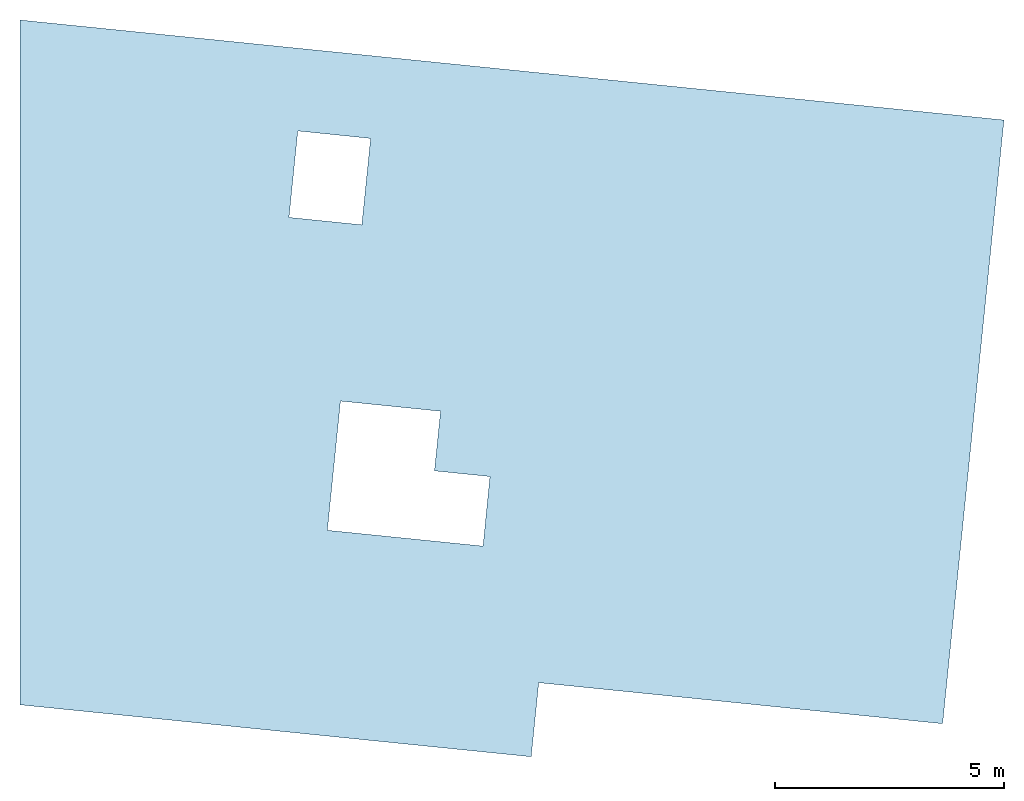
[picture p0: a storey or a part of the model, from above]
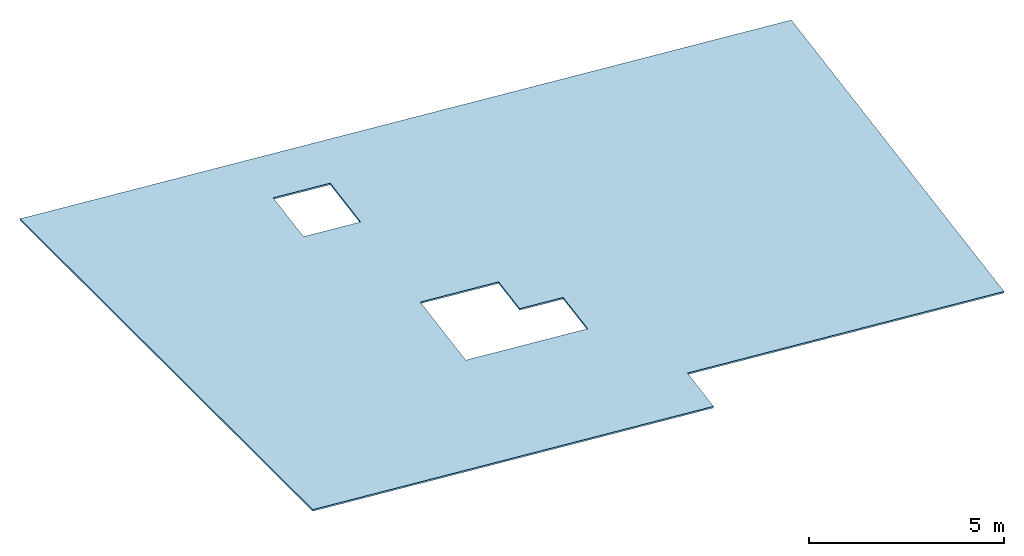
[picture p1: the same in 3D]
Properties of the parts of a building model (IFC2X3), part 1 of 44

# File
Description: ViewDefinition [], Option [Elements to export: Visible elements (on all stories)], Option [Partial Structure Display: Entire Model], Option [IFC Domain: All], Option [Structural Function: All Elements], Option [Convert Grid elements: On], Option [Convert IFC Annotations and Archicad 2D elements: Off], Option [Convert 2D symbols of Doors and Windows: Off], Option [Export geometries that Participates in Collision Detection only: On], Option [Split complex elements: Off], Option [Material Preservation: Explode where necessary], Option [Elements in Solid Element Operations: Extruded/revolved], Option [Elements with junctions: Extruded/revolved without junctions], Option [IFC Model position: Survey Point and Project Origin], Option [Curtain Wall export mode: Container Element], Option [Railing export mode: Container Element], Option [Stair export mode: Container Element], Option [Properties To Export: All properties], Option [Space containment: Off], Option [Geometry to type objects: Off], Option [Element Properties: Off], Option [Building Material Properties: Off], Option [Element Parameters: All], Option [Component Parameters: Off], Option [IFC Base Quantities: Off], Option [Door Window Parameters: On], Option [IFC Space boundaries: Off], Option [Archicad Zone Categories as IFC Space classification data: Off], Option [Element Classifications: On]
File name: Z:\DOSSIERS EN COURS\ECT 19 - Edifidès Caen Rue Basse\10-DCE2\DCE IFC 211024\ECT DCE2 3d ifc.ifc
Time: 2024-10-21T14:32:08
Author: Architect
Organization: Building Designer Office
Written by: DDS_IFC v3.0
Made in: IFC file generated by Graphisoft Archicad 27.0.0 FRA FULL Windows version (IFC add-on version: 3001 FRA FULL).
Authorization: The authorising person

# IfcSite, Site
RefLatitude: 48, 52, 0, 0; RefLongitude: 2, 20, 0, 0; RefElevation: 0 mm

# IfcBuildingStorey (10)
In: Bâtiment
Name | Elevation (mm)
cadastre | 0
rdc | 3000
sousol | 0
Etage 2 | 8500
Etage1 | 5750
Etage 3 | 11550
etage 4 | 14600
Etage 5 | 17650
toiture | 20350
toiture2 | 23050

# IfcBeam: Bloc béton 3409626266 180 x 523 (2)
Classification: Poutre (Classification ARCHICAD); Material: Bloc béton 3409626266
ArchiCADProperties - Coupe transversale de Poutre: Rectangulaire; Surface de fin: Peinture-11; Surface gauche: Peinture-11; Surface droite: Peinture-11; Angle d'inclinaison de Poutre: 0 deg; Génération de modèle analytique structurel: yes; Membre étiré manuellement: no; ID de l'élément: Poutre-012; Lien et ID d'élément: Poutre-012; Calque: 3D; Matériau de construction / Composite / Profil / Hachure: Bloc béton 3409626266; Matériau de construction: Bloc béton 3409626266; Verrouillé: no; Type d'élément: Poutre; Type de structure: Basique; ID de Parent: Poutre-012; Matériaux de construction (Tous): Bloc béton 3409626266; Surfaces (Toutes): Peinture-11; Angle d'inclinaison: 0 deg; Nombre de percements: 0; Surface supérieure: Peinture-11; Surface inférieure: Peinture-11; Nom de Variante: Modèle principal; Nom de Jeu de Variantes: Modèle principal; Position: Intérieur; Fonction structurelle: Élément porteur; Affichage sur filtre de rénovation: Tous les filtres appropriés; État de rénovation: Existant; État de Variante: Modèle principal; Jeu de Variantes: Modèle principal
AC_Pset_RenovationAndPhasing - Renovation Status: Existing
ArchiCADQuantities - Superficie des deux extrémités de poutre: 0.188323 m2; Nombre de trous: 0; Superficie des arêtes des trous: 0 m2; Superficie des trous: 0 m2; Volume des trous: 0 m3; Décalage: 0 mm; Hauteur: 523.12 mm; Largeur: 180 mm; Altitude à étage lié/étage d'implantation: 3000 mm; Décalage étage d'implantation: 3000 mm; Altitude supérieure à étage d'implantation: 3000 mm; Altitude inférieure à étage d'implantation: 2476.88 mm; Hauteur coupe transversale haut/fin (perpendiculaire): 523.12 mm; Hauteur coupe transversale bas/départ (perpendiculaire): 523.12 mm; Largeur coupe transversale haut/fin (perpendiculaire): 180 mm; Largeur coupe transversale bas/départ (perpendiculaire): 180 mm; Hauteur coupe transversale haut/fin (coupée): 523.12 mm; Hauteur coupe transversale bas/départ (coupée): 523.12 mm; Largeur coupe transversale haut/fin (coupée): 180 mm; Largeur coupe transversale bas/départ (coupée): 180 mm; Surface coupe transversale bas/départ (coupée): 0.0941616 m2; Surface coupe transversale haut/fin: 0.0941616 m2; Nombre de segments: 1
Name | In | Nom d'étage d'implantation | Numéro d'étage d'implantation | Superficie de la poutre côté gauche (nette) (m2) = Superficie de la poutre côté droit (nette) (m2) | Longueur gauche (mm) = Longueur droite (mm) = Longueur 3D (mm) | Superficie (m2) = Superficie supérieure (nette) (m2) = Superficie inférieure (nette) (m2) | Volume (net) (m3) = Volume (conditionnel) (m3) = Volume (brut) (m3) | Altitude à Zéro du Projet (mm) = Altitude de Référence Niveau 1 (mm) = Altitude de Référence Niveau 2 (mm) = Altitude à niveau de la mer (mm) = Altitude supérieure à premier niveau de référence (mm) = Altitude supérieure à Zéro du projet (mm) = Altitude supérieure à niveau de la mer (mm) = Altitude supérieure à deuxième niveau de référence (mm) | Superficie en plan (m2) | Altitude inférieure à premier niveau de référence (mm) = Altitude inférieure à Zéro du projet (mm) = Altitude inférieure à niveau de la mer (mm) = Altitude inférieure à deuxième niveau de référence (mm)
Poutre-012 | sousol | sousol | 2 | 2.77982 | 5313.92 | 0.956506 | 0.500367 | 3000 | 7.66097 | 2476.88
Poutre-012 | Etage 3 | Etage 3 | 6 | 2.98864 | 5713.12 | 1.02836 | 0.537956 | 14550 | 8.22233 | 14026.9

# IfcBeam: Bloc béton 3409626266 180 x 600, Poutre-012
In: sousol
Classification: Poutre (Classification ARCHICAD); Material: Bloc béton 3409626266
AC_Pset_RenovationAndPhasing - Renovation Status: Existing
ArchiCADQuantities - Superficie des deux extrémités de poutre: 0.216 m2; Nombre de trous: 0; Superficie des arêtes des trous: 0 m2; Superficie des trous: 0 m2; Volume des trous: 0 m3; Superficie de la poutre côté gauche (nette): 0.96 m2; Longueur gauche: 1600 mm; Longueur droite: 1600 mm; Décalage: 0 mm; Superficie de la poutre côté droit (nette): 0.96 m2; Superficie: 0.288 m2; Hauteur: 600 mm; Volume (net): 0.1728 m3; Largeur: 180 mm; Altitude à Zéro du Projet: 2950 mm; Altitude de Référence Niveau 1: 2950 mm; Altitude de Référence Niveau 2: 2950 mm; Altitude à niveau de la mer: 2950 mm; Altitude à étage lié/étage d'implantation: 2950 mm; Décalage étage d'implantation: 2950 mm; Superficie en plan: 2.712 m2; Longueur 3D: 1600 mm; Volume (conditionnel): 0.1728 m3; Volume (brut): 0.1728 m3; Altitude supérieure à premier niveau de référence: 2950 mm; Altitude supérieure à étage d'implantation: 2950 mm; Altitude supérieure à Zéro du projet: 2950 mm; Altitude supérieure à niveau de la mer: 2950 mm; Altitude supérieure à deuxième niveau de référence: 2950 mm; Altitude inférieure à premier niveau de référence: 2350 mm; Altitude inférieure à étage d'implantation: 2350 mm; Altitude inférieure à Zéro du projet: 2350 mm; Altitude inférieure à niveau de la mer: 2350 mm; Altitude inférieure à deuxième niveau de référence: 2350 mm; Hauteur coupe transversale haut/fin (perpendiculaire): 600 mm; Hauteur coupe transversale bas/départ (perpendiculaire): 600 mm; Largeur coupe transversale haut/fin (perpendiculaire): 180 mm; Largeur coupe transversale bas/départ (perpendiculaire): 180 mm; Hauteur coupe transversale haut/fin (coupée): 600 mm; Hauteur coupe transversale bas/départ (coupée): 600 mm; Largeur coupe transversale haut/fin (coupée): 180 mm; Largeur coupe transversale bas/départ (coupée): 180 mm; Surface coupe transversale bas/départ (coupée): 0.108 m2; Surface coupe transversale haut/fin: 0.108 m2; Nombre de segments: 1; Superficie supérieure (nette): 0.288 m2; Superficie inférieure (nette): 0.288 m2
ArchiCADProperties - Coupe transversale de Poutre: Rectangulaire; Surface de fin: Bois-Pin; Surface gauche: Bois-Pin; Surface droite: Bois-Pin; Angle d'inclinaison de Poutre: 0 deg; Génération de modèle analytique structurel: yes; Membre étiré manuellement: no; ID de l'élément: Poutre-012; Lien et ID d'élément: Poutre-012; Calque: 3D; Matériau de construction / Composite / Profil / Hachure: Bloc béton 3409626266; Matériau de construction: Bloc béton 3409626266; Verrouillé: no; Nom d'étage d'implantation: sousol; Numéro d'étage d'implantation: 2; Type d'élément: Poutre; Type de structure: Basique; ID de Parent: Poutre-012; Matériaux de construction (Tous): Bloc béton 3409626266; Surfaces (Toutes): Bois-Pin; Angle d'inclinaison: 0 deg; Nombre de percements: 0; Surface supérieure: Bois-Pin; Surface inférieure: Bois-Pin; Nom de Variante: Modèle principal; Nom de Jeu de Variantes: Modèle principal; Position: Intérieur; Fonction structurelle: Élément porteur; Affichage sur filtre de rénovation: Tous les filtres appropriés; État de rénovation: Existant; État de Variante: Modèle principal; Jeu de Variantes: Modèle principal

# IfcBeam: Bloc béton 3409626266 180 x 700 (2)
In: sousol
Classification: Poutre (Classification ARCHICAD); Material: Bloc béton 3409626266
AC_Pset_RenovationAndPhasing - Renovation Status: Existing
ArchiCADQuantities - Nombre de trous: 0; Superficie des arêtes des trous: 0 m2; Superficie des trous: 0 m2; Volume des trous: 0 m3; Décalage: 0 mm; Hauteur: 700 mm; Largeur: 180 mm; Altitude à Zéro du Projet: 2950 mm; Altitude de Référence Niveau 1: 2950 mm; Altitude de Référence Niveau 2: 2950 mm; Altitude à niveau de la mer: 2950 mm; Altitude à étage lié/étage d'implantation: 2950 mm; Décalage étage d'implantation: 2950 mm; Altitude supérieure à premier niveau de référence: 2950 mm; Altitude supérieure à étage d'implantation: 2950 mm; Altitude supérieure à Zéro du projet: 2950 mm; Altitude supérieure à niveau de la mer: 2950 mm; Altitude supérieure à deuxième niveau de référence: 2950 mm; Altitude inférieure à premier niveau de référence: 2250 mm; Altitude inférieure à étage d'implantation: 2250 mm; Altitude inférieure à Zéro du projet: 2250 mm; Altitude inférieure à niveau de la mer: 2250 mm; Altitude inférieure à deuxième niveau de référence: 2250 mm; Hauteur coupe transversale haut/fin (perpendiculaire): 700 mm; Hauteur coupe transversale bas/départ (perpendiculaire): 700 mm; Largeur coupe transversale haut/fin (perpendiculaire): 180 mm; Largeur coupe transversale bas/départ (perpendiculaire): 180 mm; Hauteur coupe transversale haut/fin (coupée): 700 mm; Hauteur coupe transversale bas/départ (coupée): 700 mm; Largeur coupe transversale haut/fin (coupée): 180 mm; Largeur coupe transversale bas/départ (coupée): 180 mm; Surface coupe transversale haut/fin: 0.126 m2; Nombre de segments: 1
ArchiCADProperties - Coupe transversale de Poutre: Rectangulaire; Surface de fin: Bois-Pin; Surface gauche: Bois-Pin; Surface droite: Bois-Pin; Angle d'inclinaison de Poutre: 0 deg; Génération de modèle analytique structurel: yes; Membre étiré manuellement: no; ID de l'élément: Poutre-012; Lien et ID d'élément: Poutre-012; Calque: 3D; Matériau de construction / Composite / Profil / Hachure: Bloc béton 3409626266; Matériau de construction: Bloc béton 3409626266; Verrouillé: no; Nom d'étage d'implantation: sousol; Numéro d'étage d'implantation: 2; Type d'élément: Poutre; Type de structure: Basique; ID de Parent: Poutre-012; Matériaux de construction (Tous): Bloc béton 3409626266; Surfaces (Toutes): Bois-Pin; Angle d'inclinaison: 0 deg; Nombre de percements: 0; Surface supérieure: Bois-Pin; Surface inférieure: Bois-Pin; Nom de Variante: Modèle principal; Nom de Jeu de Variantes: Modèle principal; Position: Intérieur; Fonction structurelle: Élément porteur; Affichage sur filtre de rénovation: Tous les filtres appropriés; État de rénovation: Existant; État de Variante: Modèle principal; Jeu de Variantes: Modèle principal
Name | Superficie des deux extrémités de poutre (m2) | Superficie de la poutre côté gauche (nette) (m2) | Longueur gauche (mm) = Longueur 3D (mm) | Longueur droite (mm) | Superficie de la poutre côté droit (nette) (m2) | Superficie (m2) = Superficie supérieure (nette) (m2) = Superficie inférieure (nette) (m2) | Volume (net) (m3) = Volume (conditionnel) (m3) = Volume (brut) (m3) | Superficie en plan (m2) | Surface coupe transversale bas/départ (coupée) (m2)
Poutre-012 | 0.252 | 1.16463 | 1663.75 | 1663.75 | 1.16463 | 0.299476 | 0.209633 | 3.18021 | 0.126
Poutre-012 | 0.401501 | 1.15869 | 1655.28 | 1305.28 | 0.913694 | 0.26645 | 0.186515 | 3.00679 | 0.275501

# IfcBeam: Bloc béton 3409626266 180 x 900, Poutre-012
In: sousol
Classification: Poutre (Classification ARCHICAD); Material: Bloc béton 3409626266
ArchiCADProperties - Coupe transversale de Poutre: Rectangulaire; Surface de fin: Bois-Pin; Surface gauche: Bois-Pin; Surface droite: Bois-Pin; Angle d'inclinaison de Poutre: 0 deg; Génération de modèle analytique structurel: yes; Membre étiré manuellement: no; ID de l'élément: Poutre-012; Lien et ID d'élément: Poutre-012; Calque: 3D; Matériau de construction / Composite / Profil / Hachure: Bloc béton 3409626266; Matériau de construction: Bloc béton 3409626266; Verrouillé: no; Nom d'étage d'implantation: sousol; Numéro d'étage d'implantation: 2; Type d'élément: Poutre; Type de structure: Basique; ID de Parent: Poutre-012; Matériaux de construction (Tous): Bloc béton 3409626266; Surfaces (Toutes): Bois-Pin; Angle d'inclinaison: 0 deg; Nombre de percements: 0; Surface supérieure: Bois-Pin; Surface inférieure: Bois-Pin; Nom de Variante: Modèle principal; Nom de Jeu de Variantes: Modèle principal; Position: Intérieur; Fonction structurelle: Élément porteur; Affichage sur filtre de rénovation: Tous les filtres appropriés; État de rénovation: Existant; État de Variante: Modèle principal; Jeu de Variantes: Modèle principal
AC_Pset_RenovationAndPhasing - Renovation Status: Existing
ArchiCADQuantities - Superficie des deux extrémités de poutre: 0.556771 m2; Nombre de trous: 0; Superficie des arêtes des trous: 0 m2; Superficie des trous: 0 m2; Volume des trous: 0 m3; Superficie de la poutre côté gauche (nette): 1.16176 m2; Longueur gauche: 1290.84 mm; Longueur droite: 1690.84 mm; Décalage: 0 mm; Superficie de la poutre côté droit (nette): 1.52176 m2; Superficie: 0.268352 m2; Hauteur: 900 mm; Volume (net): 0.241516 m3; Largeur: 180 mm; Altitude à Zéro du Projet: 2950 mm; Altitude de Référence Niveau 1: 2950 mm; Altitude de Référence Niveau 2: 2950 mm; Altitude à niveau de la mer: 2950 mm; Altitude à étage lié/étage d'implantation: 2950 mm; Décalage étage d'implantation: 2950 mm; Superficie en plan: 3.77699 m2; Longueur 3D: 1690.84 mm; Volume (conditionnel): 0.241516 m3; Volume (brut): 0.241516 m3; Altitude supérieure à premier niveau de référence: 2950 mm; Altitude supérieure à étage d'implantation: 2950 mm; Altitude supérieure à Zéro du projet: 2950 mm; Altitude supérieure à niveau de la mer: 2950 mm; Altitude supérieure à deuxième niveau de référence: 2950 mm; Altitude inférieure à premier niveau de référence: 2050 mm; Altitude inférieure à étage d'implantation: 2050 mm; Altitude inférieure à Zéro du projet: 2050 mm; Altitude inférieure à niveau de la mer: 2050 mm; Altitude inférieure à deuxième niveau de référence: 2050 mm; Hauteur coupe transversale haut/fin (perpendiculaire): 900 mm; Hauteur coupe transversale bas/départ (perpendiculaire): 900 mm; Largeur coupe transversale haut/fin (perpendiculaire): 180 mm; Largeur coupe transversale bas/départ (perpendiculaire): 180 mm; Hauteur coupe transversale haut/fin (coupée): 900 mm; Hauteur coupe transversale bas/départ (coupée): 900 mm; Largeur coupe transversale haut/fin (coupée): 180 mm; Largeur coupe transversale bas/départ (coupée): 180 mm; Surface coupe transversale bas/départ (coupée): 0.394771 m2; Surface coupe transversale haut/fin: 0.162 m2; Nombre de segments: 1; Superficie supérieure (nette): 0.268352 m2; Superficie inférieure (nette): 0.268352 m2

# IfcBeam: Bloc béton 3409626266 200 x 200 (3)
In: sousol
Classification: Poutre (Classification ARCHICAD); Material: Bloc béton 3409626266
ArchiCADQuantities - Nombre de trous: 0; Superficie des arêtes des trous: 0 m2; Superficie des trous: 0 m2; Volume des trous: 0 m3; Décalage: 0 mm; Hauteur: 200 mm; Largeur: 200 mm; Altitude à Zéro du Projet: 2950 mm; Altitude de Référence Niveau 1: 2950 mm; Altitude de Référence Niveau 2: 2950 mm; Altitude à niveau de la mer: 2950 mm; Altitude à étage lié/étage d'implantation: 2950 mm; Décalage étage d'implantation: 2950 mm; Altitude supérieure à premier niveau de référence: 2950 mm; Altitude supérieure à étage d'implantation: 2950 mm; Altitude supérieure à Zéro du projet: 2950 mm; Altitude supérieure à niveau de la mer: 2950 mm; Altitude supérieure à deuxième niveau de référence: 2950 mm; Altitude inférieure à premier niveau de référence: 2750 mm; Altitude inférieure à étage d'implantation: 2750 mm; Altitude inférieure à Zéro du projet: 2750 mm; Altitude inférieure à niveau de la mer: 2750 mm; Altitude inférieure à deuxième niveau de référence: 2750 mm; Hauteur coupe transversale haut/fin (perpendiculaire): 200 mm; Hauteur coupe transversale bas/départ (perpendiculaire): 200 mm; Largeur coupe transversale haut/fin (perpendiculaire): 200 mm; Largeur coupe transversale bas/départ (perpendiculaire): 200 mm; Hauteur coupe transversale haut/fin (coupée): 200 mm; Hauteur coupe transversale bas/départ (coupée): 200 mm; Largeur coupe transversale haut/fin (coupée): 200 mm; Largeur coupe transversale bas/départ (coupée): 200 mm; Nombre de segments: 1
AC_Pset_RenovationAndPhasing - Renovation Status: Existing
ArchiCADProperties - Coupe transversale de Poutre: Rectangulaire; Surface de fin: Bois-Pin; Surface gauche: Bois-Pin; Surface droite: Bois-Pin; Angle d'inclinaison de Poutre: 0 deg; Génération de modèle analytique structurel: yes; Membre étiré manuellement: no; ID de l'élément: Poutre-012; Lien et ID d'élément: Poutre-012; Calque: 3D; Matériau de construction / Composite / Profil / Hachure: Bloc béton 3409626266; Matériau de construction: Bloc béton 3409626266; Verrouillé: no; Nom d'étage d'implantation: sousol; Numéro d'étage d'implantation: 2; Type d'élément: Poutre; Type de structure: Basique; ID de Parent: Poutre-012; Matériaux de construction (Tous): Bloc béton 3409626266; Surfaces (Toutes): Bois-Pin; Angle d'inclinaison: 0 deg; Nombre de percements: 0; Surface supérieure: Bois-Pin; Surface inférieure: Bois-Pin; Nom de Variante: Modèle principal; Nom de Jeu de Variantes: Modèle principal; Position: Intérieur; Fonction structurelle: Élément porteur; Affichage sur filtre de rénovation: Tous les filtres appropriés; État de rénovation: Existant; État de Variante: Modèle principal; Jeu de Variantes: Modèle principal
Name | Superficie des deux extrémités de poutre (m2) | Superficie de la poutre côté gauche (nette) (m2) | Longueur gauche (mm) | Longueur droite (mm) = Longueur 3D (mm) | Superficie de la poutre côté droit (nette) (m2) | Superficie (m2) = Superficie supérieure (nette) (m2) = Superficie inférieure (nette) (m2) | Volume (net) (m3) = Volume (conditionnel) (m3) = Volume (brut) (m3) | Superficie en plan (m2) | Surface coupe transversale bas/départ (coupée) (m2) | Surface coupe transversale haut/fin (m2)
Poutre-012 | 0.081987 | 1.46264 | 7313.2 | 7393.99 | 1.4788 | 1.47072 | 0.294144 | 5.96486 | 0.0402099 | 0.0417772
Poutre-012 | 0.0965685 | 0.321709 | 1608.54 | 1808.54 | 0.361709 | 0.341709 | 0.0683417 | 1.4634 | 0.0565685 | 0.04
Poutre-012 | 0.0965685 | 0.381973 | 1909.86 | 2109.86 | 0.421973 | 0.401973 | 0.0803946 | 1.70446 | 0.04 | 0.0565685

# IfcBeam: Bloc béton 3409626266 200 x 300, Poutre-012
In: sousol
Classification: Poutre (Classification ARCHICAD); Material: Bloc béton 3409626266
ArchiCADQuantities - Superficie des deux extrémités de poutre: 0.12 m2; Nombre de trous: 0; Superficie des arêtes des trous: 0 m2; Superficie des trous: 0 m2; Volume des trous: 0 m3; Superficie de la poutre côté gauche (nette): 0.387443 m2; Longueur gauche: 1291.48 mm; Longueur droite: 1291.48 mm; Décalage: 0 mm; Superficie de la poutre côté droit (nette): 0.387443 m2; Superficie: 0.258296 m2; Hauteur: 300 mm; Volume (net): 0.0774887 m3; Largeur: 200 mm; Altitude à Zéro du Projet: 2560 mm; Altitude de Référence Niveau 1: 2560 mm; Altitude de Référence Niveau 2: 2560 mm; Altitude à niveau de la mer: 2560 mm; Altitude à étage lié/étage d'implantation: 2560 mm; Décalage étage d'implantation: 2560 mm; Superficie en plan: 1.41148 m2; Longueur 3D: 1291.48 mm; Volume (conditionnel): 0.0774887 m3; Volume (brut): 0.0774887 m3; Altitude supérieure à premier niveau de référence: 2560 mm; Altitude supérieure à étage d'implantation: 2560 mm; Altitude supérieure à Zéro du projet: 2560 mm; Altitude supérieure à niveau de la mer: 2560 mm; Altitude supérieure à deuxième niveau de référence: 2560 mm; Altitude inférieure à premier niveau de référence: 2260 mm; Altitude inférieure à étage d'implantation: 2260 mm; Altitude inférieure à Zéro du projet: 2260 mm; Altitude inférieure à niveau de la mer: 2260 mm; Altitude inférieure à deuxième niveau de référence: 2260 mm; Hauteur coupe transversale haut/fin (perpendiculaire): 300 mm; Hauteur coupe transversale bas/départ (perpendiculaire): 300 mm; Largeur coupe transversale haut/fin (perpendiculaire): 200 mm; Largeur coupe transversale bas/départ (perpendiculaire): 200 mm; Hauteur coupe transversale haut/fin (coupée): 300 mm; Hauteur coupe transversale bas/départ (coupée): 300 mm; Largeur coupe transversale haut/fin (coupée): 200 mm; Largeur coupe transversale bas/départ (coupée): 200 mm; Surface coupe transversale bas/départ (coupée): 0.06 m2; Surface coupe transversale haut/fin: 0.06 m2; Nombre de segments: 1; Superficie supérieure (nette): 0.258296 m2; Superficie inférieure (nette): 0.258296 m2
AC_Pset_RenovationAndPhasing - Renovation Status: Existing
ArchiCADProperties - Coupe transversale de Poutre: Rectangulaire; Surface de fin: Bois-Pin; Surface gauche: Bois-Pin; Surface droite: Bois-Pin; Angle d'inclinaison de Poutre: 0 deg; Génération de modèle analytique structurel: yes; Membre étiré manuellement: no; ID de l'élément: Poutre-012; Lien et ID d'élément: Poutre-012; Calque: 3D; Matériau de construction / Composite / Profil / Hachure: Bloc béton 3409626266; Matériau de construction: Bloc béton 3409626266; Verrouillé: no; Nom d'étage d'implantation: sousol; Numéro d'étage d'implantation: 2; Type d'élément: Poutre; Type de structure: Basique; ID de Parent: Poutre-012; Matériaux de construction (Tous): Bloc béton 3409626266; Surfaces (Toutes): Bois-Pin; Angle d'inclinaison: 0 deg; Nombre de percements: 0; Surface supérieure: Bois-Pin; Surface inférieure: Bois-Pin; Nom de Variante: Modèle principal; Nom de Jeu de Variantes: Modèle principal; Position: Intérieur; Fonction structurelle: Élément porteur; Affichage sur filtre de rénovation: Tous les filtres appropriés; État de rénovation: Existant; État de Variante: Modèle principal; Jeu de Variantes: Modèle principal

# IfcBeam: Bloc béton 3409626266 200 x 500 (2)
In: sousol
Classification: Poutre (Classification ARCHICAD); Material: Bloc béton 3409626266
AC_Pset_RenovationAndPhasing - Renovation Status: Existing
ArchiCADQuantities - Superficie des deux extrémités de poutre: 0.2 m2; Nombre de trous: 0; Superficie des arêtes des trous: 0 m2; Superficie des trous: 0 m2; Volume des trous: 0 m3; Superficie de la poutre côté gauche (nette): 1.19941 m2; Longueur gauche: 2398.82 mm; Longueur droite: 2398.82 mm; Décalage: 0 mm; Superficie de la poutre côté droit (nette): 1.19941 m2; Superficie: 0.479765 m2; Hauteur: 500 mm; Volume (net): 0.239882 m3; Largeur: 200 mm; Altitude à Zéro du Projet: 2950 mm; Altitude de Référence Niveau 1: 2950 mm; Altitude de Référence Niveau 2: 2950 mm; Altitude à niveau de la mer: 2950 mm; Altitude à étage lié/étage d'implantation: 2950 mm; Décalage étage d'implantation: 2950 mm; Superficie en plan: 3.55835 m2; Longueur 3D: 2398.82 mm; Volume (conditionnel): 0.239882 m3; Volume (brut): 0.239882 m3; Altitude supérieure à premier niveau de référence: 2950 mm; Altitude supérieure à étage d'implantation: 2950 mm; Altitude supérieure à Zéro du projet: 2950 mm; Altitude supérieure à niveau de la mer: 2950 mm; Altitude supérieure à deuxième niveau de référence: 2950 mm; Altitude inférieure à premier niveau de référence: 2450 mm; Altitude inférieure à étage d'implantation: 2450 mm; Altitude inférieure à Zéro du projet: 2450 mm; Altitude inférieure à niveau de la mer: 2450 mm; Altitude inférieure à deuxième niveau de référence: 2450 mm; Hauteur coupe transversale haut/fin (perpendiculaire): 500 mm; Hauteur coupe transversale bas/départ (perpendiculaire): 500 mm; Largeur coupe transversale haut/fin (perpendiculaire): 200 mm; Largeur coupe transversale bas/départ (perpendiculaire): 200 mm; Hauteur coupe transversale haut/fin (coupée): 500 mm; Hauteur coupe transversale bas/départ (coupée): 500 mm; Largeur coupe transversale haut/fin (coupée): 200 mm; Largeur coupe transversale bas/départ (coupée): 200 mm; Surface coupe transversale bas/départ (coupée): 0.1 m2; Surface coupe transversale haut/fin: 0.1 m2; Nombre de segments: 1; Superficie supérieure (nette): 0.479765 m2; Superficie inférieure (nette): 0.479765 m2
ArchiCADProperties - Coupe transversale de Poutre: Rectangulaire; Surface de fin: Bois-Pin; Surface gauche: Bois-Pin; Surface droite: Bois-Pin; Angle d'inclinaison de Poutre: 0 deg; Génération de modèle analytique structurel: yes; Membre étiré manuellement: no; ID de l'élément: Poutre-012; Lien et ID d'élément: Poutre-012; Calque: 3D; Matériau de construction / Composite / Profil / Hachure: Bloc béton 3409626266; Matériau de construction: Bloc béton 3409626266; Verrouillé: no; Nom d'étage d'implantation: sousol; Numéro d'étage d'implantation: 2; Type d'élément: Poutre; Type de structure: Basique; ID de Parent: Poutre-012; Matériaux de construction (Tous): Bloc béton 3409626266; Surfaces (Toutes): Bois-Pin; Angle d'inclinaison: 0 deg; Nombre de percements: 0; Surface supérieure: Bois-Pin; Surface inférieure: Bois-Pin; Nom de Variante: Modèle principal; Nom de Jeu de Variantes: Modèle principal; Position: Intérieur; Fonction structurelle: Élément porteur; Affichage sur filtre de rénovation: Tous les filtres appropriés; État de rénovation: Existant; État de Variante: Modèle principal; Jeu de Variantes: Modèle principal

# IfcBeam: Bloc béton 3409626266 200 x 700, Poutre-012
In: sousol
Classification: Poutre (Classification ARCHICAD); Material: Bloc béton 3409626266
ArchiCADQuantities - Superficie des deux extrémités de poutre: 0.28 m2; Nombre de trous: 0; Superficie des arêtes des trous: 0 m2; Superficie des trous: 0 m2; Volume des trous: 0 m3; Superficie de la poutre côté gauche (nette): 3.72904 m2; Longueur gauche: 5327.2 mm; Longueur droite: 5327.2 mm; Décalage: 0 mm; Superficie de la poutre côté droit (nette): 3.72904 m2; Superficie: 1.06544 m2; Hauteur: 700 mm; Volume (net): 0.745808 m3; Largeur: 200 mm; Altitude à Zéro du Projet: 2950 mm; Altitude de Référence Niveau 1: 2950 mm; Altitude de Référence Niveau 2: 2950 mm; Altitude à niveau de la mer: 2950 mm; Altitude à étage lié/étage d'implantation: 2950 mm; Décalage étage d'implantation: 2950 mm; Superficie en plan: 9.86897 m2; Longueur 3D: 5327.2 mm; Volume (conditionnel): 0.745808 m3; Volume (brut): 0.745808 m3; Altitude supérieure à premier niveau de référence: 2950 mm; Altitude supérieure à étage d'implantation: 2950 mm; Altitude supérieure à Zéro du projet: 2950 mm; Altitude supérieure à niveau de la mer: 2950 mm; Altitude supérieure à deuxième niveau de référence: 2950 mm; Altitude inférieure à premier niveau de référence: 2250 mm; Altitude inférieure à étage d'implantation: 2250 mm; Altitude inférieure à Zéro du projet: 2250 mm; Altitude inférieure à niveau de la mer: 2250 mm; Altitude inférieure à deuxième niveau de référence: 2250 mm; Hauteur coupe transversale haut/fin (perpendiculaire): 700 mm; Hauteur coupe transversale bas/départ (perpendiculaire): 700 mm; Largeur coupe transversale haut/fin (perpendiculaire): 200 mm; Largeur coupe transversale bas/départ (perpendiculaire): 200 mm; Hauteur coupe transversale haut/fin (coupée): 700 mm; Hauteur coupe transversale bas/départ (coupée): 700 mm; Largeur coupe transversale haut/fin (coupée): 200 mm; Largeur coupe transversale bas/départ (coupée): 200 mm; Surface coupe transversale bas/départ (coupée): 0.14 m2; Surface coupe transversale haut/fin: 0.14 m2; Nombre de segments: 1; Superficie supérieure (nette): 1.06544 m2; Superficie inférieure (nette): 1.06544 m2
AC_Pset_RenovationAndPhasing - Renovation Status: Existing
ArchiCADProperties - Coupe transversale de Poutre: Rectangulaire; Surface de fin: Bois-Pin; Surface gauche: Bois-Pin; Surface droite: Bois-Pin; Angle d'inclinaison de Poutre: 0 deg; Génération de modèle analytique structurel: yes; Membre étiré manuellement: no; ID de l'élément: Poutre-012; Lien et ID d'élément: Poutre-012; Calque: 3D; Matériau de construction / Composite / Profil / Hachure: Bloc béton 3409626266; Matériau de construction: Bloc béton 3409626266; Verrouillé: no; Nom d'étage d'implantation: sousol; Numéro d'étage d'implantation: 2; Type d'élément: Poutre; Type de structure: Basique; ID de Parent: Poutre-012; Matériaux de construction (Tous): Bloc béton 3409626266; Surfaces (Toutes): Bois-Pin; Angle d'inclinaison: 0 deg; Nombre de percements: 0; Surface supérieure: Bois-Pin; Surface inférieure: Bois-Pin; Nom de Variante: Modèle principal; Nom de Jeu de Variantes: Modèle principal; Position: Intérieur; Fonction structurelle: Élément porteur; Affichage sur filtre de rénovation: Tous les filtres appropriés; État de rénovation: Existant; État de Variante: Modèle principal; Jeu de Variantes: Modèle principal

# IfcBeam: Bloc béton 3409626266 200 x 800, Poutre-012
In: sousol
Classification: Poutre (Classification ARCHICAD); Material: Bloc béton 3409626266
ArchiCADQuantities - Superficie des deux extrémités de poutre: 0.32 m2; Nombre de trous: 0; Superficie des arêtes des trous: 0 m2; Superficie des trous: 0 m2; Volume des trous: 0 m3; Superficie de la poutre côté gauche (nette): 1.30396 m2; Longueur gauche: 1529.95 mm; Longueur droite: 1529.95 mm; Décalage: 0 mm; Superficie de la poutre côté droit (nette): 1.30396 m2; Superficie: 0.385989 m2; Hauteur: 800 mm; Volume (net): 0.260792 m3; Largeur: 200 mm; Altitude à Zéro du Projet: 2950 mm; Altitude de Référence Niveau 1: 2950 mm; Altitude de Référence Niveau 2: 2950 mm; Altitude à niveau de la mer: 2950 mm; Altitude à étage lié/étage d'implantation: 2950 mm; Décalage étage d'implantation: 2950 mm; Superficie en plan: 3.69989 m2; Longueur 3D: 1929.95 mm; Volume (conditionnel): 0.260792 m3; Volume (brut): 0.260792 m3; Altitude supérieure à premier niveau de référence: 2950 mm; Altitude supérieure à étage d'implantation: 2950 mm; Altitude supérieure à Zéro du projet: 2950 mm; Altitude supérieure à niveau de la mer: 2950 mm; Altitude supérieure à deuxième niveau de référence: 2950 mm; Altitude inférieure à premier niveau de référence: 2150 mm; Altitude inférieure à étage d'implantation: 2150 mm; Altitude inférieure à Zéro du projet: 2150 mm; Altitude inférieure à niveau de la mer: 2150 mm; Altitude inférieure à deuxième niveau de référence: 2150 mm; Hauteur coupe transversale haut/fin (perpendiculaire): 800 mm; Hauteur coupe transversale bas/départ (perpendiculaire): 800 mm; Largeur coupe transversale haut/fin (perpendiculaire): 200 mm; Largeur coupe transversale bas/départ (perpendiculaire): 200 mm; Hauteur coupe transversale haut/fin (coupée): 800 mm; Hauteur coupe transversale bas/départ (coupée): 800 mm; Largeur coupe transversale haut/fin (coupée): 200 mm; Largeur coupe transversale bas/départ (coupée): 200 mm; Surface coupe transversale bas/départ (coupée): 0.16 m2; Surface coupe transversale haut/fin: 0.16 m2; Nombre de segments: 1; Superficie supérieure (nette): 0.305989 m2; Superficie inférieure (nette): 0.465989 m2
AC_Pset_RenovationAndPhasing - Renovation Status: Existing
ArchiCADProperties - Coupe transversale de Poutre: Rectangulaire; Surface de fin: Bois-Pin; Surface gauche: Bois-Pin; Surface droite: Bois-Pin; Angle d'inclinaison de Poutre: 0 deg; Génération de modèle analytique structurel: yes; Membre étiré manuellement: no; ID de l'élément: Poutre-012; Lien et ID d'élément: Poutre-012; Calque: 3D; Matériau de construction / Composite / Profil / Hachure: Bloc béton 3409626266; Matériau de construction: Bloc béton 3409626266; Verrouillé: no; Nom d'étage d'implantation: sousol; Numéro d'étage d'implantation: 2; Type d'élément: Poutre; Type de structure: Basique; ID de Parent: Poutre-012; Matériaux de construction (Tous): Bloc béton 3409626266; Surfaces (Toutes): Bois-Pin; Angle d'inclinaison: 0 deg; Nombre de percements: 0; Surface supérieure: Bois-Pin; Surface inférieure: Bois-Pin; Nom de Variante: Modèle principal; Nom de Jeu de Variantes: Modèle principal; Position: Intérieur; Fonction structurelle: Élément porteur; Affichage sur filtre de rénovation: Tous les filtres appropriés; État de rénovation: Existant; État de Variante: Modèle principal; Jeu de Variantes: Modèle principal

# IfcBeam: Bloc béton 3409626266 200 x 850 (3)
In: sousol
Classification: Poutre (Classification ARCHICAD); Material: Bloc béton 3409626266
ArchiCADQuantities - Superficie des deux extrémités de poutre: 0.34 m2; Nombre de trous: 0; Superficie des arêtes des trous: 0 m2; Superficie des trous: 0 m2; Volume des trous: 0 m3; Décalage: 0 mm; Hauteur: 850 mm; Largeur: 200 mm; Altitude à Zéro du Projet: 2950 mm; Altitude de Référence Niveau 1: 2950 mm; Altitude de Référence Niveau 2: 2950 mm; Altitude à niveau de la mer: 2950 mm; Altitude à étage lié/étage d'implantation: 2950 mm; Décalage étage d'implantation: 2950 mm; Altitude supérieure à premier niveau de référence: 2950 mm; Altitude supérieure à étage d'implantation: 2950 mm; Altitude supérieure à Zéro du projet: 2950 mm; Altitude supérieure à niveau de la mer: 2950 mm; Altitude supérieure à deuxième niveau de référence: 2950 mm; Altitude inférieure à premier niveau de référence: 2100 mm; Altitude inférieure à étage d'implantation: 2100 mm; Altitude inférieure à Zéro du projet: 2100 mm; Altitude inférieure à niveau de la mer: 2100 mm; Altitude inférieure à deuxième niveau de référence: 2100 mm; Hauteur coupe transversale haut/fin (perpendiculaire): 850 mm; Hauteur coupe transversale bas/départ (perpendiculaire): 850 mm; Largeur coupe transversale haut/fin (perpendiculaire): 200 mm; Largeur coupe transversale bas/départ (perpendiculaire): 200 mm; Hauteur coupe transversale haut/fin (coupée): 850 mm; Hauteur coupe transversale bas/départ (coupée): 850 mm; Largeur coupe transversale haut/fin (coupée): 200 mm; Largeur coupe transversale bas/départ (coupée): 200 mm; Surface coupe transversale bas/départ (coupée): 0.17 m2; Surface coupe transversale haut/fin: 0.17 m2; Nombre de segments: 1
AC_Pset_RenovationAndPhasing - Renovation Status: Existing
ArchiCADProperties - Coupe transversale de Poutre: Rectangulaire; Surface de fin: Bois-Pin; Surface gauche: Bois-Pin; Surface droite: Bois-Pin; Angle d'inclinaison de Poutre: 0 deg; Génération de modèle analytique structurel: yes; Membre étiré manuellement: no; ID de l'élément: Poutre-012; Lien et ID d'élément: Poutre-012; Calque: 3D; Matériau de construction / Composite / Profil / Hachure: Bloc béton 3409626266; Matériau de construction: Bloc béton 3409626266; Verrouillé: no; Nom d'étage d'implantation: sousol; Numéro d'étage d'implantation: 2; Type d'élément: Poutre; Type de structure: Basique; ID de Parent: Poutre-012; Matériaux de construction (Tous): Bloc béton 3409626266; Surfaces (Toutes): Bois-Pin; Angle d'inclinaison: 0 deg; Nombre de percements: 0; Surface supérieure: Bois-Pin; Surface inférieure: Bois-Pin; Nom de Variante: Modèle principal; Nom de Jeu de Variantes: Modèle principal; Position: Intérieur; Fonction structurelle: Élément porteur; Affichage sur filtre de rénovation: Tous les filtres appropriés; État de rénovation: Existant; État de Variante: Modèle principal; Jeu de Variantes: Modèle principal
Name | Superficie de la poutre côté gauche (nette) (m2) = Superficie de la poutre côté droit (nette) (m2) | Longueur gauche (mm) = Longueur droite (mm) | Superficie (m2) | Volume (net) (m3) = Volume (conditionnel) (m3) = Volume (brut) (m3) | Superficie en plan (m2) | Longueur 3D (mm) | Superficie supérieure (nette) (m2) | Superficie inférieure (nette) (m2)
Poutre-012 | 6.09721 | 7137.9 | 1.54758 | 1.21944 | 15.6296 | 7737.9 | 1.42758 | 1.66758
Poutre-012 | 2.23192 | 2625.78 | 0.525156 | 0.446383 | 5.85414 | 2625.78 | 0.525156 | 0.525156
Poutre-012 | 1.60814 | 1856.64 | 0.411328 | 0.321629 | 4.37894 | 2056.64 | 0.371328 | 0.451328

# IfcBeam: Bloc béton 3409626266 250 x 400 (2)
In: sousol
Classification: Poutre (Classification ARCHICAD); Material: Bloc béton 3409626266
ArchiCADQuantities - Superficie des deux extrémités de poutre: 0.2 m2; Nombre de trous: 0; Superficie des arêtes des trous: 0 m2; Superficie des trous: 0 m2; Volume des trous: 0 m3; Décalage: 0 mm; Hauteur: 400 mm; Largeur: 250 mm; Altitude à Zéro du Projet: 2950 mm; Altitude de Référence Niveau 1: 2950 mm; Altitude de Référence Niveau 2: 2950 mm; Altitude à niveau de la mer: 2950 mm; Altitude à étage lié/étage d'implantation: 2950 mm; Décalage étage d'implantation: 2950 mm; Altitude supérieure à premier niveau de référence: 2950 mm; Altitude supérieure à étage d'implantation: 2950 mm; Altitude supérieure à Zéro du projet: 2950 mm; Altitude supérieure à niveau de la mer: 2950 mm; Altitude supérieure à deuxième niveau de référence: 2950 mm; Altitude inférieure à premier niveau de référence: 2550 mm; Altitude inférieure à étage d'implantation: 2550 mm; Altitude inférieure à Zéro du projet: 2550 mm; Altitude inférieure à niveau de la mer: 2550 mm; Altitude inférieure à deuxième niveau de référence: 2550 mm; Hauteur coupe transversale haut/fin (perpendiculaire): 400 mm; Hauteur coupe transversale bas/départ (perpendiculaire): 400 mm; Largeur coupe transversale haut/fin (perpendiculaire): 250 mm; Largeur coupe transversale bas/départ (perpendiculaire): 250 mm; Hauteur coupe transversale haut/fin (coupée): 400 mm; Hauteur coupe transversale bas/départ (coupée): 400 mm; Largeur coupe transversale haut/fin (coupée): 250 mm; Largeur coupe transversale bas/départ (coupée): 250 mm; Surface coupe transversale bas/départ (coupée): 0.1 m2; Surface coupe transversale haut/fin: 0.1 m2; Nombre de segments: 1
AC_Pset_RenovationAndPhasing - Renovation Status: Existing
ArchiCADProperties - Coupe transversale de Poutre: Rectangulaire; Surface de fin: Bois-Pin; Surface gauche: Bois-Pin; Surface droite: Bois-Pin; Angle d'inclinaison de Poutre: 0 deg; Génération de modèle analytique structurel: yes; Membre étiré manuellement: no; ID de l'élément: Poutre-012; Lien et ID d'élément: Poutre-012; Calque: 3D; Matériau de construction / Composite / Profil / Hachure: Bloc béton 3409626266; Matériau de construction: Bloc béton 3409626266; Verrouillé: no; Nom d'étage d'implantation: sousol; Numéro d'étage d'implantation: 2; Type d'élément: Poutre; Type de structure: Basique; ID de Parent: Poutre-012; Matériaux de construction (Tous): Bloc béton 3409626266; Surfaces (Toutes): Bois-Pin; Angle d'inclinaison: 0 deg; Nombre de percements: 0; Surface supérieure: Bois-Pin; Surface inférieure: Bois-Pin; Nom de Variante: Modèle principal; Nom de Jeu de Variantes: Modèle principal; Position: Intérieur; Fonction structurelle: Élément porteur; Affichage sur filtre de rénovation: Tous les filtres appropriés; État de rénovation: Existant; État de Variante: Modèle principal; Jeu de Variantes: Modèle principal
Name | Superficie de la poutre côté gauche (nette) (m2) = Superficie de la poutre côté droit (nette) (m2) | Longueur gauche (mm) = Longueur droite (mm) = Longueur 3D (mm) | Superficie (m2) = Superficie supérieure (nette) (m2) = Superficie inférieure (nette) (m2) | Volume (net) (m3) = Volume (conditionnel) (m3) = Volume (brut) (m3) | Superficie en plan (m2)
Poutre-012 | 0.502493 | 1256.23 | 0.314058 | 0.125623 | 1.8331 | ArchiCADProperties - Nom de zone liée: Pl; Numéro de zone liée: 818
Poutre-012 | 0.556311 | 1390.78 | 0.347694 | 0.139078 | 2.00801

# IfcBeam: Bloc béton 3409626266 250 x 500 (3)
In: sousol
Classification: Poutre (Classification ARCHICAD); Material: Bloc béton 3409626266
ArchiCADProperties - Coupe transversale de Poutre: Rectangulaire; Surface de fin: Bois-Pin; Surface gauche: Bois-Pin; Surface droite: Bois-Pin; Angle d'inclinaison de Poutre: 0 deg; Génération de modèle analytique structurel: yes; Membre étiré manuellement: no; ID de l'élément: Poutre-012; Lien et ID d'élément: Poutre-012; Calque: 3D; Matériau de construction / Composite / Profil / Hachure: Bloc béton 3409626266; Matériau de construction: Bloc béton 3409626266; Verrouillé: no; Nom d'étage d'implantation: sousol; Numéro d'étage d'implantation: 2; Type d'élément: Poutre; Type de structure: Basique; ID de Parent: Poutre-012; Matériaux de construction (Tous): Bloc béton 3409626266; Surfaces (Toutes): Bois-Pin; Angle d'inclinaison: 0 deg; Nombre de percements: 0; Surface supérieure: Bois-Pin; Surface inférieure: Bois-Pin; Nom de Variante: Modèle principal; Nom de Jeu de Variantes: Modèle principal; Position: Intérieur; Fonction structurelle: Élément porteur; Affichage sur filtre de rénovation: Tous les filtres appropriés; État de rénovation: Existant; État de Variante: Modèle principal; Jeu de Variantes: Modèle principal
AC_Pset_RenovationAndPhasing - Renovation Status: Existing
ArchiCADQuantities - Nombre de trous: 0; Superficie des arêtes des trous: 0 m2; Superficie des trous: 0 m2; Volume des trous: 0 m3; Décalage: 0 mm; Hauteur: 500 mm; Largeur: 250 mm; Altitude à Zéro du Projet: 2950 mm; Altitude de Référence Niveau 1: 2950 mm; Altitude de Référence Niveau 2: 2950 mm; Altitude à niveau de la mer: 2950 mm; Altitude à étage lié/étage d'implantation: 2950 mm; Décalage étage d'implantation: 2950 mm; Altitude supérieure à premier niveau de référence: 2950 mm; Altitude supérieure à étage d'implantation: 2950 mm; Altitude supérieure à Zéro du projet: 2950 mm; Altitude supérieure à niveau de la mer: 2950 mm; Altitude supérieure à deuxième niveau de référence: 2950 mm; Altitude inférieure à premier niveau de référence: 2450 mm; Altitude inférieure à étage d'implantation: 2450 mm; Altitude inférieure à Zéro du projet: 2450 mm; Altitude inférieure à niveau de la mer: 2450 mm; Altitude inférieure à deuxième niveau de référence: 2450 mm; Hauteur coupe transversale haut/fin (perpendiculaire): 500 mm; Hauteur coupe transversale bas/départ (perpendiculaire): 500 mm; Largeur coupe transversale haut/fin (perpendiculaire): 250 mm; Largeur coupe transversale bas/départ (perpendiculaire): 250 mm; Hauteur coupe transversale haut/fin (coupée): 500 mm; Hauteur coupe transversale bas/départ (coupée): 500 mm; Largeur coupe transversale haut/fin (coupée): 250 mm; Largeur coupe transversale bas/départ (coupée): 250 mm; Surface coupe transversale haut/fin: 0.125 m2; Nombre de segments: 1
Name | Superficie des deux extrémités de poutre (m2) | Superficie de la poutre côté gauche (nette) (m2) = Superficie de la poutre côté droit (nette) (m2) | Longueur gauche (mm) = Longueur 3D (mm) | Longueur droite (mm) | Superficie (m2) = Superficie supérieure (nette) (m2) = Superficie inférieure (nette) (m2) | Volume (net) (m3) = Volume (conditionnel) (m3) | Superficie en plan (m2) | Volume (brut) (m3) | Surface coupe transversale bas/départ (coupée) (m2)
Poutre-012 | 0.25 | 0.703333 | 1406.67 | 1406.67 | 0.351666 | 0.175833 | 2.36 | 0.175833 | 0.125
Poutre-012 | 0.125 | 0.681795 | 1363.59 | 1663.59 | 0.340898 | 0.170449 | 2.29539 | 0.189199 | 0
Poutre-012 | 0.25 | 0.684992 | 1369.98 | 1369.98 | 0.342496 | 0.171248 | 2.30497 | 0.171248 | 0.125

# IfcBeam: Bloc béton 3409626266 300 x 600 (2)
In: sousol
Classification: Poutre (Classification ARCHICAD); Material: Bloc béton 3409626266
ArchiCADProperties - Coupe transversale de Poutre: Rectangulaire; Surface de fin: Bois-Pin; Surface gauche: Bois-Pin; Surface droite: Bois-Pin; Angle d'inclinaison de Poutre: 0 deg; Génération de modèle analytique structurel: yes; Membre étiré manuellement: no; ID de l'élément: Poutre-012; Lien et ID d'élément: Poutre-012; Calque: 3D; Matériau de construction / Composite / Profil / Hachure: Bloc béton 3409626266; Matériau de construction: Bloc béton 3409626266; Verrouillé: no; Nom d'étage d'implantation: sousol; Numéro d'étage d'implantation: 2; Type d'élément: Poutre; Type de structure: Basique; ID de Parent: Poutre-012; Matériaux de construction (Tous): Bloc béton 3409626266; Surfaces (Toutes): Bois-Pin; Angle d'inclinaison: 0 deg; Nombre de percements: 0; Surface supérieure: Bois-Pin; Surface inférieure: Bois-Pin; Nom de Variante: Modèle principal; Nom de Jeu de Variantes: Modèle principal; Position: Intérieur; Fonction structurelle: Élément porteur; Affichage sur filtre de rénovation: Tous les filtres appropriés; État de rénovation: Existant; État de Variante: Modèle principal; Jeu de Variantes: Modèle principal
AC_Pset_RenovationAndPhasing - Renovation Status: Existing
ArchiCADQuantities - Superficie des deux extrémités de poutre: 0.36 m2; Nombre de trous: 0; Superficie des arêtes des trous: 0 m2; Superficie des trous: 0 m2; Volume des trous: 0 m3; Décalage: 0 mm; Hauteur: 600 mm; Largeur: 300 mm; Altitude à Zéro du Projet: 2950 mm; Altitude de Référence Niveau 1: 2950 mm; Altitude de Référence Niveau 2: 2950 mm; Altitude à niveau de la mer: 2950 mm; Altitude à étage lié/étage d'implantation: 2950 mm; Décalage étage d'implantation: 2950 mm; Altitude supérieure à premier niveau de référence: 2950 mm; Altitude supérieure à étage d'implantation: 2950 mm; Altitude supérieure à Zéro du projet: 2950 mm; Altitude supérieure à niveau de la mer: 2950 mm; Altitude supérieure à deuxième niveau de référence: 2950 mm; Altitude inférieure à premier niveau de référence: 2350 mm; Altitude inférieure à étage d'implantation: 2350 mm; Altitude inférieure à Zéro du projet: 2350 mm; Altitude inférieure à niveau de la mer: 2350 mm; Altitude inférieure à deuxième niveau de référence: 2350 mm; Hauteur coupe transversale haut/fin (perpendiculaire): 600 mm; Hauteur coupe transversale bas/départ (perpendiculaire): 600 mm; Largeur coupe transversale haut/fin (perpendiculaire): 300 mm; Largeur coupe transversale bas/départ (perpendiculaire): 300 mm; Hauteur coupe transversale haut/fin (coupée): 600 mm; Hauteur coupe transversale bas/départ (coupée): 600 mm; Largeur coupe transversale haut/fin (coupée): 300 mm; Largeur coupe transversale bas/départ (coupée): 300 mm; Surface coupe transversale bas/départ (coupée): 0.18 m2; Surface coupe transversale haut/fin: 0.18 m2; Nombre de segments: 1
Name | Superficie de la poutre côté gauche (nette) (m2) = Superficie de la poutre côté droit (nette) (m2) | Longueur gauche (mm) = Longueur droite (mm) = Longueur 3D (mm) | Superficie (m2) = Superficie supérieure (nette) (m2) = Superficie inférieure (nette) (m2) | Volume (net) (m3) = Volume (conditionnel) (m3) = Volume (brut) (m3) | Superficie en plan (m2)
Poutre-012 | 1.89751 | 3162.51 | 0.948753 | 0.569252 | 6.05252
Poutre-012 | 6.12787 | 10213.1 | 3.06394 | 1.83836 | 18.7436 | ArchiCADProperties - Zones conflictuelles: Pl; Nom de zone liée: Pl; Numéro de zone liée: 818

# IfcBeam: Bloc béton 3409626266 300 x 700 (2)
In: sousol
Classification: Poutre (Classification ARCHICAD); Material: Bloc béton 3409626266
AC_Pset_RenovationAndPhasing - Renovation Status: Existing
ArchiCADProperties - Coupe transversale de Poutre: Rectangulaire; Surface de fin: Bois-Pin; Surface gauche: Bois-Pin; Surface droite: Bois-Pin; Angle d'inclinaison de Poutre: 0 deg; Génération de modèle analytique structurel: yes; Membre étiré manuellement: no; ID de l'élément: Poutre-012; Lien et ID d'élément: Poutre-012; Calque: 3D; Matériau de construction / Composite / Profil / Hachure: Bloc béton 3409626266; Matériau de construction: Bloc béton 3409626266; Verrouillé: no; Nom d'étage d'implantation: sousol; Numéro d'étage d'implantation: 2; Type d'élément: Poutre; Type de structure: Basique; ID de Parent: Poutre-012; Matériaux de construction (Tous): Bloc béton 3409626266; Surfaces (Toutes): Bois-Pin; Angle d'inclinaison: 0 deg; Nombre de percements: 0; Surface supérieure: Bois-Pin; Surface inférieure: Bois-Pin; Nom de Variante: Modèle principal; Nom de Jeu de Variantes: Modèle principal; Position: Intérieur; Fonction structurelle: Élément porteur; Affichage sur filtre de rénovation: Tous les filtres appropriés; État de rénovation: Existant; État de Variante: Modèle principal; Jeu de Variantes: Modèle principal
ArchiCADQuantities - Nombre de trous: 0; Superficie des arêtes des trous: 0 m2; Superficie des trous: 0 m2; Volume des trous: 0 m3; Décalage: 0 mm; Hauteur: 700 mm; Largeur: 300 mm; Altitude à Zéro du Projet: 2950 mm; Altitude de Référence Niveau 1: 2950 mm; Altitude de Référence Niveau 2: 2950 mm; Altitude à niveau de la mer: 2950 mm; Altitude à étage lié/étage d'implantation: 2950 mm; Décalage étage d'implantation: 2950 mm; Altitude supérieure à premier niveau de référence: 2950 mm; Altitude supérieure à étage d'implantation: 2950 mm; Altitude supérieure à Zéro du projet: 2950 mm; Altitude supérieure à niveau de la mer: 2950 mm; Altitude supérieure à deuxième niveau de référence: 2950 mm; Altitude inférieure à premier niveau de référence: 2250 mm; Altitude inférieure à étage d'implantation: 2250 mm; Altitude inférieure à Zéro du projet: 2250 mm; Altitude inférieure à niveau de la mer: 2250 mm; Altitude inférieure à deuxième niveau de référence: 2250 mm; Hauteur coupe transversale haut/fin (perpendiculaire): 700 mm; Hauteur coupe transversale bas/départ (perpendiculaire): 700 mm; Largeur coupe transversale haut/fin (perpendiculaire): 300 mm; Largeur coupe transversale bas/départ (perpendiculaire): 300 mm; Hauteur coupe transversale haut/fin (coupée): 700 mm; Hauteur coupe transversale bas/départ (coupée): 700 mm; Largeur coupe transversale haut/fin (coupée): 300 mm; Largeur coupe transversale bas/départ (coupée): 300 mm; Surface coupe transversale haut/fin: 0.21 m2; Nombre de segments: 1
Name | Superficie des deux extrémités de poutre (m2) | Superficie de la poutre côté gauche (nette) (m2) | Longueur gauche (mm) = Longueur droite (mm) | Superficie de la poutre côté droit (nette) (m2) | Superficie (m2) = Superficie supérieure (nette) (m2) = Superficie inférieure (nette) (m2) | Volume (net) (m3) = Volume (conditionnel) (m3) | Superficie en plan (m2) | Longueur 3D (mm) | Volume (brut) (m3) | Surface coupe transversale bas/départ (coupée) (m2)
Poutre-012 | 0.315 | 3.57931 | 5293.42 | 3.57939 | 1.53402 | 1.07381 | 11.0667 | 5113.64 | 1.11162 | 0.105
Poutre-012 | 0.42 | 3.4157 | 5179.57 | 3.4157 | 1.46387 | 1.02471 | 10.5991 | 4879.57 | 1.08771 | 0.21

# IfcBeam: Bloc béton 3409626266 300 x 750, Poutre-012
In: sousol
Classification: Poutre (Classification ARCHICAD); Material: Bloc béton 3409626266
AC_Pset_RenovationAndPhasing - Renovation Status: Existing
ArchiCADQuantities - Superficie des deux extrémités de poutre: 0.45 m2; Nombre de trous: 0; Superficie des arêtes des trous: 0 m2; Superficie des trous: 0 m2; Volume des trous: 0 m3; Superficie de la poutre côté gauche (nette): 3.65182 m2; Longueur gauche: 5329.1 mm; Longueur droite: 5329.1 mm; Décalage: 0 mm; Superficie de la poutre côté droit (nette): 3.65182 m2; Superficie: 1.46073 m2; Hauteur: 750 mm; Volume (net): 1.09555 m3; Largeur: 300 mm; Altitude à Zéro du Projet: 2950 mm; Altitude de Référence Niveau 1: 2950 mm; Altitude de Référence Niveau 2: 2950 mm; Altitude à niveau de la mer: 2950 mm; Altitude à étage lié/étage d'implantation: 2950 mm; Décalage étage d'implantation: 2950 mm; Superficie en plan: 11.1251 m2; Longueur 3D: 4869.1 mm; Volume (conditionnel): 1.09555 m3; Volume (brut): 1.19905 m3; Altitude supérieure à premier niveau de référence: 2950 mm; Altitude supérieure à étage d'implantation: 2950 mm; Altitude supérieure à Zéro du projet: 2950 mm; Altitude supérieure à niveau de la mer: 2950 mm; Altitude supérieure à deuxième niveau de référence: 2950 mm; Altitude inférieure à premier niveau de référence: 2200 mm; Altitude inférieure à étage d'implantation: 2200 mm; Altitude inférieure à Zéro du projet: 2200 mm; Altitude inférieure à niveau de la mer: 2200 mm; Altitude inférieure à deuxième niveau de référence: 2200 mm; Hauteur coupe transversale haut/fin (perpendiculaire): 750 mm; Hauteur coupe transversale bas/départ (perpendiculaire): 750 mm; Largeur coupe transversale haut/fin (perpendiculaire): 300 mm; Largeur coupe transversale bas/départ (perpendiculaire): 300 mm; Hauteur coupe transversale haut/fin (coupée): 750 mm; Hauteur coupe transversale bas/départ (coupée): 750 mm; Largeur coupe transversale haut/fin (coupée): 300 mm; Largeur coupe transversale bas/départ (coupée): 300 mm; Surface coupe transversale bas/départ (coupée): 0.225 m2; Surface coupe transversale haut/fin: 0.225 m2; Nombre de segments: 1; Superficie supérieure (nette): 1.46073 m2; Superficie inférieure (nette): 1.46073 m2
ArchiCADProperties - Coupe transversale de Poutre: Rectangulaire; Surface de fin: Bois-Pin; Surface gauche: Bois-Pin; Surface droite: Bois-Pin; Angle d'inclinaison de Poutre: 0 deg; Génération de modèle analytique structurel: yes; Membre étiré manuellement: no; ID de l'élément: Poutre-012; Lien et ID d'élément: Poutre-012; Calque: 3D; Matériau de construction / Composite / Profil / Hachure: Bloc béton 3409626266; Matériau de construction: Bloc béton 3409626266; Verrouillé: no; Nom d'étage d'implantation: sousol; Numéro d'étage d'implantation: 2; Type d'élément: Poutre; Type de structure: Basique; ID de Parent: Poutre-012; Matériaux de construction (Tous): Bloc béton 3409626266; Surfaces (Toutes): Bois-Pin; Angle d'inclinaison: 0 deg; Nombre de percements: 0; Surface supérieure: Bois-Pin; Surface inférieure: Bois-Pin; Nom de Variante: Modèle principal; Nom de Jeu de Variantes: Modèle principal; Position: Intérieur; Fonction structurelle: Élément porteur; Affichage sur filtre de rénovation: Tous les filtres appropriés; État de rénovation: Existant; État de Variante: Modèle principal; Jeu de Variantes: Modèle principal

# IfcBeam: Bloc béton 3409626266 300 x 850, Poutre-012
In: sousol
Classification: Poutre (Classification ARCHICAD); Material: Bloc béton 3409626266
AC_Pset_RenovationAndPhasing - Renovation Status: Existing
ArchiCADQuantities - Superficie des deux extrémités de poutre: 0.255 m2; Nombre de trous: 0; Superficie des arêtes des trous: 0 m2; Superficie des trous: 0 m2; Volume des trous: 0 m3; Superficie de la poutre côté gauche (nette): 4.55635 m2; Longueur gauche: 5391.03 mm; Longueur droite: 5391.03 mm; Décalage: 0 mm; Superficie de la poutre côté droit (nette): 3.90135 m2; Superficie: 1.52165 m2; Hauteur: 850 mm; Volume (net): 1.17811 m3; Largeur: 300 mm; Altitude à Zéro du Projet: 2950 mm; Altitude de Référence Niveau 1: 2950 mm; Altitude de Référence Niveau 2: 2950 mm; Altitude à niveau de la mer: 2950 mm; Altitude à étage lié/étage d'implantation: 2950 mm; Décalage étage d'implantation: 2950 mm; Superficie en plan: 13.2048 m2; Longueur 3D: 5360.41 mm; Volume (conditionnel): 1.17811 m3; Volume (brut): 1.29224 m3; Altitude supérieure à premier niveau de référence: 2950 mm; Altitude supérieure à étage d'implantation: 2950 mm; Altitude supérieure à Zéro du projet: 2950 mm; Altitude supérieure à niveau de la mer: 2950 mm; Altitude supérieure à deuxième niveau de référence: 2950 mm; Altitude inférieure à premier niveau de référence: 2100 mm; Altitude inférieure à étage d'implantation: 2100 mm; Altitude inférieure à Zéro du projet: 2100 mm; Altitude inférieure à niveau de la mer: 2100 mm; Altitude inférieure à deuxième niveau de référence: 2100 mm; Hauteur coupe transversale haut/fin (perpendiculaire): 850 mm; Hauteur coupe transversale bas/départ (perpendiculaire): 850 mm; Largeur coupe transversale haut/fin (perpendiculaire): 300 mm; Largeur coupe transversale bas/départ (perpendiculaire): 300 mm; Hauteur coupe transversale haut/fin (coupée): 850 mm; Hauteur coupe transversale bas/départ (coupée): 850 mm; Largeur coupe transversale haut/fin (coupée): 300 mm; Largeur coupe transversale bas/départ (coupée): 300 mm; Surface coupe transversale bas/départ (coupée): 0 m2; Surface coupe transversale haut/fin: 0.255 m2; Nombre de segments: 1; Superficie supérieure (nette): 1.37753 m2; Superficie inférieure (nette): 1.66577 m2
ArchiCADProperties - Coupe transversale de Poutre: Rectangulaire; Surface de fin: Bois-Pin; Surface gauche: Bois-Pin; Surface droite: Bois-Pin; Angle d'inclinaison de Poutre: 0 deg; Génération de modèle analytique structurel: yes; Membre étiré manuellement: no; ID de l'élément: Poutre-012; Lien et ID d'élément: Poutre-012; Calque: 3D; Matériau de construction / Composite / Profil / Hachure: Bloc béton 3409626266; Matériau de construction: Bloc béton 3409626266; Verrouillé: no; Nom d'étage d'implantation: sousol; Numéro d'étage d'implantation: 2; Type d'élément: Poutre; Type de structure: Basique; ID de Parent: Poutre-012; Matériaux de construction (Tous): Bloc béton 3409626266; Surfaces (Toutes): Bois-Pin; Angle d'inclinaison: 0 deg; Nombre de percements: 0; Surface supérieure: Bois-Pin; Surface inférieure: Bois-Pin; Nom de Variante: Modèle principal; Nom de Jeu de Variantes: Modèle principal; Position: Intérieur; Fonction structurelle: Élément porteur; Affichage sur filtre de rénovation: Tous les filtres appropriés; État de rénovation: Existant; État de Variante: Modèle principal; Jeu de Variantes: Modèle principal

# IfcBeam: Bloc béton 3409626266 400 x 850 (2)
In: sousol
Classification: Poutre (Classification ARCHICAD); Material: Bloc béton 3409626266
ArchiCADProperties - Coupe transversale de Poutre: Rectangulaire; Surface de fin: Bois-Pin; Surface gauche: Bois-Pin; Surface droite: Bois-Pin; Angle d'inclinaison de Poutre: 0 deg; Génération de modèle analytique structurel: yes; Membre étiré manuellement: no; ID de l'élément: Poutre-012; Lien et ID d'élément: Poutre-012; Calque: 3D; Matériau de construction / Composite / Profil / Hachure: Bloc béton 3409626266; Matériau de construction: Bloc béton 3409626266; Verrouillé: no; Nom d'étage d'implantation: sousol; Numéro d'étage d'implantation: 2; Type d'élément: Poutre; Type de structure: Basique; ID de Parent: Poutre-012; Matériaux de construction (Tous): Bloc béton 3409626266; Surfaces (Toutes): Bois-Pin; Angle d'inclinaison: 0 deg; Nombre de percements: 0; Surface supérieure: Bois-Pin; Surface inférieure: Bois-Pin; Nom de Variante: Modèle principal; Nom de Jeu de Variantes: Modèle principal; Position: Intérieur; Fonction structurelle: Élément porteur; Affichage sur filtre de rénovation: Tous les filtres appropriés; État de rénovation: Existant; État de Variante: Modèle principal; Jeu de Variantes: Modèle principal
AC_Pset_RenovationAndPhasing - Renovation Status: Existing
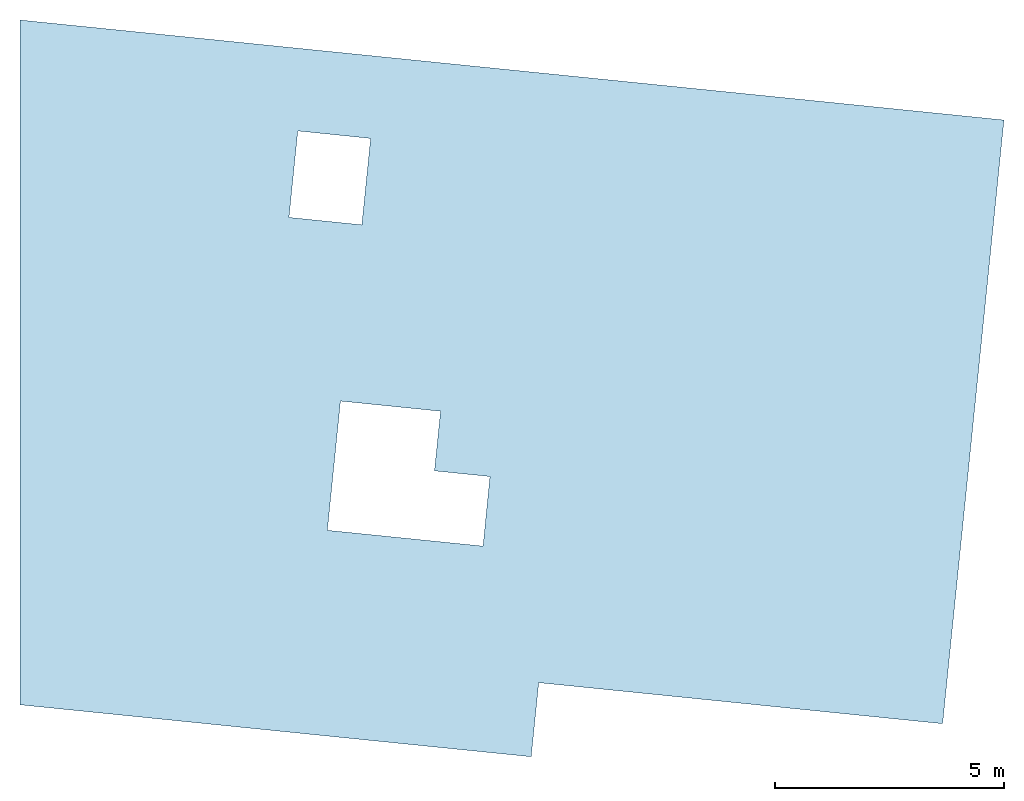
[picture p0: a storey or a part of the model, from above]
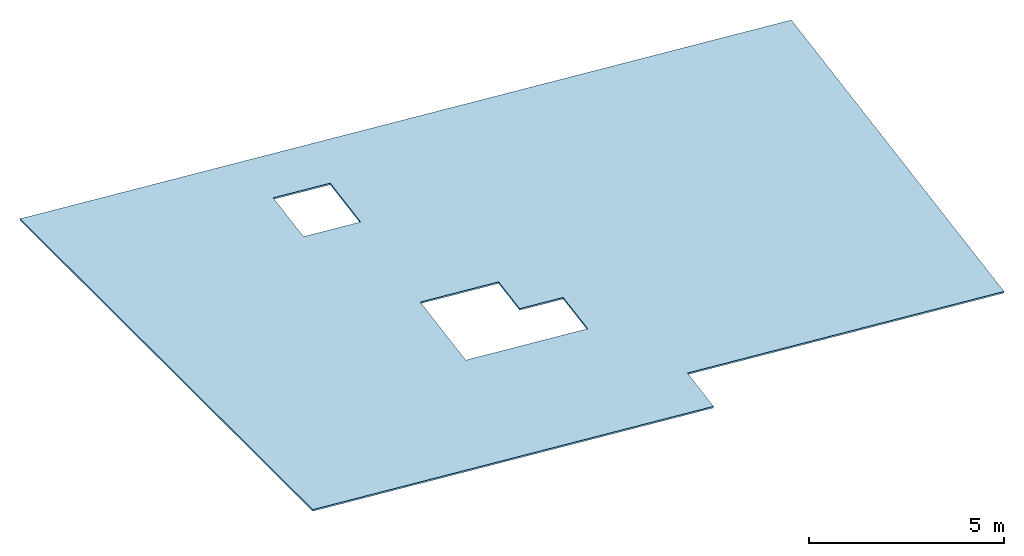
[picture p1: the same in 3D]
Properties of the parts of a building model (IFC2X3), part 2 of 44

# IfcBeam: Bloc béton 3409626266 400 x 850 (2)
ArchiCADQuantities - Superficie des deux extrémités de poutre: 0.68 m2; Nombre de trous: 0; Superficie des arêtes des trous: 0 m2; Superficie des trous: 0 m2; Volume des trous: 0 m3; Décalage: 0 mm; Hauteur: 850 mm; Largeur: 400 mm; Altitude à Zéro du Projet: 2950 mm; Altitude de Référence Niveau 1: 2950 mm; Altitude de Référence Niveau 2: 2950 mm; Altitude à niveau de la mer: 2950 mm; Altitude à étage lié/étage d'implantation: 2950 mm; Décalage étage d'implantation: 2950 mm; Altitude supérieure à premier niveau de référence: 2950 mm; Altitude supérieure à étage d'implantation: 2950 mm; Altitude supérieure à Zéro du projet: 2950 mm; Altitude supérieure à niveau de la mer: 2950 mm; Altitude supérieure à deuxième niveau de référence: 2950 mm; Altitude inférieure à premier niveau de référence: 2100 mm; Altitude inférieure à étage d'implantation: 2100 mm; Altitude inférieure à Zéro du projet: 2100 mm; Altitude inférieure à niveau de la mer: 2100 mm; Altitude inférieure à deuxième niveau de référence: 2100 mm; Hauteur coupe transversale haut/fin (perpendiculaire): 850 mm; Hauteur coupe transversale bas/départ (perpendiculaire): 850 mm; Largeur coupe transversale haut/fin (perpendiculaire): 400 mm; Largeur coupe transversale bas/départ (perpendiculaire): 400 mm; Hauteur coupe transversale haut/fin (coupée): 850 mm; Hauteur coupe transversale bas/départ (coupée): 850 mm; Largeur coupe transversale haut/fin (coupée): 400 mm; Largeur coupe transversale bas/départ (coupée): 400 mm; Surface coupe transversale bas/départ (coupée): 0.34 m2; Surface coupe transversale haut/fin: 0.34 m2; Nombre de segments: 1
Name | Superficie de la poutre côté gauche (nette) (m2) | Longueur gauche (mm) = Longueur droite (mm) = Longueur 3D (mm) | Superficie de la poutre côté droit (nette) (m2) | Superficie (m2) = Superficie supérieure (nette) (m2) = Superficie inférieure (nette) (m2) | Volume (net) (m3) = Volume (conditionnel) (m3) | Superficie en plan (m2) | Volume (brut) (m3)
Poutre-012 | 5.13568 | 6041.98 | 5.13568 | 2.41679 | 2.05427 | 15.785 | 2.05427
Poutre-012 | 6.82133 | 8025.09 | 6.13283 | 2.97197 | 2.52617 | 21.2659 | 2.72853

# IfcBeam: Bloc béton 3409626266 500 x 600, Poutre-012
In: sousol
Classification: Poutre (Classification ARCHICAD); Material: Bloc béton 3409626266
ArchiCADQuantities - Superficie des deux extrémités de poutre: 0.6 m2; Nombre de trous: 0; Superficie des arêtes des trous: 0 m2; Superficie des trous: 0 m2; Volume des trous: 0 m3; Superficie de la poutre côté gauche (nette): 3.01155 m2; Longueur gauche: 5019.24 mm; Longueur droite: 5019.24 mm; Décalage: 0 mm; Superficie de la poutre côté droit (nette): 3.01155 m2; Superficie: 2.50962 m2; Hauteur: 600 mm; Volume (net): 1.50577 m3; Largeur: 500 mm; Altitude à Zéro du Projet: 2950 mm; Altitude de Référence Niveau 1: 2950 mm; Altitude de Référence Niveau 2: 2950 mm; Altitude à niveau de la mer: 2950 mm; Altitude à étage lié/étage d'implantation: 2950 mm; Décalage étage d'implantation: 2950 mm; Superficie en plan: 11.6423 m2; Longueur 3D: 5019.24 mm; Volume (conditionnel): 1.50577 m3; Volume (brut): 1.50577 m3; Altitude supérieure à premier niveau de référence: 2950 mm; Altitude supérieure à étage d'implantation: 2950 mm; Altitude supérieure à Zéro du projet: 2950 mm; Altitude supérieure à niveau de la mer: 2950 mm; Altitude supérieure à deuxième niveau de référence: 2950 mm; Altitude inférieure à premier niveau de référence: 2350 mm; Altitude inférieure à étage d'implantation: 2350 mm; Altitude inférieure à Zéro du projet: 2350 mm; Altitude inférieure à niveau de la mer: 2350 mm; Altitude inférieure à deuxième niveau de référence: 2350 mm; Hauteur coupe transversale haut/fin (perpendiculaire): 600 mm; Hauteur coupe transversale bas/départ (perpendiculaire): 600 mm; Largeur coupe transversale haut/fin (perpendiculaire): 500 mm; Largeur coupe transversale bas/départ (perpendiculaire): 500 mm; Hauteur coupe transversale haut/fin (coupée): 600 mm; Hauteur coupe transversale bas/départ (coupée): 600 mm; Largeur coupe transversale haut/fin (coupée): 500 mm; Largeur coupe transversale bas/départ (coupée): 500 mm; Surface coupe transversale bas/départ (coupée): 0.3 m2; Surface coupe transversale haut/fin: 0.3 m2; Nombre de segments: 1; Superficie supérieure (nette): 2.50962 m2; Superficie inférieure (nette): 2.50962 m2
AC_Pset_RenovationAndPhasing - Renovation Status: Existing
ArchiCADProperties - Coupe transversale de Poutre: Rectangulaire; Surface de fin: Bois-Pin; Surface gauche: Bois-Pin; Surface droite: Bois-Pin; Angle d'inclinaison de Poutre: 0 deg; Génération de modèle analytique structurel: yes; Membre étiré manuellement: no; ID de l'élément: Poutre-012; Lien et ID d'élément: Poutre-012; Calque: 3D; Matériau de construction / Composite / Profil / Hachure: Bloc béton 3409626266; Matériau de construction: Bloc béton 3409626266; Verrouillé: no; Nom d'étage d'implantation: sousol; Numéro d'étage d'implantation: 2; Type d'élément: Poutre; Type de structure: Basique; ID de Parent: Poutre-012; Matériaux de construction (Tous): Bloc béton 3409626266; Surfaces (Toutes): Bois-Pin; Angle d'inclinaison: 0 deg; Nombre de percements: 0; Surface supérieure: Bois-Pin; Surface inférieure: Bois-Pin; Nom de Variante: Modèle principal; Nom de Jeu de Variantes: Modèle principal; Position: Intérieur; Fonction structurelle: Élément porteur; Affichage sur filtre de rénovation: Tous les filtres appropriés; État de rénovation: Existant; État de Variante: Modèle principal; Jeu de Variantes: Modèle principal

# IfcBeam: Brique 1 268964100 180 x 200 (20)
Classification: Poutre (Classification ARCHICAD); Material: Brique 1 268964100
ArchiCADProperties - Coupe transversale de Poutre: Rectangulaire; Surface de fin: Bois-Pin; Surface gauche: Bois-Pin; Surface droite: Bois-Pin; Angle d'inclinaison de Poutre: 0 deg; Génération de modèle analytique structurel: yes; Membre étiré manuellement: no; ID de l'élément: Poutre-010; Lien et ID d'élément: Poutre-010; Matériau de construction / Composite / Profil / Hachure: Brique 1 268964100; Matériau de construction: Brique 1 268964100; Verrouillé: no; Type d'élément: Poutre; Type de structure: Basique; ID de Parent: Poutre-010; Matériaux de construction (Tous): Brique 1 268964100; Surfaces (Toutes): Bois-Pin; Angle d'inclinaison: 0 deg; Nombre de percements: 0; Surface supérieure: Bois-Pin; Surface inférieure: Bois-Pin; Nom de Variante: Modèle principal; Nom de Jeu de Variantes: Modèle principal; Position: Intérieur; Fonction structurelle: Élément porteur; Affichage sur filtre de rénovation: Tous les filtres appropriés; État de rénovation: Existant; État de Variante: Modèle principal; Jeu de Variantes: Modèle principal
AC_Pset_RenovationAndPhasing - Renovation Status: Existing
ArchiCADQuantities - Superficie des deux extrémités de poutre: 0.072 m2; Nombre de trous: 0; Superficie des arêtes des trous: 0 m2; Superficie des trous: 0 m2; Volume des trous: 0 m3; Décalage: 0 mm; Hauteur: 200 mm; Largeur: 180 mm; Hauteur coupe transversale haut/fin (perpendiculaire): 200 mm; Hauteur coupe transversale bas/départ (perpendiculaire): 200 mm; Largeur coupe transversale haut/fin (perpendiculaire): 180 mm; Largeur coupe transversale bas/départ (perpendiculaire): 180 mm; Hauteur coupe transversale haut/fin (coupée): 200 mm; Hauteur coupe transversale bas/départ (coupée): 200 mm; Largeur coupe transversale haut/fin (coupée): 180 mm; Largeur coupe transversale bas/départ (coupée): 180 mm; Surface coupe transversale bas/départ (coupée): 0.036 m2; Surface coupe transversale haut/fin: 0.036 m2; Nombre de segments: 1
Name | In | Calque | Zones conflictuelles | Nom de zone liée | Numéro de zone liée | Nom d'étage d'implantation | Numéro d'étage d'implantation | Superficie de la poutre côté gauche (nette) (m2) = Superficie de la poutre côté droit (nette) (m2) | Longueur gauche (mm) = Longueur droite (mm) = Longueur 3D (mm) | Superficie (m2) = Superficie supérieure (nette) (m2) = Superficie inférieure (nette) (m2) | Volume (net) (m3) = Volume (conditionnel) (m3) = Volume (brut) (m3) | Altitude à Zéro du Projet (mm) = Altitude de Référence Niveau 1 (mm) = Altitude de Référence Niveau 2 (mm) = Altitude à niveau de la mer (mm) = Altitude supérieure à premier niveau de référence (mm) = Altitude supérieure à Zéro du projet (mm) = Altitude supérieure à niveau de la mer (mm) = Altitude supérieure à deuxième niveau de référence (mm) | Altitude à étage lié/étage d'implantation (mm) = Décalage étage d'implantation (mm) = Altitude supérieure à étage d'implantation (mm) | Superficie en plan (m2) | Altitude inférieure à premier niveau de référence (mm) = Altitude inférieure à Zéro du projet (mm) = Altitude inférieure à niveau de la mer (mm) = Altitude inférieure à deuxième niveau de référence (mm) | Altitude inférieure à étage d'implantation (mm)
Poutre-010 | rdc | 3D | Sejour cuisine | Sejour cuisine | A03 | rdc | 3 | 0.480795 | 2403.98 | 0.432716 | 0.0865432 | 5300 | 2300 | 1.89902 | 5100 | 2100
Poutre-010 | rdc | 3D | Cellier; Ch 2; Sejour cuisine/pl | Ch 2 | B04 | rdc | 3 | 1.18929 | 5946.47 | 1.07036 | 0.214073 | 5500 | 2500 | 4.59131 | 5300 | 2300
Poutre-010 | rdc | 3D |  |  |  | rdc | 3 | 0.252946 | 1264.73 | 0.227651 | 0.0455303 | 5300 | 2300 | 1.03319 | 5100 | 2100
Poutre-010 | Etage1 | 3D |  |  |  | Etage1 | 4 | 0.252946 | 1264.73 | 0.227651 | 0.0455303 | 8050 | 2300 | 1.03319 | 7850 | 2100
Poutre-010 | Etage1 | 3D | Sejour cuisine/pl | Sejour cuisine/pl | A11 | Etage1 | 4 | 0.624 | 3120 | 0.5616 | 0.11232 | 8050 | 2300 | 2.4432 | 7850 | 2100
Poutre-010 | Etage1 | 3D | Sejour cuisine | Sejour cuisine | A13 | Etage1 | 4 | 0.480795 | 2403.98 | 0.432716 | 0.0865432 | 8050 | 2300 | 1.89902 | 7850 | 2100
Poutre-010 | Etage 2 | PRO INDIC | Ch 1; Ch 1; Ch 2/pl | Ch 2/pl | A24 | Etage 2 | 5 | 1.89957 | 9497.86 | 1.70961 | 0.341923 | 11000 | 2500 | 7.29037 | 10800 | 2300
Poutre-010 | Etage 2 | 3D |  | Ch 1/pl | B24 | Etage 2 | 5 | 2.13302 | 10665.1 | 1.91972 | 0.383943 | 11200 | 2700 | 8.17747 | 11000 | 2500
Poutre-010 | Etage 2 | PRO INDIC | Ch 1; Ch 1/pl; Ch 2 | Ch 1 | A22 | Etage 2 | 5 | 1.99602 | 9980.12 | 1.79642 | 0.359284 | 11000 | 2500 | 7.65689 | 10800 | 2300
Poutre-010 | Etage 2 | 3D |  |  |  | Etage 2 | 5 | 0.252946 | 1264.73 | 0.227651 | 0.0455303 | 11000 | 2500 | 1.03319 | 10800 | 2300
Poutre-010 | Etage 2 | PRO INDIC | Sejour cuisine/pl | Sejour cuisine/pl | A21 | Etage 2 | 5 | 0.624 | 3120 | 0.5616 | 0.11232 | 11000 | 2500 | 2.4432 | 10800 | 2300
Poutre-010 | Etage 2 | PRO INDIC | Sejour cuisine | Sejour cuisine | A23 | Etage 2 | 5 | 0.480795 | 2403.98 | 0.432716 | 0.0865432 | 10800 | 2300 | 1.89902 | 10600 | 2100
Poutre-010 | Etage 3 | 3D |  | Sejour cuisine | B34 | Etage 3 | 6 | 2.98191 | 14909.6 | 2.68372 | 0.536744 | 14250 | 2700 | 11.4033 | 14050 | 2500
Poutre-010 | Etage 3 | 3D |  |  |  | Etage 3 | 6 | 0.252946 | 1264.73 | 0.227651 | 0.0455303 | 14050 | 2500 | 1.03319 | 13850 | 2300
Poutre-010 | Etage 3 | 3D | Sejour cuisine | Sejour cuisine | A32 | Etage 3 | 6 | 0.549788 | 2748.94 | 0.49481 | 0.0989619 | 14050 | 2500 | 2.1612 | 13850 | 2300
Poutre-010 | Etage 3 | 3D | Sejour cuisine/pl | Sejour cuisine/pl | B35 | Etage 3 | 6 | 0.90464 | 4523.2 | 0.814176 | 0.162835 | 14050 | 2500 | 3.50963 | 13850 | 2300
Poutre-010 | Etage 3 | 3D | Sejour cuisine | Sejour cuisine | A32 | Etage 3 | 6 | 0.480795 | 2403.98 | 0.432716 | 0.0865432 | 13850 | 2300 | 1.89902 | 13650 | 2100
Poutre-010 | etage 4 | 3D | Sejour cuisine | Sejour cuisine | B53 | etage 4 | 7 | 2.26785 | 11339.3 | 2.04107 | 0.408213 | 17100 | 2500 | 8.68983 | 16900 | 2300
Poutre-010 | etage 4 | 3D |  | Ch 3/sde | B44 | etage 4 | 7 | 2.96387 | 14819.3 | 2.66748 | 0.533496 | 17300 | 2700 | 11.3347 | 17100 | 2500
Poutre-010 | Etage 5 | 3D | Sdb | Sdb | B51 | Etage 5 | 8 | 0.647087 | 3235.43 | 0.582378 | 0.116476 | 20150 | 2500 | 2.53093 | 19950 | 2300

# IfcBeam: Brique 1 268964100 180 x 300, Poutre-010
In: Etage 3
Classification: Poutre (Classification ARCHICAD); Material: Brique 1 268964100
ArchiCADProperties - Coupe transversale de Poutre: Rectangulaire; Surface de fin: Bois-Pin; Surface gauche: Bois-Pin; Surface droite: Bois-Pin; Angle d'inclinaison de Poutre: 0 deg; Génération de modèle analytique structurel: yes; Membre étiré manuellement: no; ID de l'élément: Poutre-010; Lien et ID d'élément: Poutre-010; Calque: 3D; Matériau de construction / Composite / Profil / Hachure: Brique 1 268964100; Matériau de construction: Brique 1 268964100; Nom de zone liée: Sejour cuisine/pl; Numéro de zone liée: B35; Verrouillé: no; Nom d'étage d'implantation: Etage 3; Numéro d'étage d'implantation: 6; Type d'élément: Poutre; Type de structure: Basique; ID de Parent: Poutre-010; Matériaux de construction (Tous): Brique 1 268964100; Surfaces (Toutes): Bois-Pin; Angle d'inclinaison: 0 deg; Nombre de percements: 0; Surface supérieure: Bois-Pin; Surface inférieure: Bois-Pin; Nom de Variante: Modèle principal; Nom de Jeu de Variantes: Modèle principal; Position: Intérieur; Fonction structurelle: Élément porteur; Affichage sur filtre de rénovation: Tous les filtres appropriés; État de rénovation: Existant; État de Variante: Modèle principal; Jeu de Variantes: Modèle principal
ArchiCADQuantities - Superficie des deux extrémités de poutre: 0.108 m2; Nombre de trous: 0; Superficie des arêtes des trous: 0 m2; Superficie des trous: 0 m2; Volume des trous: 0 m3; Superficie de la poutre côté gauche (nette): 1.06275 m2; Longueur gauche: 3542.49 mm; Longueur droite: 3542.49 mm; Décalage: 0 mm; Superficie de la poutre côté droit (nette): 1.06275 m2; Superficie: 0.637649 m2; Hauteur: 300 mm; Volume (net): 0.191295 m3; Largeur: 180 mm; Altitude à Zéro du Projet: 14350 mm; Altitude de Référence Niveau 1: 14350 mm; Altitude de Référence Niveau 2: 14350 mm; Altitude à niveau de la mer: 14350 mm; Altitude à étage lié/étage d'implantation: 2800 mm; Décalage étage d'implantation: 2800 mm; Superficie en plan: 3.50879 m2; Longueur 3D: 3542.49 mm; Volume (conditionnel): 0.191295 m3; Volume (brut): 0.191295 m3; Altitude supérieure à premier niveau de référence: 14350 mm; Altitude supérieure à étage d'implantation: 2800 mm; Altitude supérieure à Zéro du projet: 14350 mm; Altitude supérieure à niveau de la mer: 14350 mm; Altitude supérieure à deuxième niveau de référence: 14350 mm; Altitude inférieure à premier niveau de référence: 14050 mm; Altitude inférieure à étage d'implantation: 2500 mm; Altitude inférieure à Zéro du projet: 14050 mm; Altitude inférieure à niveau de la mer: 14050 mm; Altitude inférieure à deuxième niveau de référence: 14050 mm; Hauteur coupe transversale haut/fin (perpendiculaire): 300 mm; Hauteur coupe transversale bas/départ (perpendiculaire): 300 mm; Largeur coupe transversale haut/fin (perpendiculaire): 180 mm; Largeur coupe transversale bas/départ (perpendiculaire): 180 mm; Hauteur coupe transversale haut/fin (coupée): 300 mm; Hauteur coupe transversale bas/départ (coupée): 300 mm; Largeur coupe transversale haut/fin (coupée): 180 mm; Largeur coupe transversale bas/départ (coupée): 180 mm; Surface coupe transversale bas/départ (coupée): 0.054 m2; Surface coupe transversale haut/fin: 0.054 m2; Nombre de segments: 1; Superficie supérieure (nette): 0.637649 m2; Superficie inférieure (nette): 0.637649 m2
AC_Pset_RenovationAndPhasing - Renovation Status: Existing

# IfcBeam: Brique 1 268964100 180 x 400, Poutre-010
In: rdc
Classification: Poutre (Classification ARCHICAD); Material: Brique 1 268964100
ArchiCADProperties - Coupe transversale de Poutre: Rectangulaire; Surface de fin: Poutre; Surface gauche: Poutre; Surface droite: Poutre; Angle d'inclinaison de Poutre: 0 deg; Génération de modèle analytique structurel: yes; Membre étiré manuellement: no; ID de l'élément: Poutre-010; Lien et ID d'élément: Poutre-010; Calque: 3D; Matériau de construction / Composite / Profil / Hachure: Brique 1 268964100; Matériau de construction: Brique 1 268964100; Verrouillé: no; Nom d'étage d'implantation: rdc; Numéro d'étage d'implantation: 3; Type d'élément: Poutre; Type de structure: Basique; ID de Parent: Poutre-010; Matériaux de construction (Tous): Brique 1 268964100; Surfaces (Toutes): Poutre; Angle d'inclinaison: 0 deg; Nombre de percements: 0; Surface supérieure: Poutre; Surface inférieure: Poutre; Nom de Variante: Modèle principal; Nom de Jeu de Variantes: Modèle principal; Position: Intérieur; Fonction structurelle: Élément porteur; Affichage sur filtre de rénovation: Tous les filtres appropriés; État de rénovation: Existant; État de Variante: Modèle principal; Jeu de Variantes: Modèle principal
AC_Pset_RenovationAndPhasing - Renovation Status: Existing
ArchiCADQuantities - Superficie des deux extrémités de poutre: 0.144001 m2; Nombre de trous: 0; Superficie des arêtes des trous: 0 m2; Superficie des trous: 0 m2; Volume des trous: 0 m3; Superficie de la poutre côté gauche (nette): 1.04723 m2; Longueur gauche: 2618.09 mm; Longueur droite: 2618.06 mm; Décalage: 0 mm; Superficie de la poutre côté droit (nette): 1.04723 m2; Superficie: 0.471253 m2; Hauteur: 400.002 mm; Volume (net): 0.188502 m3; Largeur: 180 mm; Altitude à Zéro du Projet: 5550 mm; Altitude de Référence Niveau 1: 5550 mm; Altitude de Référence Niveau 2: 5550 mm; Altitude à niveau de la mer: 5550 mm; Altitude à étage lié/étage d'implantation: 2550 mm; Décalage étage d'implantation: 2550 mm; Superficie en plan: 3.18098 m2; Longueur 3D: 2618.07 mm; Volume (conditionnel): 0.188502 m3; Volume (brut): 0.188502 m3; Altitude supérieure à premier niveau de référence: 5550 mm; Altitude supérieure à étage d'implantation: 2550 mm; Altitude supérieure à Zéro du projet: 5550 mm; Altitude supérieure à niveau de la mer: 5550 mm; Altitude supérieure à deuxième niveau de référence: 5550 mm; Altitude inférieure à premier niveau de référence: 5150 mm; Altitude inférieure à étage d'implantation: 2150 mm; Altitude inférieure à Zéro du projet: 5150 mm; Altitude inférieure à niveau de la mer: 5150 mm; Altitude inférieure à deuxième niveau de référence: 5150 mm; Hauteur coupe transversale haut/fin (perpendiculaire): 400.002 mm; Hauteur coupe transversale bas/départ (perpendiculaire): 400.002 mm; Largeur coupe transversale haut/fin (perpendiculaire): 180 mm; Largeur coupe transversale bas/départ (perpendiculaire): 180 mm; Hauteur coupe transversale haut/fin (coupée): 400.002 mm; Hauteur coupe transversale bas/départ (coupée): 400.002 mm; Largeur coupe transversale haut/fin (coupée): 180 mm; Largeur coupe transversale bas/départ (coupée): 180 mm; Surface coupe transversale bas/départ (coupée): 0.0720003 m2; Surface coupe transversale haut/fin: 0.0720003 m2; Nombre de segments: 1; Superficie supérieure (nette): 0.471253 m2; Superficie inférieure (nette): 0.471253 m2

# IfcBeam: Brique 1 268964100 200 x 200, Poutre-010
In: Etage 2
Classification: Poutre (Classification ARCHICAD); Material: Brique 1 268964100
ArchiCADProperties - Coupe transversale de Poutre: Rectangulaire; Surface de fin: Bois-Pin; Surface gauche: Bois-Pin; Surface droite: Bois-Pin; Angle d'inclinaison de Poutre: 0 deg; Génération de modèle analytique structurel: yes; Membre étiré manuellement: no; ID de l'élément: Poutre-010; Lien et ID d'élément: Poutre-010; Calque: PRO INDIC; Matériau de construction / Composite / Profil / Hachure: Brique 1 268964100; Matériau de construction: Brique 1 268964100; Zones conflictuelles: Sejour cuisine/pl; Nom de zone liée: Sejour cuisine/pl; Numéro de zone liée: A21; Verrouillé: no; Nom d'étage d'implantation: Etage 2; Numéro d'étage d'implantation: 5; Type d'élément: Poutre; Type de structure: Basique; ID de Parent: Poutre-010; Matériaux de construction (Tous): Brique 1 268964100; Surfaces (Toutes): Bois-Pin; Angle d'inclinaison: 0 deg; Nombre de percements: 0; Surface supérieure: Bois-Pin; Surface inférieure: Bois-Pin; Nom de Variante: Modèle principal; Nom de Jeu de Variantes: Modèle principal; Position: Intérieur; Fonction structurelle: Élément porteur; Affichage sur filtre de rénovation: Tous les filtres appropriés; État de rénovation: Existant; État de Variante: Modèle principal; Jeu de Variantes: Modèle principal
ArchiCADQuantities - Superficie des deux extrémités de poutre: 0.08 m2; Nombre de trous: 0; Superficie des arêtes des trous: 0 m2; Superficie des trous: 0 m2; Volume des trous: 0 m3; Superficie de la poutre côté gauche (nette): 1.23347 m2; Longueur gauche: 6167.37 mm; Longueur droite: 6167.37 mm; Décalage: 0 mm; Superficie de la poutre côté droit (nette): 1.23347 m2; Superficie: 1.23347 m2; Hauteur: 200 mm; Volume (net): 0.246695 m3; Largeur: 200 mm; Altitude à Zéro du Projet: 11000 mm; Altitude de Référence Niveau 1: 11000 mm; Altitude de Référence Niveau 2: 11000 mm; Altitude à niveau de la mer: 11000 mm; Altitude à étage lié/étage d'implantation: 2500 mm; Décalage étage d'implantation: 2500 mm; Superficie en plan: 5.0139 m2; Longueur 3D: 6167.37 mm; Volume (conditionnel): 0.246695 m3; Volume (brut): 0.246695 m3; Altitude supérieure à premier niveau de référence: 11000 mm; Altitude supérieure à étage d'implantation: 2500 mm; Altitude supérieure à Zéro du projet: 11000 mm; Altitude supérieure à niveau de la mer: 11000 mm; Altitude supérieure à deuxième niveau de référence: 11000 mm; Altitude inférieure à premier niveau de référence: 10800 mm; Altitude inférieure à étage d'implantation: 2300 mm; Altitude inférieure à Zéro du projet: 10800 mm; Altitude inférieure à niveau de la mer: 10800 mm; Altitude inférieure à deuxième niveau de référence: 10800 mm; Hauteur coupe transversale haut/fin (perpendiculaire): 200 mm; Hauteur coupe transversale bas/départ (perpendiculaire): 200 mm; Largeur coupe transversale haut/fin (perpendiculaire): 200 mm; Largeur coupe transversale bas/départ (perpendiculaire): 200 mm; Hauteur coupe transversale haut/fin (coupée): 200 mm; Hauteur coupe transversale bas/départ (coupée): 200 mm; Largeur coupe transversale haut/fin (coupée): 200 mm; Largeur coupe transversale bas/départ (coupée): 200 mm; Surface coupe transversale bas/départ (coupée): 0.04 m2; Surface coupe transversale haut/fin: 0.04 m2; Nombre de segments: 1; Superficie supérieure (nette): 1.23347 m2; Superficie inférieure (nette): 1.23347 m2
AC_Pset_RenovationAndPhasing - Renovation Status: Existing

# IfcBeam: Brique 1 268964100 300 x 200, Poutre-010
In: Etage 3
Classification: Poutre (Classification ARCHICAD); Material: Brique 1 268964100
ArchiCADQuantities - Superficie des deux extrémités de poutre: 0.12 m2; Nombre de trous: 0; Superficie des arêtes des trous: 0 m2; Superficie des trous: 0 m2; Volume des trous: 0 m3; Superficie de la poutre côté gauche (nette): 0.507758 m2; Longueur gauche: 2538.79 mm; Longueur droite: 2538.79 mm; Décalage: 0 mm; Superficie de la poutre côté droit (nette): 0.507758 m2; Superficie: 0.761638 m2; Hauteur: 200 mm; Volume (net): 0.152328 m3; Largeur: 300 mm; Altitude à Zéro du Projet: 14050 mm; Altitude de Référence Niveau 1: 14050 mm; Altitude de Référence Niveau 2: 14050 mm; Altitude à niveau de la mer: 14050 mm; Altitude à étage lié/étage d'implantation: 2500 mm; Décalage étage d'implantation: 2500 mm; Superficie en plan: 2.65879 m2; Longueur 3D: 2538.79 mm; Volume (conditionnel): 0.152328 m3; Volume (brut): 0.152328 m3; Altitude supérieure à premier niveau de référence: 14050 mm; Altitude supérieure à étage d'implantation: 2500 mm; Altitude supérieure à Zéro du projet: 14050 mm; Altitude supérieure à niveau de la mer: 14050 mm; Altitude supérieure à deuxième niveau de référence: 14050 mm; Altitude inférieure à premier niveau de référence: 13850 mm; Altitude inférieure à étage d'implantation: 2300 mm; Altitude inférieure à Zéro du projet: 13850 mm; Altitude inférieure à niveau de la mer: 13850 mm; Altitude inférieure à deuxième niveau de référence: 13850 mm; Hauteur coupe transversale haut/fin (perpendiculaire): 200 mm; Hauteur coupe transversale bas/départ (perpendiculaire): 200 mm; Largeur coupe transversale haut/fin (perpendiculaire): 300 mm; Largeur coupe transversale bas/départ (perpendiculaire): 300 mm; Hauteur coupe transversale haut/fin (coupée): 200 mm; Hauteur coupe transversale bas/départ (coupée): 200 mm; Largeur coupe transversale haut/fin (coupée): 300 mm; Largeur coupe transversale bas/départ (coupée): 300 mm; Surface coupe transversale bas/départ (coupée): 0.06 m2; Surface coupe transversale haut/fin: 0.06 m2; Nombre de segments: 1; Superficie supérieure (nette): 0.761638 m2; Superficie inférieure (nette): 0.761638 m2
ArchiCADProperties - Coupe transversale de Poutre: Rectangulaire; Surface de fin: Bois-Pin; Surface gauche: Bois-Pin; Surface droite: Bois-Pin; Angle d'inclinaison de Poutre: 0 deg; Génération de modèle analytique structurel: yes; Membre étiré manuellement: no; ID de l'élément: Poutre-010; Lien et ID d'élément: Poutre-010; Calque: 3D; Matériau de construction / Composite / Profil / Hachure: Brique 1 268964100; Matériau de construction: Brique 1 268964100; Zones conflictuelles: Sejour cuisine; Nom de zone liée: Sejour cuisine; Numéro de zone liée: B34; Verrouillé: no; Nom d'étage d'implantation: Etage 3; Numéro d'étage d'implantation: 6; Type d'élément: Poutre; Type de structure: Basique; ID de Parent: Poutre-010; Matériaux de construction (Tous): Brique 1 268964100; Surfaces (Toutes): Bois-Pin; Angle d'inclinaison: 0 deg; Nombre de percements: 0; Surface supérieure: Bois-Pin; Surface inférieure: Bois-Pin; Nom de Variante: Modèle principal; Nom de Jeu de Variantes: Modèle principal; Position: Intérieur; Fonction structurelle: Élément porteur; Affichage sur filtre de rénovation: Tous les filtres appropriés; État de rénovation: Existant; État de Variante: Modèle principal; Jeu de Variantes: Modèle principal
AC_Pset_RenovationAndPhasing - Renovation Status: Existing

# IfcBeam: Brique 1 268964100 400 x 200, Poutre-010
In: etage 4
Classification: Poutre (Classification ARCHICAD); Material: Brique 1 268964100
ArchiCADProperties - Coupe transversale de Poutre: Rectangulaire; Surface de fin: Bois-Pin; Surface gauche: Bois-Pin; Surface droite: Bois-Pin; Angle d'inclinaison de Poutre: 0 deg; Génération de modèle analytique structurel: yes; Membre étiré manuellement: no; ID de l'élément: Poutre-010; Lien et ID d'élément: Poutre-010; Calque: 3D; Matériau de construction / Composite / Profil / Hachure: Brique 1 268964100; Matériau de construction: Brique 1 268964100; Zones conflictuelles: Sejour cuisine; Nom de zone liée: Sejour cuisine; Numéro de zone liée: B44; Verrouillé: no; Nom d'étage d'implantation: etage 4; Numéro d'étage d'implantation: 7; Type d'élément: Poutre; Type de structure: Basique; ID de Parent: Poutre-010; Matériaux de construction (Tous): Brique 1 268964100; Surfaces (Toutes): Bois-Pin; Angle d'inclinaison: 0 deg; Nombre de percements: 0; Surface supérieure: Bois-Pin; Surface inférieure: Bois-Pin; Nom de Variante: Modèle principal; Nom de Jeu de Variantes: Modèle principal; Position: Intérieur; Fonction structurelle: Élément porteur; Affichage sur filtre de rénovation: Tous les filtres appropriés; État de rénovation: Existant; État de Variante: Modèle principal; Jeu de Variantes: Modèle principal
ArchiCADQuantities - Superficie des deux extrémités de poutre: 0.16 m2; Nombre de trous: 0; Superficie des arêtes des trous: 0 m2; Superficie des trous: 0 m2; Volume des trous: 0 m3; Superficie de la poutre côté gauche (nette): 0.883901 m2; Longueur gauche: 4419.5 mm; Longueur droite: 4419.5 mm; Décalage: 0 mm; Superficie de la poutre côté droit (nette): 0.883901 m2; Superficie: 1.7678 m2; Hauteur: 200 mm; Volume (net): 0.35356 m3; Largeur: 400 mm; Altitude à Zéro du Projet: 17100 mm; Altitude de Référence Niveau 1: 17100 mm; Altitude de Référence Niveau 2: 17100 mm; Altitude à niveau de la mer: 17100 mm; Altitude à étage lié/étage d'implantation: 2500 mm; Décalage étage d'implantation: 2500 mm; Superficie en plan: 5.4634 m2; Longueur 3D: 4419.5 mm; Volume (conditionnel): 0.35356 m3; Volume (brut): 0.35356 m3; Altitude supérieure à premier niveau de référence: 17100 mm; Altitude supérieure à étage d'implantation: 2500 mm; Altitude supérieure à Zéro du projet: 17100 mm; Altitude supérieure à niveau de la mer: 17100 mm; Altitude supérieure à deuxième niveau de référence: 17100 mm; Altitude inférieure à premier niveau de référence: 16900 mm; Altitude inférieure à étage d'implantation: 2300 mm; Altitude inférieure à Zéro du projet: 16900 mm; Altitude inférieure à niveau de la mer: 16900 mm; Altitude inférieure à deuxième niveau de référence: 16900 mm; Hauteur coupe transversale haut/fin (perpendiculaire): 200 mm; Hauteur coupe transversale bas/départ (perpendiculaire): 200 mm; Largeur coupe transversale haut/fin (perpendiculaire): 400 mm; Largeur coupe transversale bas/départ (perpendiculaire): 400 mm; Hauteur coupe transversale haut/fin (coupée): 200 mm; Hauteur coupe transversale bas/départ (coupée): 200 mm; Largeur coupe transversale haut/fin (coupée): 400 mm; Largeur coupe transversale bas/départ (coupée): 400 mm; Surface coupe transversale bas/départ (coupée): 0.08 m2; Surface coupe transversale haut/fin: 0.08 m2; Nombre de segments: 1; Superficie supérieure (nette): 1.7678 m2; Superficie inférieure (nette): 1.7678 m2
AC_Pset_RenovationAndPhasing - Renovation Status: Existing

# IfcBeam: Parpaing 2676271321 180 x 200 (6)
Classification: Poutre (Classification ARCHICAD); Material: Parpaing 2676271321
AC_Pset_RenovationAndPhasing - Renovation Status: Existing
ArchiCADQuantities - Superficie des deux extrémités de poutre: 0.072 m2; Nombre de trous: 0; Superficie des arêtes des trous: 0 m2; Superficie des trous: 0 m2; Volume des trous: 0 m3; Décalage: 0 mm; Hauteur: 200 mm; Largeur: 180 mm; Hauteur coupe transversale haut/fin (perpendiculaire): 200 mm; Hauteur coupe transversale bas/départ (perpendiculaire): 200 mm; Largeur coupe transversale haut/fin (perpendiculaire): 180 mm; Largeur coupe transversale bas/départ (perpendiculaire): 180 mm; Hauteur coupe transversale haut/fin (coupée): 200 mm; Hauteur coupe transversale bas/départ (coupée): 200 mm; Largeur coupe transversale haut/fin (coupée): 180 mm; Largeur coupe transversale bas/départ (coupée): 180 mm; Surface coupe transversale bas/départ (coupée): 0.036 m2; Surface coupe transversale haut/fin: 0.036 m2; Nombre de segments: 1
ArchiCADProperties - Coupe transversale de Poutre: Rectangulaire; Surface de fin: Bois-Pin; Surface gauche: Bois-Pin; Surface droite: Bois-Pin; Angle d'inclinaison de Poutre: 0 deg; Génération de modèle analytique structurel: yes; Membre étiré manuellement: no; ID de l'élément: Poutre-010; Lien et ID d'élément: Poutre-010; Calque: 3D; Matériau de construction / Composite / Profil / Hachure: Parpaing 2676271321; Matériau de construction: Parpaing 2676271321; Verrouillé: no; Type d'élément: Poutre; Type de structure: Basique; ID de Parent: Poutre-010; Matériaux de construction (Tous): Parpaing 2676271321; Surfaces (Toutes): Bois-Pin; Angle d'inclinaison: 0 deg; Nombre de percements: 0; Surface supérieure: Bois-Pin; Surface inférieure: Bois-Pin; Nom de Variante: Modèle principal; Nom de Jeu de Variantes: Modèle principal; Position: Intérieur; Fonction structurelle: Élément porteur; Affichage sur filtre de rénovation: Tous les filtres appropriés; État de rénovation: Existant; État de Variante: Modèle principal; Jeu de Variantes: Modèle principal
Name | In | Superficie de la poutre côté gauche (nette) (m2) = Superficie de la poutre côté droit (nette) (m2) | Longueur gauche (mm) = Longueur droite (mm) = Longueur 3D (mm) | Superficie (m2) = Superficie supérieure (nette) (m2) = Superficie inférieure (nette) (m2) | Volume (net) (m3) = Volume (conditionnel) (m3) = Volume (brut) (m3) | Altitude à Zéro du Projet (mm) = Altitude de Référence Niveau 1 (mm) = Altitude de Référence Niveau 2 (mm) = Altitude à niveau de la mer (mm) = Altitude supérieure à premier niveau de référence (mm) = Altitude supérieure à Zéro du projet (mm) = Altitude supérieure à niveau de la mer (mm) = Altitude supérieure à deuxième niveau de référence (mm) | Altitude à étage lié/étage d'implantation (mm) = Décalage étage d'implantation (mm) = Altitude supérieure à étage d'implantation (mm) | Superficie en plan (m2) | Altitude inférieure à premier niveau de référence (mm) = Altitude inférieure à Zéro du projet (mm) = Altitude inférieure à niveau de la mer (mm) = Altitude inférieure à deuxième niveau de référence (mm) | Altitude inférieure à étage d'implantation (mm) | Zones conflictuelles | Nom de zone liée | Numéro de zone liée | Nom d'étage d'implantation | Numéro d'étage d'implantation
Poutre-010 | rdc | 0.708499 | 3542.49 | 0.637649 | 0.12753 | 5500 | 2500 | 2.7643 | 5300 | 2300 | Sejour cuisine; Wc | Sejour cuisine | B05 | rdc | 3
Poutre-010 | rdc | 0.733616 | 3668.08 | 0.660255 | 0.132051 | 5500 | 2500 | 2.85974 | 5300 | 2300 | Cellier; Entree/pl; Wc | Entree/pl | B04 | rdc | 3
Poutre-010 | Etage1 | 0.708499 | 3542.49 | 0.637649 | 0.12753 | 8250 | 2500 | 2.7643 | 8050 | 2300 | Sejour cuisine; Wc | Sejour cuisine | B16 | Etage1 | 4
Poutre-010 | Etage1 | 0.984952 | 4924.76 | 0.886456 | 0.177291 | 8250 | 2500 | 3.81482 | 8050 | 2300 | Entree/pl; Sejour cuisine; Wc | Cellier | B15 | Etage1 | 4
Poutre-010 | Etage 2 | 0.708499 | 3542.49 | 0.637649 | 0.12753 | 11300 | 2800 | 2.7643 | 11100 | 2600 |  | Wc | B26 | Etage 2 | 5
Poutre-010 | Etage 2 | 0.984952 | 4924.76 | 0.886456 | 0.177291 | 11300 | 2800 | 3.81482 | 11100 | 2600 |  | Cellier | B25 | Etage 2 | 5

# IfcBeam: Parpaing 2676271321 180 x 300, Poutre-010
In: Etage 3
Classification: Poutre (Classification ARCHICAD); Material: Parpaing 2676271321
ArchiCADProperties - Coupe transversale de Poutre: Rectangulaire; Surface de fin: Bois-Pin; Surface gauche: Bois-Pin; Surface droite: Bois-Pin; Angle d'inclinaison de Poutre: 0 deg; Génération de modèle analytique structurel: yes; Membre étiré manuellement: no; ID de l'élément: Poutre-010; Lien et ID d'élément: Poutre-010; Calque: 3D; Matériau de construction / Composite / Profil / Hachure: Parpaing 2676271321; Matériau de construction: Parpaing 2676271321; Nom de zone liée: Sejour cuisine/pl; Numéro de zone liée: B35; Verrouillé: no; Nom d'étage d'implantation: Etage 3; Numéro d'étage d'implantation: 6; Type d'élément: Poutre; Type de structure: Basique; ID de Parent: Poutre-010; Matériaux de construction (Tous): Parpaing 2676271321; Surfaces (Toutes): Bois-Pin; Angle d'inclinaison: 0 deg; Nombre de percements: 0; Surface supérieure: Bois-Pin; Surface inférieure: Bois-Pin; Nom de Variante: Modèle principal; Nom de Jeu de Variantes: Modèle principal; Position: Intérieur; Fonction structurelle: Élément porteur; Affichage sur filtre de rénovation: Tous les filtres appropriés; État de rénovation: Existant; État de Variante: Modèle principal; Jeu de Variantes: Modèle principal
AC_Pset_RenovationAndPhasing - Renovation Status: Existing
ArchiCADQuantities - Superficie des deux extrémités de poutre: 0.108 m2; Nombre de trous: 0; Superficie des arêtes des trous: 0 m2; Superficie des trous: 0 m2; Volume des trous: 0 m3; Superficie de la poutre côté gauche (nette): 1.06275 m2; Longueur gauche: 3542.49 mm; Longueur droite: 3542.49 mm; Décalage: 0 mm; Superficie de la poutre côté droit (nette): 1.06275 m2; Superficie: 0.637649 m2; Hauteur: 300 mm; Volume (net): 0.191295 m3; Largeur: 180 mm; Altitude à Zéro du Projet: 14350 mm; Altitude de Référence Niveau 1: 14350 mm; Altitude de Référence Niveau 2: 14350 mm; Altitude à niveau de la mer: 14350 mm; Altitude à étage lié/étage d'implantation: 2800 mm; Décalage étage d'implantation: 2800 mm; Superficie en plan: 3.50879 m2; Longueur 3D: 3542.49 mm; Volume (conditionnel): 0.191295 m3; Volume (brut): 0.191295 m3; Altitude supérieure à premier niveau de référence: 14350 mm; Altitude supérieure à étage d'implantation: 2800 mm; Altitude supérieure à Zéro du projet: 14350 mm; Altitude supérieure à niveau de la mer: 14350 mm; Altitude supérieure à deuxième niveau de référence: 14350 mm; Altitude inférieure à premier niveau de référence: 14050 mm; Altitude inférieure à étage d'implantation: 2500 mm; Altitude inférieure à Zéro du projet: 14050 mm; Altitude inférieure à niveau de la mer: 14050 mm; Altitude inférieure à deuxième niveau de référence: 14050 mm; Hauteur coupe transversale haut/fin (perpendiculaire): 300 mm; Hauteur coupe transversale bas/départ (perpendiculaire): 300 mm; Largeur coupe transversale haut/fin (perpendiculaire): 180 mm; Largeur coupe transversale bas/départ (perpendiculaire): 180 mm; Hauteur coupe transversale haut/fin (coupée): 300 mm; Hauteur coupe transversale bas/départ (coupée): 300 mm; Largeur coupe transversale haut/fin (coupée): 180 mm; Largeur coupe transversale bas/départ (coupée): 180 mm; Surface coupe transversale bas/départ (coupée): 0.054 m2; Surface coupe transversale haut/fin: 0.054 m2; Nombre de segments: 1; Superficie supérieure (nette): 0.637649 m2; Superficie inférieure (nette): 0.637649 m2

# IfcBeam: Parpaing 2676271321 180 x 500 (2)
Classification: Poutre (Classification ARCHICAD); Material: Parpaing 2676271321
AC_Pset_RenovationAndPhasing - Renovation Status: Existing
ArchiCADQuantities - Superficie des deux extrémités de poutre: 0.18 m2; Nombre de trous: 0; Superficie des arêtes des trous: 0 m2; Superficie des trous: 0 m2; Volume des trous: 0 m3; Décalage: 0 mm; Hauteur: 500.001 mm; Largeur: 180 mm; Altitude à étage lié/étage d'implantation: 3000 mm; Décalage étage d'implantation: 3000 mm; Altitude supérieure à étage d'implantation: 3000 mm; Altitude inférieure à étage d'implantation: 2500 mm; Hauteur coupe transversale haut/fin (perpendiculaire): 500.001 mm; Hauteur coupe transversale bas/départ (perpendiculaire): 500.001 mm; Largeur coupe transversale haut/fin (perpendiculaire): 180 mm; Largeur coupe transversale bas/départ (perpendiculaire): 180 mm; Hauteur coupe transversale haut/fin (coupée): 500.001 mm; Hauteur coupe transversale bas/départ (coupée): 500.001 mm; Largeur coupe transversale haut/fin (coupée): 180 mm; Largeur coupe transversale bas/départ (coupée): 180 mm; Surface coupe transversale bas/départ (coupée): 0.0900002 m2; Surface coupe transversale haut/fin: 0.0900002 m2; Nombre de segments: 1
ArchiCADProperties - Coupe transversale de Poutre: Rectangulaire; Surface de fin: Bois-Pin; Surface gauche: Bois-Pin; Surface droite: Bois-Pin; Angle d'inclinaison de Poutre: 0 deg; Génération de modèle analytique structurel: yes; Membre étiré manuellement: no; ID de l'élément: Poutre-010; Lien et ID d'élément: Poutre-010; Calque: 3D; Matériau de construction / Composite / Profil / Hachure: Parpaing 2676271321; Matériau de construction: Parpaing 2676271321; Nom de zone liée: Sejour cuisine; Verrouillé: no; Type d'élément: Poutre; Type de structure: Basique; ID de Parent: Poutre-010; Matériaux de construction (Tous): Parpaing 2676271321; Surfaces (Toutes): Bois-Pin; Angle d'inclinaison: 0 deg; Nombre de percements: 0; Surface supérieure: Bois-Pin; Surface inférieure: Bois-Pin; Nom de Variante: Modèle principal; Nom de Jeu de Variantes: Modèle principal; Position: Intérieur; Fonction structurelle: Élément porteur; Affichage sur filtre de rénovation: Tous les filtres appropriés; État de rénovation: Existant; État de Variante: Modèle principal; Jeu de Variantes: Modèle principal
Name | In | Superficie de la poutre côté gauche (nette) (m2) = Superficie de la poutre côté droit (nette) (m2) | Longueur gauche (mm) = Longueur droite (mm) = Longueur 3D (mm) | Superficie (m2) = Superficie supérieure (nette) (m2) = Superficie inférieure (nette) (m2) | Volume (net) (m3) = Volume (conditionnel) (m3) = Volume (brut) (m3) | Altitude à Zéro du Projet (mm) = Altitude de Référence Niveau 1 (mm) = Altitude de Référence Niveau 2 (mm) = Altitude à niveau de la mer (mm) = Altitude supérieure à premier niveau de référence (mm) = Altitude supérieure à Zéro du projet (mm) = Altitude supérieure à niveau de la mer (mm) = Altitude supérieure à deuxième niveau de référence (mm) | Superficie en plan (m2) | Altitude inférieure à premier niveau de référence (mm) = Altitude inférieure à Zéro du projet (mm) = Altitude inférieure à niveau de la mer (mm) = Altitude inférieure à deuxième niveau de référence (mm) | Numéro de zone liée | Nom d'étage d'implantation | Numéro d'étage d'implantation
Poutre-010 | Etage 2 | 7.10625 | 14212.5 | 2.55824 | 1.27912 | 11500 | 19.509 | 11000 | B24 | Etage 2 | 5
Poutre-010 | Etage 3 | 7.93602 | 15872 | 2.85696 | 1.42848 | 14550 | 21.766 | 14050 | B34 | Etage 3 | 6

# IfcBeam: Parpaing 2676271321 180 x 550, Poutre-010
In: etage 4
Classification: Poutre (Classification ARCHICAD); Material: Parpaing 2676271321
ArchiCADProperties - Coupe transversale de Poutre: Rectangulaire; Surface de fin: Bois-Pin; Surface gauche: Bois-Pin; Surface droite: Bois-Pin; Angle d'inclinaison de Poutre: 0 deg; Génération de modèle analytique structurel: yes; Membre étiré manuellement: no; ID de l'élément: Poutre-010; Lien et ID d'élément: Poutre-010; Calque: 3D; Matériau de construction / Composite / Profil / Hachure: Parpaing 2676271321; Matériau de construction: Parpaing 2676271321; Nom de zone liée: Sejour cuisine; Numéro de zone liée: B42; Verrouillé: no; Nom d'étage d'implantation: etage 4; Numéro d'étage d'implantation: 7; Type d'élément: Poutre; Type de structure: Basique; ID de Parent: Poutre-010; Matériaux de construction (Tous): Parpaing 2676271321; Surfaces (Toutes): Bois-Pin; Angle d'inclinaison: 0 deg; Nombre de percements: 0; Surface supérieure: Bois-Pin; Surface inférieure: Bois-Pin; Nom de Variante: Modèle principal; Nom de Jeu de Variantes: Modèle principal; Position: Intérieur; Fonction structurelle: Élément porteur; Affichage sur filtre de rénovation: Tous les filtres appropriés; État de rénovation: Existant; État de Variante: Modèle principal; Jeu de Variantes: Modèle principal
ArchiCADQuantities - Superficie des deux extrémités de poutre: 0.198 m2; Nombre de trous: 0; Superficie des arêtes des trous: 0 m2; Superficie des trous: 0 m2; Volume des trous: 0 m3; Superficie de la poutre côté gauche (nette): 6.13759 m2; Longueur gauche: 11159.2 mm; Longueur droite: 11159.2 mm; Décalage: 0 mm; Superficie de la poutre côté droit (nette): 6.13759 m2; Superficie: 2.00866 m2; Hauteur: 550 mm; Volume (net): 1.10477 m3; Largeur: 180 mm; Altitude à Zéro du Projet: 17650 mm; Altitude de Référence Niveau 1: 17650 mm; Altitude de Référence Niveau 2: 17650 mm; Altitude à niveau de la mer: 17650 mm; Altitude à étage lié/étage d'implantation: 3050 mm; Décalage étage d'implantation: 3050 mm; Superficie en plan: 16.4905 m2; Longueur 3D: 11159.2 mm; Volume (conditionnel): 1.10477 m3; Volume (brut): 1.10477 m3; Altitude supérieure à premier niveau de référence: 17650 mm; Altitude supérieure à étage d'implantation: 3050 mm; Altitude supérieure à Zéro du projet: 17650 mm; Altitude supérieure à niveau de la mer: 17650 mm; Altitude supérieure à deuxième niveau de référence: 17650 mm; Altitude inférieure à premier niveau de référence: 17100 mm; Altitude inférieure à étage d'implantation: 2500 mm; Altitude inférieure à Zéro du projet: 17100 mm; Altitude inférieure à niveau de la mer: 17100 mm; Altitude inférieure à deuxième niveau de référence: 17100 mm; Hauteur coupe transversale haut/fin (perpendiculaire): 550 mm; Hauteur coupe transversale bas/départ (perpendiculaire): 550 mm; Largeur coupe transversale haut/fin (perpendiculaire): 180 mm; Largeur coupe transversale bas/départ (perpendiculaire): 180 mm; Hauteur coupe transversale haut/fin (coupée): 550 mm; Hauteur coupe transversale bas/départ (coupée): 550 mm; Largeur coupe transversale haut/fin (coupée): 180 mm; Largeur coupe transversale bas/départ (coupée): 180 mm; Surface coupe transversale bas/départ (coupée): 0.099 m2; Surface coupe transversale haut/fin: 0.099 m2; Nombre de segments: 1; Superficie supérieure (nette): 2.00866 m2; Superficie inférieure (nette): 2.00866 m2
AC_Pset_RenovationAndPhasing - Renovation Status: Existing

# IfcBeam: Parpaing 2676271321 180 x 600, Poutre-010
In: rdc
Classification: Poutre (Classification ARCHICAD); Material: Parpaing 2676271321
ArchiCADProperties - Coupe transversale de Poutre: Rectangulaire; Surface de fin: Poutre; Surface gauche: Poutre; Surface droite: Poutre; Angle d'inclinaison de Poutre: 0 deg; Génération de modèle analytique structurel: yes; Membre étiré manuellement: no; ID de l'élément: Poutre-010; Lien et ID d'élément: Poutre-010; Calque: 3D; Matériau de construction / Composite / Profil / Hachure: Parpaing 2676271321; Matériau de construction: Parpaing 2676271321; Verrouillé: no; Nom d'étage d'implantation: rdc; Numéro d'étage d'implantation: 3; Type d'élément: Poutre; Type de structure: Basique; ID de Parent: Poutre-010; Matériaux de construction (Tous): Parpaing 2676271321; Surfaces (Toutes): Poutre; Angle d'inclinaison: 0 deg; Nombre de percements: 0; Surface supérieure: Poutre; Surface inférieure: Poutre; Nom de Variante: Modèle principal; Nom de Jeu de Variantes: Modèle principal; Position: Intérieur; Fonction structurelle: Élément porteur; Affichage sur filtre de rénovation: Tous les filtres appropriés; État de rénovation: Existant; État de Variante: Modèle principal; Jeu de Variantes: Modèle principal
ArchiCADQuantities - Superficie des deux extrémités de poutre: 0.216 m2; Nombre de trous: 0; Superficie des arêtes des trous: 0 m2; Superficie des trous: 0 m2; Volume des trous: 0 m3; Superficie de la poutre côté gauche (nette): 2.32968 m2; Longueur gauche: 3882.82 mm; Longueur droite: 3882.79 mm; Décalage: 0 mm; Superficie de la poutre côté droit (nette): 2.32968 m2; Superficie: 0.698905 m2; Hauteur: 600 mm; Volume (net): 0.419343 m3; Largeur: 180 mm; Altitude à Zéro du Projet: 5750 mm; Altitude de Référence Niveau 1: 5750 mm; Altitude de Référence Niveau 2: 5750 mm; Altitude à niveau de la mer: 5750 mm; Altitude à étage lié/étage d'implantation: 2750 mm; Décalage étage d'implantation: 2750 mm; Superficie en plan: 6.27318 m2; Longueur 3D: 3882.8 mm; Volume (conditionnel): 0.419343 m3; Volume (brut): 0.419343 m3; Altitude supérieure à premier niveau de référence: 5750 mm; Altitude supérieure à étage d'implantation: 2750 mm; Altitude supérieure à Zéro du projet: 5750 mm; Altitude supérieure à niveau de la mer: 5750 mm; Altitude supérieure à deuxième niveau de référence: 5750 mm; Altitude inférieure à premier niveau de référence: 5150 mm; Altitude inférieure à étage d'implantation: 2150 mm; Altitude inférieure à Zéro du projet: 5150 mm; Altitude inférieure à niveau de la mer: 5150 mm; Altitude inférieure à deuxième niveau de référence: 5150 mm; Hauteur coupe transversale haut/fin (perpendiculaire): 600 mm; Hauteur coupe transversale bas/départ (perpendiculaire): 600 mm; Largeur coupe transversale haut/fin (perpendiculaire): 180 mm; Largeur coupe transversale bas/départ (perpendiculaire): 180 mm; Hauteur coupe transversale haut/fin (coupée): 600 mm; Hauteur coupe transversale bas/départ (coupée): 600 mm; Largeur coupe transversale haut/fin (coupée): 180 mm; Largeur coupe transversale bas/départ (coupée): 180 mm; Surface coupe transversale bas/départ (coupée): 0.108 m2; Surface coupe transversale haut/fin: 0.108 m2; Nombre de segments: 1; Superficie supérieure (nette): 0.698905 m2; Superficie inférieure (nette): 0.698905 m2
AC_Pset_RenovationAndPhasing - Renovation Status: Existing

# IfcBeam: Parpaing 2676271321 180 x 700, Poutre-010
In: etage 4
Classification: Poutre (Classification ARCHICAD); Material: Parpaing 2676271321
ArchiCADProperties - Coupe transversale de Poutre: Rectangulaire; Surface de fin: Bois-Pin; Surface gauche: Bois-Pin; Surface droite: Bois-Pin; Angle d'inclinaison de Poutre: 0 deg; Génération de modèle analytique structurel: yes; Membre étiré manuellement: no; ID de l'élément: Poutre-010; Lien et ID d'élément: Poutre-010; Calque: 3D; Matériau de construction / Composite / Profil / Hachure: Parpaing 2676271321; Matériau de construction: Parpaing 2676271321; Zones conflictuelles: Sejour cuisine; Nom de zone liée: Sejour cuisine; Numéro de zone liée: B44; Verrouillé: no; Nom d'étage d'implantation: etage 4; Numéro d'étage d'implantation: 7; Type d'élément: Poutre; Type de structure: Basique; ID de Parent: Poutre-010; Matériaux de construction (Tous): Parpaing 2676271321; Surfaces (Toutes): Bois-Pin; Angle d'inclinaison: 0 deg; Nombre de percements: 0; Surface supérieure: Bois-Pin; Surface inférieure: Bois-Pin; Nom de Variante: Modèle principal; Nom de Jeu de Variantes: Modèle principal; Position: Intérieur; Fonction structurelle: Élément porteur; Affichage sur filtre de rénovation: Tous les filtres appropriés; État de rénovation: Existant; État de Variante: Modèle principal; Jeu de Variantes: Modèle principal
AC_Pset_RenovationAndPhasing - Renovation Status: Existing
ArchiCADQuantities - Superficie des deux extrémités de poutre: 0.252 m2; Nombre de trous: 0; Superficie des arêtes des trous: 0 m2; Superficie des trous: 0 m2; Volume des trous: 0 m3; Superficie de la poutre côté gauche (nette): 7.93748 m2; Longueur gauche: 11339.3 mm; Longueur droite: 11339.3 mm; Décalage: 0 mm; Superficie de la poutre côté droit (nette): 7.93748 m2; Superficie: 2.04107 m2; Hauteur: 700 mm; Volume (net): 1.42875 m3; Largeur: 180 mm; Altitude à Zéro du Projet: 17600 mm; Altitude de Référence Niveau 1: 17600 mm; Altitude de Référence Niveau 2: 17600 mm; Altitude à niveau de la mer: 17600 mm; Altitude à étage lié/étage d'implantation: 3000 mm; Décalage étage d'implantation: 3000 mm; Superficie en plan: 20.2091 m2; Longueur 3D: 11339.3 mm; Volume (conditionnel): 1.42875 m3; Volume (brut): 1.42875 m3; Altitude supérieure à premier niveau de référence: 17600 mm; Altitude supérieure à étage d'implantation: 3000 mm; Altitude supérieure à Zéro du projet: 17600 mm; Altitude supérieure à niveau de la mer: 17600 mm; Altitude supérieure à deuxième niveau de référence: 17600 mm; Altitude inférieure à premier niveau de référence: 16900 mm; Altitude inférieure à étage d'implantation: 2300 mm; Altitude inférieure à Zéro du projet: 16900 mm; Altitude inférieure à niveau de la mer: 16900 mm; Altitude inférieure à deuxième niveau de référence: 16900 mm; Hauteur coupe transversale haut/fin (perpendiculaire): 700 mm; Hauteur coupe transversale bas/départ (perpendiculaire): 700 mm; Largeur coupe transversale haut/fin (perpendiculaire): 180 mm; Largeur coupe transversale bas/départ (perpendiculaire): 180 mm; Hauteur coupe transversale haut/fin (coupée): 700 mm; Hauteur coupe transversale bas/départ (coupée): 700 mm; Largeur coupe transversale haut/fin (coupée): 180 mm; Largeur coupe transversale bas/départ (coupée): 180 mm; Surface coupe transversale bas/départ (coupée): 0.126 m2; Surface coupe transversale haut/fin: 0.126 m2; Nombre de segments: 1; Superficie supérieure (nette): 2.04107 m2; Superficie inférieure (nette): 2.04107 m2

# IfcBeam: Parpaing 2676271321 180 x 850 (2)
In: sousol
Classification: Poutre (Classification ARCHICAD); Material: Parpaing 2676271321
AC_Pset_RenovationAndPhasing - Renovation Status: Existing
ArchiCADProperties - Coupe transversale de Poutre: Rectangulaire; Surface de fin: Bois-Pin; Surface gauche: Bois-Pin; Surface droite: Bois-Pin; Angle d'inclinaison de Poutre: 0 deg; Génération de modèle analytique structurel: yes; Membre étiré manuellement: no; ID de l'élément: Poutre-012; Lien et ID d'élément: Poutre-012; Calque: 3D; Matériau de construction / Composite / Profil / Hachure: Parpaing 2676271321; Matériau de construction: Parpaing 2676271321; Verrouillé: no; Nom d'étage d'implantation: sousol; Numéro d'étage d'implantation: 2; Type d'élément: Poutre; Type de structure: Basique; ID de Parent: Poutre-012; Matériaux de construction (Tous): Parpaing 2676271321; Surfaces (Toutes): Bois-Pin; Angle d'inclinaison: 0 deg; Nombre de percements: 0; Surface supérieure: Bois-Pin; Surface inférieure: Bois-Pin; Nom de Variante: Modèle principal; Nom de Jeu de Variantes: Modèle principal; Position: Intérieur; Fonction structurelle: Élément porteur; Affichage sur filtre de rénovation: Tous les filtres appropriés; État de rénovation: Existant; État de Variante: Modèle principal; Jeu de Variantes: Modèle principal
ArchiCADQuantities - Superficie des deux extrémités de poutre: 0.306 m2; Nombre de trous: 0; Superficie des arêtes des trous: 0 m2; Superficie des trous: 0 m2; Volume des trous: 0 m3; Superficie de la poutre côté gauche (nette): 4.5543 m2; Longueur gauche: 5358 mm; Longueur droite: 5358 mm; Décalage: 0 mm; Superficie de la poutre côté droit (nette): 4.5543 m2; Superficie: 0.964441 m2; Hauteur: 850 mm; Volume (net): 0.819775 m3; Largeur: 180 mm; Altitude à Zéro du Projet: 2950 mm; Altitude de Référence Niveau 1: 2950 mm; Altitude de Référence Niveau 2: 2950 mm; Altitude à niveau de la mer: 2950 mm; Altitude à étage lié/étage d'implantation: 2950 mm; Décalage étage d'implantation: 2950 mm; Superficie en plan: 11.3435 m2; Longueur 3D: 5358 mm; Volume (conditionnel): 0.819775 m3; Volume (brut): 0.819775 m3; Altitude supérieure à premier niveau de référence: 2950 mm; Altitude supérieure à étage d'implantation: 2950 mm; Altitude supérieure à Zéro du projet: 2950 mm; Altitude supérieure à niveau de la mer: 2950 mm; Altitude supérieure à deuxième niveau de référence: 2950 mm; Altitude inférieure à premier niveau de référence: 2100 mm; Altitude inférieure à étage d'implantation: 2100 mm; Altitude inférieure à Zéro du projet: 2100 mm; Altitude inférieure à niveau de la mer: 2100 mm; Altitude inférieure à deuxième niveau de référence: 2100 mm; Hauteur coupe transversale haut/fin (perpendiculaire): 850 mm; Hauteur coupe transversale bas/départ (perpendiculaire): 850 mm; Largeur coupe transversale haut/fin (perpendiculaire): 180 mm; Largeur coupe transversale bas/départ (perpendiculaire): 180 mm; Hauteur coupe transversale haut/fin (coupée): 850 mm; Hauteur coupe transversale bas/départ (coupée): 850 mm; Largeur coupe transversale haut/fin (coupée): 180 mm; Largeur coupe transversale bas/départ (coupée): 180 mm; Surface coupe transversale bas/départ (coupée): 0.153 m2; Surface coupe transversale haut/fin: 0.153 m2; Nombre de segments: 1; Superficie supérieure (nette): 0.964441 m2; Superficie inférieure (nette): 0.964441 m2

# IfcBeam: Parpaing 2676271321 200 x 200, Poutre-012
In: sousol
Classification: Poutre (Classification ARCHICAD); Material: Parpaing 2676271321
AC_Pset_RenovationAndPhasing - Renovation Status: Existing
ArchiCADProperties - Coupe transversale de Poutre: Rectangulaire; Surface de fin: Bois-Pin; Surface gauche: Bois-Pin; Surface droite: Bois-Pin; Angle d'inclinaison de Poutre: 0 deg; Génération de modèle analytique structurel: yes; Membre étiré manuellement: no; ID de l'élément: Poutre-012; Lien et ID d'élément: Poutre-012; Calque: 3D; Matériau de construction / Composite / Profil / Hachure: Parpaing 2676271321; Matériau de construction: Parpaing 2676271321; Verrouillé: no; Nom d'étage d'implantation: sousol; Numéro d'étage d'implantation: 2; Type d'élément: Poutre; Type de structure: Basique; ID de Parent: Poutre-012; Matériaux de construction (Tous): Parpaing 2676271321; Surfaces (Toutes): Bois-Pin; Angle d'inclinaison: 0 deg; Nombre de percements: 0; Surface supérieure: Bois-Pin; Surface inférieure: Bois-Pin; Nom de Variante: Modèle principal; Nom de Jeu de Variantes: Modèle principal; Position: Intérieur; Fonction structurelle: Élément porteur; Affichage sur filtre de rénovation: Tous les filtres appropriés; État de rénovation: Existant; État de Variante: Modèle principal; Jeu de Variantes: Modèle principal
ArchiCADQuantities - Superficie des deux extrémités de poutre: 0.08 m2; Nombre de trous: 0; Superficie des arêtes des trous: 0 m2; Superficie des trous: 0 m2; Volume des trous: 0 m3; Superficie de la poutre côté gauche (nette): 0.756236 m2; Longueur gauche: 3781.18 mm; Longueur droite: 3781.18 mm; Décalage: 0 mm; Superficie de la poutre côté droit (nette): 0.756236 m2; Superficie: 0.756236 m2; Hauteur: 200 mm; Volume (net): 0.151247 m3; Largeur: 200 mm; Altitude à Zéro du Projet: 2950 mm; Altitude de Référence Niveau 1: 2950 mm; Altitude de Référence Niveau 2: 2950 mm; Altitude à niveau de la mer: 2950 mm; Altitude à étage lié/étage d'implantation: 2950 mm; Décalage étage d'implantation: 2950 mm; Superficie en plan: 3.10494 m2; Longueur 3D: 3781.18 mm; Volume (conditionnel): 0.151247 m3; Volume (brut): 0.151247 m3; Altitude supérieure à premier niveau de référence: 2950 mm; Altitude supérieure à étage d'implantation: 2950 mm; Altitude supérieure à Zéro du projet: 2950 mm; Altitude supérieure à niveau de la mer: 2950 mm; Altitude supérieure à deuxième niveau de référence: 2950 mm; Altitude inférieure à premier niveau de référence: 2750 mm; Altitude inférieure à étage d'implantation: 2750 mm; Altitude inférieure à Zéro du projet: 2750 mm; Altitude inférieure à niveau de la mer: 2750 mm; Altitude inférieure à deuxième niveau de référence: 2750 mm; Hauteur coupe transversale haut/fin (perpendiculaire): 200 mm; Hauteur coupe transversale bas/départ (perpendiculaire): 200 mm; Largeur coupe transversale haut/fin (perpendiculaire): 200 mm; Largeur coupe transversale bas/départ (perpendiculaire): 200 mm; Hauteur coupe transversale haut/fin (coupée): 200 mm; Hauteur coupe transversale bas/départ (coupée): 200 mm; Largeur coupe transversale haut/fin (coupée): 200 mm; Largeur coupe transversale bas/départ (coupée): 200 mm; Surface coupe transversale bas/départ (coupée): 0.04 m2; Surface coupe transversale haut/fin: 0.04 m2; Nombre de segments: 1; Superficie supérieure (nette): 0.756236 m2; Superficie inférieure (nette): 0.756236 m2

# IfcBeam: Parpaing 2676271321 200 x 500 (4)
In: sousol
Classification: Poutre (Classification ARCHICAD); Material: Parpaing 2676271321
ArchiCADProperties - Coupe transversale de Poutre: Rectangulaire; Surface de fin: Bois-Pin; Surface gauche: Bois-Pin; Surface droite: Bois-Pin; Angle d'inclinaison de Poutre: 0 deg; Génération de modèle analytique structurel: yes; Membre étiré manuellement: no; ID de l'élément: Poutre-012; Lien et ID d'élément: Poutre-012; Calque: 3D; Matériau de construction / Composite / Profil / Hachure: Parpaing 2676271321; Matériau de construction: Parpaing 2676271321; Verrouillé: no; Nom d'étage d'implantation: sousol; Numéro d'étage d'implantation: 2; Type d'élément: Poutre; Type de structure: Basique; ID de Parent: Poutre-012; Matériaux de construction (Tous): Parpaing 2676271321; Surfaces (Toutes): Bois-Pin; Angle d'inclinaison: 0 deg; Nombre de percements: 0; Surface supérieure: Bois-Pin; Surface inférieure: Bois-Pin; Nom de Variante: Modèle principal; Nom de Jeu de Variantes: Modèle principal; Position: Intérieur; Fonction structurelle: Élément porteur; Affichage sur filtre de rénovation: Tous les filtres appropriés; État de rénovation: Existant; État de Variante: Modèle principal; Jeu de Variantes: Modèle principal
AC_Pset_RenovationAndPhasing - Renovation Status: Existing
ArchiCADQuantities - Superficie des deux extrémités de poutre: 0.2 m2; Nombre de trous: 0; Superficie des arêtes des trous: 0 m2; Superficie des trous: 0 m2; Volume des trous: 0 m3; Décalage: 0 mm; Hauteur: 500 mm; Largeur: 200 mm; Hauteur coupe transversale haut/fin (perpendiculaire): 500 mm; Hauteur coupe transversale bas/départ (perpendiculaire): 500 mm; Largeur coupe transversale haut/fin (perpendiculaire): 200 mm; Largeur coupe transversale bas/départ (perpendiculaire): 200 mm; Hauteur coupe transversale haut/fin (coupée): 500 mm; Hauteur coupe transversale bas/départ (coupée): 500 mm; Largeur coupe transversale haut/fin (coupée): 200 mm; Largeur coupe transversale bas/départ (coupée): 200 mm; Surface coupe transversale bas/départ (coupée): 0.1 m2; Surface coupe transversale haut/fin: 0.1 m2; Nombre de segments: 1
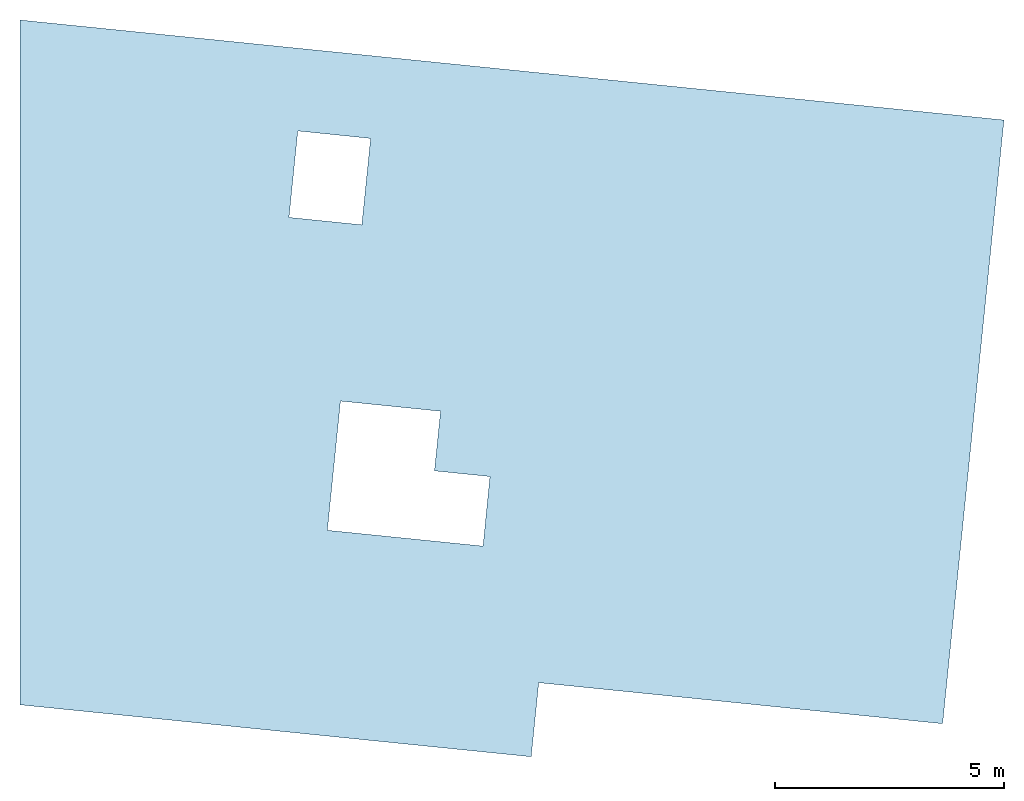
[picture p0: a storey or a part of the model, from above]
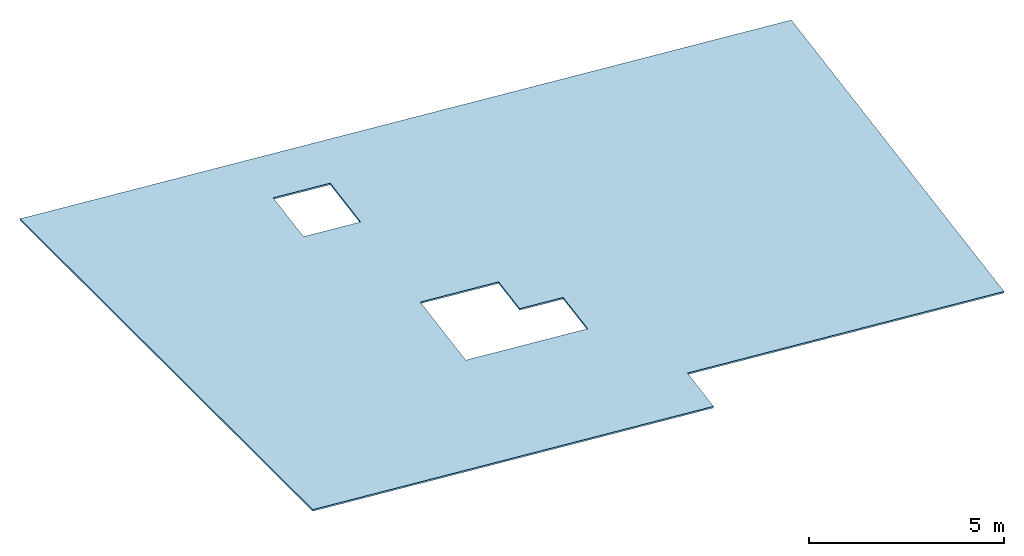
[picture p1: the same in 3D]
Properties of the parts of a building model (IFC2X3), part 3 of 44

# IfcBeam: Parpaing 2676271321 200 x 500 (4)
Name | Superficie de la poutre côté gauche (nette) (m2) = Superficie de la poutre côté droit (nette) (m2) | Longueur gauche (mm) = Longueur droite (mm) = Longueur 3D (mm) | Superficie (m2) = Superficie supérieure (nette) (m2) = Superficie inférieure (nette) (m2) | Volume (net) (m3) = Volume (conditionnel) (m3) = Volume (brut) (m3) | Altitude à Zéro du Projet (mm) = Altitude de Référence Niveau 1 (mm) = Altitude de Référence Niveau 2 (mm) = Altitude à niveau de la mer (mm) = Altitude à étage lié/étage d'implantation (mm) = Décalage étage d'implantation (mm) = Altitude supérieure à premier niveau de référence (mm) = Altitude supérieure à étage d'implantation (mm) = Altitude supérieure à Zéro du projet (mm) = Altitude supérieure à niveau de la mer (mm) = Altitude supérieure à deuxième niveau de référence (mm) | Superficie en plan (m2) | Altitude inférieure à premier niveau de référence (mm) = Altitude inférieure à étage d'implantation (mm) = Altitude inférieure à Zéro du projet (mm) = Altitude inférieure à niveau de la mer (mm) = Altitude inférieure à deuxième niveau de référence (mm)
Poutre-012 | 2.875 | 5750 | 1.15 | 0.575 | 2950 | 8.25 | 2450
2 x Poutre-012 | 4.30023 | 8600.46 | 1.72009 | 0.860046 | 2500 | 12.2406 | 2000
Poutre-012 | 3.99002 | 7980.04 | 1.59601 | 0.798004 | 2500 | 11.3721 | 2000

# IfcBeam: Parpaing 2676271321 200 x 600, Poutre-012
In: sousol
Classification: Poutre (Classification ARCHICAD); Material: Parpaing 2676271321
ArchiCADQuantities - Superficie des deux extrémités de poutre: 0.388328 m2; Nombre de trous: 0; Superficie des arêtes des trous: 0 m2; Superficie des trous: 0 m2; Volume des trous: 0 m3; Superficie de la poutre côté gauche (nette): 0.917968 m2; Longueur gauche: 1529.95 mm; Longueur droite: 1929.95 mm; Décalage: 0 mm; Superficie de la poutre côté droit (nette): 1.15797 m2; Superficie: 0.345989 m2; Hauteur: 600 mm; Volume (net): 0.207594 m3; Largeur: 200 mm; Altitude à Zéro du Projet: 2950 mm; Altitude de Référence Niveau 1: 2950 mm; Altitude de Référence Niveau 2: 2950 mm; Altitude à niveau de la mer: 2950 mm; Altitude à étage lié/étage d'implantation: 2950 mm; Décalage étage d'implantation: 2950 mm; Superficie en plan: 3.15624 m2; Longueur 3D: 1929.95 mm; Volume (conditionnel): 0.207594 m3; Volume (brut): 0.207594 m3; Altitude supérieure à premier niveau de référence: 2950 mm; Altitude supérieure à étage d'implantation: 2950 mm; Altitude supérieure à Zéro du projet: 2950 mm; Altitude supérieure à niveau de la mer: 2950 mm; Altitude supérieure à deuxième niveau de référence: 2950 mm; Altitude inférieure à premier niveau de référence: 2350 mm; Altitude inférieure à étage d'implantation: 2350 mm; Altitude inférieure à Zéro du projet: 2350 mm; Altitude inférieure à niveau de la mer: 2350 mm; Altitude inférieure à deuxième niveau de référence: 2350 mm; Hauteur coupe transversale haut/fin (perpendiculaire): 600 mm; Hauteur coupe transversale bas/départ (perpendiculaire): 600 mm; Largeur coupe transversale haut/fin (perpendiculaire): 200 mm; Largeur coupe transversale bas/départ (perpendiculaire): 200 mm; Hauteur coupe transversale haut/fin (coupée): 600 mm; Hauteur coupe transversale bas/départ (coupée): 600 mm; Largeur coupe transversale haut/fin (coupée): 200 mm; Largeur coupe transversale bas/départ (coupée): 200 mm; Surface coupe transversale bas/départ (coupée): 0.12 m2; Surface coupe transversale haut/fin: 0.268328 m2; Nombre de segments: 1; Superficie supérieure (nette): 0.345989 m2; Superficie inférieure (nette): 0.345989 m2
AC_Pset_RenovationAndPhasing - Renovation Status: Existing
ArchiCADProperties - Coupe transversale de Poutre: Rectangulaire; Surface de fin: Bois-Pin; Surface gauche: Bois-Pin; Surface droite: Bois-Pin; Angle d'inclinaison de Poutre: 0 deg; Génération de modèle analytique structurel: yes; Membre étiré manuellement: no; ID de l'élément: Poutre-012; Lien et ID d'élément: Poutre-012; Calque: 3D; Matériau de construction / Composite / Profil / Hachure: Parpaing 2676271321; Matériau de construction: Parpaing 2676271321; Verrouillé: no; Nom d'étage d'implantation: sousol; Numéro d'étage d'implantation: 2; Type d'élément: Poutre; Type de structure: Basique; ID de Parent: Poutre-012; Matériaux de construction (Tous): Parpaing 2676271321; Surfaces (Toutes): Bois-Pin; Angle d'inclinaison: 0 deg; Nombre de percements: 0; Surface supérieure: Bois-Pin; Surface inférieure: Bois-Pin; Nom de Variante: Modèle principal; Nom de Jeu de Variantes: Modèle principal; Position: Intérieur; Fonction structurelle: Élément porteur; Affichage sur filtre de rénovation: Tous les filtres appropriés; État de rénovation: Existant; État de Variante: Modèle principal; Jeu de Variantes: Modèle principal

# IfcBeam: Parpaing 2676271321 250 x 1000, Poutre-012
In: sousol
Classification: Poutre (Classification ARCHICAD); Material: Parpaing 2676271321
ArchiCADQuantities - Superficie des deux extrémités de poutre: 0.5 m2; Nombre de trous: 0; Superficie des arêtes des trous: 0 m2; Superficie des trous: 0 m2; Volume des trous: 0 m3; Superficie de la poutre côté gauche (nette): 8.81351 m2; Longueur gauche: 8813.51 mm; Longueur droite: 8813.51 mm; Décalage: 0 mm; Superficie de la poutre côté droit (nette): 8.81351 m2; Superficie: 2.20338 m2; Hauteur: 1000 mm; Volume (net): 2.20338 m3; Largeur: 250 mm; Altitude à Zéro du Projet: 2950 mm; Altitude de Référence Niveau 1: 2950 mm; Altitude de Référence Niveau 2: 2950 mm; Altitude à niveau de la mer: 2950 mm; Altitude à étage lié/étage d'implantation: 2950 mm; Décalage étage d'implantation: 2950 mm; Superficie en plan: 22.5338 m2; Longueur 3D: 8813.51 mm; Volume (conditionnel): 2.20338 m3; Volume (brut): 2.20338 m3; Altitude supérieure à premier niveau de référence: 2950 mm; Altitude supérieure à étage d'implantation: 2950 mm; Altitude supérieure à Zéro du projet: 2950 mm; Altitude supérieure à niveau de la mer: 2950 mm; Altitude supérieure à deuxième niveau de référence: 2950 mm; Altitude inférieure à premier niveau de référence: 1950 mm; Altitude inférieure à étage d'implantation: 1950 mm; Altitude inférieure à Zéro du projet: 1950 mm; Altitude inférieure à niveau de la mer: 1950 mm; Altitude inférieure à deuxième niveau de référence: 1950 mm; Hauteur coupe transversale haut/fin (perpendiculaire): 1000 mm; Hauteur coupe transversale bas/départ (perpendiculaire): 1000 mm; Largeur coupe transversale haut/fin (perpendiculaire): 250 mm; Largeur coupe transversale bas/départ (perpendiculaire): 250 mm; Hauteur coupe transversale haut/fin (coupée): 1000 mm; Hauteur coupe transversale bas/départ (coupée): 1000 mm; Largeur coupe transversale haut/fin (coupée): 250 mm; Largeur coupe transversale bas/départ (coupée): 250 mm; Surface coupe transversale bas/départ (coupée): 0.25 m2; Surface coupe transversale haut/fin: 0.25 m2; Nombre de segments: 1; Superficie supérieure (nette): 2.20338 m2; Superficie inférieure (nette): 2.20338 m2
AC_Pset_RenovationAndPhasing - Renovation Status: Existing
ArchiCADProperties - Coupe transversale de Poutre: Rectangulaire; Surface de fin: Bois-Pin; Surface gauche: Bois-Pin; Surface droite: Bois-Pin; Angle d'inclinaison de Poutre: 0 deg; Génération de modèle analytique structurel: yes; Membre étiré manuellement: no; ID de l'élément: Poutre-012; Lien et ID d'élément: Poutre-012; Calque: 3D; Matériau de construction / Composite / Profil / Hachure: Parpaing 2676271321; Matériau de construction: Parpaing 2676271321; Verrouillé: no; Nom d'étage d'implantation: sousol; Numéro d'étage d'implantation: 2; Type d'élément: Poutre; Type de structure: Basique; ID de Parent: Poutre-012; Matériaux de construction (Tous): Parpaing 2676271321; Surfaces (Toutes): Bois-Pin; Angle d'inclinaison: 0 deg; Nombre de percements: 0; Surface supérieure: Bois-Pin; Surface inférieure: Bois-Pin; Nom de Variante: Modèle principal; Nom de Jeu de Variantes: Modèle principal; Position: Intérieur; Fonction structurelle: Élément porteur; Affichage sur filtre de rénovation: Tous les filtres appropriés; État de rénovation: Existant; État de Variante: Modèle principal; Jeu de Variantes: Modèle principal

# IfcBeam: Parpaing 2676271321 250 x 400, Poutre-012
In: sousol
Classification: Poutre (Classification ARCHICAD); Material: Parpaing 2676271321
ArchiCADProperties - Coupe transversale de Poutre: Rectangulaire; Surface de fin: Bois-Pin; Surface gauche: Bois-Pin; Surface droite: Bois-Pin; Angle d'inclinaison de Poutre: 0 deg; Génération de modèle analytique structurel: yes; Membre étiré manuellement: no; ID de l'élément: Poutre-012; Lien et ID d'élément: Poutre-012; Calque: 3D; Matériau de construction / Composite / Profil / Hachure: Parpaing 2676271321; Matériau de construction: Parpaing 2676271321; Verrouillé: no; Nom d'étage d'implantation: sousol; Numéro d'étage d'implantation: 2; Type d'élément: Poutre; Type de structure: Basique; ID de Parent: Poutre-012; Matériaux de construction (Tous): Parpaing 2676271321; Surfaces (Toutes): Bois-Pin; Angle d'inclinaison: 0 deg; Nombre de percements: 0; Surface supérieure: Bois-Pin; Surface inférieure: Bois-Pin; Nom de Variante: Modèle principal; Nom de Jeu de Variantes: Modèle principal; Position: Intérieur; Fonction structurelle: Élément porteur; Affichage sur filtre de rénovation: Tous les filtres appropriés; État de rénovation: Existant; État de Variante: Modèle principal; Jeu de Variantes: Modèle principal
ArchiCADQuantities - Superficie des deux extrémités de poutre: 0.2 m2; Nombre de trous: 0; Superficie des arêtes des trous: 0 m2; Superficie des trous: 0 m2; Volume des trous: 0 m3; Superficie de la poutre côté gauche (nette): 1.22799 m2; Longueur gauche: 3069.98 mm; Longueur droite: 3069.98 mm; Décalage: 0 mm; Superficie de la poutre côté droit (nette): 1.22799 m2; Superficie: 0.767494 m2; Hauteur: 400 mm; Volume (net): 0.306998 m3; Largeur: 250 mm; Altitude à Zéro du Projet: 2950 mm; Altitude de Référence Niveau 1: 2950 mm; Altitude de Référence Niveau 2: 2950 mm; Altitude à niveau de la mer: 2950 mm; Altitude à étage lié/étage d'implantation: 2950 mm; Décalage étage d'implantation: 2950 mm; Superficie en plan: 4.19097 m2; Longueur 3D: 3069.98 mm; Volume (conditionnel): 0.306998 m3; Volume (brut): 0.306998 m3; Altitude supérieure à premier niveau de référence: 2950 mm; Altitude supérieure à étage d'implantation: 2950 mm; Altitude supérieure à Zéro du projet: 2950 mm; Altitude supérieure à niveau de la mer: 2950 mm; Altitude supérieure à deuxième niveau de référence: 2950 mm; Altitude inférieure à premier niveau de référence: 2550 mm; Altitude inférieure à étage d'implantation: 2550 mm; Altitude inférieure à Zéro du projet: 2550 mm; Altitude inférieure à niveau de la mer: 2550 mm; Altitude inférieure à deuxième niveau de référence: 2550 mm; Hauteur coupe transversale haut/fin (perpendiculaire): 400 mm; Hauteur coupe transversale bas/départ (perpendiculaire): 400 mm; Largeur coupe transversale haut/fin (perpendiculaire): 250 mm; Largeur coupe transversale bas/départ (perpendiculaire): 250 mm; Hauteur coupe transversale haut/fin (coupée): 400 mm; Hauteur coupe transversale bas/départ (coupée): 400 mm; Largeur coupe transversale haut/fin (coupée): 250 mm; Largeur coupe transversale bas/départ (coupée): 250 mm; Surface coupe transversale bas/départ (coupée): 0.1 m2; Surface coupe transversale haut/fin: 0.1 m2; Nombre de segments: 1; Superficie supérieure (nette): 0.767494 m2; Superficie inférieure (nette): 0.767494 m2
AC_Pset_RenovationAndPhasing - Renovation Status: Existing

# IfcBeam: Parpaing 2676271321 250 x 500, Poutre-012
In: sousol
Classification: Poutre (Classification ARCHICAD); Material: Parpaing 2676271321
ArchiCADProperties - Coupe transversale de Poutre: Rectangulaire; Surface de fin: Bois-Pin; Surface gauche: Bois-Pin; Surface droite: Bois-Pin; Angle d'inclinaison de Poutre: 0 deg; Génération de modèle analytique structurel: yes; Membre étiré manuellement: no; ID de l'élément: Poutre-012; Lien et ID d'élément: Poutre-012; Calque: 3D; Matériau de construction / Composite / Profil / Hachure: Parpaing 2676271321; Matériau de construction: Parpaing 2676271321; Verrouillé: no; Nom d'étage d'implantation: sousol; Numéro d'étage d'implantation: 2; Type d'élément: Poutre; Type de structure: Basique; ID de Parent: Poutre-012; Matériaux de construction (Tous): Parpaing 2676271321; Surfaces (Toutes): Bois-Pin; Angle d'inclinaison: 0 deg; Nombre de percements: 0; Surface supérieure: Bois-Pin; Surface inférieure: Bois-Pin; Nom de Variante: Modèle principal; Nom de Jeu de Variantes: Modèle principal; Position: Intérieur; Fonction structurelle: Élément porteur; Affichage sur filtre de rénovation: Tous les filtres appropriés; État de rénovation: Existant; État de Variante: Modèle principal; Jeu de Variantes: Modèle principal
ArchiCADQuantities - Superficie des deux extrémités de poutre: 0.261181 m2; Nombre de trous: 0; Superficie des arêtes des trous: 0 m2; Superficie des trous: 0 m2; Volume des trous: 0 m3; Superficie de la poutre côté gauche (nette): 2.94817 m2; Longueur gauche: 5896.33 mm; Longueur droite: 5896.33 mm; Décalage: 0 mm; Superficie de la poutre côté droit (nette): 2.94817 m2; Superficie: 1.47408 m2; Hauteur: 500 mm; Volume (net): 0.737042 m3; Largeur: 250 mm; Altitude à Zéro du Projet: 2950 mm; Altitude de Référence Niveau 1: 2950 mm; Altitude de Référence Niveau 2: 2950 mm; Altitude à niveau de la mer: 2950 mm; Altitude à étage lié/étage d'implantation: 2950 mm; Décalage étage d'implantation: 2950 mm; Superficie en plan: 9.10568 m2; Longueur 3D: 5971.94 mm; Volume (conditionnel): 0.737042 m3; Volume (brut): 0.737042 m3; Altitude supérieure à premier niveau de référence: 2950 mm; Altitude supérieure à étage d'implantation: 2950 mm; Altitude supérieure à Zéro du projet: 2950 mm; Altitude supérieure à niveau de la mer: 2950 mm; Altitude supérieure à deuxième niveau de référence: 2950 mm; Altitude inférieure à premier niveau de référence: 2450 mm; Altitude inférieure à étage d'implantation: 2450 mm; Altitude inférieure à Zéro du projet: 2450 mm; Altitude inférieure à niveau de la mer: 2450 mm; Altitude inférieure à deuxième niveau de référence: 2450 mm; Hauteur coupe transversale haut/fin (perpendiculaire): 500 mm; Hauteur coupe transversale bas/départ (perpendiculaire): 500 mm; Largeur coupe transversale haut/fin (perpendiculaire): 250 mm; Largeur coupe transversale bas/départ (perpendiculaire): 250 mm; Hauteur coupe transversale haut/fin (coupée): 500 mm; Hauteur coupe transversale bas/départ (coupée): 500 mm; Largeur coupe transversale haut/fin (coupée): 250 mm; Largeur coupe transversale bas/départ (coupée): 250 mm; Surface coupe transversale bas/départ (coupée): 0.130591 m2; Surface coupe transversale haut/fin: 0.130591 m2; Nombre de segments: 1; Superficie supérieure (nette): 1.47408 m2; Superficie inférieure (nette): 1.47408 m2
AC_Pset_RenovationAndPhasing - Renovation Status: Existing

# IfcBeam: Parpaing 2676271321 300 x 600 (3)
In: sousol
Classification: Poutre (Classification ARCHICAD); Material: Parpaing 2676271321
AC_Pset_RenovationAndPhasing - Renovation Status: Existing
ArchiCADProperties - Coupe transversale de Poutre: Rectangulaire; Surface de fin: Bois-Pin; Surface gauche: Bois-Pin; Surface droite: Bois-Pin; Angle d'inclinaison de Poutre: 0 deg; Génération de modèle analytique structurel: yes; Membre étiré manuellement: no; ID de l'élément: Poutre-012; Lien et ID d'élément: Poutre-012; Calque: 3D; Matériau de construction / Composite / Profil / Hachure: Parpaing 2676271321; Matériau de construction: Parpaing 2676271321; Verrouillé: no; Nom d'étage d'implantation: sousol; Numéro d'étage d'implantation: 2; Type d'élément: Poutre; Type de structure: Basique; ID de Parent: Poutre-012; Matériaux de construction (Tous): Parpaing 2676271321; Surfaces (Toutes): Bois-Pin; Angle d'inclinaison: 0 deg; Nombre de percements: 0; Surface supérieure: Bois-Pin; Surface inférieure: Bois-Pin; Nom de Variante: Modèle principal; Nom de Jeu de Variantes: Modèle principal; Position: Intérieur; Fonction structurelle: Élément porteur; Affichage sur filtre de rénovation: Tous les filtres appropriés; État de rénovation: Existant; État de Variante: Modèle principal; Jeu de Variantes: Modèle principal
ArchiCADQuantities - Nombre de trous: 0; Superficie des arêtes des trous: 0 m2; Superficie des trous: 0 m2; Volume des trous: 0 m3; Décalage: 0 mm; Hauteur: 600 mm; Largeur: 300 mm; Altitude à Zéro du Projet: 2950 mm; Altitude de Référence Niveau 1: 2950 mm; Altitude de Référence Niveau 2: 2950 mm; Altitude à niveau de la mer: 2950 mm; Altitude à étage lié/étage d'implantation: 2950 mm; Décalage étage d'implantation: 2950 mm; Altitude supérieure à premier niveau de référence: 2950 mm; Altitude supérieure à étage d'implantation: 2950 mm; Altitude supérieure à Zéro du projet: 2950 mm; Altitude supérieure à niveau de la mer: 2950 mm; Altitude supérieure à deuxième niveau de référence: 2950 mm; Altitude inférieure à premier niveau de référence: 2350 mm; Altitude inférieure à étage d'implantation: 2350 mm; Altitude inférieure à Zéro du projet: 2350 mm; Altitude inférieure à niveau de la mer: 2350 mm; Altitude inférieure à deuxième niveau de référence: 2350 mm; Hauteur coupe transversale haut/fin (perpendiculaire): 600 mm; Hauteur coupe transversale bas/départ (perpendiculaire): 600 mm; Largeur coupe transversale haut/fin (perpendiculaire): 300 mm; Largeur coupe transversale bas/départ (perpendiculaire): 300 mm; Hauteur coupe transversale haut/fin (coupée): 600 mm; Hauteur coupe transversale bas/départ (coupée): 600 mm; Largeur coupe transversale haut/fin (coupée): 300 mm; Largeur coupe transversale bas/départ (coupée): 300 mm; Surface coupe transversale haut/fin: 0.18 m2; Nombre de segments: 1
Name | Superficie des deux extrémités de poutre (m2) | Superficie de la poutre côté gauche (nette) (m2) | Longueur gauche (mm) | Longueur droite (mm) = Longueur 3D (mm) | Superficie de la poutre côté droit (nette) (m2) | Superficie (m2) = Superficie supérieure (nette) (m2) = Superficie inférieure (nette) (m2) | Volume (net) (m3) = Volume (conditionnel) (m3) = Volume (brut) (m3) | Superficie en plan (m2) | Surface coupe transversale bas/départ (coupée) (m2)
Poutre-012 | 0.582492 | 1.5779 | 2629.83 | 3229.83 | 1.9379 | 0.878949 | 0.527369 | 5.85618 | 0.402492
Poutre-012 | 0.36 | 1.7039 | 2839.83 | 2839.83 | 1.7039 | 0.851949 | 0.511169 | 5.47169 | 0.18
Poutre-012 | 0.36 | 1.75182 | 2919.7 | 2919.7 | 1.75182 | 0.875909 | 0.525546 | 5.61546 | 0.18 | ArchiCADProperties - Zones conflictuelles: Pl; Nom de zone liée: Pl; Numéro de zone liée: 818

# IfcBeam: Parpaing 2676271321 300 x 690, Poutre-012
In: sousol
Classification: Poutre (Classification ARCHICAD); Material: Parpaing 2676271321
ArchiCADProperties - Coupe transversale de Poutre: Rectangulaire; Surface de fin: Bois-Pin; Surface gauche: Bois-Pin; Surface droite: Bois-Pin; Angle d'inclinaison de Poutre: 0 deg; Génération de modèle analytique structurel: yes; Membre étiré manuellement: no; ID de l'élément: Poutre-012; Lien et ID d'élément: Poutre-012; Calque: 3D; Matériau de construction / Composite / Profil / Hachure: Parpaing 2676271321; Matériau de construction: Parpaing 2676271321; Verrouillé: no; Nom d'étage d'implantation: sousol; Numéro d'étage d'implantation: 2; Type d'élément: Poutre; Type de structure: Basique; ID de Parent: Poutre-012; Matériaux de construction (Tous): Parpaing 2676271321; Surfaces (Toutes): Bois-Pin; Angle d'inclinaison: 0 deg; Nombre de percements: 0; Surface supérieure: Bois-Pin; Surface inférieure: Bois-Pin; Nom de Variante: Modèle principal; Nom de Jeu de Variantes: Modèle principal; Position: Intérieur; Fonction structurelle: Élément porteur; Affichage sur filtre de rénovation: Tous les filtres appropriés; État de rénovation: Existant; État de Variante: Modèle principal; Jeu de Variantes: Modèle principal
AC_Pset_RenovationAndPhasing - Renovation Status: Existing
ArchiCADQuantities - Superficie des deux extrémités de poutre: 0.414 m2; Nombre de trous: 0; Superficie des arêtes des trous: 0 m2; Superficie des trous: 0 m2; Volume des trous: 0 m3; Superficie de la poutre côté gauche (nette): 6.78167 m2; Longueur gauche: 10228.5 mm; Longueur droite: 10228.5 mm; Décalage: 0 mm; Superficie de la poutre côté droit (nette): 6.78167 m2; Superficie: 2.94855 m2; Hauteur: 690 mm; Volume (net): 2.0345 m3; Largeur: 300 mm; Altitude à Zéro du Projet: 2950 mm; Altitude de Référence Niveau 1: 2950 mm; Altitude de Référence Niveau 2: 2950 mm; Altitude à niveau de la mer: 2950 mm; Altitude à étage lié/étage d'implantation: 2950 mm; Décalage étage d'implantation: 2950 mm; Superficie en plan: 20.7024 m2; Longueur 3D: 9828.51 mm; Volume (conditionnel): 2.0345 m3; Volume (brut): 2.1173 m3; Altitude supérieure à premier niveau de référence: 2950 mm; Altitude supérieure à étage d'implantation: 2950 mm; Altitude supérieure à Zéro du projet: 2950 mm; Altitude supérieure à niveau de la mer: 2950 mm; Altitude supérieure à deuxième niveau de référence: 2950 mm; Altitude inférieure à premier niveau de référence: 2260 mm; Altitude inférieure à étage d'implantation: 2260 mm; Altitude inférieure à Zéro du projet: 2260 mm; Altitude inférieure à niveau de la mer: 2260 mm; Altitude inférieure à deuxième niveau de référence: 2260 mm; Hauteur coupe transversale haut/fin (perpendiculaire): 690 mm; Hauteur coupe transversale bas/départ (perpendiculaire): 690 mm; Largeur coupe transversale haut/fin (perpendiculaire): 300 mm; Largeur coupe transversale bas/départ (perpendiculaire): 300 mm; Hauteur coupe transversale haut/fin (coupée): 690 mm; Hauteur coupe transversale bas/départ (coupée): 690 mm; Largeur coupe transversale haut/fin (coupée): 300 mm; Largeur coupe transversale bas/départ (coupée): 300 mm; Surface coupe transversale bas/départ (coupée): 0.207 m2; Surface coupe transversale haut/fin: 0.207 m2; Nombre de segments: 1; Superficie supérieure (nette): 2.94855 m2; Superficie inférieure (nette): 2.94855 m2

# IfcBeam: Parpaing 2676271321 300 x 700 (2)
In: sousol
Classification: Poutre (Classification ARCHICAD); Material: Parpaing 2676271321
ArchiCADQuantities - Superficie des deux extrémités de poutre: 0.21 m2; Nombre de trous: 0; Superficie des arêtes des trous: 0 m2; Superficie des trous: 0 m2; Volume des trous: 0 m3; Superficie de la poutre côté gauche (nette): 1.75826 m2; Décalage: 0 mm; Superficie de la poutre côté droit (nette): 1.75826 m2; Superficie: 0.75354 m2; Hauteur: 700 mm; Volume (net): 0.527478 m3; Largeur: 300 mm; Altitude à Zéro du Projet: 2950 mm; Altitude de Référence Niveau 1: 2950 mm; Altitude de Référence Niveau 2: 2950 mm; Altitude à niveau de la mer: 2950 mm; Altitude à étage lié/étage d'implantation: 2950 mm; Décalage étage d'implantation: 2950 mm; Superficie en plan: 5.4436 m2; Longueur 3D: 2511.8 mm; Volume (conditionnel): 0.527478 m3; Volume (brut): 0.564228 m3; Altitude supérieure à premier niveau de référence: 2950 mm; Altitude supérieure à étage d'implantation: 2950 mm; Altitude supérieure à Zéro du projet: 2950 mm; Altitude supérieure à niveau de la mer: 2950 mm; Altitude supérieure à deuxième niveau de référence: 2950 mm; Altitude inférieure à premier niveau de référence: 2250 mm; Altitude inférieure à étage d'implantation: 2250 mm; Altitude inférieure à Zéro du projet: 2250 mm; Altitude inférieure à niveau de la mer: 2250 mm; Altitude inférieure à deuxième niveau de référence: 2250 mm; Hauteur coupe transversale haut/fin (perpendiculaire): 700 mm; Hauteur coupe transversale bas/départ (perpendiculaire): 700 mm; Largeur coupe transversale haut/fin (perpendiculaire): 300 mm; Largeur coupe transversale bas/départ (perpendiculaire): 300 mm; Hauteur coupe transversale haut/fin (coupée): 700 mm; Hauteur coupe transversale bas/départ (coupée): 700 mm; Largeur coupe transversale haut/fin (coupée): 300 mm; Largeur coupe transversale bas/départ (coupée): 300 mm; Surface coupe transversale bas/départ (coupée): 0.21 m2; Surface coupe transversale haut/fin: 0 m2; Nombre de segments: 1; Superficie supérieure (nette): 0.75354 m2; Superficie inférieure (nette): 0.75354 m2
AC_Pset_RenovationAndPhasing - Renovation Status: Existing
ArchiCADProperties - Coupe transversale de Poutre: Rectangulaire; Surface de fin: Bois-Pin; Surface gauche: Bois-Pin; Surface droite: Bois-Pin; Angle d'inclinaison de Poutre: 0 deg; Génération de modèle analytique structurel: yes; Membre étiré manuellement: no; ID de l'élément: Poutre-012; Lien et ID d'élément: Poutre-012; Calque: 3D; Matériau de construction / Composite / Profil / Hachure: Parpaing 2676271321; Matériau de construction: Parpaing 2676271321; Verrouillé: no; Nom d'étage d'implantation: sousol; Numéro d'étage d'implantation: 2; Type d'élément: Poutre; Type de structure: Basique; ID de Parent: Poutre-012; Matériaux de construction (Tous): Parpaing 2676271321; Surfaces (Toutes): Bois-Pin; Angle d'inclinaison: 0 deg; Nombre de percements: 0; Surface supérieure: Bois-Pin; Surface inférieure: Bois-Pin; Nom de Variante: Modèle principal; Nom de Jeu de Variantes: Modèle principal; Position: Intérieur; Fonction structurelle: Élément porteur; Affichage sur filtre de rénovation: Tous les filtres appropriés; État de rénovation: Existant; État de Variante: Modèle principal; Jeu de Variantes: Modèle principal
Name | Longueur gauche (mm) | Longueur droite (mm)
Poutre-012 | 2686.8 | 2686.8
Poutre-012 | 2561.8 | 2811.8

# IfcBeam: Parpaing 2676271321 350 x 700, Poutre-012
In: sousol
Classification: Poutre (Classification ARCHICAD); Material: Parpaing 2676271321
ArchiCADProperties - Coupe transversale de Poutre: Rectangulaire; Surface de fin: Bois-Pin; Surface gauche: Bois-Pin; Surface droite: Bois-Pin; Angle d'inclinaison de Poutre: 0 deg; Génération de modèle analytique structurel: yes; Membre étiré manuellement: no; ID de l'élément: Poutre-012; Lien et ID d'élément: Poutre-012; Calque: 3D; Matériau de construction / Composite / Profil / Hachure: Parpaing 2676271321; Matériau de construction: Parpaing 2676271321; Verrouillé: no; Nom d'étage d'implantation: sousol; Numéro d'étage d'implantation: 2; Type d'élément: Poutre; Type de structure: Basique; ID de Parent: Poutre-012; Matériaux de construction (Tous): Parpaing 2676271321; Surfaces (Toutes): Bois-Pin; Angle d'inclinaison: 0 deg; Nombre de percements: 0; Surface supérieure: Bois-Pin; Surface inférieure: Bois-Pin; Nom de Variante: Modèle principal; Nom de Jeu de Variantes: Modèle principal; Position: Intérieur; Fonction structurelle: Élément porteur; Affichage sur filtre de rénovation: Tous les filtres appropriés; État de rénovation: Existant; État de Variante: Modèle principal; Jeu de Variantes: Modèle principal
AC_Pset_RenovationAndPhasing - Renovation Status: Existing
ArchiCADQuantities - Superficie des deux extrémités de poutre: 0.520501 m2; Nombre de trous: 0; Superficie des arêtes des trous: 0 m2; Superficie des trous: 0 m2; Volume des trous: 0 m3; Superficie de la poutre côté gauche (nette): 12.7394 m2; Longueur gauche: 18199.2 mm; Longueur droite: 18019.2 mm; Décalage: 0 mm; Superficie de la poutre côté droit (nette): 12.6134 m2; Superficie: 6.33821 m2; Hauteur: 700 mm; Volume (net): 4.43675 m3; Largeur: 350 mm; Altitude à Zéro du Projet: 2950 mm; Altitude de Référence Niveau 1: 2950 mm; Altitude de Référence Niveau 2: 2950 mm; Altitude à niveau de la mer: 2950 mm; Altitude à étage lié/étage d'implantation: 2950 mm; Décalage étage d'implantation: 2950 mm; Superficie en plan: 38.5498 m2; Longueur 3D: 18199.2 mm; Volume (conditionnel): 4.43675 m3; Volume (brut): 4.43675 m3; Altitude supérieure à premier niveau de référence: 2950 mm; Altitude supérieure à étage d'implantation: 2950 mm; Altitude supérieure à Zéro du projet: 2950 mm; Altitude supérieure à niveau de la mer: 2950 mm; Altitude supérieure à deuxième niveau de référence: 2950 mm; Altitude inférieure à premier niveau de référence: 2250 mm; Altitude inférieure à étage d'implantation: 2250 mm; Altitude inférieure à Zéro du projet: 2250 mm; Altitude inférieure à niveau de la mer: 2250 mm; Altitude inférieure à deuxième niveau de référence: 2250 mm; Hauteur coupe transversale haut/fin (perpendiculaire): 700 mm; Hauteur coupe transversale bas/départ (perpendiculaire): 700 mm; Largeur coupe transversale haut/fin (perpendiculaire): 350 mm; Largeur coupe transversale bas/départ (perpendiculaire): 350 mm; Hauteur coupe transversale haut/fin (coupée): 700 mm; Hauteur coupe transversale bas/départ (coupée): 700 mm; Largeur coupe transversale haut/fin (coupée): 350 mm; Largeur coupe transversale bas/départ (coupée): 350 mm; Surface coupe transversale bas/départ (coupée): 0.245 m2; Surface coupe transversale haut/fin: 0.275501 m2; Nombre de segments: 1; Superficie supérieure (nette): 6.33821 m2; Superficie inférieure (nette): 6.33821 m2

# IfcBeam: Parpaing 2676271321 400 x 600, Poutre-012
In: sousol
Classification: Poutre (Classification ARCHICAD); Material: Parpaing 2676271321
ArchiCADProperties - Coupe transversale de Poutre: Rectangulaire; Surface de fin: Bois-Pin; Surface gauche: Bois-Pin; Surface droite: Bois-Pin; Angle d'inclinaison de Poutre: 0 deg; Génération de modèle analytique structurel: yes; Membre étiré manuellement: no; ID de l'élément: Poutre-012; Lien et ID d'élément: Poutre-012; Calque: 3D; Matériau de construction / Composite / Profil / Hachure: Parpaing 2676271321; Matériau de construction: Parpaing 2676271321; Verrouillé: no; Nom d'étage d'implantation: sousol; Numéro d'étage d'implantation: 2; Type d'élément: Poutre; Type de structure: Basique; ID de Parent: Poutre-012; Matériaux de construction (Tous): Parpaing 2676271321; Surfaces (Toutes): Bois-Pin; Angle d'inclinaison: 0 deg; Nombre de percements: 0; Surface supérieure: Bois-Pin; Surface inférieure: Bois-Pin; Nom de Variante: Modèle principal; Nom de Jeu de Variantes: Modèle principal; Position: Intérieur; Fonction structurelle: Élément porteur; Affichage sur filtre de rénovation: Tous les filtres appropriés; État de rénovation: Existant; État de Variante: Modèle principal; Jeu de Variantes: Modèle principal
ArchiCADQuantities - Superficie des deux extrémités de poutre: 0.508328 m2; Nombre de trous: 0; Superficie des arêtes des trous: 0 m2; Superficie des trous: 0 m2; Volume des trous: 0 m3; Superficie de la poutre côté gauche (nette): 5.23203 m2; Longueur gauche: 8720.05 mm; Longueur droite: 8520.05 mm; Décalage: 0 mm; Superficie de la poutre côté droit (nette): 5.11203 m2; Superficie: 3.44802 m2; Hauteur: 600 mm; Volume (net): 2.06881 m3; Largeur: 400 mm; Altitude à Zéro du Projet: 2950 mm; Altitude de Référence Niveau 1: 2950 mm; Altitude de Référence Niveau 2: 2950 mm; Altitude à niveau de la mer: 2950 mm; Altitude à étage lié/étage d'implantation: 2950 mm; Décalage étage d'implantation: 2950 mm; Superficie en plan: 17.7484 m2; Longueur 3D: 8720.05 mm; Volume (conditionnel): 2.06881 m3; Volume (brut): 2.06881 m3; Altitude supérieure à premier niveau de référence: 2950 mm; Altitude supérieure à étage d'implantation: 2950 mm; Altitude supérieure à Zéro du projet: 2950 mm; Altitude supérieure à niveau de la mer: 2950 mm; Altitude supérieure à deuxième niveau de référence: 2950 mm; Altitude inférieure à premier niveau de référence: 2350 mm; Altitude inférieure à étage d'implantation: 2350 mm; Altitude inférieure à Zéro du projet: 2350 mm; Altitude inférieure à niveau de la mer: 2350 mm; Altitude inférieure à deuxième niveau de référence: 2350 mm; Hauteur coupe transversale haut/fin (perpendiculaire): 600 mm; Hauteur coupe transversale bas/départ (perpendiculaire): 600 mm; Largeur coupe transversale haut/fin (perpendiculaire): 400 mm; Largeur coupe transversale bas/départ (perpendiculaire): 400 mm; Hauteur coupe transversale haut/fin (coupée): 600 mm; Hauteur coupe transversale bas/départ (coupée): 600 mm; Largeur coupe transversale haut/fin (coupée): 400 mm; Largeur coupe transversale bas/départ (coupée): 400 mm; Surface coupe transversale bas/départ (coupée): 0.24 m2; Surface coupe transversale haut/fin: 0.268328 m2; Nombre de segments: 1; Superficie supérieure (nette): 3.44802 m2; Superficie inférieure (nette): 3.44802 m2
AC_Pset_RenovationAndPhasing - Renovation Status: Existing

# IfcBeam: Parpaing 2676271321 400 x 700 (2)
In: sousol
Classification: Poutre (Classification ARCHICAD); Material: Parpaing 2676271321
ArchiCADQuantities - Nombre de trous: 0; Superficie des arêtes des trous: 0 m2; Superficie des trous: 0 m2; Volume des trous: 0 m3; Décalage: 0 mm; Hauteur: 700 mm; Largeur: 400 mm; Altitude à Zéro du Projet: 2950 mm; Altitude de Référence Niveau 1: 2950 mm; Altitude de Référence Niveau 2: 2950 mm; Altitude à niveau de la mer: 2950 mm; Altitude à étage lié/étage d'implantation: 2950 mm; Décalage étage d'implantation: 2950 mm; Altitude supérieure à premier niveau de référence: 2950 mm; Altitude supérieure à étage d'implantation: 2950 mm; Altitude supérieure à Zéro du projet: 2950 mm; Altitude supérieure à niveau de la mer: 2950 mm; Altitude supérieure à deuxième niveau de référence: 2950 mm; Altitude inférieure à premier niveau de référence: 2250 mm; Altitude inférieure à étage d'implantation: 2250 mm; Altitude inférieure à Zéro du projet: 2250 mm; Altitude inférieure à niveau de la mer: 2250 mm; Altitude inférieure à deuxième niveau de référence: 2250 mm; Hauteur coupe transversale haut/fin (perpendiculaire): 700 mm; Hauteur coupe transversale bas/départ (perpendiculaire): 700 mm; Largeur coupe transversale haut/fin (perpendiculaire): 400 mm; Largeur coupe transversale bas/départ (perpendiculaire): 400 mm; Hauteur coupe transversale haut/fin (coupée): 700 mm; Hauteur coupe transversale bas/départ (coupée): 700 mm; Largeur coupe transversale haut/fin (coupée): 400 mm; Largeur coupe transversale bas/départ (coupée): 400 mm; Surface coupe transversale haut/fin: 0.28 m2; Nombre de segments: 1
ArchiCADProperties - Coupe transversale de Poutre: Rectangulaire; Surface de fin: Bois-Pin; Surface gauche: Bois-Pin; Surface droite: Bois-Pin; Angle d'inclinaison de Poutre: 0 deg; Génération de modèle analytique structurel: yes; Membre étiré manuellement: no; ID de l'élément: Poutre-012; Lien et ID d'élément: Poutre-012; Calque: 3D; Matériau de construction / Composite / Profil / Hachure: Parpaing 2676271321; Matériau de construction: Parpaing 2676271321; Verrouillé: no; Nom d'étage d'implantation: sousol; Numéro d'étage d'implantation: 2; Type d'élément: Poutre; Type de structure: Basique; ID de Parent: Poutre-012; Matériaux de construction (Tous): Parpaing 2676271321; Surfaces (Toutes): Bois-Pin; Angle d'inclinaison: 0 deg; Nombre de percements: 0; Surface supérieure: Bois-Pin; Surface inférieure: Bois-Pin; Nom de Variante: Modèle principal; Nom de Jeu de Variantes: Modèle principal; Position: Intérieur; Fonction structurelle: Élément porteur; Affichage sur filtre de rénovation: Tous les filtres appropriés; État de rénovation: Existant; État de Variante: Modèle principal; Jeu de Variantes: Modèle principal
AC_Pset_RenovationAndPhasing - Renovation Status: Existing
Name | Superficie des deux extrémités de poutre (m2) | Superficie de la poutre côté gauche (nette) (m2) | Longueur gauche (mm) = Longueur 3D (mm) | Longueur droite (mm) | Superficie de la poutre côté droit (nette) (m2) | Superficie (m2) = Superficie supérieure (nette) (m2) = Superficie inférieure (nette) (m2) | Volume (net) (m3) = Volume (conditionnel) (m3) = Volume (brut) (m3) | Superficie en plan (m2) | Surface coupe transversale bas/départ (coupée) (m2)
Poutre-012 | 0.56 | 3.78 | 5400 | 5400 | 3.78 | 2.16 | 1.512 | 12.44 | 0.28
Poutre-012 | 0.587044 | 4.87485 | 6964.07 | 6784.07 | 4.74885 | 2.74963 | 1.92474 | 15.71 | 0.307044

# IfcBeam: Parpaing 2676271321 400 x 850 (2)
In: sousol
Classification: Poutre (Classification ARCHICAD); Material: Parpaing 2676271321
ArchiCADQuantities - Nombre de trous: 0; Superficie des arêtes des trous: 0 m2; Superficie des trous: 0 m2; Volume des trous: 0 m3; Décalage: 0 mm; Hauteur: 850 mm; Largeur: 400 mm; Altitude à Zéro du Projet: 2950 mm; Altitude de Référence Niveau 1: 2950 mm; Altitude de Référence Niveau 2: 2950 mm; Altitude à niveau de la mer: 2950 mm; Altitude à étage lié/étage d'implantation: 2950 mm; Décalage étage d'implantation: 2950 mm; Altitude supérieure à premier niveau de référence: 2950 mm; Altitude supérieure à étage d'implantation: 2950 mm; Altitude supérieure à Zéro du projet: 2950 mm; Altitude supérieure à niveau de la mer: 2950 mm; Altitude supérieure à deuxième niveau de référence: 2950 mm; Altitude inférieure à premier niveau de référence: 2100 mm; Altitude inférieure à étage d'implantation: 2100 mm; Altitude inférieure à Zéro du projet: 2100 mm; Altitude inférieure à niveau de la mer: 2100 mm; Altitude inférieure à deuxième niveau de référence: 2100 mm; Hauteur coupe transversale haut/fin (perpendiculaire): 850 mm; Hauteur coupe transversale bas/départ (perpendiculaire): 850 mm; Largeur coupe transversale haut/fin (perpendiculaire): 400 mm; Largeur coupe transversale bas/départ (perpendiculaire): 400 mm; Hauteur coupe transversale haut/fin (coupée): 850 mm; Hauteur coupe transversale bas/départ (coupée): 850 mm; Largeur coupe transversale haut/fin (coupée): 400 mm; Largeur coupe transversale bas/départ (coupée): 400 mm; Surface coupe transversale bas/départ (coupée): 0.34 m2; Nombre de segments: 1
AC_Pset_RenovationAndPhasing - Renovation Status: Existing
ArchiCADProperties - Coupe transversale de Poutre: Rectangulaire; Surface de fin: Bois-Pin; Surface gauche: Bois-Pin; Surface droite: Bois-Pin; Angle d'inclinaison de Poutre: 0 deg; Génération de modèle analytique structurel: yes; Membre étiré manuellement: no; ID de l'élément: Poutre-012; Lien et ID d'élément: Poutre-012; Calque: 3D; Matériau de construction / Composite / Profil / Hachure: Parpaing 2676271321; Matériau de construction: Parpaing 2676271321; Verrouillé: no; Nom d'étage d'implantation: sousol; Numéro d'étage d'implantation: 2; Type d'élément: Poutre; Type de structure: Basique; ID de Parent: Poutre-012; Matériaux de construction (Tous): Parpaing 2676271321; Surfaces (Toutes): Bois-Pin; Angle d'inclinaison: 0 deg; Nombre de percements: 0; Surface supérieure: Bois-Pin; Surface inférieure: Bois-Pin; Nom de Variante: Modèle principal; Nom de Jeu de Variantes: Modèle principal; Position: Intérieur; Fonction structurelle: Élément porteur; Affichage sur filtre de rénovation: Tous les filtres appropriés; État de rénovation: Existant; État de Variante: Modèle principal; Jeu de Variantes: Modèle principal
Name | Superficie des deux extrémités de poutre (m2) | Superficie de la poutre côté gauche (nette) (m2) | Longueur gauche (mm) | Longueur droite (mm) | Superficie de la poutre côté droit (nette) (m2) | Superficie (m2) = Superficie supérieure (nette) (m2) = Superficie inférieure (nette) (m2) | Volume (net) (m3) = Volume (conditionnel) (m3) | Superficie en plan (m2) | Longueur 3D (mm) | Volume (brut) (m3) | Surface coupe transversale haut/fin (m2)
Poutre-012 | 1.10026 | 15.8244 | 19166.9 | 18366.9 | 15.1444 | 7.28677 | 6.19376 | 48.0026 | 18616.9 | 6.38076 | 0.760263
Poutre-012 | 0.68 | 5.00915 | 5893.12 | 5893.12 | 5.00915 | 2.35725 | 2.00366 | 15.4128 | 5893.12 | 2.00366 | 0.34

# IfcBeam: Parpaing 2676271321 500 x 700, Poutre-012
In: sousol
Classification: Poutre (Classification ARCHICAD); Material: Parpaing 2676271321
AC_Pset_RenovationAndPhasing - Renovation Status: Existing
ArchiCADQuantities - Superficie des deux extrémités de poutre: 0.7 m2; Nombre de trous: 0; Superficie des arêtes des trous: 0 m2; Superficie des trous: 0 m2; Volume des trous: 0 m3; Superficie de la poutre côté gauche (nette): 3.78 m2; Longueur gauche: 5400 mm; Longueur droite: 5400 mm; Décalage: 0 mm; Superficie de la poutre côté droit (nette): 3.78 m2; Superficie: 2.7 m2; Hauteur: 700 mm; Volume (net): 1.89 m3; Largeur: 500 mm; Altitude à Zéro du Projet: 2950 mm; Altitude de Référence Niveau 1: 2950 mm; Altitude de Référence Niveau 2: 2950 mm; Altitude à niveau de la mer: 2950 mm; Altitude à étage lié/étage d'implantation: 2950 mm; Décalage étage d'implantation: 2950 mm; Superficie en plan: 13.66 m2; Longueur 3D: 5400 mm; Volume (conditionnel): 1.89 m3; Volume (brut): 1.89 m3; Altitude supérieure à premier niveau de référence: 2950 mm; Altitude supérieure à étage d'implantation: 2950 mm; Altitude supérieure à Zéro du projet: 2950 mm; Altitude supérieure à niveau de la mer: 2950 mm; Altitude supérieure à deuxième niveau de référence: 2950 mm; Altitude inférieure à premier niveau de référence: 2250 mm; Altitude inférieure à étage d'implantation: 2250 mm; Altitude inférieure à Zéro du projet: 2250 mm; Altitude inférieure à niveau de la mer: 2250 mm; Altitude inférieure à deuxième niveau de référence: 2250 mm; Hauteur coupe transversale haut/fin (perpendiculaire): 700 mm; Hauteur coupe transversale bas/départ (perpendiculaire): 700 mm; Largeur coupe transversale haut/fin (perpendiculaire): 500 mm; Largeur coupe transversale bas/départ (perpendiculaire): 500 mm; Hauteur coupe transversale haut/fin (coupée): 700 mm; Hauteur coupe transversale bas/départ (coupée): 700 mm; Largeur coupe transversale haut/fin (coupée): 500 mm; Largeur coupe transversale bas/départ (coupée): 500 mm; Surface coupe transversale bas/départ (coupée): 0.35 m2; Surface coupe transversale haut/fin: 0.35 m2; Nombre de segments: 1; Superficie supérieure (nette): 2.7 m2; Superficie inférieure (nette): 2.7 m2
ArchiCADProperties - Coupe transversale de Poutre: Rectangulaire; Surface de fin: Bois-Pin; Surface gauche: Bois-Pin; Surface droite: Bois-Pin; Angle d'inclinaison de Poutre: 0 deg; Génération de modèle analytique structurel: yes; Membre étiré manuellement: no; ID de l'élément: Poutre-012; Lien et ID d'élément: Poutre-012; Calque: 3D; Matériau de construction / Composite / Profil / Hachure: Parpaing 2676271321; Matériau de construction: Parpaing 2676271321; Verrouillé: no; Nom d'étage d'implantation: sousol; Numéro d'étage d'implantation: 2; Type d'élément: Poutre; Type de structure: Basique; ID de Parent: Poutre-012; Matériaux de construction (Tous): Parpaing 2676271321; Surfaces (Toutes): Bois-Pin; Angle d'inclinaison: 0 deg; Nombre de percements: 0; Surface supérieure: Bois-Pin; Surface inférieure: Bois-Pin; Nom de Variante: Modèle principal; Nom de Jeu de Variantes: Modèle principal; Position: Intérieur; Fonction structurelle: Élément porteur; Affichage sur filtre de rénovation: Tous les filtres appropriés; État de rénovation: Existant; État de Variante: Modèle principal; Jeu de Variantes: Modèle principal

# IfcBeam: Parpaing 2676271321 500 x 800, Poutre-012
In: sousol
Classification: Poutre (Classification ARCHICAD); Material: Parpaing 2676271321
ArchiCADProperties - Coupe transversale de Poutre: Rectangulaire; Surface de fin: Bois-Pin; Surface gauche: Bois-Pin; Surface droite: Bois-Pin; Angle d'inclinaison de Poutre: 0 deg; Génération de modèle analytique structurel: yes; Membre étiré manuellement: no; ID de l'élément: Poutre-012; Lien et ID d'élément: Poutre-012; Calque: 3D; Matériau de construction / Composite / Profil / Hachure: Parpaing 2676271321; Matériau de construction: Parpaing 2676271321; Verrouillé: no; Nom d'étage d'implantation: sousol; Numéro d'étage d'implantation: 2; Type d'élément: Poutre; Type de structure: Basique; ID de Parent: Poutre-012; Matériaux de construction (Tous): Parpaing 2676271321; Surfaces (Toutes): Bois-Pin; Angle d'inclinaison: 0 deg; Nombre de percements: 0; Surface supérieure: Bois-Pin; Surface inférieure: Bois-Pin; Nom de Variante: Modèle principal; Nom de Jeu de Variantes: Modèle principal; Position: Intérieur; Fonction structurelle: Élément porteur; Affichage sur filtre de rénovation: Tous les filtres appropriés; État de rénovation: Existant; État de Variante: Modèle principal; Jeu de Variantes: Modèle principal
ArchiCADQuantities - Superficie des deux extrémités de poutre: 0.16 m2; Nombre de trous: 0; Superficie des arêtes des trous: 0 m2; Superficie des trous: 0 m2; Volume des trous: 0 m3; Superficie de la poutre côté gauche (nette): 4.08794 m2; Longueur gauche: 5750 mm; Longueur droite: 5750 mm; Décalage: 0 mm; Superficie de la poutre côté droit (nette): 4.6 m2; Superficie: 2.61897 m2; Hauteur: 800 mm; Volume (net): 2.09518 m3; Largeur: 500 mm; Altitude à Zéro du Projet: 2950 mm; Altitude de Référence Niveau 1: 2950 mm; Altitude de Référence Niveau 2: 2950 mm; Altitude à niveau de la mer: 2950 mm; Altitude à étage lié/étage d'implantation: 2950 mm; Décalage étage d'implantation: 2950 mm; Superficie en plan: 15.2379 m2; Longueur 3D: 5750 mm; Volume (conditionnel): 2.09518 m3; Volume (brut): 2.3 m3; Altitude supérieure à premier niveau de référence: 2950 mm; Altitude supérieure à étage d'implantation: 2950 mm; Altitude supérieure à Zéro du projet: 2950 mm; Altitude supérieure à niveau de la mer: 2950 mm; Altitude supérieure à deuxième niveau de référence: 2950 mm; Altitude inférieure à premier niveau de référence: 2150 mm; Altitude inférieure à étage d'implantation: 2150 mm; Altitude inférieure à Zéro du projet: 2150 mm; Altitude inférieure à niveau de la mer: 2150 mm; Altitude inférieure à deuxième niveau de référence: 2150 mm; Hauteur coupe transversale haut/fin (perpendiculaire): 800 mm; Hauteur coupe transversale bas/départ (perpendiculaire): 800 mm; Largeur coupe transversale haut/fin (perpendiculaire): 500 mm; Largeur coupe transversale bas/départ (perpendiculaire): 500 mm; Hauteur coupe transversale haut/fin (coupée): 800 mm; Hauteur coupe transversale bas/départ (coupée): 800 mm; Largeur coupe transversale haut/fin (coupée): 500 mm; Largeur coupe transversale bas/départ (coupée): 500 mm; Surface coupe transversale bas/départ (coupée): 0.08 m2; Surface coupe transversale haut/fin: 0.08 m2; Nombre de segments: 1; Superficie supérieure (nette): 2.61897 m2; Superficie inférieure (nette): 2.61897 m2
AC_Pset_RenovationAndPhasing - Renovation Status: Existing

# IfcBeam: Parpaing 2676271321 600 x 580, Poutre-012
In: sousol
Classification: Poutre (Classification ARCHICAD); Material: Parpaing 2676271321
AC_Pset_RenovationAndPhasing - Renovation Status: Existing
ArchiCADProperties - Coupe transversale de Poutre: Rectangulaire; Surface de fin: Bois-Pin; Surface gauche: Bois-Pin; Surface droite: Bois-Pin; Angle d'inclinaison de Poutre: 0 deg; Génération de modèle analytique structurel: yes; Membre étiré manuellement: no; ID de l'élément: Poutre-012; Lien et ID d'élément: Poutre-012; Calque: 3D; Matériau de construction / Composite / Profil / Hachure: Parpaing 2676271321; Matériau de construction: Parpaing 2676271321; Verrouillé: no; Nom d'étage d'implantation: sousol; Numéro d'étage d'implantation: 2; Type d'élément: Poutre; Type de structure: Basique; ID de Parent: Poutre-012; Matériaux de construction (Tous): Parpaing 2676271321; Surfaces (Toutes): Bois-Pin; Angle d'inclinaison: 0 deg; Nombre de percements: 0; Surface supérieure: Bois-Pin; Surface inférieure: Bois-Pin; Nom de Variante: Modèle principal; Nom de Jeu de Variantes: Modèle principal; Position: Intérieur; Fonction structurelle: Élément porteur; Affichage sur filtre de rénovation: Tous les filtres appropriés; État de rénovation: Existant; État de Variante: Modèle principal; Jeu de Variantes: Modèle principal
ArchiCADQuantities - Superficie des deux extrémités de poutre: 0.696 m2; Nombre de trous: 0; Superficie des arêtes des trous: 0 m2; Superficie des trous: 0 m2; Volume des trous: 0 m3; Superficie de la poutre côté gauche (nette): 3.55155 m2; Longueur gauche: 6123.36 mm; Longueur droite: 6123.36 mm; Décalage: 0 mm; Superficie de la poutre côté droit (nette): 3.55155 m2; Superficie: 3.67401 m2; Hauteur: 580 mm; Volume (net): 2.13093 m3; Largeur: 600 mm; Altitude à Zéro du Projet: 2950 mm; Altitude de Référence Niveau 1: 2950 mm; Altitude de Référence Niveau 2: 2950 mm; Altitude à niveau de la mer: 2950 mm; Altitude à étage lié/étage d'implantation: 2950 mm; Décalage étage d'implantation: 2950 mm; Superficie en plan: 15.1471 m2; Longueur 3D: 6123.36 mm; Volume (conditionnel): 2.13093 m3; Volume (brut): 2.13093 m3; Altitude supérieure à premier niveau de référence: 2950 mm; Altitude supérieure à étage d'implantation: 2950 mm; Altitude supérieure à Zéro du projet: 2950 mm; Altitude supérieure à niveau de la mer: 2950 mm; Altitude supérieure à deuxième niveau de référence: 2950 mm; Altitude inférieure à premier niveau de référence: 2370 mm; Altitude inférieure à étage d'implantation: 2370 mm; Altitude inférieure à Zéro du projet: 2370 mm; Altitude inférieure à niveau de la mer: 2370 mm; Altitude inférieure à deuxième niveau de référence: 2370 mm; Hauteur coupe transversale haut/fin (perpendiculaire): 580 mm; Hauteur coupe transversale bas/départ (perpendiculaire): 580 mm; Largeur coupe transversale haut/fin (perpendiculaire): 600 mm; Largeur coupe transversale bas/départ (perpendiculaire): 600 mm; Hauteur coupe transversale haut/fin (coupée): 580 mm; Hauteur coupe transversale bas/départ (coupée): 580 mm; Largeur coupe transversale haut/fin (coupée): 600 mm; Largeur coupe transversale bas/départ (coupée): 600 mm; Surface coupe transversale bas/départ (coupée): 0.348 m2; Surface coupe transversale haut/fin: 0.348 m2; Nombre de segments: 1; Superficie supérieure (nette): 3.67401 m2; Superficie inférieure (nette): 3.67401 m2

# IfcBeam: Parpaing 2676271321 600 x 700 (3)
In: sousol
Classification: Poutre (Classification ARCHICAD); Material: Parpaing 2676271321
AC_Pset_RenovationAndPhasing - Renovation Status: Existing
ArchiCADProperties - Coupe transversale de Poutre: Rectangulaire; Surface de fin: Bois-Pin; Surface gauche: Bois-Pin; Surface droite: Bois-Pin; Angle d'inclinaison de Poutre: 0 deg; Génération de modèle analytique structurel: yes; Membre étiré manuellement: no; ID de l'élément: Poutre-012; Lien et ID d'élément: Poutre-012; Calque: 3D; Matériau de construction / Composite / Profil / Hachure: Parpaing 2676271321; Matériau de construction: Parpaing 2676271321; Verrouillé: no; Nom d'étage d'implantation: sousol; Numéro d'étage d'implantation: 2; Type d'élément: Poutre; Type de structure: Basique; ID de Parent: Poutre-012; Matériaux de construction (Tous): Parpaing 2676271321; Surfaces (Toutes): Bois-Pin; Angle d'inclinaison: 0 deg; Nombre de percements: 0; Surface supérieure: Bois-Pin; Surface inférieure: Bois-Pin; Nom de Variante: Modèle principal; Nom de Jeu de Variantes: Modèle principal; Position: Intérieur; Fonction structurelle: Élément porteur; Affichage sur filtre de rénovation: Tous les filtres appropriés; État de rénovation: Existant; État de Variante: Modèle principal; Jeu de Variantes: Modèle principal
ArchiCADQuantities - Nombre de trous: 0; Superficie des arêtes des trous: 0 m2; Superficie des trous: 0 m2; Volume des trous: 0 m3; Décalage: 0 mm; Hauteur: 700 mm; Largeur: 600 mm; Altitude à Zéro du Projet: 2950 mm; Altitude de Référence Niveau 1: 2950 mm; Altitude de Référence Niveau 2: 2950 mm; Altitude à niveau de la mer: 2950 mm; Altitude à étage lié/étage d'implantation: 2950 mm; Décalage étage d'implantation: 2950 mm; Altitude supérieure à premier niveau de référence: 2950 mm; Altitude supérieure à étage d'implantation: 2950 mm; Altitude supérieure à Zéro du projet: 2950 mm; Altitude supérieure à niveau de la mer: 2950 mm; Altitude supérieure à deuxième niveau de référence: 2950 mm; Altitude inférieure à premier niveau de référence: 2250 mm; Altitude inférieure à étage d'implantation: 2250 mm; Altitude inférieure à Zéro du projet: 2250 mm; Altitude inférieure à niveau de la mer: 2250 mm; Altitude inférieure à deuxième niveau de référence: 2250 mm; Hauteur coupe transversale haut/fin (perpendiculaire): 700 mm; Hauteur coupe transversale bas/départ (perpendiculaire): 700 mm; Largeur coupe transversale haut/fin (perpendiculaire): 600 mm; Largeur coupe transversale bas/départ (perpendiculaire): 600 mm; Hauteur coupe transversale haut/fin (coupée): 700 mm; Hauteur coupe transversale bas/départ (coupée): 700 mm; Largeur coupe transversale haut/fin (coupée): 600 mm; Largeur coupe transversale bas/départ (coupée): 600 mm; Surface coupe transversale bas/départ (coupée): 0.42 m2; Nombre de segments: 1
Name | Superficie des deux extrémités de poutre (m2) | Superficie de la poutre côté gauche (nette) (m2) | Longueur gauche (mm) | Longueur droite (mm) | Superficie de la poutre côté droit (nette) (m2) | Superficie (m2) | Volume (net) (m3) = Volume (conditionnel) (m3) = Volume (brut) (m3) | Superficie en plan (m2) | Longueur 3D (mm) | Surface coupe transversale haut/fin (m2) | Superficie supérieure (nette) (m2) | Superficie inférieure (nette) (m2)
Poutre-012 | 0.84 | 7.55173 | 10788.2 | 10788.2 | 7.55173 | 6.47291 | 4.53104 | 28.8893 | 10788.2 | 0.42 | 6.47291 | 6.47291
Poutre-012 | 0.84 | 3.80036 | 5429.08 | 5429.67 | 3.80077 | 3.25762 | 2.28034 | 14.9564 | 5429.67 | 0.42 | 3.25762 | 3.25762
Poutre-012 | 0.853418 | 4.51761 | 6327.26 | 6508.71 | 4.60833 | 4.06193 | 2.73778 | 18.1032 | 6769.89 | 0.433418 | 3.85079 | 4.27308

# IfcBeam: Parpaing 2676271321 600 x 800 (3)
In: sousol
Classification: Poutre (Classification ARCHICAD); Material: Parpaing 2676271321
ArchiCADProperties - Coupe transversale de Poutre: Rectangulaire; Surface de fin: Bois-Pin; Surface gauche: Bois-Pin; Surface droite: Bois-Pin; Angle d'inclinaison de Poutre: 0 deg; Génération de modèle analytique structurel: yes; Membre étiré manuellement: no; ID de l'élément: Poutre-012; Lien et ID d'élément: Poutre-012; Calque: 3D; Matériau de construction / Composite / Profil / Hachure: Parpaing 2676271321; Matériau de construction: Parpaing 2676271321; Verrouillé: no; Nom d'étage d'implantation: sousol; Numéro d'étage d'implantation: 2; Type d'élément: Poutre; Type de structure: Basique; ID de Parent: Poutre-012; Matériaux de construction (Tous): Parpaing 2676271321; Surfaces (Toutes): Bois-Pin; Angle d'inclinaison: 0 deg; Nombre de percements: 0; Surface supérieure: Bois-Pin; Surface inférieure: Bois-Pin; Nom de Variante: Modèle principal; Nom de Jeu de Variantes: Modèle principal; Position: Intérieur; Fonction structurelle: Élément porteur; Affichage sur filtre de rénovation: Tous les filtres appropriés; État de rénovation: Existant; État de Variante: Modèle principal; Jeu de Variantes: Modèle principal
ArchiCADQuantities - Nombre de trous: 0; Superficie des arêtes des trous: 0 m2; Superficie des trous: 0 m2; Volume des trous: 0 m3; Décalage: 0 mm; Hauteur: 800 mm; Largeur: 600 mm; Altitude à Zéro du Projet: 2950 mm; Altitude de Référence Niveau 1: 2950 mm; Altitude de Référence Niveau 2: 2950 mm; Altitude à niveau de la mer: 2950 mm; Altitude à étage lié/étage d'implantation: 2950 mm; Décalage étage d'implantation: 2950 mm; Altitude supérieure à premier niveau de référence: 2950 mm; Altitude supérieure à étage d'implantation: 2950 mm; Altitude supérieure à Zéro du projet: 2950 mm; Altitude supérieure à niveau de la mer: 2950 mm; Altitude supérieure à deuxième niveau de référence: 2950 mm; Altitude inférieure à premier niveau de référence: 2150 mm; Altitude inférieure à étage d'implantation: 2150 mm; Altitude inférieure à Zéro du projet: 2150 mm; Altitude inférieure à niveau de la mer: 2150 mm; Altitude inférieure à deuxième niveau de référence: 2150 mm; Hauteur coupe transversale haut/fin (perpendiculaire): 800 mm; Hauteur coupe transversale bas/départ (perpendiculaire): 800 mm; Largeur coupe transversale haut/fin (perpendiculaire): 600 mm; Largeur coupe transversale bas/départ (perpendiculaire): 600 mm; Hauteur coupe transversale haut/fin (coupée): 800 mm; Hauteur coupe transversale bas/départ (coupée): 800 mm; Largeur coupe transversale haut/fin (coupée): 600 mm; Largeur coupe transversale bas/départ (coupée): 600 mm; Surface coupe transversale bas/départ (coupée): 0.48 m2; Nombre de segments: 1
AC_Pset_RenovationAndPhasing - Renovation Status: Existing
Name | Superficie des deux extrémités de poutre (m2) | Superficie de la poutre côté gauche (nette) (m2) | Longueur gauche (mm) | Longueur droite (mm) | Superficie de la poutre côté droit (nette) (m2) | Superficie (m2) | Volume (net) (m3) = Volume (conditionnel) (m3) = Volume (brut) (m3) | Superficie en plan (m2) | Longueur 3D (mm) | Surface coupe transversale haut/fin (m2) | Superficie supérieure (nette) (m2) | Superficie inférieure (nette) (m2)
Poutre-012 | 0.96 | 4.50076 | 5550.8 | 5551.39 | 4.50111 | 3.51083 | 2.70056 | 16.9835 | 5851.39 | 0.48 | 3.33066 | 3.69101
Poutre-012 | 1.01666 | 4.28 | 5350 | 5650 | 4.52 | 3.3 | 2.64 | 16.4167 | 5650 | 0.536656 | 3.3 | 3.3
Poutre-012 | 0.962472 | 4.9923 | 6240.37 | 6301.35 | 5.04108 | 3.76252 | 3.01001 | 18.5209 | 6301.35 | 0.482472 | 3.76252 | 3.76252

# IfcBeam: Parpaing 2676271321 600 x 850, Poutre-012
In: sousol
Classification: Poutre (Classification ARCHICAD); Material: Parpaing 2676271321
ArchiCADQuantities - Superficie des deux extrémités de poutre: 1.02 m2; Nombre de trous: 0; Superficie des arêtes des trous: 0 m2; Superficie des trous: 0 m2; Volume des trous: 0 m3; Superficie de la poutre côté gauche (nette): 4.59 m2; Longueur gauche: 5400 mm; Longueur droite: 5400 mm; Décalage: 0 mm; Superficie de la poutre côté droit (nette): 4.59 m2; Superficie: 3.24 m2; Hauteur: 850 mm; Volume (net): 2.754 m3; Largeur: 600 mm; Altitude à Zéro du Projet: 2950 mm; Altitude de Référence Niveau 1: 2950 mm; Altitude de Référence Niveau 2: 2950 mm; Altitude à niveau de la mer: 2950 mm; Altitude à étage lié/étage d'implantation: 2950 mm; Décalage étage d'implantation: 2950 mm; Superficie en plan: 16.68 m2; Longueur 3D: 5400 mm; Volume (conditionnel): 2.754 m3; Volume (brut): 2.754 m3; Altitude supérieure à premier niveau de référence: 2950 mm; Altitude supérieure à étage d'implantation: 2950 mm; Altitude supérieure à Zéro du projet: 2950 mm; Altitude supérieure à niveau de la mer: 2950 mm; Altitude supérieure à deuxième niveau de référence: 2950 mm; Altitude inférieure à premier niveau de référence: 2100 mm; Altitude inférieure à étage d'implantation: 2100 mm; Altitude inférieure à Zéro du projet: 2100 mm; Altitude inférieure à niveau de la mer: 2100 mm; Altitude inférieure à deuxième niveau de référence: 2100 mm; Hauteur coupe transversale haut/fin (perpendiculaire): 850 mm; Hauteur coupe transversale bas/départ (perpendiculaire): 850 mm; Largeur coupe transversale haut/fin (perpendiculaire): 600 mm; Largeur coupe transversale bas/départ (perpendiculaire): 600 mm; Hauteur coupe transversale haut/fin (coupée): 850 mm; Hauteur coupe transversale bas/départ (coupée): 850 mm; Largeur coupe transversale haut/fin (coupée): 600 mm; Largeur coupe transversale bas/départ (coupée): 600 mm; Surface coupe transversale bas/départ (coupée): 0.51 m2; Surface coupe transversale haut/fin: 0.51 m2; Nombre de segments: 1; Superficie supérieure (nette): 3.24 m2; Superficie inférieure (nette): 3.24 m2
AC_Pset_RenovationAndPhasing - Renovation Status: Existing
ArchiCADProperties - Coupe transversale de Poutre: Rectangulaire; Surface de fin: Bois-Pin; Surface gauche: Bois-Pin; Surface droite: Bois-Pin; Angle d'inclinaison de Poutre: 0 deg; Génération de modèle analytique structurel: yes; Membre étiré manuellement: no; ID de l'élément: Poutre-012; Lien et ID d'élément: Poutre-012; Calque: 3D; Matériau de construction / Composite / Profil / Hachure: Parpaing 2676271321; Matériau de construction: Parpaing 2676271321; Verrouillé: no; Nom d'étage d'implantation: sousol; Numéro d'étage d'implantation: 2; Type d'élément: Poutre; Type de structure: Basique; ID de Parent: Poutre-012; Matériaux de construction (Tous): Parpaing 2676271321; Surfaces (Toutes): Bois-Pin; Angle d'inclinaison: 0 deg; Nombre de percements: 0; Surface supérieure: Bois-Pin; Surface inférieure: Bois-Pin; Nom de Variante: Modèle principal; Nom de Jeu de Variantes: Modèle principal; Position: Intérieur; Fonction structurelle: Élément porteur; Affichage sur filtre de rénovation: Tous les filtres appropriés; État de rénovation: Existant; État de Variante: Modèle principal; Jeu de Variantes: Modèle principal
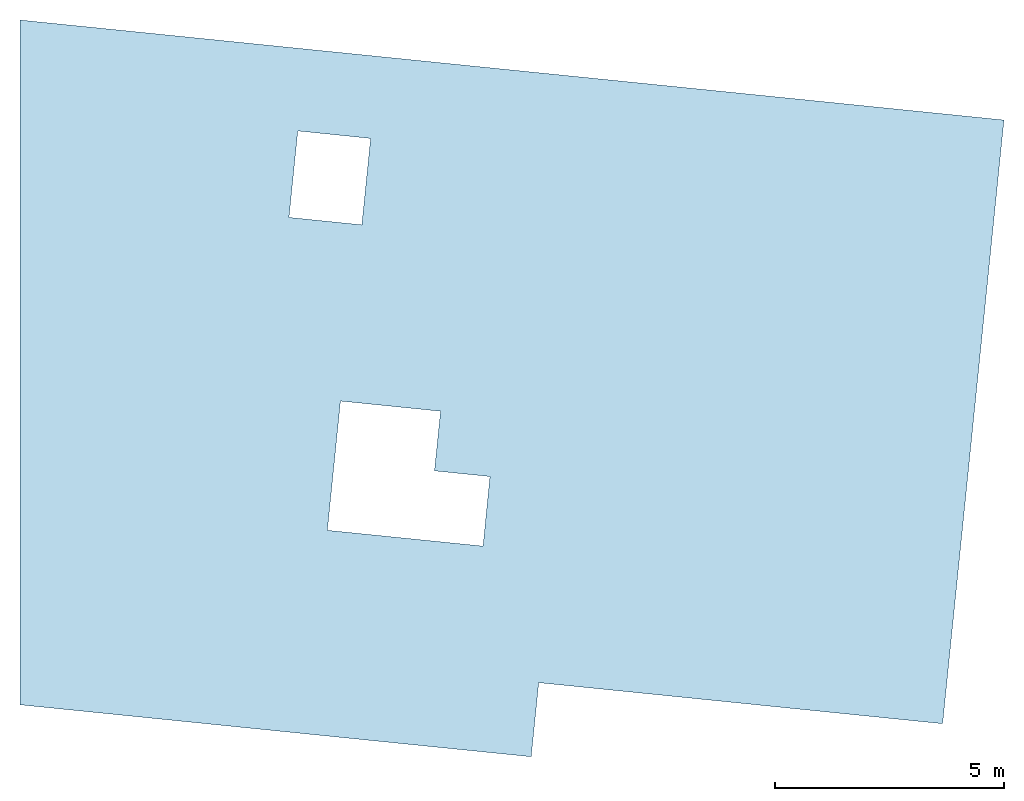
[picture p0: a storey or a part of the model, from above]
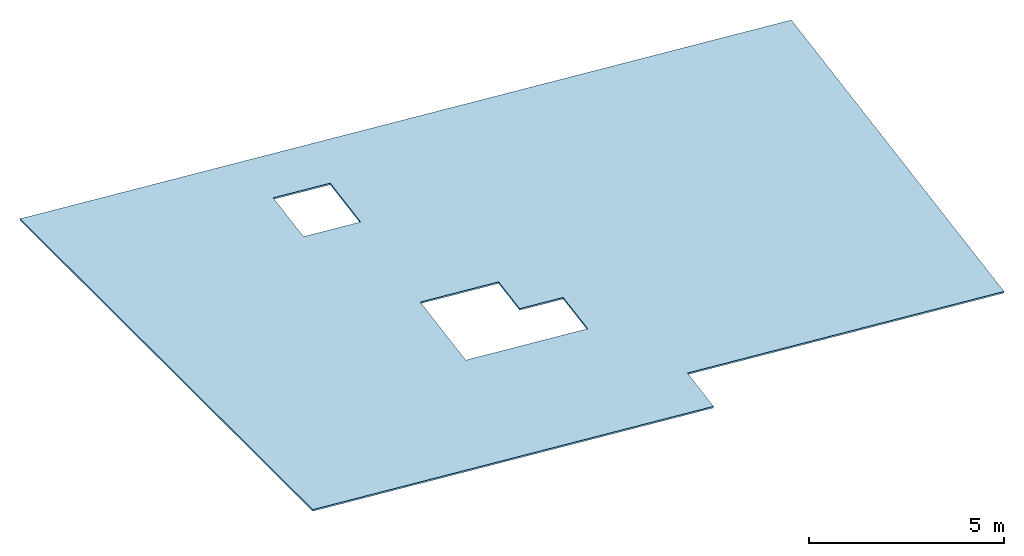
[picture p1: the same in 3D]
Properties of the parts of a building model (IFC2X3), part 4 of 44

# IfcBeam: Parpaing 2676271321 700 x 800, Poutre-012
In: sousol
Classification: Poutre (Classification ARCHICAD); Material: Parpaing 2676271321
ArchiCADProperties - Coupe transversale de Poutre: Rectangulaire; Surface de fin: Bois-Pin; Surface gauche: Bois-Pin; Surface droite: Bois-Pin; Angle d'inclinaison de Poutre: 0 deg; Génération de modèle analytique structurel: yes; Membre étiré manuellement: no; ID de l'élément: Poutre-012; Lien et ID d'élément: Poutre-012; Calque: 3D; Matériau de construction / Composite / Profil / Hachure: Parpaing 2676271321; Matériau de construction: Parpaing 2676271321; Verrouillé: no; Nom d'étage d'implantation: sousol; Numéro d'étage d'implantation: 2; Type d'élément: Poutre; Type de structure: Basique; ID de Parent: Poutre-012; Matériaux de construction (Tous): Parpaing 2676271321; Surfaces (Toutes): Bois-Pin; Angle d'inclinaison: 0 deg; Nombre de percements: 0; Surface supérieure: Bois-Pin; Surface inférieure: Bois-Pin; Nom de Variante: Modèle principal; Nom de Jeu de Variantes: Modèle principal; Position: Intérieur; Fonction structurelle: Élément porteur; Affichage sur filtre de rénovation: Tous les filtres appropriés; État de rénovation: Existant; État de Variante: Modèle principal; Jeu de Variantes: Modèle principal
AC_Pset_RenovationAndPhasing - Renovation Status: Existing
ArchiCADQuantities - Superficie des deux extrémités de poutre: 1.12 m2; Nombre de trous: 0; Superficie des arêtes des trous: 0 m2; Superficie des trous: 0 m2; Volume des trous: 0 m3; Superficie de la poutre côté gauche (nette): 4.504 m2; Longueur gauche: 5630 mm; Longueur droite: 5630 mm; Décalage: 0 mm; Superficie de la poutre côté droit (nette): 4.504 m2; Superficie: 3.941 m2; Hauteur: 800 mm; Volume (net): 3.1528 m3; Largeur: 700 mm; Altitude à Zéro du Projet: 2950 mm; Altitude de Référence Niveau 1: 2950 mm; Altitude de Référence Niveau 2: 2950 mm; Altitude à niveau de la mer: 2950 mm; Altitude à étage lié/étage d'implantation: 2950 mm; Décalage étage d'implantation: 2950 mm; Superficie en plan: 18.01 m2; Longueur 3D: 5630 mm; Volume (conditionnel): 3.1528 m3; Volume (brut): 3.1528 m3; Altitude supérieure à premier niveau de référence: 2950 mm; Altitude supérieure à étage d'implantation: 2950 mm; Altitude supérieure à Zéro du projet: 2950 mm; Altitude supérieure à niveau de la mer: 2950 mm; Altitude supérieure à deuxième niveau de référence: 2950 mm; Altitude inférieure à premier niveau de référence: 2150 mm; Altitude inférieure à étage d'implantation: 2150 mm; Altitude inférieure à Zéro du projet: 2150 mm; Altitude inférieure à niveau de la mer: 2150 mm; Altitude inférieure à deuxième niveau de référence: 2150 mm; Hauteur coupe transversale haut/fin (perpendiculaire): 800 mm; Hauteur coupe transversale bas/départ (perpendiculaire): 800 mm; Largeur coupe transversale haut/fin (perpendiculaire): 700 mm; Largeur coupe transversale bas/départ (perpendiculaire): 700 mm; Hauteur coupe transversale haut/fin (coupée): 800 mm; Hauteur coupe transversale bas/départ (coupée): 800 mm; Largeur coupe transversale haut/fin (coupée): 700 mm; Largeur coupe transversale bas/départ (coupée): 700 mm; Surface coupe transversale bas/départ (coupée): 0.56 m2; Surface coupe transversale haut/fin: 0.56 m2; Nombre de segments: 1; Superficie supérieure (nette): 3.941 m2; Superficie inférieure (nette): 3.941 m2

# IfcBeam: Parpaing 2676271321 800 x 800 (4)
In: sousol
Classification: Poutre (Classification ARCHICAD); Material: Parpaing 2676271321
ArchiCADProperties - Coupe transversale de Poutre: Rectangulaire; Surface de fin: Bois-Pin; Surface gauche: Bois-Pin; Surface droite: Bois-Pin; Angle d'inclinaison de Poutre: 0 deg; Génération de modèle analytique structurel: yes; Membre étiré manuellement: no; ID de l'élément: Poutre-012; Lien et ID d'élément: Poutre-012; Calque: 3D; Matériau de construction / Composite / Profil / Hachure: Parpaing 2676271321; Matériau de construction: Parpaing 2676271321; Verrouillé: no; Nom d'étage d'implantation: sousol; Numéro d'étage d'implantation: 2; Type d'élément: Poutre; Type de structure: Basique; ID de Parent: Poutre-012; Matériaux de construction (Tous): Parpaing 2676271321; Surfaces (Toutes): Bois-Pin; Angle d'inclinaison: 0 deg; Nombre de percements: 0; Surface supérieure: Bois-Pin; Surface inférieure: Bois-Pin; Nom de Variante: Modèle principal; Nom de Jeu de Variantes: Modèle principal; Position: Intérieur; Fonction structurelle: Élément porteur; Affichage sur filtre de rénovation: Tous les filtres appropriés; État de rénovation: Existant; État de Variante: Modèle principal; Jeu de Variantes: Modèle principal
AC_Pset_RenovationAndPhasing - Renovation Status: Existing
ArchiCADQuantities - Nombre de trous: 0; Superficie des arêtes des trous: 0 m2; Superficie des trous: 0 m2; Volume des trous: 0 m3; Décalage: 0 mm; Hauteur: 800 mm; Largeur: 800 mm; Altitude à Zéro du Projet: 2950 mm; Altitude de Référence Niveau 1: 2950 mm; Altitude de Référence Niveau 2: 2950 mm; Altitude à niveau de la mer: 2950 mm; Altitude à étage lié/étage d'implantation: 2950 mm; Décalage étage d'implantation: 2950 mm; Altitude supérieure à premier niveau de référence: 2950 mm; Altitude supérieure à étage d'implantation: 2950 mm; Altitude supérieure à Zéro du projet: 2950 mm; Altitude supérieure à niveau de la mer: 2950 mm; Altitude supérieure à deuxième niveau de référence: 2950 mm; Altitude inférieure à premier niveau de référence: 2150 mm; Altitude inférieure à étage d'implantation: 2150 mm; Altitude inférieure à Zéro du projet: 2150 mm; Altitude inférieure à niveau de la mer: 2150 mm; Altitude inférieure à deuxième niveau de référence: 2150 mm; Hauteur coupe transversale haut/fin (perpendiculaire): 800 mm; Hauteur coupe transversale bas/départ (perpendiculaire): 800 mm; Largeur coupe transversale haut/fin (perpendiculaire): 800 mm; Largeur coupe transversale bas/départ (perpendiculaire): 800 mm; Hauteur coupe transversale haut/fin (coupée): 800 mm; Hauteur coupe transversale bas/départ (coupée): 800 mm; Largeur coupe transversale haut/fin (coupée): 800 mm; Largeur coupe transversale bas/départ (coupée): 800 mm; Nombre de segments: 1
Name | Superficie des deux extrémités de poutre (m2) | Superficie de la poutre côté gauche (nette) (m2) | Longueur gauche (mm) = Longueur 3D (mm) | Longueur droite (mm) | Superficie de la poutre côté droit (nette) (m2) | Superficie (m2) = Superficie supérieure (nette) (m2) = Superficie inférieure (nette) (m2) | Volume (net) (m3) = Volume (conditionnel) (m3) | Superficie en plan (m2) | Volume (brut) (m3) | Surface coupe transversale bas/départ (coupée) (m2) | Surface coupe transversale haut/fin (m2)
Poutre-012 | 1.04 | 4.67059 | 5838.24 | 5838.24 | 4.67059 | 4.64412 | 3.7153 | 20.0506 | 3.73647 | 0.64 | 0.4
Poutre-012 | 1.28 | 4.6 | 5750 | 5750 | 4.6 | 4.6 | 3.68 | 19.68 | 3.68 | 0.64 | 0.64
Poutre-012 | 1.08721 | 4.83513 | 6043.91 | 5643.91 | 4.51513 | 4.58262 | 3.6661 | 20.3361 | 3.7401 | 0.447214 | 0.64
Poutre-012 | 0.8 | 5.05459 | 6318.24 | 6318.24 | 5.05459 | 4.85675 | 3.8854 | 22.1578 | 4.04367 | 0.4 | 0.4

# IfcBeam: Sans Trame 275646760 20 x 349, Poutre-011
In: toiture
Classification: Poutre (Classification ARCHICAD); Material: Sans Trame 275646760
ArchiCADQuantities - Superficie des deux extrémités de poutre: 0.0120033 m2; Nombre de trous: 0; Superficie des arêtes des trous: 0 m2; Superficie des trous: 0 m2; Volume des trous: 0 m3; Superficie de la poutre côté gauche (nette): 2.03374 m2; Longueur gauche: 5833.75 mm; Longueur droite: 5833.75 mm; Décalage: 0 mm; Superficie de la poutre côté droit (nette): 2.02374 m2; Superficie: 0.101409 m2; Hauteur: 348.616 mm; Volume (net): 0.0405747 m3; Largeur: 20 mm; Altitude à Zéro du Projet: 18490.7 mm; Altitude de Référence Niveau 1: 18490.7 mm; Altitude de Référence Niveau 2: 18490.7 mm; Altitude à niveau de la mer: 18490.7 mm; Altitude à étage lié/étage d'implantation: -1859.34 mm; Décalage étage d'implantation: -1859.34 mm; Superficie en plan: 4.33226 m2; Longueur 3D: 6030.1 mm; Volume (conditionnel): 0.0405747 m3; Volume (brut): 0.0406748 m3; Altitude supérieure à premier niveau de référence: 21353.6 mm; Altitude supérieure à étage d'implantation: 1003.57 mm; Altitude supérieure à Zéro du projet: 21353.6 mm; Altitude supérieure à niveau de la mer: 21353.6 mm; Altitude supérieure à deuxième niveau de référence: 21353.6 mm; Altitude inférieure à premier niveau de référence: 18090.6 mm; Altitude inférieure à étage d'implantation: -2259.44 mm; Altitude inférieure à Zéro du projet: 18090.6 mm; Altitude inférieure à niveau de la mer: 18090.6 mm; Altitude inférieure à deuxième niveau de référence: 18090.6 mm; Hauteur coupe transversale haut/fin (perpendiculaire): 348.616 mm; Hauteur coupe transversale bas/départ (perpendiculaire): 348.616 mm; Largeur coupe transversale haut/fin (perpendiculaire): 20 mm; Largeur coupe transversale bas/départ (perpendiculaire): 20 mm; Hauteur coupe transversale haut/fin (coupée): 400.11 mm; Hauteur coupe transversale bas/départ (coupée): 400.11 mm; Largeur coupe transversale haut/fin (coupée): 20 mm; Largeur coupe transversale bas/départ (coupée): 20 mm; Surface coupe transversale bas/départ (coupée): 0.00400109 m2; Surface coupe transversale haut/fin: 0.00800219 m2; Nombre de segments: 1; Superficie supérieure (nette): 0.116388 m2; Superficie inférieure (nette): 0.116388 m2
AC_Pset_RenovationAndPhasing - Renovation Status: Existing
ArchiCADProperties - Coupe transversale de Poutre: Rectangulaire; Surface de fin: Vitrage-Bleu; Surface gauche: Vitrage-Bleu; Surface droite: Vitrage-Bleu; Angle d'inclinaison de Poutre: 29.3898 deg; Génération de modèle analytique structurel: yes; Membre étiré manuellement: no; ID de l'élément: Poutre-011; Lien et ID d'élément: Poutre-011; Calque: 3D; Matériau de construction / Composite / Profil / Hachure: Sans Trame 275646760; Matériau de construction: Sans Trame 275646760; Zones conflictuelles: Terrasse; Verrouillé: no; Nom d'étage d'implantation: toiture; Numéro d'étage d'implantation: 9; Type d'élément: Poutre; Type de structure: Basique; ID de Parent: Poutre-011; Matériaux de construction (Tous): Sans Trame 275646760; Surfaces (Toutes): Vitrage-Bleu; Angle d'inclinaison: 29.3898 deg; Nombre de percements: 0; Surface supérieure: Vitrage-Bleu; Surface inférieure: Vitrage-Bleu; Nom de Variante: Modèle principal; Nom de Jeu de Variantes: Modèle principal; Position: Intérieur; Fonction structurelle: Élément porteur; Affichage sur filtre de rénovation: Tous les filtres appropriés; État de rénovation: Existant; État de Variante: Modèle principal; Jeu de Variantes: Modèle principal

# IfcBuildingElementProxy (454)
AC_Pset_RenovationAndPhasing - Renovation Status: Existing
ArchiCADProperties - Verrouillé: no; Type d'élément: Objet; Nom de Variante: Modèle principal; Nom de Jeu de Variantes: Modèle principal; Position: Non défini; Fonction structurelle: Non défini; Affichage sur filtre de rénovation: Tous les filtres appropriés; État de rénovation: Existant; État de Variante: Modèle principal; Jeu de Variantes: Modèle principal
Name | In | Longueur (A) (mm) | Superficie (m2) = Superficie supérieure (nette) (m2) | Hauteur (mm) | Volume (net) (m3) | Largeur (mm) | Altitude à Zéro du Projet (mm) = Altitude de Référence Niveau 1 (mm) = Altitude de Référence Niveau 2 (mm) = Altitude à niveau de la mer (mm) = Coordonnée topographique Z (mm) | Altitude à étage lié/étage d'implantation (mm) = Décalage étage d'implantation (mm) | Superficie en plan (m2) = Superficie inférieure (nette) (m2) | Altitude supérieure à premier niveau de référence (mm) = Altitude supérieure à Zéro du projet (mm) = Altitude supérieure à niveau de la mer (mm) = Altitude supérieure à deuxième niveau de référence (mm) | Altitude supérieure à étage d'implantation (mm) | Altitude inférieure à premier niveau de référence (mm) = Altitude inférieure à Zéro du projet (mm) = Altitude inférieure à niveau de la mer (mm) = Altitude inférieure à deuxième niveau de référence (mm) | Altitude inférieure à étage d'implantation (mm) | Coordonnée topographique X (mm) | Coordonnée topographique Y (mm) | Angle de rotation (deg) | Surface | ID de l'élément = Lien et ID d'élément = ID de Parent | Calque | Nom Élément de Bibliothèque | Matériau de construction / Composite / Profil / Hachure = Type Hachure | Nom d'étage d'implantation | Numéro d'étage d'implantation | Surfaces (Toutes) | Zones conflictuelles | Nom de zone liée | Numéro de zone liée
Obj.-047 | rdc | 1406.6 | 1.4066 | 1000 | 0.00728511 | 1000 | 3200 | 200 | 0.728511 | 4200 | 1200 | 3250 | 250 | 2248772 | -607260 | 174.197 | Revêt. pilier rond | Obj.-047 | MOBILIER | Cadre solide_70 | Brique 1 | rdc | 3 | Surface-Porcelaine
Obj.-027 | rdc | 440 | 0.211011 | 450 | 0.0143427 | 479.571 | 3000 | 2.22045e-12 | 0.948533 | 3780 | 780 | 3000 | 2.22045e-12 | 2231889 | -617070 | 264.227 | C10 | Obj.-027 | MOBILIER | Chaise 1 65 | Brique 1 | rdc | 3 | Métal-Inox; Surface-Plastique stratifié | Sejour cuisine | Sejour cuisine | A03
Obj.-027 | rdc | 440 | 0.211011 | 450 | 0.0143427 | 479.571 | 3000 | 2.22045e-12 | 0.948533 | 3780 | 780 | 3000 | 2.22045e-12 | 2219837 | -625431 | 90.031 | C10 | Obj.-027 | MOBILIER | Chaise 1 65 | Brique 1 | rdc | 3 | Métal-Inox; Surface-Plastique stratifié | Sejour Cuisine | Sejour Cuisine | B01
Obj.-027 | rdc | 440 | 0.211011 | 450 | 0.0143427 | 479.571 | 3000 | 2.22045e-12 | 0.948533 | 3780 | 780 | 3000 | 2.22045e-12 | 2220245 | -626046 | 270.031 | C10 | Obj.-027 | MOBILIER | Chaise 1 65 | Brique 1 | rdc | 3 | Métal-Inox; Surface-Plastique stratifié | Sejour Cuisine | Sejour Cuisine | B01
Obj.-034 | rdc | 1473.38 | 0.220611 | 2500 | 0.0477147 | 149.731 | 3000 | 1.42109e-11 | 5.5917 | 5500 | 2500 | 3000 | 1.42109e-11 | 2233601 | -622258 | 84.1973 | Revêt. pilier rond | Obj.-034 | 0-Resille Dampere | Barrière vitrée 65 | Brique 1 | rdc | 3 | Divers-Eau; Peinture-05
Obj.-034 | rdc | 800 | 0.64 | 360 | 0.280139 | 800 | 3800 | 800 | 4.69089 | 4466.7 | 1466.7 | 3800 | 800 | 2221923 | -642912 | 269.964 | Revêt. pilier rond | Obj.-034 | 0-Resille Dampere | Fauteuil 65 | Brique 1 | rdc | 3 | Plancher-Moquette; Revêt. pilier rond | Sejour cuisine | Sejour cuisine | B02
Obj.-027 | rdc | 440 | 0.211011 | 450 | 0.0143427 | 479.571 | 3000 | 2.22045e-12 | 0.948533 | 3780 | 780 | 3000 | 2.22045e-12 | 2221917 | -619966 | 84.2606 | C10 | Obj.-027 | MOBILIER | Chaise 1 65 | Brique 1 | rdc | 3 | Métal-Inox; Surface-Plastique stratifié | Sejour Cuisine | Sejour Cuisine | A02
Obj.-027 | rdc | 440 | 0.211011 | 450 | 0.0143427 | 479.571 | 3000 | 2.22045e-12 | 0.948533 | 3780 | 780 | 3000 | 2.22045e-12 | 2222827 | -606850 | 84.2606 | C10 | Obj.-027 | MOBILIER | Chaise 1 65 | Brique 1 | rdc | 3 | Métal-Inox; Surface-Plastique stratifié | Sejour cuisine/pl | Sejour cuisine/pl | A01
Obj.-019 | rdc | 600 | 0.36 | 900 | 0.314148 | 600 | 3000 | 0 | 4.5196 | 3900 | 900 | 3000 | 0 | 2224288 | -605566 | 264.23 | Revêt. pilier rond | Obj.-019 | SANITAIRE | Réfrigérateur haut 65 | Brique 1 | rdc | 3 | Métal-Chrome; Surface-Lavis Blanc | Sejour cuisine/pl | Sejour cuisine/pl | A01
Obj.-027 | rdc | 440 | 0.211011 | 450 | 0.0143427 | 479.571 | 3000 | 2.22045e-12 | 0.948533 | 3780 | 780 | 3000 | 2.22045e-12 | 2229635 | -638670 | 89.9951 | C10 | Obj.-027 | MOBILIER | Chaise 1 65 | Brique 1 | rdc | 3 | Métal-Inox; Surface-Plastique stratifié | Sejour cuisine | Sejour cuisine | B05
Obj.-027 | rdc | 440 | 0.211011 | 450 | 0.0143427 | 479.571 | 3000 | 2.22045e-12 | 0.948533 | 3780 | 780 | 3000 | 2.22045e-12 | 2222889 | -606238 | 84.2606 | C10 | Obj.-027 | MOBILIER | Chaise 1 65 | Brique 1 | rdc | 3 | Métal-Inox; Surface-Plastique stratifié | Sejour cuisine/pl | Sejour cuisine/pl | A01
Obj.-026 | rdc | 1200 | 1.08 | 730 | 0.0252536 | 900 | 3000 | 2.22045e-12 | 3.05224 | 3730 | 730 | 3000 | 2.22045e-12 | 2222684 | -606816 | 264.261 | C10 | Obj.-026 | MOBILIER | al_table Sting | Brique 1 | rdc | 3 | Métal-Inox; Surface-Peinture brillante; Divers-Glace | Sejour cuisine/pl | Sejour cuisine/pl | A01
Obj.-027 | rdc | 440 | 0.211011 | 450 | 0.0143427 | 479.571 | 3000 | 2.22045e-12 | 0.948533 | 3780 | 780 | 3000 | 2.22045e-12 | 2223233 | -606891 | 264.261 | C10 | Obj.-027 | MOBILIER | Chaise 1 65 | Brique 1 | rdc | 3 | Métal-Inox; Surface-Plastique stratifié | Sejour cuisine/pl | Sejour cuisine/pl | A01
Obj.-027 | rdc | 440 | 0.211011 | 450 | 0.0143427 | 479.571 | 3000 | 2.22045e-12 | 0.948533 | 3780 | 780 | 3000 | 2.22045e-12 | 2223295 | -606279 | 264.261 | C10 | Obj.-027 | MOBILIER | Chaise 1 65 | Brique 1 | rdc | 3 | Métal-Inox; Surface-Plastique stratifié | Sejour cuisine/pl | Sejour cuisine/pl | A01
Obj.-317 | rdc | 2240 | 0.9856 | 960 | 0.838912 | 440 | 3450 | 450 | 26.2191 | 4384 | 1384 | 3450 | 450 | 2226604 | -609683 | 264.197 | Peinture-15 | Obj.-317 | Interieurs logements | al_boiteslettres | 100 % | rdc | 3 | Surface-Lavis Blanc; Métal-Aluminium
Obj.-027 | rdc | 440 | 0.211011 | 450 | 0.0143427 | 479.571 | 3000 | 2.22045e-12 | 0.948533 | 3780 | 780 | 3000 | 2.22045e-12 | 2229634 | -639286 | 89.9951 | C10 | Obj.-027 | MOBILIER | Chaise 1 65 | Brique 1 | rdc | 3 | Métal-Inox; Surface-Plastique stratifié | Sejour cuisine | Sejour cuisine | B05
Obj.-317 | rdc | 3200 | 1.408 | 960 | 1.19761 | 440 | 3450 | 450 | 36.8336 | 4384 | 1384 | 3450 | 450 | 2226273 | -631878 | 0 | Peinture-15 | Obj.-317 | Interieurs logements | al_boiteslettres | 100 % | rdc | 3 | Surface-Lavis Blanc; Métal-Aluminium
Obj.-027 | rdc | 440 | 0.211011 | 450 | 0.0143427 | 479.571 | 3000 | 2.22045e-12 | 0.948533 | 3780 | 780 | 3000 | 2.22045e-12 | 2222323 | -620007 | 264.261 | C10 | Obj.-027 | MOBILIER | Chaise 1 65 | Brique 1 | rdc | 3 | Métal-Inox; Surface-Plastique stratifié | Sejour Cuisine | Sejour Cuisine | A02
Obj.-026 | rdc | 1200 | 1.08 | 730 | 0.0252536 | 900 | 3000 | 2.22045e-12 | 3.05224 | 3730 | 730 | 3000 | 2.22045e-12 | 2221773 | -619932 | 264.261 | C10 | Obj.-026 | MOBILIER | al_table Sting | Brique 1 | rdc | 3 | Métal-Inox; Surface-Peinture brillante; Divers-Glace | Sejour Cuisine | Sejour Cuisine | A02
Obj.-027 | rdc | 440 | 0.211011 | 450 | 0.0143427 | 479.571 | 3000 | 2.22045e-12 | 0.948533 | 3780 | 780 | 3000 | 2.22045e-12 | 2230043 | -638671 | 269.995 | C10 | Obj.-027 | MOBILIER | Chaise 1 65 | Brique 1 | rdc | 3 | Métal-Inox; Surface-Plastique stratifié | Sejour cuisine | Sejour cuisine | B05
Obj.-027 | rdc | 440 | 0.211011 | 450 | 0.0143427 | 479.571 | 3000 | 2.22045e-12 | 0.948533 | 3780 | 780 | 3000 | 2.22045e-12 | 2220245 | -625431 | 270.031 | C10 | Obj.-027 | MOBILIER | Chaise 1 65 | Brique 1 | rdc | 3 | Métal-Inox; Surface-Plastique stratifié | Sejour Cuisine | Sejour Cuisine | B01
Obj.-019 | rdc | 600 | 0.36 | 900 | 0.314148 | 600 | 3000 | 0 | 4.5196 | 3900 | 900 | 3000 | 0 | 2222857 | -639252 | 0 | Revêt. pilier rond | Obj.-019 | SANITAIRE | Réfrigérateur haut 65 | Brique 1 | rdc | 3 | Métal-Chrome; Surface-Lavis Blanc | Sejour cuisine | Sejour cuisine | B02
Obj.-027 | rdc | 440 | 0.211011 | 450 | 0.0143427 | 479.571 | 3000 | 2.22045e-12 | 0.948533 | 3780 | 780 | 3000 | 2.22045e-12 | 2222384 | -619395 | 264.261 | C10 | Obj.-027 | MOBILIER | Chaise 1 65 | Brique 1 | rdc | 3 | Métal-Inox; Surface-Plastique stratifié | Sejour Cuisine | Sejour Cuisine | A02
Obj.-027 | rdc | 440 | 0.211011 | 450 | 0.0143427 | 479.571 | 3000 | 2.22045e-12 | 0.948533 | 3780 | 780 | 3000 | 2.22045e-12 | 2221978 | -619354 | 84.2606 | C10 | Obj.-027 | MOBILIER | Chaise 1 65 | Brique 1 | rdc | 3 | Métal-Inox; Surface-Plastique stratifié | Sejour Cuisine | Sejour Cuisine | A02
Obj.-003 | rdc | 1400 | 2.66 | 400 | 0.566521 | 1900 | 3000 | 0 | 14.0446 | 3493.34 | 493.337 | 3000 | 0 | 2219226 | -644356 | 360 | C10 | Obj.-003 | SANITAIRE | Lit double_70 | Brique 1 | rdc | 3 | Bois-Pin; Plancher-Moquette | Ch 1 | Ch 1 | B03
Obj.-026 | rdc | 1200 | 1.08 | 730 | 0.0252536 | 900 | 3000 | 2.22045e-12 | 3.05224 | 3730 | 730 | 3000 | 2.22045e-12 | 2223265 | -652774 | 89.9951 | C10 | Obj.-026 | MOBILIER | al_table Sting | Brique 1 | rdc | 3 | Métal-Inox; Surface-Peinture brillante; Divers-Glace | Sejour cuisine | Sejour cuisine | B03
Obj.-027 | rdc | 440 | 0.211011 | 450 | 0.0143427 | 479.571 | 3000 | 2.22045e-12 | 0.948533 | 3780 | 780 | 3000 | 2.22045e-12 | 2223119 | -652754 | 269.995 | C10 | Obj.-027 | MOBILIER | Chaise 1 65 | Brique 1 | rdc | 3 | Métal-Inox; Surface-Plastique stratifié | Sejour cuisine | Sejour cuisine | B03
Obj.-027 | rdc | 440 | 0.211011 | 450 | 0.0143427 | 479.571 | 3000 | 2.22045e-12 | 0.948533 | 3780 | 780 | 3000 | 2.22045e-12 | 2236453 | -616012 | 354.197 | C10 | Obj.-027 | MOBILIER | Chaise 1 65 | Brique 1 | rdc | 3 | Métal-Inox; Surface-Plastique stratifié | Sejour Cuisine/pl | Sejour Cuisine/pl | A04
Obj.-003 | rdc | 900 | 1.71 | 400 | 0.364192 | 1900 | 3000 | 0 | 9.53161 | 3493.34 | 493.337 | 3000 | 0 | 2218871 | -649991 | 359.95 | C10 | Obj.-003 | SANITAIRE | Lit double_70 | Brique 1 | rdc | 3 | Bois-Pin; Plancher-Moquette | Ch 3 | Ch 3 | B03
Obj.-003 | rdc | 900 | 1.71 | 400 | 0.364192 | 1900 | 3000 | 0 | 9.53161 | 3493.34 | 493.337 | 3000 | 0 | 2231126 | -652342 | 180.035 | C10 | Obj.-003 | SANITAIRE | Lit double_70 | Brique 1 | rdc | 3 | Bois-Pin; Plancher-Moquette | Ch 2 | Ch 2 | B04
Obj.-003 | rdc | 900 | 1.71 | 400 | 0.364192 | 1900 | 3000 | 0 | 9.53161 | 3493.34 | 493.337 | 3000 | 0 | 2230573 | -641025 | 0.00850185 | C10 | Obj.-003 | SANITAIRE | Lit double_70 | Brique 1 | rdc | 3 | Bois-Pin; Plancher-Moquette | Ch 2 | Ch 2 | B05
Obj.-003 | rdc | 900 | 1.71 | 400 | 0.364192 | 1900 | 3000 | 0 | 9.53161 | 3493.34 | 493.337 | 3000 | 0 | 2218802 | -638677 | 180.001 | C10 | Obj.-003 | SANITAIRE | Lit double_70 | Brique 1 | rdc | 3 | Bois-Pin; Plancher-Moquette | Ch 2 | Ch 2 | B02
Obj.-003 | rdc | 900 | 1.71 | 400 | 0.364192 | 1900 | 3000 | 0 | 9.53161 | 3493.34 | 493.337 | 3000 | 0 | 2218630 | -629221 | 180.001 | C10 | Obj.-003 | SANITAIRE | Lit double_70 | Brique 1 | rdc | 3 | Bois-Pin; Plancher-Moquette | Ch 2 | Ch 2 | B01
Obj.-003 | rdc | 900 | 1.71 | 400 | 0.364192 | 1900 | 3000 | 0 | 9.53161 | 3493.34 | 493.337 | 3000 | 0 | 2236741 | -608071 | 264.197 | C10 | Obj.-003 | SANITAIRE | Lit double_70 | Brique 1 | rdc | 3 | Bois-Pin; Plancher-Moquette | Ch 2/pl | Ch 2/pl | A04
Obj.-003 | rdc | 900 | 1.71 | 400 | 0.364192 | 1900 | 3000 | 0 | 9.53161 | 3493.34 | 493.337 | 3000 | 0 | 2218839 | -649921 | 180.05 | C10 | Obj.-003 | SANITAIRE | Lit double_70 | Brique 1 | rdc | 3 | Bois-Pin; Plancher-Moquette | Ch 2/pl | Ch 2/pl | B03
Obj.-003 | rdc | 900 | 1.71 | 400 | 0.364192 | 1900 | 3000 | 0 | 9.53161 | 3493.34 | 493.337 | 3000 | 0 | 2218690 | -614658 | 354.193 | C10 | Obj.-003 | SANITAIRE | Lit double_70 | Brique 1 | rdc | 3 | Bois-Pin; Plancher-Moquette | Ch 2 | Ch 2 | A02
Obj.-027 | rdc | 440 | 0.211011 | 450 | 0.0143427 | 479.571 | 3000 | 2.22045e-12 | 0.948533 | 3780 | 780 | 3000 | 2.22045e-12 | 2219837 | -626046 | 90.031 | C10 | Obj.-027 | MOBILIER | Chaise 1 65 | Brique 1 | rdc | 3 | Métal-Inox; Surface-Plastique stratifié | Sejour Cuisine | Sejour Cuisine | B01
Obj.-027 | rdc | 440 | 0.211011 | 450 | 0.0143427 | 479.571 | 3000 | 2.22045e-12 | 0.948533 | 3780 | 780 | 3000 | 2.22045e-12 | 2220345 | -639218 | 269.969 | C10 | Obj.-027 | MOBILIER | Chaise 1 65 | Brique 1 | rdc | 3 | Métal-Inox; Surface-Plastique stratifié | Sejour cuisine | Sejour cuisine | B02
Obj.-027 | rdc | 440 | 0.211011 | 450 | 0.0143427 | 479.571 | 3000 | 2.22045e-12 | 0.948533 | 3780 | 780 | 3000 | 2.22045e-12 | 2235841 | -615949 | 354.197 | C10 | Obj.-027 | MOBILIER | Chaise 1 65 | Brique 1 | rdc | 3 | Métal-Inox; Surface-Plastique stratifié | Sejour Cuisine/pl | Sejour Cuisine/pl | A04
Obj.-027 | rdc | 440 | 0.211011 | 450 | 0.0143427 | 479.571 | 3000 | 2.22045e-12 | 0.948533 | 3780 | 780 | 3000 | 2.22045e-12 | 2219937 | -639833 | 89.969 | C10 | Obj.-027 | MOBILIER | Chaise 1 65 | Brique 1 | rdc | 3 | Métal-Inox; Surface-Plastique stratifié | Sejour cuisine | Sejour cuisine | B02
Obj.-026 | rdc | 1144.92 | 1.03042 | 730 | 0.0242125 | 900 | 3000 | 2.22045e-12 | 2.93436 | 3730 | 730 | 3000 | 2.22045e-12 | 2219691 | -625971 | 270.031 | C10 | Obj.-026 | MOBILIER | al_table Sting | Brique 1 | rdc | 3 | Métal-Inox; Surface-Peinture brillante; Divers-Glace | Sejour Cuisine | Sejour Cuisine | B01
Obj.-034 | rdc | 800 | 0.64 | 360 | 0.280139 | 800 | 3025 | 25 | 4.69089 | 3691.7 | 691.7 | 3025 | 25 | 2235168 | -617828 | 354.197 | Revêt. pilier rond | Obj.-034 | 0-Resille Dampere | Fauteuil 65 | Brique 1 | rdc | 3 | Plancher-Moquette; Revêt. pilier rond | Sejour Cuisine/pl | Sejour Cuisine/pl | A04
Obj.-027 | rdc | 440 | 0.211011 | 450 | 0.0143427 | 479.571 | 3000 | 2.22045e-12 | 0.948533 | 3780 | 780 | 3000 | 2.22045e-12 | 2235800 | -616355 | 174.197 | C10 | Obj.-027 | MOBILIER | Chaise 1 65 | Brique 1 | rdc | 3 | Métal-Inox; Surface-Plastique stratifié | Sejour Cuisine/pl | Sejour Cuisine/pl | A04
Obj.-027 | rdc | 440 | 0.211011 | 450 | 0.0143427 | 479.571 | 3000 | 2.22045e-12 | 0.948533 | 3780 | 780 | 3000 | 2.22045e-12 | 2225988 | -654823 | 269.995 | C10 | Obj.-027 | MOBILIER | Chaise 1 65 | Brique 1 | rdc | 3 | Métal-Inox; Surface-Plastique stratifié | Sejour cuisine/pl | Sejour cuisine/pl | B04
Obj.-027 | rdc | 440 | 0.211011 | 450 | 0.0143427 | 479.571 | 3000 | 2.22045e-12 | 0.948533 | 3780 | 780 | 3000 | 2.22045e-12 | 2223119 | -653369 | 269.995 | C10 | Obj.-027 | MOBILIER | Chaise 1 65 | Brique 1 | rdc | 3 | Métal-Inox; Surface-Plastique stratifié | Sejour cuisine | Sejour cuisine | B03
Obj.-027 | rdc | 440 | 0.211011 | 450 | 0.0143427 | 479.571 | 3000 | 2.22045e-12 | 0.948533 | 3780 | 780 | 3000 | 2.22045e-12 | 2222711 | -653369 | 89.9951 | C10 | Obj.-027 | MOBILIER | Chaise 1 65 | Brique 1 | rdc | 3 | Métal-Inox; Surface-Plastique stratifié | Sejour cuisine | Sejour cuisine | B03
Obj.-026 | rdc | 1200 | 1.08 | 730 | 0.0252536 | 900 | 3000 | 2.22045e-12 | 3.05224 | 3730 | 730 | 3000 | 2.22045e-12 | 2219791 | -639238 | 269.969 | C10 | Obj.-026 | MOBILIER | al_table Sting | Brique 1 | rdc | 3 | Métal-Inox; Surface-Peinture brillante; Divers-Glace | Sejour cuisine | Sejour cuisine | B02
Obj.-034 | rdc | 800 | 0.64 | 360 | 0.280139 | 800 | 3800 | 800 | 4.69089 | 4466.7 | 1466.7 | 3800 | 800 | 2231855 | -638726 | 179.964 | Revêt. pilier rond | Obj.-034 | 0-Resille Dampere | Fauteuil 65 | Brique 1 | rdc | 3 | Plancher-Moquette; Revêt. pilier rond | Sejour cuisine | Sejour cuisine | B05
Obj.-002 | rdc | 1800 | 1.44 | 600 | 0.0995281 | 800 | 3000 | 0 | 10.3313 | 3600 | 600 | 3000 | 0 | 2223332 | -644939 | 270 | Revêt. pilier rond | Obj.-002 | SANITAIRE | Baignoire 65 | Brique 1 | rdc | 3 | Surface-Ceramiques vitrifiées | Sdb | Sdb | B03
Obj.-026 | rdc | 1200 | 1.08 | 730 | 0.0252536 | 900 | 3000 | 2.22045e-12 | 3.05224 | 3730 | 730 | 3000 | 2.22045e-12 | 2235876 | -615806 | 174.197 | C10 | Obj.-026 | MOBILIER | al_table Sting | Brique 1 | rdc | 3 | Métal-Inox; Surface-Peinture brillante; Divers-Glace | Sejour Cuisine/pl | Sejour Cuisine/pl | A04
Obj.-027 | rdc | 440 | 0.211011 | 450 | 0.0143427 | 479.571 | 3000 | 2.22045e-12 | 0.948533 | 3780 | 780 | 3000 | 2.22045e-12 | 2236412 | -616418 | 174.197 | C10 | Obj.-027 | MOBILIER | Chaise 1 65 | Brique 1 | rdc | 3 | Métal-Inox; Surface-Plastique stratifié | Sejour Cuisine/pl | Sejour Cuisine/pl | A04
Obj.-027 | rdc | 440 | 0.211011 | 450 | 0.0143427 | 479.571 | 3000 | 2.22045e-12 | 0.948533 | 3780 | 780 | 3000 | 2.22045e-12 | 2219937 | -639218 | 89.969 | C10 | Obj.-027 | MOBILIER | Chaise 1 65 | Brique 1 | rdc | 3 | Métal-Inox; Surface-Plastique stratifié | Sejour cuisine | Sejour cuisine | B02
Obj.-034 | rdc | 800 | 0.64 | 360 | 0.280139 | 800 | 3000 | 1.95399e-11 | 4.69089 | 3666.7 | 666.7 | 3000 | 1.95399e-11 | 2222793 | -655255 | 0 | Revêt. pilier rond | Obj.-034 | 0-Resille Dampere | Fauteuil 65 | Brique 1 | rdc | 3 | Plancher-Moquette; Revêt. pilier rond | Sejour cuisine | Sejour cuisine | B03
Obj.-027 | rdc | 440 | 0.211011 | 450 | 0.0143427 | 479.571 | 3000 | 2.22045e-12 | 0.948533 | 3780 | 780 | 3000 | 2.22045e-12 | 2231483 | -617029 | 84.2265 | C10 | Obj.-027 | MOBILIER | Chaise 1 65 | Brique 1 | rdc | 3 | Métal-Inox; Surface-Plastique stratifié | Sejour cuisine | Sejour cuisine | A03
Obj.-019 | rdc | 600 | 0.36 | 900 | 0.314148 | 600 | 3000 | 0 | 4.5196 | 3900 | 900 | 3000 | 0 | 2238279 | -615670 | 264.23 | Revêt. pilier rond | Obj.-019 | SANITAIRE | Réfrigérateur haut 65 | Brique 1 | rdc | 3 | Métal-Chrome; Surface-Lavis Blanc | Sejour Cuisine/pl | Sejour Cuisine/pl | A04
Obj.-019 | rdc | 600 | 0.36 | 900 | 0.314148 | 600 | 3000 | 0 | 4.5196 | 3900 | 900 | 3000 | 0 | 2224132 | -623871 | 90 | Revêt. pilier rond | Obj.-019 | SANITAIRE | Réfrigérateur haut 65 | Brique 1 | rdc | 3 | Métal-Chrome; Surface-Lavis Blanc | Sejour Cuisine | Sejour Cuisine | B01
Obj.-003 | rdc | 1400 | 2.66 | 400 | 0.566521 | 1900 | 3000 | 0 | 14.0446 | 3493.34 | 493.337 | 3000 | 0 | 2218719 | -632614 | 360 | C10 | Obj.-003 | SANITAIRE | Lit double_70 | Brique 1 | rdc | 3 | Poteaux | Ch 1/pl | Ch 1/pl | B02
Obj.-026 | rdc | 788.112 | 0.709301 | 730 | 0.0174689 | 900 | 3000 | 2.22045e-12 | 2.1708 | 3730 | 730 | 3000 | 2.22045e-12 | 2231347 | -616918 | 264.227 | C10 | Obj.-026 | MOBILIER | al_table Sting | Brique 1 | rdc | 3 | Métal-Inox; Surface-Peinture brillante; Divers-Glace | Sejour cuisine | Sejour cuisine | A03
Obj.-027 | rdc | 440 | 0.211011 | 450 | 0.0143427 | 479.571 | 3000 | 2.22045e-12 | 0.948533 | 3780 | 780 | 3000 | 2.22045e-12 | 2230043 | -639286 | 269.995 | C10 | Obj.-027 | MOBILIER | Chaise 1 65 | Brique 1 | rdc | 3 | Métal-Inox; Surface-Plastique stratifié | Sejour cuisine | Sejour cuisine | B05
Obj.-027 | rdc | 440 | 0.211011 | 450 | 0.0143427 | 479.571 | 3000 | 2.22045e-12 | 0.948533 | 3780 | 780 | 3000 | 2.22045e-12 | 2222711 | -652754 | 89.9951 | C10 | Obj.-027 | MOBILIER | Chaise 1 65 | Brique 1 | rdc | 3 | Métal-Inox; Surface-Plastique stratifié | Sejour cuisine | Sejour cuisine | B03
Obj.-026 | rdc | 1200 | 1.08 | 730 | 0.0252536 | 900 | 3000 | 2.22045e-12 | 3.05224 | 3730 | 730 | 3000 | 2.22045e-12 | 2230189 | -638691 | 89.9951 | C10 | Obj.-026 | MOBILIER | al_table Sting | Brique 1 | rdc | 3 | Métal-Inox; Surface-Peinture brillante; Divers-Glace | Sejour cuisine | Sejour cuisine | B05
Obj.-019 | rdc | 600 | 0.36 | 900 | 0.314148 | 600 | 3000 | 0 | 4.5196 | 3900 | 900 | 3000 | 0 | 2217646 | -653013 | 0.141506 | Revêt. pilier rond | Obj.-019 | SANITAIRE | Réfrigérateur haut 65 | Brique 1 | rdc | 3 | Métal-Chrome; Surface-Lavis Blanc | Sejour cuisine | Sejour cuisine | B03
Obj.-019 | rdc | 600 | 0.36 | 900 | 0.314148 | 600 | 3000 | 0 | 4.5196 | 3900 | 900 | 3000 | 0 | 2228229 | -638115 | 359.964 | Revêt. pilier rond | Obj.-019 | SANITAIRE | Réfrigérateur haut 65 | Brique 1 | rdc | 3 | Métal-Chrome; Surface-Lavis Blanc | Sejour cuisine | Sejour cuisine | B05
Obj.-027 | rdc | 440 | 0.211011 | 450 | 0.0143427 | 479.571 | 3000 | 2.22045e-12 | 0.948533 | 3780 | 780 | 3000 | 2.22045e-12 | 2220345 | -639833 | 269.969 | C10 | Obj.-027 | MOBILIER | Chaise 1 65 | Brique 1 | rdc | 3 | Métal-Inox; Surface-Plastique stratifié | Sejour cuisine | Sejour cuisine | B02
Obj.-003 | rdc | 1400 | 2.66 | 400 | 0.566521 | 1900 | 3000 | 0 | 14.0446 | 3493.34 | 493.337 | 3000 | 0 | 2230817 | -646738 | 180 | C10 | Obj.-003 | SANITAIRE | Lit double_70 | Brique 1 | rdc | 3 | Bois-Pin; Plancher-Moquette | Ch 1 | Ch 1 | B05
Obj.-019 | rdc | 600 | 0.36 | 900 | 0.314148 | 600 | 3000 | 0 | 4.5196 | 3900 | 900 | 3000 | 0 | 2229379 | -616664 | 84.1958 | Revêt. pilier rond | Obj.-019 | SANITAIRE | Réfrigérateur haut 65 | Brique 1 | rdc | 3 | Métal-Chrome; Surface-Lavis Blanc | Sejour cuisine | Sejour cuisine | A03
Obj.-003 | rdc | 1400 | 2.66 | 400 | 0.566521 | 1900 | 3000 | 0 | 14.0446 | 3493.34 | 493.337 | 3000 | 0 | 2231518 | -649903 | 180.005 | C10 | Obj.-003 | SANITAIRE | Lit double_70 | Brique 1 | rdc | 3 | Poteaux | Ch 1/pl | Ch 1/pl | B04
Obj.-034 | rdc | 3099.81 | 0.464972 | 2500 | 0.0599986 | 150 | 3000 | 1.42109e-11 | 10.0679 | 5500 | 2500 | 3000 | 1.42109e-11 | 2224338 | -660918 | 90 | Revêt. pilier rond | Obj.-034 | 0-Resille Dampere | Barrière vitrée 65 | Brique 1 | rdc | 3 | Divers-Eau; Peinture-05 | Terrasse
Obj.-003 | rdc | 1400 | 2.66 | 400 | 0.566521 | 1900 | 3000 | 0 | 14.0446 | 3493.34 | 493.337 | 3000 | 0 | 2218835 | -611027 | 354.293 | C10 | Obj.-003 | SANITAIRE | Lit double_70 | Brique 1 | rdc | 3 | Bois-Pin; Plancher-Moquette | Ch 1 | Ch 1 | A02
Obj.-003 | rdc | 1400 | 2.66 | 400 | 0.566521 | 1900 | 3000 | 0 | 14.0446 | 3493.34 | 493.337 | 3000 | 0 | 2218566 | -610820 | 174.104 | C10 | Obj.-003 | SANITAIRE | Lit double_70 | Brique 1 | rdc | 3 | Bois-Pin; Plancher-Moquette | Ch 1 | Ch 1 | A01
Obj.-003 | rdc | 1400 | 2.66 | 400 | 0.566521 | 1900 | 3000 | 0 | 14.0446 | 3493.34 | 493.337 | 3000 | 0 | 2239584 | -608777 | 264.197 | C10 | Obj.-003 | SANITAIRE | Lit double_70 | Brique 1 | rdc | 3 | Bois-Pin; Plancher-Moquette | Ch 1 | Ch 1 | A04
Obj.-003 | rdc | 1400 | 2.66 | 400 | 0.566521 | 1900 | 3000 | 0 | 14.0446 | 3493.34 | 493.337 | 3000 | 0 | 2219041 | -632434 | 180 | C10 | Obj.-003 | SANITAIRE | Lit double_70 | Brique 1 | rdc | 3 | Bois-Pin; Plancher-Moquette | Ch 1 | Ch 1 | B01
Obj.-003 | rdc | 1400 | 2.66 | 400 | 0.566521 | 1900 | 3000 | 0 | 14.0446 | 3493.34 | 493.337 | 3000 | 0 | 2226486 | -618956 | 84.1973 | C10 | Obj.-003 | SANITAIRE | Lit double_70 | Brique 1 | rdc | 3 | Poutre; Revêt. sol | Ch 1 | Ch 1 | A03
Obj.-026 | rdc | 1200 | 1.08 | 730 | 0.0252536 | 900 | 3000 | 2.22045e-12 | 3.05224 | 3730 | 730 | 3000 | 2.22045e-12 | 2226135 | -654843 | 89.9951 | C10 | Obj.-026 | MOBILIER | al_table Sting | Brique 1 | rdc | 3 | Métal-Inox; Surface-Peinture brillante; Divers-Glace | Sejour cuisine/pl | Sejour cuisine/pl | B04
Obj.-047 | rdc | 1329.38 | 1.32938 | 1000 | 0.00703801 | 1000 | 1100 | -1900 | 0.703801 | 2100 | -900 | 1150 | -1850 | 2248075 | -667063 | 182.045 | Revêt. pilier rond | Obj.-047 | MOBILIER | Cadre solide_70 | Brique 1 | rdc | 3 | Surface-Porcelaine
Obj.-027 | rdc | 440 | 0.211011 | 450 | 0.0143427 | 479.571 | 3000 | 2.22045e-12 | 0.948533 | 3780 | 780 | 3000 | 2.22045e-12 | 2225988 | -655438 | 269.995 | C10 | Obj.-027 | MOBILIER | Chaise 1 65 | Brique 1 | rdc | 3 | Métal-Inox; Surface-Plastique stratifié | Sejour cuisine/pl | Sejour cuisine/pl | B04
Obj.-034 | rdc | 1210.87 | 0.18163 | 2500 | 0.0458315 | 150 | 3000 | 1.42109e-11 | 4.87329 | 5500 | 2500 | 3000 | 1.42109e-11 | 2216932 | -620794 | 353.229 | Revêt. pilier rond | Obj.-034 | 0-Resille Dampere | Barrière vitrée 65 | Brique 1 | rdc | 3 | Divers-Eau; Peinture-05 | Terrasse; Terrasse
Obj.-027 | rdc | 440 | 0.211011 | 450 | 0.0143427 | 479.571 | 3000 | 2.22045e-12 | 0.948533 | 3780 | 780 | 3000 | 2.22045e-12 | 2225580 | -655438 | 89.9951 | C10 | Obj.-027 | MOBILIER | Chaise 1 65 | Brique 1 | rdc | 3 | Métal-Inox; Surface-Plastique stratifié | Sejour cuisine/pl | Sejour cuisine/pl | B04
Obj.-034 | rdc | 800 | 0.64 | 360 | 0.280139 | 800 | 3000 | 1.95399e-11 | 4.69089 | 3666.7 | 666.7 | 3000 | 1.95399e-11 | 2230758 | -654992 | 0 | Revêt. pilier rond | Obj.-034 | 0-Resille Dampere | Fauteuil 65 | Brique 1 | rdc | 3 | Plancher-Moquette; Revêt. pilier rond | Sejour cuisine/pl | Sejour cuisine/pl | B04
Obj.-019 | rdc | 600 | 0.36 | 900 | 0.314148 | 600 | 3000 | 0 | 4.5196 | 3900 | 900 | 3000 | 0 | 2231705 | -653016 | 359.849 | Revêt. pilier rond | Obj.-019 | SANITAIRE | Réfrigérateur haut 65 | Brique 1 | rdc | 3 | Métal-Chrome; Surface-Lavis Blanc | Sejour cuisine/pl | Sejour cuisine/pl | B04
Obj.-019 | rdc | 50 | 0.00496755 | 1000 | 0.0000520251 | 99.3509 | 3000 | 0 | 0.0142858 | 3063 | 63 | 3000 | 0 | 2230639 | -607185 | 173.752 | Revêt. pilier rond | Obj.-019 | SANITAIRE | Robinet 3 65 | Brique 1 | rdc | 3 | Métal-Chrome | Pl | Pl | 678
Obj.-019 | rdc | 50 | 0.00496755 | 1000 | 0.0000520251 | 99.3509 | 3000 | 0 | 0.0142858 | 3063 | 63 | 3000 | 0 | 2226278 | -629352 | 179.858 | Revêt. pilier rond | Obj.-019 | SANITAIRE | Robinet 3 65 | Brique 1 | rdc | 3 | Métal-Chrome | Pl | Pl | 819
Obj.-027 | rdc | 440 | 0.211011 | 450 | 0.0143427 | 479.571 | 3000 | 2.22045e-12 | 0.948533 | 3780 | 780 | 3000 | 2.22045e-12 | 2225580 | -654823 | 89.9951 | C10 | Obj.-027 | MOBILIER | Chaise 1 65 | Brique 1 | rdc | 3 | Métal-Inox; Surface-Plastique stratifié | Sejour cuisine/pl | Sejour cuisine/pl | B04
Obj.-047 | rdc | 1410.34 | 1.41034 | 1000 | 0.00729708 | 1000 | 1100 | -1900 | 0.729708 | 2100 | -900 | 1150 | -1850 | 2243186 | -667238 | 182.045 | Revêt. pilier rond | Obj.-047 | MOBILIER | Cadre solide_70 | Brique 1 | rdc | 3 | Surface-Porcelaine
Obj.-019 | rdc | 600 | 0.36 | 900 | 0.314148 | 600 | 3000 | 0 | 4.5196 | 3900 | 900 | 3000 | 0 | 2224415 | -621199 | 354.165 | Revêt. pilier rond | Obj.-019 | SANITAIRE | Réfrigérateur haut 65 | Brique 1 | rdc | 3 | Métal-Chrome; Surface-Lavis Blanc | Sejour Cuisine | Sejour Cuisine | A02
Obj.-047 | rdc | 415.054 | 0.415054 | 1000 | 0.00411217 | 1000 | 1100 | -1900 | 0.411217 | 2100 | -900 | 1150 | -1850 | 2254701 | -666826 | 182.045 | Revêt. pilier rond | Obj.-047 | MOBILIER | Cadre solide_70 | Brique 1 | rdc | 3 | Surface-Porcelaine
Obj.-047 | rdc | 2441.93 | 2.44193 | 1000 | 0.0105982 | 1000 | 1100 | -1900 | 1.05982 | 2100 | -900 | 1150 | -1850 | 2252868 | -666892 | 182.045 | Revêt. pilier rond | Obj.-047 | MOBILIER | Cadre solide_70 | Brique 1 | rdc | 3 | Surface-Porcelaine
Obj.-047 | rdc | 3467.36 | 3.46736 | 1200 | 0.0145196 | 1000 | 900 | -2100 | 1.45196 | 2100 | -900 | 950 | -2050 | 2246672 | -667031 | 182.045 | Revêt. pilier rond | Obj.-047 | MOBILIER | Cadre solide_70 | Brique 1 | rdc | 3 | Surface-Porcelaine
Obj.-047 | rdc | 2294.47 | 2.29447 | 1000 | 0.0101263 | 1000 | 1100 | -1900 | 1.01263 | 2100 | -900 | 1150 | -1850 | 2241747 | -667289 | 182.045 | Revêt. pilier rond | Obj.-047 | MOBILIER | Cadre solide_70 | Brique 1 | rdc | 3 | Surface-Porcelaine
Obj.-047 | rdc | 2294.47 | 2.29447 | 1000 | 0.0101263 | 1000 | 1100 | -1900 | 1.01263 | 2100 | -900 | 1150 | -1850 | 2239424 | -667372 | 182.045 | Revêt. pilier rond | Obj.-047 | MOBILIER | Cadre solide_70 | Brique 1 | rdc | 3 | Surface-Porcelaine
Obj.-047 | rdc | 2294.47 | 2.29447 | 1000 | 0.0101263 | 1000 | 1100 | -1900 | 1.01263 | 2100 | -900 | 1150 | -1850 | 2237101 | -667455 | 182.045 | Revêt. pilier rond | Obj.-047 | MOBILIER | Cadre solide_70 | Brique 1 | rdc | 3 | Surface-Porcelaine
Obj.-047 | rdc | 2294.47 | 2.29447 | 1000 | 0.0101263 | 1000 | 1100 | -1900 | 1.01263 | 2100 | -900 | 1150 | -1850 | 2234778 | -667538 | 182.045 | Revêt. pilier rond | Obj.-047 | MOBILIER | Cadre solide_70 | Brique 1 | rdc | 3 | Surface-Porcelaine
Obj.-047 | rdc | 359.005 | 0.359005 | 1166.16 | 0.00446454 | 1000 | 933.838 | -2066.16 | 0.446454 | 2100 | -900 | 983.838 | -2016.16 | 2254256 | -666840 | 182.045 | Revêt. pilier rond | Obj.-047 | MOBILIER | Cadre solide_70 | Brique 1 | rdc | 3 | Surface-Porcelaine
Obj.-047 | rdc | 2294.47 | 2.29447 | 1000 | 0.0101263 | 1000 | 1100 | -1900 | 1.01263 | 2100 | -900 | 1150 | -1850 | 2250398 | -666980 | 182.045 | Revêt. pilier rond | Obj.-047 | MOBILIER | Cadre solide_70 | Brique 1 | rdc | 3 | Surface-Porcelaine
Obj.-047 | rdc | 1000 | 1 | 1166.16 | 0.00651572 | 1000 | 933.838 | -2066.16 | 0.651572 | 2100 | -900 | 983.838 | -2016.16 | 2253897 | -666853 | 182.045 | Revêt. pilier rond | Obj.-047 | MOBILIER | Cadre solide_70 | Brique 1 | rdc | 3 | Surface-Porcelaine
Obj.-047 | rdc | 2294.47 | 2.29447 | 1000 | 0.0101263 | 1000 | 3200 | 200 | 1.01263 | 4200 | 1200 | 3250 | 250 | 2242480 | -606620 | 174.197 | Revêt. pilier rond | Obj.-047 | MOBILIER | Cadre solide_70 | Brique 1 | rdc | 3 | Surface-Porcelaine
Obj.-047 | rdc | 2294.47 | 2.29447 | 1000 | 0.0101263 | 1000 | 3200 | 200 | 1.01263 | 4200 | 1200 | 3250 | 250 | 2244793 | -606855 | 174.197 | Revêt. pilier rond | Obj.-047 | MOBILIER | Cadre solide_70 | Brique 1 | rdc | 3 | Surface-Porcelaine
Obj.-047 | rdc | 2294.47 | 2.29447 | 1000 | 0.0101263 | 1000 | 3200 | 200 | 1.01263 | 4200 | 1200 | 3250 | 250 | 2247105 | -607090 | 174.197 | Revêt. pilier rond | Obj.-047 | MOBILIER | Cadre solide_70 | Brique 1 | rdc | 3 | Surface-Porcelaine
Obj.-047 | rdc | 1406.6 | 1.4066 | 1000 | 0.00728511 | 1000 | 3200 | 200 | 0.728511 | 4200 | 1200 | 3250 | 250 | 2248535 | -607236 | 174.197 | Revêt. pilier rond | Obj.-047 | MOBILIER | Cadre solide_70 | Brique 1 | rdc | 3 | Surface-Porcelaine
Obj.-047 | rdc | 1056.65 | 1.05665 | 1000 | 0.00616529 | 1000 | 3200 | 200 | 0.616529 | 4200 | 1200 | 3250 | 250 | 2251138 | -607500 | 174.197 | Revêt. pilier rond | Obj.-047 | MOBILIER | Cadre solide_70 | Brique 1 | rdc | 3 | Surface-Porcelaine
Obj.-047 | rdc | 730 | 0.73 | 1600 | 0.00704 | 1000 | 2600 | -400 | 0.704 | 4200 | 1200 | 2650 | -350 | 2249559 | -607340 | 174.197 | Revêt. pilier rond | Obj.-047 | MOBILIER | Cadre solide_70 | Brique 1 | rdc | 3 | Surface-Porcelaine
Obj.-047 | rdc | 500 | 0.5 | 1600 | 0.006304 | 1000 | 2600 | -400 | 0.6304 | 4200 | 1200 | 2650 | -350 | 2250057 | -607390 | 174.197 | Revêt. pilier rond | Obj.-047 | MOBILIER | Cadre solide_70 | Brique 1 | rdc | 3 | Surface-Porcelaine
Obj.-047 | rdc | 2294.47 | 2.29447 | 1000 | 0.0101263 | 1000 | 1100 | -1900 | 1.01263 | 2100 | -900 | 1150 | -1850 | 2216194 | -668201 | 182.045 | Revêt. pilier rond | Obj.-047 | MOBILIER | Cadre solide_70 | Brique 1 | rdc | 3 | Surface-Porcelaine
Obj.-047 | rdc | 2294.47 | 2.29447 | 1000 | 0.0101263 | 1000 | 1100 | -1900 | 1.01263 | 2100 | -900 | 1150 | -1850 | 2218517 | -668118 | 182.045 | Revêt. pilier rond | Obj.-047 | MOBILIER | Cadre solide_70 | Brique 1 | rdc | 3 | Surface-Porcelaine
Obj.-047 | rdc | 2294.47 | 2.29447 | 1000 | 0.0101263 | 1000 | 1100 | -1900 | 1.01263 | 2100 | -900 | 1150 | -1850 | 2220840 | -668035 | 182.045 | Revêt. pilier rond | Obj.-047 | MOBILIER | Cadre solide_70 | Brique 1 | rdc | 3 | Surface-Porcelaine
Obj.-047 | rdc | 2294.47 | 2.29447 | 1000 | 0.0101263 | 1000 | 1100 | -1900 | 1.01263 | 2100 | -900 | 1150 | -1850 | 2223163 | -667952 | 182.045 | Revêt. pilier rond | Obj.-047 | MOBILIER | Cadre solide_70 | Brique 1 | rdc | 3 | Surface-Porcelaine
Obj.-047 | rdc | 2294.47 | 2.29447 | 1000 | 0.0101263 | 1000 | 1100 | -1900 | 1.01263 | 2100 | -900 | 1150 | -1850 | 2225486 | -667870 | 182.045 | Revêt. pilier rond | Obj.-047 | MOBILIER | Cadre solide_70 | Brique 1 | rdc | 3 | Surface-Porcelaine
Obj.-047 | rdc | 2294.47 | 2.29447 | 1000 | 0.0101263 | 1000 | 1100 | -1900 | 1.01263 | 2100 | -900 | 1150 | -1850 | 2227809 | -667787 | 182.045 | Revêt. pilier rond | Obj.-047 | MOBILIER | Cadre solide_70 | Brique 1 | rdc | 3 | Surface-Porcelaine
Obj.-047 | rdc | 2294.47 | 2.29447 | 1000 | 0.0101263 | 1000 | 1100 | -1900 | 1.01263 | 2100 | -900 | 1150 | -1850 | 2230132 | -667704 | 182.045 | Revêt. pilier rond | Obj.-047 | MOBILIER | Cadre solide_70 | Brique 1 | rdc | 3 | Surface-Porcelaine
Obj.-047 | rdc | 2294.47 | 2.29447 | 1000 | 0.0101263 | 1000 | 1100 | -1900 | 1.01263 | 2100 | -900 | 1150 | -1850 | 2232455 | -667621 | 182.045 | Revêt. pilier rond | Obj.-047 | MOBILIER | Cadre solide_70 | Brique 1 | rdc | 3 | Surface-Porcelaine
Obj.-003 | Etage1 | 1400 | 2.66 | 400 | 0.566521 | 1900 | 5750 | 0 | 14.0446 | 6243.34 | 493.337 | 5750 | 0 | 2236768 | -608491 | 84.1973 | C10 | Obj.-003 | SANITAIRE | Lit double_70 | Brique 1 | Etage1 | 4 | Bois-Pin; Plancher-Moquette | Ch 1 | Ch 1 | A14
Obj.-027 | Etage1 | 440 | 0.211011 | 450 | 0.0143427 | 479.571 | 5750 | 1.77636e-12 | 0.948533 | 6530 | 780 | 5750 | 1.77636e-12 | 2236691 | -616614 | 174.197 | C10 | Obj.-027 | MOBILIER | Chaise 1 65 | Brique 1 | Etage1 | 4 | Métal-Inox; Surface-Plastique stratifié | Sejour Cuisine/pl | Sejour Cuisine/pl | A14
Obj.-026 | Etage1 | 1200 | 1.08 | 730 | 0.0252536 | 900 | 5750 | 1.77636e-12 | 3.05224 | 6480 | 730 | 5750 | 1.77636e-12 | 2219691 | -625971 | 270.031 | C10 | Obj.-026 | MOBILIER | al_table Sting | Brique 1 | Etage1 | 4 | Métal-Inox; Surface-Peinture brillante; Divers-Glace | Sejour cuisine | Sejour cuisine | B12
Obj.-027 | Etage1 | 440 | 0.211011 | 450 | 0.0143427 | 479.571 | 5750 | 1.77636e-12 | 0.948533 | 6530 | 780 | 5750 | 1.77636e-12 | 2219937 | -640106 | 89.969 | C10 | Obj.-027 | MOBILIER | Chaise 1 65 | Brique 1 | Etage1 | 4 | Métal-Inox; Surface-Plastique stratifié | Sejour Cuisine | Sejour Cuisine | B13
Obj.-027 | Etage1 | 440 | 0.211011 | 450 | 0.0143427 | 479.571 | 5750 | 1.77636e-12 | 0.948533 | 6530 | 780 | 5750 | 1.77636e-12 | 2220245 | -625376 | 270.031 | C10 | Obj.-027 | MOBILIER | Chaise 1 65 | Brique 1 | Etage1 | 4 | Métal-Inox; Surface-Plastique stratifié | Sejour cuisine | Sejour cuisine | B12
Obj.-027 | Etage1 | 440 | 0.211011 | 450 | 0.0143427 | 479.571 | 5750 | 1.77636e-12 | 0.948533 | 6530 | 780 | 5750 | 1.77636e-12 | 2219837 | -625991 | 90.031 | C10 | Obj.-027 | MOBILIER | Chaise 1 65 | Brique 1 | Etage1 | 4 | Métal-Inox; Surface-Plastique stratifié | Sejour cuisine | Sejour cuisine | B12
Obj.-027 | Etage1 | 440 | 0.211011 | 450 | 0.0143427 | 479.571 | 5750 | 1.77636e-12 | 0.948533 | 6530 | 780 | 5750 | 1.77636e-12 | 2219937 | -639490 | 89.969 | C10 | Obj.-027 | MOBILIER | Chaise 1 65 | Brique 1 | Etage1 | 4 | Métal-Inox; Surface-Plastique stratifié | Sejour Cuisine | Sejour Cuisine | B13
Obj.-034 | Etage1 | 800 | 0.64 | 360 | 0.280139 | 800 | 6550 | 800 | 4.69089 | 7216.7 | 1466.7 | 6550 | 800 | 2221923 | -642912 | 269.964 | Revêt. pilier rond | Obj.-034 | 0-Resille Dampere | Fauteuil 65 | Brique 1 | Etage1 | 4 | Plancher-Moquette; Revêt. pilier rond | Sejour Cuisine | Sejour Cuisine | B13
Obj.-026 | Etage1 | 1200 | 1.08 | 730 | 0.0252536 | 900 | 5750 | 1.77636e-12 | 3.05224 | 6480 | 730 | 5750 | 1.77636e-12 | 2236155 | -616002 | 174.197 | C10 | Obj.-026 | MOBILIER | al_table Sting | Brique 1 | Etage1 | 4 | Métal-Inox; Surface-Peinture brillante; Divers-Glace | Sejour Cuisine/pl | Sejour Cuisine/pl | A14
Obj.-027 | Etage1 | 440 | 0.211011 | 450 | 0.0143427 | 479.571 | 5750 | 1.77636e-12 | 0.948533 | 6530 | 780 | 5750 | 1.77636e-12 | 2236079 | -616552 | 174.197 | C10 | Obj.-027 | MOBILIER | Chaise 1 65 | Brique 1 | Etage1 | 4 | Métal-Inox; Surface-Plastique stratifié | Sejour Cuisine/pl | Sejour Cuisine/pl | A14
Obj.-027 | Etage1 | 440 | 0.211011 | 450 | 0.0143427 | 479.571 | 5750 | 1.77636e-12 | 0.948533 | 6530 | 780 | 5750 | 1.77636e-12 | 2220345 | -639491 | 269.969 | C10 | Obj.-027 | MOBILIER | Chaise 1 65 | Brique 1 | Etage1 | 4 | Métal-Inox; Surface-Plastique stratifié | Sejour Cuisine | Sejour Cuisine | B13
Obj.-027 | Etage1 | 440 | 0.211011 | 450 | 0.0143427 | 479.571 | 5750 | 1.77636e-12 | 0.948533 | 6530 | 780 | 5750 | 1.77636e-12 | 2236733 | -616208 | 354.197 | C10 | Obj.-027 | MOBILIER | Chaise 1 65 | Brique 1 | Etage1 | 4 | Métal-Inox; Surface-Plastique stratifié | Sejour Cuisine/pl | Sejour Cuisine/pl | A14
Obj.-019 | Etage1 | 600 | 0.36 | 900 | 0.314148 | 600 | 5750 | 0 | 4.5196 | 6650 | 900 | 5750 | 0 | 2226492 | -631658 | 90 | Revêt. pilier rond | Obj.-019 | SANITAIRE | Réfrigérateur haut 65 | Brique 1 | Etage1 | 4 | Métal-Chrome; Surface-Lavis Blanc | Sejour cuisine | Sejour cuisine | B11
Obj.-027 | Etage1 | 440 | 0.211011 | 450 | 0.0143427 | 479.571 | 5750 | 1.77636e-12 | 0.948533 | 6530 | 780 | 5750 | 1.77636e-12 | 2220345 | -640106 | 269.969 | C10 | Obj.-027 | MOBILIER | Chaise 1 65 | Brique 1 | Etage1 | 4 | Métal-Inox; Surface-Plastique stratifié | Sejour Cuisine | Sejour Cuisine | B13
Obj.-003 | Etage1 | 1400 | 2.66 | 400 | 0.566521 | 1900 | 5750 | 0 | 14.0446 | 6243.34 | 493.337 | 5750 | 0 | 2226990 | -622043 | 354.2 | C10 | Obj.-003 | SANITAIRE | Lit double_70 | Brique 1 | Etage1 | 4 | Poutre; Revêt. sol | Ch 1 | Ch 1 | B11
Obj.-034 | Etage1 | 800 | 0.64 | 360 | 0.280139 | 800 | 6550 | 800 | 4.69089 | 7216.7 | 1466.7 | 6550 | 800 | 2221449 | -622536 | 264.197 | Revêt. pilier rond | Obj.-034 | 0-Resille Dampere | Fauteuil 65 | Brique 1 | Etage1 | 4 | Plancher-Moquette; Revêt. pilier rond | Sejour cuisine | Sejour cuisine | B12
Obj.-026 | Etage1 | 1200 | 1.08 | 730 | 0.0252536 | 900 | 5750 | 1.77636e-12 | 3.05224 | 6480 | 730 | 5750 | 1.77636e-12 | 2219791 | -639511 | 269.969 | C10 | Obj.-026 | MOBILIER | al_table Sting | Brique 1 | Etage1 | 4 | Métal-Inox; Surface-Peinture brillante; Divers-Glace | Sejour Cuisine | Sejour Cuisine | B13
Obj.-034 | Etage1 | 800 | 0.64 | 360 | 0.280139 | 800 | 5775 | 25 | 4.69089 | 6441.7 | 691.7 | 5775 | 25 | 2236717 | -618573 | 264.197 | Revêt. pilier rond | Obj.-034 | 0-Resille Dampere | Fauteuil 65 | Brique 1 | Etage1 | 4 | Plancher-Moquette; Revêt. pilier rond | Sejour Cuisine/pl | Sejour Cuisine/pl | A14
Obj.-019 | Etage1 | 600 | 0.36 | 900 | 0.314148 | 600 | 5750 | 0 | 4.5196 | 6650 | 900 | 5750 | 0 | 2218082 | -653016 | 0.141506 | Revêt. pilier rond | Obj.-019 | SANITAIRE | Réfrigérateur haut 65 | Brique 1 | Etage1 | 4 | Métal-Chrome; Surface-Lavis Blanc | Sejour cuisine | Sejour cuisine | B14
Obj.-027 | Etage1 | 440 | 0.211011 | 450 | 0.0143427 | 479.571 | 5750 | 1.77636e-12 | 0.948533 | 6530 | 780 | 5750 | 1.77636e-12 | 2228193 | -629331 | 3.05333e-13 | C10 | Obj.-027 | MOBILIER | Chaise 1 65 | Brique 1 | Etage1 | 4 | Métal-Inox; Surface-Plastique stratifié | Sejour cuisine | Sejour cuisine | B11
Obj.-034 | Etage1 | 800 | 0.64 | 360 | 0.280139 | 800 | 6550 | 800 | 4.69089 | 7216.7 | 1466.7 | 6550 | 800 | 2231719 | -638450 | 180.036 | Revêt. pilier rond | Obj.-034 | 0-Resille Dampere | Fauteuil 65 | Brique 1 | Etage1 | 4 | Plancher-Moquette; Revêt. pilier rond | Sejour cuisine | Sejour cuisine | B16
Obj.-026 | Etage1 | 1200 | 1.08 | 730 | 0.0252536 | 900 | 5750 | 1.77636e-12 | 3.05224 | 6480 | 730 | 5750 | 1.77636e-12 | 2230189 | -638691 | 89.9951 | C10 | Obj.-026 | MOBILIER | al_table Sting | Brique 1 | Etage1 | 4 | Métal-Inox; Surface-Peinture brillante; Divers-Glace | Sejour cuisine | Sejour cuisine | B16
Obj.-003 | Etage1 | 1400 | 2.66 | 400 | 0.566521 | 1900 | 5750 | 0 | 14.0446 | 6243.34 | 493.337 | 5750 | 0 | 2233953 | -608037 | 264.197 | C10 | Obj.-003 | SANITAIRE | Lit double_70 | Brique 1 | Etage1 | 4 | Bois-Pin; Plancher-Moquette | Ch 1 | Ch 1 | A15
Obj.-019 | Etage1 | 600 | 0.36 | 900 | 0.314148 | 600 | 5750 | 0 | 4.5196 | 6650 | 900 | 5750 | 0 | 2238281 | -615649 | 264.23 | Revêt. pilier rond | Obj.-019 | SANITAIRE | Réfrigérateur haut 65 | Brique 1 | Etage1 | 4 | Métal-Chrome; Surface-Lavis Blanc | Sejour Cuisine/pl | Sejour Cuisine/pl | A14
Obj.-003 | Etage1 | 1400 | 2.66 | 400 | 0.566521 | 1900 | 5750 | 0 | 14.0446 | 6243.34 | 493.337 | 5750 | 0 | 2218719 | -632614 | 360 | C10 | Obj.-003 | SANITAIRE | Lit double_70 | Brique 1 | Etage1 | 4 | Poteaux | Ch 1/pl | Ch 1/pl | B13
Obj.-027 | Etage1 | 440 | 0.211011 | 450 | 0.0143427 | 479.571 | 5750 | 1.77636e-12 | 0.948533 | 6530 | 780 | 5750 | 1.77636e-12 | 2236121 | -616146 | 354.197 | C10 | Obj.-027 | MOBILIER | Chaise 1 65 | Brique 1 | Etage1 | 4 | Métal-Inox; Surface-Plastique stratifié | Sejour Cuisine/pl | Sejour Cuisine/pl | A14
Obj.-027 | Etage1 | 440 | 0.211011 | 450 | 0.0143427 | 479.571 | 5750 | 1.77636e-12 | 0.948533 | 6530 | 780 | 5750 | 1.77636e-12 | 2222759 | -606136 | 84.2606 | C10 | Obj.-027 | MOBILIER | Chaise 1 65 | Brique 1 | Etage1 | 4 | Métal-Inox; Surface-Plastique stratifié | Sejour cuisine/pl | Sejour cuisine/pl | A11
Obj.-027 | Etage1 | 440 | 0.211011 | 450 | 0.0143427 | 479.571 | 5750 | 1.77636e-12 | 0.948533 | 6530 | 780 | 5750 | 1.77636e-12 | 2228808 | -629739 | 180 | C10 | Obj.-027 | MOBILIER | Chaise 1 65 | Brique 1 | Etage1 | 4 | Métal-Inox; Surface-Plastique stratifié | Sejour cuisine | Sejour cuisine | B11
Obj.-002 | Etage1 | 1800 | 1.44 | 600 | 0.0995281 | 800 | 5750 | 0 | 10.3313 | 6350 | 600 | 5750 | 0 | 2223332 | -646741 | 270 | Revêt. pilier rond | Obj.-002 | SANITAIRE | Baignoire 65 | Brique 1 | Etage1 | 4 | Surface-Ceramiques vitrifiées | Sde | Sde | B14
Obj.-003 | Etage1 | 900 | 1.71 | 400 | 0.364192 | 1900 | 5750 | 0 | 9.53161 | 6243.34 | 493.337 | 5750 | 0 | 2231212 | -649660 | 180.035 | C10 | Obj.-003 | SANITAIRE | Lit double_70 | Brique 1 | Etage1 | 4 | Bois-Pin; Plancher-Moquette | Ch 1/pl | Ch 1/pl | B15
Obj.-003 | Etage1 | 1400 | 2.66 | 400 | 0.566521 | 1900 | 5750 | 0 | 14.0446 | 6243.34 | 493.337 | 5750 | 0 | 2219226 | -644356 | 360 | C10 | Obj.-003 | SANITAIRE | Lit double_70 | Brique 1 | Etage1 | 4 | Bois-Pin; Plancher-Moquette | Ch 1/pl | Ch 1/pl | B14
Obj.-003 | Etage1 | 900 | 1.71 | 400 | 0.364192 | 1900 | 5750 | 0 | 9.53161 | 6243.34 | 493.337 | 5750 | 0 | 2218871 | -649991 | 359.95 | C10 | Obj.-003 | SANITAIRE | Lit double_70 | Brique 1 | Etage1 | 4 | Bois-Pin; Plancher-Moquette | Ch 3 | Ch 3 | B14
Obj.-003 | Etage1 | 900 | 1.71 | 400 | 0.364192 | 1900 | 5750 | 0 | 9.53161 | 6243.34 | 493.337 | 5750 | 0 | 2218839 | -649921 | 180.05 | C10 | Obj.-003 | SANITAIRE | Lit double_70 | Brique 1 | Etage1 | 4 | Bois-Pin; Plancher-Moquette | Ch 2/pl | Ch 2/pl | B14
Obj.-003 | Etage1 | 900 | 1.71 | 400 | 0.364192 | 1900 | 5750 | 0 | 9.53161 | 6243.34 | 493.337 | 5750 | 0 | 2230573 | -641025 | 0.00850185 | C10 | Obj.-003 | SANITAIRE | Lit double_70 | Brique 1 | Etage1 | 4 | Bois-Pin; Plancher-Moquette | Ch 2 | Ch 2 | B16
Obj.-003 | Etage1 | 900 | 1.71 | 400 | 0.364192 | 1900 | 5750 | 0 | 9.53161 | 6243.34 | 493.337 | 5750 | 0 | 2231126 | -652342 | 180.035 | C10 | Obj.-003 | SANITAIRE | Lit double_70 | Brique 1 | Etage1 | 4 | Bois-Pin; Plancher-Moquette | Ch 2 | Ch 2 | B15
Obj.-003 | Etage1 | 900 | 1.71 | 400 | 0.364192 | 1900 | 5750 | 0 | 9.53161 | 6243.34 | 493.337 | 5750 | 0 | 2218802 | -638677 | 180.001 | C10 | Obj.-003 | SANITAIRE | Lit double_70 | Brique 1 | Etage1 | 4 | Bois-Pin; Plancher-Moquette | Ch 2 | Ch 2 | B13
Obj.-003 | Etage1 | 900 | 1.71 | 400 | 0.364192 | 1900 | 5750 | 0 | 9.53161 | 6243.34 | 493.337 | 5750 | 0 | 2218630 | -629221 | 180.001 | C10 | Obj.-003 | SANITAIRE | Lit double_70 | Brique 1 | Etage1 | 4 | Bois-Pin; Plancher-Moquette | Ch 2 | Ch 2 | B12
Obj.-003 | Etage1 | 900 | 1.71 | 400 | 0.364192 | 1900 | 5750 | 0 | 9.53161 | 6243.34 | 493.337 | 5750 | 0 | 2218690 | -614658 | 354.193 | C10 | Obj.-003 | SANITAIRE | Lit double_70 | Brique 1 | Etage1 | 4 | Bois-Pin; Plancher-Moquette | Ch 2 | Ch 2 | A12
Obj.-003 | Etage1 | 900 | 1.71 | 400 | 0.364192 | 1900 | 5750 | 0 | 9.53161 | 6243.34 | 493.337 | 5750 | 0 | 2236741 | -608071 | 264.197 | C10 | Obj.-003 | SANITAIRE | Lit double_70 | Brique 1 | Etage1 | 4 | Bois-Pin; Plancher-Moquette | Ch 2 | Ch 2 | A14
Obj.-026 | Etage1 | 1200 | 1.08 | 730 | 0.0252536 | 900 | 5750 | 1.77636e-12 | 3.05224 | 6480 | 730 | 5750 | 1.77636e-12 | 2222553 | -606713 | 264.261 | C10 | Obj.-026 | MOBILIER | al_table Sting | Brique 1 | Etage1 | 4 | Métal-Inox; Surface-Peinture brillante; Divers-Glace | Sejour cuisine/pl | Sejour cuisine/pl | A11
Obj.-027 | Etage1 | 440 | 0.211011 | 450 | 0.0143427 | 479.571 | 5750 | 1.77636e-12 | 0.948533 | 6530 | 780 | 5750 | 1.77636e-12 | 2223103 | -606789 | 264.261 | C10 | Obj.-027 | MOBILIER | Chaise 1 65 | Brique 1 | Etage1 | 4 | Métal-Inox; Surface-Plastique stratifié | Sejour cuisine/pl | Sejour cuisine/pl | A11
Obj.-027 | Etage1 | 440 | 0.211011 | 450 | 0.0143427 | 479.571 | 5750 | 1.77636e-12 | 0.948533 | 6530 | 780 | 5750 | 1.77636e-12 | 2223165 | -606177 | 264.261 | C10 | Obj.-027 | MOBILIER | Chaise 1 65 | Brique 1 | Etage1 | 4 | Métal-Inox; Surface-Plastique stratifié | Sejour cuisine/pl | Sejour cuisine/pl | A11
Obj.-034 | Etage1 | 1473.38 | 0.220611 | 2500 | 0.0477147 | 149.731 | 5750 | 1.42109e-11 | 5.5917 | 8250 | 2500 | 5750 | 1.42109e-11 | 2233601 | -622258 | 84.1973 | Revêt. pilier rond | Obj.-034 | 0-Resille Dampere | Barrière vitrée 65 | Brique 1 | Etage1 | 4 | Divers-Eau; Peinture-05
Obj.-003 | Etage1 | 1400 | 2.66 | 400 | 0.566521 | 1900 | 5750 | 0 | 14.0446 | 6243.34 | 493.337 | 5750 | 0 | 2230817 | -646738 | 180 | C10 | Obj.-003 | SANITAIRE | Lit double_70 | Brique 1 | Etage1 | 4 | Bois-Pin; Plancher-Moquette | Ch 1/pl | Ch 1/pl | B16
Obj.-027 | Etage1 | 440 | 0.211011 | 450 | 0.0143427 | 479.571 | 5750 | 1.77636e-12 | 0.948533 | 6530 | 780 | 5750 | 1.77636e-12 | 2220245 | -625991 | 270.031 | C10 | Obj.-027 | MOBILIER | Chaise 1 65 | Brique 1 | Etage1 | 4 | Métal-Inox; Surface-Plastique stratifié | Sejour cuisine | Sejour cuisine | B12
Obj.-027 | Etage1 | 440 | 0.211011 | 450 | 0.0143427 | 479.571 | 5750 | 1.77636e-12 | 0.948533 | 6530 | 780 | 5750 | 1.77636e-12 | 2228808 | -629331 | 3.05333e-13 | C10 | Obj.-027 | MOBILIER | Chaise 1 65 | Brique 1 | Etage1 | 4 | Métal-Inox; Surface-Plastique stratifié | Sejour cuisine | Sejour cuisine | B11
Obj.-003 | Etage1 | 1400 | 2.66 | 400 | 0.566521 | 1900 | 5750 | 0 | 14.0446 | 6243.34 | 493.337 | 5750 | 0 | 2219041 | -632434 | 180 | C10 | Obj.-003 | SANITAIRE | Lit double_70 | Brique 1 | Etage1 | 4 | Bois-Pin; Plancher-Moquette | Ch 1/pl | Ch 1/pl | B12
Obj.-019 | Etage1 | 600 | 0.36 | 900 | 0.314148 | 600 | 5750 | 0 | 4.5196 | 6650 | 900 | 5750 | 0 | 2224132 | -623871 | 90 | Revêt. pilier rond | Obj.-019 | SANITAIRE | Réfrigérateur haut 65 | Brique 1 | Etage1 | 4 | Métal-Chrome; Surface-Lavis Blanc | Sejour cuisine | Sejour cuisine | B12
Obj.-027 | Etage1 | 440 | 0.211011 | 450 | 0.0143427 | 479.571 | 5750 | 1.77636e-12 | 0.948533 | 6530 | 780 | 5750 | 1.77636e-12 | 2228193 | -629739 | 180 | C10 | Obj.-027 | MOBILIER | Chaise 1 65 | Brique 1 | Etage1 | 4 | Métal-Inox; Surface-Plastique stratifié | Sejour cuisine | Sejour cuisine | B11
Obj.-003 | Etage1 | 1400 | 2.66 | 400 | 0.566521 | 1900 | 5750 | 0 | 14.0446 | 6243.34 | 493.337 | 5750 | 0 | 2218835 | -611027 | 354.293 | C10 | Obj.-003 | SANITAIRE | Lit double_70 | Brique 1 | Etage1 | 4 | Bois-Pin; Plancher-Moquette | Ch 1 | Ch 1 | A12
Obj.-003 | Etage1 | 1400 | 2.66 | 400 | 0.566521 | 1900 | 5750 | 0 | 14.0446 | 6243.34 | 493.337 | 5750 | 0 | 2226485 | -618956 | 84.1973 | C10 | Obj.-003 | SANITAIRE | Lit double_70 | Brique 1 | Etage1 | 4 | Poutre; Revêt. sol | Ch 1 | Ch 1 | A13
Obj.-019 | Etage1 | 600 | 0.36 | 900 | 0.314148 | 600 | 5750 | 0 | 4.5196 | 6650 | 900 | 5750 | 0 | 2224288 | -605566 | 264.23 | Revêt. pilier rond | Obj.-019 | SANITAIRE | Réfrigérateur haut 65 | Brique 1 | Etage1 | 4 | Métal-Chrome; Surface-Lavis Blanc | Sejour cuisine/pl | Sejour cuisine/pl | A11
Obj.-027 | Etage1 | 440 | 0.211011 | 450 | 0.0143427 | 479.571 | 5750 | 1.77636e-12 | 0.948533 | 6530 | 780 | 5750 | 1.77636e-12 | 2222697 | -606748 | 84.2606 | C10 | Obj.-027 | MOBILIER | Chaise 1 65 | Brique 1 | Etage1 | 4 | Métal-Inox; Surface-Plastique stratifié | Sejour cuisine/pl | Sejour cuisine/pl | A11
Obj.-019 | Etage1 | 600 | 0.36 | 900 | 0.314148 | 600 | 5750 | 0 | 4.5196 | 6650 | 900 | 5750 | 0 | 2226099 | -610499 | 174.197 | Revêt. pilier rond | Obj.-019 | SANITAIRE | Réfrigérateur haut 65 | Brique 1 | Etage1 | 4 | Métal-Chrome; Surface-Lavis Blanc | Sejour cuisine/pl | Sejour cuisine/pl | A15
Obj.-027 | Etage1 | 440 | 0.211011 | 450 | 0.0143427 | 479.571 | 5750 | 1.77636e-12 | 0.948533 | 6530 | 780 | 5750 | 1.77636e-12 | 2221788 | -620423 | 84.2606 | C10 | Obj.-027 | MOBILIER | Chaise 1 65 | Brique 1 | Etage1 | 4 | Métal-Inox; Surface-Plastique stratifié | Sejour cuisine | Sejour cuisine | A12
Obj.-026 | Etage1 | 1200 | 1.08 | 730 | 0.0252536 | 900 | 5750 | 1.77636e-12 | 3.05224 | 6480 | 730 | 5750 | 1.77636e-12 | 2221644 | -620388 | 264.261 | C10 | Obj.-026 | MOBILIER | al_table Sting | Brique 1 | Etage1 | 4 | Métal-Inox; Surface-Peinture brillante; Divers-Glace | Sejour cuisine | Sejour cuisine | A12
Obj.-027 | Etage1 | 440 | 0.211011 | 450 | 0.0143427 | 479.571 | 5750 | 1.77636e-12 | 0.948533 | 6530 | 780 | 5750 | 1.77636e-12 | 2222194 | -620463 | 264.261 | C10 | Obj.-027 | MOBILIER | Chaise 1 65 | Brique 1 | Etage1 | 4 | Métal-Inox; Surface-Plastique stratifié | Sejour cuisine | Sejour cuisine | A12
Obj.-027 | Etage1 | 440 | 0.211011 | 450 | 0.0143427 | 479.571 | 5750 | 1.77636e-12 | 0.948533 | 6530 | 780 | 5750 | 1.77636e-12 | 2222256 | -619851 | 264.261 | C10 | Obj.-027 | MOBILIER | Chaise 1 65 | Brique 1 | Etage1 | 4 | Métal-Inox; Surface-Plastique stratifié | Sejour cuisine | Sejour cuisine | A12
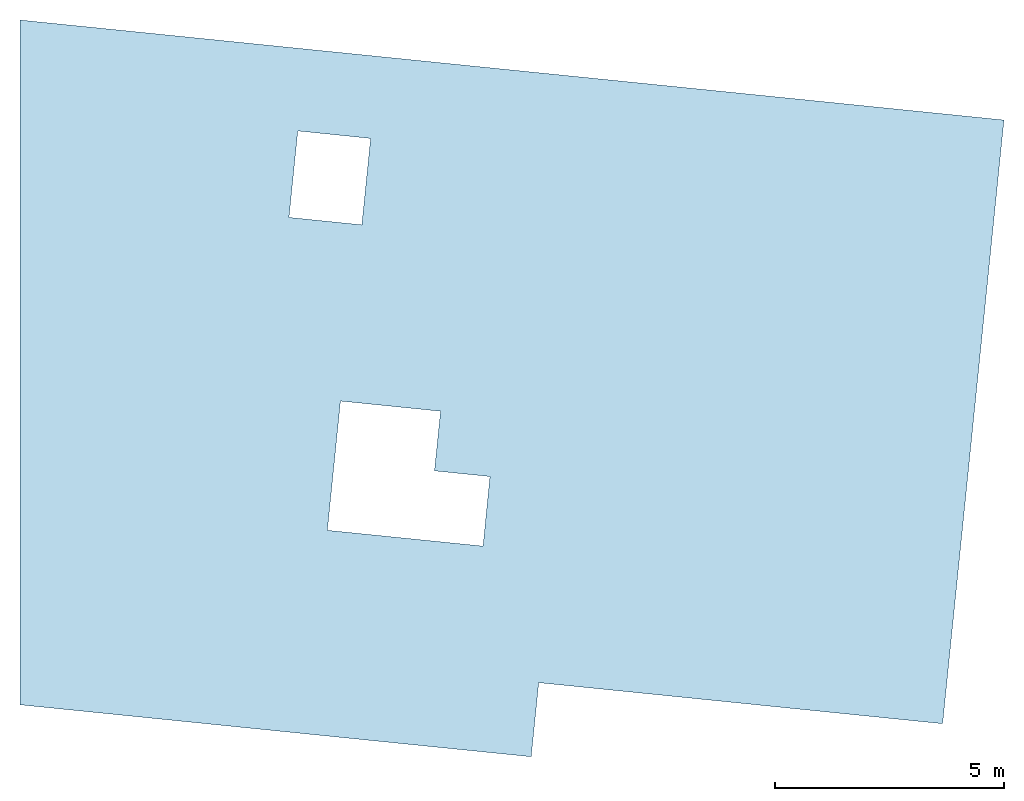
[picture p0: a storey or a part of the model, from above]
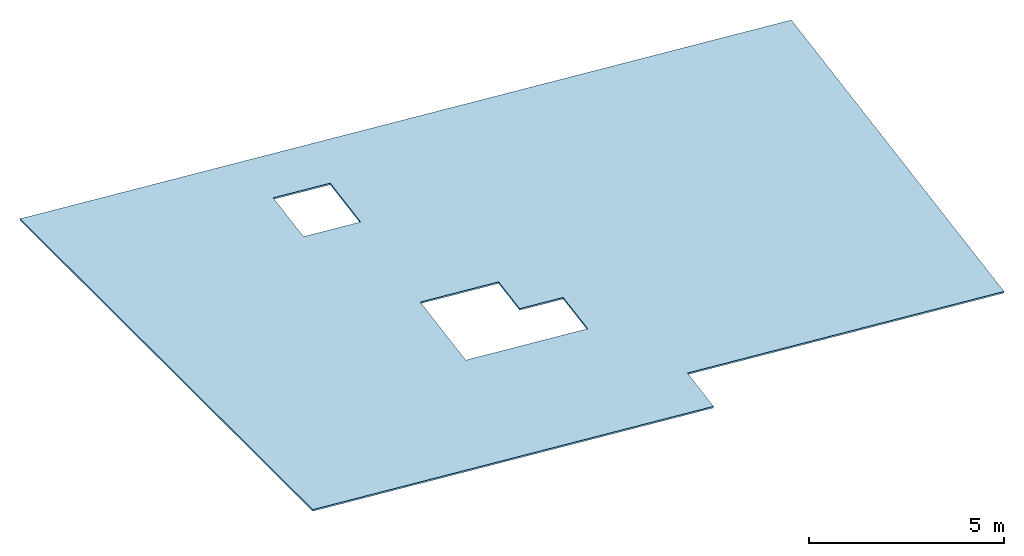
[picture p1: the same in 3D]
Properties of the parts of a building model (IFC2X3), part 5 of 44

# IfcBuildingElementProxy (454)
Name | In | Longueur (A) (mm) | Superficie (m2) = Superficie supérieure (nette) (m2) | Hauteur (mm) | Volume (net) (m3) | Largeur (mm) | Altitude à Zéro du Projet (mm) = Altitude de Référence Niveau 1 (mm) = Altitude de Référence Niveau 2 (mm) = Altitude à niveau de la mer (mm) = Coordonnée topographique Z (mm) | Altitude à étage lié/étage d'implantation (mm) = Décalage étage d'implantation (mm) | Superficie en plan (m2) = Superficie inférieure (nette) (m2) | Altitude supérieure à premier niveau de référence (mm) = Altitude supérieure à Zéro du projet (mm) = Altitude supérieure à niveau de la mer (mm) = Altitude supérieure à deuxième niveau de référence (mm) | Altitude supérieure à étage d'implantation (mm) | Altitude inférieure à premier niveau de référence (mm) = Altitude inférieure à Zéro du projet (mm) = Altitude inférieure à niveau de la mer (mm) = Altitude inférieure à deuxième niveau de référence (mm) | Altitude inférieure à étage d'implantation (mm) | Coordonnée topographique X (mm) | Coordonnée topographique Y (mm) | Angle de rotation (deg) | Surface | ID de l'élément = Lien et ID d'élément = ID de Parent | Calque | Nom Élément de Bibliothèque | Matériau de construction / Composite / Profil / Hachure = Type Hachure | Nom d'étage d'implantation | Numéro d'étage d'implantation | Surfaces (Toutes) | Zones conflictuelles | Nom de zone liée | Numéro de zone liée
Obj.-027 | Etage1 | 440 | 0.211011 | 450 | 0.0143427 | 479.571 | 5750 | 1.77636e-12 | 0.948533 | 6530 | 780 | 5750 | 1.77636e-12 | 2221850 | -619811 | 84.2606 | C10 | Obj.-027 | MOBILIER | Chaise 1 65 | Brique 1 | Etage1 | 4 | Métal-Inox; Surface-Plastique stratifié | Sejour cuisine | Sejour cuisine | A12
Obj.-003 | Etage1 | 1400 | 2.66 | 400 | 0.566521 | 1900 | 5750 | 0 | 14.0446 | 6243.34 | 493.337 | 5750 | 0 | 2218566 | -610820 | 174.104 | C10 | Obj.-003 | SANITAIRE | Lit double_70 | Brique 1 | Etage1 | 4 | Bois-Pin; Plancher-Moquette | Ch 1 | Ch 1 | A11
Obj.-027 | Etage1 | 440 | 0.211011 | 450 | 0.0143427 | 479.571 | 5750 | 1.77636e-12 | 0.948533 | 6530 | 780 | 5750 | 1.77636e-12 | 2231913 | -616910 | 264.227 | C10 | Obj.-027 | MOBILIER | Chaise 1 65 | Brique 1 | Etage1 | 4 | Métal-Inox; Surface-Plastique stratifié | Sejour cuisine | Sejour cuisine | A13
Obj.-027 | Etage1 | 440 | 0.211011 | 450 | 0.0143427 | 479.571 | 5750 | 1.77636e-12 | 0.948533 | 6530 | 780 | 5750 | 1.77636e-12 | 2222506 | -653289 | 89.9951 | C10 | Obj.-027 | MOBILIER | Chaise 1 65 | Brique 1 | Etage1 | 4 | Métal-Inox; Surface-Plastique stratifié | Sejour cuisine | Sejour cuisine | B14
Obj.-003 | Etage1 | 1400 | 2.66 | 400 | 0.566521 | 1900 | 5750 | 0 | 14.0446 | 6243.34 | 493.337 | 5750 | 0 | 2224312 | -655277 | 90 | C10 | Obj.-003 | SANITAIRE | Lit double_70 | Brique 1 | Etage1 | 4 | Poteaux | Ch 3 | Ch 3 | B15
Obj.-026 | Etage1 | 1200 | 1.08 | 730 | 0.0252536 | 900 | 5750 | 1.77636e-12 | 3.05224 | 6480 | 730 | 5750 | 1.77636e-12 | 2228213 | -629885 | 3.05333e-13 | C10 | Obj.-026 | MOBILIER | al_table Sting | Brique 1 | Etage1 | 4 | Métal-Inox; Surface-Peinture brillante; Divers-Glace | Sejour cuisine | Sejour cuisine | B11
Obj.-027 | Etage1 | 440 | 0.211011 | 450 | 0.0143427 | 479.571 | 5750 | 1.77636e-12 | 0.948533 | 6530 | 780 | 5750 | 1.77636e-12 | 2219837 | -625376 | 90.031 | C10 | Obj.-027 | MOBILIER | Chaise 1 65 | Brique 1 | Etage1 | 4 | Métal-Inox; Surface-Plastique stratifié | Sejour cuisine | Sejour cuisine | B12
Obj.-026 | Etage1 | 788.112 | 0.709301 | 730 | 0.0174689 | 900 | 5750 | 1.77636e-12 | 2.1708 | 6480 | 730 | 5750 | 1.77636e-12 | 2231371 | -616758 | 264.227 | C10 | Obj.-026 | MOBILIER | al_table Sting | Brique 1 | Etage1 | 4 | Métal-Inox; Surface-Peinture brillante; Divers-Glace | Sejour cuisine | Sejour cuisine | A13
Obj.-019 | Etage1 | 600 | 0.36 | 900 | 0.314148 | 600 | 5750 | 0 | 4.5196 | 6650 | 900 | 5750 | 0 | 2229379 | -616664 | 84.1958 | Revêt. pilier rond | Obj.-019 | SANITAIRE | Réfrigérateur haut 65 | Brique 1 | Etage1 | 4 | Métal-Chrome; Surface-Lavis Blanc | Sejour cuisine | Sejour cuisine | A13
Obj.-027 | Etage1 | 440 | 0.211011 | 450 | 0.0143427 | 479.571 | 5750 | 1.77636e-12 | 0.948533 | 6530 | 780 | 5750 | 1.77636e-12 | 2231507 | -616869 | 84.2265 | C10 | Obj.-027 | MOBILIER | Chaise 1 65 | Brique 1 | Etage1 | 4 | Métal-Inox; Surface-Plastique stratifié | Sejour cuisine | Sejour cuisine | A13
Obj.-027 | Etage1 | 440 | 0.211011 | 450 | 0.0143427 | 479.571 | 5750 | 1.77636e-12 | 0.948533 | 6530 | 780 | 5750 | 1.77636e-12 | 2230043 | -639286 | 269.995 | C10 | Obj.-027 | MOBILIER | Chaise 1 65 | Brique 1 | Etage1 | 4 | Métal-Inox; Surface-Plastique stratifié | Sejour cuisine | Sejour cuisine | B16
Obj.-034 | Etage1 | 2229.78 | 0.334467 | 2500 | 0.0534734 | 150 | 5750 | 1.42109e-11 | 7.6753 | 8250 | 2500 | 5750 | 1.42109e-11 | 2224338 | -660048 | 90 | Revêt. pilier rond | Obj.-034 | 0-Resille Dampere | Barrière vitrée 65 | Brique 1 | Etage1 | 4 | Divers-Eau; Peinture-05
Obj.-027 | Etage1 | 440 | 0.211011 | 450 | 0.0143427 | 479.571 | 5750 | 1.77636e-12 | 0.948533 | 6530 | 780 | 5750 | 1.77636e-12 | 2229634 | -639286 | 89.9951 | C10 | Obj.-027 | MOBILIER | Chaise 1 65 | Brique 1 | Etage1 | 4 | Métal-Inox; Surface-Plastique stratifié | Sejour cuisine | Sejour cuisine | B16
Obj.-027 | Etage1 | 440 | 0.211011 | 450 | 0.0143427 | 479.571 | 5750 | 1.77636e-12 | 0.948533 | 6530 | 780 | 5750 | 1.77636e-12 | 2229635 | -638670 | 89.9951 | C10 | Obj.-027 | MOBILIER | Chaise 1 65 | Brique 1 | Etage1 | 4 | Métal-Inox; Surface-Plastique stratifié | Sejour cuisine | Sejour cuisine | B16
Obj.-027 | Etage1 | 440 | 0.211011 | 450 | 0.0143427 | 479.571 | 5750 | 1.77636e-12 | 0.948533 | 6530 | 780 | 5750 | 1.77636e-12 | 2230043 | -638671 | 269.995 | C10 | Obj.-027 | MOBILIER | Chaise 1 65 | Brique 1 | Etage1 | 4 | Métal-Inox; Surface-Plastique stratifié | Sejour cuisine | Sejour cuisine | B16
Obj.-027 | Etage1 | 440 | 0.211011 | 450 | 0.0143427 | 479.571 | 5750 | 1.77636e-12 | 0.948533 | 6530 | 780 | 5750 | 1.77636e-12 | 2222914 | -653289 | 269.995 | C10 | Obj.-027 | MOBILIER | Chaise 1 65 | Brique 1 | Etage1 | 4 | Métal-Inox; Surface-Plastique stratifié | Sejour cuisine | Sejour cuisine | B14
Obj.-026 | Etage1 | 1200 | 1.08 | 730 | 0.0252536 | 900 | 5750 | 1.77636e-12 | 3.05224 | 6480 | 730 | 5750 | 1.77636e-12 | 2223061 | -653309 | 89.9951 | C10 | Obj.-026 | MOBILIER | al_table Sting | Brique 1 | Etage1 | 4 | Métal-Inox; Surface-Peinture brillante; Divers-Glace | Sejour cuisine | Sejour cuisine | B14
Obj.-027 | Etage1 | 440 | 0.211011 | 450 | 0.0143427 | 479.571 | 5750 | 1.77636e-12 | 0.948533 | 6530 | 780 | 5750 | 1.77636e-12 | 2222506 | -653904 | 89.9951 | C10 | Obj.-027 | MOBILIER | Chaise 1 65 | Brique 1 | Etage1 | 4 | Métal-Inox; Surface-Plastique stratifié | Sejour cuisine | Sejour cuisine | B14
Obj.-019 | Etage1 | 600 | 0.36 | 900 | 0.314148 | 600 | 5750 | 0 | 4.5196 | 6650 | 900 | 5750 | 0 | 2222857 | -639252 | 0 | Revêt. pilier rond | Obj.-019 | SANITAIRE | Réfrigérateur haut 65 | Brique 1 | Etage1 | 4 | Métal-Chrome; Surface-Lavis Blanc | Sejour Cuisine | Sejour Cuisine | B13
Obj.-034 | Etage1 | 800 | 0.64 | 360 | 0.280139 | 800 | 5750 | 1.95399e-11 | 4.69089 | 6416.7 | 666.7 | 5750 | 1.95399e-11 | 2221219 | -656139 | 270 | Revêt. pilier rond | Obj.-034 | 0-Resille Dampere | Fauteuil 65 | Brique 1 | Etage1 | 4 | Plancher-Moquette; Revêt. pilier rond | Sejour cuisine | Sejour cuisine | B14
Obj.-027 | Etage1 | 440 | 0.211011 | 450 | 0.0143427 | 479.571 | 5750 | 1.77636e-12 | 0.948533 | 6530 | 780 | 5750 | 1.77636e-12 | 2222914 | -653904 | 269.995 | C10 | Obj.-027 | MOBILIER | Chaise 1 65 | Brique 1 | Etage1 | 4 | Métal-Inox; Surface-Plastique stratifié | Sejour cuisine | Sejour cuisine | B14
Obj.-026 | Etage1 | 1200 | 1.08 | 730 | 0.0252536 | 900 | 5750 | 1.77636e-12 | 3.05224 | 6480 | 730 | 5750 | 1.77636e-12 | 2231250 | -655308 | 89.9951 | C10 | Obj.-026 | MOBILIER | al_table Sting | Brique 1 | Etage1 | 4 | Métal-Inox; Surface-Peinture brillante; Divers-Glace | Sejour cuisine | Sejour cuisine | B15
Obj.-027 | Etage1 | 440 | 0.211011 | 450 | 0.0143427 | 479.571 | 5750 | 1.77636e-12 | 0.948533 | 6530 | 780 | 5750 | 1.77636e-12 | 2231103 | -655903 | 269.995 | C10 | Obj.-027 | MOBILIER | Chaise 1 65 | Brique 1 | Etage1 | 4 | Métal-Inox; Surface-Plastique stratifié | Sejour cuisine | Sejour cuisine | B15
Obj.-027 | Etage1 | 440 | 0.211011 | 450 | 0.0143427 | 479.571 | 5750 | 1.77636e-12 | 0.948533 | 6530 | 780 | 5750 | 1.77636e-12 | 2230695 | -655288 | 89.9951 | C10 | Obj.-027 | MOBILIER | Chaise 1 65 | Brique 1 | Etage1 | 4 | Métal-Inox; Surface-Plastique stratifié | Sejour cuisine | Sejour cuisine | B15
Obj.-034 | Etage1 | 800 | 0.64 | 360 | 0.280139 | 800 | 5750 | 1.95399e-11 | 4.69089 | 6416.7 | 666.7 | 5750 | 1.95399e-11 | 2228173 | -654780 | 0 | Revêt. pilier rond | Obj.-034 | 0-Resille Dampere | Fauteuil 65 | Brique 1 | Etage1 | 4 | Plancher-Moquette; Revêt. pilier rond | Sejour cuisine | Sejour cuisine | B15
Obj.-027 | Etage1 | 440 | 0.211011 | 450 | 0.0143427 | 479.571 | 5750 | 1.77636e-12 | 0.948533 | 6530 | 780 | 5750 | 1.77636e-12 | 2230695 | -655903 | 89.9951 | C10 | Obj.-027 | MOBILIER | Chaise 1 65 | Brique 1 | Etage1 | 4 | Métal-Inox; Surface-Plastique stratifié | Sejour cuisine | Sejour cuisine | B15
Obj.-027 | Etage1 | 440 | 0.211011 | 450 | 0.0143427 | 479.571 | 5750 | 1.77636e-12 | 0.948533 | 6530 | 780 | 5750 | 1.77636e-12 | 2231103 | -655288 | 269.995 | C10 | Obj.-027 | MOBILIER | Chaise 1 65 | Brique 1 | Etage1 | 4 | Métal-Inox; Surface-Plastique stratifié | Sejour cuisine | Sejour cuisine | B15
Obj.-019 | Etage1 | 600 | 0.36 | 900 | 0.314148 | 600 | 5750 | 0 | 4.5196 | 6650 | 900 | 5750 | 0 | 2231705 | -653016 | 359.849 | Revêt. pilier rond | Obj.-019 | SANITAIRE | Réfrigérateur haut 65 | Brique 1 | Etage1 | 4 | Métal-Chrome; Surface-Lavis Blanc | Sejour cuisine | Sejour cuisine | B15
Obj.-034 | Etage1 | 1210.87 | 0.18163 | 2500 | 0.0458315 | 150 | 5750 | 1.42109e-11 | 4.87329 | 8250 | 2500 | 5750 | 1.42109e-11 | 2216897 | -620792 | 353.337 | Revêt. pilier rond | Obj.-034 | 0-Resille Dampere | Barrière vitrée 65 | Brique 1 | Etage1 | 4 | Divers-Eau; Peinture-05 | balcon; balcon
Obj.-019 | Etage1 | 600 | 0.36 | 900 | 0.314148 | 600 | 5750 | 0 | 4.5196 | 6650 | 900 | 5750 | 0 | 2224415 | -621199 | 354.165 | Revêt. pilier rond | Obj.-019 | SANITAIRE | Réfrigérateur haut 65 | Brique 1 | Etage1 | 4 | Métal-Chrome; Surface-Lavis Blanc | Sejour cuisine | Sejour cuisine | A12
Obj.-019 | Etage1 | 600 | 0.36 | 900 | 0.314148 | 600 | 5750 | 0 | 4.5196 | 6650 | 900 | 5750 | 0 | 2228229 | -638115 | 359.964 | Revêt. pilier rond | Obj.-019 | SANITAIRE | Réfrigérateur haut 65 | Brique 1 | Etage1 | 4 | Métal-Chrome; Surface-Lavis Blanc | Sejour cuisine | Sejour cuisine | B16
Obj.-027 | Etage 2 | 440 | 0.211011 | 450 | 0.0143427 | 479.571 | 8500 | 1.77636e-12 | 0.948533 | 9280 | 780 | 8500 | 1.77636e-12 | 2222194 | -620463 | 264.261 | C10 | Obj.-027 | MOBILIER | Chaise 1 65 | Brique 1 | Etage 2 | 5 | Métal-Inox; Surface-Plastique stratifié | Sejour cuisine | Sejour cuisine | A22
Obj.-027 | Etage 2 | 440 | 0.211011 | 450 | 0.0143427 | 479.571 | 8500 | 1.77636e-12 | 0.948533 | 9280 | 780 | 8500 | 1.77636e-12 | 2221788 | -620423 | 84.2606 | C10 | Obj.-027 | MOBILIER | Chaise 1 65 | Brique 1 | Etage 2 | 5 | Métal-Inox; Surface-Plastique stratifié | Sejour cuisine | Sejour cuisine | A22
Obj.-026 | Etage 2 | 1200 | 1.08 | 730 | 0.0252536 | 900 | 8500 | 1.77636e-12 | 3.05224 | 9230 | 730 | 8500 | 1.77636e-12 | 2221644 | -620388 | 264.261 | C10 | Obj.-026 | MOBILIER | al_table Sting | Brique 1 | Etage 2 | 5 | Métal-Inox; Surface-Peinture brillante; Divers-Glace | Sejour cuisine | Sejour cuisine | A22
Obj.-026 | Etage 2 | 1200 | 1.08 | 730 | 0.0252536 | 900 | 8500 | 1.77636e-12 | 3.05224 | 9230 | 730 | 8500 | 1.77636e-12 | 2222777 | -606816 | 264.261 | C10 | Obj.-026 | MOBILIER | al_table Sting | Brique 1 | Etage 2 | 5 | Métal-Inox; Surface-Peinture brillante; Divers-Glace | Sejour cuisine/pl | Sejour cuisine/pl | A21
Obj.-003 | Etage 2 | 1400 | 2.66 | 400 | 0.566521 | 1900 | 8500 | 0 | 14.0446 | 8993.34 | 493.337 | 8500 | 0 | 2218835 | -611027 | 354.293 | C10 | Obj.-003 | MOBILIER | Lit double_70 | Brique 1 | Etage 2 | 5 | Bois-Pin; Plancher-Moquette | Ch 1 | Ch 1 | A22
Obj.-003 | Etage 2 | 1400 | 2.66 | 400 | 0.566521 | 1900 | 8500 | 0 | 14.0446 | 8993.34 | 493.337 | 8500 | 0 | 2233953 | -608037 | 264.197 | C10 | Obj.-003 | MOBILIER | Lit double_70 | Brique 1 | Etage 2 | 5 | Bois-Pin; Plancher-Moquette | Ch 1 | Ch 1 | A25
Obj.-034 | Etage 2 | 1473.38 | 0.220611 | 2500 | 0.0522066 | 149.731 | 8500 | 1.42109e-11 | 6.21339 | 11300 | 2800 | 8500 | 1.42109e-11 | 2233601 | -622258 | 84.1973 | Revêt. pilier rond | Obj.-034 | 0-Resille Dampere | Barrière vitrée 65 | Brique 1 | Etage 2 | 5 | Divers-Eau; Peinture-05
Obj.-027 | Etage 2 | 440 | 0.211011 | 450 | 0.0143427 | 479.571 | 8500 | 1.77636e-12 | 0.948533 | 9280 | 780 | 8500 | 1.77636e-12 | 2222983 | -606238 | 84.2606 | C10 | Obj.-027 | MOBILIER | Chaise 1 65 | Brique 1 | Etage 2 | 5 | Métal-Inox; Surface-Plastique stratifié | Sejour cuisine/pl | Sejour cuisine/pl | A21
Obj.-026 | Etage 2 | 1200 | 1.08 | 730 | 0.0252536 | 900 | 8500 | 1.77636e-12 | 3.05224 | 9230 | 730 | 8500 | 1.77636e-12 | 2230189 | -638691 | 89.9951 | C10 | Obj.-026 | MOBILIER | al_table Sting | Brique 1 | Etage 2 | 5 | Métal-Inox; Surface-Peinture brillante; Divers-Glace | Sejour cuisine | Sejour cuisine | B26
Obj.-003 | Etage 2 | 1400 | 2.66 | 400 | 0.566521 | 1900 | 8500 | 0 | 14.0446 | 8993.34 | 493.337 | 8500 | 0 | 2219041 | -632434 | 180 | C10 | Obj.-003 | MOBILIER | Lit double_70 | Brique 1 | Etage 2 | 5 | Bois-Pin; Plancher-Moquette | Ch 1/pl | Ch 1/pl | B22
Obj.-019 | Etage 2 | 600 | 0.36 | 900 | 0.314148 | 600 | 8500 | 0 | 4.5196 | 9400 | 900 | 8500 | 0 | 2226492 | -631658 | 90 | Revêt. pilier rond | Obj.-019 | SANITAIRE | Réfrigérateur haut 65 | Brique 1 | Etage 2 | 5 | Métal-Chrome; Surface-Lavis Blanc | Sejour cuisine | Sejour cuisine | B21
Obj.-019 | Etage 2 | 600 | 0.36 | 900 | 0.314148 | 600 | 8500 | 0 | 4.5196 | 9400 | 900 | 8500 | 0 | 2226099 | -610499 | 174.197 | Revêt. pilier rond | Obj.-019 | SANITAIRE | Réfrigérateur haut 65 | Brique 1 | Etage 2 | 5 | Métal-Chrome; Surface-Lavis Blanc | Sejour cuisine/pl | Sejour cuisine/pl | A25
Obj.-027 | Etage 2 | 440 | 0.211011 | 450 | 0.0143427 | 479.571 | 8500 | 1.77636e-12 | 0.948533 | 9280 | 780 | 8500 | 1.77636e-12 | 2222256 | -619851 | 264.261 | C10 | Obj.-027 | MOBILIER | Chaise 1 65 | Brique 1 | Etage 2 | 5 | Métal-Inox; Surface-Plastique stratifié | Sejour cuisine | Sejour cuisine | A22
Obj.-003 | Etage 2 | 1400 | 2.66 | 400 | 0.566521 | 1900 | 8500 | 0 | 14.0446 | 8993.34 | 493.337 | 8500 | 0 | 2218566 | -610820 | 174.104 | C10 | Obj.-003 | MOBILIER | Lit double_70 | Brique 1 | Etage 2 | 5 | Bois-Pin; Plancher-Moquette | Ch 1/pl | Ch 1/pl | A21
Obj.-003 | Etage 2 | 1400 | 2.66 | 400 | 0.566521 | 1900 | 8500 | 0 | 14.0446 | 8993.34 | 493.337 | 8500 | 0 | 2219226 | -644356 | 360 | C10 | Obj.-003 | MOBILIER | Lit double_70 | Brique 1 | Etage 2 | 5 | Bois-Pin; Plancher-Moquette | Ch 1/pl | Ch 1/pl | B24
Obj.-019 | Etage 2 | 600 | 0.36 | 900 | 0.314148 | 600 | 8500 | 0 | 4.5196 | 9400 | 900 | 8500 | 0 | 2222857 | -639252 | 0 | Revêt. pilier rond | Obj.-019 | SANITAIRE | Réfrigérateur haut 65 | Brique 1 | Etage 2 | 5 | Métal-Chrome; Surface-Lavis Blanc | Sejour cuisine | Sejour cuisine | B23
Obj.-027 | Etage 2 | 440 | 0.211011 | 450 | 0.0143427 | 479.571 | 8500 | 1.77636e-12 | 0.948533 | 9280 | 780 | 8500 | 1.77636e-12 | 2231741 | -617478 | 264.227 | C10 | Obj.-027 | MOBILIER | Chaise 1 65 | Brique 1 | Etage 2 | 5 | Métal-Inox; Surface-Plastique stratifié | Sejour cuisine | Sejour cuisine | A23
Obj.-019 | Etage 2 | 600 | 0.36 | 900 | 0.314148 | 600 | 8500 | 0 | 4.5196 | 9400 | 900 | 8500 | 0 | 2224416 | -621199 | 354.165 | Revêt. pilier rond | Obj.-019 | SANITAIRE | Réfrigérateur haut 65 | Brique 1 | Etage 2 | 5 | Métal-Chrome; Surface-Lavis Blanc | Sejour cuisine | Sejour cuisine | A22
Obj.-027 | Etage 2 | 440 | 0.211011 | 450 | 0.0143427 | 479.571 | 8500 | 1.77636e-12 | 0.948533 | 9280 | 780 | 8500 | 1.77636e-12 | 2223327 | -606891 | 264.261 | C10 | Obj.-027 | MOBILIER | Chaise 1 65 | Brique 1 | Etage 2 | 5 | Métal-Inox; Surface-Plastique stratifié | Sejour cuisine/pl | Sejour cuisine/pl | A21
Obj.-027 | Etage 2 | 440 | 0.211011 | 450 | 0.0143427 | 479.571 | 8500 | 1.77636e-12 | 0.948533 | 9280 | 780 | 8500 | 1.77636e-12 | 2223389 | -606279 | 264.261 | C10 | Obj.-027 | MOBILIER | Chaise 1 65 | Brique 1 | Etage 2 | 5 | Métal-Inox; Surface-Plastique stratifié | Sejour cuisine/pl | Sejour cuisine/pl | A21
Obj.-019 | Etage 2 | 600 | 0.36 | 900 | 0.314148 | 600 | 8500 | 0 | 4.5196 | 9400 | 900 | 8500 | 0 | 2224288 | -605566 | 264.23 | Revêt. pilier rond | Obj.-019 | SANITAIRE | Réfrigérateur haut 65 | Brique 1 | Etage 2 | 5 | Métal-Chrome; Surface-Lavis Blanc | Sejour cuisine/pl | Sejour cuisine/pl | A21
Obj.-027 | Etage 2 | 440 | 0.211011 | 450 | 0.0143427 | 479.571 | 8500 | 1.77636e-12 | 0.948533 | 9280 | 780 | 8500 | 1.77636e-12 | 2222921 | -606850 | 84.2606 | C10 | Obj.-027 | MOBILIER | Chaise 1 65 | Brique 1 | Etage 2 | 5 | Métal-Inox; Surface-Plastique stratifié | Sejour cuisine/pl | Sejour cuisine/pl | A21
Obj.-027 | Etage 2 | 440 | 0.211011 | 450 | 0.0143427 | 479.571 | 8500 | 1.77636e-12 | 0.948533 | 9280 | 780 | 8500 | 1.77636e-12 | 2221850 | -619811 | 84.2606 | C10 | Obj.-027 | MOBILIER | Chaise 1 65 | Brique 1 | Etage 2 | 5 | Métal-Inox; Surface-Plastique stratifié | Sejour cuisine | Sejour cuisine | A22
Obj.-019 | Etage 2 | 600 | 0.36 | 900 | 0.314148 | 600 | 8500 | 0 | 4.5196 | 9400 | 900 | 8500 | 0 | 2238281 | -615649 | 264.23 | Revêt. pilier rond | Obj.-019 | SANITAIRE | Réfrigérateur haut 65 | Brique 1 | Etage 2 | 5 | Métal-Chrome; Surface-Lavis Blanc | Sejour cuisine/pl | Sejour cuisine/pl | A24
Obj.-034 | Etage 2 | 800 | 0.64 | 360 | 0.280139 | 800 | 9300 | 800 | 4.69089 | 9966.7 | 1466.7 | 9300 | 800 | 2221923 | -642912 | 269.964 | Revêt. pilier rond | Obj.-034 | 0-Resille Dampere | Fauteuil 65 | Brique 1 | Etage 2 | 5 | Plancher-Moquette; Revêt. pilier rond | Sejour cuisine | Sejour cuisine | B23
Obj.-027 | Etage 2 | 440 | 0.211011 | 450 | 0.0143427 | 479.571 | 8500 | 1.77636e-12 | 0.948533 | 9280 | 780 | 8500 | 1.77636e-12 | 2228808 | -628859 | 180 | C10 | Obj.-027 | MOBILIER | Chaise 1 65 | Brique 1 | Etage 2 | 5 | Métal-Inox; Surface-Plastique stratifié | Sejour cuisine | Sejour cuisine | B21
Obj.-026 | Etage 2 | 1200 | 1.08 | 730 | 0.0252536 | 900 | 8500 | 1.77636e-12 | 3.05224 | 9230 | 730 | 8500 | 1.77636e-12 | 2228137 | -655011 | 270.005 | C10 | Obj.-026 | MOBILIER | al_table Sting | Brique 1 | Etage 2 | 5 | Métal-Inox; Surface-Peinture brillante; Divers-Glace | Sejour cuisine | Sejour cuisine | B25
Obj.-003 | Etage 2 | 900 | 1.71 | 400 | 0.364192 | 1900 | 8500 | 0 | 9.53161 | 8993.34 | 493.337 | 8500 | 0 | 2219060 | -617168 | 180.001 | C10 | Obj.-003 | SANITAIRE | Lit double_70 | Brique 1 | Etage 2 | 5 | Bois-Pin; Plancher-Moquette | Ch 2 | Ch 2 | A22
Obj.-003 | Etage 2 | 900 | 1.71 | 400 | 0.364192 | 1900 | 8500 | 0 | 9.53161 | 8993.34 | 493.337 | 8500 | 0 | 2231126 | -647078 | 0.0411323 | C10 | Obj.-003 | SANITAIRE | Lit double_70 | Brique 1 | Etage 2 | 5 | Bois-Pin; Plancher-Moquette | Ch 1/pl | Ch 1/pl | B25
Obj.-003 | Etage 2 | 900 | 1.71 | 400 | 0.364192 | 1900 | 8500 | 0 | 9.53161 | 8993.34 | 493.337 | 8500 | 0 | 2236721 | -608261 | 264.197 | C10 | Obj.-003 | SANITAIRE | Lit double_70 | Brique 1 | Etage 2 | 5 | Bois-Pin; Plancher-Moquette | Ch 2/pl | Ch 2/pl | A24
Obj.-019 | Etage 2 | 600 | 0.36 | 900 | 0.314148 | 600 | 8500 | 0 | 4.5196 | 9400 | 900 | 8500 | 0 | 2218082 | -653017 | 0.141506 | Revêt. pilier rond | Obj.-019 | SANITAIRE | Réfrigérateur haut 65 | Brique 1 | Etage 2 | 5 | Métal-Chrome; Surface-Lavis Blanc | Sejour cuisine | Sejour cuisine | B24
Obj.-003 | Etage 2 | 900 | 1.71 | 400 | 0.364192 | 1900 | 8500 | 0 | 9.53161 | 8993.34 | 493.337 | 8500 | 0 | 2218839 | -649921 | 180.05 | C10 | Obj.-003 | SANITAIRE | Lit double_70 | Brique 1 | Etage 2 | 5 | Bois-Pin; Plancher-Moquette | Ch 2/pl | Ch 2/pl | B24
Obj.-003 | Etage 2 | 900 | 1.71 | 400 | 0.364192 | 1900 | 8500 | 0 | 9.53161 | 8993.34 | 493.337 | 8500 | 0 | 2229307 | -651783 | 90.0411 | C10 | Obj.-003 | SANITAIRE | Lit double_70 | Brique 1 | Etage 2 | 5 | Bois-Pin; Plancher-Moquette | Ch 2 | Ch 2 | B25
Obj.-003 | Etage 2 | 900 | 1.71 | 400 | 0.364192 | 1900 | 8500 | 0 | 9.53161 | 8993.34 | 493.337 | 8500 | 0 | 2230573 | -641025 | 0.00850185 | C10 | Obj.-003 | SANITAIRE | Lit double_70 | Brique 1 | Etage 2 | 5 | Bois-Pin; Plancher-Moquette | Ch 2 | Ch 2 | B26
Obj.-003 | Etage 2 | 900 | 1.71 | 400 | 0.364192 | 1900 | 8500 | 0 | 9.53161 | 8993.34 | 493.337 | 8500 | 0 | 2218871 | -649991 | 359.95 | C10 | Obj.-003 | SANITAIRE | Lit double_70 | Brique 1 | Etage 2 | 5 | Bois-Pin; Plancher-Moquette | Ch 3 | Ch 3 | B24
Obj.-003 | Etage 2 | 900 | 1.71 | 400 | 0.364192 | 1900 | 8500 | 0 | 9.53161 | 8993.34 | 493.337 | 8500 | 0 | 2218802 | -638677 | 180.001 | C10 | Obj.-003 | SANITAIRE | Lit double_70 | Brique 1 | Etage 2 | 5 | Bois-Pin; Plancher-Moquette | Ch 2 | Ch 2 | B23
Obj.-003 | Etage 2 | 900 | 1.71 | 400 | 0.364192 | 1900 | 8500 | 0 | 9.53161 | 8993.34 | 493.337 | 8500 | 0 | 2218630 | -629221 | 180.001 | C10 | Obj.-003 | SANITAIRE | Lit double_70 | Brique 1 | Etage 2 | 5 | Bois-Pin; Plancher-Moquette | Ch 2 | Ch 2 | B22
Obj.-002 | Etage 2 | 1800 | 1.44 | 600 | 0.0995281 | 800 | 8500 | 0 | 10.3313 | 9100 | 600 | 8500 | 0 | 2227692 | -647718 | 4.07111e-13 | Revêt. pilier rond | Obj.-002 | SANITAIRE | Baignoire 65 | Brique 1 | Etage 2 | 5 | Surface-Ceramiques vitrifiées | Sde | Sde | B25
Obj.-034 | Etage 2 | 1210.87 | 0.18163 | 2500 | 0.0458315 | 150 | 8500 | 1.42109e-11 | 4.87329 | 11000 | 2500 | 8500 | 1.42109e-11 | 2216897 | -620792 | 353.337 | Revêt. pilier rond | Obj.-034 | 0-Resille Dampere | Barrière vitrée 65 | Brique 1 | Etage 2 | 5 | Divers-Eau; Peinture-05 | balcon; balcon
Obj.-019 | Etage 2 | 600 | 0.36 | 900 | 0.314148 | 600 | 8500 | 0 | 4.5196 | 9400 | 900 | 8500 | 0 | 2231705 | -653021 | 359.849 | Revêt. pilier rond | Obj.-019 | SANITAIRE | Réfrigérateur haut 65 | Brique 1 | Etage 2 | 5 | Métal-Chrome; Surface-Lavis Blanc | Sejour cuisine | Sejour cuisine | B25
Obj.-027 | Etage 2 | 440 | 0.211011 | 450 | 0.0143427 | 479.571 | 8500 | 1.77636e-12 | 0.948533 | 9280 | 780 | 8500 | 1.77636e-12 | 2219837 | -625991 | 90.031 | C10 | Obj.-027 | MOBILIER | Chaise 1 65 | Brique 1 | Etage 2 | 5 | Métal-Inox; Surface-Plastique stratifié | Sejour cuisine | Sejour cuisine | B22
Obj.-019 | Etage 2 | 600 | 0.36 | 900 | 0.314148 | 600 | 8500 | 0 | 4.5196 | 9400 | 900 | 8500 | 0 | 2224132 | -623871 | 90 | Revêt. pilier rond | Obj.-019 | SANITAIRE | Réfrigérateur haut 65 | Brique 1 | Etage 2 | 5 | Métal-Chrome; Surface-Lavis Blanc | Sejour cuisine | Sejour cuisine | B22
Obj.-027 | Etage 2 | 440 | 0.211011 | 450 | 0.0143427 | 479.571 | 8500 | 1.77636e-12 | 0.948533 | 9280 | 780 | 8500 | 1.77636e-12 | 2220245 | -625376 | 270.031 | C10 | Obj.-027 | MOBILIER | Chaise 1 65 | Brique 1 | Etage 2 | 5 | Métal-Inox; Surface-Plastique stratifié | Sejour cuisine | Sejour cuisine | B22
Obj.-026 | Etage 2 | 1144.92 | 1.03042 | 730 | 0.0242125 | 900 | 8500 | 1.77636e-12 | 2.93436 | 9230 | 730 | 8500 | 1.77636e-12 | 2219691 | -625916 | 270.031 | C10 | Obj.-026 | MOBILIER | al_table Sting | Brique 1 | Etage 2 | 5 | Métal-Inox; Surface-Peinture brillante; Divers-Glace | Sejour cuisine | Sejour cuisine | B22
Obj.-027 | Etage 2 | 440 | 0.211011 | 450 | 0.0143427 | 479.571 | 8500 | 1.77636e-12 | 0.948533 | 9280 | 780 | 8500 | 1.77636e-12 | 2228808 | -628451 | 3.05333e-13 | C10 | Obj.-027 | MOBILIER | Chaise 1 65 | Brique 1 | Etage 2 | 5 | Métal-Inox; Surface-Plastique stratifié | Sejour cuisine | Sejour cuisine | B21
Obj.-027 | Etage 2 | 440 | 0.211011 | 450 | 0.0143427 | 479.571 | 8500 | 1.77636e-12 | 0.948533 | 9280 | 780 | 8500 | 1.77636e-12 | 2219837 | -625376 | 90.031 | C10 | Obj.-027 | MOBILIER | Chaise 1 65 | Brique 1 | Etage 2 | 5 | Métal-Inox; Surface-Plastique stratifié | Sejour cuisine | Sejour cuisine | B22
Obj.-027 | Etage 2 | 440 | 0.211011 | 450 | 0.0143427 | 479.571 | 8500 | 1.77636e-12 | 0.948533 | 9280 | 780 | 8500 | 1.77636e-12 | 2220245 | -625991 | 270.031 | C10 | Obj.-027 | MOBILIER | Chaise 1 65 | Brique 1 | Etage 2 | 5 | Métal-Inox; Surface-Plastique stratifié | Sejour cuisine | Sejour cuisine | B22
Obj.-026 | Etage 2 | 788.112 | 0.709301 | 730 | 0.0174689 | 900 | 8500 | 1.77636e-12 | 2.1708 | 9230 | 730 | 8500 | 1.77636e-12 | 2231199 | -617326 | 264.227 | C10 | Obj.-026 | MOBILIER | al_table Sting | Brique 1 | Etage 2 | 5 | Métal-Inox; Surface-Peinture brillante; Divers-Glace | Sejour cuisine | Sejour cuisine | A23
Obj.-027 | Etage 2 | 440 | 0.211011 | 450 | 0.0143427 | 479.571 | 8500 | 1.77636e-12 | 0.948533 | 9280 | 780 | 8500 | 1.77636e-12 | 2231335 | -617437 | 84.2265 | C10 | Obj.-027 | MOBILIER | Chaise 1 65 | Brique 1 | Etage 2 | 5 | Métal-Inox; Surface-Plastique stratifié | Sejour cuisine | Sejour cuisine | A23
Obj.-003 | Etage 2 | 1400 | 2.66 | 400 | 0.566521 | 1900 | 8500 | 0 | 14.0446 | 8993.34 | 493.337 | 8500 | 0 | 2226773 | -622021 | 354.2 | C10 | Obj.-003 | MOBILIER | Lit double_70 | Brique 1 | Etage 2 | 5 | Poutre; Revêt. sol | Ch 1 | Ch 1 | B21
Obj.-026 | Etage 2 | 1144.92 | 1.03042 | 730 | 0.0242125 | 900 | 8500 | 1.77636e-12 | 2.93436 | 9230 | 730 | 8500 | 1.77636e-12 | 2219791 | -639566 | 269.969 | C10 | Obj.-026 | MOBILIER | al_table Sting | Brique 1 | Etage 2 | 5 | Métal-Inox; Surface-Peinture brillante; Divers-Glace | Sejour cuisine | Sejour cuisine | B23
Obj.-027 | Etage 2 | 440 | 0.211011 | 450 | 0.0143427 | 479.571 | 8500 | 1.77636e-12 | 0.948533 | 9280 | 780 | 8500 | 1.77636e-12 | 2220345 | -640106 | 269.969 | C10 | Obj.-027 | MOBILIER | Chaise 1 65 | Brique 1 | Etage 2 | 5 | Métal-Inox; Surface-Plastique stratifié | Sejour cuisine | Sejour cuisine | B23
Obj.-027 | Etage 2 | 440 | 0.211011 | 450 | 0.0143427 | 479.571 | 8500 | 1.77636e-12 | 0.948533 | 9280 | 780 | 8500 | 1.77636e-12 | 2219937 | -639490 | 89.969 | C10 | Obj.-027 | MOBILIER | Chaise 1 65 | Brique 1 | Etage 2 | 5 | Métal-Inox; Surface-Plastique stratifié | Sejour cuisine | Sejour cuisine | B23
Obj.-027 | Etage 2 | 440 | 0.211011 | 450 | 0.0143427 | 479.571 | 8500 | 1.77636e-12 | 0.948533 | 9280 | 780 | 8500 | 1.77636e-12 | 2228692 | -655605 | 270.005 | C10 | Obj.-027 | MOBILIER | Chaise 1 65 | Brique 1 | Etage 2 | 5 | Métal-Inox; Surface-Plastique stratifié | Sejour cuisine | Sejour cuisine | B25
Obj.-027 | Etage 2 | 440 | 0.211011 | 450 | 0.0143427 | 479.571 | 8500 | 1.77636e-12 | 0.948533 | 9280 | 780 | 8500 | 1.77636e-12 | 2220345 | -639491 | 269.969 | C10 | Obj.-027 | MOBILIER | Chaise 1 65 | Brique 1 | Etage 2 | 5 | Métal-Inox; Surface-Plastique stratifié | Sejour cuisine | Sejour cuisine | B23
Obj.-034 | Etage 2 | 800 | 0.64 | 360 | 0.280139 | 800 | 9300 | 800 | 4.69089 | 9966.7 | 1466.7 | 9300 | 800 | 2231719 | -638450 | 180.036 | Revêt. pilier rond | Obj.-034 | MOBILIER | Fauteuil 65 | Brique 1 | Etage 2 | 5 | Plancher-Moquette; Revêt. pilier rond | Sejour cuisine | Sejour cuisine | B26
Obj.-027 | Etage 2 | 440 | 0.211011 | 450 | 0.0143427 | 479.571 | 8500 | 1.77636e-12 | 0.948533 | 9280 | 780 | 8500 | 1.77636e-12 | 2219937 | -640106 | 89.969 | C10 | Obj.-027 | MOBILIER | Chaise 1 65 | Brique 1 | Etage 2 | 5 | Métal-Inox; Surface-Plastique stratifié | Sejour cuisine | Sejour cuisine | B23
Obj.-027 | Etage 2 | 440 | 0.211011 | 450 | 0.0143427 | 479.571 | 8500 | 1.77636e-12 | 0.948533 | 9280 | 780 | 8500 | 1.77636e-12 | 2228193 | -628859 | 180 | C10 | Obj.-027 | MOBILIER | Chaise 1 65 | Brique 1 | Etage 2 | 5 | Métal-Inox; Surface-Plastique stratifié | Sejour cuisine | Sejour cuisine | B21
Obj.-026 | Etage 2 | 1200 | 1.08 | 730 | 0.0252536 | 900 | 8500 | 1.77636e-12 | 3.05224 | 9230 | 730 | 8500 | 1.77636e-12 | 2228213 | -629006 | 3.05333e-13 | C10 | Obj.-026 | MOBILIER | al_table Sting | Brique 1 | Etage 2 | 5 | Métal-Inox; Surface-Peinture brillante; Divers-Glace | Sejour cuisine | Sejour cuisine | B21
Obj.-003 | Etage 2 | 1400 | 2.66 | 400 | 0.566521 | 1900 | 8500 | 0 | 14.0446 | 8993.34 | 493.337 | 8500 | 0 | 2236768 | -608491 | 84.1973 | C10 | Obj.-003 | MOBILIER | Lit double_70 | Brique 1 | Etage 2 | 5 | Bois-Pin; Plancher-Moquette | Ch 1 | Ch 1 | A24
Obj.-027 | Etage 2 | 440 | 0.211011 | 450 | 0.0143427 | 479.571 | 8500 | 1.77636e-12 | 0.948533 | 9280 | 780 | 8500 | 1.77636e-12 | 2228193 | -628451 | 3.05333e-13 | C10 | Obj.-027 | MOBILIER | Chaise 1 65 | Brique 1 | Etage 2 | 5 | Métal-Inox; Surface-Plastique stratifié | Sejour cuisine | Sejour cuisine | B21
Obj.-027 | Etage 2 | 440 | 0.211011 | 450 | 0.0143427 | 479.571 | 8500 | 1.77636e-12 | 0.948533 | 9280 | 780 | 8500 | 1.77636e-12 | 2236691 | -616614 | 174.197 | C10 | Obj.-027 | MOBILIER | Chaise 1 65 | Brique 1 | Etage 2 | 5 | Métal-Inox; Surface-Plastique stratifié | Sejour cuisine/pl | Sejour cuisine/pl | A24
Obj.-027 | Etage 2 | 440 | 0.211011 | 450 | 0.0143427 | 479.571 | 8500 | 1.77636e-12 | 0.948533 | 9280 | 780 | 8500 | 1.77636e-12 | 2236079 | -616552 | 174.197 | C10 | Obj.-027 | MOBILIER | Chaise 1 65 | Brique 1 | Etage 2 | 5 | Métal-Inox; Surface-Plastique stratifié | Sejour cuisine/pl | Sejour cuisine/pl | A24
Obj.-026 | Etage 2 | 1200 | 1.08 | 730 | 0.0252536 | 900 | 8500 | 1.77636e-12 | 3.05224 | 9230 | 730 | 8500 | 1.77636e-12 | 2236155 | -616002 | 174.197 | C10 | Obj.-026 | MOBILIER | al_table Sting | Brique 1 | Etage 2 | 5 | Métal-Inox; Surface-Peinture brillante; Divers-Glace | Sejour cuisine/pl | Sejour cuisine/pl | A24
Obj.-027 | Etage 2 | 440 | 0.211011 | 450 | 0.0143427 | 479.571 | 8500 | 1.77636e-12 | 0.948533 | 9280 | 780 | 8500 | 1.77636e-12 | 2236733 | -616208 | 354.197 | C10 | Obj.-027 | MOBILIER | Chaise 1 65 | Brique 1 | Etage 2 | 5 | Métal-Inox; Surface-Plastique stratifié | Sejour cuisine/pl | Sejour cuisine/pl | A24
Obj.-034 | Etage 2 | 800 | 0.64 | 360 | 0.280139 | 800 | 8525 | 25 | 4.69089 | 9191.7 | 691.7 | 8525 | 25 | 2235066 | -617844 | 354.205 | Revêt. pilier rond | Obj.-034 | MOBILIER | Fauteuil 65 | Brique 1 | Etage 2 | 5 | Plancher-Moquette; Revêt. pilier rond | Sejour cuisine/pl | Sejour cuisine/pl | A24
Obj.-019 | Etage 2 | 600 | 0.36 | 900 | 0.314148 | 600 | 8500 | 0 | 4.5196 | 9400 | 900 | 8500 | 0 | 2229379 | -616664 | 84.1958 | Revêt. pilier rond | Obj.-019 | SANITAIRE | Réfrigérateur haut 65 | Brique 1 | Etage 2 | 5 | Métal-Chrome; Surface-Lavis Blanc | Sejour cuisine | Sejour cuisine | A23
Obj.-027 | Etage 2 | 440 | 0.211011 | 450 | 0.0143427 | 479.571 | 8500 | 1.77636e-12 | 0.948533 | 9280 | 780 | 8500 | 1.77636e-12 | 2236121 | -616146 | 354.197 | C10 | Obj.-027 | MOBILIER | Chaise 1 65 | Brique 1 | Etage 2 | 5 | Métal-Inox; Surface-Plastique stratifié | Sejour cuisine/pl | Sejour cuisine/pl | A24
Obj.-027 | Etage 2 | 440 | 0.211011 | 450 | 0.0143427 | 479.571 | 8500 | 1.77636e-12 | 0.948533 | 9280 | 780 | 8500 | 1.77636e-12 | 2228284 | -655606 | 90.0049 | C10 | Obj.-027 | MOBILIER | Chaise 1 65 | Brique 1 | Etage 2 | 5 | Métal-Inox; Surface-Plastique stratifié | Sejour cuisine | Sejour cuisine | B25
Obj.-003 | Etage 2 | 1400 | 2.66 | 400 | 0.566521 | 1900 | 8500 | 0 | 14.0446 | 8993.34 | 493.337 | 8500 | 0 | 2226485 | -618956 | 84.1973 | C10 | Obj.-003 | SANITAIRE | Lit double_70 | Brique 1 | Etage 2 | 5 | Poutre; Revêt. sol | Ch 1 | Ch 1 | A23
Obj.-027 | Etage 2 | 440 | 0.211011 | 450 | 0.0143427 | 479.571 | 8500 | 1.77636e-12 | 0.948533 | 9280 | 780 | 8500 | 1.77636e-12 | 2230043 | -639286 | 269.995 | C10 | Obj.-027 | MOBILIER | Chaise 1 65 | Brique 1 | Etage 2 | 5 | Métal-Inox; Surface-Plastique stratifié | Sejour cuisine | Sejour cuisine | B26
Obj.-034 | Etage 2 | 2229.78 | 0.334467 | 2500 | 0.0534734 | 150 | 8500 | 1.42109e-11 | 7.6753 | 11000 | 2500 | 8500 | 1.42109e-11 | 2224338 | -660048 | 90 | Revêt. pilier rond | Obj.-034 | 0-Resille Dampere | Barrière vitrée 65 | Brique 1 | Etage 2 | 5 | Divers-Eau; Peinture-05
Obj.-027 | Etage 2 | 440 | 0.211011 | 450 | 0.0143427 | 479.571 | 8500 | 1.77636e-12 | 0.948533 | 9280 | 780 | 8500 | 1.77636e-12 | 2229635 | -638670 | 89.9951 | C10 | Obj.-027 | MOBILIER | Chaise 1 65 | Brique 1 | Etage 2 | 5 | Métal-Inox; Surface-Plastique stratifié | Sejour cuisine | Sejour cuisine | B26
Obj.-027 | Etage 2 | 440 | 0.211011 | 450 | 0.0143427 | 479.571 | 8500 | 1.77636e-12 | 0.948533 | 9280 | 780 | 8500 | 1.77636e-12 | 2219773 | -654872 | 269.995 | C10 | Obj.-027 | MOBILIER | Chaise 1 65 | Brique 1 | Etage 2 | 5 | Métal-Inox; Surface-Plastique stratifié | Sejour cuisine | Sejour cuisine | B24
Obj.-027 | Etage 2 | 440 | 0.211011 | 450 | 0.0143427 | 479.571 | 8500 | 1.77636e-12 | 0.948533 | 9280 | 780 | 8500 | 1.77636e-12 | 2219773 | -655487 | 269.995 | C10 | Obj.-027 | MOBILIER | Chaise 1 65 | Brique 1 | Etage 2 | 5 | Métal-Inox; Surface-Plastique stratifié | Sejour cuisine | Sejour cuisine | B24
Obj.-027 | Etage 2 | 440 | 0.211011 | 450 | 0.0143427 | 479.571 | 8500 | 1.77636e-12 | 0.948533 | 9280 | 780 | 8500 | 1.77636e-12 | 2228692 | -654990 | 270.005 | C10 | Obj.-027 | MOBILIER | Chaise 1 65 | Brique 1 | Etage 2 | 5 | Métal-Inox; Surface-Plastique stratifié | Sejour cuisine | Sejour cuisine | B25
Obj.-026 | Etage 2 | 1200 | 1.08 | 730 | 0.0252536 | 900 | 8500 | 1.77636e-12 | 3.05224 | 9230 | 730 | 8500 | 1.77636e-12 | 2219919 | -654892 | 89.9951 | C10 | Obj.-026 | MOBILIER | al_table Sting | Brique 1 | Etage 2 | 5 | Métal-Inox; Surface-Peinture brillante; Divers-Glace | Sejour cuisine | Sejour cuisine | B24
Obj.-027 | Etage 2 | 440 | 0.211011 | 450 | 0.0143427 | 479.571 | 8500 | 1.77636e-12 | 0.948533 | 9280 | 780 | 8500 | 1.77636e-12 | 2219364 | -655487 | 89.9951 | C10 | Obj.-027 | MOBILIER | Chaise 1 65 | Brique 1 | Etage 2 | 5 | Métal-Inox; Surface-Plastique stratifié | Sejour cuisine | Sejour cuisine | B24
Obj.-034 | Etage 2 | 800 | 0.64 | 360 | 0.280139 | 800 | 8500 | 1.95399e-11 | 4.69089 | 9166.7 | 666.7 | 8500 | 1.95399e-11 | 2222793 | -654057 | 0 | Revêt. pilier rond | Obj.-034 | MOBILIER | Fauteuil 65 | Brique 1 | Etage 2 | 5 | Plancher-Moquette; Revêt. pilier rond | Sejour cuisine | Sejour cuisine | B24
Obj.-027 | Etage 2 | 440 | 0.211011 | 450 | 0.0143427 | 479.571 | 8500 | 1.77636e-12 | 0.948533 | 9280 | 780 | 8500 | 1.77636e-12 | 2219365 | -654872 | 89.9951 | C10 | Obj.-027 | MOBILIER | Chaise 1 65 | Brique 1 | Etage 2 | 5 | Métal-Inox; Surface-Plastique stratifié | Sejour cuisine | Sejour cuisine | B24
Obj.-027 | Etage 2 | 440 | 0.211011 | 450 | 0.0143427 | 479.571 | 8500 | 1.77636e-12 | 0.948533 | 9280 | 780 | 8500 | 1.77636e-12 | 2228284 | -654990 | 90.0049 | C10 | Obj.-027 | MOBILIER | Chaise 1 65 | Brique 1 | Etage 2 | 5 | Métal-Inox; Surface-Plastique stratifié | Sejour cuisine | Sejour cuisine | B25
Obj.-002 | Etage 2 | 1800 | 1.44 | 600 | 0.0995281 | 800 | 8500 | 0 | 10.3313 | 9100 | 600 | 8500 | 0 | 2223332 | -646741 | 270 | Revêt. pilier rond | Obj.-002 | SANITAIRE | Baignoire 65 | Brique 1 | Etage 2 | 5 | Surface-Ceramiques vitrifiées | Sde | Sde | B24
Obj.-019 | Etage 2 | 600 | 0.36 | 900 | 0.314148 | 600 | 8500 | 0 | 4.5196 | 9400 | 900 | 8500 | 0 | 2228229 | -638115 | 359.964 | Revêt. pilier rond | Obj.-019 | SANITAIRE | Réfrigérateur haut 65 | Brique 1 | Etage 2 | 5 | Métal-Chrome; Surface-Lavis Blanc | Sejour cuisine | Sejour cuisine | B26
Obj.-027 | Etage 2 | 440 | 0.211011 | 450 | 0.0143427 | 479.571 | 8500 | 1.77636e-12 | 0.948533 | 9280 | 780 | 8500 | 1.77636e-12 | 2229634 | -639286 | 89.9951 | C10 | Obj.-027 | MOBILIER | Chaise 1 65 | Brique 1 | Etage 2 | 5 | Métal-Inox; Surface-Plastique stratifié | Sejour cuisine | Sejour cuisine | B26
Obj.-027 | Etage 2 | 440 | 0.211011 | 450 | 0.0143427 | 479.571 | 8500 | 1.77636e-12 | 0.948533 | 9280 | 780 | 8500 | 1.77636e-12 | 2230043 | -638671 | 269.995 | C10 | Obj.-027 | MOBILIER | Chaise 1 65 | Brique 1 | Etage 2 | 5 | Métal-Inox; Surface-Plastique stratifié | Sejour cuisine | Sejour cuisine | B26
Obj.-003 | Etage 2 | 1400 | 2.66 | 400 | 0.566521 | 1900 | 8500 | 0 | 14.0446 | 8993.34 | 493.337 | 8500 | 0 | 2230817 | -646738 | 180 | C10 | Obj.-003 | SANITAIRE | Lit double_70 | Brique 1 | Etage 2 | 5 | Bois-Pin; Plancher-Moquette | Ch 1/pl | Ch 1/pl | B26
Obj.-003 | Etage 2 | 1400 | 2.66 | 400 | 0.566521 | 1900 | 8500 | 0 | 14.0446 | 8993.34 | 493.337 | 8500 | 0 | 2218719 | -632614 | 360 | C10 | Obj.-003 | SANITAIRE | Lit double_70 | Brique 1 | Etage 2 | 5 | Poteaux | Ch 1/pl | Ch 1/pl | B23
Obj.-003 | Etage 2 | 1400 | 2.66 | 400 | 0.566521 | 1900 | 8500 | 0 | 14.0446 | 8993.34 | 493.337 | 8500 | 0 | 2224312 | -655277 | 90 | C10 | Obj.-003 | MOBILIER | Lit double_70 | Brique 1 | Etage 2 | 5 | Poteaux | Ch 3 | Ch 3 | B25
Obj.-034 | Etage 2 | 800 | 0.64 | 360 | 0.280139 | 800 | 9300 | 800 | 4.69089 | 9966.7 | 1466.7 | 9300 | 800 | 2221761 | -622560 | 264.197 | Revêt. pilier rond | Obj.-034 | MOBILIER | Fauteuil 65 | Brique 1 | Etage 2 | 5 | Plancher-Moquette; Revêt. pilier rond | Sejour cuisine | Sejour cuisine | B22
Obj.-003 | Etage 3 | 1400 | 2.66 | 400 | 0.566521 | 1900 | 11550 | 0 | 14.0446 | 12043.3 | 493.337 | 11550 | 0 | 2220203 | -650884 | 179.983 | C10 | Obj.-003 | MOBILIER | Lit double_70 | Brique 1 | Etage 3 | 6 | Bois-Pin; Plancher-Moquette | Ch 2 | Ch 2 | B34
Obj.-027 | Etage 3 | 440 | 0.211011 | 450 | 0.0143427 | 479.571 | 11550 | 1.77636e-12 | 0.948533 | 12330 | 780 | 11550 | 1.77636e-12 | 2231464 | -649734 | 89.969 | C10 | Obj.-027 | MOBILIER | Chaise 1 65 | Brique 1 | Etage 3 | 6 | Métal-Inox; Surface-Plastique stratifié | Sejour cuisine | Sejour cuisine | B34
Obj.-027 | Etage 3 | 440 | 0.211011 | 450 | 0.0143427 | 479.571 | 11550 | 1.77636e-12 | 0.948533 | 12330 | 780 | 11550 | 1.77636e-12 | 2231463 | -650349 | 89.969 | C10 | Obj.-027 | MOBILIER | Chaise 1 65 | Brique 1 | Etage 3 | 6 | Métal-Inox; Surface-Plastique stratifié | Sejour cuisine | Sejour cuisine | B34
Obj.-027 | Etage 3 | 440 | 0.211011 | 450 | 0.0143427 | 479.571 | 11550 | 1.77636e-12 | 0.948533 | 12330 | 780 | 11550 | 1.77636e-12 | 2231463 | -650972 | 89.969 | C10 | Obj.-027 | MOBILIER | Chaise 1 65 | Brique 1 | Etage 3 | 6 | Métal-Inox; Surface-Plastique stratifié | Sejour cuisine | Sejour cuisine | B34
Obj.-019 | Etage 3 | 600 | 0.36 | 900 | 0.314148 | 600 | 11550 | 0 | 4.5196 | 12450 | 900 | 11550 | 0 | 2224132 | -623871 | 90 | Revêt. pilier rond | Obj.-019 | SANITAIRE | Réfrigérateur haut 65 | Brique 1 | Etage 3 | 6 | Métal-Chrome; Surface-Lavis Blanc | Sejour cuisine | Sejour cuisine | B32
Obj.-027 | Etage 3 | 440 | 0.211011 | 450 | 0.0143427 | 479.571 | 11550 | 1.77636e-12 | 0.948533 | 12330 | 780 | 11550 | 1.77636e-12 | 2231598 | -611020 | 84.1998 | C10 | Obj.-027 | MOBILIER | Chaise 1 65 | Brique 1 | Etage 3 | 6 | Métal-Inox; Surface-Plastique stratifié | Sejour cuisine/pl | Sejour cuisine/pl | A34
Obj.-027 | Etage 3 | 440 | 0.211011 | 450 | 0.0143427 | 479.571 | 11550 | 1.77636e-12 | 0.948533 | 12330 | 780 | 11550 | 1.77636e-12 | 2219837 | -639657 | 89.969 | C10 | Obj.-027 | MOBILIER | Chaise 1 65 | Brique 1 | Etage 3 | 6 | Métal-Inox; Surface-Plastique stratifié | Sejour cuisine | Sejour cuisine | B33
Obj.-002 | Etage 3 | 1800 | 1.44 | 600 | 0.0995281 | 800 | 11550 | 0 | 10.3313 | 12150 | 600 | 11550 | 0 | 2224582 | -618563 | 174.197 | Revêt. pilier rond | Obj.-002 | SANITAIRE | Baignoire 65 | Brique 1 | Etage 3 | 6 | Surface-Ceramiques vitrifiées | Sde1 | Sde1 | A31
Obj.-027 | Etage 3 | 440 | 0.211011 | 450 | 0.0143427 | 479.571 | 11550 | 1.77636e-12 | 0.948533 | 12330 | 780 | 11550 | 1.77636e-12 | 2220245 | -626046 | 270.031 | C10 | Obj.-027 | MOBILIER | Chaise 1 65 | Brique 1 | Etage 3 | 6 | Métal-Inox; Surface-Plastique stratifié | Sejour cuisine | Sejour cuisine | B32
Obj.-034 | Etage 3 | 1473.38 | 0.220611 | 2500 | 0.0462174 | 149.731 | 11550 | 1.42109e-11 | 5.38447 | 13950 | 2400 | 11550 | 1.42109e-11 | 2233601 | -622258 | 84.1973 | Revêt. pilier rond | Obj.-034 | 0-Resille Dampere | Barrière vitrée 65 | Brique 1 | Etage 3 | 6 | Divers-Eau; Peinture-05
Obj.-019 | Etage 3 | 600 | 0.36 | 900 | 0.314148 | 600 | 11550 | 0 | 4.5196 | 12450 | 900 | 11550 | 0 | 2229970 | -610844 | 84.1975 | Revêt. pilier rond | Obj.-019 | SANITAIRE | Réfrigérateur haut 65 | Brique 1 | Etage 3 | 6 | Métal-Chrome; Surface-Lavis Blanc | Sejour cuisine/pl | Sejour cuisine/pl | A34
Obj.-019 | Etage 3 | 600 | 0.36 | 900 | 0.314148 | 600 | 11550 | 0 | 4.5196 | 12450 | 900 | 11550 | 0 | 2238225 | -616213 | 264.324 | Revêt. pilier rond | Obj.-019 | SANITAIRE | Réfrigérateur haut 65 | Brique 1 | Etage 3 | 6 | Métal-Chrome; Surface-Lavis Blanc | Sejour cuisine/pl | Sejour cuisine/pl | A33
Obj.-034 | Etage 3 | 800 | 0.64 | 360 | 0.280139 | 800 | 12350 | 800 | 4.69089 | 13016.7 | 1466.7 | 12350 | 800 | 2223158 | -607549 | 354.161 | Revêt. pilier rond | Obj.-034 | MOBILIER | Fauteuil 65 | Brique 1 | Etage 3 | 6 | Plancher-Moquette; Revêt. pilier rond | Sejour cuisine/pl | Sejour cuisine/pl | A31
Obj.-027 | Etage 3 | 440 | 0.211011 | 450 | 0.0143427 | 479.571 | 11550 | 1.77636e-12 | 0.948533 | 12330 | 780 | 11550 | 1.77636e-12 | 2219451 | -608230 | 174.197 | C10 | Obj.-027 | MOBILIER | Chaise 1 65 | Brique 1 | Etage 3 | 6 | Métal-Inox; Surface-Plastique stratifié | Sejour cuisine/pl | Sejour cuisine/pl | A31
Obj.-027 | Etage 3 | 440 | 0.211011 | 450 | 0.0143427 | 479.571 | 11550 | 1.77636e-12 | 0.948533 | 12330 | 780 | 11550 | 1.77636e-12 | 2219492 | -607824 | 354.197 | C10 | Obj.-027 | MOBILIER | Chaise 1 65 | Brique 1 | Etage 3 | 6 | Métal-Inox; Surface-Plastique stratifié | Sejour cuisine/pl | Sejour cuisine/pl | A31
Obj.-027 | Etage 3 | 440 | 0.211011 | 450 | 0.0143427 | 479.571 | 11550 | 1.77636e-12 | 0.948533 | 12330 | 780 | 11550 | 1.77636e-12 | 2220104 | -607887 | 354.197 | C10 | Obj.-027 | MOBILIER | Chaise 1 65 | Brique 1 | Etage 3 | 6 | Métal-Inox; Surface-Plastique stratifié | Sejour cuisine/pl | Sejour cuisine/pl | A31
Obj.-026 | Etage 3 | 1200 | 1.08 | 730 | 0.0252536 | 900 | 11550 | 1.77636e-12 | 3.05224 | 12280 | 730 | 11550 | 1.77636e-12 | 2219527 | -607681 | 174.197 | C10 | Obj.-026 | MOBILIER | al_table Sting | Brique 1 | Etage 3 | 6 | Métal-Inox; Surface-Peinture brillante; Divers-Glace | Sejour cuisine/pl | Sejour cuisine/pl | A31
Obj.-027 | Etage 3 | 440 | 0.211011 | 450 | 0.0143427 | 479.571 | 11550 | 1.77636e-12 | 0.948533 | 12330 | 780 | 11550 | 1.77636e-12 | 2220063 | -608293 | 174.197 | C10 | Obj.-027 | MOBILIER | Chaise 1 65 | Brique 1 | Etage 3 | 6 | Métal-Inox; Surface-Plastique stratifié | Sejour cuisine/pl | Sejour cuisine/pl | A31
Obj.-019 | Etage 3 | 600 | 0.36 | 900 | 0.314148 | 600 | 11550 | 0 | 4.5196 | 12450 | 900 | 11550 | 0 | 2218739 | -611319 | 174.117 | Revêt. pilier rond | Obj.-019 | SANITAIRE | Réfrigérateur haut 65 | Brique 1 | Etage 3 | 6 | Métal-Chrome; Surface-Lavis Blanc | Sejour cuisine/pl | Sejour cuisine/pl | A31
Obj.-003 | Etage 3 | 900 | 1.71 | 400 | 0.364192 | 1900 | 11550 | 0 | 9.53161 | 12043.3 | 493.337 | 11550 | 0 | 2234032 | -609033 | 84.1973 | C10 | Obj.-003 | SANITAIRE | Lit double_70 | Brique 1 | Etage 3 | 6 | Bois-Pin; Plancher-Moquette | Ch 2/pl | Ch 2/pl | A33
Obj.-027 | Etage 3 | 440 | 0.211011 | 450 | 0.0143427 | 479.571 | 11550 | 1.77636e-12 | 0.948533 | 12330 | 780 | 11550 | 1.77636e-12 | 2231872 | -649734 | 269.969 | C10 | Obj.-027 | MOBILIER | Chaise 1 65 | Brique 1 | Etage 3 | 6 | Métal-Inox; Surface-Plastique stratifié | Sejour cuisine | Sejour cuisine | B34
Obj.-027 | Etage 3 | 440 | 0.211011 | 450 | 0.0143427 | 479.571 | 11550 | 1.77636e-12 | 0.948533 | 12330 | 780 | 11550 | 1.77636e-12 | 2231871 | -650349 | 269.969 | C10 | Obj.-027 | MOBILIER | Chaise 1 65 | Brique 1 | Etage 3 | 6 | Métal-Inox; Surface-Plastique stratifié | Sejour cuisine | Sejour cuisine | B34
Obj.-026 | Etage 3 | 1898.56 | 1.70871 | 730 | 0.0384564 | 900 | 11550 | 1.77636e-12 | 4.54716 | 12280 | 730 | 11550 | 1.77636e-12 | 2231317 | -649754 | 269.969 | C10 | Obj.-026 | MOBILIER | al_table Sting | Brique 1 | Etage 3 | 6 | Métal-Inox; Surface-Peinture brillante; Divers-Glace | Sejour cuisine | Sejour cuisine | B34
Obj.-027 | Etage 3 | 440 | 0.211011 | 450 | 0.0143427 | 479.571 | 11550 | 1.77636e-12 | 0.948533 | 12330 | 780 | 11550 | 1.77636e-12 | 2232004 | -611061 | 264.2 | C10 | Obj.-027 | MOBILIER | Chaise 1 65 | Brique 1 | Etage 3 | 6 | Métal-Inox; Surface-Plastique stratifié | Sejour cuisine/pl | Sejour cuisine/pl | A34
Obj.-002 | Etage 3 | 1800 | 1.44 | 600 | 0.0995281 | 800 | 11550 | 0 | 10.3313 | 12150 | 600 | 11550 | 0 | 2223332 | -646741 | 270 | Revêt. pilier rond | Obj.-002 | SANITAIRE | Baignoire 65 | Brique 1 | Etage 3 | 6 | Surface-Ceramiques vitrifiées | Sdb | Sdb | B34
Obj.-027 | Etage 3 | 440 | 0.211011 | 450 | 0.0143427 | 479.571 | 11550 | 1.77636e-12 | 0.948533 | 12330 | 780 | 11550 | 1.77636e-12 | 2219837 | -625431 | 90.031 | C10 | Obj.-027 | MOBILIER | Chaise 1 65 | Brique 1 | Etage 3 | 6 | Métal-Inox; Surface-Plastique stratifié | Sejour cuisine | Sejour cuisine | B32
Obj.-003 | Etage 3 | 1400 | 2.66 | 400 | 0.566521 | 1900 | 11550 | 0 | 14.0446 | 12043.3 | 493.337 | 11550 | 0 | 2228066 | -609929 | 174.188 | C10 | Obj.-003 | MOBILIER | Lit double_70 | Brique 1 | Etage 3 | 6 | Bois-Pin; Plancher-Moquette | Ch 1 | Ch 1 | A34
Obj.-003 | Etage 3 | 900 | 1.71 | 400 | 0.364192 | 1900 | 11550 | 0 | 9.53161 | 12043.3 | 493.337 | 11550 | 0 | 2219858 | -614706 | 174.197 | C10 | Obj.-003 | SANITAIRE | Lit double_70 | Brique 1 | Etage 3 | 6 | Bois-Pin; Plancher-Moquette | Ch 3 | Ch 3 | A31
Obj.-034 | Etage 3 | 1300 | 0.195 | 1900 | 0.0375 | 150 | 11550 | 1.42109e-11 | 3.9784 | 13450 | 1900 | 11550 | 1.42109e-11 | 2234225 | -607138 | 84.1973 | Revêt. pilier rond | Obj.-034 | 0-Resille Dampere | Barrière vitrée 65 | Brique 1 | Etage 3 | 6 | Divers-Eau; Peinture-05
Obj.-019 | Etage 3 | 600 | 0.36 | 900 | 0.314148 | 600 | 11550 | 0 | 4.5196 | 12450 | 900 | 11550 | 0 | 2231665 | -647677 | 0.151258 | Revêt. pilier rond | Obj.-019 | SANITAIRE | Réfrigérateur haut 65 | Brique 1 | Etage 3 | 6 | Métal-Chrome; Surface-Lavis Blanc | Sejour cuisine | Sejour cuisine | B34
Obj.-003 | Etage 3 | 1400 | 2.66 | 400 | 0.566521 | 1900 | 11550 | 0 | 14.0446 | 12043.3 | 493.337 | 11550 | 0 | 2226485 | -618956 | 84.1973 | C10 | Obj.-003 | SANITAIRE | Lit double_70 | Brique 1 | Etage 3 | 6 | Poutre; Revêt. sol | Ch 1 | Ch 1 | A32
Obj.-026 | Etage 3 | 758.193 | 0.682373 | 730 | 0.0169034 | 900 | 11550 | 1.77636e-12 | 2.10677 | 12280 | 730 | 11550 | 1.77636e-12 | 2232144 | -611130 | 84.1998 | C10 | Obj.-026 | MOBILIER | al_table Sting | Brique 1 | Etage 3 | 6 | Métal-Inox; Surface-Peinture brillante; Divers-Glace | Sejour cuisine/pl | Sejour cuisine/pl | A34
Obj.-027 | Etage 3 | 440 | 0.211011 | 450 | 0.0143427 | 479.571 | 11550 | 1.77636e-12 | 0.948533 | 12330 | 780 | 11550 | 1.77636e-12 | 2228796 | -639401 | 89.9951 | C10 | Obj.-027 | MOBILIER | Chaise 1 65 | Brique 1 | Etage 3 | 6 | Métal-Inox; Surface-Plastique stratifié | Sejour cuisine/pl | Sejour cuisine/pl | B35
Obj.-034 | Etage 3 | 800 | 0.64 | 360 | 0.280139 | 800 | 12350 | 800 | 4.69089 | 13016.7 | 1466.7 | 12350 | 800 | 2221856 | -622578 | 269.964 | Revêt. pilier rond | Obj.-034 | MOBILIER | Fauteuil 65 | Brique 1 | Etage 3 | 6 | Plancher-Moquette; Revêt. pilier rond | Sejour cuisine | Sejour cuisine | B32
Obj.-019 | Etage 3 | 600 | 0.36 | 900 | 0.314148 | 600 | 11550 | 0 | 4.5196 | 12450 | 900 | 11550 | 0 | 2226492 | -631658 | 90 | Revêt. pilier rond | Obj.-019 | SANITAIRE | Réfrigérateur haut 65 | Brique 1 | Etage 3 | 6 | Métal-Chrome; Surface-Lavis Blanc | Sejour cuisine/pl | Sejour cuisine/pl | B31
Obj.-027 | Etage 3 | 440 | 0.211011 | 450 | 0.0143427 | 479.571 | 11550 | 1.77636e-12 | 0.948533 | 12330 | 780 | 11550 | 1.77636e-12 | 2219837 | -639042 | 89.969 | C10 | Obj.-027 | MOBILIER | Chaise 1 65 | Brique 1 | Etage 3 | 6 | Métal-Inox; Surface-Plastique stratifié | Sejour cuisine | Sejour cuisine | B33
Obj.-003 | Etage 3 | 900 | 1.71 | 400 | 0.364192 | 1900 | 11550 | 0 | 9.53161 | 12043.3 | 493.337 | 11550 | 0 | 2218453 | -635793 | 359.95 | C10 | Obj.-003 | SANITAIRE | Lit double_70 | Brique 1 | Etage 3 | 6 | Bois-Pin; Plancher-Moquette | Ch 2 | Ch 2 | B33
Obj.-027 | Etage 3 | 440 | 0.211011 | 450 | 0.0143427 | 479.571 | 11550 | 1.77636e-12 | 0.948533 | 12330 | 780 | 11550 | 1.77636e-12 | 2220245 | -639042 | 269.969 | C10 | Obj.-027 | MOBILIER | Chaise 1 65 | Brique 1 | Etage 3 | 6 | Métal-Inox; Surface-Plastique stratifié | Sejour cuisine | Sejour cuisine | B33
Obj.-027 | Etage 3 | 440 | 0.211011 | 450 | 0.0143427 | 479.571 | 11550 | 1.77636e-12 | 0.948533 | 12330 | 780 | 11550 | 1.77636e-12 | 2228796 | -638786 | 89.9951 | C10 | Obj.-027 | MOBILIER | Chaise 1 65 | Brique 1 | Etage 3 | 6 | Métal-Inox; Surface-Plastique stratifié | Sejour cuisine/pl | Sejour cuisine/pl | B35
Obj.-003 | Etage 3 | 900 | 1.71 | 400 | 0.364192 | 1900 | 11550 | 0 | 9.53161 | 12043.3 | 493.337 | 11550 | 0 | 2230615 | -641026 | 359.95 | C10 | Obj.-003 | SANITAIRE | Lit double_70 | Brique 1 | Etage 3 | 6 | Bois-Pin; Plancher-Moquette | Ch 2 | Ch 2 | B35
Obj.-027 | Etage 3 | 440 | 0.211011 | 450 | 0.0143427 | 479.571 | 11550 | 1.77636e-12 | 0.948533 | 12330 | 780 | 11550 | 1.77636e-12 | 2229204 | -639401 | 269.995 | C10 | Obj.-027 | MOBILIER | Chaise 1 65 | Brique 1 | Etage 3 | 6 | Métal-Inox; Surface-Plastique stratifié | Sejour cuisine/pl | Sejour cuisine/pl | B35
Obj.-026 | Etage 3 | 1144.92 | 1.03042 | 730 | 0.0242125 | 900 | 11550 | 1.77636e-12 | 2.93436 | 12280 | 730 | 11550 | 1.77636e-12 | 2219691 | -625971 | 270.031 | C10 | Obj.-026 | MOBILIER | al_table Sting | Brique 1 | Etage 3 | 6 | Métal-Inox; Surface-Peinture brillante; Divers-Glace | Sejour cuisine | Sejour cuisine | B32
Obj.-003 | Etage 3 | 900 | 1.71 | 400 | 0.364192 | 1900 | 11550 | 0 | 9.53161 | 12043.3 | 493.337 | 11550 | 0 | 2220021 | -644197 | 359.95 | C10 | Obj.-003 | SANITAIRE | Lit double_70 | Brique 1 | Etage 3 | 6 | Bois-Pin; Plancher-Moquette | Ch 3 | Ch 3 | B34
Obj.-034 | Etage 3 | 800 | 0.64 | 360 | 0.280139 | 800 | 12350 | 800 | 4.69089 | 13016.7 | 1466.7 | 12350 | 800 | 2231719 | -638450 | 180.036 | Revêt. pilier rond | Obj.-034 | MOBILIER | Fauteuil 65 | Brique 1 | Etage 3 | 6 | Plancher-Moquette; Revêt. pilier rond | Sejour cuisine/pl | Sejour cuisine/pl | B35
Obj.-026 | Etage 3 | 1200 | 1.08 | 730 | 0.0252536 | 900 | 11550 | 1.77636e-12 | 3.05224 | 12280 | 730 | 11550 | 1.77636e-12 | 2228213 | -628840 | 3.05333e-13 | C10 | Obj.-026 | MOBILIER | al_table Sting | Brique 1 | Etage 3 | 6 | Métal-Inox; Surface-Peinture brillante; Divers-Glace | Sejour cuisine/pl | Sejour cuisine/pl | B31
Obj.-026 | Etage 3 | 1200 | 1.08 | 730 | 0.0252536 | 900 | 11550 | 1.77636e-12 | 3.05224 | 12280 | 730 | 11550 | 1.77636e-12 | 2229351 | -638806 | 89.9951 | C10 | Obj.-026 | MOBILIER | al_table Sting | Brique 1 | Etage 3 | 6 | Métal-Inox; Surface-Peinture brillante; Divers-Glace | Sejour cuisine/pl | Sejour cuisine/pl | B35
Obj.-027 | Etage 3 | 440 | 0.211011 | 450 | 0.0143427 | 479.571 | 11550 | 1.77636e-12 | 0.948533 | 12330 | 780 | 11550 | 1.77636e-12 | 2220245 | -625431 | 270.031 | C10 | Obj.-027 | MOBILIER | Chaise 1 65 | Brique 1 | Etage 3 | 6 | Métal-Inox; Surface-Plastique stratifié | Sejour cuisine | Sejour cuisine | B32
Obj.-027 | Etage 3 | 440 | 0.211011 | 450 | 0.0143427 | 479.571 | 11550 | 1.77636e-12 | 0.948533 | 12330 | 780 | 11550 | 1.77636e-12 | 2228808 | -628693 | 180 | C10 | Obj.-027 | MOBILIER | Chaise 1 65 | Brique 1 | Etage 3 | 6 | Métal-Inox; Surface-Plastique stratifié | Sejour cuisine/pl | Sejour cuisine/pl | B31
Obj.-027 | Etage 3 | 440 | 0.211011 | 450 | 0.0143427 | 479.571 | 11550 | 1.77636e-12 | 0.948533 | 12330 | 780 | 11550 | 1.77636e-12 | 2228808 | -628285 | 3.05333e-13 | C10 | Obj.-027 | MOBILIER | Chaise 1 65 | Brique 1 | Etage 3 | 6 | Métal-Inox; Surface-Plastique stratifié | Sejour cuisine/pl | Sejour cuisine/pl | B31
Obj.-027 | Etage 3 | 440 | 0.211011 | 450 | 0.0143427 | 479.571 | 11550 | 1.77636e-12 | 0.948533 | 12330 | 780 | 11550 | 1.77636e-12 | 2219837 | -626046 | 90.031 | C10 | Obj.-027 | MOBILIER | Chaise 1 65 | Brique 1 | Etage 3 | 6 | Métal-Inox; Surface-Plastique stratifié | Sejour cuisine | Sejour cuisine | B32
Obj.-003 | Etage 3 | 900 | 1.71 | 400 | 0.364192 | 1900 | 11550 | 0 | 9.53161 | 12043.3 | 493.337 | 11550 | 0 | 2218734 | -626412 | 359.95 | C10 | Obj.-003 | SANITAIRE | Lit double_70 | Brique 1 | Etage 3 | 6 | Bois-Pin; Plancher-Moquette | Ch 2 | Ch 2 | B32
Obj.-034 | Etage 3 | 800 | 0.64 | 360 | 0.280139 | 800 | 11550 | 1.77636e-12 | 4.69089 | 12216.7 | 666.7 | 11550 | 1.77636e-12 | 2225548 | -650754 | 359.964 | Revêt. pilier rond | Obj.-034 | MOBILIER | Fauteuil 65 | Brique 1 | Etage 3 | 6 | Plancher-Moquette; Revêt. pilier rond | Sejour cuisine | Sejour cuisine | B34
Obj.-034 | Etage 3 | 800 | 0.64 | 360 | 0.280139 | 800 | 12350 | 800 | 4.69089 | 13016.7 | 1466.7 | 12350 | 800 | 2221923 | -642912 | 269.964 | Revêt. pilier rond | Obj.-034 | 0-Resille Dampere | Fauteuil 65 | Brique 1 | Etage 3 | 6 | Plancher-Moquette; Revêt. pilier rond | Sejour cuisine | Sejour cuisine | B33
Obj.-027 | Etage 3 | 440 | 0.211011 | 450 | 0.0143427 | 479.571 | 11550 | 1.77636e-12 | 0.948533 | 12330 | 780 | 11550 | 1.77636e-12 | 2220245 | -639657 | 269.969 | C10 | Obj.-027 | MOBILIER | Chaise 1 65 | Brique 1 | Etage 3 | 6 | Métal-Inox; Surface-Plastique stratifié | Sejour cuisine | Sejour cuisine | B33
Obj.-026 | Etage 3 | 1144.92 | 1.03042 | 730 | 0.0242125 | 900 | 11550 | 1.77636e-12 | 2.93436 | 12280 | 730 | 11550 | 1.77636e-12 | 2219691 | -639117 | 269.969 | C10 | Obj.-026 | MOBILIER | al_table Sting | Brique 1 | Etage 3 | 6 | Métal-Inox; Surface-Peinture brillante; Divers-Glace | Sejour cuisine | Sejour cuisine | B33
Obj.-027 | Etage 3 | 440 | 0.211011 | 450 | 0.0143427 | 479.571 | 11550 | 1.77636e-12 | 0.948533 | 12330 | 780 | 11550 | 1.77636e-12 | 2231871 | -650973 | 269.969 | C10 | Obj.-027 | MOBILIER | Chaise 1 65 | Brique 1 | Etage 3 | 6 | Métal-Inox; Surface-Plastique stratifié | Sejour cuisine | Sejour cuisine | B34
Obj.-027 | Etage 3 | 440 | 0.211011 | 450 | 0.0143427 | 479.571 | 11550 | 1.77636e-12 | 0.948533 | 12330 | 780 | 11550 | 1.77636e-12 | 2228193 | -628693 | 180 | C10 | Obj.-027 | MOBILIER | Chaise 1 65 | Brique 1 | Etage 3 | 6 | Métal-Inox; Surface-Plastique stratifié | Sejour cuisine/pl | Sejour cuisine/pl | B31
Obj.-027 | Etage 3 | 440 | 0.211011 | 450 | 0.0143427 | 479.571 | 11550 | 1.77636e-12 | 0.948533 | 12330 | 780 | 11550 | 1.77636e-12 | 2228193 | -628285 | 3.05333e-13 | C10 | Obj.-027 | MOBILIER | Chaise 1 65 | Brique 1 | Etage 3 | 6 | Métal-Inox; Surface-Plastique stratifié | Sejour cuisine/pl | Sejour cuisine/pl | B31
Obj.-034 | Etage 3 | 800 | 0.64 | 360 | 0.280139 | 800 | 11550 | 1.77636e-12 | 4.69089 | 12216.7 | 666.7 | 11550 | 1.77636e-12 | 2225515 | -652639 | 180.036 | Revêt. pilier rond | Obj.-034 | MOBILIER | Fauteuil 65 | Brique 1 | Etage 3 | 6 | Plancher-Moquette; Revêt. pilier rond | Sejour cuisine | Sejour cuisine | B34
Obj.-019 | Etage 3 | 600 | 0.36 | 900 | 0.314148 | 600 | 11550 | 0 | 4.5196 | 12450 | 900 | 11550 | 0 | 2222857 | -639252 | 0 | Revêt. pilier rond | Obj.-019 | SANITAIRE | Réfrigérateur haut 65 | Brique 1 | Etage 3 | 6 | Métal-Chrome; Surface-Lavis Blanc | Sejour cuisine | Sejour cuisine | B33
Obj.-027 | Etage 3 | 440 | 0.211011 | 450 | 0.0143427 | 479.571 | 11550 | 1.77636e-12 | 0.948533 | 12330 | 780 | 11550 | 1.77636e-12 | 2237096 | -616866 | 354.228 | C10 | Obj.-027 | MOBILIER | Chaise 1 65 | Brique 1 | Etage 3 | 6 | Métal-Inox; Surface-Plastique stratifié | Sejour cuisine/pl | Sejour cuisine/pl | A33
Obj.-027 | Etage 3 | 440 | 0.211011 | 450 | 0.0143427 | 479.571 | 11550 | 1.77636e-12 | 0.948533 | 12330 | 780 | 11550 | 1.77636e-12 | 2237667 | -617334 | 174.228 | C10 | Obj.-027 | MOBILIER | Chaise 1 65 | Brique 1 | Etage 3 | 6 | Métal-Inox; Surface-Plastique stratifié | Sejour cuisine/pl | Sejour cuisine/pl | A33
Obj.-034 | Etage 3 | 800 | 0.64 | 360 | 0.280139 | 800 | 11550 | 0 | 4.69089 | 12216.7 | 666.7 | 11550 | 0 | 2236451 | -618652 | 264.233 | Revêt. pilier rond | Obj.-034 | MOBILIER | Fauteuil 65 | Brique 1 | Etage 3 | 6 | Plancher-Moquette; Revêt. pilier rond | Sejour cuisine/pl | Sejour cuisine/pl | A33
Obj.-026 | Etage 3 | 1200 | 1.08 | 730 | 0.0252536 | 900 | 11550 | 1.77636e-12 | 3.05224 | 12280 | 730 | 11550 | 1.77636e-12 | 2237703 | -616780 | 174.228 | C10 | Obj.-026 | MOBILIER | al_table Sting | Brique 1 | Etage 3 | 6 | Métal-Inox; Surface-Peinture brillante; Divers-Glace | Sejour cuisine/pl | Sejour cuisine/pl | A33
Obj.-027 | Etage 3 | 440 | 0.211011 | 450 | 0.0143427 | 479.571 | 11550 | 1.77636e-12 | 0.948533 | 12330 | 780 | 11550 | 1.77636e-12 | 2237055 | -617272 | 174.228 | C10 | Obj.-027 | MOBILIER | Chaise 1 65 | Brique 1 | Etage 3 | 6 | Métal-Inox; Surface-Plastique stratifié | Sejour cuisine/pl | Sejour cuisine/pl | A33
Obj.-027 | Etage 3 | 440 | 0.211011 | 450 | 0.0143427 | 479.571 | 11550 | 1.77636e-12 | 0.948533 | 12330 | 780 | 11550 | 1.77636e-12 | 2237708 | -616928 | 354.228 | C10 | Obj.-027 | MOBILIER | Chaise 1 65 | Brique 1 | Etage 3 | 6 | Métal-Inox; Surface-Plastique stratifié | Sejour cuisine/pl | Sejour cuisine/pl | A33
Obj.-003 | Etage 3 | 1400 | 2.66 | 400 | 0.566521 | 1900 | 11550 | 0 | 14.0446 | 12043.3 | 493.337 | 11550 | 0 | 2219041 | -632434 | 180 | C10 | Obj.-003 | MOBILIER | Lit double_70 | Brique 1 | Etage 3 | 6 | Bois-Pin; Plancher-Moquette | Ch 1/pl | Ch 1/pl | B32
Obj.-003 | Etage 3 | 1400 | 2.66 | 400 | 0.566521 | 1900 | 11550 | 0 | 14.0446 | 12043.3 | 493.337 | 11550 | 0 | 2220386 | -620789 | 174.197 | C10 | Obj.-003 | MOBILIER | Lit double_70 | Brique 1 | Etage 3 | 6 | Bois-Pin; Plancher-Moquette | Ch 1 | Ch 1 | A31
Obj.-003 | Etage 3 | 1400 | 2.66 | 400 | 0.566521 | 1900 | 11550 | 0 | 14.0446 | 12043.3 | 493.337 | 11550 | 0 | 2236551 | -609626 | 84.1973 | C10 | Obj.-003 | MOBILIER | Lit double_70 | Brique 1 | Etage 3 | 6 | Bois-Pin; Plancher-Moquette | Ch 1 | Ch 1 | A33
Obj.-003 | Etage 3 | 1400 | 2.66 | 400 | 0.566521 | 1900 | 11550 | 0 | 14.0446 | 12043.3 | 493.337 | 11550 | 0 | 2227078 | -622052 | 354.2 | C10 | Obj.-003 | MOBILIER | Lit double_70 | Brique 1 | Etage 3 | 6 | Poutre; Revêt. sol | Ch 1/pl | Ch 1/pl | B31
Obj.-003 | Etage 3 | 1400 | 2.66 | 400 | 0.566521 | 1900 | 11550 | 0 | 14.0446 | 12043.3 | 493.337 | 11550 | 0 | 2218719 | -632614 | 360 | C10 | Obj.-003 | SANITAIRE | Lit double_70 | Brique 1 | Etage 3 | 6 | Poteaux | Ch 1/pl | Ch 1/pl | B33
Obj.-019 | Etage 3 | 600 | 0.36 | 900 | 0.314148 | 600 | 11550 | 0 | 4.5196 | 12450 | 900 | 11550 | 0 | 2228229 | -638115 | 359.964 | Revêt. pilier rond | Obj.-019 | SANITAIRE | Réfrigérateur haut 65 | Brique 1 | Etage 3 | 6 | Métal-Chrome; Surface-Lavis Blanc | Sejour cuisine/pl | Sejour cuisine/pl | B35
Obj.-027 | Etage 3 | 440 | 0.211011 | 450 | 0.0143427 | 479.571 | 11550 | 1.77636e-12 | 0.948533 | 12330 | 780 | 11550 | 1.77636e-12 | 2229204 | -638786 | 269.995 | C10 | Obj.-027 | MOBILIER | Chaise 1 65 | Brique 1 | Etage 3 | 6 | Métal-Inox; Surface-Plastique stratifié | Sejour cuisine/pl | Sejour cuisine/pl | B35
Obj.-003 | Etage 3 | 1400 | 2.66 | 400 | 0.566521 | 1900 | 11550 | 0 | 14.0446 | 12043.3 | 493.337 | 11550 | 0 | 2230817 | -646738 | 180 | C10 | Obj.-003 | SANITAIRE | Lit double_70 | Brique 1 | Etage 3 | 6 | Bois-Pin; Plancher-Moquette | Ch 1/pl | Ch 1/pl | B35
Obj.-026 | Etage 3 | 788.112 | 0.709301 | 730 | 0.0174689 | 900 | 11550 | 1.77636e-12 | 2.1708 | 12280 | 730 | 11550 | 1.77636e-12 | 2231199 | -617326 | 264.227 | C10 | Obj.-026 | MOBILIER | al_table Sting | Brique 1 | Etage 3 | 6 | Métal-Inox; Surface-Peinture brillante; Divers-Glace | Sejour cuisine | Sejour cuisine | A32
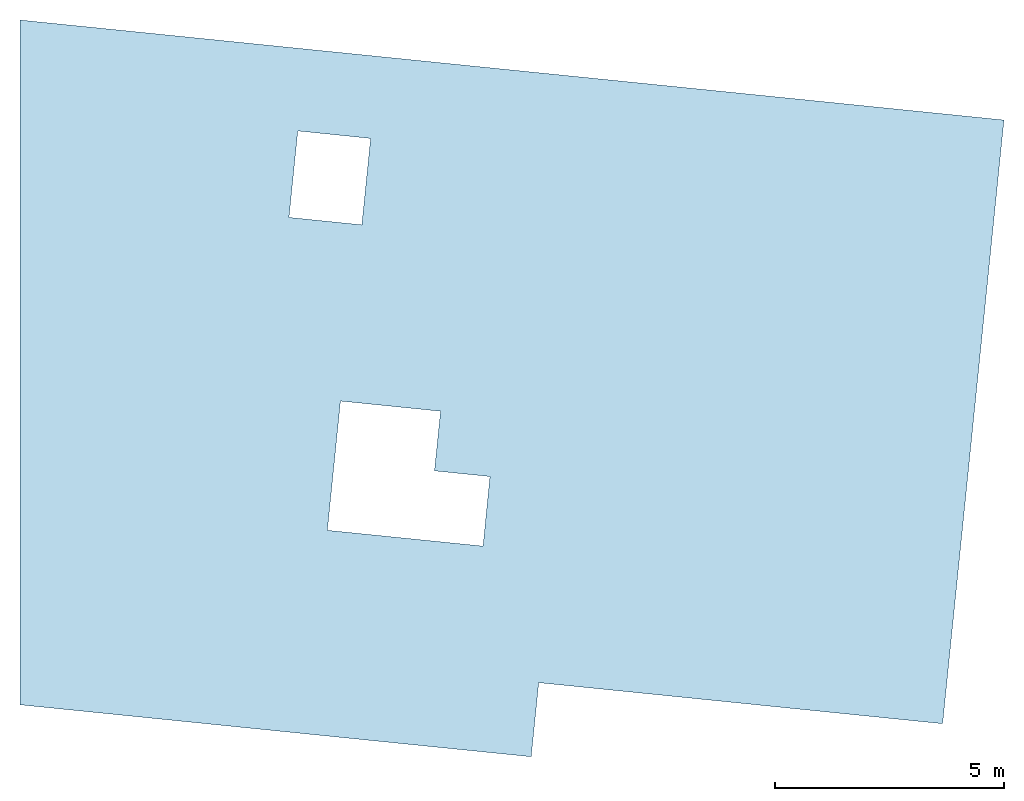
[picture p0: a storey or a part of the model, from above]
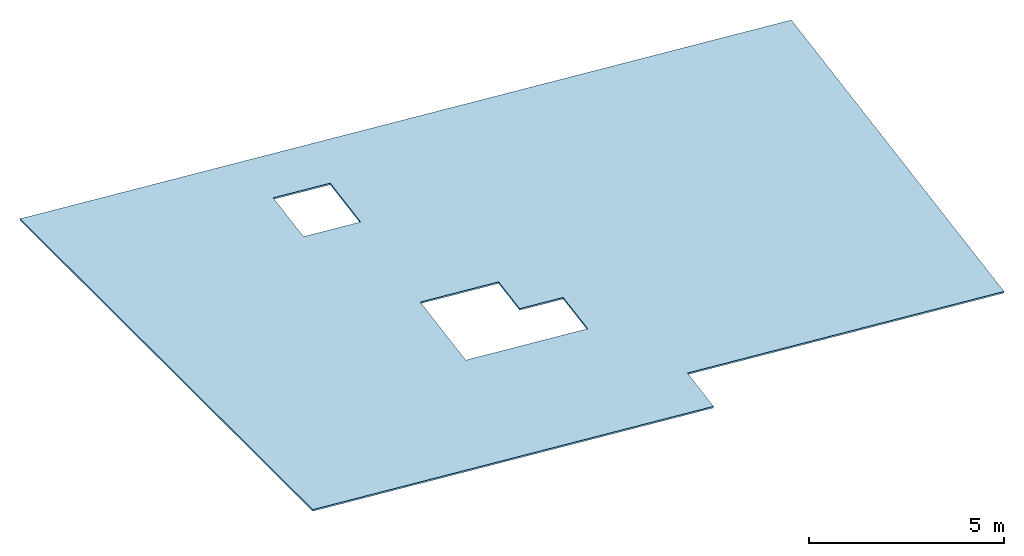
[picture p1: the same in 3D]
Properties of the parts of a building model (IFC2X3), part 6 of 44

# IfcBuildingElementProxy (454)
Name | In | Longueur (A) (mm) | Superficie (m2) = Superficie supérieure (nette) (m2) | Hauteur (mm) | Volume (net) (m3) | Largeur (mm) | Altitude à Zéro du Projet (mm) = Altitude de Référence Niveau 1 (mm) = Altitude de Référence Niveau 2 (mm) = Altitude à niveau de la mer (mm) = Coordonnée topographique Z (mm) | Altitude à étage lié/étage d'implantation (mm) = Décalage étage d'implantation (mm) | Superficie en plan (m2) = Superficie inférieure (nette) (m2) | Altitude supérieure à premier niveau de référence (mm) = Altitude supérieure à Zéro du projet (mm) = Altitude supérieure à niveau de la mer (mm) = Altitude supérieure à deuxième niveau de référence (mm) | Altitude supérieure à étage d'implantation (mm) | Altitude inférieure à premier niveau de référence (mm) = Altitude inférieure à Zéro du projet (mm) = Altitude inférieure à niveau de la mer (mm) = Altitude inférieure à deuxième niveau de référence (mm) | Altitude inférieure à étage d'implantation (mm) | Coordonnée topographique X (mm) | Coordonnée topographique Y (mm) | Angle de rotation (deg) | Surface | ID de l'élément = Lien et ID d'élément = ID de Parent | Calque | Nom Élément de Bibliothèque | Matériau de construction / Composite / Profil / Hachure = Type Hachure | Nom d'étage d'implantation | Numéro d'étage d'implantation | Surfaces (Toutes) | Zones conflictuelles | Nom de zone liée | Numéro de zone liée
Obj.-027 | Etage 3 | 440 | 0.211011 | 450 | 0.0143427 | 479.571 | 11550 | 1.77636e-12 | 0.948533 | 12330 | 780 | 11550 | 1.77636e-12 | 2231741 | -617478 | 264.227 | C10 | Obj.-027 | MOBILIER | Chaise 1 65 | Brique 1 | Etage 3 | 6 | Métal-Inox; Surface-Plastique stratifié | Sejour cuisine | Sejour cuisine | A32
Obj.-027 | Etage 3 | 440 | 0.211011 | 450 | 0.0143427 | 479.571 | 11550 | 1.77636e-12 | 0.948533 | 12330 | 780 | 11550 | 1.77636e-12 | 2231335 | -617437 | 84.2265 | C10 | Obj.-027 | MOBILIER | Chaise 1 65 | Brique 1 | Etage 3 | 6 | Métal-Inox; Surface-Plastique stratifié | Sejour cuisine | Sejour cuisine | A32
Obj.-003 | Etage 3 | 900 | 1.71 | 400 | 0.364192 | 1900 | 11550 | 0 | 9.53161 | 12043.3 | 493.337 | 11550 | 0 | 2219517 | -617568 | 174.197 | C10 | Obj.-003 | SANITAIRE | Lit double_70 | Brique 1 | Etage 3 | 6 | Bois-Pin; Plancher-Moquette | Ch 2 | Ch 2 | A31
Obj.-019 | Etage 3 | 600 | 0.36 | 900 | 0.314148 | 600 | 11550 | 0 | 4.5196 | 12450 | 900 | 11550 | 0 | 2229379 | -616664 | 84.1958 | Revêt. pilier rond | Obj.-019 | SANITAIRE | Réfrigérateur haut 65 | Brique 1 | Etage 3 | 6 | Métal-Chrome; Surface-Lavis Blanc | Sejour cuisine | Sejour cuisine | A32
Obj.-019 | etage 4 | 600 | 0.36 | 900 | 0.314148 | 600 | 14600 | 0 | 4.5196 | 15500 | 900 | 14600 | 0 | 2230042 | -647517 | 0.151258 | Revêt. pilier rond | Obj.-019 | SANITAIRE | Réfrigérateur haut 65 | Brique 1 | etage 4 | 7 | Métal-Chrome; Surface-Lavis Blanc | Sejour cuisine | Sejour cuisine | B44
Obj.-026 | etage 4 | 1200 | 1.08 | 730 | 0.0252536 | 900 | 14600 | 1.77636e-12 | 3.05224 | 15330 | 730 | 14600 | 1.77636e-12 | 2228213 | -629535 | 3.05333e-13 | C10 | Obj.-026 | MOBILIER | al_table Sting | Brique 1 | etage 4 | 7 | Métal-Inox; Surface-Peinture brillante; Divers-Glace | Sejour cuisine/pl | Sejour cuisine/pl | B41
Obj.-027 | etage 4 | 440 | 0.211011 | 450 | 0.0143427 | 479.571 | 14600 | 1.77636e-12 | 0.948533 | 15380 | 780 | 14600 | 1.77636e-12 | 2220245 | -625431 | 270.031 | C10 | Obj.-027 | MOBILIER | Chaise 1 65 | Brique 1 | etage 4 | 7 | Métal-Inox; Surface-Plastique stratifié | Sejour cuisine | Sejour cuisine | B42
Obj.-027 | etage 4 | 440 | 0.211011 | 450 | 0.0143427 | 479.571 | 14600 | 1.77636e-12 | 0.948533 | 15380 | 780 | 14600 | 1.77636e-12 | 2219837 | -626046 | 90.031 | C10 | Obj.-027 | MOBILIER | Chaise 1 65 | Brique 1 | etage 4 | 7 | Métal-Inox; Surface-Plastique stratifié | Sejour cuisine | Sejour cuisine | B42
Obj.-027 | etage 4 | 440 | 0.211011 | 450 | 0.0143427 | 479.571 | 14600 | 1.77636e-12 | 0.948533 | 15380 | 780 | 14600 | 1.77636e-12 | 2220245 | -639657 | 269.969 | C10 | Obj.-027 | MOBILIER | Chaise 1 65 | Brique 1 | etage 4 | 7 | Métal-Inox; Surface-Plastique stratifié | Sejour cuisine | Sejour cuisine | B43
Obj.-027 | etage 4 | 440 | 0.211011 | 450 | 0.0143427 | 479.571 | 14600 | 1.77636e-12 | 0.948533 | 15380 | 780 | 14600 | 1.77636e-12 | 2228808 | -629388 | 180 | C10 | Obj.-027 | MOBILIER | Chaise 1 65 | Brique 1 | etage 4 | 7 | Métal-Inox; Surface-Plastique stratifié | Sejour cuisine/pl | Sejour cuisine/pl | B41
Obj.-019 | etage 4 | 600 | 0.36 | 900 | 0.314148 | 600 | 14600 | 0 | 4.5196 | 15500 | 900 | 14600 | 0 | 2222857 | -639252 | 0 | Revêt. pilier rond | Obj.-019 | SANITAIRE | Réfrigérateur haut 65 | Brique 1 | etage 4 | 7 | Métal-Chrome; Surface-Lavis Blanc | Sejour cuisine | Sejour cuisine | B43
Obj.-027 | etage 4 | 440 | 0.211011 | 450 | 0.0143427 | 479.571 | 14600 | 1.77636e-12 | 0.948533 | 15380 | 780 | 14600 | 1.77636e-12 | 2220245 | -639042 | 269.969 | C10 | Obj.-027 | MOBILIER | Chaise 1 65 | Brique 1 | etage 4 | 7 | Métal-Inox; Surface-Plastique stratifié | Sejour cuisine | Sejour cuisine | B43
Obj.-003 | etage 4 | 900 | 1.71 | 400 | 0.364192 | 1900 | 14600 | 0 | 9.53161 | 15093.3 | 493.337 | 14600 | 0 | 2229492 | -641025 | 2.03555e-13 | C10 | Obj.-003 | SANITAIRE | Lit double_70 | Brique 1 | etage 4 | 7 | Bois-Pin; Plancher-Moquette | Ch 2 | Ch 2 | B44
Obj.-027 | etage 4 | 440 | 0.211011 | 450 | 0.0143427 | 479.571 | 14600 | 1.77636e-12 | 0.948533 | 15380 | 780 | 14600 | 1.77636e-12 | 2219837 | -625431 | 90.031 | C10 | Obj.-027 | MOBILIER | Chaise 1 65 | Brique 1 | etage 4 | 7 | Métal-Inox; Surface-Plastique stratifié | Sejour cuisine | Sejour cuisine | B42
Obj.-027 | etage 4 | 440 | 0.211011 | 450 | 0.0143427 | 479.571 | 14600 | 1.77636e-12 | 0.948533 | 15380 | 780 | 14600 | 1.77636e-12 | 2219837 | -639657 | 89.969 | C10 | Obj.-027 | MOBILIER | Chaise 1 65 | Brique 1 | etage 4 | 7 | Métal-Inox; Surface-Plastique stratifié | Sejour cuisine | Sejour cuisine | B43
Obj.-027 | etage 4 | 440 | 0.211011 | 450 | 0.0143427 | 479.571 | 14600 | 1.77636e-12 | 0.948533 | 15380 | 780 | 14600 | 1.77636e-12 | 2219837 | -639042 | 89.969 | C10 | Obj.-027 | MOBILIER | Chaise 1 65 | Brique 1 | etage 4 | 7 | Métal-Inox; Surface-Plastique stratifié | Sejour cuisine | Sejour cuisine | B43
Obj.-027 | etage 4 | 440 | 0.211011 | 450 | 0.0143427 | 479.571 | 14600 | 1.77636e-12 | 0.948533 | 15380 | 780 | 14600 | 1.77636e-12 | 2228193 | -628980 | 3.05333e-13 | C10 | Obj.-027 | MOBILIER | Chaise 1 65 | Brique 1 | etage 4 | 7 | Métal-Inox; Surface-Plastique stratifié | Sejour cuisine/pl | Sejour cuisine/pl | B41
Obj.-026 | etage 4 | 1144.92 | 1.03042 | 730 | 0.0242125 | 900 | 14600 | 1.77636e-12 | 2.93436 | 15330 | 730 | 14600 | 1.77636e-12 | 2219691 | -639117 | 269.969 | C10 | Obj.-026 | MOBILIER | al_table Sting | Brique 1 | etage 4 | 7 | Métal-Inox; Surface-Peinture brillante; Divers-Glace | Sejour cuisine | Sejour cuisine | B43
Obj.-027 | etage 4 | 440 | 0.211011 | 450 | 0.0143427 | 479.571 | 14600 | 1.77636e-12 | 0.948533 | 15380 | 780 | 14600 | 1.77636e-12 | 2220245 | -626046 | 270.031 | C10 | Obj.-027 | MOBILIER | Chaise 1 65 | Brique 1 | etage 4 | 7 | Métal-Inox; Surface-Plastique stratifié | Sejour cuisine | Sejour cuisine | B42
Obj.-027 | etage 4 | 440 | 0.211011 | 450 | 0.0143427 | 479.571 | 14600 | 1.77636e-12 | 0.948533 | 15380 | 780 | 14600 | 1.77636e-12 | 2228808 | -628980 | 3.05333e-13 | C10 | Obj.-027 | MOBILIER | Chaise 1 65 | Brique 1 | etage 4 | 7 | Métal-Inox; Surface-Plastique stratifié | Sejour cuisine/pl | Sejour cuisine/pl | B41
Obj.-034 | etage 4 | 800 | 0.64 | 360 | 0.280139 | 800 | 15400 | 800 | 4.69089 | 16066.7 | 1466.7 | 15400 | 800 | 2221923 | -642912 | 269.964 | Revêt. pilier rond | Obj.-034 | 0-Resille Dampere | Fauteuil 65 | Brique 1 | etage 4 | 7 | Plancher-Moquette; Revêt. pilier rond | Sejour cuisine | Sejour cuisine | B43
Obj.-026 | etage 4 | 1144.92 | 1.03042 | 730 | 0.0242125 | 900 | 14600 | 1.77636e-12 | 2.93436 | 15330 | 730 | 14600 | 1.77636e-12 | 2219691 | -625971 | 270.031 | C10 | Obj.-026 | MOBILIER | al_table Sting | Brique 1 | etage 4 | 7 | Métal-Inox; Surface-Peinture brillante; Divers-Glace | Sejour cuisine | Sejour cuisine | B42
Obj.-003 | etage 4 | 1400 | 2.66 | 400 | 0.566521 | 1900 | 14600 | 0 | 14.0446 | 15093.3 | 493.337 | 14600 | 0 | 2219041 | -632434 | 180 | C10 | Obj.-003 | SANITAIRE | Lit double_70 | Brique 1 | etage 4 | 7 | Bois-Pin; Plancher-Moquette | Ch 1/pl | Ch 1/pl | B42
Obj.-027 | etage 4 | 440 | 0.211011 | 450 | 0.0143427 | 479.571 | 14600 | 1.77636e-12 | 0.948533 | 15380 | 780 | 14600 | 1.77636e-12 | 2228193 | -629388 | 180 | C10 | Obj.-027 | MOBILIER | Chaise 1 65 | Brique 1 | etage 4 | 7 | Métal-Inox; Surface-Plastique stratifié | Sejour cuisine/pl | Sejour cuisine/pl | B41
Obj.-027 | etage 4 | 440 | 0.211011 | 450 | 0.0143427 | 479.571 | 14600 | 1.77636e-12 | 0.948533 | 15380 | 780 | 14600 | 1.77636e-12 | 2229694 | -649807 | 359.969 | C10 | Obj.-027 | MOBILIER | Chaise 1 65 | Brique 1 | etage 4 | 7 | Métal-Inox; Surface-Plastique stratifié | Sejour cuisine | Sejour cuisine | B44
Obj.-027 | etage 4 | 440 | 0.211011 | 450 | 0.0143427 | 479.571 | 14600 | 1.77636e-12 | 0.948533 | 15380 | 780 | 14600 | 1.77636e-12 | 2229694 | -650215 | 179.969 | C10 | Obj.-027 | MOBILIER | Chaise 1 65 | Brique 1 | etage 4 | 7 | Métal-Inox; Surface-Plastique stratifié | Sejour cuisine | Sejour cuisine | B44
Obj.-027 | etage 4 | 440 | 0.211011 | 450 | 0.0143427 | 479.571 | 14600 | 1.77636e-12 | 0.948533 | 15380 | 780 | 14600 | 1.77636e-12 | 2228456 | -649806 | 359.969 | C10 | Obj.-027 | MOBILIER | Chaise 1 65 | Brique 1 | etage 4 | 7 | Métal-Inox; Surface-Plastique stratifié | Sejour cuisine | Sejour cuisine | B44
Obj.-026 | etage 4 | 1898.56 | 1.70871 | 730 | 0.0384564 | 900 | 14600 | 1.77636e-12 | 4.54716 | 15330 | 730 | 14600 | 1.77636e-12 | 2229674 | -649660 | 179.969 | C10 | Obj.-026 | MOBILIER | al_table Sting | Brique 1 | etage 4 | 7 | Métal-Inox; Surface-Peinture brillante; Divers-Glace | Sejour cuisine | Sejour cuisine | B44
Obj.-027 | etage 4 | 440 | 0.211011 | 450 | 0.0143427 | 479.571 | 14600 | 1.77636e-12 | 0.948533 | 15380 | 780 | 14600 | 1.77636e-12 | 2229079 | -650214 | 179.969 | C10 | Obj.-027 | MOBILIER | Chaise 1 65 | Brique 1 | etage 4 | 7 | Métal-Inox; Surface-Plastique stratifié | Sejour cuisine | Sejour cuisine | B44
Obj.-034 | etage 4 | 800 | 0.64 | 360 | 0.280139 | 800 | 14600 | 1.77636e-12 | 4.69089 | 15266.7 | 666.7 | 14600 | 1.77636e-12 | 2220338 | -648823 | 0.0358973 | Revêt. pilier rond | Obj.-034 | 0-Resille Dampere | Fauteuil 65 | Brique 1 | etage 4 | 7 | Poteaux; Revêt. pilier rond | Sejour cuisine | Sejour cuisine | B44
Obj.-027 | etage 4 | 440 | 0.211011 | 450 | 0.0143427 | 479.571 | 14600 | 1.77636e-12 | 0.948533 | 15380 | 780 | 14600 | 1.77636e-12 | 2229079 | -649806 | 359.969 | C10 | Obj.-027 | MOBILIER | Chaise 1 65 | Brique 1 | etage 4 | 7 | Métal-Inox; Surface-Plastique stratifié | Sejour cuisine | Sejour cuisine | B44
Obj.-027 | etage 4 | 440 | 0.211011 | 450 | 0.0143427 | 479.571 | 14600 | 1.77636e-12 | 0.948533 | 15380 | 780 | 14600 | 1.77636e-12 | 2228456 | -650214 | 179.969 | C10 | Obj.-027 | MOBILIER | Chaise 1 65 | Brique 1 | etage 4 | 7 | Métal-Inox; Surface-Plastique stratifié | Sejour cuisine | Sejour cuisine | B44
Obj.-034 | etage 4 | 800 | 0.64 | 360 | 0.280139 | 800 | 14600 | 1.77636e-12 | 4.69089 | 15266.7 | 666.7 | 14600 | 1.77636e-12 | 2221389 | -649373 | 269.964 | Revêt. pilier rond | Obj.-034 | 0-Resille Dampere | Fauteuil 65 | Brique 1 | etage 4 | 7 | Poteaux; Revêt. pilier rond | Sejour cuisine | Sejour cuisine | B44
Obj.-003 | etage 4 | 1400 | 2.66 | 400 | 0.566521 | 1900 | 14600 | 0 | 14.0446 | 15093.3 | 493.337 | 14600 | 0 | 2227102 | -622115 | 354.2 | C10 | Obj.-003 | SANITAIRE | Lit double_70 | Brique 1 | etage 4 | 7 | Poutre; Revêt. sol | Ch 1/pl | Ch 1/pl | B41
Obj.-003 | etage 4 | 1400 | 2.66 | 400 | 0.566521 | 1900 | 14600 | 0 | 14.0446 | 15093.3 | 493.337 | 14600 | 0 | 2220509 | -644196 | 360 | C10 | Obj.-003 | SANITAIRE | Lit double_70 | Brique 1 | etage 4 | 7 | Bois-Pin; Plancher-Moquette | Ch 1 | Ch 1 | B44
Obj.-019 | etage 4 | 600 | 0.36 | 900 | 0.314148 | 600 | 14600 | 0 | 4.5196 | 15500 | 900 | 14600 | 0 | 2299084 | -644795 | 359.849 | Revêt. pilier rond | Obj.-019 | SANITAIRE | Réfrigérateur haut 65 | Brique 1 | etage 4 | 7 | Métal-Chrome; Surface-Lavis Blanc | Sejour cuisine | Sejour cuisine | B53
Obj.-027 | etage 4 | 440 | 0.211011 | 450 | 0.0143427 | 479.571 | 14600 | 1.77636e-12 | 0.948533 | 15380 | 780 | 14600 | 1.77636e-12 | 2301308 | -649691 | 270 | C10 | Obj.-027 | MOBILIER | Chaise 1 65 | Brique 1 | etage 4 | 7 | Métal-Inox; Surface-Plastique stratifié | Sejour cuisine | Sejour cuisine | B53
Obj.-003 | etage 4 | 900 | 1.71 | 400 | 0.364192 | 1900 | 14600 | 0 | 9.53161 | 15093.3 | 493.337 | 14600 | 0 | 2218624 | -635796 | 2.03555e-13 | C10 | Obj.-003 | SANITAIRE | Lit double_70 | Brique 1 | etage 4 | 7 | Bois-Pin; Plancher-Moquette | Ch 2 | Ch 2 | B43
Obj.-003 | etage 4 | 900 | 1.71 | 400 | 0.364192 | 1900 | 14600 | 0 | 9.53161 | 15093.3 | 493.337 | 14600 | 0 | 2218558 | -626411 | 2.03555e-13 | C10 | Obj.-003 | SANITAIRE | Lit double_70 | Brique 1 | etage 4 | 7 | Bois-Pin; Plancher-Moquette | Ch 2 | Ch 2 | B42
Obj.-002 | etage 4 | 1800 | 1.44 | 600 | 0.0995281 | 800 | 14600 | 0 | 10.3313 | 15200 | 600 | 14600 | 0 | 2227384 | -645938 | 180 | Revêt. pilier rond | Obj.-002 | SANITAIRE | Baignoire 65 | Brique 1 | etage 4 | 7 | Surface-Ceramiques vitrifiées | Sde 1 | Sde 1 | B44
Obj.-019 | etage 4 | 600 | 0.36 | 900 | 0.314148 | 600 | 14600 | 0 | 4.5196 | 15500 | 900 | 14600 | 0 | 2226492 | -631658 | 90 | Revêt. pilier rond | Obj.-019 | SANITAIRE | Réfrigérateur haut 65 | Brique 1 | etage 4 | 7 | Métal-Chrome; Surface-Lavis Blanc | Sejour cuisine/pl | Sejour cuisine/pl | B41
Obj.-003 | etage 4 | 1400 | 2.66 | 400 | 0.566521 | 1900 | 14600 | 0 | 14.0446 | 15093.3 | 493.337 | 14600 | 0 | 2218719 | -632614 | 360 | C10 | Obj.-003 | SANITAIRE | Lit double_70 | Brique 1 | etage 4 | 7 | Poteaux | Ch 1/pl | Ch 1/pl | B43
Obj.-027 | etage 4 | 440 | 0.211011 | 450 | 0.0143427 | 479.571 | 14600 | 1.77636e-12 | 0.948533 | 15380 | 780 | 14600 | 1.77636e-12 | 2301308 | -648453 | 270 | C10 | Obj.-027 | MOBILIER | Chaise 1 65 | Brique 1 | etage 4 | 7 | Métal-Inox; Surface-Plastique stratifié | Sejour cuisine | Sejour cuisine | B53
Obj.-027 | etage 4 | 440 | 0.211011 | 450 | 0.0143427 | 479.571 | 14600 | 1.77636e-12 | 0.948533 | 15380 | 780 | 14600 | 1.77636e-12 | 2300900 | -650291 | 90 | C10 | Obj.-027 | MOBILIER | Chaise 1 65 | Brique 1 | etage 4 | 7 | Métal-Inox; Surface-Plastique stratifié | Sejour cuisine | Sejour cuisine | B53
Obj.-027 | etage 4 | 440 | 0.211011 | 450 | 0.0143427 | 479.571 | 14600 | 1.77636e-12 | 0.948533 | 15380 | 780 | 14600 | 1.77636e-12 | 2300900 | -649076 | 90 | C10 | Obj.-027 | MOBILIER | Chaise 1 65 | Brique 1 | etage 4 | 7 | Métal-Inox; Surface-Plastique stratifié | Sejour cuisine | Sejour cuisine | B53
Obj.-026 | etage 4 | 2546.88 | 2.2922 | 730 | 0.0507097 | 900 | 14600 | 1.77636e-12 | 5.93457 | 15330 | 730 | 14600 | 1.77636e-12 | 2301455 | -650319 | 90 | C10 | Obj.-026 | MOBILIER | al_table Sting | Brique 1 | etage 4 | 7 | Métal-Inox; Surface-Peinture brillante; Divers-Glace | Sejour cuisine | Sejour cuisine | B53
Obj.-027 | etage 4 | 440 | 0.211011 | 450 | 0.0143427 | 479.571 | 14600 | 1.77636e-12 | 0.948533 | 15380 | 780 | 14600 | 1.77636e-12 | 2300900 | -648453 | 90 | C10 | Obj.-027 | MOBILIER | Chaise 1 65 | Brique 1 | etage 4 | 7 | Métal-Inox; Surface-Plastique stratifié | Sejour cuisine | Sejour cuisine | B53
Obj.-027 | etage 4 | 440 | 0.211011 | 450 | 0.0143427 | 479.571 | 14600 | 1.77636e-12 | 0.948533 | 15380 | 780 | 14600 | 1.77636e-12 | 2300900 | -649691 | 90 | C10 | Obj.-027 | MOBILIER | Chaise 1 65 | Brique 1 | etage 4 | 7 | Métal-Inox; Surface-Plastique stratifié | Sejour cuisine | Sejour cuisine | B53
Obj.-027 | etage 4 | 440 | 0.211011 | 450 | 0.0143427 | 479.571 | 14600 | 1.77636e-12 | 0.948533 | 15380 | 780 | 14600 | 1.77636e-12 | 2301308 | -649076 | 270 | C10 | Obj.-027 | MOBILIER | Chaise 1 65 | Brique 1 | etage 4 | 7 | Métal-Inox; Surface-Plastique stratifié | Sejour cuisine | Sejour cuisine | B53
Obj.-027 | etage 4 | 440 | 0.211011 | 450 | 0.0143427 | 479.571 | 14600 | 1.77636e-12 | 0.948533 | 15380 | 780 | 14600 | 1.77636e-12 | 2301308 | -650291 | 270 | C10 | Obj.-027 | MOBILIER | Chaise 1 65 | Brique 1 | etage 4 | 7 | Métal-Inox; Surface-Plastique stratifié | Sejour cuisine | Sejour cuisine | B53
Obj.-003 | etage 4 | 1400 | 2.66 | 400 | 0.566521 | 1900 | 14600 | 0 | 14.0446 | 15093.3 | 493.337 | 14600 | 0 | 2229769 | -637573 | 360 | C10 | Obj.-003 | SANITAIRE | Lit double_70 | Brique 1 | etage 4 | 7 | Bois-Pin; Plancher-Moquette | Ch 3/sde | Ch 3/sde | B44
Obj.-019 | etage 4 | 600 | 0.36 | 900 | 0.314148 | 600 | 14600 | 0 | 4.5196 | 15500 | 900 | 14600 | 0 | 2224132 | -623871 | 90 | Revêt. pilier rond | Obj.-019 | SANITAIRE | Réfrigérateur haut 65 | Brique 1 | etage 4 | 7 | Métal-Chrome; Surface-Lavis Blanc | Sejour cuisine | Sejour cuisine | B42
Obj.-027 | Etage 5 | 440 | 0.211011 | 450 | 0.0143427 | 479.571 | 17650 | 3.55271e-12 | 0.948533 | 18430 | 780 | 17650 | 3.55271e-12 | 2221324 | -629327 | 359.969 | C10 | Obj.-027 | MOBILIER | Chaise 1 65 | Brique 1 | Etage 5 | 8 | Métal-Inox; Surface-Plastique stratifié | Sejour cuisine | Sejour cuisine | B51
Obj.-002 | Etage 5 | 1800 | 1.44 | 600 | 0.0995281 | 800 | 17650 | 0 | 10.3313 | 18250 | 600 | 17650 | 0 | 2223732 | -638762 | 89.9242 | Revêt. pilier rond | Obj.-002 | SANITAIRE | Baignoire 65 | Brique 1 | Etage 5 | 8 | Surface-Ceramiques vitrifiées | Sde 1 | Sde 1 | B52
Obj.-003 | Etage 5 | 1400 | 2.66 | 400 | 0.566521 | 1900 | 17650 | 0 | 14.0446 | 18143.3 | 493.337 | 17650 | 0 | 2227369 | -644940 | 180 | C10 | Obj.-003 | MOBILIER | Lit double_70 | Brique 1 | Etage 5 | 8 | Bois-Pin; Plancher-Moquette | Ch 4/Pl | Ch 4/Pl | B52
Obj.-027 | Etage 5 | 440 | 0.211011 | 450 | 0.0143427 | 479.571 | 17650 | 3.55271e-12 | 0.948533 | 18430 | 780 | 17650 | 3.55271e-12 | 2220708 | -629735 | 179.969 | C10 | Obj.-027 | MOBILIER | Chaise 1 65 | Brique 1 | Etage 5 | 8 | Métal-Inox; Surface-Plastique stratifié | Sejour cuisine | Sejour cuisine | B51
Obj.-027 | Etage 5 | 440 | 0.211011 | 450 | 0.0143427 | 479.571 | 17650 | 3.55271e-12 | 0.948533 | 18430 | 780 | 17650 | 3.55271e-12 | 2221323 | -629735 | 179.969 | C10 | Obj.-027 | MOBILIER | Chaise 1 65 | Brique 1 | Etage 5 | 8 | Métal-Inox; Surface-Plastique stratifié | Sejour cuisine | Sejour cuisine | B51
Obj.-034 | Etage 5 | 800 | 0.64 | 360 | 0.280139 | 800 | 18450 | 800 | 4.69089 | 19116.7 | 1466.7 | 18450 | 800 | 2222133 | -627081 | 180.144 | Revêt. pilier rond | Obj.-034 | MOBILIER | Fauteuil 65 | Brique 1 | Etage 5 | 8 | Plancher-Moquette; Revêt. pilier rond | Sejour cuisine | Sejour cuisine | B51
Obj.-027 | Etage 5 | 440 | 0.211011 | 450 | 0.0143427 | 479.571 | 17650 | 3.55271e-12 | 0.948533 | 18430 | 780 | 17650 | 3.55271e-12 | 2220085 | -629734 | 179.969 | C10 | Obj.-027 | MOBILIER | Chaise 1 65 | Brique 1 | Etage 5 | 8 | Métal-Inox; Surface-Plastique stratifié | Sejour cuisine | Sejour cuisine | B51
Obj.-026 | Etage 5 | 1898.56 | 1.70871 | 730 | 0.0384564 | 900 | 17650 | 3.55271e-12 | 4.54716 | 18380 | 730 | 17650 | 3.55271e-12 | 2221304 | -629180 | 179.969 | C10 | Obj.-026 | MOBILIER | al_table Sting | Brique 1 | Etage 5 | 8 | Métal-Inox; Surface-Peinture brillante; Divers-Glace | Sejour cuisine | Sejour cuisine | B51
Obj.-019 | Etage 5 | 600 | 0.36 | 900 | 0.314148 | 600 | 17650 | 0 | 4.5196 | 18550 | 900 | 17650 | 0 | 2218674 | -632434 | 270 | Revêt. pilier rond | Obj.-019 | SANITAIRE | Réfrigérateur haut 65 | Brique 1 | Etage 5 | 8 | Métal-Chrome; Surface-Lavis Blanc | Sejour cuisine | Sejour cuisine | B51
Obj.-002 | Etage 5 | 1800 | 1.44 | 600 | 0.0995281 | 800 | 17650 | 0 | 10.3313 | 18250 | 600 | 17650 | 0 | 2224384 | -625647 | 360 | Revêt. pilier rond | Obj.-002 | SANITAIRE | Baignoire 65 | Brique 1 | Etage 5 | 8 | Surface-Ceramiques vitrifiées | Sdb | Sdb | B51
Obj.-027 | Etage 5 | 440 | 0.211011 | 450 | 0.0143427 | 479.571 | 17650 | 3.55271e-12 | 0.948533 | 18430 | 780 | 17650 | 3.55271e-12 | 2220709 | -629327 | 359.969 | C10 | Obj.-027 | MOBILIER | Chaise 1 65 | Brique 1 | Etage 5 | 8 | Métal-Inox; Surface-Plastique stratifié | Sejour cuisine | Sejour cuisine | B51
Obj.-003 | Etage 5 | 1400 | 2.66 | 400 | 0.566521 | 1900 | 17650 | 0 | 14.0446 | 18143.3 | 493.337 | 17650 | 0 | 2220525 | -636007 | 180 | C10 | Obj.-003 | MOBILIER | Lit double_70 | Brique 1 | Etage 5 | 8 | Poteaux | Ch 1 | Ch 1 | B51
Obj.-019 | Etage 5 | 600 | 0.36 | 900 | 0.314148 | 600 | 17650 | 0 | 4.5196 | 18550 | 900 | 17650 | 0 | 2225782 | -647518 | 360 | Revêt. pilier rond | Obj.-019 | SANITAIRE | Réfrigérateur haut 65 | Brique 1 | Etage 5 | 8 | Métal-Chrome; Surface-Lavis Blanc | Sejour Cuisine | Sejour Cuisine | B52
Obj.-034 | Etage 5 | 800 | 0.64 | 360 | 0.280139 | 800 | 17650 | 3.55271e-12 | 4.69089 | 18316.7 | 666.7 | 17650 | 3.55271e-12 | 2219746 | -648082 | 180.036 | Revêt. pilier rond | Obj.-034 | MOBILIER | Fauteuil 65 | Brique 1 | Etage 5 | 8 | Plancher-Moquette; Revêt. pilier rond | Sejour Cuisine | Sejour Cuisine | B52
Obj.-034 | Etage 5 | 800 | 0.64 | 360 | 0.280139 | 800 | 17650 | 3.55271e-12 | 4.69089 | 18316.7 | 666.7 | 17650 | 3.55271e-12 | 2219746 | -646132 | 359.964 | Revêt. pilier rond | Obj.-034 | MOBILIER | Fauteuil 65 | Brique 1 | Etage 5 | 8 | Plancher-Moquette; Revêt. pilier rond | Sejour Cuisine | Sejour Cuisine | B52
Obj.-027 | Etage 5 | 440 | 0.211011 | 450 | 0.0143427 | 479.571 | 17650 | 3.55271e-12 | 0.948533 | 18430 | 780 | 17650 | 3.55271e-12 | 2223756 | -646718 | 359.969 | C10 | Obj.-027 | MOBILIER | Chaise 1 65 | Brique 1 | Etage 5 | 8 | Métal-Inox; Surface-Plastique stratifié | Sejour Cuisine | Sejour Cuisine | B52
Obj.-027 | Etage 5 | 440 | 0.211011 | 450 | 0.0143427 | 479.571 | 17650 | 3.55271e-12 | 0.948533 | 18430 | 780 | 17650 | 3.55271e-12 | 2223132 | -646717 | 359.969 | C10 | Obj.-027 | MOBILIER | Chaise 1 65 | Brique 1 | Etage 5 | 8 | Métal-Inox; Surface-Plastique stratifié | Sejour Cuisine | Sejour Cuisine | B52
Obj.-026 | Etage 5 | 1898.56 | 1.70871 | 730 | 0.0384564 | 900 | 17650 | 3.55271e-12 | 4.54716 | 18380 | 730 | 17650 | 3.55271e-12 | 2224351 | -646572 | 179.969 | C10 | Obj.-026 | MOBILIER | al_table Sting | Brique 1 | Etage 5 | 8 | Métal-Inox; Surface-Peinture brillante; Divers-Glace | Sejour Cuisine | Sejour Cuisine | B52
Obj.-027 | Etage 5 | 440 | 0.211011 | 450 | 0.0143427 | 479.571 | 17650 | 3.55271e-12 | 0.948533 | 18430 | 780 | 17650 | 3.55271e-12 | 2224371 | -646718 | 359.969 | C10 | Obj.-027 | MOBILIER | Chaise 1 65 | Brique 1 | Etage 5 | 8 | Métal-Inox; Surface-Plastique stratifié | Sejour Cuisine | Sejour Cuisine | B52
Obj.-027 | Etage 5 | 440 | 0.211011 | 450 | 0.0143427 | 479.571 | 17650 | 3.55271e-12 | 0.948533 | 18430 | 780 | 17650 | 3.55271e-12 | 2224371 | -647126 | 179.969 | C10 | Obj.-027 | MOBILIER | Chaise 1 65 | Brique 1 | Etage 5 | 8 | Métal-Inox; Surface-Plastique stratifié | Sejour Cuisine | Sejour Cuisine | B52
Obj.-027 | Etage 5 | 440 | 0.211011 | 450 | 0.0143427 | 479.571 | 17650 | 3.55271e-12 | 0.948533 | 18430 | 780 | 17650 | 3.55271e-12 | 2223132 | -647126 | 179.969 | C10 | Obj.-027 | MOBILIER | Chaise 1 65 | Brique 1 | Etage 5 | 8 | Métal-Inox; Surface-Plastique stratifié | Sejour Cuisine | Sejour Cuisine | B52
Obj.-027 | Etage 5 | 440 | 0.211011 | 450 | 0.0143427 | 479.571 | 17650 | 3.55271e-12 | 0.948533 | 18430 | 780 | 17650 | 3.55271e-12 | 2223755 | -647126 | 179.969 | C10 | Obj.-027 | MOBILIER | Chaise 1 65 | Brique 1 | Etage 5 | 8 | Métal-Inox; Surface-Plastique stratifié | Sejour Cuisine | Sejour Cuisine | B52
Obj.-003 | Etage 5 | 1400 | 2.66 | 400 | 0.566521 | 1900 | 17650 | 0 | 14.0446 | 18143.3 | 493.337 | 17650 | 0 | 2220171 | -644016 | 180 | C10 | Obj.-003 | MOBILIER | Lit double_70 | Brique 1 | Etage 5 | 8 | Bois-Pin; Plancher-Moquette | Ch 1/pl | Ch 1/pl | B52
Obj.-003 | Etage 5 | 900 | 1.71 | 400 | 0.364192 | 1900 | 17650 | 0 | 9.53161 | 18143.3 | 493.337 | 17650 | 0 | 2226254 | -627197 | 90 | C10 | Obj.-003 | SANITAIRE | Lit double_70 | Brique 1 | Etage 5 | 8 | Bois-Pin; Plancher-Moquette | Ch 2 | Ch 2 | B51
Obj.-027 | Etage 5 | 440 | 0.211011 | 450 | 0.0143427 | 479.571 | 17650 | 3.55271e-12 | 0.948533 | 18430 | 780 | 17650 | 3.55271e-12 | 2220085 | -629326 | 359.969 | C10 | Obj.-027 | MOBILIER | Chaise 1 65 | Brique 1 | Etage 5 | 8 | Métal-Inox; Surface-Plastique stratifié | Sejour cuisine | Sejour cuisine | B51
Obj.-003 | Etage 5 | 900 | 1.71 | 400 | 0.364192 | 1900 | 17650 | 0 | 9.53161 | 18143.3 | 493.337 | 17650 | 0 | 2226464 | -631072 | 90 | C10 | Obj.-003 | SANITAIRE | Lit double_70 | Brique 1 | Etage 5 | 8 | Bois-Pin; Plancher-Moquette | Ch 3 | Ch 3 | B51
Obj.-019 | Etage 5 | 600 | 0.36 | 900 | 0.314148 | 600 | 17650 | 0 | 4.5196 | 18550 | 900 | 17650 | 0 | 2298993 | -641335 | 360 | Revêt. pilier rond | Obj.-019 | SANITAIRE | Réfrigérateur haut 65 | Brique 1 | Etage 5 | 8 | Métal-Chrome; Surface-Lavis Blanc | Sejour Cuisine | Sejour Cuisine | B54
Obj.-027 | Etage 5 | 440 | 0.211011 | 450 | 0.0143427 | 479.571 | 17650 | 3.55271e-12 | 0.948533 | 18430 | 780 | 17650 | 3.55271e-12 | 2300226 | -645884 | 90 | C10 | Obj.-027 | MOBILIER | Chaise 1 65 | Brique 1 | Etage 5 | 8 | Métal-Inox; Surface-Plastique stratifié | Sejour Cuisine | Sejour Cuisine | B54
Obj.-026 | Etage 5 | 2546.88 | 2.2922 | 730 | 0.0507097 | 900 | 17650 | 3.55271e-12 | 5.93457 | 18380 | 730 | 17650 | 3.55271e-12 | 2300781 | -647750 | 90 | C10 | Obj.-026 | MOBILIER | al_table Sting | Brique 1 | Etage 5 | 8 | Métal-Inox; Surface-Peinture brillante; Divers-Glace | Sejour Cuisine | Sejour Cuisine | B54
Obj.-027 | Etage 5 | 440 | 0.211011 | 450 | 0.0143427 | 479.571 | 17650 | 3.55271e-12 | 0.948533 | 18430 | 780 | 17650 | 3.55271e-12 | 2300226 | -646507 | 90 | C10 | Obj.-027 | MOBILIER | Chaise 1 65 | Brique 1 | Etage 5 | 8 | Métal-Inox; Surface-Plastique stratifié | Sejour Cuisine | Sejour Cuisine | B54
Obj.-027 | Etage 5 | 440 | 0.211011 | 450 | 0.0143427 | 479.571 | 17650 | 3.55271e-12 | 0.948533 | 18430 | 780 | 17650 | 3.55271e-12 | 2300634 | -646507 | 270 | C10 | Obj.-027 | MOBILIER | Chaise 1 65 | Brique 1 | Etage 5 | 8 | Métal-Inox; Surface-Plastique stratifié | Sejour Cuisine | Sejour Cuisine | B54
Obj.-027 | Etage 5 | 440 | 0.211011 | 450 | 0.0143427 | 479.571 | 17650 | 3.55271e-12 | 0.948533 | 18430 | 780 | 17650 | 3.55271e-12 | 2300226 | -647122 | 90 | C10 | Obj.-027 | MOBILIER | Chaise 1 65 | Brique 1 | Etage 5 | 8 | Métal-Inox; Surface-Plastique stratifié | Sejour Cuisine | Sejour Cuisine | B54
Obj.-027 | Etage 5 | 440 | 0.211011 | 450 | 0.0143427 | 479.571 | 17650 | 3.55271e-12 | 0.948533 | 18430 | 780 | 17650 | 3.55271e-12 | 2300634 | -647722 | 270 | C10 | Obj.-027 | MOBILIER | Chaise 1 65 | Brique 1 | Etage 5 | 8 | Métal-Inox; Surface-Plastique stratifié | Sejour Cuisine | Sejour Cuisine | B54
Obj.-027 | Etage 5 | 440 | 0.211011 | 450 | 0.0143427 | 479.571 | 17650 | 3.55271e-12 | 0.948533 | 18430 | 780 | 17650 | 3.55271e-12 | 2300634 | -647122 | 270 | C10 | Obj.-027 | MOBILIER | Chaise 1 65 | Brique 1 | Etage 5 | 8 | Métal-Inox; Surface-Plastique stratifié | Sejour Cuisine | Sejour Cuisine | B54
Obj.-027 | Etage 5 | 440 | 0.211011 | 450 | 0.0143427 | 479.571 | 17650 | 3.55271e-12 | 0.948533 | 18430 | 780 | 17650 | 3.55271e-12 | 2300634 | -645884 | 270 | C10 | Obj.-027 | MOBILIER | Chaise 1 65 | Brique 1 | Etage 5 | 8 | Métal-Inox; Surface-Plastique stratifié | Sejour Cuisine | Sejour Cuisine | B54
Obj.-027 | Etage 5 | 440 | 0.211011 | 450 | 0.0143427 | 479.571 | 17650 | 3.55271e-12 | 0.948533 | 18430 | 780 | 17650 | 3.55271e-12 | 2300226 | -647722 | 90 | C10 | Obj.-027 | MOBILIER | Chaise 1 65 | Brique 1 | Etage 5 | 8 | Métal-Inox; Surface-Plastique stratifié | Sejour Cuisine | Sejour Cuisine | B54
Obj.-003 | Etage 5 | 1400 | 2.66 | 400 | 0.566521 | 1900 | 17650 | 0 | 14.0446 | 18143.3 | 493.337 | 17650 | 0 | 2301522 | -638087 | 269.999 | C10 | Obj.-003 | MOBILIER | Lit double_70 | Brique 1 | Etage 5 | 8 | Bois-Pin; Plancher-Moquette | Ch 1 | Ch 1 | B54
Obj.-003 | Etage 5 | 1400 | 2.66 | 400 | 0.566521 | 1900 | 17650 | 0 | 14.0446 | 18143.3 | 493.337 | 17650 | 0 | 2221054 | -638167 | 270 | C10 | Obj.-003 | MOBILIER | Lit double_70 | Brique 1 | Etage 5 | 8 | Bois-Pin; Plancher-Moquette | Ch 2/pl | Ch 2/pl | B52
Obj.-003 | Etage 5 | 1400 | 2.66 | 400 | 0.566521 | 1900 | 17650 | 0 | 14.0446 | 18143.3 | 493.337 | 17650 | 0 | 2225892 | -639411 | 90.0003 | C10 | Obj.-003 | MOBILIER | Lit double_70 | Brique 1 | Etage 5 | 8 | Bois-Pin; Plancher-Moquette | Ch 3/pl | Ch 3/pl | B52

# IfcBuildingElementProxy: IfcBuildingElementProxy (404)
ArchiCADProperties - Calque: Calque Archicad; Verrouillé: no; Étage supérieur lié absolu: Non lié; Étage supérieur lié relatif: Non lié; Étage supérieur lié: Non lié; Nom de Variante: Modèle principal; Nom de Jeu de Variantes: Modèle principal; Affichage sur filtre de rénovation: Tous les filtres appropriés; État de rénovation: Existant; État de Variante: Modèle principal; Jeu de Variantes: Modèle principal
AC_Pset_RenovationAndPhasing - Renovation Status: Existing
Name | In | Material | ID de l'élément = Lien et ID d'élément | Nom d'étage d'implantation | Numéro d'étage d'implantation | Type d'élément | ID de Parent | Superficie totale (m2) = Superficie en plan (m2) = Superficie inférieure (nette) (m2) | Épaisseur (mm) | Volume (net) (m3) | Largeur (mm) | Altitude à Zéro du Projet (mm) = Altitude de Référence Niveau 1 (mm) = Altitude de Référence Niveau 2 (mm) = Altitude à niveau de la mer (mm) | Altitude à étage lié/étage d'implantation (mm) = Décalage étage d'implantation (mm) | Décalage supérieur (mm) | Altitude supérieure à premier niveau de référence (mm) = Altitude supérieure à Zéro du projet (mm) = Altitude supérieure à niveau de la mer (mm) = Altitude supérieure à deuxième niveau de référence (mm) | Altitude supérieure à étage d'implantation (mm) | Altitude inférieure à premier niveau de référence (mm) = Altitude inférieure à Zéro du projet (mm) = Altitude inférieure à niveau de la mer (mm) = Altitude inférieure à deuxième niveau de référence (mm) | Altitude inférieure à étage d'implantation (mm) | Index volée | Type de segment | Index de marche | Nom Élément de Bibliothèque | Superficie avant (m2) | Largeur arrière (mm) | Largeur avant (mm)
VOLEE-016 | sousol | Cloison 274992075 | VOLEE-016 | sousol | 2 | Structure (Escalier) | ESC-014 | 24.5944 | 150 | 2.14202 | 1200 | 2990 | 2990 | 10 | 2990 | 2990 | -130 | -130 | ArchiCADProperties - Type construction: Monolithique; Type forme: Plat; Position structure escalier: Sous l'escalier; Index volée structure escalier: 1; Matériau de construction / Composite / Profil / Hachure: Cloison 274992075; Matériaux de construction (Tous): Cloison 274992075; ArchiCADQuantities - Épaisseur secondaire: 150 mm; Hauteur 3D de structure d'escalier: 3120 mm; Longueur 3D: 6016.76 mm
C-MARCHE-225 | sousol | Lame d'air 275581351 | C-MARCHE-225 | sousol | 2 | Contremarche (Escalier) | ESC-014 | 0.527068 | 10 | 0.00245263 | 1553.08 | 166.667 | 166.667 | 2676.67 | 323.333 | 323.333 | 166.667 | 166.667 | 1 | Quart tournant avec marches égales | 2 | Contremarche 27 | 0.243315 | 1553.08 | 1553.08 | ArchiCADQuantities - Hauteur 3D de contremarche: 156.667 mm; Hauteur: 156.667 mm
C-MARCHE-224 | sousol | Lame d'air 275581351 | C-MARCHE-224 | sousol | 2 | Contremarche (Escalier) | ESC-014 | 0.403133 | 10 | 0.00188 | 1200 | 0 | 0 | 2843.33 | 156.667 | 156.667 | 0 | 0 | 1 | Quart tournant avec marches égales | 1 | Contremarche 27 | 0.188 | 1200 | 1200 | ArchiCADQuantities - Hauteur 3D de contremarche: 156.667 mm; Hauteur: 156.667 mm
C-MARCHE-227 | sousol | Lame d'air 275581351 | C-MARCHE-227 | sousol | 2 | Contremarche (Escalier) | ESC-014 | 0.403133 | 10 | 0.00188 | 1200 | 500 | 500 | 2343.33 | 656.667 | 656.667 | 500 | 500 | 1 | Quart tournant avec marches égales | 4 | Contremarche 27 | 0.188 | 1200 | 1200 | ArchiCADQuantities - Hauteur 3D de contremarche: 156.667 mm; Hauteur: 156.667 mm
C-MARCHE-226 | sousol | Lame d'air 275581351 | C-MARCHE-226 | sousol | 2 | Contremarche (Escalier) | ESC-014 | 0.498435 | 10 | 0.00232443 | 1483.68 | 333.333 | 333.333 | 2510 | 490 | 490 | 333.333 | 333.333 | 1 | Quart tournant avec marches égales | 3 | Contremarche 27 | 0.232443 | 1483.68 | 1483.68 | ArchiCADQuantities - Hauteur 3D de contremarche: 156.667 mm; Hauteur: 156.667 mm
C-MARCHE-228 | sousol | Lame d'air 275581351 | C-MARCHE-228 | sousol | 2 | Contremarche (Escalier) | ESC-014 | 0.403133 | 10 | 0.00188 | 1200 | 666.667 | 666.667 | 2176.67 | 823.333 | 823.333 | 666.667 | 666.667 | 1 | Quart tournant avec marches égales | 5 | Contremarche 27 | 0.188 | 1200 | 1200 | ArchiCADQuantities - Hauteur 3D de contremarche: 156.667 mm; Hauteur: 156.667 mm
C-MARCHE-230 | sousol | Lame d'air 275581351 | C-MARCHE-230 | sousol | 2 | Contremarche (Escalier) | ESC-014 | 0.403133 | 10 | 0.00188 | 1200 | 1000 | 1000 | 1843.33 | 1156.67 | 1156.67 | 1000 | 1000 | 1 | Quart tournant avec marches égales | 7 | Contremarche 27 | 0.188 | 1200 | 1200 | ArchiCADQuantities - Hauteur 3D de contremarche: 156.667 mm; Hauteur: 156.667 mm
C-MARCHE-229 | sousol | Lame d'air 275581351 | C-MARCHE-229 | sousol | 2 | Contremarche (Escalier) | ESC-014 | 0.403133 | 10 | 0.00188 | 1200 | 833.333 | 833.333 | 2010 | 990 | 990 | 833.333 | 833.333 | 1 | Quart tournant avec marches égales | 6 | Contremarche 27 | 0.188 | 1200 | 1200 | ArchiCADQuantities - Hauteur 3D de contremarche: 156.667 mm; Hauteur: 156.667 mm
C-MARCHE-231 | sousol | Lame d'air 275581351 | C-MARCHE-231 | sousol | 2 | Contremarche (Escalier) | ESC-014 | 0.403133 | 10 | 0.00188 | 1200 | 1166.67 | 1166.67 | 1676.67 | 1323.33 | 1323.33 | 1166.67 | 1166.67 | 1 | Quart tournant avec marches égales | 8 | Contremarche 27 | 0.188 | 1200 | 1200 | ArchiCADQuantities - Hauteur 3D de contremarche: 156.667 mm; Hauteur: 156.667 mm
C-MARCHE-232 | sousol | Lame d'air 275581351 | C-MARCHE-232 | sousol | 2 | Contremarche (Escalier) | ESC-014 | 0.403133 | 10 | 0.00188 | 1200 | 1333.33 | 1333.33 | 1510 | 1490 | 1490 | 1333.33 | 1333.33 | 1 | Quart tournant avec marches égales | 9 | Contremarche 27 | 0.188 | 1200 | 1200 | ArchiCADQuantities - Hauteur 3D de contremarche: 156.667 mm; Hauteur: 156.667 mm
C-MARCHE-233 | sousol | Lame d'air 275581351 | C-MARCHE-233 | sousol | 2 | Contremarche (Escalier) | ESC-014 | 0.403133 | 10 | 0.00188 | 1200 | 1500 | 1500 | 1343.33 | 1656.67 | 1656.67 | 1500 | 1500 | 1 | Quart tournant avec marches égales | 10 | Contremarche 27 | 0.188 | 1200 | 1200 | ArchiCADQuantities - Hauteur 3D de contremarche: 156.667 mm; Hauteur: 156.667 mm
C-MARCHE-234 | sousol | Lame d'air 275581351 | C-MARCHE-234 | sousol | 2 | Contremarche (Escalier) | ESC-014 | 0.403133 | 10 | 0.00188 | 1200 | 1666.67 | 1666.67 | 1176.67 | 1823.33 | 1823.33 | 1666.67 | 1666.67 | 1 | Quart tournant avec marches égales | 11 | Contremarche 27 | 0.188 | 1200 | 1200 | ArchiCADQuantities - Hauteur 3D de contremarche: 156.667 mm; Hauteur: 156.667 mm
C-MARCHE-235 | sousol | Lame d'air 275581351 | C-MARCHE-235 | sousol | 2 | Contremarche (Escalier) | ESC-014 | 0.403133 | 10 | 0.00188 | 1200 | 1833.33 | 1833.33 | 1010 | 1990 | 1990 | 1833.33 | 1833.33 | 1 | Volée | 12 | Contremarche 27 | 0.188 | 1200 | 1200 | ArchiCADQuantities - Hauteur 3D de contremarche: 156.667 mm; Hauteur: 156.667 mm
C-MARCHE-237 | sousol | Lame d'air 275581351 | C-MARCHE-237 | sousol | 2 | Contremarche (Escalier) | ESC-014 | 0.403133 | 10 | 0.00188 | 1200 | 2166.67 | 2166.67 | 676.667 | 2323.33 | 2323.33 | 2166.67 | 2166.67 | 1 | Volée | 14 | Contremarche 27 | 0.188 | 1200 | 1200 | ArchiCADQuantities - Hauteur 3D de contremarche: 156.667 mm; Hauteur: 156.667 mm
C-MARCHE-236 | sousol | Lame d'air 275581351 | C-MARCHE-236 | sousol | 2 | Contremarche (Escalier) | ESC-014 | 0.403133 | 10 | 0.00188 | 1200 | 2000 | 2000 | 843.333 | 2156.67 | 2156.67 | 2000 | 2000 | 1 | Volée | 13 | Contremarche 27 | 0.188 | 1200 | 1200 | ArchiCADQuantities - Hauteur 3D de contremarche: 156.667 mm; Hauteur: 156.667 mm
C-MARCHE-238 | sousol | Lame d'air 275581351 | C-MARCHE-238 | sousol | 2 | Contremarche (Escalier) | ESC-014 | 0.403133 | 10 | 0.00188 | 1200 | 2333.33 | 2333.33 | 510 | 2490 | 2490 | 2333.33 | 2333.33 | 1 | Volée | 15 | Contremarche 27 | 0.188 | 1200 | 1200 | ArchiCADQuantities - Hauteur 3D de contremarche: 156.667 mm; Hauteur: 156.667 mm
C-MARCHE-239 | sousol | Lame d'air 275581351 | C-MARCHE-239 | sousol | 2 | Contremarche (Escalier) | ESC-014 | 0.403133 | 10 | 0.00188 | 1200 | 2500 | 2500 | 343.333 | 2656.67 | 2656.67 | 2500 | 2500 | 1 | Quart tournant avec marches égales | 16 | Contremarche 27 | 0.188 | 1200 | 1200 | ArchiCADQuantities - Hauteur 3D de contremarche: 156.667 mm; Hauteur: 156.667 mm
C-MARCHE-240 | sousol | Lame d'air 275581351 | C-MARCHE-240 | sousol | 2 | Contremarche (Escalier) | ESC-014 | 0.500827 | 10 | 0.00233559 | 1490.8 | 2666.67 | 2666.67 | 176.667 | 2823.33 | 2823.33 | 2666.67 | 2666.67 | 1 | Quart tournant avec marches égales | 17 | Contremarche 27 | 0.233559 | 1490.8 | 1490.8 | ArchiCADQuantities - Hauteur 3D de contremarche: 156.667 mm; Hauteur: 156.667 mm
C-MARCHE-241 | sousol | Lame d'air 275581351 | C-MARCHE-241 | sousol | 2 | Contremarche (Escalier) | ESC-014 | 0.498817 | 10 | 0.00231975 | 1493.19 | 2833.33 | 2833.33 | 10 | 2990 | 2990 | 2833.33 | 2833.33 | 1 | Quart tournant avec marches égales | 18 | Contremarche 27 | 0.233933 | 1493.19 | 1493.19 | ArchiCADQuantities - Hauteur 3D de contremarche: 156.667 mm; Hauteur: 156.667 mm
MARCHE-224 | sousol | Lame d'air 275581351 | MARCHE-224 | sousol | 2 | Giron (Escalier) | ESC-014 | 1.19247 | 10 | 0.0057711 |  | 166.667 | 166.667 | 2833.33 | 166.667 | 166.667 | 156.667 | 156.667 | 1 | Quart tournant avec marches égales | 1 | Marche 27 | 0.012 | 1577.94 | 1200 | ArchiCADQuantities - Nez de marche: 15 mm; Giron de marche: 289.75 mm; Longueur volée marche: 315.533 mm; Superficie supérieure marche: 0.57711 m2
MARCHE-225 | sousol | Lame d'air 275581351 | MARCHE-225 | sousol | 2 | Giron (Escalier) | ESC-014 | 1.58466 | 10 | 0.00771234 |  | 333.333 | 333.333 | 2666.67 | 333.333 | 333.333 | 323.333 | 323.333 | 1 | Quart tournant avec marches égales | 2 | Marche 27 | 0.0151578 | 1483.68 | 1515.78 | ArchiCADQuantities - Nez de marche: 15 mm; Giron de marche: 289.75 mm; Longueur volée marche: 320.545 mm; Superficie supérieure marche: 0.771234 m2
MARCHE-226 | sousol | Lame d'air 275581351 | MARCHE-226 | sousol | 2 | Giron (Escalier) | ESC-014 | 1.25511 | 10 | 0.00609059 |  | 500 | 500 | 2500 | 500 | 500 | 490 | 490 | 1 | Quart tournant avec marches égales | 3 | Marche 27 | 0.0148368 | 1200 | 1483.68 | ArchiCADQuantities - Nez de marche: 15 mm; Giron de marche: 289.75 mm; Longueur volée marche: 314.75 mm; Superficie supérieure marche: 0.609059 m2
MARCHE-227 | sousol | Lame d'air 275581351 | MARCHE-227 | sousol | 2 | Giron (Escalier) | ESC-014 | 0.785695 | 10 | 0.003777 |  | 666.667 | 666.667 | 2333.33 | 666.667 | 666.667 | 656.667 | 656.667 | 1 | Quart tournant avec marches égales | 4 | Marche 27 | 0.012 | 1200 | 1200 | ArchiCADQuantities - Nez de marche: 15 mm; Giron de marche: 289.75 mm; Longueur volée marche: 314.75 mm; Superficie supérieure marche: 0.3777 m2
MARCHE-228 | sousol | Lame d'air 275581351 | MARCHE-228 | sousol | 2 | Giron (Escalier) | ESC-014 | 0.785695 | 10 | 0.003777 |  | 833.333 | 833.333 | 2166.67 | 833.333 | 833.333 | 823.333 | 823.333 | 1 | Quart tournant avec marches égales | 5 | Marche 27 | 0.012 | 1200 | 1200 | ArchiCADQuantities - Nez de marche: 15 mm; Giron de marche: 289.75 mm; Longueur volée marche: 314.75 mm; Superficie supérieure marche: 0.3777 m2
MARCHE-229 | sousol | Lame d'air 275581351 | MARCHE-229 | sousol | 2 | Giron (Escalier) | ESC-014 | 0.785695 | 10 | 0.003777 |  | 1000 | 1000 | 2000 | 1000 | 1000 | 990 | 990 | 1 | Quart tournant avec marches égales | 6 | Marche 27 | 0.012 | 1200 | 1200 | ArchiCADQuantities - Nez de marche: 15 mm; Giron de marche: 289.75 mm; Longueur volée marche: 314.75 mm; Superficie supérieure marche: 0.3777 m2
MARCHE-231 | sousol | Lame d'air 275581351 | MARCHE-231 | sousol | 2 | Giron (Escalier) | ESC-014 | 0.785695 | 10 | 0.003777 |  | 1333.33 | 1333.33 | 1666.67 | 1333.33 | 1333.33 | 1323.33 | 1323.33 | 1 | Quart tournant avec marches égales | 8 | Marche 27 | 0.012 | 1200 | 1200 | ArchiCADQuantities - Nez de marche: 15 mm; Giron de marche: 289.75 mm; Longueur volée marche: 314.75 mm; Superficie supérieure marche: 0.3777 m2
MARCHE-230 | sousol | Lame d'air 275581351 | MARCHE-230 | sousol | 2 | Giron (Escalier) | ESC-014 | 0.785695 | 10 | 0.003777 |  | 1166.67 | 1166.67 | 1833.33 | 1166.67 | 1166.67 | 1156.67 | 1156.67 | 1 | Quart tournant avec marches égales | 7 | Marche 27 | 0.012 | 1200 | 1200 | ArchiCADQuantities - Nez de marche: 15 mm; Giron de marche: 289.75 mm; Longueur volée marche: 314.75 mm; Superficie supérieure marche: 0.3777 m2
MARCHE-232 | sousol | Lame d'air 275581351 | MARCHE-232 | sousol | 2 | Giron (Escalier) | ESC-014 | 0.785695 | 10 | 0.003777 |  | 1500 | 1500 | 1500 | 1500 | 1500 | 1490 | 1490 | 1 | Quart tournant avec marches égales | 9 | Marche 27 | 0.012 | 1200 | 1200 | ArchiCADQuantities - Nez de marche: 15 mm; Giron de marche: 289.75 mm; Longueur volée marche: 314.75 mm; Superficie supérieure marche: 0.3777 m2
MARCHE-233 | sousol | Lame d'air 275581351 | MARCHE-233 | sousol | 2 | Giron (Escalier) | ESC-014 | 0.785695 | 10 | 0.003777 |  | 1666.67 | 1666.67 | 1333.33 | 1666.67 | 1666.67 | 1656.67 | 1656.67 | 1 | Quart tournant avec marches égales | 10 | Marche 27 | 0.012 | 1200 | 1200 | ArchiCADQuantities - Nez de marche: 15 mm; Giron de marche: 289.75 mm; Longueur volée marche: 314.75 mm; Superficie supérieure marche: 0.3777 m2
MARCHE-234 | sousol | Lame d'air 275581351 | MARCHE-234 | sousol | 2 | Giron (Escalier) | ESC-014 | 0.785695 | 10 | 0.003777 |  | 1833.33 | 1833.33 | 1166.67 | 1833.33 | 1833.33 | 1823.33 | 1823.33 | 1 | Quart tournant avec marches égales | 11 | Marche 27 | 0.012 | 1200 | 1200 | ArchiCADQuantities - Nez de marche: 15 mm; Giron de marche: 289.75 mm; Longueur volée marche: 314.75 mm; Superficie supérieure marche: 0.3777 m2
MARCHE-235 | sousol | Lame d'air 275581351 | MARCHE-235 | sousol | 2 | Giron (Escalier) | ESC-014 | 0.785695 | 10 | 0.003777 |  | 2000 | 2000 | 1000 | 2000 | 2000 | 1990 | 1990 | 1 | Volée | 12 | Marche 27 | 0.012 | 1200 | 1200 | ArchiCADQuantities - Nez de marche: 15 mm; Giron de marche: 289.75 mm; Longueur volée marche: 314.75 mm; Superficie supérieure marche: 0.3777 m2
MARCHE-236 | sousol | Lame d'air 275581351 | MARCHE-236 | sousol | 2 | Giron (Escalier) | ESC-014 | 0.785695 | 10 | 0.003777 |  | 2166.67 | 2166.67 | 833.333 | 2166.67 | 2166.67 | 2156.67 | 2156.67 | 1 | Volée | 13 | Marche 27 | 0.012 | 1200 | 1200 | ArchiCADQuantities - Nez de marche: 15 mm; Giron de marche: 289.75 mm; Longueur volée marche: 314.75 mm; Superficie supérieure marche: 0.3777 m2
MARCHE-237 | sousol | Lame d'air 275581351 | MARCHE-237 | sousol | 2 | Giron (Escalier) | ESC-014 | 0.785695 | 10 | 0.003777 |  | 2333.33 | 2333.33 | 666.667 | 2333.33 | 2333.33 | 2323.33 | 2323.33 | 1 | Volée | 14 | Marche 27 | 0.012 | 1200 | 1200 | ArchiCADQuantities - Nez de marche: 15 mm; Giron de marche: 289.75 mm; Longueur volée marche: 314.75 mm; Superficie supérieure marche: 0.3777 m2
MARCHE-239 | sousol | Lame d'air 275581351 | MARCHE-239 | sousol | 2 | Giron (Escalier) | ESC-014 | 1.27606 | 10 | 0.00619416 |  | 2666.67 | 2666.67 | 333.333 | 2666.67 | 2666.67 | 2656.67 | 2656.67 | 1 | Quart tournant avec marches égales | 16 | Marche 27 | 0.012 | 1490.8 | 1200 | ArchiCADQuantities - Nez de marche: 15 mm; Giron de marche: 289.75 mm; Longueur volée marche: 319.576 mm; Superficie supérieure marche: 0.619416 m2
MARCHE-240 | sousol | Lame d'air 275581351 | MARCHE-240 | sousol | 2 | Giron (Escalier) | ESC-014 | 1.57874 | 10 | 0.00768429 |  | 2833.33 | 2833.33 | 166.667 | 2833.33 | 2833.33 | 2823.33 | 2823.33 | 1 | Quart tournant avec marches égales | 17 | Marche 27 | 0.014908 | 1468.2 | 1490.8 | ArchiCADQuantities - Nez de marche: 15 mm; Giron de marche: 289.75 mm; Longueur volée marche: 315.212 mm; Superficie supérieure marche: 0.768429 m2
MARCHE-241 | sousol | Lame d'air 275581351 | MARCHE-241 | sousol | 2 | Giron (Escalier) | ESC-014 | 1.11411 | 10 | 0.0053855 |  | 3000 | 3000 | 0 | 3000 | 3000 | 2990 | 2990 | 1 | Quart tournant avec marches égales | 18 | Marche 27 | 0.0153067 | 1200 | 1530.67 | ArchiCADQuantities - Nez de marche: 15 mm; Giron de marche: 289.75 mm; Longueur volée marche: 289.75 mm; Superficie supérieure marche: 0.53855 m2
MARCHE-238 | sousol | Lame d'air 275581351 | MARCHE-238 | sousol | 2 | Giron (Escalier) | ESC-014 | 0.785695 | 10 | 0.003777 |  | 2500 | 2500 | 500 | 2500 | 2500 | 2490 | 2490 | 1 | Volée | 15 | Marche 27 | 0.012 | 1200 | 1200 | ArchiCADQuantities - Nez de marche: 15 mm; Giron de marche: 289.75 mm; Longueur volée marche: 314.75 mm; Superficie supérieure marche: 0.3777 m2
VOLEE-023 | sousol | Cloison 274992075 | VOLEE-023 | sousol | 2 | Structure (Escalier) | ESC-021 | 26.2359 | 150 | 2.22332 | 1400 | 2990 | 2990 | 10 | 2990 | 2990 | 770 | 770 | ArchiCADProperties - Type construction: Monolithique; Type forme: Plat; Position structure escalier: Sous l'escalier; Index volée structure escalier: 1; Matériau de construction / Composite / Profil / Hachure: Cloison 274992075; Matériaux de construction (Tous): Cloison 274992075; ArchiCADQuantities - Épaisseur secondaire: 150 mm; Hauteur 3D de structure d'escalier: 2220 mm; Longueur 3D: 5147.82 mm
C-MARCHE-350 | sousol | Lame d'air 275581351 | C-MARCHE-350 | sousol | 2 | Contremarche (Escalier) | ESC-021 | 0.643405 | 10 | 0.00298945 | 2135.86 | 900 | 900 | 1960 | 1040 | 1040 | 900 | 900 | 1 | Volée | 1 | Contremarche 27 | 0.299021 | 2135.86 | 2135.86 | ArchiCADQuantities - Hauteur 3D de contremarche: 140 mm; Hauteur: 140 mm
C-MARCHE-351 | sousol | Lame d'air 275581351 | C-MARCHE-351 | sousol | 2 | Contremarche (Escalier) | ESC-021 | 0.632577 | 10 | 0.00293892 | 2099.77 | 1050 | 1050 | 1810 | 1190 | 1190 | 1050 | 1050 | 1 | Volée | 2 | Contremarche 27 | 0.293967 | 2099.77 | 2099.77 | ArchiCADQuantities - Hauteur 3D de contremarche: 140 mm; Hauteur: 140 mm
C-MARCHE-352 | sousol | Lame d'air 275581351 | C-MARCHE-352 | sousol | 2 | Contremarche (Escalier) | ESC-021 | 0.621748 | 10 | 0.00288839 | 2063.67 | 1200 | 1200 | 1660 | 1340 | 1340 | 1200 | 1200 | 1 | Volée | 3 | Contremarche 27 | 0.288914 | 2063.67 | 2063.67 | ArchiCADQuantities - Hauteur 3D de contremarche: 140 mm; Hauteur: 140 mm
C-MARCHE-354 | sousol | Lame d'air 275581351 | C-MARCHE-354 | sousol | 2 | Contremarche (Escalier) | ESC-021 | 0.600092 | 10 | 0.00278732 | 1991.48 | 1500 | 1500 | 1360 | 1640 | 1640 | 1500 | 1500 | 1 | Volée | 5 | Contremarche 27 | 0.278808 | 1991.48 | 1991.48 | ArchiCADQuantities - Hauteur 3D de contremarche: 140 mm; Hauteur: 140 mm
C-MARCHE-355 | sousol | Lame d'air 275581351 | C-MARCHE-355 | sousol | 2 | Contremarche (Escalier) | ESC-021 | 0.589263 | 10 | 0.00273679 | 1955.39 | 1650 | 1650 | 1210 | 1790 | 1790 | 1650 | 1650 | 1 | Volée | 6 | Contremarche 27 | 0.273754 | 1955.39 | 1955.39 | ArchiCADQuantities - Hauteur 3D de contremarche: 140 mm; Hauteur: 140 mm
C-MARCHE-356 | sousol | Lame d'air 275581351 | C-MARCHE-356 | sousol | 2 | Contremarche (Escalier) | ESC-021 | 0.578435 | 10 | 0.00268626 | 1919.29 | 1800 | 1800 | 1060 | 1940 | 1940 | 1800 | 1800 | 1 | Volée | 7 | Contremarche 27 | 0.268701 | 1919.29 | 1919.29 | ArchiCADQuantities - Hauteur 3D de contremarche: 140 mm; Hauteur: 140 mm
C-MARCHE-357 | sousol | Lame d'air 275581351 | C-MARCHE-357 | sousol | 2 | Contremarche (Escalier) | ESC-021 | 0.567607 | 10 | 0.00263573 | 1883.2 | 1950 | 1950 | 910 | 2090 | 2090 | 1950 | 1950 | 1 | Volée | 8 | Contremarche 27 | 0.263648 | 1883.2 | 1883.2 | ArchiCADQuantities - Hauteur 3D de contremarche: 140 mm; Hauteur: 140 mm
C-MARCHE-358 | sousol | Lame d'air 275581351 | C-MARCHE-358 | sousol | 2 | Contremarche (Escalier) | ESC-021 | 0.556778 | 10 | 0.00258519 | 1847.11 | 2100 | 2100 | 760 | 2240 | 2240 | 2100 | 2100 | 1 | Volée | 9 | Contremarche 27 | 0.258595 | 1847.11 | 1847.11 | ArchiCADQuantities - Hauteur 3D de contremarche: 140 mm; Hauteur: 140 mm
C-MARCHE-359 | sousol | Lame d'air 275581351 | C-MARCHE-359 | sousol | 2 | Contremarche (Escalier) | ESC-021 | 0.54595 | 10 | 0.00253466 | 1811.01 | 2250 | 2250 | 610 | 2390 | 2390 | 2250 | 2250 | 1 | Volée | 10 | Contremarche 27 | 0.253542 | 1811.01 | 1811.01 | ArchiCADQuantities - Hauteur 3D de contremarche: 140 mm; Hauteur: 140 mm
C-MARCHE-360 | sousol | Lame d'air 275581351 | C-MARCHE-360 | sousol | 2 | Contremarche (Escalier) | ESC-021 | 0.536585 | 10 | 0.00249094 | 1778.56 | 2400 | 2400 | 460 | 2540 | 2540 | 2400 | 2400 | 1 | Volée | 11 | Contremarche 27 | 0.248999 | 1778.56 | 1778.56 | ArchiCADQuantities - Hauteur 3D de contremarche: 140 mm; Hauteur: 140 mm
C-MARCHE-362 | sousol | Lame d'air 275581351 | C-MARCHE-362 | sousol | 2 | Contremarche (Escalier) | ESC-021 | 0.563884 | 10 | 0.00261833 | 1869.56 | 2700 | 2700 | 160 | 2840 | 2840 | 2700 | 2700 | 1 | Volée | 13 | Contremarche 27 | 0.261738 | 1869.56 | 1869.56 | ArchiCADQuantities - Hauteur 3D de contremarche: 140 mm; Hauteur: 140 mm
C-MARCHE-363 | sousol | Lame d'air 275581351 | C-MARCHE-363 | sousol | 2 | Contremarche (Escalier) | ESC-021 | 0.577534 | 10 | 0.00268203 | 1915.06 | 2850 | 2850 | 10 | 2990 | 2990 | 2850 | 2850 | 1 | Volée | 14 | Contremarche 27 | 0.268108 | 1915.06 | 1915.06 | ArchiCADQuantities - Hauteur 3D de contremarche: 140 mm; Hauteur: 140 mm
MARCHE-351 | sousol | Lame d'air 275581351 | MARCHE-351 | sousol | 2 | Giron (Escalier) | ESC-021 | 1.55088 | 10 | 0.00751003 |  | 1200 | 1200 | 1800 | 1200 | 1200 | 1190 | 1190 | 1 | Volée | 2 | Marche 27 | 0.0210138 | 2062.6 | 2101.38 | ArchiCADQuantities - Nez de marche: 15 mm; Giron de marche: 335.714 mm; Longueur volée marche: 360.714 mm; Superficie supérieure marche: 0.751003 m2
MARCHE-350 | sousol | Lame d'air 275581351 | MARCHE-350 | sousol | 2 | Giron (Escalier) | ESC-021 | 1.57548 | 10 | 0.00762957 |  | 1050 | 1050 | 1950 | 1050 | 1050 | 1040 | 1040 | 1 | Volée | 1 | Marche 27 | 0.0119555 | 2098.69 | 1195.55 | ArchiCADQuantities - Nez de marche: 15 mm; Giron de marche: 335.714 mm; Longueur volée marche: 360.714 mm; Superficie supérieure marche: 0.762957 m2
MARCHE-352 | sousol | Lame d'air 275581351 | MARCHE-352 | sousol | 2 | Giron (Escalier) | ESC-021 | 1.52412 | 10 | 0.00737983 |  | 1350 | 1350 | 1650 | 1350 | 1350 | 1340 | 1340 | 1 | Volée | 3 | Marche 27 | 0.0206528 | 2026.5 | 2065.28 | ArchiCADQuantities - Nez de marche: 15 mm; Giron de marche: 335.714 mm; Longueur volée marche: 360.714 mm; Superficie supérieure marche: 0.737983 m2
MARCHE-353 | sousol | Lame d'air 275581351 | MARCHE-353 | sousol | 2 | Giron (Escalier) | ESC-021 | 1.49736 | 10 | 0.00724963 |  | 1500 | 1500 | 1500 | 1500 | 1500 | 1490 | 1490 | 1 | Volée | 4 | Marche 27 | 0.0202919 | 1990.41 | 2029.19 | ArchiCADQuantities - Nez de marche: 15 mm; Giron de marche: 335.714 mm; Longueur volée marche: 360.714 mm; Superficie supérieure marche: 0.724963 m2
C-MARCHE-361 | sousol | Lame d'air 275581351 | C-MARCHE-361 | sousol | 2 | Contremarche (Escalier) | ESC-021 | 0.550234 | 10 | 0.00255463 | 1824.06 | 2550 | 2550 | 310 | 2690 | 2690 | 2550 | 2550 | 1 | Volée | 12 | Contremarche 27 | 0.255369 | 1824.06 | 1824.06 | ArchiCADQuantities - Hauteur 3D de contremarche: 140 mm; Hauteur: 140 mm
MARCHE-354 | sousol | Lame d'air 275581351 | MARCHE-354 | sousol | 2 | Giron (Escalier) | ESC-021 | 1.4706 | 10 | 0.00711944 |  | 1650 | 1650 | 1350 | 1650 | 1650 | 1640 | 1640 | 1 | Volée | 5 | Marche 27 | 0.019931 | 1954.31 | 1993.1 | ArchiCADQuantities - Nez de marche: 15 mm; Giron de marche: 335.714 mm; Longueur volée marche: 360.714 mm; Superficie supérieure marche: 0.711944 m2
C-MARCHE-353 | sousol | Lame d'air 275581351 | C-MARCHE-353 | sousol | 2 | Contremarche (Escalier) | ESC-021 | 0.61092 | 10 | 0.00283786 | 2027.58 | 1350 | 1350 | 1510 | 1490 | 1490 | 1350 | 1350 | 1 | Volée | 4 | Contremarche 27 | 0.283861 | 2027.58 | 2027.58 | ArchiCADQuantities - Hauteur 3D de contremarche: 140 mm; Hauteur: 140 mm
MARCHE-356 | sousol | Lame d'air 275581351 | MARCHE-356 | sousol | 2 | Giron (Escalier) | ESC-021 | 1.41707 | 10 | 0.00685904 |  | 1950 | 1950 | 1050 | 1950 | 1950 | 1940 | 1940 | 1 | Volée | 7 | Marche 27 | 0.0192091 | 1882.12 | 1920.91 | ArchiCADQuantities - Nez de marche: 15 mm; Giron de marche: 335.714 mm; Longueur volée marche: 360.714 mm; Superficie supérieure marche: 0.685904 m2
MARCHE-359 | sousol | Lame d'air 275581351 | MARCHE-359 | sousol | 2 | Giron (Escalier) | ESC-021 | 1.337 | 10 | 0.0064692 |  | 2400 | 2400 | 600 | 2400 | 2400 | 2390 | 2390 | 1 | Volée | 10 | Marche 27 | 0.0181262 | 1779.92 | 1812.62 | ArchiCADQuantities - Nez de marche: 15 mm; Giron de marche: 335.714 mm; Longueur volée marche: 360.714 mm; Superficie supérieure marche: 0.64692 m2
MARCHE-361 | sousol | Lame d'air 275581351 | MARCHE-361 | sousol | 2 | Giron (Escalier) | ESC-021 | 1.37627 | 10 | 0.00666049 |  | 2700 | 2700 | 300 | 2700 | 2700 | 2690 | 2690 | 1 | Volée | 12 | Marche 27 | 0.0182203 | 1870.91 | 1822.03 | ArchiCADQuantities - Nez de marche: 15 mm; Giron de marche: 335.714 mm; Longueur volée marche: 360.714 mm; Superficie supérieure marche: 0.666049 m2
MARCHE-360 | sousol | Lame d'air 275581351 | MARCHE-360 | sousol | 2 | Giron (Escalier) | ESC-021 | 1.34254 | 10 | 0.00649637 |  | 2550 | 2550 | 450 | 2550 | 2550 | 2540 | 2540 | 1 | Volée | 11 | Marche 27 | 0.0177653 | 1825.42 | 1776.53 | ArchiCADQuantities - Nez de marche: 15 mm; Giron de marche: 335.714 mm; Longueur volée marche: 360.714 mm; Superficie supérieure marche: 0.649637 m2
MARCHE-362 | sousol | Lame d'air 275581351 | MARCHE-362 | sousol | 2 | Giron (Escalier) | ESC-021 | 1.41001 | 10 | 0.00682461 |  | 2850 | 2850 | 150 | 2850 | 2850 | 2840 | 2840 | 1 | Volée | 13 | Marche 27 | 0.0186753 | 1916.41 | 1867.53 | ArchiCADQuantities - Nez de marche: 15 mm; Giron de marche: 335.714 mm; Longueur volée marche: 360.714 mm; Superficie supérieure marche: 0.682461 m2
MARCHE-363 | sousol | Lame d'air 275581351 | MARCHE-363 | sousol | 2 | Giron (Escalier) | ESC-021 | 1.34519 | 10 | 0.00649867 |  | 3000 | 3000 | 0 | 3000 | 3000 | 2990 | 2990 | 1 | Volée | 14 | Marche 27 | 0.0191303 | 1400 | 1913.03 | ArchiCADQuantities - Nez de marche: 15 mm; Giron de marche: 335.714 mm; Longueur volée marche: 335.714 mm; Superficie supérieure marche: 0.649867 m2
MARCHE-358 | sousol | Lame d'air 275581351 | MARCHE-358 | sousol | 2 | Giron (Escalier) | ESC-021 | 1.36355 | 10 | 0.00659864 |  | 2250 | 2250 | 750 | 2250 | 2250 | 2240 | 2240 | 1 | Volée | 9 | Marche 27 | 0.0184872 | 1809.94 | 1848.72 | ArchiCADQuantities - Nez de marche: 15 mm; Giron de marche: 335.714 mm; Longueur volée marche: 360.714 mm; Superficie supérieure marche: 0.659864 m2
MARCHE-357 | sousol | Lame d'air 275581351 | MARCHE-357 | sousol | 2 | Giron (Escalier) | ESC-021 | 1.39031 | 10 | 0.00672884 |  | 2100 | 2100 | 900 | 2100 | 2100 | 2090 | 2090 | 1 | Volée | 8 | Marche 27 | 0.0188481 | 1846.03 | 1884.81 | ArchiCADQuantities - Nez de marche: 15 mm; Giron de marche: 335.714 mm; Longueur volée marche: 360.714 mm; Superficie supérieure marche: 0.672884 m2
MARCHE-355 | sousol | Lame d'air 275581351 | MARCHE-355 | sousol | 2 | Giron (Escalier) | ESC-021 | 1.44383 | 10 | 0.00698924 |  | 1800 | 1800 | 1200 | 1800 | 1800 | 1790 | 1790 | 1 | Volée | 6 | Marche 27 | 0.01957 | 1918.22 | 1957 | ArchiCADQuantities - Nez de marche: 15 mm; Giron de marche: 335.714 mm; Longueur volée marche: 360.714 mm; Superficie supérieure marche: 0.698924 m2
2 x VOLEE-022 | rdc | Cloison 274992075 | VOLEE-022 | rdc | 3 | Structure (Escalier) | ESC-020 | 23.0028 | 150 | 2.01336 | 1220 | 5578.24 | 2578.24 | 171.765 | 5578.24 | 2578.24 | 2870 | -130 | ArchiCADProperties - Type construction: Monolithique; Type forme: Plat; Position structure escalier: Sous l'escalier; Index volée structure escalier: 1; Matériau de construction / Composite / Profil / Hachure: Cloison 274992075; Matériaux de construction (Tous): Cloison 274992075; ArchiCADQuantities - Épaisseur secondaire: 150 mm; Hauteur 3D de structure d'escalier: 2708.24 mm; Longueur 3D: 5809.97 mm
C-MARCHE-332 | rdc | Parpaing 2676271321 | C-MARCHE-332 | rdc | 3 | Contremarche (Escalier) | ESC-020 | 0.397741 | 10 | 0.00185153 | 1220 | 3000 | 0 | 2598.24 | 3151.76 | 151.765 | 3000 | 0 | 1 | Quart tournant avec marches égales | 1 | Contremarche 27 | 0.185153 | 1220 | 1220 | ArchiCADQuantities - Hauteur 3D de contremarche: 151.765 mm; Hauteur: 151.765 mm; ArchiCADProperties - Surfaces (Toutes): Peinture-11
C-MARCHE-333 | rdc | Parpaing 2676271321 | C-MARCHE-333 | rdc | 3 | Contremarche (Escalier) | ESC-020 | 0.397741 | 10 | 0.00185153 | 1220 | 3161.76 | 161.765 | 2436.47 | 3313.53 | 313.529 | 3161.76 | 161.765 | 1 | Quart tournant avec marches égales | 2 | Contremarche 27 | 0.185153 | 1220 | 1220 | ArchiCADQuantities - Hauteur 3D de contremarche: 151.765 mm; Hauteur: 151.765 mm; ArchiCADProperties - Surfaces (Toutes): Peinture-11
C-MARCHE-334 | rdc | Parpaing 2676271321 | C-MARCHE-334 | rdc | 3 | Contremarche (Escalier) | ESC-020 | 0.397741 | 10 | 0.00185153 | 1220 | 3323.53 | 323.529 | 2274.71 | 3475.29 | 475.294 | 3323.53 | 323.529 | 1 | Quart tournant avec marches égales | 3 | Contremarche 27 | 0.185153 | 1220 | 1220 | ArchiCADQuantities - Hauteur 3D de contremarche: 151.765 mm; Hauteur: 151.765 mm; ArchiCADProperties - Surfaces (Toutes): Peinture-11
C-MARCHE-336 | rdc | Parpaing 2676271321 | C-MARCHE-336 | rdc | 3 | Contremarche (Escalier) | ESC-020 | 0.518578 | 10 | 0.00241656 | 1588.17 | 3647.06 | 647.059 | 1951.18 | 3798.82 | 798.824 | 3647.06 | 647.059 | 1 | Quart tournant avec marches égales | 5 | Contremarche 27 | 0.241028 | 1588.17 | 1588.17 | ArchiCADQuantities - Hauteur 3D de contremarche: 151.765 mm; Hauteur: 151.765 mm; ArchiCADProperties - Surfaces (Toutes): Peinture-11
C-MARCHE-335 | rdc | Parpaing 2676271321 | C-MARCHE-335 | rdc | 3 | Contremarche (Escalier) | ESC-020 | 0.413619 | 10 | 0.00192578 | 1267.31 | 3485.29 | 485.294 | 2112.94 | 3637.06 | 637.059 | 3485.29 | 485.294 | 1 | Quart tournant avec marches égales | 4 | Contremarche 27 | 0.192332 | 1267.31 | 1267.31 | ArchiCADQuantities - Hauteur 3D de contremarche: 151.765 mm; Hauteur: 151.765 mm; ArchiCADProperties - Surfaces (Toutes): Peinture-11
C-MARCHE-338 | rdc | Parpaing 2676271321 | C-MARCHE-338 | rdc | 3 | Contremarche (Escalier) | ESC-020 | 0.400095 | 10 | 0.0018625 | 1227.48 | 3970.59 | 970.588 | 1627.65 | 4122.35 | 1122.35 | 3970.59 | 970.588 | 1 | Quart tournant avec marches égales | 7 | Contremarche 27 | 0.186288 | 1227.48 | 1227.48 | ArchiCADQuantities - Hauteur 3D de contremarche: 151.765 mm; Hauteur: 151.765 mm; ArchiCADProperties - Surfaces (Toutes): Peinture-11
C-MARCHE-339 | rdc | Parpaing 2676271321 | C-MARCHE-339 | rdc | 3 | Contremarche (Escalier) | ESC-020 | 0.417789 | 10 | 0.00194527 | 1279.95 | 4132.35 | 1132.35 | 1465.88 | 4284.12 | 1284.12 | 4132.35 | 1132.35 | 1 | Quart tournant avec marches égales | 8 | Contremarche 27 | 0.194252 | 1279.95 | 1279.95 | ArchiCADQuantities - Hauteur 3D de contremarche: 151.765 mm; Hauteur: 151.765 mm; ArchiCADProperties - Surfaces (Toutes): Peinture-11
C-MARCHE-341 | rdc | Parpaing 2676271321 | C-MARCHE-341 | rdc | 3 | Contremarche (Escalier) | ESC-020 | 0.456082 | 10 | 0.00212423 | 1401.98 | 4455.88 | 1455.88 | 1142.35 | 4607.65 | 1607.65 | 4455.88 | 1455.88 | 1 | Quart tournant avec marches égales | 10 | Contremarche 27 | 0.212771 | 1401.98 | 1401.98 | ArchiCADQuantities - Hauteur 3D de contremarche: 151.765 mm; Hauteur: 151.765 mm; ArchiCADProperties - Surfaces (Toutes): Peinture-11
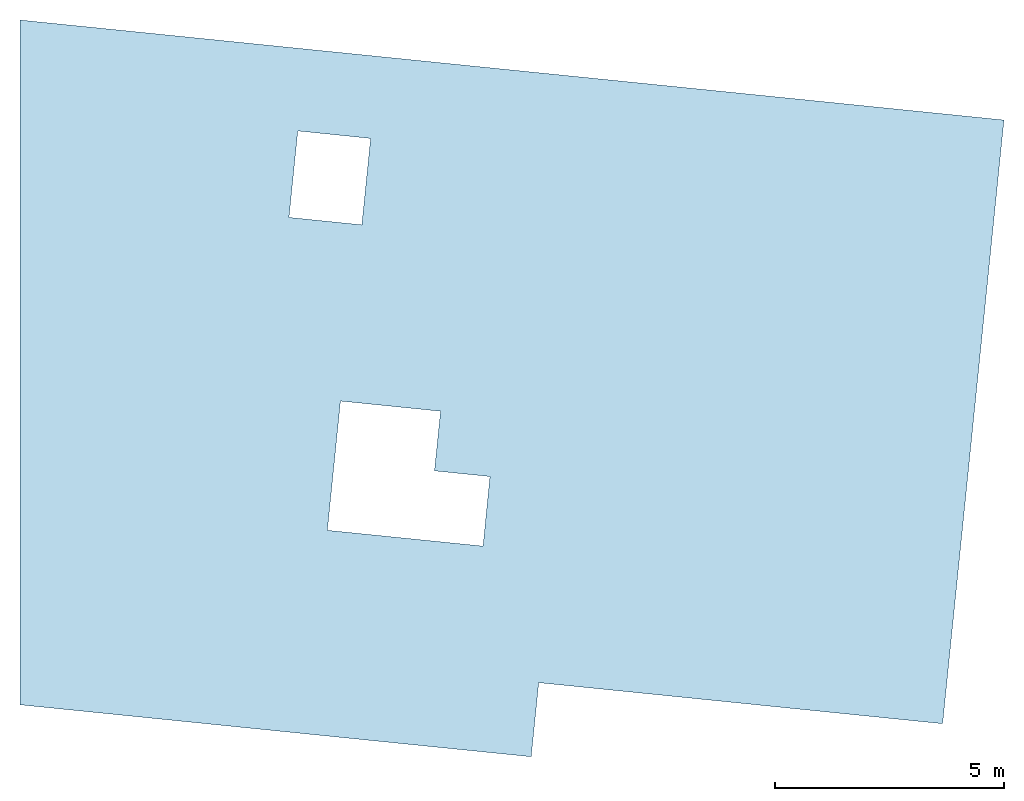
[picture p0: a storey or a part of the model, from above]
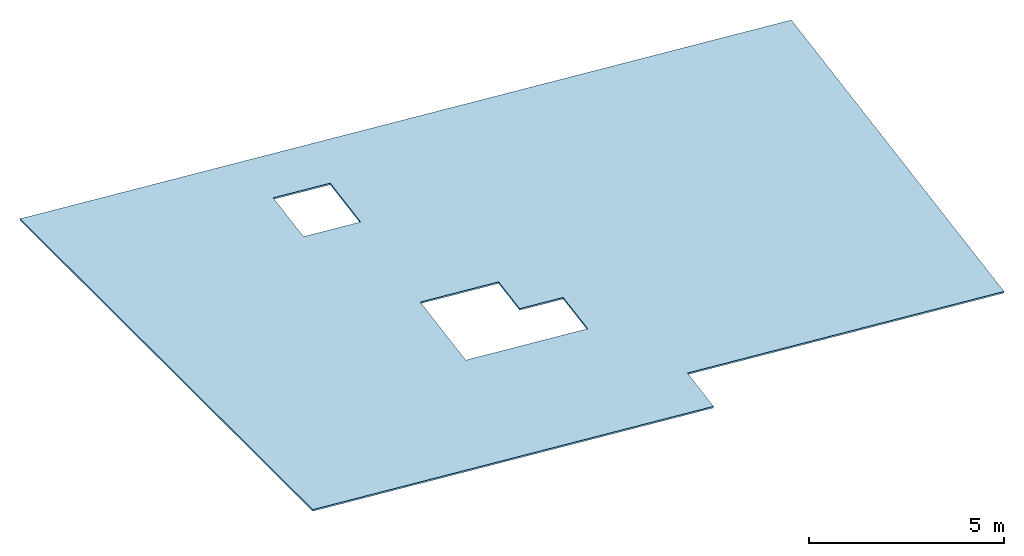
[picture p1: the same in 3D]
Properties of the parts of a building model (IFC2X3), part 7 of 44

# IfcBuildingElementProxy: IfcBuildingElementProxy (404)
Name | In | Material | ID de l'élément = Lien et ID d'élément | Nom d'étage d'implantation | Numéro d'étage d'implantation | Type d'élément | ID de Parent | Superficie totale (m2) = Superficie en plan (m2) = Superficie inférieure (nette) (m2) | Épaisseur (mm) | Volume (net) (m3) | Largeur (mm) | Altitude à Zéro du Projet (mm) = Altitude de Référence Niveau 1 (mm) = Altitude de Référence Niveau 2 (mm) = Altitude à niveau de la mer (mm) | Altitude à étage lié/étage d'implantation (mm) = Décalage étage d'implantation (mm) | Décalage supérieur (mm) | Altitude supérieure à premier niveau de référence (mm) = Altitude supérieure à Zéro du projet (mm) = Altitude supérieure à niveau de la mer (mm) = Altitude supérieure à deuxième niveau de référence (mm) | Altitude supérieure à étage d'implantation (mm) | Altitude inférieure à premier niveau de référence (mm) = Altitude inférieure à Zéro du projet (mm) = Altitude inférieure à niveau de la mer (mm) = Altitude inférieure à deuxième niveau de référence (mm) | Altitude inférieure à étage d'implantation (mm) | Index volée | Type de segment | Index de marche | Nom Élément de Bibliothèque | Superficie avant (m2) | Largeur arrière (mm) | Largeur avant (mm)
C-MARCHE-337 | rdc | Parpaing 2676271321 | C-MARCHE-337 | rdc | 3 | Contremarche (Escalier) | ESC-020 | 0.465612 | 10 | 0.00216877 | 1431.56 | 3808.82 | 808.824 | 1789.41 | 3960.59 | 960.588 | 3808.82 | 808.824 | 1 | Quart tournant avec marches égales | 6 | Contremarche 27 | 0.217261 | 1431.56 | 1431.56 | ArchiCADQuantities - Hauteur 3D de contremarche: 151.765 mm; Hauteur: 151.765 mm; ArchiCADProperties - Surfaces (Toutes): Peinture-11
C-MARCHE-342 | rdc | Parpaing 2676271321 | C-MARCHE-342 | rdc | 3 | Contremarche (Escalier) | ESC-020 | 0.399292 | 10 | 0.00185876 | 1224.83 | 4617.65 | 1617.65 | 980.588 | 4769.41 | 1769.41 | 4617.65 | 1617.65 | 1 | Quart tournant avec marches égales | 11 | Contremarche 27 | 0.185886 | 1224.83 | 1224.83 | ArchiCADQuantities - Hauteur 3D de contremarche: 151.765 mm; Hauteur: 151.765 mm; ArchiCADProperties - Surfaces (Toutes): Peinture-11
C-MARCHE-343 | rdc | Parpaing 2676271321 | C-MARCHE-343 | rdc | 3 | Contremarche (Escalier) | ESC-020 | 0.397741 | 10 | 0.00185153 | 1220 | 4779.41 | 1779.41 | 818.824 | 4931.18 | 1931.18 | 4779.41 | 1779.41 | 1 | Quart tournant avec marches égales | 12 | Contremarche 27 | 0.185153 | 1220 | 1220 | ArchiCADQuantities - Hauteur 3D de contremarche: 151.765 mm; Hauteur: 151.765 mm; ArchiCADProperties - Surfaces (Toutes): Peinture-11
C-MARCHE-344 | rdc | Parpaing 2676271321 | C-MARCHE-344 | rdc | 3 | Contremarche (Escalier) | ESC-020 | 0.398046 | 10 | 0.00185294 | 1220.56 | 4941.18 | 1941.18 | 657.059 | 5092.94 | 2092.94 | 4941.18 | 1941.18 | 1 | Quart tournant avec marches égales | 13 | Contremarche 27 | 0.185237 | 1220.56 | 1220.56 | ArchiCADQuantities - Hauteur 3D de contremarche: 151.765 mm; Hauteur: 151.765 mm; ArchiCADProperties - Surfaces (Toutes): Peinture-11
C-MARCHE-345 | rdc | Parpaing 2676271321 | C-MARCHE-345 | rdc | 3 | Contremarche (Escalier) | ESC-020 | 0.440568 | 10 | 0.00205179 | 1349.46 | 5102.94 | 2102.94 | 495.294 | 5254.71 | 2254.71 | 5102.94 | 2102.94 | 1 | Quart tournant avec marches égales | 14 | Contremarche 27 | 0.2048 | 1349.46 | 1349.46 | ArchiCADQuantities - Hauteur 3D de contremarche: 151.765 mm; Hauteur: 151.765 mm; ArchiCADProperties - Surfaces (Toutes): Peinture-11
C-MARCHE-346 | rdc | Parpaing 2676271321 | C-MARCHE-346 | rdc | 3 | Contremarche (Escalier) | ESC-020 | 0.572948 | 10 | 0.00267059 | 1764.16 | 5264.71 | 2264.71 | 333.529 | 5416.47 | 2416.47 | 5264.71 | 2264.71 | 1 | Quart tournant avec marches égales | 15 | Contremarche 27 | 0.267738 | 1764.16 | 1764.16 | ArchiCADQuantities - Hauteur 3D de contremarche: 151.765 mm; Hauteur: 151.765 mm; ArchiCADProperties - Surfaces (Toutes): Peinture-11
C-MARCHE-347 | rdc | Parpaing 2676271321 | C-MARCHE-347 | rdc | 3 | Contremarche (Escalier) | ESC-020 | 0.428757 | 10 | 0.00199649 | 1317.07 | 5426.47 | 2426.47 | 171.765 | 5578.24 | 2578.24 | 5426.47 | 2426.47 | 1 | Quart tournant avec marches égales | 16 | Contremarche 27 | 0.199885 | 1317.07 | 1317.07 | ArchiCADQuantities - Hauteur 3D de contremarche: 151.765 mm; Hauteur: 151.765 mm; ArchiCADProperties - Surfaces (Toutes): Peinture-11
2 x MARCHE-332 | rdc | Lame d'air 275581351 | MARCHE-332 | rdc | 3 | Giron (Escalier) | ESC-020 | 0.885647 | 10 | 0.00427123 |  | 3161.76 | 161.765 | 2588.24 | 3161.76 | 161.765 | 3151.76 | 151.765 | 1 | Quart tournant avec marches égales | 1 | Marche 27 | 0.0122 | 1220 | 1220 | ArchiCADQuantities - Nez de marche: 15 mm; Giron de marche: 325.101 mm; Longueur volée marche: 350.101 mm; Superficie supérieure marche: 0.427123 m2
C-MARCHE-340 | rdc | Parpaing 2676271321 | C-MARCHE-340 | rdc | 3 | Contremarche (Escalier) | ESC-020 | 0.534643 | 10 | 0.00249166 | 1637.37 | 4294.12 | 1294.12 | 1304.12 | 4445.88 | 1445.88 | 4294.12 | 1294.12 | 1 | Quart tournant avec marches égales | 9 | Contremarche 27 | 0.248494 | 1637.37 | 1637.37 | ArchiCADQuantities - Hauteur 3D de contremarche: 151.765 mm; Hauteur: 151.765 mm; ArchiCADProperties - Surfaces (Toutes): Peinture-11
2 x MARCHE-333 | rdc | Lame d'air 275581351 | MARCHE-333 | rdc | 3 | Giron (Escalier) | ESC-020 | 0.885647 | 10 | 0.00427123 |  | 3323.53 | 323.529 | 2426.47 | 3323.53 | 323.529 | 3313.53 | 313.529 | 1 | Quart tournant avec marches égales | 2 | Marche 27 | 0.0122 | 1220 | 1220 | ArchiCADQuantities - Nez de marche: 15 mm; Giron de marche: 325.101 mm; Longueur volée marche: 350.101 mm; Superficie supérieure marche: 0.427123 m2
2 x MARCHE-334 | rdc | Lame d'air 275581351 | MARCHE-334 | rdc | 3 | Giron (Escalier) | ESC-020 | 0.898539 | 10 | 0.00433276 |  | 3485.29 | 485.294 | 2264.71 | 3485.29 | 485.294 | 3475.29 | 475.294 | 1 | Quart tournant avec marches égales | 3 | Marche 27 | 0.0122 | 1270.79 | 1220 | ArchiCADQuantities - Nez de marche: 15 mm; Giron de marche: 325.101 mm; Longueur volée marche: 350.105 mm; Superficie supérieure marche: 0.433276 m2
C-MARCHE-348 | rdc | Parpaing 2676271321 | C-MARCHE-348 | rdc | 3 | Contremarche (Escalier) | ESC-020 | 0.422341 | 10 | 0.00197353 | 1220 | 5588.24 | 2588.24 | 0 | 5750 | 2750 | 5588.24 | 2588.24 | 1 | Inconnu | 17 | Contremarche 27 | 0.197353 | 1220 | 1220 | ArchiCADQuantities - Hauteur 3D de contremarche: 161.765 mm; Hauteur: 161.765 mm; ArchiCADProperties - Surfaces (Toutes): Peinture-11
2 x MARCHE-335 | rdc | Lame d'air 275581351 | MARCHE-335 | rdc | 3 | Giron (Escalier) | ESC-020 | 1.11576 | 10 | 0.00539325 |  | 3647.06 | 647.059 | 2102.94 | 3647.06 | 647.059 | 3637.06 | 637.059 | 1 | Quart tournant avec marches égales | 4 | Marche 27 | 0.0126302 | 1596.69 | 1263.02 | ArchiCADQuantities - Nez de marche: 15 mm; Giron de marche: 325.101 mm; Longueur volée marche: 350.105 mm; Superficie supérieure marche: 0.539325 m2
2 x MARCHE-336 | rdc | Lame d'air 275581351 | MARCHE-336 | rdc | 3 | Giron (Escalier) | ESC-020 | 1.44552 | 10 | 0.0070232 |  | 3808.82 | 808.824 | 1941.18 | 3808.82 | 808.824 | 3798.82 | 798.824 | 1 | Quart tournant avec marches égales | 5 | Marche 27 | 0.0157633 | 1426.76 | 1576.33 | ArchiCADQuantities - Nez de marche: 15 mm; Giron de marche: 325.101 mm; Longueur volée marche: 350.105 mm; Superficie supérieure marche: 0.70232 m2
2 x MARCHE-338 | rdc | Lame d'air 275581351 | MARCHE-338 | rdc | 3 | Giron (Escalier) | ESC-020 | 0.90354 | 10 | 0.00435648 |  | 4132.35 | 1132.35 | 1617.65 | 4132.35 | 1132.35 | 4122.35 | 1122.35 | 1 | Quart tournant avec marches égales | 7 | Marche 27 | 0.012288 | 1283.83 | 1228.8 | ArchiCADQuantities - Nez de marche: 15 mm; Giron de marche: 325.101 mm; Longueur volée marche: 350.105 mm; Superficie supérieure marche: 0.435648 m2
2 x MARCHE-339 | rdc | Lame d'air 275581351 | MARCHE-339 | rdc | 3 | Giron (Escalier) | ESC-020 | 1.15533 | 10 | 0.0055866 |  | 4294.12 | 1294.12 | 1455.88 | 4294.12 | 1294.12 | 4284.12 | 1284.12 | 1 | Quart tournant avec marches égales | 8 | Marche 27 | 0.0127509 | 1646.47 | 1275.09 | ArchiCADQuantities - Nez de marche: 15 mm; Giron de marche: 325.101 mm; Longueur volée marche: 350.105 mm; Superficie supérieure marche: 0.55866 m2
2 x MARCHE-340 | rdc | Lame d'air 275581351 | MARCHE-340 | rdc | 3 | Giron (Escalier) | ESC-020 | 1.42363 | 10 | 0.00691358 |  | 4455.88 | 1455.88 | 1294.12 | 4455.88 | 1455.88 | 4445.88 | 1445.88 | 1 | Quart tournant avec marches égales | 9 | Marche 27 | 0.0162465 | 1397.65 | 1624.65 | ArchiCADQuantities - Nez de marche: 15 mm; Giron de marche: 325.101 mm; Longueur volée marche: 350.105 mm; Superficie supérieure marche: 0.691358 m2
2 x MARCHE-337 | rdc | Lame d'air 275581351 | MARCHE-337 | rdc | 3 | Giron (Escalier) | ESC-020 | 0.99521 | 10 | 0.0048039 |  | 3970.59 | 970.588 | 1779.41 | 3970.59 | 970.588 | 3960.59 | 960.588 | 1 | Quart tournant avec marches égales | 6 | Marche 27 | 0.0143972 | 1227.23 | 1439.72 | ArchiCADQuantities - Nez de marche: 15 mm; Giron de marche: 325.101 mm; Longueur volée marche: 350.105 mm; Superficie supérieure marche: 0.48039 m2
2 x MARCHE-341 | rdc | Lame d'air 275581351 | MARCHE-341 | rdc | 3 | Giron (Escalier) | ESC-020 | 0.975694 | 10 | 0.00470869 |  | 4617.65 | 1617.65 | 1132.35 | 4617.65 | 1617.65 | 4607.65 | 1607.65 | 1 | Quart tournant avec marches égales | 10 | Marche 27 | 0.0140942 | 1224.81 | 1409.42 | ArchiCADQuantities - Nez de marche: 15 mm; Giron de marche: 325.101 mm; Longueur volée marche: 350.105 mm; Superficie supérieure marche: 0.470869 m2
2 x MARCHE-343 | rdc | Lame d'air 275581351 | MARCHE-343 | rdc | 3 | Giron (Escalier) | ESC-020 | 0.885702 | 10 | 0.00427142 |  | 4941.18 | 1941.18 | 808.824 | 4941.18 | 1941.18 | 4931.18 | 1931.18 | 1 | Quart tournant avec marches égales | 12 | Marche 27 | 0.0122 | 1221.56 | 1220 | ArchiCADQuantities - Nez de marche: 15 mm; Giron de marche: 325.101 mm; Longueur volée marche: 350.104 mm; Superficie supérieure marche: 0.427142 m2
2 x MARCHE-342 | rdc | Lame d'air 275581351 | MARCHE-342 | rdc | 3 | Giron (Escalier) | ESC-020 | 0.886181 | 10 | 0.0042736 |  | 4779.41 | 1779.41 | 970.588 | 4779.41 | 1779.41 | 4769.41 | 1769.41 | 1 | Quart tournant avec marches égales | 11 | Marche 27 | 0.012256 | 1220 | 1225.6 | ArchiCADQuantities - Nez de marche: 15 mm; Giron de marche: 325.101 mm; Longueur volée marche: 350.101 mm; Superficie supérieure marche: 0.42736 m2
2 x MARCHE-344 | rdc | Lame d'air 275581351 | MARCHE-344 | rdc | 3 | Giron (Escalier) | ESC-020 | 0.940287 | 10 | 0.00453595 |  | 5102.94 | 2102.94 | 647.059 | 5102.94 | 2102.94 | 5092.94 | 2092.94 | 1 | Quart tournant avec marches égales | 13 | Marche 27 | 0.0122 | 1354.71 | 1220 | ArchiCADQuantities - Nez de marche: 15 mm; Giron de marche: 325.101 mm; Longueur volée marche: 350.105 mm; Superficie supérieure marche: 0.453595 m2
2 x MARCHE-347 | rdc | Lame d'air 275581351 | MARCHE-347 | rdc | 3 | Giron (Escalier) | ESC-020 | 0.922626 | 10 | 0.00444976 |  | 5588.24 | 2588.24 | 161.765 | 5588.24 | 2588.24 | 5578.24 | 2578.24 | 1 | Quart tournant avec marches égales | 16 | Marche 27 | 0.013223 | 1220 | 1322.3 | ArchiCADQuantities - Nez de marche: 15 mm; Giron de marche: 325.101 mm; Longueur volée marche: 325.101 mm; Superficie supérieure marche: 0.444976 m2
2 x MARCHE-346 | rdc | Lame d'air 275581351 | MARCHE-346 | rdc | 3 | Giron (Escalier) | ESC-020 | 1.26693 | 10 | 0.00613203 |  | 5426.47 | 2426.47 | 323.529 | 5426.47 | 2426.47 | 5416.47 | 2416.47 | 1 | Quart tournant avec marches égales | 15 | Marche 27 | 0.0177815 | 1314.21 | 1778.15 | ArchiCADQuantities - Nez de marche: 15 mm; Giron de marche: 325.101 mm; Longueur volée marche: 350.105 mm; Superficie supérieure marche: 0.613203 m2
2 x MARCHE-345 | rdc | Lame d'air 275581351 | MARCHE-345 | rdc | 3 | Giron (Escalier) | ESC-020 | 1.34291 | 10 | 0.00650934 |  | 5264.71 | 2264.71 | 485.294 | 5264.71 | 2264.71 | 5254.71 | 2254.71 | 1 | Quart tournant avec marches égales | 14 | Marche 27 | 0.0134253 | 1755.47 | 1342.53 | ArchiCADQuantities - Nez de marche: 15 mm; Giron de marche: 325.101 mm; Longueur volée marche: 350.105 mm; Superficie supérieure marche: 0.650934 m2
C-MARCHE-332 | rdc | Lame d'air 275581351 | C-MARCHE-332 | rdc | 3 | Contremarche (Escalier) | ESC-020 | 0.397741 | 10 | 0.00185153 | 1220 | 3000 | 0 | 2598.24 | 3151.76 | 151.765 | 3000 | 0 | 1 | Quart tournant avec marches égales | 1 | Contremarche 27 | 0.185153 | 1220 | 1220 | ArchiCADQuantities - Hauteur 3D de contremarche: 151.765 mm; Hauteur: 151.765 mm
C-MARCHE-333 | rdc | Lame d'air 275581351 | C-MARCHE-333 | rdc | 3 | Contremarche (Escalier) | ESC-020 | 0.397741 | 10 | 0.00185153 | 1220 | 3161.76 | 161.765 | 2436.47 | 3313.53 | 313.529 | 3161.76 | 161.765 | 1 | Quart tournant avec marches égales | 2 | Contremarche 27 | 0.185153 | 1220 | 1220 | ArchiCADQuantities - Hauteur 3D de contremarche: 151.765 mm; Hauteur: 151.765 mm
C-MARCHE-335 | rdc | Lame d'air 275581351 | C-MARCHE-335 | rdc | 3 | Contremarche (Escalier) | ESC-020 | 0.413619 | 10 | 0.00192578 | 1267.31 | 3485.29 | 485.294 | 2112.94 | 3637.06 | 637.059 | 3485.29 | 485.294 | 1 | Quart tournant avec marches égales | 4 | Contremarche 27 | 0.192332 | 1267.31 | 1267.31 | ArchiCADQuantities - Hauteur 3D de contremarche: 151.765 mm; Hauteur: 151.765 mm
C-MARCHE-336 | rdc | Lame d'air 275581351 | C-MARCHE-336 | rdc | 3 | Contremarche (Escalier) | ESC-020 | 0.518578 | 10 | 0.00241656 | 1588.17 | 3647.06 | 647.059 | 1951.18 | 3798.82 | 798.824 | 3647.06 | 647.059 | 1 | Quart tournant avec marches égales | 5 | Contremarche 27 | 0.241028 | 1588.17 | 1588.17 | ArchiCADQuantities - Hauteur 3D de contremarche: 151.765 mm; Hauteur: 151.765 mm
C-MARCHE-337 | rdc | Lame d'air 275581351 | C-MARCHE-337 | rdc | 3 | Contremarche (Escalier) | ESC-020 | 0.465612 | 10 | 0.00216877 | 1431.56 | 3808.82 | 808.824 | 1789.41 | 3960.59 | 960.588 | 3808.82 | 808.824 | 1 | Quart tournant avec marches égales | 6 | Contremarche 27 | 0.217261 | 1431.56 | 1431.56 | ArchiCADQuantities - Hauteur 3D de contremarche: 151.765 mm; Hauteur: 151.765 mm
C-MARCHE-338 | rdc | Lame d'air 275581351 | C-MARCHE-338 | rdc | 3 | Contremarche (Escalier) | ESC-020 | 0.400095 | 10 | 0.0018625 | 1227.48 | 3970.59 | 970.588 | 1627.65 | 4122.35 | 1122.35 | 3970.59 | 970.588 | 1 | Quart tournant avec marches égales | 7 | Contremarche 27 | 0.186288 | 1227.48 | 1227.48 | ArchiCADQuantities - Hauteur 3D de contremarche: 151.765 mm; Hauteur: 151.765 mm
C-MARCHE-339 | rdc | Lame d'air 275581351 | C-MARCHE-339 | rdc | 3 | Contremarche (Escalier) | ESC-020 | 0.417789 | 10 | 0.00194527 | 1279.95 | 4132.35 | 1132.35 | 1465.88 | 4284.12 | 1284.12 | 4132.35 | 1132.35 | 1 | Quart tournant avec marches égales | 8 | Contremarche 27 | 0.194252 | 1279.95 | 1279.95 | ArchiCADQuantities - Hauteur 3D de contremarche: 151.765 mm; Hauteur: 151.765 mm
C-MARCHE-340 | rdc | Lame d'air 275581351 | C-MARCHE-340 | rdc | 3 | Contremarche (Escalier) | ESC-020 | 0.534643 | 10 | 0.00249166 | 1637.37 | 4294.12 | 1294.12 | 1304.12 | 4445.88 | 1445.88 | 4294.12 | 1294.12 | 1 | Quart tournant avec marches égales | 9 | Contremarche 27 | 0.248494 | 1637.37 | 1637.37 | ArchiCADQuantities - Hauteur 3D de contremarche: 151.765 mm; Hauteur: 151.765 mm
C-MARCHE-341 | rdc | Lame d'air 275581351 | C-MARCHE-341 | rdc | 3 | Contremarche (Escalier) | ESC-020 | 0.456082 | 10 | 0.00212423 | 1401.98 | 4455.88 | 1455.88 | 1142.35 | 4607.65 | 1607.65 | 4455.88 | 1455.88 | 1 | Quart tournant avec marches égales | 10 | Contremarche 27 | 0.212771 | 1401.98 | 1401.98 | ArchiCADQuantities - Hauteur 3D de contremarche: 151.765 mm; Hauteur: 151.765 mm
C-MARCHE-342 | rdc | Lame d'air 275581351 | C-MARCHE-342 | rdc | 3 | Contremarche (Escalier) | ESC-020 | 0.399292 | 10 | 0.00185876 | 1224.83 | 4617.65 | 1617.65 | 980.588 | 4769.41 | 1769.41 | 4617.65 | 1617.65 | 1 | Quart tournant avec marches égales | 11 | Contremarche 27 | 0.185886 | 1224.83 | 1224.83 | ArchiCADQuantities - Hauteur 3D de contremarche: 151.765 mm; Hauteur: 151.765 mm
C-MARCHE-344 | rdc | Lame d'air 275581351 | C-MARCHE-344 | rdc | 3 | Contremarche (Escalier) | ESC-020 | 0.398046 | 10 | 0.00185294 | 1220.56 | 4941.18 | 1941.18 | 657.059 | 5092.94 | 2092.94 | 4941.18 | 1941.18 | 1 | Quart tournant avec marches égales | 13 | Contremarche 27 | 0.185237 | 1220.56 | 1220.56 | ArchiCADQuantities - Hauteur 3D de contremarche: 151.765 mm; Hauteur: 151.765 mm
C-MARCHE-345 | rdc | Lame d'air 275581351 | C-MARCHE-345 | rdc | 3 | Contremarche (Escalier) | ESC-020 | 0.440568 | 10 | 0.00205179 | 1349.46 | 5102.94 | 2102.94 | 495.294 | 5254.71 | 2254.71 | 5102.94 | 2102.94 | 1 | Quart tournant avec marches égales | 14 | Contremarche 27 | 0.2048 | 1349.46 | 1349.46 | ArchiCADQuantities - Hauteur 3D de contremarche: 151.765 mm; Hauteur: 151.765 mm
C-MARCHE-346 | rdc | Lame d'air 275581351 | C-MARCHE-346 | rdc | 3 | Contremarche (Escalier) | ESC-020 | 0.572948 | 10 | 0.00267059 | 1764.16 | 5264.71 | 2264.71 | 333.529 | 5416.47 | 2416.47 | 5264.71 | 2264.71 | 1 | Quart tournant avec marches égales | 15 | Contremarche 27 | 0.267738 | 1764.16 | 1764.16 | ArchiCADQuantities - Hauteur 3D de contremarche: 151.765 mm; Hauteur: 151.765 mm
C-MARCHE-347 | rdc | Lame d'air 275581351 | C-MARCHE-347 | rdc | 3 | Contremarche (Escalier) | ESC-020 | 0.428757 | 10 | 0.00199649 | 1317.07 | 5426.47 | 2426.47 | 171.765 | 5578.24 | 2578.24 | 5426.47 | 2426.47 | 1 | Quart tournant avec marches égales | 16 | Contremarche 27 | 0.199885 | 1317.07 | 1317.07 | ArchiCADQuantities - Hauteur 3D de contremarche: 151.765 mm; Hauteur: 151.765 mm
C-MARCHE-348 | rdc | Lame d'air 275581351 | C-MARCHE-348 | rdc | 3 | Contremarche (Escalier) | ESC-020 | 0.422341 | 10 | 0.00197353 | 1220 | 5588.24 | 2588.24 | 0 | 5750 | 2750 | 5588.24 | 2588.24 | 1 | Inconnu | 17 | Contremarche 27 | 0.197353 | 1220 | 1220 | ArchiCADQuantities - Hauteur 3D de contremarche: 161.765 mm; Hauteur: 161.765 mm
C-MARCHE-343 | rdc | Lame d'air 275581351 | C-MARCHE-343 | rdc | 3 | Contremarche (Escalier) | ESC-020 | 0.397741 | 10 | 0.00185153 | 1220 | 4779.41 | 1779.41 | 818.824 | 4931.18 | 1931.18 | 4779.41 | 1779.41 | 1 | Quart tournant avec marches égales | 12 | Contremarche 27 | 0.185153 | 1220 | 1220 | ArchiCADQuantities - Hauteur 3D de contremarche: 151.765 mm; Hauteur: 151.765 mm
C-MARCHE-334 | rdc | Lame d'air 275581351 | C-MARCHE-334 | rdc | 3 | Contremarche (Escalier) | ESC-020 | 0.397741 | 10 | 0.00185153 | 1220 | 3323.53 | 323.529 | 2274.71 | 3475.29 | 475.294 | 3323.53 | 323.529 | 1 | Quart tournant avec marches égales | 3 | Contremarche 27 | 0.185153 | 1220 | 1220 | ArchiCADQuantities - Hauteur 3D de contremarche: 151.765 mm; Hauteur: 151.765 mm
2 x VOLEE-022 | Etage1 | Cloison 274992075 | VOLEE-022 | Etage1 | 4 | Structure (Escalier) | ESC-020 | 23.0028 | 150 | 2.01336 | 1220 | 8328.24 | 2578.24 | 171.765 | 8328.24 | 2578.24 | 5620 | -130 | ArchiCADProperties - Type construction: Monolithique; Type forme: Plat; Position structure escalier: Sous l'escalier; Index volée structure escalier: 1; Matériau de construction / Composite / Profil / Hachure: Cloison 274992075; Matériaux de construction (Tous): Cloison 274992075; ArchiCADQuantities - Épaisseur secondaire: 150 mm; Hauteur 3D de structure d'escalier: 2708.24 mm; Longueur 3D: 5809.97 mm
C-MARCHE-332 | Etage1 | Parpaing 2676271321 | C-MARCHE-332 | Etage1 | 4 | Contremarche (Escalier) | ESC-020 | 0.397741 | 10 | 0.00185153 | 1220 | 5750 | 0 | 2598.24 | 5901.76 | 151.765 | 5750 | 0 | 1 | Quart tournant avec marches égales | 1 | Contremarche 27 | 0.185153 | 1220 | 1220 | ArchiCADQuantities - Hauteur 3D de contremarche: 151.765 mm; Hauteur: 151.765 mm; ArchiCADProperties - Surfaces (Toutes): Peinture-11
C-MARCHE-333 | Etage1 | Parpaing 2676271321 | C-MARCHE-333 | Etage1 | 4 | Contremarche (Escalier) | ESC-020 | 0.397741 | 10 | 0.00185153 | 1220 | 5911.76 | 161.765 | 2436.47 | 6063.53 | 313.529 | 5911.76 | 161.765 | 1 | Quart tournant avec marches égales | 2 | Contremarche 27 | 0.185153 | 1220 | 1220 | ArchiCADQuantities - Hauteur 3D de contremarche: 151.765 mm; Hauteur: 151.765 mm; ArchiCADProperties - Surfaces (Toutes): Peinture-11
C-MARCHE-334 | Etage1 | Parpaing 2676271321 | C-MARCHE-334 | Etage1 | 4 | Contremarche (Escalier) | ESC-020 | 0.397741 | 10 | 0.00185153 | 1220 | 6073.53 | 323.529 | 2274.71 | 6225.29 | 475.294 | 6073.53 | 323.529 | 1 | Quart tournant avec marches égales | 3 | Contremarche 27 | 0.185153 | 1220 | 1220 | ArchiCADQuantities - Hauteur 3D de contremarche: 151.765 mm; Hauteur: 151.765 mm; ArchiCADProperties - Surfaces (Toutes): Peinture-11
C-MARCHE-335 | Etage1 | Parpaing 2676271321 | C-MARCHE-335 | Etage1 | 4 | Contremarche (Escalier) | ESC-020 | 0.413619 | 10 | 0.00192578 | 1267.31 | 6235.29 | 485.294 | 2112.94 | 6387.06 | 637.059 | 6235.29 | 485.294 | 1 | Quart tournant avec marches égales | 4 | Contremarche 27 | 0.192332 | 1267.31 | 1267.31 | ArchiCADQuantities - Hauteur 3D de contremarche: 151.765 mm; Hauteur: 151.765 mm; ArchiCADProperties - Surfaces (Toutes): Peinture-11
C-MARCHE-336 | Etage1 | Parpaing 2676271321 | C-MARCHE-336 | Etage1 | 4 | Contremarche (Escalier) | ESC-020 | 0.518578 | 10 | 0.00241656 | 1588.17 | 6397.06 | 647.059 | 1951.18 | 6548.82 | 798.824 | 6397.06 | 647.059 | 1 | Quart tournant avec marches égales | 5 | Contremarche 27 | 0.241028 | 1588.17 | 1588.17 | ArchiCADQuantities - Hauteur 3D de contremarche: 151.765 mm; Hauteur: 151.765 mm; ArchiCADProperties - Surfaces (Toutes): Peinture-11
C-MARCHE-337 | Etage1 | Parpaing 2676271321 | C-MARCHE-337 | Etage1 | 4 | Contremarche (Escalier) | ESC-020 | 0.465612 | 10 | 0.00216877 | 1431.56 | 6558.82 | 808.824 | 1789.41 | 6710.59 | 960.588 | 6558.82 | 808.824 | 1 | Quart tournant avec marches égales | 6 | Contremarche 27 | 0.217261 | 1431.56 | 1431.56 | ArchiCADQuantities - Hauteur 3D de contremarche: 151.765 mm; Hauteur: 151.765 mm; ArchiCADProperties - Surfaces (Toutes): Peinture-11
C-MARCHE-338 | Etage1 | Parpaing 2676271321 | C-MARCHE-338 | Etage1 | 4 | Contremarche (Escalier) | ESC-020 | 0.400095 | 10 | 0.0018625 | 1227.48 | 6720.59 | 970.588 | 1627.65 | 6872.35 | 1122.35 | 6720.59 | 970.588 | 1 | Quart tournant avec marches égales | 7 | Contremarche 27 | 0.186288 | 1227.48 | 1227.48 | ArchiCADQuantities - Hauteur 3D de contremarche: 151.765 mm; Hauteur: 151.765 mm; ArchiCADProperties - Surfaces (Toutes): Peinture-11
C-MARCHE-339 | Etage1 | Parpaing 2676271321 | C-MARCHE-339 | Etage1 | 4 | Contremarche (Escalier) | ESC-020 | 0.417789 | 10 | 0.00194527 | 1279.95 | 6882.35 | 1132.35 | 1465.88 | 7034.12 | 1284.12 | 6882.35 | 1132.35 | 1 | Quart tournant avec marches égales | 8 | Contremarche 27 | 0.194252 | 1279.95 | 1279.95 | ArchiCADQuantities - Hauteur 3D de contremarche: 151.765 mm; Hauteur: 151.765 mm; ArchiCADProperties - Surfaces (Toutes): Peinture-11
C-MARCHE-341 | Etage1 | Parpaing 2676271321 | C-MARCHE-341 | Etage1 | 4 | Contremarche (Escalier) | ESC-020 | 0.456082 | 10 | 0.00212423 | 1401.98 | 7205.88 | 1455.88 | 1142.35 | 7357.65 | 1607.65 | 7205.88 | 1455.88 | 1 | Quart tournant avec marches égales | 10 | Contremarche 27 | 0.212771 | 1401.98 | 1401.98 | ArchiCADQuantities - Hauteur 3D de contremarche: 151.765 mm; Hauteur: 151.765 mm; ArchiCADProperties - Surfaces (Toutes): Peinture-11
C-MARCHE-340 | Etage1 | Parpaing 2676271321 | C-MARCHE-340 | Etage1 | 4 | Contremarche (Escalier) | ESC-020 | 0.534643 | 10 | 0.00249166 | 1637.37 | 7044.12 | 1294.12 | 1304.12 | 7195.88 | 1445.88 | 7044.12 | 1294.12 | 1 | Quart tournant avec marches égales | 9 | Contremarche 27 | 0.248494 | 1637.37 | 1637.37 | ArchiCADQuantities - Hauteur 3D de contremarche: 151.765 mm; Hauteur: 151.765 mm; ArchiCADProperties - Surfaces (Toutes): Peinture-11
C-MARCHE-342 | Etage1 | Parpaing 2676271321 | C-MARCHE-342 | Etage1 | 4 | Contremarche (Escalier) | ESC-020 | 0.399292 | 10 | 0.00185876 | 1224.83 | 7367.65 | 1617.65 | 980.588 | 7519.41 | 1769.41 | 7367.65 | 1617.65 | 1 | Quart tournant avec marches égales | 11 | Contremarche 27 | 0.185886 | 1224.83 | 1224.83 | ArchiCADQuantities - Hauteur 3D de contremarche: 151.765 mm; Hauteur: 151.765 mm; ArchiCADProperties - Surfaces (Toutes): Peinture-11
C-MARCHE-344 | Etage1 | Parpaing 2676271321 | C-MARCHE-344 | Etage1 | 4 | Contremarche (Escalier) | ESC-020 | 0.398046 | 10 | 0.00185294 | 1220.56 | 7691.18 | 1941.18 | 657.059 | 7842.94 | 2092.94 | 7691.18 | 1941.18 | 1 | Quart tournant avec marches égales | 13 | Contremarche 27 | 0.185237 | 1220.56 | 1220.56 | ArchiCADQuantities - Hauteur 3D de contremarche: 151.765 mm; Hauteur: 151.765 mm; ArchiCADProperties - Surfaces (Toutes): Peinture-11
C-MARCHE-347 | Etage1 | Parpaing 2676271321 | C-MARCHE-347 | Etage1 | 4 | Contremarche (Escalier) | ESC-020 | 0.428757 | 10 | 0.00199649 | 1317.07 | 8176.47 | 2426.47 | 171.765 | 8328.24 | 2578.24 | 8176.47 | 2426.47 | 1 | Quart tournant avec marches égales | 16 | Contremarche 27 | 0.199885 | 1317.07 | 1317.07 | ArchiCADQuantities - Hauteur 3D de contremarche: 151.765 mm; Hauteur: 151.765 mm; ArchiCADProperties - Surfaces (Toutes): Peinture-11
C-MARCHE-345 | Etage1 | Parpaing 2676271321 | C-MARCHE-345 | Etage1 | 4 | Contremarche (Escalier) | ESC-020 | 0.440568 | 10 | 0.00205179 | 1349.46 | 7852.94 | 2102.94 | 495.294 | 8004.71 | 2254.71 | 7852.94 | 2102.94 | 1 | Quart tournant avec marches égales | 14 | Contremarche 27 | 0.2048 | 1349.46 | 1349.46 | ArchiCADQuantities - Hauteur 3D de contremarche: 151.765 mm; Hauteur: 151.765 mm; ArchiCADProperties - Surfaces (Toutes): Peinture-11
2 x MARCHE-332 | Etage1 | Lame d'air 275581351 | MARCHE-332 | Etage1 | 4 | Giron (Escalier) | ESC-020 | 0.885647 | 10 | 0.00427123 |  | 5911.76 | 161.765 | 2588.24 | 5911.76 | 161.765 | 5901.76 | 151.765 | 1 | Quart tournant avec marches égales | 1 | Marche 27 | 0.0122 | 1220 | 1220 | ArchiCADQuantities - Nez de marche: 15 mm; Giron de marche: 325.101 mm; Longueur volée marche: 350.101 mm; Superficie supérieure marche: 0.427123 m2
C-MARCHE-348 | Etage1 | Parpaing 2676271321 | C-MARCHE-348 | Etage1 | 4 | Contremarche (Escalier) | ESC-020 | 0.422341 | 10 | 0.00197353 | 1220 | 8338.24 | 2588.24 | 0 | 8500 | 2750 | 8338.24 | 2588.24 | 1 | Inconnu | 17 | Contremarche 27 | 0.197353 | 1220 | 1220 | ArchiCADQuantities - Hauteur 3D de contremarche: 161.765 mm; Hauteur: 161.765 mm; ArchiCADProperties - Surfaces (Toutes): Peinture-11
2 x MARCHE-338 | Etage1 | Lame d'air 275581351 | MARCHE-338 | Etage1 | 4 | Giron (Escalier) | ESC-020 | 0.90354 | 10 | 0.00435648 |  | 6882.35 | 1132.35 | 1617.65 | 6882.35 | 1132.35 | 6872.35 | 1122.35 | 1 | Quart tournant avec marches égales | 7 | Marche 27 | 0.012288 | 1283.83 | 1228.8 | ArchiCADQuantities - Nez de marche: 15 mm; Giron de marche: 325.101 mm; Longueur volée marche: 350.105 mm; Superficie supérieure marche: 0.435648 m2
2 x MARCHE-336 | Etage1 | Lame d'air 275581351 | MARCHE-336 | Etage1 | 4 | Giron (Escalier) | ESC-020 | 1.44552 | 10 | 0.0070232 |  | 6558.82 | 808.824 | 1941.18 | 6558.82 | 808.824 | 6548.82 | 798.824 | 1 | Quart tournant avec marches égales | 5 | Marche 27 | 0.0157633 | 1426.76 | 1576.33 | ArchiCADQuantities - Nez de marche: 15 mm; Giron de marche: 325.101 mm; Longueur volée marche: 350.105 mm; Superficie supérieure marche: 0.70232 m2
2 x MARCHE-335 | Etage1 | Lame d'air 275581351 | MARCHE-335 | Etage1 | 4 | Giron (Escalier) | ESC-020 | 1.11576 | 10 | 0.00539325 |  | 6397.06 | 647.059 | 2102.94 | 6397.06 | 647.059 | 6387.06 | 637.059 | 1 | Quart tournant avec marches égales | 4 | Marche 27 | 0.0126302 | 1596.69 | 1263.02 | ArchiCADQuantities - Nez de marche: 15 mm; Giron de marche: 325.101 mm; Longueur volée marche: 350.105 mm; Superficie supérieure marche: 0.539325 m2
C-MARCHE-346 | Etage1 | Parpaing 2676271321 | C-MARCHE-346 | Etage1 | 4 | Contremarche (Escalier) | ESC-020 | 0.572948 | 10 | 0.00267059 | 1764.16 | 8014.71 | 2264.71 | 333.529 | 8166.47 | 2416.47 | 8014.71 | 2264.71 | 1 | Quart tournant avec marches égales | 15 | Contremarche 27 | 0.267738 | 1764.16 | 1764.16 | ArchiCADQuantities - Hauteur 3D de contremarche: 151.765 mm; Hauteur: 151.765 mm; ArchiCADProperties - Surfaces (Toutes): Peinture-11
2 x MARCHE-334 | Etage1 | Lame d'air 275581351 | MARCHE-334 | Etage1 | 4 | Giron (Escalier) | ESC-020 | 0.898539 | 10 | 0.00433276 |  | 6235.29 | 485.294 | 2264.71 | 6235.29 | 485.294 | 6225.29 | 475.294 | 1 | Quart tournant avec marches égales | 3 | Marche 27 | 0.0122 | 1270.79 | 1220 | ArchiCADQuantities - Nez de marche: 15 mm; Giron de marche: 325.101 mm; Longueur volée marche: 350.105 mm; Superficie supérieure marche: 0.433276 m2
2 x MARCHE-333 | Etage1 | Lame d'air 275581351 | MARCHE-333 | Etage1 | 4 | Giron (Escalier) | ESC-020 | 0.885647 | 10 | 0.00427123 |  | 6073.53 | 323.529 | 2426.47 | 6073.53 | 323.529 | 6063.53 | 313.529 | 1 | Quart tournant avec marches égales | 2 | Marche 27 | 0.0122 | 1220 | 1220 | ArchiCADQuantities - Nez de marche: 15 mm; Giron de marche: 325.101 mm; Longueur volée marche: 350.101 mm; Superficie supérieure marche: 0.427123 m2
2 x MARCHE-342 | Etage1 | Lame d'air 275581351 | MARCHE-342 | Etage1 | 4 | Giron (Escalier) | ESC-020 | 0.886181 | 10 | 0.0042736 |  | 7529.41 | 1779.41 | 970.588 | 7529.41 | 1779.41 | 7519.41 | 1769.41 | 1 | Quart tournant avec marches égales | 11 | Marche 27 | 0.012256 | 1220 | 1225.6 | ArchiCADQuantities - Nez de marche: 15 mm; Giron de marche: 325.101 mm; Longueur volée marche: 350.101 mm; Superficie supérieure marche: 0.42736 m2
2 x MARCHE-341 | Etage1 | Lame d'air 275581351 | MARCHE-341 | Etage1 | 4 | Giron (Escalier) | ESC-020 | 0.975694 | 10 | 0.00470869 |  | 7367.65 | 1617.65 | 1132.35 | 7367.65 | 1617.65 | 7357.65 | 1607.65 | 1 | Quart tournant avec marches égales | 10 | Marche 27 | 0.0140942 | 1224.81 | 1409.42 | ArchiCADQuantities - Nez de marche: 15 mm; Giron de marche: 325.101 mm; Longueur volée marche: 350.105 mm; Superficie supérieure marche: 0.470869 m2
2 x MARCHE-340 | Etage1 | Lame d'air 275581351 | MARCHE-340 | Etage1 | 4 | Giron (Escalier) | ESC-020 | 1.42363 | 10 | 0.00691358 |  | 7205.88 | 1455.88 | 1294.12 | 7205.88 | 1455.88 | 7195.88 | 1445.88 | 1 | Quart tournant avec marches égales | 9 | Marche 27 | 0.0162465 | 1397.65 | 1624.65 | ArchiCADQuantities - Nez de marche: 15 mm; Giron de marche: 325.101 mm; Longueur volée marche: 350.105 mm; Superficie supérieure marche: 0.691358 m2
2 x MARCHE-339 | Etage1 | Lame d'air 275581351 | MARCHE-339 | Etage1 | 4 | Giron (Escalier) | ESC-020 | 1.15533 | 10 | 0.0055866 |  | 7044.12 | 1294.12 | 1455.88 | 7044.12 | 1294.12 | 7034.12 | 1284.12 | 1 | Quart tournant avec marches égales | 8 | Marche 27 | 0.0127509 | 1646.47 | 1275.09 | ArchiCADQuantities - Nez de marche: 15 mm; Giron de marche: 325.101 mm; Longueur volée marche: 350.105 mm; Superficie supérieure marche: 0.55866 m2
2 x MARCHE-337 | Etage1 | Lame d'air 275581351 | MARCHE-337 | Etage1 | 4 | Giron (Escalier) | ESC-020 | 0.99521 | 10 | 0.0048039 |  | 6720.59 | 970.588 | 1779.41 | 6720.59 | 970.588 | 6710.59 | 960.588 | 1 | Quart tournant avec marches égales | 6 | Marche 27 | 0.0143972 | 1227.23 | 1439.72 | ArchiCADQuantities - Nez de marche: 15 mm; Giron de marche: 325.101 mm; Longueur volée marche: 350.105 mm; Superficie supérieure marche: 0.48039 m2
2 x MARCHE-345 | Etage1 | Lame d'air 275581351 | MARCHE-345 | Etage1 | 4 | Giron (Escalier) | ESC-020 | 1.34291 | 10 | 0.00650934 |  | 8014.71 | 2264.71 | 485.294 | 8014.71 | 2264.71 | 8004.71 | 2254.71 | 1 | Quart tournant avec marches égales | 14 | Marche 27 | 0.0134253 | 1755.47 | 1342.53 | ArchiCADQuantities - Nez de marche: 15 mm; Giron de marche: 325.101 mm; Longueur volée marche: 350.105 mm; Superficie supérieure marche: 0.650934 m2
2 x MARCHE-347 | Etage1 | Lame d'air 275581351 | MARCHE-347 | Etage1 | 4 | Giron (Escalier) | ESC-020 | 0.922626 | 10 | 0.00444976 |  | 8338.24 | 2588.24 | 161.765 | 8338.24 | 2588.24 | 8328.24 | 2578.24 | 1 | Quart tournant avec marches égales | 16 | Marche 27 | 0.013223 | 1220 | 1322.3 | ArchiCADQuantities - Nez de marche: 15 mm; Giron de marche: 325.101 mm; Longueur volée marche: 325.101 mm; Superficie supérieure marche: 0.444976 m2
2 x MARCHE-346 | Etage1 | Lame d'air 275581351 | MARCHE-346 | Etage1 | 4 | Giron (Escalier) | ESC-020 | 1.26693 | 10 | 0.00613203 |  | 8176.47 | 2426.47 | 323.529 | 8176.47 | 2426.47 | 8166.47 | 2416.47 | 1 | Quart tournant avec marches égales | 15 | Marche 27 | 0.0177815 | 1314.21 | 1778.15 | ArchiCADQuantities - Nez de marche: 15 mm; Giron de marche: 325.101 mm; Longueur volée marche: 350.105 mm; Superficie supérieure marche: 0.613203 m2
2 x MARCHE-344 | Etage1 | Lame d'air 275581351 | MARCHE-344 | Etage1 | 4 | Giron (Escalier) | ESC-020 | 0.940287 | 10 | 0.00453595 |  | 7852.94 | 2102.94 | 647.059 | 7852.94 | 2102.94 | 7842.94 | 2092.94 | 1 | Quart tournant avec marches égales | 13 | Marche 27 | 0.0122 | 1354.71 | 1220 | ArchiCADQuantities - Nez de marche: 15 mm; Giron de marche: 325.101 mm; Longueur volée marche: 350.105 mm; Superficie supérieure marche: 0.453595 m2
2 x MARCHE-343 | Etage1 | Lame d'air 275581351 | MARCHE-343 | Etage1 | 4 | Giron (Escalier) | ESC-020 | 0.885702 | 10 | 0.00427142 |  | 7691.18 | 1941.18 | 808.824 | 7691.18 | 1941.18 | 7681.18 | 1931.18 | 1 | Quart tournant avec marches égales | 12 | Marche 27 | 0.0122 | 1221.56 | 1220 | ArchiCADQuantities - Nez de marche: 15 mm; Giron de marche: 325.101 mm; Longueur volée marche: 350.104 mm; Superficie supérieure marche: 0.427142 m2
C-MARCHE-343 | Etage1 | Parpaing 2676271321 | C-MARCHE-343 | Etage1 | 4 | Contremarche (Escalier) | ESC-020 | 0.397741 | 10 | 0.00185153 | 1220 | 7529.41 | 1779.41 | 818.824 | 7681.18 | 1931.18 | 7529.41 | 1779.41 | 1 | Quart tournant avec marches égales | 12 | Contremarche 27 | 0.185153 | 1220 | 1220 | ArchiCADQuantities - Hauteur 3D de contremarche: 151.765 mm; Hauteur: 151.765 mm; ArchiCADProperties - Surfaces (Toutes): Peinture-11
C-MARCHE-332 | Etage1 | Lame d'air 275581351 | C-MARCHE-332 | Etage1 | 4 | Contremarche (Escalier) | ESC-020 | 0.397741 | 10 | 0.00185153 | 1220 | 5750 | 0 | 2598.24 | 5901.76 | 151.765 | 5750 | 0 | 1 | Quart tournant avec marches égales | 1 | Contremarche 27 | 0.185153 | 1220 | 1220 | ArchiCADQuantities - Hauteur 3D de contremarche: 151.765 mm; Hauteur: 151.765 mm
C-MARCHE-335 | Etage1 | Lame d'air 275581351 | C-MARCHE-335 | Etage1 | 4 | Contremarche (Escalier) | ESC-020 | 0.413619 | 10 | 0.00192578 | 1267.31 | 6235.29 | 485.294 | 2112.94 | 6387.06 | 637.059 | 6235.29 | 485.294 | 1 | Quart tournant avec marches égales | 4 | Contremarche 27 | 0.192332 | 1267.31 | 1267.31 | ArchiCADQuantities - Hauteur 3D de contremarche: 151.765 mm; Hauteur: 151.765 mm
C-MARCHE-336 | Etage1 | Lame d'air 275581351 | C-MARCHE-336 | Etage1 | 4 | Contremarche (Escalier) | ESC-020 | 0.518578 | 10 | 0.00241656 | 1588.17 | 6397.06 | 647.059 | 1951.18 | 6548.82 | 798.824 | 6397.06 | 647.059 | 1 | Quart tournant avec marches égales | 5 | Contremarche 27 | 0.241028 | 1588.17 | 1588.17 | ArchiCADQuantities - Hauteur 3D de contremarche: 151.765 mm; Hauteur: 151.765 mm
C-MARCHE-334 | Etage1 | Lame d'air 275581351 | C-MARCHE-334 | Etage1 | 4 | Contremarche (Escalier) | ESC-020 | 0.397741 | 10 | 0.00185153 | 1220 | 6073.53 | 323.529 | 2274.71 | 6225.29 | 475.294 | 6073.53 | 323.529 | 1 | Quart tournant avec marches égales | 3 | Contremarche 27 | 0.185153 | 1220 | 1220 | ArchiCADQuantities - Hauteur 3D de contremarche: 151.765 mm; Hauteur: 151.765 mm
C-MARCHE-337 | Etage1 | Lame d'air 275581351 | C-MARCHE-337 | Etage1 | 4 | Contremarche (Escalier) | ESC-020 | 0.465612 | 10 | 0.00216877 | 1431.56 | 6558.82 | 808.824 | 1789.41 | 6710.59 | 960.588 | 6558.82 | 808.824 | 1 | Quart tournant avec marches égales | 6 | Contremarche 27 | 0.217261 | 1431.56 | 1431.56 | ArchiCADQuantities - Hauteur 3D de contremarche: 151.765 mm; Hauteur: 151.765 mm
C-MARCHE-333 | Etage1 | Lame d'air 275581351 | C-MARCHE-333 | Etage1 | 4 | Contremarche (Escalier) | ESC-020 | 0.397741 | 10 | 0.00185153 | 1220 | 5911.76 | 161.765 | 2436.47 | 6063.53 | 313.529 | 5911.76 | 161.765 | 1 | Quart tournant avec marches égales | 2 | Contremarche 27 | 0.185153 | 1220 | 1220 | ArchiCADQuantities - Hauteur 3D de contremarche: 151.765 mm; Hauteur: 151.765 mm
C-MARCHE-341 | Etage1 | Lame d'air 275581351 | C-MARCHE-341 | Etage1 | 4 | Contremarche (Escalier) | ESC-020 | 0.456082 | 10 | 0.00212423 | 1401.98 | 7205.88 | 1455.88 | 1142.35 | 7357.65 | 1607.65 | 7205.88 | 1455.88 | 1 | Quart tournant avec marches égales | 10 | Contremarche 27 | 0.212771 | 1401.98 | 1401.98 | ArchiCADQuantities - Hauteur 3D de contremarche: 151.765 mm; Hauteur: 151.765 mm
C-MARCHE-340 | Etage1 | Lame d'air 275581351 | C-MARCHE-340 | Etage1 | 4 | Contremarche (Escalier) | ESC-020 | 0.534643 | 10 | 0.00249166 | 1637.37 | 7044.12 | 1294.12 | 1304.12 | 7195.88 | 1445.88 | 7044.12 | 1294.12 | 1 | Quart tournant avec marches égales | 9 | Contremarche 27 | 0.248494 | 1637.37 | 1637.37 | ArchiCADQuantities - Hauteur 3D de contremarche: 151.765 mm; Hauteur: 151.765 mm
C-MARCHE-339 | Etage1 | Lame d'air 275581351 | C-MARCHE-339 | Etage1 | 4 | Contremarche (Escalier) | ESC-020 | 0.417789 | 10 | 0.00194527 | 1279.95 | 6882.35 | 1132.35 | 1465.88 | 7034.12 | 1284.12 | 6882.35 | 1132.35 | 1 | Quart tournant avec marches égales | 8 | Contremarche 27 | 0.194252 | 1279.95 | 1279.95 | ArchiCADQuantities - Hauteur 3D de contremarche: 151.765 mm; Hauteur: 151.765 mm
C-MARCHE-342 | Etage1 | Lame d'air 275581351 | C-MARCHE-342 | Etage1 | 4 | Contremarche (Escalier) | ESC-020 | 0.399292 | 10 | 0.00185876 | 1224.83 | 7367.65 | 1617.65 | 980.588 | 7519.41 | 1769.41 | 7367.65 | 1617.65 | 1 | Quart tournant avec marches égales | 11 | Contremarche 27 | 0.185886 | 1224.83 | 1224.83 | ArchiCADQuantities - Hauteur 3D de contremarche: 151.765 mm; Hauteur: 151.765 mm
C-MARCHE-338 | Etage1 | Lame d'air 275581351 | C-MARCHE-338 | Etage1 | 4 | Contremarche (Escalier) | ESC-020 | 0.400095 | 10 | 0.0018625 | 1227.48 | 6720.59 | 970.588 | 1627.65 | 6872.35 | 1122.35 | 6720.59 | 970.588 | 1 | Quart tournant avec marches égales | 7 | Contremarche 27 | 0.186288 | 1227.48 | 1227.48 | ArchiCADQuantities - Hauteur 3D de contremarche: 151.765 mm; Hauteur: 151.765 mm
C-MARCHE-343 | Etage1 | Lame d'air 275581351 | C-MARCHE-343 | Etage1 | 4 | Contremarche (Escalier) | ESC-020 | 0.397741 | 10 | 0.00185153 | 1220 | 7529.41 | 1779.41 | 818.824 | 7681.18 | 1931.18 | 7529.41 | 1779.41 | 1 | Quart tournant avec marches égales | 12 | Contremarche 27 | 0.185153 | 1220 | 1220 | ArchiCADQuantities - Hauteur 3D de contremarche: 151.765 mm; Hauteur: 151.765 mm
C-MARCHE-344 | Etage1 | Lame d'air 275581351 | C-MARCHE-344 | Etage1 | 4 | Contremarche (Escalier) | ESC-020 | 0.398046 | 10 | 0.00185294 | 1220.56 | 7691.18 | 1941.18 | 657.059 | 7842.94 | 2092.94 | 7691.18 | 1941.18 | 1 | Quart tournant avec marches égales | 13 | Contremarche 27 | 0.185237 | 1220.56 | 1220.56 | ArchiCADQuantities - Hauteur 3D de contremarche: 151.765 mm; Hauteur: 151.765 mm
C-MARCHE-345 | Etage1 | Lame d'air 275581351 | C-MARCHE-345 | Etage1 | 4 | Contremarche (Escalier) | ESC-020 | 0.440568 | 10 | 0.00205179 | 1349.46 | 7852.94 | 2102.94 | 495.294 | 8004.71 | 2254.71 | 7852.94 | 2102.94 | 1 | Quart tournant avec marches égales | 14 | Contremarche 27 | 0.2048 | 1349.46 | 1349.46 | ArchiCADQuantities - Hauteur 3D de contremarche: 151.765 mm; Hauteur: 151.765 mm
C-MARCHE-346 | Etage1 | Lame d'air 275581351 | C-MARCHE-346 | Etage1 | 4 | Contremarche (Escalier) | ESC-020 | 0.572948 | 10 | 0.00267059 | 1764.16 | 8014.71 | 2264.71 | 333.529 | 8166.47 | 2416.47 | 8014.71 | 2264.71 | 1 | Quart tournant avec marches égales | 15 | Contremarche 27 | 0.267738 | 1764.16 | 1764.16 | ArchiCADQuantities - Hauteur 3D de contremarche: 151.765 mm; Hauteur: 151.765 mm
C-MARCHE-348 | Etage1 | Lame d'air 275581351 | C-MARCHE-348 | Etage1 | 4 | Contremarche (Escalier) | ESC-020 | 0.422341 | 10 | 0.00197353 | 1220 | 8338.24 | 2588.24 | 0 | 8500 | 2750 | 8338.24 | 2588.24 | 1 | Inconnu | 17 | Contremarche 27 | 0.197353 | 1220 | 1220 | ArchiCADQuantities - Hauteur 3D de contremarche: 161.765 mm; Hauteur: 161.765 mm
C-MARCHE-347 | Etage1 | Lame d'air 275581351 | C-MARCHE-347 | Etage1 | 4 | Contremarche (Escalier) | ESC-020 | 0.428757 | 10 | 0.00199649 | 1317.07 | 8176.47 | 2426.47 | 171.765 | 8328.24 | 2578.24 | 8176.47 | 2426.47 | 1 | Quart tournant avec marches égales | 16 | Contremarche 27 | 0.199885 | 1317.07 | 1317.07 | ArchiCADQuantities - Hauteur 3D de contremarche: 151.765 mm; Hauteur: 151.765 mm
2 x VOLEE-022 | Etage 2 | Cloison 274992075 | VOLEE-022 | Etage 2 | 5 | Structure (Escalier) | ESC-020 | 23.8304 | 150 | 2.08754 | 1220 | 11370.6 | 2870.56 | 179.444 | 11370.6 | 2870.56 | 8370 | -130 | ArchiCADProperties - Type construction: Monolithique; Type forme: Plat; Position structure escalier: Sous l'escalier; Index volée structure escalier: 1; Matériau de construction / Composite / Profil / Hachure: Cloison 274992075; Matériaux de construction (Tous): Cloison 274992075; ArchiCADQuantities - Épaisseur secondaire: 150 mm; Hauteur 3D de structure d'escalier: 3000.56 mm; Longueur 3D: 6016.72 mm
C-MARCHE-332 | Etage 2 | Parpaing 2676271321 | C-MARCHE-332 | Etage 2 | 5 | Contremarche (Escalier) | ESC-020 | 0.416633 | 10 | 0.00194522 | 1220 | 8500 | 0 | 2890.56 | 8659.44 | 159.444 | 8500 | 0 | 1 | Quart tournant avec marches égales | 1 | Contremarche 27 | 0.194522 | 1220 | 1220 | ArchiCADQuantities - Hauteur 3D de contremarche: 159.444 mm; Hauteur: 159.444 mm; ArchiCADProperties - Surfaces (Toutes): Peinture-11
C-MARCHE-333 | Etage 2 | Parpaing 2676271321 | C-MARCHE-333 | Etage 2 | 5 | Contremarche (Escalier) | ESC-020 | 0.416633 | 10 | 0.00194522 | 1220 | 8669.44 | 169.444 | 2721.11 | 8828.89 | 328.889 | 8669.44 | 169.444 | 1 | Quart tournant avec marches égales | 2 | Contremarche 27 | 0.194522 | 1220 | 1220 | ArchiCADQuantities - Hauteur 3D de contremarche: 159.444 mm; Hauteur: 159.444 mm; ArchiCADProperties - Surfaces (Toutes): Peinture-11
C-MARCHE-334 | Etage 2 | Parpaing 2676271321 | C-MARCHE-334 | Etage 2 | 5 | Contremarche (Escalier) | ESC-020 | 0.416633 | 10 | 0.00194522 | 1220 | 8838.89 | 338.889 | 2551.67 | 8998.33 | 498.333 | 8838.89 | 338.889 | 1 | Quart tournant avec marches égales | 3 | Contremarche 27 | 0.194522 | 1220 | 1220 | ArchiCADQuantities - Hauteur 3D de contremarche: 159.444 mm; Hauteur: 159.444 mm; ArchiCADProperties - Surfaces (Toutes): Peinture-11
C-MARCHE-335 | Etage 2 | Parpaing 2676271321 | C-MARCHE-335 | Etage 2 | 5 | Contremarche (Escalier) | ESC-020 | 0.427095 | 10 | 0.00199428 | 1249.43 | 9008.33 | 508.333 | 2382.22 | 9167.78 | 667.778 | 9008.33 | 508.333 | 1 | Quart tournant avec marches égales | 4 | Contremarche 27 | 0.199215 | 1249.43 | 1249.43 | ArchiCADQuantities - Hauteur 3D de contremarche: 159.444 mm; Hauteur: 159.444 mm; ArchiCADProperties - Surfaces (Toutes): Peinture-11
C-MARCHE-338 | Etage 2 | Parpaing 2676271321 | C-MARCHE-338 | Etage 2 | 5 | Contremarche (Escalier) | ESC-020 | 0.427779 | 10 | 0.00199743 | 1253.55 | 9516.67 | 1016.67 | 1873.89 | 9676.11 | 1176.11 | 9516.67 | 1016.67 | 1 | Quart tournant avec marches égales | 7 | Contremarche 27 | 0.199871 | 1253.55 | 1253.55 | ArchiCADQuantities - Hauteur 3D de contremarche: 159.444 mm; Hauteur: 159.444 mm; ArchiCADProperties - Surfaces (Toutes): Peinture-11
C-MARCHE-336 | Etage 2 | Parpaing 2676271321 | C-MARCHE-336 | Etage 2 | 5 | Contremarche (Escalier) | ESC-020 | 0.513301 | 10 | 0.00239859 | 1500.73 | 9177.78 | 677.778 | 2212.78 | 9337.22 | 837.222 | 9177.78 | 677.778 | 1 | Quart tournant avec marches égales | 5 | Contremarche 27 | 0.239284 | 1500.73 | 1500.73 | ArchiCADQuantities - Hauteur 3D de contremarche: 159.444 mm; Hauteur: 159.444 mm; ArchiCADProperties - Surfaces (Toutes): Peinture-11
C-MARCHE-339 | Etage 2 | Parpaing 2676271321 | C-MARCHE-339 | Etage 2 | 5 | Contremarche (Escalier) | ESC-020 | 0.423162 | 10 | 0.00197583 | 1238.04 | 9686.11 | 1186.11 | 1704.44 | 9845.56 | 1345.56 | 9686.11 | 1186.11 | 1 | Quart tournant avec marches égales | 8 | Contremarche 27 | 0.197398 | 1238.04 | 1238.04 | ArchiCADQuantities - Hauteur 3D de contremarche: 159.444 mm; Hauteur: 159.444 mm; ArchiCADProperties - Surfaces (Toutes): Peinture-11
C-MARCHE-340 | Etage 2 | Parpaing 2676271321 | C-MARCHE-340 | Etage 2 | 5 | Contremarche (Escalier) | ESC-020 | 0.499875 | 10 | 0.00233561 | 1461.48 | 9855.56 | 1355.56 | 1535 | 10015 | 1515 | 9855.56 | 1355.56 | 1 | Quart tournant avec marches égales | 9 | Contremarche 27 | 0.233024 | 1461.48 | 1461.48 | ArchiCADQuantities - Hauteur 3D de contremarche: 159.444 mm; Hauteur: 159.444 mm; ArchiCADProperties - Surfaces (Toutes): Peinture-11
C-MARCHE-337 | Etage 2 | Parpaing 2676271321 | C-MARCHE-337 | Etage 2 | 5 | Contremarche (Escalier) | ESC-020 | 0.519602 | 10 | 0.00242797 | 1525.93 | 9347.22 | 847.222 | 2043.33 | 9506.67 | 1006.67 | 9347.22 | 847.222 | 1 | Quart tournant avec marches égales | 6 | Contremarche 27 | 0.243301 | 1525.93 | 1525.93 | ArchiCADQuantities - Hauteur 3D de contremarche: 159.444 mm; Hauteur: 159.444 mm; ArchiCADProperties - Surfaces (Toutes): Peinture-11
C-MARCHE-342 | Etage 2 | Parpaing 2676271321 | C-MARCHE-342 | Etage 2 | 5 | Contremarche (Escalier) | ESC-020 | 0.432726 | 10 | 0.00202064 | 1268.29 | 10194.4 | 1694.44 | 1196.11 | 10353.9 | 1853.89 | 10194.4 | 1694.44 | 1 | Quart tournant avec marches égales | 11 | Contremarche 27 | 0.202221 | 1268.29 | 1268.29 | ArchiCADQuantities - Hauteur 3D de contremarche: 159.444 mm; Hauteur: 159.444 mm; ArchiCADProperties - Surfaces (Toutes): Peinture-11
C-MARCHE-341 | Etage 2 | Parpaing 2676271321 | C-MARCHE-341 | Etage 2 | 5 | Contremarche (Escalier) | ESC-020 | 0.535374 | 10 | 0.00250195 | 1572.59 | 10025 | 1525 | 1365.56 | 10184.4 | 1684.44 | 10025 | 1525 | 1 | Quart tournant avec marches égales | 10 | Contremarche 27 | 0.250741 | 1572.59 | 1572.59 | ArchiCADQuantities - Hauteur 3D de contremarche: 159.444 mm; Hauteur: 159.444 mm; ArchiCADProperties - Surfaces (Toutes): Peinture-11
C-MARCHE-343 | Etage 2 | Parpaing 2676271321 | C-MARCHE-343 | Etage 2 | 5 | Contremarche (Escalier) | ESC-020 | 0.416633 | 10 | 0.00194522 | 1220 | 10363.9 | 1863.89 | 1026.67 | 10523.3 | 2023.33 | 10363.9 | 1863.89 | 1 | Quart tournant avec marches égales | 12 | Contremarche 27 | 0.194522 | 1220 | 1220 | ArchiCADQuantities - Hauteur 3D de contremarche: 159.444 mm; Hauteur: 159.444 mm; ArchiCADProperties - Surfaces (Toutes): Peinture-11
C-MARCHE-344 | Etage 2 | Parpaing 2676271321 | C-MARCHE-344 | Etage 2 | 5 | Contremarche (Escalier) | ESC-020 | 0.416633 | 10 | 0.00194522 | 1220 | 10533.3 | 2033.33 | 857.222 | 10692.8 | 2192.78 | 10533.3 | 2033.33 | 1 | Quart tournant avec marches égales | 13 | Contremarche 27 | 0.194522 | 1220 | 1220 | ArchiCADQuantities - Hauteur 3D de contremarche: 159.444 mm; Hauteur: 159.444 mm; ArchiCADProperties - Surfaces (Toutes): Peinture-11
C-MARCHE-345 | Etage 2 | Parpaing 2676271321 | C-MARCHE-345 | Etage 2 | 5 | Contremarche (Escalier) | ESC-020 | 0.425234 | 10 | 0.00198555 | 1244.06 | 10702.8 | 2202.78 | 687.778 | 10862.2 | 2362.22 | 10702.8 | 2202.78 | 1 | Quart tournant avec marches égales | 14 | Contremarche 27 | 0.198358 | 1244.06 | 1244.06 | ArchiCADQuantities - Hauteur 3D de contremarche: 159.444 mm; Hauteur: 159.444 mm; ArchiCADProperties - Surfaces (Toutes): Peinture-11
C-MARCHE-346 | Etage 2 | Parpaing 2676271321 | C-MARCHE-346 | Etage 2 | 5 | Contremarche (Escalier) | ESC-020 | 0.506145 | 10 | 0.00236503 | 1479.82 | 10872.2 | 2372.22 | 518.333 | 11031.7 | 2531.67 | 10872.2 | 2372.22 | 1 | Quart tournant avec marches égales | 15 | Contremarche 27 | 0.235949 | 1479.82 | 1479.82 | ArchiCADQuantities - Hauteur 3D de contremarche: 159.444 mm; Hauteur: 159.444 mm; ArchiCADProperties - Surfaces (Toutes): Peinture-11
C-MARCHE-348 | Etage 2 | Parpaing 2676271321 | C-MARCHE-348 | Etage 2 | 5 | Contremarche (Escalier) | ESC-020 | 0.430867 | 10 | 0.00201192 | 1262.74 | 11211.1 | 2711.11 | 179.444 | 11370.6 | 2870.56 | 11211.1 | 2711.11 | 1 | Quart tournant avec marches égales | 17 | Contremarche 27 | 0.201337 | 1262.74 | 1262.74 | ArchiCADQuantities - Hauteur 3D de contremarche: 159.444 mm; Hauteur: 159.444 mm; ArchiCADProperties - Surfaces (Toutes): Peinture-11
C-MARCHE-349 | Etage 2 | Parpaing 2676271321 | C-MARCHE-349 | Etage 2 | 5 | Contremarche (Escalier) | ESC-020 | 0.441233 | 10 | 0.00206722 | 1220 | 11380.6 | 2880.56 | 0 | 11550 | 3050 | 11380.6 | 2880.56 | 1 | Inconnu | 18 | Contremarche 27 | 0.206722 | 1220 | 1220 | ArchiCADQuantities - Hauteur 3D de contremarche: 169.444 mm; Hauteur: 169.444 mm; ArchiCADProperties - Surfaces (Toutes): Peinture-11
2 x MARCHE-332 | Etage 2 | Lame d'air 275581351 | MARCHE-332 | Etage 2 | 5 | Giron (Escalier) | ESC-020 | 0.850289 | 10 | 0.00409587 |  | 8669.44 | 169.444 | 2880.56 | 8669.44 | 169.444 | 8659.44 | 159.444 | 1 | Quart tournant avec marches égales | 1 | Marche 27 | 0.0122 | 1220 | 1220 | ArchiCADQuantities - Nez de marche: 15 mm; Giron de marche: 310.727 mm; Longueur volée marche: 335.727 mm; Superficie supérieure marche: 0.409587 m2
2 x MARCHE-338 | Etage 2 | Lame d'air 275581351 | MARCHE-338 | Etage 2 | 5 | Giron (Escalier) | ESC-020 | 0.860493 | 10 | 0.00414368 |  | 9686.11 | 1186.11 | 1863.89 | 9686.11 | 1186.11 | 9676.11 | 1176.11 | 1 | Quart tournant avec marches égales | 7 | Marche 27 | 0.0125652 | 1240.61 | 1256.52 | ArchiCADQuantities - Nez de marche: 15 mm; Giron de marche: 310.727 mm; Longueur volée marche: 335.731 mm; Superficie supérieure marche: 0.414368 m2
2 x MARCHE-339 | Etage 2 | Lame d'air 275581351 | MARCHE-339 | Etage 2 | 5 | Giron (Escalier) | ESC-020 | 0.979664 | 10 | 0.00472531 |  | 9855.56 | 1355.56 | 1694.44 | 9855.56 | 1355.56 | 9845.56 | 1345.56 | 1 | Quart tournant avec marches égales | 8 | Marche 27 | 0.0123513 | 1468.46 | 1235.13 | ArchiCADQuantities - Nez de marche: 15 mm; Giron de marche: 310.727 mm; Longueur volée marche: 335.731 mm; Superficie supérieure marche: 0.472531 m2
2 x MARCHE-340 | Etage 2 | Lame d'air 275581351 | MARCHE-340 | Etage 2 | 5 | Giron (Escalier) | ESC-020 | 1.40265 | 10 | 0.00680994 |  | 10025 | 1525 | 1525 | 10025 | 1525 | 10015 | 1515 | 1 | Quart tournant avec marches égales | 9 | Marche 27 | 0.0145195 | 1566 | 1451.95 | ArchiCADQuantities - Nez de marche: 15 mm; Giron de marche: 310.727 mm; Longueur volée marche: 335.731 mm; Superficie supérieure marche: 0.680994 m2
2 x MARCHE-337 | Etage 2 | Lame d'air 275581351 | MARCHE-337 | Etage 2 | 5 | Giron (Escalier) | ESC-020 | 1.02964 | 10 | 0.00496903 |  | 9516.67 | 1016.67 | 2033.33 | 9516.67 | 1016.67 | 9506.67 | 1006.67 | 1 | Quart tournant avec marches égales | 6 | Marche 27 | 0.0153597 | 1252.2 | 1535.97 | ArchiCADQuantities - Nez de marche: 15 mm; Giron de marche: 310.727 mm; Longueur volée marche: 335.731 mm; Superficie supérieure marche: 0.496903 m2
2 x MARCHE-336 | Etage 2 | Lame d'air 275581351 | MARCHE-336 | Etage 2 | 5 | Giron (Escalier) | ESC-020 | 1.41147 | 10 | 0.00685407 |  | 9347.22 | 847.222 | 2202.78 | 9347.22 | 847.222 | 9337.22 | 837.222 | 1 | Quart tournant avec marches égales | 5 | Marche 27 | 0.0149048 | 1519.87 | 1490.48 | ArchiCADQuantities - Nez de marche: 15 mm; Giron de marche: 310.727 mm; Longueur volée marche: 335.731 mm; Superficie supérieure marche: 0.685407 m2
2 x MARCHE-335 | Etage 2 | Lame d'air 275581351 | MARCHE-335 | Etage 2 | 5 | Giron (Escalier) | ESC-020 | 1.00989 | 10 | 0.00487295 |  | 9177.78 | 677.778 | 2372.22 | 9177.78 | 677.778 | 9167.78 | 667.778 | 1 | Quart tournant avec marches égales | 4 | Marche 27 | 0.0124599 | 1508.2 | 1245.99 | ArchiCADQuantities - Nez de marche: 15 mm; Giron de marche: 310.727 mm; Longueur volée marche: 335.731 mm; Superficie supérieure marche: 0.487295 m2
2 x MARCHE-334 | Etage 2 | Lame d'air 275581351 | MARCHE-334 | Etage 2 | 5 | Giron (Escalier) | ESC-020 | 0.856816 | 10 | 0.0041267 |  | 9008.33 | 508.333 | 2541.67 | 9008.33 | 508.333 | 8998.33 | 498.333 | 1 | Quart tournant avec marches égales | 3 | Marche 27 | 0.0122 | 1252.36 | 1220 | ArchiCADQuantities - Nez de marche: 15 mm; Giron de marche: 310.727 mm; Longueur volée marche: 335.731 mm; Superficie supérieure marche: 0.41267 m2
2 x MARCHE-333 | Etage 2 | Lame d'air 275581351 | MARCHE-333 | Etage 2 | 5 | Giron (Escalier) | ESC-020 | 0.850289 | 10 | 0.00409587 |  | 8838.89 | 338.889 | 2711.11 | 8838.89 | 338.889 | 8828.89 | 328.889 | 1 | Quart tournant avec marches égales | 2 | Marche 27 | 0.0122 | 1220 | 1220 | ArchiCADQuantities - Nez de marche: 15 mm; Giron de marche: 310.727 mm; Longueur volée marche: 335.727 mm; Superficie supérieure marche: 0.409587 m2
2 x MARCHE-342 | Etage 2 | Lame d'air 275581351 | MARCHE-342 | Etage 2 | 5 | Giron (Escalier) | ESC-020 | 0.86406 | 10 | 0.00416169 |  | 10363.9 | 1863.89 | 1186.11 | 10363.9 | 1863.89 | 10353.9 | 1853.89 | 1 | Quart tournant avec marches égales | 11 | Marche 27 | 0.0127181 | 1220 | 1271.81 | ArchiCADQuantities - Nez de marche: 15 mm; Giron de marche: 310.727 mm; Longueur volée marche: 335.727 mm; Superficie supérieure marche: 0.416169 m2
2 x MARCHE-341 | Etage 2 | Lame d'air 275581351 | MARCHE-341 | Etage 2 | 5 | Giron (Escalier) | ESC-020 | 1.06732 | 10 | 0.00515312 |  | 10194.4 | 1694.44 | 1355.56 | 10194.4 | 1694.44 | 10184.4 | 1684.44 | 1 | Quart tournant avec marches égales | 10 | Marche 27 | 0.0158342 | 1266.57 | 1583.42 | ArchiCADQuantities - Nez de marche: 15 mm; Giron de marche: 310.727 mm; Longueur volée marche: 335.731 mm; Superficie supérieure marche: 0.515312 m2
2 x MARCHE-344 | Etage 2 | Lame d'air 275581351 | MARCHE-344 | Etage 2 | 5 | Giron (Escalier) | ESC-020 | 0.855182 | 10 | 0.00411886 |  | 10702.8 | 2202.78 | 847.222 | 10702.8 | 2202.78 | 10692.8 | 2192.78 | 1 | Quart tournant avec marches égales | 13 | Marche 27 | 0.0122 | 1246.79 | 1220 | ArchiCADQuantities - Nez de marche: 15 mm; Giron de marche: 310.727 mm; Longueur volée marche: 335.731 mm; Superficie supérieure marche: 0.411886 m2
2 x MARCHE-343 | Etage 2 | Lame d'air 275581351 | MARCHE-343 | Etage 2 | 5 | Giron (Escalier) | ESC-020 | 0.850289 | 10 | 0.00409587 |  | 10533.3 | 2033.33 | 1016.67 | 10533.3 | 2033.33 | 10523.3 | 2023.33 | 1 | Quart tournant avec marches égales | 12 | Marche 27 | 0.0122 | 1220 | 1220 | ArchiCADQuantities - Nez de marche: 15 mm; Giron de marche: 310.727 mm; Longueur volée marche: 335.727 mm; Superficie supérieure marche: 0.409587 m2
2 x MARCHE-345 | Etage 2 | Lame d'air 275581351 | MARCHE-345 | Etage 2 | 5 | Giron (Escalier) | ESC-020 | 0.994208 | 10 | 0.00479638 |  | 10872.2 | 2372.22 | 677.778 | 10872.2 | 2372.22 | 10862.2 | 2362.22 | 1 | Quart tournant avec marches égales | 14 | Marche 27 | 0.0124091 | 1487.02 | 1240.91 | ArchiCADQuantities - Nez de marche: 15 mm; Giron de marche: 310.727 mm; Longueur volée marche: 335.731 mm; Superficie supérieure marche: 0.479638 m2
2 x MARCHE-347 | Etage 2 | Lame d'air 275581351 | MARCHE-347 | Etage 2 | 5 | Giron (Escalier) | ESC-020 | 1.05199 | 10 | 0.00507826 |  | 11211.1 | 2711.11 | 338.889 | 11211.1 | 2711.11 | 11201.1 | 2701.11 | 1 | Quart tournant avec marches égales | 16 | Marche 27 | 0.0156368 | 1261.18 | 1563.68 | ArchiCADQuantities - Nez de marche: 15 mm; Giron de marche: 310.727 mm; Longueur volée marche: 335.731 mm; Superficie supérieure marche: 0.507826 m2
2 x MARCHE-346 | Etage 2 | Lame d'air 275581351 | MARCHE-346 | Etage 2 | 5 | Giron (Escalier) | ESC-020 | 1.41049 | 10 | 0.00684895 |  | 11041.7 | 2541.67 | 508.333 | 11041.7 | 2541.67 | 11031.7 | 2531.67 | 1 | Quart tournant avec marches égales | 15 | Marche 27 | 0.0146997 | 1546.84 | 1469.97 | ArchiCADQuantities - Nez de marche: 15 mm; Giron de marche: 310.727 mm; Longueur volée marche: 335.731 mm; Superficie supérieure marche: 0.684895 m2
2 x MARCHE-348 | Etage 2 | Lame d'air 275581351 | MARCHE-348 | Etage 2 | 5 | Giron (Escalier) | ESC-020 | 0.861863 | 10 | 0.00415106 |  | 11380.6 | 2880.56 | 169.444 | 11380.6 | 2880.56 | 11370.6 | 2870.56 | 1 | Quart tournant avec marches égales | 17 | Marche 27 | 0.0126603 | 1220 | 1266.03 | ArchiCADQuantities - Nez de marche: 15 mm; Giron de marche: 310.727 mm; Longueur volée marche: 310.727 mm; Superficie supérieure marche: 0.415106 m2
C-MARCHE-347 | Etage 2 | Parpaing 2676271321 | C-MARCHE-347 | Etage 2 | 5 | Contremarche (Escalier) | ESC-020 | 0.52882 | 10 | 0.00247121 | 1553.2 | 11041.7 | 2541.67 | 348.889 | 11201.1 | 2701.11 | 11041.7 | 2541.67 | 1 | Quart tournant avec marches égales | 16 | Contremarche 27 | 0.247649 | 1553.2 | 1553.2 | ArchiCADQuantities - Hauteur 3D de contremarche: 159.444 mm; Hauteur: 159.444 mm; ArchiCADProperties - Surfaces (Toutes): Peinture-11
C-MARCHE-332 | Etage 2 | Lame d'air 275581351 | C-MARCHE-332 | Etage 2 | 5 | Contremarche (Escalier) | ESC-020 | 0.416633 | 10 | 0.00194522 | 1220 | 8500 | 0 | 2890.56 | 8659.44 | 159.444 | 8500 | 0 | 1 | Quart tournant avec marches égales | 1 | Contremarche 27 | 0.194522 | 1220 | 1220 | ArchiCADQuantities - Hauteur 3D de contremarche: 159.444 mm; Hauteur: 159.444 mm
C-MARCHE-333 | Etage 2 | Lame d'air 275581351 | C-MARCHE-333 | Etage 2 | 5 | Contremarche (Escalier) | ESC-020 | 0.416633 | 10 | 0.00194522 | 1220 | 8669.44 | 169.444 | 2721.11 | 8828.89 | 328.889 | 8669.44 | 169.444 | 1 | Quart tournant avec marches égales | 2 | Contremarche 27 | 0.194522 | 1220 | 1220 | ArchiCADQuantities - Hauteur 3D de contremarche: 159.444 mm; Hauteur: 159.444 mm
C-MARCHE-335 | Etage 2 | Lame d'air 275581351 | C-MARCHE-335 | Etage 2 | 5 | Contremarche (Escalier) | ESC-020 | 0.427095 | 10 | 0.00199428 | 1249.43 | 9008.33 | 508.333 | 2382.22 | 9167.78 | 667.778 | 9008.33 | 508.333 | 1 | Quart tournant avec marches égales | 4 | Contremarche 27 | 0.199215 | 1249.43 | 1249.43 | ArchiCADQuantities - Hauteur 3D de contremarche: 159.444 mm; Hauteur: 159.444 mm
C-MARCHE-336 | Etage 2 | Lame d'air 275581351 | C-MARCHE-336 | Etage 2 | 5 | Contremarche (Escalier) | ESC-020 | 0.513301 | 10 | 0.00239859 | 1500.73 | 9177.78 | 677.778 | 2212.78 | 9337.22 | 837.222 | 9177.78 | 677.778 | 1 | Quart tournant avec marches égales | 5 | Contremarche 27 | 0.239284 | 1500.73 | 1500.73 | ArchiCADQuantities - Hauteur 3D de contremarche: 159.444 mm; Hauteur: 159.444 mm
C-MARCHE-334 | Etage 2 | Lame d'air 275581351 | C-MARCHE-334 | Etage 2 | 5 | Contremarche (Escalier) | ESC-020 | 0.416633 | 10 | 0.00194522 | 1220 | 8838.89 | 338.889 | 2551.67 | 8998.33 | 498.333 | 8838.89 | 338.889 | 1 | Quart tournant avec marches égales | 3 | Contremarche 27 | 0.194522 | 1220 | 1220 | ArchiCADQuantities - Hauteur 3D de contremarche: 159.444 mm; Hauteur: 159.444 mm
C-MARCHE-340 | Etage 2 | Lame d'air 275581351 | C-MARCHE-340 | Etage 2 | 5 | Contremarche (Escalier) | ESC-020 | 0.499875 | 10 | 0.00233561 | 1461.48 | 9855.56 | 1355.56 | 1535 | 10015 | 1515 | 9855.56 | 1355.56 | 1 | Quart tournant avec marches égales | 9 | Contremarche 27 | 0.233024 | 1461.48 | 1461.48 | ArchiCADQuantities - Hauteur 3D de contremarche: 159.444 mm; Hauteur: 159.444 mm
C-MARCHE-339 | Etage 2 | Lame d'air 275581351 | C-MARCHE-339 | Etage 2 | 5 | Contremarche (Escalier) | ESC-020 | 0.423162 | 10 | 0.00197583 | 1238.04 | 9686.11 | 1186.11 | 1704.44 | 9845.56 | 1345.56 | 9686.11 | 1186.11 | 1 | Quart tournant avec marches égales | 8 | Contremarche 27 | 0.197398 | 1238.04 | 1238.04 | ArchiCADQuantities - Hauteur 3D de contremarche: 159.444 mm; Hauteur: 159.444 mm
C-MARCHE-337 | Etage 2 | Lame d'air 275581351 | C-MARCHE-337 | Etage 2 | 5 | Contremarche (Escalier) | ESC-020 | 0.519602 | 10 | 0.00242797 | 1525.93 | 9347.22 | 847.222 | 2043.33 | 9506.67 | 1006.67 | 9347.22 | 847.222 | 1 | Quart tournant avec marches égales | 6 | Contremarche 27 | 0.243301 | 1525.93 | 1525.93 | ArchiCADQuantities - Hauteur 3D de contremarche: 159.444 mm; Hauteur: 159.444 mm
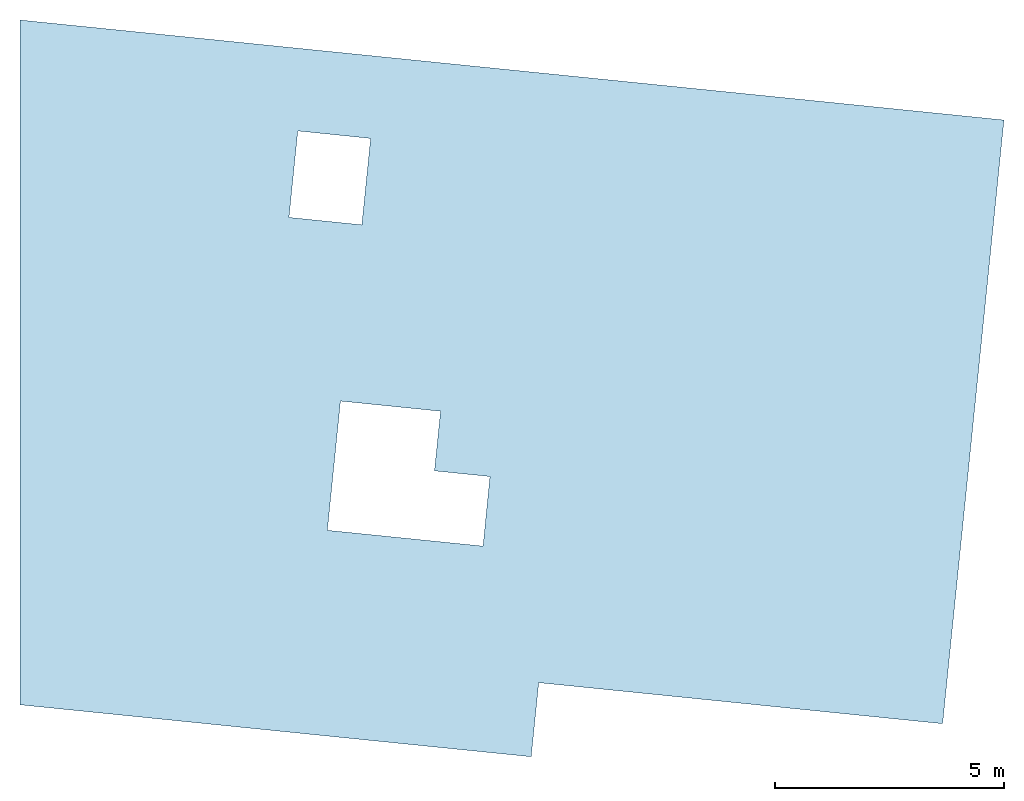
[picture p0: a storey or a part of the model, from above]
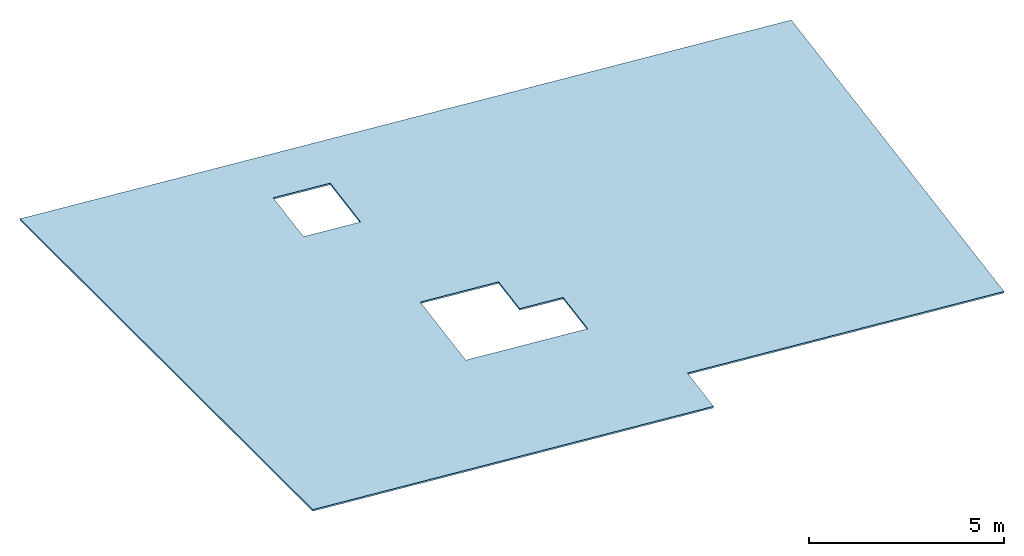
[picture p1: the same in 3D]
Properties of the parts of a building model (IFC2X3), part 8 of 44

# IfcBuildingElementProxy: IfcBuildingElementProxy (404)
Name | In | Material | ID de l'élément = Lien et ID d'élément | Nom d'étage d'implantation | Numéro d'étage d'implantation | Type d'élément | ID de Parent | Superficie totale (m2) = Superficie en plan (m2) = Superficie inférieure (nette) (m2) | Épaisseur (mm) | Volume (net) (m3) | Largeur (mm) | Altitude à Zéro du Projet (mm) = Altitude de Référence Niveau 1 (mm) = Altitude de Référence Niveau 2 (mm) = Altitude à niveau de la mer (mm) | Altitude à étage lié/étage d'implantation (mm) = Décalage étage d'implantation (mm) | Décalage supérieur (mm) | Altitude supérieure à premier niveau de référence (mm) = Altitude supérieure à Zéro du projet (mm) = Altitude supérieure à niveau de la mer (mm) = Altitude supérieure à deuxième niveau de référence (mm) | Altitude supérieure à étage d'implantation (mm) | Altitude inférieure à premier niveau de référence (mm) = Altitude inférieure à Zéro du projet (mm) = Altitude inférieure à niveau de la mer (mm) = Altitude inférieure à deuxième niveau de référence (mm) | Altitude inférieure à étage d'implantation (mm) | Index volée | Type de segment | Index de marche | Nom Élément de Bibliothèque | Superficie avant (m2) | Largeur arrière (mm) | Largeur avant (mm)
C-MARCHE-342 | Etage 2 | Lame d'air 275581351 | C-MARCHE-342 | Etage 2 | 5 | Contremarche (Escalier) | ESC-020 | 0.432726 | 10 | 0.00202064 | 1268.29 | 10194.4 | 1694.44 | 1196.11 | 10353.9 | 1853.89 | 10194.4 | 1694.44 | 1 | Quart tournant avec marches égales | 11 | Contremarche 27 | 0.202221 | 1268.29 | 1268.29 | ArchiCADQuantities - Hauteur 3D de contremarche: 159.444 mm; Hauteur: 159.444 mm
C-MARCHE-338 | Etage 2 | Lame d'air 275581351 | C-MARCHE-338 | Etage 2 | 5 | Contremarche (Escalier) | ESC-020 | 0.427779 | 10 | 0.00199743 | 1253.55 | 9516.67 | 1016.67 | 1873.89 | 9676.11 | 1176.11 | 9516.67 | 1016.67 | 1 | Quart tournant avec marches égales | 7 | Contremarche 27 | 0.199871 | 1253.55 | 1253.55 | ArchiCADQuantities - Hauteur 3D de contremarche: 159.444 mm; Hauteur: 159.444 mm
C-MARCHE-341 | Etage 2 | Lame d'air 275581351 | C-MARCHE-341 | Etage 2 | 5 | Contremarche (Escalier) | ESC-020 | 0.535374 | 10 | 0.00250195 | 1572.59 | 10025 | 1525 | 1365.56 | 10184.4 | 1684.44 | 10025 | 1525 | 1 | Quart tournant avec marches égales | 10 | Contremarche 27 | 0.250741 | 1572.59 | 1572.59 | ArchiCADQuantities - Hauteur 3D de contremarche: 159.444 mm; Hauteur: 159.444 mm
C-MARCHE-344 | Etage 2 | Lame d'air 275581351 | C-MARCHE-344 | Etage 2 | 5 | Contremarche (Escalier) | ESC-020 | 0.416633 | 10 | 0.00194522 | 1220 | 10533.3 | 2033.33 | 857.222 | 10692.8 | 2192.78 | 10533.3 | 2033.33 | 1 | Quart tournant avec marches égales | 13 | Contremarche 27 | 0.194522 | 1220 | 1220 | ArchiCADQuantities - Hauteur 3D de contremarche: 159.444 mm; Hauteur: 159.444 mm
C-MARCHE-345 | Etage 2 | Lame d'air 275581351 | C-MARCHE-345 | Etage 2 | 5 | Contremarche (Escalier) | ESC-020 | 0.425234 | 10 | 0.00198555 | 1244.06 | 10702.8 | 2202.78 | 687.778 | 10862.2 | 2362.22 | 10702.8 | 2202.78 | 1 | Quart tournant avec marches égales | 14 | Contremarche 27 | 0.198358 | 1244.06 | 1244.06 | ArchiCADQuantities - Hauteur 3D de contremarche: 159.444 mm; Hauteur: 159.444 mm
C-MARCHE-343 | Etage 2 | Lame d'air 275581351 | C-MARCHE-343 | Etage 2 | 5 | Contremarche (Escalier) | ESC-020 | 0.416633 | 10 | 0.00194522 | 1220 | 10363.9 | 1863.89 | 1026.67 | 10523.3 | 2023.33 | 10363.9 | 1863.89 | 1 | Quart tournant avec marches égales | 12 | Contremarche 27 | 0.194522 | 1220 | 1220 | ArchiCADQuantities - Hauteur 3D de contremarche: 159.444 mm; Hauteur: 159.444 mm
C-MARCHE-346 | Etage 2 | Lame d'air 275581351 | C-MARCHE-346 | Etage 2 | 5 | Contremarche (Escalier) | ESC-020 | 0.506145 | 10 | 0.00236503 | 1479.82 | 10872.2 | 2372.22 | 518.333 | 11031.7 | 2531.67 | 10872.2 | 2372.22 | 1 | Quart tournant avec marches égales | 15 | Contremarche 27 | 0.235949 | 1479.82 | 1479.82 | ArchiCADQuantities - Hauteur 3D de contremarche: 159.444 mm; Hauteur: 159.444 mm
C-MARCHE-348 | Etage 2 | Lame d'air 275581351 | C-MARCHE-348 | Etage 2 | 5 | Contremarche (Escalier) | ESC-020 | 0.430867 | 10 | 0.00201192 | 1262.74 | 11211.1 | 2711.11 | 179.444 | 11370.6 | 2870.56 | 11211.1 | 2711.11 | 1 | Quart tournant avec marches égales | 17 | Contremarche 27 | 0.201337 | 1262.74 | 1262.74 | ArchiCADQuantities - Hauteur 3D de contremarche: 159.444 mm; Hauteur: 159.444 mm
C-MARCHE-349 | Etage 2 | Lame d'air 275581351 | C-MARCHE-349 | Etage 2 | 5 | Contremarche (Escalier) | ESC-020 | 0.441233 | 10 | 0.00206722 | 1220 | 11380.6 | 2880.56 | 0 | 11550 | 3050 | 11380.6 | 2880.56 | 1 | Inconnu | 18 | Contremarche 27 | 0.206722 | 1220 | 1220 | ArchiCADQuantities - Hauteur 3D de contremarche: 169.444 mm; Hauteur: 169.444 mm
C-MARCHE-347 | Etage 2 | Lame d'air 275581351 | C-MARCHE-347 | Etage 2 | 5 | Contremarche (Escalier) | ESC-020 | 0.52882 | 10 | 0.00247121 | 1553.2 | 11041.7 | 2541.67 | 348.889 | 11201.1 | 2701.11 | 11041.7 | 2541.67 | 1 | Quart tournant avec marches égales | 16 | Contremarche 27 | 0.247649 | 1553.2 | 1553.2 | ArchiCADQuantities - Hauteur 3D de contremarche: 159.444 mm; Hauteur: 159.444 mm
VOLEE-022 | Etage 3 | Cloison 274992075 | VOLEE-022 | Etage 3 | 6 | Structure (Escalier) | ESC-020 | 23.8304 | 150 | 2.08754 | 1220 | 14420.6 | 2870.56 | 179.444 | 14420.6 | 2870.56 | 11420 | -130 | ArchiCADProperties - Type construction: Monolithique; Type forme: Plat; Position structure escalier: Sous l'escalier; Index volée structure escalier: 1; Matériau de construction / Composite / Profil / Hachure: Cloison 274992075; Matériaux de construction (Tous): Cloison 274992075; ArchiCADQuantities - Épaisseur secondaire: 150 mm; Hauteur 3D de structure d'escalier: 3000.56 mm; Longueur 3D: 6016.72 mm
C-MARCHE-332 | Etage 3 | Parpaing 2676271321 | C-MARCHE-332 | Etage 3 | 6 | Contremarche (Escalier) | ESC-020 | 0.416633 | 10 | 0.00194522 | 1220 | 11550 | 0 | 2890.56 | 11709.4 | 159.444 | 11550 | 0 | 1 | Quart tournant avec marches égales | 1 | Contremarche 27 | 0.194522 | 1220 | 1220 | ArchiCADQuantities - Hauteur 3D de contremarche: 159.444 mm; Hauteur: 159.444 mm; ArchiCADProperties - Surfaces (Toutes): Peinture-11
C-MARCHE-333 | Etage 3 | Parpaing 2676271321 | C-MARCHE-333 | Etage 3 | 6 | Contremarche (Escalier) | ESC-020 | 0.416633 | 10 | 0.00194522 | 1220 | 11719.4 | 169.444 | 2721.11 | 11878.9 | 328.889 | 11719.4 | 169.444 | 1 | Quart tournant avec marches égales | 2 | Contremarche 27 | 0.194522 | 1220 | 1220 | ArchiCADQuantities - Hauteur 3D de contremarche: 159.444 mm; Hauteur: 159.444 mm; ArchiCADProperties - Surfaces (Toutes): Peinture-11
C-MARCHE-335 | Etage 3 | Parpaing 2676271321 | C-MARCHE-335 | Etage 3 | 6 | Contremarche (Escalier) | ESC-020 | 0.427095 | 10 | 0.00199428 | 1249.43 | 12058.3 | 508.333 | 2382.22 | 12217.8 | 667.778 | 12058.3 | 508.333 | 1 | Quart tournant avec marches égales | 4 | Contremarche 27 | 0.199215 | 1249.43 | 1249.43 | ArchiCADQuantities - Hauteur 3D de contremarche: 159.444 mm; Hauteur: 159.444 mm; ArchiCADProperties - Surfaces (Toutes): Peinture-11
C-MARCHE-336 | Etage 3 | Parpaing 2676271321 | C-MARCHE-336 | Etage 3 | 6 | Contremarche (Escalier) | ESC-020 | 0.513301 | 10 | 0.00239859 | 1500.73 | 12227.8 | 677.778 | 2212.78 | 12387.2 | 837.222 | 12227.8 | 677.778 | 1 | Quart tournant avec marches égales | 5 | Contremarche 27 | 0.239284 | 1500.73 | 1500.73 | ArchiCADQuantities - Hauteur 3D de contremarche: 159.444 mm; Hauteur: 159.444 mm; ArchiCADProperties - Surfaces (Toutes): Peinture-11
C-MARCHE-338 | Etage 3 | Parpaing 2676271321 | C-MARCHE-338 | Etage 3 | 6 | Contremarche (Escalier) | ESC-020 | 0.427779 | 10 | 0.00199743 | 1253.55 | 12566.7 | 1016.67 | 1873.89 | 12726.1 | 1176.11 | 12566.7 | 1016.67 | 1 | Quart tournant avec marches égales | 7 | Contremarche 27 | 0.199871 | 1253.55 | 1253.55 | ArchiCADQuantities - Hauteur 3D de contremarche: 159.444 mm; Hauteur: 159.444 mm; ArchiCADProperties - Surfaces (Toutes): Peinture-11
C-MARCHE-334 | Etage 3 | Parpaing 2676271321 | C-MARCHE-334 | Etage 3 | 6 | Contremarche (Escalier) | ESC-020 | 0.416633 | 10 | 0.00194522 | 1220 | 11888.9 | 338.889 | 2551.67 | 12048.3 | 498.333 | 11888.9 | 338.889 | 1 | Quart tournant avec marches égales | 3 | Contremarche 27 | 0.194522 | 1220 | 1220 | ArchiCADQuantities - Hauteur 3D de contremarche: 159.444 mm; Hauteur: 159.444 mm; ArchiCADProperties - Surfaces (Toutes): Peinture-11
C-MARCHE-337 | Etage 3 | Parpaing 2676271321 | C-MARCHE-337 | Etage 3 | 6 | Contremarche (Escalier) | ESC-020 | 0.519602 | 10 | 0.00242797 | 1525.93 | 12397.2 | 847.222 | 2043.33 | 12556.7 | 1006.67 | 12397.2 | 847.222 | 1 | Quart tournant avec marches égales | 6 | Contremarche 27 | 0.243301 | 1525.93 | 1525.93 | ArchiCADQuantities - Hauteur 3D de contremarche: 159.444 mm; Hauteur: 159.444 mm; ArchiCADProperties - Surfaces (Toutes): Peinture-11
C-MARCHE-339 | Etage 3 | Parpaing 2676271321 | C-MARCHE-339 | Etage 3 | 6 | Contremarche (Escalier) | ESC-020 | 0.423162 | 10 | 0.00197583 | 1238.04 | 12736.1 | 1186.11 | 1704.44 | 12895.6 | 1345.56 | 12736.1 | 1186.11 | 1 | Quart tournant avec marches égales | 8 | Contremarche 27 | 0.197398 | 1238.04 | 1238.04 | ArchiCADQuantities - Hauteur 3D de contremarche: 159.444 mm; Hauteur: 159.444 mm; ArchiCADProperties - Surfaces (Toutes): Peinture-11
C-MARCHE-340 | Etage 3 | Parpaing 2676271321 | C-MARCHE-340 | Etage 3 | 6 | Contremarche (Escalier) | ESC-020 | 0.499875 | 10 | 0.00233561 | 1461.48 | 12905.6 | 1355.56 | 1535 | 13065 | 1515 | 12905.6 | 1355.56 | 1 | Quart tournant avec marches égales | 9 | Contremarche 27 | 0.233024 | 1461.48 | 1461.48 | ArchiCADQuantities - Hauteur 3D de contremarche: 159.444 mm; Hauteur: 159.444 mm; ArchiCADProperties - Surfaces (Toutes): Peinture-11
C-MARCHE-341 | Etage 3 | Parpaing 2676271321 | C-MARCHE-341 | Etage 3 | 6 | Contremarche (Escalier) | ESC-020 | 0.535374 | 10 | 0.00250195 | 1572.59 | 13075 | 1525 | 1365.56 | 13234.4 | 1684.44 | 13075 | 1525 | 1 | Quart tournant avec marches égales | 10 | Contremarche 27 | 0.250741 | 1572.59 | 1572.59 | ArchiCADQuantities - Hauteur 3D de contremarche: 159.444 mm; Hauteur: 159.444 mm; ArchiCADProperties - Surfaces (Toutes): Peinture-11
C-MARCHE-342 | Etage 3 | Parpaing 2676271321 | C-MARCHE-342 | Etage 3 | 6 | Contremarche (Escalier) | ESC-020 | 0.432726 | 10 | 0.00202064 | 1268.29 | 13244.4 | 1694.44 | 1196.11 | 13403.9 | 1853.89 | 13244.4 | 1694.44 | 1 | Quart tournant avec marches égales | 11 | Contremarche 27 | 0.202221 | 1268.29 | 1268.29 | ArchiCADQuantities - Hauteur 3D de contremarche: 159.444 mm; Hauteur: 159.444 mm; ArchiCADProperties - Surfaces (Toutes): Peinture-11
C-MARCHE-344 | Etage 3 | Parpaing 2676271321 | C-MARCHE-344 | Etage 3 | 6 | Contremarche (Escalier) | ESC-020 | 0.416633 | 10 | 0.00194522 | 1220 | 13583.3 | 2033.33 | 857.222 | 13742.8 | 2192.78 | 13583.3 | 2033.33 | 1 | Quart tournant avec marches égales | 13 | Contremarche 27 | 0.194522 | 1220 | 1220 | ArchiCADQuantities - Hauteur 3D de contremarche: 159.444 mm; Hauteur: 159.444 mm; ArchiCADProperties - Surfaces (Toutes): Peinture-11
C-MARCHE-343 | Etage 3 | Parpaing 2676271321 | C-MARCHE-343 | Etage 3 | 6 | Contremarche (Escalier) | ESC-020 | 0.416633 | 10 | 0.00194522 | 1220 | 13413.9 | 1863.89 | 1026.67 | 13573.3 | 2023.33 | 13413.9 | 1863.89 | 1 | Quart tournant avec marches égales | 12 | Contremarche 27 | 0.194522 | 1220 | 1220 | ArchiCADQuantities - Hauteur 3D de contremarche: 159.444 mm; Hauteur: 159.444 mm; ArchiCADProperties - Surfaces (Toutes): Peinture-11
C-MARCHE-345 | Etage 3 | Parpaing 2676271321 | C-MARCHE-345 | Etage 3 | 6 | Contremarche (Escalier) | ESC-020 | 0.425234 | 10 | 0.00198555 | 1244.06 | 13752.8 | 2202.78 | 687.778 | 13912.2 | 2362.22 | 13752.8 | 2202.78 | 1 | Quart tournant avec marches égales | 14 | Contremarche 27 | 0.198358 | 1244.06 | 1244.06 | ArchiCADQuantities - Hauteur 3D de contremarche: 159.444 mm; Hauteur: 159.444 mm; ArchiCADProperties - Surfaces (Toutes): Peinture-11
C-MARCHE-346 | Etage 3 | Parpaing 2676271321 | C-MARCHE-346 | Etage 3 | 6 | Contremarche (Escalier) | ESC-020 | 0.506145 | 10 | 0.00236503 | 1479.82 | 13922.2 | 2372.22 | 518.333 | 14081.7 | 2531.67 | 13922.2 | 2372.22 | 1 | Quart tournant avec marches égales | 15 | Contremarche 27 | 0.235949 | 1479.82 | 1479.82 | ArchiCADQuantities - Hauteur 3D de contremarche: 159.444 mm; Hauteur: 159.444 mm; ArchiCADProperties - Surfaces (Toutes): Peinture-11
C-MARCHE-347 | Etage 3 | Parpaing 2676271321 | C-MARCHE-347 | Etage 3 | 6 | Contremarche (Escalier) | ESC-020 | 0.52882 | 10 | 0.00247121 | 1553.2 | 14091.7 | 2541.67 | 348.889 | 14251.1 | 2701.11 | 14091.7 | 2541.67 | 1 | Quart tournant avec marches égales | 16 | Contremarche 27 | 0.247649 | 1553.2 | 1553.2 | ArchiCADQuantities - Hauteur 3D de contremarche: 159.444 mm; Hauteur: 159.444 mm; ArchiCADProperties - Surfaces (Toutes): Peinture-11
C-MARCHE-349 | Etage 3 | Parpaing 2676271321 | C-MARCHE-349 | Etage 3 | 6 | Contremarche (Escalier) | ESC-020 | 0.441233 | 10 | 0.00206722 | 1220 | 14430.6 | 2880.56 | 0 | 14600 | 3050 | 14430.6 | 2880.56 | 1 | Inconnu | 18 | Contremarche 27 | 0.206722 | 1220 | 1220 | ArchiCADQuantities - Hauteur 3D de contremarche: 169.444 mm; Hauteur: 169.444 mm; ArchiCADProperties - Surfaces (Toutes): Peinture-11
C-MARCHE-348 | Etage 3 | Parpaing 2676271321 | C-MARCHE-348 | Etage 3 | 6 | Contremarche (Escalier) | ESC-020 | 0.430867 | 10 | 0.00201192 | 1262.74 | 14261.1 | 2711.11 | 179.444 | 14420.6 | 2870.56 | 14261.1 | 2711.11 | 1 | Quart tournant avec marches égales | 17 | Contremarche 27 | 0.201337 | 1262.74 | 1262.74 | ArchiCADQuantities - Hauteur 3D de contremarche: 159.444 mm; Hauteur: 159.444 mm; ArchiCADProperties - Surfaces (Toutes): Peinture-11
MARCHE-332 | Etage 3 | Lame d'air 275581351 | MARCHE-332 | Etage 3 | 6 | Giron (Escalier) | ESC-020 | 0.850289 | 10 | 0.00409587 |  | 11719.4 | 169.444 | 2880.56 | 11719.4 | 169.444 | 11709.4 | 159.444 | 1 | Quart tournant avec marches égales | 1 | Marche 27 | 0.0122 | 1220 | 1220 | ArchiCADQuantities - Nez de marche: 15 mm; Giron de marche: 310.727 mm; Longueur volée marche: 335.727 mm; Superficie supérieure marche: 0.409587 m2
MARCHE-333 | Etage 3 | Lame d'air 275581351 | MARCHE-333 | Etage 3 | 6 | Giron (Escalier) | ESC-020 | 0.850289 | 10 | 0.00409587 |  | 11888.9 | 338.889 | 2711.11 | 11888.9 | 338.889 | 11878.9 | 328.889 | 1 | Quart tournant avec marches égales | 2 | Marche 27 | 0.0122 | 1220 | 1220 | ArchiCADQuantities - Nez de marche: 15 mm; Giron de marche: 310.727 mm; Longueur volée marche: 335.727 mm; Superficie supérieure marche: 0.409587 m2
MARCHE-334 | Etage 3 | Lame d'air 275581351 | MARCHE-334 | Etage 3 | 6 | Giron (Escalier) | ESC-020 | 0.856816 | 10 | 0.0041267 |  | 12058.3 | 508.333 | 2541.67 | 12058.3 | 508.333 | 12048.3 | 498.333 | 1 | Quart tournant avec marches égales | 3 | Marche 27 | 0.0122 | 1252.36 | 1220 | ArchiCADQuantities - Nez de marche: 15 mm; Giron de marche: 310.727 mm; Longueur volée marche: 335.731 mm; Superficie supérieure marche: 0.41267 m2
MARCHE-335 | Etage 3 | Lame d'air 275581351 | MARCHE-335 | Etage 3 | 6 | Giron (Escalier) | ESC-020 | 1.00989 | 10 | 0.00487295 |  | 12227.8 | 677.778 | 2372.22 | 12227.8 | 677.778 | 12217.8 | 667.778 | 1 | Quart tournant avec marches égales | 4 | Marche 27 | 0.0124599 | 1508.2 | 1245.99 | ArchiCADQuantities - Nez de marche: 15 mm; Giron de marche: 310.727 mm; Longueur volée marche: 335.731 mm; Superficie supérieure marche: 0.487295 m2
MARCHE-336 | Etage 3 | Lame d'air 275581351 | MARCHE-336 | Etage 3 | 6 | Giron (Escalier) | ESC-020 | 1.41147 | 10 | 0.00685407 |  | 12397.2 | 847.222 | 2202.78 | 12397.2 | 847.222 | 12387.2 | 837.222 | 1 | Quart tournant avec marches égales | 5 | Marche 27 | 0.0149048 | 1519.87 | 1490.48 | ArchiCADQuantities - Nez de marche: 15 mm; Giron de marche: 310.727 mm; Longueur volée marche: 335.731 mm; Superficie supérieure marche: 0.685407 m2
MARCHE-337 | Etage 3 | Lame d'air 275581351 | MARCHE-337 | Etage 3 | 6 | Giron (Escalier) | ESC-020 | 1.02964 | 10 | 0.00496903 |  | 12566.7 | 1016.67 | 2033.33 | 12566.7 | 1016.67 | 12556.7 | 1006.67 | 1 | Quart tournant avec marches égales | 6 | Marche 27 | 0.0153597 | 1252.2 | 1535.97 | ArchiCADQuantities - Nez de marche: 15 mm; Giron de marche: 310.727 mm; Longueur volée marche: 335.731 mm; Superficie supérieure marche: 0.496903 m2
MARCHE-338 | Etage 3 | Lame d'air 275581351 | MARCHE-338 | Etage 3 | 6 | Giron (Escalier) | ESC-020 | 0.860493 | 10 | 0.00414368 |  | 12736.1 | 1186.11 | 1863.89 | 12736.1 | 1186.11 | 12726.1 | 1176.11 | 1 | Quart tournant avec marches égales | 7 | Marche 27 | 0.0125652 | 1240.61 | 1256.52 | ArchiCADQuantities - Nez de marche: 15 mm; Giron de marche: 310.727 mm; Longueur volée marche: 335.731 mm; Superficie supérieure marche: 0.414368 m2
MARCHE-339 | Etage 3 | Lame d'air 275581351 | MARCHE-339 | Etage 3 | 6 | Giron (Escalier) | ESC-020 | 0.979664 | 10 | 0.00472531 |  | 12905.6 | 1355.56 | 1694.44 | 12905.6 | 1355.56 | 12895.6 | 1345.56 | 1 | Quart tournant avec marches égales | 8 | Marche 27 | 0.0123513 | 1468.46 | 1235.13 | ArchiCADQuantities - Nez de marche: 15 mm; Giron de marche: 310.727 mm; Longueur volée marche: 335.731 mm; Superficie supérieure marche: 0.472531 m2
MARCHE-340 | Etage 3 | Lame d'air 275581351 | MARCHE-340 | Etage 3 | 6 | Giron (Escalier) | ESC-020 | 1.40265 | 10 | 0.00680994 |  | 13075 | 1525 | 1525 | 13075 | 1525 | 13065 | 1515 | 1 | Quart tournant avec marches égales | 9 | Marche 27 | 0.0145195 | 1566 | 1451.95 | ArchiCADQuantities - Nez de marche: 15 mm; Giron de marche: 310.727 mm; Longueur volée marche: 335.731 mm; Superficie supérieure marche: 0.680994 m2
MARCHE-341 | Etage 3 | Lame d'air 275581351 | MARCHE-341 | Etage 3 | 6 | Giron (Escalier) | ESC-020 | 1.06732 | 10 | 0.00515312 |  | 13244.4 | 1694.44 | 1355.56 | 13244.4 | 1694.44 | 13234.4 | 1684.44 | 1 | Quart tournant avec marches égales | 10 | Marche 27 | 0.0158342 | 1266.57 | 1583.42 | ArchiCADQuantities - Nez de marche: 15 mm; Giron de marche: 310.727 mm; Longueur volée marche: 335.731 mm; Superficie supérieure marche: 0.515312 m2
MARCHE-342 | Etage 3 | Lame d'air 275581351 | MARCHE-342 | Etage 3 | 6 | Giron (Escalier) | ESC-020 | 0.86406 | 10 | 0.00416169 |  | 13413.9 | 1863.89 | 1186.11 | 13413.9 | 1863.89 | 13403.9 | 1853.89 | 1 | Quart tournant avec marches égales | 11 | Marche 27 | 0.0127181 | 1220 | 1271.81 | ArchiCADQuantities - Nez de marche: 15 mm; Giron de marche: 310.727 mm; Longueur volée marche: 335.727 mm; Superficie supérieure marche: 0.416169 m2
MARCHE-343 | Etage 3 | Lame d'air 275581351 | MARCHE-343 | Etage 3 | 6 | Giron (Escalier) | ESC-020 | 0.850289 | 10 | 0.00409587 |  | 13583.3 | 2033.33 | 1016.67 | 13583.3 | 2033.33 | 13573.3 | 2023.33 | 1 | Quart tournant avec marches égales | 12 | Marche 27 | 0.0122 | 1220 | 1220 | ArchiCADQuantities - Nez de marche: 15 mm; Giron de marche: 310.727 mm; Longueur volée marche: 335.727 mm; Superficie supérieure marche: 0.409587 m2
MARCHE-345 | Etage 3 | Lame d'air 275581351 | MARCHE-345 | Etage 3 | 6 | Giron (Escalier) | ESC-020 | 0.994208 | 10 | 0.00479638 |  | 13922.2 | 2372.22 | 677.778 | 13922.2 | 2372.22 | 13912.2 | 2362.22 | 1 | Quart tournant avec marches égales | 14 | Marche 27 | 0.0124091 | 1487.02 | 1240.91 | ArchiCADQuantities - Nez de marche: 15 mm; Giron de marche: 310.727 mm; Longueur volée marche: 335.731 mm; Superficie supérieure marche: 0.479638 m2
MARCHE-344 | Etage 3 | Lame d'air 275581351 | MARCHE-344 | Etage 3 | 6 | Giron (Escalier) | ESC-020 | 0.855182 | 10 | 0.00411886 |  | 13752.8 | 2202.78 | 847.222 | 13752.8 | 2202.78 | 13742.8 | 2192.78 | 1 | Quart tournant avec marches égales | 13 | Marche 27 | 0.0122 | 1246.79 | 1220 | ArchiCADQuantities - Nez de marche: 15 mm; Giron de marche: 310.727 mm; Longueur volée marche: 335.731 mm; Superficie supérieure marche: 0.411886 m2
MARCHE-348 | Etage 3 | Lame d'air 275581351 | MARCHE-348 | Etage 3 | 6 | Giron (Escalier) | ESC-020 | 0.861863 | 10 | 0.00415106 |  | 14430.6 | 2880.56 | 169.444 | 14430.6 | 2880.56 | 14420.6 | 2870.56 | 1 | Quart tournant avec marches égales | 17 | Marche 27 | 0.0126603 | 1220 | 1266.03 | ArchiCADQuantities - Nez de marche: 15 mm; Giron de marche: 310.727 mm; Longueur volée marche: 310.727 mm; Superficie supérieure marche: 0.415106 m2
MARCHE-346 | Etage 3 | Lame d'air 275581351 | MARCHE-346 | Etage 3 | 6 | Giron (Escalier) | ESC-020 | 1.41049 | 10 | 0.00684895 |  | 14091.7 | 2541.67 | 508.333 | 14091.7 | 2541.67 | 14081.7 | 2531.67 | 1 | Quart tournant avec marches égales | 15 | Marche 27 | 0.0146997 | 1546.84 | 1469.97 | ArchiCADQuantities - Nez de marche: 15 mm; Giron de marche: 310.727 mm; Longueur volée marche: 335.731 mm; Superficie supérieure marche: 0.684895 m2
MARCHE-347 | Etage 3 | Lame d'air 275581351 | MARCHE-347 | Etage 3 | 6 | Giron (Escalier) | ESC-020 | 1.05199 | 10 | 0.00507826 |  | 14261.1 | 2711.11 | 338.889 | 14261.1 | 2711.11 | 14251.1 | 2701.11 | 1 | Quart tournant avec marches égales | 16 | Marche 27 | 0.0156368 | 1261.18 | 1563.68 | ArchiCADQuantities - Nez de marche: 15 mm; Giron de marche: 310.727 mm; Longueur volée marche: 335.731 mm; Superficie supérieure marche: 0.507826 m2
VOLEE-022 | Etage 3 | Cloison 274992075 | VOLEE-022 | Etage 3 | 6 | Structure (Escalier) | ESC-020 | 25.8026 | 150 | 2.29064 | 1220 | 14543.2 | 2993.16 | 176.842 | 14543.2 | 2993.16 | 11420 | -130 | ArchiCADProperties - Type construction: Monolithique; Type forme: Plat; Position structure escalier: Sous l'escalier; Index volée structure escalier: 1; Matériau de construction / Composite / Profil / Hachure: Cloison 274992075; Matériaux de construction (Tous): Cloison 274992075; ArchiCADQuantities - Épaisseur secondaire: 150 mm; Hauteur 3D de structure d'escalier: 3123.16 mm; Longueur 3D: 5886 mm
C-MARCHE-333 | Etage 3 | Lame d'air 275581351 | C-MARCHE-333 | Etage 3 | 6 | Contremarche (Escalier) | ESC-020 | 0.410232 | 10 | 0.00191347 | 1220 | 11716.8 | 166.842 | 2846.32 | 11873.7 | 323.684 | 11716.8 | 166.842 | 1 | Quart tournant avec marches égales | 2 | Contremarche 27 | 0.191347 | 1220 | 1220 | ArchiCADQuantities - Hauteur 3D de contremarche: 156.842 mm; Hauteur: 156.842 mm
C-MARCHE-332 | Etage 3 | Lame d'air 275581351 | C-MARCHE-332 | Etage 3 | 6 | Contremarche (Escalier) | ESC-020 | 0.410232 | 10 | 0.00191347 | 1220 | 11550 | 0 | 3013.16 | 11706.8 | 156.842 | 11550 | 0 | 1 | Quart tournant avec marches égales | 1 | Contremarche 27 | 0.191347 | 1220 | 1220 | ArchiCADQuantities - Hauteur 3D de contremarche: 156.842 mm; Hauteur: 156.842 mm
C-MARCHE-334 | Etage 3 | Lame d'air 275581351 | C-MARCHE-334 | Etage 3 | 6 | Contremarche (Escalier) | ESC-020 | 0.410232 | 10 | 0.00191347 | 1220 | 11883.7 | 333.684 | 2679.47 | 12040.5 | 490.526 | 11883.7 | 333.684 | 1 | Quart tournant avec marches égales | 3 | Contremarche 27 | 0.191347 | 1220 | 1220 | ArchiCADQuantities - Hauteur 3D de contremarche: 156.842 mm; Hauteur: 156.842 mm
C-MARCHE-335 | Etage 3 | Lame d'air 275581351 | C-MARCHE-335 | Etage 3 | 6 | Contremarche (Escalier) | ESC-020 | 0.430437 | 10 | 0.00200781 | 1277.67 | 12050.5 | 500.526 | 2512.63 | 12207.4 | 657.368 | 12050.5 | 500.526 | 1 | Quart tournant avec marches égales | 4 | Contremarche 27 | 0.200393 | 1277.67 | 1277.67 | ArchiCADQuantities - Hauteur 3D de contremarche: 156.842 mm; Hauteur: 156.842 mm
C-MARCHE-337 | Etage 3 | Lame d'air 275581351 | C-MARCHE-337 | Etage 3 | 6 | Contremarche (Escalier) | ESC-020 | 0.599564 | 10 | 0.00280262 | 1788.85 | 12384.2 | 834.211 | 2178.95 | 12541.1 | 991.053 | 12384.2 | 834.211 | 1 | Quart tournant avec marches égales | 6 | Contremarche 27 | 0.280566 | 1788.85 | 1788.85 | ArchiCADQuantities - Hauteur 3D de contremarche: 156.842 mm; Hauteur: 156.842 mm
C-MARCHE-338 | Etage 3 | Lame d'air 275581351 | C-MARCHE-338 | Etage 3 | 6 | Contremarche (Escalier) | ESC-020 | 0.49486 | 10 | 0.00231037 | 1475.17 | 12551.1 | 1001.05 | 2012.11 | 12707.9 | 1157.89 | 12551.1 | 1001.05 | 1 | Quart tournant avec marches égales | 7 | Contremarche 27 | 0.231369 | 1475.17 | 1475.17 | ArchiCADQuantities - Hauteur 3D de contremarche: 156.842 mm; Hauteur: 156.842 mm
C-MARCHE-339 | Etage 3 | Lame d'air 275581351 | C-MARCHE-339 | Etage 3 | 6 | Contremarche (Escalier) | ESC-020 | 0.41349 | 10 | 0.00192827 | 1227.19 | 12717.9 | 1167.89 | 1845.26 | 12874.7 | 1324.74 | 12717.9 | 1167.89 | 1 | Quart tournant avec marches égales | 8 | Contremarche 27 | 0.192475 | 1227.19 | 1227.19 | ArchiCADQuantities - Hauteur 3D de contremarche: 156.842 mm; Hauteur: 156.842 mm
C-MARCHE-336 | Etage 3 | Lame d'air 275581351 | C-MARCHE-336 | Etage 3 | 6 | Contremarche (Escalier) | ESC-020 | 0.51598 | 10 | 0.00240981 | 1533.86 | 12217.4 | 667.368 | 2345.79 | 12374.2 | 824.211 | 12217.4 | 667.368 | 1 | Quart tournant avec marches égales | 5 | Contremarche 27 | 0.240574 | 1533.86 | 1533.86 | ArchiCADQuantities - Hauteur 3D de contremarche: 156.842 mm; Hauteur: 156.842 mm
C-MARCHE-340 | Etage 3 | Lame d'air 275581351 | C-MARCHE-340 | Etage 3 | 6 | Contremarche (Escalier) | ESC-020 | 0.48873 | 10 | 0.00228181 | 1452.39 | 12884.7 | 1334.74 | 1678.42 | 13041.6 | 1491.58 | 12884.7 | 1334.74 | 1 | Quart tournant avec marches égales | 9 | Contremarche 27 | 0.227796 | 1452.39 | 1452.39 | ArchiCADQuantities - Hauteur 3D de contremarche: 156.842 mm; Hauteur: 156.842 mm
C-MARCHE-341 | Etage 3 | Lame d'air 275581351 | C-MARCHE-341 | Etage 3 | 6 | Contremarche (Escalier) | ESC-020 | 0.577794 | 10 | 0.0027005 | 1719.45 | 13051.6 | 1501.58 | 1511.58 | 13208.4 | 1658.42 | 13051.6 | 1501.58 | 1 | Quart tournant avec marches égales | 10 | Contremarche 27 | 0.269681 | 1719.45 | 1719.45 | ArchiCADQuantities - Hauteur 3D de contremarche: 156.842 mm; Hauteur: 156.842 mm
C-MARCHE-342 | Etage 3 | Lame d'air 275581351 | C-MARCHE-342 | Etage 3 | 6 | Contremarche (Escalier) | ESC-020 | 0.538996 | 10 | 0.00251795 | 1607.32 | 13218.4 | 1668.42 | 1344.74 | 13375.3 | 1825.26 | 13218.4 | 1668.42 | 1 | Quart tournant avec marches égales | 11 | Contremarche 27 | 0.252096 | 1607.32 | 1607.32 | ArchiCADQuantities - Hauteur 3D de contremarche: 156.842 mm; Hauteur: 156.842 mm
C-MARCHE-344 | Etage 3 | Lame d'air 275581351 | C-MARCHE-344 | Etage 3 | 6 | Contremarche (Escalier) | ESC-020 | 0.410232 | 10 | 0.00191347 | 1220 | 13552.1 | 2002.11 | 1011.05 | 13708.9 | 2158.95 | 13552.1 | 2002.11 | 1 | Quart tournant avec marches égales | 13 | Contremarche 27 | 0.191347 | 1220 | 1220 | ArchiCADQuantities - Hauteur 3D de contremarche: 156.842 mm; Hauteur: 156.842 mm
C-MARCHE-346 | Etage 3 | Lame d'air 275581351 | C-MARCHE-346 | Etage 3 | 6 | Contremarche (Escalier) | ESC-020 | 0.444097 | 10 | 0.00207198 | 1318.54 | 13885.8 | 2335.79 | 677.368 | 14042.6 | 2492.63 | 13885.8 | 2335.79 | 1 | Quart tournant avec marches égales | 15 | Contremarche 27 | 0.206803 | 1318.54 | 1318.54 | ArchiCADQuantities - Hauteur 3D de contremarche: 156.842 mm; Hauteur: 156.842 mm
C-MARCHE-345 | Etage 3 | Lame d'air 275581351 | C-MARCHE-345 | Etage 3 | 6 | Contremarche (Escalier) | ESC-020 | 0.410232 | 10 | 0.00191347 | 1220 | 13718.9 | 2168.95 | 844.211 | 13875.8 | 2325.79 | 13718.9 | 2168.95 | 1 | Quart tournant avec marches égales | 14 | Contremarche 27 | 0.191347 | 1220 | 1220 | ArchiCADQuantities - Hauteur 3D de contremarche: 156.842 mm; Hauteur: 156.842 mm
C-MARCHE-347 | Etage 3 | Lame d'air 275581351 | C-MARCHE-347 | Etage 3 | 6 | Contremarche (Escalier) | ESC-020 | 0.532787 | 10 | 0.00248881 | 1584.24 | 14052.6 | 2502.63 | 510.526 | 14209.5 | 2659.47 | 14052.6 | 2502.63 | 1 | Quart tournant avec marches égales | 16 | Contremarche 27 | 0.248476 | 1584.24 | 1584.24 | ArchiCADQuantities - Hauteur 3D de contremarche: 156.842 mm; Hauteur: 156.842 mm
C-MARCHE-348 | Etage 3 | Lame d'air 275581351 | C-MARCHE-348 | Etage 3 | 6 | Contremarche (Escalier) | ESC-020 | 0.58345 | 10 | 0.00272695 | 1740.49 | 14219.5 | 2669.47 | 343.684 | 14376.3 | 2826.32 | 14219.5 | 2669.47 | 1 | Quart tournant avec marches égales | 17 | Contremarche 27 | 0.272982 | 1740.49 | 1740.49 | ArchiCADQuantities - Hauteur 3D de contremarche: 156.842 mm; Hauteur: 156.842 mm
C-MARCHE-349 | Etage 3 | Lame d'air 275581351 | C-MARCHE-349 | Etage 3 | 6 | Contremarche (Escalier) | ESC-020 | 0.486786 | 10 | 0.00227252 | 1450.88 | 14386.3 | 2836.32 | 176.842 | 14543.2 | 2993.16 | 14386.3 | 2836.32 | 1 | Quart tournant avec marches égales | 18 | Contremarche 27 | 0.227559 | 1450.88 | 1450.88 | ArchiCADQuantities - Hauteur 3D de contremarche: 156.842 mm; Hauteur: 156.842 mm
C-MARCHE-350 | Etage 3 | Lame d'air 275581351 | C-MARCHE-350 | Etage 3 | 6 | Contremarche (Escalier) | ESC-020 | 0.434832 | 10 | 0.00203547 | 1220 | 14553.2 | 3003.16 | 0 | 14720 | 3170 | 14553.2 | 3003.16 | 1 | Inconnu | 19 | Contremarche 27 | 0.203547 | 1220 | 1220 | ArchiCADQuantities - Hauteur 3D de contremarche: 166.842 mm; Hauteur: 166.842 mm
MARCHE-332 | Etage 3 | Lame d'air 275581351 | MARCHE-332 | Etage 3 | 6 | Giron (Escalier) | ESC-020 | 0.777737 | 10 | 0.00373606 |  | 11716.8 | 166.842 | 3003.16 | 11716.8 | 166.842 | 11706.8 | 156.842 | 1 | Quart tournant avec marches égales | 1 | Marche 27 | 0.0122 | 1220 | 1220 | ArchiCADQuantities - Nez de marche: 15 mm; Giron de marche: 281.235 mm; Longueur volée marche: 306.235 mm; Superficie supérieure marche: 0.373606 m2
MARCHE-333 | Etage 3 | Lame d'air 275581351 | MARCHE-333 | Etage 3 | 6 | Giron (Escalier) | ESC-020 | 0.777737 | 10 | 0.00373606 |  | 11883.7 | 333.684 | 2836.32 | 11883.7 | 333.684 | 11873.7 | 323.684 | 1 | Quart tournant avec marches égales | 2 | Marche 27 | 0.0122 | 1220 | 1220 | ArchiCADQuantities - Nez de marche: 15 mm; Giron de marche: 281.235 mm; Longueur volée marche: 306.235 mm; Superficie supérieure marche: 0.373606 m2
MARCHE-334 | Etage 3 | Lame d'air 275581351 | MARCHE-334 | Etage 3 | 6 | Giron (Escalier) | ESC-020 | 0.792158 | 10 | 0.00380409 |  | 12050.5 | 500.526 | 2669.47 | 12050.5 | 500.526 | 12040.5 | 490.526 | 1 | Quart tournant avec marches égales | 3 | Marche 27 | 0.0122 | 1282.83 | 1220 | ArchiCADQuantities - Nez de marche: 15 mm; Giron de marche: 281.235 mm; Longueur volée marche: 306.239 mm; Superficie supérieure marche: 0.380409 m2
MARCHE-335 | Etage 3 | Lame d'air 275581351 | MARCHE-335 | Etage 3 | 6 | Giron (Escalier) | ESC-020 | 1.00939 | 10 | 0.00486899 |  | 12217.4 | 667.368 | 2502.63 | 12217.4 | 667.368 | 12207.4 | 657.368 | 1 | Quart tournant avec marches égales | 4 | Marche 27 | 0.0127075 | 1539.27 | 1270.75 | ArchiCADQuantities - Nez de marche: 15 mm; Giron de marche: 281.235 mm; Longueur volée marche: 306.239 mm; Superficie supérieure marche: 0.486899 m2
C-MARCHE-343 | Etage 3 | Lame d'air 275581351 | C-MARCHE-343 | Etage 3 | 6 | Contremarche (Escalier) | ESC-020 | 0.448537 | 10 | 0.00209277 | 1336.22 | 13385.3 | 1835.26 | 1177.89 | 13542.1 | 1992.11 | 13385.3 | 1835.26 | 1 | Quart tournant avec marches égales | 12 | Contremarche 27 | 0.209575 | 1336.22 | 1336.22 | ArchiCADQuantities - Hauteur 3D de contremarche: 156.842 mm; Hauteur: 156.842 mm
MARCHE-336 | Etage 3 | Lame d'air 275581351 | MARCHE-336 | Etage 3 | 6 | Giron (Escalier) | ESC-020 | 1.37345 | 10 | 0.00665885 |  | 12384.2 | 834.211 | 2335.79 | 12384.2 | 834.211 | 12374.2 | 824.211 | 1 | Quart tournant avec marches égales | 5 | Marche 27 | 0.0152656 | 1785.19 | 1526.56 | ArchiCADQuantities - Nez de marche: 15 mm; Giron de marche: 281.235 mm; Longueur volée marche: 306.239 mm; Superficie supérieure marche: 0.665885 m2
MARCHE-338 | Etage 3 | Lame d'air 275581351 | MARCHE-338 | Etage 3 | 6 | Giron (Escalier) | ESC-020 | 0.937933 | 10 | 0.00451717 |  | 12717.9 | 1167.89 | 2002.11 | 12717.9 | 1167.89 | 12707.9 | 1157.89 | 1 | Quart tournant avec marches égales | 7 | Marche 27 | 0.0148202 | 1231.9 | 1482.02 | ArchiCADQuantities - Nez de marche: 15 mm; Giron de marche: 281.235 mm; Longueur volée marche: 306.239 mm; Superficie supérieure marche: 0.451717 m2
MARCHE-337 | Etage 3 | Lame d'air 275581351 | MARCHE-337 | Etage 3 | 6 | Giron (Escalier) | ESC-020 | 1.31059 | 10 | 0.00634701 |  | 12551.1 | 1001.05 | 2168.95 | 12551.1 | 1001.05 | 12541.1 | 991.053 | 1 | Quart tournant avec marches égales | 6 | Marche 27 | 0.0179515 | 1471.15 | 1795.15 | ArchiCADQuantities - Nez de marche: 15 mm; Giron de marche: 281.235 mm; Longueur volée marche: 306.239 mm; Superficie supérieure marche: 0.634701 m2
MARCHE-339 | Etage 3 | Lame d'air 275581351 | MARCHE-339 | Etage 3 | 6 | Giron (Escalier) | ESC-020 | 0.93012 | 10 | 0.00448091 |  | 12884.7 | 1334.74 | 1835.26 | 12884.7 | 1334.74 | 12874.7 | 1324.74 | 1 | Quart tournant avec marches égales | 8 | Marche 27 | 0.0122095 | 1457.51 | 1220.95 | ArchiCADQuantities - Nez de marche: 15 mm; Giron de marche: 281.235 mm; Longueur volée marche: 306.239 mm; Superficie supérieure marche: 0.448091 m2
MARCHE-340 | Etage 3 | Lame d'air 275581351 | MARCHE-340 | Etage 3 | 6 | Giron (Escalier) | ESC-020 | 1.24412 | 10 | 0.00602141 |  | 13051.6 | 1501.58 | 1668.42 | 13051.6 | 1501.58 | 13041.6 | 1491.58 | 1 | Quart tournant avec marches égales | 9 | Marche 27 | 0.0144553 | 1724.36 | 1445.53 | ArchiCADQuantities - Nez de marche: 15 mm; Giron de marche: 281.235 mm; Longueur volée marche: 306.239 mm; Superficie supérieure marche: 0.602141 m2
MARCHE-341 | Etage 3 | Lame d'air 275581351 | MARCHE-341 | Etage 3 | 6 | Giron (Escalier) | ESC-020 | 1.43938 | 10 | 0.00698745 |  | 13218.4 | 1668.42 | 1501.58 | 13218.4 | 1668.42 | 13208.4 | 1658.42 | 1 | Quart tournant avec marches égales | 10 | Marche 27 | 0.0171289 | 1603.7 | 1712.89 | ArchiCADQuantities - Nez de marche: 15 mm; Giron de marche: 281.235 mm; Longueur volée marche: 306.239 mm; Superficie supérieure marche: 0.698745 m2
MARCHE-342 | Etage 3 | Lame d'air 275581351 | MARCHE-342 | Etage 3 | 6 | Giron (Escalier) | ESC-020 | 1.09551 | 10 | 0.00529115 |  | 13385.3 | 1835.26 | 1334.74 | 13385.3 | 1835.26 | 13375.3 | 1825.26 | 1 | Quart tournant avec marches égales | 11 | Marche 27 | 0.0161356 | 1332.64 | 1613.56 | ArchiCADQuantities - Nez de marche: 15 mm; Giron de marche: 281.235 mm; Longueur volée marche: 306.239 mm; Superficie supérieure marche: 0.529115 m2
MARCHE-343 | Etage 3 | Lame d'air 275581351 | MARCHE-343 | Etage 3 | 6 | Giron (Escalier) | ESC-020 | 0.82433 | 10 | 0.0039606 |  | 13552.1 | 2002.11 | 1167.89 | 13552.1 | 2002.11 | 13542.1 | 1992.11 | 1 | Quart tournant avec marches égales | 12 | Marche 27 | 0.0134239 | 1220 | 1342.39 | ArchiCADQuantities - Nez de marche: 15 mm; Giron de marche: 281.235 mm; Longueur volée marche: 306.235 mm; Superficie supérieure marche: 0.39606 m2
MARCHE-344 | Etage 3 | Lame d'air 275581351 | MARCHE-344 | Etage 3 | 6 | Giron (Escalier) | ESC-020 | 0.777737 | 10 | 0.00373606 |  | 13718.9 | 2168.95 | 1001.05 | 13718.9 | 2168.95 | 13708.9 | 2158.95 | 1 | Quart tournant avec marches égales | 13 | Marche 27 | 0.0122 | 1220 | 1220 | ArchiCADQuantities - Nez de marche: 15 mm; Giron de marche: 281.235 mm; Longueur volée marche: 306.235 mm; Superficie supérieure marche: 0.373606 m2
MARCHE-346 | Etage 3 | Lame d'air 275581351 | MARCHE-346 | Etage 3 | 6 | Giron (Escalier) | ESC-020 | 1.06666 | 10 | 0.0051498 |  | 14052.6 | 2502.63 | 667.368 | 14052.6 | 2502.63 | 14042.6 | 2492.63 | 1 | Quart tournant avec marches égales | 15 | Marche 27 | 0.0131147 | 1589.63 | 1311.47 | ArchiCADQuantities - Nez de marche: 15 mm; Giron de marche: 281.235 mm; Longueur volée marche: 306.239 mm; Superficie supérieure marche: 0.51498 m2
MARCHE-345 | Etage 3 | Lame d'air 275581351 | MARCHE-345 | Etage 3 | 6 | Giron (Escalier) | ESC-020 | 0.811599 | 10 | 0.00389845 |  | 13885.8 | 2335.79 | 834.211 | 13885.8 | 2335.79 | 13875.8 | 2325.79 | 1 | Quart tournant avec marches égales | 14 | Marche 27 | 0.0122 | 1323.8 | 1220 | ArchiCADQuantities - Nez de marche: 15 mm; Giron de marche: 281.235 mm; Longueur volée marche: 306.239 mm; Superficie supérieure marche: 0.389845 m2
MARCHE-347 | Etage 3 | Lame d'air 275581351 | MARCHE-347 | Etage 3 | 6 | Giron (Escalier) | ESC-020 | 1.42404 | 10 | 0.00691099 |  | 14219.5 | 2669.47 | 500.526 | 14219.5 | 2669.47 | 14209.5 | 2659.47 | 1 | Quart tournant avec marches égales | 16 | Marche 27 | 0.0157697 | 1737.05 | 1576.97 | ArchiCADQuantities - Nez de marche: 15 mm; Giron de marche: 281.235 mm; Longueur volée marche: 306.239 mm; Superficie supérieure marche: 0.691099 m2
MARCHE-350 | Etage 3 | Lame d'air 275581351 | MARCHE-350 | Etage 3 | 6 | Giron (Escalier) | ESC-020 | 0.921117 | 10 | 0.00443574 |  | 14553.2 | 3003.16 | 166.842 | 14553.2 | 3003.16 | 14543.2 | 2993.16 | 1 | Quart tournant avec marches égales | 18 | Marche 27 | 0.0145725 | 1220 | 1457.25 | ArchiCADQuantities - Nez de marche: 15 mm; Giron de marche: 281.235 mm; Longueur volée marche: 281.235 mm; Superficie supérieure marche: 0.443574 m2
MARCHE-348 | Etage 3 | Lame d'air 275581351 | MARCHE-348 | Etage 3 | 6 | Giron (Escalier) | ESC-020 | 1.26026 | 10 | 0.00610008 |  | 14386.3 | 2836.32 | 333.684 | 14386.3 | 2836.32 | 14376.3 | 2826.32 | 1 | Quart tournant avec marches égales | 17 | Marche 27 | 0.0174645 | 1447.18 | 1746.45 | ArchiCADQuantities - Nez de marche: 15 mm; Giron de marche: 281.235 mm; Longueur volée marche: 306.239 mm; Superficie supérieure marche: 0.610008 m2
VOLEE-022 | etage 4 | Cloison 274992075 | VOLEE-022 | etage 4 | 7 | Structure (Escalier) | ESC-020 | 23.8304 | 150 | 2.08754 | 1220 | 17470.6 | 2870.56 | 179.444 | 17470.6 | 2870.56 | 14470 | -130 | ArchiCADProperties - Type construction: Monolithique; Type forme: Plat; Position structure escalier: Sous l'escalier; Index volée structure escalier: 1; Matériau de construction / Composite / Profil / Hachure: Cloison 274992075; Matériaux de construction (Tous): Cloison 274992075; ArchiCADQuantities - Épaisseur secondaire: 150 mm; Hauteur 3D de structure d'escalier: 3000.56 mm; Longueur 3D: 6016.72 mm
C-MARCHE-334 | etage 4 | Parpaing 2676271321 | C-MARCHE-334 | etage 4 | 7 | Contremarche (Escalier) | ESC-020 | 0.416633 | 10 | 0.00194522 | 1220 | 14938.9 | 338.889 | 2551.67 | 15098.3 | 498.333 | 14938.9 | 338.889 | 1 | Quart tournant avec marches égales | 3 | Contremarche 27 | 0.194522 | 1220 | 1220 | ArchiCADQuantities - Hauteur 3D de contremarche: 159.444 mm; Hauteur: 159.444 mm; ArchiCADProperties - Surfaces (Toutes): Peinture-11
C-MARCHE-335 | etage 4 | Parpaing 2676271321 | C-MARCHE-335 | etage 4 | 7 | Contremarche (Escalier) | ESC-020 | 0.427095 | 10 | 0.00199428 | 1249.43 | 15108.3 | 508.333 | 2382.22 | 15267.8 | 667.778 | 15108.3 | 508.333 | 1 | Quart tournant avec marches égales | 4 | Contremarche 27 | 0.199215 | 1249.43 | 1249.43 | ArchiCADQuantities - Hauteur 3D de contremarche: 159.444 mm; Hauteur: 159.444 mm; ArchiCADProperties - Surfaces (Toutes): Peinture-11
C-MARCHE-332 | etage 4 | Parpaing 2676271321 | C-MARCHE-332 | etage 4 | 7 | Contremarche (Escalier) | ESC-020 | 0.416633 | 10 | 0.00194522 | 1220 | 14600 | 0 | 2890.56 | 14759.4 | 159.444 | 14600 | 0 | 1 | Quart tournant avec marches égales | 1 | Contremarche 27 | 0.194522 | 1220 | 1220 | ArchiCADQuantities - Hauteur 3D de contremarche: 159.444 mm; Hauteur: 159.444 mm; ArchiCADProperties - Surfaces (Toutes): Peinture-11
C-MARCHE-336 | etage 4 | Parpaing 2676271321 | C-MARCHE-336 | etage 4 | 7 | Contremarche (Escalier) | ESC-020 | 0.513301 | 10 | 0.00239859 | 1500.73 | 15277.8 | 677.778 | 2212.78 | 15437.2 | 837.222 | 15277.8 | 677.778 | 1 | Quart tournant avec marches égales | 5 | Contremarche 27 | 0.239284 | 1500.73 | 1500.73 | ArchiCADQuantities - Hauteur 3D de contremarche: 159.444 mm; Hauteur: 159.444 mm; ArchiCADProperties - Surfaces (Toutes): Peinture-11
C-MARCHE-337 | etage 4 | Parpaing 2676271321 | C-MARCHE-337 | etage 4 | 7 | Contremarche (Escalier) | ESC-020 | 0.519602 | 10 | 0.00242797 | 1525.93 | 15447.2 | 847.222 | 2043.33 | 15606.7 | 1006.67 | 15447.2 | 847.222 | 1 | Quart tournant avec marches égales | 6 | Contremarche 27 | 0.243301 | 1525.93 | 1525.93 | ArchiCADQuantities - Hauteur 3D de contremarche: 159.444 mm; Hauteur: 159.444 mm; ArchiCADProperties - Surfaces (Toutes): Peinture-11
C-MARCHE-338 | etage 4 | Parpaing 2676271321 | C-MARCHE-338 | etage 4 | 7 | Contremarche (Escalier) | ESC-020 | 0.427779 | 10 | 0.00199743 | 1253.55 | 15616.7 | 1016.67 | 1873.89 | 15776.1 | 1176.11 | 15616.7 | 1016.67 | 1 | Quart tournant avec marches égales | 7 | Contremarche 27 | 0.199871 | 1253.55 | 1253.55 | ArchiCADQuantities - Hauteur 3D de contremarche: 159.444 mm; Hauteur: 159.444 mm; ArchiCADProperties - Surfaces (Toutes): Peinture-11
C-MARCHE-333 | etage 4 | Parpaing 2676271321 | C-MARCHE-333 | etage 4 | 7 | Contremarche (Escalier) | ESC-020 | 0.416633 | 10 | 0.00194522 | 1220 | 14769.4 | 169.444 | 2721.11 | 14928.9 | 328.889 | 14769.4 | 169.444 | 1 | Quart tournant avec marches égales | 2 | Contremarche 27 | 0.194522 | 1220 | 1220 | ArchiCADQuantities - Hauteur 3D de contremarche: 159.444 mm; Hauteur: 159.444 mm; ArchiCADProperties - Surfaces (Toutes): Peinture-11
C-MARCHE-339 | etage 4 | Parpaing 2676271321 | C-MARCHE-339 | etage 4 | 7 | Contremarche (Escalier) | ESC-020 | 0.423162 | 10 | 0.00197583 | 1238.04 | 15786.1 | 1186.11 | 1704.44 | 15945.6 | 1345.56 | 15786.1 | 1186.11 | 1 | Quart tournant avec marches égales | 8 | Contremarche 27 | 0.197398 | 1238.04 | 1238.04 | ArchiCADQuantities - Hauteur 3D de contremarche: 159.444 mm; Hauteur: 159.444 mm; ArchiCADProperties - Surfaces (Toutes): Peinture-11
C-MARCHE-342 | etage 4 | Parpaing 2676271321 | C-MARCHE-342 | etage 4 | 7 | Contremarche (Escalier) | ESC-020 | 0.432726 | 10 | 0.00202064 | 1268.29 | 16294.4 | 1694.44 | 1196.11 | 16453.9 | 1853.89 | 16294.4 | 1694.44 | 1 | Quart tournant avec marches égales | 11 | Contremarche 27 | 0.202221 | 1268.29 | 1268.29 | ArchiCADQuantities - Hauteur 3D de contremarche: 159.444 mm; Hauteur: 159.444 mm; ArchiCADProperties - Surfaces (Toutes): Peinture-11
C-MARCHE-343 | etage 4 | Parpaing 2676271321 | C-MARCHE-343 | etage 4 | 7 | Contremarche (Escalier) | ESC-020 | 0.416633 | 10 | 0.00194522 | 1220 | 16463.9 | 1863.89 | 1026.67 | 16623.3 | 2023.33 | 16463.9 | 1863.89 | 1 | Quart tournant avec marches égales | 12 | Contremarche 27 | 0.194522 | 1220 | 1220 | ArchiCADQuantities - Hauteur 3D de contremarche: 159.444 mm; Hauteur: 159.444 mm; ArchiCADProperties - Surfaces (Toutes): Peinture-11
C-MARCHE-341 | etage 4 | Parpaing 2676271321 | C-MARCHE-341 | etage 4 | 7 | Contremarche (Escalier) | ESC-020 | 0.535374 | 10 | 0.00250195 | 1572.59 | 16125 | 1525 | 1365.56 | 16284.4 | 1684.44 | 16125 | 1525 | 1 | Quart tournant avec marches égales | 10 | Contremarche 27 | 0.250741 | 1572.59 | 1572.59 | ArchiCADQuantities - Hauteur 3D de contremarche: 159.444 mm; Hauteur: 159.444 mm; ArchiCADProperties - Surfaces (Toutes): Peinture-11
C-MARCHE-340 | etage 4 | Parpaing 2676271321 | C-MARCHE-340 | etage 4 | 7 | Contremarche (Escalier) | ESC-020 | 0.499875 | 10 | 0.00233561 | 1461.48 | 15955.6 | 1355.56 | 1535 | 16115 | 1515 | 15955.6 | 1355.56 | 1 | Quart tournant avec marches égales | 9 | Contremarche 27 | 0.233024 | 1461.48 | 1461.48 | ArchiCADQuantities - Hauteur 3D de contremarche: 159.444 mm; Hauteur: 159.444 mm; ArchiCADProperties - Surfaces (Toutes): Peinture-11
C-MARCHE-346 | etage 4 | Parpaing 2676271321 | C-MARCHE-346 | etage 4 | 7 | Contremarche (Escalier) | ESC-020 | 0.506145 | 10 | 0.00236503 | 1479.82 | 16972.2 | 2372.22 | 518.333 | 17131.7 | 2531.67 | 16972.2 | 2372.22 | 1 | Quart tournant avec marches égales | 15 | Contremarche 27 | 0.235949 | 1479.82 | 1479.82 | ArchiCADQuantities - Hauteur 3D de contremarche: 159.444 mm; Hauteur: 159.444 mm; ArchiCADProperties - Surfaces (Toutes): Peinture-11
C-MARCHE-345 | etage 4 | Parpaing 2676271321 | C-MARCHE-345 | etage 4 | 7 | Contremarche (Escalier) | ESC-020 | 0.425234 | 10 | 0.00198555 | 1244.06 | 16802.8 | 2202.78 | 687.778 | 16962.2 | 2362.22 | 16802.8 | 2202.78 | 1 | Quart tournant avec marches égales | 14 | Contremarche 27 | 0.198358 | 1244.06 | 1244.06 | ArchiCADQuantities - Hauteur 3D de contremarche: 159.444 mm; Hauteur: 159.444 mm; ArchiCADProperties - Surfaces (Toutes): Peinture-11
C-MARCHE-347 | etage 4 | Parpaing 2676271321 | C-MARCHE-347 | etage 4 | 7 | Contremarche (Escalier) | ESC-020 | 0.52882 | 10 | 0.00247121 | 1553.2 | 17141.7 | 2541.67 | 348.889 | 17301.1 | 2701.11 | 17141.7 | 2541.67 | 1 | Quart tournant avec marches égales | 16 | Contremarche 27 | 0.247649 | 1553.2 | 1553.2 | ArchiCADQuantities - Hauteur 3D de contremarche: 159.444 mm; Hauteur: 159.444 mm; ArchiCADProperties - Surfaces (Toutes): Peinture-11
C-MARCHE-344 | etage 4 | Parpaing 2676271321 | C-MARCHE-344 | etage 4 | 7 | Contremarche (Escalier) | ESC-020 | 0.416633 | 10 | 0.00194522 | 1220 | 16633.3 | 2033.33 | 857.222 | 16792.8 | 2192.78 | 16633.3 | 2033.33 | 1 | Quart tournant avec marches égales | 13 | Contremarche 27 | 0.194522 | 1220 | 1220 | ArchiCADQuantities - Hauteur 3D de contremarche: 159.444 mm; Hauteur: 159.444 mm; ArchiCADProperties - Surfaces (Toutes): Peinture-11
MARCHE-334 | etage 4 | Lame d'air 275581351 | MARCHE-334 | etage 4 | 7 | Giron (Escalier) | ESC-020 | 0.856816 | 10 | 0.0041267 |  | 15108.3 | 508.333 | 2541.67 | 15108.3 | 508.333 | 15098.3 | 498.333 | 1 | Quart tournant avec marches égales | 3 | Marche 27 | 0.0122 | 1252.36 | 1220 | ArchiCADQuantities - Nez de marche: 15 mm; Giron de marche: 310.727 mm; Longueur volée marche: 335.731 mm; Superficie supérieure marche: 0.41267 m2
C-MARCHE-348 | etage 4 | Parpaing 2676271321 | C-MARCHE-348 | etage 4 | 7 | Contremarche (Escalier) | ESC-020 | 0.430867 | 10 | 0.00201192 | 1262.74 | 17311.1 | 2711.11 | 179.444 | 17470.6 | 2870.56 | 17311.1 | 2711.11 | 1 | Quart tournant avec marches égales | 17 | Contremarche 27 | 0.201337 | 1262.74 | 1262.74 | ArchiCADQuantities - Hauteur 3D de contremarche: 159.444 mm; Hauteur: 159.444 mm; ArchiCADProperties - Surfaces (Toutes): Peinture-11
MARCHE-333 | etage 4 | Lame d'air 275581351 | MARCHE-333 | etage 4 | 7 | Giron (Escalier) | ESC-020 | 0.850289 | 10 | 0.00409587 |  | 14938.9 | 338.889 | 2711.11 | 14938.9 | 338.889 | 14928.9 | 328.889 | 1 | Quart tournant avec marches égales | 2 | Marche 27 | 0.0122 | 1220 | 1220 | ArchiCADQuantities - Nez de marche: 15 mm; Giron de marche: 310.727 mm; Longueur volée marche: 335.727 mm; Superficie supérieure marche: 0.409587 m2
C-MARCHE-349 | etage 4 | Parpaing 2676271321 | C-MARCHE-349 | etage 4 | 7 | Contremarche (Escalier) | ESC-020 | 0.441233 | 10 | 0.00206722 | 1220 | 17480.6 | 2880.56 | 0 | 17650 | 3050 | 17480.6 | 2880.56 | 1 | Inconnu | 18 | Contremarche 27 | 0.206722 | 1220 | 1220 | ArchiCADQuantities - Hauteur 3D de contremarche: 169.444 mm; Hauteur: 169.444 mm; ArchiCADProperties - Surfaces (Toutes): Peinture-11
MARCHE-332 | etage 4 | Lame d'air 275581351 | MARCHE-332 | etage 4 | 7 | Giron (Escalier) | ESC-020 | 0.850289 | 10 | 0.00409587 |  | 14769.4 | 169.444 | 2880.56 | 14769.4 | 169.444 | 14759.4 | 159.444 | 1 | Quart tournant avec marches égales | 1 | Marche 27 | 0.0122 | 1220 | 1220 | ArchiCADQuantities - Nez de marche: 15 mm; Giron de marche: 310.727 mm; Longueur volée marche: 335.727 mm; Superficie supérieure marche: 0.409587 m2
MARCHE-336 | etage 4 | Lame d'air 275581351 | MARCHE-336 | etage 4 | 7 | Giron (Escalier) | ESC-020 | 1.41147 | 10 | 0.00685407 |  | 15447.2 | 847.222 | 2202.78 | 15447.2 | 847.222 | 15437.2 | 837.222 | 1 | Quart tournant avec marches égales | 5 | Marche 27 | 0.0149048 | 1519.87 | 1490.48 | ArchiCADQuantities - Nez de marche: 15 mm; Giron de marche: 310.727 mm; Longueur volée marche: 335.731 mm; Superficie supérieure marche: 0.685407 m2
MARCHE-337 | etage 4 | Lame d'air 275581351 | MARCHE-337 | etage 4 | 7 | Giron (Escalier) | ESC-020 | 1.02964 | 10 | 0.00496903 |  | 15616.7 | 1016.67 | 2033.33 | 15616.7 | 1016.67 | 15606.7 | 1006.67 | 1 | Quart tournant avec marches égales | 6 | Marche 27 | 0.0153597 | 1252.2 | 1535.97 | ArchiCADQuantities - Nez de marche: 15 mm; Giron de marche: 310.727 mm; Longueur volée marche: 335.731 mm; Superficie supérieure marche: 0.496903 m2
MARCHE-339 | etage 4 | Lame d'air 275581351 | MARCHE-339 | etage 4 | 7 | Giron (Escalier) | ESC-020 | 0.979664 | 10 | 0.00472531 |  | 15955.6 | 1355.56 | 1694.44 | 15955.6 | 1355.56 | 15945.6 | 1345.56 | 1 | Quart tournant avec marches égales | 8 | Marche 27 | 0.0123513 | 1468.46 | 1235.13 | ArchiCADQuantities - Nez de marche: 15 mm; Giron de marche: 310.727 mm; Longueur volée marche: 335.731 mm; Superficie supérieure marche: 0.472531 m2
MARCHE-341 | etage 4 | Lame d'air 275581351 | MARCHE-341 | etage 4 | 7 | Giron (Escalier) | ESC-020 | 1.06732 | 10 | 0.00515312 |  | 16294.4 | 1694.44 | 1355.56 | 16294.4 | 1694.44 | 16284.4 | 1684.44 | 1 | Quart tournant avec marches égales | 10 | Marche 27 | 0.0158342 | 1266.57 | 1583.42 | ArchiCADQuantities - Nez de marche: 15 mm; Giron de marche: 310.727 mm; Longueur volée marche: 335.731 mm; Superficie supérieure marche: 0.515312 m2
MARCHE-342 | etage 4 | Lame d'air 275581351 | MARCHE-342 | etage 4 | 7 | Giron (Escalier) | ESC-020 | 0.86406 | 10 | 0.00416169 |  | 16463.9 | 1863.89 | 1186.11 | 16463.9 | 1863.89 | 16453.9 | 1853.89 | 1 | Quart tournant avec marches égales | 11 | Marche 27 | 0.0127181 | 1220 | 1271.81 | ArchiCADQuantities - Nez de marche: 15 mm; Giron de marche: 310.727 mm; Longueur volée marche: 335.727 mm; Superficie supérieure marche: 0.416169 m2
MARCHE-338 | etage 4 | Lame d'air 275581351 | MARCHE-338 | etage 4 | 7 | Giron (Escalier) | ESC-020 | 0.860493 | 10 | 0.00414368 |  | 15786.1 | 1186.11 | 1863.89 | 15786.1 | 1186.11 | 15776.1 | 1176.11 | 1 | Quart tournant avec marches égales | 7 | Marche 27 | 0.0125652 | 1240.61 | 1256.52 | ArchiCADQuantities - Nez de marche: 15 mm; Giron de marche: 310.727 mm; Longueur volée marche: 335.731 mm; Superficie supérieure marche: 0.414368 m2
MARCHE-335 | etage 4 | Lame d'air 275581351 | MARCHE-335 | etage 4 | 7 | Giron (Escalier) | ESC-020 | 1.00989 | 10 | 0.00487295 |  | 15277.8 | 677.778 | 2372.22 | 15277.8 | 677.778 | 15267.8 | 667.778 | 1 | Quart tournant avec marches égales | 4 | Marche 27 | 0.0124599 | 1508.2 | 1245.99 | ArchiCADQuantities - Nez de marche: 15 mm; Giron de marche: 310.727 mm; Longueur volée marche: 335.731 mm; Superficie supérieure marche: 0.487295 m2
MARCHE-343 | etage 4 | Lame d'air 275581351 | MARCHE-343 | etage 4 | 7 | Giron (Escalier) | ESC-020 | 0.850289 | 10 | 0.00409587 |  | 16633.3 | 2033.33 | 1016.67 | 16633.3 | 2033.33 | 16623.3 | 2023.33 | 1 | Quart tournant avec marches égales | 12 | Marche 27 | 0.0122 | 1220 | 1220 | ArchiCADQuantities - Nez de marche: 15 mm; Giron de marche: 310.727 mm; Longueur volée marche: 335.727 mm; Superficie supérieure marche: 0.409587 m2
MARCHE-344 | etage 4 | Lame d'air 275581351 | MARCHE-344 | etage 4 | 7 | Giron (Escalier) | ESC-020 | 0.855182 | 10 | 0.00411886 |  | 16802.8 | 2202.78 | 847.222 | 16802.8 | 2202.78 | 16792.8 | 2192.78 | 1 | Quart tournant avec marches égales | 13 | Marche 27 | 0.0122 | 1246.79 | 1220 | ArchiCADQuantities - Nez de marche: 15 mm; Giron de marche: 310.727 mm; Longueur volée marche: 335.731 mm; Superficie supérieure marche: 0.411886 m2
MARCHE-345 | etage 4 | Lame d'air 275581351 | MARCHE-345 | etage 4 | 7 | Giron (Escalier) | ESC-020 | 0.994208 | 10 | 0.00479638 |  | 16972.2 | 2372.22 | 677.778 | 16972.2 | 2372.22 | 16962.2 | 2362.22 | 1 | Quart tournant avec marches égales | 14 | Marche 27 | 0.0124091 | 1487.02 | 1240.91 | ArchiCADQuantities - Nez de marche: 15 mm; Giron de marche: 310.727 mm; Longueur volée marche: 335.731 mm; Superficie supérieure marche: 0.479638 m2
MARCHE-347 | etage 4 | Lame d'air 275581351 | MARCHE-347 | etage 4 | 7 | Giron (Escalier) | ESC-020 | 1.05199 | 10 | 0.00507826 |  | 17311.1 | 2711.11 | 338.889 | 17311.1 | 2711.11 | 17301.1 | 2701.11 | 1 | Quart tournant avec marches égales | 16 | Marche 27 | 0.0156368 | 1261.18 | 1563.68 | ArchiCADQuantities - Nez de marche: 15 mm; Giron de marche: 310.727 mm; Longueur volée marche: 335.731 mm; Superficie supérieure marche: 0.507826 m2
MARCHE-346 | etage 4 | Lame d'air 275581351 | MARCHE-346 | etage 4 | 7 | Giron (Escalier) | ESC-020 | 1.41049 | 10 | 0.00684895 |  | 17141.7 | 2541.67 | 508.333 | 17141.7 | 2541.67 | 17131.7 | 2531.67 | 1 | Quart tournant avec marches égales | 15 | Marche 27 | 0.0146997 | 1546.84 | 1469.97 | ArchiCADQuantities - Nez de marche: 15 mm; Giron de marche: 310.727 mm; Longueur volée marche: 335.731 mm; Superficie supérieure marche: 0.684895 m2
MARCHE-348 | etage 4 | Lame d'air 275581351 | MARCHE-348 | etage 4 | 7 | Giron (Escalier) | ESC-020 | 0.861863 | 10 | 0.00415106 |  | 17480.6 | 2880.56 | 169.444 | 17480.6 | 2880.56 | 17470.6 | 2870.56 | 1 | Quart tournant avec marches égales | 17 | Marche 27 | 0.0126603 | 1220 | 1266.03 | ArchiCADQuantities - Nez de marche: 15 mm; Giron de marche: 310.727 mm; Longueur volée marche: 310.727 mm; Superficie supérieure marche: 0.415106 m2
MARCHE-340 | etage 4 | Lame d'air 275581351 | MARCHE-340 | etage 4 | 7 | Giron (Escalier) | ESC-020 | 1.40265 | 10 | 0.00680994 |  | 16125 | 1525 | 1525 | 16125 | 1525 | 16115 | 1515 | 1 | Quart tournant avec marches égales | 9 | Marche 27 | 0.0145195 | 1566 | 1451.95 | ArchiCADQuantities - Nez de marche: 15 mm; Giron de marche: 310.727 mm; Longueur volée marche: 335.731 mm; Superficie supérieure marche: 0.680994 m2
SS - 024 | Etage 5 | Isolant styromousse 288701002 | SS - 024 | Etage 5 | 8 | Structure (Escalier) | ESC-021 | 2.69233 | 200 | 0.024393 | 20 | 20548.4 | 2898.42 | 171.579 | 20776.9 | 3126.89 | 17640.9 | -9.08071 |  |  |  | Limon de volée 27 | ArchiCADProperties - Type construction: Limons; Type forme: Droit; Position structure escalier: Gauche; Index volée structure escalier: 1; Surfaces (Toutes): Innvik Tex Stripe 1440; LxH de profil: 0,02×0,20; Nom de zone liée: Terrasse; Numéro de zone liée: B52; ArchiCADQuantities - Épaisseur secondaire: 200 mm; Hauteur 3D de structure d'escalier: 3135.97 mm; Longueur 3D: 6098.24 mm; Largeur de profil: 20 mm; Hauteur de profil: 200 mm
SS - 024 | Etage 5 | Isolant styromousse 288701002 | SS - 024 | Etage 5 | 8 | Structure (Escalier) | ESC-021 | 2.69233 | 200 | 0.024393 | 20 | 20548.4 | 2898.42 | 171.579 | 20776.9 | 3126.89 | 17640.9 | -9.08071 |  |  |  | Limon de volée 27 | ArchiCADProperties - Type construction: Limons; Type forme: Droit; Position structure escalier: Droite; Index volée structure escalier: 1; Surfaces (Toutes): Innvik Tex Stripe 1440; LxH de profil: 0,02×0,20; Nom de zone liée: Terrasse; Numéro de zone liée: B52; ArchiCADQuantities - Épaisseur secondaire: 200 mm; Hauteur 3D de structure d'escalier: 3135.97 mm; Longueur 3D: 6098.24 mm; Largeur de profil: 20 mm; Hauteur de profil: 200 mm
MARCHE-351 | Etage 5 | Lame d'air 275581351 | MARCHE-351 | Etage 5 | 8 | Giron (Escalier) | ESC-021 | 0.651811 | 10 | 0.00312778 |  | 17973.2 | 323.158 | 2746.84 | 17973.2 | 323.158 | 17963.2 | 313.158 | 1 | Volée | 2 | Marche 27 | 0.01 | 1000 | 1000 | ArchiCADQuantities - Nez de marche: 15 mm; Giron de marche: 297.778 mm; Longueur volée marche: 312.778 mm; Superficie supérieure marche: 0.312778 m2; ArchiCADProperties - Surfaces (Toutes): Bois-Chêne; Nom de zone liée: Terrasse; Numéro de zone liée: B52
MARCHE-350 | Etage 5 | Lame d'air 275581351 | MARCHE-350 | Etage 5 | 8 | Giron (Escalier) | ESC-021 | 0.651811 | 10 | 0.00312778 |  | 17811.6 | 161.579 | 2908.42 | 17811.6 | 161.579 | 17801.6 | 151.579 | 1 | Volée | 1 | Marche 27 | 0.01 | 1000 | 1000 | ArchiCADQuantities - Nez de marche: 15 mm; Giron de marche: 297.778 mm; Longueur volée marche: 312.778 mm; Superficie supérieure marche: 0.312778 m2; ArchiCADProperties - Surfaces (Toutes): Bois-Chêne; Nom de zone liée: Terrasse; Numéro de zone liée: B52
MARCHE-352 | Etage 5 | Lame d'air 275581351 | MARCHE-352 | Etage 5 | 8 | Giron (Escalier) | ESC-021 | 0.651811 | 10 | 0.00312778 |  | 18134.7 | 484.737 | 2585.26 | 18134.7 | 484.737 | 18124.7 | 474.737 | 1 | Volée | 3 | Marche 27 | 0.01 | 1000 | 1000 | ArchiCADQuantities - Nez de marche: 15 mm; Giron de marche: 297.778 mm; Longueur volée marche: 312.778 mm; Superficie supérieure marche: 0.312778 m2; ArchiCADProperties - Surfaces (Toutes): Bois-Chêne; Nom de zone liée: Terrasse; Numéro de zone liée: B52
MARCHE-353 | Etage 5 | Lame d'air 275581351 | MARCHE-353 | Etage 5 | 8 | Giron (Escalier) | ESC-021 | 0.651811 | 10 | 0.00312778 |  | 18296.3 | 646.316 | 2423.68 | 18296.3 | 646.316 | 18286.3 | 636.316 | 1 | Volée | 4 | Marche 27 | 0.01 | 1000 | 1000 | ArchiCADQuantities - Nez de marche: 15 mm; Giron de marche: 297.778 mm; Longueur volée marche: 312.778 mm; Superficie supérieure marche: 0.312778 m2; ArchiCADProperties - Surfaces (Toutes): Bois-Chêne; Nom de zone liée: Terrasse; Numéro de zone liée: B52
MARCHE-355 | Etage 5 | Lame d'air 275581351 | MARCHE-355 | Etage 5 | 8 | Giron (Escalier) | ESC-021 | 0.651811 | 10 | 0.00312778 |  | 18619.5 | 969.474 | 2100.53 | 18619.5 | 969.474 | 18609.5 | 959.474 | 1 | Volée | 6 | Marche 27 | 0.01 | 1000 | 1000 | ArchiCADQuantities - Nez de marche: 15 mm; Giron de marche: 297.778 mm; Longueur volée marche: 312.778 mm; Superficie supérieure marche: 0.312778 m2; ArchiCADProperties - Surfaces (Toutes): Bois-Chêne; Nom de zone liée: Terrasse; Numéro de zone liée: B52
MARCHE-357 | Etage 5 | Lame d'air 275581351 | MARCHE-357 | Etage 5 | 8 | Giron (Escalier) | ESC-021 | 0.651811 | 10 | 0.00312778 |  | 18942.6 | 1292.63 | 1777.37 | 18942.6 | 1292.63 | 18932.6 | 1282.63 | 1 | Volée | 8 | Marche 27 | 0.01 | 1000 | 1000 | ArchiCADQuantities - Nez de marche: 15 mm; Giron de marche: 297.778 mm; Longueur volée marche: 312.778 mm; Superficie supérieure marche: 0.312778 m2; ArchiCADProperties - Surfaces (Toutes): Bois-Chêne; Nom de zone liée: Terrasse; Numéro de zone liée: B52
MARCHE-356 | Etage 5 | Lame d'air 275581351 | MARCHE-356 | Etage 5 | 8 | Giron (Escalier) | ESC-021 | 0.651811 | 10 | 0.00312778 |  | 18781.1 | 1131.05 | 1938.95 | 18781.1 | 1131.05 | 18771.1 | 1121.05 | 1 | Volée | 7 | Marche 27 | 0.01 | 1000 | 1000 | ArchiCADQuantities - Nez de marche: 15 mm; Giron de marche: 297.778 mm; Longueur volée marche: 312.778 mm; Superficie supérieure marche: 0.312778 m2; ArchiCADProperties - Surfaces (Toutes): Bois-Chêne; Nom de zone liée: Terrasse; Numéro de zone liée: B52
MARCHE-354 | Etage 5 | Lame d'air 275581351 | MARCHE-354 | Etage 5 | 8 | Giron (Escalier) | ESC-021 | 0.651811 | 10 | 0.00312778 |  | 18457.9 | 807.895 | 2262.11 | 18457.9 | 807.895 | 18447.9 | 797.895 | 1 | Volée | 5 | Marche 27 | 0.01 | 1000 | 1000 | ArchiCADQuantities - Nez de marche: 15 mm; Giron de marche: 297.778 mm; Longueur volée marche: 312.778 mm; Superficie supérieure marche: 0.312778 m2; ArchiCADProperties - Surfaces (Toutes): Bois-Chêne; Nom de zone liée: Terrasse; Numéro de zone liée: B52
MARCHE-358 | Etage 5 | Lame d'air 275581351 | MARCHE-358 | Etage 5 | 8 | Giron (Escalier) | ESC-021 | 0.651811 | 10 | 0.00312778 |  | 19104.2 | 1454.21 | 1615.79 | 19104.2 | 1454.21 | 19094.2 | 1444.21 | 1 | Volée | 9 | Marche 27 | 0.01 | 1000 | 1000 | ArchiCADQuantities - Nez de marche: 15 mm; Giron de marche: 297.778 mm; Longueur volée marche: 312.778 mm; Superficie supérieure marche: 0.312778 m2; ArchiCADProperties - Surfaces (Toutes): Bois-Chêne; Nom de zone liée: Terrasse; Numéro de zone liée: B52
MARCHE-360 | Etage 5 | Lame d'air 275581351 | MARCHE-360 | Etage 5 | 8 | Giron (Escalier) | ESC-021 | 0.651811 | 10 | 0.00312778 |  | 19427.4 | 1777.37 | 1292.63 | 19427.4 | 1777.37 | 19417.4 | 1767.37 | 1 | Volée | 11 | Marche 27 | 0.01 | 1000 | 1000 | ArchiCADQuantities - Nez de marche: 15 mm; Giron de marche: 297.778 mm; Longueur volée marche: 312.778 mm; Superficie supérieure marche: 0.312778 m2; ArchiCADProperties - Surfaces (Toutes): Bois-Chêne; Nom de zone liée: Terrasse; Numéro de zone liée: B52
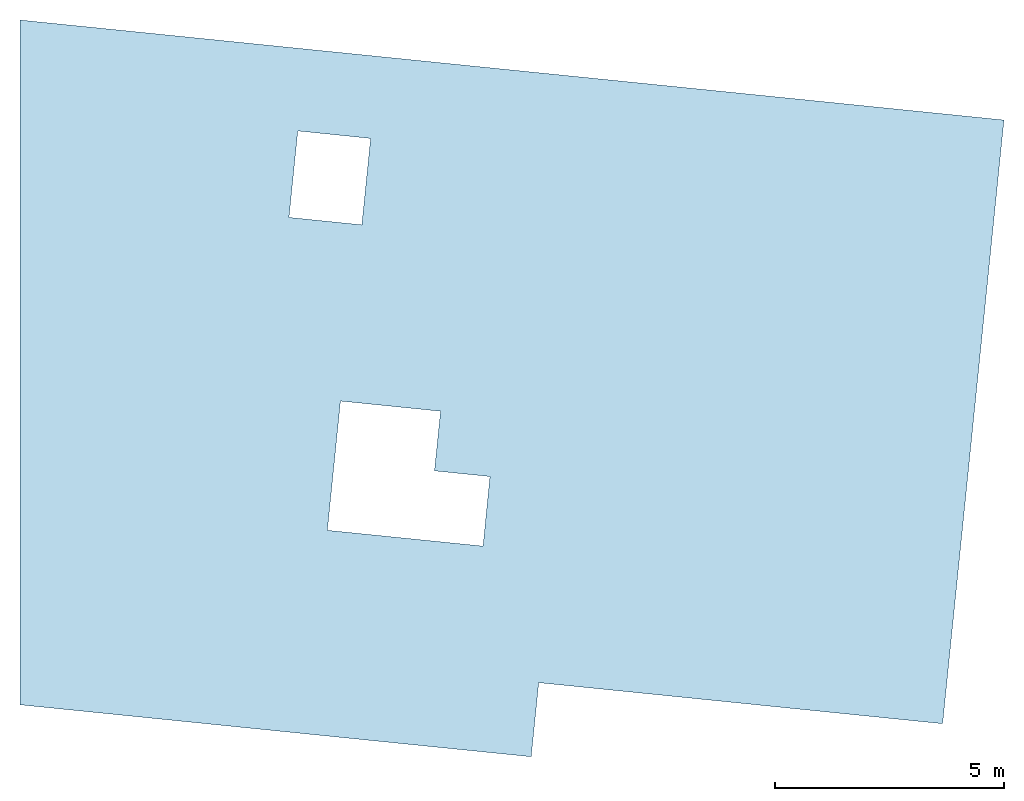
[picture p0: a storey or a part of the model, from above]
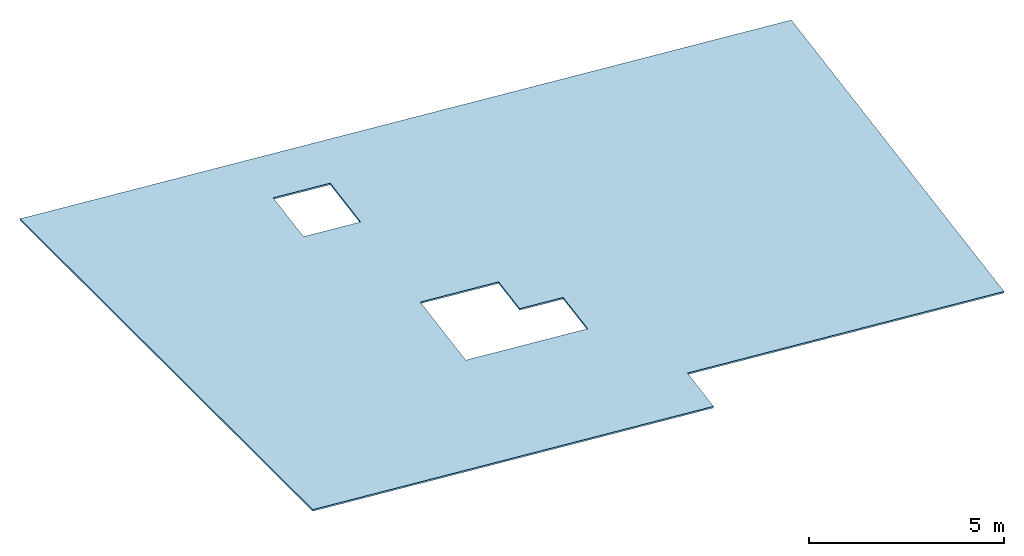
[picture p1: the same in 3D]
Properties of the parts of a building model (IFC2X3), part 9 of 44

# IfcBuildingElementProxy: IfcBuildingElementProxy (404)
Name | In | Material | ID de l'élément = Lien et ID d'élément | Nom d'étage d'implantation | Numéro d'étage d'implantation | Type d'élément | ID de Parent | Superficie totale (m2) = Superficie en plan (m2) = Superficie inférieure (nette) (m2) | Épaisseur (mm) | Volume (net) (m3) | Largeur (mm) | Altitude à Zéro du Projet (mm) = Altitude de Référence Niveau 1 (mm) = Altitude de Référence Niveau 2 (mm) = Altitude à niveau de la mer (mm) | Altitude à étage lié/étage d'implantation (mm) = Décalage étage d'implantation (mm) | Décalage supérieur (mm) | Altitude supérieure à premier niveau de référence (mm) = Altitude supérieure à Zéro du projet (mm) = Altitude supérieure à niveau de la mer (mm) = Altitude supérieure à deuxième niveau de référence (mm) | Altitude supérieure à étage d'implantation (mm) | Altitude inférieure à premier niveau de référence (mm) = Altitude inférieure à Zéro du projet (mm) = Altitude inférieure à niveau de la mer (mm) = Altitude inférieure à deuxième niveau de référence (mm) | Altitude inférieure à étage d'implantation (mm) | Index volée | Type de segment | Index de marche | Nom Élément de Bibliothèque | Superficie avant (m2) | Largeur arrière (mm) | Largeur avant (mm)
MARCHE-361 | Etage 5 | Lame d'air 275581351 | MARCHE-361 | Etage 5 | 8 | Giron (Escalier) | ESC-021 | 0.651811 | 10 | 0.00312778 |  | 19588.9 | 1938.95 | 1131.05 | 19588.9 | 1938.95 | 19578.9 | 1928.95 | 1 | Volée | 12 | Marche 27 | 0.01 | 1000 | 1000 | ArchiCADQuantities - Nez de marche: 15 mm; Giron de marche: 297.778 mm; Longueur volée marche: 312.778 mm; Superficie supérieure marche: 0.312778 m2; ArchiCADProperties - Surfaces (Toutes): Bois-Chêne; Nom de zone liée: Terrasse; Numéro de zone liée: B52
MARCHE-359 | Etage 5 | Lame d'air 275581351 | MARCHE-359 | Etage 5 | 8 | Giron (Escalier) | ESC-021 | 0.651811 | 10 | 0.00312778 |  | 19265.8 | 1615.79 | 1454.21 | 19265.8 | 1615.79 | 19255.8 | 1605.79 | 1 | Volée | 10 | Marche 27 | 0.01 | 1000 | 1000 | ArchiCADQuantities - Nez de marche: 15 mm; Giron de marche: 297.778 mm; Longueur volée marche: 312.778 mm; Superficie supérieure marche: 0.312778 m2; ArchiCADProperties - Surfaces (Toutes): Bois-Chêne; Nom de zone liée: Terrasse; Numéro de zone liée: B52
MARCHE-362 | Etage 5 | Lame d'air 275581351 | MARCHE-362 | Etage 5 | 8 | Giron (Escalier) | ESC-021 | 0.651811 | 10 | 0.00312778 |  | 19750.5 | 2100.53 | 969.474 | 19750.5 | 2100.53 | 19740.5 | 2090.53 | 1 | Volée | 13 | Marche 27 | 0.01 | 1000 | 1000 | ArchiCADQuantities - Nez de marche: 15 mm; Giron de marche: 297.778 mm; Longueur volée marche: 312.778 mm; Superficie supérieure marche: 0.312778 m2; ArchiCADProperties - Surfaces (Toutes): Bois-Chêne; Nom de zone liée: Terrasse; Numéro de zone liée: B52
MARCHE-364 | Etage 5 | Lame d'air 275581351 | MARCHE-364 | Etage 5 | 8 | Giron (Escalier) | ESC-021 | 0.651811 | 10 | 0.00312778 |  | 20073.7 | 2423.68 | 646.316 | 20073.7 | 2423.68 | 20063.7 | 2413.68 | 1 | Volée | 15 | Marche 27 | 0.01 | 1000 | 1000 | ArchiCADQuantities - Nez de marche: 15 mm; Giron de marche: 297.778 mm; Longueur volée marche: 312.778 mm; Superficie supérieure marche: 0.312778 m2; ArchiCADProperties - Surfaces (Toutes): Bois-Chêne; Nom de zone liée: Terrasse; Numéro de zone liée: B52
MARCHE-365 | Etage 5 | Lame d'air 275581351 | MARCHE-365 | Etage 5 | 8 | Giron (Escalier) | ESC-021 | 0.651811 | 10 | 0.00312778 |  | 20235.3 | 2585.26 | 484.737 | 20235.3 | 2585.26 | 20225.3 | 2575.26 | 1 | Volée | 16 | Marche 27 | 0.01 | 1000 | 1000 | ArchiCADQuantities - Nez de marche: 15 mm; Giron de marche: 297.778 mm; Longueur volée marche: 312.778 mm; Superficie supérieure marche: 0.312778 m2; ArchiCADProperties - Surfaces (Toutes): Bois-Chêne; Nom de zone liée: Terrasse; Numéro de zone liée: B52
MARCHE-366 | Etage 5 | Lame d'air 275581351 | MARCHE-366 | Etage 5 | 8 | Giron (Escalier) | ESC-021 | 0.651811 | 10 | 0.00312778 |  | 20396.8 | 2746.84 | 323.158 | 20396.8 | 2746.84 | 20386.8 | 2736.84 | 1 | Volée | 17 | Marche 27 | 0.01 | 1000 | 1000 | ArchiCADQuantities - Nez de marche: 15 mm; Giron de marche: 297.778 mm; Longueur volée marche: 312.778 mm; Superficie supérieure marche: 0.312778 m2; ArchiCADProperties - Surfaces (Toutes): Bois-Chêne; Nom de zone liée: Terrasse; Numéro de zone liée: B52
MARCHE-367 | Etage 5 | Lame d'air 275581351 | MARCHE-367 | Etage 5 | 8 | Giron (Escalier) | ESC-021 | 0.651811 | 10 | 0.00312778 |  | 20558.4 | 2908.42 | 161.579 | 20558.4 | 2908.42 | 20548.4 | 2898.42 | 1 | Volée | 18 | Marche 27 | 0.01 | 1000 | 1000 | ArchiCADQuantities - Nez de marche: 15 mm; Giron de marche: 297.778 mm; Longueur volée marche: 297.778 mm; Superficie supérieure marche: 0.312778 m2; ArchiCADProperties - Surfaces (Toutes): Bois-Chêne; Nom de zone liée: Terrasse; Numéro de zone liée: B52
MARCHE-363 | Etage 5 | Lame d'air 275581351 | MARCHE-363 | Etage 5 | 8 | Giron (Escalier) | ESC-021 | 0.651811 | 10 | 0.00312778 |  | 19912.1 | 2262.11 | 807.895 | 19912.1 | 2262.11 | 19902.1 | 2252.11 | 1 | Volée | 14 | Marche 27 | 0.01 | 1000 | 1000 | ArchiCADQuantities - Nez de marche: 15 mm; Giron de marche: 297.778 mm; Longueur volée marche: 312.778 mm; Superficie supérieure marche: 0.312778 m2; ArchiCADProperties - Surfaces (Toutes): Bois-Chêne; Nom de zone liée: Terrasse; Numéro de zone liée: B52

# IfcColumn: Briques 314940890 300 x 200, Pilier-021
In: sousol
Classification: Poteau (Classification ARCHICAD); Material: Briques 314940890
ArchiCADQuantities - Hauteur / Diamètre d'âme: 200 mm; Volume de l'âme du poteau (net): 0.18 m3; Largeur d'âme: 300 mm; Superficie de l'âme du poteau (brute, sans sommet/base): 3 m2; Superficie supérieure de l'âme du poteau (brute): 0.06 m2; Superficie inférieure de l'âme du poteau (brute): 0.06 m2; Volume de l'âme du poteau (brut): 0.18 m3; Superficie du revêtement du poteau (brute, sans sommet/base): 0 m2; Superficie supérieure du revêtement du poteau (brute): 0 m2; Superficie inférieure du revêtement du poteau (brute): 0 m2; Volume du revêtement du poteau (brut): 0 m3; Hauteur maximale du Poteau: 3000 mm; Hauteur minimale du Poteau: 3000 mm; Superficie inférieure de l'âme du poteau (nette): 0.06 m2; Superficie de l'âme du poteau (nette, sans sommet/base): 3 m2; Superficie supérieure de l'âme du poteau (nette): 0.06 m2; Superficie inférieure du revêtement du poteau (nette): 0 m2; Superficie du revêtement du poteau (nette): 0 m2; Superficie supérieure du revêtement du poteau (nette): 0 m2; Périmètre de profil de poteau (base): 1000 mm; Volume du revêtement du poteau (net): 0 m3; Superficie: 0.06 m2; Hauteur: 3000 mm; Volume (net): 0.18 m3; Largeur: 300 mm; Altitude à Zéro du Projet: 0 mm; Altitude de Référence Niveau 1: 0 mm; Altitude de Référence Niveau 2: 0 mm; Altitude à niveau de la mer: 0 mm; Altitude à étage lié/étage d'implantation: 0 mm; Décalage étage d'implantation: 0 mm; Décalage supérieur: 0 mm; Superficie en plan: 3 m2; Longueur 3D: 3000 mm; Volume (brut): 0.18 m3; Altitude supérieure à premier niveau de référence: 3000 mm; Altitude supérieure à étage d'implantation: 3000 mm; Altitude supérieure à Zéro du projet: 3000 mm; Altitude supérieure à niveau de la mer: 3000 mm; Altitude supérieure à deuxième niveau de référence: 3000 mm; Altitude inférieure à premier niveau de référence: 0 mm; Altitude inférieure à étage d'implantation: 0 mm; Altitude inférieure à Zéro du projet: 0 mm; Altitude inférieure à niveau de la mer: 0 mm; Altitude inférieure à deuxième niveau de référence: 0 mm; Hauteur coupe transversale haut/fin (perpendiculaire): 200 mm; Hauteur coupe transversale bas/départ (perpendiculaire): 200 mm; Largeur coupe transversale haut/fin (perpendiculaire): 300 mm; Largeur coupe transversale bas/départ (perpendiculaire): 300 mm; Hauteur coupe transversale haut/fin (coupée): 200 mm; Hauteur coupe transversale bas/départ (coupée): 200 mm; Largeur coupe transversale haut/fin (coupée): 300 mm; Largeur coupe transversale bas/départ (coupée): 300 mm; Surface coupe transversale bas/départ (coupée): 0.06 m2; Surface coupe transversale haut/fin: 0.06 m2; Nombre de segments: 1; Superficie supérieure (nette): 0.06 m2; Superficie inférieure (nette): 3 m2; Superficie surface supérieure (Brute): 0.06 m2
AC_Pset_RenovationAndPhasing - Renovation Status: Existing
ArchiCADProperties - Coupe transversale de Poteau: Rectangulaire; Angle d'inclinaison de Poteau: 90 deg; Surface d'extrusion: Lavis blanc; Surface de fin: Lavis blanc; Génération de modèle analytique structurel: yes; Membre étiré manuellement: no; ID de l'élément: Pilier-021; Lien et ID d'élément: Pilier-021; Calque: 3D; Matériau de construction / Composite / Profil / Hachure: Briques 314940890; Matériau de construction: Briques 314940890; Verrouillé: no; Nom d'étage d'implantation: sousol; Numéro d'étage d'implantation: 2; Type d'élément: Poteau; Étage supérieur lié absolu: Non lié; Étage supérieur lié relatif: Non lié; Étage supérieur lié: Non lié; Type de structure: Basique; ID de Parent: Pilier-021; Matériaux de construction (Tous): Briques 314940890; Surfaces (Toutes): Lavis blanc; Hachure de recouvrement: Sans Trame; Angle d'inclinaison: 90 deg; Nom de Variante: Modèle principal; Nom de Jeu de Variantes: Modèle principal; Position: Intérieur; Fonction structurelle: Élément porteur; Affichage sur filtre de rénovation: Tous les filtres appropriés; État de rénovation: Existant; État de Variante: Modèle principal; Jeu de Variantes: Modèle principal

# IfcColumn: Briques 314940890 300 x 300 (3)
In: sousol
Classification: Poteau (Classification ARCHICAD); Material: Briques 314940890
AC_Pset_RenovationAndPhasing - Renovation Status: Existing
ArchiCADProperties - Coupe transversale de Poteau: Rectangulaire; Angle d'inclinaison de Poteau: 90 deg; Surface d'extrusion: Lavis blanc; Surface de fin: Lavis blanc; Génération de modèle analytique structurel: yes; Membre étiré manuellement: no; ID de l'élément: Pilier-021; Lien et ID d'élément: Pilier-021; Calque: 3D; Matériau de construction / Composite / Profil / Hachure: Briques 314940890; Matériau de construction: Briques 314940890; Verrouillé: no; Nom d'étage d'implantation: sousol; Numéro d'étage d'implantation: 2; Type d'élément: Poteau; Étage supérieur lié absolu: Non lié; Étage supérieur lié relatif: Non lié; Étage supérieur lié: Non lié; Type de structure: Basique; ID de Parent: Pilier-021; Matériaux de construction (Tous): Briques 314940890; Surfaces (Toutes): Lavis blanc; Hachure de recouvrement: Sans Trame; Angle d'inclinaison: 90 deg; Nom de Variante: Modèle principal; Nom de Jeu de Variantes: Modèle principal; Position: Intérieur; Fonction structurelle: Élément porteur; Affichage sur filtre de rénovation: Tous les filtres appropriés; État de rénovation: Existant; État de Variante: Modèle principal; Jeu de Variantes: Modèle principal
ArchiCADQuantities - Hauteur / Diamètre d'âme: 300 mm; Volume de l'âme du poteau (net): 0.27 m3; Largeur d'âme: 300 mm; Superficie de l'âme du poteau (brute, sans sommet/base): 3.6 m2; Superficie supérieure de l'âme du poteau (brute): 0.09 m2; Superficie inférieure de l'âme du poteau (brute): 0.09 m2; Volume de l'âme du poteau (brut): 0.27 m3; Superficie du revêtement du poteau (brute, sans sommet/base): 0 m2; Superficie supérieure du revêtement du poteau (brute): 0 m2; Superficie inférieure du revêtement du poteau (brute): 0 m2; Volume du revêtement du poteau (brut): 0 m3; Hauteur maximale du Poteau: 3000 mm; Hauteur minimale du Poteau: 3000 mm; Superficie inférieure de l'âme du poteau (nette): 0.09 m2; Superficie de l'âme du poteau (nette, sans sommet/base): 3.6 m2; Superficie supérieure de l'âme du poteau (nette): 0.09 m2; Superficie inférieure du revêtement du poteau (nette): 0 m2; Superficie du revêtement du poteau (nette): 0 m2; Superficie supérieure du revêtement du poteau (nette): 0 m2; Périmètre de profil de poteau (base): 1200 mm; Volume du revêtement du poteau (net): 0 m3; Superficie: 0.09 m2; Hauteur: 3000 mm; Volume (net): 0.27 m3; Largeur: 300 mm; Altitude à Zéro du Projet: 0 mm; Altitude de Référence Niveau 1: 0 mm; Altitude de Référence Niveau 2: 0 mm; Altitude à niveau de la mer: 0 mm; Altitude à étage lié/étage d'implantation: 0 mm; Décalage étage d'implantation: 0 mm; Décalage supérieur: 0 mm; Superficie en plan: 3.6 m2; Longueur 3D: 3000 mm; Volume (brut): 0.27 m3; Altitude supérieure à premier niveau de référence: 3000 mm; Altitude supérieure à étage d'implantation: 3000 mm; Altitude supérieure à Zéro du projet: 3000 mm; Altitude supérieure à niveau de la mer: 3000 mm; Altitude supérieure à deuxième niveau de référence: 3000 mm; Altitude inférieure à premier niveau de référence: 0 mm; Altitude inférieure à étage d'implantation: 0 mm; Altitude inférieure à Zéro du projet: 0 mm; Altitude inférieure à niveau de la mer: 0 mm; Altitude inférieure à deuxième niveau de référence: 0 mm; Hauteur coupe transversale haut/fin (perpendiculaire): 300 mm; Hauteur coupe transversale bas/départ (perpendiculaire): 300 mm; Largeur coupe transversale haut/fin (perpendiculaire): 300 mm; Largeur coupe transversale bas/départ (perpendiculaire): 300 mm; Hauteur coupe transversale haut/fin (coupée): 300 mm; Hauteur coupe transversale bas/départ (coupée): 300 mm; Largeur coupe transversale haut/fin (coupée): 300 mm; Largeur coupe transversale bas/départ (coupée): 300 mm; Surface coupe transversale bas/départ (coupée): 0.09 m2; Surface coupe transversale haut/fin: 0.09 m2; Nombre de segments: 1; Superficie supérieure (nette): 0.09 m2; Superficie inférieure (nette): 3.6 m2; Superficie surface supérieure (Brute): 0.09 m2
Name
2 x Pilier-021
Pilier-021 | ArchiCADProperties - Nom de zone liée: Pl; Numéro de zone liée: 818

# IfcColumn: Briques 314940890 400 x 180 (2)
In: sousol
Classification: Poteau (Classification ARCHICAD); Material: Briques 314940890
ArchiCADQuantities - Hauteur / Diamètre d'âme: 180 mm; Volume de l'âme du poteau (net): 0.216 m3; Largeur d'âme: 400 mm; Superficie de l'âme du poteau (brute, sans sommet/base): 3.48 m2; Superficie supérieure de l'âme du poteau (brute): 0.072 m2; Superficie inférieure de l'âme du poteau (brute): 0.072 m2; Volume de l'âme du poteau (brut): 0.216 m3; Superficie du revêtement du poteau (brute, sans sommet/base): 0 m2; Superficie supérieure du revêtement du poteau (brute): 0 m2; Superficie inférieure du revêtement du poteau (brute): 0 m2; Volume du revêtement du poteau (brut): 0 m3; Hauteur maximale du Poteau: 3000 mm; Hauteur minimale du Poteau: 3000 mm; Superficie inférieure de l'âme du poteau (nette): 0.072 m2; Superficie de l'âme du poteau (nette, sans sommet/base): 3.48 m2; Superficie supérieure de l'âme du poteau (nette): 0.072 m2; Superficie inférieure du revêtement du poteau (nette): 0 m2; Superficie du revêtement du poteau (nette): 0 m2; Superficie supérieure du revêtement du poteau (nette): 0 m2; Périmètre de profil de poteau (base): 1160 mm; Volume du revêtement du poteau (net): 0 m3; Superficie: 0.072 m2; Hauteur: 3000 mm; Volume (net): 0.216 m3; Largeur: 400 mm; Altitude à Zéro du Projet: 0 mm; Altitude de Référence Niveau 1: 0 mm; Altitude de Référence Niveau 2: 0 mm; Altitude à niveau de la mer: 0 mm; Altitude à étage lié/étage d'implantation: 0 mm; Décalage étage d'implantation: 0 mm; Décalage supérieur: 0 mm; Superficie en plan: 3.48 m2; Longueur 3D: 3000 mm; Volume (brut): 0.216 m3; Altitude supérieure à premier niveau de référence: 3000 mm; Altitude supérieure à étage d'implantation: 3000 mm; Altitude supérieure à Zéro du projet: 3000 mm; Altitude supérieure à niveau de la mer: 3000 mm; Altitude supérieure à deuxième niveau de référence: 3000 mm; Altitude inférieure à premier niveau de référence: 0 mm; Altitude inférieure à étage d'implantation: 0 mm; Altitude inférieure à Zéro du projet: 0 mm; Altitude inférieure à niveau de la mer: 0 mm; Altitude inférieure à deuxième niveau de référence: 0 mm; Hauteur coupe transversale haut/fin (perpendiculaire): 180 mm; Hauteur coupe transversale bas/départ (perpendiculaire): 180 mm; Largeur coupe transversale haut/fin (perpendiculaire): 400 mm; Largeur coupe transversale bas/départ (perpendiculaire): 400 mm; Hauteur coupe transversale haut/fin (coupée): 180 mm; Hauteur coupe transversale bas/départ (coupée): 180 mm; Largeur coupe transversale haut/fin (coupée): 400 mm; Largeur coupe transversale bas/départ (coupée): 400 mm; Surface coupe transversale bas/départ (coupée): 0.072 m2; Surface coupe transversale haut/fin: 0.072 m2; Nombre de segments: 1; Superficie supérieure (nette): 0.072 m2; Superficie inférieure (nette): 3.48 m2; Superficie surface supérieure (Brute): 0.072 m2
ArchiCADProperties - Coupe transversale de Poteau: Rectangulaire; Angle d'inclinaison de Poteau: 90 deg; Surface d'extrusion: Lavis blanc; Surface de fin: Lavis blanc; Génération de modèle analytique structurel: yes; Membre étiré manuellement: no; ID de l'élément: Pilier-021; Lien et ID d'élément: Pilier-021; Calque: 3D; Matériau de construction / Composite / Profil / Hachure: Briques 314940890; Matériau de construction: Briques 314940890; Verrouillé: no; Nom d'étage d'implantation: sousol; Numéro d'étage d'implantation: 2; Type d'élément: Poteau; Étage supérieur lié absolu: Non lié; Étage supérieur lié relatif: Non lié; Étage supérieur lié: Non lié; Type de structure: Basique; ID de Parent: Pilier-021; Matériaux de construction (Tous): Briques 314940890; Surfaces (Toutes): Lavis blanc; Hachure de recouvrement: Sans Trame; Angle d'inclinaison: 90 deg; Nom de Variante: Modèle principal; Nom de Jeu de Variantes: Modèle principal; Position: Intérieur; Fonction structurelle: Élément porteur; Affichage sur filtre de rénovation: Tous les filtres appropriés; État de rénovation: Existant; État de Variante: Modèle principal; Jeu de Variantes: Modèle principal
AC_Pset_RenovationAndPhasing - Renovation Status: Existing

# IfcColumn: Briques 314940890 400 x 250, Pilier-021
In: sousol
Classification: Poteau (Classification ARCHICAD); Material: Briques 314940890
AC_Pset_RenovationAndPhasing - Renovation Status: Existing
ArchiCADQuantities - Hauteur / Diamètre d'âme: 250 mm; Volume de l'âme du poteau (net): 0.3 m3; Largeur d'âme: 400 mm; Superficie de l'âme du poteau (brute, sans sommet/base): 3.9 m2; Superficie supérieure de l'âme du poteau (brute): 0.1 m2; Superficie inférieure de l'âme du poteau (brute): 0.1 m2; Volume de l'âme du poteau (brut): 0.3 m3; Superficie du revêtement du poteau (brute, sans sommet/base): 0 m2; Superficie supérieure du revêtement du poteau (brute): 0 m2; Superficie inférieure du revêtement du poteau (brute): 0 m2; Volume du revêtement du poteau (brut): 0 m3; Hauteur maximale du Poteau: 3000 mm; Hauteur minimale du Poteau: 3000 mm; Superficie inférieure de l'âme du poteau (nette): 0.1 m2; Superficie de l'âme du poteau (nette, sans sommet/base): 3.9 m2; Superficie supérieure de l'âme du poteau (nette): 0.1 m2; Superficie inférieure du revêtement du poteau (nette): 0 m2; Superficie du revêtement du poteau (nette): 0 m2; Superficie supérieure du revêtement du poteau (nette): 0 m2; Périmètre de profil de poteau (base): 1300 mm; Volume du revêtement du poteau (net): 0 m3; Superficie: 0.1 m2; Hauteur: 3000 mm; Volume (net): 0.3 m3; Largeur: 400 mm; Altitude à Zéro du Projet: 0 mm; Altitude de Référence Niveau 1: 0 mm; Altitude de Référence Niveau 2: 0 mm; Altitude à niveau de la mer: 0 mm; Altitude à étage lié/étage d'implantation: 0 mm; Décalage étage d'implantation: 0 mm; Décalage supérieur: 0 mm; Superficie en plan: 3.9 m2; Longueur 3D: 3000 mm; Volume (brut): 0.3 m3; Altitude supérieure à premier niveau de référence: 3000 mm; Altitude supérieure à étage d'implantation: 3000 mm; Altitude supérieure à Zéro du projet: 3000 mm; Altitude supérieure à niveau de la mer: 3000 mm; Altitude supérieure à deuxième niveau de référence: 3000 mm; Altitude inférieure à premier niveau de référence: 0 mm; Altitude inférieure à étage d'implantation: 0 mm; Altitude inférieure à Zéro du projet: 0 mm; Altitude inférieure à niveau de la mer: 0 mm; Altitude inférieure à deuxième niveau de référence: 0 mm; Hauteur coupe transversale haut/fin (perpendiculaire): 250 mm; Hauteur coupe transversale bas/départ (perpendiculaire): 250 mm; Largeur coupe transversale haut/fin (perpendiculaire): 400 mm; Largeur coupe transversale bas/départ (perpendiculaire): 400 mm; Hauteur coupe transversale haut/fin (coupée): 250 mm; Hauteur coupe transversale bas/départ (coupée): 250 mm; Largeur coupe transversale haut/fin (coupée): 400 mm; Largeur coupe transversale bas/départ (coupée): 400 mm; Surface coupe transversale bas/départ (coupée): 0.1 m2; Surface coupe transversale haut/fin: 0.1 m2; Nombre de segments: 1; Superficie supérieure (nette): 0.1 m2; Superficie inférieure (nette): 3.9 m2; Superficie surface supérieure (Brute): 0.1 m2
ArchiCADProperties - Coupe transversale de Poteau: Rectangulaire; Angle d'inclinaison de Poteau: 90 deg; Surface d'extrusion: Lavis blanc; Surface de fin: Lavis blanc; Génération de modèle analytique structurel: yes; Membre étiré manuellement: no; ID de l'élément: Pilier-021; Lien et ID d'élément: Pilier-021; Calque: 3D; Matériau de construction / Composite / Profil / Hachure: Briques 314940890; Matériau de construction: Briques 314940890; Verrouillé: no; Nom d'étage d'implantation: sousol; Numéro d'étage d'implantation: 2; Type d'élément: Poteau; Étage supérieur lié absolu: Non lié; Étage supérieur lié relatif: Non lié; Étage supérieur lié: Non lié; Type de structure: Basique; ID de Parent: Pilier-021; Matériaux de construction (Tous): Briques 314940890; Surfaces (Toutes): Lavis blanc; Hachure de recouvrement: Sans Trame; Angle d'inclinaison: 90 deg; Nom de Variante: Modèle principal; Nom de Jeu de Variantes: Modèle principal; Position: Intérieur; Fonction structurelle: Élément porteur; Affichage sur filtre de rénovation: Tous les filtres appropriés; État de rénovation: Existant; État de Variante: Modèle principal; Jeu de Variantes: Modèle principal

# IfcColumn: Briques 314940890 400 x 300 (9)
In: sousol
Classification: Poteau (Classification ARCHICAD); Material: Briques 314940890
ArchiCADProperties - Coupe transversale de Poteau: Rectangulaire; Angle d'inclinaison de Poteau: 90 deg; Surface d'extrusion: Lavis blanc; Surface de fin: Lavis blanc; Génération de modèle analytique structurel: yes; Membre étiré manuellement: no; ID de l'élément: Pilier-021; Lien et ID d'élément: Pilier-021; Calque: 3D; Matériau de construction / Composite / Profil / Hachure: Briques 314940890; Matériau de construction: Briques 314940890; Verrouillé: no; Nom d'étage d'implantation: sousol; Numéro d'étage d'implantation: 2; Type d'élément: Poteau; Étage supérieur lié absolu: Non lié; Étage supérieur lié relatif: Non lié; Étage supérieur lié: Non lié; Type de structure: Basique; ID de Parent: Pilier-021; Matériaux de construction (Tous): Briques 314940890; Surfaces (Toutes): Lavis blanc; Hachure de recouvrement: Sans Trame; Angle d'inclinaison: 90 deg; Nom de Variante: Modèle principal; Nom de Jeu de Variantes: Modèle principal; Position: Intérieur; Fonction structurelle: Élément porteur; Affichage sur filtre de rénovation: Tous les filtres appropriés; État de rénovation: Existant; État de Variante: Modèle principal; Jeu de Variantes: Modèle principal
AC_Pset_RenovationAndPhasing - Renovation Status: Existing
ArchiCADQuantities - Hauteur / Diamètre d'âme: 300 mm; Volume de l'âme du poteau (net): 0.36 m3; Largeur d'âme: 400 mm; Superficie de l'âme du poteau (brute, sans sommet/base): 4.2 m2; Superficie supérieure de l'âme du poteau (brute): 0.12 m2; Superficie inférieure de l'âme du poteau (brute): 0.12 m2; Volume de l'âme du poteau (brut): 0.36 m3; Superficie du revêtement du poteau (brute, sans sommet/base): 0 m2; Superficie supérieure du revêtement du poteau (brute): 0 m2; Superficie inférieure du revêtement du poteau (brute): 0 m2; Volume du revêtement du poteau (brut): 0 m3; Hauteur maximale du Poteau: 3000 mm; Hauteur minimale du Poteau: 3000 mm; Superficie inférieure de l'âme du poteau (nette): 0.12 m2; Superficie de l'âme du poteau (nette, sans sommet/base): 4.2 m2; Superficie supérieure de l'âme du poteau (nette): 0.12 m2; Superficie inférieure du revêtement du poteau (nette): 0 m2; Superficie du revêtement du poteau (nette): 0 m2; Superficie supérieure du revêtement du poteau (nette): 0 m2; Périmètre de profil de poteau (base): 1400 mm; Volume du revêtement du poteau (net): 0 m3; Superficie: 0.12 m2; Hauteur: 3000 mm; Volume (net): 0.36 m3; Largeur: 400 mm; Altitude à Zéro du Projet: 0 mm; Altitude de Référence Niveau 1: 0 mm; Altitude de Référence Niveau 2: 0 mm; Altitude à niveau de la mer: 0 mm; Altitude à étage lié/étage d'implantation: 0 mm; Décalage étage d'implantation: 0 mm; Décalage supérieur: 0 mm; Superficie en plan: 4.2 m2; Longueur 3D: 3000 mm; Volume (brut): 0.36 m3; Altitude supérieure à premier niveau de référence: 3000 mm; Altitude supérieure à étage d'implantation: 3000 mm; Altitude supérieure à Zéro du projet: 3000 mm; Altitude supérieure à niveau de la mer: 3000 mm; Altitude supérieure à deuxième niveau de référence: 3000 mm; Altitude inférieure à premier niveau de référence: 0 mm; Altitude inférieure à étage d'implantation: 0 mm; Altitude inférieure à Zéro du projet: 0 mm; Altitude inférieure à niveau de la mer: 0 mm; Altitude inférieure à deuxième niveau de référence: 0 mm; Hauteur coupe transversale haut/fin (perpendiculaire): 300 mm; Hauteur coupe transversale bas/départ (perpendiculaire): 300 mm; Largeur coupe transversale haut/fin (perpendiculaire): 400 mm; Largeur coupe transversale bas/départ (perpendiculaire): 400 mm; Hauteur coupe transversale haut/fin (coupée): 300 mm; Hauteur coupe transversale bas/départ (coupée): 300 mm; Largeur coupe transversale haut/fin (coupée): 400 mm; Largeur coupe transversale bas/départ (coupée): 400 mm; Surface coupe transversale bas/départ (coupée): 0.12 m2; Surface coupe transversale haut/fin: 0.12 m2; Nombre de segments: 1; Superficie supérieure (nette): 0.12 m2; Superficie inférieure (nette): 4.2 m2; Superficie surface supérieure (Brute): 0.12 m2

# IfcColumn: Briques 314940890 400 x 510, Pilier-021
In: sousol
Classification: Poteau (Classification ARCHICAD); Material: Briques 314940890
ArchiCADQuantities - Hauteur / Diamètre d'âme: 510 mm; Volume de l'âme du poteau (net): 0.612 m3; Largeur d'âme: 400 mm; Superficie de l'âme du poteau (brute, sans sommet/base): 5.46 m2; Superficie supérieure de l'âme du poteau (brute): 0.204 m2; Superficie inférieure de l'âme du poteau (brute): 0.204 m2; Volume de l'âme du poteau (brut): 0.612 m3; Superficie du revêtement du poteau (brute, sans sommet/base): 0 m2; Superficie supérieure du revêtement du poteau (brute): 0 m2; Superficie inférieure du revêtement du poteau (brute): 0 m2; Volume du revêtement du poteau (brut): 0 m3; Hauteur maximale du Poteau: 3000 mm; Hauteur minimale du Poteau: 3000 mm; Superficie inférieure de l'âme du poteau (nette): 0.204 m2; Superficie de l'âme du poteau (nette, sans sommet/base): 5.46 m2; Superficie supérieure de l'âme du poteau (nette): 0.204 m2; Superficie inférieure du revêtement du poteau (nette): 0 m2; Superficie du revêtement du poteau (nette): 0 m2; Superficie supérieure du revêtement du poteau (nette): 0 m2; Périmètre de profil de poteau (base): 1820 mm; Volume du revêtement du poteau (net): 0 m3; Superficie: 0.204 m2; Hauteur: 3000 mm; Volume (net): 0.612 m3; Largeur: 400 mm; Altitude à Zéro du Projet: 0 mm; Altitude de Référence Niveau 1: 0 mm; Altitude de Référence Niveau 2: 0 mm; Altitude à niveau de la mer: 0 mm; Altitude à étage lié/étage d'implantation: 0 mm; Décalage étage d'implantation: 0 mm; Décalage supérieur: 0 mm; Superficie en plan: 5.46 m2; Longueur 3D: 3000 mm; Volume (brut): 0.612 m3; Altitude supérieure à premier niveau de référence: 3000 mm; Altitude supérieure à étage d'implantation: 3000 mm; Altitude supérieure à Zéro du projet: 3000 mm; Altitude supérieure à niveau de la mer: 3000 mm; Altitude supérieure à deuxième niveau de référence: 3000 mm; Altitude inférieure à premier niveau de référence: 0 mm; Altitude inférieure à étage d'implantation: 0 mm; Altitude inférieure à Zéro du projet: 0 mm; Altitude inférieure à niveau de la mer: 0 mm; Altitude inférieure à deuxième niveau de référence: 0 mm; Hauteur coupe transversale haut/fin (perpendiculaire): 510 mm; Hauteur coupe transversale bas/départ (perpendiculaire): 510 mm; Largeur coupe transversale haut/fin (perpendiculaire): 400 mm; Largeur coupe transversale bas/départ (perpendiculaire): 400 mm; Hauteur coupe transversale haut/fin (coupée): 510 mm; Hauteur coupe transversale bas/départ (coupée): 510 mm; Largeur coupe transversale haut/fin (coupée): 400 mm; Largeur coupe transversale bas/départ (coupée): 400 mm; Surface coupe transversale bas/départ (coupée): 0.204 m2; Surface coupe transversale haut/fin: 0.204 m2; Nombre de segments: 1; Superficie supérieure (nette): 0.204 m2; Superficie inférieure (nette): 5.46 m2; Superficie surface supérieure (Brute): 0.204 m2
ArchiCADProperties - Coupe transversale de Poteau: Rectangulaire; Angle d'inclinaison de Poteau: 90 deg; Surface d'extrusion: Lavis blanc; Surface de fin: Lavis blanc; Génération de modèle analytique structurel: yes; Membre étiré manuellement: no; ID de l'élément: Pilier-021; Lien et ID d'élément: Pilier-021; Calque: 3D; Matériau de construction / Composite / Profil / Hachure: Briques 314940890; Matériau de construction: Briques 314940890; Verrouillé: no; Nom d'étage d'implantation: sousol; Numéro d'étage d'implantation: 2; Type d'élément: Poteau; Étage supérieur lié absolu: Non lié; Étage supérieur lié relatif: Non lié; Étage supérieur lié: Non lié; Type de structure: Basique; ID de Parent: Pilier-021; Matériaux de construction (Tous): Briques 314940890; Surfaces (Toutes): Lavis blanc; Hachure de recouvrement: Sans Trame; Angle d'inclinaison: 90 deg; Nom de Variante: Modèle principal; Nom de Jeu de Variantes: Modèle principal; Position: Intérieur; Fonction structurelle: Élément porteur; Affichage sur filtre de rénovation: Tous les filtres appropriés; État de rénovation: Existant; État de Variante: Modèle principal; Jeu de Variantes: Modèle principal
AC_Pset_RenovationAndPhasing - Renovation Status: Existing

# IfcColumn: Briques 314940890 460 x 300, Pilier-021
In: sousol
Classification: Poteau (Classification ARCHICAD); Material: Briques 314940890
AC_Pset_RenovationAndPhasing - Renovation Status: Existing
ArchiCADProperties - Coupe transversale de Poteau: Rectangulaire; Angle d'inclinaison de Poteau: 90 deg; Surface d'extrusion: Lavis blanc; Surface de fin: Lavis blanc; Génération de modèle analytique structurel: yes; Membre étiré manuellement: no; ID de l'élément: Pilier-021; Lien et ID d'élément: Pilier-021; Calque: 3D; Matériau de construction / Composite / Profil / Hachure: Briques 314940890; Matériau de construction: Briques 314940890; Verrouillé: no; Nom d'étage d'implantation: sousol; Numéro d'étage d'implantation: 2; Type d'élément: Poteau; Étage supérieur lié absolu: Non lié; Étage supérieur lié relatif: Non lié; Étage supérieur lié: Non lié; Type de structure: Basique; ID de Parent: Pilier-021; Matériaux de construction (Tous): Briques 314940890; Surfaces (Toutes): Lavis blanc; Hachure de recouvrement: Sans Trame; Angle d'inclinaison: 90 deg; Nom de Variante: Modèle principal; Nom de Jeu de Variantes: Modèle principal; Position: Intérieur; Fonction structurelle: Élément porteur; Affichage sur filtre de rénovation: Tous les filtres appropriés; État de rénovation: Existant; État de Variante: Modèle principal; Jeu de Variantes: Modèle principal
ArchiCADQuantities - Hauteur / Diamètre d'âme: 300 mm; Volume de l'âme du poteau (net): 0.414 m3; Largeur d'âme: 460 mm; Superficie de l'âme du poteau (brute, sans sommet/base): 4.56 m2; Superficie supérieure de l'âme du poteau (brute): 0.138 m2; Superficie inférieure de l'âme du poteau (brute): 0.138 m2; Volume de l'âme du poteau (brut): 0.414 m3; Superficie du revêtement du poteau (brute, sans sommet/base): 0 m2; Superficie supérieure du revêtement du poteau (brute): 0 m2; Superficie inférieure du revêtement du poteau (brute): 0 m2; Volume du revêtement du poteau (brut): 0 m3; Hauteur maximale du Poteau: 3000 mm; Hauteur minimale du Poteau: 3000 mm; Superficie inférieure de l'âme du poteau (nette): 0.138 m2; Superficie de l'âme du poteau (nette, sans sommet/base): 4.56 m2; Superficie supérieure de l'âme du poteau (nette): 0.138 m2; Superficie inférieure du revêtement du poteau (nette): 0 m2; Superficie du revêtement du poteau (nette): 0 m2; Superficie supérieure du revêtement du poteau (nette): 0 m2; Périmètre de profil de poteau (base): 1520 mm; Volume du revêtement du poteau (net): 0 m3; Superficie: 0.138 m2; Hauteur: 3000 mm; Volume (net): 0.414 m3; Largeur: 460 mm; Altitude à Zéro du Projet: 0 mm; Altitude de Référence Niveau 1: 0 mm; Altitude de Référence Niveau 2: 0 mm; Altitude à niveau de la mer: 0 mm; Altitude à étage lié/étage d'implantation: 0 mm; Décalage étage d'implantation: 0 mm; Décalage supérieur: 0 mm; Superficie en plan: 4.56 m2; Longueur 3D: 3000 mm; Volume (brut): 0.414 m3; Altitude supérieure à premier niveau de référence: 3000 mm; Altitude supérieure à étage d'implantation: 3000 mm; Altitude supérieure à Zéro du projet: 3000 mm; Altitude supérieure à niveau de la mer: 3000 mm; Altitude supérieure à deuxième niveau de référence: 3000 mm; Altitude inférieure à premier niveau de référence: 0 mm; Altitude inférieure à étage d'implantation: 0 mm; Altitude inférieure à Zéro du projet: 0 mm; Altitude inférieure à niveau de la mer: 0 mm; Altitude inférieure à deuxième niveau de référence: 0 mm; Hauteur coupe transversale haut/fin (perpendiculaire): 300 mm; Hauteur coupe transversale bas/départ (perpendiculaire): 300 mm; Largeur coupe transversale haut/fin (perpendiculaire): 460 mm; Largeur coupe transversale bas/départ (perpendiculaire): 460 mm; Hauteur coupe transversale haut/fin (coupée): 300 mm; Hauteur coupe transversale bas/départ (coupée): 300 mm; Largeur coupe transversale haut/fin (coupée): 460 mm; Largeur coupe transversale bas/départ (coupée): 460 mm; Surface coupe transversale bas/départ (coupée): 0.138 m2; Surface coupe transversale haut/fin: 0.138 m2; Nombre de segments: 1; Superficie supérieure (nette): 0.138 m2; Superficie inférieure (nette): 4.56 m2; Superficie surface supérieure (Brute): 0.138 m2

# IfcColumn: Briques 314940890 500 x 400 (2)
In: sousol
Classification: Poteau (Classification ARCHICAD); Material: Briques 314940890
AC_Pset_RenovationAndPhasing - Renovation Status: Existing
ArchiCADProperties - Coupe transversale de Poteau: Rectangulaire; Angle d'inclinaison de Poteau: 90 deg; Surface d'extrusion: Lavis blanc; Surface de fin: Lavis blanc; Génération de modèle analytique structurel: yes; Membre étiré manuellement: no; ID de l'élément: Pilier-021; Lien et ID d'élément: Pilier-021; Calque: 3D; Matériau de construction / Composite / Profil / Hachure: Briques 314940890; Matériau de construction: Briques 314940890; Verrouillé: no; Nom d'étage d'implantation: sousol; Numéro d'étage d'implantation: 2; Type d'élément: Poteau; Étage supérieur lié absolu: Non lié; Étage supérieur lié relatif: Non lié; Étage supérieur lié: Non lié; Type de structure: Basique; ID de Parent: Pilier-021; Matériaux de construction (Tous): Briques 314940890; Surfaces (Toutes): Lavis blanc; Hachure de recouvrement: Sans Trame; Angle d'inclinaison: 90 deg; Nom de Variante: Modèle principal; Nom de Jeu de Variantes: Modèle principal; Position: Intérieur; Fonction structurelle: Élément porteur; Affichage sur filtre de rénovation: Tous les filtres appropriés; État de rénovation: Existant; État de Variante: Modèle principal; Jeu de Variantes: Modèle principal
ArchiCADQuantities - Hauteur / Diamètre d'âme: 400 mm; Volume de l'âme du poteau (net): 0.6 m3; Largeur d'âme: 500 mm; Superficie de l'âme du poteau (brute, sans sommet/base): 5.4 m2; Superficie supérieure de l'âme du poteau (brute): 0.2 m2; Superficie inférieure de l'âme du poteau (brute): 0.2 m2; Volume de l'âme du poteau (brut): 0.6 m3; Superficie du revêtement du poteau (brute, sans sommet/base): 0 m2; Superficie supérieure du revêtement du poteau (brute): 0 m2; Superficie inférieure du revêtement du poteau (brute): 0 m2; Volume du revêtement du poteau (brut): 0 m3; Hauteur maximale du Poteau: 3000 mm; Hauteur minimale du Poteau: 3000 mm; Superficie inférieure de l'âme du poteau (nette): 0.2 m2; Superficie de l'âme du poteau (nette, sans sommet/base): 5.4 m2; Superficie supérieure de l'âme du poteau (nette): 0.2 m2; Superficie inférieure du revêtement du poteau (nette): 0 m2; Superficie du revêtement du poteau (nette): 0 m2; Superficie supérieure du revêtement du poteau (nette): 0 m2; Périmètre de profil de poteau (base): 1800 mm; Volume du revêtement du poteau (net): 0 m3; Superficie: 0.2 m2; Hauteur: 3000 mm; Volume (net): 0.6 m3; Largeur: 500 mm; Altitude à Zéro du Projet: 0 mm; Altitude de Référence Niveau 1: 0 mm; Altitude de Référence Niveau 2: 0 mm; Altitude à niveau de la mer: 0 mm; Altitude à étage lié/étage d'implantation: 0 mm; Décalage étage d'implantation: 0 mm; Décalage supérieur: 0 mm; Superficie en plan: 5.4 m2; Longueur 3D: 3000 mm; Volume (brut): 0.6 m3; Altitude supérieure à premier niveau de référence: 3000 mm; Altitude supérieure à étage d'implantation: 3000 mm; Altitude supérieure à Zéro du projet: 3000 mm; Altitude supérieure à niveau de la mer: 3000 mm; Altitude supérieure à deuxième niveau de référence: 3000 mm; Altitude inférieure à premier niveau de référence: 0 mm; Altitude inférieure à étage d'implantation: 0 mm; Altitude inférieure à Zéro du projet: 0 mm; Altitude inférieure à niveau de la mer: 0 mm; Altitude inférieure à deuxième niveau de référence: 0 mm; Hauteur coupe transversale haut/fin (perpendiculaire): 400 mm; Hauteur coupe transversale bas/départ (perpendiculaire): 400 mm; Largeur coupe transversale haut/fin (perpendiculaire): 500 mm; Largeur coupe transversale bas/départ (perpendiculaire): 500 mm; Hauteur coupe transversale haut/fin (coupée): 400 mm; Hauteur coupe transversale bas/départ (coupée): 400 mm; Largeur coupe transversale haut/fin (coupée): 500 mm; Largeur coupe transversale bas/départ (coupée): 500 mm; Surface coupe transversale bas/départ (coupée): 0.2 m2; Surface coupe transversale haut/fin: 0.2 m2; Nombre de segments: 1; Superficie supérieure (nette): 0.2 m2; Superficie inférieure (nette): 5.4 m2; Superficie surface supérieure (Brute): 0.2 m2

# IfcColumn: Briques 314940890 600 x 200 (2)
In: sousol
Classification: Poteau (Classification ARCHICAD); Material: Briques 314940890
ArchiCADProperties - Coupe transversale de Poteau: Rectangulaire; Angle d'inclinaison de Poteau: 90 deg; Surface d'extrusion: Lavis blanc; Surface de fin: Lavis blanc; Génération de modèle analytique structurel: yes; Membre étiré manuellement: no; ID de l'élément: Pilier-021; Lien et ID d'élément: Pilier-021; Calque: 3D; Matériau de construction / Composite / Profil / Hachure: Briques 314940890; Matériau de construction: Briques 314940890; Verrouillé: no; Nom d'étage d'implantation: sousol; Numéro d'étage d'implantation: 2; Type d'élément: Poteau; Étage supérieur lié absolu: Non lié; Étage supérieur lié relatif: Non lié; Étage supérieur lié: Non lié; Type de structure: Basique; ID de Parent: Pilier-021; Matériaux de construction (Tous): Briques 314940890; Surfaces (Toutes): Lavis blanc; Hachure de recouvrement: Sans Trame; Angle d'inclinaison: 90 deg; Nom de Variante: Modèle principal; Nom de Jeu de Variantes: Modèle principal; Position: Intérieur; Fonction structurelle: Élément porteur; Affichage sur filtre de rénovation: Tous les filtres appropriés; État de rénovation: Existant; État de Variante: Modèle principal; Jeu de Variantes: Modèle principal
AC_Pset_RenovationAndPhasing - Renovation Status: Existing
ArchiCADQuantities - Hauteur / Diamètre d'âme: 200 mm; Volume de l'âme du poteau (net): 0.36 m3; Largeur d'âme: 600 mm; Superficie de l'âme du poteau (brute, sans sommet/base): 4.8 m2; Superficie supérieure de l'âme du poteau (brute): 0.12 m2; Superficie inférieure de l'âme du poteau (brute): 0.12 m2; Volume de l'âme du poteau (brut): 0.36 m3; Superficie du revêtement du poteau (brute, sans sommet/base): 0 m2; Superficie supérieure du revêtement du poteau (brute): 0 m2; Superficie inférieure du revêtement du poteau (brute): 0 m2; Volume du revêtement du poteau (brut): 0 m3; Hauteur maximale du Poteau: 3000 mm; Hauteur minimale du Poteau: 3000 mm; Superficie inférieure de l'âme du poteau (nette): 0.12 m2; Superficie de l'âme du poteau (nette, sans sommet/base): 4.8 m2; Superficie supérieure de l'âme du poteau (nette): 0.12 m2; Superficie inférieure du revêtement du poteau (nette): 0 m2; Superficie du revêtement du poteau (nette): 0 m2; Superficie supérieure du revêtement du poteau (nette): 0 m2; Périmètre de profil de poteau (base): 1600 mm; Volume du revêtement du poteau (net): 0 m3; Superficie: 0.12 m2; Hauteur: 3000 mm; Volume (net): 0.36 m3; Largeur: 600 mm; Altitude à Zéro du Projet: 0 mm; Altitude de Référence Niveau 1: 0 mm; Altitude de Référence Niveau 2: 0 mm; Altitude à niveau de la mer: 0 mm; Altitude à étage lié/étage d'implantation: 0 mm; Décalage étage d'implantation: 0 mm; Décalage supérieur: 0 mm; Superficie en plan: 4.8 m2; Longueur 3D: 3000 mm; Volume (brut): 0.36 m3; Altitude supérieure à premier niveau de référence: 3000 mm; Altitude supérieure à étage d'implantation: 3000 mm; Altitude supérieure à Zéro du projet: 3000 mm; Altitude supérieure à niveau de la mer: 3000 mm; Altitude supérieure à deuxième niveau de référence: 3000 mm; Altitude inférieure à premier niveau de référence: 0 mm; Altitude inférieure à étage d'implantation: 0 mm; Altitude inférieure à Zéro du projet: 0 mm; Altitude inférieure à niveau de la mer: 0 mm; Altitude inférieure à deuxième niveau de référence: 0 mm; Hauteur coupe transversale haut/fin (perpendiculaire): 200 mm; Hauteur coupe transversale bas/départ (perpendiculaire): 200 mm; Largeur coupe transversale haut/fin (perpendiculaire): 600 mm; Largeur coupe transversale bas/départ (perpendiculaire): 600 mm; Hauteur coupe transversale haut/fin (coupée): 200 mm; Hauteur coupe transversale bas/départ (coupée): 200 mm; Largeur coupe transversale haut/fin (coupée): 600 mm; Largeur coupe transversale bas/départ (coupée): 600 mm; Surface coupe transversale bas/départ (coupée): 0.12 m2; Surface coupe transversale haut/fin: 0.12 m2; Nombre de segments: 1; Superficie supérieure (nette): 0.12 m2; Superficie inférieure (nette): 4.8 m2; Superficie surface supérieure (Brute): 0.12 m2

# IfcColumn: Briques 314940890 600 x 250, Pilier-021
In: sousol
Classification: Poteau (Classification ARCHICAD); Material: Briques 314940890
AC_Pset_RenovationAndPhasing - Renovation Status: Existing
ArchiCADQuantities - Hauteur / Diamètre d'âme: 250 mm; Volume de l'âme du poteau (net): 0.45 m3; Largeur d'âme: 600 mm; Superficie de l'âme du poteau (brute, sans sommet/base): 5.1 m2; Superficie supérieure de l'âme du poteau (brute): 0.15 m2; Superficie inférieure de l'âme du poteau (brute): 0.15 m2; Volume de l'âme du poteau (brut): 0.45 m3; Superficie du revêtement du poteau (brute, sans sommet/base): 0 m2; Superficie supérieure du revêtement du poteau (brute): 0 m2; Superficie inférieure du revêtement du poteau (brute): 0 m2; Volume du revêtement du poteau (brut): 0 m3; Hauteur maximale du Poteau: 3000 mm; Hauteur minimale du Poteau: 3000 mm; Superficie inférieure de l'âme du poteau (nette): 0.15 m2; Superficie de l'âme du poteau (nette, sans sommet/base): 5.1 m2; Superficie supérieure de l'âme du poteau (nette): 0.15 m2; Superficie inférieure du revêtement du poteau (nette): 0 m2; Superficie du revêtement du poteau (nette): 0 m2; Superficie supérieure du revêtement du poteau (nette): 0 m2; Périmètre de profil de poteau (base): 1700 mm; Volume du revêtement du poteau (net): 0 m3; Superficie: 0.15 m2; Hauteur: 3000 mm; Volume (net): 0.45 m3; Largeur: 600 mm; Altitude à Zéro du Projet: 0 mm; Altitude de Référence Niveau 1: 0 mm; Altitude de Référence Niveau 2: 0 mm; Altitude à niveau de la mer: 0 mm; Altitude à étage lié/étage d'implantation: 0 mm; Décalage étage d'implantation: 0 mm; Décalage supérieur: 0 mm; Superficie en plan: 5.1 m2; Longueur 3D: 3000 mm; Volume (brut): 0.45 m3; Altitude supérieure à premier niveau de référence: 3000 mm; Altitude supérieure à étage d'implantation: 3000 mm; Altitude supérieure à Zéro du projet: 3000 mm; Altitude supérieure à niveau de la mer: 3000 mm; Altitude supérieure à deuxième niveau de référence: 3000 mm; Altitude inférieure à premier niveau de référence: 0 mm; Altitude inférieure à étage d'implantation: 0 mm; Altitude inférieure à Zéro du projet: 0 mm; Altitude inférieure à niveau de la mer: 0 mm; Altitude inférieure à deuxième niveau de référence: 0 mm; Hauteur coupe transversale haut/fin (perpendiculaire): 250 mm; Hauteur coupe transversale bas/départ (perpendiculaire): 250 mm; Largeur coupe transversale haut/fin (perpendiculaire): 600 mm; Largeur coupe transversale bas/départ (perpendiculaire): 600 mm; Hauteur coupe transversale haut/fin (coupée): 250 mm; Hauteur coupe transversale bas/départ (coupée): 250 mm; Largeur coupe transversale haut/fin (coupée): 600 mm; Largeur coupe transversale bas/départ (coupée): 600 mm; Surface coupe transversale bas/départ (coupée): 0.15 m2; Surface coupe transversale haut/fin: 0.15 m2; Nombre de segments: 1; Superficie supérieure (nette): 0.15 m2; Superficie inférieure (nette): 5.1 m2; Superficie surface supérieure (Brute): 0.15 m2
ArchiCADProperties - Coupe transversale de Poteau: Rectangulaire; Angle d'inclinaison de Poteau: 90 deg; Surface d'extrusion: Lavis blanc; Surface de fin: Lavis blanc; Génération de modèle analytique structurel: yes; Membre étiré manuellement: no; ID de l'élément: Pilier-021; Lien et ID d'élément: Pilier-021; Calque: 3D; Matériau de construction / Composite / Profil / Hachure: Briques 314940890; Matériau de construction: Briques 314940890; Verrouillé: no; Nom d'étage d'implantation: sousol; Numéro d'étage d'implantation: 2; Type d'élément: Poteau; Étage supérieur lié absolu: Non lié; Étage supérieur lié relatif: Non lié; Étage supérieur lié: Non lié; Type de structure: Basique; ID de Parent: Pilier-021; Matériaux de construction (Tous): Briques 314940890; Surfaces (Toutes): Lavis blanc; Hachure de recouvrement: Sans Trame; Angle d'inclinaison: 90 deg; Nom de Variante: Modèle principal; Nom de Jeu de Variantes: Modèle principal; Position: Intérieur; Fonction structurelle: Élément porteur; Affichage sur filtre de rénovation: Tous les filtres appropriés; État de rénovation: Existant; État de Variante: Modèle principal; Jeu de Variantes: Modèle principal

# IfcColumn: Briques 314940890 600 x 400, Pilier-021
In: sousol
Classification: Poteau (Classification ARCHICAD); Material: Briques 314940890
AC_Pset_RenovationAndPhasing - Renovation Status: Existing
ArchiCADQuantities - Hauteur / Diamètre d'âme: 400 mm; Volume de l'âme du poteau (net): 0.72 m3; Largeur d'âme: 600 mm; Superficie de l'âme du poteau (brute, sans sommet/base): 6 m2; Superficie supérieure de l'âme du poteau (brute): 0.24 m2; Superficie inférieure de l'âme du poteau (brute): 0.24 m2; Volume de l'âme du poteau (brut): 0.72 m3; Superficie du revêtement du poteau (brute, sans sommet/base): 0 m2; Superficie supérieure du revêtement du poteau (brute): 0 m2; Superficie inférieure du revêtement du poteau (brute): 0 m2; Volume du revêtement du poteau (brut): 0 m3; Hauteur maximale du Poteau: 3000 mm; Hauteur minimale du Poteau: 3000 mm; Superficie inférieure de l'âme du poteau (nette): 0.24 m2; Superficie de l'âme du poteau (nette, sans sommet/base): 6 m2; Superficie supérieure de l'âme du poteau (nette): 0.24 m2; Superficie inférieure du revêtement du poteau (nette): 0 m2; Superficie du revêtement du poteau (nette): 0 m2; Superficie supérieure du revêtement du poteau (nette): 0 m2; Périmètre de profil de poteau (base): 2000 mm; Volume du revêtement du poteau (net): 0 m3; Superficie: 0.24 m2; Hauteur: 3000 mm; Volume (net): 0.72 m3; Largeur: 600 mm; Altitude à Zéro du Projet: 0 mm; Altitude de Référence Niveau 1: 0 mm; Altitude de Référence Niveau 2: 0 mm; Altitude à niveau de la mer: 0 mm; Altitude à étage lié/étage d'implantation: 0 mm; Décalage étage d'implantation: 0 mm; Décalage supérieur: 0 mm; Superficie en plan: 6 m2; Longueur 3D: 3000 mm; Volume (brut): 0.72 m3; Altitude supérieure à premier niveau de référence: 3000 mm; Altitude supérieure à étage d'implantation: 3000 mm; Altitude supérieure à Zéro du projet: 3000 mm; Altitude supérieure à niveau de la mer: 3000 mm; Altitude supérieure à deuxième niveau de référence: 3000 mm; Altitude inférieure à premier niveau de référence: 0 mm; Altitude inférieure à étage d'implantation: 0 mm; Altitude inférieure à Zéro du projet: 0 mm; Altitude inférieure à niveau de la mer: 0 mm; Altitude inférieure à deuxième niveau de référence: 0 mm; Hauteur coupe transversale haut/fin (perpendiculaire): 400 mm; Hauteur coupe transversale bas/départ (perpendiculaire): 400 mm; Largeur coupe transversale haut/fin (perpendiculaire): 600 mm; Largeur coupe transversale bas/départ (perpendiculaire): 600 mm; Hauteur coupe transversale haut/fin (coupée): 400 mm; Hauteur coupe transversale bas/départ (coupée): 400 mm; Largeur coupe transversale haut/fin (coupée): 600 mm; Largeur coupe transversale bas/départ (coupée): 600 mm; Surface coupe transversale bas/départ (coupée): 0.24 m2; Surface coupe transversale haut/fin: 0.24 m2; Nombre de segments: 1; Superficie supérieure (nette): 0.24 m2; Superficie inférieure (nette): 6 m2; Superficie surface supérieure (Brute): 0.24 m2
ArchiCADProperties - Coupe transversale de Poteau: Rectangulaire; Angle d'inclinaison de Poteau: 90 deg; Surface d'extrusion: Lavis blanc; Surface de fin: Lavis blanc; Génération de modèle analytique structurel: yes; Membre étiré manuellement: no; ID de l'élément: Pilier-021; Lien et ID d'élément: Pilier-021; Calque: 3D; Matériau de construction / Composite / Profil / Hachure: Briques 314940890; Matériau de construction: Briques 314940890; Verrouillé: no; Nom d'étage d'implantation: sousol; Numéro d'étage d'implantation: 2; Type d'élément: Poteau; Étage supérieur lié absolu: Non lié; Étage supérieur lié relatif: Non lié; Étage supérieur lié: Non lié; Type de structure: Basique; ID de Parent: Pilier-021; Matériaux de construction (Tous): Briques 314940890; Surfaces (Toutes): Lavis blanc; Hachure de recouvrement: Sans Trame; Angle d'inclinaison: 90 deg; Nom de Variante: Modèle principal; Nom de Jeu de Variantes: Modèle principal; Position: Intérieur; Fonction structurelle: Élément porteur; Affichage sur filtre de rénovation: Tous les filtres appropriés; État de rénovation: Existant; État de Variante: Modèle principal; Jeu de Variantes: Modèle principal

# IfcColumn: Briques 314940890 680 x 300, Pilier-021
In: sousol
Classification: Poteau (Classification ARCHICAD); Material: Briques 314940890
ArchiCADProperties - Coupe transversale de Poteau: Rectangulaire; Angle d'inclinaison de Poteau: 90 deg; Surface d'extrusion: Lavis blanc; Surface de fin: Lavis blanc; Génération de modèle analytique structurel: yes; Membre étiré manuellement: no; ID de l'élément: Pilier-021; Lien et ID d'élément: Pilier-021; Calque: 3D; Matériau de construction / Composite / Profil / Hachure: Briques 314940890; Matériau de construction: Briques 314940890; Verrouillé: no; Nom d'étage d'implantation: sousol; Numéro d'étage d'implantation: 2; Type d'élément: Poteau; Étage supérieur lié absolu: Non lié; Étage supérieur lié relatif: Non lié; Étage supérieur lié: Non lié; Type de structure: Basique; ID de Parent: Pilier-021; Matériaux de construction (Tous): Briques 314940890; Surfaces (Toutes): Lavis blanc; Hachure de recouvrement: Sans Trame; Angle d'inclinaison: 90 deg; Nom de Variante: Modèle principal; Nom de Jeu de Variantes: Modèle principal; Position: Intérieur; Fonction structurelle: Élément porteur; Affichage sur filtre de rénovation: Tous les filtres appropriés; État de rénovation: Existant; État de Variante: Modèle principal; Jeu de Variantes: Modèle principal
AC_Pset_RenovationAndPhasing - Renovation Status: Existing
ArchiCADQuantities - Hauteur / Diamètre d'âme: 300 mm; Volume de l'âme du poteau (net): 0.612 m3; Largeur d'âme: 680 mm; Superficie de l'âme du poteau (brute, sans sommet/base): 5.88 m2; Superficie supérieure de l'âme du poteau (brute): 0.204 m2; Superficie inférieure de l'âme du poteau (brute): 0.204 m2; Volume de l'âme du poteau (brut): 0.612 m3; Superficie du revêtement du poteau (brute, sans sommet/base): 0 m2; Superficie supérieure du revêtement du poteau (brute): 0 m2; Superficie inférieure du revêtement du poteau (brute): 0 m2; Volume du revêtement du poteau (brut): 0 m3; Hauteur maximale du Poteau: 3000 mm; Hauteur minimale du Poteau: 3000 mm; Superficie inférieure de l'âme du poteau (nette): 0.204 m2; Superficie de l'âme du poteau (nette, sans sommet/base): 5.88 m2; Superficie supérieure de l'âme du poteau (nette): 0.204 m2; Superficie inférieure du revêtement du poteau (nette): 0 m2; Superficie du revêtement du poteau (nette): 0 m2; Superficie supérieure du revêtement du poteau (nette): 0 m2; Périmètre de profil de poteau (base): 1960 mm; Volume du revêtement du poteau (net): 0 m3; Superficie: 0.204 m2; Hauteur: 3000 mm; Volume (net): 0.612 m3; Largeur: 680 mm; Altitude à Zéro du Projet: 0 mm; Altitude de Référence Niveau 1: 0 mm; Altitude de Référence Niveau 2: 0 mm; Altitude à niveau de la mer: 0 mm; Altitude à étage lié/étage d'implantation: 0 mm; Décalage étage d'implantation: 0 mm; Décalage supérieur: 0 mm; Superficie en plan: 5.88 m2; Longueur 3D: 3000 mm; Volume (brut): 0.612 m3; Altitude supérieure à premier niveau de référence: 3000 mm; Altitude supérieure à étage d'implantation: 3000 mm; Altitude supérieure à Zéro du projet: 3000 mm; Altitude supérieure à niveau de la mer: 3000 mm; Altitude supérieure à deuxième niveau de référence: 3000 mm; Altitude inférieure à premier niveau de référence: 0 mm; Altitude inférieure à étage d'implantation: 0 mm; Altitude inférieure à Zéro du projet: 0 mm; Altitude inférieure à niveau de la mer: 0 mm; Altitude inférieure à deuxième niveau de référence: 0 mm; Hauteur coupe transversale haut/fin (perpendiculaire): 300 mm; Hauteur coupe transversale bas/départ (perpendiculaire): 300 mm; Largeur coupe transversale haut/fin (perpendiculaire): 680 mm; Largeur coupe transversale bas/départ (perpendiculaire): 680 mm; Hauteur coupe transversale haut/fin (coupée): 300 mm; Hauteur coupe transversale bas/départ (coupée): 300 mm; Largeur coupe transversale haut/fin (coupée): 680 mm; Largeur coupe transversale bas/départ (coupée): 680 mm; Surface coupe transversale bas/départ (coupée): 0.204 m2; Surface coupe transversale haut/fin: 0.204 m2; Nombre de segments: 1; Superficie supérieure (nette): 0.204 m2; Superficie inférieure (nette): 5.88 m2; Superficie surface supérieure (Brute): 0.204 m2

# IfcColumn: Empty Fill 2959611567 150 x 150 (33)
Classification: Poteau (Classification ARCHICAD); Material: Empty Fill 2959611567
ArchiCADProperties - Coupe transversale de Poteau: Rectangulaire; Angle d'inclinaison de Poteau: 90 deg; Surface d'extrusion: Innvik Tex Stripe 1440; Surface de fin: Innvik Tex Stripe 1440; Génération de modèle analytique structurel: yes; Membre étiré manuellement: no; ID de l'élément: Pilier-018; Lien et ID d'élément: Pilier-018; Calque: 3D; Matériau de construction / Composite / Profil / Hachure: Empty Fill 2959611567; Matériau de construction: Empty Fill 2959611567; Verrouillé: no; Type d'élément: Poteau; Étage supérieur lié absolu: Non lié; Étage supérieur lié relatif: Non lié; Étage supérieur lié: Non lié; Type de structure: Basique; ID de Parent: Pilier-018; Matériaux de construction (Tous): Empty Fill 2959611567; Surfaces (Toutes): Innvik Tex Stripe 1440; Hachure de recouvrement: Sans Trame; Angle d'inclinaison: 90 deg; Nom de Variante: Modèle principal; Nom de Jeu de Variantes: Modèle principal; Position: Intérieur; Fonction structurelle: Élément porteur; Affichage sur filtre de rénovation: Tous les filtres appropriés; État de rénovation: Existant; État de Variante: Modèle principal; Jeu de Variantes: Modèle principal
ArchiCADQuantities - Hauteur / Diamètre d'âme: 150 mm; Largeur d'âme: 150 mm; Superficie supérieure de l'âme du poteau (brute): 0.0225 m2; Superficie inférieure de l'âme du poteau (brute): 0.0225 m2; Superficie du revêtement du poteau (brute, sans sommet/base): 0 m2; Superficie supérieure du revêtement du poteau (brute): 0 m2; Superficie inférieure du revêtement du poteau (brute): 0 m2; Volume du revêtement du poteau (brut): 0 m3; Superficie inférieure de l'âme du poteau (nette): 0.0225 m2; Superficie supérieure de l'âme du poteau (nette): 0.0225 m2; Superficie inférieure du revêtement du poteau (nette): 0 m2; Superficie du revêtement du poteau (nette): 0 m2; Superficie supérieure du revêtement du poteau (nette): 0 m2; Périmètre de profil de poteau (base): 600 mm; Volume du revêtement du poteau (net): 0 m3; Superficie: 0.0225 m2; Largeur: 150 mm; Décalage supérieur: 0 mm; Hauteur coupe transversale haut/fin (perpendiculaire): 150 mm; Hauteur coupe transversale bas/départ (perpendiculaire): 150 mm; Largeur coupe transversale haut/fin (perpendiculaire): 150 mm; Largeur coupe transversale bas/départ (perpendiculaire): 150 mm; Hauteur coupe transversale haut/fin (coupée): 150 mm; Hauteur coupe transversale bas/départ (coupée): 150 mm; Largeur coupe transversale haut/fin (coupée): 150 mm; Largeur coupe transversale bas/départ (coupée): 150 mm; Surface coupe transversale bas/départ (coupée): 0.0225 m2; Surface coupe transversale haut/fin: 0.0225 m2; Nombre de segments: 1; Superficie supérieure (nette): 0.0225 m2; Superficie surface supérieure (Brute): 0.0225 m2
AC_Pset_RenovationAndPhasing - Renovation Status: Existing
Name | In | Nom d'étage d'implantation | Numéro d'étage d'implantation | Volume de l'âme du poteau (net) (m3) = Volume de l'âme du poteau (brut) (m3) = Volume (net) (m3) = Volume (brut) (m3) | Superficie de l'âme du poteau (brute, sans sommet/base) (m2) = Superficie de l'âme du poteau (nette, sans sommet/base) (m2) = Superficie en plan (m2) = Superficie inférieure (nette) (m2) | Hauteur maximale du Poteau (mm) = Hauteur minimale du Poteau (mm) = Hauteur (mm) = Longueur 3D (mm) | Altitude à Zéro du Projet (mm) = Altitude de Référence Niveau 1 (mm) = Altitude de Référence Niveau 2 (mm) = Altitude à niveau de la mer (mm) = Altitude inférieure à premier niveau de référence (mm) = Altitude inférieure à Zéro du projet (mm) = Altitude inférieure à niveau de la mer (mm) = Altitude inférieure à deuxième niveau de référence (mm) | Altitude à étage lié/étage d'implantation (mm) = Décalage étage d'implantation (mm) = Altitude inférieure à étage d'implantation (mm) | Altitude supérieure à premier niveau de référence (mm) = Altitude supérieure à Zéro du projet (mm) = Altitude supérieure à niveau de la mer (mm) = Altitude supérieure à deuxième niveau de référence (mm) | Altitude supérieure à étage d'implantation (mm)
4 x Pilier-018 | rdc | rdc | 3 | 0.06075 | 1.62 | 2700 | 2800 | -200 | 5500 | 2500
2 x Pilier-018 | etage 4 | etage 4 | 7 | 0.052875 | 1.41 | 2350 | 14598.3 | -1.70358 | 16948.3 | 2348.3
6 x Pilier-018 | etage 4 | etage 4 | 7 | 0.052875 | 1.41 | 2350 | 14600 | 0 | 16950 | 2350
8 x Pilier-018 | Etage 5 | Etage 5 | 8 | 0.065925 | 1.758 | 2930 | 14720 | -2930 | 17650 | 0
Pilier-018 | Etage 5 | Etage 5 | 8 | 0.06075 | 1.62 | 2700 | 14950 | -2700 | 17650 | 0
Pilier-018 | toiture2 | toiture2 | 10 | 0.06075 | 1.62 | 2700 | 20100 | -2950 | 22800 | -250 | ArchiCADProperties - Zones conflictuelles: Ch 4/Pl; Terrasse/eng.
Pilier-018 | toiture2 | toiture2 | 10 | 0.06075 | 1.62 | 2700 | 20100 | -2950 | 22800 | -250 | ArchiCADProperties - Zones conflictuelles: Ch 1; Terrasse/eng.
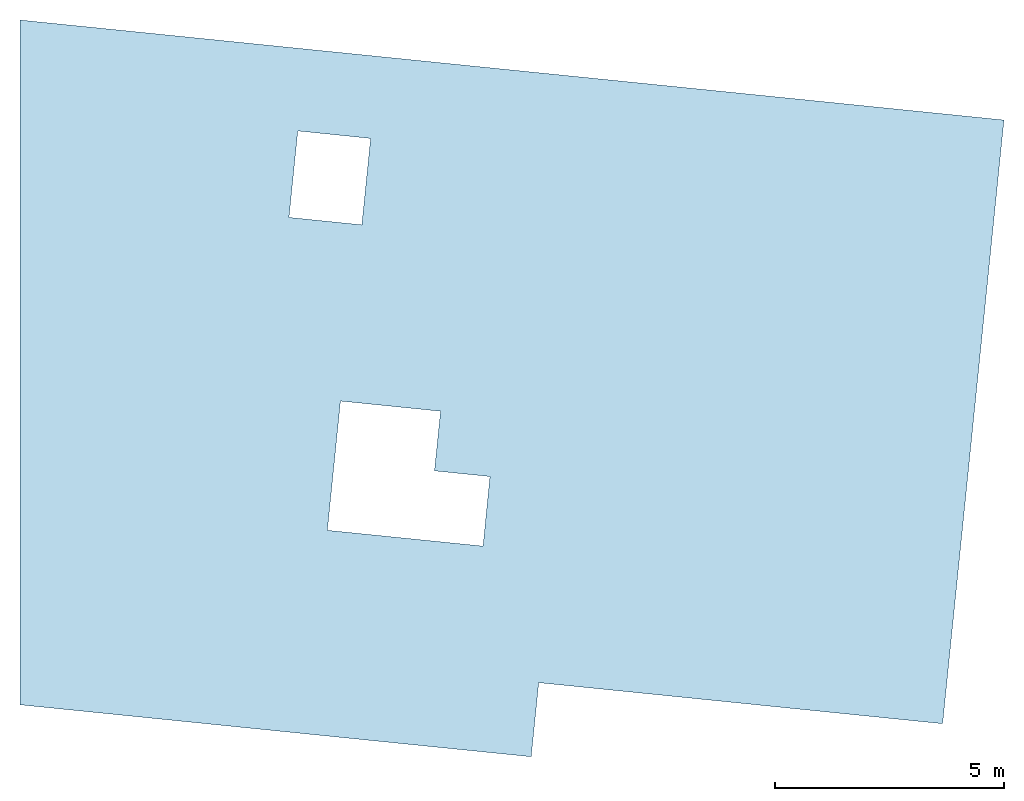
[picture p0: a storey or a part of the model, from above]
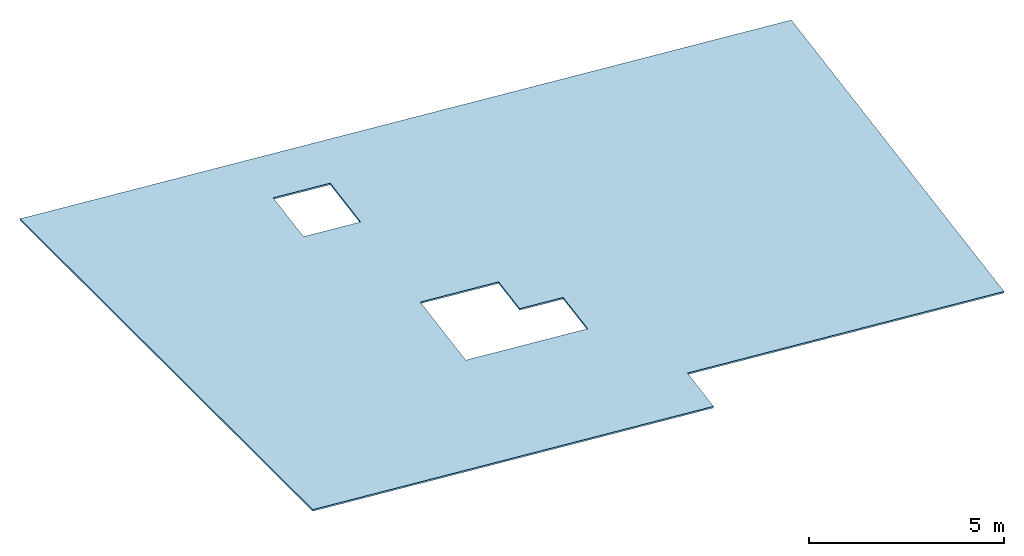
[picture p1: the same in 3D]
Properties of the parts of a building model (IFC2X3), part 10 of 44

# IfcColumn: Empty Fill 2959611567 150 x 150 (33)
Name | In | Nom d'étage d'implantation | Numéro d'étage d'implantation | Volume de l'âme du poteau (net) (m3) = Volume de l'âme du poteau (brut) (m3) = Volume (net) (m3) = Volume (brut) (m3) | Superficie de l'âme du poteau (brute, sans sommet/base) (m2) = Superficie de l'âme du poteau (nette, sans sommet/base) (m2) = Superficie en plan (m2) = Superficie inférieure (nette) (m2) | Hauteur maximale du Poteau (mm) = Hauteur minimale du Poteau (mm) = Hauteur (mm) = Longueur 3D (mm) | Altitude à Zéro du Projet (mm) = Altitude de Référence Niveau 1 (mm) = Altitude de Référence Niveau 2 (mm) = Altitude à niveau de la mer (mm) = Altitude inférieure à premier niveau de référence (mm) = Altitude inférieure à Zéro du projet (mm) = Altitude inférieure à niveau de la mer (mm) = Altitude inférieure à deuxième niveau de référence (mm) | Altitude à étage lié/étage d'implantation (mm) = Décalage étage d'implantation (mm) = Altitude inférieure à étage d'implantation (mm) | Altitude supérieure à premier niveau de référence (mm) = Altitude supérieure à Zéro du projet (mm) = Altitude supérieure à niveau de la mer (mm) = Altitude supérieure à deuxième niveau de référence (mm) | Altitude supérieure à étage d'implantation (mm)
4 x Pilier-018 | toiture2 | toiture2 | 10 | 0.06075 | 1.62 | 2700 | 20100 | -2950 | 22800 | -250 | ArchiCADProperties - Zones conflictuelles: Sejour Cuisine; Terrasse/eng.
Pilier-018 | toiture2 | toiture2 | 10 | 0.06075 | 1.62 | 2700 | 20100 | -2950 | 22800 | -250 | ArchiCADProperties - Zones conflictuelles: Terrasse/eng.
Pilier-018 | toiture2 | toiture2 | 10 | 0.06075 | 1.62 | 2700 | 20100 | -2950 | 22800 | -250 | ArchiCADProperties - Zones conflictuelles: Ch 3/pl; Terrasse/eng.
Pilier-018 | toiture2 | toiture2 | 10 | 0.06075 | 1.62 | 2700 | 20100 | -2950 | 22800 | -250 | ArchiCADProperties - Zones conflictuelles: Sde 1; Terrasse/eng.
Pilier-018 | toiture2 | toiture2 | 10 | 0.06075 | 1.62 | 2700 | 20100 | -2950 | 22800 | -250 | ArchiCADProperties - Zones conflictuelles: Sde 2; Terrasse/eng.
Pilier-018 | toiture2 | toiture2 | 10 | 0.06075 | 1.62 | 2700 | 20100 | -2950 | 22800 | -250 | ArchiCADProperties - Zones conflictuelles: Ch 1/pl; Terrasse/eng.
Pilier-018 | toiture2 | toiture2 | 10 | 0.06075 | 1.62 | 2700 | 20100 | -2950 | 22800 | -250 | ArchiCADProperties - Zones conflictuelles: Entree; Terrasse/eng.

# IfcColumn: Empty Fill 2959611567 30 x 60 (26)
In: rdc
Classification: Poteau (Classification ARCHICAD); Material: Empty Fill 2959611567
AC_Pset_RenovationAndPhasing - Renovation Status: Existing
ArchiCADQuantities - Hauteur / Diamètre d'âme: 60 mm; Volume de l'âme du poteau (net): 0.002268 m3; Largeur d'âme: 30 mm; Superficie de l'âme du poteau (brute, sans sommet/base): 0.2268 m2; Superficie supérieure de l'âme du poteau (brute): 0.0018 m2; Superficie inférieure de l'âme du poteau (brute): 0.0018 m2; Volume de l'âme du poteau (brut): 0.002268 m3; Superficie du revêtement du poteau (brute, sans sommet/base): 0 m2; Superficie supérieure du revêtement du poteau (brute): 0 m2; Superficie inférieure du revêtement du poteau (brute): 0 m2; Volume du revêtement du poteau (brut): 0 m3; Hauteur maximale du Poteau: 1260 mm; Hauteur minimale du Poteau: 1260 mm; Superficie inférieure de l'âme du poteau (nette): 0.0018 m2; Superficie de l'âme du poteau (nette, sans sommet/base): 0.2268 m2; Superficie supérieure de l'âme du poteau (nette): 0.0018 m2; Superficie inférieure du revêtement du poteau (nette): 0 m2; Superficie du revêtement du poteau (nette): 0 m2; Superficie supérieure du revêtement du poteau (nette): 0 m2; Périmètre de profil de poteau (base): 180 mm; Volume du revêtement du poteau (net): 0 m3; Superficie: 0.0018 m2; Hauteur: 1260 mm; Volume (net): 0.002268 m3; Largeur: 30 mm; Décalage supérieur: 0 mm; Superficie en plan: 0.2268 m2; Longueur 3D: 1260 mm; Volume (brut): 0.002268 m3; Hauteur coupe transversale haut/fin (perpendiculaire): 60 mm; Hauteur coupe transversale bas/départ (perpendiculaire): 60 mm; Largeur coupe transversale haut/fin (perpendiculaire): 30 mm; Largeur coupe transversale bas/départ (perpendiculaire): 30 mm; Hauteur coupe transversale haut/fin (coupée): 60 mm; Hauteur coupe transversale bas/départ (coupée): 60 mm; Largeur coupe transversale haut/fin (coupée): 30 mm; Largeur coupe transversale bas/départ (coupée): 30 mm; Surface coupe transversale bas/départ (coupée): 0.0018 m2; Surface coupe transversale haut/fin: 0.0018 m2; Nombre de segments: 1; Superficie supérieure (nette): 0.0018 m2; Superficie inférieure (nette): 0.2268 m2; Superficie surface supérieure (Brute): 0.0018 m2
ArchiCADProperties - Coupe transversale de Poteau: Rectangulaire; Angle d'inclinaison de Poteau: 90 deg; Surface d'extrusion: Lavis blanc; Surface de fin: Lavis blanc; Génération de modèle analytique structurel: yes; Membre étiré manuellement: no; ID de l'élément: Pilier-019; Lien et ID d'élément: Pilier-019; Calque: 3D; Matériau de construction / Composite / Profil / Hachure: Empty Fill 2959611567; Matériau de construction: Empty Fill 2959611567; Verrouillé: no; Nom d'étage d'implantation: rdc; Numéro d'étage d'implantation: 3; Type d'élément: Poteau; Étage supérieur lié absolu: Non lié; Étage supérieur lié relatif: Non lié; Étage supérieur lié: Non lié; Type de structure: Basique; ID de Parent: Pilier-019; Matériaux de construction (Tous): Empty Fill 2959611567; Surfaces (Toutes): Lavis blanc; Hachure de recouvrement: Sans Trame; Angle d'inclinaison: 90 deg; Nom de Variante: Modèle principal; Nom de Jeu de Variantes: Modèle principal; Position: Intérieur; Fonction structurelle: Élément porteur; Affichage sur filtre de rénovation: Tous les filtres appropriés; État de rénovation: Existant; État de Variante: Modèle principal; Jeu de Variantes: Modèle principal
Name | Altitude à Zéro du Projet (mm) = Altitude de Référence Niveau 1 (mm) = Altitude de Référence Niveau 2 (mm) = Altitude à niveau de la mer (mm) = Altitude inférieure à premier niveau de référence (mm) = Altitude inférieure à Zéro du projet (mm) = Altitude inférieure à niveau de la mer (mm) = Altitude inférieure à deuxième niveau de référence (mm) | Altitude à étage lié/étage d'implantation (mm) = Décalage étage d'implantation (mm) = Altitude inférieure à étage d'implantation (mm) | Altitude supérieure à premier niveau de référence (mm) = Altitude supérieure à Zéro du projet (mm) = Altitude supérieure à niveau de la mer (mm) = Altitude supérieure à deuxième niveau de référence (mm) | Altitude supérieure à étage d'implantation (mm)
18 x Pilier-019 | 900 | -2100 | 2160 | -840
Pilier-019 | 988.217 | -2011.78 | 2248.22 | -751.783
7 x Pilier-019 | 3000 | 0 | 4260 | 1260

# IfcColumn: Empty Fill 2959611567 50 x 10 (4)
In: toiture
Classification: Poteau (Classification ARCHICAD); Material: Empty Fill 2959611567
ArchiCADProperties - Coupe transversale de Poteau: Rectangulaire; Angle d'inclinaison de Poteau: 90 deg; Surface d'extrusion: Métal-Inox; Surface de fin: Métal-Inox; Génération de modèle analytique structurel: yes; Membre étiré manuellement: no; ID de l'élément: Pilier-020; Lien et ID d'élément: Pilier-020; Calque: 3D; Matériau de construction / Composite / Profil / Hachure: Empty Fill 2959611567; Matériau de construction: Empty Fill 2959611567; Verrouillé: no; Nom d'étage d'implantation: toiture; Numéro d'étage d'implantation: 9; Type d'élément: Poteau; Étage supérieur lié absolu: Non lié; Étage supérieur lié relatif: Non lié; Étage supérieur lié: Non lié; Type de structure: Basique; ID de Parent: Pilier-020; Matériaux de construction (Tous): Empty Fill 2959611567; Surfaces (Toutes): Métal-Inox; Hachure de recouvrement: Sans Trame; Angle d'inclinaison: 90 deg; Nom de Variante: Modèle principal; Nom de Jeu de Variantes: Modèle principal; Position: Intérieur; Fonction structurelle: Élément porteur; Affichage sur filtre de rénovation: Tous les filtres appropriés; État de rénovation: Existant; État de Variante: Modèle principal; Jeu de Variantes: Modèle principal
AC_Pset_RenovationAndPhasing - Renovation Status: Existing
ArchiCADQuantities - Hauteur / Diamètre d'âme: 10 mm; Largeur d'âme: 50 mm; Superficie supérieure de l'âme du poteau (brute): 0.0005 m2; Superficie inférieure de l'âme du poteau (brute): 0.0005 m2; Superficie du revêtement du poteau (brute, sans sommet/base): 0 m2; Superficie supérieure du revêtement du poteau (brute): 0 m2; Superficie inférieure du revêtement du poteau (brute): 0 m2; Volume du revêtement du poteau (brut): 0 m3; Superficie inférieure de l'âme du poteau (nette): 0.0005 m2; Superficie supérieure de l'âme du poteau (nette): 0.0005 m2; Superficie inférieure du revêtement du poteau (nette): 0 m2; Superficie du revêtement du poteau (nette): 0 m2; Superficie supérieure du revêtement du poteau (nette): 0 m2; Périmètre de profil de poteau (base): 120 mm; Volume du revêtement du poteau (net): 0 m3; Superficie: 0.0005 m2; Largeur: 50 mm; Décalage supérieur: 0 mm; Hauteur coupe transversale haut/fin (perpendiculaire): 10 mm; Hauteur coupe transversale bas/départ (perpendiculaire): 10 mm; Largeur coupe transversale haut/fin (perpendiculaire): 50 mm; Largeur coupe transversale bas/départ (perpendiculaire): 50 mm; Hauteur coupe transversale haut/fin (coupée): 10 mm; Hauteur coupe transversale bas/départ (coupée): 10 mm; Largeur coupe transversale haut/fin (coupée): 50 mm; Largeur coupe transversale bas/départ (coupée): 50 mm; Surface coupe transversale bas/départ (coupée): 0.0005 m2; Surface coupe transversale haut/fin: 0.0005 m2; Nombre de segments: 1; Superficie supérieure (nette): 0.0005 m2; Superficie surface supérieure (Brute): 0.0005 m2
Name | Zones conflictuelles | Volume de l'âme du poteau (net) (m3) = Volume de l'âme du poteau (brut) (m3) = Volume (net) (m3) = Volume (brut) (m3) | Superficie de l'âme du poteau (brute, sans sommet/base) (m2) = Superficie de l'âme du poteau (nette, sans sommet/base) (m2) = Superficie en plan (m2) = Superficie inférieure (nette) (m2) | Hauteur maximale du Poteau (mm) = Hauteur minimale du Poteau (mm) = Hauteur (mm) = Longueur 3D (mm) | Altitude à Zéro du Projet (mm) = Altitude de Référence Niveau 1 (mm) = Altitude de Référence Niveau 2 (mm) = Altitude à niveau de la mer (mm) = Altitude inférieure à premier niveau de référence (mm) = Altitude inférieure à Zéro du projet (mm) = Altitude inférieure à niveau de la mer (mm) = Altitude inférieure à deuxième niveau de référence (mm) | Altitude à étage lié/étage d'implantation (mm) = Décalage étage d'implantation (mm) = Altitude inférieure à étage d'implantation (mm) | Altitude supérieure à premier niveau de référence (mm) = Altitude supérieure à Zéro du projet (mm) = Altitude supérieure à niveau de la mer (mm) = Altitude supérieure à deuxième niveau de référence (mm) | Altitude supérieure à étage d'implantation (mm)
Pilier-020 | Terrasse | 0.000608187 | 0.145965 | 1216.37 | 18750 | -1599.96 | 19966.4 | -383.588
Pilier-020 | Terrasse | 0.000613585 | 0.14726 | 1227.17 | 17773.1 | -2576.95 | 19000.2 | -1349.78
Pilier-020 | Terrasse | 0.000613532 | 0.147248 | 1227.06 | 19702.1 | -647.854 | 20929.2 | 579.211
Pilier-020 |  | 0.000563 | 0.13512 | 1126 | 20674 | 324 | 21800 | 1450

# IfcColumn: Empty Fill 2959611567 D20 (498)
Classification: Poteau (Classification ARCHICAD); Material: Empty Fill 2959611567
ArchiCADProperties - Coupe transversale de Poteau: Circulaire; Génération de modèle analytique structurel: yes; Membre étiré manuellement: no; Calque: 3D; Matériau de construction / Composite / Profil / Hachure: Empty Fill 2959611567; Matériau de construction: Empty Fill 2959611567; Verrouillé: no; Type d'élément: Poteau; Étage supérieur lié absolu: Non lié; Étage supérieur lié relatif: Non lié; Étage supérieur lié: Non lié; Type de structure: Basique; Matériaux de construction (Tous): Empty Fill 2959611567; Hachure de recouvrement: Sans Trame; Nom de Variante: Modèle principal; Nom de Jeu de Variantes: Modèle principal; Position: Intérieur; Fonction structurelle: Élément porteur; Affichage sur filtre de rénovation: Tous les filtres appropriés; État de rénovation: Existant; État de Variante: Modèle principal; Jeu de Variantes: Modèle principal
ArchiCADQuantities - Hauteur / Diamètre d'âme: 20 mm; Largeur d'âme: 20 mm; Superficie du revêtement du poteau (brute, sans sommet/base): 0 m2; Superficie supérieure du revêtement du poteau (brute): 0 m2; Superficie inférieure du revêtement du poteau (brute): 0 m2; Volume du revêtement du poteau (brut): 0 m3; Superficie inférieure du revêtement du poteau (nette): 0 m2; Superficie du revêtement du poteau (nette): 0 m2; Superficie supérieure du revêtement du poteau (nette): 0 m2; Périmètre de profil de poteau (base): 62.8319 mm; Volume du revêtement du poteau (net): 0 m3; Largeur: 20 mm; Décalage supérieur: 0 mm; Hauteur coupe transversale haut/fin (perpendiculaire): 20 mm; Hauteur coupe transversale bas/départ (perpendiculaire): 20 mm; Largeur coupe transversale haut/fin (perpendiculaire): 20 mm; Largeur coupe transversale bas/départ (perpendiculaire): 20 mm; Largeur coupe transversale haut/fin (coupée): 20 mm; Largeur coupe transversale bas/départ (coupée): 20 mm; Nombre de segments: 1
AC_Pset_RenovationAndPhasing - Renovation Status: Existing
Name | In | Angle d'inclinaison de Poteau (deg) = Angle d'inclinaison (deg) | Surface d'extrusion = Surface de fin = Surfaces (Toutes) | ID de l'élément = Lien et ID d'élément = ID de Parent | Nom d'étage d'implantation | Numéro d'étage d'implantation | Volume de l'âme du poteau (net) (m3) = Volume de l'âme du poteau (brut) (m3) = Volume (net) (m3) = Volume (brut) (m3) | Superficie de l'âme du poteau (brute, sans sommet/base) (m2) = Superficie de l'âme du poteau (nette, sans sommet/base) (m2) = Superficie en plan (m2) = Superficie inférieure (nette) (m2) | Superficie supérieure de l'âme du poteau (brute) (m2) = Superficie inférieure de l'âme du poteau (brute) (m2) = Superficie inférieure de l'âme du poteau (nette) (m2) = Superficie supérieure de l'âme du poteau (nette) (m2) = Superficie (m2) = Surface coupe transversale bas/départ (coupée) (m2) = Surface coupe transversale haut/fin (m2) = Superficie supérieure (nette) (m2) = Superficie surface supérieure (Brute) (m2) | Hauteur maximale du Poteau (mm) = Hauteur minimale du Poteau (mm) = Hauteur (mm) | Altitude à Zéro du Projet (mm) = Altitude de Référence Niveau 1 (mm) = Altitude de Référence Niveau 2 (mm) = Altitude à niveau de la mer (mm) = Altitude inférieure à premier niveau de référence (mm) = Altitude inférieure à Zéro du projet (mm) = Altitude inférieure à niveau de la mer (mm) = Altitude inférieure à deuxième niveau de référence (mm) | Altitude à étage lié/étage d'implantation (mm) = Décalage étage d'implantation (mm) = Altitude inférieure à étage d'implantation (mm) | Longueur 3D (mm) | Altitude supérieure à premier niveau de référence (mm) = Altitude supérieure à Zéro du projet (mm) = Altitude supérieure à niveau de la mer (mm) = Altitude supérieure à deuxième niveau de référence (mm) | Altitude supérieure à étage d'implantation (mm) | Hauteur coupe transversale haut/fin (coupée) (mm) = Hauteur coupe transversale bas/départ (coupée) (mm)
85 x Pilier-019 | rdc | 85 | Surface-Porcelaine | Pilier-019 | rdc | 3 | 0.000387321 | 0.0774641 | 0.000322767 | 1200 | 1050 | -1950 | 1206.33 | 2250 | -750 | 20.0764
5 x Pilier-019 | rdc | 81 | Surface-Porcelaine | Pilier-019 | rdc | 3 | 0.000390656 | 0.0781313 | 0.000325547 | 1200 | 3150 | 150 | 1218.13 | 4350 | 1350 | 20.2493
14 x Pilier-019 | rdc | 81 | Surface-Porcelaine | Pilier-019 | rdc | 3 | 0.000390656 | 0.0781313 | 0.000325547 | 1200 | 1050 | -1950 | 1218.13 | 2250 | -750 | 20.2493
86 x Pilier-019 | rdc | 87 | Surface-Porcelaine | Pilier-019 | rdc | 3 | 0.000386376 | 0.0772753 | 0.00032198 | 1200 | 1050 | -1950 | 1202.69 | 2250 | -750 | 20.0274
3 x Pilier-019 | rdc | 84 | Surface-Porcelaine | Pilier-019 | rdc | 3 | 0.000427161 | 0.0854322 | 0.00032331 | 1321.21 | 928.789 | -2071.21 | 1330.59 | 2250 | -750 | 20.1102
100 x Pilier-019 | rdc | 88 | Surface-Porcelaine | Pilier-019 | rdc | 3 | 0.000386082 | 0.0772164 | 0.000321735 | 1200 | 1050 | -1950 | 1201.43 | 2250 | -750 | 20.0122
19 x Pilier-019 | rdc | 88 | Surface-Porcelaine | Pilier-019 | rdc | 3 | 0.00042508 | 0.085016 | 0.000321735 | 1321.21 | 928.789 | -2071.21 | 1322.71 | 2250 | -750 | 20.0122
16 x Pilier-019 | rdc | 85 | Surface-Porcelaine | Pilier-019 | rdc | 3 | 0.000426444 | 0.0852887 | 0.000322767 | 1321.21 | 928.789 | -2071.21 | 1328.01 | 2250 | -750 | 20.0764
3 x Pilier-019 | rdc | 82 | Surface-Porcelaine | Pilier-019 | rdc | 3 | 0.000428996 | 0.0857992 | 0.000324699 | 1321.21 | 928.789 | -2071.21 | 1337.01 | 2250 | -750 | 20.1966
17 x Pilier-019 | rdc | 87 | Surface-Porcelaine | Pilier-019 | rdc | 3 | 0.000425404 | 0.0850808 | 0.00032198 | 1321.21 | 928.789 | -2071.21 | 1324.07 | 2250 | -750 | 20.0274
14 x Pilier-019 | rdc | 82 | Surface-Porcelaine | Pilier-019 | rdc | 3 | 0.000389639 | 0.0779278 | 0.000324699 | 1200 | 1050 | -1950 | 1214.6 | 2250 | -750 | 20.1966
14 x Pilier-019 | rdc | 84 | Surface-Porcelaine | Pilier-019 | rdc | 3 | 0.000387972 | 0.0775944 | 0.00032331 | 1200 | 1050 | -1950 | 1208.71 | 2250 | -750 | 20.1102
3 x Pilier-019 | rdc | 81 | Surface-Porcelaine | Pilier-019 | rdc | 3 | 0.000430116 | 0.0860233 | 0.000325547 | 1321.21 | 928.789 | -2071.21 | 1340.85 | 2250 | -750 | 20.2493
5 x Pilier-019 | rdc | 87 | Surface-Porcelaine | Pilier-019 | rdc | 3 | 0.000414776 | 0.0829553 | 0.00032198 | 1288.2 | 961.796 | -2038.2 | 1291.02 | 2250 | -750 | 20.0274
3 x Pilier-019 | rdc | 85 | Surface-Porcelaine | Pilier-019 | rdc | 3 | 0.00041579 | 0.083158 | 0.000322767 | 1288.2 | 961.796 | -2038.2 | 1294.87 | 2250 | -750 | 20.0764
4 x Pilier-019 | rdc | 88 | Surface-Porcelaine | Pilier-019 | rdc | 3 | 0.00041446 | 0.0828921 | 0.000321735 | 1288.2 | 961.796 | -2038.2 | 1289.69 | 2250 | -750 | 20.0122
Pilier-019 | rdc | 82 | Surface-Porcelaine | Pilier-019 | rdc | 3 | 0.000418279 | 0.0836557 | 0.000324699 | 1288.2 | 961.796 | -2038.2 | 1303.68 | 2250 | -750 | 20.1966
25 x Pilier-019 | rdc | 87 | Surface-Porcelaine | Pilier-019 | rdc | 3 | 0.000386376 | 0.0772753 | 0.00032198 | 1200 | 3150 | 150 | 1202.69 | 4350 | 1350 | 20.0274
28 x Pilier-019 | rdc | 88 | Surface-Porcelaine | Pilier-019 | rdc | 3 | 0.000386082 | 0.0772164 | 0.000321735 | 1200 | 3150 | 150 | 1201.43 | 4350 | 1350 | 20.0122
24 x Pilier-019 | rdc | 85 | Surface-Porcelaine | Pilier-019 | rdc | 3 | 0.000387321 | 0.0774641 | 0.000322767 | 1200 | 3150 | 150 | 1206.33 | 4350 | 1350 | 20.0764
3 x Pilier-019 | rdc | 84 | Surface-Porcelaine | Pilier-019 | rdc | 3 | 0.000387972 | 0.0775944 | 0.00032331 | 1200 | 3150 | 150 | 1208.71 | 4350 | 1350 | 20.1102
5 x Pilier-019 | rdc | 82 | Surface-Porcelaine | Pilier-019 | rdc | 3 | 0.000389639 | 0.0779278 | 0.000324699 | 1200 | 3150 | 150 | 1214.6 | 4350 | 1350 | 20.1966
3 x Pilier-019 | rdc | 87 | Surface-Porcelaine | Pilier-019 | rdc | 3 | 0.000556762 | 0.111352 | 0.00032198 | 1729.18 | 2620.82 | -379.18 | 1732.6 | 4350 | 1350 | 20.0274
4 x Pilier-019 | rdc | 88 | Surface-Porcelaine | Pilier-019 | rdc | 3 | 0.000556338 | 0.111268 | 0.000321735 | 1729.18 | 2620.82 | -379.18 | 1730.93 | 4350 | 1350 | 20.0122
Pilier-019 | rdc | 88.8101 | Surface-Porcelaine | Pilier-019 | rdc | 3 | 0.000556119 | 0.111224 | 0.000321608 | 1729.18 | 2620.82 | -379.18 | 1729.97 | 4350 | 1350 | 20.0043
Pilier-019 | rdc | 84.9658 | Surface-Porcelaine | Pilier-019 | rdc | 3 | 0.000558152 | 0.11163 | 0.000322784 | 1729.18 | 2620.82 | -379.18 | 1737.64 | 4350 | 1350 | 20.0774
3 x Pilier-019 | rdc | 85 | Surface-Porcelaine | Pilier-019 | rdc | 3 | 0.000558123 | 0.111625 | 0.000322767 | 1729.18 | 2620.82 | -379.18 | 1737.54 | 4350 | 1350 | 20.0764
Pilier-019 | rdc | 88.007 | Surface-Porcelaine | Pilier-019 | rdc | 3 | 0.000556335 | 0.111267 | 0.000321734 | 1729.18 | 2620.82 | -379.18 | 1730.92 | 4350 | 1350 | 20.0121
Pilier-019 | rdc | 86.389 | Surface-Porcelaine | Pilier-019 | rdc | 3 | 0.000557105 | 0.111421 | 0.000322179 | 1729.18 | 2620.82 | -379.18 | 1733.88 | 4350 | 1350 | 20.0398
Pilier-020 | toiture | 29.29 | Métal-Inox | Pilier-020 | toiture | 9 | 0.00185967 | 0.371935 | 0.000657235 | 2829.54 | 18869 | -1480.96 | 5819.32 | 21698.6 | 1348.58 | 40.8805 | ArchiCADProperties - Zones conflictuelles: Terrasse
Pilier-020 | toiture | 29.29 | Métal-Inox | Pilier-020 | toiture | 9 | 0.00190172 | 0.380343 | 0.000657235 | 2893.51 | 18238.4 | -2111.58 | 5950.08 | 21131.9 | 781.93 | 40.8805 | ArchiCADProperties - Zones conflictuelles: Terrasse
Pilier-020 | toiture | 29.29 | Métal-Inox | Pilier-020 | toiture | 9 | 0.00190172 | 0.380343 | 0.000657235 | 2893.51 | 18112.3 | -2237.71 | 5950.08 | 21005.8 | 655.805 | 40.8805 | ArchiCADProperties - Zones conflictuelles: Terrasse
Pilier-020 | toiture | 29.29 | Métal-Inox | Pilier-020 | toiture | 9 | 0.00189387 | 0.378774 | 0.000657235 | 2881.57 | 18364.5 | -1985.46 | 5925.66 | 21246.1 | 896.111 | 40.8805 | ArchiCADProperties - Zones conflictuelles: Terrasse
Pilier-020 | toiture | 29.29 | Métal-Inox | Pilier-020 | toiture | 9 | 0.00188151 | 0.376302 | 0.000657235 | 2862.76 | 18490.7 | -1859.34 | 5887.22 | 21353.4 | 1003.43 | 40.8805 | ArchiCADProperties - Zones conflictuelles: Terrasse
Pilier-020 | toiture | 29.29 | Métal-Inox | Pilier-020 | toiture | 9 | 0.00186753 | 0.373507 | 0.000657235 | 2841.5 | 18742.9 | -1607.09 | 5843.76 | 21584.4 | 1234.42 | 40.8805 | ArchiCADProperties - Zones conflictuelles: Terrasse
Pilier-020 | toiture | 29.29 | Métal-Inox | Pilier-020 | toiture | 9 | 0.00187515 | 0.37503 | 0.000657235 | 2853.09 | 18616.8 | -1733.21 | 5867.45 | 21469.9 | 1119.88 | 40.8805 | ArchiCADProperties - Zones conflictuelles: Terrasse

# IfcColumn: Empty Fill 2959611567 D30 (33)
Classification: Poteau (Classification ARCHICAD); Material: Empty Fill 2959611567
ArchiCADProperties - Coupe transversale de Poteau: Circulaire; Surface d'extrusion: Innvik Tex Stripe 1440; Surface de fin: Innvik Tex Stripe 1440; Génération de modèle analytique structurel: yes; Membre étiré manuellement: no; ID de l'élément: Pilier-018; Lien et ID d'élément: Pilier-018; Calque: 3D; Matériau de construction / Composite / Profil / Hachure: Empty Fill 2959611567; Matériau de construction: Empty Fill 2959611567; Verrouillé: no; Type d'élément: Poteau; Étage supérieur lié absolu: Non lié; Étage supérieur lié relatif: Non lié; Étage supérieur lié: Non lié; Type de structure: Basique; ID de Parent: Pilier-018; Matériaux de construction (Tous): Empty Fill 2959611567; Surfaces (Toutes): Innvik Tex Stripe 1440; Hachure de recouvrement: Sans Trame; Nom de Variante: Modèle principal; Nom de Jeu de Variantes: Modèle principal; Position: Intérieur; Fonction structurelle: Élément porteur; Affichage sur filtre de rénovation: Tous les filtres appropriés; État de rénovation: Existant; État de Variante: Modèle principal; Jeu de Variantes: Modèle principal
ArchiCADQuantities - Hauteur / Diamètre d'âme: 30 mm; Largeur d'âme: 30 mm; Superficie du revêtement du poteau (brute, sans sommet/base): 0 m2; Superficie supérieure du revêtement du poteau (brute): 0 m2; Superficie inférieure du revêtement du poteau (brute): 0 m2; Volume du revêtement du poteau (brut): 0 m3; Superficie inférieure du revêtement du poteau (nette): 0 m2; Superficie du revêtement du poteau (nette): 0 m2; Superficie supérieure du revêtement du poteau (nette): 0 m2; Périmètre de profil de poteau (base): 94.2478 mm; Volume du revêtement du poteau (net): 0 m3; Largeur: 30 mm; Décalage supérieur: 0 mm; Hauteur coupe transversale haut/fin (perpendiculaire): 30 mm; Hauteur coupe transversale bas/départ (perpendiculaire): 30 mm; Largeur coupe transversale haut/fin (perpendiculaire): 30 mm; Largeur coupe transversale bas/départ (perpendiculaire): 30 mm; Largeur coupe transversale haut/fin (coupée): 30 mm; Largeur coupe transversale bas/départ (coupée): 30 mm; Nombre de segments: 1
AC_Pset_RenovationAndPhasing - Renovation Status: Existing
Name | In | Angle d'inclinaison de Poteau (deg) = Angle d'inclinaison (deg) | Nom d'étage d'implantation | Numéro d'étage d'implantation | Volume de l'âme du poteau (net) (m3) = Volume de l'âme du poteau (brut) (m3) = Volume (net) (m3) = Volume (brut) (m3) | Superficie de l'âme du poteau (brute, sans sommet/base) (m2) = Superficie de l'âme du poteau (nette, sans sommet/base) (m2) = Superficie en plan (m2) = Superficie inférieure (nette) (m2) | Superficie supérieure de l'âme du poteau (brute) (m2) = Superficie inférieure de l'âme du poteau (brute) (m2) = Superficie inférieure de l'âme du poteau (nette) (m2) = Superficie supérieure de l'âme du poteau (nette) (m2) = Superficie (m2) = Surface coupe transversale bas/départ (coupée) (m2) = Surface coupe transversale haut/fin (m2) = Superficie supérieure (nette) (m2) = Superficie surface supérieure (Brute) (m2) | Hauteur maximale du Poteau (mm) = Hauteur minimale du Poteau (mm) = Hauteur (mm) | Altitude à Zéro du Projet (mm) = Altitude de Référence Niveau 1 (mm) = Altitude de Référence Niveau 2 (mm) = Altitude à niveau de la mer (mm) = Altitude inférieure à premier niveau de référence (mm) = Altitude inférieure à Zéro du projet (mm) = Altitude inférieure à niveau de la mer (mm) = Altitude inférieure à deuxième niveau de référence (mm) | Altitude à étage lié/étage d'implantation (mm) = Décalage étage d'implantation (mm) | Longueur 3D (mm) | Altitude supérieure à premier niveau de référence (mm) = Altitude supérieure à Zéro du projet (mm) = Altitude supérieure à niveau de la mer (mm) = Altitude supérieure à deuxième niveau de référence (mm) | Altitude supérieure à étage d'implantation (mm) | Altitude inférieure à étage d'implantation (mm) | Hauteur coupe transversale haut/fin (coupée) (mm) = Hauteur coupe transversale bas/départ (coupée) (mm)
7 x Pilier-018 | etage 4 | 35 | etage 4 | 7 | 0.000882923 | 0.117723 | 0.00126132 | 700 | 14120.7 | -479.3 | 1263.26 | 14820.7 | 220.7 | -479.3 | 52.3034
14 x Pilier-018 | etage 4 | 20 | etage 4 | 7 | 0.000740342 | 0.0987123 | 0.00211526 | 350 | 14120.7 | -479.3 | 1105.76 | 14470.7 | -129.3 | -479.3 | 87.7141
3 x Pilier-018 | toiture | 38 | toiture | 9 | 0.000881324 | 0.11751 | 0.0011751 | 750 | 20350 | 0 | 1256.6 | 21100 | 750 | -7.10543e-12 | 48.7281
9 x Pilier-018 | toiture | 38 | toiture | 9 | 0.000881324 | 0.11751 | 0.0011751 | 750 | 20350 | 0 | 1256.6 | 21100 | 750 | -1.42109e-11 | 48.7281

# IfcColumn: Minimal space 288701002 150 x 150 (9)
Classification: Poteau (Classification ARCHICAD); Material: Minimal space 288701002
ArchiCADProperties - Coupe transversale de Poteau: Rectangulaire; Angle d'inclinaison de Poteau: 90 deg; Surface d'extrusion: Innvik Tex Stripe 1440; Surface de fin: Innvik Tex Stripe 1440; Génération de modèle analytique structurel: yes; Membre étiré manuellement: no; ID de l'élément: Pilier-018; Lien et ID d'élément: Pilier-018; Calque: 3D; Matériau de construction / Composite / Profil / Hachure: Minimal space 288701002; Matériau de construction: Minimal space 288701002; Verrouillé: no; Type d'élément: Poteau; Étage supérieur lié absolu: Non lié; Étage supérieur lié relatif: Non lié; Étage supérieur lié: Non lié; Type de structure: Basique; ID de Parent: Pilier-018; Matériaux de construction (Tous): Minimal space 288701002; Surfaces (Toutes): Innvik Tex Stripe 1440; Angle d'inclinaison: 90 deg; Nom de Variante: Modèle principal; Nom de Jeu de Variantes: Modèle principal; Position: Intérieur; Fonction structurelle: Élément porteur; Affichage sur filtre de rénovation: Tous les filtres appropriés; État de rénovation: Existant; État de Variante: Modèle principal; Jeu de Variantes: Modèle principal
AC_Pset_RenovationAndPhasing - Renovation Status: Existing
ArchiCADQuantities - Hauteur / Diamètre d'âme: 150 mm; Volume de l'âme du poteau (net): 0.057375 m3; Largeur d'âme: 150 mm; Superficie de l'âme du poteau (brute, sans sommet/base): 1.53 m2; Superficie supérieure de l'âme du poteau (brute): 0.0225 m2; Superficie inférieure de l'âme du poteau (brute): 0.0225 m2; Volume de l'âme du poteau (brut): 0.057375 m3; Superficie du revêtement du poteau (brute, sans sommet/base): 0 m2; Superficie supérieure du revêtement du poteau (brute): 0 m2; Superficie inférieure du revêtement du poteau (brute): 0 m2; Volume du revêtement du poteau (brut): 0 m3; Hauteur maximale du Poteau: 2550 mm; Hauteur minimale du Poteau: 2550 mm; Superficie inférieure de l'âme du poteau (nette): 0.0225 m2; Superficie de l'âme du poteau (nette, sans sommet/base): 1.53 m2; Superficie supérieure de l'âme du poteau (nette): 0.0225 m2; Superficie inférieure du revêtement du poteau (nette): 0 m2; Superficie du revêtement du poteau (nette): 0 m2; Superficie supérieure du revêtement du poteau (nette): 0 m2; Périmètre de profil de poteau (base): 600 mm; Volume du revêtement du poteau (net): 0 m3; Superficie: 0.0225 m2; Hauteur: 2550 mm; Volume (net): 0.057375 m3; Largeur: 150 mm; Altitude à étage lié/étage d'implantation: 0 mm; Décalage étage d'implantation: 0 mm; Décalage supérieur: 0 mm; Superficie en plan: 1.53 m2; Longueur 3D: 2550 mm; Volume (brut): 0.057375 m3; Altitude supérieure à étage d'implantation: 2550 mm; Altitude inférieure à étage d'implantation: 0 mm; Hauteur coupe transversale haut/fin (perpendiculaire): 150 mm; Hauteur coupe transversale bas/départ (perpendiculaire): 150 mm; Largeur coupe transversale haut/fin (perpendiculaire): 150 mm; Largeur coupe transversale bas/départ (perpendiculaire): 150 mm; Hauteur coupe transversale haut/fin (coupée): 150 mm; Hauteur coupe transversale bas/départ (coupée): 150 mm; Largeur coupe transversale haut/fin (coupée): 150 mm; Largeur coupe transversale bas/départ (coupée): 150 mm; Surface coupe transversale bas/départ (coupée): 0.0225 m2; Surface coupe transversale haut/fin: 0.0225 m2; Nombre de segments: 1; Superficie supérieure (nette): 0.0225 m2; Superficie inférieure (nette): 1.53 m2; Superficie surface supérieure (Brute): 0.0225 m2
Name | In | Nom d'étage d'implantation | Numéro d'étage d'implantation | Hachure de recouvrement | Altitude à Zéro du Projet (mm) = Altitude de Référence Niveau 1 (mm) = Altitude de Référence Niveau 2 (mm) = Altitude à niveau de la mer (mm) = Altitude inférieure à premier niveau de référence (mm) = Altitude inférieure à Zéro du projet (mm) = Altitude inférieure à niveau de la mer (mm) = Altitude inférieure à deuxième niveau de référence (mm) | Altitude supérieure à premier niveau de référence (mm) = Altitude supérieure à Zéro du projet (mm) = Altitude supérieure à niveau de la mer (mm) = Altitude supérieure à deuxième niveau de référence (mm)
Pilier-018 | rdc | rdc | 3 | Sans Trame | 3000 | 5550 | ArchiCADProperties - Zones conflictuelles: Terrasse; Nom de zone liée: Terrasse; Numéro de zone liée: B03
Pilier-018 | rdc | rdc | 3 | Sans Trame | 3000 | 5550 | ArchiCADProperties - Zones conflictuelles: Terrasse; Nom de zone liée: Terrasse; Numéro de zone liée: B04
Pilier-018 | rdc | rdc | 3 | Espace Minimal | 3000 | 5550 | ArchiCADProperties - Zones conflictuelles: Terrasse; Nom de zone liée: Terrasse; Numéro de zone liée: B03
3 x Pilier-018 | Etage1 | Etage1 | 4 | Sans Trame | 5750 | 8300
3 x Pilier-018 | Etage 2 | Etage 2 | 5 | Sans Trame | 8500 | 11050

# IfcDiscreteAccessory: Boite à eau 27 (20)
Classification: Accessoire distinct (Classification ARCHICAD)
AC_Pset_Boite_à_eau_27 - Afficher points chauds 2D en 3D: no; Page: 1; Type cuvette (gs_gutter_hl_type): Type 1; Type cuvette (gs_gutter_hl_type_m): 1; Garde cuvette: yes; Profil tuyau descente (gs_gutter_ds_profile): Arrondi; Profil tuyau descente (gs_gutter_ds_profile_num): 1; Résolution: 16; Niveau de détail 3D: 3; Ombre: yes; Affichage en plan (floorPlanDisplayType): Projeté avec partie supérieure; Affichage en plan (iFloorPlanDisplayType): 2; Type de ligne: 1; Type de ligne au-dessus tête: 4; Motif de hachure: Sans Trame; Stylo fond de hachure: Transparent; Cuvette: Métal-Zinc; Couvre gouttière: Métal-Acier; Coût: 0; Type de groupe (FM_Type): Autres; Type de groupe (iFMType): 25; Poids de l'objet: 0; Unité poids de l'objet: kg
ArchiCADProperties - Surface: GENERAL; ID de l'élément: Obj.-319; Lien et ID d'élément: Obj.-319; Calque: 1-Projet; Nom Élément de Bibliothèque: Boite à eau 27; Matériau de construction / Composite / Profil / Hachure: 100 %; Type Hachure: 100 %; Verrouillé: no; Type d'élément: Objet; ID de Parent: Obj.-319; Surfaces (Toutes): Métal-Acier; Métal-Zinc; Nom de Variante: Modèle principal; Nom de Jeu de Variantes: Modèle principal; Position: Non défini; Fonction structurelle: Non défini; Affichage sur filtre de rénovation: Tous les filtres appropriés; État de rénovation: Existant; État de Variante: Modèle principal; Jeu de Variantes: Modèle principal
AC_Equantity_Boite_à_eau_27 - 1ère dimension: 200 mm; 2ème dimension: 150 mm; Hauteur: 200 mm; Niveau inférieur: 1000 mm; Niveau supérieur: 0 mm; Largeur cuvette (HL_Width): 200 mm; Largeur cuvette (HL_Width2): 100 mm; Cadre cuvette: 50 mm; Profondeur cuvette: 150 mm; Hauteur cuvette: 200 mm; Largeur profil tuyau (gs_gutter_aa): 50 mm; Largeur profil tuyau (gs_gutter_aa2): 100 mm; Profondeur profil tuyau (gs_gutter_bb): 50 mm; Profondeur profil tuyau (gs_gutter_bb2): 100 mm; Rayon profil tuyau (gs_gutter_dd): 50 mm; Rayon profil tuyau (gs_gutter_dd2): 100 mm
AC_Pset_RenovationAndPhasing - Renovation Status: Existing
ArchiCADQuantities - Longueur (A): 200 mm; Superficie: 0.03 m2; Hauteur: 200 mm; Volume (net): 0 m3; Largeur: 150 mm; Altitude à étage lié/étage d'implantation: -350 mm; Décalage étage d'implantation: -350 mm; Superficie en plan: 0.115143 m2; Altitude supérieure à étage d'implantation: -150 mm; Altitude inférieure à étage d'implantation: -350 mm; Superficie supérieure (nette): 0.03 m2; Superficie inférieure (nette): 0.115143 m2
Name | In | Angle de rotation (deg) | Nom d'étage d'implantation | Numéro d'étage d'implantation | Altitude à Zéro du Projet (mm) = Altitude de Référence Niveau 1 (mm) = Altitude de Référence Niveau 2 (mm) = Altitude à niveau de la mer (mm) = Altitude inférieure à premier niveau de référence (mm) = Altitude inférieure à Zéro du projet (mm) = Altitude inférieure à niveau de la mer (mm) = Altitude inférieure à deuxième niveau de référence (mm) = Coordonnée topographique Z (mm) | Altitude supérieure à premier niveau de référence (mm) = Altitude supérieure à Zéro du projet (mm) = Altitude supérieure à niveau de la mer (mm) = Altitude supérieure à deuxième niveau de référence (mm) | Coordonnée topographique X (mm) | Coordonnée topographique Y (mm)
Obj.-319 | Etage1 | 354.973 | Etage1 | 4 | 5400 | 5600 | 2254198 | -610132
Obj.-319 | Etage 3 | 174.197 | Etage 3 | 6 | 11200 | 11400 | 2239980 | -606145
Obj.-319 | Etage 3 | 180 | Etage 3 | 6 | 11200 | 11400 | 2218064 | -643966 | ArchiCADProperties - Nom de zone liée: balcon; Numéro de zone liée: B33
Obj.-319 | Etage 3 | 360 | Etage 3 | 6 | 11200 | 11400 | 2218178 | -655091
Obj.-319 | Etage 3 | 270 | Etage 3 | 6 | 11200 | 11400 | 2218164 | -657557
Obj.-319 | Etage 3 | 90 | Etage 3 | 6 | 11200 | 11400 | 2232857 | -657557
Obj.-319 | Etage 3 | 264.196 | Etage 3 | 6 | 11200 | 11400 | 2230185 | -606620
Obj.-319 | Etage 3 | 180 | Etage 3 | 6 | 11200 | 11400 | 2218034 | -607117
Obj.-319 | Etage 3 | 174.197 | Etage 3 | 6 | 11200 | 11400 | 2218409 | -603953
Obj.-319 | Etage 3 | 84.1984 | Etage 3 | 6 | 11200 | 11400 | 2226422 | -606237
Obj.-319 | Etage 3 | 360 | Etage 3 | 6 | 11200 | 11400 | 2218034 | -617558
Obj.-319 | etage 4 | 0.0000200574 | etage 4 | 7 | 14250 | 14450 | 2233996 | -655091
Obj.-319 | etage 4 | 180 | etage 4 | 7 | 14250 | 14450 | 2229720 | -635903
Obj.-319 | Etage 5 | 360 | Etage 5 | 8 | 17300 | 17500 | 2298064 | -639067
Obj.-319 | Etage 5 | 180 | Etage 5 | 8 | 17300 | 17500 | 2298064 | -626021
Obj.-319 | Etage 5 | 360 | Etage 5 | 8 | 17300 | 17500 | 2298451 | -652473
Obj.-319 | Etage 5 | 360 | Etage 5 | 8 | 17300 | 17500 | 2218064 | -639067
Obj.-319 | Etage 5 | 360 | Etage 5 | 8 | 17300 | 17500 | 2218451 | -652473
Obj.-319 | Etage 5 | 180 | Etage 5 | 8 | 17300 | 17500 | 2229817 | -637163
Obj.-319 | Etage 5 | 180 | Etage 5 | 8 | 17300 | 17500 | 2218064 | -626021

# IfcDiscreteAccessory: Tuyau descente 27 (140)
Classification: Accessoire distinct (Classification ARCHICAD)
ArchiCADProperties - Surface: GENERAL; ID de l'élément: Obj.-318; Lien et ID d'élément: Obj.-318; Calque: 1-Projet; Nom Élément de Bibliothèque: Tuyau descente 27; Matériau de construction / Composite / Profil / Hachure: AS_EMPTY; Type Hachure: AS_EMPTY; Verrouillé: no; Type d'élément: Objet; ID de Parent: Obj.-318; Surfaces (Toutes): Métal-Zinc; Nom de Variante: Modèle principal; Nom de Jeu de Variantes: Modèle principal; Position: Non défini; Fonction structurelle: Non défini; Affichage sur filtre de rénovation: Tous les filtres appropriés; État de rénovation: Existant; État de Variante: Modèle principal; Jeu de Variantes: Modèle principal
AC_Pset_RenovationAndPhasing - Renovation Status: Existing
ArchiCADQuantities - Volume (net): 0 m3
AC_Equantity_Tuyau_descente_27 - Niveau inférieur: 0 mm; Largeur profilé (gs_gutter_aa): 50 mm; Largeur profilé (gs_gutter_aa2): 100 mm; Profondeur profil (gs_gutter_bb): 50 mm; Profondeur profil (gs_gutter_bb2): 100 mm; Distance entre Crochets: 800 mm; Décalage suspentes: 500 mm
AC_Pset_Tuyau_descente_27 - Afficher points chauds 2D en 3D: no; Page: 1; Angle tuyau descente: 0 deg; Angle de coupe sup.: 0 deg; Profil tuyau descente (gs_gutter_ds_profile): Arrondi; Profil tuyau descente (gs_gutter_ds_profile_num): 1; Suspente tuyau descente: no; Position suspente: 2; Niveau de détail 3D: 3; Résolution: 12; Ombre: yes; Type de ligne: 1; Motif de hachure: Sans Trame; Tuyau descente: Métal-Zinc; Support: Métal-Acier; Coût: 0; Type de groupe (FM_Type): Autres; Type de groupe (iFMType): 25; Poids de l'objet: 0; Unité poids de l'objet: kg
Name | In | Angle de rotation (deg) | Nom d'étage d'implantation | Numéro d'étage d'implantation | Longueur (A) (mm) = Largeur (mm) = 1ère dimension (mm) = 2ème dimension (mm) = Diamètre profil (mm) | Superficie (m2) = Superficie supérieure (nette) (m2) | ArchiCADQuantities, Hauteur (mm) = AC_Equantity_Tuyau_descente_27, Hauteur (mm) = Niveau supérieur (mm) = Longueur tuyau descente (mm) | Altitude à Zéro du Projet (mm) = Altitude de Référence Niveau 1 (mm) = Altitude de Référence Niveau 2 (mm) = Altitude à niveau de la mer (mm) = Altitude inférieure à premier niveau de référence (mm) = Altitude inférieure à Zéro du projet (mm) = Altitude inférieure à niveau de la mer (mm) = Altitude inférieure à deuxième niveau de référence (mm) = Coordonnée topographique Z (mm) | Altitude à étage lié/étage d'implantation (mm) = Décalage étage d'implantation (mm) = Altitude inférieure à étage d'implantation (mm) | Superficie en plan (m2) = Superficie inférieure (nette) (m2) | Altitude supérieure à premier niveau de référence (mm) = Altitude supérieure à Zéro du projet (mm) = Altitude supérieure à niveau de la mer (mm) = Altitude supérieure à deuxième niveau de référence (mm) | Altitude supérieure à étage d'implantation (mm) | Coordonnée topographique X (mm) | Coordonnée topographique Y (mm) | Rayon profil (mm) | Distance entre axes tuyau descente et mur (mm)
Obj.-318 | sousol | 174.197 | sousol | 2 | 100 | 0.01 | 300 | 2700 | 2700 | 0.0931749 | 3000 | 3000 | 2226236 | -608065 | 50 | 50
Obj.-318 | sousol | 174.197 | sousol | 2 | 100 | 0.01 | 300 | 2700 | 2700 | 0.0931749 | 3000 | 3000 | 2230185 | -606620 | 50 | 50
Obj.-318 | sousol | 174.197 | sousol | 2 | 100 | 0.01 | 300 | 2700 | 2700 | 0.0931749 | 3000 | 3000 | 2239980 | -606145 | 50 | 50
Obj.-318 | sousol | 180 | sousol | 2 | 100 | 0.01 | 300 | 2700 | 2700 | 0.0931749 | 3000 | 3000 | 2216947 | -620443 | 50 | 50
Obj.-318 | sousol | 180 | sousol | 2 | 100 | 0.01 | 300 | 2700 | 2700 | 0.0931749 | 3000 | 3000 | 2216947 | -604189 | 50 | 50 | ArchiCADProperties - Nom de zone liée: Pl; Numéro de zone liée: 818
Obj.-318 | sousol | 180 | sousol | 2 | 100 | 0.01 | 300 | 2700 | 2700 | 0.0931749 | 3000 | 3000 | 2216947 | -625966 | 50 | 50
Obj.-318 | sousol | 0 | sousol | 2 | 100 | 0.01 | 300 | 2700 | 2700 | 0.0931749 | 3000 | 3000 | 2224514 | -627465 | 50 | 50
Obj.-318 | sousol | 0 | sousol | 2 | 100 | 0.01 | 300 | 2700 | 2700 | 0.0931749 | 3000 | 3000 | 2225111 | -616801 | 50 | 50
Obj.-318 | sousol | 180 | sousol | 2 | 100 | 0.01 | 300 | 2700 | 2700 | 0.0931749 | 3000 | 3000 | 2233096 | -646652 | 50 | 50
Obj.-318 | sousol | 180 | sousol | 2 | 100 | 0.01 | 300 | 2700 | 2700 | 0.0931749 | 3000 | 3000 | 2216947 | -643902 | 50 | 50
Obj.-318 | sousol | 0 | sousol | 2 | 100 | 0.01 | 300 | 2700 | 2700 | 0.0931749 | 3000 | 3000 | 2222381 | -660856 | 50 | 50
Obj.-318 | sousol | 0 | sousol | 2 | 100 | 0.01 | 600 | 2400 | 2400 | 0.18635 | 3000 | 3000 | 2218064 | -643966 | 50 | 50
Obj.-318 | sousol | 0 | sousol | 2 | 100 | 0.01 | 300 | 2700 | 2700 | 0.0931749 | 3000 | 3000 | 2223660 | -625855 | 50 | 50
Obj.-318 | sousol | 180 | sousol | 2 | 100 | 0.01 | 300 | 2700 | 2700 | 0.0931749 | 3000 | 3000 | 2229212 | -637138 | 50 | 50
Obj.-318 | sousol | 180 | sousol | 2 | 100 | 0.01 | 300 | 2700 | 2700 | 0.0931749 | 3000 | 3000 | 2234431 | -636233 | 50 | 50
Obj.-318 | sousol | 0 | sousol | 2 | 100 | 0.01 | 600 | 2400 | 2400 | 0.18635 | 3000 | 3000 | 2218064 | -626021 | 50 | 50
Obj.-318 | sousol | 0 | sousol | 2 | 100 | 0.01 | 300 | 2700 | 2700 | 0.0931749 | 3000 | 3000 | 2234034 | -654991 | 50 | 195.421
Obj.-318 | sousol | 0 | sousol | 2 | 100 | 0.01 | 300 | 2700 | 2700 | 0.0931749 | 3000 | 3000 | 2234431 | -635903 | 50 | 50
Obj.-318 | sousol | 0 | sousol | 2 | 100 | 0.01 | 300 | 2700 | 2700 | 0.0931749 | 3000 | 3000 | 2218164 | -657557 | 50 | 50
Obj.-318 | sousol | 0 | sousol | 2 | 100 | 0.01 | 875.186 | 2124.81 | 2124.81 | 0.271818 | 3000 | 3000 | 2216584 | -655091 | 50 | 50
Obj.-318 | sousol | 0 | sousol | 2 | 100 | 0.01 | 300 | 2700 | 2700 | 0.0931749 | 3000 | 3000 | 2231864 | -657557 | 50 | 50
Obj.-318 | sousol | 0 | sousol | 2 | 100 | 0.01 | 300 | 2700 | 2700 | 0.0931749 | 3000 | 3000 | 2238913 | -614395 | 50 | 50
Obj.-318 | sousol | 180 | sousol | 2 | 100 | 0.01 | 300 | 2700 | 2700 | 0.0931749 | 3000 | 3000 | 2218034 | -607117 | 50 | 50 | ArchiCADProperties - Nom de zone liée: Pl; Numéro de zone liée: 818
Obj.-318 | sousol | 0 | sousol | 2 | 100 | 0.01 | 300 | 2700 | 2700 | 0.0931749 | 3000 | 3000 | 2218034 | -617558 | 50 | 50
Obj.-318 | sousol | 174.197 | sousol | 2 | 100 | 0.01 | 300 | 2700 | 2700 | 0.0931749 | 3000 | 3000 | 2218409 | -603953 | 50 | 50
Obj.-318 | sousol | 0 | sousol | 2 | 100 | 0.01 | 300 | 2700 | 2700 | 0.0931749 | 3000 | 3000 | 2218164 | -659945 | 50 | 50
Obj.-318 | sousol | 174.197 | sousol | 2 | 100 | 0.01 | 300 | 2700 | 2700 | 0.0931749 | 3000 | 3000 | 2226422 | -606237 | 50 | 50
Obj.-318 | sousol | 0 | sousol | 2 | 100 | 0.01 | 300 | 2700 | 2700 | 0.0931749 | 3000 | 3000 | 2224973 | -617760 | 50 | 576.478
Obj.-318 | sousol | 0 | sousol | 2 | 100 | 0.01 | 300 | 2700 | 2700 | 0.0931749 | 3000 | 3000 | 2231864 | -659945 | 50 | 50
Obj.-318 | sousol | 0 | sousol | 2 | 100 | 0.01 | 300 | 2700 | 2700 | 0.0931749 | 3000 | 3000 | 2227905 | -660814 | 50 | 50
Obj.-318 | sousol | 174.197 | sousol | 2 | 150 | 0.0225 | 300 | 2700 | 2700 | 0.139762 | 3000 | 3000 | 2225510 | -605001 | 75 | 75
Obj.-318 | sousol | 0 | sousol | 2 | 100 | 0.01 | 600 | 2400 | 2400 | 0.18635 | 3000 | 3000 | 2218064 | -639067 | 50 | 50
Obj.-318 | rdc | 174.197 | rdc | 3 | 100 | 0.01 | 20 | 3000 | 0 | 0.00621166 | 3020 | 20 | 2226235 | -608071 | 50 | 50
Obj.-318 | rdc | 174.197 | rdc | 3 | 100 | 0.01 | 20 | 3000 | 0 | 0.00621166 | 3020 | 20 | 2216947 | -604189 | 50 | 50 | ArchiCADProperties - Nom de zone liée: Terrasse; Numéro de zone liée: A01; Zones conflictuelles: Terrasse
Obj.-318 | rdc | 174.197 | rdc | 3 | 100 | 0.01 | 20 | 3000 | 0 | 0.00621166 | 3020 | 20 | 2216947 | -620443 | 50 | 50 | ArchiCADProperties - Nom de zone liée: Terrasse; Numéro de zone liée: A02; Zones conflictuelles: Terrasse
Obj.-318 | rdc | 174.197 | rdc | 3 | 100 | 0.01 | 3050 | 3000 | 0 | 0.947278 | 6050 | 3050 | 2230185 | -606620 | 50 | 50 | ArchiCADProperties - Zones conflictuelles: balcon
Obj.-318 | rdc | 5.8027 | rdc | 3 | 100 | 0.01 | 20 | 3000 | 0 | 0.00621166 | 3020 | 20 | 2216947 | -643902 | 50 | 50 | ArchiCADProperties - Nom de zone liée: Terrasse; Numéro de zone liée: B02; Zones conflictuelles: Terrasse
Obj.-318 | rdc | 174.197 | rdc | 3 | 100 | 0.01 | 2750 | 3000 | 0 | 0.854103 | 5750 | 2750 | 2239980 | -606145 | 50 | 50
Obj.-318 | rdc | 0 | rdc | 3 | 100 | 0.01 | 2700 | 3000 | 0 | 0.838574 | 5700 | 2700 | 2225111 | -616801 | 50 | 50
Obj.-318 | rdc | 5.8027 | rdc | 3 | 100 | 0.01 | 20 | 3000 | 0 | 0.00621166 | 3020 | 20 | 2216947 | -625966 | 50 | 50 | ArchiCADProperties - Nom de zone liée: Terrasse; Numéro de zone liée: B01; Zones conflictuelles: Terrasse
Obj.-318 | rdc | 180 | rdc | 3 | 100 | 0.01 | 2700 | 3000 | 0 | 0.838574 | 5700 | 2700 | 2229212 | -637138 | 50 | 50
Obj.-318 | rdc | 5.8027 | rdc | 3 | 100 | 0.01 | 20 | 3000 | 0 | 0.00621166 | 3020 | 20 | 2233096 | -646652 | 50 | 50 | ArchiCADProperties - Nom de zone liée: Terrasse; Numéro de zone liée: B05; Zones conflictuelles: Terrasse
Obj.-318 | rdc | 0 | rdc | 3 | 100 | 0.01 | 2750 | 3000 | 7.10543e-12 | 0.854103 | 5750 | 2750 | 2218064 | -639067 | 50 | 50 | ArchiCADProperties - Nom de zone liée: Terrasse; Numéro de zone liée: B02; Zones conflictuelles: Terrasse
Obj.-318 | rdc | 0 | rdc | 3 | 100 | 0.01 | 2700 | 3000 | 0 | 0.838574 | 5700 | 2700 | 2223236 | -644268 | 50 | 50
Obj.-318 | rdc | 0 | rdc | 3 | 100 | 0.01 | 2700 | 3000 | 0 | 0.838574 | 5700 | 2700 | 2223660 | -625855 | 50 | 50
Obj.-318 | rdc | 0 | rdc | 3 | 100 | 0.01 | 2750 | 3000 | 1.42109e-11 | 0.854103 | 5750 | 2750 | 2229720 | -635903 | 50 | 50
Obj.-318 | rdc | 0 | rdc | 3 | 100 | 0.01 | 2750 | 3000 | 0 | 0.854103 | 5750 | 2750 | 2218064 | -626021 | 50 | 50 | ArchiCADProperties - Nom de zone liée: Terrasse; Numéro de zone liée: B01; Zones conflictuelles: Terrasse
Obj.-318 | rdc | 0 | rdc | 3 | 100 | 0.01 | 2700 | 3000 | 0 | 0.838574 | 5700 | 2700 | 2224512 | -624387 | 50 | 50 | ArchiCADProperties - Nom de zone liée: Pl; Numéro de zone liée: 819; Zones conflictuelles: Pl
Obj.-318 | rdc | 0 | rdc | 3 | 100 | 0.01 | 2750 | 3000 | 1.77636e-12 | 0.854103 | 5750 | 2750 | 2218178 | -655091 | 50 | 50 | ArchiCADProperties - Nom de zone liée: Terrasse; Numéro de zone liée: B03; Zones conflictuelles: Terrasse
Obj.-318 | rdc | 0 | rdc | 3 | 100 | 0.01 | 2700 | 3000 | 0 | 0.838574 | 5700 | 2700 | 2232877 | -657557 | 50 | 50 | ArchiCADProperties - Nom de zone liée: Terrasse; Numéro de zone liée: B04; Zones conflictuelles: Terrasse
Obj.-318 | rdc | 0 | rdc | 3 | 100 | 0.01 | 2700 | 3000 | 0 | 0.838574 | 5700 | 2700 | 2218164 | -657557 | 50 | 50 | ArchiCADProperties - Nom de zone liée: Terrasse; Numéro de zone liée: B03; Zones conflictuelles: Terrasse
Obj.-318 | rdc | 0 | rdc | 3 | 100 | 0.01 | 2700 | 3000 | 0 | 0.838574 | 5700 | 2700 | 2231864 | -659945 | 50 | 50 | ArchiCADProperties - Nom de zone liée: Terrasse; Numéro de zone liée: B04; Zones conflictuelles: Terrasse
Obj.-318 | rdc | 0 | rdc | 3 | 100 | 0.01 | 2700 | 3000 | 0 | 0.838574 | 5700 | 2700 | 2218164 | -659945 | 50 | 50 | ArchiCADProperties - Nom de zone liée: Terrasse; Numéro de zone liée: B03; Zones conflictuelles: Terrasse
Obj.-318 | rdc | 0 | rdc | 3 | 100 | 0.01 | 2750 | 3000 | 0 | 0.854103 | 5750 | 2750 | 2218064 | -643966 | 50 | 50 | ArchiCADProperties - Nom de zone liée: Terrasse; Numéro de zone liée: B02; Zones conflictuelles: Terrasse
Obj.-318 | rdc | 0 | rdc | 3 | 100 | 0.01 | 2700 | 3000 | 0 | 0.838574 | 5700 | 2700 | 2224980 | -618217 | 50 | 50 | ArchiCADProperties - Nom de zone liée: Dressing; Numéro de zone liée: A03; Zones conflictuelles: Dressing
Obj.-318 | rdc | 0 | rdc | 3 | 100 | 0.01 | 2700 | 3000 | 0 | 0.838574 | 5700 | 2700 | 2238913 | -614395 | 50 | 50
Obj.-318 | rdc | 0 | rdc | 3 | 100 | 0.01 | 3050 | 3000 | 0 | 0.947278 | 6050 | 3050 | 2218034 | -617558 | 50 | 50 | ArchiCADProperties - Nom de zone liée: Terrasse; Numéro de zone liée: A02; Zones conflictuelles: balcon; Terrasse
Obj.-318 | rdc | 180 | rdc | 3 | 100 | 0.01 | 3050 | 3000 | 0 | 0.947278 | 6050 | 3050 | 2218034 | -607117 | 50 | 50 | ArchiCADProperties - Nom de zone liée: Terrasse; Numéro de zone liée: A01; Zones conflictuelles: balcon; Terrasse
Obj.-318 | rdc | 174.197 | rdc | 3 | 100 | 0.01 | 2800 | 3000 | 0 | 0.869632 | 5800 | 2800 | 2226422 | -606237 | 50 | 50 | ArchiCADProperties - Zones conflictuelles: balcon
Obj.-318 | rdc | 174.197 | rdc | 3 | 100 | 0.01 | 2750 | 3000 | 0 | 0.854103 | 5750 | 2750 | 2218409 | -603953 | 50 | 50
Obj.-318 | rdc | 0 | rdc | 3 | 100 | 0.01 | 2700 | 330.741 | -2669.26 | 0.838574 | 3030.74 | 30.7406 | 2227905 | -660764 | 50 | 50 | ArchiCADProperties - Nom de zone liée: Terrasse; Numéro de zone liée: B04; Zones conflictuelles: Terrasse
Obj.-318 | rdc | 0 | rdc | 3 | 100 | 0.01 | 2700 | 330.741 | -2669.26 | 0.838574 | 3030.74 | 30.7406 | 2222381 | -660751 | 50 | 50 | ArchiCADProperties - Nom de zone liée: Terrasse; Numéro de zone liée: B03; Zones conflictuelles: Terrasse
Obj.-318 | rdc | 0 | rdc | 3 | 100 | 0.01 | 2490 | 3000 | 0 | 0.773351 | 5490 | 2490 | 2229876 | -631890 | 50 | 50
Obj.-318 | rdc | 0 | rdc | 3 | 100 | 0.01 | 2750 | 3000 | 0 | 0.854103 | 5750 | 2750 | 2234123 | -631890 | 50 | 50
Obj.-318 | Etage1 | 174.197 | Etage1 | 4 | 100 | 0.01 | 3050 | 5750 | 0 | 0.947278 | 8800 | 3050 | 2230185 | -606620 | 50 | 50 | ArchiCADProperties - Nom de zone liée: balcon; Numéro de zone liée: A15; Zones conflictuelles: balcon; balcon
Obj.-318 | Etage1 | 174.197 | Etage1 | 4 | 100 | 0.01 | 2750 | 5750 | 0 | 0.854103 | 8500 | 2750 | 2239980 | -606145 | 50 | 50
Obj.-318 | Etage1 | 0 | Etage1 | 4 | 100 | 0.01 | 2700 | 5750 | 0 | 0.838574 | 8450 | 2700 | 2225111 | -616801 | 50 | 50
Obj.-318 | Etage1 | 0 | Etage1 | 4 | 100 | 0.01 | 2750 | 5750 | 7.10543e-12 | 0.854103 | 8500 | 2750 | 2218064 | -639067 | 50 | 50 | ArchiCADProperties - Nom de zone liée: balcon; Numéro de zone liée: B13; Zones conflictuelles: balcon
Obj.-318 | Etage1 | 0 | Etage1 | 4 | 100 | 0.01 | 2700 | 5750 | 0 | 0.838574 | 8450 | 2700 | 2223236 | -644268 | 50 | 50
Obj.-318 | Etage1 | 0 | Etage1 | 4 | 100 | 0.01 | 2700 | 5750 | 0 | 0.838574 | 8450 | 2700 | 2224512 | -624387 | 50 | 50
Obj.-318 | Etage1 | 180 | Etage1 | 4 | 100 | 0.01 | 2700 | 5750 | 0 | 0.838574 | 8450 | 2700 | 2229212 | -637138 | 50 | 50
Obj.-318 | Etage1 | 0 | Etage1 | 4 | 100 | 0.01 | 2700 | 5750 | 0 | 0.838574 | 8450 | 2700 | 2223660 | -625855 | 50 | 50
Obj.-318 | Etage1 | 0 | Etage1 | 4 | 100 | 0.01 | 2750 | 5750 | 0 | 0.854103 | 8500 | 2750 | 2218064 | -626021 | 50 | 50 | ArchiCADProperties - Nom de zone liée: balcon; Numéro de zone liée: B12; Zones conflictuelles: balcon
Obj.-318 | Etage1 | 0 | Etage1 | 4 | 100 | 0.01 | 2750 | 5750 | 1.42109e-11 | 0.854103 | 8500 | 2750 | 2229720 | -635903 | 50 | 50
Obj.-318 | Etage1 | 0 | Etage1 | 4 | 100 | 0.01 | 2750 | 5750 | 1.77636e-12 | 0.854103 | 8500 | 2750 | 2218178 | -655091 | 50 | 50 | ArchiCADProperties - Nom de zone liée: balcon; Numéro de zone liée: B14; Zones conflictuelles: balcon
Obj.-318 | Etage1 | 0 | Etage1 | 4 | 100 | 0.01 | 2700 | 5750 | 0 | 0.838574 | 8450 | 2700 | 2218164 | -657557 | 50 | 50 | ArchiCADProperties - Nom de zone liée: balcon; Numéro de zone liée: B14; Zones conflictuelles: balcon
Obj.-318 | Etage1 | 0 | Etage1 | 4 | 100 | 0.01 | 2750 | 5750 | 0 | 0.854103 | 8500 | 2750 | 2218064 | -643966 | 50 | 50 | ArchiCADProperties - Nom de zone liée: balcon; Numéro de zone liée: B13; Zones conflictuelles: balcon
Obj.-318 | Etage1 | 0 | Etage1 | 4 | 100 | 0.01 | 2700 | 5750 | 0 | 0.838574 | 8450 | 2700 | 2224980 | -618142 | 50 | 124.733
Obj.-318 | Etage1 | 0 | Etage1 | 4 | 100 | 0.01 | 2700 | 5750 | 0 | 0.838574 | 8450 | 2700 | 2238913 | -614395 | 50 | 50
Obj.-318 | Etage1 | 180 | Etage1 | 4 | 100 | 0.01 | 3050 | 5750 | 0 | 0.947278 | 8800 | 3050 | 2218034 | -607117 | 50 | 50 | ArchiCADProperties - Nom de zone liée: balcon; Numéro de zone liée: A11; Zones conflictuelles: balcon; balcon
Obj.-318 | Etage1 | 0 | Etage1 | 4 | 100 | 0.01 | 3050 | 5750 | 0 | 0.947278 | 8800 | 3050 | 2218034 | -617558 | 50 | 50 | ArchiCADProperties - Nom de zone liée: balcon; Numéro de zone liée: A12; Zones conflictuelles: balcon; balcon
Obj.-318 | Etage1 | 174.197 | Etage1 | 4 | 100 | 0.01 | 2800 | 5750 | 0 | 0.869632 | 8550 | 2800 | 2226422 | -606237 | 50 | 50 | ArchiCADProperties - Nom de zone liée: balcon; Numéro de zone liée: A15; Zones conflictuelles: balcon; balcon
Obj.-318 | Etage1 | 174.197 | Etage1 | 4 | 100 | 0.01 | 2750 | 5750 | 0 | 0.854103 | 8500 | 2750 | 2218409 | -603953 | 50 | 50
Obj.-318 | Etage1 | 0 | Etage1 | 4 | 100 | 0.01 | 2700 | 5750 | 0 | 0.838574 | 8450 | 2700 | 2232887 | -657557 | 50 | 50 | ArchiCADProperties - Nom de zone liée: balcon; Numéro de zone liée: B15
Obj.-318 | Etage 2 | 174.197 | Etage 2 | 5 | 100 | 0.01 | 3050 | 8500 | 0 | 0.947278 | 11550 | 3050 | 2230185 | -606620 | 50 | 50 | ArchiCADProperties - Nom de zone liée: balcon; Numéro de zone liée: A25; Zones conflictuelles: balcon
Obj.-318 | Etage 2 | 174.197 | Etage 2 | 5 | 100 | 0.01 | 2700 | 8500 | 0 | 0.838574 | 11200 | 2700 | 2239980 | -606145 | 50 | 50
Obj.-318 | Etage 2 | 0 | Etage 2 | 5 | 100 | 0.01 | 2700 | 8500 | 0 | 0.838574 | 11200 | 2700 | 2225111 | -616801 | 50 | 50
Obj.-318 | Etage 2 | 0 | Etage 2 | 5 | 100 | 0.01 | 3050 | 8500 | 7.10543e-12 | 0.947278 | 11550 | 3050 | 2218064 | -639067 | 50 | 50 | ArchiCADProperties - Nom de zone liée: balcon; Numéro de zone liée: B23; Zones conflictuelles: balcon
Obj.-318 | Etage 2 | 0 | Etage 2 | 5 | 100 | 0.01 | 2700 | 8500 | 0 | 0.838574 | 11200 | 2700 | 2223236 | -644268 | 50 | 50
Obj.-318 | Etage 2 | 0 | Etage 2 | 5 | 100 | 0.01 | 2700 | 8500 | 0 | 0.838574 | 11200 | 2700 | 2224512 | -624387 | 50 | 50
Obj.-318 | Etage 2 | 0 | Etage 2 | 5 | 100 | 0.01 | 2700 | 8500 | 0 | 0.838574 | 11200 | 2700 | 2223660 | -625855 | 50 | 50
Obj.-318 | Etage 2 | 0 | Etage 2 | 5 | 100 | 0.01 | 3050 | 8500 | 1.42109e-11 | 0.947278 | 11550 | 3050 | 2229720 | -635903 | 50 | 50
Obj.-318 | Etage 2 | 0 | Etage 2 | 5 | 100 | 0.01 | 3050 | 8500 | 0 | 0.947278 | 11550 | 3050 | 2233995 | -655091 | 50 | 50 | ArchiCADProperties - Nom de zone liée: balcon; Numéro de zone liée: B25; Zones conflictuelles: balcon
Obj.-318 | Etage 2 | 0 | Etage 2 | 5 | 100 | 0.01 | 3050 | 8500 | 0 | 0.947278 | 11550 | 3050 | 2218064 | -626021 | 50 | 50 | ArchiCADProperties - Nom de zone liée: balcon; Numéro de zone liée: B22; Zones conflictuelles: balcon
Obj.-318 | Etage 2 | 0 | Etage 2 | 5 | 100 | 0.01 | 2700 | 8500 | 0 | 0.838574 | 11200 | 2700 | 2232877 | -657557 | 50 | 50 | ArchiCADProperties - Nom de zone liée: balcon; Numéro de zone liée: B25; Zones conflictuelles: balcon
Obj.-318 | Etage 2 | 0 | Etage 2 | 5 | 100 | 0.01 | 2700 | 8500 | 0 | 0.838574 | 11200 | 2700 | 2218164 | -657557 | 50 | 50 | ArchiCADProperties - Nom de zone liée: balcon; Numéro de zone liée: B24; Zones conflictuelles: balcon
Obj.-318 | Etage 2 | 0 | Etage 2 | 5 | 100 | 0.01 | 2700 | 8500 | 0 | 0.838574 | 11200 | 2700 | 2218064 | -643966 | 50 | 50 | ArchiCADProperties - Nom de zone liée: balcon; Numéro de zone liée: B23; Zones conflictuelles: balcon
Obj.-318 | Etage 2 | 0 | Etage 2 | 5 | 100 | 0.01 | 2700 | 8500 | 1.77636e-12 | 0.838574 | 11200 | 2700 | 2218178 | -655091 | 50 | 50 | ArchiCADProperties - Nom de zone liée: balcon; Numéro de zone liée: B24; Zones conflictuelles: balcon
Obj.-318 | Etage 2 | 180 | Etage 2 | 5 | 100 | 0.01 | 2700 | 8500 | 0 | 0.838574 | 11200 | 2700 | 2229212 | -637138 | 50 | 50
Obj.-318 | Etage 2 | 0 | Etage 2 | 5 | 100 | 0.01 | 2700 | 8500 | 0 | 0.838574 | 11200 | 2700 | 2238913 | -614395 | 50 | 50
Obj.-318 | Etage 2 | 0 | Etage 2 | 5 | 100 | 0.01 | 2700 | 8500 | 0 | 0.838574 | 11200 | 2700 | 2224980 | -617170 | 50 | 1096.63
Obj.-318 | Etage 2 | 0 | Etage 2 | 5 | 100 | 0.01 | 2900 | 8500 | 0 | 0.90069 | 11400 | 2900 | 2218034 | -617558 | 50 | 50 | ArchiCADProperties - Nom de zone liée: balcon; Numéro de zone liée: A22; Zones conflictuelles: balcon
Obj.-318 | Etage 2 | 174.197 | Etage 2 | 5 | 100 | 0.01 | 2700 | 8500 | 0 | 0.838574 | 11200 | 2700 | 2226422 | -606237 | 50 | 50 | ArchiCADProperties - Nom de zone liée: balcon; Numéro de zone liée: A25; Zones conflictuelles: balcon
Obj.-318 | Etage 2 | 174.197 | Etage 2 | 5 | 100 | 0.01 | 2700 | 8500 | 0 | 0.838574 | 11200 | 2700 | 2218409 | -603953 | 50 | 50
Obj.-318 | Etage 2 | 180 | Etage 2 | 5 | 100 | 0.01 | 2900 | 8500 | 0 | 0.90069 | 11400 | 2900 | 2218034 | -607117 | 50 | 50 | ArchiCADProperties - Nom de zone liée: balcon; Numéro de zone liée: A21; Zones conflictuelles: balcon
Obj.-318 | Etage 3 | 0 | Etage 3 | 6 | 100 | 0.01 | 2700 | 11550 | 0 | 0.838574 | 14250 | 2700 | 2225111 | -616801 | 50 | 50
Obj.-318 | Etage 3 | 0 | Etage 3 | 6 | 100 | 0.01 | 3050 | 11550 | 7.10543e-12 | 0.947278 | 14600 | 3050 | 2218064 | -639067 | 50 | 50 | ArchiCADProperties - Nom de zone liée: balcon; Numéro de zone liée: B33; Zones conflictuelles: balcon
Obj.-318 | Etage 3 | 0 | Etage 3 | 6 | 100 | 0.01 | 2700 | 11550 | 0 | 0.838574 | 14250 | 2700 | 2223236 | -644268 | 50 | 50
Obj.-318 | Etage 3 | 180 | Etage 3 | 6 | 100 | 0.01 | 2700 | 11550 | 0 | 0.838574 | 14250 | 2700 | 2229212 | -637138 | 50 | 50
Obj.-318 | Etage 3 | 0 | Etage 3 | 6 | 100 | 0.01 | 2700 | 11550 | 0 | 0.838574 | 14250 | 2700 | 2224512 | -624387 | 50 | 50
Obj.-318 | Etage 3 | 0 | Etage 3 | 6 | 100 | 0.01 | 2700 | 11550 | 0 | 0.838574 | 14250 | 2700 | 2233995 | -655091 | 50 | 50
Obj.-318 | Etage 3 | 0 | Etage 3 | 6 | 100 | 0.01 | 2700 | 11550 | 1.42109e-11 | 0.838574 | 14250 | 2700 | 2229720 | -635903 | 50 | 50
Obj.-318 | Etage 3 | 0 | Etage 3 | 6 | 100 | 0.01 | 3050 | 11550 | 0 | 0.947278 | 14600 | 3050 | 2218064 | -626021 | 50 | 50 | ArchiCADProperties - Nom de zone liée: balcon; Numéro de zone liée: B32; Zones conflictuelles: balcon
Obj.-318 | Etage 3 | 0 | Etage 3 | 6 | 100 | 0.01 | 2700 | 11550 | 0 | 0.838574 | 14250 | 2700 | 2238913 | -614395 | 50 | 50
Obj.-318 | Etage 3 | 0 | Etage 3 | 6 | 100 | 0.01 | 2700 | 11550 | 0 | 0.838574 | 14250 | 2700 | 2223660 | -625855 | 50 | 50
Obj.-318 | Etage 3 | 0 | Etage 3 | 6 | 100 | 0.01 | 2700 | 11550 | 0 | 0.838574 | 14250 | 2700 | 2224980 | -617241 | 50 | 1026.23
Obj.-318 | etage 4 | 0 | etage 4 | 7 | 100 | 0.01 | 2700 | 14600 | 7.10543e-12 | 0.838574 | 17300 | 2700 | 2298064 | -639067 | 50 | 50
Obj.-318 | etage 4 | 0 | etage 4 | 7 | 100 | 0.01 | 2700 | 14600 | 0 | 0.838574 | 17300 | 2700 | 2225111 | -616801 | 50 | 50
Obj.-318 | etage 4 | 0 | etage 4 | 7 | 100 | 0.01 | 2700 | 14600 | 7.10543e-12 | 0.838574 | 17300 | 2700 | 2218064 | -639067 | 50 | 50 | ArchiCADProperties - Nom de zone liée: Balcon; Numéro de zone liée: B43; Zones conflictuelles: Balcon
Obj.-318 | etage 4 | 0 | etage 4 | 7 | 100 | 0.01 | 2700 | 14600 | 0 | 0.838574 | 17300 | 2700 | 2223660 | -625855 | 50 | 50
Obj.-318 | etage 4 | 180 | etage 4 | 7 | 100 | 0.01 | 2700 | 14600 | 0 | 0.838574 | 17300 | 2700 | 2229212 | -637138 | 50 | 50
Obj.-318 | etage 4 | 0 | etage 4 | 7 | 100 | 0.01 | 2700 | 14600 | 0 | 0.838574 | 17300 | 2700 | 2223309 | -644268 | 50 | 50
Obj.-318 | etage 4 | 0 | etage 4 | 7 | 100 | 0.01 | 2700 | 14600 | 0 | 0.838574 | 17300 | 2700 | 2229817 | -637163 | 50 | 50 | ArchiCADProperties - Nom de zone liée: Terrasse; Numéro de zone liée: B44; Zones conflictuelles: Terrasse
Obj.-318 | etage 4 | 0 | etage 4 | 7 | 100 | 0.01 | 2700 | 14600 | 0 | 0.838574 | 17300 | 2700 | 2224512 | -624387 | 50 | 50
Obj.-318 | etage 4 | 0 | etage 4 | 7 | 100 | 0.01 | 2700 | 14600 | 0 | 0.838574 | 17300 | 2700 | 2218451 | -652473 | 50 | 50 | ArchiCADProperties - Nom de zone liée: Terrasse; Numéro de zone liée: B44; Zones conflictuelles: Terrasse
Obj.-318 | etage 4 | 0 | etage 4 | 7 | 100 | 0.01 | 2700 | 14600 | 0 | 0.838574 | 17300 | 2700 | 2218064 | -626021 | 50 | 50 | ArchiCADProperties - Nom de zone liée: balcon; Numéro de zone liée: B42; Zones conflictuelles: balcon
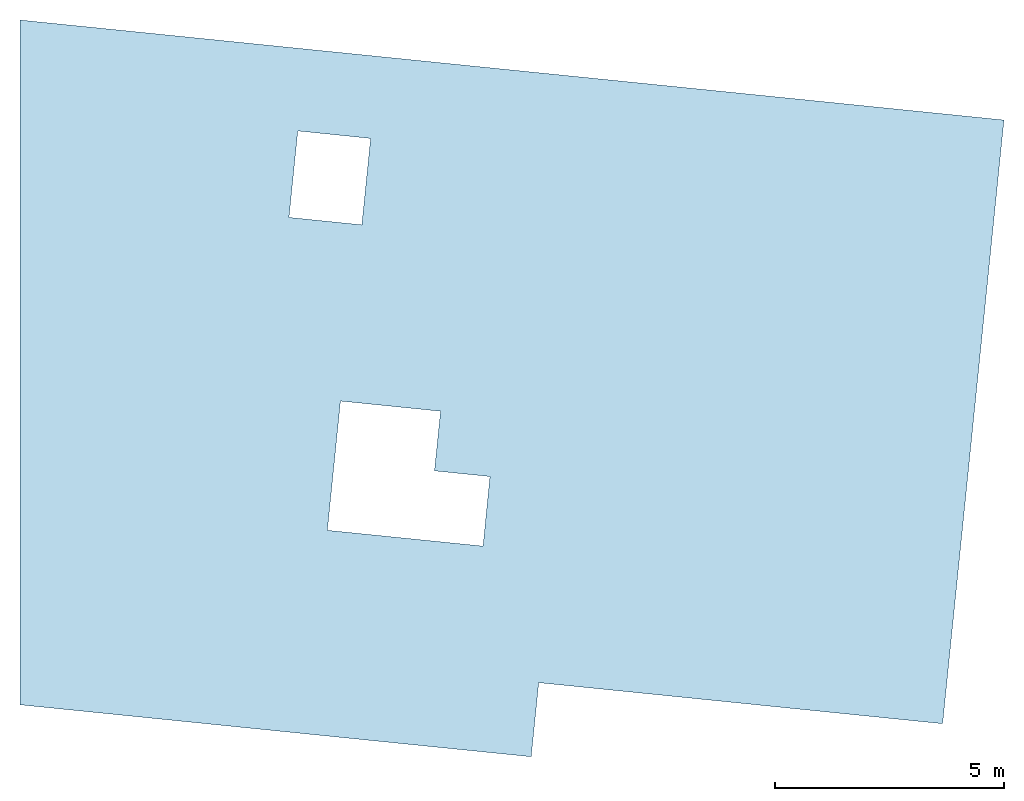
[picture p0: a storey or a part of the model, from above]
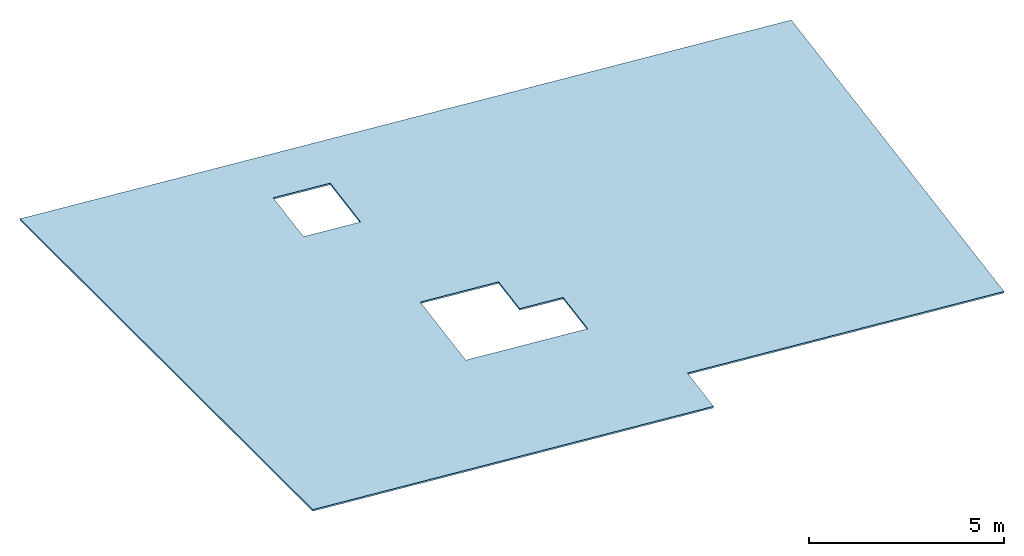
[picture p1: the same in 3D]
Properties of the parts of a building model (IFC2X3), part 11 of 44

# IfcDiscreteAccessory: Tuyau descente 27 (140)
Name | In | Angle de rotation (deg) | Nom d'étage d'implantation | Numéro d'étage d'implantation | Longueur (A) (mm) = Largeur (mm) = 1ère dimension (mm) = 2ème dimension (mm) = Diamètre profil (mm) | Superficie (m2) = Superficie supérieure (nette) (m2) | ArchiCADQuantities, Hauteur (mm) = AC_Equantity_Tuyau_descente_27, Hauteur (mm) = Niveau supérieur (mm) = Longueur tuyau descente (mm) | Altitude à Zéro du Projet (mm) = Altitude de Référence Niveau 1 (mm) = Altitude de Référence Niveau 2 (mm) = Altitude à niveau de la mer (mm) = Altitude inférieure à premier niveau de référence (mm) = Altitude inférieure à Zéro du projet (mm) = Altitude inférieure à niveau de la mer (mm) = Altitude inférieure à deuxième niveau de référence (mm) = Coordonnée topographique Z (mm) | Altitude à étage lié/étage d'implantation (mm) = Décalage étage d'implantation (mm) = Altitude inférieure à étage d'implantation (mm) | Superficie en plan (m2) = Superficie inférieure (nette) (m2) | Altitude supérieure à premier niveau de référence (mm) = Altitude supérieure à Zéro du projet (mm) = Altitude supérieure à niveau de la mer (mm) = Altitude supérieure à deuxième niveau de référence (mm) | Altitude supérieure à étage d'implantation (mm) | Coordonnée topographique X (mm) | Coordonnée topographique Y (mm) | Rayon profil (mm) | Distance entre axes tuyau descente et mur (mm)
Obj.-318 | etage 4 | 0 | etage 4 | 7 | 100 | 0.01 | 400 | 14600 | 0 | 0.124233 | 15000 | 400 | 2238913 | -614395 | 50 | 50
Obj.-318 | etage 4 | 0 | etage 4 | 7 | 100 | 0.01 | 10 | 14600 | 0 | 0.00310583 | 14610 | 10 | 2225009 | -617707 | 50 | 936.746
Obj.-318 | etage 4 | 0 | etage 4 | 7 | 100 | 0.01 | 2700 | 14600 | 0 | 0.838574 | 17300 | 2700 | 2298451 | -652473 | 50 | 50 | ArchiCADProperties - Nom de zone liée: Terrasse; Numéro de zone liée: B53; Zones conflictuelles: Terrasse
Obj.-318 | etage 4 | 0 | etage 4 | 7 | 100 | 0.01 | 2700 | 14600 | 0 | 0.838574 | 17300 | 2700 | 2298064 | -626021 | 50 | 50
2 x Obj.-318 | Etage 5 | 0 | Etage 5 | 8 | 100 | 0.01 | 2700 | 17650 | 0 | 0.838574 | 20350 | 2700 | 2224064 | -644268 | 50 | 50
Obj.-318 | Etage 5 | 0 | Etage 5 | 8 | 100 | 0.01 | 100 | 17650 | 0 | 0.0310583 | 17750 | 100 | 2225111 | -616801 | 50 | 50
Obj.-318 | Etage 5 | 0 | Etage 5 | 8 | 100 | 0.01 | 2700 | 17650 | 0 | 0.838574 | 20350 | 2700 | 2223660 | -625855 | 50 | 50
Obj.-318 | Etage 5 | 180 | Etage 5 | 8 | 100 | 0.01 | 2700 | 17650 | 0 | 0.838574 | 20350 | 2700 | 2229212 | -637138 | 50 | 50
Obj.-318 | Etage 5 | 0 | Etage 5 | 8 | 100 | 0.01 | 400 | 17650 | 0 | 0.124233 | 18050 | 400 | 2224512 | -624387 | 50 | 50 | ArchiCADProperties - Nom de zone liée: Terrasse; Numéro de zone liée: B51; Zones conflictuelles: Terrasse
Obj.-318 | toiture | 0 | toiture | 9 | 100 | 0.01 | 764.183 | 20100 | -250 | 0.237342 | 20864.2 | 514.183 | 2224064 | -644268 | 50 | 50 | ArchiCADProperties - Nom de zone liée: Terrasse/eng.; Numéro de zone liée: B52; Zones conflictuelles: Terrasse/eng.
Obj.-318 | toiture | 0 | toiture | 9 | 100 | 0.01 | 400 | 20350 | 0 | 0.124233 | 20750 | 400 | 2223660 | -625855 | 50 | 50
Obj.-318 | toiture | 0 | toiture | 9 | 100 | 0.01 | 1000 | 20350 | 0 | 0.310583 | 21350 | 1000 | 2229212 | -637138 | 50 | 50
Obj.-318 | toiture | 180 | toiture | 9 | 100 | 0.01 | 100 | 20350 | 0 | 0.0310583 | 20450 | 100 | 2229212 | -637138 | 50 | 50

# IfcDistributionElement: Chaudière à gaz 27 (48)
Classification: Elément de distribution (Classification ARCHICAD)
ArchiCADProperties - Surface: C10; ID de l'élément: Obj.-003; Lien et ID d'élément: Obj.-003; Calque: 1-Projet; Nom Élément de Bibliothèque: Chaudière à gaz 27; Matériau de construction / Composite / Profil / Hachure: Brique 1; Type Hachure: Brique 1; Verrouillé: no; Type d'élément: Objet; ID de Parent: Obj.-003; Surfaces (Toutes): Métal-Inox; Métal-Chrome; Surface-Lavis Blanc; Métal-Acier; Nom de Variante: Modèle principal; Nom de Jeu de Variantes: Modèle principal; Position: Non défini; Fonction structurelle: Non défini; Affichage sur filtre de rénovation: Tous les filtres appropriés; État de rénovation: Existant; État de Variante: Modèle principal; Jeu de Variantes: Modèle principal
AC_Pset_RenovationAndPhasing - Renovation Status: Existing
AC_Pset_Chaudière_à_gaz_27 - Afficher points chauds 2D en 3D: yes; Définir programme: no; Niveau de détail 3D: 3; Afficher tuyau: yes; Connexion entrée tuyau: yes; Type outil (ConToolType_1): 2; Système MEP (ConSystem_1): MANQUANT; Type de forme (ConType_1): Cercle; Type connexion (ConConnectorType_1): A brides; Connexion sortie tuyau: yes; Type outil (ConToolType_2): 2; Système MEP (ConSystem_2): Non défini; Type de forme (ConType_2): Cercle; Connexion gaz: yes; Type outil (ConToolType_3): 2; Système MEP (ConSystem_3): Non défini; Type de forme (ConType_3): Cercle; Connexion fumée: yes; Type outil (ConToolType_4): 1; Système MEP (ConSystem_4): Non défini; Type de forme (ConType_4): Cercle; Résolution: 18; Ombre: yes; Niveau de détail 2D: 3; Motif de hachure: Sans Trame; Type ligne interrompue: 4; Boîte: Métal-Chrome; Comptoir: Surface-Lavis Blanc; Bouton: Métal-Acier; Connexion: Métal-Inox; Utiliser surface de système: no; Surface de système: C14; Nombre connexions: 4; Sortie: 0; Courant d'utilisation: 0; Démarrage courant: 0; Durée de la surcharge: 0; Coût: 0; Volts: 0; Type de groupe (FM_Type): Équipement CVCA; Type de groupe (iFMType): 12; Superficie: 0; Volume: 0; Code ERP: 0; Numéro de commande: 0; Poids de l'objet: 0; Unité poids de l'objet: kg; Unité puissance calor. max.: O; Puissance calorifique maximum (FM_HeatOutput): 0; Puissance calorifique maximum (FM_HeatOutput_btu): 0; Unité puissance refroid. max.: O; Puissance refroidissement max. (FM_RefrigeratingOutput): 0; Puissance refroidissement max. (FM_RefrigeratingOutput_btu): 0; Puissance en Watts: 0; Collecteur de graisse: no; Connexion électrique: no; Phase No.: 0; Tension: 0; Performance électrique: 0
ArchiCADQuantities - Superficie: 0.147 m2; Hauteur: 1000 mm; Superficie supérieure (nette): 0.147 m2
AC_Equantity_Chaudière_à_gaz_27 - Hauteur: 1000 mm; Niveau inférieur: 1000 mm; Niveau supérieur: 0 mm; Profondeur nominale (ConNominalDepth_1): 40 mm; Diamètre extérieur (ConWidth_1): 42 mm; Profondeur extérieure (ConDepth_1): 42 mm; Épaisseur mur (ConWallThickness_1): 1 mm; Longueur connexion (ConLength_1): 20 mm; Diamètre connecteur (ConConnectorWidth_1): 42 mm; Profondeur connecteur (ConConnectorDepth_1): 0 mm; Largeur connecteur (ConConnectorWidth2_1): 5 mm; Position connexion en X (ConPosX_1): 200 mm; Position connexion en Z (ConPosZ_1): 111.909 mm; Profondeur nominale (ConNominalDepth_2): 40 mm; Diamètre extérieur (ConWidth_2): 42 mm; Profondeur extérieure (ConDepth_2): 42 mm; Épaisseur mur (ConWallThickness_2): 1 mm; Longueur connexion (ConLength_2): 20 mm; Diamètre connecteur (ConConnectorWidth_2): 42 mm; Profondeur connecteur (ConConnectorDepth_2): 0 mm; Largeur connecteur (ConConnectorWidth2_2): 5 mm; Position connexion en Z (ConPosZ_2): 111.909 mm; Profondeur nominale (ConNominalDepth_3): 40 mm; Diamètre extérieur (ConWidth_3): 42 mm; Profondeur extérieure (ConDepth_3): 42 mm; Épaisseur mur (ConWallThickness_3): 1 mm; Longueur connexion (ConLength_3): 20 mm; Diamètre connecteur (ConConnectorWidth_3): 42 mm; Profondeur connecteur (ConConnectorDepth_3): 0 mm; Largeur connecteur (ConConnectorWidth2_3): 5 mm; Position connexion en Z (ConPosZ_3): 111.909 mm; Profondeur nominale (ConNominalDepth_4): 0 mm; Diamètre interne: 150 mm; Hauteur intérieure: 150 mm; Épaisseur mur (ConWallThickness_4): 2 mm; Longueur connexion (ConLength_4): 100 mm; Hauteur connecteur: 20 mm; Profondeur connecteur (ConConnectorDepth_4): 0 mm; Largeur connecteur (ConConnectorWidth2_4): 0 mm; Position connexion en Z (ConPosZ_4): 1295 mm
Name | In | Angle de rotation (deg) | Zones conflictuelles = Nom de zone liée | Numéro de zone liée | Nom d'étage d'implantation | Numéro d'étage d'implantation | Longueur (A) (mm) = AC_Equantity_Chaudière_à_gaz_27, Largeur (mm) | Volume (net) (m3) | ArchiCADQuantities, Largeur (mm) = Profondeur (mm) = Position connexion en Y (ConPosY_1) (mm) = Position connexion en Y (ConPosY_2) (mm) = Position connexion en Y (ConPosY_3) (mm) = Position connexion en Y (ConPosY_4) (mm) | Altitude à Zéro du Projet (mm) = Altitude de Référence Niveau 1 (mm) = Altitude de Référence Niveau 2 (mm) = Altitude à niveau de la mer (mm) = Altitude inférieure à premier niveau de référence (mm) = Altitude inférieure à Zéro du projet (mm) = Altitude inférieure à niveau de la mer (mm) = Altitude inférieure à deuxième niveau de référence (mm) = Coordonnée topographique Z (mm) | Altitude à étage lié/étage d'implantation (mm) = Décalage étage d'implantation (mm) = Altitude inférieure à étage d'implantation (mm) | Superficie en plan (m2) = Superficie inférieure (nette) (m2) | Altitude supérieure à premier niveau de référence (mm) = Altitude supérieure à Zéro du projet (mm) = Altitude supérieure à niveau de la mer (mm) = Altitude supérieure à deuxième niveau de référence (mm) | Altitude supérieure à étage d'implantation (mm) | Coordonnée topographique X (mm) | Coordonnée topographique Y (mm) | Position connexion en X (ConPosX_2) (mm) | Position connexion en X (ConPosX_3) (mm) | Position connexion en X (ConPosX_4) (mm)
Obj.-003 | rdc | 270 | Cellier | B02 | rdc | 3 | 350 | 0.146733 | 420 | 3851.96 | 851.964 | 2.51951 | 5225.96 | 2225.96 | 2223316 | -636145 | 329 | 329 | 175
Obj.-003 | rdc | 264.197 | Sejour cuisine/pl | A01 | rdc | 3 | 420 | 0.146764 | 350 | 3900 | 900 | 2.53255 | 5274 | 2274 | 2224905 | -607900 | 375 | 399 | 210
Obj.-003 | rdc | 90.0359 | Sejour cuisine | B05 | rdc | 3 | 350 | 0.146733 | 420 | 4000 | 1000 | 2.51951 | 5374 | 2374 | 2227534 | -637514 | 329 | 329 | 175
Obj.-003 | rdc | 270 | Cellier | B01 | rdc | 3 | 350 | 0.146733 | 420 | 3000 | 0 | 2.51951 | 4374 | 1374 | 2223036 | -626411 | 329 | 329 | 175
Obj.-003 | rdc | 269.99 | Sejour cuisine/pl | B04 | rdc | 3 | 350 | 0.146733 | 420 | 3000 | 0 | 2.51951 | 4374 | 1374 | 2233591 | -652763 | 329 | 329 | 175
Obj.-003 | rdc | 354.228 | Sejour cuisine | A03 | rdc | 3 | 420 | 0.146764 | 350 | 3000 | 0 | 2.53255 | 4374 | 1374 | 2229345 | -615219 | 375 | 399 | 210
Obj.-003 | rdc | 264.197 | Sejour Cuisine/pl | A04 | rdc | 3 | 420 | 0.146764 | 350 | 3000 | 0 | 2.53255 | 4374 | 1374 | 2238605 | -614938 | 375 | 399 | 210
Obj.-003 | rdc | 90 | Sejour cuisine | B03 | rdc | 3 | 350 | 0.146733 | 420 | 3000 | 0 | 2.51951 | 4374 | 1374 | 2217427 | -652830 | 329 | 329 | 175
Obj.-003 | rdc | 269.99 | Sejour cuisine/pl | B04 | rdc | 3 | 350 | 0.146733 | 420 | 3000 | 0 | 2.51951 | 4374 | 1374 | 2233572 | -652831 | 329 | 329 | 175
Obj.-003 | rdc | 264.197 | Sdb/pl | A02 | rdc | 3 | 350 | 0.146733 | 420 | 3900 | 900 | 2.51951 | 5274 | 2274 | 2222320 | -611749 | 329 | 329 | 175
Obj.-003 | Etage1 | 264.197 | Sejour Cuisine/pl | A14 | Etage1 | 4 | 420 | 0.146764 | 350 | 6515.22 | 765.224 | 2.53255 | 7889.22 | 2139.22 | 2238605 | -614938 | 375 | 399 | 210
Obj.-003 | Etage1 | 270 | Cellier | B13 | Etage1 | 4 | 350 | 0.146733 | 420 | 6601.96 | 851.964 | 2.51951 | 7975.96 | 2225.96 | 2223316 | -636145 | 329 | 329 | 175
Obj.-003 | Etage1 | 269.99 | Sejour cuisine | B15 | Etage1 | 4 | 350 | 0.146733 | 420 | 5750 | 0 | 2.51951 | 7124 | 1374 | 2233572 | -652831 | 329 | 329 | 175
Obj.-003 | Etage1 | 270 | Cellier | B12 | Etage1 | 4 | 350 | 0.146733 | 420 | 5750 | 0 | 2.51951 | 7124 | 1374 | 2223036 | -626411 | 329 | 329 | 175
Obj.-003 | Etage1 | 174.192 | Sejour cuisine/pl | A15 | Etage1 | 4 | 350 | 0.146733 | 420 | 6550 | 800 | 2.51951 | 7924 | 2174 | 2226373 | -611247 | 329 | 329 | 175
Obj.-003 | Etage1 | 264.197 | Sejour cuisine/pl | A11 | Etage1 | 4 | 420 | 0.146764 | 350 | 6650 | 900 | 2.53255 | 8024 | 2274 | 2224905 | -607900 | 375 | 399 | 210
Obj.-003 | Etage1 | 270.045 | Sejour cuisine | B11 | Etage1 | 4 | 350 | 0.146733 | 420 | 5750 | 0 | 2.51951 | 7124 | 1374 | 2228816 | -631984 | 329 | 329 | 175
Obj.-003 | Etage1 | 90 | Sejour cuisine | B14 | Etage1 | 4 | 350 | 0.146733 | 420 | 5750 | 0 | 2.51951 | 7124 | 1374 | 2217427 | -652830 | 329 | 329 | 175
Obj.-003 | Etage1 | 264.197 | Sde | A12 | Etage1 | 4 | 350 | 0.146733 | 420 | 6650 | 900 | 2.51951 | 8024 | 2274 | 2222320 | -611749 | 329 | 329 | 175
Obj.-003 | Etage1 | 90.0359 | Sejour cuisine | B16 | Etage1 | 4 | 350 | 0.146733 | 420 | 6750 | 1000 | 2.51951 | 8124 | 2374 | 2227534 | -637514 | 329 | 329 | 175
Obj.-003 | Etage1 | 354.228 | Sejour cuisine | A13 | Etage1 | 4 | 420 | 0.146764 | 350 | 5750 | 0 | 2.53255 | 7124 | 1374 | 2229345 | -615219 | 375 | 399 | 210
Obj.-003 | Etage 2 | 174.192 | Sejour cuisine/pl | A25 | Etage 2 | 5 | 350 | 0.146733 | 420 | 9300 | 800 | 2.51951 | 10674 | 2174 | 2226373 | -611247 | 329 | 329 | 175
Obj.-003 | Etage 2 | 264.197 | Sejour cuisine/pl | A21 | Etage 2 | 5 | 420 | 0.146764 | 350 | 9400 | 900 | 2.53255 | 10774 | 2274 | 2224905 | -607900 | 375 | 399 | 210
Obj.-003 | Etage 2 | 270 | Cellier | B22 | Etage 2 | 5 | 350 | 0.146733 | 420 | 8500 | 0 | 2.51951 | 9874 | 1374 | 2223036 | -626411 | 329 | 329 | 175
Obj.-003 | Etage 2 | 270.045 | Sejour cuisine | B21 | Etage 2 | 5 | 350 | 0.146733 | 420 | 8500 | 0 | 2.51951 | 9874 | 1374 | 2228816 | -631984 | 329 | 329 | 175
Obj.-003 | Etage 2 | 264.197 | Sejour cuisine/pl | A24 | Etage 2 | 5 | 420 | 0.146764 | 350 | 9265.22 | 765.224 | 2.53255 | 10639.2 | 2139.22 | 2238605 | -614938 | 375 | 399 | 210
Obj.-003 | Etage 2 | 270 | Cellier | B23 | Etage 2 | 5 | 350 | 0.146733 | 420 | 9351.96 | 851.964 | 2.51951 | 10726 | 2225.96 | 2223316 | -636145 | 329 | 329 | 175
Obj.-003 | Etage 2 | 90.0359 | Sejour cuisine | B26 | Etage 2 | 5 | 350 | 0.146733 | 420 | 9500 | 1000 | 2.51951 | 10874 | 2374 | 2227534 | -637514 | 329 | 329 | 175
Obj.-003 | Etage 2 | 269.99 | Sejour cuisine | B25 | Etage 2 | 5 | 350 | 0.146733 | 420 | 8500 | 0 | 2.51951 | 9874 | 1374 | 2233572 | -652831 | 329 | 329 | 175
Obj.-003 | Etage 2 | 354.228 | Sejour cuisine | A23 | Etage 2 | 5 | 420 | 0.146764 | 350 | 8500 | 0 | 2.53255 | 9874 | 1374 | 2229347 | -615199 | 375 | 399 | 210
Obj.-003 | Etage 2 | 264.197 | Pl 2 | A22 | Etage 2 | 5 | 350 | 0.146733 | 420 | 9400 | 900 | 2.51951 | 10774 | 2274 | 2222320 | -611749 | 329 | 329 | 175
Obj.-003 | Etage 2 | 90 | Sejour cuisine | B24 | Etage 2 | 5 | 350 | 0.146733 | 420 | 8500 | 0 | 2.51951 | 9874 | 1374 | 2217427 | -652830 | 329 | 329 | 175
Obj.-003 | Etage 3 | 270 | Cellier | B32 | Etage 3 | 6 | 350 | 0.146733 | 420 | 11550 | 0 | 2.51951 | 12924 | 1374 | 2223036 | -626411 | 329 | 329 | 175
Obj.-003 | Etage 3 | 264.213 | Sejour cuisine/pl | A33 | Etage 3 | 6 | 420 | 0.146764 | 350 | 11550 | 0 | 2.53255 | 12924 | 1374 | 2238554 | -615443 | 375 | 399 | 210
Obj.-003 | Etage 3 | 174.184 | Sde/pl | A34 | Etage 3 | 6 | 350 | 0.146733 | 420 | 11550 | 0 | 2.51951 | 12924 | 1374 | 2226395 | -611049 | 329 | 329 | 175
Obj.-003 | Etage 3 | 270 | Cellier | B33 | Etage 3 | 6 | 350 | 0.146733 | 420 | 12402 | 851.964 | 2.51951 | 13776 | 2225.96 | 2223316 | -636145 | 329 | 329 | 175
Obj.-003 | Etage 3 | 270.045 | Sejour cuisine/pl | B31 | Etage 3 | 6 | 350 | 0.146733 | 420 | 11550 | 0 | 2.51951 | 12924 | 1374 | 2228816 | -631984 | 329 | 329 | 175
Obj.-003 | Etage 3 | 270 | cellier | B34 | Etage 3 | 6 | 350 | 0.146733 | 420 | 11550 | 0 | 2.51951 | 12924 | 1374 | 2229373 | -647069 | 329 | 329 | 175
Obj.-003 | Etage 3 | 90.0359 | Sejour cuisine/pl | B35 | Etage 3 | 6 | 350 | 0.146733 | 420 | 12550 | 1000 | 2.51951 | 13924 | 2374 | 2227534 | -637514 | 329 | 329 | 175
Obj.-003 | Etage 3 | 354.228 | Sejour cuisine | A32 | Etage 3 | 6 | 420 | 0.146764 | 350 | 11550 | 0 | 2.53255 | 12924 | 1374 | 2229346 | -615216 | 375 | 399 | 210
Obj.-003 | Etage 3 | 354.197 | Sejour cuisine/pl | A31 | Etage 3 | 6 | 350 | 0.146733 | 420 | 11550 | 0 | 2.51951 | 12924 | 1374 | 2223415 | -612485 | 329 | 329 | 175
Obj.-003 | etage 4 | 270.045 | Sejour cuisine/pl | B41 | etage 4 | 7 | 350 | 0.146733 | 420 | 14600 | 0 | 2.51951 | 15974 | 1374 | 2228816 | -631984 | 329 | 329 | 175
Obj.-003 | etage 4 | 270 | Sde 1 | B44 | etage 4 | 7 | 350 | 0.146733 | 420 | 15217.5 | 617.532 | 2.51951 | 16591.5 | 1991.53 | 2230997 | -646388 | 329 | 329 | 175
Obj.-003 | etage 4 | 270 | Cellier | B42 | etage 4 | 7 | 350 | 0.146733 | 420 | 14600 | 0 | 2.51951 | 15974 | 1374 | 2223036 | -626411 | 329 | 329 | 175
Obj.-003 | etage 4 | 270 | Cellier | B43 | etage 4 | 7 | 420 | 0.146764 | 350 | 15452 | 851.964 | 2.53255 | 16826 | 2225.96 | 2223382 | -636145 | 375 | 399 | 210
Obj.-003 | Etage 5 | 180 | cellier | B51 | Etage 5 | 8 | 420 | 0.146764 | 350 | 17650 | 0 | 2.53255 | 19024 | 1374 | 2222182 | -631754 | 375 | 399 | 210
Obj.-003 | Etage 5 | 0.23561 | Sde 1 | B52 | Etage 5 | 8 | 350 | 0.146733 | 420 | 18502 | 851.964 | 2.51951 | 19876 | 2225.96 | 2222525 | -636607 | 329 | 329 | 175
Obj.-003 | Etage 5 | 360 | cellier | B54 | Etage 5 | 8 | 350 | 0.146733 | 420 | 17650 | 0 | 2.51951 | 19024 | 1374 | 2301517 | -641423 | 329 | 329 | 175

# IfcDistributionElement: Douche rectangulaire (53)
Classification: Elément de distribution (Classification ARCHICAD)
ArchiCADProperties - Surface: Revêt. pilier rond; ID de l'élément: Obj.-002; Lien et ID d'élément: Obj.-002; Calque: SANITAIRE; Nom Élément de Bibliothèque: Douche rectangulaire; Matériau de construction / Composite / Profil / Hachure: Brique 1; Type Hachure: Brique 1; Verrouillé: no; Type d'élément: Objet; ID de Parent: Obj.-002; Surfaces (Toutes): Métal-Inox; Surface-Ceramiques vitrifiées; Nom de Variante: Modèle principal; Nom de Jeu de Variantes: Modèle principal; Position: Non défini; Fonction structurelle: Non défini; Affichage sur filtre de rénovation: Tous les filtres appropriés; État de rénovation: Existant; État de Variante: Modèle principal; Jeu de Variantes: Modèle principal
AC_Pset_Douche_rectangulaire - 3D: Détaillé; Résolution: 24; Ombre: yes; Afficher points chauds 2D en 3D: yes; Encombrement minimal: no; Motif de hachure: Sans Trame; Matière bac: Surface-Ceramiques vitrifiées; Matière siphon: Métal-Inox; Coût: 0; Type de groupe (FM_Type): Equipement CVCA; Type de groupe (iFMType): 12; Code ERP: 0; Numéro de commande: 0; Poids de l'objet: 0; Unité poids de l'objet: kg; Version: 4; Nombre connexions: 0; Unité d'eau chaude requise: 0; Unité d'eau froide requise: 0; Unité de vidange: 0; Nombre de points chauds: 0
ArchiCADQuantities - Longueur (A): 900 mm; Hauteur: 100 mm; Altitude à étage lié/étage d'implantation: 0 mm; Décalage étage d'implantation: 0 mm; Altitude supérieure à étage d'implantation: 100 mm; Altitude inférieure à étage d'implantation: 0 mm
AC_Equantity_Douche_rectangulaire - Dimension X: 900 mm; Hauteur: 100 mm; Niveau inférieur: 1000 mm; Niveau supérieur: 0 mm
AC_Pset_RenovationAndPhasing - Renovation Status: Existing
Name | In | Angle de rotation (deg) | Zones conflictuelles = Nom de zone liée | Numéro de zone liée | Nom d'étage d'implantation | Numéro d'étage d'implantation | Superficie (m2) = Superficie supérieure (nette) (m2) | Volume (net) (m3) | Largeur (mm) = Dimension Y (mm) | Altitude à Zéro du Projet (mm) = Altitude de Référence Niveau 1 (mm) = Altitude de Référence Niveau 2 (mm) = Altitude à niveau de la mer (mm) = Altitude inférieure à premier niveau de référence (mm) = Altitude inférieure à Zéro du projet (mm) = Altitude inférieure à niveau de la mer (mm) = Altitude inférieure à deuxième niveau de référence (mm) = Coordonnée topographique Z (mm) | Superficie en plan (m2) = Superficie inférieure (nette) (m2) | Altitude supérieure à premier niveau de référence (mm) = Altitude supérieure à Zéro du projet (mm) = Altitude supérieure à niveau de la mer (mm) = Altitude supérieure à deuxième niveau de référence (mm) | Coordonnée topographique X (mm) | Coordonnée topographique Y (mm)
Obj.-002 | rdc | 84.1897 | Sdb | A04 | rdc | 3 | 1.08 | 0.00670769 | 1200 | 3000 | 3.62333 | 3100 | 2238969 | -613853
Obj.-002 | rdc | 179.968 | Sdb | B02 | rdc | 3 | 1.08 | 0.00670769 | 1200 | 3000 | 3.62333 | 3100 | 2224133 | -633044
Obj.-002 | rdc | 84.1991 | Sdb | A01 | rdc | 3 | 1.08 | 0.00670769 | 1200 | 3000 | 3.62333 | 3100 | 2222466 | -611216
Obj.-002 | rdc | 90 | Sde | B04 | rdc | 3 | 1.08 | 0.00670769 | 1200 | 3000 | 3.62333 | 3100 | 2227657 | -646918
Obj.-002 | rdc | 174.193 | Sdb/pl | A02 | rdc | 3 | 1.08 | 0.00670769 | 1200 | 3000 | 3.62333 | 3100 | 2223805 | -612102
Obj.-002 | rdc | 84.2333 | Sdb | A03 | rdc | 3 | 1.08 | 0.00670769 | 1200 | 3000 | 3.62333 | 3100 | 2226482 | -618286
Obj.-002 | rdc | 180 | Sdb | B03 | rdc | 3 | 1.08 | 0.00670769 | 1200 | 3000 | 3.62333 | 3100 | 2224138 | -644938
Obj.-002 | rdc | 360 | Sdb | B01 | rdc | 3 | 1.08 | 0.00670769 | 1200 | 3000 | 3.62333 | 3100 | 2224132 | -631798
Obj.-002 | rdc | 180 | Sdb | B05 | rdc | 3 | 1.08 | 0.00670769 | 1200 | 3000 | 3.62333 | 3100 | 2225891 | -645429
Obj.-002 | Etage1 | 179.968 | Sde | B13 | Etage1 | 4 | 1.08 | 0.00670769 | 1200 | 5750 | 3.62333 | 5850 | 2224133 | -633044
Obj.-002 | Etage1 | 180 | Sde | B16 | Etage1 | 4 | 1.08 | 0.00670769 | 1200 | 5750 | 3.62333 | 5850 | 2225891 | -645429
Obj.-002 | Etage1 | 174.193 | Sde | A12 | Etage1 | 4 | 1.08 | 0.00670769 | 1200 | 5750 | 3.62333 | 5850 | 2223805 | -612102
Obj.-002 | Etage1 | 360 | Sde | B12 | Etage1 | 4 | 1.08 | 0.00670769 | 1200 | 5750 | 3.62333 | 5850 | 2224132 | -631798
Obj.-002 | Etage1 | 360 | Sde | B14 | Etage1 | 4 | 1.08 | 0.00670769 | 1200 | 5750 | 3.62333 | 5850 | 2224132 | -646141
Obj.-002 | Etage1 | 264.199 | Sde | A11 | Etage1 | 4 | 1.08 | 0.00670769 | 1200 | 5750 | 3.62333 | 5850 | 2221302 | -611097
Obj.-002 | Etage1 | 84.1885 | Sde | A15 | Etage1 | 4 | 1.08 | 0.00670769 | 1200 | 5750 | 3.62333 | 5850 | 2233435 | -613091
Obj.-002 | Etage1 | 90 | Sde | B15 | Etage1 | 4 | 1.08 | 0.00670769 | 1200 | 5750 | 3.62333 | 5850 | 2227657 | -646918
Obj.-002 | Etage1 | 270.004 | Sde | B11 | Etage1 | 4 | 1.08 | 0.00670769 | 1200 | 5750 | 3.62333 | 5850 | 2225078 | -628147
Obj.-002 | Etage1 | 84.2333 | Sde | A13 | Etage1 | 4 | 1.08 | 0.00670769 | 1200 | 5750 | 3.62333 | 5850 | 2226482 | -618286
Obj.-002 | Etage1 | 84.1897 | Sdb | A14 | Etage1 | 4 | 1.08 | 0.00670769 | 1200 | 5750 | 3.62333 | 5850 | 2238969 | -613853
Obj.-002 | Etage 2 | 84.2333 | Sde | A23 | Etage 2 | 5 | 1.08 | 0.00670769 | 1200 | 8500 | 3.62333 | 8600 | 2226482 | -618286
Obj.-002 | Etage 2 | 174.182 | Sde | A22 | Etage 2 | 5 | 1.08 | 0.00670769 | 1200 | 8500 | 3.62333 | 8600 | 2223805 | -612102
Obj.-002 | Etage 2 | 270.004 | Sde | B21 | Etage 2 | 5 | 1.08 | 0.00670769 | 1200 | 8500 | 3.62333 | 8600 | 2225078 | -628147
Obj.-002 | Etage 2 | 179.968 | Sde | B23 | Etage 2 | 5 | 1.08 | 0.00670769 | 1200 | 8500 | 3.62333 | 8600 | 2224133 | -633044
Obj.-002 | Etage 2 | 360 | Sde | B22 | Etage 2 | 5 | 1.08 | 0.00670769 | 1200 | 8500 | 3.62333 | 8600 | 2224132 | -631798
Obj.-002 | Etage 2 | 84.1885 | Sde | A25 | Etage 2 | 5 | 1.08 | 0.00670769 | 1200 | 8500 | 3.62333 | 8600 | 2233435 | -613091
Obj.-002 | Etage 2 | 180 | Sde | B26 | Etage 2 | 5 | 1.08 | 0.00670769 | 1200 | 8500 | 3.62333 | 8600 | 2225891 | -645429
Obj.-002 | Etage 2 | 360 | Sde | B24 | Etage 2 | 5 | 1.08 | 0.00670769 | 1200 | 8500 | 3.62333 | 8600 | 2224132 | -646141
Obj.-002 | Etage 2 | 84.1897 | Sde | A24 | Etage 2 | 5 | 1.08 | 0.00670769 | 1200 | 8500 | 3.62333 | 8600 | 2238969 | -613853
Obj.-002 | Etage 2 | 264.199 | Sde | A21 | Etage 2 | 5 | 1.08 | 0.00670769 | 1200 | 8500 | 3.62333 | 8600 | 2221302 | -611097
Obj.-002 | Etage 2 | 90 | Sde | B25 | Etage 2 | 5 | 1.08 | 0.00670769 | 1200 | 8500 | 3.62333 | 8600 | 2227692 | -646918
Obj.-002 | Etage 3 | 84.2333 | Sde | A32 | Etage 3 | 6 | 1.08 | 0.00670769 | 1200 | 11550 | 3.62333 | 11650 | 2226480 | -618286
Obj.-002 | Etage 3 | 264.195 | Sde/pl | A34 | Etage 3 | 6 | 1.08 | 0.00670769 | 1200 | 11550 | 3.62333 | 11650 | 2226450 | -612381
Obj.-002 | Etage 3 | 360 | Sde | B32 | Etage 3 | 6 | 1.08 | 0.00670769 | 1200 | 11550 | 3.62333 | 11650 | 2224132 | -631798
Obj.-002 | Etage 3 | 360 | Sdb | B34 | Etage 3 | 6 | 1.08 | 0.00670769 | 1200 | 11550 | 3.62333 | 11650 | 2224132 | -646141
Obj.-002 | Etage 3 | 270.004 | Sde | B31 | Etage 3 | 6 | 1.08 | 0.00670769 | 1200 | 11550 | 3.62333 | 11650 | 2225078 | -628147
Obj.-002 | Etage 3 | 179.968 | Sde | B33 | Etage 3 | 6 | 1.08 | 0.00670769 | 1200 | 11550 | 3.62333 | 11650 | 2224133 | -633044
Obj.-002 | Etage 3 | 84.2127 | Sde | A33 | Etage 3 | 6 | 1.08 | 0.00670769 | 1200 | 11550 | 3.62333 | 11650 | 2238257 | -614920
Obj.-002 | Etage 3 | 90.0001 | Sde | B34 | Etage 3 | 6 | 1.08 | 0.00670769 | 1200 | 11550 | 3.62333 | 11650 | 2224062 | -652323
Obj.-002 | Etage 3 | 84.2051 | Sde2 | A31 | Etage 3 | 6 | 0.81 | 0.00503077 | 900 | 11550 | 2.82504 | 11650 | 2224316 | -621189
Obj.-002 | Etage 3 | 180 | Sde | B35 | Etage 3 | 6 | 1.08 | 0.00670769 | 1200 | 11550 | 3.62333 | 11650 | 2225891 | -645429
Obj.-002 | Etage 3 | 84.1973 | Sde1 | A31 | Etage 3 | 6 | 1.08 | 0.00670769 | 1200 | 11550 | 3.62333 | 11650 | 2224502 | -619359
Obj.-002 | etage 4 | 179.968 | Sde | B43 | etage 4 | 7 | 1.08 | 0.00670769 | 1200 | 14600 | 3.62333 | 14700 | 2224133 | -633044
Obj.-002 | etage 4 | 270.004 | Sde | B41 | etage 4 | 7 | 1.08 | 0.00670769 | 1200 | 14600 | 3.62333 | 14700 | 2225108 | -628148
Obj.-002 | etage 4 | 360 | Sde 2 | B44 | etage 4 | 7 | 1.08 | 0.00670769 | 1200 | 14600 | 3.62333 | 14700 | 2224131 | -645896
Obj.-002 | etage 4 | 360 | Sde | B42 | etage 4 | 7 | 1.08 | 0.00670769 | 1200 | 14600 | 3.62333 | 14700 | 2224132 | -631798
Obj.-002 | etage 4 | 270 | Sde 1 | B44 | etage 4 | 7 | 1.08 | 0.00670769 | 1200 | 14600 | 3.62333 | 14700 | 2227384 | -646738
Obj.-002 | etage 4 | 0.0000567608 | Ch 3/sde | B44 | etage 4 | 7 | 1.08 | 0.00670769 | 1200 | 14600 | 3.62333 | 14700 | 2225892 | -639456
Obj.-002 | Etage 5 | 360 | Sde 1 | B52 | Etage 5 | 8 | 1.08 | 0.00670769 | 1200 | 17650 | 3.62333 | 17750 | 2223732 | -638762
Obj.-002 | Etage 5 | 270 | Sdb | B51 | Etage 5 | 8 | 1.08 | 0.00670769 | 1200 | 17650 | 3.62333 | 17750 | 2224372 | -624847
Obj.-002 | Etage 5 | 270 | Sde 2 | B52 | Etage 5 | 8 | 1.08 | 0.00670769 | 1200 | 17650 | 3.62333 | 17750 | 2228113 | -646738
Obj.-002 | Etage 5 | 89.9998 | Sde 1 | B54 | Etage 5 | 8 | 1.08 | 0.00670769 | 1200 | 17650 | 3.62333 | 17750 | 2302792 | -636187
Obj.-002 | Etage 5 | 90 | sde | B51 | Etage 5 | 8 | 1.08 | 0.00670769 | 1200 | 17650 | 3.62333 | 17750 | 2223944 | -635107

# IfcDistributionElement: Evier à double bacs 27 (48)
Classification: Elément de distribution (Classification ARCHICAD)
ArchiCADProperties - Surface: Revêt. pilier rond; ID de l'élément: Obj.-019; Lien et ID d'élément: Obj.-019; Calque: SANITAIRE; Nom Élément de Bibliothèque: Evier à double bacs 27; Matériau de construction / Composite / Profil / Hachure: Brique 1; Type Hachure: Brique 1; Verrouillé: no; Type d'élément: Objet; ID de Parent: Obj.-019; Surfaces (Toutes): Métal-Inox; Métal-Chrome; Nom de Variante: Modèle principal; Nom de Jeu de Variantes: Modèle principal; Position: Non défini; Fonction structurelle: Non défini; Affichage sur filtre de rénovation: Tous les filtres appropriés; État de rénovation: Existant; État de Variante: Modèle principal; Jeu de Variantes: Modèle principal
AC_Pset_Evier_à_double_bacs_27 - Afficher points chauds 2D en 3D: no; Définir programme: no; Evier en-dessous: no; Niveau de détail 3D: 3; Styles évier (gs_sink_type): Style 10; Styles robinet (gs_tap_type): Style 3; Connexion d'eau chaude: no; Type outil (ConToolType_1): 2; Système MEP (ConSystem_1): Non défini; Type de forme (ConType_1): Cercle; Type connexion (ConConnectorType_1): Soudé; Connexion d'eau froide: no; Type outil (ConToolType_2): 2; Système MEP (ConSystem_2): Non défini; Type de forme (ConType_2): Cercle; Type connexion (ConConnectorType_2): Soudé; Connexion eau résiduaire #1: yes; Type outil (ConToolType_3): 2; Système MEP (ConSystem_3): Non défini; Type de forme (ConType_3): Cercle; Type connexion (ConConnectorType_3): Soudé; Connexion eau résiduaire #2: no; Type outil (ConToolType_4): 2; Système MEP (ConSystem_4): Non défini; Type de forme (ConType_4): Cercle; Type connexion (ConConnectorType_4): Soudé; Connexion eau résiduaire #3: no; Type outil (ConToolType_5): 2; Système MEP (ConSystem_5): Non défini; Type de forme (ConType_5): Cercle; Type connexion (ConConnectorType_5): Soudé; Niveau de détail 2D: 1; Type symbole évier (SinkSymbol): Simple; Type symbole robinet (TapSymbol): Détaillé; Motif de hachure: Sans Trame; Stylo fond de hachure: Transparent; Résolution: 16; Ombre: yes; Evier: Métal-Chrome; Robinet: Métal-Inox; Connexion: Métal-Inox; Utiliser surface de système: no; Surface de système: C14; Styles évier (gs_sink_type_m): 10; Styles robinet (gs_tap_type_m): 3; Type symbole évier (SinkSymbol_m): 1; Type symbole robinet (TapSymbol_m): 2; Nombre connexions: 3; Coût: 0; Type de groupe (FM_Type): Sanitaires; Type de groupe (iFMType): 13; Superficie: 0; Volume: 0; Poids de l'objet: 0; Unité poids de l'objet: kg
AC_Pset_RenovationAndPhasing - Renovation Status: Existing
ArchiCADQuantities - Longueur (A): 1200 mm; Superficie: 0.72 m2; Hauteur: 200 mm; Volume (net): 0.00295221 m3; Largeur: 600 mm; Altitude à étage lié/étage d'implantation: 0 mm; Décalage étage d'implantation: 0 mm; Superficie en plan: 1.80427 m2; Altitude supérieure à étage d'implantation: 1037.9 mm; Altitude inférieure à étage d'implantation: 680 mm; Superficie supérieure (nette): 0.72 m2; Superficie inférieure (nette): 1.80427 m2
AC_Equantity_Evier_à_double_bacs_27 - 1ère dimension: 1200 mm; 2ème dimension: 600 mm; Hauteur évier: 200 mm; Hauteur comptoir: 900 mm; Niveau inférieur: 700 mm; Niveau supérieur: 900 mm; Épaisseur Plan/Plateau (0-Sans): 50 mm; Profondeur nominale (ConNominalDepth_1): 25 mm; Diamètre extérieur (ConWidth_1): 27 mm; Profondeur extérieure (ConDepth_1): 27 mm; Épaisseur mur (ConWallThickness_1): 1 mm; Longueur connexion (ConLength_1): 20 mm; Diamètre connecteur (ConConnectorWidth_1): 40 mm; Profondeur connecteur (ConConnectorDepth_1): 0 mm; Largeur connecteur (ConConnectorWidth2_1): 5 mm; Position connexion en X (ConPosX_1): 444.75 mm; Position connexion en Y (ConPosY_1): 490 mm; Position connexion en Z (ConPosZ_1): 0 mm; Profondeur nominale (ConNominalDepth_2): 25 mm; Diamètre extérieur (ConWidth_2): 27 mm; Profondeur extérieure (ConDepth_2): 27 mm; Épaisseur mur (ConWallThickness_2): 1 mm; Longueur connexion (ConLength_2): 20 mm; Diamètre connecteur (ConConnectorWidth_2): 40 mm; Profondeur connecteur (ConConnectorDepth_2): 0 mm; Largeur connecteur (ConConnectorWidth2_2): 5 mm; Position connexion en X (ConPosX_2): 485.25 mm; Position connexion en Y (ConPosY_2): 490 mm; Position connexion en Z (ConPosZ_2): 0 mm; Profondeur nominale (ConNominalDepth_3): 40 mm; Diamètre extérieur (ConWidth_3): 42 mm; Profondeur extérieure (ConDepth_3): 42 mm; Épaisseur mur (ConWallThickness_3): 1 mm; Longueur connexion (ConLength_3): 20 mm; Diamètre connecteur (ConConnectorWidth_3): 42 mm; Profondeur connecteur (ConConnectorDepth_3): 0 mm; Largeur connecteur (ConConnectorWidth2_3): 5 mm; Position connexion en X (ConPosX_3): 350 mm; Position connexion en Y (ConPosY_3): 400 mm; Position connexion en Z (ConPosZ_3): -200 mm; Profondeur nominale (ConNominalDepth_4): 40 mm; Diamètre extérieur (ConWidth_4): 42 mm; Profondeur extérieure (ConDepth_4): 42 mm; Épaisseur mur (ConWallThickness_4): 1 mm; Longueur connexion (ConLength_4): 20 mm; Diamètre connecteur (ConConnectorWidth_4): 42 mm; Profondeur connecteur (ConConnectorDepth_4): 0 mm; Largeur connecteur (ConConnectorWidth2_4): 0 mm; Position connexion en X (ConPosX_4): 502 mm; Position connexion en Y (ConPosY_4): 400 mm; Position connexion en Z (ConPosZ_4): -200 mm; Profondeur nominale (ConNominalDepth_5): 25.4 mm; Diamètre extérieur (ConWidth_5): 30 mm; Profondeur extérieure (ConDepth_5): 30 mm; Épaisseur mur (ConWallThickness_5): 2 mm; Longueur connexion (ConLength_5): 20 mm; Diamètre connecteur (ConConnectorWidth_5): 40 mm; Profondeur connecteur (ConConnectorDepth_5): 0 mm; Largeur connecteur (ConConnectorWidth2_5): 5 mm; Position connexion en X (ConPosX_5): 406 mm; Position connexion en Y (ConPosY_5): 400 mm; Position connexion en Z (ConPosZ_5): -200 mm
Name | In | Angle de rotation (deg) | Zones conflictuelles = Nom de zone liée | Numéro de zone liée | Nom d'étage d'implantation | Numéro d'étage d'implantation | Altitude à Zéro du Projet (mm) = Altitude de Référence Niveau 1 (mm) = Altitude de Référence Niveau 2 (mm) = Altitude à niveau de la mer (mm) = Coordonnée topographique Z (mm) | Altitude supérieure à premier niveau de référence (mm) = Altitude supérieure à Zéro du projet (mm) = Altitude supérieure à niveau de la mer (mm) = Altitude supérieure à deuxième niveau de référence (mm) | Altitude inférieure à premier niveau de référence (mm) = Altitude inférieure à Zéro du projet (mm) = Altitude inférieure à niveau de la mer (mm) = Altitude inférieure à deuxième niveau de référence (mm) | Coordonnée topographique X (mm) | Coordonnée topographique Y (mm)
Obj.-019 | rdc | 354.144 | Sejour cuisine | A03 | rdc | 3 | 3000 | 4037.9 | 3680 | 2230757 | -615592
Obj.-019 | rdc | 263.958 | Sejour cuisine/pl | A01 | rdc | 3 | 3000 | 4037.9 | 3680 | 2225456 | -605983
Obj.-019 | rdc | 270 | Sejour Cuisine | B01 | rdc | 3 | 3000 | 4037.9 | 3680 | 2223532 | -624471
Obj.-019 | rdc | 0 | Sejour cuisine | B03 | rdc | 3 | 3000 | 4037.9 | 3680 | 2219282 | -653013
Obj.-019 | rdc | 354.144 | Sejour Cuisine/pl | A04 | rdc | 3 | 3000 | 4037.9 | 3680 | 2238373 | -614466
Obj.-019 | rdc | 270 | Sejour cuisine | B02 | rdc | 3 | 3000 | 4037.9 | 3680 | 2223132 | -639280
Obj.-019 | rdc | 264.164 | Sejour Cuisine | A02 | rdc | 3 | 3000 | 4037.9 | 3680 | 2224158 | -617801
Obj.-019 | rdc | 90 | Sejour cuisine | B05 | rdc | 3 | 3000 | 4037.9 | 3680 | 2226492 | -638256
Obj.-019 | rdc | 0 | Sejour cuisine/pl | B04 | rdc | 3 | 3000 | 4037.9 | 3680 | 2230507 | -653013
Obj.-019 | Etage1 | 264.164 | Sejour cuisine | A12 | Etage1 | 4 | 5750 | 6787.9 | 6430 | 2224158 | -617801
Obj.-019 | Etage1 | 174.132 | Sejour cuisine/pl | A15 | Etage1 | 4 | 5750 | 6787.9 | 6430 | 2227841 | -611919
Obj.-019 | Etage1 | 263.958 | Sejour cuisine/pl | A11 | Etage1 | 4 | 5750 | 6787.9 | 6430 | 2225456 | -605983
Obj.-019 | Etage1 | 180.051 | Sejour cuisine | B11 | Etage1 | 4 | 5750 | 6787.9 | 6430 | 2227781 | -631733
Obj.-019 | Etage1 | 270 | Sejour Cuisine | B13 | Etage1 | 4 | 5750 | 6787.9 | 6430 | 2223132 | -639280
Obj.-019 | Etage1 | 354.144 | Sejour cuisine | A13 | Etage1 | 4 | 5750 | 6787.9 | 6430 | 2230720 | -615588
Obj.-019 | Etage1 | 90 | Sejour cuisine | B16 | Etage1 | 4 | 5750 | 6787.9 | 6430 | 2226492 | -638256
Obj.-019 | Etage1 | 270 | Sejour cuisine | B12 | Etage1 | 4 | 5750 | 6787.9 | 6430 | 2223532 | -624471
Obj.-019 | Etage1 | 354.144 | Sejour Cuisine/pl | A14 | Etage1 | 4 | 5750 | 6787.9 | 6430 | 2238373 | -614466
Obj.-019 | Etage1 | 0 | Sejour cuisine | B15 | Etage1 | 4 | 5750 | 6787.9 | 6430 | 2230507 | -653013
Obj.-019 | Etage1 | 0 | Sejour cuisine | B14 | Etage1 | 4 | 5750 | 6787.9 | 6430 | 2219282 | -653013
Obj.-019 | Etage 2 | 0 | Sejour cuisine | B25 | Etage 2 | 5 | 8500 | 9537.9 | 9180 | 2230507 | -653015
Obj.-019 | Etage 2 | 354.144 | Sejour cuisine | A23 | Etage 2 | 5 | 8500 | 9537.9 | 9180 | 2230755 | -615591
Obj.-019 | Etage 2 | 264.164 | Sejour cuisine | A22 | Etage 2 | 5 | 8500 | 9537.9 | 9180 | 2224158 | -617801
Obj.-019 | Etage 2 | 0 | Sejour cuisine | B24 | Etage 2 | 5 | 8500 | 9537.9 | 9180 | 2219282 | -653014
Obj.-019 | Etage 2 | 270 | Sejour cuisine | B22 | Etage 2 | 5 | 8500 | 9537.9 | 9180 | 2223532 | -624471
Obj.-019 | Etage 2 | 354.144 | Sejour cuisine/pl | A24 | Etage 2 | 5 | 8500 | 9537.9 | 9180 | 2238373 | -614466
Obj.-019 | Etage 2 | 263.958 | Sejour cuisine/pl | A21 | Etage 2 | 5 | 8500 | 9537.9 | 9180 | 2225456 | -605983
Obj.-019 | Etage 2 | 180 | Sejour cuisine | B21 | Etage 2 | 5 | 8500 | 9537.9 | 9180 | 2227781 | -631734
Obj.-019 | Etage 2 | 174.132 | Sejour cuisine/pl | A25 | Etage 2 | 5 | 8500 | 9537.9 | 9180 | 2227841 | -611919
Obj.-019 | Etage 2 | 270 | Sejour cuisine | B23 | Etage 2 | 5 | 8500 | 9537.9 | 9180 | 2223132 | -639280
Obj.-019 | Etage 2 | 90 | Sejour cuisine | B26 | Etage 2 | 5 | 8500 | 9537.9 | 9180 | 2226492 | -638256
Obj.-019 | Etage 3 | 90 | Sejour cuisine/pl | B35 | Etage 3 | 6 | 11550 | 12587.9 | 12230 | 2226492 | -638256
Obj.-019 | Etage 3 | 3.81667e-12 | Sejour cuisine | B34 | Etage 3 | 6 | 11550 | 12587.9 | 12230 | 2229863 | -647678
Obj.-019 | Etage 3 | 354.184 | Sejour cuisine | A32 | Etage 3 | 6 | 11550 | 12587.9 | 12230 | 2230756 | -615592
Obj.-019 | Etage 3 | 354.184 | Sejour cuisine/pl | A33 | Etage 3 | 6 | 11550 | 12587.9 | 12230 | 2238231 | -615591
Obj.-019 | Etage 3 | 174.184 | Sejour cuisine/pl | A34 | Etage 3 | 6 | 11550 | 12587.9 | 12230 | 2231093 | -612250
Obj.-019 | Etage 3 | 270 | Sejour cuisine | B32 | Etage 3 | 6 | 11550 | 12587.9 | 12230 | 2223532 | -624471
Obj.-019 | Etage 3 | 180 | Sejour cuisine/pl | B31 | Etage 3 | 6 | 11550 | 12587.9 | 12230 | 2227781 | -631734
Obj.-019 | Etage 3 | 270 | Sejour cuisine | B33 | Etage 3 | 6 | 11550 | 12587.9 | 12230 | 2223132 | -639280
Obj.-019 | Etage 3 | 174.184 | Sejour cuisine/pl | A31 | Etage 3 | 6 | 11550 | 12587.9 | 12230 | 2220531 | -611501
Obj.-019 | etage 4 | 180 | Sejour cuisine/pl | B41 | etage 4 | 7 | 14600 | 15637.9 | 15280 | 2227781 | -631734
Obj.-019 | etage 4 | 270 | Sejour cuisine | B43 | etage 4 | 7 | 14600 | 15637.9 | 15280 | 2223132 | -639280
Obj.-019 | etage 4 | 270 | Sejour cuisine | B42 | etage 4 | 7 | 14600 | 15637.9 | 15280 | 2223532 | -624471
Obj.-019 | etage 4 | 3.81667e-12 | Sejour cuisine | B53 | etage 4 | 7 | 14600 | 15637.9 | 15280 | 2300882 | -644796
Obj.-019 | etage 4 | 3.81667e-12 | Sejour cuisine | B44 | etage 4 | 7 | 14600 | 15637.9 | 15280 | 2228241 | -647518
Obj.-019 | Etage 5 | 180 | Sejour cuisine | B51 | Etage 5 | 8 | 17650 | 18687.9 | 18330 | 2221128 | -631834
Obj.-019 | Etage 5 | 360 | Sejour Cuisine | B52 | Etage 5 | 8 | 17650 | 18687.9 | 18330 | 2227582 | -647518
Obj.-019 | Etage 5 | 360 | Sejour Cuisine | B54 | Etage 5 | 8 | 17650 | 18687.9 | 18330 | 2301393 | -641335

# IfcDistributionElement: Lavabo 27 (28)
Classification: Elément de distribution (Classification ARCHICAD)
ArchiCADProperties - Surface: Revêt. pilier rond; ID de l'élément: Obj.-019; Lien et ID d'élément: Obj.-019; Calque: SANITAIRE; Nom Élément de Bibliothèque: Lavabo 27; Matériau de construction / Composite / Profil / Hachure: Brique 1; Type Hachure: Brique 1; Verrouillé: no; Type d'élément: Objet; ID de Parent: Obj.-019; Surfaces (Toutes): Métal-Inox; Métal-Chrome; Surface-Ceramiques vitrifiées; Nom de Variante: Modèle principal; Nom de Jeu de Variantes: Modèle principal; Position: Non défini; Fonction structurelle: Non défini; Affichage sur filtre de rénovation: Tous les filtres appropriés; État de rénovation: Existant; État de Variante: Modèle principal; Jeu de Variantes: Modèle principal
AC_Pset_RenovationAndPhasing - Renovation Status: Existing
AC_Pset_Lavabo_27 - Type évier (stStyle): Rectangulaire; Type évier (iStyle): 6; Afficher points chauds 2D en 3D: no; Définir programme: no; Niveau de détail 3D: 1; Type de support (suptyp): Sans; Type de support (iSuptyp): 0; Type robinet (tapGroup): Mélangeur niveau unique; Type robinet (iTapGroup): 1; Style de robinet (gs_tap_type): Style 1; Style de robinet (gs_tap_type_m): 1; Connexion d'eau chaude: yes; Type outil (ConToolType_1): 2; Système MEP (ConSystem_1): Non défini; Type de forme (ConType_1): Cercle; Type connexion (ConConnectorType_1): Soudé; Connexion d'eau froide: yes; Type outil (ConToolType_2): 2; Système MEP (ConSystem_2): Non défini; Type de forme (ConType_2): Cercle; Type connexion (ConConnectorType_2): Soudé; Connexion eau résiduaire: yes; Type outil (ConToolType_3): 2; Système MEP (ConSystem_3): Non défini; Type de forme (ConType_3): Cercle; Type connexion (ConConnectorType_3): Soudé; Résolution: 12; Résolution connexion: 8; Ombre: yes; Type de symbole (gs_symbol_type): Fondé sur modèle; Type de symbole (iSymbolType): 1; Activer types de symbole: no; Niveau de détail 2D: 1; Type symbole robinet (TapSymbol): Détaillé; Type symbole robinet (TapSymbol_m): 2; Motif de hachure: Sans Trame; Lavabo: Surface-Ceramiques vitrifiées; Robinet: Métal-Chrome; Egout: Métal-Inox; Connexion: Métal-Inox; Utiliser surface de système: no; Surface de système: C14; Nombre connexions: 3; Coût: 0; Type de groupe (FM_Type): Sanitaires; Type de groupe (iFMType): 13; Superficie: 0; Volume: 0; Poids de l'objet: 0; Unité poids de l'objet: kg
ArchiCADQuantities - Longueur (A): 440 mm; Superficie: 0.11 m2; Hauteur: 135 mm; Volume (net): 0.012763 m3; Largeur: 250 mm; Altitude à étage lié/étage d'implantation: 0 mm; Décalage étage d'implantation: 0 mm; Superficie en plan: 0.705455 m2; Altitude supérieure à étage d'implantation: 1095.55 mm; Altitude inférieure à étage d'implantation: 845 mm; Superficie supérieure (nette): 0.11 m2; Superficie inférieure (nette): 0.705455 m2
AC_Equantity_Lavabo_27 - Largeur lavabo: 440 mm; Profondeur lavabo: 250 mm; Hauteur: 135 mm; Hauteur supérieure: 1000 mm; Niveau inférieur: 865 mm; Niveau supérieur: 1000 mm; Hauteur robinet: 1100 mm; Position robinet en X: 0 mm; Position robinet en Y: 0 mm; Position robinet en Z: 0 mm; Profondeur nominale (ConNominalDepth_1): 25 mm; Diamètre extérieur (ConWidth_1): 27 mm; Profondeur extérieure (ConDepth_1): 27 mm; Épaisseur mur (ConWallThickness_1): 1 mm; Longueur connexion (ConLength_1): 20 mm; Diamètre connecteur (ConConnectorWidth_1): 40 mm; Profondeur connecteur (ConConnectorDepth_1): 0 mm; Largeur connecteur (ConConnectorWidth2_1): 5 mm; Position connexion en X (ConPosX_1): -100 mm; Position connexion en Y (ConPosY_1): 0 mm; Position connexion en Z (ConPosZ_1): 93 mm; Profondeur nominale (ConNominalDepth_2): 25 mm; Diamètre extérieur (ConWidth_2): 27 mm; Profondeur extérieure (ConDepth_2): 27 mm; Épaisseur mur (ConWallThickness_2): 1 mm; Longueur connexion (ConLength_2): 20 mm; Diamètre connecteur (ConConnectorWidth_2): 40 mm; Profondeur connecteur (ConConnectorDepth_2): 0 mm; Largeur connecteur (ConConnectorWidth2_2): 5 mm; Position connexion en X (ConPosX_2): 100 mm; Position connexion en Y (ConPosY_2): 0 mm; Position connexion en Z (ConPosZ_2): 93 mm; Profondeur nominale (ConNominalDepth_3): 40 mm; Diamètre extérieur (ConWidth_3): 42 mm; Profondeur extérieure (ConDepth_3): 42 mm; Épaisseur mur (ConWallThickness_3): 1 mm; Longueur connexion (ConLength_3): 20 mm; Diamètre connecteur (ConConnectorWidth_3): 42 mm; Profondeur connecteur (ConConnectorDepth_3): 0 mm; Largeur connecteur (ConConnectorWidth2_3): 5 mm; Position connexion en X (ConPosX_3): 0 mm; Position connexion en Y (ConPosY_3): -148.178 mm; Position connexion en Z (ConPosZ_3): 0 mm; Espace minimum devant: 1100 mm; Espace minimum sur côté 1: 170 mm; Espace minimum sur côté 2: 220 mm
Name | In | Angle de rotation (deg) | Zones conflictuelles = Nom de zone liée | Numéro de zone liée | Nom d'étage d'implantation | Numéro d'étage d'implantation | Altitude à Zéro du Projet (mm) = Altitude de Référence Niveau 1 (mm) = Altitude de Référence Niveau 2 (mm) = Altitude à niveau de la mer (mm) = Coordonnée topographique Z (mm) | Altitude supérieure à premier niveau de référence (mm) = Altitude supérieure à Zéro du projet (mm) = Altitude supérieure à niveau de la mer (mm) = Altitude supérieure à deuxième niveau de référence (mm) | Altitude inférieure à premier niveau de référence (mm) = Altitude inférieure à Zéro du projet (mm) = Altitude inférieure à niveau de la mer (mm) = Altitude inférieure à deuxième niveau de référence (mm) | Coordonnée topographique X (mm) | Coordonnée topographique Y (mm)
Obj.-019 | rdc | 264.199 | Wc | A04 | rdc | 3 | 3000 | 4095.55 | 3845 | 2235307 | -611983
Obj.-019 | rdc | 264.199 | Wc | A03 | rdc | 3 | 3000 | 4095.55 | 3845 | 2232684 | -615407
Obj.-019 | rdc | 90 | Wc | B03 | rdc | 3 | 3000 | 4095.55 | 3845 | 2222542 | -651375
Obj.-019 | rdc | 270 | Wc | B04 | rdc | 3 | 3000 | 4095.55 | 3845 | 2225917 | -651944
Obj.-019 | rdc | 90 | Wc | B02 | rdc | 3 | 3000 | 4095.55 | 3845 | 2222372 | -638362
Obj.-019 | Etage1 | 263.978 | Wc | A13 | Etage1 | 4 | 5750 | 6845.55 | 6595 | 2232683 | -615407
Obj.-019 | Etage1 | 270 | Wc | B15 | Etage1 | 4 | 5750 | 6845.55 | 6595 | 2225687 | -651944
Obj.-019 | Etage1 | 89.9201 | Wc | B14 | Etage1 | 4 | 5750 | 6845.55 | 6595 | 2222542 | -651373
Obj.-019 | Etage1 | 180 | Wc | B12 | Etage1 | 4 | 5750 | 6845.55 | 6595 | 2223912 | -628780
Obj.-019 | Etage1 | 180 | Wc | B16 | Etage1 | 4 | 5750 | 6845.55 | 6595 | 2226112 | -641820
Obj.-019 | Etage1 | 90 | Wc | B13 | Etage1 | 4 | 5750 | 6845.55 | 6595 | 2222372 | -638362
Obj.-019 | Etage 2 | 270 | Wc | B25 | Etage 2 | 5 | 8500 | 9595.55 | 9345 | 2225687 | -651945
Obj.-019 | Etage 2 | 90 | Wc | B24 | Etage 2 | 5 | 8500 | 9595.55 | 9345 | 2222542 | -651372
Obj.-019 | Etage 2 | 90 | Wc | B23 | Etage 2 | 5 | 8500 | 9595.55 | 9345 | 2222372 | -638362
Obj.-019 | Etage 2 | 180 | Wc | B22 | Etage 2 | 5 | 8500 | 9595.55 | 9345 | 2223912 | -628780
Obj.-019 | Etage 2 | 263.978 | Wc | A23 | Etage 2 | 5 | 8500 | 9595.55 | 9345 | 2232680 | -615407
Obj.-019 | Etage 2 | 263.978 | Wc | A24 | Etage 2 | 5 | 8500 | 9595.55 | 9345 | 2235307 | -611983
Obj.-019 | Etage 3 | 264.212 | Wc | A33 | Etage 3 | 6 | 11550 | 12645.5 | 12395 | 2235242 | -611937
Obj.-019 | Etage 3 | 264.212 | Wc | A32 | Etage 3 | 6 | 11550 | 12645.5 | 12395 | 2232684 | -615407
Obj.-019 | Etage 3 | 180 | Wc | B35 | Etage 3 | 6 | 11550 | 12645.5 | 12395 | 2226112 | -641820
Obj.-019 | Etage 3 | 90 | Wc 1 | B34 | Etage 3 | 6 | 11550 | 12645.5 | 12395 | 2225782 | -647138
Obj.-019 | Etage 3 | 90 | Wc | B33 | Etage 3 | 6 | 11550 | 12645.5 | 12395 | 2222372 | -638362
Obj.-019 | Etage 3 | 180 | Wc | B32 | Etage 3 | 6 | 11550 | 12645.5 | 12395 | 2223912 | -628780
Obj.-019 | etage 4 | 90 | Wc | B44 | etage 4 | 7 | 14600 | 15695.5 | 15445 | 2225892 | -646518
Obj.-019 | etage 4 | 180 | Wc | B42 | etage 4 | 7 | 14600 | 15695.5 | 15445 | 2223912 | -628780
Obj.-019 | etage 4 | 90 | Wc | B43 | etage 4 | 7 | 14600 | 15695.5 | 15445 | 2222372 | -638362
Obj.-019 | Etage 5 | 360 | Wc | B51 | Etage 5 | 8 | 17650 | 18745.5 | 18495 | 2226174 | -630331
Obj.-019 | Etage 5 | 360 | Wc | B52 | Etage 5 | 8 | 17650 | 18745.5 | 18495 | 2225492 | -643165

# IfcDistributionElement: Lavabo encastré ellipse (60)
Classification: Elément de distribution (Classification ARCHICAD)
ArchiCADProperties - Surface: C10; ID de l'élément: Obj.-003; Lien et ID d'élément: Obj.-003; Calque: SANITAIRE; Nom Élément de Bibliothèque: Lavabo encastré ellipse; Matériau de construction / Composite / Profil / Hachure: Brique 1; Type Hachure: Brique 1; Verrouillé: no; Type d'élément: Objet; ID de Parent: Obj.-003; Surfaces (Toutes): Métal-Inox; Métal-Chrome; Surface-Plastique stratifié; Nom de Variante: Modèle principal; Nom de Jeu de Variantes: Modèle principal; Position: Non défini; Fonction structurelle: Non défini; Affichage sur filtre de rénovation: Tous les filtres appropriés; État de rénovation: Existant; État de Variante: Modèle principal; Jeu de Variantes: Modèle principal
AC_Pset_RenovationAndPhasing - Renovation Status: Existing
ArchiCADQuantities - Hauteur: 1000 mm
AC_Pset_Lavabo_encastré_ellipse - 3D: Détaillé; Styles robinet: Sans; Côtés visibles: Les deux; Résolution: 12; Ombre: yes; Afficher points chauds 2D en 3D: no; Encombrement minimal: no; Motif de hachure: Sans Trame; Matière plateau / plan: Surface-Plastique stratifié; Matière dosseret: Surface-Plastique stratifié; Matière lavabo: Métal-Chrome; Matière robinet: Métal-Nickel; Matière siphon: Métal-Inox; Coût: 0; Type de groupe (FM_Type): Equipement CVCA; Type de groupe (iFMType): 12; Code ERP: 0; Numéro de commande: 0; Poids de l'objet: 0; Unité poids de l'objet: kg; Version: 4; Nombre connexions: 0; Unité d'eau chaude requise: 0; Unité d'eau froide requise: 0; Unité de vidange: 0; Nombre de points chauds: 0
AC_Equantity_Lavabo_encastré_ellipse - Dimension Z: 1000 mm; Epaisseur tablette: 30 mm; Hauteur Dosseret - 0-Sans: 100 mm; Distance lavabo à partir du centre: 0 mm; Niveau inférieur: 1000 mm; Niveau supérieur: 0 mm
Name | In | Angle de rotation (deg) | Zones conflictuelles = Nom de zone liée | Numéro de zone liée | Nom d'étage d'implantation | Numéro d'étage d'implantation | Longueur (A) (mm) = Dimension X (mm) | Superficie (m2) = Superficie supérieure (nette) (m2) | Volume (net) (m3) | Largeur (mm) = Dimension Y (mm) | Altitude à Zéro du Projet (mm) = Altitude de Référence Niveau 1 (mm) = Altitude de Référence Niveau 2 (mm) = Altitude à niveau de la mer (mm) = Coordonnée topographique Z (mm) | Altitude à étage lié/étage d'implantation (mm) = Décalage étage d'implantation (mm) | Superficie en plan (m2) = Superficie inférieure (nette) (m2) | Altitude supérieure à premier niveau de référence (mm) = Altitude supérieure à Zéro du projet (mm) = Altitude supérieure à niveau de la mer (mm) = Altitude supérieure à deuxième niveau de référence (mm) | Altitude supérieure à étage d'implantation (mm) | Altitude inférieure à premier niveau de référence (mm) = Altitude inférieure à Zéro du projet (mm) = Altitude inférieure à niveau de la mer (mm) = Altitude inférieure à deuxième niveau de référence (mm) | Altitude inférieure à étage d'implantation (mm) | Coordonnée topographique X (mm) | Coordonnée topographique Y (mm)
Obj.-003 | rdc | 0.0595536 | Sdb | B03 | rdc | 3 | 600 | 0.3 | 0.00524116 | 500 | 3000 | 0 | 0.846401 | 3100 | 100 | 2857 | -143 | 2222492 | -644697
Obj.-003 | rdc | 354.07 | Sdb | A01 | rdc | 3 | 800 | 0.48 | 0.0110412 | 600 | 3895 | 895 | 1.2724 | 3995 | 995 | 3752 | 752 | 2222737 | -608533
Obj.-003 | rdc | 354.19 | Sdb | A04 | rdc | 3 | 800 | 0.48 | 0.0110412 | 600 | 3000 | 0 | 1.2724 | 3100 | 100 | 2857 | -143 | 2238423 | -611309
Obj.-003 | rdc | 90 | Sdb | B05 | rdc | 3 | 800 | 0.48 | 0.0110412 | 600 | 3895 | 895 | 1.2724 | 3995 | 995 | 3752 | 752 | 2226791 | -645359
Obj.-003 | rdc | 0.0595536 | Sdb | B03 | rdc | 3 | 600 | 0.3 | 0.00524116 | 500 | 3000 | 0 | 0.846401 | 3100 | 100 | 2857 | -143 | 2221892 | -644698
Obj.-003 | rdc | 180.001 | Sdb | B01 | rdc | 3 | 800 | 0.48 | 0.0110412 | 600 | 3895 | 895 | 1.2724 | 3995 | 995 | 3752 | 752 | 2223182 | -631834
Obj.-003 | rdc | 90 | Sdb | B02 | rdc | 3 | 800 | 0.48 | 0.0110412 | 600 | 4000 | 1000 | 1.2724 | 4100 | 1100 | 3857 | 857 | 2221681 | -633584
Obj.-003 | rdc | 174.325 | Sdb | A03 | rdc | 3 | 800 | 0.48 | 0.0110412 | 600 | 3895 | 895 | 1.2724 | 3995 | 995 | 3752 | 752 | 2225622 | -620717
Obj.-003 | rdc | 270.06 | Sde | B04 | rdc | 3 | 800 | 0.48 | 0.0110412 | 600 | 3000 | 0 | 1.2724 | 3100 | 100 | 2857 | -143 | 2227658 | -647917
Obj.-003 | rdc | 354.07 | Sdb/pl | A02 | rdc | 3 | 800 | 0.48 | 0.0110412 | 600 | 3895 | 895 | 1.2724 | 3995 | 995 | 3752 | 752 | 2221997 | -611954
Obj.-003 | Etage1 | 89.986 | Sde | B11 | Etage1 | 4 | 800 | 0.48 | 0.0110412 | 600 | 6645 | 895 | 1.2724 | 6745 | 995 | 6502 | 752 | 2224912 | -625698
Obj.-003 | Etage1 | 354.18 | Sdb | A14 | Etage1 | 4 | 800 | 0.48 | 0.0110412 | 600 | 6645 | 895 | 1.2724 | 6745 | 995 | 6502 | 752 | 2238423 | -611309
Obj.-003 | Etage1 | 180 | Sde | B12 | Etage1 | 4 | 800 | 0.48 | 0.0110412 | 600 | 5750 | 0 | 1.2724 | 5850 | 100 | 5607 | -143 | 2222319 | -631834
Obj.-003 | Etage1 | 270.06 | Sde | B15 | Etage1 | 4 | 800 | 0.48 | 0.0110412 | 600 | 5750 | 0 | 1.2724 | 5850 | 100 | 5607 | -143 | 2227658 | -647917
Obj.-003 | Etage1 | 90 | Sde | B13 | Etage1 | 4 | 800 | 0.48 | 0.0110412 | 600 | 6750 | 1000 | 1.2724 | 6850 | 1100 | 6607 | 857 | 2221681 | -633584
Obj.-003 | Etage1 | 84.1075 | Sde | A11 | Etage1 | 4 | 800 | 0.48 | 0.0110412 | 600 | 5750 | 0 | 1.2724 | 5850 | 100 | 5607 | -143 | 2221459 | -607801
Obj.-003 | Etage1 | 84.1926 | Sde | A15 | Etage1 | 4 | 800 | 0.48 | 0.0110412 | 600 | 6645 | 895 | 1.2724 | 6745 | 995 | 6502 | 752 | 2231982 | -611345
Obj.-003 | Etage1 | 90 | Sde | B16 | Etage1 | 4 | 800 | 0.48 | 0.0110412 | 600 | 5750 | 0 | 1.2724 | 5850 | 100 | 5607 | -143 | 2226791 | -644559
Obj.-003 | Etage1 | 174.229 | Sde | A13 | Etage1 | 4 | 800 | 0.48 | 0.0110412 | 600 | 5750 | 0 | 1.2724 | 5850 | 100 | 5607 | -143 | 2224775 | -620632
Obj.-003 | Etage1 | 0.0595536 | Sde | B14 | Etage1 | 4 | 600 | 0.3 | 0.00524116 | 500 | 5750 | 0 | 0.846401 | 5850 | 100 | 5607 | -143 | 2221892 | -644698
Obj.-003 | Etage1 | 0.0595536 | Sde | B14 | Etage1 | 4 | 600 | 0.3 | 0.00524116 | 500 | 5750 | 0 | 0.846401 | 5850 | 100 | 5607 | -143 | 2222492 | -644697
Obj.-003 | Etage1 | 354.18 | Sde | A12 | Etage1 | 4 | 800 | 0.48 | 0.0110412 | 600 | 6645 | 895 | 1.2724 | 6745 | 995 | 6502 | 752 | 2221172 | -611868
Obj.-003 | Etage 2 | 354.197 | Sde | A22 | Etage 2 | 5 | 800 | 0.48 | 0.0110412 | 600 | 9395 | 895 | 1.2724 | 9495 | 995 | 9252 | 752 | 2221173 | -611868
Obj.-003 | Etage 2 | 90 | Sde | B26 | Etage 2 | 5 | 800 | 0.48 | 0.0110412 | 600 | 9500 | 1000 | 1.2724 | 9600 | 1100 | 9357 | 857 | 2226791 | -645359
Obj.-003 | Etage 2 | 90 | Sde | B23 | Etage 2 | 5 | 800 | 0.48 | 0.0110412 | 600 | 9500 | 1000 | 1.2724 | 9600 | 1100 | 9357 | 857 | 2221681 | -633584
Obj.-003 | Etage 2 | 180 | Sde | B22 | Etage 2 | 5 | 800 | 0.48 | 0.0110412 | 600 | 8500 | 0 | 1.2724 | 8600 | 100 | 8357 | -143 | 2222319 | -631834
Obj.-003 | Etage 2 | 174.325 | Sde | A23 | Etage 2 | 5 | 800 | 0.48 | 0.0110412 | 600 | 9395 | 895 | 1.2724 | 9495 | 995 | 9252 | 752 | 2225622 | -620717
Obj.-003 | Etage 2 | 84.1917 | Sde | A25 | Etage 2 | 5 | 800 | 0.48 | 0.0110412 | 600 | 9395 | 895 | 1.2724 | 9495 | 995 | 9252 | 752 | 2231982 | -611345
Obj.-003 | Etage 2 | 270.06 | Sde | B25 | Etage 2 | 5 | 800 | 0.4 | 0.00864116 | 500 | 8500 | 0 | 1.1064 | 8600 | 100 | 8357 | -143 | 2227757 | -647820
Obj.-003 | Etage 2 | 90.0017 | Sde | B21 | Etage 2 | 5 | 800 | 0.48 | 0.0110412 | 600 | 9395 | 895 | 1.2724 | 9495 | 995 | 9252 | 752 | 2224912 | -625698
Obj.-003 | Etage 2 | 0.0595536 | Sde | B24 | Etage 2 | 5 | 600 | 0.3 | 0.00524116 | 500 | 8500 | 0 | 0.846401 | 8600 | 100 | 8357 | -143 | 2221892 | -644698
Obj.-003 | Etage 2 | 0.0595536 | Sde | B24 | Etage 2 | 5 | 600 | 0.3 | 0.00524116 | 500 | 8500 | 0 | 0.846401 | 8600 | 100 | 8357 | -143 | 2222492 | -644697
Obj.-003 | Etage 2 | 354.19 | Sde | A24 | Etage 2 | 5 | 800 | 0.48 | 0.0110412 | 600 | 8500 | 0 | 1.2724 | 8600 | 100 | 8357 | -143 | 2238423 | -611309
Obj.-003 | Etage 2 | 84.1075 | Sde | A21 | Etage 2 | 5 | 800 | 0.48 | 0.0110412 | 600 | 8500 | 0 | 1.2724 | 8600 | 100 | 8357 | -143 | 2221459 | -607801
Obj.-003 | Etage 3 | 354.201 | Sde1 | A31 | Etage 3 | 6 | 600 | 0.3 | 0.00524116 | 500 | 11550 | 0 | 0.846401 | 11650 | 100 | 11407 | -143 | 2223973 | -616760
Obj.-003 | Etage 3 | 264.2 | Sde/pl | A34 | Etage 3 | 6 | 800 | 0.48 | 0.0110412 | 600 | 11550 | 0 | 1.2724 | 11650 | 100 | 11407 | -143 | 2228772 | -610071
Obj.-003 | Etage 3 | 0.0595536 | Sdb | B34 | Etage 3 | 6 | 700 | 0.42 | 0.00904116 | 600 | 11550 | 0 | 1.1224 | 11650 | 100 | 11407 | -143 | 2222229 | -644796
Obj.-003 | Etage 3 | 90 | Sde | B33 | Etage 3 | 6 | 800 | 0.48 | 0.0110412 | 600 | 12550 | 1000 | 1.2724 | 12650 | 1100 | 12407 | 857 | 2221681 | -633584
Obj.-003 | Etage 3 | 174.325 | Sde | A32 | Etage 3 | 6 | 800 | 0.48 | 0.0110412 | 600 | 12445 | 895 | 1.2724 | 12545 | 995 | 12302 | 752 | 2225547 | -620709
Obj.-003 | Etage 3 | 90.0003 | Sde | B31 | Etage 3 | 6 | 800 | 0.48 | 0.0110412 | 600 | 11550 | 0 | 1.2724 | 11650 | 100 | 11407 | -143 | 2224912 | -624898
Obj.-003 | Etage 3 | 180 | Sde | B32 | Etage 3 | 6 | 800 | 0.48 | 0.0110412 | 600 | 11550 | 0 | 1.2724 | 11650 | 100 | 11407 | -143 | 2222319 | -631834
Obj.-003 | Etage 3 | 0.0595536 | Sdb | B34 | Etage 3 | 6 | 700 | 0.42 | 0.00904116 | 600 | 11550 | 0 | 1.1224 | 11650 | 100 | 11407 | -143 | 2221529 | -644796
Obj.-003 | Etage 3 | 179.999 | Sde | B34 | Etage 3 | 6 | 800 | 0.48 | 0.0110412 | 600 | 11550 | 0 | 1.2724 | 11650 | 100 | 11407 | -143 | 2223231 | -654101
Obj.-003 | Etage 3 | 354.308 | Sde | A33 | Etage 3 | 6 | 800 | 0.48 | 0.0110412 | 600 | 11550 | 0 | 1.2724 | 11650 | 100 | 11407 | -143 | 2238285 | -612421
Obj.-003 | Etage 3 | 90 | Sde | B35 | Etage 3 | 6 | 800 | 0.48 | 0.0110412 | 600 | 11550 | 0 | 1.2724 | 11650 | 100 | 11407 | -143 | 2226791 | -644559
Obj.-003 | Etage 3 | 264.025 | Sde2 | A31 | Etage 3 | 6 | 800 | 0.48 | 0.0110412 | 600 | 11550 | 0 | 1.2724 | 11650 | 100 | 11407 | -143 | 2223602 | -619335
Obj.-003 | Etage 3 | 354.201 | Sde1 | A31 | Etage 3 | 6 | 600 | 0.3 | 0.00524116 | 500 | 11550 | 0 | 0.846401 | 11650 | 100 | 11407 | -143 | 2223376 | -616699
Obj.-003 | etage 4 | 90.0003 | Sde | B41 | etage 4 | 7 | 800 | 0.48 | 0.0110412 | 600 | 14600 | 0 | 1.2724 | 14700 | 100 | 14457 | -143 | 2224912 | -624946
Obj.-003 | etage 4 | 179.94 | Sde 1 | B44 | etage 4 | 7 | 600 | 0.3 | 0.00524116 | 500 | 14600 | 0 | 0.846401 | 14700 | 100 | 14457 | -143 | 2229455 | -646239
Obj.-003 | etage 4 | 0.0000308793 | Sde 2 | B44 | etage 4 | 7 | 700 | 0.35 | 0.00694116 | 500 | 14600 | 0 | 0.976401 | 14700 | 100 | 14457 | -143 | 2223179 | -644696
Obj.-003 | etage 4 | 180.01 | Sde | B42 | etage 4 | 7 | 800 | 0.48 | 0.0110412 | 600 | 14600 | 0 | 1.2724 | 14700 | 100 | 14457 | -143 | 2222319 | -631834
Obj.-003 | etage 4 | 90 | Sde | B43 | etage 4 | 7 | 800 | 0.48 | 0.0110412 | 600 | 15600 | 1000 | 1.2724 | 15700 | 1100 | 15457 | 857 | 2221681 | -633584
Obj.-003 | etage 4 | 179.94 | Sde 1 | B44 | etage 4 | 7 | 600 | 0.3 | 0.00524116 | 500 | 14600 | 0 | 0.846401 | 14700 | 100 | 14457 | -143 | 2230055 | -646239
Obj.-003 | etage 4 | 0.0000258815 | Ch 3/sde | B44 | etage 4 | 7 | 700 | 0.35 | 0.00694116 | 500 | 14600 | 0 | 0.976401 | 14700 | 100 | 14457 | -143 | 2226852 | -638073
Obj.-003 | Etage 5 | 360 | Sde 1 | B52 | Etage 5 | 8 | 600 | 0.36 | 0.00704116 | 600 | 18650 | 1000 | 0.972401 | 18750 | 1100 | 18507 | 857 | 2221724 | -636787
Obj.-003 | Etage 5 | 90 | Sde 2 | B52 | Etage 5 | 8 | 800 | 0.48 | 0.0110412 | 600 | 18650 | 1000 | 1.2724 | 18750 | 1100 | 18507 | 857 | 2227984 | -645038
Obj.-003 | Etage 5 | 90 | Sdb | B51 | Etage 5 | 8 | 600 | 0.3 | 0.00524116 | 500 | 17650 | 0 | 0.846401 | 17750 | 100 | 17507 | -143 | 2224372 | -627123
Obj.-003 | Etage 5 | 360 | Sde 1 | B52 | Etage 5 | 8 | 600 | 0.36 | 0.00704116 | 600 | 18650 | 1000 | 0.972401 | 18750 | 1100 | 18507 | 857 | 2222324 | -636787
Obj.-003 | Etage 5 | 90 | Sdb | B51 | Etage 5 | 8 | 600 | 0.3 | 0.00524116 | 500 | 17650 | 0 | 0.846401 | 17750 | 100 | 17507 | -143 | 2224372 | -627723
Obj.-003 | Etage 5 | 270.001 | sde | B51 | Etage 5 | 8 | 800 | 0.48 | 0.0110412 | 600 | 17650 | 0 | 1.2724 | 17750 | 100 | 17507 | -143 | 2223532 | -635107

# IfcDistributionElement: Lavabo ovale (2)
Classification: Elément de distribution (Classification ARCHICAD)
ArchiCADProperties - Surface: C10; ID de l'élément: Obj.-003; Lien et ID d'élément: Obj.-003; Calque: SANITAIRE; Nom Élément de Bibliothèque: Lavabo ovale; Matériau de construction / Composite / Profil / Hachure: Brique 1; Type Hachure: Brique 1; Verrouillé: no; Type d'élément: Objet; ID de Parent: Obj.-003; Surfaces (Toutes): Métal-Inox; Métal-Chrome; Surface-Ceramiques vitrifiées; Nom de Variante: Modèle principal; Nom de Jeu de Variantes: Modèle principal; Position: Non défini; Fonction structurelle: Non défini; Affichage sur filtre de rénovation: Tous les filtres appropriés; État de rénovation: Existant; État de Variante: Modèle principal; Jeu de Variantes: Modèle principal
AC_Pset_Lavabo_ovale - 3D: Détaillé; Styles robinet: Sans; Résolution: 12; Ombre: yes; Afficher points chauds 2D en 3D: no; Encombrement minimal: no; Motif de hachure: Sans Trame; Matière lavabo: Surface-Ceramiques vitrifiées; Matière robinet: Métal-Chrome; Matière siphon: Métal-Inox; Coût: 0; Type de groupe (FM_Type): Equipement CVCA; Type de groupe (iFMType): 12; Code ERP: 0; Numéro de commande: 0; Poids de l'objet: 0; Unité poids de l'objet: kg; Version: 4; Nombre connexions: 0; Unité d'eau chaude requise: 0; Unité d'eau froide requise: 0; Unité de vidange: 0; Nombre de points chauds: 0
AC_Pset_RenovationAndPhasing - Renovation Status: Existing
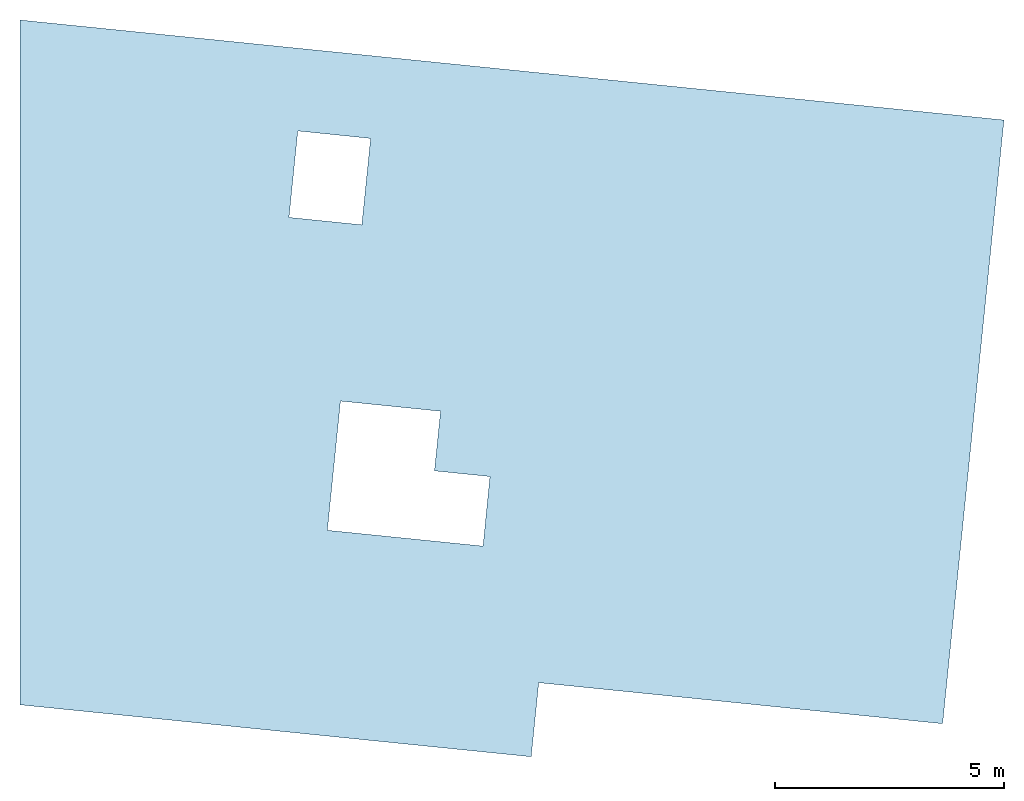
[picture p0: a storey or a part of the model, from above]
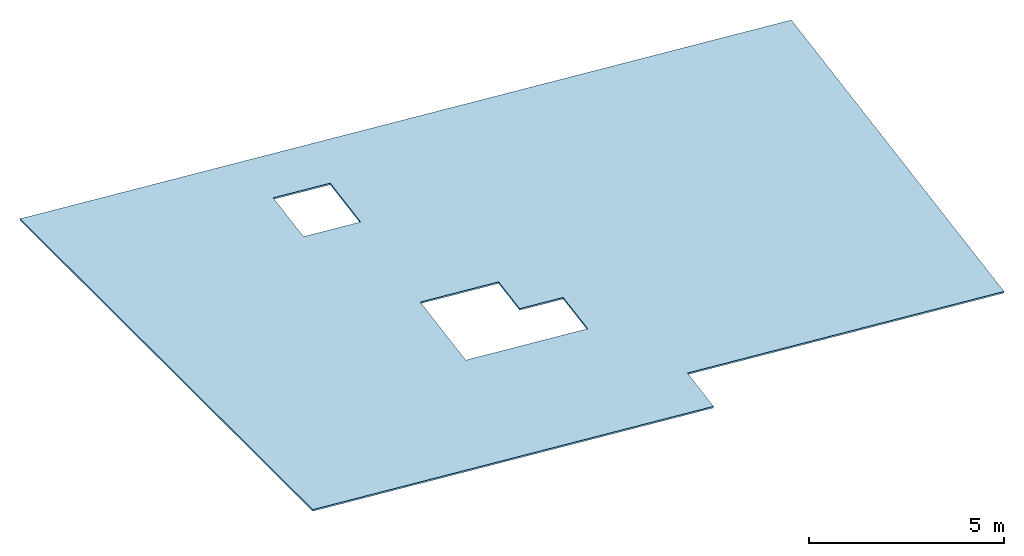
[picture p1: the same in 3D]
Properties of the parts of a building model (IFC2X3), part 12 of 44

# IfcDistributionElement: Lavabo ovale (2)
AC_Equantity_Lavabo_ovale - Dimension Y: 500 mm; Hauteur: 140 mm; Niveau inférieur: 1000 mm; Niveau supérieur: 0 mm
ArchiCADQuantities - Hauteur: 140 mm; Largeur: 500 mm; Altitude à étage lié/étage d'implantation: 0 mm; Décalage étage d'implantation: 0 mm; Altitude inférieure à étage d'implantation: -140 mm
Name | In | Angle de rotation (deg) | Nom d'étage d'implantation | Numéro d'étage d'implantation | Dimension X (mm) = Longueur (A) (mm) | Superficie (m2) = Superficie supérieure (nette) (m2) | Volume (net) (m3) | Altitude à Zéro du Projet (mm) = Altitude de Référence Niveau 1 (mm) = Altitude de Référence Niveau 2 (mm) = Altitude à niveau de la mer (mm) = Coordonnée topographique Z (mm) | Superficie en plan (m2) = Superficie inférieure (nette) (m2) | Altitude supérieure à premier niveau de référence (mm) = Altitude supérieure à Zéro du projet (mm) = Altitude supérieure à niveau de la mer (mm) = Altitude supérieure à deuxième niveau de référence (mm) | Altitude supérieure à étage d'implantation (mm) | Altitude inférieure à premier niveau de référence (mm) = Altitude inférieure à Zéro du projet (mm) = Altitude inférieure à niveau de la mer (mm) = Altitude inférieure à deuxième niveau de référence (mm) | Coordonnée topographique X (mm) | Coordonnée topographique Y (mm)
Obj.-003 | sousol | 84.0064 | sousol | 2 | 400 | 0.2 | 0.00314445 | 0 | 0.544356 | -1.38778e-14 | -1.38778e-14 | -140 | 2225141 | -605695
Obj.-003 | rdc | 180.39 | rdc | 3 | 600 | 0.3 | 0.00471667 | 3000 | 0.768591 | 3000 | 0 | 2860 | 2222445 | -631936 | ArchiCADProperties - Nom de zone liée: Sdb; Numéro de zone liée: B01

# IfcDistributionElement: WC 3 (13)
Classification: Elément de distribution (Classification ARCHICAD)
ArchiCADProperties - Surface: C10; ID de l'élément: Obj.-003; Lien et ID d'élément: Obj.-003; Calque: SANITAIRE; Nom Élément de Bibliothèque: WC 3; Matériau de construction / Composite / Profil / Hachure: Brique 1; Type Hachure: Brique 1; Verrouillé: no; Type d'élément: Objet; ID de Parent: Obj.-003; Surfaces (Toutes): Surface-Ceramiques vitrifiées; Surface-Plastique stratifié; Nom de Variante: Modèle principal; Nom de Jeu de Variantes: Modèle principal; Position: Non défini; Fonction structurelle: Non défini; Affichage sur filtre de rénovation: Tous les filtres appropriés; État de rénovation: Existant; État de Variante: Modèle principal; Jeu de Variantes: Modèle principal
AC_Pset_RenovationAndPhasing - Renovation Status: Existing
ArchiCADQuantities - Longueur (A): 440 mm; Superficie: 0.286 m2; Hauteur: 740 mm; Volume (net): 0.027395 m3; Largeur: 650 mm; Altitude à étage lié/étage d'implantation: 0 mm; Décalage étage d'implantation: 0 mm; Superficie en plan: 1.66956 m2; Altitude supérieure à étage d'implantation: 750 mm; Altitude inférieure à étage d'implantation: 0 mm; Superficie supérieure (nette): 0.286 m2; Superficie inférieure (nette): 1.66956 m2
AC_Equantity_WC_3 - Dimension X: 440 mm; Dimension Y: 650 mm; Hauteur: 740 mm; Niveau inférieur: 1000 mm; Niveau supérieur: 0 mm
AC_Pset_WC_3 - 3D: Détaillé; Résolution: 8; Ombre: yes; Afficher points chauds 2D en 3D: yes; Encombrement minimal: no; Motif de hachure: Sans Trame; Matière cuvette: Surface-Ceramiques vitrifiées; Matière réservoir: Surface-Ceramiques vitrifiées; Matière siège: Surface-Plastique stratifié; Coût: 0; Type de groupe (FM_Type): Equipement CVCA; Type de groupe (iFMType): 12; Code ERP: 0; Numéro de commande: 0; Poids de l'objet: 0; Unité poids de l'objet: kg; Version: 4; Nombre connexions: 0; Unité d'eau chaude requise: 0; Unité d'eau froide requise: 0; Unité de vidange: 0; Nombre de points chauds: 0
Name | In | Angle de rotation (deg) | Zones conflictuelles = Nom de zone liée | Numéro de zone liée | Nom d'étage d'implantation | Numéro d'étage d'implantation | Altitude à Zéro du Projet (mm) = Altitude de Référence Niveau 1 (mm) = Altitude de Référence Niveau 2 (mm) = Altitude à niveau de la mer (mm) = Altitude inférieure à premier niveau de référence (mm) = Altitude inférieure à Zéro du projet (mm) = Altitude inférieure à niveau de la mer (mm) = Altitude inférieure à deuxième niveau de référence (mm) = Coordonnée topographique Z (mm) | Altitude supérieure à premier niveau de référence (mm) = Altitude supérieure à Zéro du projet (mm) = Altitude supérieure à niveau de la mer (mm) = Altitude supérieure à deuxième niveau de référence (mm) | Coordonnée topographique X (mm) | Coordonnée topographique Y (mm)
Obj.-003 | rdc | 0.0000132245 | Wc | B05 | rdc | 3 | 3000 | 3750 | 2226445 | -641149
Obj.-003 | rdc | 174.105 | Sdb | A01 | rdc | 3 | 3000 | 3750 | 2221279 | -609513
Obj.-003 | rdc | 0.0000132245 | Wc | B01 | rdc | 3 | 3000 | 3750 | 2223960 | -628106
Obj.-003 | rdc | 174.105 | Wc | A02 | rdc | 3 | 3000 | 3750 | 2224660 | -615997
Obj.-003 | Etage1 | 180 | Sde | B11 | Etage1 | 4 | 5750 | 6500 | 2224926 | -626597
Obj.-003 | Etage1 | 264.108 | Wc | A15 | Etage1 | 4 | 5750 | 6500 | 2231252 | -612678
Obj.-003 | Etage1 | 84.2861 | Wc | A14 | Etage1 | 4 | 5750 | 6500 | 2234363 | -612211
Obj.-003 | Etage1 | 174.197 | Wc | A12 | Etage1 | 4 | 5750 | 6500 | 2224235 | -615953
Obj.-003 | Etage 2 | 0 | Wc | B26 | Etage 2 | 5 | 8500 | 9250 | 2226444 | -641149
Obj.-003 | Etage 2 | 263.926 | Wc | A25 | Etage 2 | 5 | 8500 | 9250 | 2231298 | -612238
Obj.-003 | Etage 2 | 180 | Sde | B21 | Etage 2 | 5 | 8500 | 9250 | 2224926 | -626597
Obj.-003 | Etage 2 | 174.197 | Wc | A22 | Etage 2 | 5 | 8500 | 9250 | 2224673 | -615998
Obj.-003 | Etage 3 | 263.926 | Wc | A31 | Etage 3 | 6 | 11550 | 12300 | 2224302 | -614906

# IfcDoor (67)
Type - ParameterTakesPrecedence: no; Sizeable: no
Classification: Porte (Classification ARCHICAD)
ArchiCADQuantities - Épaisseur cadre: 100 mm
AC_Pset_RenovationAndPhasing - Renovation Status: Existing
ArchiCADProperties - Index hachure latérale ouverture: Brique 1; Matériau de construction / Composite / Profil / Hachure: Brique 1; Type Hachure: Brique 1; Verrouillé: no; Type d'élément: Porte; Nom de Variante: Modèle principal; Nom de Jeu de Variantes: Modèle principal; Position: Non défini; Fonction structurelle: Non défini; Affichage sur filtre de rénovation: Tous les filtres appropriés; État de rénovation: Existant; État de Variante: Modèle principal; Jeu de Variantes: Modèle principal
Name | In | OverallHeight (mm) = Hauteur nominale de l'ouverture P/F côté ébrasure (mm) = Hauteur nominale de l'ouverture P/F côté opposée ébrasure (mm) = Hauteur (mm) | OverallWidth (mm) = Largeur nominale de l'ouverture P/F côté ébrasure (mm) = Largeur nominale de l'ouverture P/F côté opposée ébrasure (mm) = Largeur (mm) | Volume ouverture d'ouverture P/F (m3) | Volume nominal ouverture P/F (m3) | Superficie ouverture P/F (m2) = Superficie en plan (m2) = Superficie inférieure (nette) (m2) | Superficie nominale ouverture P/F (m2) = Superficie nominale de l'ouverture P/F côté ébrasure (m2) = Superficie nominale de l'ouverture P/F côté opposé ébrasure (m2) | Largeur ouverture P/F côté ébrasure (mm) | Hauteur ouverture P/F côté ébrasure (mm) | Largeur ouverture P/F côté opposé ébrasure (mm) | Hauteur ouverture P/F côté opposé ébrasure (mm) | Superficie ouverture P/F côté ébrasure (m2) | Superficie ouverture P/F côté opposé ébrasure (m2) | Valeur Appui ou Linteau (mm) = Hauteur nominale seuil (mm) | Hauteur seuil P/F côté ébrasure (mm) = Hauteur seuil P/F côté opposé ébrasure (mm) | Hauteur nominale linteau P/F (mm) | Hauteur linteau P/F côté ébrasure (mm) = Hauteur linteau P/F côté opposé ébrasure (mm) | Épaisseur de Mur (mm) | Volume (net) (m3) | Altitude à Zéro du Projet (mm) = Altitude de Référence Niveau 1 (mm) = Altitude de Référence Niveau 2 (mm) = Altitude à niveau de la mer (mm) | Altitude à étage lié/étage d'implantation (mm) = Décalage étage d'implantation (mm) | Altitude supérieure à premier niveau de référence (mm) = Altitude supérieure à Zéro du projet (mm) = Altitude supérieure à niveau de la mer (mm) = Altitude supérieure à deuxième niveau de référence (mm) | Altitude supérieure à étage d'implantation (mm) | Altitude inférieure à premier niveau de référence (mm) = Altitude inférieure à Zéro du projet (mm) = Altitude inférieure à niveau de la mer (mm) = Altitude inférieure à deuxième niveau de référence (mm) | Altitude inférieure à étage d'implantation (mm) | Taille L x H nominale | Taille L x H x E nominale | Structure de Mur | Orientation | Nom élément de bibliothèque d'ouverture = Nom Élément de Bibliothèque | ID de l'élément = Lien et ID d'élément | Calque | Nom d'étage d'implantation | Numéro d'étage d'implantation | ID de Parent | Surfaces (Toutes) | Zones conflictuelles | Nom de zone liée | Numéro de zone liée | De Zone | Du numéro de Zone | À Zone | À numéro de Zone
Por-238 | sousol | 2200 | 3600 | 1.4256 | 1.4256 | 17.8166 | 7.92 | 3600 | 2200 | 3600 | 2200 | 7.92 | 7.92 | 0 | 0 | 2200 | 2100 | 180 | 0.42512 | 4.18415e-12 | 4.18415e-12 | 2200 | 2200 | 4.18365e-12 | 4.18365e-12 | 3,60×2,20 | 3,60×2,20×0,18 | Beton 18 0170347028 | D | Porte de garage 1 70 | Por-238 | 3D | sousol | 2 | Mur-132 | Tablette métal
Por-254 | rdc | 2000 | 1013.09 | 0.138355 | 0.141832 | 4.03848 | 2.02618 | 988.252 | 2000 | 988.252 | 2000 | 1.9765 | 1.9765 | 0 | 0 | 2000 | 1900 | 70 | 0.0302599 | 3000 | 0 | 5000 | 2000 | 3000 | 0 | 1,01×2,00 | 1,01×2,00×0,07 | Cloison 70 0826278243 | D | Portes_coulissantes | Por-254 | 1-Projet | rdc | 3 | Mur-149 | Bois-Pin; Surface-Plastique stratifié; Divers-Glace | Entree/pl | Entree/pl | A02 | Entree/pl | A02
Por-321 | rdc | 2000 | 1519.97 | 0.207195 | 0.212795 | 5.6605 | 3.03993 | 1479.97 | 2000 | 1479.97 | 2000 | 2.95993 | 2.95993 | 0 | 0 | 2000 | 1900 | 70 | 0.0414113 | 3000 | 0 | 5000 | 2000 | 3000 | 0 | 1,52×2,00 | 1,52×2,00×0,07 | Cloison 70 0826278243 | D | Portes_coulissantes | Por-321 | 1-Projet | rdc | 3 | Mur-149 | Bois-Pin; Surface-Plastique stratifié; Divers-Glace | Ch 2/pl | Ch 2/pl | B03 |  |  | Ch 2/pl | B03
Por-322 | rdc | 2000 | 1006.8 | 0.140953 | 0.140953 | 4.01837 | 2.01361 | 1006.8 | 2000 | 1006.8 | 2000 | 2.01361 | 2.01361 | 0 | 0 | 2000 | 1900 | 70 | 0.0301217 | 3000 | 0 | 5000 | 2000 | 3000 | 0 | 1,01×2,00 | 1,01×2,00×0,07 | Cloison 70 0826278243 | G | Portes_coulissantes | Por-322 | 1-Projet | rdc | 3 | Mur-149 | Bois-Pin; Surface-Plastique stratifié; Divers-Glace | Sejour cuisine/pl | Sejour cuisine/pl | A01 |  |  | Sejour cuisine/pl | A01
Por-321 | rdc | 2000 | 1829.52 | 0.250534 | 0.256133 | 6.65107 | 3.65904 | 1789.52 | 2000 | 1789.52 | 2000 | 3.57904 | 3.57904 | 0 | 0 | 2000 | 1900 | 70 | 0.0482215 | 3000 | 0 | 5000 | 2000 | 3000 | 0 | 1,83×2,00 | 1,83×2,00×0,07 | Cloison 70 0826278243 | G | Portes_coulissantes | Por-321 | 1-Projet | rdc | 3 | Mur-149 | Bois-Pin; Surface-Plastique stratifié; Divers-Glace | Entree/pl | Entree/pl | B01 |  |  | Entree/pl | B01
Por-325 | rdc | 2000 | 1571.42 | 0.214399 | 0.219999 | 5.82514 | 3.14284 | 1531.42 | 2000 | 1531.42 | 2000 | 3.06284 | 3.06284 | 0 | 0 | 2000 | 1900 | 70 | 0.0425432 | 3000 | 0 | 5000 | 2000 | 3000 | 0 | 1,57×2,00 | 1,57×2,00×0,07 | Cloison 70 0826278243 | G | Portes_coulissantes | Por-325 | 1-Projet | rdc | 3 | Mur-153 | Bois-Pin; Surface-Plastique stratifié; Divers-Glace | Ch 2/pl | Ch 2/pl | A04 | Ch 2/pl | A04
Por-254 | rdc | 2000 | 1174.54 | 0.164436 | 0.164436 | 4.55514 | 2.34909 | 1174.54 | 2000 | 1174.54 | 2000 | 2.34909 | 2.34909 | 0 | 0 | 2000 | 1900 | 70 | 0.0338119 | 3000 | 0 | 5000 | 2000 | 3000 | 0 | 1,17×2,00 | 1,17×2,00×0,07 | Cloison 70 0826278243 | D | Portes_coulissantes | Por-254 | 1-Projet | rdc | 3 | Mur-153 | Bois-Pin; Surface-Plastique stratifié; Divers-Glace | Sejour Cuisine/pl | Sejour Cuisine/pl | A04 |  |  | Sejour Cuisine/pl | A04
Por-321 | rdc | 2000 | 1568.6 | 0.219604 | 0.219604 | 5.81612 | 3.1372 | 1568.6 | 2000 | 1568.6 | 2000 | 3.1372 | 3.1372 | 0 | 0 | 2000 | 1900 | 70 | 0.0424812 | 3000 | 0 | 5000 | 2000 | 3000 | 0 | 1,57×2,00 | 1,57×2,00×0,07 | Cloison 70 0826278243 | G | Portes_coulissantes | Por-321 | 1-Projet | rdc | 3 | Mur-149 | Bois-Pin; Surface-Plastique stratifié; Divers-Glace | Ch 1/pl | Ch 1/pl | B04 | Ch 1/pl | B04
Por-321 | rdc | 2000 | 1589.97 | 0.216995 | 0.222595 | 5.8845 | 3.17993 | 1549.97 | 2000 | 1549.97 | 2000 | 3.09993 | 3.09993 | 0 | 0 | 2000 | 1900 | 70 | 0.0429513 | 3000 | 0 | 5000 | 2000 | 3000 | 0 | 1,59×2,00 | 1,59×2,00×0,07 | Cloison 70 0826278243 | D | Portes_coulissantes | Por-321 | 1-Projet | rdc | 3 | Mur-149 | Bois-Pin; Surface-Plastique stratifié; Divers-Glace | Entree/pl | Entree/pl | B03 | Entree/pl | B03
Por-321 | rdc | 2000 | 1805.73 | 0.246973 | 0.252802 | 6.57494 | 3.61146 | 1764.1 | 2000 | 1764.1 | 2000 | 3.52819 | 3.52819 | 0 | 0 | 2000 | 1900 | 70 | 0.0476981 | 3000 | 0 | 5000 | 2000 | 3000 | 0 | 1,81×2,00 | 1,81×2,00×0,07 | Cloison 70 0826278243 | D | Portes_coulissantes | Por-321 | 1-Projet | rdc | 3 | Mur-149 | Bois-Pin; Surface-Plastique stratifié; Divers-Glace | Entree/pl | Entree/pl | B02 |  |  | Entree/pl | B02
Por-325 | rdc | 2000 | 976.066 | 0.136649 | 0.136649 | 3.92001 | 1.95213 | 976.066 | 2000 | 976.066 | 2000 | 1.95213 | 1.95213 | 0 | 0 | 2000 | 1900 | 70 | 0.0294455 | 3000 | 0 | 5000 | 2000 | 3000 | 0 | 0,98×2,00 | 0,98×2,00×0,07 | Cloison 70 0826278243 | D | Portes_coulissantes | Por-325 | 1-Projet | rdc | 3 | Mur-149 | Bois-Pin; Surface-Plastique stratifié; Divers-Glace | Entree/pl | Entree/pl | B04 | Entree/pl | B04
Por-321 | rdc | 2000 | 843.343 | 0.112468 | 0.118068 | 3.4953 | 1.68669 | 803.343 | 2000 | 803.343 | 2000 | 1.60669 | 1.60669 | 0 | 0 | 2000 | 1900 | 70 | 0.0265255 | 3000 | 0 | 5000 | 2000 | 3000 | 0 | 0,84×2,00 | 0,84×2,00×0,07 | Cloison 70 0826278243 | G | Portes_coulissantes | Por-321 | 1-Projet | rdc | 3 | Mur-149 | Bois-Pin; Surface-Plastique stratifié; Divers-Glace | Entree/pl | Entree/pl | B05 |  |  | Entree/pl | B05
Por-285 | rdc | 2200 | 2500 | 1.76027 | 1.87 | 9.95326 | 5.5 | 2500 | 2200 | 2500 | 2200 | 5.17726 | 5.17726 | 1500 | 1400 | 3700 | 3600 | 340 | 0.0629031 | 4000 | 1000 | 6200 | 3200 | 4000 | 1000 | 2,50×2,20 | 2,50×2,20×0,34 | Empty Fill 272047960 | D | Porte_ext_v_arc_70 | Por-285 | Interieurs logements | rdc | 3 | Mur-143 | Vitrage-Verre; Peinture-01
Por-329 | rdc | 2000 | 1553.12 | 0.211837 | 0.217437 | 5.76658 | 3.10624 | 1513.12 | 2000 | 1513.12 | 2000 | 3.02624 | 3.02624 | 0 | 0 | 2000 | 1900 | 70 | 0.0421406 | 3000 | 0 | 5000 | 2000 | 3000 | 0 | 1,55×2,00 | 1,55×2,00×0,07 | Cloison 70 0826278243 | G | Portes_coulissantes | Por-329 | 1-Projet | rdc | 3 | Mur-149 | Bois-Pin; Surface-Plastique stratifié; Divers-Glace | Ch 1/pl | Ch 1/pl | B02 |  |  | Ch 1/pl | B02
Por-321 | Etage1 | 2000 | 1805.73 | 0.246973 | 0.252802 | 6.57494 | 3.61146 | 1764.1 | 2000 | 1764.1 | 2000 | 3.52819 | 3.52819 | 0 | 0 | 2000 | 1900 | 70 | 0.0476981 | 5750 | 0 | 7750 | 2000 | 5750 | 0 | 1,81×2,00 | 1,81×2,00×0,07 | Cloison 70 0826278243 | G | Portes_coulissantes | Por-321 | 1-Projet | Etage1 | 4 | Mur-149 | Bois-Pin; Surface-Plastique stratifié; Divers-Glace | Entree/pl | Entree/pl | B13 | Entree/pl | B13
Por-321 | Etage1 | 2000 | 1829.52 | 0.250534 | 0.256133 | 6.65107 | 3.65904 | 1789.52 | 2000 | 1789.52 | 2000 | 3.57904 | 3.57904 | 0 | 0 | 2000 | 1900 | 70 | 0.0482215 | 5750 | 0 | 7750 | 2000 | 5750 | 0 | 1,83×2,00 | 1,83×2,00×0,07 | Cloison 70 0826278243 | G | Portes_coulissantes | Por-321 | 1-Projet | Etage1 | 4 | Mur-149 | Bois-Pin; Surface-Plastique stratifié; Divers-Glace | Entree/pl | Entree/pl | B12 |  |  | Entree/pl | B12
Por-321 | Etage1 | 2000 | 2149.1 | 0.300875 | 0.300875 | 7.67373 | 4.29821 | 2149.1 | 2000 | 2149.1 | 2000 | 4.29821 | 4.29821 | 0 | 0 | 2000 | 1900 | 70 | 0.0552523 | 5750 | 0 | 7750 | 2000 | 5750 | 0 | 2,15×2,00 | 2,15×2,00×0,07 | Cloison 70 0826278243 | G | Portes_coulissantes | Por-321 | 1-Projet | Etage1 | 4 | Mur-149 | Bois-Pin; Surface-Plastique stratifié; Divers-Glace | Ch 1/pl | Ch 1/pl | B12 | Ch 1/pl | B12 | Ch 1/pl | B12
Por-254 | Etage1 | 2000 | 1174.54 | 0.158836 | 0.164436 | 4.55514 | 2.34909 | 1134.54 | 2000 | 1134.54 | 2000 | 2.26909 | 2.26909 | 0 | 0 | 2000 | 1900 | 70 | 0.0338119 | 5750 | 0 | 7750 | 2000 | 5750 | 0 | 1,17×2,00 | 1,17×2,00×0,07 | Cloison 70 0826278243 | D | Portes_coulissantes | Por-254 | 1-Projet | Etage1 | 4 | Mur-153 | Bois-Pin; Surface-Plastique stratifié; Divers-Glace | Sejour Cuisine/pl | Sejour Cuisine/pl | A14 | Sejour Cuisine/pl | A14
Por-323 | Etage1 | 2000 | 1720.16 | 0.240823 | 0.240823 | 6.30112 | 3.44032 | 1720.16 | 2000 | 1720.16 | 2000 | 3.44032 | 3.44032 | 0 | 0 | 2000 | 1900 | 70 | 0.0458156 | 5750 | 0 | 7750 | 2000 | 5750 | 0 | 1,72×2,00 | 1,72×2,00×0,07 | Cloison 70 0826278243 | D | Portes_coulissantes | Por-323 | 1-Projet | Etage1 | 4 | Mur-149 | Bois-Pin; Surface-Plastique stratifié; Divers-Glace | Ch 1/pl | Ch 1/pl | B16 | Ch 1/pl | B16 | Ch 1/pl | B16
Por-329 | Etage1 | 2000 | 1553.12 | 0.217437 | 0.217437 | 5.76658 | 3.10624 | 1553.12 | 2000 | 1553.12 | 2000 | 3.10624 | 3.10624 | 0 | 0 | 2000 | 1900 | 70 | 0.0421406 | 5750 | 0 | 7750 | 2000 | 5750 | 0 | 1,55×2,00 | 1,55×2,00×0,07 | Cloison 70 0826278243 | G | Portes_coulissantes | Por-329 | 1-Projet | Etage1 | 4 | Mur-149 | Bois-Pin; Surface-Plastique stratifié; Divers-Glace | Ch 1/pl | Ch 1/pl | B13 | Ch 1/pl | B13 | Ch 1/pl | B13
Por-254 | Etage1 | 2000 | 1448.05 | 0.197127 | 0.202727 | 5.43035 | 2.8961 | 1408.05 | 2000 | 1408.05 | 2000 | 2.8161 | 2.8161 | 0 | 0 | 2000 | 1900 | 70 | 0.0398291 | 5750 | 0 | 7750 | 2000 | 5750 | 0 | 1,45×2,00 | 1,45×2,00×0,07 | Cloison 70 0826278243 | D | Portes_coulissantes | Por-254 | 1-Projet | Etage1 | 4 | Mur-148 | Bois-Pin; Surface-Plastique stratifié; Divers-Glace | Sejour cuisine/pl | Sejour cuisine/pl | A15 |  |  | Sejour cuisine/pl | A15
Por-321 | Etage1 | 2000 | 1525.23 | 0.213532 | 0.213532 | 5.67733 | 3.05046 | 1525.23 | 2000 | 1525.23 | 2000 | 3.05046 | 3.05046 | 0 | 0 | 2000 | 1900 | 70 | 0.041527 | 5750 | 0 | 7750 | 2000 | 5750 | 0 | 1,53×2,00 | 1,53×2,00×0,07 | Cloison 70 0826278243 | G | Portes_coulissantes | Por-321 | 1-Projet | Etage1 | 4 | Mur-149 | Bois-Pin; Surface-Plastique stratifié; Divers-Glace | Ch 2/pl | Ch 2/pl | B14 |  |  | Ch 2/pl | B14
Por-321 | Etage1 | 2000 | 1013.09 | 0.138355 | 0.141832 | 4.03848 | 2.02618 | 988.252 | 2000 | 988.252 | 2000 | 1.9765 | 1.9765 | 0 | 0 | 2000 | 1900 | 70 | 0.0302599 | 5750 | 0 | 7750 | 2000 | 5750 | 0 | 1,01×2,00 | 1,01×2,00×0,07 | Cloison 70 0826278243 | G | Portes_coulissantes | Por-321 | 1-Projet | Etage1 | 4 | Mur-149 | Bois-Pin; Surface-Plastique stratifié; Divers-Glace | Entree/pl | Entree/pl | A12 |  |  | Entree/pl | A12
Por-321 | Etage1 | 2000 | 1568.6 | 0.219604 | 0.219604 | 5.81612 | 3.1372 | 1568.6 | 2000 | 1568.6 | 2000 | 3.1372 | 3.1372 | 0 | 0 | 2000 | 1900 | 70 | 0.0424812 | 5750 | 0 | 7750 | 2000 | 5750 | 0 | 1,57×2,00 | 1,57×2,00×0,07 | Cloison 70 0826278243 | G | Portes_coulissantes | Por-321 | 1-Projet | Etage1 | 4 | Mur-149 | Bois-Pin; Surface-Plastique stratifié; Divers-Glace | Ch 1/pl | Ch 1/pl | B15 |  |  | Ch 1/pl | B15
Por-321 | Etage1 | 2000 | 843.343 | 0.112468 | 0.118068 | 3.4953 | 1.68669 | 803.343 | 2000 | 803.343 | 2000 | 1.60669 | 1.60669 | 0 | 0 | 2000 | 1900 | 70 | 0.0265255 | 5750 | 0 | 7750 | 2000 | 5750 | 0 | 0,84×2,00 | 0,84×2,00×0,07 | Cloison 70 0826278243 | G | Portes_coulissantes | Por-321 | 1-Projet | Etage1 | 4 | Mur-149 | Bois-Pin; Surface-Plastique stratifié; Divers-Glace | Entree/pl | Entree/pl | B16 |  |  | Entree/pl | B16
Por-321 | Etage1 | 2000 | 871.932 | 0.114541 | 0.12207 | 3.58678 | 1.74386 | 818.151 | 2000 | 818.151 | 2000 | 1.6363 | 1.6363 | 0 | 0 | 2000 | 1900 | 70 | 0.0271545 | 5750 | 0 | 7750 | 2000 | 5750 | 0 | 0,87×2,00 | 0,87×2,00×0,07 | Cloison 70 0826278243 | D | Portes_coulissantes | Por-321 | 1-Projet | Etage1 | 4 | Mur-149 | Bois-Pin; Surface-Plastique stratifié; Divers-Glace | Entree/pl | Entree/pl | B15 |  |  | Entree/pl | B15
Por-322 | Etage1 | 2000 | 1589.99 | 0.216998 | 0.222598 | 5.88456 | 3.17997 | 1549.99 | 2000 | 1549.99 | 2000 | 3.09997 | 3.09997 | 0 | 0 | 2000 | 1900 | 70 | 0.0429517 | 5750 | 0 | 7750 | 2000 | 5750 | 0 | 1,59×2,00 | 1,59×2,00×0,07 | Cloison 70 0826278243 | D | Portes_coulissantes | Por-322 | 1-Projet | Etage1 | 4 | Mur-149 | Bois-Pin; Surface-Plastique stratifié; Divers-Glace | Entree/pl | Entree/pl | B14 | Entree/pl | B14
Por-321 | Etage 2 | 2000 | 1013.09 | 0.138355 | 0.141832 | 4.03848 | 2.02618 | 988.252 | 2000 | 988.252 | 2000 | 1.9765 | 1.9765 | 0 | 0 | 2000 | 1900 | 70 | 0.0302599 | 8500 | 0 | 10500 | 2000 | 8500 | 0 | 1,01×2,00 | 1,01×2,00×0,07 | Cloison 70 0826278243 | G | Portes_coulissantes | Por-321 | 1-Projet | Etage 2 | 5 | Mur-149 | Bois-Pin; Surface-Plastique stratifié; Divers-Glace | Entree/pl | Entree/pl | A22 |  |  | Entree/pl | A22
Por-322 | Etage 2 | 2000 | 1525.23 | 0.213532 | 0.213532 | 5.67733 | 3.05046 | 1525.23 | 2000 | 1525.23 | 2000 | 3.05046 | 3.05046 | 0 | 0 | 2000 | 1900 | 70 | 0.041527 | 8500 | 0 | 10500 | 2000 | 8500 | 0 | 1,53×2,00 | 1,53×2,00×0,07 | Cloison 70 0826278243 | G | Portes_coulissantes | Por-322 | 1-Projet | Etage 2 | 5 | Mur-149 | Bois-Pin; Surface-Plastique stratifié; Divers-Glace | Ch 2/pl | Ch 2/pl | B24 |  |  | Ch 2/pl | B24
Por-326 | Etage 2 | 2000 | 1567 | 0.21938 | 0.21938 | 5.811 | 3.134 | 1567 | 2000 | 1567 | 2000 | 3.134 | 3.134 | 0 | 0 | 2000 | 1900 | 70 | 0.042446 | 8500 | 0 | 10500 | 2000 | 8500 | 0 | 1,57×2,00 | 1,57×2,00×0,07 | Cloison 70 0826278243 | D | Portes_coulissantes | Por-326 | 1-Projet | Etage 2 | 5 | Mur-153 | Bois-Pin; Surface-Plastique stratifié; Divers-Glace | Ch 2/pl | Ch 2/pl | A24 | Ch 2/pl | A24 | Ch 2/pl | A24
Por-321 | Etage 2 | 2000 | 1829.52 | 0.250533 | 0.256133 | 6.65107 | 3.65904 | 1789.52 | 2000 | 1789.52 | 2000 | 3.57904 | 3.57905 | 0 | 0 | 2000 | 1900 | 70 | 0.0482215 | 8500 | 0 | 10500 | 2000 | 8500 | 0 | 1,83×2,00 | 1,83×2,00×0,07 | Cloison 70 0826278243 | G | Portes_coulissantes | Por-321 | 1-Projet | Etage 2 | 5 | Mur-149 | Bois-Pin; Surface-Plastique stratifié; Divers-Glace | Entree/pl | Entree/pl | B22 |  |  | Entree/pl | B22
Por-321 | Etage 2 | 2000 | 2149.12 | 0.30088 | 0.300877 | 7.6738 | 4.29825 | 2149.15 | 2968.39 | 2149.15 | 3000 | 4.29829 | 4.29829 | 0 | 0 | 2000 | 1900 | 70 | 0.0552527 | 8500 | 0 | 10500 | 2000 | 8500 | 0 | 2,15×2,00 | 2,15×2,00×0,07 | Cloison 70 0826278243 | G | Portes_coulissantes | Por-321 | 1-Projet | Etage 2 | 5 | Mur-149 | Bois-Pin; Surface-Plastique stratifié; Divers-Glace | Ch 1/pl | Ch 1/pl | B22 | Ch 1/pl | B22 | Ch 1/pl | B22
Por-321 | Etage 2 | 2000 | 1809.01 | 0.247791 | 0.253261 | 6.58543 | 3.61802 | 1769.93 | 2000 | 1769.93 | 2000 | 3.53987 | 3.53987 | 0 | 0 | 2000 | 1900 | 70 | 0.0477702 | 8500 | 0 | 10500 | 2000 | 8500 | 0 | 1,81×2,00 | 1,81×2,00×0,07 | Cloison 70 0826278243 | D | Portes_coulissantes | Por-321 | 1-Projet | Etage 2 | 5 | Mur-149 | Bois-Pin; Surface-Plastique stratifié; Divers-Glace | Entree/pl | Entree/pl | B23 |  |  | Entree/pl | B23
Por-324 | Etage 2 | 2000 | 1589.97 | 0.216995 | 0.222595 | 5.88449 | 3.17993 | 1549.97 | 2000 | 1549.97 | 2000 | 3.09993 | 3.09993 | 0 | 0 | 2000 | 1900 | 70 | 0.0429513 | 8500 | 0 | 10500 | 2000 | 8500 | 0 | 1,59×2,00 | 1,59×2,00×0,07 | Cloison 70 0826278243 | D | Portes_coulissantes | Por-324 | 1-Projet | Etage 2 | 5 | Mur-149 | Bois-Pin; Surface-Plastique stratifié; Divers-Glace | Entree/pl | Entree/pl | B24 | Entree/pl | B24
Por-254 | Etage 2 | 2000 | 1174.46 | 0.164424 | 0.164424 | 4.55486 | 2.34891 | 1174.46 | 2000 | 1174.46 | 2000 | 2.34891 | 2.34891 | 0 | 0 | 2000 | 1900 | 70 | 0.03381 | 8500 | 0 | 10500 | 2000 | 8500 | 0 | 1,17×2,00 | 1,17×2,00×0,07 | Cloison 70 0826278243 | D | Portes_coulissantes | Por-254 | 1-Projet | Etage 2 | 5 | Mur-153 | Bois-Pin; Surface-Plastique stratifié; Divers-Glace | Sejour cuisine/pl | Sejour cuisine/pl | A24 | Sejour cuisine/pl | A24 | Sejour cuisine/pl | A24
Por-254 | Etage 2 | 2000 | 1448.05 | 0.197127 | 0.202727 | 5.43035 | 2.8961 | 1408.05 | 2000 | 1408.05 | 2000 | 2.8161 | 2.8161 | 0 | 0 | 2000 | 1900 | 70 | 0.0398291 | 8500 | 0 | 10500 | 2000 | 8500 | 0 | 1,45×2,00 | 1,45×2,00×0,07 | Cloison 70 0826278243 | D | Portes_coulissantes | Por-254 | 1-Projet | Etage 2 | 5 | Mur-148 | Bois-Pin; Surface-Plastique stratifié; Divers-Glace | Sejour cuisine/pl | Sejour cuisine/pl | A25 |  |  | Sejour cuisine/pl | A25
Por-321 | Etage 2 | 2000 | 857.128 | 0.11841 | 0.119998 | 3.53941 | 1.71426 | 845.787 | 2000 | 845.787 | 2000 | 1.69157 | 1.69157 | 0 | 0 | 2000 | 1900 | 70 | 0.0268288 | 8500 | 0 | 10500 | 2000 | 8500 | 0 | 0,86×2,00 | 0,86×2,00×0,07 | Cloison 70 0826278243 | G | Portes_coulissantes | Por-321 | 1-Projet | Etage 2 | 5 | Mur-149 | Bois-Pin; Surface-Plastique stratifié; Divers-Glace | Entree/pl | Entree/pl | B25 | Entree/pl | B25 | Entree/pl | B25
Por-321 | Etage 2 | 2000 | 1188.36 | 0.16077 | 0.16637 | 4.59935 | 2.37672 | 1148.36 | 2000 | 1148.36 | 2000 | 2.29672 | 2.29672 | 0 | 0 | 2000 | 1900 | 70 | 0.0341159 | 8500 | 0 | 10500 | 2000 | 8500 | 0 | 1,19×2,00 | 1,19×2,00×0,07 | Cloison 70 0826278243 | G | Portes_coulissantes | Por-321 | 1-Projet | Etage 2 | 5 | Mur-149 | Bois-Pin; Surface-Plastique stratifié; Divers-Glace | Entree/pl | Entree/pl | B25 |  |  | Entree/pl | B25
Por-321 | Etage 2 | 2000 | 843.343 | 0.112468 | 0.118068 | 3.4953 | 1.68669 | 803.343 | 2000 | 803.343 | 2000 | 1.60669 | 1.60669 | 0 | 0 | 2000 | 1900 | 70 | 0.0265255 | 8500 | 0 | 10500 | 2000 | 8500 | 0 | 0,84×2,00 | 0,84×2,00×0,07 | Cloison 70 0826278243 | G | Portes_coulissantes | Por-321 | 1-Projet | Etage 2 | 5 | Mur-149 | Bois-Pin; Surface-Plastique stratifié; Divers-Glace | Entree/Pl | Entree/Pl | B26 |  |  | Entree/Pl | B26
Por-323 | Etage 2 | 2000 | 1720.16 | 0.240823 | 0.240823 | 6.30112 | 3.44032 | 1720.16 | 2000 | 1720.16 | 2000 | 3.44032 | 3.44032 | 0 | 0 | 2000 | 1900 | 70 | 0.0458156 | 8500 | 0 | 10500 | 2000 | 8500 | 0 | 1,72×2,00 | 1,72×2,00×0,07 | Cloison 70 0826278243 | D | Portes_coulissantes | Por-323 | 1-Projet | Etage 2 | 5 | Mur-149 | Bois-Pin; Surface-Plastique stratifié; Divers-Glace | Ch 1/pl | Ch 1/pl | B26 | Ch 1/pl | B26 | Ch 1/pl | B26
Por-329 | Etage 2 | 2000 | 1553.12 | 0.217434 | 0.217437 | 5.76658 | 3.10624 | 1553.1 | 2000 | 1553.1 | 2000 | 3.10619 | 3.10619 | 0 | 0 | 2000 | 1900 | 70 | 0.0421406 | 8500 | 0 | 10500 | 2000 | 8500 | 0 | 1,55×2,00 | 1,55×2,00×0,07 | Cloison 70 0826278243 | G | Portes_coulissantes | Por-329 | 1-Projet | Etage 2 | 5 | Mur-149 | Bois-Pin; Surface-Plastique stratifié; Divers-Glace | Ch 1/pl | Ch 1/pl | B23 | Ch 1/pl | B23 | Ch 1/pl | B23
Por-321 | Etage 2 | 2000 | 1568.54 | 0.219596 | 0.219596 | 5.81593 | 3.13708 | 1568.54 | 2000 | 1568.54 | 2000 | 3.13708 | 3.13708 | 0 | 0 | 2000 | 1900 | 70 | 0.0424799 | 8500 | 0 | 10500 | 2000 | 8500 | 0 | 1,57×2,00 | 1,57×2,00×0,07 | Cloison 70 0826278243 | G | Portes_coulissantes | Por-321 | 1-Projet | Etage 2 | 5 | Mur-149 | Bois-Pin; Surface-Plastique stratifié; Divers-Glace | Ch 1/pl | Ch 1/pl | B25 |  |  | Ch 1/pl | B25
Por-321 | Etage 3 | 2000 | 1038.21 | 0.140401 | 0.14535 | 4.11888 | 2.07643 | 1002.86 | 2000 | 1002.86 | 2000 | 2.00572 | 2.00572 | 0 | 0 | 2000 | 1900 | 70 | 0.0308127 | 11550 | 0 | 13550 | 2000 | 11550 | 0 | 1,04×2,00 | 1,04×2,00×0,07 | Cloison 70 0826278243 | G | Portes_coulissantes | Por-321 | 1-Projet | Etage 3 | 6 | Mur-153 | Bois-Pin; Surface-Plastique stratifié; Divers-Glace | Sejour cuisine/pl | Sejour cuisine/pl | A34 | Sejour cuisine/pl | A34
Por-321 | Etage 3 | 2000 | 1700.07 | 0.232528 | 0.23801 | 6.23682 | 3.40014 | 1660.92 | 2000 | 1660.92 | 2000 | 3.32183 | 3.32183 | 0 | 0 | 2000 | 1900 | 70 | 0.0453735 | 11550 | 0 | 13550 | 2000 | 11550 | 0 | 1,70×2,00 | 1,70×2,00×0,07 | Cloison 70 0826278243 | D | Portes_coulissantes | Por-321 | 1-Projet | Etage 3 | 6 | Mur-153 | Bois-Pin; Surface-Plastique stratifié; Divers-Glace | Sejour cuisine/pl | Sejour cuisine/pl | A31 | Sejour cuisine/pl | A31
Por-321 | Etage 3 | 2000 | 893.343 | 0.119468 | 0.125068 | 3.6553 | 1.78669 | 853.343 | 2000 | 853.343 | 2000 | 1.70669 | 1.70669 | 0 | 0 | 2000 | 1900 | 70 | 0.0276255 | 11550 | 0 | 13550 | 2000 | 11550 | 0 | 0,89×2,00 | 0,89×2,00×0,07 | Cloison 70 0826278243 | G | Portes_coulissantes | Por-321 | 1-Projet | Etage 3 | 6 | Mur-149 | Bois-Pin; Surface-Plastique stratifié; Divers-Glace | Entree/pl | Entree/pl | B35 |  |  | Entree/pl | B35
Por-321 | Etage 3 | 2000 | 1805.73 | 0.252802 | 0.252802 | 6.57494 | 3.61146 | 1805.73 | 2000 | 1805.73 | 2000 | 3.61146 | 3.61146 | 0 | 0 | 2000 | 1900 | 70 | 0.0476981 | 11550 | 0 | 13550 | 2000 | 11550 | 0 | 1,81×2,00 | 1,81×2,00×0,07 | Cloison 70 0826278243 | D | Portes_coulissantes | Por-321 | 1-Projet | Etage 3 | 6 | Mur-149 | Bois-Pin; Surface-Plastique stratifié; Divers-Glace | Entree/pl | Entree/pl | B33 | Entree/pl | B33
Por-321 | Etage 3 | 2000 | 1819.52 | 0.249134 | 0.254733 | 6.61907 | 3.63904 | 1779.52 | 2000 | 1779.52 | 2000 | 3.55904 | 3.55904 | 0 | 0 | 2000 | 1900 | 70 | 0.0480015 | 11550 | 0 | 13550 | 2000 | 11550 | 0 | 1,82×2,00 | 1,82×2,00×0,07 | Cloison 70 0826278243 | G | Portes_coulissantes | Por-321 | 1-Projet | Etage 3 | 6 | Mur-149 | Bois-Pin; Surface-Plastique stratifié; Divers-Glace | Entree/pl | Entree/pl | B32 |  |  | Entree/pl | B32
Por-321 | Etage 3 | 2000 | 2140.59 | 0.299683 | 0.299683 | 7.6465 | 4.28119 | 2140.59 | 2000 | 2140.59 | 2000 | 4.28119 | 4.28119 | 0 | 0 | 2000 | 1900 | 70 | 0.055065 | 11550 | 0 | 13550 | 2000 | 11550 | 0 | 2,14×2,00 | 2,14×2,00×0,07 | Cloison 70 0826278243 | G | Portes_coulissantes | Por-321 | 1-Projet | Etage 3 | 6 | Mur-149 | Bois-Pin; Surface-Plastique stratifié; Divers-Glace | Ch 1/pl | Ch 1/pl | B32 | Ch 1/pl | B32
Por-321 | Etage 3 | 2000 | 981.097 | 0.137354 | 0.137354 | 3.93611 | 1.96219 | 981.097 | 2000 | 981.097 | 2000 | 1.96219 | 1.96219 | 0 | 0 | 2000 | 1900 | 70 | 0.0295561 | 11550 | 0 | 13550 | 2000 | 11550 | 0 | 0,98×2,00 | 0,98×2,00×0,07 | Cloison 70 0826278243 | D | Portes_coulissantes | Por-321 | 1-Projet | Etage 3 | 6 | Mur-156 | Bois-Pin; Surface-Plastique stratifié; Divers-Glace | Ch 2/pl | Ch 2/pl | A33 |  |  | Ch 2/pl | A33
Por-321 | Etage 3 | 2000 | 937.266 | 0.125616 | 0.131217 | 3.79585 | 1.87453 | 897.249 | 2000 | 897.266 | 2000 | 1.7945 | 1.79453 | 0 | 0 | 2000 | 1900 | 70 | 0.0285919 | 11550 | 0 | 13550 | 2000 | 11550 | 0 | 0,94×2,00 | 0,94×2,00×0,07 | Cloison 70 0826278243 | G | Portes_coulissantes | Por-321 | 1-Projet | Etage 3 | 6 | Mur-156 | Bois-Pin; Surface-Plastique stratifié; Divers-Glace | Sejour cuisine/pl | Sejour cuisine/pl | A33 | Sejour cuisine/pl | A33
Por-329 | Etage 3 | 2000 | 1553.12 | 0.217437 | 0.217437 | 5.76658 | 3.10624 | 1553.12 | 2000 | 1553.12 | 2000 | 3.10624 | 3.10624 | 0 | 0 | 2000 | 1900 | 70 | 0.0421406 | 11550 | 0 | 13550 | 2000 | 11550 | 0 | 1,55×2,00 | 1,55×2,00×0,07 | Cloison 70 0826278243 | G | Portes_coulissantes | Por-329 | 1-Projet | Etage 3 | 6 | Mur-149 | Bois-Pin; Surface-Plastique stratifié; Divers-Glace | Ch 1/pl | Ch 1/pl | B33 | Ch 1/pl | B33 | Ch 1/pl | B33
Por-279 | Etage 3 | 2100 | 900 | 0.189 | 0.189 | 3.81744 | 1.89 | 900 | 2100 | 900 | 2100 | 1.89 | 1.89 | 0 | 0 | 2100 | 2000 | 100 | 0.0306871 | 11550 | 0 | 13650 | 2100 | 11550 | 0 | 0,90×2,10 | 0,90×2,10×0,10 | Cloison 100 0826278243 | D | Couliss ds mur 70 | Por-279 | 1-Projet | Etage 3 | 6 | Mur-149 | Dallage-Asphalte Lisse; Vitrage-Verre; Noyer |  | Dgt/pl | B34 | Wc 2 | B34 | Dgt/pl | B34
Por-323 | Etage 3 | 2000 | 2329.29 | 0.326101 | 0.326101 | 8.25033 | 4.65858 | 2329.29 | 2000 | 2329.29 | 2000 | 4.65858 | 4.65858 | 0 | 0 | 2000 | 1900 | 70 | 0.0592164 | 11550 | 0 | 13550 | 2000 | 11550 | 0 | 2,33×2,00 | 2,33×2,00×0,07 | Cloison 70 0826278243 | G | Portes_coulissantes | Por-323 | 1-Projet | Etage 3 | 6 | Mur-149 | Bois-Pin; Surface-Plastique stratifié; Divers-Glace | Ch 1/pl | Ch 1/pl | B31 | Ch 1/pl | B31 | Ch 1/pl | B31
Por-323 | Etage 3 | 2000 | 1720.16 | 0.240823 | 0.240823 | 6.30112 | 3.44032 | 1720.16 | 2000 | 1720.16 | 2000 | 3.44032 | 3.44032 | 0 | 0 | 2000 | 1900 | 70 | 0.0458156 | 11550 | 0 | 13550 | 2000 | 11550 | 0 | 1,72×2,00 | 1,72×2,00×0,07 | Cloison 70 0826278243 | D | Portes_coulissantes | Por-323 | 1-Projet | Etage 3 | 6 | Mur-149 | Bois-Pin; Surface-Plastique stratifié; Divers-Glace | Ch 1/pl | Ch 1/pl | B35 | Ch 1/pl | B35 | Ch 1/pl | B35
Por-321 | etage 4 | 2000 | 1849.85 | 0.25898 | 0.25898 | 6.71613 | 3.69971 | 1849.85 | 2000 | 1849.85 | 2000 | 3.69971 | 3.69971 | 0 | 0 | 2000 | 1900 | 70 | 0.0486688 | 14600 | 0 | 16600 | 2000 | 14600 | 0 | 1,85×2,00 | 1,85×2,00×0,07 | Cloison 70 0836576958 | G | Portes_coulissantes | Por-321 | 1-Projet | etage 4 | 7 | Mur-148 | Bois-Pin; Surface-Plastique stratifié; Divers-Glace |  | Ch 3/sde | B44 |  |  | Ch 3/sde | B44
Por-324 | etage 4 | 2000 | 2268.98 | 0.317658 | 0.317658 | 8.05734 | 4.53796 | 2268.98 | 2000 | 2268.98 | 2000 | 4.53796 | 4.53796 | 0 | 0 | 2000 | 1900 | 70 | 0.0578896 | 14600 | 0 | 16600 | 2000 | 14600 | 0 | 2,27×2,00 | 2,27×2,00×0,07 | Cloison 70 0826278243 | G | Portes_coulissantes | Por-324 | 1-Projet | etage 4 | 7 | Mur-149 | Bois-Pin; Surface-Plastique stratifié; Divers-Glace | Ch 1/pl | Ch 1/pl | B41 | Ch 1/pl | B41 | Ch 1/pl | B41
Por-321 | etage 4 | 2000 | 1829.52 | 0.250531 | 0.256133 | 6.65107 | 3.65904 | 1789.52 | 2000 | 1789.52 | 2000 | 3.57904 | 3.57904 | 0 | 0 | 2000 | 1900 | 70 | 0.0482215 | 14600 | 0 | 16600 | 2000 | 14600 | 0 | 1,83×2,00 | 1,83×2,00×0,07 | Cloison 70 0826278243 | G | Portes_coulissantes | Por-321 | 1-Projet | etage 4 | 7 | Mur-149 | Bois-Pin; Surface-Plastique stratifié; Divers-Glace | Entree/pl | Entree/pl | B42 |  |  | Entree/pl | B42
Por-321 | etage 4 | 2000 | 2140.59 | 0.299683 | 0.299683 | 7.6465 | 4.28119 | 2140.59 | 2000 | 2140.59 | 2000 | 4.28119 | 4.28119 | 0 | 0 | 2000 | 1900 | 70 | 0.055065 | 14600 | 0 | 16600 | 2000 | 14600 | 0 | 2,14×2,00 | 2,14×2,00×0,07 | Cloison 70 0826278243 | G | Portes_coulissantes | Por-321 | 1-Projet | etage 4 | 7 | Mur-149 | Bois-Pin; Surface-Plastique stratifié; Divers-Glace | Ch 1/pl | Ch 1/pl | B42 | Ch 1/pl | B42
Por-321 | etage 4 | 2000 | 1792.63 | 0.244471 | 0.250968 | 6.53302 | 3.58526 | 1746.22 | 2000 | 1746.22 | 2000 | 3.49244 | 3.49244 | 0 | 0 | 2000 | 1900 | 70 | 0.0474099 | 14600 | 0 | 16600 | 2000 | 14600 | 0 | 1,79×2,00 | 1,79×2,00×0,07 | Cloison 70 0826278243 | D | Portes_coulissantes | Por-321 | 1-Projet | etage 4 | 7 | Mur-149 | Bois-Pin; Surface-Plastique stratifié; Divers-Glace | Entree/pl | Entree/pl | B43 | Entree/pl | B43
Por-329 | etage 4 | 2000 | 1553.12 | 0.217437 | 0.217437 | 5.76658 | 3.10624 | 1553.12 | 2000 | 1553.12 | 2000 | 3.10624 | 3.10624 | 0 | 0 | 2000 | 1900 | 70 | 0.0421406 | 14600 | 0 | 16600 | 2000 | 14600 | 0 | 1,55×2,00 | 1,55×2,00×0,07 | Cloison 70 0826278243 | G | Portes_coulissantes | Por-329 | 1-Projet | etage 4 | 7 | Mur-149 | Bois-Pin; Surface-Plastique stratifié; Divers-Glace | Ch 1/pl | Ch 1/pl | B43 | Ch 1/pl | B43 | Ch 1/pl | B43
Por-321 | Etage 5 | 2000 | 1830.08 | 0.256211 | 0.256211 | 6.65284 | 3.66015 | 1830.08 | 2000 | 1830.08 | 2000 | 3.66015 | 3.66015 | 0 | 0 | 2000 | 1900 | 70 | 0.0482337 | 17650 | 0 | 19650 | 2000 | 17650 | 0 | 1,83×2,00 | 1,83×2,00×0,07 | Cloison 70 0826278243 | D | Portes_coulissantes | Por-321 | 1-Projet | Etage 5 | 8 | Mur-149 | Bois-Pin; Surface-Plastique stratifié; Divers-Glace | Ch 1/pl | Ch 1/pl | B52 | Ch 1/pl | B52 | Ch 1/pl | B52
Por-289 | Etage 5 | 2100 | 900 | 0.189 | 0.189 | 3.81744 | 1.89 | 900 | 2100 | 900 | 2100 | 1.89 | 1.89 | 0 | 0 | 2100 | 2000 | 100 | 0.0306871 | 17650 | 0 | 19750 | 2100 | 17650 | 0 | 0,90×2,10 | 0,90×2,10×0,10 | Cloison 100 0826278243 | D | Couliss ds mur 70 | Por-289 | 1-Projet | Etage 5 | 8 | Mur-149 | Dallage-Asphalte Lisse; Vitrage-Verre; Noyer |  | Ch 1 | B51 | sde | B51 | Ch 1 | B51
Por-321 | Etage 5 | 2000 | 1830.08 | 0.112775 | 0.256211 | 6.65284 | 3.66015 | 1790.08 | 900 | 1790.08 | 900 | 1.61107 | 1.61107 | 1800 | 1700 | 3800 | 3700 | 70 | 0.0482337 | 19450 | 1800 | 21450 | 3800 | 19450 | 1800 | 1,83×2,00 | 1,83×2,00×0,07 | Cloison 70 0826278243 | G | Portes_coulissantes | Por-321 | 1-Projet | Etage 5 | 8 | Mur-149 | Bois-Pin; Surface-Plastique stratifié; Divers-Glace | Dgt/pl; Terrasse/eng. | Dgt/pl | B52 |  |  | Dgt/pl | B52
Por-321 | Etage 5 | 2000 | 1154.97 | 0.161696 | 0.161696 | 4.49252 | 2.30995 | 1154.97 | 2000 | 1154.97 | 2000 | 2.30995 | 2.30995 | 0 | 0 | 2000 | 1900 | 70 | 0.0333814 | 17650 | 0 | 19650 | 2000 | 17650 | 0 | 1,15×2,00 | 1,15×2,00×0,07 | Cloison 70 0826278243 | D | Portes_coulissantes | Por-321 | 1-Projet | Etage 5 | 8 | Mur-149 | Bois-Pin; Surface-Plastique stratifié; Divers-Glace | Ch 4/Pl | Ch 4/Pl | B52 |  |  | Ch 4/Pl | B52
Por-321 | Etage 5 | 2000 | 2579.42 | 0.361118 | 0.361118 | 9.05073 | 5.15883 | 2579.42 | 2000 | 2579.42 | 2000 | 5.15883 | 5.15883 | 0 | 0 | 2000 | 1900 | 70 | 0.0647192 | 17650 | 0 | 19650 | 2000 | 17650 | 0 | 2,58×2,00 | 2,58×2,00×0,07 | Cloison 70 0826278243 | G | Portes_coulissantes | Por-321 | 1-Projet | Etage 5 | 8 | Mur-149 | Bois-Pin; Surface-Plastique stratifié; Divers-Glace | Ch 2/pl | Ch 2/pl | B52 | Ch 2/pl | B52 | Ch 2/pl | B52
Por-321 | Etage 5 | 2000 | 1207.1 | 0.163395 | 0.168995 | 4.65933 | 2.41421 | 1167.1 | 2000 | 1167.1 | 2000 | 2.33421 | 2.33421 | 300 | 200 | 2300 | 2200 | 70 | 0.0345283 | 17950 | 300 | 19950 | 2300 | 17950 | 300 | 1,21×2,00 | 1,21×2,00×0,07 | Cloison 70 0826278243 | G | Portes_coulissantes | Por-321 | 1-Projet | Etage 5 | 8 | Mur-149 | Bois-Pin; Surface-Plastique stratifié; Divers-Glace | Entree/pl; Wc | Sejour cuisine | B51 | Entree/pl | B51 | Sejour cuisine | B51
Por-321 | Etage 5 | 2000 | 1136.96 | 0.159175 | 0.159175 | 4.43488 | 2.27393 | 1136.96 | 2000 | 1136.96 | 2000 | 2.27393 | 2.27393 | 0 | 0 | 2000 | 1900 | 70 | 0.0329852 | 17650 | 0 | 19650 | 2000 | 17650 | 0 | 1,14×2,00 | 1,14×2,00×0,07 | Cloison 70 0826278243 | G | Portes_coulissantes | Por-321 | 1-Projet | Etage 5 | 8 | Mur-149 | Bois-Pin; Surface-Plastique stratifié; Divers-Glace | Ch 3/pl | Ch 3/pl | B52 |  |  | Ch 3/pl | B52

# IfcDoor: P_garage 1 (27)
In: sousol
Type - ParameterTakesPrecedence: no; Sizeable: no
OverallHeight: 2050 mm; Classification: Porte (Classification ARCHICAD)
ArchiCADProperties - Nom élément de bibliothèque d'ouverture: P_garage 1; Index hachure latérale ouverture: Brique 1; ID de l'élément: Por-296; Lien et ID d'élément: Por-296; Calque: 3D; Nom Élément de Bibliothèque: P_garage 1; Matériau de construction / Composite / Profil / Hachure: Brique 1; Type Hachure: Brique 1; Verrouillé: no; Nom d'étage d'implantation: sousol; Numéro d'étage d'implantation: 2; Type d'élément: Porte; Surfaces (Toutes): Surface-Plastique stratifié; Nom de Variante: Modèle principal; Nom de Jeu de Variantes: Modèle principal; Position: Non défini; Fonction structurelle: Non défini; Affichage sur filtre de rénovation: Tous les filtres appropriés; État de rénovation: Existant; État de Variante: Modèle principal; Jeu de Variantes: Modèle principal
AC_Pset_P_garage_1 - Contours Mur (0-Sans,1-Tout,2-Côté,3-Longueur): 2; Points chauds 0-Sans,1-2D,2-3D,3-Tous: 3; Points chauds automatiques en 3D: yes; Trou a matière bord de mur: yes; Hole Matière's Split is Curved: no; Ouverture nominale: no; Dimensions feuillure: Personnalisé; Dimensions standard: 7-6 x 7-0; Niveau de paramétrage: Elevé; Entièrement éditable: yes; Niveau de détail 2D: Selon échelle; Niveau de détail 3D: Détaillé; Aligner à Porte/Fenêtre sur côté: Sans; Direction d'ouverture: Intérieur; Epaisseur cadre=Epaisseur mur: no; Style panneau de porte: Style 2; Nombre de montants: 4; Nombre de traverses: 3; Poignée d'ouverture: Sans; Encadr./Chambranle: Sans; Seuil: Sans; Volets: Sans; Style Volets: Décoratif; Positionnement volets: Côté droit; Finition en tableaux: Sans; Côté cavité: Les deux; Nbre de couches retournées: 2; Joint: yes; Hachure Joint: Sans Trame; Angle ouverture 2D: 60 deg; Ligne d'ouverture en 2D: yes; Type ligne d'ouverture en 2D: 4; Ligne de contour de mur: Sans; Type ligne contour intérieur de mur: 4; Type ligne contour extérieur de mur: 4; Angle ouverture 3D: 0 deg; Ligne d'ouverture en 3D: no; Style lignes d'ouverture: Style 1; Type de ligne d'ouverture: Ligne continue; Résolution de courbe: 12; Ombre: yes; Matière cadre: Surface-Plastique stratifié; Matière panneaux: Surface-Plastique stratifié; Matière battant 2: Surface-Plastique stratifié; Matière facettes: Surface-Plastique stratifié; Matière vitrage: Vitrage-Verre; Matière encadrement intérieur: Surface-Plastique stratifié; Matière encadrement extérieur: Surface-Plastique stratifié; Matière cadre volets: Bois-Pin brillant; Matière panneaux des volets: Bois-Pin brillant; Matière seuil: Bois-Pin brillant; Matière poignée: Métal-Acier; Matière accessoires poignée: Métal-Inox; Opération IFC: 0; Coût: 0; Surface totale vitrage: 0; Périmètre total vitrage: 0; Type de groupe: Autres; Poids de l'objet: 0; Unité poids de l'objet: kg
AC_Equantity_P_garage_1 - Dimension Z: 1000 mm; Hauteur appui à étage actuel: 0 mm; Niveau inférieur: 1000 mm; Niveau supérieur: 0 mm; Epaisseur battant: 1800 mm; Hauteur feuillure: 2100 mm; Epaisseur cadre: 100 mm; Largeur cadre: 50 mm; Epaisseur panneaux: 40 mm; Hauteur poignée: 250 mm; Epaisseur encadrement comme cadre: 25 mm; Décalage encadrement: 12 mm; Epaisseur encadrement intérieur: 19 mm; Larg. encadr. int. gauche: 75 mm; Larg. encadr. int. droit: 75 mm; Larg. encadr. int. sup.: 75 mm; Epaisseur encadrement extérieur: 19 mm; Larg. encadr. ext. gauche: 75 mm; Larg. encadr. ext. droit: 75 mm; Larg. encadr. ext. sup.: 75 mm; Epaisseur seuil: 12 mm; Dépassement du seuil: 25 mm; Largeur Volets: 0 mm; Dépassement ouverture gauche: 0 mm; Dépassement ouverture droite: 0 mm; Dépassement ouverture supérieur: 0 mm; Dépassement ouverture inférieur: 0 mm; Hauteur ouverture en 3D: 0 mm; Dépass.ouverture gauche: 0 mm; Dépass.ouverture à droite: 0 mm; Dépass.ouverture supérieur: 0 mm; Dépass.ouverture inférieur: 0 mm; Agrandissement à gauche: 0 mm; Agrandissement à droite: 0 mm; Agrandissement supérieur: 0 mm; Agrandissement inférieur: 0 mm; Agrandissement à gauche 2: 0 mm; Agrandissement à droite 2: 0 mm; Epaisseur réelle du cadre: 100 mm
AC_Pset_RenovationAndPhasing - Renovation Status: Existing
ArchiCADQuantities - Hauteur ouverture P/F côté ébrasure: 2050 mm; Hauteur ouverture P/F côté opposé ébrasure: 2050 mm; Hauteur nominale de l'ouverture P/F côté ébrasure: 2050 mm; Hauteur nominale de l'ouverture P/F côté opposée ébrasure: 2050 mm; Valeur Appui ou Linteau: 0 mm; Hauteur nominale seuil: 0 mm; Hauteur seuil P/F côté ébrasure: 0 mm; Hauteur seuil P/F côté opposé ébrasure: 0 mm; Hauteur nominale linteau P/F: 2050 mm; Hauteur linteau P/F côté ébrasure: 1950 mm; Hauteur linteau P/F côté opposé ébrasure: 1950 mm; Épaisseur cadre: 100 mm; Hauteur: 2050 mm; Altitude à Zéro du Projet: 4.18415e-12 mm; Altitude de Référence Niveau 1: 4.18415e-12 mm; Altitude de Référence Niveau 2: 4.18415e-12 mm; Altitude à niveau de la mer: 4.18415e-12 mm; Altitude à étage lié/étage d'implantation: 4.18415e-12 mm; Décalage étage d'implantation: 4.18415e-12 mm; Altitude supérieure à premier niveau de référence: 2050 mm; Altitude supérieure à étage d'implantation: 2050 mm; Altitude supérieure à Zéro du projet: 2050 mm; Altitude supérieure à niveau de la mer: 2050 mm; Altitude supérieure à deuxième niveau de référence: 2050 mm
Name | OverallWidth (mm) = Largeur ouverture P/F côté ébrasure (mm) = Largeur ouverture P/F côté opposé ébrasure (mm) = Largeur nominale de l'ouverture P/F côté ébrasure (mm) = Largeur nominale de l'ouverture P/F côté opposée ébrasure (mm) = Largeur (mm) | Taille L x H nominale | Taille L x H x E nominale | Structure de Mur | Orientation | ID de Parent | Volume ouverture d'ouverture P/F (m3) = Volume nominal ouverture P/F (m3) | Superficie ouverture P/F (m2) = Superficie en plan (m2) = Superficie inférieure (nette) (m2) | Superficie nominale ouverture P/F (m2) = Superficie ouverture P/F côté ébrasure (m2) = Superficie ouverture P/F côté opposé ébrasure (m2) = Superficie nominale de l'ouverture P/F côté ébrasure (m2) = Superficie nominale de l'ouverture P/F côté opposé ébrasure (m2) | Épaisseur de Mur (mm) | Volume (net) (m3) | Altitude inférieure à premier niveau de référence (mm) = Altitude inférieure à étage d'implantation (mm) = Altitude inférieure à Zéro du projet (mm) = Altitude inférieure à niveau de la mer (mm) = Altitude inférieure à deuxième niveau de référence (mm)
3 x Por-296 | 2400 | 2,40×2,05 | 2,40×2,05×0,18 | Beton 18 0170347028 | D | Mur-132 | 0.8856 | 20.0756 | 4.92 | 180 | 0.204267 | 4.17313e-12
9 x Por-296 | 2400 | 2,40×2,05 | 2,40×2,05×0,18 | Beton 18 0170347028 | G | Mur-133 | 0.8856 | 20.0756 | 4.92 | 180 | 0.204267 | 4.17803e-12
Por-296 | 3300 | 3,30×2,05 | 3,30×2,05×0,18 | Beton 18 0170347028 | D | Mur-133 | 1.2177 | 27.3728 | 6.765 | 180 | 0.275967 | 4.17803e-12
Por-296 | 2400 | 2,40×2,05 | 2,40×2,05×0,10 | Cloison 100 gaine | D | Mur-133 | 0.492 | 20.0756 | 4.92 | 100 | 0.204267 | 4.17803e-12
2 x Por-296 | 2400 | 2,40×2,05 | 2,40×2,05×0,18 | Beton 18 0170347028 | G | Mur-133 | 0.8856 | 20.0756 | 4.92 | 180 | 0.204267 | 4.17313e-12
4 x Por-296 | 2400 | 2,40×2,05 | 2,40×2,05×0,18 | Beton 18 0170347028 | D | Mur-133 | 0.8856 | 20.0756 | 4.92 | 180 | 0.204267 | 4.17313e-12
6 x Por-296 | 2400 | 2,40×2,05 | 2,40×2,05×0,18 | Beton 18 0170347028 | G | Mur-132 | 0.8856 | 20.0756 | 4.92 | 180 | 0.204267 | 4.17803e-12
Por-296 | 3300 | 3,30×2,05 | 3,30×2,05×0,18 | Beton 18 0170347028 | D | Mur-133 | 1.2177 | 27.3728 | 6.765 | 180 | 0.275967 | 4.17313e-12

# IfcDoor: P_garage 2, Por-286
In: rdc
Type - ParameterTakesPrecedence: no; Sizeable: no
OverallHeight: 1795.97 mm; OverallWidth: 2536.58 mm; Classification: Porte (Classification ARCHICAD)
ArchiCADProperties - Taille L x H nominale: 2,54×1,80; Taille L x H x E nominale: 2,54×1,80×0,34; Structure de Mur: Empty Fill 272047960; Orientation: G; Nom élément de bibliothèque d'ouverture: P_garage 2; Index hachure latérale ouverture: Brique 1; ID de l'élément: Por-286; Lien et ID d'élément: Por-286; Calque: Interieurs logements; Nom Élément de Bibliothèque: P_garage 2; Matériau de construction / Composite / Profil / Hachure: Brique 1; Type Hachure: Brique 1; Verrouillé: no; Nom d'étage d'implantation: rdc; Numéro d'étage d'implantation: 3; Type d'élément: Porte; ID de Parent: Mur-143; Surfaces (Toutes): Peinture-01; Nom de Variante: Modèle principal; Nom de Jeu de Variantes: Modèle principal; Position: Non défini; Fonction structurelle: Non défini; Affichage sur filtre de rénovation: Tous les filtres appropriés; État de rénovation: Existant; État de Variante: Modèle principal; Jeu de Variantes: Modèle principal
AC_Pset_P_garage_2 - Contours Mur (0-Sans,1-Tout,2-Côté,3-Longueur): 2; Points chauds 0-Sans,1-2D,2-3D,3-Tous: 3; Points chauds automatiques en 3D: yes; Trou a matière bord de mur: yes; Hole Matière's Split is Curved: no; Ouverture nominale: no; Dimensions feuillure: Personnalisé; Dimensions standard: 6-6 x 6-6; Niveau de paramétrage: Elevé; Entièrement éditable: yes; Niveau de détail 2D: Selon échelle; Niveau de détail 3D: Détaillé; Aligner à Porte/Fenêtre sur côté: Sans; Direction d'ouverture: Intérieur; Epaisseur cadre=Epaisseur mur: no; Style panneau de porte: Style 1; Nombre de montants: 4; Nombre de traverses: 3; Poignée d'ouverture: Sans; Encadr./Chambranle: Sans; Seuil: Sans; Volets: Sans; Style Volets: Décoratif; Positionnement volets: Côté droit; Finition en tableaux: Sans; Côté cavité: Les deux; Nbre de couches retournées: 2; Joint: yes; Hachure Joint: Sans Trame; Angle ouverture 2D: 60 deg; Ligne de contour de mur: Sans; Type ligne contour intérieur de mur: 4; Type ligne contour extérieur de mur: 4; Angle ouverture 3D: 0 deg; Ligne d'ouverture en 3D: no; Style lignes d'ouverture: Style 1; Type de ligne d'ouverture: Ligne continue; Résolution de courbe: 12; Ombre: yes; Matière cadre: Peinture-01; Matière panneaux: Peinture-01; Matière battant 2: Peinture-01; Matière facettes: Surface-Plastique stratifié; Matière vitrage: Vitrage-Verre; Matière encadrement intérieur: Surface-Plastique stratifié; Matière encadrement extérieur: Surface-Plastique stratifié; Matière cadre volets: Surface-Plastique stratifié; Matière panneaux des volets: Surface-Plastique stratifié; Matière seuil: Surface-Plastique stratifié; Matière poignée: Métal-Acier; Matière accessoires poignée: Métal-Inox; Opération IFC: 0; Coût: 0; Surface totale vitrage: 0; Périmètre total vitrage: 0; Type de groupe: Autres; Poids de l'objet: 0; Unité poids de l'objet: kg
AC_Pset_RenovationAndPhasing - Renovation Status: Existing
ArchiCADQuantities - Volume ouverture d'ouverture P/F: 1.54891 m3; Volume nominal ouverture P/F: 1.54891 m3; Superficie ouverture P/F: 19.4256 m2; Superficie nominale ouverture P/F: 4.55562 m2; Largeur ouverture P/F côté ébrasure: 2536.58 mm; Hauteur ouverture P/F côté ébrasure: 1795.97 mm; Largeur ouverture P/F côté opposé ébrasure: 2536.58 mm; Hauteur ouverture P/F côté opposé ébrasure: 1795.97 mm; Superficie ouverture P/F côté ébrasure: 4.55562 m2; Superficie ouverture P/F côté opposé ébrasure: 4.55562 m2; Largeur nominale de l'ouverture P/F côté ébrasure: 2536.58 mm; Hauteur nominale de l'ouverture P/F côté ébrasure: 1795.97 mm; Largeur nominale de l'ouverture P/F côté opposée ébrasure: 2536.58 mm; Hauteur nominale de l'ouverture P/F côté opposée ébrasure: 1795.97 mm; Superficie nominale de l'ouverture P/F côté ébrasure: 4.55562 m2; Superficie nominale de l'ouverture P/F côté opposé ébrasure: 4.55562 m2; Valeur Appui ou Linteau: 0 mm; Hauteur nominale seuil: 0 mm; Hauteur seuil P/F côté ébrasure: 0 mm; Hauteur seuil P/F côté opposé ébrasure: 0 mm; Hauteur nominale linteau P/F: 1795.97 mm; Hauteur linteau P/F côté ébrasure: 1695.97 mm; Hauteur linteau P/F côté opposé ébrasure: 1695.97 mm; Épaisseur de Mur: 340 mm; Épaisseur cadre: 100 mm; Hauteur: 1795.97 mm; Volume (net): 0.195113 m3; Largeur: 2536.58 mm; Altitude à Zéro du Projet: 2500 mm; Altitude de Référence Niveau 1: 2500 mm; Altitude de Référence Niveau 2: 2500 mm; Altitude à niveau de la mer: 2500 mm; Altitude à étage lié/étage d'implantation: -500 mm; Décalage étage d'implantation: -500 mm; Superficie en plan: 19.4256 m2; Altitude supérieure à premier niveau de référence: 4295.97 mm; Altitude supérieure à étage d'implantation: 1295.97 mm; Altitude supérieure à Zéro du projet: 4295.97 mm; Altitude supérieure à niveau de la mer: 4295.97 mm; Altitude supérieure à deuxième niveau de référence: 4295.97 mm; Altitude inférieure à premier niveau de référence: 2500 mm; Altitude inférieure à étage d'implantation: -500 mm; Altitude inférieure à Zéro du projet: 2500 mm; Altitude inférieure à niveau de la mer: 2500 mm; Altitude inférieure à deuxième niveau de référence: 2500 mm; Superficie inférieure (nette): 19.4256 m2
AC_Equantity_P_garage_2 - Dimension Z: 1000 mm; Hauteur appui à étage actuel: 2500 mm; Niveau inférieur: 1000 mm; Niveau supérieur: 0 mm; Epaisseur battant: 1800 mm; Hauteur feuillure: 2100 mm; Epaisseur cadre: 100 mm; Largeur cadre: 50 mm; Epaisseur panneaux: 40 mm; Hauteur poignée: 250 mm; Epaisseur encadrement comme cadre: 25 mm; Décalage encadrement: 12 mm; Epaisseur encadrement intérieur: 19 mm; Larg. encadr. int. gauche: 75 mm; Larg. encadr. int. droit: 75 mm; Larg. encadr. int. sup.: 75 mm; Epaisseur encadrement extérieur: 19 mm; Larg. encadr. ext. gauche: 75 mm; Larg. encadr. ext. droit: 75 mm; Larg. encadr. ext. sup.: 75 mm; Epaisseur seuil: 12 mm; Dépassement du seuil: 25 mm; Largeur Volets: 0 mm; Dépassement ouverture gauche: 0 mm; Dépassement ouverture droite: 0 mm; Dépassement ouverture supérieur: 0 mm; Dépassement ouverture inférieur: 0 mm; Hauteur ouverture en 3D: 0 mm; Dépass.ouverture gauche: 0 mm; Dépass.ouverture à droite: 0 mm; Dépass.ouverture supérieur: 0 mm; Dépass.ouverture inférieur: 0 mm; Agrandissement à gauche: 0 mm; Agrandissement à droite: 0 mm; Agrandissement supérieur: 0 mm; Agrandissement inférieur: 0 mm; Agrandissement à gauche 2: 0 mm; Agrandissement à droite 2: 0 mm; Epaisseur réelle du cadre: 100 mm

# IfcDoor: Porte_1v (482)
Type - ParameterTakesPrecedence: no; Sizeable: no
Classification: Porte (Classification ARCHICAD)
ArchiCADProperties - Nom élément de bibliothèque d'ouverture: Porte_1v; Index hachure latérale ouverture: Brique 1; Nom Élément de Bibliothèque: Porte_1v; Matériau de construction / Composite / Profil / Hachure: Brique 1; Type Hachure: Brique 1; Verrouillé: no; Type d'élément: Porte; Nom de Variante: Modèle principal; Nom de Jeu de Variantes: Modèle principal; Position: Non défini; Fonction structurelle: Non défini; Affichage sur filtre de rénovation: Tous les filtres appropriés; État de rénovation: Existant; État de Variante: Modèle principal; Jeu de Variantes: Modèle principal
AC_Pset_RenovationAndPhasing - Renovation Status: Existing
ArchiCADQuantities - Épaisseur cadre: 0 mm
AC_Equantity_Porte_1v - Z Dimension: 1000 mm; Niveau inférieur: 1000 mm; Niveau supérieur: 0 mm; Epais huiss. (0 = épais mur): 0 mm; Larg. faux cadre: 60 mm; Ep feuillure: 15 mm; Larg feuill trav vertic: 40 mm; Vide sous porte si chape: 0 mm; Larg. 2éme v.(si 0: moitié): 400 mm; Epaiss montants porte: 100 mm; Larg. montants vert. porte: 300 mm; Section bois des carreaux: 30 mm; Larg. montants haut. porte: 100 mm; Décallage texte: -20 mm; Décal ep stylo cache: 10 mm; décal fond pour visuel: 0 mm; AC Left Opening Oversize: 0 mm; AC Right Opening Oversize: 0 mm; AC Upper Opening Oversize: 0 mm; AC Lower Opening Oversize: 0 mm
AC_Pset_Porte_1v - Point ch.0-Non,1-2D,2-3D,3-Tous: 3; Type de porte (P_vitr): Porte pleine; Cotation au ....: Vide en battues; Hole Has Wall's Side Material: no; Hole Material's Split is Curved: no; Afficher points chauds 2D en 3D: yes; Type de porte (TypPorte): simple; Type d'huisserie: Huisserie bois; Aspect 2éme vantail: Ouvrant; Vision huisseries: dés le 100ème; Affichage en plan: Porte_ouverte; Rempliss métal: no; Hachure si non détaillée: Isolation; Type lignes seuil arc: 4; Choix d'affichage seuil: Aucun; Angle d'ouverture en 3D: 0 deg; Inversion porte: no; Vitrage (OUI = 1 NON =0): yes; Nbre de carreaux sur X: 2; Nbre de carreaux sur Z: 4; Nb carr. sur X (2éme vant): 1; Matériau vitrage: Vitrage-Verre; Hachure seuil/cache: Hachure solide; Opération IFC: 0; Police de caractère: HELVETICA; Hauteur police en mm: 1.2; Abréviation porte pleine: PP; Abréviation porte vitrée: PV
Name | In | OverallHeight (mm) = Hauteur nominale de l'ouverture P/F côté ébrasure (mm) = Hauteur nominale de l'ouverture P/F côté opposée ébrasure (mm) = Hauteur (mm) | OverallWidth (mm) | Taille L x H nominale | Taille L x H x E nominale | Structure de Mur | Orientation | ID de l'élément = Lien et ID d'élément | Calque | Nom d'étage d'implantation | Numéro d'étage d'implantation | ID de Parent | Surfaces (Toutes) = Matériau du cadre = Matériau porte = Matériau si métal = Matériau Poignée | Volume ouverture d'ouverture P/F (m3) | Volume nominal ouverture P/F (m3) | Superficie ouverture P/F (m2) = Superficie en plan (m2) = Superficie inférieure (nette) (m2) | Superficie nominale ouverture P/F (m2) = Superficie nominale de l'ouverture P/F côté ébrasure (m2) = Superficie nominale de l'ouverture P/F côté opposé ébrasure (m2) | Largeur ouverture P/F côté ébrasure (mm) | Hauteur ouverture P/F côté ébrasure (mm) = Hauteur ouverture P/F côté opposé ébrasure (mm) | Largeur ouverture P/F côté opposé ébrasure (mm) | Superficie ouverture P/F côté ébrasure (m2) | Superficie ouverture P/F côté opposé ébrasure (m2) | Largeur nominale de l'ouverture P/F côté ébrasure (mm) = Largeur nominale de l'ouverture P/F côté opposée ébrasure (mm) = Largeur (mm) | Valeur Appui ou Linteau (mm) = Hauteur nominale seuil (mm) | Hauteur seuil P/F côté ébrasure (mm) = Hauteur seuil P/F côté opposé ébrasure (mm) | Hauteur nominale linteau P/F (mm) | Hauteur linteau P/F côté ébrasure (mm) = Hauteur linteau P/F côté opposé ébrasure (mm) | Épaisseur de Mur (mm) | Volume (net) (m3) | Altitude à Zéro du Projet (mm) = Altitude de Référence Niveau 1 (mm) = Altitude de Référence Niveau 2 (mm) = Altitude à niveau de la mer (mm) | Altitude à étage lié/étage d'implantation (mm) = Décalage étage d'implantation (mm) | Altitude supérieure à premier niveau de référence (mm) = Altitude supérieure à Zéro du projet (mm) = Altitude supérieure à niveau de la mer (mm) = Altitude supérieure à deuxième niveau de référence (mm) | Altitude supérieure à étage d'implantation (mm) | Altitude inférieure à premier niveau de référence (mm) = Altitude inférieure à Zéro du projet (mm) = Altitude inférieure à niveau de la mer (mm) = Altitude inférieure à deuxième niveau de référence (mm) | Altitude inférieure à étage d'implantation (mm) | Hauteur appui à étage actuel (mm) | Largeur huisserie (mm) | Epais. faux cadre (mm) | Larg feuill mont horiz (mm) | Epaisseur porte (mm) | Contours Mur (0-Sans,1-Tout,2-Côté,3-Longueur) | Dimensions normalisées | Angle d'ouverture en 2D (deg) | Poignée en 3D | Liste des interface user | Affichage texte | Nom de zone liée | Numéro de zone liée | De Zone | Du numéro de Zone | Zones conflictuelles | À Zone | À numéro de Zone
Por-277 | sousol | 500 | 500 | 0,50×0,50 | 0,50×0,50×0,18 | Beton 18 0170347028 | G | Por-277 | 3D | sousol | 2 | Mur-132 | HAG Acrylic White | 0.047736 | 0.045 | 1.2067 | 0.25 | 520 | 510 | 520 | 0.2652 | 0.2652 | 500 | 0 | 0 | 500 | 400 | 180 | 0.010418 | 4.18415e-12 | 4.18415e-12 | 1100 | 1100 | 4.17313e-12 | 4.17313e-12 | 4.18415e-12 | 10 | 10 | 10 | 20 | 2 | yes | 0 | yes | Cadre et porte | Sans
Por-277 | sousol | 500 | 323.342 | 0,32×0,50 | 0,32×0,50×0,18 | Beton 18 0170347028 | G | Por-277 | 3D | sousol | 2 | Mur-132 | HAG Acrylic White | 0.0315188 | 0.0291008 | 0.952313 | 0.161671 | 343.342 | 510 | 343.342 | 0.175105 | 0.175105 | 323.342 | 0 | 0 | 500 | 400 | 180 | 0.00804195 | 4.18415e-12 | 4.18415e-12 | 1100 | 1100 | 4.17313e-12 | 4.17313e-12 | 4.18415e-12 | 10 | 10 | 10 | 20 | 2 | yes | 0 | yes | Cadre et porte | Sans
Por-277 | sousol | 500 | 500 | 0,50×0,50 | 0,50×0,50×0,18 | Beton 18 0170347028 | G | Por-277 | 3D | sousol | 2 | Mur-132 | HAG Acrylic White | 0.047736 | 0.045 | 1.2067 | 0.25 | 520 | 510 | 520 | 0.2652 | 0.2652 | 500 | 2000 | 1900 | 2500 | 2400 | 180 | 0.010418 | 2000 | 2000 | 3100 | 3100 | 2000 | 2000 | 2000 | 10 | 10 | 10 | 20 | 2 | yes | 0 | yes | Cadre et porte | Sans
Por-275 | sousol | 1400 | 2773.34 | 2,77×1,40 | 2,77×1,40×0,18 | Beton 18 0170347028 | G | Por-275 | 3D | sousol | 2 | Mur-132 | HAG Acrylic White | 0.708951 | 0.698883 | 10.2283 | 3.88268 | 2793.35 | 1410 | 2793.35 | 3.93862 | 3.93862 | 2773.35 | 0 | 0 | 1400 | 1300 | 180 | 0.0971247 | 4.18415e-12 | 4.18415e-12 | 1410 | 1410 | 4.17283e-12 | 4.17283e-12 | 0 | 10 | 10 | 10 | 20 | 2 | yes | 0 | yes | Cadre et porte | Sans
Por-300 | sousol | 2040 | 930 | 0,93×2,04 | 0,93×2,04×0,18 | Beton 18 0170347028 | D | Por-300 | 3D | sousol | 2 | Mur-133 | HAG Acrylic White | 0.378144 | 0.341496 | 6.48965 | 1.8972 | 1010 | 2080 | 1010 | 2.1008 | 2.1008 | 930 | 0 | 0 | 2040 | 1940 | 180 | 0.125102 | 4.18415e-12 | 4.18415e-12 | 2080 | 2080 | 4.17313e-12 | 4.17313e-12 | 0 | 40 | 20 | 15 | 40 | 2 | yes | 7.89569 | yes | Réglages rapides | Sur ouvrant
Por-295 | sousol | 2040 | 1030 | 1,03×2,04 | 1,03×2,04×0,18 | Beton 18 0170347028 | G | Por-295 | 3D | sousol | 2 | Mur-132 | HAG Acrylic White | 0.415584 | 0.378216 | 6.95265 | 2.1012 | 1110 | 2080 | 1110 | 2.3088 | 2.3088 | 1030 | 0 | 0 | 2040 | 1940 | 180 | 0.134229 | 4.18415e-12 | 4.18415e-12 | 2080 | 2080 | 4.17313e-12 | 4.17313e-12 | 0 | 40 | 20 | 15 | 40 | 2 | yes | 26.641 | yes | Réglages rapides | Sur ouvrant | Pl | 818 | Pl | 818
Por-298 | sousol | 2040 | 930 | 0,93×2,04 | 0,93×2,04×0,18 | Beton 18 0170347028 | D | Por-298 | 3D | sousol | 2 | Mur-132 | HAG Acrylic White | 0.378144 | 0.341496 | 6.48965 | 1.8972 | 1010 | 2080 | 1010 | 2.1008 | 2.1008 | 930 | 0 | 0 | 2040 | 1940 | 180 | 0.125102 | 4.18415e-12 | 4.18415e-12 | 2080 | 2080 | 4.17313e-12 | 4.17313e-12 | 0 | 40 | 20 | 15 | 40 | 1 | yes | 90 | yes | Réglages rapides | Sur ouvrant
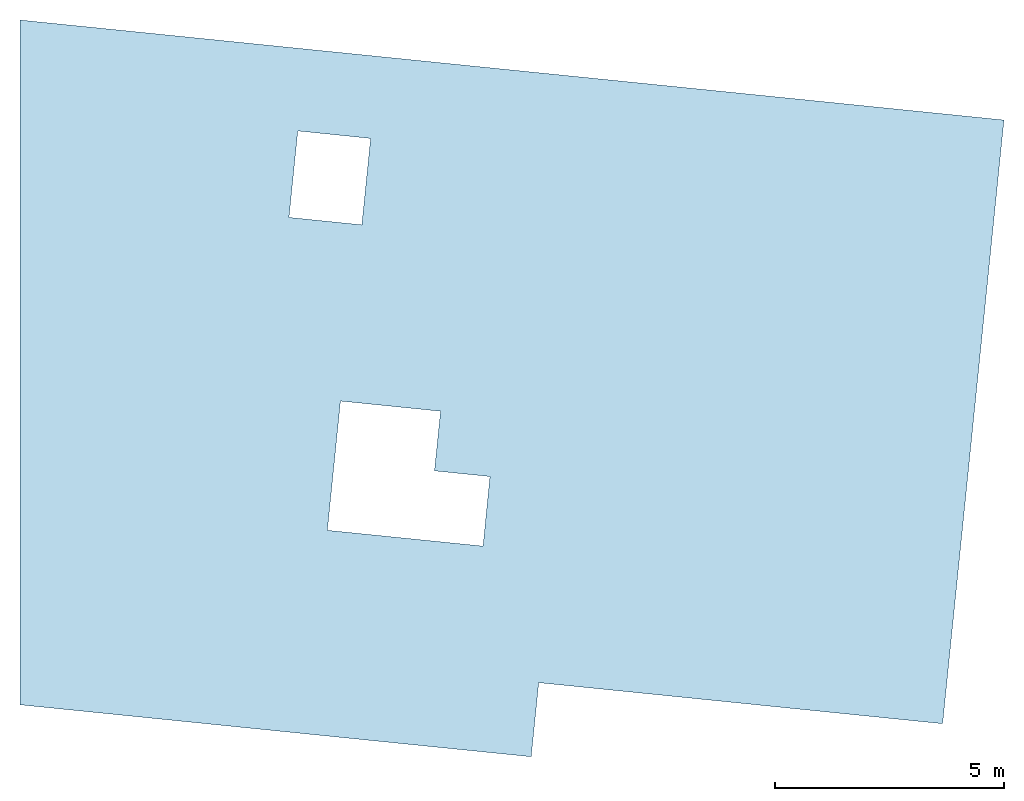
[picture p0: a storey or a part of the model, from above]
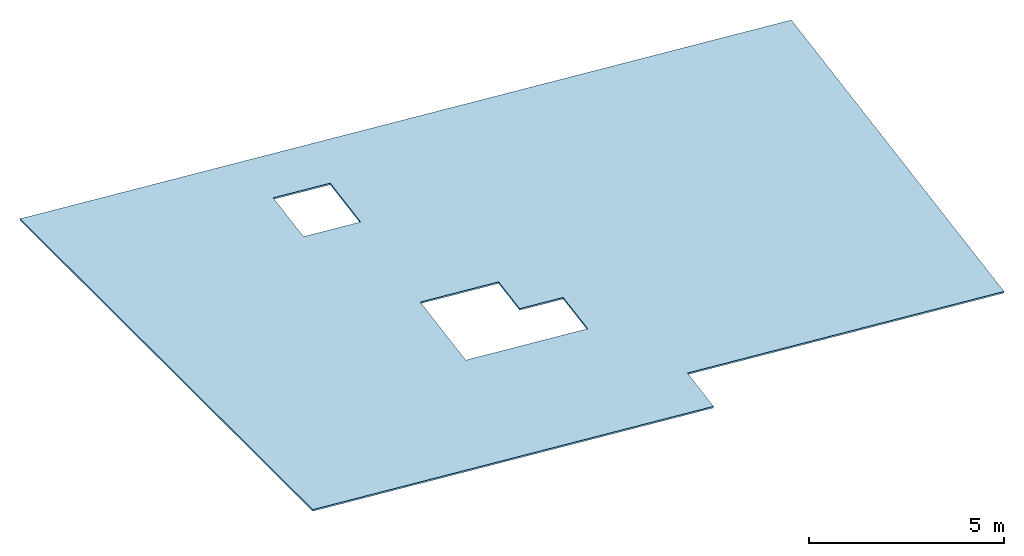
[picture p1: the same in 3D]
Properties of the parts of a building model (IFC2X3), part 13 of 44

# IfcDoor: Porte_1v (482)
Name | In | OverallHeight (mm) = Hauteur nominale de l'ouverture P/F côté ébrasure (mm) = Hauteur nominale de l'ouverture P/F côté opposée ébrasure (mm) = Hauteur (mm) | OverallWidth (mm) | Taille L x H nominale | Taille L x H x E nominale | Structure de Mur | Orientation | ID de l'élément = Lien et ID d'élément | Calque | Nom d'étage d'implantation | Numéro d'étage d'implantation | ID de Parent | Surfaces (Toutes) = Matériau du cadre = Matériau porte = Matériau si métal = Matériau Poignée | Volume ouverture d'ouverture P/F (m3) | Volume nominal ouverture P/F (m3) | Superficie ouverture P/F (m2) = Superficie en plan (m2) = Superficie inférieure (nette) (m2) | Superficie nominale ouverture P/F (m2) = Superficie nominale de l'ouverture P/F côté ébrasure (m2) = Superficie nominale de l'ouverture P/F côté opposé ébrasure (m2) | Largeur ouverture P/F côté ébrasure (mm) | Hauteur ouverture P/F côté ébrasure (mm) = Hauteur ouverture P/F côté opposé ébrasure (mm) | Largeur ouverture P/F côté opposé ébrasure (mm) | Superficie ouverture P/F côté ébrasure (m2) | Superficie ouverture P/F côté opposé ébrasure (m2) | Largeur nominale de l'ouverture P/F côté ébrasure (mm) = Largeur nominale de l'ouverture P/F côté opposée ébrasure (mm) = Largeur (mm) | Valeur Appui ou Linteau (mm) = Hauteur nominale seuil (mm) | Hauteur seuil P/F côté ébrasure (mm) = Hauteur seuil P/F côté opposé ébrasure (mm) | Hauteur nominale linteau P/F (mm) | Hauteur linteau P/F côté ébrasure (mm) = Hauteur linteau P/F côté opposé ébrasure (mm) | Épaisseur de Mur (mm) | Volume (net) (m3) | Altitude à Zéro du Projet (mm) = Altitude de Référence Niveau 1 (mm) = Altitude de Référence Niveau 2 (mm) = Altitude à niveau de la mer (mm) | Altitude à étage lié/étage d'implantation (mm) = Décalage étage d'implantation (mm) | Altitude supérieure à premier niveau de référence (mm) = Altitude supérieure à Zéro du projet (mm) = Altitude supérieure à niveau de la mer (mm) = Altitude supérieure à deuxième niveau de référence (mm) | Altitude supérieure à étage d'implantation (mm) | Altitude inférieure à premier niveau de référence (mm) = Altitude inférieure à Zéro du projet (mm) = Altitude inférieure à niveau de la mer (mm) = Altitude inférieure à deuxième niveau de référence (mm) | Altitude inférieure à étage d'implantation (mm) | Hauteur appui à étage actuel (mm) | Largeur huisserie (mm) | Epais. faux cadre (mm) | Larg feuill mont horiz (mm) | Epaisseur porte (mm) | Contours Mur (0-Sans,1-Tout,2-Côté,3-Longueur) | Dimensions normalisées | Angle d'ouverture en 2D (deg) | Poignée en 3D | Liste des interface user | Affichage texte | Nom de zone liée | Numéro de zone liée | De Zone | Du numéro de Zone | Zones conflictuelles | À Zone | À numéro de Zone
Por-299 | sousol | 2040 | 930 | 0,93×2,04 | 0,93×2,04×0,18 | Beton 18 0170347028 | G | Por-299 | 3D | sousol | 2 | Mur-133 | HAG Acrylic White | 0.378144 | 0.341496 | 6.48965 | 1.8972 | 1010 | 2080 | 1010 | 2.1008 | 2.1008 | 930 | 0 | 0 | 2040 | 1940 | 180 | 0.125102 | 4.18415e-12 | 4.18415e-12 | 2080 | 2080 | 4.1716e-12 | 4.1716e-12 | 0 | 40 | 20 | 15 | 40 | 2 | yes | 90 | yes | Réglages rapides | Sur ouvrant
2 x Por-297 | sousol | 2040 | 930 | 0,93×2,04 | 0,93×2,04×0,18 | Beton 18 0170347028 | G | Por-297 | 3D | sousol | 2 | Mur-133 | HAG Acrylic White | 0.378144 | 0.341496 | 6.48965 | 1.8972 | 1010 | 2080 | 1010 | 2.1008 | 2.1008 | 930 | 0 | 0 | 2040 | 1940 | 180 | 0.125102 | 4.18415e-12 | 4.18415e-12 | 2080 | 2080 | 4.1716e-12 | 4.1716e-12 | 0 | 40 | 20 | 15 | 40 | 2 | yes | 90 | yes | Réglages rapides | Sur ouvrant
Por-296 | sousol | 2040 | 930 | 0,93×2,04 | 0,93×2,04×0,18 | Beton 18 0170347028 | D | Por-296 | 3D | sousol | 2 | Mur-133 | HAG Acrylic White | 0.378144 | 0.341496 | 6.48965 | 1.8972 | 1010 | 2080 | 1010 | 2.1008 | 2.1008 | 930 | 0 | 0 | 2040 | 1940 | 180 | 0.125102 | 4.18415e-12 | 4.18415e-12 | 2080 | 2080 | 4.1716e-12 | 4.1716e-12 | 0 | 40 | 20 | 15 | 40 | 2 | yes | 90 | yes | Réglages rapides | Sur ouvrant
Por-295 | sousol | 2040 | 1030 | 1,03×2,04 | 1,03×2,04×0,18 | Beton 18 0170347028 | D | Por-295 | 3D | sousol | 2 | Mur-133 | HAG Acrylic White | 0.415584 | 0.378216 | 6.95265 | 2.1012 | 1110 | 2080 | 1110 | 2.3088 | 2.3088 | 1030 | 0 | 0 | 2040 | 1940 | 180 | 0.134229 | 4.18415e-12 | 4.18415e-12 | 2080 | 2080 | 4.17313e-12 | 4.17313e-12 | 0 | 40 | 20 | 15 | 40 | 2 | yes | 90 | yes | Réglages rapides | Sur ouvrant | Pl | 818 | Pl | 818 | Pl | Pl | 818
Por-298 | sousol | 2040 | 930 | 0,93×2,04 | 0,93×2,04×0,18 | Beton 18 0170347028 | D | Por-298 | 3D | sousol | 2 | Mur-133 | HAG Acrylic White | 0.378144 | 0.341496 | 6.48965 | 1.8972 | 1010 | 2080 | 1010 | 2.1008 | 2.1008 | 930 | 0 | 0 | 2040 | 1940 | 180 | 0.125102 | 4.18415e-12 | 4.18415e-12 | 2080 | 2080 | 4.1716e-12 | 4.1716e-12 | 0 | 40 | 20 | 15 | 40 | 2 | yes | 90 | yes | Réglages rapides | Sur ouvrant
Por-276 | sousol | 500 | 500 | 0,50×0,50 | 0,50×0,50×0,18 | Beton 18 0170347028 | G | Por-276 | 3D | sousol | 2 | Mur-132 | HAG Acrylic White | 0.047736 | 0.045 | 1.2067 | 0.25 | 520 | 510 | 520 | 0.2652 | 0.2652 | 500 | 1800 | 1700 | 2300 | 2200 | 180 | 0.010418 | 1800 | 1800 | 2900 | 2900 | 1800 | 1800 | 1800 | 10 | 10 | 10 | 20 | 2 | yes | 0 | yes | Cadre et porte | Sans | Pl | 818 |  |  | Pl | Pl | 818
Por-276 | sousol | 2040 | 516.122 | 0,52×2,04 | 0,52×2,04×0,18 | Beton 18 0170347028 | D | Por-276 | 3D | sousol | 2 | Mur-132 | HAG Acrylic White | 0.197829 | 0.18952 | 4.11317 | 1.05289 | 536.122 | 2050 | 536.122 | 1.09905 | 1.09905 | 516.122 | 0 | 0 | 2040 | 1940 | 180 | 0.0371574 | 4.18415e-12 | 4.18415e-12 | 2050 | 2050 | 4.17283e-12 | 4.17283e-12 | 0 | 10 | 10 | 10 | 20 | 2 | yes | 0 | yes | Cadre et porte | Sans
Por-299 | sousol | 2040 | 930 | 0,93×2,04 | 0,93×2,04×0,18 | Beton 18 0170347028 | D | Por-299 | 3D | sousol | 2 | Mur-133 | HAG Acrylic White | 0.378144 | 0.341496 | 6.48965 | 1.8972 | 1010 | 2080 | 1010 | 2.1008 | 2.1008 | 930 | 0 | 0 | 2040 | 1940 | 180 | 0.125102 | 4.18415e-12 | 4.18415e-12 | 2080 | 2080 | 4.17313e-12 | 4.17313e-12 | 4.18415e-12 | 40 | 20 | 15 | 40 | 2 | yes | 90 | yes | Réglages rapides | Sur ouvrant | Pl | 818 | Pl | 818 | Pl | Pl | 818
Por-276 | sousol | 500 | 500 | 0,50×0,50 | 0,50×0,50×0,18 | Beton 18 0170347028 | G | Por-276 | 3D | sousol | 2 | Mur-133 | HAG Acrylic White | 0.047736 | 0.045 | 1.2067 | 0.25 | 520 | 510 | 520 | 0.2652 | 0.2652 | 500 | 1800 | 1700 | 2300 | 2200 | 180 | 0.010418 | 1800 | 1800 | 2900 | 2900 | 1800 | 1800 | 1800 | 10 | 10 | 10 | 20 | 2 | yes | 0 | yes | Cadre et porte | Sans | Pl | 818 | Pl | 818 | Pl | Pl | 818
Por-238 | sousol | 2050 | 930 | 0,93×2,05 | 0,93×2,05×0,18 | Beton 18 0170347028 | G | Por-238 | 3D | sousol | 2 | Mur-132 | Chrome | 0.379962 | 0.34317 | 6.51845 | 1.9065 | 1010 | 2090 | 1010 | 2.1109 | 2.1109 | 930 | 110 | 10 | 2160 | 2060 | 180 | 0.125667 | 110 | 110 | 2200 | 2200 | 110 | 110 | 110 | 40 | 20 | 15 | 40 | 1 | yes | 90 | yes | Réglages rapides | Sur ouvrant
Por-277 | rdc | 2000 | 1000 | 1,00×2,00 | 1,00×2,00×0,18 | Beton 18 0018356637 | D | Por-277 | Interieurs logements | rdc | 3 | Mur-142 | HAG Acrylic White | 0.369036 | 0.36 | 6.1867 | 2 | 1020 | 2010 | 1020 | 2.0502 | 2.0502 | 1000 | 200 | 100 | 2200 | 2100 | 180 | 0.057493 | 2600 | -400 | 4610 | 1610 | 2600 | -400 | 2600 | 10 | 10 | 10 | 20 | 2 | yes | 0 | yes | Cadre et porte | Sans
Por-277 | rdc | 2000 | 1000 | 1,00×2,00 | 1,00×2,00×0,18 | Beton 18 0018356637 | G | Por-277 | Interieurs logements | rdc | 3 | Mur-142 | HAG Acrylic White | 0.369036 | 0.36 | 6.1867 | 2 | 1020 | 2010 | 1020 | 2.0502 | 2.0502 | 1000 | 200 | 100 | 2200 | 2100 | 180 | 0.057493 | 2600 | -400 | 4610 | 1610 | 2600 | -400 | 2600 | 10 | 10 | 10 | 20 | 2 | yes | 0 | yes | Cadre et porte | Sans
Por-242 | rdc | 650 | 450 | 0,45×0,65 | 0,45×0,65×0,32 | isol int 18+14 | G | Por-242 | Interieurs logements | rdc | 3 | Mur-142 | HAG Acrylic White | 0.105056 | 0.0936 | 1.90145 | 0.2925 | 490 | 670 | 490 | 0.3283 | 0.3283 | 450 | 300 | 200 | 950 | 850 | 320 | 0.025175 | 3300 | 300 | 3970 | 970 | 3300 | 300 | 300 | 20 | 20 | 15 | 20 | 2 | yes | 0 | no | Réglages rapides | Sans
Por-274 | rdc | 2040 | 580 | 0,58×2,04 | 0,58×2,04×0,07 | Cloison 70 0836576958 | G | Por-274 | 1-Projet | rdc | 3 | Mur-148 | HAG Acrylic White | 0.0861 | 0.082824 | 3.3723 | 1.1832 | 600 | 2050 | 600 | 1.23 | 1.23 | 580 | 0 | 0 | 2040 | 1940 | 70 | 0.029732 | 3000 | 0 | 5050 | 2050 | 3000 | 0 | 0 | 10 | 10 | 10 | 20 | 2 | yes | 0 | yes | Cadre et porte | Sans | Dgt | A04 |  |  | Dgt | Dgt | A04
Por-274 | rdc | 2040 | 580 | 0,58×2,04 | 0,58×2,04×0,07 | Cloison 70 0826278243 | G | Por-274 | 1-Projet | rdc | 3 | Mur-149 | HAG Acrylic White | 0.0795621 | 0.082824 | 3.3723 | 1.1832 | 554.44 | 2050 | 554.44 | 1.1366 | 1.1366 | 580 | 0 | 0 | 2040 | 1940 | 70 | 0.029732 | 3000 | 0 | 5050 | 2050 | 3000 | 0 | 0 | 10 | 10 | 10 | 20 | 2 | yes | 0 | yes | Cadre et porte | Sans | Sejour cuisine/pl | B04 | Sejour cuisine/pl | B04 | Sejour cuisine/pl
Por-278 | rdc | 2040 | 830 | 0,83×2,04 | 0,83×2,04×0,07 | Cloison 70 0826278243 | G | Por-278 | 1-Projet | rdc | 3 | Mur-149 | HAG Acrylic White | 0.132496 | 0.118524 | 4.92335 | 1.6932 | 910 | 2080 | 910 | 1.8928 | 1.8928 | 830 | 0 | 0 | 2040 | 1940 | 70 | 0.085966 | 3000 | 0 | 5080 | 2080 | 3000 | 0 | 0 | 40 | 20 | 15 | 40 | 2 | yes | 22.6789 | yes | Réglages rapides | Sur ouvrant | Entree/pl | B01 | Cellier | B01 | Entree/pl | Entree/pl | B01
Por-281 | rdc | 2040 | 830 | 0,83×2,04 | 0,83×2,04×0,07 | Cloison 70 0826278243 | G | Por-281 | 1-Projet | rdc | 3 | Mur-149 | HAG Acrylic White | 0.132496 | 0.118524 | 4.92335 | 1.6932 | 910 | 2080 | 910 | 1.8928 | 1.8928 | 830 | 0 | 0 | 2040 | 1940 | 70 | 0.085966 | 3000 | 0 | 5080 | 2080 | 3000 | 0 | 0 | 40 | 20 | 15 | 40 | 2 | yes | 27.0064 | yes | Réglages rapides | Sur ouvrant | Entree/pl | A02 | Wc | A02 | Entree/pl | Entree/pl | A02
Por-274 | rdc | 2040 | 580 | 0,58×2,04 | 0,58×2,04×0,07 | Cloison 70 0826278243 | D | Por-274 | 1-Projet | rdc | 3 | Mur-149 | HAG Acrylic White | 0.0861 | 0.082824 | 3.3723 | 1.1832 | 600 | 2050 | 600 | 1.23 | 1.23 | 580 | 0 | 0 | 2040 | 1940 | 70 | 0.029732 | 3000 | 0 | 5050 | 2050 | 3000 | 0 | 0 | 10 | 10 | 10 | 20 | 2 | yes | 0 | yes | Cadre et porte | Sans | Entree/pl | A02 |  |  | Entree/pl | Entree/pl | A02
Por-280 | rdc | 2040 | 830 | 0,83×2,04 | 0,83×2,04×0,07 | Cloison 70 0826278243 | D | Por-280 | 1-Projet | rdc | 3 | Mur-149 | HAG Acrylic White | 0.132496 | 0.118524 | 4.92335 | 1.6932 | 910 | 2080 | 910 | 1.8928 | 1.8928 | 830 | 0 | 0 | 2040 | 1940 | 70 | 0.085966 | 3000 | 0 | 5080 | 2080 | 3000 | 0 | 0 | 40 | 20 | 15 | 40 | 2 | yes | 90 | yes | Réglages rapides | Sur ouvrant | Ch 2 | A02 | Entree/pl | A02 | Ch 2 | Ch 2 | A02
Por-278 | rdc | 2040 | 830 | 0,83×2,04 | 0,83×2,04×0,07 | Cloison 70 0826278243 | G | Por-278 | 1-Projet | rdc | 3 | Mur-149 | HAG Acrylic White | 0.132496 | 0.118524 | 4.92335 | 1.6932 | 910 | 2080 | 910 | 1.8928 | 1.8928 | 830 | 0 | 0 | 2040 | 1940 | 70 | 0.085966 | 3000 | 0 | 5080 | 2080 | 3000 | 0 | 0 | 40 | 20 | 15 | 40 | 2 | yes | 20.2897 | yes | Réglages rapides | Sur ouvrant | Sejour Cuisine | A02 | Cellier | A02 | Sejour Cuisine | Sejour Cuisine | A02
Por-280 | rdc | 2040 | 830 | 0,83×2,04 | 0,83×2,04×0,07 | Cloison 70 0826278243 | D | Por-280 | 1-Projet | rdc | 3 | Mur-149 | HAG Acrylic White | 0.132496 | 0.118524 | 4.92335 | 1.6932 | 910 | 2080 | 910 | 1.8928 | 1.8928 | 830 | 0 | 0 | 2040 | 1940 | 70 | 0.085966 | 3000 | 0 | 5080 | 2080 | 3000 | 0 | 0 | 40 | 20 | 15 | 40 | 2 | yes | 17.6124 | yes | Réglages rapides | Sur ouvrant | Entree/pl | A02 | Sdb/pl | A02 | Entree/pl | Entree/pl | A02
Por-280 | rdc | 2040 | 830 | 0,83×2,04 | 0,83×2,04×0,07 | Cloison 70 0826278243 | D | Por-280 | 1-Projet | rdc | 3 | Mur-149 | HAG Acrylic White | 0.132496 | 0.118524 | 4.92335 | 1.6932 | 910 | 2080 | 910 | 1.8928 | 1.8928 | 830 | 0 | 0 | 2040 | 1940 | 70 | 0.085966 | 3000 | 0 | 5080 | 2080 | 3000 | 0 | 0 | 40 | 20 | 15 | 40 | 2 | yes | 90 | yes | Réglages rapides | Sur ouvrant | Ch 1 | A02 | Entree/pl | A02 | Ch 1 | Ch 1 | A02
Por-274 | rdc | 2040 | 580 | 0,58×2,04 | 0,58×2,04×0,07 | Cloison 70 0826278243 | G | Por-274 | 1-Projet | rdc | 3 | Mur-149 | HAG Acrylic White | 0.0861 | 0.082824 | 3.3723 | 1.1832 | 600 | 2050 | 600 | 1.23 | 1.23 | 580 | 0 | 0 | 2040 | 1940 | 70 | 0.029732 | 3000 | 0 | 5050 | 2050 | 3000 | 0 | 0 | 10 | 10 | 10 | 20 | 2 | yes | 0 | yes | Cadre et porte | Sans | Entree/pl | B05 |  |  | Entree/pl | Entree/pl | B05
Por-279 | rdc | 2040 | 930 | 0,93×2,04 | 0,93×2,04×0,18 | Beton 18 0018356637 | D | Por-279 | Interieurs logements | rdc | 3 | Mur-143 | HAG Acrylic White | 0.378144 | 0.341496 | 6.48965 | 1.8972 | 1010 | 2080 | 1010 | 2.1008 | 2.1008 | 930 | 0 | 0 | 2040 | 1940 | 180 | 0.125102 | 3000 | 0 | 5080 | 2080 | 3000 | 0 | 0 | 40 | 20 | 15 | 40 | 2 | yes | 90 | yes | Réglages rapides | Sur ouvrant | Entree/pl | A02 |  |  | Entree/pl | Entree/pl | A02
Por-281 | rdc | 2040 | 930 | 0,93×2,04 | 0,93×2,04×0,18 | Beton 18 0018356637 | G | Por-281 | Interieurs logements | rdc | 3 | Mur-143 | HAG Acrylic White | 0.378144 | 0.341496 | 6.48965 | 1.8972 | 1010 | 2080 | 1010 | 2.1008 | 2.1008 | 930 | 0 | 0 | 2040 | 1940 | 180 | 0.125102 | 3000 | 0 | 5080 | 2080 | 3000 | 0 | 0 | 40 | 20 | 15 | 40 | 2 | yes | 90 | yes | Réglages rapides | Sur ouvrant
Por-274 | rdc | 2040 | 580 | 0,58×2,04 | 0,58×2,04×0,07 | Cloison 70 0826278243 | D | Por-274 | 1-Projet | rdc | 3 | Mur-149 | HAG Acrylic White | 0.0861 | 0.082824 | 3.3723 | 1.1832 | 600 | 2050 | 600 | 1.23 | 1.23 | 580 | 0 | 0 | 2040 | 1940 | 70 | 0.029732 | 3000 | 0 | 5050 | 2050 | 3000 | 0 | 0 | 10 | 10 | 10 | 20 | 2 | yes | 0 | yes | Cadre et porte | Sans | Entree | A01 | Entree | A01 | Entree | Entree | A01
Por-278 | rdc | 2040 | 830 | 0,83×2,04 | 0,83×2,04×0,07 | Cloison 70 0826278243 | G | Por-278 | 1-Projet | rdc | 3 | Mur-149 | HAG Acrylic White | 0.132496 | 0.118524 | 4.92335 | 1.6932 | 910 | 2080 | 910 | 1.8928 | 1.8928 | 830 | 520 | 420 | 2560 | 2460 | 70 | 0.085966 | 3520 | 520 | 5600 | 2600 | 3520 | 520 | 520 | 40 | 20 | 15 | 40 | 2 | yes | 22.6789 | yes | Réglages rapides | Sur ouvrant | Entree/pl | B05 | Sdb | B05 | Entree/pl | Entree/pl | B05
Por-299 | rdc | 2040 | 930 | 0,93×2,04 | 0,93×2,04×0,18 | Beton 18 0018356637 | G | Por-299 | Interieurs logements | rdc | 3 | Mur-142 | HAG Acrylic White | 0.378144 | 0.341496 | 6.48965 | 1.8972 | 1010 | 2080 | 1010 | 2.1008 | 2.1008 | 930 | 0 | 0 | 2040 | 1940 | 180 | 0.125102 | 3000 | 0 | 5080 | 2080 | 3000 | 0 | 0 | 40 | 20 | 15 | 40 | 2 | yes | 90 | yes | Réglages rapides | Sur ouvrant | Entree/pl | B04 |  |  | Entree/pl | Entree/pl | B04
Por-274 | rdc | 2040 | 580 | 0,58×2,04 | 0,58×2,04×0,07 | Cloison 70 0826278243 | G | Por-274 | 1-Projet | rdc | 3 | Mur-149 | HAG Acrylic White | 0.08323 | 0.082824 | 3.3723 | 1.1832 | 580 | 2050 | 580 | 1.189 | 1.189 | 580 | 0 | 0 | 2040 | 1940 | 70 | 0.029732 | 3000 | 0 | 5050 | 2050 | 3000 | 0 | 0 | 10 | 10 | 10 | 20 | 2 | yes | 0 | yes | Cadre et porte | Sans | Sejour cuisine | B03 | Sejour cuisine | B03 | Sejour cuisine | Sejour cuisine | B03
Por-285 | rdc | 2040 | 830 | 0,83×2,04 | 0,83×2,04×0,07 | Cloison 70 0826278243 | G | Por-285 | 1-Projet | rdc | 3 | Mur-149 | HAG Acrylic White | 0.132496 | 0.118524 | 4.92335 | 1.6932 | 910 | 2080 | 910 | 1.8928 | 1.8928 | 830 | 0 | 0 | 2040 | 1940 | 70 | 0.085966 | 3000 | 0 | 5080 | 2080 | 3000 | 0 | 0 | 40 | 20 | 15 | 40 | 2 | yes | 24.3404 | yes | Réglages rapides | Sur ouvrant | Entree | A01 | Sdb | A01 | Entree | Entree | A01
Por-278 | rdc | 2040 | 830 | 0,83×2,04 | 0,83×2,04×0,07 | Cloison 70 0826278243 | G | Por-278 | 1-Projet | rdc | 3 | Mur-153 | HAG Acrylic White | 0.132496 | 0.118524 | 4.92335 | 1.6932 | 910 | 2080 | 910 | 1.8928 | 1.8928 | 830 | 0 | 0 | 2040 | 1940 | 70 | 0.085966 | 3000 | 0 | 5080 | 2080 | 3000 | 0 | 0 | 40 | 20 | 15 | 40 | 2 | yes | 89.8741 | yes | Réglages rapides | Sur ouvrant | Ch 1 | A03 | Sejour cuisine | A03 | Ch 1 | Ch 1 | A03
Por-275 | rdc | 2040 | 830 | 0,83×2,04 | 0,83×2,04×0,07 | Cloison 70 0826278243 | D | Por-275 | 1-Projet | rdc | 3 | Mur-149 | HAG Acrylic White | 0.132496 | 0.118524 | 4.92335 | 1.6932 | 910 | 2080 | 910 | 1.8928 | 1.8928 | 830 | 0 | 0 | 2040 | 1940 | 70 | 0.085966 | 3000 | 0 | 5080 | 2080 | 3000 | 0 | 0 | 40 | 20 | 15 | 40 | 2 | yes | 20.9444 | yes | Réglages rapides | Sur ouvrant | Entree/pl | B02 | Ch 1/pl | B02 | Entree/pl | Entree/pl | B02
Por-276 | rdc | 2040 | 830 | 0,83×2,04 | 0,83×2,04×0,07 | Cloison 70 0826278243 | G | Por-276 | 1-Projet | rdc | 3 | Mur-149 | HAG Acrylic White | 0.132496 | 0.118524 | 4.92335 | 1.6932 | 910 | 2080 | 910 | 1.8928 | 1.8928 | 830 | 0 | 0 | 2040 | 1940 | 70 | 0.085966 | 3000 | 0 | 5080 | 2080 | 3000 | 0 | 0 | 40 | 20 | 15 | 40 | 2 | yes | 90 | yes | Réglages rapides | Sur ouvrant | Ch 2 | B02 | Entree/pl | B02 | Ch 2 | Ch 2 | B02
Por-284 | rdc | 2040 | 830 | 0,83×2,04 | 0,83×2,04×0,07 | Cloison 70 0826278243 | G | Por-284 | 1-Projet | rdc | 3 | Mur-149 | HAG Acrylic White | 0.132496 | 0.118524 | 4.92335 | 1.6932 | 910 | 2080 | 910 | 1.8928 | 1.8928 | 830 | 0 | 0 | 2040 | 1940 | 70 | 0.085966 | 3000 | 0 | 5080 | 2080 | 3000 | 0 | 0 | 40 | 20 | 15 | 40 | 2 | yes | 22.6789 | yes | Réglages rapides | Sur ouvrant | Entree/pl | B03 | Cellier | B03 | Entree/pl | Entree/pl | B03
Por-275 | rdc | 2040 | 830 | 0,83×2,04 | 0,83×2,04×0,07 | Cloison 70 0826278243 | D | Por-275 | 1-Projet | rdc | 3 | Mur-149 | HAG Acrylic White | 0.132496 | 0.118524 | 4.92335 | 1.6932 | 910 | 2080 | 910 | 1.8928 | 1.8928 | 830 | 0 | 0 | 2040 | 1940 | 70 | 0.085966 | 3000 | 0 | 5080 | 2080 | 3000 | 0 | 0 | 40 | 20 | 15 | 40 | 2 | yes | 90 | yes | Réglages rapides | Sur ouvrant | Ch 1 | B05 | Entree/pl | B05 | Ch 1 | Ch 1 | B05
Por-276 | rdc | 2040 | 830 | 0,83×2,04 | 0,83×2,04×0,07 | Cloison 70 0826278243 | G | Por-276 | 1-Projet | rdc | 3 | Mur-149 | HAG Acrylic White | 0.132496 | 0.118524 | 4.92335 | 1.6932 | 910 | 2080 | 910 | 1.8928 | 1.8928 | 830 | 0 | 0 | 2040 | 1940 | 70 | 0.085966 | 3000 | 0 | 5080 | 2080 | 3000 | 0 | 0 | 40 | 20 | 15 | 40 | 2 | yes | 89.9641 | yes | Réglages rapides | Sur ouvrant | Ch 2 | B05 | Entree/pl | B05 | Ch 2 | Ch 2 | B05
Por-279 | rdc | 2040 | 930 | 0,93×2,04 | 0,93×2,04×0,28 | isol int 18+10 0018356637 | D | Por-279 | Interieurs logements | rdc | 3 | Mur-142 | HAG Acrylic White | 0.588224 | 0.531216 | 7.51265 | 1.8972 | 1010 | 2080 | 1010 | 2.1008 | 2.1008 | 930 | 0 | 0 | 2040 | 1940 | 280 | 0.152932 | 3000 | 0 | 5080 | 2080 | 3000 | 0 | 0 | 40 | 20 | 15 | 40 | 2 | yes | 90 | yes | Réglages rapides | Sur ouvrant | Entree | A01 |  |  | Entree | Entree | A01
Por-279 | rdc | 2040 | 930 | 0,93×2,04 | 0,93×2,04×0,18 | Beton 18 0018356637 | D | Por-279 | Interieurs logements | rdc | 3 | Mur-142 | HAG Acrylic White | 0.378144 | 0.341496 | 6.48965 | 1.8972 | 1010 | 2080 | 1010 | 2.1008 | 2.1008 | 930 | 0 | 0 | 2040 | 1940 | 180 | 0.125102 | 3000 | 0 | 5080 | 2080 | 3000 | 0 | 0 | 40 | 20 | 15 | 40 | 2 | yes | 90 | yes | Réglages rapides | Sur ouvrant | Sejour cuisine | A03 |  |  | Sejour cuisine | Sejour cuisine | A03
Por-280 | rdc | 2040 | 830 | 0,83×2,04 | 0,83×2,04×0,07 | Cloison 70 0826278243 | G | Por-280 | 1-Projet | rdc | 3 | Mur-149 | HAG Acrylic White | 0.132496 | 0.118524 | 4.92335 | 1.6932 | 910 | 2080 | 910 | 1.8928 | 1.8928 | 830 | 0 | 0 | 2040 | 1940 | 70 | 0.085966 | 3000 | 0 | 5080 | 2080 | 3000 | 0 | 0 | 40 | 20 | 15 | 40 | 2 | yes | 22.6789 | yes | Réglages rapides | Sur ouvrant | Entree/pl | B03 | Sdb | B03 | Entree/pl | Entree/pl | B03
Por-288 | rdc | 2040 | 800 | 0,80×2,04 | 0,80×2,04×0,02 | mur 2cm | G | Por-288 | 1-Projet | rdc | 3 | Mur-148 | HAG Acrylic White | 0.036608 | 0.03264 | 4.17895 | 1.632 | 880 | 2080 | 880 | 1.8304 | 1.8304 | 800 | 0 | 0 | 2040 | 1940 | 20 | 0.0372118 | 3000 | 0 | 5080 | 2080 | 3000 | 0 | 0 | 40 | 20 | 15 | 20 | 2 | no | 14.3266 | yes | Réglages rapides | Sans | Sdb | B05 |  |  | Sdb | Sdb | B05
Por-288 | rdc | 2040 | 800 | 0,80×2,04 | 0,80×2,04×0,02 | mur 2cm | D | Por-288 | 1-Projet | rdc | 3 | Mur-148 | HAG Acrylic White | 0.036608 | 0.03264 | 4.17895 | 1.632 | 880 | 2080 | 880 | 1.8304 | 1.8304 | 800 | 0 | 0 | 2040 | 1940 | 20 | 0.0372118 | 3000 | 0 | 5080 | 2080 | 3000 | 0 | 0 | 40 | 20 | 15 | 20 | 2 | no | 14.3266 | yes | Réglages rapides | Sans | Sde | B04 | Sde | B04 | Sde | Sde | B04
Por-288 | rdc | 2040 | 800 | 0,80×2,04 | 0,80×2,04×0,02 | mur 2cm | G | Por-288 | 1-Projet | rdc | 3 | Mur-148 | HAG Acrylic White | 0.036608 | 0.03264 | 4.17895 | 1.632 | 880 | 2080 | 880 | 1.8304 | 1.8304 | 800 | 0 | 0 | 2040 | 1940 | 20 | 0.0372118 | 3000 | 0 | 5080 | 2080 | 3000 | 0 | 0 | 40 | 20 | 15 | 20 | 2 | no | 14.3266 | yes | Réglages rapides | Sans | Sdb | B02 | Sdb | B02 | Sdb | Sdb | B02
Por-288 | rdc | 2040 | 800 | 0,80×2,04 | 0,80×2,04×0,02 | mur 2cm | G | Por-288 | 1-Projet | rdc | 3 | Mur-148 | HAG Acrylic White | 0.036608 | 0.03264 | 4.17895 | 1.632 | 880 | 2080 | 880 | 1.8304 | 1.8304 | 800 | 0 | 0 | 2040 | 1940 | 20 | 0.0372118 | 3000 | 0 | 5080 | 2080 | 3000 | 0 | 0 | 40 | 20 | 15 | 20 | 2 | no | 14.3266 | yes | Réglages rapides | Sans | Sdb | B01 | Sdb | B01 | Sdb | Sdb | B01
Por-288 | rdc | 2040 | 800 | 0,80×2,04 | 0,80×2,04×0,02 | mur 2cm | G | Por-288 | 1-Projet | rdc | 3 | Mur-148 | HAG Acrylic White | 0.036608 | 0.03264 | 4.17895 | 1.632 | 880 | 2080 | 880 | 1.8304 | 1.8304 | 800 | 0 | 0 | 2040 | 1940 | 20 | 0.0372118 | 3000 | 0 | 5080 | 2080 | 3000 | 0 | 0 | 40 | 20 | 15 | 20 | 2 | no | 14.3266 | yes | Réglages rapides | Sans | Sdb | A04 | Sdb | A04 | Sdb | Sdb | A04
Por-288 | rdc | 2040 | 800 | 0,80×2,04 | 0,80×2,04×0,02 | mur 2cm | G | Por-288 | 1-Projet | rdc | 3 | Mur-148 | HAG Acrylic White | 0.036608 | 0.03264 | 4.17895 | 1.632 | 880 | 2080 | 880 | 1.8304 | 1.8304 | 800 | 0 | 0 | 2040 | 1940 | 20 | 0.0372118 | 3000 | 0 | 5080 | 2080 | 3000 | 0 | 0 | 40 | 20 | 15 | 20 | 2 | no | 14.3266 | yes | Réglages rapides | Sans | Sdb | A03 | Sdb | A03 | Sdb | Sdb | A03
Por-288 | rdc | 2040 | 800 | 0,80×2,04 | 0,80×2,04×0,02 | mur 2cm | G | Por-288 | 1-Projet | rdc | 3 | Mur-148 | HAG Acrylic White | 0.036608 | 0.03264 | 4.17895 | 1.632 | 880 | 2080 | 880 | 1.8304 | 1.8304 | 800 | 0 | 0 | 2040 | 1940 | 20 | 0.0372118 | 3000 | 0 | 5080 | 2080 | 3000 | 0 | 0 | 40 | 20 | 15 | 20 | 2 | no | 14.3266 | yes | Réglages rapides | Sans | Sdb | A01 | Sdb | A01 | Sdb | Sdb | A01
Por-288 | rdc | 2040 | 800 | 0,80×2,04 | 0,80×2,04×0,02 | mur 2cm | G | Por-288 | 1-Projet | rdc | 3 | Mur-148 | HAG Acrylic White | 0.036608 | 0.03264 | 4.17895 | 1.632 | 880 | 2080 | 880 | 1.8304 | 1.8304 | 800 | 0 | 0 | 2040 | 1940 | 20 | 0.0372118 | 3000 | 0 | 5080 | 2080 | 3000 | 0 | 0 | 40 | 20 | 15 | 20 | 2 | no | 14.3266 | yes | Réglages rapides | Sans | Sdb/pl | A02 | Sdb/pl | A02 | Sdb/pl | Sdb/pl | A02
Por-278 | rdc | 2040 | 830 | 0,83×2,04 | 0,83×2,04×0,07 | Cloison 70 0826278243 | G | Por-278 | 1-Projet | rdc | 3 | Mur-149 | HAG Acrylic White | 0.132496 | 0.118524 | 4.92335 | 1.6932 | 910 | 2080 | 910 | 1.8928 | 1.8928 | 830 | 0 | 0 | 2040 | 1940 | 70 | 0.085966 | 3000 | 0 | 5080 | 2080 | 3000 | 0 | 0 | 40 | 20 | 15 | 40 | 2 | yes | 22.6789 | yes | Réglages rapides | Sur ouvrant | Entree/pl | B02 | Cellier | B02 | Entree/pl | Entree/pl | B02
Por-278 | rdc | 2040 | 830 | 0,83×2,04 | 0,83×2,04×0,07 | Cloison 70 0826278243 | D | Por-278 | 1-Projet | rdc | 3 | Mur-149 | HAG Acrylic White | 0.132496 | 0.118524 | 4.92335 | 1.6932 | 910 | 2080 | 910 | 1.8928 | 1.8928 | 830 | 0 | 0 | 2040 | 1940 | 70 | 0.085966 | 3000 | 0 | 5080 | 2080 | 3000 | 0 | 0 | 40 | 20 | 15 | 40 | 2 | yes | 22.6789 | yes | Réglages rapides | Sur ouvrant | Entree/pl | B02 | Wc | B02 | Entree/pl | Entree/pl | B02
Por-275 | rdc | 2040 | 580 | 0,58×2,04 | 0,58×2,04×0,07 | Cloison 70 0826278243 | G | Por-275 | 1-Projet | rdc | 3 | Mur-150 | HAG Acrylic White | 0.0861 | 0.082824 | 3.3723 | 1.1832 | 600 | 2050 | 600 | 1.23 | 1.23 | 580 | 0 | 0 | 2040 | 1940 | 70 | 0.029732 | 3000 | 0 | 5050 | 2050 | 3000 | 0 | 0 | 10 | 10 | 10 | 20 | 2 | yes | 0 | yes | Cadre et porte | Sans | Entree/pl | B01 |  |  | Entree/pl | Entree/pl | B01
Por-276 | rdc | 2040 | 830 | 0,83×2,04 | 0,83×2,04×0,07 | Cloison 70 0826278243 | D | Por-276 | 1-Projet | rdc | 3 | Mur-149 | HAG Acrylic White | 0.132496 | 0.118524 | 4.92335 | 1.6932 | 910 | 2080 | 910 | 1.8928 | 1.8928 | 830 | 0 | 0 | 2040 | 1940 | 70 | 0.085966 | 3000 | 0 | 5080 | 2080 | 3000 | 0 | 0 | 40 | 20 | 15 | 40 | 2 | yes | 22.6807 | yes | Réglages rapides | Sur ouvrant | Entree/pl | B01 | Wc | B01 | Entree/pl | Entree/pl | B01
Por-277 | rdc | 2040 | 830 | 0,83×2,04 | 0,83×2,04×0,07 | Cloison 70 0826278243 | G | Por-277 | 1-Projet | rdc | 3 | Mur-150 | HAG Acrylic White | 0.132496 | 0.118524 | 4.92335 | 1.6932 | 910 | 2080 | 910 | 1.8928 | 1.8928 | 830 | 0 | 0 | 2040 | 1940 | 70 | 0.085966 | 3000 | 0 | 5080 | 2080 | 3000 | 0 | 0 | 40 | 20 | 15 | 40 | 2 | yes | 21.9195 | yes | Réglages rapides | Sur ouvrant | Entree/pl | B01 | Sdb | B01 | Entree/pl | Entree/pl | B01
Por-275 | rdc | 2040 | 830 | 0,83×2,04 | 0,83×2,04×0,07 | Cloison 70 0826278243 | G | Por-275 | 1-Projet | rdc | 3 | Mur-149 | HAG Acrylic White | 0.132496 | 0.118524 | 4.92335 | 1.6932 | 910 | 2080 | 910 | 1.8928 | 1.8928 | 830 | 0 | 0 | 2040 | 1940 | 70 | 0.085966 | 3000 | 0 | 5080 | 2080 | 3000 | 0 | 0 | 40 | 20 | 15 | 40 | 2 | yes | 90 | yes | Réglages rapides | Sur ouvrant | Ch 1 | B01 | Entree/pl | B01 | Ch 1 | Ch 1 | B01
Por-276 | rdc | 2040 | 830 | 0,83×2,04 | 0,83×2,04×0,07 | Cloison 70 0826278243 | D | Por-276 | 1-Projet | rdc | 3 | Mur-149 | HAG Acrylic White | 0.132496 | 0.118524 | 4.92335 | 1.6932 | 910 | 2080 | 910 | 1.8928 | 1.8928 | 830 | 0 | 0 | 2040 | 1940 | 70 | 0.085966 | 3000 | 0 | 5080 | 2080 | 3000 | 0 | 0 | 40 | 20 | 15 | 40 | 2 | yes | 90 | yes | Réglages rapides | Sur ouvrant | Ch 2 | B01 | Entree/pl | B01 | Ch 2 | Ch 2 | B01
Por-279 | rdc | 2040 | 930 | 0,93×2,04 | 0,93×2,04×0,18 | Beton 18 0018356637 | D | Por-279 | Interieurs logements | rdc | 3 | Mur-142 | HAG Acrylic White | 0.378144 | 0.341496 | 6.48965 | 1.8972 | 1010 | 2080 | 1010 | 2.1008 | 2.1008 | 930 | 0 | 0 | 2040 | 1940 | 180 | 0.125102 | 3000 | 0 | 5080 | 2080 | 3000 | 0 | 0 | 40 | 20 | 15 | 40 | 2 | yes | 90 | yes | Réglages rapides | Sur ouvrant | Sejour Cuisine/pl | A04 |  |  | Sejour Cuisine/pl | Sejour Cuisine/pl | A04
Por-299 | rdc | 2040 | 930 | 0,93×2,04 | 0,93×2,04×0,18 | Beton 18 0018356637 | G | Por-299 | Interieurs logements | rdc | 3 | Mur-143 | HAG Acrylic White | 0.378144 | 0.341496 | 6.48965 | 1.8972 | 1010 | 2080 | 1010 | 2.1008 | 2.1008 | 930 | 0 | 0 | 2040 | 1940 | 180 | 0.125102 | 3000 | 0 | 5080 | 2080 | 3000 | 0 | 0 | 40 | 20 | 15 | 40 | 2 | yes | 90 | yes | Réglages rapides | Sur ouvrant | Entree/pl | B05 |  |  | Entree/pl | Entree/pl | B05
Por-295 | rdc | 2040 | 930 | 0,93×2,04 | 0,93×2,04×0,18 | Beton 18 0018356637 | D | Por-295 | Interieurs logements | rdc | 3 | Mur-143 | HAG Acrylic White | 0.378144 | 0.341496 | 6.48965 | 1.8972 | 1010 | 2080 | 1010 | 2.1008 | 2.1008 | 930 | 0 | 0 | 2040 | 1940 | 180 | 0.125102 | 3000 | 0 | 5080 | 2080 | 3000 | 0 | 0 | 40 | 20 | 15 | 40 | 2 | yes | 90 | yes | Réglages rapides | Sur ouvrant
Por-235 | rdc | 650 | 450 | 0,45×0,65 | 0,45×0,65×0,18 | Beton 18 0018356637 | G | Por-235 | Interieurs logements | rdc | 3 | Mur-143 | HAG Acrylic White | 0.059094 | 0.05265 | 1.39885 | 0.2925 | 490 | 670 | 490 | 0.3283 | 0.3283 | 450 | 300 | 200 | 950 | 850 | 180 | 0.016551 | 3300 | 300 | 3970 | 970 | 3300 | 300 | 300 | 20 | 20 | 15 | 20 | 2 | yes | 0 | no | Réglages rapides | Sans
Por-249 | rdc | 650 | 450 | 0,45×0,65 | 0,45×0,65×0,07 | Cloison 70 0826278243 | G | Por-249 | 1-Projet | rdc | 3 | Mur-149 | HAG Acrylic White | 0.022981 | 0.020475 | 1.00395 | 0.2925 | 490 | 670 | 490 | 0.3283 | 0.3283 | 450 | 300 | 200 | 950 | 850 | 70 | 0.009775 | 3300 | 300 | 3970 | 970 | 3300 | 300 | 300 | 20 | 20 | 15 | 20 | 2 | yes | 0 | no | Réglages rapides | Sans | Sejour Cuisine/pl | A04 | Sejour Cuisine/pl | A04 | Sejour Cuisine/pl
Por-278 | rdc | 2040 | 830 | 0,83×2,04 | 0,83×2,04×0,07 | Cloison 70 0826278243 | G | Por-278 | 1-Projet | rdc | 3 | Mur-151 | HAG Acrylic White | 0.132496 | 0.118524 | 4.92335 | 1.6932 | 910 | 2080 | 910 | 1.8928 | 1.8928 | 830 | 0 | 0 | 2040 | 1940 | 70 | 0.085966 | 3000 | 0 | 5080 | 2080 | 3000 | 0 | 0 | 40 | 20 | 15 | 40 | 2 | yes | 29.5716 | yes | Réglages rapides | Sur ouvrant | Ch 1 | A03 | Sdb | A03 | Ch 1 | Ch 1 | A03
Por-281 | rdc | 2040 | 830 | 0,83×2,04 | 0,83×2,04×0,07 | Cloison 70 0826278243 | G | Por-281 | 1-Projet | rdc | 3 | Mur-153 | HAG Acrylic White | 0.132496 | 0.118524 | 4.92335 | 1.6932 | 910 | 2080 | 910 | 1.8928 | 1.8928 | 830 | 0 | 0 | 2040 | 1940 | 70 | 0.085966 | 3000 | 0 | 5080 | 2080 | 3000 | 0 | 0 | 40 | 20 | 15 | 40 | 2 | yes | 90 | yes | Réglages rapides | Sur ouvrant | Ch 2/pl | A04 |  |  | Ch 2/pl; Dgt | Ch 2/pl | A04
Por-282 | rdc | 2040 | 830 | 0,83×2,04 | 0,83×2,04×0,07 | Cloison 70 0826278243 | D | Por-282 | 1-Projet | rdc | 3 | Mur-153 | HAG Acrylic White | 0.132496 | 0.118524 | 4.92335 | 1.6932 | 910 | 2080 | 910 | 1.8928 | 1.8928 | 830 | 0 | 0 | 2040 | 1940 | 70 | 0.085966 | 3000 | 0 | 5080 | 2080 | 3000 | 0 | 0 | 40 | 20 | 15 | 40 | 2 | yes | 90 | yes | Réglages rapides | Sur ouvrant | Dgt | A04 | Dgt | A04 | Ch 1; Dgt | Dgt | A04
Por-284 | rdc | 2040 | 830 | 0,83×2,04 | 0,83×2,04×0,07 | Cloison 70 0826278243 | D | Por-284 | 1-Projet | rdc | 3 | Mur-149 | HAG Acrylic White | 0.132496 | 0.118524 | 4.92335 | 1.6932 | 910 | 2080 | 910 | 1.8928 | 1.8928 | 830 | 0 | 0 | 2040 | 1940 | 70 | 0.085966 | 3000 | 0 | 5080 | 2080 | 3000 | 0 | 0 | 40 | 20 | 15 | 40 | 2 | yes | 22.8067 | yes | Réglages rapides | Sur ouvrant | Sejour cuisine/pl | A01 | Ch 1 | A01 | Sejour cuisine/pl | Sejour cuisine/pl | A01
Por-283 | rdc | 2040 | 830 | 0,83×2,04 | 0,83×2,04×0,07 | Cloison 70 0826278243 | G | Por-283 | 1-Projet | rdc | 3 | Mur-149 | HAG Acrylic White | 0.132496 | 0.118524 | 4.92335 | 1.6932 | 910 | 2080 | 910 | 1.8928 | 1.8928 | 830 | 0 | 0 | 2040 | 1940 | 70 | 0.085966 | 3000 | 0 | 5080 | 2080 | 3000 | 0 | 0 | 40 | 20 | 15 | 40 | 2 | yes | 22.6789 | yes | Réglages rapides | Sur ouvrant | Entree/pl | B03 | Wc | B03 | Entree/pl | Entree/pl | B03
Por-277 | rdc | 2040 | 830 | 0,83×2,04 | 0,83×2,04×0,07 | Cloison 70 0826278243 | D | Por-277 | 1-Projet | rdc | 3 | Mur-150 | HAG Acrylic White | 0.132496 | 0.118524 | 4.92335 | 1.6932 | 910 | 2080 | 910 | 1.8928 | 1.8928 | 830 | 0 | 0 | 2040 | 1940 | 70 | 0.085966 | 3000 | 0 | 5080 | 2080 | 3000 | 0 | 0 | 40 | 20 | 15 | 40 | 2 | yes | 21.9195 | yes | Réglages rapides | Sur ouvrant | Entree/pl | B02 | Sdb | B02 | Entree/pl | Entree/pl | B02
Por-274 | rdc | 2040 | 580 | 0,58×2,04 | 0,58×2,04×0,07 | Cloison 70 0826278243 | D | Por-274 | 1-Projet | rdc | 3 | Mur-150 | HAG Acrylic White | 0.0861 | 0.082824 | 3.3723 | 1.1832 | 600 | 2050 | 600 | 1.23 | 1.23 | 580 | 0 | 0 | 2040 | 1940 | 70 | 0.029732 | 3000 | 0 | 5050 | 2050 | 3000 | 0 | 0 | 10 | 10 | 10 | 20 | 2 | yes | 0 | yes | Cadre et porte | Sans | Entree/pl | B02 | Sdb | B02 | Entree/pl | Entree/pl | B02
Por-281 | rdc | 2040 | 830 | 0,83×2,04 | 0,83×2,04×0,07 | Cloison 70 0826278243 | D | Por-281 | 1-Projet | rdc | 3 | Mur-149 | HAG Acrylic White | 0.132496 | 0.118524 | 4.92335 | 1.6932 | 910 | 2080 | 910 | 1.8928 | 1.8928 | 830 | 0 | 0 | 2040 | 1940 | 70 | 0.085966 | 3000 | 0 | 5080 | 2080 | 3000 | 0 | 0 | 40 | 20 | 15 | 40 | 2 | yes | 90 | yes | Réglages rapides | Sur ouvrant | Ch 1/pl | B04 | Dgt | B04 | Ch 1/pl | Ch 1/pl | B04
Por-282 | rdc | 2040 | 830 | 0,83×2,04 | 0,83×2,04×0,07 | Cloison 70 0826278243 | G | Por-282 | 1-Projet | rdc | 3 | Mur-149 | HAG Acrylic White | 0.132496 | 0.118524 | 4.92335 | 1.6932 | 910 | 2080 | 910 | 1.8928 | 1.8928 | 830 | 0 | 0 | 2040 | 1940 | 70 | 0.085966 | 3000 | 0 | 5080 | 2080 | 3000 | 0 | 0 | 40 | 20 | 15 | 40 | 2 | yes | 90 | yes | Réglages rapides | Sur ouvrant | Sde | B04 | Dgt | B04 | Sde | Sde | B04
Por-299 | rdc | 2040 | 930 | 0,93×2,04 | 0,93×2,04×0,18 | Beton 18 0018356637 | G | Por-299 | Interieurs logements | rdc | 3 | Mur-143 | HAG Acrylic White | 0.378144 | 0.341496 | 6.48965 | 1.8972 | 1010 | 2080 | 1010 | 2.1008 | 2.1008 | 930 | 0 | 0 | 2040 | 1940 | 180 | 0.125102 | 3000 | 0 | 5080 | 2080 | 3000 | 0 | 0 | 40 | 20 | 15 | 40 | 2 | yes | 90 | yes | Réglages rapides | Sur ouvrant | Entree/pl | B03 |  |  | Entree/pl | Entree/pl | B03
Por-234 | rdc | 650 | 450 | 0,45×0,65 | 0,45×0,65×0,18 | Beton 18 0018356637 | G | Por-234 | Interieurs logements | rdc | 3 | Mur-143 | HAG Acrylic White | 0.059094 | 0.05265 | 1.39885 | 0.2925 | 490 | 670 | 490 | 0.3283 | 0.3283 | 450 | 300 | 200 | 950 | 850 | 180 | 0.016551 | 3300 | 300 | 3970 | 970 | 3300 | 300 | 300 | 20 | 20 | 15 | 20 | 2 | yes | 0 | no | Réglages rapides | Sans
Por-283 | rdc | 2040 | 830 | 0,83×2,04 | 0,83×2,04×0,07 | Cloison 70 0826278243 | D | Por-283 | 1-Projet | rdc | 3 | Mur-153 | HAG Acrylic White | 0.132496 | 0.118524 | 4.92335 | 1.6932 | 910 | 2080 | 910 | 1.8928 | 1.8928 | 830 | 0 | 0 | 2040 | 1940 | 70 | 0.085966 | 3000 | 0 | 5080 | 2080 | 3000 | 0 | 0 | 40 | 20 | 15 | 40 | 2 | yes | 24.4794 | yes | Réglages rapides | Sur ouvrant | Sejour Cuisine/pl | A04 | Wc | A04 | Sejour Cuisine/pl | Sejour Cuisine/pl | A04
Por-283 | rdc | 2040 | 830 | 0,83×2,04 | 0,83×2,04×0,07 | Cloison 70 0826278243 | D | Por-283 | 1-Projet | rdc | 3 | Mur-153 | HAG Acrylic White | 0.132496 | 0.118524 | 4.92335 | 1.6932 | 910 | 2080 | 910 | 1.8928 | 1.8928 | 830 | 0 | 0 | 2040 | 1940 | 70 | 0.085966 | 3000 | 0 | 5080 | 2080 | 3000 | 0 | 0 | 40 | 20 | 15 | 40 | 2 | yes | 24.4794 | yes | Réglages rapides | Sur ouvrant | Dgt | A04 | Cellier | A04 | Dgt | Dgt | A04
Por-283 | rdc | 2040 | 830 | 0,83×2,04 | 0,83×2,04×0,07 | Cloison 70 0826278243 | D | Por-283 | 1-Projet | rdc | 3 | Mur-153 | HAG Acrylic White | 0.132496 | 0.118524 | 4.92335 | 1.6932 | 910 | 2080 | 910 | 1.8928 | 1.8928 | 830 | 0 | 0 | 2040 | 1940 | 70 | 0.085966 | 3000 | 0 | 5080 | 2080 | 3000 | 0 | 0 | 40 | 20 | 15 | 40 | 2 | yes | 24.4794 | yes | Réglages rapides | Sur ouvrant | Dgt | A04 | Sdb | A04 | Dgt | Dgt | A04
Por-278 | rdc | 2040 | 830 | 0,83×2,04 | 0,83×2,04×0,07 | Cloison 70 0826278243 | G | Por-278 | 1-Projet | rdc | 3 | Mur-149 | HAG Acrylic White | 0.132496 | 0.118524 | 4.92335 | 1.6932 | 910 | 2080 | 910 | 1.8928 | 1.8928 | 830 | 0 | 0 | 2040 | 1940 | 70 | 0.085966 | 3000 | 0 | 5080 | 2080 | 3000 | 0 | 0 | 40 | 20 | 15 | 40 | 2 | yes | 22.6789 | yes | Réglages rapides | Sur ouvrant | Entree/pl | B05 | Wc | B05 | Entree/pl | Entree/pl | B05
Por-202 | rdc | 2040 | 600 | 0,60×2,04 | 0,60×2,04×0,07 | Cloison 70 0826278243 | D | Por-202 | 3D | rdc | 3 | Mur-120 | HAG Acrylic White | 0.0889698 | 0.08568 | 3.5639 | 1.224 | 620 | 2050 | 620 | 1.271 | 1.271 | 600 | 0 | 0 | 2040 | 1940 | 70 | 0.055053 | 3000 | 0 | 5050 | 2050 | 3000 | 0 | 0 | 10 | 10 | 10 | 40 | 2 | yes | 0 | yes | Cadre et porte | Sans
Por-202 | rdc | 2040 | 680 | 0,68×2,04 | 0,68×2,04×0,07 | Cloison 70 0826278243 | D | Por-202 | 3D | rdc | 3 | Mur-120 | HAG Acrylic White | 0.10045 | 0.097104 | 3.9111 | 1.3872 | 700 | 2050 | 700 | 1.435 | 1.435 | 680 | 0 | 0 | 2040 | 1940 | 70 | 0.061681 | 3000 | 0 | 5050 | 2050 | 3000 | 0 | 0 | 10 | 10 | 10 | 40 | 2 | yes | 0 | yes | Cadre et porte | Sans
Por-202 | rdc | 2040 | 380 | 0,38×2,04 | 0,38×2,04×0,07 | Cloison 70 0826278243 | D | Por-202 | 3D | rdc | 3 | Mur-120 | HAG Acrylic White | 0.0570041 | 0.054264 | 2.6091 | 0.7752 | 397.242 | 2050 | 397.242 | 0.814345 | 0.814345 | 380 | 0 | 0 | 2040 | 1940 | 70 | 0.036826 | 3000 | 0 | 5050 | 2050 | 3000 | 0 | 0 | 10 | 10 | 10 | 40 | 2 | yes | 0 | yes | Cadre et porte | Sans
Por-202 | rdc | 2040 | 480 | 0,48×2,04 | 0,48×2,04×0,07 | Cloison 70 0826278243 | D | Por-202 | 3D | rdc | 3 | Mur-120 | HAG Acrylic White | 0.0703153 | 0.068544 | 3.0431 | 0.9792 | 490.003 | 2050 | 490.003 | 1.00451 | 1.00451 | 480 | 0 | 0 | 2040 | 1940 | 70 | 0.045111 | 3000 | 0 | 5050 | 2050 | 3000 | 0 | 0 | 10 | 10 | 10 | 40 | 2 | yes | 0 | yes | Cadre et porte | Sans
Por-202 | rdc | 2040 | 600 | 0,60×2,04 | 0,60×2,04×0,07 | Cloison 70 0826278243 | D | Por-202 | 3D | rdc | 3 | Mur-120 | HAG Acrylic White | 0.0889697 | 0.08568 | 3.5639 | 1.224 | 620 | 2050 | 620 | 1.271 | 1.271 | 600 | 0 | 0 | 2040 | 1940 | 70 | 0.055053 | 3000 | 0 | 5050 | 2050 | 3000 | 0 | 0 | 10 | 10 | 10 | 40 | 2 | yes | 0 | yes | Cadre et porte | Sans
Por-202 | rdc | 2040 | 450 | 0,45×2,04 | 0,45×2,04×0,07 | Cloison 70 0826278243 | D | Por-202 | 3D | rdc | 3 | Mur-120 | HAG Acrylic White | 0.0674448 | 0.06426 | 2.9129 | 0.918 | 470 | 2050 | 470 | 0.9635 | 0.9635 | 450 | 0 | 0 | 2040 | 1940 | 70 | 0.0426255 | 3000 | 0 | 5050 | 2050 | 3000 | 0 | 0 | 10 | 10 | 10 | 40 | 2 | yes | 0 | yes | Cadre et porte | Sans
Por-202 | rdc | 2040 | 350 | 0,35×2,04 | 0,35×2,04×0,07 | Cloison 70 0826278243 | D | Por-202 | 3D | rdc | 3 | Mur-120 | HAG Acrylic White | 0.0530948 | 0.04998 | 2.4789 | 0.714 | 370 | 2050 | 370 | 0.7585 | 0.7585 | 350 | 0 | 0 | 2040 | 1940 | 70 | 0.0343405 | 3000 | 0 | 5050 | 2050 | 3000 | 0 | 0 | 10 | 10 | 10 | 40 | 2 | yes | 0 | yes | Cadre et porte | Sans
2 x Por-202 | rdc | 2040 | 480 | 0,48×2,04 | 0,48×2,04×0,07 | Cloison 70 0826278243 | D | Por-202 | 3D | rdc | 3 | Mur-120 | HAG Acrylic White | 0.07175 | 0.068544 | 3.0431 | 0.9792 | 500 | 2050 | 500 | 1.025 | 1.025 | 480 | 0 | 0 | 2040 | 1940 | 70 | 0.045111 | 3000 | 0 | 5050 | 2050 | 3000 | 0 | 0 | 10 | 10 | 10 | 40 | 2 | yes | 0 | yes | Cadre et porte | Sans
2 x Por-202 | rdc | 2040 | 580 | 0,58×2,04 | 0,58×2,04×0,07 | Cloison 70 0826278243 | D | Por-202 | 3D | rdc | 3 | Mur-120 | HAG Acrylic White | 0.0861 | 0.082824 | 3.4771 | 1.1832 | 600 | 2050 | 600 | 1.23 | 1.23 | 580 | 0 | 0 | 2040 | 1940 | 70 | 0.053396 | 3000 | 0 | 5050 | 2050 | 3000 | 0 | 0 | 10 | 10 | 10 | 40 | 2 | yes | 0 | yes | Cadre et porte | Sans
Por-202 | rdc | 2040 | 630 | 0,63×2,04 | 0,63×2,04×0,07 | Cloison 70 0826278243 | D | Por-202 | 3D | rdc | 3 | Mur-120 | HAG Acrylic White | 0.093275 | 0.089964 | 3.6941 | 1.2852 | 650 | 2050 | 650 | 1.3325 | 1.3325 | 630 | 0 | 0 | 2040 | 1940 | 70 | 0.0575385 | 3000 | 0 | 5050 | 2050 | 3000 | 0 | 0 | 10 | 10 | 10 | 40 | 2 | yes | 0 | yes | Cadre et porte | Sans
Por-302 | rdc | 2040 | 1030 | 1,03×2,04 | 1,03×2,04×0,18 | Beton 18 0018356637 | D | Por-302 | Interieurs logements | rdc | 3 | Mur-142 | HAG Acrylic White | 0.415584 | 0.378216 | 6.95265 | 2.1012 | 1110 | 2080 | 1110 | 2.3088 | 2.3088 | 1030 | 0 | 0 | 2040 | 1940 | 180 | 0.134229 | 3000 | 0 | 5080 | 2080 | 3000 | 0 | 0 | 40 | 20 | 15 | 40 | 1 | yes | 90 | yes | Réglages rapides | Sur ouvrant | Pl | 678 | Pl | 678
Por-302 | rdc | 2040 | 1030 | 1,03×2,04 | 1,03×2,04×0,18 | Beton 18 0018356637 | G | Por-302 | Interieurs logements | rdc | 3 | Mur-142 | HAG Acrylic White | 0.415584 | 0.378216 | 6.95265 | 2.1012 | 1110 | 2080 | 1110 | 2.3088 | 2.3088 | 1030 | 0 | 0 | 2040 | 1940 | 180 | 0.134229 | 3000 | 0 | 5080 | 2080 | 3000 | 0 | 0 | 40 | 20 | 15 | 40 | 1 | yes | 90 | yes | Réglages rapides | Sur ouvrant | Pl | 678 | Pl | 678
Por-278 | rdc | 2040 | 830 | 0,83×2,04 | 0,83×2,04×0,07 | Cloison 70 0826278243 | D | Por-278 | 1-Projet | rdc | 3 | Mur-121 | HAG Acrylic White | 0.132496 | 0.118524 | 4.92335 | 1.6932 | 910 | 2080 | 910 | 1.8928 | 1.8928 | 830 | 0 | 0 | 2040 | 1940 | 70 | 0.085966 | 3000 | 0 | 5080 | 2080 | 3000 | 0 | 0 | 40 | 20 | 15 | 40 | 2 | yes | 25.655 | yes | Réglages rapides | Sur ouvrant | Sejour cuisine | A03 |  |  | Sejour cuisine; Wc | Sejour cuisine | A03
Por-274 | rdc | 2040 | 580 | 0,58×2,04 | 0,58×2,04×0,07 | Cloison 70 0826278243 | D | Por-274 | 1-Projet | rdc | 3 | Mur-153 | HAG Acrylic White | 0.0861 | 0.082824 | 3.3723 | 1.1832 | 600 | 2050 | 600 | 1.23 | 1.23 | 580 | 0 | 0 | 2040 | 1940 | 70 | 0.029732 | 3000 | 0 | 5050 | 2050 | 3000 | 0 | 0 | 10 | 10 | 10 | 20 | 2 | yes | 0 | yes | Cadre et porte | Sans | Sejour cuisine | A03 |  |  | Sejour cuisine | Sejour cuisine | A03
Por-301 | rdc | 2100 | 1030 | 1,03×2,10 | 1,03×2,10×0,10 | Cloison 100 gaine | D | Por-301 | 3D | rdc | 3 | Mur-133 | HAG Acrylic White | 0.23754 | 0.2163 | 6.28385 | 2.163 | 1110 | 2140 | 1110 | 2.3754 | 2.3754 | 1030 | 0 | 0 | 2100 | 2000 | 100 | 0.11463 | 3000 | 3.9968e-12 | 5140 | 2140 | 3000 | 3.9968e-12 | 8.88178e-13 | 40 | 20 | 15 | 40 | 2 | yes | 90 | yes | Réglages rapides | Sur ouvrant | Pl | 819 |  |  | Pl | Pl | 819
Por-274 | rdc | 2040 | 580 | 0,58×2,04 | 0,58×2,04×0,07 | Cloison 70 0826278243 | G | Por-274 | 1-Projet | rdc | 3 | Mur-149 | HAG Acrylic White | 0.0861 | 0.082824 | 3.3723 | 1.1832 | 600 | 2050 | 600 | 1.23 | 1.23 | 580 | 0 | 0 | 2040 | 1940 | 70 | 0.029732 | 3000 | 0 | 5050 | 2050 | 3000 | 0 | 0 | 10 | 10 | 10 | 20 | 2 | yes | 0 | yes | Cadre et porte | Sans | Entree/pl | B04 |  |  | Entree/pl | Entree/pl | B04
Por-295 | rdc | 2040 | 930 | 0,93×2,04 | 0,93×2,04×0,18 | Beton 18 0018356637 | D | Por-295 | Interieurs logements | rdc | 3 | Mur-143 | HAG Acrylic White | 0.378144 | 0.341496 | 6.48965 | 1.8972 | 1010 | 2080 | 1010 | 2.1008 | 2.1008 | 930 | 0 | 0 | 2040 | 1940 | 180 | 0.125102 | 3000 | 0 | 5080 | 2080 | 3000 | 0 | 0 | 40 | 20 | 15 | 40 | 2 | yes | 90 | yes | Réglages rapides | Sur ouvrant | Entree/pl | B01 |  |  | Entree/pl | Entree/pl | B01
Por-295 | rdc | 2040 | 930 | 0,93×2,04 | 0,93×2,04×0,18 | Beton 18 0018356637 | G | Por-295 | Interieurs logements | rdc | 3 | Mur-143 | HAG Acrylic White | 0.378144 | 0.341496 | 6.48965 | 1.8972 | 1010 | 2080 | 1010 | 2.1008 | 2.1008 | 930 | 0 | 0 | 2040 | 1940 | 180 | 0.125102 | 3000 | 0 | 5080 | 2080 | 3000 | 0 | 0 | 40 | 20 | 15 | 40 | 2 | yes | 90 | yes | Réglages rapides | Sur ouvrant | Entree/pl | B02 | Entree/pl | B02 | Entree/pl | Entree/pl | B02
Por-301 | rdc | 2100 | 1030 | 1,03×2,10 | 1,03×2,10×0,18 | Beton 18 0836643197 | D | Por-301 | Interieurs logements | rdc | 3 | Mur-144 | HAG Acrylic White | 0.427572 | 0.38934 | 7.13745 | 2.163 | 1110 | 2140 | 1110 | 2.3754 | 2.3754 | 1030 | 520 | 420 | 2620 | 2520 | 180 | 0.137862 | 3000 | 8.88178e-13 | 5140 | 2140 | 3000 | 8.88178e-13 | 8.88178e-13 | 40 | 20 | 15 | 40 | 2 | yes | 90 | yes | Réglages rapides | Sur ouvrant
Por-274 | rdc | 2040 | 580 | 0,58×2,04 | 0,58×2,04×0,07 | Cloison 70 0826278243 | D | Por-274 | 1-Projet | rdc | 3 | Mur-149 | HAG Acrylic White | 0.0861 | 0.082824 | 3.3723 | 1.1832 | 600 | 2050 | 600 | 1.23 | 1.23 | 580 | 0 | 0 | 2040 | 1940 | 70 | 0.029732 | 3000 | 0 | 5050 | 2050 | 3000 | 0 | 0 | 10 | 10 | 10 | 20 | 2 | yes | 0 | yes | Cadre et porte | Sans | Sejour cuisine | B03 |  |  | Sejour cuisine | Sejour cuisine | B03
Por-283 | rdc | 2040 | 830 | 0,83×2,04 | 0,83×2,04×0,07 | Cloison 70 0826278243 | G | Por-283 | 1-Projet | rdc | 3 | Mur-149 | HAG Acrylic White | 0.132496 | 0.118524 | 4.92335 | 1.6932 | 910 | 2080 | 910 | 1.8928 | 1.8928 | 830 | 0 | 0 | 2040 | 1940 | 70 | 0.085966 | 3000 | 0 | 5080 | 2080 | 3000 | 0 | 0 | 40 | 20 | 15 | 40 | 2 | yes | 32.5733 | yes | Réglages rapides | Sur ouvrant | Entree/pl | B04 |  |  | Entree/pl | Entree/pl | B04
Por-280 | rdc | 2040 | 830 | 0,83×2,04 | 0,83×2,04×0,07 | Cloison 70 0826278243 | G | Por-280 | 1-Projet | rdc | 3 | Mur-149 | HAG Acrylic White | 0.132496 | 0.118524 | 4.92335 | 1.6932 | 910 | 2080 | 910 | 1.8928 | 1.8928 | 830 | 0 | 0 | 2040 | 1940 | 70 | 0.085966 | 3000 | 0 | 5080 | 2080 | 3000 | 0 | 0 | 40 | 20 | 15 | 40 | 2 | yes | 33.4203 | yes | Réglages rapides | Sur ouvrant | Entree/pl | B04 | Wc | B04 | Entree/pl; Sejour cuisine/pl | Entree/pl | B04
Por-282 | rdc | 2040 | 830 | 0,83×2,04 | 0,83×2,04×0,07 | Cloison 70 0826278243 | D | Por-282 | 1-Projet | rdc | 3 | Mur-149 | HAG Acrylic White | 0.132496 | 0.118524 | 4.92335 | 1.6932 | 910 | 2080 | 910 | 1.8928 | 1.8928 | 830 | 0 | 0 | 2040 | 1940 | 70 | 0.085966 | 3000 | 0 | 5080 | 2080 | 3000 | 0 | 0 | 40 | 20 | 15 | 40 | 2 | yes | 90 | yes | Réglages rapides | Sur ouvrant | Ch 2 | B04 | Dgt | B04 | Ch 2 | Ch 2 | B04
Por-279 | rdc | 2040 | 830 | 0,83×2,04 | 0,83×2,04×0,07 | Cloison 70 0826278243 | G | Por-279 | 1-Projet | rdc | 3 | Mur-149 | HAG Acrylic White | 0.132496 | 0.118524 | 4.92335 | 1.6932 | 910 | 2080 | 910 | 1.8928 | 1.8928 | 830 | 0 | 0 | 2040 | 1940 | 70 | 0.085966 | 3000 | 0 | 5080 | 2080 | 3000 | 0 | 0 | 40 | 20 | 15 | 40 | 2 | yes | 90 | yes | Réglages rapides | Sur ouvrant | Ch 2/pl | B03 | Entree/pl | B03 | Ch 2/pl | Ch 2/pl | B03
Por-278 | rdc | 2040 | 830 | 0,83×2,04 | 0,83×2,04×0,07 | Cloison 70 0826278243 | D | Por-278 | 1-Projet | rdc | 3 | Mur-149 | HAG Acrylic White | 0.132496 | 0.118524 | 4.92335 | 1.6932 | 910 | 2080 | 910 | 1.8928 | 1.8928 | 830 | 0 | 0 | 2040 | 1940 | 70 | 0.085966 | 3000 | 0 | 5080 | 2080 | 3000 | 0 | 0 | 40 | 20 | 15 | 40 | 2 | yes | 90 | yes | Réglages rapides | Sur ouvrant | Ch 1 | B03 | Entree/pl | B03 | Ch 1 | Ch 1 | B03
Por-281 | rdc | 2040 | 830 | 0,83×2,04 | 0,83×2,04×0,07 | Cloison 70 0826278243 | G | Por-281 | 1-Projet | rdc | 3 | Mur-149 | HAG Acrylic White | 0.132496 | 0.118524 | 4.92335 | 1.6932 | 910 | 2080 | 910 | 1.8928 | 1.8928 | 830 | 0 | 0 | 2040 | 1940 | 70 | 0.085966 | 3000 | 0 | 5080 | 2080 | 3000 | 0 | 0 | 40 | 20 | 15 | 40 | 2 | yes | 90 | yes | Réglages rapides | Sur ouvrant | Ch 3 | B03 | Entree/pl | B03 | Ch 3 | Ch 3 | B03
Por-283 | rdc | 2040 | 1000 | 1,00×2,04 | 1,00×2,04×0,34 | Empty Fill 272047960 | G | Por-283 | Interieurs logements | rdc | 3 | Mur-143 | HAG Acrylic White | 0.763776 | 0.6936 | 5.09865 | 2.04 | 1080 | 2080 | 1080 | 2.2464 | 2.2464 | 1000 | 1000 | 900 | 3040 | 2940 | 340 | 0.0829763 | 3500 | 500 | 5580 | 2580 | 3500 | 500 | 500 | 40 | 20 | 15 | 40 | 2 | yes | 89.9751 | yes | Réglages rapides | Sur ouvrant
Por-301 | rdc | 2100 | 1030 | 1,03×2,10 | 1,03×2,10×0,10 | Cloison 100 gaine | G | Por-301 | 3D | rdc | 3 | Mur-133 | HAG Acrylic White | 0.23754 | 0.2163 | 6.28385 | 2.163 | 1110 | 2140 | 1110 | 2.3754 | 2.3754 | 1030 | 0 | 0 | 2100 | 2000 | 100 | 0.11463 | 3000 | 3.9968e-12 | 5140 | 2140 | 3000 | 3.9968e-12 | 8.88178e-13 | 40 | 20 | 15 | 40 | 2 | yes | 90 | yes | Réglages rapides | Sur ouvrant | Pl | 679 |  |  | Pl | Pl | 679
Por-249 | rdc | 650 | 450 | 0,45×0,65 | 0,45×0,65×0,07 | Cloison 70 0826278243 | D | Por-249 | 1-Projet | rdc | 3 | Mur-148 | HAG Acrylic White | 0.022981 | 0.020475 | 1.00395 | 0.2925 | 490 | 670 | 490 | 0.3283 | 0.3283 | 450 | 300 | 200 | 950 | 850 | 70 | 0.009775 | 3300 | 300 | 3970 | 970 | 3300 | 300 | 300 | 20 | 20 | 15 | 20 | 2 | yes | 0 | no | Réglages rapides | Sans | Sdb/pl | A02 | Sdb/pl | A02 | Sdb/pl | Sdb/pl | A02
Por-276 | Etage1 | 2040 | 830 | 0,83×2,04 | 0,83×2,04×0,07 | Cloison 70 0826278243 | D | Por-276 | 1-Projet | Etage1 | 4 | Mur-149 | HAG Acrylic White | 0.132496 | 0.118524 | 4.92335 | 1.6932 | 910 | 2080 | 910 | 1.8928 | 1.8928 | 830 | 0 | 0 | 2040 | 1940 | 70 | 0.085966 | 5750 | 0 | 7830 | 2080 | 5750 | 0 | 0 | 40 | 20 | 15 | 40 | 2 | yes | 22.6807 | yes | Réglages rapides | Sur ouvrant | Wc | B12 | Wc | B12 | Entree/pl; Wc | Wc | B12
Por-279 | Etage1 | 2040 | 930 | 0,93×2,04 | 0,93×2,04×0,18 | Beton 18 0018356637 | D | Por-279 | Interieurs logements | Etage1 | 4 | Mur-142 | HAG Acrylic White | 0.378144 | 0.341496 | 6.48965 | 1.8972 | 1010 | 2080 | 1010 | 2.1008 | 2.1008 | 930 | 0 | 0 | 2040 | 1940 | 180 | 0.125102 | 5750 | 0 | 7830 | 2080 | 5750 | 0 | 0 | 40 | 20 | 15 | 40 | 2 | yes | 90 | yes | Réglages rapides | Sur ouvrant | Sejour Cuisine/pl | A14 |  |  | Sejour Cuisine/pl | Sejour Cuisine/pl | A14
Por-274 | Etage1 | 2040 | 580 | 0,58×2,04 | 0,58×2,04×0,07 | Cloison 70 0826278243 | D | Por-274 | 1-Projet | Etage1 | 4 | Mur-153 | HAG Acrylic White | 0.0861 | 0.082824 | 3.3723 | 1.1832 | 600 | 2050 | 600 | 1.23 | 1.23 | 580 | 0 | 0 | 2040 | 1940 | 70 | 0.029732 | 5750 | 0 | 7800 | 2050 | 5750 | 0 | 0 | 10 | 10 | 10 | 20 | 2 | yes | 0 | yes | Cadre et porte | Sans | Sejour cuisine | A13 |  |  | Sejour cuisine | Sejour cuisine | A13
Por-299 | Etage1 | 2040 | 930 | 0,93×2,04 | 0,93×2,04×0,18 | Beton 18 0018356637 | G | Por-299 | Interieurs logements | Etage1 | 4 | Mur-143 | HAG Acrylic White | 0.378144 | 0.341496 | 6.48965 | 1.8972 | 1010 | 2080 | 1010 | 2.1008 | 2.1008 | 930 | 0 | 0 | 2040 | 1940 | 180 | 0.125102 | 5750 | 0 | 7830 | 2080 | 5750 | 0 | 0 | 40 | 20 | 15 | 40 | 2 | yes | 90 | yes | Réglages rapides | Sur ouvrant |  |  |  |  | Entree/pl
Por-232 | Etage1 | 650 | 450 | 0,45×0,65 | 0,45×0,65×0,18 | Beton 18 0018356637 | G | Por-232 | Interieurs logements | Etage1 | 4 | Mur-143 | HAG Acrylic White | 0.059094 | 0.05265 | 1.39885 | 0.2925 | 490 | 670 | 490 | 0.3283 | 0.3283 | 450 | 0 | 0 | 650 | 550 | 180 | 0.016551 | 5750 | 0 | 6420 | 670 | 5750 | 0 | 0 | 20 | 20 | 15 | 20 | 2 | yes | 0 | no | Réglages rapides | Sans
Por-299 | Etage1 | 2040 | 930 | 0,93×2,04 | 0,93×2,04×0,18 | Beton 18 0018356637 | G | Por-299 | Interieurs logements | Etage1 | 4 | Mur-143 | HAG Acrylic White | 0.378144 | 0.341496 | 6.48965 | 1.8972 | 1010 | 2080 | 1010 | 2.1008 | 2.1008 | 930 | 0 | 0 | 2040 | 1940 | 180 | 0.125102 | 5750 | 0 | 7830 | 2080 | 5750 | 0 | 0 | 40 | 20 | 15 | 40 | 2 | yes | 90 | yes | Réglages rapides | Sur ouvrant | Entree/pl | B16 |  |  | Entree/pl | Entree/pl | B16
Por-295 | Etage1 | 2040 | 930 | 0,93×2,04 | 0,93×2,04×0,18 | Beton 18 0018356637 | G | Por-295 | Interieurs logements | Etage1 | 4 | Mur-143 | HAG Acrylic White | 0.378144 | 0.341496 | 6.48965 | 1.8972 | 1010 | 2080 | 1010 | 2.1008 | 2.1008 | 930 | 0 | 0 | 2040 | 1940 | 180 | 0.125102 | 5750 | 0 | 7830 | 2080 | 5750 | 0 | 0 | 40 | 20 | 15 | 40 | 2 | yes | 90 | yes | Réglages rapides | Sur ouvrant
Por-236 | Etage1 | 650 | 450 | 0,45×0,65 | 0,45×0,65×0,18 | Beton 18 0018356637 | D | Por-236 | Interieurs logements | Etage1 | 4 | Mur-143 | HAG Acrylic White | 0.059094 | 0.05265 | 1.39885 | 0.2925 | 490 | 670 | 490 | 0.3283 | 0.3283 | 450 | 300 | 200 | 950 | 850 | 180 | 0.016551 | 6050 | 300 | 6720 | 970 | 6050 | 300 | 300 | 20 | 20 | 15 | 20 | 2 | yes | 0 | no | Réglages rapides | Sans
Por-281 | Etage1 | 2040 | 930 | 0,93×2,04 | 0,93×2,04×0,18 | Beton 18 0018356637 | D | Por-281 | Interieurs logements | Etage1 | 4 | Mur-143 | HAG Acrylic White | 0.378144 | 0.341496 | 6.48965 | 1.8972 | 1010 | 2080 | 1010 | 2.1008 | 2.1008 | 930 | 0 | 0 | 2040 | 1940 | 180 | 0.125102 | 5750 | 0 | 7830 | 2080 | 5750 | 0 | 0 | 40 | 20 | 15 | 40 | 2 | yes | 90 | yes | Réglages rapides | Sur ouvrant
Por-279 | Etage1 | 2040 | 930 | 0,93×2,04 | 0,93×2,04×0,18 | Beton 18 0018356637 | D | Por-279 | Interieurs logements | Etage1 | 4 | Mur-143 | HAG Acrylic White | 0.378144 | 0.341496 | 6.48965 | 1.8972 | 1010 | 2080 | 1010 | 2.1008 | 2.1008 | 930 | 0 | 0 | 2040 | 1940 | 180 | 0.125102 | 5750 | 0 | 7830 | 2080 | 5750 | 0 | 0 | 40 | 20 | 15 | 40 | 2 | yes | 90 | yes | Réglages rapides | Sur ouvrant | Entree/pl | A12 |  |  | Entree/pl | Entree/pl | A12
Por-278 | Etage1 | 2040 | 830 | 0,83×2,04 | 0,83×2,04×0,07 | Cloison 70 0826278243 | D | Por-278 | 1-Projet | Etage1 | 4 | Mur-149 | HAG Acrylic White | 0.132496 | 0.118524 | 4.92335 | 1.6932 | 910 | 2080 | 910 | 1.8928 | 1.8928 | 830 | 0 | 0 | 2040 | 1940 | 70 | 0.085966 | 5750 | 0 | 7830 | 2080 | 5750 | 0 | 0 | 40 | 20 | 15 | 40 | 2 | yes | 22.6789 | yes | Réglages rapides | Sur ouvrant | Entree/pl | B13 | Wc | B13 | Entree/pl | Entree/pl | B13
Por-282 | Etage1 | 2040 | 830 | 0,83×2,04 | 0,83×2,04×0,07 | Cloison 70 0826278243 | D | Por-282 | 1-Projet | Etage1 | 4 | Mur-153 | HAG Acrylic White | 0.132496 | 0.118524 | 4.92335 | 1.6932 | 910 | 2080 | 910 | 1.8928 | 1.8928 | 830 | 0 | 0 | 2040 | 1940 | 70 | 0.085966 | 5750 | 0 | 7830 | 2080 | 5750 | 0 | 0 | 40 | 20 | 15 | 40 | 2 | yes | 90 | yes | Réglages rapides | Sur ouvrant | Ch 1 | A14 | Dgt | A14 | Ch 1 | Ch 1 | A14
Por-281 | Etage1 | 2040 | 830 | 0,83×2,04 | 0,83×2,04×0,07 | Cloison 70 0826278243 | G | Por-281 | 1-Projet | Etage1 | 4 | Mur-153 | HAG Acrylic White | 0.132496 | 0.118524 | 4.92335 | 1.6932 | 910 | 2080 | 910 | 1.8928 | 1.8928 | 830 | 0 | 0 | 2040 | 1940 | 70 | 0.085966 | 5750 | 0 | 7830 | 2080 | 5750 | 0 | 0 | 40 | 20 | 15 | 40 | 2 | yes | 90 | yes | Réglages rapides | Sur ouvrant | Ch 2 | A14 | Dgt | A14 | Ch 2 | Ch 2 | A14
Por-280 | Etage1 | 2040 | 830 | 0,83×2,04 | 0,83×2,04×0,07 | Cloison 70 0826278243 | G | Por-280 | 1-Projet | Etage1 | 4 | Mur-149 | HAG Acrylic White | 0.132331 | 0.118524 | 4.92335 | 1.6932 | 908.87 | 2080 | 908.87 | 1.89045 | 1.89045 | 830 | 0 | 0 | 2040 | 1940 | 70 | 0.085966 | 5750 | 0 | 7830 | 2080 | 5750 | 0 | 0 | 40 | 20 | 15 | 40 | 2 | yes | 22.6789 | yes | Réglages rapides | Sur ouvrant | Entree/pl | B14 | Sde | B14 | Entree/pl | Entree/pl | B14
Por-277 | Etage1 | 2040 | 830 | 0,83×2,04 | 0,83×2,04×0,07 | Cloison 70 0826278243 | D | Por-277 | 1-Projet | Etage1 | 4 | Mur-150 | HAG Acrylic White | 0.132496 | 0.118524 | 4.92335 | 1.6932 | 910 | 2080 | 910 | 1.8928 | 1.8928 | 830 | 0 | 0 | 2040 | 1940 | 70 | 0.085966 | 5750 | 0 | 7830 | 2080 | 5750 | 0 | 0 | 40 | 20 | 15 | 40 | 2 | yes | 21.9195 | yes | Réglages rapides | Sur ouvrant | Entree/pl | B13 | Sde | B13 | Entree/pl | Entree/pl | B13
Por-275 | Etage1 | 2040 | 580 | 0,58×2,04 | 0,58×2,04×0,07 | Cloison 70 0826278243 | G | Por-275 | 1-Projet | Etage1 | 4 | Mur-150 | HAG Acrylic White | 0.0861 | 0.082824 | 3.3723 | 1.1832 | 600 | 2050 | 600 | 1.23 | 1.23 | 580 | 0 | 0 | 2040 | 1940 | 70 | 0.029732 | 5750 | 0 | 7800 | 2050 | 5750 | 0 | 0 | 10 | 10 | 10 | 20 | 2 | yes | 0 | yes | Cadre et porte | Sans | Entree/pl | B13 |  |  | Entree/pl | Entree/pl | B13
Por-284 | Etage1 | 2040 | 730 | 0,73×2,04 | 0,73×2,04×0,07 | Cloison 70 0826278243 | D | Por-284 | 1-Projet | Etage1 | 4 | Mur-149 | HAG Acrylic White | 0.117936 | 0.104244 | 4.48235 | 1.4892 | 810 | 2080 | 810 | 1.6848 | 1.6848 | 730 | 0 | 0 | 2040 | 1940 | 70 | 0.0774435 | 5750 | 0 | 7830 | 2080 | 5750 | 0 | 0 | 40 | 20 | 15 | 40 | 2 | yes | 22.8067 | yes | Réglages rapides | Sur ouvrant | Ch 1 | A11 | Ch 1 | A11 | Ch 1 | Ch 1 | A11
Por-274 | Etage1 | 2040 | 580 | 0,58×2,04 | 0,58×2,04×0,07 | Cloison 70 0826278243 | D | Por-274 | 1-Projet | Etage1 | 4 | Mur-153 | HAG Acrylic White | 0.0861 | 0.082824 | 3.3723 | 1.1832 | 600 | 2050 | 600 | 1.23 | 1.23 | 580 | 0 | 0 | 2040 | 1940 | 70 | 0.029732 | 5750 | 0 | 7800 | 2050 | 5750 | 0 | 0 | 10 | 10 | 10 | 20 | 2 | yes | 0 | yes | Cadre et porte | Sans | Sejour cuisine/pl | A15 |  |  | Sejour cuisine/pl | Sejour cuisine/pl | A15
Por-285 | Etage1 | 2040 | 830 | 0,83×2,04 | 0,83×2,04×0,07 | Cloison 70 0826278243 | G | Por-285 | 1-Projet | Etage1 | 4 | Mur-149 | HAG Acrylic White | 0.132496 | 0.118524 | 4.92335 | 1.6932 | 910 | 2080 | 910 | 1.8928 | 1.8928 | 830 | 0 | 0 | 2040 | 1940 | 70 | 0.085966 | 5750 | 0 | 7830 | 2080 | 5750 | 0 | 0 | 40 | 20 | 15 | 40 | 2 | yes | 24.3404 | yes | Réglages rapides | Sur ouvrant | Entree | A11 |  |  | Entree | Entree | A11
Por-280 | Etage1 | 2040 | 830 | 0,83×2,04 | 0,83×2,04×0,07 | Cloison 70 0826278243 | D | Por-280 | 1-Projet | Etage1 | 4 | Mur-149 | HAG Acrylic White | 0.132496 | 0.118524 | 4.92335 | 1.6932 | 910 | 2080 | 910 | 1.8928 | 1.8928 | 830 | 0 | 0 | 2040 | 1940 | 70 | 0.085966 | 5750 | 0 | 7830 | 2080 | 5750 | 0 | 0 | 40 | 20 | 15 | 40 | 2 | yes | 90 | yes | Réglages rapides | Sur ouvrant | Ch 1 | A12 | Entree/pl | A12 | Ch 1 | Ch 1 | A12
Por-297 | Etage1 | 2040 | 830 | 0,83×2,04 | 0,83×2,04×0,07 | Cloison 70 0826278243 | G | Por-297 | 1-Projet | Etage1 | 4 | Mur-149 | HAG Acrylic White | 0.132496 | 0.118524 | 4.92335 | 1.6932 | 910 | 2080 | 910 | 1.8928 | 1.8928 | 830 | 0 | 0 | 2040 | 1940 | 70 | 0.085966 | 5750 | 0 | 7830 | 2080 | 5750 | 0 | 0 | 40 | 20 | 15 | 40 | 2 | yes | 27.1745 | yes | Réglages rapides | Sur ouvrant | Entree/pl | B13 | Cellier | B13 | Entree/pl | Entree/pl | B13
Por-279 | Etage1 | 2040 | 930 | 0,93×2,04 | 0,93×2,04×0,28 | isol int 18+10 0018356637 | D | Por-279 | Interieurs logements | Etage1 | 4 | Mur-142 | HAG Acrylic White | 0.588224 | 0.531216 | 7.51265 | 1.8972 | 1010 | 2080 | 1010 | 2.1008 | 2.1008 | 930 | 0 | 0 | 2040 | 1940 | 280 | 0.152932 | 5750 | 0 | 7830 | 2080 | 5750 | 0 | 0 | 40 | 20 | 15 | 40 | 2 | yes | 90 | yes | Réglages rapides | Sur ouvrant | Entree | A11 |  |  | Entree | Entree | A11
Por-276 | Etage1 | 2040 | 830 | 0,83×2,04 | 0,83×2,04×0,07 | Cloison 70 0826278243 | D | Por-276 | 1-Projet | Etage1 | 4 | Mur-149 | HAG Acrylic White | 0.132496 | 0.118524 | 4.92335 | 1.6932 | 910 | 2080 | 910 | 1.8928 | 1.8928 | 830 | 0 | 0 | 2040 | 1940 | 70 | 0.085966 | 5750 | 0 | 7830 | 2080 | 5750 | 0 | 0 | 40 | 20 | 15 | 40 | 2 | yes | 90 | yes | Réglages rapides | Sur ouvrant | Ch 2 | B12 | Entree/pl | B12 | Ch 2 | Ch 2 | B12
Por-275 | Etage1 | 2040 | 830 | 0,83×2,04 | 0,83×2,04×0,07 | Cloison 70 0826278243 | G | Por-275 | 1-Projet | Etage1 | 4 | Mur-149 | HAG Acrylic White | 0.132496 | 0.118524 | 4.92335 | 1.6932 | 910 | 2080 | 910 | 1.8928 | 1.8928 | 830 | 0 | 0 | 2040 | 1940 | 70 | 0.085966 | 5750 | 0 | 7830 | 2080 | 5750 | 0 | 0 | 40 | 20 | 15 | 40 | 2 | yes | 90 | yes | Réglages rapides | Sur ouvrant | Ch 1/pl | B12 | Entree/pl | B12 | Ch 1/pl | Ch 1/pl | B12
Por-283 | Etage1 | 2040 | 830 | 0,83×2,04 | 0,83×2,04×0,07 | Cloison 70 0826278243 | D | Por-283 | 1-Projet | Etage1 | 4 | Mur-153 | HAG Acrylic White | 0.132496 | 0.118524 | 4.92335 | 1.6932 | 910 | 2080 | 910 | 1.8928 | 1.8928 | 830 | 0 | 0 | 2040 | 1940 | 70 | 0.085966 | 5750 | 0 | 7830 | 2080 | 5750 | 0 | 0 | 40 | 20 | 15 | 40 | 2 | yes | 24.4794 | yes | Réglages rapides | Sur ouvrant | Dgt | A14 | Sdb | A14 | Dgt | Dgt | A14
Por-278 | Etage1 | 2040 | 830 | 0,83×2,04 | 0,83×2,04×0,07 | Cloison 70 0826278243 | G | Por-278 | 1-Projet | Etage1 | 4 | Mur-149 | HAG Acrylic White | 0.132496 | 0.118524 | 4.92335 | 1.6932 | 910 | 2080 | 910 | 1.8928 | 1.8928 | 830 | 0 | 0 | 2040 | 1940 | 70 | 0.085966 | 5750 | 0 | 7830 | 2080 | 5750 | 0 | 0 | 40 | 20 | 15 | 40 | 2 | yes | 22.6789 | yes | Réglages rapides | Sur ouvrant | Entree/pl | B12 | Cellier | B12 | Entree/pl | Entree/pl | B12
Por-278 | Etage1 | 2040 | 830 | 0,83×2,04 | 0,83×2,04×0,07 | Cloison 70 0826278243 | D | Por-278 | 1-Projet | Etage1 | 4 | Mur-121 | HAG Acrylic White | 0.132496 | 0.118524 | 4.92335 | 1.6932 | 910 | 2080 | 910 | 1.8928 | 1.8928 | 830 | 0 | 0 | 2040 | 1940 | 70 | 0.085966 | 5750 | 0 | 7830 | 2080 | 5750 | 0 | 0 | 40 | 20 | 15 | 40 | 2 | yes | 25.655 | yes | Réglages rapides | Sur ouvrant | Sejour cuisine | A13 | Wc | A13 | Sejour cuisine | Sejour cuisine | A13
Por-293 | Etage1 | 2040 | 830 | 0,83×2,04 | 0,83×2,04×0,07 | Cloison 70 0826278243 | G | Por-293 | 1-Projet | Etage1 | 4 | Mur-149 | HAG Acrylic White | 0.132496 | 0.118524 | 4.92335 | 1.6932 | 910 | 2080 | 910 | 1.8928 | 1.8928 | 830 | 0 | 0 | 2040 | 1940 | 70 | 0.085966 | 5750 | 0 | 7830 | 2080 | 5750 | 0 | 0 | 40 | 20 | 15 | 40 | 2 | yes | 90 | yes | Réglages rapides | Sur ouvrant | Ch 1 | B11 | Sejour cuisine | B11 | Ch 1 | Ch 1 | B11
Por-288 | Etage1 | 2040 | 800 | 0,80×2,04 | 0,80×2,04×0,02 | mur 2cm | G | Por-288 | 1-Projet | Etage1 | 4 | Mur-148 | HAG Acrylic White | 0.036608 | 0.03264 | 4.17895 | 1.632 | 880 | 2080 | 880 | 1.8304 | 1.8304 | 800 | 0 | 0 | 2040 | 1940 | 20 | 0.0372118 | 5750 | 0 | 7830 | 2080 | 5750 | 0 | 0 | 40 | 20 | 15 | 20 | 2 | no | 14.3266 | yes | Réglages rapides | Sans | Sde | B16 |  |  | Sde | Sde | B16
Por-288 | Etage1 | 2040 | 800 | 0,80×2,04 | 0,80×2,04×0,02 | mur 2cm | G | Por-288 | 1-Projet | Etage1 | 4 | Mur-148 | HAG Acrylic White | 0.036608 | 0.03264 | 4.17895 | 1.632 | 880 | 2080 | 880 | 1.8304 | 1.8304 | 800 | 0 | 0 | 2040 | 1940 | 20 | 0.0372118 | 5750 | 0 | 7830 | 2080 | 5750 | 0 | 0 | 40 | 20 | 15 | 20 | 2 | no | 14.3266 | yes | Réglages rapides | Sans | Sde | B13 | Sde | B13 | Sde | Sde | B13
Por-288 | Etage1 | 2040 | 800 | 0,80×2,04 | 0,80×2,04×0,02 | mur 2cm | D | Por-288 | 1-Projet | Etage1 | 4 | Mur-148 | HAG Acrylic White | 0.036608 | 0.03264 | 4.17895 | 1.632 | 880 | 2080 | 880 | 1.8304 | 1.8304 | 800 | 0 | 0 | 2040 | 1940 | 20 | 0.0372118 | 5750 | 0 | 7830 | 2080 | 5750 | 0 | 0 | 40 | 20 | 15 | 20 | 2 | no | 14.3266 | yes | Réglages rapides | Sans | Sde | B15 | Sde | B15 | Sde | Sde | B15
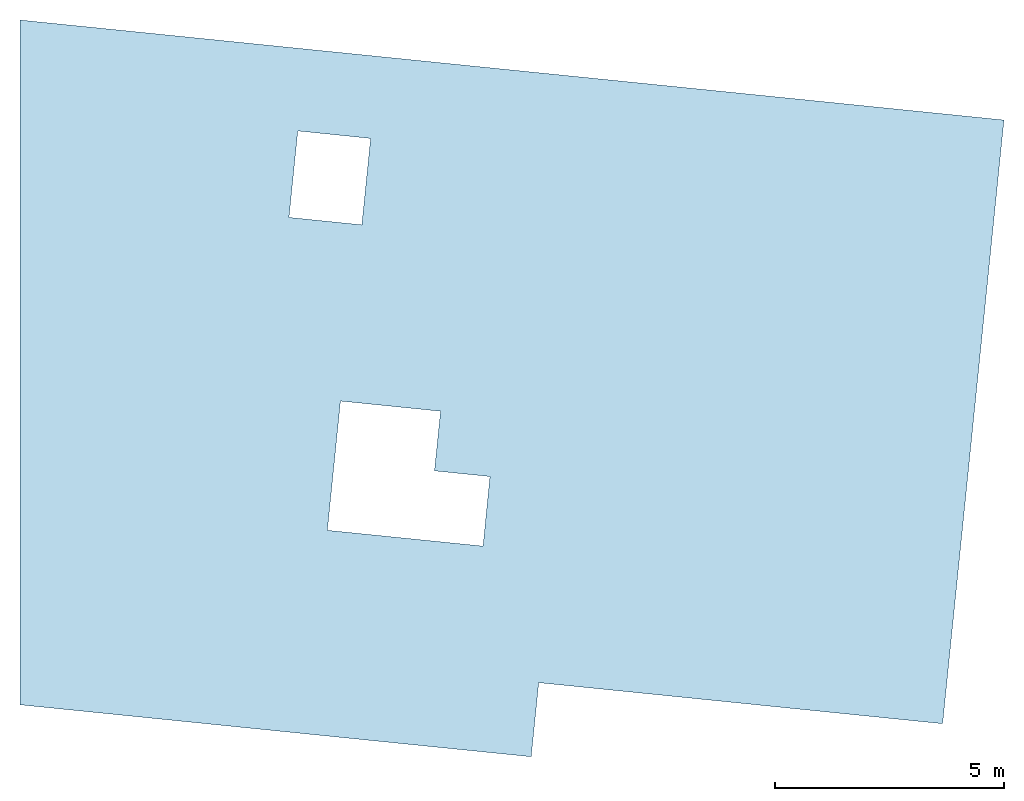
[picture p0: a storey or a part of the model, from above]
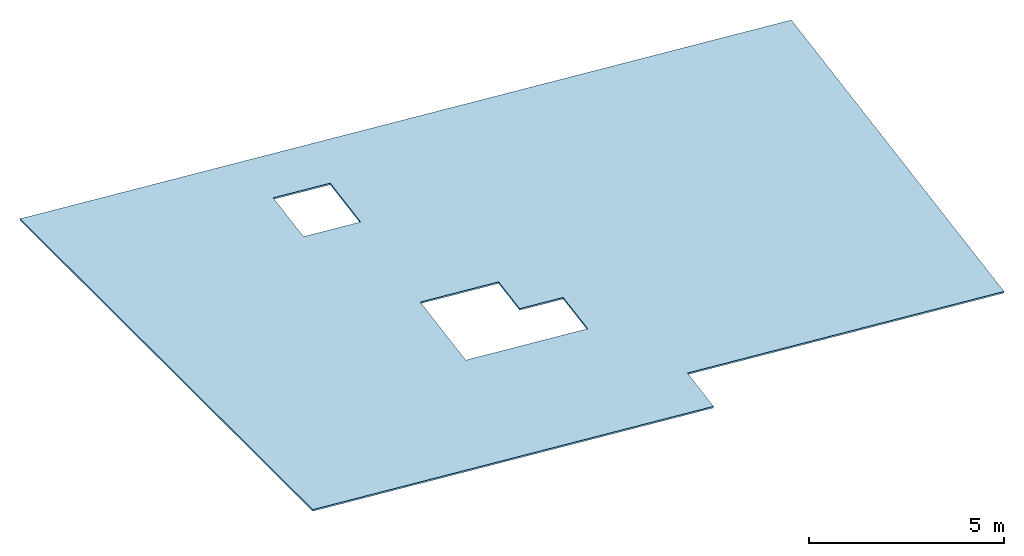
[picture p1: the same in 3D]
Properties of the parts of a building model (IFC2X3), part 14 of 44

# IfcDoor: Porte_1v (482)
Name | In | OverallHeight (mm) = Hauteur nominale de l'ouverture P/F côté ébrasure (mm) = Hauteur nominale de l'ouverture P/F côté opposée ébrasure (mm) = Hauteur (mm) | OverallWidth (mm) | Taille L x H nominale | Taille L x H x E nominale | Structure de Mur | Orientation | ID de l'élément = Lien et ID d'élément | Calque | Nom d'étage d'implantation | Numéro d'étage d'implantation | ID de Parent | Surfaces (Toutes) = Matériau du cadre = Matériau porte = Matériau si métal = Matériau Poignée | Volume ouverture d'ouverture P/F (m3) | Volume nominal ouverture P/F (m3) | Superficie ouverture P/F (m2) = Superficie en plan (m2) = Superficie inférieure (nette) (m2) | Superficie nominale ouverture P/F (m2) = Superficie nominale de l'ouverture P/F côté ébrasure (m2) = Superficie nominale de l'ouverture P/F côté opposé ébrasure (m2) | Largeur ouverture P/F côté ébrasure (mm) | Hauteur ouverture P/F côté ébrasure (mm) = Hauteur ouverture P/F côté opposé ébrasure (mm) | Largeur ouverture P/F côté opposé ébrasure (mm) | Superficie ouverture P/F côté ébrasure (m2) | Superficie ouverture P/F côté opposé ébrasure (m2) | Largeur nominale de l'ouverture P/F côté ébrasure (mm) = Largeur nominale de l'ouverture P/F côté opposée ébrasure (mm) = Largeur (mm) | Valeur Appui ou Linteau (mm) = Hauteur nominale seuil (mm) | Hauteur seuil P/F côté ébrasure (mm) = Hauteur seuil P/F côté opposé ébrasure (mm) | Hauteur nominale linteau P/F (mm) | Hauteur linteau P/F côté ébrasure (mm) = Hauteur linteau P/F côté opposé ébrasure (mm) | Épaisseur de Mur (mm) | Volume (net) (m3) | Altitude à Zéro du Projet (mm) = Altitude de Référence Niveau 1 (mm) = Altitude de Référence Niveau 2 (mm) = Altitude à niveau de la mer (mm) | Altitude à étage lié/étage d'implantation (mm) = Décalage étage d'implantation (mm) | Altitude supérieure à premier niveau de référence (mm) = Altitude supérieure à Zéro du projet (mm) = Altitude supérieure à niveau de la mer (mm) = Altitude supérieure à deuxième niveau de référence (mm) | Altitude supérieure à étage d'implantation (mm) | Altitude inférieure à premier niveau de référence (mm) = Altitude inférieure à Zéro du projet (mm) = Altitude inférieure à niveau de la mer (mm) = Altitude inférieure à deuxième niveau de référence (mm) | Altitude inférieure à étage d'implantation (mm) | Hauteur appui à étage actuel (mm) | Largeur huisserie (mm) | Epais. faux cadre (mm) | Larg feuill mont horiz (mm) | Epaisseur porte (mm) | Contours Mur (0-Sans,1-Tout,2-Côté,3-Longueur) | Dimensions normalisées | Angle d'ouverture en 2D (deg) | Poignée en 3D | Liste des interface user | Affichage texte | Nom de zone liée | Numéro de zone liée | De Zone | Du numéro de Zone | Zones conflictuelles | À Zone | À numéro de Zone
Por-288 | Etage1 | 2040 | 800 | 0,80×2,04 | 0,80×2,04×0,02 | mur 2cm | G | Por-288 | 1-Projet | Etage1 | 4 | Mur-148 | HAG Acrylic White | 0.0366081 | 0.03264 | 4.17895 | 1.632 | 880 | 2080 | 880 | 1.8304 | 1.8304 | 800 | 0 | 0 | 2040 | 1940 | 20 | 0.0372118 | 5750 | 0 | 7830 | 2080 | 5750 | 0 | 0 | 40 | 20 | 15 | 20 | 2 | no | 14.3266 | yes | Réglages rapides | Sans | Sde | B12 | Sde | B12 | Sde | Sde | B12
Por-288 | Etage1 | 2040 | 800 | 0,80×2,04 | 0,80×2,04×0,02 | mur 2cm | G | Por-288 | 1-Projet | Etage1 | 4 | Mur-148 | HAG Acrylic White | 0.036608 | 0.03264 | 4.17895 | 1.632 | 880 | 2080 | 880 | 1.8304 | 1.8304 | 800 | 0 | 0 | 2040 | 1940 | 20 | 0.0372118 | 5750 | 0 | 7830 | 2080 | 5750 | 0 | 0 | 40 | 20 | 15 | 20 | 2 | no | 14.3266 | yes | Réglages rapides | Sans | Sdb | A14 | Sdb | A14 | Sdb | Sdb | A14
Por-288 | Etage1 | 2040 | 800 | 0,80×2,04 | 0,80×2,04×0,02 | mur 2cm | D | Por-288 | 1-Projet | Etage1 | 4 | Mur-148 | HAG Acrylic White | 0.036608 | 0.03264 | 4.17895 | 1.632 | 880 | 2080 | 880 | 1.8304 | 1.8304 | 800 | 0 | 0 | 2040 | 1940 | 20 | 0.0372118 | 5750 | 0 | 7830 | 2080 | 5750 | 0 | 0 | 40 | 20 | 15 | 20 | 2 | no | 14.3266 | yes | Réglages rapides | Sans | Sde | B11 | Sde | B11 | Sde | Sde | B11
Por-288 | Etage1 | 2040 | 800 | 0,80×2,04 | 0,80×2,04×0,02 | mur 2cm | G | Por-288 | 1-Projet | Etage1 | 4 | Mur-148 | HAG Acrylic White | 0.036608 | 0.03264 | 4.17895 | 1.632 | 880 | 2080 | 880 | 1.8304 | 1.8304 | 800 | 0 | 0 | 2040 | 1940 | 20 | 0.0372118 | 5750 | 0 | 7830 | 2080 | 5750 | 0 | 0 | 40 | 20 | 15 | 20 | 2 | no | 14.3266 | yes | Réglages rapides | Sans | Sde | A13 | Sde | A13 | Sde | Sde | A13
Por-288 | Etage1 | 2040 | 800 | 0,80×2,04 | 0,80×2,04×0,02 | mur 2cm | G | Por-288 | 1-Projet | Etage1 | 4 | Mur-148 | HAG Acrylic White | 0.036608 | 0.03264 | 4.17895 | 1.632 | 880 | 2080 | 880 | 1.8304 | 1.8304 | 800 | 0 | 0 | 2040 | 1940 | 20 | 0.0372118 | 5750 | 0 | 7830 | 2080 | 5750 | 0 | 0 | 40 | 20 | 15 | 20 | 2 | no | 14.3266 | yes | Réglages rapides | Sans | Sde | A12 | Sde | A12 | Sde | Sde | A12
Por-288 | Etage1 | 2040 | 800 | 0,80×2,04 | 0,80×2,04×0,02 | mur 2cm | G | Por-288 | 1-Projet | Etage1 | 4 | Mur-148 | HAG Acrylic White | 0.036608 | 0.03264 | 4.17895 | 1.632 | 880 | 2080 | 880 | 1.8304 | 1.8304 | 800 | 0 | 0 | 2040 | 1940 | 20 | 0.0372118 | 5750 | 0 | 7830 | 2080 | 5750 | 0 | 0 | 40 | 20 | 15 | 20 | 2 | no | 14.3266 | yes | Réglages rapides | Sans | Sde | A11 | Sde | A11 | Sde | Sde | A11
Por-295 | Etage1 | 2040 | 930 | 0,93×2,04 | 0,93×2,04×0,18 | Beton 18 0018356637 | G | Por-295 | Interieurs logements | Etage1 | 4 | Mur-143 | HAG Acrylic White | 0.378144 | 0.341496 | 6.48965 | 1.8972 | 1010 | 2080 | 1010 | 2.1008 | 2.1008 | 930 | 0 | 0 | 2040 | 1940 | 180 | 0.125102 | 5750 | 0 | 7830 | 2080 | 5750 | 0 | 0 | 40 | 20 | 15 | 40 | 2 | yes | 90 | yes | Réglages rapides | Sur ouvrant | Entree/pl | B13 |  |  | Entree/pl | Entree/pl | B13
Por-295 | Etage1 | 2040 | 930 | 0,93×2,04 | 0,93×2,04×0,18 | Beton 18 0018356637 | D | Por-295 | Interieurs logements | Etage1 | 4 | Mur-143 | HAG Acrylic White | 0.378144 | 0.341496 | 6.48965 | 1.8972 | 1010 | 2080 | 1010 | 2.1008 | 2.1008 | 930 | 0 | 0 | 2040 | 1940 | 180 | 0.125102 | 5750 | 0 | 7830 | 2080 | 5750 | 0 | 0 | 40 | 20 | 15 | 40 | 2 | yes | 90 | yes | Réglages rapides | Sur ouvrant | Entree/pl | B12 |  |  | Entree/pl | Entree/pl | B12
Por-288 | Etage1 | 2040 | 800 | 0,80×2,04 | 0,80×2,04×0,02 | mur 2cm | G | Por-288 | 1-Projet | Etage1 | 4 | Mur-148 | HAG Acrylic White | 0.036608 | 0.03264 | 4.17895 | 1.632 | 880 | 2080 | 880 | 1.8304 | 1.8304 | 800 | 0 | 0 | 2040 | 1940 | 20 | 0.0372118 | 5750 | 0 | 7830 | 2080 | 5750 | 0 | 0 | 40 | 20 | 15 | 20 | 2 | no | 14.3266 | yes | Réglages rapides | Sans | Sde | A15 | Sde | A15 | Sde | Sde | A15
Por-274 | Etage1 | 2040 | 550 | 0,55×2,04 | 0,55×2,04×0,07 | Cloison 70 0826278243 | G | Por-274 | 1-Projet | Etage1 | 4 | Mur-149 | HAG Acrylic White | 0.081795 | 0.07854 | 3.2433 | 1.122 | 570 | 2050 | 570 | 1.1685 | 1.1685 | 550 | 0 | 0 | 2040 | 1940 | 70 | 0.0284705 | 5750 | 0 | 7800 | 2050 | 5750 | 0 | 0 | 10 | 10 | 10 | 20 | 2 | yes | 0 | yes | Cadre et porte | Sans | Sejour cuisine/pl | A11 | Sejour cuisine/pl | A11 | Sejour cuisine/pl | Sejour cuisine/pl | A11
Por-284 | Etage1 | 2040 | 830 | 0,83×2,04 | 0,83×2,04×0,07 | Cloison 70 0826278243 | D | Por-284 | 1-Projet | Etage1 | 4 | Mur-149 | HAG Acrylic White | 0.132496 | 0.118524 | 4.92335 | 1.6932 | 910 | 2080 | 910 | 1.8928 | 1.8928 | 830 | 0 | 0 | 2040 | 1940 | 70 | 0.085966 | 5750 | 0 | 7830 | 2080 | 5750 | 0 | 0 | 40 | 20 | 15 | 40 | 2 | yes | 22.8067 | yes | Réglages rapides | Sur ouvrant | Sejour cuisine/pl | A11 | Ch 1 | A11 | Sejour cuisine/pl | Sejour cuisine/pl | A11
Por-296 | Etage1 | 2040 | 930 | 0,93×2,04 | 0,93×2,04×0,18 | Beton 18 0018356637 | G | Por-296 | Interieurs logements | Etage1 | 4 | Mur-143 | HAG Acrylic White | 0.378144 | 0.341496 | 6.48965 | 1.8972 | 1010 | 2080 | 1010 | 2.1008 | 2.1008 | 930 | 0 | 0 | 2040 | 1940 | 180 | 0.125102 | 5750 | 0 | 7830 | 2080 | 5750 | 0 | 0 | 40 | 20 | 15 | 40 | 2 | yes | 90 | yes | Réglages rapides | Sur ouvrant | Sejour cuisine | B11 |  |  | Sejour cuisine | Sejour cuisine | B11
Por-202 | Etage1 | 2040 | 380 | 0,38×2,04 | 0,38×2,04×0,07 | Cloison 70 0826278243 | D | Por-202 | 3D | Etage1 | 4 | Mur-120 | HAG Acrylic White | 0.0574 | 0.054264 | 2.6091 | 0.7752 | 400 | 2050 | 400 | 0.82 | 0.82 | 380 | 0 | 0 | 2040 | 1940 | 70 | 0.036826 | 5750 | 0 | 7800 | 2050 | 5750 | 0 | 0 | 10 | 10 | 10 | 40 | 2 | yes | 0 | yes | Cadre et porte | Sans
Por-202 | Etage1 | 2040 | 680 | 0,68×2,04 | 0,68×2,04×0,07 | Cloison 70 0826278243 | D | Por-202 | 3D | Etage1 | 4 | Mur-120 | HAG Acrylic White | 0.10045 | 0.097104 | 3.9111 | 1.3872 | 700 | 2050 | 700 | 1.435 | 1.435 | 680 | 0 | 0 | 2040 | 1940 | 70 | 0.061681 | 5750 | 0 | 7800 | 2050 | 5750 | 0 | 0 | 10 | 10 | 10 | 40 | 2 | yes | 0 | yes | Cadre et porte | Sans
Por-202 | Etage1 | 2040 | 450 | 0,45×2,04 | 0,45×2,04×0,07 | Cloison 70 0826278243 | D | Por-202 | 3D | Etage1 | 4 | Mur-120 | HAG Acrylic White | 0.067445 | 0.06426 | 2.9129 | 0.918 | 470 | 2050 | 470 | 0.9635 | 0.9635 | 450 | 0 | 0 | 2040 | 1940 | 70 | 0.0426255 | 5750 | 0 | 7800 | 2050 | 5750 | 0 | 0 | 10 | 10 | 10 | 40 | 2 | yes | 0 | yes | Cadre et porte | Sans
2 x Por-202 | Etage1 | 2040 | 600 | 0,60×2,04 | 0,60×2,04×0,07 | Cloison 70 0826278243 | D | Por-202 | 3D | Etage1 | 4 | Mur-120 | HAG Acrylic White | 0.08897 | 0.08568 | 3.5639 | 1.224 | 620 | 2050 | 620 | 1.271 | 1.271 | 600 | 0 | 0 | 2040 | 1940 | 70 | 0.055053 | 5750 | 0 | 7800 | 2050 | 5750 | 0 | 0 | 10 | 10 | 10 | 40 | 2 | yes | 0 | yes | Cadre et porte | Sans
3 x Por-202 | Etage1 | 2040 | 480 | 0,48×2,04 | 0,48×2,04×0,07 | Cloison 70 0826278243 | D | Por-202 | 3D | Etage1 | 4 | Mur-120 | HAG Acrylic White | 0.07175 | 0.068544 | 3.0431 | 0.9792 | 500 | 2050 | 500 | 1.025 | 1.025 | 480 | 0 | 0 | 2040 | 1940 | 70 | 0.045111 | 5750 | 0 | 7800 | 2050 | 5750 | 0 | 0 | 10 | 10 | 10 | 40 | 2 | yes | 0 | yes | Cadre et porte | Sans
Por-202 | Etage1 | 2040 | 350 | 0,35×2,04 | 0,35×2,04×0,07 | Cloison 70 0826278243 | D | Por-202 | 3D | Etage1 | 4 | Mur-120 | HAG Acrylic White | 0.053095 | 0.04998 | 2.4789 | 0.714 | 370 | 2050 | 370 | 0.7585 | 0.7585 | 350 | 0 | 0 | 2040 | 1940 | 70 | 0.0343405 | 5750 | 0 | 7800 | 2050 | 5750 | 0 | 0 | 10 | 10 | 10 | 40 | 2 | yes | 0 | yes | Cadre et porte | Sans
Por-274 | Etage1 | 2040 | 580 | 0,58×2,04 | 0,58×2,04×0,07 | Cloison 70 0826278243 | D | Por-274 | 1-Projet | Etage1 | 4 | Mur-149 | HAG Acrylic White | 0.0861 | 0.082824 | 3.3723 | 1.1832 | 600 | 2050 | 600 | 1.23 | 1.23 | 580 | 0 | 0 | 2040 | 1940 | 70 | 0.029732 | 5750 | 0 | 7800 | 2050 | 5750 | 0 | 0 | 10 | 10 | 10 | 20 | 2 | yes | 0 | yes | Cadre et porte | Sans | Sejour cuisine | B11 |  |  | Sejour cuisine | Sejour cuisine | B11
Por-279 | Etage1 | 2040 | 930 | 0,93×2,04 | 0,93×2,04×0,18 | Beton 18 0018356637 | D | Por-279 | Interieurs logements | Etage1 | 4 | Mur-142 | HAG Acrylic White | 0.378144 | 0.341496 | 6.48965 | 1.8972 | 1010 | 2080 | 1010 | 2.1008 | 2.1008 | 930 | 0 | 0 | 2040 | 1940 | 180 | 0.125102 | 5750 | 0 | 7830 | 2080 | 5750 | 0 | 0 | 40 | 20 | 15 | 40 | 2 | yes | 90 | yes | Réglages rapides | Sur ouvrant | Sejour cuisine | A13 |  |  | Sejour cuisine | Sejour cuisine | A13
Por-241 | Etage1 | 650 | 450 | 0,45×0,65 | 0,45×0,65×0,18 | Beton 18 0018356637 | D | Por-241 | Interieurs logements | Etage1 | 4 | Mur-142 | HAG Acrylic White | 0.059094 | 0.05265 | 1.39885 | 0.2925 | 490 | 670 | 490 | 0.3283 | 0.3283 | 450 | 300 | 200 | 950 | 850 | 180 | 0.016551 | 6050 | 300 | 6720 | 970 | 6050 | 300 | 300 | 20 | 20 | 15 | 20 | 2 | yes | 0 | no | Réglages rapides | Sans
Por-299 | Etage1 | 2040 | 930 | 0,93×2,04 | 0,93×2,04×0,18 | Beton 18 0018356637 | G | Por-299 | Interieurs logements | Etage1 | 4 | Mur-142 | HAG Acrylic White | 0.378144 | 0.341496 | 6.48965 | 1.8972 | 1010 | 2080 | 1010 | 2.1008 | 2.1008 | 930 | 0 | 0 | 2040 | 1940 | 180 | 0.125102 | 5750 | 0 | 7830 | 2080 | 5750 | 0 | 0 | 40 | 20 | 15 | 40 | 2 | yes | 90 | yes | Réglages rapides | Sur ouvrant | Entree/pl | B15 |  |  | Entree/pl | Entree/pl | B15
Por-276 | Etage1 | 2040 | 830 | 0,83×2,04 | 0,83×2,04×0,07 | Cloison 70 0826278243 | G | Por-276 | 1-Projet | Etage1 | 4 | Mur-149 | HAG Acrylic White | 0.132496 | 0.118524 | 4.92335 | 1.6932 | 910 | 2080 | 910 | 1.8928 | 1.8928 | 830 | 0 | 0 | 2040 | 1940 | 70 | 0.085966 | 5750 | 0 | 7830 | 2080 | 5750 | 0 | 0 | 40 | 20 | 15 | 40 | 2 | yes | 90 | yes | Réglages rapides | Sur ouvrant | Ch 2 | B13 | Entree/pl | B13 | Ch 2 | Ch 2 | B13
Por-275 | Etage1 | 2040 | 830 | 0,83×2,04 | 0,83×2,04×0,07 | Cloison 70 0826278243 | D | Por-275 | 1-Projet | Etage1 | 4 | Mur-149 | HAG Acrylic White | 0.132496 | 0.118524 | 4.92335 | 1.6932 | 910 | 2080 | 910 | 1.8928 | 1.8928 | 830 | 0 | 0 | 2040 | 1940 | 70 | 0.085966 | 5750 | 0 | 7830 | 2080 | 5750 | 0 | 0 | 40 | 20 | 15 | 40 | 2 | yes | 32.4426 | yes | Réglages rapides | Sur ouvrant | Entree/pl | B13 | Ch 1/pl | B13 | Entree/pl | Entree/pl | B13
Por-275 | Etage1 | 2040 | 830 | 0,83×2,04 | 0,83×2,04×0,07 | Cloison 70 0826278243 | G | Por-275 | 1-Projet | Etage1 | 4 | Mur-148 | HAG Acrylic White | 0.132496 | 0.118524 | 4.92335 | 1.6932 | 910 | 2080 | 910 | 1.8928 | 1.8928 | 830 | 0 | 0 | 2040 | 1940 | 70 | 0.085966 | 5750 | 0 | 7830 | 2080 | 5750 | 0 | 0 | 40 | 20 | 15 | 40 | 2 | yes | 90 | yes | Réglages rapides | Sur ouvrant | Ch 1 | A15 | Sejour cuisine/pl | A15 | Ch 1 | Ch 1 | A15
Por-268 | Etage1 | 2040 | 830 | 0,83×2,04 | 0,83×2,04×0,07 | Cloison 70 0826278243 | D | Por-268 | 1-Projet | Etage1 | 4 | Mur-148 | HAG Acrylic White | 0.132496 | 0.118524 | 4.92335 | 1.6932 | 910 | 2080 | 910 | 1.8928 | 1.8928 | 830 | 0 | 0 | 2040 | 1940 | 70 | 0.085966 | 5750 | 0 | 7830 | 2080 | 5750 | 0 | 0 | 40 | 20 | 15 | 40 | 2 | yes | 22.6789 | yes | Réglages rapides | Sur ouvrant | Sejour cuisine/pl | A15 | Wc | A15 | Sejour cuisine/pl | Sejour cuisine/pl | A15
Por-275 | Etage1 | 2040 | 830 | 0,83×2,04 | 0,83×2,04×0,07 | Cloison 70 0826278243 | G | Por-275 | 1-Projet | Etage1 | 4 | Mur-148 | HAG Acrylic White | 0.132228 | 0.118524 | 4.92335 | 1.6932 | 908.162 | 2080 | 908.162 | 1.88898 | 1.88898 | 830 | 0 | 0 | 2040 | 1940 | 70 | 0.085966 | 5750 | 0 | 7830 | 2080 | 5750 | 0 | 0 | 40 | 20 | 15 | 40 | 2 | yes | 34.5955 | yes | Réglages rapides | Sur ouvrant | Ch 1 | A15 | Sde | A15 | Ch 1 | Ch 1 | A15
Por-277 | Etage1 | 2040 | 830 | 0,83×2,04 | 0,83×2,04×0,07 | Cloison 70 0826278243 | G | Por-277 | 1-Projet | Etage1 | 4 | Mur-150 | HAG Acrylic White | 0.132496 | 0.118524 | 4.92335 | 1.6932 | 910 | 2080 | 910 | 1.8928 | 1.8928 | 830 | 0 | 0 | 2040 | 1940 | 70 | 0.085966 | 5750 | 0 | 7830 | 2080 | 5750 | 0 | 0 | 40 | 20 | 15 | 40 | 2 | yes | 21.9195 | yes | Réglages rapides | Sur ouvrant | Entree/pl | B12 | Sde | B12 | Entree/pl | Entree/pl | B12
Por-283 | Etage1 | 2040 | 830 | 0,83×2,04 | 0,83×2,04×0,07 | Cloison 70 0826278243 | D | Por-283 | 1-Projet | Etage1 | 4 | Mur-153 | HAG Acrylic White | 0.132496 | 0.118524 | 4.92335 | 1.6932 | 910 | 2080 | 910 | 1.8928 | 1.8928 | 830 | 0 | 0 | 2040 | 1940 | 70 | 0.085966 | 5750 | 0 | 7830 | 2080 | 5750 | 0 | 0 | 40 | 20 | 15 | 40 | 2 | yes | 24.4794 | yes | Réglages rapides | Sur ouvrant | Sejour Cuisine/pl | A14 | Wc | A14 | Sejour Cuisine/pl | Sejour Cuisine/pl | A14
Por-283 | Etage1 | 2040 | 830 | 0,83×2,04 | 0,83×2,04×0,07 | Cloison 70 0826278243 | D | Por-283 | 1-Projet | Etage1 | 4 | Mur-153 | HAG Acrylic White | 0.132496 | 0.118524 | 4.92335 | 1.6932 | 910 | 2080 | 910 | 1.8928 | 1.8928 | 830 | 0 | 0 | 2040 | 1940 | 70 | 0.085966 | 5750 | 0 | 7830 | 2080 | 5750 | 0 | 0 | 40 | 20 | 15 | 40 | 2 | yes | 24.4794 | yes | Réglages rapides | Sur ouvrant | Dgt | A14 | Cellier | A14 | Dgt | Dgt | A14
Por-280 | Etage1 | 2040 | 830 | 0,83×2,04 | 0,83×2,04×0,07 | Cloison 70 0826278243 | D | Por-280 | 1-Projet | Etage1 | 4 | Mur-149 | HAG Acrylic White | 0.132496 | 0.118524 | 4.92335 | 1.6932 | 910 | 2080 | 910 | 1.8928 | 1.8928 | 830 | 0 | 0 | 2040 | 1940 | 70 | 0.085966 | 5750 | 0 | 7830 | 2080 | 5750 | 0 | 0 | 40 | 20 | 15 | 40 | 2 | yes | 21.6784 | yes | Réglages rapides | Sur ouvrant | Entree/pl | A12 | Sde | A12 | Entree/pl | Entree/pl | A12
Por-276 | Etage1 | 2040 | 580 | 0,58×2,04 | 0,58×2,04×0,07 | Cloison 70 0826278243 | G | Por-276 | 1-Projet | Etage1 | 4 | Mur-150 | HAG Acrylic White | 0.0861 | 0.082824 | 3.3723 | 1.1832 | 600 | 2050 | 600 | 1.23 | 1.23 | 580 | 0 | 0 | 2040 | 1940 | 70 | 0.029732 | 5750 | 0 | 7800 | 2050 | 5750 | 0 | 0 | 10 | 10 | 10 | 20 | 2 | yes | 0 | yes | Cadre et porte | Sans | Entree/pl | B12 |  |  | Entree/pl | Entree/pl | B12
Por-278 | Etage1 | 2040 | 830 | 0,83×2,04 | 0,83×2,04×0,07 | Cloison 70 0826278243 | G | Por-278 | 1-Projet | Etage1 | 4 | Mur-149 | HAG Acrylic White | 0.132496 | 0.118524 | 4.92335 | 1.6932 | 910 | 2080 | 910 | 1.8928 | 1.8928 | 830 | 0 | 0 | 2040 | 1940 | 70 | 0.085966 | 5750 | 0 | 7830 | 2080 | 5750 | 0 | 0 | 40 | 20 | 15 | 40 | 2 | yes | 20.2897 | yes | Réglages rapides | Sur ouvrant | Sejour cuisine | A12 | Cellier | A12 | Sejour cuisine | Sejour cuisine | A12
Por-280 | Etage1 | 2040 | 830 | 0,83×2,04 | 0,83×2,04×0,07 | Cloison 70 0826278243 | D | Por-280 | 1-Projet | Etage1 | 4 | Mur-149 | HAG Acrylic White | 0.132496 | 0.118524 | 4.92335 | 1.6932 | 910 | 2080 | 910 | 1.8928 | 1.8928 | 830 | 0 | 0 | 2040 | 1940 | 70 | 0.085966 | 5750 | 0 | 7830 | 2080 | 5750 | 0 | 0 | 40 | 20 | 15 | 40 | 2 | yes | 90 | yes | Réglages rapides | Sur ouvrant | Ch 2 | A12 | Entree/pl | A12 | Ch 2 | Ch 2 | A12
Por-274 | Etage1 | 2040 | 580 | 0,58×2,04 | 0,58×2,04×0,07 | Cloison 70 0826278243 | G | Por-274 | 1-Projet | Etage1 | 4 | Mur-149 | HAG Acrylic White | 0.0861 | 0.082824 | 3.3723 | 1.1832 | 600 | 2050 | 600 | 1.23 | 1.23 | 580 | 0 | 0 | 2040 | 1940 | 70 | 0.029732 | 5750 | 0 | 7800 | 2050 | 5750 | 0 | 0 | 10 | 10 | 10 | 20 | 2 | yes | 0 | yes | Cadre et porte | Sans | Entree/pl | B16 |  |  | Entree/pl | Entree/pl | B16
Por-284 | Etage1 | 2040 | 830 | 0,83×2,04 | 0,83×2,04×0,07 | Cloison 70 0826278243 | G | Por-284 | 1-Projet | Etage1 | 4 | Mur-149 | HAG Acrylic White | 0.132496 | 0.118524 | 4.92335 | 1.6932 | 910 | 2080 | 910 | 1.8928 | 1.8928 | 830 | 0 | 0 | 2040 | 1940 | 70 | 0.085966 | 5750 | 0 | 7830 | 2080 | 5750 | 0 | 0 | 40 | 20 | 15 | 40 | 2 | yes | 22.6789 | yes | Réglages rapides | Sur ouvrant | Entree/pl | B14 | Cellier | B14 | Entree/pl | Entree/pl | B14
Por-278 | Etage1 | 2040 | 830 | 0,83×2,04 | 0,83×2,04×0,07 | Cloison 70 0826278243 | G | Por-278 | 1-Projet | Etage1 | 4 | Mur-149 | HAG Acrylic White | 0.132496 | 0.118524 | 4.92335 | 1.6932 | 910 | 2080 | 910 | 1.8928 | 1.8928 | 830 | 520 | 420 | 2560 | 2460 | 70 | 0.085966 | 6270 | 520 | 8350 | 2600 | 6270 | 520 | 520 | 40 | 20 | 15 | 40 | 2 | yes | 22.6789 | yes | Réglages rapides | Sur ouvrant | Entree/pl | B16 | Sde | B16 | Entree/pl | Entree/pl | B16
Por-274 | Etage1 | 2040 | 580 | 0,58×2,04 | 0,58×2,04×0,07 | Cloison 70 0826278243 | G | Por-274 | 1-Projet | Etage1 | 4 | Mur-149 | HAG Acrylic White | 0.0795621 | 0.082824 | 3.3723 | 1.1832 | 554.44 | 2050 | 554.44 | 1.1366 | 1.1366 | 580 | 0 | 0 | 2040 | 1940 | 70 | 0.029732 | 5750 | 0 | 7800 | 2050 | 5750 | 0 | 0 | 10 | 10 | 10 | 20 | 2 | yes | 0 | yes | Cadre et porte | Sans | Sejour cuisine | B15 | Sejour cuisine | B15 | Sejour cuisine
Por-279 | Etage1 | 2040 | 930 | 0,93×2,04 | 0,93×2,04×0,18 | Beton 18 0018356637 | G | Por-279 | Interieurs logements | Etage1 | 4 | Mur-143 | HAG Acrylic White | 0.378144 | 0.341496 | 6.48965 | 1.8972 | 1010 | 2080 | 1010 | 2.1008 | 2.1008 | 930 | 0 | 0 | 2040 | 1940 | 180 | 0.125102 | 5750 | 0 | 7830 | 2080 | 5750 | 0 | 0 | 40 | 20 | 15 | 40 | 2 | yes | 90 | yes | Réglages rapides | Sur ouvrant | Sejour cuisine/pl | A15 |  |  | Sejour cuisine/pl | Sejour cuisine/pl | A15
Por-276 | Etage1 | 2040 | 830 | 0,83×2,04 | 0,83×2,04×0,07 | Cloison 70 0826278243 | G | Por-276 | 1-Projet | Etage1 | 4 | Mur-149 | HAG Acrylic White | 0.132496 | 0.118524 | 4.92335 | 1.6932 | 910 | 2080 | 910 | 1.8928 | 1.8928 | 830 | 0 | 0 | 2040 | 1940 | 70 | 0.085966 | 5750 | 0 | 7830 | 2080 | 5750 | 0 | 0 | 40 | 20 | 15 | 40 | 2 | yes | 89.9641 | yes | Réglages rapides | Sur ouvrant | Ch 2 | B16 | Entree/pl | B16 | Ch 2 | Ch 2 | B16
Por-275 | Etage1 | 2040 | 830 | 0,83×2,04 | 0,83×2,04×0,07 | Cloison 70 0826278243 | D | Por-275 | 1-Projet | Etage1 | 4 | Mur-149 | HAG Acrylic White | 0.132496 | 0.118524 | 4.92335 | 1.6932 | 910 | 2080 | 910 | 1.8928 | 1.8928 | 830 | 0 | 0 | 2040 | 1940 | 70 | 0.085966 | 5750 | 0 | 7830 | 2080 | 5750 | 0 | 0 | 40 | 20 | 15 | 40 | 2 | yes | 66.6058 | yes | Réglages rapides | Sur ouvrant | Entree/pl | B16 | Ch 1/pl | B16 | Entree/pl | Entree/pl | B16
Por-274 | Etage1 | 2040 | 580 | 0,58×2,04 | 0,58×2,04×0,07 | Cloison 70 0826278243 | G | Por-274 | 1-Projet | Etage1 | 4 | Mur-149 | HAG Acrylic White | 0.0861 | 0.082824 | 3.3723 | 1.1832 | 600 | 2050 | 600 | 1.23 | 1.23 | 580 | 0 | 0 | 2040 | 1940 | 70 | 0.029732 | 5750 | 0 | 7800 | 2050 | 5750 | 0 | 0 | 10 | 10 | 10 | 20 | 2 | yes | 0 | yes | Cadre et porte | Sans | Entree/pl | B15 |  |  | Entree/pl | Entree/pl | B15
Por-279 | Etage1 | 2040 | 830 | 0,83×2,04 | 0,83×2,04×0,07 | Cloison 70 0826278243 | G | Por-279 | 1-Projet | Etage1 | 4 | Mur-153 | HAG Acrylic White | 0.132496 | 0.118524 | 4.92335 | 1.6932 | 910 | 2080 | 910 | 1.8928 | 1.8928 | 830 | 0 | 0 | 2040 | 1940 | 70 | 0.085966 | 5750 | 0 | 7830 | 2080 | 5750 | 0 | 0 | 40 | 20 | 15 | 40 | 2 | yes | 90.0431 | yes | Réglages rapides | Sur ouvrant | Sejour cuisine | A13 | Sejour cuisine | A13 | Ch 1
Por-278 | Etage1 | 2040 | 830 | 0,83×2,04 | 0,83×2,04×0,07 | Cloison 70 0826278243 | G | Por-278 | 1-Projet | Etage1 | 4 | Mur-151 | HAG Acrylic White | 0.132496 | 0.118524 | 4.92335 | 1.6932 | 910 | 2080 | 910 | 1.8928 | 1.8928 | 830 | 0 | 0 | 2040 | 1940 | 70 | 0.085966 | 5750 | 0 | 7830 | 2080 | 5750 | 0 | 0 | 40 | 20 | 15 | 40 | 2 | yes | 29.5716 | yes | Réglages rapides | Sur ouvrant | Ch 1 | A13 | Ch 1 | A13 | Ch 1 | Ch 1 | A13
Por-293 | Etage1 | 2040 | 830 | 0,83×2,04 | 0,83×2,04×0,07 | Cloison 70 0826278243 | D | Por-293 | 1-Projet | Etage1 | 4 | Mur-149 | HAG Acrylic White | 0.132496 | 0.118524 | 4.92335 | 1.6932 | 910 | 2080 | 910 | 1.8928 | 1.8928 | 830 | 0 | 0 | 2040 | 1940 | 70 | 0.085966 | 5750 | 0 | 7830 | 2080 | 5750 | 0 | 0 | 40 | 20 | 15 | 40 | 2 | yes | 27.1745 | yes | Réglages rapides | Sur ouvrant | Ch 1 | B11 | Sde | B11 | Ch 1 | Ch 1 | B11
Por-283 | Etage1 | 2040 | 830 | 0,83×2,04 | 0,83×2,04×0,07 | Cloison 70 0826278243 | G | Por-283 | 1-Projet | Etage1 | 4 | Mur-149 | HAG Acrylic White | 0.132496 | 0.118524 | 4.92335 | 1.6932 | 910 | 2080 | 910 | 1.8928 | 1.8928 | 830 | 0 | 0 | 2040 | 1940 | 70 | 0.085966 | 5750 | 0 | 7830 | 2080 | 5750 | 0 | 0 | 40 | 20 | 15 | 40 | 2 | yes | 22.6789 | yes | Réglages rapides | Sur ouvrant | Wc | B14 | Wc | B14 | Entree/pl; Wc | Wc | B14
Por-274 | Etage1 | 2040 | 580 | 0,58×2,04 | 0,58×2,04×0,07 | Cloison 70 0826278243 | D | Por-274 | 1-Projet | Etage1 | 4 | Mur-149 | HAG Acrylic White | 0.0861 | 0.082824 | 3.3723 | 1.1832 | 600 | 2050 | 600 | 1.23 | 1.23 | 580 | 0 | 0 | 2040 | 1940 | 70 | 0.029732 | 5750 | 0 | 7800 | 2050 | 5750 | 0 | 0 | 10 | 10 | 10 | 20 | 2 | yes | 0 | yes | Cadre et porte | Sans | Sejour cuisine | B14 | Sejour cuisine | B14 | Sejour cuisine | Sejour cuisine | B14
Por-282 | Etage1 | 2040 | 830 | 0,83×2,04 | 0,83×2,04×0,07 | Cloison 70 0826278243 | D | Por-282 | 1-Projet | Etage1 | 4 | Mur-149 | HAG Acrylic White | 0.132496 | 0.118524 | 4.92335 | 1.6932 | 910 | 2080 | 910 | 1.8928 | 1.8928 | 830 | 0 | 0 | 2040 | 1940 | 70 | 0.085966 | 5750 | 0 | 7830 | 2080 | 5750 | 0 | 0 | 40 | 20 | 15 | 40 | 2 | yes | 90 | yes | Réglages rapides | Sur ouvrant | Ch 2 | B15 | Ch 2 | B15 | Ch 2 | Ch 2 | B15
Por-283 | Etage1 | 2040 | 830 | 0,83×2,04 | 0,83×2,04×0,07 | Cloison 70 0826278243 | G | Por-283 | 1-Projet | Etage1 | 4 | Mur-149 | HAG Acrylic White | 0.132496 | 0.118524 | 4.92335 | 1.6932 | 910 | 2080 | 910 | 1.8928 | 1.8928 | 830 | 0 | 0 | 2040 | 1940 | 70 | 0.085966 | 5750 | 0 | 7830 | 2080 | 5750 | 0 | 0 | 40 | 20 | 15 | 40 | 2 | yes | 30.0872 | yes | Réglages rapides | Sur ouvrant | Cellier | B15 | Cellier | B15 | Dgt
Por-281 | Etage1 | 2040 | 830 | 0,83×2,04 | 0,83×2,04×0,07 | Cloison 70 0826278243 | D | Por-281 | 1-Projet | Etage1 | 4 | Mur-149 | HAG Acrylic White | 0.132496 | 0.118524 | 4.92335 | 1.6932 | 910 | 2080 | 910 | 1.8928 | 1.8928 | 830 | 0 | 0 | 2040 | 1940 | 70 | 0.085966 | 5750 | 0 | 7830 | 2080 | 5750 | 0 | 0 | 40 | 20 | 15 | 40 | 2 | yes | 90 | yes | Réglages rapides | Sur ouvrant | Ch 3 | B15 | Entree/pl | B15 | Ch 3 | Ch 3 | B15
Por-280 | Etage1 | 2040 | 830 | 0,83×2,04 | 0,83×2,04×0,07 | Cloison 70 0826278243 | G | Por-280 | 1-Projet | Etage1 | 4 | Mur-149 | HAG Acrylic White | 0.132496 | 0.118524 | 4.92335 | 1.6932 | 910 | 2080 | 910 | 1.8928 | 1.8928 | 830 | 0 | 0 | 2040 | 1940 | 70 | 0.085966 | 5750 | 0 | 7830 | 2080 | 5750 | 0 | 0 | 40 | 20 | 15 | 40 | 2 | yes | 33.4203 | yes | Réglages rapides | Sur ouvrant | Entree/pl | B15 | Wc | B15 | Entree/pl | Entree/pl | B15
Por-274 | Etage1 | 2040 | 580 | 0,58×2,04 | 0,58×2,04×0,07 | Cloison 70 0826278243 | D | Por-274 | 1-Projet | Etage1 | 4 | Mur-149 | HAG Acrylic White | 0.0861 | 0.082824 | 3.3723 | 1.1832 | 600 | 2050 | 600 | 1.23 | 1.23 | 580 | 0 | 0 | 2040 | 1940 | 70 | 0.029732 | 5750 | 0 | 7800 | 2050 | 5750 | 0 | 0 | 10 | 10 | 10 | 20 | 2 | yes | 0 | yes | Cadre et porte | Sans | Entree/pl | A12 |  |  | Entree/pl | Entree/pl | A12
Por-281 | Etage1 | 2040 | 830 | 0,83×2,04 | 0,83×2,04×0,07 | Cloison 70 0826278243 | G | Por-281 | 1-Projet | Etage1 | 4 | Mur-149 | HAG Acrylic White | 0.132496 | 0.118524 | 4.92335 | 1.6932 | 910 | 2080 | 910 | 1.8928 | 1.8928 | 830 | 0 | 0 | 2040 | 1940 | 70 | 0.085966 | 5750 | 0 | 7830 | 2080 | 5750 | 0 | 0 | 40 | 20 | 15 | 40 | 2 | yes | 27.0064 | yes | Réglages rapides | Sur ouvrant | Entree/pl | A12 | Wc | A12 | Entree/pl | Entree/pl | A12
Por-274 | Etage1 | 2040 | 580 | 0,58×2,04 | 0,58×2,04×0,07 | Cloison 70 0826278243 | G | Por-274 | 1-Projet | Etage1 | 4 | Mur-149 | HAG Acrylic White | 0.0861 | 0.082824 | 3.3723 | 1.1832 | 600 | 2050 | 600 | 1.23 | 1.23 | 580 | 0 | 0 | 2040 | 1940 | 70 | 0.029732 | 5750 | 0 | 7800 | 2050 | 5750 | 0 | 0 | 10 | 10 | 10 | 20 | 2 | yes | 0 | yes | Cadre et porte | Sans | Entree | A11 |  |  | Entree | Entree | A11
Por-278 | Etage1 | 2040 | 830 | 0,83×2,04 | 0,83×2,04×0,07 | Cloison 70 0826278243 | G | Por-278 | 1-Projet | Etage1 | 4 | Mur-149 | HAG Acrylic White | 0.132496 | 0.118524 | 4.92335 | 1.6932 | 910 | 2080 | 910 | 1.8928 | 1.8928 | 830 | 0 | 0 | 2040 | 1940 | 70 | 0.085966 | 5750 | 0 | 7830 | 2080 | 5750 | 0 | 0 | 40 | 20 | 15 | 40 | 2 | yes | 22.6789 | yes | Réglages rapides | Sur ouvrant | Entree/pl | B16 | Wc | B16 | Entree/pl | Entree/pl | B16
Por-274 | Etage1 | 2040 | 580 | 0,58×2,04 | 0,58×2,04×0,07 | Cloison 70 0836576958 | G | Por-274 | 1-Projet | Etage1 | 4 | Mur-148 | HAG Acrylic White | 0.0861 | 0.082824 | 3.3723 | 1.1832 | 600 | 2050 | 600 | 1.23 | 1.23 | 580 | 0 | 0 | 2040 | 1940 | 70 | 0.029732 | 5750 | 0 | 7800 | 2050 | 5750 | 0 | 0 | 10 | 10 | 10 | 20 | 2 | yes | 0 | yes | Cadre et porte | Sans | Dgt | A14 |  |  | Dgt | Dgt | A14
Por-274 | Etage1 | 2040 | 580 | 0,58×2,04 | 0,58×2,04×0,07 | Cloison 70 0826278243 | G | Por-274 | 1-Projet | Etage1 | 4 | Mur-149 | HAG Acrylic White | 0.08323 | 0.082824 | 3.3723 | 1.1832 | 580 | 2050 | 580 | 1.189 | 1.189 | 580 | 0 | 0 | 2040 | 1940 | 70 | 0.029732 | 5750 | 0 | 7800 | 2050 | 5750 | 0 | 0 | 10 | 10 | 10 | 20 | 2 | yes | 0 | yes | Cadre et porte | Sans | Sejour cuisine | B14 | Sejour cuisine | B14 | Sejour cuisine | Sejour cuisine | B14
2 x Por-202 | Etage1 | 2040 | 580 | 0,58×2,04 | 0,58×2,04×0,07 | Cloison 70 0826278243 | D | Por-202 | 3D | Etage1 | 4 | Mur-120 | HAG Acrylic White | 0.0861 | 0.082824 | 3.4771 | 1.1832 | 600 | 2050 | 600 | 1.23 | 1.23 | 580 | 0 | 0 | 2040 | 1940 | 70 | 0.053396 | 5750 | 0 | 7800 | 2050 | 5750 | 0 | 0 | 10 | 10 | 10 | 40 | 2 | yes | 0 | yes | Cadre et porte | Sans
Por-202 | Etage1 | 2040 | 630 | 0,63×2,04 | 0,63×2,04×0,07 | Cloison 70 0826278243 | D | Por-202 | 3D | Etage1 | 4 | Mur-120 | HAG Acrylic White | 0.093275 | 0.089964 | 3.6941 | 1.2852 | 650 | 2050 | 650 | 1.3325 | 1.3325 | 630 | 0 | 0 | 2040 | 1940 | 70 | 0.0575385 | 5750 | 0 | 7800 | 2050 | 5750 | 0 | 0 | 10 | 10 | 10 | 40 | 2 | yes | 0 | yes | Cadre et porte | Sans
Por-275 | Etage1 | 2040 | 450 | 0,45×2,04 | 0,45×2,04×0,07 | Cloison 70 0836576958 | G | Por-275 | 1-Projet | Etage1 | 4 | Mur-148 | HAG Acrylic White | 0.0648009 | 0.06426 | 2.8133 | 0.918 | 451.574 | 2050 | 451.574 | 0.925727 | 0.925727 | 450 | 0 | 0 | 2040 | 1940 | 70 | 0.0242655 | 5750 | 0 | 7800 | 2050 | 5750 | 0 | 0 | 10 | 10 | 10 | 20 | 2 | yes | 0 | yes | Cadre et porte | Sans | Sejour cuisine | B16 | Sejour cuisine | B16 | Sejour cuisine
Por-281 | Etage1 | 2040 | 830 | 0,83×2,04 | 0,83×2,04×0,07 | Cloison 70 0826278243 | D | Por-281 | 1-Projet | Etage1 | 4 | Mur-149 | HAG Acrylic White | 0.132496 | 0.118524 | 4.92335 | 1.6932 | 910 | 2080 | 910 | 1.8928 | 1.8928 | 830 | 0 | 0 | 2040 | 1940 | 70 | 0.085966 | 5750 | 0 | 7830 | 2080 | 5750 | 0 | 0 | 40 | 20 | 15 | 40 | 2 | yes | 90 | yes | Réglages rapides | Sur ouvrant | Ch 1/pl | B15 | Dgt | B15 | Ch 1/pl | Ch 1/pl | B15
Por-282 | Etage1 | 2040 | 830 | 0,83×2,04 | 0,83×2,04×0,07 | Cloison 70 0826278243 | G | Por-282 | 1-Projet | Etage1 | 4 | Mur-149 | HAG Acrylic White | 0.132496 | 0.118524 | 4.92335 | 1.6932 | 910 | 2080 | 910 | 1.8928 | 1.8928 | 830 | 0 | 0 | 2040 | 1940 | 70 | 0.085966 | 5750 | 0 | 7830 | 2080 | 5750 | 0 | 0 | 40 | 20 | 15 | 40 | 2 | yes | 90 | yes | Réglages rapides | Sur ouvrant | Sde | B15 | Dgt | B15 | Sde | Sde | B15
Por-278 | Etage1 | 2040 | 830 | 0,83×2,04 | 0,83×2,04×0,07 | Cloison 70 0826278243 | D | Por-278 | 1-Projet | Etage1 | 4 | Mur-149 | HAG Acrylic White | 0.132496 | 0.118524 | 4.92335 | 1.6932 | 910 | 2080 | 910 | 1.8928 | 1.8928 | 830 | 0 | 0 | 2040 | 1940 | 70 | 0.085966 | 5750 | 0 | 7830 | 2080 | 5750 | 0 | 0 | 40 | 20 | 15 | 40 | 2 | yes | 90 | yes | Réglages rapides | Sur ouvrant | Ch 1/pl | B14 | Entree/pl | B14 | Ch 1/pl | Ch 1/pl | B14
Por-279 | Etage1 | 2040 | 830 | 0,83×2,04 | 0,83×2,04×0,07 | Cloison 70 0826278243 | G | Por-279 | 1-Projet | Etage1 | 4 | Mur-149 | HAG Acrylic White | 0.132496 | 0.118524 | 4.92335 | 1.6932 | 910 | 2080 | 910 | 1.8928 | 1.8928 | 830 | 0 | 0 | 2040 | 1940 | 70 | 0.085966 | 5750 | 0 | 7830 | 2080 | 5750 | 0 | 0 | 40 | 20 | 15 | 40 | 2 | yes | 90 | yes | Réglages rapides | Sur ouvrant | Ch 2/pl | B14 | Entree/pl | B14 | Ch 2/pl | Ch 2/pl | B14
Por-281 | Etage1 | 2040 | 830 | 0,83×2,04 | 0,83×2,04×0,07 | Cloison 70 0826278243 | G | Por-281 | 1-Projet | Etage1 | 4 | Mur-149 | HAG Acrylic White | 0.132496 | 0.118524 | 4.92335 | 1.6932 | 910 | 2080 | 910 | 1.8928 | 1.8928 | 830 | 0 | 0 | 2040 | 1940 | 70 | 0.085966 | 5750 | 0 | 7830 | 2080 | 5750 | 0 | 0 | 40 | 20 | 15 | 40 | 2 | yes | 90 | yes | Réglages rapides | Sur ouvrant | Ch 3 | B14 | Entree/pl | B14 | Ch 3 | Ch 3 | B14
Por-249 | Etage1 | 650 | 450 | 0,45×0,65 | 0,45×0,65×0,07 | Cloison 70 0826278243 | D | Por-249 | 1-Projet | Etage1 | 4 | Mur-148 | HAG Acrylic White | 0.022981 | 0.020475 | 1.00395 | 0.2925 | 490 | 670 | 490 | 0.3283 | 0.3283 | 450 | 300 | 200 | 950 | 850 | 70 | 0.009775 | 6050 | 300 | 6720 | 970 | 6050 | 300 | 300 | 20 | 20 | 15 | 20 | 2 | yes | 0 | no | Réglages rapides | Sans | Sde | A12 | Sde | A12 | Sde | Sde | A12
Por-281 | Etage 2 | 2040 | 930 | 0,93×2,04 | 0,93×2,04×0,18 | Beton 18 0018356637 | D | Por-281 | Interieurs logements | Etage 2 | 5 | Mur-143 | HAG Acrylic White | 0.378144 | 0.341496 | 6.48965 | 1.8972 | 1010 | 2080 | 1010 | 2.1008 | 2.1008 | 930 | 0 | 0 | 2040 | 1940 | 180 | 0.125102 | 8500 | 0 | 10580 | 2080 | 8500 | 0 | 0 | 40 | 20 | 15 | 40 | 2 | yes | 90 | yes | Réglages rapides | Sur ouvrant
Por-280 | Etage 2 | 2040 | 830 | 0,83×2,04 | 0,83×2,04×0,07 | Cloison 70 0826278243 | D | Por-280 | 1-Projet | Etage 2 | 5 | Mur-149 | HAG Acrylic White | 0.132496 | 0.118524 | 4.92335 | 1.6932 | 910 | 2080 | 910 | 1.8928 | 1.8928 | 830 | 0 | 0 | 2040 | 1940 | 70 | 0.085966 | 8500 | 0 | 10580 | 2080 | 8500 | 0 | 0 | 40 | 20 | 15 | 40 | 2 | yes | 43.4643 | yes | Réglages rapides | Sur ouvrant | Entree/pl | B24 |  |  | Entree/pl | Entree/pl | B24
Por-279 | Etage 2 | 2040 | 930 | 0,93×2,04 | 0,93×2,04×0,18 | Beton 18 0018356637 | D | Por-279 | Interieurs logements | Etage 2 | 5 | Mur-143 | HAG Acrylic White | 0.378144 | 0.341496 | 6.48965 | 1.8972 | 1010 | 2080 | 1010 | 2.1008 | 2.1008 | 930 | 0 | 0 | 2040 | 1940 | 180 | 0.125102 | 8500 | 0 | 10580 | 2080 | 8500 | 0 | 0 | 40 | 20 | 15 | 40 | 2 | yes | 90 | yes | Réglages rapides | Sur ouvrant | Entree/pl | A22 |  |  | Entree/pl | Entree/pl | A22
Por-279 | Etage 2 | 2040 | 830 | 0,83×2,04 | 0,83×2,04×0,07 | Cloison 70 0826278243 | G | Por-279 | 1-Projet | Etage 2 | 5 | Mur-149 | HAG Acrylic White | 0.132496 | 0.118524 | 4.92335 | 1.6932 | 910 | 2080 | 910 | 1.8928 | 1.8928 | 830 | 0 | 0 | 2040 | 1940 | 70 | 0.085966 | 8500 | 0 | 10580 | 2080 | 8500 | 0 | 0 | 40 | 20 | 15 | 40 | 2 | yes | 90 | yes | Réglages rapides | Sur ouvrant | Ch 2/pl | B24 | Entree/pl | B24 | Ch 2/pl | Ch 2/pl | B24
Por-278 | Etage 2 | 2040 | 830 | 0,83×2,04 | 0,83×2,04×0,07 | Cloison 70 0826278243 | D | Por-278 | 1-Projet | Etage 2 | 5 | Mur-149 | HAG Acrylic White | 0.132496 | 0.118524 | 4.92335 | 1.6932 | 910 | 2080 | 910 | 1.8928 | 1.8928 | 830 | 0 | 0 | 2040 | 1940 | 70 | 0.085966 | 8500 | 0 | 10580 | 2080 | 8500 | 0 | 0 | 40 | 20 | 15 | 40 | 2 | yes | 90 | yes | Réglages rapides | Sur ouvrant | Ch 1/pl | B24 | Entree/pl | B24 | Ch 1/pl | Ch 1/pl | B24
Por-281 | Etage 2 | 2040 | 830 | 0,83×2,04 | 0,83×2,04×0,07 | Cloison 70 0826278243 | G | Por-281 | 1-Projet | Etage 2 | 5 | Mur-149 | HAG Acrylic White | 0.132496 | 0.118524 | 4.92335 | 1.6932 | 910 | 2080 | 910 | 1.8928 | 1.8928 | 830 | 0 | 0 | 2040 | 1940 | 70 | 0.085966 | 8500 | 0 | 10580 | 2080 | 8500 | 0 | 0 | 40 | 20 | 15 | 40 | 2 | yes | 22.6789 | yes | Réglages rapides | Sur ouvrant | Ch 3 | B24 | Entree/pl | B24 | Ch 3 | Ch 3 | B24
Por-284 | Etage 2 | 2040 | 830 | 0,83×2,04 | 0,83×2,04×0,07 | Cloison 70 0826278243 | D | Por-284 | 1-Projet | Etage 2 | 5 | Mur-149 | HAG Acrylic White | 0.132496 | 0.118524 | 4.92335 | 1.6932 | 910 | 2080 | 910 | 1.8928 | 1.8928 | 830 | 0 | 0 | 2040 | 1940 | 70 | 0.085966 | 8500 | 0 | 10580 | 2080 | 8500 | 0 | 0 | 40 | 20 | 15 | 40 | 2 | yes | 22.8067 | yes | Réglages rapides | Sur ouvrant | Sejour cuisine/pl | A21 | Ch 1/pl | A21 | Sejour cuisine/pl | Sejour cuisine/pl | A21
Por-296 | Etage 2 | 2040 | 930 | 0,93×2,04 | 0,93×2,04×0,18 | Beton 18 0018356637 | G | Por-296 | Interieurs logements | Etage 2 | 5 | Mur-143 | HAG Acrylic White | 0.378144 | 0.341496 | 6.48965 | 1.8972 | 1010 | 2080 | 1010 | 2.1008 | 2.1008 | 930 | 0 | 0 | 2040 | 1940 | 180 | 0.125102 | 8500 | 0 | 10580 | 2080 | 8500 | 0 | 0 | 40 | 20 | 15 | 40 | 2 | yes | 90 | yes | Réglages rapides | Sur ouvrant | Sejour cuisine | B21 |  |  | Sejour cuisine | Sejour cuisine | B21
Por-278 | Etage 2 | 2040 | 830 | 0,83×2,04 | 0,83×2,04×0,07 | Cloison 70 0826278243 | G | Por-278 | 1-Projet | Etage 2 | 5 | Mur-149 | HAG Acrylic White | 0.132496 | 0.118524 | 4.92335 | 1.6932 | 910 | 2080 | 910 | 1.8928 | 1.8928 | 830 | 0 | 0 | 2040 | 1940 | 70 | 0.085966 | 8500 | 0 | 10580 | 2080 | 8500 | 0 | 0 | 40 | 20 | 15 | 40 | 2 | yes | 22.6789 | yes | Réglages rapides | Sur ouvrant | Entree/Pl | B26 | Wc | B26 | Entree/Pl | Entree/Pl | B26
Por-279 | Etage 2 | 2040 | 930 | 0,93×2,04 | 0,93×2,04×0,28 | isol int 18+10 0018356637 | D | Por-279 | Interieurs logements | Etage 2 | 5 | Mur-142 | HAG Acrylic White | 0.588224 | 0.531216 | 7.51265 | 1.8972 | 1010 | 2080 | 1010 | 2.1008 | 2.1008 | 930 | 0 | 0 | 2040 | 1940 | 280 | 0.152932 | 8500 | 0 | 10580 | 2080 | 8500 | 0 | 0 | 40 | 20 | 15 | 40 | 2 | yes | 90 | yes | Réglages rapides | Sur ouvrant | Entree | A21 |  |  | Entree | Entree | A21
Por-280 | Etage 2 | 2040 | 830 | 0,83×2,04 | 0,83×2,04×0,07 | Cloison 70 0826278243 | D | Por-280 | 1-Projet | Etage 2 | 5 | Mur-149 | HAG Acrylic White | 0.132496 | 0.118524 | 4.92335 | 1.6932 | 910 | 2080 | 910 | 1.8928 | 1.8928 | 830 | 0 | 0 | 2040 | 1940 | 70 | 0.085966 | 8500 | 0 | 10580 | 2080 | 8500 | 0 | 0 | 40 | 20 | 15 | 40 | 2 | yes | 90 | yes | Réglages rapides | Sur ouvrant | Ch 2 | A22 | Entree/pl | A22 | Ch 2 | Ch 2 | A22
Por-278 | Etage 2 | 2040 | 830 | 0,83×2,04 | 0,83×2,04×0,07 | Cloison 70 0826278243 | G | Por-278 | 1-Projet | Etage 2 | 5 | Mur-149 | HAG Acrylic White | 0.132496 | 0.118524 | 4.92335 | 1.6932 | 910 | 2080 | 910 | 1.8928 | 1.8928 | 830 | 0 | 0 | 2040 | 1940 | 70 | 0.085966 | 8500 | 0 | 10580 | 2080 | 8500 | 0 | 0 | 40 | 20 | 15 | 40 | 2 | yes | 20.2897 | yes | Réglages rapides | Sur ouvrant | Sejour cuisine | A22 | Cellier | A22 | Sejour cuisine | Sejour cuisine | A22
Por-278 | Etage 2 | 2040 | 830 | 0,83×2,04 | 0,83×2,04×0,07 | Cloison 70 0826278243 | G | Por-278 | 1-Projet | Etage 2 | 5 | Mur-153 | HAG Acrylic White | 0.132496 | 0.118524 | 4.92335 | 1.6932 | 910 | 2080 | 910 | 1.8928 | 1.8928 | 830 | 0 | 0 | 2040 | 1940 | 70 | 0.085966 | 8500 | 0 | 10580 | 2080 | 8500 | 0 | 0 | 40 | 20 | 15 | 40 | 2 | yes | 90.425 | yes | Réglages rapides | Sur ouvrant | Ch 1 | A23 | Sejour cuisine | A23 | Ch 1 | Ch 1 | A23
Por-274 | Etage 2 | 2040 | 580 | 0,58×2,04 | 0,58×2,04×0,07 | Cloison 70 0826278243 | G | Por-274 | 1-Projet | Etage 2 | 5 | Mur-149 | HAG Acrylic White | 0.0861 | 0.082824 | 3.3723 | 1.1832 | 600 | 2050 | 600 | 1.23 | 1.23 | 580 | 0 | 0 | 2040 | 1940 | 70 | 0.029732 | 8500 | 0 | 10550 | 2050 | 8500 | 0 | 0 | 10 | 10 | 10 | 20 | 2 | yes | 0 | yes | Cadre et porte | Sans | Entree/Pl | B26 |  |  | Entree/Pl | Entree/Pl | B26
Por-279 | Etage 2 | 2040 | 930 | 0,93×2,04 | 0,93×2,04×0,18 | Beton 18 0018356637 | G | Por-279 | Interieurs logements | Etage 2 | 5 | Mur-143 | HAG Acrylic White | 0.378144 | 0.341496 | 6.48965 | 1.8972 | 1010 | 2080 | 1010 | 2.1008 | 2.1008 | 930 | 0 | 0 | 2040 | 1940 | 180 | 0.125102 | 8500 | 0 | 10580 | 2080 | 8500 | 0 | 0 | 40 | 20 | 15 | 40 | 2 | yes | 90 | yes | Réglages rapides | Sur ouvrant |  |  |  |  | Sejour cuisine/pl
Por-275 | Etage 2 | 2040 | 830 | 0,83×2,04 | 0,83×2,04×0,07 | Cloison 70 0826278243 | D | Por-275 | 1-Projet | Etage 2 | 5 | Mur-149 | HAG Acrylic White | 0.132496 | 0.118524 | 4.92335 | 1.6932 | 910 | 2080 | 910 | 1.8928 | 1.8928 | 830 | 0 | 0 | 2040 | 1940 | 70 | 0.085966 | 8500 | 0 | 10580 | 2080 | 8500 | 0 | 0 | 40 | 20 | 15 | 40 | 2 | yes | 62.6302 | yes | Réglages rapides | Sur ouvrant | Entree/Pl | B26 | Ch 1/pl | B26 | Entree/Pl | Entree/Pl | B26
Por-276 | Etage 2 | 2040 | 830 | 0,83×2,04 | 0,83×2,04×0,07 | Cloison 70 0826278243 | G | Por-276 | 1-Projet | Etage 2 | 5 | Mur-149 | HAG Acrylic White | 0.132496 | 0.118524 | 4.92335 | 1.6932 | 910 | 2080 | 910 | 1.8928 | 1.8928 | 830 | 0 | 0 | 2040 | 1940 | 70 | 0.085966 | 8500 | 0 | 10580 | 2080 | 8500 | 0 | 0 | 40 | 20 | 15 | 40 | 2 | yes | 89.9641 | yes | Réglages rapides | Sur ouvrant | Ch 2 | B26 | Entree/Pl | B26 | Ch 2 | Ch 2 | B26
Por-275 | Etage 2 | 2040 | 830 | 0,83×2,04 | 0,83×2,04×0,07 | Cloison 70 0826278243 | G | Por-275 | 1-Projet | Etage 2 | 5 | Mur-148 | HAG Acrylic White | 0.132228 | 0.118524 | 4.92335 | 1.6932 | 908.162 | 2080 | 908.162 | 1.88898 | 1.88898 | 830 | 0 | 0 | 2040 | 1940 | 70 | 0.085966 | 8500 | 0 | 10580 | 2080 | 8500 | 0 | 0 | 40 | 20 | 15 | 40 | 2 | yes | 34.5955 | yes | Réglages rapides | Sur ouvrant | Ch 1 | A25 | Sde | A25 | Ch 1 | Ch 1 | A25
Por-283 | Etage 2 | 2040 | 830 | 0,83×2,04 | 0,83×2,04×0,07 | Cloison 70 0826278243 | D | Por-283 | 1-Projet | Etage 2 | 5 | Mur-153 | HAG Acrylic White | 0.132496 | 0.118524 | 4.92335 | 1.6932 | 910 | 2080 | 910 | 1.8928 | 1.8928 | 830 | 0 | 0 | 2040 | 1940 | 70 | 0.085966 | 8500 | 0 | 10580 | 2080 | 8500 | 0 | 0 | 40 | 20 | 15 | 40 | 2 | yes | 24.4794 | yes | Réglages rapides | Sur ouvrant | Dgt | A24 |  |  | Cellier; Dgt | Dgt | A24
Por-283 | Etage 2 | 2040 | 830 | 0,83×2,04 | 0,83×2,04×0,07 | Cloison 70 0826278243 | D | Por-283 | 1-Projet | Etage 2 | 5 | Mur-153 | HAG Acrylic White | 0.132496 | 0.118524 | 4.92335 | 1.6932 | 910 | 2080 | 910 | 1.8928 | 1.8928 | 830 | 0 | 0 | 2040 | 1940 | 70 | 0.085966 | 8500 | 0 | 10580 | 2080 | 8500 | 0 | 0 | 40 | 20 | 15 | 40 | 2 | yes | 24.4794 | yes | Réglages rapides | Sur ouvrant | Sejour cuisine/pl | A24 |  |  | Sejour cuisine/pl | Sejour cuisine/pl | A24
Por-280 | Etage 2 | 2040 | 830 | 0,83×2,04 | 0,83×2,04×0,07 | Cloison 70 0826278243 | D | Por-280 | 1-Projet | Etage 2 | 5 | Mur-149 | HAG Acrylic White | 0.132496 | 0.118524 | 4.92335 | 1.6932 | 910 | 2080 | 910 | 1.8928 | 1.8928 | 830 | 0 | 0 | 2040 | 1940 | 70 | 0.085966 | 8500 | 0 | 10580 | 2080 | 8500 | 0 | 0 | 40 | 20 | 15 | 40 | 2 | yes | 37.8707 | yes | Réglages rapides | Sur ouvrant | Entree/pl | A22 | Sde | A22 | Entree/pl | Entree/pl | A22
Por-284 | Etage 2 | 2040 | 730 | 0,73×2,04 | 0,73×2,04×0,07 | Cloison 70 0826278243 | D | Por-284 | 1-Projet | Etage 2 | 5 | Mur-149 | HAG Acrylic White | 0.117936 | 0.104244 | 4.48235 | 1.4892 | 810 | 2080 | 810 | 1.6848 | 1.6848 | 730 | 0 | 0 | 2040 | 1940 | 70 | 0.0774435 | 8500 | 0 | 10580 | 2080 | 8500 | 0 | 0 | 40 | 20 | 15 | 40 | 2 | yes | 22.8067 | yes | Réglages rapides | Sur ouvrant | Ch 1/pl | A21 | Ch 1/pl | A21 | Ch 1/pl | Ch 1/pl | A21
Por-280 | Etage 2 | 2040 | 830 | 0,83×2,04 | 0,83×2,04×0,07 | Cloison 70 0826278243 | D | Por-280 | 1-Projet | Etage 2 | 5 | Mur-149 | HAG Acrylic White | 0.132496 | 0.118524 | 4.92335 | 1.6932 | 910 | 2080 | 910 | 1.8928 | 1.8928 | 830 | 0 | 0 | 2040 | 1940 | 70 | 0.085966 | 8500 | 0 | 10580 | 2080 | 8500 | 0 | 0 | 40 | 20 | 15 | 40 | 2 | yes | 90 | yes | Réglages rapides | Sur ouvrant | Ch 1 | A22 | Entree/pl | A22 | Ch 1 | Ch 1 | A22
Por-295 | Etage 2 | 2040 | 930 | 0,93×2,04 | 0,93×2,04×0,18 | Beton 18 0018356637 | G | Por-295 | Interieurs logements | Etage 2 | 5 | Mur-143 | HAG Acrylic White | 0.378144 | 0.341496 | 6.48965 | 1.8972 | 1010 | 2080 | 1010 | 2.1008 | 2.1008 | 930 | 0 | 0 | 2040 | 1940 | 180 | 0.125102 | 8500 | 0 | 10580 | 2080 | 8500 | 0 | 0 | 40 | 20 | 15 | 40 | 2 | yes | 90 | yes | Réglages rapides | Sur ouvrant | Entree/pl | B23 |  |  | Entree/pl | Entree/pl | B23
Por-296 | Etage 2 | 2040 | 930 | 0,93×2,04 | 0,93×2,04×0,18 | Beton 18 0018356637 | D | Por-296 | Interieurs logements | Etage 2 | 5 | Mur-143 | HAG Acrylic White | 0.378144 | 0.341496 | 6.48965 | 1.8972 | 1010 | 2080 | 1010 | 2.1008 | 2.1008 | 930 | 0 | 0 | 2040 | 1940 | 180 | 0.125102 | 8500 | 0 | 10580 | 2080 | 8500 | 0 | 0 | 40 | 20 | 15 | 40 | 2 | yes | 90 | yes | Réglages rapides | Sur ouvrant | Entree/pl | B22 |  |  | Entree/pl | Entree/pl | B22
Por-275 | Etage 2 | 2040 | 500 | 0,50×2,04 | 0,50×2,04×0,07 | Cloison 70 0826278243 | D | Por-275 | 1-Projet | Etage 2 | 5 | Mur-149 | HAG Acrylic White | 0.07462 | 0.0714 | 3.0283 | 1.02 | 520 | 2050 | 520 | 1.066 | 1.066 | 500 | 0 | 0 | 2040 | 1940 | 70 | 0.026368 | 8500 | 0 | 10550 | 2050 | 8500 | 0 | 0 | 10 | 10 | 10 | 20 | 2 | yes | 0 | yes | Cadre et porte | Sans | Sejour cuisine/pl | A21 | Sejour cuisine/pl | A21 | Sejour cuisine/pl | Sejour cuisine/pl | A21
Por-274 | Etage 2 | 2040 | 580 | 0,58×2,04 | 0,58×2,04×0,07 | Cloison 70 0826278243 | G | Por-274 | 1-Projet | Etage 2 | 5 | Mur-149 | HAG Acrylic White | 0.08323 | 0.082824 | 3.3723 | 1.1832 | 580 | 2050 | 580 | 1.189 | 1.189 | 580 | 0 | 0 | 2040 | 1940 | 70 | 0.029732 | 8500 | 0 | 10550 | 2050 | 8500 | 0 | 0 | 10 | 10 | 10 | 20 | 2 | yes | 0 | yes | Cadre et porte | Sans | Sejour cuisine | B24 |  |  | Sejour cuisine | Sejour cuisine | B24
Por-283 | Etage 2 | 2040 | 830 | 0,83×2,04 | 0,83×2,04×0,07 | Cloison 70 0826278243 | G | Por-283 | 1-Projet | Etage 2 | 5 | Mur-149 | HAG Acrylic White | 0.132496 | 0.118524 | 4.92335 | 1.6932 | 910 | 2080 | 910 | 1.8928 | 1.8928 | 830 | 0 | 0 | 2040 | 1940 | 70 | 0.085966 | 8500 | 0 | 10580 | 2080 | 8500 | 0 | 0 | 40 | 20 | 15 | 40 | 2 | yes | 30.0872 | yes | Réglages rapides | Sur ouvrant | Dgt | B25 | Cellier | B25 | Dgt | Dgt | B25
Por-268 | Etage 2 | 2040 | 830 | 0,83×2,04 | 0,83×2,04×0,07 | Cloison 70 0826278243 | D | Por-268 | 1-Projet | Etage 2 | 5 | Mur-148 | HAG Acrylic White | 0.132496 | 0.118524 | 4.92335 | 1.6932 | 910 | 2080 | 910 | 1.8928 | 1.8928 | 830 | 0 | 0 | 2040 | 1940 | 70 | 0.085966 | 8500 | 0 | 10580 | 2080 | 8500 | 0 | 0 | 40 | 20 | 15 | 40 | 2 | yes | 22.6789 | yes | Réglages rapides | Sur ouvrant | Sejour cuisine/pl | A25 | Wc | A25 | Sejour cuisine/pl | Sejour cuisine/pl | A25
Por-278 | Etage 2 | 2040 | 830 | 0,83×2,04 | 0,83×2,04×0,07 | Cloison 70 0826278243 | G | Por-278 | 1-Projet | Etage 2 | 5 | Mur-151 | HAG Acrylic White | 0.132496 | 0.118524 | 4.92335 | 1.6932 | 910 | 2080 | 910 | 1.8928 | 1.8928 | 830 | 0 | 0 | 2040 | 1940 | 70 | 0.085966 | 8500 | 0 | 10580 | 2080 | 8500 | 0 | 0 | 40 | 20 | 15 | 40 | 2 | yes | 29.5716 | yes | Réglages rapides | Sur ouvrant | Ch 1 | A23 | Ch 1 | A23 | Ch 1 | Ch 1 | A23
Por-288 | Etage 2 | 2040 | 800 | 0,80×2,04 | 0,80×2,04×0,02 | mur 2cm | G | Por-288 | 1-Projet | Etage 2 | 5 | Mur-148 | HAG Acrylic White | 0.036608 | 0.03264 | 4.17895 | 1.632 | 880 | 2080 | 880 | 1.8304 | 1.8304 | 800 | 0 | 0 | 2040 | 1940 | 20 | 0.0372118 | 8500 | 0 | 10580 | 2080 | 8500 | 0 | 0 | 40 | 20 | 15 | 20 | 2 | no | 14.3266 | yes | Réglages rapides | Sans | Sde | A24 | Sde | A24 | Sde | Sde | A24
Por-288 | Etage 2 | 2040 | 800 | 0,80×2,04 | 0,80×2,04×0,02 | mur 2cm | G | Por-288 | 1-Projet | Etage 2 | 5 | Mur-148 | HAG Acrylic White | 0.036608 | 0.03264 | 4.17895 | 1.632 | 880 | 2080 | 880 | 1.8304 | 1.8304 | 800 | 0 | 0 | 2040 | 1940 | 20 | 0.0372118 | 8500 | 0 | 10580 | 2080 | 8500 | 0 | 0 | 40 | 20 | 15 | 20 | 2 | no | 14.3266 | yes | Réglages rapides | Sans | Sde | A25 | Sde | A25 | Sde | Sde | A25
Por-288 | Etage 2 | 2040 | 800 | 0,80×2,04 | 0,80×2,04×0,02 | mur 2cm | G | Por-288 | 1-Projet | Etage 2 | 5 | Mur-148 | HAG Acrylic White | 0.036608 | 0.03264 | 4.17895 | 1.632 | 880 | 2080 | 880 | 1.8304 | 1.8304 | 800 | 0 | 0 | 2040 | 1940 | 20 | 0.0372118 | 8500 | 0 | 10580 | 2080 | 8500 | 0 | 0 | 40 | 20 | 15 | 20 | 2 | no | 14.3266 | yes | Réglages rapides | Sans | Sde | A23 | Sde | A23 | Sde | Sde | A23
Por-288 | Etage 2 | 2040 | 800 | 0,80×2,04 | 0,80×2,04×0,02 | mur 2cm | G | Por-288 | 1-Projet | Etage 2 | 5 | Mur-148 | HAG Acrylic White | 0.036608 | 0.03264 | 4.17895 | 1.632 | 880 | 2080 | 880 | 1.8304 | 1.8304 | 800 | 0 | 0 | 2040 | 1940 | 20 | 0.0372118 | 8500 | 0 | 10580 | 2080 | 8500 | 0 | 0 | 40 | 20 | 15 | 20 | 2 | no | 14.3266 | yes | Réglages rapides | Sans | Sde | A22 | Sde | A22 | Sde | Sde | A22
Por-288 | Etage 2 | 2040 | 800 | 0,80×2,04 | 0,80×2,04×0,02 | mur 2cm | D | Por-288 | 1-Projet | Etage 2 | 5 | Mur-148 | HAG Acrylic White | 0.036608 | 0.03264 | 4.17895 | 1.632 | 880 | 2080 | 880 | 1.8304 | 1.8304 | 800 | 0 | 0 | 2040 | 1940 | 20 | 0.0372118 | 8500 | 0 | 10580 | 2080 | 8500 | 0 | 0 | 40 | 20 | 15 | 20 | 2 | no | 14.3266 | yes | Réglages rapides | Sans | Sde | B21 | Sde | B21 | Sde | Sde | B21
Por-288 | Etage 2 | 2040 | 800 | 0,80×2,04 | 0,80×2,04×0,02 | mur 2cm | G | Por-288 | 1-Projet | Etage 2 | 5 | Mur-148 | HAG Acrylic White | 0.036608 | 0.03264 | 4.17895 | 1.632 | 880 | 2080 | 880 | 1.8304 | 1.8304 | 800 | 0 | 0 | 2040 | 1940 | 20 | 0.0372118 | 8500 | 0 | 10580 | 2080 | 8500 | 0 | 0 | 40 | 20 | 15 | 20 | 2 | no | 14.3266 | yes | Réglages rapides | Sans | Sde | B26 |  |  | Sde | Sde | B26
Por-288 | Etage 2 | 2040 | 800 | 0,80×2,04 | 0,80×2,04×0,02 | mur 2cm | G | Por-288 | 1-Projet | Etage 2 | 5 | Mur-148 | HAG Acrylic White | 0.036608 | 0.03264 | 4.17895 | 1.632 | 880 | 2080 | 880 | 1.8304 | 1.8304 | 800 | 0 | 0 | 2040 | 1940 | 20 | 0.0372118 | 8500 | 0 | 10580 | 2080 | 8500 | 0 | 0 | 40 | 20 | 15 | 20 | 2 | no | 14.3266 | yes | Réglages rapides | Sans | Sde | B23 | Sde | B23 | Sde | Sde | B23
Por-288 | Etage 2 | 2040 | 800 | 0,80×2,04 | 0,80×2,04×0,02 | mur 2cm | G | Por-288 | 1-Projet | Etage 2 | 5 | Mur-148 | HAG Acrylic White | 0.0366081 | 0.03264 | 4.17895 | 1.632 | 880 | 2080 | 880 | 1.8304 | 1.8304 | 800 | 0 | 0 | 2040 | 1940 | 20 | 0.0372118 | 8500 | 0 | 10580 | 2080 | 8500 | 0 | 0 | 40 | 20 | 15 | 20 | 2 | no | 14.3266 | yes | Réglages rapides | Sans | Sde | B22 | Sde | B22 | Sde | Sde | B22
Por-288 | Etage 2 | 2040 | 800 | 0,80×2,04 | 0,80×2,04×0,02 | mur 2cm | G | Por-288 | 1-Projet | Etage 2 | 5 | Mur-148 | HAG Acrylic White | 0.036608 | 0.03264 | 4.17895 | 1.632 | 880 | 2080 | 880 | 1.8304 | 1.8304 | 800 | 0 | 0 | 2040 | 1940 | 20 | 0.0372118 | 8500 | 0 | 10580 | 2080 | 8500 | 0 | 0 | 40 | 20 | 15 | 20 | 2 | no | 14.3266 | yes | Réglages rapides | Sans | Sde | A21 | Sde | A21 | Sde | Sde | A21
Por-274 | Etage 2 | 2040 | 580 | 0,58×2,04 | 0,58×2,04×0,07 | Cloison 70 0826278243 | G | Por-274 | 1-Projet | Etage 2 | 5 | Mur-149 | HAG Acrylic White | 0.0861 | 0.082824 | 3.3723 | 1.1832 | 600 | 2050 | 600 | 1.23 | 1.23 | 580 | 0 | 0 | 2040 | 1940 | 70 | 0.029732 | 8500 | 0 | 10550 | 2050 | 8500 | 0 | 0 | 10 | 10 | 10 | 20 | 2 | yes | 0 | yes | Cadre et porte | Sans | Entree/pl | B25 |  |  | Entree/pl | Entree/pl | B25
Por-274 | Etage 2 | 2040 | 580 | 0,58×2,04 | 0,58×2,04×0,07 | Cloison 70 0826278243 | D | Por-274 | 1-Projet | Etage 2 | 5 | Mur-150 | HAG Acrylic White | 0.0861 | 0.082824 | 3.3723 | 1.1832 | 600 | 2050 | 600 | 1.23 | 1.23 | 580 | 0 | 0 | 2040 | 1940 | 70 | 0.029732 | 8500 | 0 | 10550 | 2050 | 8500 | 0 | 0 | 10 | 10 | 10 | 20 | 2 | yes | 0 | yes | Cadre et porte | Sans | Entree/pl | B22 |  |  | Entree/pl | Entree/pl | B22
Por-277 | Etage 2 | 2040 | 830 | 0,83×2,04 | 0,83×2,04×0,07 | Cloison 70 0826278243 | G | Por-277 | 1-Projet | Etage 2 | 5 | Mur-150 | HAG Acrylic White | 0.132496 | 0.118524 | 4.92335 | 1.6932 | 910 | 2080 | 910 | 1.8928 | 1.8928 | 830 | 0 | 0 | 2040 | 1940 | 70 | 0.085966 | 8500 | 0 | 10580 | 2080 | 8500 | 0 | 0 | 40 | 20 | 15 | 40 | 2 | yes | 21.9195 | yes | Réglages rapides | Sur ouvrant | Entree/pl | B22 | Sde | B22 | Entree/pl | Entree/pl | B22
Por-243 | Etage 2 | 650 | 450 | 0,45×0,65 | 0,45×0,65×0,18 | Beton 18 0018356637 | D | Por-243 | Interieurs logements | Etage 2 | 5 | Mur-142 | HAG Acrylic White | 0.059094 | 0.05265 | 1.39885 | 0.2925 | 490 | 670 | 490 | 0.3283 | 0.3283 | 450 | 300 | 200 | 950 | 850 | 180 | 0.016551 | 8800 | 300 | 9470 | 970 | 8800 | 300 | 300 | 20 | 20 | 15 | 20 | 2 | yes | 0 | no | Réglages rapides | Sans
Por-299 | Etage 2 | 2040 | 930 | 0,93×2,04 | 0,93×2,04×0,18 | Beton 18 0018356637 | G | Por-299 | Interieurs logements | Etage 2 | 5 | Mur-143 | HAG Acrylic White | 0.378144 | 0.341496 | 6.48965 | 1.8972 | 1010 | 2080 | 1010 | 2.1008 | 2.1008 | 930 | 0 | 0 | 2040 | 1940 | 180 | 0.125102 | 8500 | 0 | 10580 | 2080 | 8500 | 0 | 0 | 40 | 20 | 15 | 40 | 2 | yes | 90 | yes | Réglages rapides | Sur ouvrant | Entree/Pl | B26 |  |  | Entree/Pl | Entree/Pl | B26
Por-295 | Etage 2 | 2040 | 930 | 0,93×2,04 | 0,93×2,04×0,18 | Beton 18 0018356637 | G | Por-295 | Interieurs logements | Etage 2 | 5 | Mur-143 | HAG Acrylic White | 0.378144 | 0.341496 | 6.48965 | 1.8972 | 1010 | 2080 | 1010 | 2.1008 | 2.1008 | 930 | 0 | 0 | 2040 | 1940 | 180 | 0.125102 | 8500 | 0 | 10580 | 2080 | 8500 | 0 | 0 | 40 | 20 | 15 | 40 | 2 | yes | 90 | yes | Réglages rapides | Sur ouvrant
Por-237 | Etage 2 | 650 | 450 | 0,45×0,65 | 0,45×0,65×0,18 | Beton 18 0018356637 | G | Por-237 | Interieurs logements | Etage 2 | 5 | Mur-143 | HAG Acrylic White | 0.059094 | 0.05265 | 1.39885 | 0.2925 | 490 | 670 | 490 | 0.3283 | 0.3283 | 450 | 300 | 200 | 950 | 850 | 180 | 0.016551 | 8800 | 300 | 9470 | 970 | 8800 | 300 | 300 | 20 | 20 | 15 | 20 | 2 | yes | 0 | no | Réglages rapides | Sans
Por-276 | Etage 2 | 2040 | 830 | 0,83×2,04 | 0,83×2,04×0,07 | Cloison 70 0826278243 | D | Por-276 | 1-Projet | Etage 2 | 5 | Mur-149 | HAG Acrylic White | 0.132496 | 0.118524 | 4.92335 | 1.6932 | 910 | 2080 | 909.999 | 1.8928 | 1.8928 | 830 | 0 | 0 | 2040 | 1940 | 70 | 0.085966 | 8500 | 0 | 10580 | 2080 | 8500 | 0 | 0 | 40 | 20 | 15 | 40 | 2 | yes | 90 | yes | Réglages rapides | Sur ouvrant | Ch 2 | B22 | Entree/pl | B22 | Ch 2 | Ch 2 | B22
Por-275 | Etage 2 | 2040 | 830 | 0,83×2,04 | 0,83×2,04×0,07 | Cloison 70 0826278243 | G | Por-275 | 1-Projet | Etage 2 | 5 | Mur-149 | HAG Acrylic White | 0.132496 | 0.118524 | 4.92335 | 1.6932 | 910 | 2080 | 910 | 1.8928 | 1.8928 | 830 | 0 | 0 | 2040 | 1940 | 70 | 0.085966 | 8500 | 0 | 10580 | 2080 | 8500 | 0 | 0 | 40 | 20 | 15 | 40 | 2 | yes | 90 | yes | Réglages rapides | Sur ouvrant | Entree/pl | B22 | Entree/pl | B22 | Ch 1/pl
Por-274 | Etage 2 | 2040 | 580 | 0,58×2,04 | 0,58×2,04×0,07 | Cloison 70 0826278243 | D | Por-274 | 1-Projet | Etage 2 | 5 | Mur-149 | HAG Acrylic White | 0.0861 | 0.082824 | 3.3723 | 1.1832 | 600 | 2050 | 600 | 1.23 | 1.23 | 580 | 0 | 0 | 2040 | 1940 | 70 | 0.029732 | 8500 | 0 | 10550 | 2050 | 8500 | 0 | 0 | 10 | 10 | 10 | 20 | 2 | yes | 0 | yes | Cadre et porte | Sans | Sejour cuisine | B21 |  |  | Sejour cuisine | Sejour cuisine | B21
Por-299 | Etage 2 | 2040 | 930 | 0,93×2,04 | 0,93×2,04×0,18 | Beton 18 0018356637 | G | Por-299 | Interieurs logements | Etage 2 | 5 | Mur-142 | HAG Acrylic White | 0.378144 | 0.341496 | 6.48965 | 1.8972 | 1010 | 2080 | 1010 | 2.1008 | 2.1008 | 930 | 0 | 0 | 2040 | 1940 | 180 | 0.125102 | 8500 | 0 | 10580 | 2080 | 8500 | 0 | 0 | 40 | 20 | 15 | 40 | 2 | yes | 90 | yes | Réglages rapides | Sur ouvrant | Entree/pl | B25 |  |  | Entree/pl | Entree/pl | B25
Por-293 | Etage 2 | 2040 | 830 | 0,83×2,04 | 0,83×2,04×0,07 | Cloison 70 0826278243 | G | Por-293 | 1-Projet | Etage 2 | 5 | Mur-149 | HAG Acrylic White | 0.132496 | 0.118524 | 4.92335 | 1.6932 | 910 | 2080 | 910 | 1.8928 | 1.8928 | 830 | 0 | 0 | 2040 | 1940 | 70 | 0.085966 | 8500 | 0 | 10580 | 2080 | 8500 | 0 | 0 | 40 | 20 | 15 | 40 | 2 | yes | 90 | yes | Réglages rapides | Sur ouvrant | Ch 1 | B21 | Sejour cuisine | B21 | Ch 1 | Ch 1 | B21
Por-277 | Etage 2 | 2040 | 830 | 0,83×2,04 | 0,83×2,04×0,07 | Cloison 70 0826278243 | D | Por-277 | 1-Projet | Etage 2 | 5 | Mur-150 | HAG Acrylic White | 0.132496 | 0.118524 | 4.92335 | 1.6932 | 910 | 2080 | 910 | 1.8928 | 1.8928 | 830 | 0 | 0 | 2040 | 1940 | 70 | 0.085966 | 8500 | 0 | 10580 | 2080 | 8500 | 0 | 0 | 40 | 20 | 15 | 40 | 2 | yes | 21.9195 | yes | Réglages rapides | Sur ouvrant | Entree/pl | B23 | Sde | B23 | Entree/pl | Entree/pl | B23
Por-276 | Etage 2 | 2040 | 580 | 0,58×2,04 | 0,58×2,04×0,07 | Cloison 70 0826278243 | G | Por-276 | 1-Projet | Etage 2 | 5 | Mur-150 | HAG Acrylic White | 0.0861 | 0.082824 | 3.3723 | 1.1832 | 600 | 2050 | 600 | 1.23 | 1.23 | 580 | 0 | 0 | 2040 | 1940 | 70 | 0.029732 | 8500 | 0 | 10550 | 2050 | 8500 | 0 | 0 | 10 | 10 | 10 | 20 | 2 | yes | 0 | yes | Cadre et porte | Sans | Entree/pl | B23 |  |  | Entree/pl | Entree/pl | B23
Por-278 | Etage 2 | 2040 | 830 | 0,83×2,04 | 0,83×2,04×0,07 | Cloison 70 0826278243 | D | Por-278 | 1-Projet | Etage 2 | 5 | Mur-149 | HAG Acrylic White | 0.132496 | 0.118524 | 4.92335 | 1.6932 | 910 | 2080 | 910 | 1.8928 | 1.8928 | 830 | 0 | 0 | 2040 | 1940 | 70 | 0.085966 | 8500 | 0 | 10580 | 2080 | 8500 | 0 | 0 | 40 | 20 | 15 | 40 | 2 | yes | 22.6789 | yes | Réglages rapides | Sur ouvrant | Entree/pl | B23 | Wc | B23 | Entree/pl | Entree/pl | B23
Por-278 | Etage 2 | 2040 | 830 | 0,83×2,04 | 0,83×2,04×0,07 | Cloison 70 0826278243 | G | Por-278 | 1-Projet | Etage 2 | 5 | Mur-149 | HAG Acrylic White | 0.132496 | 0.118524 | 4.92335 | 1.6932 | 910 | 2080 | 910 | 1.8928 | 1.8928 | 830 | 0 | 0 | 2040 | 1940 | 70 | 0.085966 | 8500 | 0 | 10580 | 2080 | 8500 | 0 | 0 | 40 | 20 | 15 | 40 | 2 | yes | 22.6789 | yes | Réglages rapides | Sur ouvrant | Entree/pl | B23 | Cellier | B23 | Entree/pl | Entree/pl | B23
Por-249 | Etage 2 | 650 | 450 | 0,45×0,65 | 0,45×0,65×0,07 | Cloison 70 0826278243 | D | Por-249 | 1-Projet | Etage 2 | 5 | Mur-148 | HAG Acrylic White | 0.022981 | 0.020475 | 1.00395 | 0.2925 | 490 | 670 | 490 | 0.3283 | 0.3283 | 450 | 300 | 200 | 950 | 850 | 70 | 0.009775 | 8800 | 300 | 9470 | 970 | 8800 | 300 | 300 | 20 | 20 | 15 | 20 | 2 | yes | 0 | no | Réglages rapides | Sans | Sde | A22 | Pl 2 | A22 | Sde | Sde | A22
Por-275 | Etage 2 | 2040 | 830 | 0,83×2,04 | 0,83×2,04×0,07 | Cloison 70 0826278243 | D | Por-275 | 1-Projet | Etage 2 | 5 | Mur-149 | HAG Acrylic White | 0.132496 | 0.118524 | 4.92335 | 1.6932 | 910 | 2080 | 910 | 1.8928 | 1.8928 | 830 | 0 | 0 | 2040 | 1940 | 70 | 0.085966 | 8500 | 0 | 10580 | 2080 | 8500 | 0 | 0 | 40 | 20 | 15 | 40 | 2 | yes | 17.7803 | yes | Réglages rapides | Sur ouvrant | Ch 1/pl | B23 | Ch 1/pl | B23 | Ch 1/pl; Entree/pl | Ch 1/pl | B23
Por-276 | Etage 2 | 2040 | 830 | 0,83×2,04 | 0,83×2,04×0,07 | Cloison 70 0826278243 | G | Por-276 | 1-Projet | Etage 2 | 5 | Mur-149 | HAG Acrylic White | 0.132496 | 0.118524 | 4.92335 | 1.6932 | 910 | 2080 | 910 | 1.8928 | 1.8928 | 830 | 0 | 0 | 2040 | 1940 | 70 | 0.085966 | 8500 | 0 | 10580 | 2080 | 8500 | 0 | 0 | 40 | 20 | 15 | 40 | 2 | yes | 90 | yes | Réglages rapides | Sur ouvrant | Ch 2 | B23 | Ch 2 | B23 | Ch 2 | Ch 2 | B23
Por-282 | Etage 2 | 2040 | 830 | 0,83×2,04 | 0,83×2,04×0,07 | Cloison 70 0826278243 | D | Por-282 | 1-Projet | Etage 2 | 5 | Mur-149 | HAG Acrylic White | 0.132501 | 0.118524 | 4.92335 | 1.6932 | 910 | 2080 | 910 | 1.8928 | 1.8928 | 830 | 0 | 0 | 2040 | 1940 | 70 | 0.085966 | 8500 | 0 | 10580 | 2080 | 8500 | 0 | 0 | 40 | 20 | 15 | 40 | 2 | yes | 90 | yes | Réglages rapides | Sur ouvrant | Ch 2 | B25 | Dgt | B25 | Ch 2 | Ch 2 | B25
Por-274 | Etage 2 | 2040 | 580 | 0,58×2,04 | 0,58×2,04×0,07 | Cloison 70 0826278243 | G | Por-274 | 1-Projet | Etage 2 | 5 | Mur-149 | HAG Acrylic White | 0.0861 | 0.082824 | 3.3723 | 1.1832 | 600 | 2050 | 600 | 1.23 | 1.23 | 580 | 0 | 0 | 2040 | 1940 | 70 | 0.029732 | 8500 | 0 | 10550 | 2050 | 8500 | 0 | 0 | 10 | 10 | 10 | 20 | 2 | yes | 0 | yes | Cadre et porte | Sans | Entree | A21 |  |  | Entree | Entree | A21
Por-232 | Etage 2 | 650 | 450 | 0,45×0,65 | 0,45×0,65×0,18 | Beton 18 0018356637 | G | Por-232 | Interieurs logements | Etage 2 | 5 | Mur-143 | HAG Acrylic White | 0.059094 | 0.05265 | 1.39885 | 0.2925 | 490 | 670 | 490 | 0.3283 | 0.3283 | 450 | 300 | 200 | 950 | 850 | 180 | 0.016551 | 8800 | 300 | 9470 | 970 | 8800 | 300 | 300 | 20 | 20 | 15 | 20 | 2 | yes | 0 | no | Réglages rapides | Sans
Por-299 | Etage 2 | 2040 | 930 | 0,93×2,04 | 0,93×2,04×0,18 | Beton 18 0018356637 | G | Por-299 | Interieurs logements | Etage 2 | 5 | Mur-143 | HAG Acrylic White | 0.378144 | 0.341496 | 6.48965 | 1.8972 | 1010 | 2080 | 1010 | 2.1008 | 2.1008 | 930 | 0 | 0 | 2040 | 1940 | 180 | 0.125102 | 8500 | 0 | 10580 | 2080 | 8500 | 0 | 0 | 40 | 20 | 15 | 40 | 2 | yes | 90 | yes | Réglages rapides | Sur ouvrant | Entree/pl | B24 |  |  | Entree/pl | Entree/pl | B24
Por-278 | Etage 2 | 2040 | 830 | 0,83×2,04 | 0,83×2,04×0,07 | Cloison 70 0826278243 | G | Por-278 | 1-Projet | Etage 2 | 5 | Mur-149 | HAG Acrylic White | 0.132496 | 0.118524 | 4.92335 | 1.6932 | 910 | 2080 | 910 | 1.8928 | 1.8928 | 830 | 0 | 0 | 2040 | 1940 | 70 | 0.085966 | 8500 | 0 | 10580 | 2080 | 8500 | 0 | 0 | 40 | 20 | 15 | 40 | 2 | yes | 22.6789 | yes | Réglages rapides | Sur ouvrant | Entree/pl | B22 | Cellier | B22 | Entree/pl | Entree/pl | B22
Por-281 | Etage 2 | 2040 | 830 | 0,83×2,04 | 0,83×2,04×0,07 | Cloison 70 0826278243 | D | Por-281 | 1-Projet | Etage 2 | 5 | Mur-149 | HAG Acrylic White | 0.132496 | 0.118524 | 4.92335 | 1.6932 | 910 | 2080 | 910 | 1.8928 | 1.8928 | 830 | 0 | 0 | 2040 | 1940 | 70 | 0.085966 | 8500 | 0 | 10580 | 2080 | 8500 | 0 | 0 | 40 | 20 | 15 | 40 | 2 | yes | 90 | yes | Réglages rapides | Sur ouvrant | Ch 1/pl | B25 | Dgt | B25 | Ch 1/pl | Ch 1/pl | B25
Por-282 | Etage 2 | 2040 | 830 | 0,83×2,04 | 0,83×2,04×0,07 | Cloison 70 0826278243 | G | Por-282 | 1-Projet | Etage 2 | 5 | Mur-149 | HAG Acrylic White | 0.132496 | 0.118524 | 4.92335 | 1.6932 | 910 | 2080 | 910 | 1.8928 | 1.8928 | 830 | 0 | 0 | 2040 | 1940 | 70 | 0.085966 | 8500 | 0 | 10580 | 2080 | 8500 | 0 | 0 | 40 | 20 | 15 | 40 | 2 | yes | 90 | yes | Réglages rapides | Sur ouvrant | Sde | B25 | Dgt | B25 | Sde | Sde | B25
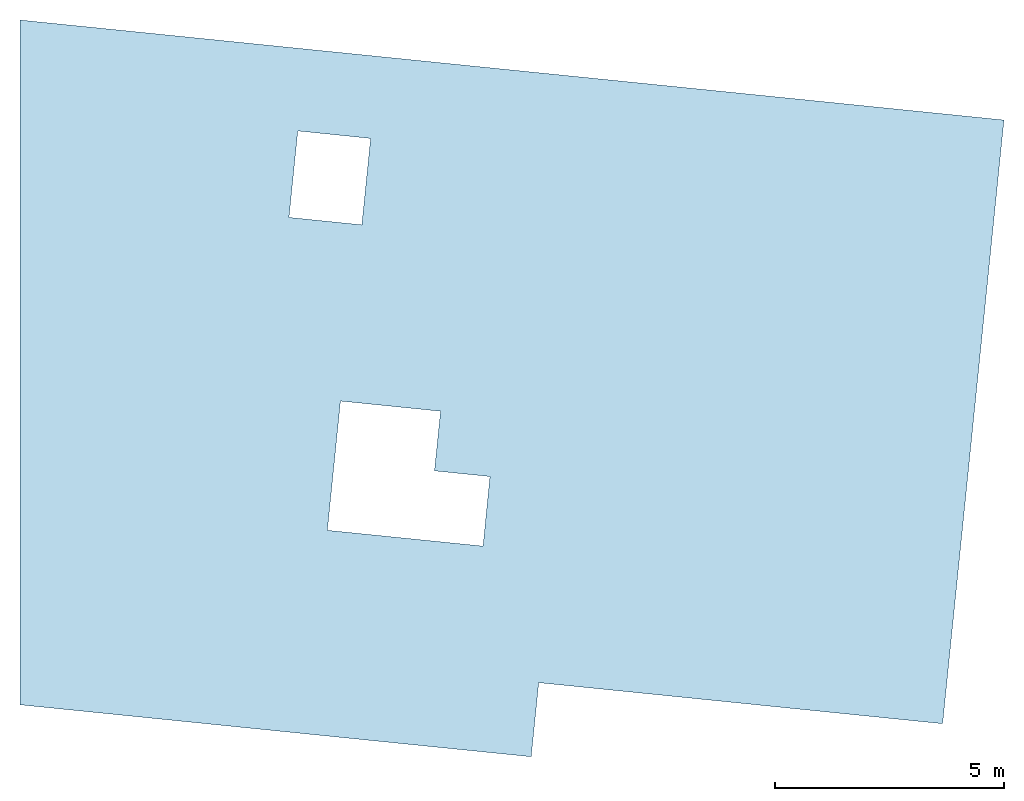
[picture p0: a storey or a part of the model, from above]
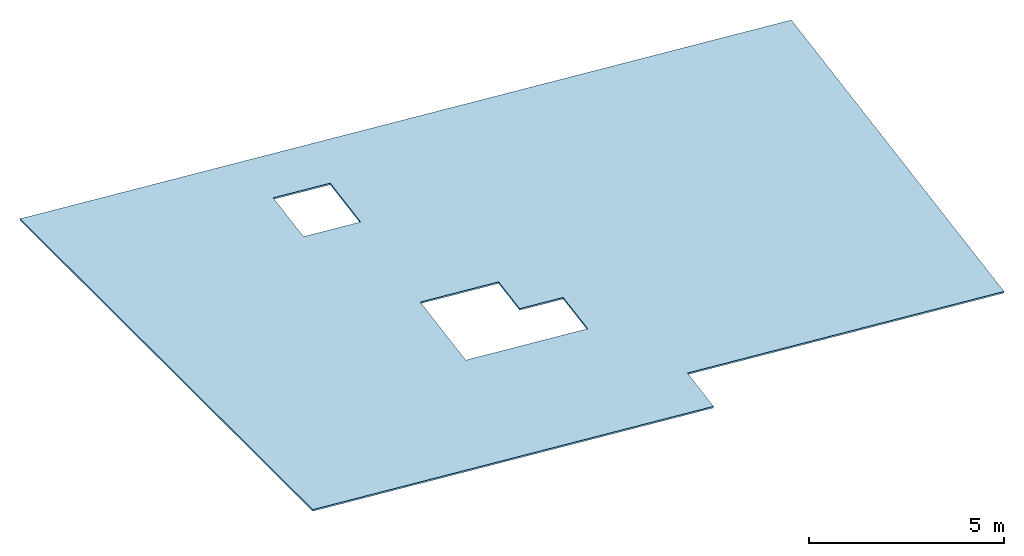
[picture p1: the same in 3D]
Properties of the parts of a building model (IFC2X3), part 15 of 44

# IfcDoor: Porte_1v (482)
Name | In | OverallHeight (mm) = Hauteur nominale de l'ouverture P/F côté ébrasure (mm) = Hauteur nominale de l'ouverture P/F côté opposée ébrasure (mm) = Hauteur (mm) | OverallWidth (mm) | Taille L x H nominale | Taille L x H x E nominale | Structure de Mur | Orientation | ID de l'élément = Lien et ID d'élément | Calque | Nom d'étage d'implantation | Numéro d'étage d'implantation | ID de Parent | Surfaces (Toutes) = Matériau du cadre = Matériau porte = Matériau si métal = Matériau Poignée | Volume ouverture d'ouverture P/F (m3) | Volume nominal ouverture P/F (m3) | Superficie ouverture P/F (m2) = Superficie en plan (m2) = Superficie inférieure (nette) (m2) | Superficie nominale ouverture P/F (m2) = Superficie nominale de l'ouverture P/F côté ébrasure (m2) = Superficie nominale de l'ouverture P/F côté opposé ébrasure (m2) | Largeur ouverture P/F côté ébrasure (mm) | Hauteur ouverture P/F côté ébrasure (mm) = Hauteur ouverture P/F côté opposé ébrasure (mm) | Largeur ouverture P/F côté opposé ébrasure (mm) | Superficie ouverture P/F côté ébrasure (m2) | Superficie ouverture P/F côté opposé ébrasure (m2) | Largeur nominale de l'ouverture P/F côté ébrasure (mm) = Largeur nominale de l'ouverture P/F côté opposée ébrasure (mm) = Largeur (mm) | Valeur Appui ou Linteau (mm) = Hauteur nominale seuil (mm) | Hauteur seuil P/F côté ébrasure (mm) = Hauteur seuil P/F côté opposé ébrasure (mm) | Hauteur nominale linteau P/F (mm) | Hauteur linteau P/F côté ébrasure (mm) = Hauteur linteau P/F côté opposé ébrasure (mm) | Épaisseur de Mur (mm) | Volume (net) (m3) | Altitude à Zéro du Projet (mm) = Altitude de Référence Niveau 1 (mm) = Altitude de Référence Niveau 2 (mm) = Altitude à niveau de la mer (mm) | Altitude à étage lié/étage d'implantation (mm) = Décalage étage d'implantation (mm) | Altitude supérieure à premier niveau de référence (mm) = Altitude supérieure à Zéro du projet (mm) = Altitude supérieure à niveau de la mer (mm) = Altitude supérieure à deuxième niveau de référence (mm) | Altitude supérieure à étage d'implantation (mm) | Altitude inférieure à premier niveau de référence (mm) = Altitude inférieure à Zéro du projet (mm) = Altitude inférieure à niveau de la mer (mm) = Altitude inférieure à deuxième niveau de référence (mm) | Altitude inférieure à étage d'implantation (mm) | Hauteur appui à étage actuel (mm) | Largeur huisserie (mm) | Epais. faux cadre (mm) | Larg feuill mont horiz (mm) | Epaisseur porte (mm) | Contours Mur (0-Sans,1-Tout,2-Côté,3-Longueur) | Dimensions normalisées | Angle d'ouverture en 2D (deg) | Poignée en 3D | Liste des interface user | Affichage texte | Nom de zone liée | Numéro de zone liée | De Zone | Du numéro de Zone | Zones conflictuelles | À Zone | À numéro de Zone
Por-284 | Etage 2 | 2040 | 830 | 0,83×2,04 | 0,83×2,04×0,07 | Cloison 70 0826278243 | G | Por-284 | 1-Projet | Etage 2 | 5 | Mur-149 | HAG Acrylic White | 0.132496 | 0.118524 | 4.92335 | 1.6932 | 910 | 2080 | 910 | 1.8928 | 1.8928 | 830 | 0 | 0 | 2040 | 1940 | 70 | 0.085966 | 8500 | 0 | 10580 | 2080 | 8500 | 0 | 0 | 40 | 20 | 15 | 40 | 2 | yes | 22.6789 | yes | Réglages rapides | Sur ouvrant | Entree/pl | B24 | Cellier | B24 | Entree/pl | Entree/pl | B24
Por-278 | Etage 2 | 2040 | 830 | 0,83×2,04 | 0,83×2,04×0,07 | Cloison 70 0826278243 | G | Por-278 | 1-Projet | Etage 2 | 5 | Mur-149 | HAG Acrylic White | 0.132496 | 0.118524 | 4.92335 | 1.6932 | 910 | 2080 | 910 | 1.8928 | 1.8928 | 830 | 520 | 420 | 2560 | 2460 | 70 | 0.085966 | 9020 | 520 | 11100 | 2600 | 9020 | 520 | 520 | 40 | 20 | 15 | 40 | 2 | yes | 22.6789 | yes | Réglages rapides | Sur ouvrant | Entree/Pl | B26 | Sde | B26 | Entree/Pl | Entree/Pl | B26
Por-276 | Etage 2 | 2040 | 830 | 0,83×2,04 | 0,83×2,04×0,07 | Cloison 70 0826278243 | D | Por-276 | 1-Projet | Etage 2 | 5 | Mur-149 | HAG Acrylic White | 0.132496 | 0.118524 | 4.92335 | 1.6932 | 910 | 2080 | 910 | 1.8928 | 1.8928 | 830 | 0 | 0 | 2040 | 1940 | 70 | 0.085966 | 8500 | 0 | 10580 | 2080 | 8500 | 0 | 0 | 40 | 20 | 15 | 40 | 2 | yes | 22.6807 | yes | Réglages rapides | Sur ouvrant | Entree/pl | B22 | Wc | B22 | Entree/pl | Entree/pl | B22
Por-279 | Etage 2 | 2040 | 930 | 0,93×2,04 | 0,93×2,04×0,18 | Beton 18 0018356637 | D | Por-279 | Interieurs logements | Etage 2 | 5 | Mur-142 | HAG Acrylic White | 0.378144 | 0.341496 | 6.48965 | 1.8972 | 1010 | 2080 | 1010 | 2.1008 | 2.1008 | 930 | 0 | 0 | 2040 | 1940 | 180 | 0.125102 | 8500 | 0 | 10580 | 2080 | 8500 | 0 | 0 | 40 | 20 | 15 | 40 | 2 | yes | 90 | yes | Réglages rapides | Sur ouvrant | Sejour cuisine/pl | A24 |  |  | Sejour cuisine/pl | Sejour cuisine/pl | A24
Por-282 | Etage 2 | 2040 | 830 | 0,83×2,04 | 0,83×2,04×0,07 | Cloison 70 0826278243 | D | Por-282 | 1-Projet | Etage 2 | 5 | Mur-153 | HAG Acrylic White | 0.132496 | 0.118524 | 4.92335 | 1.6932 | 910 | 2080 | 910 | 1.8928 | 1.8928 | 830 | 0 | 0 | 2040 | 1940 | 70 | 0.085966 | 8500 | 0 | 10580 | 2080 | 8500 | 0 | 0 | 40 | 20 | 15 | 40 | 2 | yes | 90 | yes | Réglages rapides | Sur ouvrant | Ch 1 | A24 | Dgt | A24 | Ch 1 | Ch 1 | A24
Por-283 | Etage 2 | 2040 | 830 | 0,83×2,04 | 0,83×2,04×0,07 | Cloison 70 0826278243 | D | Por-283 | 1-Projet | Etage 2 | 5 | Mur-153 | HAG Acrylic White | 0.132496 | 0.118524 | 4.92335 | 1.6932 | 910 | 2080 | 910 | 1.8928 | 1.8928 | 830 | 0 | 0 | 2040 | 1940 | 70 | 0.085966 | 8500 | 0 | 10580 | 2080 | 8500 | 0 | 0 | 40 | 20 | 15 | 40 | 2 | yes | 24.4794 | yes | Réglages rapides | Sur ouvrant | Dgt | A24 | Sde | A24 | Dgt | Dgt | A24
Por-281 | Etage 2 | 2040 | 830 | 0,83×2,04 | 0,83×2,04×0,07 | Cloison 70 0826278243 | G | Por-281 | 1-Projet | Etage 2 | 5 | Mur-153 | HAG Acrylic White | 0.132496 | 0.118524 | 4.92335 | 1.6932 | 910 | 2080 | 910 | 1.8928 | 1.8928 | 830 | 0 | 0 | 2040 | 1940 | 70 | 0.085966 | 8500 | 0 | 10580 | 2080 | 8500 | 0 | 0 | 40 | 20 | 15 | 40 | 2 | yes | 90 | yes | Réglages rapides | Sur ouvrant | Ch 2/pl | A24 | Dgt | A24 | Ch 2/pl | Ch 2/pl | A24
Por-274 | Etage 2 | 2040 | 580 | 0,58×2,04 | 0,58×2,04×0,07 | Cloison 70 0826278243 | D | Por-274 | 1-Projet | Etage 2 | 5 | Mur-153 | HAG Acrylic White | 0.0861 | 0.082824 | 3.3723 | 1.1832 | 600 | 2050 | 600 | 1.23 | 1.23 | 580 | 0 | 0 | 2040 | 1940 | 70 | 0.029732 | 8500 | 0 | 10550 | 2050 | 8500 | 0 | 0 | 10 | 10 | 10 | 20 | 2 | yes | 0 | yes | Cadre et porte | Sans | Dgt | A24 |  |  | Dgt | Dgt | A24
Por-279 | Etage 2 | 2040 | 930 | 0,93×2,04 | 0,93×2,04×0,18 | Beton 18 0018356637 | D | Por-279 | Interieurs logements | Etage 2 | 5 | Mur-142 | HAG Acrylic White | 0.378144 | 0.341496 | 6.48965 | 1.8972 | 1010 | 2080 | 1010 | 2.1008 | 2.1008 | 930 | 0 | 0 | 2040 | 1940 | 180 | 0.125102 | 8500 | 0 | 10580 | 2080 | 8500 | 0 | 0 | 40 | 20 | 15 | 40 | 2 | yes | 90 | yes | Réglages rapides | Sur ouvrant | Sejour cuisine | A23 |  |  | Sejour cuisine | Sejour cuisine | A23
Por-275 | Etage 2 | 2040 | 830 | 0,83×2,04 | 0,83×2,04×0,07 | Cloison 70 0826278243 | G | Por-275 | 1-Projet | Etage 2 | 5 | Mur-148 | HAG Acrylic White | 0.132496 | 0.118524 | 4.92335 | 1.6932 | 910 | 2080 | 910 | 1.8928 | 1.8928 | 830 | 0 | 0 | 2040 | 1940 | 70 | 0.085966 | 8500 | 0 | 10580 | 2080 | 8500 | 0 | 0 | 40 | 20 | 15 | 40 | 2 | yes | 90 | yes | Réglages rapides | Sur ouvrant | Ch 1 | A25 | Sejour cuisine/pl | A25 | Ch 1 | Ch 1 | A25
Por-278 | Etage 2 | 2040 | 830 | 0,83×2,04 | 0,83×2,04×0,07 | Cloison 70 0826278243 | D | Por-278 | 1-Projet | Etage 2 | 5 | Mur-121 | HAG Acrylic White | 0.132496 | 0.118524 | 4.92335 | 1.6932 | 910 | 2080 | 910 | 1.8928 | 1.8928 | 830 | 0 | 0 | 2040 | 1940 | 70 | 0.085966 | 8500 | 0 | 10580 | 2080 | 8500 | 0 | 0 | 40 | 20 | 15 | 40 | 2 | yes | 25.655 | yes | Réglages rapides | Sur ouvrant | Sejour cuisine | A23 |  |  | Sejour cuisine; Wc | Sejour cuisine | A23
Por-274 | Etage 2 | 2040 | 580 | 0,58×2,04 | 0,58×2,04×0,07 | Cloison 70 0826278243 | G | Por-274 | 1-Projet | Etage 2 | 5 | Mur-149 | HAG Acrylic White | 0.0795621 | 0.082824 | 3.3723 | 1.1832 | 554.44 | 2050 | 554.44 | 1.1366 | 1.1366 | 580 | 0 | 0 | 2040 | 1940 | 70 | 0.029732 | 8500 | 0 | 10550 | 2050 | 8500 | 0 | 0 | 10 | 10 | 10 | 20 | 2 | yes | 0 | yes | Cadre et porte | Sans | Sejour cuisine | B25 |  |  | Sejour cuisine | Sejour cuisine | B25
Por-283 | Etage 2 | 2040 | 830 | 0,83×2,04 | 0,83×2,04×0,07 | Cloison 70 0826278243 | G | Por-283 | 1-Projet | Etage 2 | 5 | Mur-149 | HAG Acrylic White | 0.132496 | 0.118524 | 4.92335 | 1.6932 | 910 | 2080 | 910 | 1.8928 | 1.8928 | 830 | 0 | 0 | 2040 | 1940 | 70 | 0.085966 | 8500 | 0 | 10580 | 2080 | 8500 | 0 | 0 | 40 | 20 | 15 | 40 | 2 | yes | 22.6789 | yes | Réglages rapides | Sur ouvrant | Wc | B24 | Wc | B24 | Entree/pl; Wc | Wc | B24
Por-202 | Etage 2 | 2040 | 380 | 0,38×2,04 | 0,38×2,04×0,07 | Cloison 70 0826278243 | D | Por-202 | 3D | Etage 2 | 5 | Mur-120 | HAG Acrylic White | 0.0574 | 0.054264 | 2.6091 | 0.7752 | 400 | 2050 | 400 | 0.82 | 0.82 | 380 | 0 | 0 | 2040 | 1940 | 70 | 0.036826 | 8500 | 0 | 10550 | 2050 | 8500 | 0 | 0 | 10 | 10 | 10 | 40 | 2 | yes | 0 | yes | Cadre et porte | Sans
2 x Por-202 | Etage 2 | 2040 | 600 | 0,60×2,04 | 0,60×2,04×0,07 | Cloison 70 0826278243 | D | Por-202 | 3D | Etage 2 | 5 | Mur-120 | HAG Acrylic White | 0.08897 | 0.08568 | 3.5639 | 1.224 | 620 | 2050 | 620 | 1.271 | 1.271 | 600 | 0 | 0 | 2040 | 1940 | 70 | 0.055053 | 8500 | 0 | 10550 | 2050 | 8500 | 0 | 0 | 10 | 10 | 10 | 40 | 2 | yes | 0 | yes | Cadre et porte | Sans
Por-202 | Etage 2 | 2040 | 680 | 0,68×2,04 | 0,68×2,04×0,07 | Cloison 70 0826278243 | D | Por-202 | 3D | Etage 2 | 5 | Mur-120 | HAG Acrylic White | 0.10045 | 0.097104 | 3.9111 | 1.3872 | 700 | 2050 | 700 | 1.435 | 1.435 | 680 | 0 | 0 | 2040 | 1940 | 70 | 0.061681 | 8500 | 0 | 10550 | 2050 | 8500 | 0 | 0 | 10 | 10 | 10 | 40 | 2 | yes | 0 | yes | Cadre et porte | Sans
3 x Por-202 | Etage 2 | 2040 | 480 | 0,48×2,04 | 0,48×2,04×0,07 | Cloison 70 0826278243 | D | Por-202 | 3D | Etage 2 | 5 | Mur-120 | HAG Acrylic White | 0.07175 | 0.068544 | 3.0431 | 0.9792 | 500 | 2050 | 500 | 1.025 | 1.025 | 480 | 0 | 0 | 2040 | 1940 | 70 | 0.045111 | 8500 | 0 | 10550 | 2050 | 8500 | 0 | 0 | 10 | 10 | 10 | 40 | 2 | yes | 0 | yes | Cadre et porte | Sans
Por-202 | Etage 2 | 2040 | 450 | 0,45×2,04 | 0,45×2,04×0,07 | Cloison 70 0826278243 | D | Por-202 | 3D | Etage 2 | 5 | Mur-120 | HAG Acrylic White | 0.067445 | 0.06426 | 2.9129 | 0.918 | 470 | 2050 | 470 | 0.9635 | 0.9635 | 450 | 0 | 0 | 2040 | 1940 | 70 | 0.0426255 | 8500 | 0 | 10550 | 2050 | 8500 | 0 | 0 | 10 | 10 | 10 | 40 | 2 | yes | 0 | yes | Cadre et porte | Sans
Por-202 | Etage 2 | 2040 | 350 | 0,35×2,04 | 0,35×2,04×0,07 | Cloison 70 0826278243 | D | Por-202 | 3D | Etage 2 | 5 | Mur-120 | HAG Acrylic White | 0.053095 | 0.04998 | 2.4789 | 0.714 | 370 | 2050 | 370 | 0.7585 | 0.7585 | 350 | 0 | 0 | 2040 | 1940 | 70 | 0.0343405 | 8500 | 0 | 10550 | 2050 | 8500 | 0 | 0 | 10 | 10 | 10 | 40 | 2 | yes | 0 | yes | Cadre et porte | Sans
Por-281 | Etage 2 | 2040 | 830 | 0,83×2,04 | 0,83×2,04×0,07 | Cloison 70 0826278243 | G | Por-281 | 1-Projet | Etage 2 | 5 | Mur-149 | HAG Acrylic White | 0.132496 | 0.118524 | 4.92335 | 1.6932 | 910 | 2080 | 910 | 1.8928 | 1.8928 | 830 | 0 | 0 | 2040 | 1940 | 70 | 0.085966 | 8500 | 0 | 10580 | 2080 | 8500 | 0 | 0 | 40 | 20 | 15 | 40 | 2 | yes | 27.0064 | yes | Réglages rapides | Sur ouvrant | Entree/pl | A22 | Wc | A22 | Entree/pl | Entree/pl | A22
Por-274 | Etage 2 | 2040 | 580 | 0,58×2,04 | 0,58×2,04×0,07 | Cloison 70 0826278243 | D | Por-274 | 1-Projet | Etage 2 | 5 | Mur-149 | HAG Acrylic White | 0.0861 | 0.082824 | 3.3723 | 1.1832 | 600 | 2050 | 600 | 1.23 | 1.23 | 580 | 0 | 0 | 2040 | 1940 | 70 | 0.029732 | 8500 | 0 | 10550 | 2050 | 8500 | 0 | 0 | 10 | 10 | 10 | 20 | 2 | yes | 0 | yes | Cadre et porte | Sans | Entree/pl | A22 |  |  | Entree/pl | Entree/pl | A22
Por-274 | Etage 2 | 2040 | 580 | 0,58×2,04 | 0,58×2,04×0,07 | Cloison 70 0826278243 | D | Por-274 | 1-Projet | Etage 2 | 5 | Mur-153 | HAG Acrylic White | 0.0861 | 0.082824 | 3.3723 | 1.1832 | 600 | 2050 | 600 | 1.23 | 1.23 | 580 | 0 | 0 | 2040 | 1940 | 70 | 0.029732 | 8500 | 0 | 10550 | 2050 | 8500 | 0 | 0 | 10 | 10 | 10 | 20 | 2 | yes | 0 | yes | Cadre et porte | Sans |  |  |  |  | Sejour cuisine/pl
Por-274 | Etage 2 | 2040 | 580 | 0,58×2,04 | 0,58×2,04×0,07 | Cloison 70 0826278243 | D | Por-274 | 1-Projet | Etage 2 | 5 | Mur-153 | HAG Acrylic White | 0.0861 | 0.082824 | 3.3723 | 1.1832 | 600 | 2050 | 600 | 1.23 | 1.23 | 580 | 0 | 0 | 2040 | 1940 | 70 | 0.029732 | 8500 | 0 | 10550 | 2050 | 8500 | 0 | 0 | 10 | 10 | 10 | 20 | 2 | yes | 0 | yes | Cadre et porte | Sans | Sejour cuisine | A23 |  |  | Sejour cuisine | Sejour cuisine | A23
2 x Por-202 | Etage 2 | 2040 | 580 | 0,58×2,04 | 0,58×2,04×0,07 | Cloison 70 0826278243 | D | Por-202 | 3D | Etage 2 | 5 | Mur-120 | HAG Acrylic White | 0.0861 | 0.082824 | 3.4771 | 1.1832 | 600 | 2050 | 600 | 1.23 | 1.23 | 580 | 0 | 0 | 2040 | 1940 | 70 | 0.053396 | 8500 | 0 | 10550 | 2050 | 8500 | 0 | 0 | 10 | 10 | 10 | 40 | 2 | yes | 0 | yes | Cadre et porte | Sans
Por-202 | Etage 2 | 2040 | 630 | 0,63×2,04 | 0,63×2,04×0,07 | Cloison 70 0826278243 | D | Por-202 | 3D | Etage 2 | 5 | Mur-120 | HAG Acrylic White | 0.093275 | 0.089964 | 3.6941 | 1.2852 | 650 | 2050 | 650 | 1.3325 | 1.3325 | 630 | 0 | 0 | 2040 | 1940 | 70 | 0.0575385 | 8500 | 0 | 10550 | 2050 | 8500 | 0 | 0 | 10 | 10 | 10 | 40 | 2 | yes | 0 | yes | Cadre et porte | Sans
Por-281 | Etage 2 | 2040 | 830 | 0,83×2,04 | 0,83×2,04×0,07 | Cloison 70 0826278243 | D | Por-281 | 1-Projet | Etage 2 | 5 | Mur-149 | HAG Acrylic White | 0.132496 | 0.118524 | 4.92335 | 1.6932 | 910 | 2080 | 910 | 1.8928 | 1.8928 | 830 | 0 | 0 | 2040 | 1940 | 70 | 0.085966 | 8500 | 0 | 10580 | 2080 | 8500 | 0 | 0 | 40 | 20 | 15 | 40 | 2 | yes | 90 | yes | Réglages rapides | Sur ouvrant | Ch 3 | B25 | Entree/pl | B25 | Ch 3 | Ch 3 | B25
Por-280 | Etage 2 | 2040 | 830 | 0,83×2,04 | 0,83×2,04×0,07 | Cloison 70 0826278243 | G | Por-280 | 1-Projet | Etage 2 | 5 | Mur-149 | HAG Acrylic White | 0.132496 | 0.118524 | 4.92335 | 1.6932 | 910 | 2080 | 910 | 1.8928 | 1.8928 | 830 | 0 | 0 | 2040 | 1940 | 70 | 0.085966 | 8500 | 0 | 10580 | 2080 | 8500 | 0 | 0 | 40 | 20 | 15 | 40 | 2 | yes | 33.4203 | yes | Réglages rapides | Sur ouvrant | Entree/pl | B25 | Wc | B25 | Entree/pl | Entree/pl | B25
Por-274 | Etage 2 | 2040 | 580 | 0,58×2,04 | 0,58×2,04×0,07 | Cloison 70 0826278243 | D | Por-274 | 1-Projet | Etage 2 | 5 | Mur-149 | HAG Acrylic White | 0.0861 | 0.082824 | 3.3723 | 1.1832 | 600 | 2050 | 600 | 1.23 | 1.23 | 580 | 0 | 0 | 2040 | 1940 | 70 | 0.029732 | 8500 | 0 | 10550 | 2050 | 8500 | 0 | 0 | 10 | 10 | 10 | 20 | 2 | yes | 0 | yes | Cadre et porte | Sans | Sejour cuisine | B24 | Sejour cuisine | B24 | Sejour cuisine | Sejour cuisine | B24
Por-249 | Etage 2 | 650 | 450 | 0,45×0,65 | 0,45×0,65×0,07 | Cloison 70 0826278243 | G | Por-249 | 1-Projet | Etage 2 | 5 | Mur-149 | HAG Acrylic White | 0.022981 | 0.020475 | 1.00395 | 0.2925 | 490 | 670 | 490 | 0.3283 | 0.3283 | 450 | 300 | 200 | 950 | 850 | 70 | 0.009775 | 8800 | 300 | 9470 | 970 | 8800 | 300 | 300 | 20 | 20 | 15 | 20 | 2 | yes | 0 | no | Réglages rapides | Sans | Sejour cuisine/pl | A24 | Sejour cuisine/pl | A24 | Sejour cuisine/pl
Por-285 | Etage 2 | 2040 | 830 | 0,83×2,04 | 0,83×2,04×0,07 | Cloison 70 0826278243 | G | Por-285 | 1-Projet | Etage 2 | 5 | Mur-149 | HAG Acrylic White | 0.132496 | 0.118524 | 4.92335 | 1.6932 | 910 | 2080 | 910 | 1.8928 | 1.8928 | 830 | 0 | 0 | 2040 | 1940 | 70 | 0.085966 | 8500 | 0 | 10580 | 2080 | 8500 | 0 | 0 | 40 | 20 | 15 | 40 | 2 | yes | 24.3404 | yes | Réglages rapides | Sur ouvrant | Entree | A21 |  |  | Entree | Entree | A21
Por-293 | Etage 2 | 2040 | 830 | 0,83×2,04 | 0,83×2,04×0,07 | Cloison 70 0826278243 | D | Por-293 | 1-Projet | Etage 2 | 5 | Mur-149 | HAG Acrylic White | 0.132496 | 0.118524 | 4.92335 | 1.6932 | 910 | 2080 | 910 | 1.8928 | 1.8928 | 830 | 0 | 0 | 2040 | 1940 | 70 | 0.085966 | 8500 | 0 | 10580 | 2080 | 8500 | 0 | 0 | 40 | 20 | 15 | 40 | 2 | yes | 27.1745 | yes | Réglages rapides | Sur ouvrant | Ch 1 | B21 | Sde | B21 | Ch 1 | Ch 1 | B21
Por-247 | Etage 3 | 650 | 450 | 0,45×0,65 | 0,45×0,65×0,18 | Beton 18 0018356637 | G | Por-247 | Interieurs logements | Etage 3 | 6 | Mur-142 | HAG Acrylic White | 0.059094 | 0.05265 | 1.39885 | 0.2925 | 490 | 670 | 490 | 0.3283 | 0.3283 | 450 | 300 | 200 | 950 | 850 | 180 | 0.016551 | 11850 | 300 | 12520 | 970 | 11850 | 300 | 300 | 20 | 20 | 15 | 20 | 2 | yes | 0 | no | Réglages rapides | Sans
Por-202 | Etage 3 | 2040 | 380 | 0,38×2,04 | 0,38×2,04×0,07 | Cloison 70 0826278243 | D | Por-202 | 3D | Etage 3 | 6 | Mur-120 | HAG Acrylic White | 0.0574 | 0.054264 | 2.6091 | 0.7752 | 400 | 2050 | 400 | 0.82 | 0.82 | 380 | 0 | 0 | 2040 | 1940 | 70 | 0.036826 | 11550 | 0 | 13600 | 2050 | 11550 | 0 | 0 | 10 | 10 | 10 | 40 | 2 | yes | 0 | yes | Cadre et porte | Sans
3 x Por-202 | Etage 3 | 2040 | 480 | 0,48×2,04 | 0,48×2,04×0,07 | Cloison 70 0826278243 | D | Por-202 | 3D | Etage 3 | 6 | Mur-120 | HAG Acrylic White | 0.07175 | 0.068544 | 3.0431 | 0.9792 | 500 | 2050 | 500 | 1.025 | 1.025 | 480 | 0 | 0 | 2040 | 1940 | 70 | 0.045111 | 11550 | 0 | 13600 | 2050 | 11550 | 0 | 0 | 10 | 10 | 10 | 40 | 2 | yes | 0 | yes | Cadre et porte | Sans
2 x Por-202 | Etage 3 | 2040 | 600 | 0,60×2,04 | 0,60×2,04×0,07 | Cloison 70 0826278243 | D | Por-202 | 3D | Etage 3 | 6 | Mur-120 | HAG Acrylic White | 0.08897 | 0.08568 | 3.5639 | 1.224 | 620 | 2050 | 620 | 1.271 | 1.271 | 600 | 0 | 0 | 2040 | 1940 | 70 | 0.055053 | 11550 | 0 | 13600 | 2050 | 11550 | 0 | 0 | 10 | 10 | 10 | 40 | 2 | yes | 0 | yes | Cadre et porte | Sans
Por-202 | Etage 3 | 2040 | 680 | 0,68×2,04 | 0,68×2,04×0,07 | Cloison 70 0826278243 | D | Por-202 | 3D | Etage 3 | 6 | Mur-120 | HAG Acrylic White | 0.10045 | 0.097104 | 3.9111 | 1.3872 | 700 | 2050 | 700 | 1.435 | 1.435 | 680 | 0 | 0 | 2040 | 1940 | 70 | 0.061681 | 11550 | 0 | 13600 | 2050 | 11550 | 0 | 0 | 10 | 10 | 10 | 40 | 2 | yes | 0 | yes | Cadre et porte | Sans
Por-202 | Etage 3 | 2040 | 450 | 0,45×2,04 | 0,45×2,04×0,07 | Cloison 70 0826278243 | D | Por-202 | 3D | Etage 3 | 6 | Mur-120 | HAG Acrylic White | 0.067445 | 0.06426 | 2.9129 | 0.918 | 470 | 2050 | 470 | 0.9635 | 0.9635 | 450 | 0 | 0 | 2040 | 1940 | 70 | 0.0426255 | 11550 | 0 | 13600 | 2050 | 11550 | 0 | 0 | 10 | 10 | 10 | 40 | 2 | yes | 0 | yes | Cadre et porte | Sans
Por-202 | Etage 3 | 2040 | 350 | 0,35×2,04 | 0,35×2,04×0,07 | Cloison 70 0826278243 | D | Por-202 | 3D | Etage 3 | 6 | Mur-120 | HAG Acrylic White | 0.053095 | 0.04998 | 2.4789 | 0.714 | 370 | 2050 | 370 | 0.7585 | 0.7585 | 350 | 0 | 0 | 2040 | 1940 | 70 | 0.0343405 | 11550 | 0 | 13600 | 2050 | 11550 | 0 | 0 | 10 | 10 | 10 | 40 | 2 | yes | 0 | yes | Cadre et porte | Sans
Por-280 | Etage 3 | 2040 | 830 | 0,83×2,04 | 0,83×2,04×0,07 | Cloison 70 0826278243 | G | Por-280 | 1-Projet | Etage 3 | 6 | Mur-156 | HAG Acrylic White | 0.132496 | 0.118524 | 4.92335 | 1.6932 | 910 | 2080 | 910 | 1.8928 | 1.8928 | 830 | 0 | 0 | 2040 | 1940 | 70 | 0.085966 | 11550 | 0 | 13630 | 2080 | 11550 | 0 | 0 | 40 | 20 | 15 | 40 | 2 | yes | 25.0695 | yes | Réglages rapides | Sur ouvrant | Dgt | A33 | Ch 1 | A33 | Dgt | Dgt | A33
Por-279 | Etage 3 | 2040 | 830 | 0,83×2,04 | 0,83×2,04×0,07 | Cloison 70 0826278243 | G | Por-279 | 1-Projet | Etage 3 | 6 | Mur-156 | HAG Acrylic White | 0.132496 | 0.118524 | 4.92335 | 1.6932 | 910 | 2080 | 910 | 1.8928 | 1.8928 | 830 | 0 | 0 | 2040 | 1940 | 70 | 0.085966 | 11550 | 0 | 13630 | 2080 | 11550 | 0 | 0 | 40 | 20 | 15 | 40 | 2 | yes | 90.0115 | yes | Réglages rapides | Sur ouvrant | Ch 2/pl | A33 | Dgt | A33 | Ch 2/pl | Ch 2/pl | A33
Por-280 | Etage 3 | 2040 | 830 | 0,83×2,04 | 0,83×2,04×0,07 | Cloison 70 0826278243 | G | Por-280 | 1-Projet | Etage 3 | 6 | Mur-149 | HAG Acrylic White | 0.123488 | 0.118524 | 4.92335 | 1.6932 | 848.135 | 2080 | 848.133 | 1.76412 | 1.76411 | 830 | 0 | 0 | 2040 | 1940 | 70 | 0.085966 | 11550 | 0 | 13630 | 2080 | 11550 | 0 | 0 | 40 | 20 | 15 | 40 | 2 | yes | 13.4092 | yes | Réglages rapides | Sur ouvrant | Dgt/pl | B34 | Dgt/pl | B34 | Dgt/pl
Por-278 | Etage 3 | 2040 | 830 | 0,83×2,04 | 0,83×2,04×0,07 | Cloison 70 0836576958 | D | Por-278 | 1-Projet | Etage 3 | 6 | Mur-148 | HAG Acrylic White | 0.132496 | 0.118524 | 4.92335 | 1.6932 | 910 | 2080 | 910 | 1.8928 | 1.8928 | 830 | 0 | 0 | 2040 | 1940 | 70 | 0.085966 | 11550 | 0 | 13630 | 2080 | 11550 | 0 | 0 | 40 | 20 | 15 | 40 | 2 | yes | 90 | yes | Réglages rapides | Sur ouvrant | Ch 1 | A31 | Dgt | A31 | Ch 1 | Ch 1 | A31
Por-278 | Etage 3 | 2040 | 830 | 0,83×2,04 | 0,83×2,04×0,07 | Cloison 70 0836576958 | D | Por-278 | 1-Projet | Etage 3 | 6 | Mur-148 | HAG Acrylic White | 0.132496 | 0.118524 | 4.92335 | 1.6932 | 910 | 2080 | 910 | 1.8928 | 1.8928 | 830 | 0 | 0 | 2040 | 1940 | 70 | 0.085966 | 11550 | 0 | 13630 | 2080 | 11550 | 0 | 0 | 40 | 20 | 15 | 40 | 2 | yes | 25.0695 | yes | Réglages rapides | Sur ouvrant | Dgt | A31 | Wc | A31 | Dgt | Dgt | A31
Por-275 | Etage 3 | 2040 | 580 | 0,58×2,04 | 0,58×2,04×0,07 | Cloison 70 0836576958 | D | Por-275 | 1-Projet | Etage 3 | 6 | Mur-148 | HAG Acrylic White | 0.0861 | 0.082824 | 3.3723 | 1.1832 | 600 | 2050 | 600 | 1.23 | 1.23 | 580 | 0 | 0 | 2040 | 1940 | 70 | 0.029732 | 11550 | 0 | 13600 | 2050 | 11550 | 0 | 0 | 10 | 10 | 10 | 20 | 2 | yes | 0 | yes | Cadre et porte | Sans | Dgt | A31 |  |  | Dgt | Dgt | A31
Por-278 | Etage 3 | 2040 | 830 | 0,83×2,04 | 0,83×2,04×0,07 | Cloison 70 0836576958 | D | Por-278 | 1-Projet | Etage 3 | 6 | Mur-148 | HAG Acrylic White | 0.132496 | 0.118524 | 4.92335 | 1.6932 | 910 | 2080 | 910 | 1.8928 | 1.8928 | 830 | 0 | 0 | 2040 | 1940 | 70 | 0.085966 | 11550 | 0 | 13630 | 2080 | 11550 | 0 | 0 | 40 | 20 | 15 | 40 | 2 | yes | 25.0695 | yes | Réglages rapides | Sur ouvrant | Dgt | A31 | Sde1 | A31 | Dgt | Dgt | A31
Por-278 | Etage 3 | 2040 | 830 | 0,83×2,04 | 0,83×2,04×0,07 | Cloison 70 0836576958 | D | Por-278 | 1-Projet | Etage 3 | 6 | Mur-148 | HAG Acrylic White | 0.132496 | 0.118524 | 4.92335 | 1.6932 | 910 | 2080 | 910 | 1.8928 | 1.8928 | 830 | 0 | 0 | 2040 | 1940 | 70 | 0.085966 | 11550 | 0 | 13630 | 2080 | 11550 | 0 | 0 | 40 | 20 | 15 | 40 | 2 | yes | 90 | yes | Réglages rapides | Sur ouvrant | Ch 3 | A31 |  |  | Ch 3; Dgt | Ch 3 | A31
Por-278 | Etage 3 | 2040 | 830 | 0,83×2,04 | 0,83×2,04×0,07 | Cloison 70 0836576958 | G | Por-278 | 1-Projet | Etage 3 | 6 | Mur-148 | HAG Acrylic White | 0.132496 | 0.118524 | 4.92335 | 1.6932 | 910 | 2080 | 910 | 1.8928 | 1.8928 | 830 | 0 | 0 | 2040 | 1940 | 70 | 0.085966 | 11550 | 0 | 13630 | 2080 | 11550 | 0 | 0 | 40 | 20 | 15 | 40 | 2 | yes | 90 | yes | Réglages rapides | Sur ouvrant | Dgt | A31 | Dgt | A31 | Ch 2; Dgt | Dgt | A31
Por-278 | Etage 3 | 2040 | 830 | 0,83×2,04 | 0,83×2,04×0,07 | Cloison 70 blanc | D | Por-278 | 1-Projet | Etage 3 | 6 | Mur-148 | HAG Acrylic White | 0.131768 | 0.118524 | 4.92335 | 1.6932 | 905 | 2080 | 905 | 1.8824 | 1.8824 | 830 | 0 | 0 | 2040 | 1940 | 70 | 0.085966 | 11550 | 0 | 13630 | 2080 | 11550 | 0 | 0 | 40 | 20 | 15 | 40 | 2 | yes | 25.0695 | yes | Réglages rapides | Sur ouvrant | Ch 1 | A31 |  |  | Ch 1 | Ch 1 | A31
Por-278 | Etage 3 | 2040 | 830 | 0,83×2,04 | 0,83×2,04×0,07 | Cloison 70 0826278243 | G | Por-278 | 1-Projet | Etage 3 | 6 | Mur-153 | HAG Acrylic White | 0.132496 | 0.118524 | 4.92335 | 1.6932 | 910 | 2080 | 910 | 1.8928 | 1.8928 | 830 | 0 | 0 | 2040 | 1940 | 70 | 0.085966 | 11550 | 0 | 13630 | 2080 | 11550 | 0 | 0 | 40 | 20 | 15 | 40 | 2 | yes | 90.333 | yes | Réglages rapides | Sur ouvrant | Sejour cuisine/pl | A34 | Ch 1 | A34 | Sejour cuisine/pl | Sejour cuisine/pl | A34
Por-279 | Etage 3 | 2040 | 530 | 0,53×2,04 | 0,53×2,04×0,07 | Cloison 70 0826278243 | G | Por-279 | 1-Projet | Etage 3 | 6 | Mur-153 | HAG Acrylic White | 0.0852064 | 0.075684 | 3.60035 | 1.0812 | 585.209 | 2080 | 585.209 | 1.21723 | 1.21723 | 530 | 0 | 0 | 2040 | 1940 | 70 | 0.0603985 | 11550 | 0 | 13630 | 2080 | 11550 | 0 | 0 | 40 | 20 | 15 | 40 | 2 | yes | 25.0695 | yes | Réglages rapides | Sur ouvrant | Sde/pl | A34 | Sde/pl | A34 | Sde/pl
Por-274 | Etage 3 | 2040 | 580 | 0,58×2,04 | 0,58×2,04×0,07 | Cloison 70 0826278243 | D | Por-274 | 1-Projet | Etage 3 | 6 | Mur-153 | HAG Acrylic White | 0.0861 | 0.082824 | 3.3723 | 1.1832 | 600 | 2050 | 600 | 1.23 | 1.23 | 580 | 0 | 0 | 2040 | 1940 | 70 | 0.029732 | 11550 | 0 | 13600 | 2050 | 11550 | 0 | 0 | 10 | 10 | 10 | 20 | 2 | yes | 0 | yes | Cadre et porte | Sans | Sejour cuisine | A32 |  |  | Sejour cuisine | Sejour cuisine | A32
Por-275 | Etage 3 | 2040 | 450 | 0,45×2,04 | 0,45×2,04×0,07 | Cloison 70 0836576958 | G | Por-275 | 1-Projet | Etage 3 | 6 | Mur-148 | HAG Acrylic White | 0.0648009 | 0.06426 | 2.8133 | 0.918 | 451.574 | 2050 | 451.574 | 0.925727 | 0.925727 | 450 | 0 | 0 | 2040 | 1940 | 70 | 0.0242655 | 11550 | 0 | 13600 | 2050 | 11550 | 0 | 0 | 10 | 10 | 10 | 20 | 2 | yes | 0 | yes | Cadre et porte | Sans | Sejour cuisine/pl | B35 | Sejour cuisine/pl | B35 | Sejour cuisine/pl
Por-296 | Etage 3 | 2040 | 930 | 0,93×2,04 | 0,93×2,04×0,18 | Beton 18 0018356637 | G | Por-296 | Interieurs logements | Etage 3 | 6 | Mur-143 | HAG Acrylic White | 0.378144 | 0.341496 | 6.48965 | 1.8972 | 1010 | 2080 | 1010 | 2.1008 | 2.1008 | 930 | 0 | 0 | 2040 | 1940 | 180 | 0.125102 | 11550 | 0 | 13630 | 2080 | 11550 | 0 | 0 | 40 | 20 | 15 | 40 | 2 | yes | 90 | yes | Réglages rapides | Sur ouvrant | Sejour cuisine/pl | A34 |  |  | Sejour cuisine/pl | Sejour cuisine/pl | A34
Por-274 | Etage 3 | 2040 | 580 | 0,58×2,04 | 0,58×2,04×0,07 | Cloison 70 0826278243 | G | Por-274 | 1-Projet | Etage 3 | 6 | Mur-149 | HAG Acrylic White | 0.0861 | 0.082824 | 3.3723 | 1.1832 | 600 | 2050 | 600 | 1.23 | 1.23 | 580 | 0 | 0 | 2040 | 1940 | 70 | 0.029732 | 11550 | 0 | 13600 | 2050 | 11550 | 0 | 0 | 10 | 10 | 10 | 20 | 2 | yes | 0 | yes | Hachure de fond/graphisme | Sans | Dgt/pl | B34 |  |  | Dgt/pl | Dgt/pl | B34
Por-279 | Etage 3 | 2040 | 930 | 0,93×2,04 | 0,93×2,04×0,18 | Beton 18 0018356637 | D | Por-279 | Interieurs logements | Etage 3 | 6 | Mur-142 | HAG Acrylic White | 0.378144 | 0.341496 | 6.48965 | 1.8972 | 1010 | 2080 | 1010 | 2.1008 | 2.1008 | 930 | 0 | 0 | 2040 | 1940 | 180 | 0.125102 | 11550 | 0 | 13630 | 2080 | 11550 | 0 | 0 | 40 | 20 | 15 | 40 | 2 | yes | 90 | yes | Réglages rapides | Sur ouvrant | Sejour cuisine/pl | A33 |  |  | Sejour cuisine/pl | Sejour cuisine/pl | A33
Por-278 | Etage 3 | 2040 | 830 | 0,83×2,04 | 0,83×2,04×0,07 | Cloison 70 0826278243 | D | Por-278 | 1-Projet | Etage 3 | 6 | Mur-153 | HAG Acrylic White | 0.132496 | 0.118524 | 4.92335 | 1.6932 | 910 | 2080 | 910 | 1.8928 | 1.8928 | 830 | 0 | 0 | 2040 | 1940 | 70 | 0.085966 | 11550 | 0 | 13630 | 2080 | 11550 | 0 | 0 | 40 | 20 | 15 | 40 | 2 | yes | 89.9975 | yes | Réglages rapides | Sur ouvrant | Ch 1 | A34 | Sde/pl | A34 | Ch 1 | Ch 1 | A34
Por-295 | Etage 3 | 2040 | 930 | 0,93×2,04 | 0,93×2,04×0,18 | Beton 18 0018356637 | G | Por-295 | Interieurs logements | Etage 3 | 6 | Mur-143 | HAG Acrylic White | 0.378144 | 0.341496 | 6.48965 | 1.8972 | 1010 | 2080 | 1010 | 2.1008 | 2.1008 | 930 | 0 | 0 | 2040 | 1940 | 180 | 0.125102 | 11550 | 0 | 13630 | 2080 | 11550 | 0 | 0 | 40 | 20 | 15 | 40 | 2 | yes | 90 | yes | Réglages rapides | Sur ouvrant | Entree/pl | B33 |  |  | Entree/pl | Entree/pl | B33
Por-296 | Etage 3 | 2040 | 930 | 0,93×2,04 | 0,93×2,04×0,18 | Beton 18 0018356637 | D | Por-296 | Interieurs logements | Etage 3 | 6 | Mur-143 | HAG Acrylic White | 0.378144 | 0.341496 | 6.48965 | 1.8972 | 1010 | 2080 | 1010 | 2.1008 | 2.1008 | 930 | 0 | 0 | 2040 | 1940 | 180 | 0.125102 | 11550 | 0 | 13630 | 2080 | 11550 | 0 | 0 | 40 | 20 | 15 | 40 | 2 | yes | 90 | yes | Réglages rapides | Sur ouvrant | Entree/pl | B32 |  |  | Entree/pl | Entree/pl | B32
Por-296 | Etage 3 | 2040 | 930 | 0,93×2,04 | 0,93×2,04×0,18 | Beton 18 0018356637 | D | Por-296 | Interieurs logements | Etage 3 | 6 | Mur-143 | HAG Acrylic White | 0.378144 | 0.341496 | 6.48965 | 1.8972 | 1010 | 2080 | 1010 | 2.1008 | 2.1008 | 930 | 0 | 0 | 2040 | 1940 | 180 | 0.125102 | 11550 | 0 | 13630 | 2080 | 11550 | 0 | 0 | 40 | 20 | 15 | 40 | 2 | yes | 90 | yes | Réglages rapides | Sur ouvrant
Por-288 | Etage 3 | 2040 | 800 | 0,80×2,04 | 0,80×2,04×0,02 | mur 2cm | D | Por-288 | 1-Projet | Etage 3 | 6 | Mur-148 | HAG Acrylic White | 0.036608 | 0.03264 | 4.17895 | 1.632 | 880 | 2080 | 880 | 1.8304 | 1.8304 | 800 | 0 | 0 | 2040 | 1940 | 20 | 0.0372118 | 11550 | 0 | 13630 | 2080 | 11550 | 0 | 0 | 40 | 20 | 15 | 20 | 2 | no | 14.3266 | yes | Réglages rapides | Sans | Sde | B34 | Sde | B34 | Sde | Sde | B34
Por-288 | Etage 3 | 2040 | 800 | 0,80×2,04 | 0,80×2,04×0,02 | mur 2cm | D | Por-288 | 1-Projet | Etage 3 | 6 | Mur-148 | HAG Acrylic White | 0.036608 | 0.03264 | 4.17895 | 1.632 | 880 | 2080 | 880 | 1.8304 | 1.8304 | 800 | 0 | 0 | 2040 | 1940 | 20 | 0.0372118 | 11550 | 0 | 13630 | 2080 | 11550 | 0 | 0 | 40 | 20 | 15 | 20 | 2 | no | 14.3266 | yes | Réglages rapides | Sans | Sde | B31 | Sde | B31 | Sde | Sde | B31
Por-288 | Etage 3 | 2040 | 800 | 0,80×2,04 | 0,80×2,04×0,02 | mur 2cm | G | Por-288 | 1-Projet | Etage 3 | 6 | Mur-148 | HAG Acrylic White | 0.036608 | 0.03264 | 4.17895 | 1.632 | 880 | 2080 | 880 | 1.8304 | 1.8304 | 800 | 0 | 0 | 2040 | 1940 | 20 | 0.0372118 | 11550 | 0 | 13630 | 2080 | 11550 | 0 | 0 | 40 | 20 | 15 | 20 | 2 | no | 14.3266 | yes | Réglages rapides | Sans | Sde | B35 | Sde | B35 | Sde | Sde | B35
Por-288 | Etage 3 | 2040 | 800 | 0,80×2,04 | 0,80×2,04×0,02 | mur 2cm | G | Por-288 | 1-Projet | Etage 3 | 6 | Mur-148 | HAG Acrylic White | 0.036608 | 0.03264 | 4.17895 | 1.632 | 880 | 2080 | 880 | 1.8304 | 1.8304 | 800 | 0 | 0 | 2040 | 1940 | 20 | 0.0372118 | 11550 | 0 | 13630 | 2080 | 11550 | 0 | 0 | 40 | 20 | 15 | 20 | 2 | no | 14.3266 | yes | Réglages rapides | Sans | Sde | B33 | Sde | B33 | Sde | Sde | B33
Por-288 | Etage 3 | 2040 | 800 | 0,80×2,04 | 0,80×2,04×0,02 | mur 2cm | G | Por-288 | 1-Projet | Etage 3 | 6 | Mur-148 | HAG Acrylic White | 0.0366081 | 0.03264 | 4.17895 | 1.632 | 880 | 2080 | 880 | 1.8304 | 1.8304 | 800 | 0 | 0 | 2040 | 1940 | 20 | 0.0372118 | 11550 | 0 | 13630 | 2080 | 11550 | 0 | 0 | 40 | 20 | 15 | 20 | 2 | no | 14.3266 | yes | Réglages rapides | Sans | Sde | B32 | Sde | B32 | Sde | Sde | B32
Por-288 | Etage 3 | 2040 | 800 | 0,80×2,04 | 0,80×2,04×0,02 | mur 2cm | G | Por-288 | 1-Projet | Etage 3 | 6 | Mur-148 | HAG Acrylic White | 0.036608 | 0.03264 | 4.17895 | 1.632 | 880 | 2080 | 880 | 1.8304 | 1.8304 | 800 | 0 | 0 | 2040 | 1940 | 20 | 0.0372118 | 11550 | 0 | 13630 | 2080 | 11550 | 0 | 0 | 40 | 20 | 15 | 20 | 2 | no | 14.3266 | yes | Réglages rapides | Sans | Sde | A32 | Sde | A32 | Sde | Sde | A32
Por-288 | Etage 3 | 2040 | 800 | 0,80×2,04 | 0,80×2,04×0,02 | mur 2cm | G | Por-288 | 1-Projet | Etage 3 | 6 | Mur-148 | HAG Acrylic White | 0.036608 | 0.03264 | 4.17895 | 1.632 | 880 | 2080 | 880 | 1.8304 | 1.8304 | 800 | 0 | 0 | 2040 | 1940 | 20 | 0.0372118 | 11550 | 0 | 13630 | 2080 | 11550 | 0 | 0 | 40 | 20 | 15 | 20 | 2 | no | 14.3266 | yes | Réglages rapides | Sans | Sde | A33 | Sde | A33 | Sde | Sde | A33
Por-288 | Etage 3 | 2040 | 800 | 0,80×2,04 | 0,80×2,04×0,02 | mur 2cm | D | Por-288 | 1-Projet | Etage 3 | 6 | Mur-148 | HAG Acrylic White | 0.0361924 | 0.03264 | 4.17895 | 1.632 | 880 | 2080 | 860.017 | 1.8304 | 1.78884 | 800 | 0 | 0 | 2040 | 1940 | 20 | 0.0372118 | 11550 | 0 | 13630 | 2080 | 11550 | 0 | 0 | 40 | 20 | 15 | 20 | 2 | no | 14.3266 | yes | Réglages rapides | Sans | Sde/pl | A34 | Sde/pl | A34 | Sde/pl | Sde/pl | A34
Por-278 | Etage 3 | 2040 | 830 | 0,83×2,04 | 0,83×2,04×0,07 | Cloison 70 0826278243 | G | Por-278 | 1-Projet | Etage 3 | 6 | Mur-121 | HAG Acrylic White | 0.132496 | 0.118524 | 4.92335 | 1.6932 | 910 | 2080 | 910 | 1.8928 | 1.8928 | 830 | 0 | 0 | 2040 | 1940 | 70 | 0.085966 | 11550 | 0 | 13630 | 2080 | 11550 | 0 | 0 | 40 | 20 | 15 | 40 | 2 | yes | 25.655 | yes | Réglages rapides | Sur ouvrant | Sejour cuisine | A32 | Wc | A32 | Sejour cuisine | Sejour cuisine | A32
Por-293 | Etage 3 | 2040 | 830 | 0,83×2,04 | 0,83×2,04×0,07 | Cloison 70 0826278243 | G | Por-293 | 1-Projet | Etage 3 | 6 | Mur-149 | HAG Acrylic White | 0.132496 | 0.118524 | 4.92335 | 1.6932 | 910 | 2080 | 910 | 1.8928 | 1.8928 | 830 | 0 | 0 | 2040 | 1940 | 70 | 0.085966 | 11550 | 0 | 13630 | 2080 | 11550 | 0 | 0 | 40 | 20 | 15 | 40 | 2 | yes | 90 | yes | Réglages rapides | Sur ouvrant | Ch 1/pl | B31 | Sejour cuisine/pl | B31 | Ch 1/pl | Ch 1/pl | B31
Por-278 | Etage 3 | 2040 | 830 | 0,83×2,04 | 0,83×2,04×0,07 | Cloison 70 0826278243 | G | Por-278 | 1-Projet | Etage 3 | 6 | Mur-149 | HAG Acrylic White | 0.132496 | 0.118524 | 4.92335 | 1.6932 | 910 | 2080 | 910 | 1.8928 | 1.8928 | 830 | 0 | 0 | 2040 | 1940 | 70 | 0.085966 | 11550 | 0 | 13630 | 2080 | 11550 | 0 | 0 | 40 | 20 | 15 | 40 | 2 | yes | 22.6789 | yes | Réglages rapides | Sur ouvrant | Entree/pl | B32 | Cellier | B32 | Entree/pl | Entree/pl | B32
Por-276 | Etage 3 | 2040 | 830 | 0,83×2,04 | 0,83×2,04×0,07 | Cloison 70 0826278243 | G | Por-276 | 1-Projet | Etage 3 | 6 | Mur-149 | HAG Acrylic White | 0.132496 | 0.118524 | 4.92335 | 1.6932 | 910 | 2080 | 910 | 1.8928 | 1.8928 | 830 | 0 | 0 | 2040 | 1940 | 70 | 0.085966 | 11550 | 0 | 13630 | 2080 | 11550 | 0 | 0 | 40 | 20 | 15 | 40 | 2 | yes | 90 | yes | Réglages rapides | Sur ouvrant | Entree/pl | B33 | Entree/pl | B33 | Ch 2
Por-275 | Etage 3 | 2040 | 830 | 0,83×2,04 | 0,83×2,04×0,07 | Cloison 70 0826278243 | D | Por-275 | 1-Projet | Etage 3 | 6 | Mur-149 | HAG Acrylic White | 0.132496 | 0.118524 | 4.92335 | 1.6932 | 910 | 2080 | 910 | 1.8928 | 1.8928 | 830 | 0 | 0 | 2040 | 1940 | 70 | 0.085966 | 11550 | 0 | 13630 | 2080 | 11550 | 0 | 0 | 40 | 20 | 15 | 40 | 2 | yes | 31.1825 | yes | Réglages rapides | Sur ouvrant | Entree/pl | B33 | Ch 1/pl | B33 | Entree/pl | Entree/pl | B33
Por-278 | Etage 3 | 2040 | 830 | 0,83×2,04 | 0,83×2,04×0,07 | Cloison 70 0826278243 | G | Por-278 | 1-Projet | Etage 3 | 6 | Mur-149 | HAG Acrylic White | 0.132496 | 0.118524 | 4.92335 | 1.6932 | 910 | 2080 | 910 | 1.8928 | 1.8928 | 830 | 0 | 0 | 2040 | 1940 | 70 | 0.085966 | 11550 | 0 | 13630 | 2080 | 11550 | 0 | 0 | 40 | 20 | 15 | 40 | 2 | yes | 22.6789 | yes | Réglages rapides | Sur ouvrant | Entree/pl | B33 | Cellier | B33 | Entree/pl | Entree/pl | B33
Por-296 | Etage 3 | 2040 | 930 | 0,93×2,04 | 0,93×2,04×0,18 | Beton 18 0018356637 | G | Por-296 | Interieurs logements | Etage 3 | 6 | Mur-143 | HAG Acrylic White | 0.378144 | 0.341496 | 6.48965 | 1.8972 | 1010 | 2080 | 1010 | 2.1008 | 2.1008 | 930 | 0 | 0 | 2040 | 1940 | 180 | 0.125102 | 11550 | 0 | 13630 | 2080 | 11550 | 0 | 0 | 40 | 20 | 15 | 40 | 2 | yes | 90 | yes | Réglages rapides | Sur ouvrant | Sejour cuisine/pl | B31 |  |  | Sejour cuisine/pl | Sejour cuisine/pl | B31
Por-278 | Etage 3 | 2040 | 830 | 0,83×2,04 | 0,83×2,04×0,07 | Cloison 70 0826278243 | D | Por-278 | 1-Projet | Etage 3 | 6 | Mur-149 | HAG Acrylic White | 0.132496 | 0.118524 | 4.92335 | 1.6932 | 910 | 2080 | 910 | 1.8928 | 1.8928 | 830 | 0 | 0 | 2040 | 1940 | 70 | 0.085966 | 11550 | 0 | 13630 | 2080 | 11550 | 0 | 0 | 40 | 20 | 15 | 40 | 2 | yes | 22.6789 | yes | Réglages rapides | Sur ouvrant | Entree/pl | B33 | Wc | B33 | Entree/pl | Entree/pl | B33
Por-299 | Etage 3 | 2040 | 930 | 0,93×2,04 | 0,93×2,04×0,18 | Beton 18 0018356637 | G | Por-299 | Interieurs logements | Etage 3 | 6 | Mur-142 | HAG Acrylic White | 0.378144 | 0.341496 | 6.48965 | 1.8972 | 1010 | 2080 | 1010 | 2.1008 | 2.1008 | 930 | 0 | 0 | 2040 | 1940 | 180 | 0.125102 | 11550 | 0 | 13630 | 2080 | 11550 | 0 | 0 | 40 | 20 | 15 | 40 | 2 | yes | 90 | yes | Réglages rapides | Sur ouvrant |  |  |  |  | Entree
Por-244 | Etage 3 | 650 | 450 | 0,45×0,65 | 0,45×0,65×0,18 | Beton 18 0018356637 | D | Por-244 | Interieurs logements | Etage 3 | 6 | Mur-142 | HAG Acrylic White | 0.059094 | 0.05265 | 1.39885 | 0.2925 | 490 | 670 | 490 | 0.3283 | 0.3283 | 450 | 300 | 200 | 950 | 850 | 180 | 0.016551 | 11850 | 300 | 12520 | 970 | 11850 | 300 | 300 | 20 | 20 | 15 | 20 | 2 | yes | 0 | no | Réglages rapides | Sans
Por-274 | Etage 3 | 2040 | 580 | 0,58×2,04 | 0,58×2,04×0,07 | Cloison 70 0826278243 | G | Por-274 | 1-Projet | Etage 3 | 6 | Mur-149 | HAG Acrylic White | 0.0861 | 0.082824 | 3.3723 | 1.1832 | 600 | 2050 | 600 | 1.23 | 1.23 | 580 | 0 | 0 | 2040 | 1940 | 70 | 0.029732 | 11550 | 0 | 13600 | 2050 | 11550 | 0 | 0 | 10 | 10 | 10 | 20 | 2 | yes | 0 | yes | Cadre et porte | Sans | Entree/pl | B35 | Entree/pl | B35 | Entree/pl
Por-278 | Etage 3 | 2040 | 830 | 0,83×2,04 | 0,83×2,04×0,07 | Cloison 70 0826278243 | G | Por-278 | 1-Projet | Etage 3 | 6 | Mur-149 | HAG Acrylic White | 0.132496 | 0.118524 | 4.92335 | 1.6932 | 910 | 2080 | 910 | 1.8928 | 1.8928 | 830 | 520 | 420 | 2560 | 2460 | 70 | 0.085966 | 12070 | 520 | 14150 | 2600 | 12070 | 520 | 520 | 40 | 20 | 15 | 40 | 2 | yes | 22.6789 | yes | Réglages rapides | Sur ouvrant | Entree/pl | B35 | Sde | B35 | Entree/pl | Entree/pl | B35
Por-274 | Etage 3 | 2040 | 580 | 0,58×2,04 | 0,58×2,04×0,07 | Cloison 70 0826278243 | D | Por-274 | 1-Projet | Etage 3 | 6 | Mur-149 | HAG Acrylic White | 0.0861 | 0.082824 | 3.3723 | 1.1832 | 600 | 2050 | 600 | 1.23 | 1.23 | 580 | 0 | 0 | 2040 | 1940 | 70 | 0.029732 | 11550 | 0 | 13600 | 2050 | 11550 | 0 | 0 | 10 | 10 | 10 | 20 | 2 | yes | 0 | yes | Cadre et porte | Sans | Sejour cuisine/pl | B31 |  |  | Sejour cuisine/pl | Sejour cuisine/pl | B31
Por-296 | Etage 3 | 2040 | 930 | 0,93×2,04 | 0,93×2,04×0,18 | Beton 18 0018356637 | D | Por-296 | Interieurs logements | Etage 3 | 6 | Mur-143 | HAG Acrylic White | 0.378144 | 0.341496 | 6.48965 | 1.8972 | 1010 | 2080 | 1010 | 2.1008 | 2.1008 | 930 | 0 | 0 | 2040 | 1940 | 180 | 0.125102 | 11550 | 0 | 13630 | 2080 | 11550 | 0 | 0 | 40 | 20 | 15 | 40 | 2 | yes | 90 | yes | Réglages rapides | Sur ouvrant | Sejour cuisine | A32 |  |  | Sejour cuisine | Sejour cuisine | A32
Por-277 | Etage 3 | 2040 | 830 | 0,83×2,04 | 0,83×2,04×0,07 | Cloison 70 0826278243 | D | Por-277 | 1-Projet | Etage 3 | 6 | Mur-150 | HAG Acrylic White | 0.132496 | 0.118524 | 4.92335 | 1.6932 | 910 | 2080 | 910 | 1.8928 | 1.8928 | 830 | 0 | 0 | 2040 | 1940 | 70 | 0.085966 | 11550 | 0 | 13630 | 2080 | 11550 | 0 | 0 | 40 | 20 | 15 | 40 | 2 | yes | 21.9195 | yes | Réglages rapides | Sur ouvrant | Entree/pl | B33 | Sde | B33 | Entree/pl | Entree/pl | B33
Por-277 | Etage 3 | 2040 | 580 | 0,58×2,04 | 0,58×2,04×0,07 | Cloison 70 0826278243 | D | Por-277 | 1-Projet | Etage 3 | 6 | Mur-150 | HAG Acrylic White | 0.0861 | 0.082824 | 3.3723 | 1.1832 | 600 | 2050 | 600 | 1.23 | 1.23 | 580 | 0 | 0 | 2040 | 1940 | 70 | 0.029732 | 11550 | 0 | 13600 | 2050 | 11550 | 0 | 0 | 10 | 10 | 10 | 20 | 2 | yes | 0 | yes | Cadre et porte | Sans | Entree/pl | B33 |  |  | Entree/pl | Entree/pl | B33
Por-299 | Etage 3 | 2040 | 930 | 0,93×2,04 | 0,93×2,04×0,18 | Beton 18 0018356637 | G | Por-299 | Interieurs logements | Etage 3 | 6 | Mur-143 | HAG Acrylic White | 0.378144 | 0.341496 | 6.48965 | 1.8972 | 1010 | 2080 | 1010 | 2.1008 | 2.1008 | 930 | 0 | 0 | 2040 | 1940 | 180 | 0.125102 | 11550 | 0 | 13630 | 2080 | 11550 | 0 | 0 | 40 | 20 | 15 | 40 | 2 | yes | 90 | yes | Réglages rapides | Sur ouvrant | Entree/pl | B35 |  |  | Entree/pl | Entree/pl | B35
Por-295 | Etage 3 | 2040 | 930 | 0,93×2,04 | 0,93×2,04×0,18 | Beton 18 0018356637 | G | Por-295 | Interieurs logements | Etage 3 | 6 | Mur-143 | HAG Acrylic White | 0.378144 | 0.341496 | 6.48965 | 1.8972 | 1010 | 2080 | 1010 | 2.1008 | 2.1008 | 930 | 0 | 0 | 2040 | 1940 | 180 | 0.125102 | 11550 | 0 | 13630 | 2080 | 11550 | 0 | 0 | 40 | 20 | 15 | 40 | 2 | yes | 90 | yes | Réglages rapides | Sur ouvrant
Por-283 | Etage 3 | 2040 | 830 | 0,83×2,04 | 0,83×2,04×0,07 | Cloison 70 0826278243 | G | Por-283 | 1-Projet | Etage 3 | 6 | Mur-149 | HAG Acrylic White | 0.132496 | 0.118524 | 4.92335 | 1.6932 | 910 | 2080 | 910 | 1.8928 | 1.8928 | 830 | 0 | 0 | 2040 | 1940 | 70 | 0.085966 | 11550 | 0 | 13630 | 2080 | 11550 | 0 | 0 | 40 | 20 | 15 | 40 | 2 | yes | 22.4017 | yes | Réglages rapides | Sur ouvrant |  |  |  |  | Entree
Por-238 | Etage 3 | 650 | 450 | 0,45×0,65 | 0,45×0,65×0,18 | Beton 18 0018356637 | G | Por-238 | Interieurs logements | Etage 3 | 6 | Mur-143 | HAG Acrylic White | 0.059094 | 0.05265 | 1.39885 | 0.2925 | 490 | 670 | 490 | 0.3283 | 0.3283 | 450 | 300 | 200 | 950 | 850 | 180 | 0.016551 | 11850 | 300 | 12520 | 970 | 11850 | 300 | 300 | 20 | 20 | 15 | 20 | 2 | yes | 0 | no | Réglages rapides | Sans
Por-285 | Etage 3 | 2040 | 830 | 0,83×2,04 | 0,83×2,04×0,07 | Cloison 70 0826278243 | D | Por-285 | 1-Projet | Etage 3 | 6 | Mur-149 | HAG Acrylic White | 0.132496 | 0.118524 | 4.92335 | 1.6932 | 910 | 2080 | 910 | 1.8928 | 1.8928 | 830 | 0 | 0 | 2040 | 1940 | 70 | 0.085966 | 11550 | 0 | 13630 | 2080 | 11550 | 0 | 0 | 40 | 20 | 15 | 40 | 2 | yes | 25.655 | yes | Réglages rapides | Sur ouvrant | Dgt/pl | B34 | Sdb | B34 | Dgt/pl | Dgt/pl | B34
Por-276 | Etage 3 | 2040 | 830 | 0,83×2,04 | 0,83×2,04×0,07 | Cloison 70 0826278243 | D | Por-276 | 1-Projet | Etage 3 | 6 | Mur-149 | HAG Acrylic White | 0.132496 | 0.118524 | 4.92335 | 1.6932 | 910 | 2080 | 910 | 1.8928 | 1.8928 | 830 | 0 | 0 | 2040 | 1940 | 70 | 0.085966 | 11550 | 0 | 13630 | 2080 | 11550 | 0 | 0 | 40 | 20 | 15 | 40 | 2 | yes | 22.6807 | yes | Réglages rapides | Sur ouvrant | Entree/pl | B32 | Wc | B32 | Entree/pl | Entree/pl | B32
Por-274 | Etage 3 | 2040 | 580 | 0,58×2,04 | 0,58×2,04×0,07 | Cloison 70 0826278243 | G | Por-274 | 1-Projet | Etage 3 | 6 | Mur-150 | HAG Acrylic White | 0.0861 | 0.082824 | 3.3723 | 1.1832 | 600 | 2050 | 600 | 1.23 | 1.23 | 580 | 0 | 0 | 2040 | 1940 | 70 | 0.029732 | 11550 | 0 | 13600 | 2050 | 11550 | 0 | 0 | 10 | 10 | 10 | 20 | 2 | yes | 0 | yes | Cadre et porte | Sans | Entree/pl | B32 |  |  | Entree/pl | Entree/pl | B32
Por-277 | Etage 3 | 2040 | 830 | 0,83×2,04 | 0,83×2,04×0,07 | Cloison 70 0826278243 | G | Por-277 | 1-Projet | Etage 3 | 6 | Mur-150 | HAG Acrylic White | 0.132496 | 0.118524 | 4.92335 | 1.6932 | 910 | 2080 | 910 | 1.8928 | 1.8928 | 830 | 0 | 0 | 2040 | 1940 | 70 | 0.085966 | 11550 | 0 | 13630 | 2080 | 11550 | 0 | 0 | 40 | 20 | 15 | 40 | 2 | yes | 21.9195 | yes | Réglages rapides | Sur ouvrant | Entree/pl | B32 | Sde | B32 | Entree/pl | Entree/pl | B32
Por-278 | Etage 3 | 2040 | 830 | 0,83×2,04 | 0,83×2,04×0,07 | Cloison 70 0826278243 | G | Por-278 | 1-Projet | Etage 3 | 6 | Mur-151 | HAG Acrylic White | 0.132496 | 0.118524 | 4.92335 | 1.6932 | 910 | 2080 | 910 | 1.8928 | 1.8928 | 830 | 0 | 0 | 2040 | 1940 | 70 | 0.085966 | 11550 | 0 | 13630 | 2080 | 11550 | 0 | 0 | 40 | 20 | 15 | 40 | 2 | yes | 29.5716 | yes | Réglages rapides | Sur ouvrant | Ch 1 | A32 |  |  | Ch 1; Sde | Ch 1 | A32
Por-276 | Etage 3 | 2040 | 830 | 0,83×2,04 | 0,83×2,04×0,07 | Cloison 70 0826278243 | D | Por-276 | 1-Projet | Etage 3 | 6 | Mur-149 | HAG Acrylic White | 0.132496 | 0.118524 | 4.92335 | 1.6932 | 910 | 2080 | 910 | 1.8928 | 1.8928 | 830 | 0 | 0 | 2040 | 1940 | 70 | 0.085966 | 11550 | 0 | 13630 | 2080 | 11550 | 0 | 0 | 40 | 20 | 15 | 40 | 2 | yes | 90 | yes | Réglages rapides | Sur ouvrant | Ch 2 | B32 | Entree/pl | B32 | Ch 2 | Ch 2 | B32
Por-275 | Etage 3 | 2040 | 830 | 0,83×2,04 | 0,83×2,04×0,07 | Cloison 70 0826278243 | G | Por-275 | 1-Projet | Etage 3 | 6 | Mur-149 | HAG Acrylic White | 0.132496 | 0.118524 | 4.92335 | 1.6932 | 910 | 2080 | 910 | 1.8928 | 1.8928 | 830 | 0 | 0 | 2040 | 1940 | 70 | 0.085966 | 11550 | 0 | 13630 | 2080 | 11550 | 0 | 0 | 40 | 20 | 15 | 40 | 2 | yes | 90 | yes | Réglages rapides | Sur ouvrant | Ch 1/pl | B32 | Entree/pl | B32 | Ch 1/pl | Ch 1/pl | B32
Por-277 | Etage 3 | 2040 | 830 | 0,83×2,04 | 0,83×2,04×0,07 | Cloison 70 0826278243 | G | Por-277 | 1-Projet | Etage 3 | 6 | Mur-149 | HAG Acrylic White | 0.132496 | 0.118524 | 4.92335 | 1.6932 | 910 | 2080 | 910 | 1.8928 | 1.8928 | 830 | 0 | 0 | 2040 | 1940 | 70 | 0.085966 | 11550 | 0 | 13630 | 2080 | 11550 | 0 | 0 | 40 | 20 | 15 | 40 | 2 | yes | 90 | yes | Réglages rapides | Sur ouvrant | Dgt/pl | B34 | Dgt/pl | B34 | Ch 2
Por-288 | Etage 3 | 2040 | 830 | 0,83×2,04 | 0,83×2,04×0,07 | Cloison 70 0826278243 | D | Por-288 | 1-Projet | Etage 3 | 6 | Mur-149 | HAG Acrylic White | 0.132496 | 0.118524 | 4.92335 | 1.6932 | 910 | 2080 | 910 | 1.8928 | 1.8928 | 830 | 0 | 0 | 2040 | 1940 | 70 | 0.085966 | 11550 | 0 | 13630 | 2080 | 11550 | 0 | 0 | 40 | 20 | 15 | 40 | 2 | yes | 90.0118 | yes | Réglages rapides | Sur ouvrant | Ch 1/pl | B34 | Dgt/pl | B34 | Ch 1/pl | Ch 1/pl | B34
Por-277 | Etage 3 | 2040 | 830 | 0,83×2,04 | 0,83×2,04×0,07 | Cloison 70 0826278243 | D | Por-277 | 1-Projet | Etage 3 | 6 | Mur-149 | HAG Acrylic White | 0.132496 | 0.118524 | 4.92335 | 1.6932 | 910 | 2080 | 910 | 1.8928 | 1.8928 | 830 | 0 | 0 | 2040 | 1940 | 70 | 0.085966 | 11550 | 0 | 13630 | 2080 | 11550 | 0 | 0 | 40 | 20 | 15 | 40 | 2 | yes | 90 | yes | Réglages rapides | Sur ouvrant | Dgt/pl | B34 | Dgt/pl | B34 | Ch 3
Por-274 | Etage 3 | 2040 | 580 | 0,58×2,04 | 0,58×2,04×0,07 | Cloison 70 0826278243 | D | Por-274 | 1-Projet | Etage 3 | 6 | Mur-155 | HAG Acrylic White | 0.0860976 | 0.082824 | 3.3723 | 1.1832 | 599.984 | 2050 | 599.983 | 1.22997 | 1.22997 | 580 | 0 | 0 | 2040 | 1940 | 70 | 0.029732 | 11550 | 0 | 13600 | 2050 | 11550 | 0 | 0 | 10 | 10 | 10 | 20 | 2 | yes | 0 | yes | Cadre et porte | Sans | Dgt | A33 |  |  | Dgt | Dgt | A33
Por-281 | Etage 3 | 2040 | 830 | 0,83×2,04 | 0,83×2,04×0,07 | Cloison 70 0826278243 | D | Por-281 | 1-Projet | Etage 3 | 6 | Mur-156 | HAG Acrylic White | 0.132496 | 0.118524 | 4.92335 | 1.6932 | 910 | 2080 | 910 | 1.8928 | 1.8928 | 830 | 0 | 0 | 2040 | 1940 | 70 | 0.085966 | 11550 | 0 | 13630 | 2080 | 11550 | 0 | 0 | 40 | 20 | 15 | 40 | 2 | yes | 25.0695 | yes | Réglages rapides | Sur ouvrant | Dgt | A33 | Wc | A33 | Dgt | Dgt | A33
Por-284 | Etage 3 | 2040 | 830 | 0,83×2,04 | 0,83×2,04×0,07 | Cloison 70 0826278243 | D | Por-284 | 1-Projet | Etage 3 | 6 | Mur-156 | HAG Acrylic White | 0.132496 | 0.118524 | 4.92335 | 1.6932 | 910 | 2080 | 910 | 1.8928 | 1.8928 | 830 | 0 | 0 | 2040 | 1940 | 70 | 0.085966 | 11550 | 0 | 13630 | 2080 | 11550 | 0 | 0 | 40 | 20 | 15 | 40 | 2 | yes | 25.0695 | yes | Réglages rapides | Sur ouvrant | Sde | A33 | Sde | A33 | Dgt
Por-278 | Etage 3 | 2040 | 830 | 0,83×2,04 | 0,83×2,04×0,07 | Cloison 70 0826278243 | G | Por-278 | 1-Projet | Etage 3 | 6 | Mur-149 | HAG Acrylic White | 0.132496 | 0.118524 | 4.92335 | 1.6932 | 910 | 2080 | 910 | 1.8928 | 1.8928 | 830 | 0 | 0 | 2040 | 1940 | 70 | 0.085966 | 11550 | 0 | 13630 | 2080 | 11550 | 0 | 0 | 40 | 20 | 15 | 40 | 2 | yes | 25.0695 | yes | Réglages rapides | Sur ouvrant | Sejour cuisine | B34 |  |  | cellier; Sejour cuisine | Sejour cuisine | B34
Por-275 | Etage 3 | 2040 | 580 | 0,58×2,04 | 0,58×2,04×0,07 | Cloison 70 0826278243 | D | Por-275 | 1-Projet | Etage 3 | 6 | Mur-153 | HAG Acrylic White | 0.0861 | 0.082824 | 3.3723 | 1.1832 | 600 | 2050 | 600 | 1.23 | 1.23 | 580 | 0 | 0 | 2040 | 1940 | 70 | 0.029732 | 11550 | 0 | 13600 | 2050 | 11550 | 0 | 0 | 10 | 10 | 10 | 20 | 2 | yes | 0 | yes | Cadre et porte | Sans | Sejour cuisine/pl | A34 |  |  | Sejour cuisine/pl | Sejour cuisine/pl | A34
Por-274 | Etage 3 | 2040 | 600 | 0,60×2,04 | 0,60×2,04×0,07 | Cloison 70 0826278243 | G | Por-274 | 1-Projet | Etage 3 | 6 | Mur-149 | HAG Acrylic White | 0.087535 | 0.08568 | 3.4583 | 1.224 | 610 | 2050 | 610 | 1.2505 | 1.2505 | 600 | 0 | 0 | 2040 | 1940 | 70 | 0.030573 | 11550 | 0 | 13600 | 2050 | 11550 | 0 | 0 | 10 | 10 | 10 | 20 | 2 | yes | 0 | yes | Cadre et porte | Sans | Sejour cuisine/pl | B31 |  |  | Sejour cuisine/pl | Sejour cuisine/pl | B31
Por-288 | Etage 3 | 2040 | 830 | 0,83×2,04 | 0,83×2,04×0,07 | Cloison 70 0826278243 | D | Por-288 | 1-Projet | Etage 3 | 6 | Mur-149 | HAG Acrylic White | 0.132496 | 0.118524 | 4.92335 | 1.6932 | 910 | 2080 | 910 | 1.8928 | 1.8928 | 830 | 0 | 0 | 2040 | 1940 | 70 | 0.085966 | 11550 | 0 | 13630 | 2080 | 11550 | 0 | 0 | 40 | 20 | 15 | 40 | 2 | yes | 30.5858 | yes | Réglages rapides | Sur ouvrant | Ch 1/pl | B34 | Sde | B34 | Ch 1/pl | Ch 1/pl | B34
Por-288 | Etage 3 | 2040 | 730 | 0,73×2,04 | 0,73×2,04×0,07 | Cloison 70 0826278243 | D | Por-288 | 1-Projet | Etage 3 | 6 | Mur-149 | HAG Acrylic White | 0.117936 | 0.104244 | 4.48235 | 1.4892 | 810 | 2080 | 810 | 1.6848 | 1.6848 | 730 | 0 | 0 | 2040 | 1940 | 70 | 0.0774435 | 11550 | 0 | 13630 | 2080 | 11550 | 0 | 0 | 40 | 20 | 15 | 40 | 2 | yes | 30.5858 | yes | Réglages rapides | Sur ouvrant | Ch 1/pl | B34 |  |  | Ch 1/pl | Ch 1/pl | B34
Por-278 | Etage 3 | 2040 | 830 | 0,83×2,04 | 0,83×2,04×0,07 | Cloison 70 0826278243 | G | Por-278 | 1-Projet | Etage 3 | 6 | Mur-153 | HAG Acrylic White | 0.132496 | 0.118524 | 4.92335 | 1.6932 | 910 | 2080 | 910 | 1.8928 | 1.8928 | 830 | 0 | 0 | 2040 | 1940 | 70 | 0.085966 | 11550 | 0 | 13630 | 2080 | 11550 | 0 | 0 | 40 | 20 | 15 | 40 | 2 | yes | 89.9218 | yes | Réglages rapides | Sur ouvrant | Sejour cuisine | A32 | Sejour cuisine | A32 | Ch 1 | Sejour cuisine | A32
Por-278 | Etage 3 | 2040 | 830 | 0,83×2,04 | 0,83×2,04×0,07 | Cloison 70 0826278243 | G | Por-278 | 1-Projet | Etage 3 | 6 | Mur-149 | HAG Acrylic White | 0.132496 | 0.118524 | 4.92335 | 1.6932 | 910 | 2080 | 910 | 1.8928 | 1.8928 | 830 | 0 | 0 | 2040 | 1940 | 70 | 0.085966 | 11550 | 0 | 13630 | 2080 | 11550 | 0 | 0 | 40 | 20 | 15 | 40 | 2 | yes | 22.6789 | yes | Réglages rapides | Sur ouvrant | Entree/pl | B35 | Wc | B35 | Entree/pl | Entree/pl | B35
Por-275 | Etage 3 | 2040 | 830 | 0,83×2,04 | 0,83×2,04×0,07 | Cloison 70 0826278243 | D | Por-275 | 1-Projet | Etage 3 | 6 | Mur-149 | HAG Acrylic White | 0.132496 | 0.118524 | 4.92335 | 1.6932 | 910 | 2080 | 910 | 1.8928 | 1.8928 | 830 | 0 | 0 | 2040 | 1940 | 70 | 0.085966 | 11550 | 0 | 13630 | 2080 | 11550 | 0 | 0 | 40 | 20 | 15 | 40 | 2 | yes | 54.1379 | yes | Réglages rapides | Sur ouvrant | Entree/pl | B35 | Ch 1/pl | B35 | Entree/pl | Entree/pl | B35
Por-276 | Etage 3 | 2040 | 830 | 0,83×2,04 | 0,83×2,04×0,07 | Cloison 70 0826278243 | G | Por-276 | 1-Projet | Etage 3 | 6 | Mur-149 | HAG Acrylic White | 0.132496 | 0.118524 | 4.92335 | 1.6932 | 910 | 2080 | 910 | 1.8928 | 1.8928 | 830 | 0 | 0 | 2040 | 1940 | 70 | 0.085966 | 11550 | 0 | 13630 | 2080 | 11550 | 0 | 0 | 40 | 20 | 15 | 40 | 2 | yes | 89.9641 | yes | Réglages rapides | Sur ouvrant | Ch 2 | B35 | Entree/pl | B35 | Ch 2 | Ch 2 | B35
2 x Por-202 | Etage 3 | 2040 | 580 | 0,58×2,04 | 0,58×2,04×0,07 | Cloison 70 0826278243 | D | Por-202 | 3D | Etage 3 | 6 | Mur-120 | HAG Acrylic White | 0.0861 | 0.082824 | 3.4771 | 1.1832 | 600 | 2050 | 600 | 1.23 | 1.23 | 580 | 0 | 0 | 2040 | 1940 | 70 | 0.053396 | 11550 | 0 | 13600 | 2050 | 11550 | 0 | 0 | 10 | 10 | 10 | 40 | 2 | yes | 0 | yes | Cadre et porte | Sans
Por-202 | Etage 3 | 2040 | 630 | 0,63×2,04 | 0,63×2,04×0,07 | Cloison 70 0826278243 | D | Por-202 | 3D | Etage 3 | 6 | Mur-120 | HAG Acrylic White | 0.093275 | 0.089964 | 3.6941 | 1.2852 | 650 | 2050 | 650 | 1.3325 | 1.3325 | 630 | 0 | 0 | 2040 | 1940 | 70 | 0.0575385 | 11550 | 0 | 13600 | 2050 | 11550 | 0 | 0 | 10 | 10 | 10 | 40 | 2 | yes | 0 | yes | Cadre et porte | Sans
Por-294 | Etage 3 | 2040 | 830 | 0,83×2,04 | 0,83×2,04×0,07 | Cloison 70 0826278243 | D | Por-294 | 1-Projet | Etage 3 | 6 | Mur-149 | HAG Acrylic White | 0.132496 | 0.118524 | 4.92335 | 1.6932 | 910 | 2080 | 910 | 1.8928 | 1.8928 | 830 | 0 | 0 | 2040 | 1940 | 70 | 0.085966 | 11550 | 0 | 13630 | 2080 | 11550 | 0 | 0 | 40 | 20 | 15 | 40 | 2 | yes | 27.1745 | yes | Réglages rapides | Sur ouvrant | Ch 1/pl | B31 | Sde | B31 | Ch 1/pl | Ch 1/pl | B31
Por-296 | Etage 3 | 2040 | 930 | 0,93×2,04 | 0,93×2,04×0,34 | isol int 18+16 0018356637 | D | Por-296 | Interieurs logements | Etage 3 | 6 | Mur-142 | HAG Acrylic White | 0.714272 | 0.645048 | 8.12645 | 1.8972 | 1010 | 2080 | 1010 | 2.1008 | 2.1008 | 930 | 0 | 0 | 2040 | 1940 | 340 | 0.169629 | 11550 | 0 | 13630 | 2080 | 11550 | 0 | 0 | 40 | 20 | 15 | 40 | 2 | yes | 90 | yes | Réglages rapides | Sur ouvrant | Sejour cuisine/pl | A31 |  |  | Sejour cuisine/pl | Sejour cuisine/pl | A31
Por-296 | etage 4 | 2040 | 930 | 0,93×2,04 | 0,93×2,04×0,18 | Beton 18 0018356637 | D | Por-296 | Interieurs logements | etage 4 | 7 | Mur-143 | HAG Acrylic White | 0.378144 | 0.341496 | 6.48965 | 1.8972 | 1010 | 2080 | 1010 | 2.1008 | 2.1008 | 930 | 0 | 0 | 2040 | 1940 | 180 | 0.125102 | 14600 | 0 | 16680 | 2080 | 14600 | 0 | 0 | 40 | 20 | 15 | 40 | 2 | yes | 90 | yes | Hachure de fond/graphisme | Sur ouvrant | Entree/pl | B42 |  |  | Entree/pl | Entree/pl | B42
Por-295 | etage 4 | 2040 | 930 | 0,93×2,04 | 0,93×2,04×0,18 | Beton 18 0018356637 | G | Por-295 | Interieurs logements | etage 4 | 7 | Mur-143 | HAG Acrylic White | 0.378144 | 0.341496 | 6.48965 | 1.8972 | 1010 | 2080 | 1010 | 2.1008 | 2.1008 | 930 | 0 | 0 | 2040 | 1940 | 180 | 0.125102 | 14600 | 0 | 16680 | 2080 | 14600 | 0 | 0 | 40 | 20 | 15 | 40 | 2 | yes | 90 | yes | Hachure de fond/graphisme | Sur ouvrant | Entree/pl | B43 |  |  | Entree/pl | Entree/pl | B43
Por-275 | etage 4 | 2040 | 580 | 0,58×2,04 | 0,58×2,04×0,07 | Cloison 70 0826278243 | D | Por-275 | 1-Projet | etage 4 | 7 | Mur-150 | HAG Acrylic White | 0.0861 | 0.082824 | 3.3723 | 1.1832 | 600 | 2050 | 600 | 1.23 | 1.23 | 580 | 0 | 0 | 2040 | 1940 | 70 | 0.029732 | 14600 | 0 | 16650 | 2050 | 14600 | 0 | 0 | 10 | 10 | 10 | 20 | 2 | yes | 0 | yes | Hachure de fond/graphisme | Sans | Entree/pl | B42 |  |  | Entree/pl | Entree/pl | B42
Por-277 | etage 4 | 2040 | 830 | 0,83×2,04 | 0,83×2,04×0,07 | Cloison 70 0826278243 | G | Por-277 | 1-Projet | etage 4 | 7 | Mur-150 | HAG Acrylic White | 0.132496 | 0.118524 | 4.92335 | 1.6932 | 910 | 2080 | 910 | 1.8928 | 1.8928 | 830 | 0 | 0 | 2040 | 1940 | 70 | 0.085966 | 14600 | 0 | 16680 | 2080 | 14600 | 0 | 0 | 40 | 20 | 15 | 40 | 2 | yes | 21.9195 | yes | Hachure de fond/graphisme | Sur ouvrant | Entree/pl | B42 | Sde | B42 | Entree/pl | Entree/pl | B42
Por-295 | etage 4 | 2040 | 930 | 0,93×2,04 | 0,93×2,04×0,18 | Beton 18 0018356637 | G | Por-295 | Interieurs logements | etage 4 | 7 | Mur-143 | HAG Acrylic White | 0.378146 | 0.341496 | 6.48965 | 1.8972 | 1010 | 2080 | 1010 | 2.1008 | 2.1008 | 930 | 0 | 0 | 2040 | 1940 | 180 | 0.125102 | 14600 | 0 | 16680 | 2080 | 14600 | 0 | 0 | 40 | 20 | 15 | 40 | 2 | yes | 90 | yes | Hachure de fond/graphisme | Sur ouvrant
Por-286 | etage 4 | 2040 | 830 | 0,83×2,04 | 0,83×2,04×0,18 | Beton 18 0018356637 | G | Por-286 | Interieurs logements | etage 4 | 7 | Mur-143 | HAG Acrylic White | 0.340706 | 0.304776 | 6.02665 | 1.6932 | 910 | 2080 | 910 | 1.8928 | 1.8928 | 830 | 0 | 0 | 2040 | 1940 | 180 | 0.115974 | 14600 | 0 | 16680 | 2080 | 14600 | 0 | 0 | 40 | 20 | 15 | 40 | 2 | yes | 90 | yes | Hachure de fond/graphisme | Sur ouvrant | Dgt | B44 | Entree | B44 | Dgt; Entree | Dgt | B44
Por-239 | etage 4 | 650 | 450 | 0,45×0,65 | 0,45×0,65×0,18 | Beton 18 0018356637 | G | Por-239 | Interieurs logements | etage 4 | 7 | Mur-143 | HAG Acrylic White | 0.0590945 | 0.05265 | 1.39885 | 0.2925 | 490 | 670 | 490 | 0.3283 | 0.3283 | 450 | 300 | 200 | 950 | 850 | 180 | 0.016551 | 14900 | 300 | 15570 | 970 | 14900 | 300 | 300 | 20 | 20 | 15 | 20 | 2 | yes | 0 | no | Hachure de fond/graphisme | Sans
Por-282 | etage 4 | 2040 | 830 | 0,83×2,04 | 0,83×2,04×0,18 | Beton 18 0018356637 | G | Por-282 | Interieurs logements | etage 4 | 7 | Mur-143 | HAG Acrylic White | 0.340707 | 0.304776 | 6.02665 | 1.6932 | 910 | 2080 | 910 | 1.8928 | 1.8928 | 830 | 0 | 0 | 2040 | 1940 | 180 | 0.115974 | 14600 | 0 | 16680 | 2080 | 14600 | 0 | 0 | 40 | 20 | 15 | 40 | 2 | yes | 25.0695 | yes | Hachure de fond/graphisme | Sur ouvrant | Entree | B44 | Wc | B44 | Entree; Wc | Entree | B44
Por-275 | etage 4 | 2040 | 830 | 0,83×2,04 | 0,83×2,04×0,07 | Cloison 70 0826278243 | G | Por-275 | 1-Projet | etage 4 | 7 | Mur-149 | HAG Acrylic White | 0.132496 | 0.118524 | 4.92335 | 1.6932 | 910 | 2080 | 910 | 1.8928 | 1.8928 | 830 | 0 | 0 | 2040 | 1940 | 70 | 0.085966 | 14600 | 0 | 16680 | 2080 | 14600 | 0 | 0 | 40 | 20 | 15 | 40 | 2 | yes | 90 | yes | Hachure de fond/graphisme | Sur ouvrant | Ch 1/pl | B42 | Entree/pl | B42 | Ch 1/pl | Ch 1/pl | B42
Por-276 | etage 4 | 2040 | 830 | 0,83×2,04 | 0,83×2,04×0,07 | Cloison 70 0826278243 | D | Por-276 | 1-Projet | etage 4 | 7 | Mur-149 | HAG Acrylic White | 0.132495 | 0.118524 | 4.92335 | 1.6932 | 910 | 2080 | 910 | 1.8928 | 1.8928 | 830 | 0 | 0 | 2040 | 1940 | 70 | 0.085966 | 14600 | 0 | 16680 | 2080 | 14600 | 0 | 0 | 40 | 20 | 15 | 40 | 2 | yes | 90 | yes | Hachure de fond/graphisme | Sur ouvrant | Ch 2 | B42 | Entree/pl | B42 | Ch 2 | Ch 2 | B42
Por-293 | etage 4 | 2040 | 830 | 0,83×2,04 | 0,83×2,04×0,07 | Cloison 70 0826278243 | G | Por-293 | 1-Projet | etage 4 | 7 | Mur-149 | HAG Acrylic White | 0.132496 | 0.118524 | 4.92335 | 1.6932 | 910 | 2080 | 910 | 1.8928 | 1.8928 | 830 | 0 | 0 | 2040 | 1940 | 70 | 0.085966 | 14600 | 0 | 16680 | 2080 | 14600 | 0 | 0 | 40 | 20 | 15 | 40 | 2 | yes | 90 | yes | Hachure de fond/graphisme | Sur ouvrant | Ch 1/pl | B41 | Sejour cuisine/pl | B41 | Ch 1/pl | Ch 1/pl | B41
Por-288 | etage 4 | 2040 | 800 | 0,80×2,04 | 0,80×2,04×0,02 | mur 2cm | D | Por-288 | 1-Projet | etage 4 | 7 | Mur-148 | HAG Acrylic White | 0.036608 | 0.03264 | 4.17895 | 1.632 | 880 | 2080 | 880 | 1.8304 | 1.8304 | 800 | 0 | 0 | 2040 | 1940 | 20 | 0.0372118 | 14600 | 0 | 16680 | 2080 | 14600 | 0 | 0 | 40 | 20 | 15 | 20 | 2 | no | 14.3266 | yes | Réglages rapides | Sans | Sde 2 | B44 | Sde 2 | B44 | Sde 2 | Sde 2 | B44
Por-288 | etage 4 | 2040 | 800 | 0,80×2,04 | 0,80×2,04×0,02 | mur 2cm | D | Por-288 | 1-Projet | etage 4 | 7 | Mur-148 | HAG Acrylic White | 0.036608 | 0.03264 | 4.17895 | 1.632 | 880 | 2080 | 880 | 1.8304 | 1.8304 | 800 | 0 | 0 | 2040 | 1940 | 20 | 0.0372118 | 14600 | 0 | 16680 | 2080 | 14600 | 0 | 0 | 40 | 20 | 15 | 20 | 2 | no | 14.3266 | yes | Réglages rapides | Sans | Sde | B41 | Sde | B41 | Sde | Sde | B41
Por-288 | etage 4 | 2040 | 800 | 0,80×2,04 | 0,80×2,04×0,02 | mur 2cm | G | Por-288 | 1-Projet | etage 4 | 7 | Mur-148 | HAG Acrylic White | 0.0366075 | 0.03264 | 4.17895 | 1.632 | 880 | 2080 | 880 | 1.8304 | 1.8304 | 800 | 0 | 0 | 2040 | 1940 | 20 | 0.0372118 | 14600 | 0 | 16680 | 2080 | 14600 | 0 | 0 | 40 | 20 | 15 | 20 | 2 | no | 14.3266 | yes | Réglages rapides | Sans | Sde | B42 | Sde | B42 | Sde | Sde | B42
Por-288 | etage 4 | 2040 | 800 | 0,80×2,04 | 0,80×2,04×0,02 | mur 2cm | G | Por-288 | 1-Projet | etage 4 | 7 | Mur-148 | HAG Acrylic White | 0.036608 | 0.03264 | 4.17895 | 1.632 | 880 | 2080 | 880 | 1.8304 | 1.8304 | 800 | 0 | 0 | 2040 | 1940 | 20 | 0.0372118 | 14600 | 0 | 16680 | 2080 | 14600 | 0 | 0 | 40 | 20 | 15 | 20 | 2 | no | 14.3266 | yes | Réglages rapides | Sans | Sde | B43 | Sde | B43 | Sde | Sde | B43
Por-278 | etage 4 | 2040 | 830 | 0,83×2,04 | 0,83×2,04×0,07 | Cloison 70 0826278243 | G | Por-278 | 1-Projet | etage 4 | 7 | Mur-149 | HAG Acrylic White | 0.132496 | 0.118524 | 4.92335 | 1.6932 | 910 | 2080 | 910 | 1.8928 | 1.8928 | 830 | 0 | 0 | 2040 | 1940 | 70 | 0.085966 | 14600 | 0 | 16680 | 2080 | 14600 | 0 | 0 | 40 | 20 | 15 | 40 | 2 | yes | 22.6789 | yes | Hachure de fond/graphisme | Sur ouvrant | Entree/pl | B42 | Cellier | B42 | Entree/pl | Entree/pl | B42
Por-274 | etage 4 | 2040 | 600 | 0,60×2,04 | 0,60×2,04×0,07 | Cloison 70 0826278243 | G | Por-274 | 1-Projet | etage 4 | 7 | Mur-149 | HAG Acrylic White | 0.087535 | 0.08568 | 3.4583 | 1.224 | 610 | 2050 | 610 | 1.2505 | 1.2505 | 600 | 0 | 0 | 2040 | 1940 | 70 | 0.030573 | 14600 | 0 | 16650 | 2050 | 14600 | 0 | 0 | 10 | 10 | 10 | 20 | 2 | yes | 0 | yes | Cadre et porte | Sans | Sejour cuisine/pl | B41 |  |  | Sejour cuisine/pl | Sejour cuisine/pl | B41
Por-296 | etage 4 | 2040 | 930 | 0,93×2,04 | 0,93×2,04×0,18 | Beton 18 0018356637 | D | Por-296 | Interieurs logements | etage 4 | 7 | Mur-143 | HAG Acrylic White | 0.378144 | 0.341496 | 6.48965 | 1.8972 | 1010 | 2080 | 1010 | 2.1008 | 2.1008 | 930 | 0 | 0 | 2040 | 1940 | 180 | 0.125102 | 14720 | 120 | 16800 | 2200 | 14720 | 120 | 120 | 40 | 20 | 15 | 40 | 2 | yes | 90 | yes | Hachure de fond/graphisme | Sur ouvrant
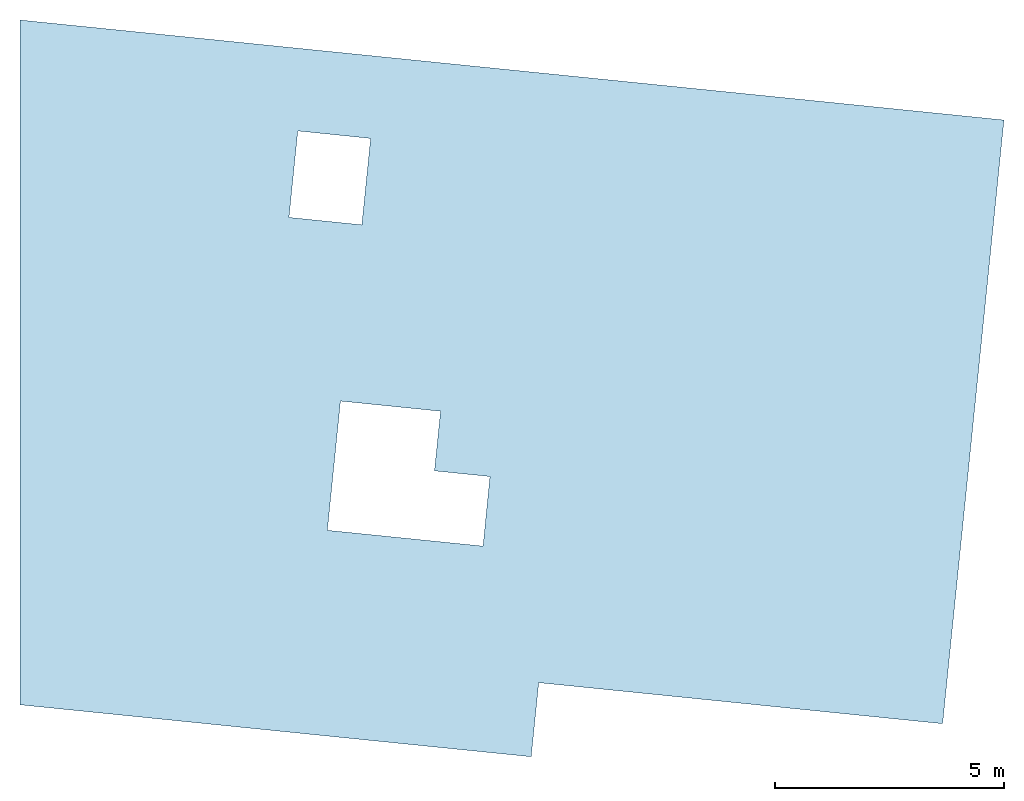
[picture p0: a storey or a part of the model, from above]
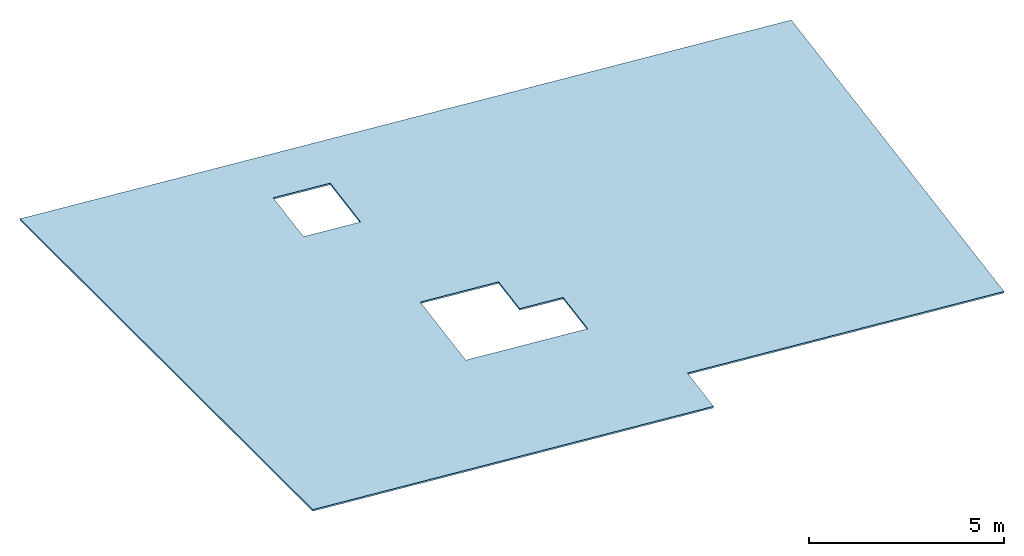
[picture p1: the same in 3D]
Properties of the parts of a building model (IFC2X3), part 16 of 44

# IfcDoor: Porte_1v (482)
Name | In | OverallHeight (mm) = Hauteur nominale de l'ouverture P/F côté ébrasure (mm) = Hauteur nominale de l'ouverture P/F côté opposée ébrasure (mm) = Hauteur (mm) | OverallWidth (mm) | Taille L x H nominale | Taille L x H x E nominale | Structure de Mur | Orientation | ID de l'élément = Lien et ID d'élément | Calque | Nom d'étage d'implantation | Numéro d'étage d'implantation | ID de Parent | Surfaces (Toutes) = Matériau du cadre = Matériau porte = Matériau si métal = Matériau Poignée | Volume ouverture d'ouverture P/F (m3) | Volume nominal ouverture P/F (m3) | Superficie ouverture P/F (m2) = Superficie en plan (m2) = Superficie inférieure (nette) (m2) | Superficie nominale ouverture P/F (m2) = Superficie nominale de l'ouverture P/F côté ébrasure (m2) = Superficie nominale de l'ouverture P/F côté opposé ébrasure (m2) | Largeur ouverture P/F côté ébrasure (mm) | Hauteur ouverture P/F côté ébrasure (mm) = Hauteur ouverture P/F côté opposé ébrasure (mm) | Largeur ouverture P/F côté opposé ébrasure (mm) | Superficie ouverture P/F côté ébrasure (m2) | Superficie ouverture P/F côté opposé ébrasure (m2) | Largeur nominale de l'ouverture P/F côté ébrasure (mm) = Largeur nominale de l'ouverture P/F côté opposée ébrasure (mm) = Largeur (mm) | Valeur Appui ou Linteau (mm) = Hauteur nominale seuil (mm) | Hauteur seuil P/F côté ébrasure (mm) = Hauteur seuil P/F côté opposé ébrasure (mm) | Hauteur nominale linteau P/F (mm) | Hauteur linteau P/F côté ébrasure (mm) = Hauteur linteau P/F côté opposé ébrasure (mm) | Épaisseur de Mur (mm) | Volume (net) (m3) | Altitude à Zéro du Projet (mm) = Altitude de Référence Niveau 1 (mm) = Altitude de Référence Niveau 2 (mm) = Altitude à niveau de la mer (mm) | Altitude à étage lié/étage d'implantation (mm) = Décalage étage d'implantation (mm) | Altitude supérieure à premier niveau de référence (mm) = Altitude supérieure à Zéro du projet (mm) = Altitude supérieure à niveau de la mer (mm) = Altitude supérieure à deuxième niveau de référence (mm) | Altitude supérieure à étage d'implantation (mm) | Altitude inférieure à premier niveau de référence (mm) = Altitude inférieure à Zéro du projet (mm) = Altitude inférieure à niveau de la mer (mm) = Altitude inférieure à deuxième niveau de référence (mm) | Altitude inférieure à étage d'implantation (mm) | Hauteur appui à étage actuel (mm) | Largeur huisserie (mm) | Epais. faux cadre (mm) | Larg feuill mont horiz (mm) | Epaisseur porte (mm) | Contours Mur (0-Sans,1-Tout,2-Côté,3-Longueur) | Dimensions normalisées | Angle d'ouverture en 2D (deg) | Poignée en 3D | Liste des interface user | Affichage texte | Nom de zone liée | Numéro de zone liée | De Zone | Du numéro de Zone | Zones conflictuelles | À Zone | À numéro de Zone
Por-274 | etage 4 | 2040 | 580 | 0,58×2,04 | 0,58×2,04×0,07 | Cloison 70 0826278243 | D | Por-274 | 1-Projet | etage 4 | 7 | Mur-149 | HAG Acrylic White | 0.0861 | 0.082824 | 3.3723 | 1.1832 | 600 | 2050 | 600 | 1.23 | 1.23 | 580 | 0 | 0 | 2040 | 1940 | 70 | 0.029732 | 14600 | 0 | 16650 | 2050 | 14600 | 0 | 0 | 10 | 10 | 10 | 20 | 2 | yes | 0 | yes | Hachure de fond/graphisme | Sans | Sejour cuisine/pl | B41 |  |  | Sejour cuisine/pl | Sejour cuisine/pl | B41
Por-276 | etage 4 | 2040 | 830 | 0,83×2,04 | 0,83×2,04×0,07 | Cloison 70 0826278243 | D | Por-276 | 1-Projet | etage 4 | 7 | Mur-149 | HAG Acrylic White | 0.132496 | 0.118524 | 4.92335 | 1.6932 | 910 | 2080 | 910 | 1.8928 | 1.8928 | 830 | 0 | 0 | 2040 | 1940 | 70 | 0.085966 | 14600 | 0 | 16680 | 2080 | 14600 | 0 | 0 | 40 | 20 | 15 | 40 | 2 | yes | 22.6807 | yes | Hachure de fond/graphisme | Sur ouvrant | Entree/pl | B42 | Wc | B42 | Entree/pl | Entree/pl | B42
Por-296 | etage 4 | 2040 | 930 | 0,93×2,04 | 0,93×2,04×0,18 | Beton 18 0018356637 | G | Por-296 | Interieurs logements | etage 4 | 7 | Mur-143 | HAG Acrylic White | 0.378144 | 0.341496 | 6.48965 | 1.8972 | 1010 | 2080 | 1010 | 2.1008 | 2.1008 | 930 | 0 | 0 | 2040 | 1940 | 180 | 0.125102 | 14600 | 0 | 16680 | 2080 | 14600 | 0 | 0 | 40 | 20 | 15 | 40 | 2 | yes | 90 | yes | Hachure de fond/graphisme | Sur ouvrant | Sejour cuisine/pl | B41 |  |  | Sejour cuisine/pl | Sejour cuisine/pl | B41
Por-245 | etage 4 | 650 | 450 | 0,45×0,65 | 0,45×0,65×0,18 | Beton 18 0018356637 | D | Por-245 | Interieurs logements | etage 4 | 7 | Mur-142 | HAG Acrylic White | 0.059094 | 0.05265 | 1.39885 | 0.2925 | 490 | 670 | 490 | 0.3283 | 0.3283 | 450 | 300 | 200 | 950 | 850 | 180 | 0.016551 | 14900 | 300 | 15570 | 970 | 14900 | 300 | 300 | 20 | 20 | 15 | 20 | 2 | yes | 0 | no | Hachure de fond/graphisme | Sans
Por-287 | etage 4 | 2040 | 830 | 0,83×2,04 | 0,83×2,04×0,07 | Cloison 70 0826278243 | G | Por-287 | 1-Projet | etage 4 | 7 | Mur-149 | HAG Acrylic White | 0.132496 | 0.118524 | 4.92335 | 1.6932 | 910 | 2080 | 910 | 1.8928 | 1.8928 | 830 | 0 | 0 | 2040 | 1940 | 70 | 0.085966 | 14600 | 0 | 16680 | 2080 | 14600 | 0 | 0 | 40 | 20 | 15 | 40 | 2 | yes | 90 | yes | Hachure de fond/graphisme | Sur ouvrant | Sde 1 | B44 | Dgt | B44 | Sde 1 | Sde 1 | B44
Por-299 | etage 4 | 2040 | 930 | 0,93×2,04 | 0,93×2,04×0,18 | Beton 18 0018356637 | G | Por-299 | Interieurs logements | etage 4 | 7 | Mur-142 | HAG Acrylic White | 0.378144 | 0.341496 | 6.48965 | 1.8972 | 1010 | 2080 | 1010 | 2.1008 | 2.1008 | 930 | 0 | 0 | 2040 | 1940 | 180 | 0.125102 | 14600 | 0 | 16680 | 2080 | 14600 | 0 | 0 | 40 | 20 | 15 | 40 | 2 | yes | 90 | yes | Hachure de fond/graphisme | Sur ouvrant | Entree | B44 |  |  | Entree | Entree | B44
Por-284 | etage 4 | 2040 | 830 | 0,83×2,04 | 0,83×2,04×0,07 | Cloison 70 0826278243 | G | Por-284 | 1-Projet | etage 4 | 7 | Mur-149 | HAG Acrylic White | 0.132496 | 0.118524 | 4.92335 | 1.6932 | 910 | 2080 | 910 | 1.8928 | 1.8928 | 830 | 0 | 0 | 2040 | 1940 | 70 | 0.085966 | 14600 | 0 | 16680 | 2080 | 14600 | 0 | 0 | 40 | 20 | 15 | 40 | 2 | yes | 25.0695 | yes | Hachure de fond/graphisme | Sur ouvrant | Sejour cuisine | B44 | Cellier | B44 | Sejour cuisine | Sejour cuisine | B44
Por-300 | etage 4 | 2040 | 930 | 0,93×2,04 | 0,93×2,04×0,07 | Cloison 70 0826278243 | G | Por-300 | 1-Projet | etage 4 | 7 | Mur-149 | HAG Acrylic White | 0.147056 | 0.132804 | 5.36435 | 1.8972 | 1010 | 2080 | 1010 | 2.1008 | 2.1008 | 930 | 0 | 0 | 2040 | 1940 | 70 | 0.0944885 | 14600 | 0 | 16680 | 2080 | 14600 | 0 | 0 | 40 | 20 | 15 | 40 | 2 | yes | 90 | yes | Hachure de fond/graphisme | Sur ouvrant | Sejour cuisine | B44 | Sejour cuisine | B44 | Ch 1
Por-283 | etage 4 | 2040 | 830 | 0,83×2,04 | 0,83×2,04×0,07 | Cloison 70 0826278243 | G | Por-283 | 1-Projet | etage 4 | 7 | Mur-149 | HAG Acrylic White | 0.132496 | 0.118524 | 4.92335 | 1.6932 | 910 | 2080 | 910 | 1.8928 | 1.8928 | 830 | 0 | 0 | 2040 | 1940 | 70 | 0.085966 | 14600 | 0 | 16680 | 2080 | 14600 | 0 | 0 | 40 | 20 | 15 | 40 | 2 | yes | 22.6789 | yes | Hachure de fond/graphisme | Sur ouvrant | Ch 1 | B44 | Sde 2 | B44 | Ch 1 | Ch 1 | B44
Por-283 | etage 4 | 2040 | 830 | 0,83×2,04 | 0,83×2,04×0,07 | Cloison 70 0826278243 | G | Por-283 | 1-Projet | etage 4 | 7 | Mur-149 | HAG Acrylic White | 0.132496 | 0.118524 | 4.92335 | 1.6932 | 910 | 2080 | 910 | 1.8928 | 1.8928 | 830 | 0 | 0 | 2040 | 1940 | 70 | 0.085966 | 14600 | 0 | 16680 | 2080 | 14600 | 0 | 0 | 40 | 20 | 15 | 40 | 2 | yes | 90 | yes | Hachure de fond/graphisme | Sur ouvrant | Ch 2 | B44 | Dgt | B44 | Ch 2 | Ch 2 | B44
Por-281 | etage 4 | 2040 | 830 | 0,83×2,04 | 0,83×2,04×0,18 | Beton 18 0018356637 | D | Por-281 | Interieurs logements | etage 4 | 7 | Mur-142 | HAG Acrylic White | 0.340704 | 0.304776 | 6.02665 | 1.6932 | 910 | 2080 | 910 | 1.8928 | 1.8928 | 830 | 0 | 0 | 2040 | 1940 | 180 | 0.115974 | 14600 | 0 | 16680 | 2080 | 14600 | 0 | 0 | 40 | 20 | 15 | 40 | 2 | yes | 90 | yes | Hachure de fond/graphisme | Sur ouvrant | Ch 3/sde | B44 | Dgt | B44 | Ch 3/sde; Dgt | Ch 3/sde | B44
Por-275 | etage 4 | 2040 | 830 | 0,83×2,04 | 0,83×2,04×0,07 | Cloison 70 0826278243 | D | Por-275 | 1-Projet | etage 4 | 7 | Mur-149 | HAG Acrylic White | 0.132496 | 0.118524 | 4.92335 | 1.6932 | 910 | 2080 | 910 | 1.8928 | 1.8928 | 830 | 0 | 0 | 2040 | 1940 | 70 | 0.085966 | 14600 | 0 | 16680 | 2080 | 14600 | 0 | 0 | 40 | 20 | 15 | 40 | 2 | yes | 22.3288 | yes | Hachure de fond/graphisme | Sur ouvrant | Entree/pl | B43 | Ch 1/pl | B43 | Entree/pl | Entree/pl | B43
Por-276 | etage 4 | 2040 | 830 | 0,83×2,04 | 0,83×2,04×0,07 | Cloison 70 0826278243 | G | Por-276 | 1-Projet | etage 4 | 7 | Mur-149 | HAG Acrylic White | 0.132496 | 0.118524 | 4.92335 | 1.6932 | 910 | 2080 | 910 | 1.8928 | 1.8928 | 830 | 0 | 0 | 2040 | 1940 | 70 | 0.085966 | 14600 | 0 | 16680 | 2080 | 14600 | 0 | 0 | 40 | 20 | 15 | 40 | 2 | yes | 90 | yes | Hachure de fond/graphisme | Sur ouvrant | Ch 2 | B43 | Entree/pl | B43 | Ch 2 | Ch 2 | B43
Por-278 | etage 4 | 2040 | 830 | 0,83×2,04 | 0,83×2,04×0,07 | Cloison 70 0826278243 | D | Por-278 | 1-Projet | etage 4 | 7 | Mur-149 | HAG Acrylic White | 0.132496 | 0.118524 | 4.92335 | 1.6932 | 910 | 2080 | 910 | 1.8928 | 1.8928 | 830 | 0 | 0 | 2040 | 1940 | 70 | 0.085966 | 14600 | 0 | 16680 | 2080 | 14600 | 0 | 0 | 40 | 20 | 15 | 40 | 2 | yes | 22.6789 | yes | Hachure de fond/graphisme | Sur ouvrant | Entree/pl | B43 | Wc | B43 | Entree/pl | Entree/pl | B43
Por-278 | etage 4 | 2040 | 830 | 0,83×2,04 | 0,83×2,04×0,07 | Cloison 70 0826278243 | G | Por-278 | 1-Projet | etage 4 | 7 | Mur-149 | HAG Acrylic White | 0.132496 | 0.118524 | 4.92335 | 1.6932 | 910 | 2080 | 910 | 1.8928 | 1.8928 | 830 | 0 | 0 | 2040 | 1940 | 70 | 0.085966 | 14600 | 0 | 16680 | 2080 | 14600 | 0 | 0 | 40 | 20 | 15 | 40 | 2 | yes | 22.6789 | yes | Hachure de fond/graphisme | Sur ouvrant | Entree/pl | B43 | Cellier | B43 | Entree/pl | Entree/pl | B43
Por-277 | etage 4 | 2040 | 830 | 0,83×2,04 | 0,83×2,04×0,07 | Cloison 70 0826278243 | D | Por-277 | 1-Projet | etage 4 | 7 | Mur-150 | HAG Acrylic White | 0.132496 | 0.118524 | 4.92335 | 1.6932 | 910 | 2080 | 910 | 1.8928 | 1.8928 | 830 | 0 | 0 | 2040 | 1940 | 70 | 0.085966 | 14600 | 0 | 16680 | 2080 | 14600 | 0 | 0 | 40 | 20 | 15 | 40 | 2 | yes | 21.9195 | yes | Hachure de fond/graphisme | Sur ouvrant | Entree/pl | B43 |  |  | Entree/pl | Entree/pl | B43
Por-274 | etage 4 | 2040 | 580 | 0,58×2,04 | 0,58×2,04×0,07 | Cloison 70 0826278243 | G | Por-274 | 1-Projet | etage 4 | 7 | Mur-150 | HAG Acrylic White | 0.0861 | 0.082824 | 3.3723 | 1.1832 | 600 | 2050 | 600 | 1.23 | 1.23 | 580 | 0 | 0 | 2040 | 1940 | 70 | 0.029732 | 14600 | 0 | 16650 | 2050 | 14600 | 0 | 0 | 10 | 10 | 10 | 20 | 2 | yes | 0 | yes | Hachure de fond/graphisme | Sans | Entree/pl | B43 |  |  | Entree/pl | Entree/pl | B43
Por-296 | etage 4 | 2040 | 930 | 0,93×2,04 | 0,93×2,04×0,34 | isol int 18+16 0018356637 | D | Por-296 | Interieurs logements | etage 4 | 7 | Mur-143 | HAG Acrylic White | 0.714272 | 0.645048 | 8.12645 | 1.8972 | 1010 | 2080 | 1010 | 2.1008 | 2.1008 | 930 | 0 | 0 | 2040 | 1940 | 340 | 0.169629 | 14600 | 0 | 16680 | 2080 | 14600 | 0 | 0 | 40 | 20 | 15 | 40 | 2 | yes | 90 | yes | Hachure de fond/graphisme | Sur ouvrant
Por-276 | etage 4 | 2040 | 580 | 0,58×2,04 | 0,58×2,04×0,07 | Cloison 70 0826278243 | G | Por-276 | 1-Projet | etage 4 | 7 | Mur-149 | HAG Acrylic White | 0.0861 | 0.082824 | 3.3723 | 1.1832 | 600 | 2050 | 600 | 1.23 | 1.23 | 580 | 0 | 0 | 2040 | 1940 | 70 | 0.029732 | 14600 | 0 | 16650 | 2050 | 14600 | 0 | 0 | 10 | 10 | 10 | 20 | 2 | yes | 19.1456 | yes | Hachure de fond/graphisme | Sans | Sde 1 | B44 | Sde 1 | B44 | Sde 1 | Sde 1 | B44
Por-276 | etage 4 | 2040 | 580 | 0,58×2,04 | 0,58×2,04×0,07 | Cloison 70 0826278243 | G | Por-276 | 1-Projet | etage 4 | 7 | Mur-149 | HAG Acrylic White | 0.0861 | 0.082824 | 3.3723 | 1.1832 | 600 | 2050 | 600 | 1.23 | 1.23 | 580 | 0 | 0 | 2040 | 1940 | 70 | 0.029732 | 14600 | 0 | 16650 | 2050 | 14600 | 0 | 0 | 10 | 10 | 10 | 20 | 2 | yes | 0 | yes | Hachure de fond/graphisme | Sans | Sejour cuisine | B44 |  |  | Sejour cuisine | Sejour cuisine | B44
Por-293 | etage 4 | 2040 | 830 | 0,83×2,04 | 0,83×2,04×0,07 | Cloison 70 0836576958 | G | Por-293 | 1-Projet | etage 4 | 7 | Mur-148 | HAG Acrylic White | 0.132496 | 0.118524 | 4.92335 | 1.6932 | 910 | 2080 | 910 | 1.8928 | 1.8928 | 830 | 0 | 0 | 2040 | 1940 | 70 | 0.085966 | 14600 | 0 | 16680 | 2080 | 14600 | 0 | 0 | 40 | 20 | 15 | 40 | 2 | yes | 24.9348 | yes | Symbole 2D | Sur ouvrant | Ch 3/sde | B44 |  |  | Ch 3/sde | Ch 3/sde | B44
Por-288 | etage 4 | 2040 | 800 | 0,80×2,04 | 0,80×2,04×0,02 | mur 2cm | G | Por-288 | 1-Projet | etage 4 | 7 | Mur-148 | HAG Acrylic White | 0.036608 | 0.03264 | 4.17895 | 1.632 | 880 | 2080 | 880 | 1.8304 | 1.8304 | 800 | 0 | 0 | 2040 | 1940 | 20 | 0.0372118 | 14600 | 0 | 16680 | 2080 | 14600 | 0 | 0 | 40 | 20 | 15 | 20 | 2 | no | 14.3266 | yes | Réglages rapides | Sans | Ch 3/sde | B44 | Ch 3/sde | B44 | Ch 3/sde | Ch 3/sde | B44
Por-295 | etage 4 | 2040 | 830 | 0,83×2,04 | 0,83×2,04×0,07 | Cloison 70 0826278243 | D | Por-295 | 1-Projet | etage 4 | 7 | Mur-149 | HAG Acrylic White | 0.132496 | 0.118524 | 4.92335 | 1.6932 | 910 | 2080 | 910 | 1.8928 | 1.8928 | 830 | 0 | 0 | 2040 | 1940 | 70 | 0.085966 | 14600 | 0 | 16680 | 2080 | 14600 | 0 | 0 | 40 | 20 | 15 | 40 | 2 | yes | 27.1745 | yes | Hachure de fond/graphisme | Sur ouvrant | Ch 1/pl | B41 | Sde | B41 | Ch 1/pl | Ch 1/pl | B41
Por-202 | etage 4 | 2040 | 380 | 0,38×2,04 | 0,38×2,04×0,07 | Cloison 70 0826278243 | D | Por-202 | 3D | etage 4 | 7 | Mur-120 | HAG Acrylic White | 0.0574 | 0.054264 | 2.6091 | 0.7752 | 400 | 2050 | 400 | 0.82 | 0.82 | 380 | 0 | 0 | 2040 | 1940 | 70 | 0.036826 | 14600 | 0 | 16650 | 2050 | 14600 | 0 | 0 | 10 | 10 | 10 | 40 | 2 | yes | 0 | yes | Cadre et porte | Sans
Por-202 | etage 4 | 2040 | 350 | 0,35×2,04 | 0,35×2,04×0,07 | Cloison 70 0826278243 | D | Por-202 | 3D | etage 4 | 7 | Mur-120 | HAG Acrylic White | 0.053095 | 0.04998 | 2.4789 | 0.714 | 370 | 2050 | 370 | 0.7585 | 0.7585 | 350 | 0 | 0 | 2040 | 1940 | 70 | 0.0343405 | 14600 | 0 | 16650 | 2050 | 14600 | 0 | 0 | 10 | 10 | 10 | 40 | 2 | yes | 0 | yes | Cadre et porte | Sans
Por-202 | etage 4 | 2040 | 680 | 0,68×2,04 | 0,68×2,04×0,07 | Cloison 70 0826278243 | D | Por-202 | 3D | etage 4 | 7 | Mur-120 | HAG Acrylic White | 0.10045 | 0.097104 | 3.9111 | 1.3872 | 700 | 2050 | 700 | 1.435 | 1.435 | 680 | 0 | 0 | 2040 | 1940 | 70 | 0.061681 | 14600 | 0 | 16650 | 2050 | 14600 | 0 | 0 | 10 | 10 | 10 | 40 | 2 | yes | 0 | yes | Cadre et porte | Sans
Por-202 | etage 4 | 2040 | 450 | 0,45×2,04 | 0,45×2,04×0,07 | Cloison 70 0826278243 | D | Por-202 | 3D | etage 4 | 7 | Mur-120 | HAG Acrylic White | 0.067445 | 0.06426 | 2.9129 | 0.918 | 470 | 2050 | 470 | 0.9635 | 0.9635 | 450 | 0 | 0 | 2040 | 1940 | 70 | 0.0426255 | 14600 | 0 | 16650 | 2050 | 14600 | 0 | 0 | 10 | 10 | 10 | 40 | 2 | yes | 0 | yes | Cadre et porte | Sans
2 x Por-202 | etage 4 | 2040 | 600 | 0,60×2,04 | 0,60×2,04×0,07 | Cloison 70 0826278243 | D | Por-202 | 3D | etage 4 | 7 | Mur-120 | HAG Acrylic White | 0.08897 | 0.08568 | 3.5639 | 1.224 | 620 | 2050 | 620 | 1.271 | 1.271 | 600 | 0 | 0 | 2040 | 1940 | 70 | 0.055053 | 14600 | 0 | 16650 | 2050 | 14600 | 0 | 0 | 10 | 10 | 10 | 40 | 2 | yes | 0 | yes | Cadre et porte | Sans
Por-202 | etage 4 | 2040 | 480 | 0,48×2,04 | 0,48×2,04×0,07 | Cloison 70 0826278243 | D | Por-202 | 3D | etage 4 | 7 | Mur-120 | HAG Acrylic White | 0.07175 | 0.068544 | 3.0431 | 0.9792 | 500 | 2050 | 500 | 1.025 | 1.025 | 480 | 0 | 0 | 2040 | 1940 | 70 | 0.045111 | 14600 | 0 | 16650 | 2050 | 14600 | 0 | 0 | 10 | 10 | 10 | 40 | 2 | yes | 0 | yes | Cadre et porte | Sans
Por-295 | Etage 5 | 2040 | 930 | 0,93×2,04 | 0,93×2,04×0,18 | Beton 18 0018356637 | G | Por-295 | Interieurs logements | Etage 5 | 8 | Mur-142 | HAG Acrylic White | 0.378144 | 0.341496 | 6.48965 | 1.8972 | 1010 | 2080 | 1010 | 2.1008 | 2.1008 | 930 | 0 | 0 | 2040 | 1940 | 180 | 0.125102 | 17650 | 0 | 19730 | 2080 | 17650 | 0 | 0 | 40 | 20 | 15 | 40 | 2 | yes | 90 | yes | Symbole 2D | Sur ouvrant | Entree | B52 |  |  | Entree | Entree | B52
Por-285 | Etage 5 | 2040 | 830 | 0,83×2,04 | 0,83×2,04×0,07 | Cloison 70 0826278243 | G | Por-285 | 1-Projet | Etage 5 | 8 | Mur-149 | HAG Acrylic White | 0.132496 | 0.118524 | 4.92335 | 1.6932 | 910 | 2080 | 910 | 1.8928 | 1.8928 | 830 | 0 | 0 | 2040 | 1940 | 70 | 0.085966 | 17650 | 0 | 19730 | 2080 | 17650 | 0 | 0 | 40 | 20 | 15 | 40 | 2 | yes | 90.0001 | yes | Symbole 2D | Sur ouvrant | Ch 1/pl | B52 | Dgt/pl | B52 | Ch 1/pl | Ch 1/pl | B52
Por-288 | Etage 5 | 2040 | 650 | 0,65×2,04 | 0,65×2,04×0,02 | mur 2cm | G | Por-288 | 1-Projet | Etage 5 | 8 | Mur-148 | HAG Acrylic White | 0.030368 | 0.02652 | 3.53845 | 1.326 | 730 | 2080 | 730 | 1.5184 | 1.5184 | 650 | 0 | 0 | 2040 | 1940 | 20 | 0.0309605 | 17650 | 0 | 19730 | 2080 | 17650 | 0 | 0 | 40 | 20 | 15 | 20 | 2 | no | 14.3266 | yes | Réglages rapides | Sans | sde | B51 | sde | B51 | sde | sde | B51
Por-288 | Etage 5 | 2040 | 800 | 0,80×2,04 | 0,80×2,04×0,02 | mur 2cm | D | Por-288 | 1-Projet | Etage 5 | 8 | Mur-148 | HAG Acrylic White | 0.036608 | 0.03264 | 4.17895 | 1.632 | 880 | 2080 | 880 | 1.8304 | 1.8304 | 800 | 0 | 0 | 2040 | 1940 | 20 | 0.0372118 | 17650 | 0 | 19730 | 2080 | 17650 | 0 | 0 | 40 | 20 | 15 | 20 | 2 | no | 14.3266 | yes | Réglages rapides | Sans | Sde 2 | B52 | Sde 2 | B52 | Sde 2 | Sde 2 | B52
Por-282 | Etage 5 | 2040 | 830 | 0,83×2,04 | 0,83×2,04×0,10 | Cloison 100 0826278243 | G | Por-282 | 1-Projet | Etage 5 | 8 | Mur-149 | HAG Acrylic White | 0.18928 | 0.16932 | 5.22425 | 1.6932 | 910 | 2080 | 910 | 1.8928 | 1.8928 | 830 | 0 | 0 | 2040 | 1940 | 100 | 0.09415 | 17650 | 0 | 19730 | 2080 | 17650 | 0 | 0 | 40 | 20 | 15 | 40 | 2 | yes | 90 | yes | Symbole 2D | Sur ouvrant | Ch 1 | B51 | Entree/pl | B51 | Ch 1 | Ch 1 | B51
Por-283 | Etage 5 | 2040 | 830 | 0,83×2,04 | 0,83×2,04×0,18 | Beton 18 0018356637 | G | Por-283 | Interieurs logements | Etage 5 | 8 | Mur-143 | HAG Acrylic White | 0.340704 | 0.304776 | 6.02665 | 1.6932 | 910 | 2080 | 910 | 1.8928 | 1.8928 | 830 | 0 | 0 | 2040 | 1940 | 180 | 0.115974 | 17650 | 0 | 19730 | 2080 | 17650 | 0 | 0 | 40 | 20 | 15 | 40 | 2 | yes | 90 | yes | Symbole 2D | Sur ouvrant | Ch 3/pl | B52 | Entree | B52 | Ch 3/pl; Entree | Ch 3/pl | B52
Por-240 | Etage 5 | 650 | 450 | 0,45×0,65 | 0,45×0,65×0,18 | Beton 18 0018356637 | G | Por-240 | Interieurs logements | Etage 5 | 8 | Mur-143 | HAG Acrylic White | 0.059094 | 0.05265 | 1.39885 | 0.2925 | 490 | 670 | 490 | 0.3283 | 0.3283 | 450 | 300 | 200 | 950 | 850 | 180 | 0.016551 | 17950 | 300 | 18620 | 970 | 17950 | 300 | 300 | 20 | 20 | 15 | 20 | 2 | yes | 0 | no | Symbole 2D | Sans
Por-284 | Etage 5 | 2040 | 830 | 0,83×2,04 | 0,83×2,04×0,18 | Beton 18 0018356637 | G | Por-284 | Interieurs logements | Etage 5 | 8 | Mur-143 | HAG Acrylic White | 0.340704 | 0.304776 | 6.02665 | 1.6932 | 910 | 2080 | 910 | 1.8928 | 1.8928 | 830 | 0 | 0 | 2040 | 1940 | 180 | 0.115974 | 17650 | 0 | 19730 | 2080 | 17650 | 0 | 0 | 40 | 20 | 15 | 40 | 2 | yes | 27.8996 | yes | Symbole 2D | Sur ouvrant | Sejour Cuisine | B52 | Cellier | B52 | Cellier; Sejour Cuisine | Sejour Cuisine | B52
Por-284 | Etage 5 | 2040 | 830 | 0,83×2,04 | 0,83×2,04×0,18 | Beton 18 0018356637 | D | Por-284 | Interieurs logements | Etage 5 | 8 | Mur-143 | HAG Acrylic White | 0.340688 | 0.304776 | 6.02665 | 1.6932 | 910 | 2080 | 910 | 1.8928 | 1.8928 | 830 | 0 | 0 | 2040 | 1940 | 180 | 0.115974 | 17650 | 0 | 19730 | 2080 | 17650 | 0 | 0 | 40 | 20 | 15 | 40 | 2 | yes | 90 | yes | Symbole 2D | Sur ouvrant | Ch 4/Pl | B52 | Entree | B52 | Ch 4/Pl; Entree | Ch 4/Pl | B52
Por-295 | Etage 5 | 2040 | 930 | 0,93×2,04 | 0,93×2,04×0,18 | Beton 18 0018356637 | G | Por-295 | Interieurs logements | Etage 5 | 8 | Mur-143 | HAG Acrylic White | 0.378144 | 0.341496 | 6.48965 | 1.8972 | 1010 | 2080 | 1010 | 2.1008 | 2.1008 | 930 | 0 | 0 | 2040 | 1940 | 180 | 0.125102 | 17650 | 0 | 19730 | 2080 | 17650 | 0 | 0 | 40 | 20 | 15 | 40 | 2 | yes | 90 | yes | Symbole 2D | Sur ouvrant
Por-245 | Etage 5 | 650 | 450 | 0,45×0,65 | 0,45×0,65×0,28 | isol int 18+10 0018356637 | G | Por-245 | Interieurs logements | Etage 5 | 8 | Mur-142 | HAG Acrylic White | 0.091924 | 0.0819 | 1.75785 | 0.2925 | 490 | 670 | 490 | 0.3283 | 0.3283 | 450 | 300 | 200 | 950 | 850 | 280 | 0.022711 | 17950 | 300 | 18620 | 970 | 17950 | 300 | 300 | 20 | 20 | 15 | 20 | 2 | yes | 0 | no | Symbole 2D | Sans
Por-293 | Etage 5 | 2040 | 830 | 0,83×2,04 | 0,83×2,04×0,07 | Cloison 70 0826278243 | D | Por-293 | 1-Projet | Etage 5 | 8 | Mur-149 | HAG Acrylic White | 0.132496 | 0.118524 | 4.92335 | 1.6932 | 910 | 2080 | 910 | 1.8928 | 1.8928 | 830 | 0 | 0 | 2040 | 1940 | 70 | 0.085966 | 17650 | 0 | 19730 | 2080 | 17650 | 0 | 0 | 40 | 20 | 15 | 40 | 2 | yes | 90 | yes | Symbole 2D | Sur ouvrant | Ch 2/pl | B52 | Dgt/pl | B52 | Ch 2/pl | Ch 2/pl | B52
Por-278 | Etage 5 | 2040 | 830 | 0,83×2,04 | 0,83×2,04×0,18 | Beton 18 0018356637 | D | Por-278 | Interieurs logements | Etage 5 | 8 | Mur-143 | HAG Acrylic White | 0.340704 | 0.304776 | 6.02665 | 1.6932 | 910 | 2080 | 910 | 1.8928 | 1.8928 | 830 | 0 | 0 | 2040 | 1940 | 180 | 0.115974 | 17650 | 0 | 19730 | 2080 | 17650 | 0 | 0 | 40 | 20 | 15 | 40 | 2 | yes | 90 | yes | Symbole 2D | Sur ouvrant | Sejour Cuisine | B52 | Entree | B52 | Entree; Sejour Cuisine | Sejour Cuisine | B52
Por-281 | Etage 5 | 2040 | 830 | 0,83×2,04 | 0,83×2,04×0,07 | Cloison 70 0826278243 | G | Por-281 | 1-Projet | Etage 5 | 8 | Mur-149 | HAG Acrylic White | 0.132496 | 0.118524 | 4.92335 | 1.6932 | 910 | 2080 | 910 | 1.8928 | 1.8928 | 830 | 0 | 0 | 2040 | 1940 | 70 | 0.085966 | 17650 | 0 | 19730 | 2080 | 17650 | 0 | 0 | 40 | 20 | 15 | 40 | 2 | yes | 17.2759 | yes | Symbole 2D | Sur ouvrant | Sejour cuisine | B51 | cellier | B51 | Sejour cuisine | Sejour cuisine | B51
Por-288 | Etage 5 | 2040 | 930 | 0,93×2,04 | 0,93×2,04×0,18 | Beton 18 0018356637 | D | Por-288 | Interieurs logements | Etage 5 | 8 | Mur-143 | HAG Acrylic White | 0.378144 | 0.341496 | 6.48965 | 1.8972 | 1010 | 2080 | 1010 | 2.1008 | 2.1008 | 930 | 0 | 0 | 2040 | 1940 | 180 | 0.125102 | 17650 | 0 | 19730 | 2080 | 17650 | 0 | 0 | 40 | 20 | 15 | 40 | 2 | yes | 89.9997 | yes | Symbole 2D | Sur ouvrant | Entree/pl | B51 |  |  | Entree/pl | Entree/pl | B51
Por-280 | Etage 5 | 2040 | 830 | 0,83×2,04 | 0,83×2,04×0,07 | Cloison 70 0826278243 | G | Por-280 | 1-Projet | Etage 5 | 8 | Mur-149 | HAG Acrylic White | 0.132496 | 0.118524 | 4.92335 | 1.6932 | 910 | 2080 | 910 | 1.8928 | 1.8928 | 830 | 0 | 0 | 2040 | 1940 | 70 | 0.085966 | 17650 | 0 | 19730 | 2080 | 17650 | 0 | 0 | 40 | 20 | 15 | 40 | 2 | yes | 90 | yes | Symbole 2D | Sur ouvrant | Ch 2 | B51 | Dgt | B51 | Ch 2 | Ch 2 | B51
Por-279 | Etage 5 | 2040 | 830 | 0,83×2,04 | 0,83×2,04×0,07 | Cloison 70 0826278243 | G | Por-279 | 1-Projet | Etage 5 | 8 | Mur-149 | HAG Acrylic White | 0.132496 | 0.118524 | 4.92335 | 1.6932 | 910 | 2080 | 910 | 1.8928 | 1.8928 | 830 | 0 | 0 | 2040 | 1940 | 70 | 0.085966 | 17650 | 0 | 19730 | 2080 | 17650 | 0 | 0 | 40 | 20 | 15 | 40 | 2 | yes | 89.8227 | yes | Symbole 2D | Sur ouvrant | Dgt | B51 | Sdb | B51 | Dgt | Dgt | B51
Por-281 | Etage 5 | 2040 | 830 | 0,83×2,04 | 0,83×2,04×0,07 | Cloison 70 0826278243 | D | Por-281 | 1-Projet | Etage 5 | 8 | Mur-149 | HAG Acrylic White | 0.132496 | 0.118524 | 4.92335 | 1.6932 | 910 | 2080 | 910 | 1.8928 | 1.8928 | 830 | 0 | 0 | 2040 | 1940 | 70 | 0.085966 | 17650 | 0 | 19730 | 2080 | 17650 | 0 | 0 | 40 | 20 | 15 | 40 | 2 | yes | 90 | yes | Symbole 2D | Sur ouvrant | Ch 3 | B51 | Dgt | B51 | Ch 3 | Ch 3 | B51
Por-281 | Etage 5 | 2040 | 830 | 0,83×2,04 | 0,83×2,04×0,07 | Cloison 70 0826278243 | D | Por-281 | 1-Projet | Etage 5 | 8 | Mur-149 | HAG Acrylic White | 0.132496 | 0.118524 | 4.92335 | 1.6932 | 910 | 2080 | 910 | 1.8928 | 1.8928 | 830 | 0 | 0 | 2040 | 1940 | 70 | 0.085966 | 17650 | 0 | 19730 | 2080 | 17650 | 0 | 0 | 40 | 20 | 15 | 40 | 2 | yes | 17.2759 | yes | Symbole 2D | Sur ouvrant | Dgt | B51 | Wc | B51 | Dgt | Dgt | B51
Por-274 | Etage 5 | 2040 | 580 | 0,58×2,04 | 0,58×2,04×0,07 | Cloison 70 0826278243 | G | Por-274 | 1-Projet | Etage 5 | 8 | Mur-149 | HAG Acrylic White | 0.0859757 | 0.082824 | 3.3723 | 1.1832 | 599.134 | 2050 | 599.134 | 1.22823 | 1.22822 | 580 | 0 | 0 | 2040 | 1940 | 70 | 0.029732 | 17650 | 0 | 19700 | 2050 | 17650 | 0 | 0 | 10 | 10 | 10 | 20 | 2 | yes | 0 | yes | Symbole 2D | Sans | Dgt | B51 |  |  | Dgt | Dgt | B51
Por-285 | Etage 5 | 2040 | 830 | 0,83×2,04 | 0,83×2,04×0,07 | Cloison 70 0826278243 | G | Por-285 | 1-Projet | Etage 5 | 8 | Mur-149 | HAG Acrylic White | 0.132496 | 0.118524 | 4.92335 | 1.6932 | 910 | 2080 | 910 | 1.8928 | 1.8928 | 830 | 0 | 0 | 2040 | 1940 | 70 | 0.085966 | 17650 | 0 | 19730 | 2080 | 17650 | 0 | 0 | 40 | 20 | 15 | 40 | 2 | yes | 25.1866 | yes | Symbole 2D | Sur ouvrant | Ch 4/Pl | B52 | Sde 2 | B52 | Ch 4/Pl | Ch 4/Pl | B52
Por-291 | Etage 5 | 2040 | 830 | 0,83×2,04 | 0,83×2,04×0,07 | Cloison 70 0826278243 | D | Por-291 | 1-Projet | Etage 5 | 8 | Mur-149 | HAG Acrylic White | 0.132496 | 0.118524 | 4.92335 | 1.6932 | 910 | 2080 | 910 | 1.8928 | 1.8928 | 830 | 0 | 0 | 2040 | 1940 | 70 | 0.085966 | 17650 | 0 | 19730 | 2080 | 17650 | 0 | 0 | 40 | 20 | 15 | 40 | 2 | yes | 22.6789 | yes | Symbole 2D | Sur ouvrant | Wc | B52 | Wc | B52 | Entree
Por-274 | Etage 5 | 2040 | 580 | 0,58×2,04 | 0,58×2,04×0,07 | Cloison 70 0826278243 | D | Por-274 | 1-Projet | Etage 5 | 8 | Mur-149 | HAG Acrylic White | 0.0861 | 0.082824 | 3.3723 | 1.1832 | 600 | 2050 | 600 | 1.23 | 1.23 | 580 | 0 | 0 | 2040 | 1940 | 70 | 0.029732 | 17650 | 0 | 19700 | 2050 | 17650 | 0 | 0 | 10 | 10 | 10 | 20 | 2 | yes | 0 | yes | Symbole 2D | Sans | Entree | B52 |  |  | Entree | Entree | B52
Por-281 | Etage 5 | 2040 | 830 | 0,83×2,04 | 0,83×2,04×0,07 | Cloison 70 0826278243 | G | Por-281 | 1-Projet | Etage 5 | 8 | Mur-149 | HAG Acrylic White | 0.132496 | 0.118524 | 4.92335 | 1.6932 | 910 | 2080 | 910 | 1.8928 | 1.8928 | 830 | 0 | 0 | 2040 | 1940 | 70 | 0.085966 | 17650 | 0 | 19730 | 2080 | 17650 | 0 | 0 | 40 | 20 | 15 | 40 | 2 | yes | 17.2759 | yes | Symbole 2D | Sur ouvrant | Sejour cuisine | B51 | Sejour cuisine | B51 | Sejour cuisine
Por-202 | Etage 5 | 2040 | 500 | 0,50×2,04 | 0,50×2,04×0,07 | Cloison 70 0826278243 | D | Por-202 | 1-Projet | Etage 5 | 8 | Mur-149 | HAG Acrylic White | 0.07462 | 0.0714 | 3.1299 | 1.02 | 520 | 2050 | 520 | 1.066 | 1.066 | 500 | 0 | 0 | 2040 | 1940 | 70 | 0.046768 | 17650 | 0 | 19700 | 2050 | 17650 | 0 | 0 | 10 | 10 | 10 | 40 | 2 | yes | 0 | yes | Symbole 2D | Sans | Sde 1 | B52 |  |  | Sde 1 | Sde 1 | B52
Por-292 | Etage 5 | 2040 | 830 | 0,83×2,04 | 0,83×2,04×0,07 | Cloison 70 0826278243 | D | Por-292 | 1-Projet | Etage 5 | 8 | Mur-149 | HAG Acrylic White | 0.132496 | 0.118524 | 4.92335 | 1.6932 | 910 | 2080 | 910 | 1.8928 | 1.8928 | 830 | 0 | 0 | 2040 | 1940 | 70 | 0.085966 | 17650 | 0 | 19730 | 2080 | 17650 | 0 | 0 | 40 | 20 | 15 | 40 | 2 | yes | 22.6789 | yes | Symbole 2D | Sur ouvrant | Dgt/pl | B52 | Sde 1 | B52 | Dgt/pl | Dgt/pl | B52
Por-293 | Etage 5 | 2040 | 830 | 0,83×2,04 | 0,83×2,04×0,07 | Cloison 70 0826278243 | D | Por-293 | 1-Projet | Etage 5 | 8 | Mur-149 | HAG Acrylic White | 0.132496 | 0.118524 | 4.92335 | 1.6932 | 910 | 2080 | 910 | 1.8928 | 1.8928 | 830 | 0 | 0 | 2040 | 1940 | 70 | 0.085966 | 17650 | 0 | 19730 | 2080 | 17650 | 0 | 0 | 40 | 20 | 15 | 40 | 2 | yes | 45.0001 | yes | Symbole 2D | Sur ouvrant | Sejour Cuisine | B54 | cellier | B54 | Sejour Cuisine | Sejour Cuisine | B54
2 x Por-202 | Etage 5 | 2040 | 600 | 0,60×2,04 | 0,60×2,04×0,07 | Cloison 70 0826278243 | D | Por-202 | 3D | Etage 5 | 8 | Mur-120 | HAG Acrylic White | 0.08897 | 0.08568 | 3.5639 | 1.224 | 620 | 2050 | 620 | 1.271 | 1.271 | 600 | 0 | 0 | 2040 | 1940 | 70 | 0.055053 | 17650 | 0 | 19700 | 2050 | 17650 | 0 | 0 | 10 | 10 | 10 | 40 | 2 | yes | 0 | yes | Cadre et porte | Sans
Por-202 | Etage 5 | 2040 | 450 | 0,45×2,04 | 0,45×2,04×0,07 | Cloison 70 0826278243 | D | Por-202 | 3D | Etage 5 | 8 | Mur-120 | HAG Acrylic White | 0.067445 | 0.06426 | 2.9129 | 0.918 | 470 | 2050 | 470 | 0.9635 | 0.9635 | 450 | 0 | 0 | 2040 | 1940 | 70 | 0.0426255 | 17650 | 0 | 19700 | 2050 | 17650 | 0 | 0 | 10 | 10 | 10 | 40 | 2 | yes | 0 | yes | Cadre et porte | Sans
Por-202 | Etage 5 | 2040 | 480 | 0,48×2,04 | 0,48×2,04×0,07 | Cloison 70 0826278243 | D | Por-202 | 3D | Etage 5 | 8 | Mur-120 | HAG Acrylic White | 0.07175 | 0.068544 | 3.0431 | 0.9792 | 500 | 2050 | 500 | 1.025 | 1.025 | 480 | 0 | 0 | 2040 | 1940 | 70 | 0.045111 | 17650 | 0 | 19700 | 2050 | 17650 | 0 | 0 | 10 | 10 | 10 | 40 | 2 | yes | 0 | yes | Cadre et porte | Sans
Por-202 | Etage 5 | 2040 | 380 | 0,38×2,04 | 0,38×2,04×0,07 | Cloison 70 0826278243 | D | Por-202 | 3D | Etage 5 | 8 | Mur-120 | HAG Acrylic White | 0.0574 | 0.054264 | 2.6091 | 0.7752 | 400 | 2050 | 400 | 0.82 | 0.82 | 380 | 0 | 0 | 2040 | 1940 | 70 | 0.036826 | 17650 | 0 | 19700 | 2050 | 17650 | 0 | 0 | 10 | 10 | 10 | 40 | 2 | yes | 0 | yes | Cadre et porte | Sans
Por-202 | Etage 5 | 2040 | 350 | 0,35×2,04 | 0,35×2,04×0,07 | Cloison 70 0826278243 | D | Por-202 | 3D | Etage 5 | 8 | Mur-120 | HAG Acrylic White | 0.053095 | 0.04998 | 2.4789 | 0.714 | 370 | 2050 | 370 | 0.7585 | 0.7585 | 350 | 0 | 0 | 2040 | 1940 | 70 | 0.0343405 | 17650 | 0 | 19700 | 2050 | 17650 | 0 | 0 | 10 | 10 | 10 | 40 | 2 | yes | 0 | yes | Cadre et porte | Sans
Por-202 | Etage 5 | 2040 | 680 | 0,68×2,04 | 0,68×2,04×0,07 | Cloison 70 0826278243 | D | Por-202 | 3D | Etage 5 | 8 | Mur-120 | HAG Acrylic White | 0.10045 | 0.097104 | 3.9111 | 1.3872 | 700 | 2050 | 700 | 1.435 | 1.435 | 680 | 0 | 0 | 2040 | 1940 | 70 | 0.061681 | 17650 | 0 | 19700 | 2050 | 17650 | 0 | 0 | 10 | 10 | 10 | 40 | 2 | yes | 0 | yes | Cadre et porte | Sans

# IfcFurnishingElement: Ecran TV plasma (46)
Classification: Mobilier (Classification ARCHICAD)
ArchiCADProperties - Surface: Revêt. pilier rond; ID de l'élément: Obj.-034; Lien et ID d'élément: Obj.-034; Nom Élément de Bibliothèque: Ecran TV plasma; Matériau de construction / Composite / Profil / Hachure: Brique 1; Type Hachure: Brique 1; Verrouillé: no; Type d'élément: Objet; ID de Parent: Obj.-034; Surfaces (Toutes): Dallage-Asphalte Lisse; Surface-Plastique stratifié; Divers-Glace; Métal-Acier; Métal-Zinc; Nom de Variante: Modèle principal; Nom de Jeu de Variantes: Modèle principal; Position: Non défini; Fonction structurelle: Non défini; Affichage sur filtre de rénovation: Tous les filtres appropriés; État de rénovation: Existant; État de Variante: Modèle principal; Jeu de Variantes: Modèle principal
AC_Pset_Ecran_TV_plasma - Afficher points chauds 2D en 3D: yes; Support: yes; 3D: Détaillé; Ombre: no; Résolution: 18; Image sur écran: no; Nom fichier image: Fleurs; 2D: Détaillé; Motif de hachure: Sans Trame; Matière écran: Divers-Glace; Matière appui: Métal-Zinc; Matière cadre: Surface-Plastique stratifié; Matière boutons: Métal-Acier; Coût: 0; Volts: 0; Type de groupe (FM_Type): Autre; Type de groupe (iFMType): 8; Poids de l'objet: 0; Unité poids de l'objet: Kg; Puissance en Watts: 0; Puissance de sortie: 0
AC_Pset_RenovationAndPhasing - Renovation Status: Existing
AC_Equantity_Ecran_TV_plasma - Hauteur: 280 mm; Niveau inférieur: 1000 mm; Niveau supérieur: 0 mm
ArchiCADQuantities - Longueur (A): 1000 mm; Superficie: 0.05 m2; Hauteur: 280 mm; Volume (net): 0.0111547 m3; Largeur: 50 mm; Altitude à étage lié/étage d'implantation: 800 mm; Décalage étage d'implantation: 800 mm; Superficie en plan: 1.09793 m2; Altitude supérieure à étage d'implantation: 1081.59 mm; Altitude inférieure à étage d'implantation: 800 mm; Superficie supérieure (nette): 0.05 m2; Superficie inférieure (nette): 1.09793 m2
Name | In | Angle de rotation (deg) | Calque | Zones conflictuelles = Nom de zone liée | Numéro de zone liée | Nom d'étage d'implantation | Numéro d'étage d'implantation | Altitude à Zéro du Projet (mm) = Altitude de Référence Niveau 1 (mm) = Altitude de Référence Niveau 2 (mm) = Altitude à niveau de la mer (mm) = Altitude inférieure à premier niveau de référence (mm) = Altitude inférieure à Zéro du projet (mm) = Altitude inférieure à niveau de la mer (mm) = Altitude inférieure à deuxième niveau de référence (mm) = Coordonnée topographique Z (mm) | Altitude supérieure à premier niveau de référence (mm) = Altitude supérieure à Zéro du projet (mm) = Altitude supérieure à niveau de la mer (mm) = Altitude supérieure à deuxième niveau de référence (mm) | Coordonnée topographique X (mm) | Coordonnée topographique Y (mm)
Obj.-034 | rdc | 179.968 | 0-Resille Dampere | Sejour cuisine | B02 | rdc | 3 | 3800 | 4081.59 | 2220357 | -643835
Obj.-034 | rdc | 270.032 | 0-Resille Dampere | Sejour cuisine | B03 | rdc | 3 | 3800 | 4081.59 | 2223951 | -655467
Obj.-034 | rdc | 270.032 | 0-Resille Dampere | Sejour cuisine/pl | B04 | rdc | 3 | 3800 | 4081.59 | 2232285 | -655553
Obj.-034 | rdc | 354.165 | 0-Resille Dampere | Sejour Cuisine | B01 | rdc | 3 | 3800 | 4081.59 | 2220664 | -621583
Obj.-034 | rdc | 180.032 | 0-Resille Dampere | Sejour cuisine | B05 | rdc | 3 | 3800 | 4081.59 | 2232288 | -640504
Obj.-034 | rdc | 84.2316 | 0-Resille Dampere | Sejour cuisine | A03 | rdc | 3 | 3800 | 4081.59 | 2229793 | -619788
Obj.-034 | rdc | 84.1651 | 0-Resille Dampere | Sejour Cuisine/pl | A04 | rdc | 3 | 3800 | 4081.59 | 2234222 | -617995
Obj.-034 | rdc | 174.165 | 0-Resille Dampere | Sejour Cuisine | A02 | rdc | 3 | 3800 | 4081.59 | 2219333 | -620499
Obj.-034 | rdc | 174.197 | 0-Resille Dampere | Sejour cuisine/pl | A01 | rdc | 3 | 3800 | 4081.59 | 2220775 | -607479
Obj.-034 | Etage1 | 179.968 | 0-Resille Dampere | Sejour Cuisine | B13 | Etage1 | 4 | 6550 | 6831.59 | 2220357 | -643835
Obj.-034 | Etage1 | 89.9678 | 0-Resille Dampere | Sejour cuisine | B15 | Etage1 | 4 | 6550 | 6831.59 | 2227384 | -655341
Obj.-034 | Etage1 | 179.968 | 0-Resille Dampere | Sejour cuisine | B16 | Etage1 | 4 | 6550 | 6831.59 | 2231410 | -640504
Obj.-034 | Etage1 | 180.032 | 0-Resille Dampere | Sejour cuisine | B14 | Etage1 | 4 | 6550 | 6831.59 | 2220661 | -657297
Obj.-034 | Etage1 | 174.165 | 0-Resille Dampere | Sejour cuisine | A12 | Etage1 | 4 | 6550 | 6831.59 | 2219333 | -620499
Obj.-034 | Etage1 | 174.165 | MOBILIER | Sejour cuisine/pl | A11 | Etage1 | 4 | 6550 | 6831.59 | 2220569 | -607457
Obj.-034 | Etage1 | 84.1602 | 0-Resille Dampere | Sejour cuisine/pl | A15 | Etage1 | 4 | 6550 | 6831.59 | 2226534 | -608018
Obj.-034 | Etage1 | 270.032 | 0-Resille Dampere | Sejour cuisine | B11 | Etage1 | 4 | 6550 | 6831.59 | 2229132 | -625441
Obj.-034 | Etage1 | 354.23 | 0-Resille Dampere | Sejour cuisine | B12 | Etage1 | 4 | 6550 | 6831.59 | 2219948 | -621510
Obj.-034 | Etage1 | 84.2356 | 0-Resille Dampere | Sejour cuisine | A13 | Etage1 | 4 | 6550 | 6831.59 | 2229793 | -619788
Obj.-034 | Etage1 | 264.163 | 0-Resille Dampere | Sejour Cuisine/pl | A14 | Etage1 | 4 | 6550 | 6831.59 | 2238280 | -619796
Obj.-034 | Etage 2 | 0.0322375 | MOBILIER | Sejour cuisine | A22 | Etage 2 | 5 | 9300 | 9581.59 | 2219473 | -617419
Obj.-034 | Etage 2 | 179.968 | 0-Resille Dampere | Sejour cuisine | B23 | Etage 2 | 5 | 9300 | 9581.59 | 2220357 | -643835
Obj.-034 | Etage 2 | 270.032 | MOBILIER | Sejour cuisine | B25 | Etage 2 | 5 | 9300 | 9581.59 | 2232285 | -655502
Obj.-034 | Etage 2 | 270.032 | MOBILIER | Sejour cuisine | B24 | Etage 2 | 5 | 9300 | 9581.59 | 2223951 | -654534
Obj.-034 | Etage 2 | 179.968 | 0-Resille Dampere | Sejour cuisine | B26 | Etage 2 | 5 | 9300 | 9581.59 | 2231656 | -640482
Obj.-034 | Etage 2 | 0.0322375 | 0-Resille Dampere | Sejour cuisine | B21 | Etage 2 | 5 | 9300 | 9581.59 | 2228192 | -625260
Obj.-034 | Etage 2 | 84.2374 | MOBILIER | Sejour cuisine/pl | A24 | Etage 2 | 5 | 9300 | 9581.59 | 2234125 | -619513
Obj.-034 | Etage 2 | 174.165 | MOBILIER | Sejour cuisine/pl | A21 | Etage 2 | 5 | 9300 | 9581.59 | 2220569 | -607457
Obj.-034 | Etage 2 | 84.2374 | MOBILIER | Sejour cuisine | A23 | Etage 2 | 5 | 9300 | 9581.59 | 2229796 | -619758
Obj.-034 | Etage 2 | 84.1602 | 0-Resille Dampere | Sejour cuisine/pl | A25 | Etage 2 | 5 | 9300 | 9581.59 | 2226534 | -608018
Obj.-034 | Etage 2 | 354.23 | MOBILIER | Sejour cuisine | B22 | Etage 2 | 5 | 9300 | 9581.59 | 2219876 | -621503
Obj.-034 | Etage 3 | 84.1651 | 0-Resille Dampere | Sejour cuisine | A32 | Etage 3 | 6 | 12350 | 12631.6 | 2229901 | -618719
Obj.-034 | Etage 3 | 84.1651 | MOBILIER | Sejour cuisine/pl | A34 | Etage 3 | 6 | 12350 | 12631.6 | 2230612 | -608035
Obj.-034 | Etage 3 | 179.968 | 0-Resille Dampere | Sejour cuisine | B33 | Etage 3 | 6 | 12350 | 12631.6 | 2220357 | -643835
Obj.-034 | Etage 3 | 264.23 | MOBILIER | Sejour cuisine/pl | A33 | Etage 3 | 6 | 12350 | 12631.6 | 2238393 | -618689
Obj.-034 | Etage 3 | 264.23 | MOBILIER | Sejour cuisine/pl | A31 | Etage 3 | 6 | 12350 | 12631.6 | 2223871 | -608078
Obj.-034 | Etage 3 | 270.005 | 0-Resille Dampere | Sejour cuisine/pl | B31 | Etage 3 | 6 | 12350 | 12631.6 | 2229131 | -625187
Obj.-034 | Etage 3 | 354.23 | MOBILIER | Sejour cuisine | B32 | Etage 3 | 6 | 12350 | 12631.6 | 2220480 | -621564
Obj.-034 | Etage 3 | 89.9678 | MOBILIER | Sejour cuisine | B34 | Etage 3 | 6 | 12350 | 12631.6 | 2224494 | -651164
Obj.-034 | Etage 3 | 179.968 | 0-Resille Dampere | Sejour cuisine/pl | B35 | Etage 3 | 6 | 12350 | 12631.6 | 2231442 | -640504
Obj.-034 | etage 4 | 354.165 | 0-Resille Dampere | Sejour cuisine | B42 | etage 4 | 7 | 15400 | 15681.6 | 2221596 | -621738
Obj.-034 | etage 4 | 179.968 | 0-Resille Dampere | Sejour cuisine | B43 | etage 4 | 7 | 15400 | 15681.6 | 2220357 | -643835
Obj.-034 | etage 4 | 90.0322 | 0-Resille Dampere | Sejour cuisine | B44 | etage 4 | 7 | 15400 | 15681.6 | 2218656 | -649476
Obj.-034 | etage 4 | 269.984 | 0-Resille Dampere | Sejour cuisine/pl | B41 | etage 4 | 7 | 15400 | 15681.6 | 2229132 | -626231
Obj.-034 | Etage 5 | 89.9678 | MOBILIER | Sejour Cuisine | B52 | Etage 5 | 8 | 18450 | 18731.6 | 2218656 | -647029
Obj.-034 | Etage 5 | 270.032 | MOBILIER | Sejour cuisine | B51 | Etage 5 | 8 | 18450 | 18731.6 | 2223275 | -626047

# IfcFurnishingElement: Machine à laver (96)
Classification: Mobilier (Classification ARCHICAD)
ArchiCADProperties - Calque: SANITAIRE; Nom Élément de Bibliothèque: Machine à laver; Matériau de construction / Composite / Profil / Hachure: Brique 1; Type Hachure: Brique 1; Verrouillé: no; Type d'élément: Objet; Surfaces (Toutes): Métal-Chrome; Surface-Lavis Blanc; Vitrage-Verre; Métal-Zinc; Nom de Variante: Modèle principal; Nom de Jeu de Variantes: Modèle principal; Position: Non défini; Fonction structurelle: Non défini; Affichage sur filtre de rénovation: Tous les filtres appropriés; État de rénovation: Existant; État de Variante: Modèle principal; Jeu de Variantes: Modèle principal
AC_Pset_Machine_à_laver - 3D: Détaillé; Résolution: 12; Ombre: yes; Afficher texte: yes; Police: Arial; Taille police: 12; Effets police: Normal; Rotation texte: 0; Encombrement minimal: no; Motif de hachure: Sans Trame; Matière équipement: Surface-Lavis Blanc; Matière vitrage: Vitrage-Verre; Matière boutons de contrôle: Métal-Zinc; Matière cadre de porte: Métal-Chrome; Matière tableau de bord: Surface-Lavis Blanc; Afficher points chauds 2D en 3D: yes; Coût: 0; Volts: 0; Type de groupe (FM_Type): Services électriques; Type de groupe (iFMType): 8; Poids de l'objet: 0; Puissance en Watts: 0; Puissance de sortie: 0
AC_Pset_RenovationAndPhasing - Renovation Status: Existing
ArchiCADQuantities - Hauteur: 900 mm; Altitude à étage lié/étage d'implantation: 0 mm; Décalage étage d'implantation: 0 mm; Altitude supérieure à étage d'implantation: 900 mm; Altitude inférieure à étage d'implantation: 0 mm
AC_Equantity_Machine_à_laver - Hauteur: 900 mm; Niveau inférieur: 1000 mm; Niveau supérieur: 0 mm
Name | In | Angle de rotation (deg) | Surface | ID de l'élément = Lien et ID d'élément = ID de Parent | Zones conflictuelles | Nom de zone liée | Numéro de zone liée | Nom d'étage d'implantation | Numéro d'étage d'implantation | Texte | Type de ligne symbole | Longueur (A) (mm) = Largeur (mm) = Dimension X (mm) = Dimension Y (mm) | Superficie (m2) = Superficie supérieure (nette) (m2) | Volume (net) (m3) | Altitude à Zéro du Projet (mm) = Altitude de Référence Niveau 1 (mm) = Altitude de Référence Niveau 2 (mm) = Altitude à niveau de la mer (mm) = Altitude inférieure à premier niveau de référence (mm) = Altitude inférieure à Zéro du projet (mm) = Altitude inférieure à niveau de la mer (mm) = Altitude inférieure à deuxième niveau de référence (mm) = Coordonnée topographique Z (mm) | Superficie en plan (m2) = Superficie inférieure (nette) (m2) | Altitude supérieure à premier niveau de référence (mm) = Altitude supérieure à Zéro du projet (mm) = Altitude supérieure à niveau de la mer (mm) = Altitude supérieure à deuxième niveau de référence (mm) | Coordonnée topographique X (mm) | Coordonnée topographique Y (mm)
Obj.-019 | rdc | 359.88 | Revêt. pilier rond | Obj.-019 | Sejour cuisine | Sejour cuisine | B03 | rdc | 3 | LV | 1 | 600 | 0.36 | 0.0534437 | 3000 | 4.19567 | 3900 | 2220482 | -653013
Obj.-003 | rdc | 354.109 | C10 | Obj.-003 | Sejour cuisine/pl | Sejour cuisine/pl | A01 | rdc | 3 | LL | 4 | 610 | 0.3721 | 0.0552404 | 3000 | 4.2919 | 3900 | 2224177 | -607825
Obj.-019 | rdc | 89.9945 | Revêt. pilier rond | Obj.-019 | Sejour cuisine | Sejour cuisine | B05 | rdc | 3 | LV | 1 | 600 | 0.36 | 0.0534437 | 3000 | 4.19567 | 3900 | 2226492 | -639456
Obj.-019 | rdc | 0.394679 | Revêt. pilier rond | Obj.-019 | Sejour cuisine | Sejour cuisine | B02 | rdc | 3 | LV | 1 | 600 | 0.36 | 0.0534437 | 3000 | 4.19567 | 3900 | 2223132 | -640483
Obj.-019 | rdc | 354.243 | Revêt. pilier rond | Obj.-019 | Sejour Cuisine/pl | Sejour Cuisine/pl | A04 | rdc | 3 | LV | 1 | 600 | 0.36 | 0.0534437 | 3000 | 4.19567 | 3900 | 2237180 | -614344
Obj.-019 | rdc | 0.0462755 | Revêt. pilier rond | Obj.-019 | Sejour Cuisine | Sejour Cuisine | B01 | rdc | 3 | LV | 1 | 600 | 0.36 | 0.0534437 | 3000 | 4.19567 | 3900 | 2224133 | -625671
Obj.-003 | rdc | 354.293 | C10 | Obj.-003 | Cellier | Cellier | A02 | rdc | 3 | LL | 4 | 610 | 0.3721 | 0.0552404 | 3000 | 4.2919 | 3900 | 2224358 | -617334
Obj.-003 | rdc | 354.201 | C10 | Obj.-003 | Sdb | Sdb | A04 | rdc | 3 | LL | 4 | 610 | 0.3721 | 0.0552404 | 3000 | 4.2919 | 3900 | 2238422 | -611319
Obj.-003 | rdc | 0.0944001 | C10 | Obj.-003 | Sdb | Sdb | B01 | rdc | 3 | LL | 4 | 610 | 0.3721 | 0.0552404 | 3000 | 4.2919 | 3900 | 2222317 | -632434
Obj.-019 | rdc | 354.243 | Revêt. pilier rond | Obj.-019 | Sejour Cuisine | Sejour Cuisine | A02 | rdc | 3 | LV | 1 | 600 | 0.36 | 0.0534437 | 3000 | 4.19567 | 3900 | 2224633 | -619055
Obj.-019 | rdc | 359.964 | Revêt. pilier rond | Obj.-019 | Sejour cuisine/pl | Sejour cuisine/pl | B04 | rdc | 3 | LV | 1 | 600 | 0.36 | 0.0534437 | 3000 | 4.19567 | 3900 | 2229906 | -653013
Obj.-003 | rdc | 0.0944001 | C10 | Obj.-003 | Sdb | Sdb | B02 | rdc | 3 | LL | 4 | 610 | 0.3721 | 0.0552404 | 3000 | 4.2919 | 3900 | 2221691 | -634250
Obj.-019 | rdc | 354.023 | Revêt. pilier rond | Obj.-019 | Sejour cuisine/pl | Sejour cuisine/pl | A01 | rdc | 3 | LV | 1 | 600 | 0.36 | 0.0534437 | 3000 | 4.19567 | 3900 | 2225928 | -607240
Obj.-003 | rdc | 360 | C10 | Obj.-003 | Cellier | Cellier | B03 | rdc | 3 | LL | 4 | 610 | 0.3721 | 0.0552404 | 3000 | 4.2919 | 3900 | 2224096 | -647583
Obj.-019 | rdc | 354.243 | Revêt. pilier rond | Obj.-019 | Sejour cuisine | Sejour cuisine | A03 | rdc | 3 | LV | 1 | 600 | 0.36 | 0.0534437 | 3000 | 4.19567 | 3900 | 2229564 | -615469
Obj.-003 | rdc | 354.132 | C10 | Obj.-003 | Sdb | Sdb | A03 | rdc | 3 | LL | 4 | 610 | 0.3721 | 0.0552404 | 3000 | 4.2919 | 3900 | 2225563 | -621315
Obj.-003 | rdc | 360 | C10 | Obj.-003 | Sdb | Sdb | B05 | rdc | 3 | LL | 4 | 610 | 0.3721 | 0.0552404 | 3000 | 4.2919 | 3900 | 2228368 | -646738
Obj.-003 | rdc | 0.0146967 | C10 | Obj.-003 | Cellier | Cellier | B04 | rdc | 3 | LL | 4 | 610 | 0.3721 | 0.0552404 | 3000 | 4.2919 | 3900 | 2228587 | -651691
Obj.-003 | rdc | 0.0585155 | C10 | Obj.-003 | Cellier | Cellier | B04 | rdc | 3 | SL | 4 | 610 | 0.3721 | 0.0552404 | 3000 | 4.2919 | 3900 | 2228590 | -652316
Obj.-019 | Etage1 | 89.9945 | Revêt. pilier rond | Obj.-019 | Sejour cuisine | Sejour cuisine | B16 | Etage1 | 4 | LV | 1 | 600 | 0.36 | 0.0534437 | 5750 | 4.19567 | 6650 | 2226492 | -639456
Obj.-003 | Etage1 | 360 | C10 | Obj.-003 | Cellier | Cellier | B14 | Etage1 | 4 | LL | 4 | 610 | 0.3721 | 0.0552404 | 5750 | 4.2919 | 6650 | 2224096 | -647762
Obj.-019 | Etage1 | 359.964 | Revêt. pilier rond | Obj.-019 | Sejour cuisine | Sejour cuisine | B15 | Etage1 | 4 | LV | 1 | 600 | 0.36 | 0.0534437 | 5750 | 4.19567 | 6650 | 2229906 | -653014
Obj.-003 | Etage1 | 354.293 | C10 | Obj.-003 | Cellier | Cellier | A12 | Etage1 | 4 | LL | 4 | 610 | 0.3721 | 0.0552404 | 5750 | 4.2919 | 6650 | 2224358 | -617334
Obj.-003 | Etage1 | 354.201 | C10 | Obj.-003 | Sdb | Sdb | A14 | Etage1 | 4 | LL | 4 | 610 | 0.3721 | 0.0552404 | 5750 | 4.2919 | 6650 | 2238422 | -611319
Obj.-019 | Etage1 | 354.023 | Revêt. pilier rond | Obj.-019 | Sejour cuisine/pl | Sejour cuisine/pl | A11 | Etage1 | 4 | LV | 1 | 600 | 0.36 | 0.0534437 | 5750 | 4.19567 | 6650 | 2225928 | -607240
Obj.-019 | Etage1 | 354.067 | Revêt. pilier rond | Obj.-019 | Sejour cuisine/pl | Sejour cuisine/pl | A15 | Etage1 | 4 | LV | 1 | 600 | 0.36 | 0.0534437 | 5750 | 4.19567 | 6650 | 2227183 | -612456
Obj.-003 | Etage1 | 0.0944001 | C10 | Obj.-003 | Sde | Sde | B13 | Etage1 | 4 | LL | 4 | 610 | 0.3721 | 0.0552404 | 5750 | 4.2919 | 6650 | 2221691 | -634250
Obj.-019 | Etage1 | 0.0462755 | Revêt. pilier rond | Obj.-019 | Sejour cuisine | Sejour cuisine | B12 | Etage1 | 4 | LV | 1 | 600 | 0.36 | 0.0534437 | 5750 | 4.19567 | 6650 | 2224133 | -625671
Obj.-003 | Etage1 | 359.906 | C10 | Obj.-003 | Sde | Sde | B12 | Etage1 | 4 | LL | 4 | 610 | 0.3721 | 0.0552404 | 5750 | 4.2919 | 6650 | 2221709 | -632433
Obj.-019 | Etage1 | 354.243 | Revêt. pilier rond | Obj.-019 | Sejour cuisine | Sejour cuisine | A12 | Etage1 | 4 | LV | 1 | 600 | 0.36 | 0.0534437 | 5750 | 4.19567 | 6650 | 2224633 | -619055
Obj.-019 | Etage1 | 354.243 | Revêt. pilier rond | Obj.-019 | Sejour cuisine | Sejour cuisine | A13 | Etage1 | 4 | LV | 1 | 600 | 0.36 | 0.0534437 | 5750 | 4.19567 | 6650 | 2229527 | -615465
Obj.-003 | Etage1 | 354.109 | C10 | Obj.-003 | Sejour cuisine/pl | Sejour cuisine/pl | A11 | Etage1 | 4 | LL | 4 | 610 | 0.3721 | 0.0552404 | 5750 | 4.2919 | 6650 | 2223987 | -607807
Obj.-019 | Etage1 | 354.243 | Revêt. pilier rond | Obj.-019 | Sejour Cuisine/pl | Sejour Cuisine/pl | A14 | Etage1 | 4 | LV | 1 | 600 | 0.36 | 0.0534437 | 5750 | 4.19567 | 6650 | 2237180 | -614344
Obj.-003 | Etage1 | 84.1924 | C10 | Obj.-003 | Sde | Sde | A15 | Etage1 | 4 | LL | 4 | 610 | 0.3721 | 0.0552404 | 5750 | 4.2919 | 6650 | 2232076 | -610513
Obj.-003 | Etage1 | 354.132 | C10 | Obj.-003 | Sde | Sde | A13 | Etage1 | 4 | LL | 4 | 610 | 0.3721 | 0.0552404 | 5750 | 4.2919 | 6650 | 2225511 | -621310
Obj.-003 | Etage1 | 359.906 | C10 | Obj.-003 | Sejour cuisine | Sejour cuisine | B11 | Etage1 | 4 | LL | 4 | 610 | 0.3721 | 0.0552404 | 5750 | 4.2919 | 6650 | 2225899 | -630948
Obj.-019 | Etage1 | 0.394679 | Revêt. pilier rond | Obj.-019 | Sejour Cuisine | Sejour Cuisine | B13 | Etage1 | 4 | LV | 1 | 600 | 0.36 | 0.0534437 | 5750 | 4.19567 | 6650 | 2223132 | -640483
Obj.-019 | Etage1 | 359.88 | Revêt. pilier rond | Obj.-019 | Sejour cuisine | Sejour cuisine | B14 | Etage1 | 4 | LV | 1 | 600 | 0.36 | 0.0534437 | 5750 | 4.19567 | 6650 | 2220482 | -653013
Obj.-019 | Etage1 | 0.0974992 | Revêt. pilier rond | Obj.-019 | Sejour cuisine | Sejour cuisine | B11 | Etage1 | 4 | LV | 1 | 600 | 0.36 | 0.0534437 | 5750 | 4.19567 | 6650 | 2227181 | -632333
Obj.-003 | Etage1 | 0 | C10 | Obj.-003 | Cellier | Cellier | B15 | Etage1 | 4 | LL | 4 | 610 | 0.3721 | 0.0552404 | 5750 | 4.2919 | 6650 | 2229237 | -652233
Obj.-003 | Etage1 | 360 | C10 | Obj.-003 | Sde | Sde | B16 | Etage1 | 4 | LL | 4 | 610 | 0.3721 | 0.0552404 | 5750 | 4.2919 | 6650 | 2228368 | -646738
Obj.-019 | Etage 2 | 354.023 | Revêt. pilier rond | Obj.-019 | Sejour cuisine/pl | Sejour cuisine/pl | A21 | Etage 2 | 5 | LV | 1 | 600 | 0.36 | 0.0534437 | 8500 | 4.19567 | 9400 | 2225928 | -607240
Obj.-003 | Etage 2 | 354.293 | C10 | Obj.-003 | Cellier | Cellier | A22 | Etage 2 | 5 | LL | 4 | 610 | 0.3721 | 0.0552404 | 8500 | 4.2919 | 9400 | 2224372 | -617321
Obj.-003 | Etage 2 | 0 | C10 | Obj.-003 | Cellier | Cellier | B25 | Etage 2 | 5 | LL | 4 | 610 | 0.3721 | 0.0552404 | 8500 | 4.2919 | 9400 | 2229237 | -652233
Obj.-003 | Etage 2 | 354.109 | C10 | Obj.-003 | Sejour cuisine/pl | Sejour cuisine/pl | A21 | Etage 2 | 5 | LL | 4 | 610 | 0.3721 | 0.0552404 | 8500 | 4.2919 | 9400 | 2224060 | -607813
Obj.-003 | Etage 2 | 359.906 | C10 | Obj.-003 | Sde | Sde | B22 | Etage 2 | 5 | LL | 4 | 610 | 0.3721 | 0.0552404 | 8500 | 4.2919 | 9400 | 2221709 | -632433
Obj.-019 | Etage 2 | 359.964 | Revêt. pilier rond | Obj.-019 | Sejour cuisine | Sejour cuisine | B25 | Etage 2 | 5 | LV | 1 | 600 | 0.36 | 0.0534437 | 8500 | 4.19567 | 9400 | 2229906 | -653015
Obj.-003 | Etage 2 | 354.293 | C10 | Obj.-003 | Sde | Sde | A23 | Etage 2 | 5 | LL | 4 | 610 | 0.3721 | 0.0552404 | 8500 | 4.2919 | 9400 | 2226169 | -621375
Obj.-019 | Etage 2 | 0.0794066 | Revêt. pilier rond | Obj.-019 | Sejour cuisine | Sejour cuisine | B22 | Etage 2 | 5 | LV | 1 | 600 | 0.36 | 0.0534437 | 8500 | 4.19567 | 9400 | 2224132 | -625670
Obj.-003 | Etage 2 | 90.0944 | C10 | Obj.-003 | Sde | Sde | B23 | Etage 2 | 5 | LL | 4 | 610 | 0.3721 | 0.0552404 | 8500 | 4.2919 | 9400 | 2221690 | -633640
Obj.-019 | Etage 2 | 354.243 | Revêt. pilier rond | Obj.-019 | Sejour cuisine | Sejour cuisine | A23 | Etage 2 | 5 | LV | 1 | 600 | 0.36 | 0.0534437 | 8500 | 4.19567 | 9400 | 2229561 | -615469
Obj.-019 | Etage 2 | 354.243 | Revêt. pilier rond | Obj.-019 | Sejour cuisine/pl | Sejour cuisine/pl | A24 | Etage 2 | 5 | LV | 1 | 600 | 0.36 | 0.0534437 | 8500 | 4.19567 | 9400 | 2237180 | -614344
Obj.-003 | Etage 2 | 359.906 | C10 | Obj.-003 | Sejour cuisine | Sejour cuisine | B21 | Etage 2 | 5 | LL | 4 | 610 | 0.3721 | 0.0552404 | 8500 | 4.2919 | 9400 | 2225899 | -630948
Obj.-003 | Etage 2 | 84.1924 | C10 | Obj.-003 | Sde | Sde | A25 | Etage 2 | 5 | LL | 4 | 610 | 0.3721 | 0.0552404 | 8500 | 4.2919 | 9400 | 2232076 | -610513
Obj.-019 | Etage 2 | 0.394679 | Revêt. pilier rond | Obj.-019 | Sejour cuisine | Sejour cuisine | B23 | Etage 2 | 5 | LV | 1 | 600 | 0.36 | 0.0534437 | 8500 | 4.19567 | 9400 | 2223132 | -640483
Obj.-019 | Etage 2 | 270.079 | Revêt. pilier rond | Obj.-019 | Sejour cuisine | Sejour cuisine | B21 | Etage 2 | 5 | LV | 1 | 600 | 0.36 | 0.0534437 | 8500 | 4.19567 | 9400 | 2226582 | -632334
Obj.-019 | Etage 2 | 359.88 | Revêt. pilier rond | Obj.-019 | Sejour cuisine | Sejour cuisine | B24 | Etage 2 | 5 | LV | 1 | 600 | 0.36 | 0.0534437 | 8500 | 4.19567 | 9400 | 2220480 | -653013
Obj.-019 | Etage 2 | 89.9945 | Revêt. pilier rond | Obj.-019 | Sejour cuisine | Sejour cuisine | B26 | Etage 2 | 5 | LV | 1 | 600 | 0.36 | 0.0534437 | 8500 | 4.19567 | 9400 | 2226492 | -639456
Obj.-019 | Etage 2 | 354.243 | Revêt. pilier rond | Obj.-019 | Sejour cuisine | Sejour cuisine | A22 | Etage 2 | 5 | LV | 1 | 600 | 0.36 | 0.0534437 | 8500 | 4.19567 | 9400 | 2224633 | -619055
Obj.-019 | Etage 2 | 354.067 | Revêt. pilier rond | Obj.-019 | Sejour cuisine/pl | Sejour cuisine/pl | A25 | Etage 2 | 5 | LV | 1 | 600 | 0.36 | 0.0534437 | 8500 | 4.19567 | 9400 | 2227183 | -612456
Obj.-003 | Etage 2 | 360 | C10 | Obj.-003 | Cellier | Cellier | B24 | Etage 2 | 5 | LL | 4 | 610 | 0.3721 | 0.0552404 | 8500 | 4.2919 | 9400 | 2224096 | -647823
Obj.-003 | Etage 2 | 360 | C10 | Obj.-003 | Sde | Sde | B26 | Etage 2 | 5 | LL | 4 | 610 | 0.3721 | 0.0552404 | 8500 | 4.2919 | 9400 | 2228368 | -646738
Obj.-003 | Etage 2 | 354.201 | C10 | Obj.-003 | Sde | Sde | A24 | Etage 2 | 5 | LL | 4 | 610 | 0.3721 | 0.0552404 | 8500 | 4.2919 | 9400 | 2238422 | -611319
Obj.-003 | Etage 3 | 359.892 | C10 | Obj.-003 | Sde | Sde | B32 | Etage 3 | 6 | LL | 4 | 610 | 0.3721 | 0.0552404 | 11550 | 4.2919 | 12450 | 2221709 | -632433
Obj.-019 | Etage 3 | 0.394679 | Revêt. pilier rond | Obj.-019 | Sejour cuisine | Sejour cuisine | B33 | Etage 3 | 6 | LV | 1 | 600 | 0.36 | 0.0534437 | 11550 | 4.19567 | 12450 | 2223132 | -640483
Obj.-003 | Etage 3 | 90.0944 | C10 | Obj.-003 | Sde | Sde | B33 | Etage 3 | 6 | LL | 4 | 610 | 0.3721 | 0.0552404 | 11550 | 4.2919 | 12450 | 2221690 | -633640
Obj.-003 | Etage 3 | 354.104 | C10 | Obj.-003 | Sejour cuisine/pl | Sejour cuisine/pl | A34 | Etage 3 | 6 | LL | 4 | 610 | 0.3721 | 0.0552404 | 11550 | 4.2919 | 12450 | 2229249 | -611987
Obj.-019 | Etage 3 | 354.12 | Revêt. pilier rond | Obj.-019 | Sejour cuisine | Sejour cuisine | A32 | Etage 3 | 6 | LV | 1 | 600 | 0.36 | 0.0534437 | 11550 | 4.19567 | 12450 | 2230159 | -615530
Obj.-019 | Etage 3 | 270.079 | Revêt. pilier rond | Obj.-019 | Sejour cuisine/pl | Sejour cuisine/pl | B31 | Etage 3 | 6 | LV | 1 | 600 | 0.36 | 0.0534437 | 11550 | 4.19567 | 12450 | 2226582 | -632334
Obj.-019 | Etage 3 | 354.12 | Revêt. pilier rond | Obj.-019 | Sejour cuisine/pl | Sejour cuisine/pl | A33 | Etage 3 | 6 | LV | 1 | 600 | 0.36 | 0.0534437 | 11550 | 4.19567 | 12450 | 2237634 | -615530
Obj.-019 | Etage 3 | 354.249 | Revêt. pilier rond | Obj.-019 | Sejour cuisine/pl | Sejour cuisine/pl | A31 | Etage 3 | 6 | LV | 1 | 600 | 0.36 | 0.0534437 | 11550 | 4.19567 | 12450 | 2219873 | -612037
Obj.-003 | Etage 3 | 270.059 | C10 | Obj.-003 | cellier | cellier | B34 | Etage 3 | 6 | LL | 4 | 610 | 0.3721 | 0.0552404 | 11550 | 4.2919 | 12450 | 2227371 | -648360
Obj.-003 | Etage 3 | 359.906 | C10 | Obj.-003 | Sejour cuisine/pl | Sejour cuisine/pl | B31 | Etage 3 | 6 | LL | 4 | 610 | 0.3721 | 0.0552404 | 11550 | 4.2919 | 12450 | 2225899 | -630948
Obj.-019 | Etage 3 | 354.249 | Revêt. pilier rond | Obj.-019 | Sejour cuisine/pl | Sejour cuisine/pl | A34 | Etage 3 | 6 | LV | 1 | 600 | 0.36 | 0.0534437 | 11550 | 4.19567 | 12450 | 2230436 | -612787
Obj.-019 | Etage 3 | 0.0794066 | Revêt. pilier rond | Obj.-019 | Sejour cuisine | Sejour cuisine | B32 | Etage 3 | 6 | LV | 1 | 600 | 0.36 | 0.0534437 | 11550 | 4.19567 | 12450 | 2224132 | -625670
Obj.-003 | Etage 3 | 354.197 | C10 | Obj.-003 | Sde | Sde | A32 | Etage 3 | 6 | LL | 4 | 610 | 0.3721 | 0.0552404 | 11550 | 4.2919 | 12450 | 2225543 | -621313
Obj.-003 | Etage 3 | 360 | C10 | Obj.-003 | Sde | Sde | B35 | Etage 3 | 6 | LL | 4 | 610 | 0.3721 | 0.0552404 | 11550 | 4.2919 | 12450 | 2228368 | -646738
Obj.-003 | Etage 3 | 354.307 | C10 | Obj.-003 | Sde | Sde | A33 | Etage 3 | 6 | LL | 4 | 610 | 0.3721 | 0.0552404 | 11550 | 4.2919 | 12450 | 2238284 | -612430
Obj.-003 | Etage 3 | 354.324 | C10 | Obj.-003 | Sejour cuisine/pl | Sejour cuisine/pl | A31 | Etage 3 | 6 | LL | 4 | 610 | 0.3721 | 0.0552404 | 11550 | 4.2919 | 12450 | 2221541 | -612208
Obj.-019 | Etage 3 | 90.3947 | Revêt. pilier rond | Obj.-019 | Sejour cuisine | Sejour cuisine | B34 | Etage 3 | 6 | LV | 1 | 600 | 0.36 | 0.0534437 | 11550 | 4.19567 | 12450 | 2231066 | -647679
Obj.-019 | Etage 3 | 89.9945 | Revêt. pilier rond | Obj.-019 | Sejour cuisine/pl | Sejour cuisine/pl | B35 | Etage 3 | 6 | LV | 1 | 600 | 0.36 | 0.0534437 | 11550 | 4.19567 | 12450 | 2226492 | -639456
Obj.-019 | etage 4 | 5.038e-12 | Revêt. pilier rond | Obj.-019 | Sejour cuisine | Sejour cuisine | B44 | etage 4 | 7 | LV | 1 | 600 | 0.36 | 0.0534437 | 14600 | 4.19567 | 15500 | 2228841 | -647521
Obj.-019 | etage 4 | 0.0794066 | Revêt. pilier rond | Obj.-019 | Sejour cuisine | Sejour cuisine | B42 | etage 4 | 7 | LV | 1 | 600 | 0.36 | 0.0534437 | 14600 | 4.19567 | 15500 | 2224132 | -625670
Obj.-019 | etage 4 | 0.0794066 | Revêt. pilier rond | Obj.-019 | Sejour cuisine/pl | Sejour cuisine/pl | B41 | etage 4 | 7 | LV | 1 | 600 | 0.36 | 0.0534437 | 14600 | 4.19567 | 15500 | 2227182 | -632333
Obj.-019 | etage 4 | 0.394679 | Revêt. pilier rond | Obj.-019 | Sejour cuisine | Sejour cuisine | B43 | etage 4 | 7 | LV | 1 | 600 | 0.36 | 0.0534437 | 14600 | 4.19567 | 15500 | 2223132 | -640483
Obj.-019 | etage 4 | 5.038e-12 | Revêt. pilier rond | Obj.-019 | Sejour cuisine | Sejour cuisine | B53 | etage 4 | 7 | LV | 1 | 600 | 0.36 | 0.0534437 | 14600 | 4.19567 | 15500 | 2301483 | -644799
Obj.-003 | etage 4 | 0 | C10 | Obj.-003 | Cellier | Cellier | B44 | etage 4 | 7 | LL | 4 | 610 | 0.3721 | 0.0552404 | 14600 | 4.2919 | 15500 | 2226428 | -647528
Obj.-003 | etage 4 | 359.886 | C10 | Obj.-003 | Sde | Sde | B42 | etage 4 | 7 | LL | 4 | 610 | 0.3721 | 0.0552404 | 14600 | 4.2919 | 15500 | 2221709 | -632433
Obj.-003 | etage 4 | 359.906 | C10 | Obj.-003 | Sejour cuisine/pl | Sejour cuisine/pl | B41 | etage 4 | 7 | LL | 4 | 610 | 0.3721 | 0.0552404 | 14600 | 4.2919 | 15500 | 2225899 | -630948
Obj.-003 | etage 4 | 90.0944 | C10 | Obj.-003 | Sde | Sde | B43 | etage 4 | 7 | LL | 4 | 610 | 0.3721 | 0.0552404 | 14600 | 4.2919 | 15500 | 2221690 | -633640
Obj.-003 | Etage 5 | 0 | C10 | Obj.-003 | Cellier | Cellier | B52 | Etage 5 | 8 | SL | 4 | 610 | 0.3721 | 0.0552404 | 17650 | 4.2919 | 18550 | 2227314 | -646738
Obj.-019 | Etage 5 | 0.0794066 | Revêt. pilier rond | Obj.-019 | Sejour cuisine | Sejour cuisine | B51 | Etage 5 | 8 | LV | 1 | 600 | 0.36 | 0.0534437 | 17650 | 4.19567 | 18550 | 2220528 | -632433
Obj.-003 | Etage 5 | 0 | C10 | Obj.-003 | Cellier | Cellier | B52 | Etage 5 | 8 | LL | 4 | 610 | 0.3721 | 0.0552404 | 17650 | 4.2919 | 18550 | 2226704 | -646738
Obj.-003 | Etage 5 | 0 | C10 | Obj.-003 | cellier; Sejour cuisine | cellier | B51 | Etage 5 | 8 | LL | 4 | 610 | 0.3721 | 0.0552404 | 17650 | 4.2919 | 18550 | 2221916 | -632426
Obj.-019 | Etage 5 | 0.0794066 | Revêt. pilier rond | Obj.-019 | Sejour Cuisine | Sejour Cuisine | B54 | Etage 5 | 8 | LV | 1 | 600 | 0.36 | 0.0534437 | 17650 | 4.19567 | 18550 | 2300794 | -641334
Obj.-019 | Etage 5 | 0.0794066 | Revêt. pilier rond | Obj.-019 | Sejour Cuisine | Sejour Cuisine | B52 | Etage 5 | 8 | LV | 1 | 600 | 0.36 | 0.0534437 | 17650 | 4.19567 | 18550 | 2226983 | -647518

# IfcRailing: Cadre avec câble 01 20 (166)
Classification: Garde-corps (Classification ARCHICAD)
AC_Pset_Cadre_avec_câble_01_20 - 3D (gs_detlevel_3D): Détaillé; 3D (gs_detlevel_3d_m): 2; Appelé comme Macro escalier: no; Côté 'A'=Longueur main courante: yes; Type rampe et paramètres saisie (ptyp): Carré; Type rampe et paramètres saisie (ptyp_m): 1; Méthode d'inclinaison (rom): Non incliné; Méthode orientation rampe: 1; Méthode d'inclinaison (iInclinationMethod): 1; Méthode de mesure: Vertical; Modes de mesure rampe: 1; Angle d'inclinaison: -0.01 deg; Angle de courbure: 85.9437 deg; Type main courante (hrt): Rectangulaire; Type main courante (hrt_m): 1; Style poteau (pt): Rectangulaire; Style poteau (pt_m): 1; Type câble: Arrondi; Style barreau: 2; Résolution arc rampe: 32; Résolution coupe transversale: 12; Ombre: yes; Afficher points chauds 2D en 3D: no; Motif de hachure: Sans Trame; Afficher axe: yes; Type de ligne d'axe: 6; Symbole poteau: no; Type de ligne symbole (postSymbolType): Type 1; Type de ligne symbole (iPostSymbolType): 1; Type de ligne de poteau: 1; Main courante: C02; Poteau: Métal-Inox; Fil: Métal-Inox; Coût: 0; Type de groupe (FM_Type): Autres; Type de groupe (iFMType): 25; Poids de l'objet: 0; Unité poids de l'objet: kg
ArchiCADProperties - Surface: Revêt. pilier rond; ID de l'élément: Obj.-002; Lien et ID d'élément: Obj.-002; Calque: ESQ blacon grosse rampe; Nom Élément de Bibliothèque: Cadre avec câble 01 20; Matériau de construction / Composite / Profil / Hachure: Brique 1; Type Hachure: Brique 1; Verrouillé: no; Type d'élément: Objet; ID de Parent: Obj.-002; Surfaces (Toutes): Métal-Inox; C02; Nom de Variante: Modèle principal; Nom de Jeu de Variantes: Modèle principal; Position: Non défini; Fonction structurelle: Non défini; Affichage sur filtre de rénovation: Tous les filtres appropriés; État de rénovation: Existant; État de Variante: Modèle principal; Jeu de Variantes: Modèle principal
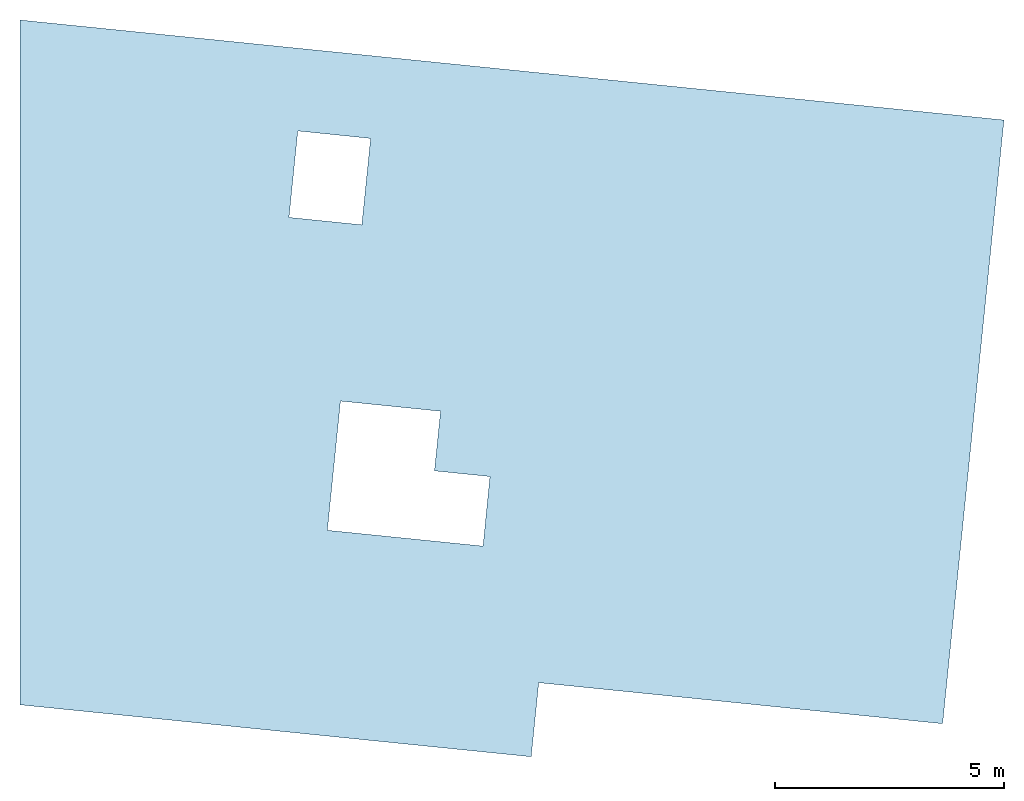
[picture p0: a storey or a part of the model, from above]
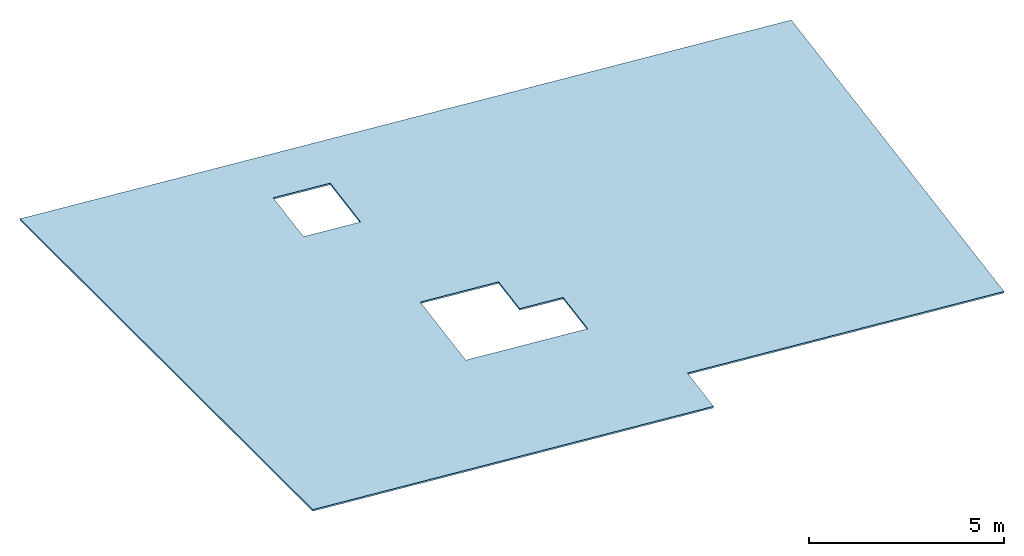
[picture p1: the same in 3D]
Properties of the parts of a building model (IFC2X3), part 17 of 44

# IfcRailing: Cadre avec câble 01 20 (166)
AC_Equantity_Cadre_avec_câble_01_20 - Rayon de courbure: 1000 mm; Distance de Dalle/Escalier (ds): 150 mm; Distance de Dalle/Escalier (dsPerp): 150 mm; Diamètre main courante: 60 mm; Hauteur main courante: 50 mm; Diamètre poteau: 35 mm; Largeur poteau: 10 mm; Epaisseur poteau: 50 mm; Débord base de poteau (gs_PostBaseOverhang): 176 mm; Débord base de poteau (gs_PostBaseOverhangPerp): 176 mm; Diamètre câble: 25 mm; Largeur câble: 15 mm; Hauteur fil: 15 mm; Niveau inférieur: 1000 mm; Niveau supérieur: 0 mm
AC_Pset_RenovationAndPhasing - Renovation Status: Existing
Name | In | Angle de coupe gauche (deg) | Angle de coupe droit (deg) | Nb. poteau | Nb. de câbles | Angle de rotation (deg) | Nom d'étage d'implantation | Numéro d'étage d'implantation | 1ère dimension (mm) = Longueur horizontale de rampe (mm) = Longueur rampe (mm) = Longueur (A) (mm) | 2ème dimension (mm) = Largeur main courante (mm) = Largeur (mm) | AC_Equantity_Cadre_avec_câble_01_20, Hauteur (mm) = ArchiCADQuantities, Hauteur (mm) | Hauteur rampe (hr) (mm) = Hauteur rampe (hrPerp) (mm) | Débord main courante (mm) | Débord main courante (gauche) (hroL) (mm) = Débord main courante (gauche) (hroLDiagonal) (mm) | Débord main courante (droite) (hroR) (mm) = Débord main courante (droite) (hroRDiagonal) (mm) | Superficie (m2) = Superficie supérieure (nette) (m2) | Volume (net) (m3) | Altitude à Zéro du Projet (mm) = Altitude de Référence Niveau 1 (mm) = Altitude de Référence Niveau 2 (mm) = Altitude à niveau de la mer (mm) = Coordonnée topographique Z (mm) | Altitude à étage lié/étage d'implantation (mm) = Décalage étage d'implantation (mm) | Superficie en plan (m2) = Superficie inférieure (nette) (m2) | Altitude supérieure à premier niveau de référence (mm) = Altitude supérieure à Zéro du projet (mm) = Altitude supérieure à niveau de la mer (mm) = Altitude supérieure à deuxième niveau de référence (mm) | Altitude supérieure à étage d'implantation (mm) | Altitude inférieure à premier niveau de référence (mm) = Altitude inférieure à Zéro du projet (mm) = Altitude inférieure à niveau de la mer (mm) = Altitude inférieure à deuxième niveau de référence (mm) | Altitude inférieure à étage d'implantation (mm) | Coordonnée topographique X (mm) | Coordonnée topographique Y (mm)
Obj.-002 | rdc | 90 | 90 | 3 | 7 | 270.046 | rdc | 3 | 2000 | 250 | 1000 | 850 | 90 | 90 | 90 | 0.5 | 0.0325952 | 3000 | 8.88178e-13 | 2.62482 | 4000 | 1000 | 2824 | -176 | 2234233 | -639733
2 x Obj.-002 | rdc | 90 | 90 | 2 | 21 | 180 | rdc | 3 | 2003.14 | 150 | 2050 | 1900 | 0 | 150 | 150 | 0.300471 | 0.0338664 | 3000 | 0 | 4.12095 | 5050 | 2050 | 2824 | -176 | 2234192 | -635797
Obj.-002 | rdc | 90 | 90 | 5 | 7 | 270 | rdc | 3 | 5713.12 | 250 | 1000 | 850 | 90 | 90 | 90 | 1.42828 | 0.0922532 | 3000 | 0 | 7.14534 | 4000 | 1000 | 2824 | -176 | 2234227 | -646738 | ArchiCADProperties - Zones conflictuelles: Terrasse
Obj.-002 | rdc | 45.0007 | 44.9986 | 11 | 7 | 0.00143799 | rdc | 3 | 17471.1 | 250 | 1000 | 850 | 90 | 90 | 90 | 4.36777 | 0.28099 | 3000 | 0 | 21.4246 | 4000 | 1000 | 2824 | -176 | 2234232 | -660973 | ArchiCADProperties - Zones conflictuelles: Terrasse
Obj.-002 | rdc | 45 | 90 | 5 | 7 | 270 | rdc | 3 | 5931.85 | 250 | 1000 | 850 | 90 | 90 | 90 | 1.48296 | 0.0957052 | 3000 | 0 | 7.40064 | 4000 | 1000 | 2824 | -176 | 2216759 | -660973
Obj.-002 | rdc | 135.005 | 90 | 5 | 7 | 270 | rdc | 3 | 5931.44 | 250 | 1000 | 850 | 90 | 90 | 90 | 1.48286 | 0.0956986 | 3000 | 0 | 7.40017 | 4000 | 1000 | 2824 | -176 | 2234232 | -660973
Obj.-002 | rdc | 90 | 90 | 3 | 7 | 90 | rdc | 3 | 2000 | 250 | 1000 | 850 | 90 | 90 | 90 | 0.5 | 0.0325952 | 3000 | 0 | 2.62482 | 4000 | 1000 | 2824 | -176 | 2216759 | -652104
Obj.-002 | rdc | 90 | 90 | 3 | 7 | 90 | rdc | 3 | 2000 | 250 | 1000 | 850 | 90 | 90 | 90 | 0.5 | 0.0325952 | 3000 | 0 | 2.62482 | 4000 | 1000 | 2824 | -176 | 2216759 | -632277
Obj.-002 | rdc | 90 | 90 | 3 | 7 | 270 | rdc | 3 | 2000 | 250 | 1000 | 850 | 90 | 90 | 90 | 0.5 | 0.0325952 | 3000 | 0 | 2.62482 | 4000 | 1000 | 2824 | -176 | 2234232 | -649260
Obj.-002 | rdc | 90 | 90 | 5 | 7 | 270 | rdc | 3 | 4999.57 | 250 | 1000 | 850 | 90 | 90 | 90 | 1.24989 | 0.0809926 | 3000 | 0 | 6.32938 | 4000 | 1000 | 2824 | -176 | 2216759 | -644016
Obj.-002 | rdc | 90 | 90 | 4 | 7 | 270 | rdc | 3 | 3139.3 | 250 | 1000 | 850 | 90 | 90 | 90 | 0.784826 | 0.0511051 | 3000 | 0 | 4.06489 | 4000 | 1000 | 2824 | -176 | 2216759 | -620647
Obj.-002 | rdc | 90 | 42.0226 | 4 | 7 | 270 | rdc | 3 | 3185.63 | 250 | 1000 | 850 | 90 | 90 | 90 | 0.796408 | 0.0518362 | 3000 | 0 | 4.12404 | 4000 | 1000 | 2824 | -176 | 2216759 | -607167 | ArchiCADProperties - Zones conflictuelles: Terrasse
Obj.-002 | rdc | 84.2127 | 137.81 | 2 | 7 | 354.213 | rdc | 3 | 1382.04 | 250 | 1000 | 850 | 90 | 90 | 90 | 0.345511 | 0.0223129 | 3000 | 0 | 1.78711 | 4000 | 1000 | 2824 | -176 | 2218134 | -604121
Obj.-002 | rdc | 90 | 90 | 5 | 7 | 270 | rdc | 3 | 5286.72 | 250 | 1000 | 850 | 90 | 90 | 90 | 1.32168 | 0.0855242 | 3000 | 0 | 6.65775 | 4000 | 1000 | 2824 | -176 | 2216759 | -626071
2 x Obj.-002 | rdc | 90 | 90 | 2 | 21 | 180 | rdc | 3 | 2314.89 | 150 | 2050 | 1900 | 0 | 150 | 150 | 0.347234 | 0.0392733 | 3000 | 0 | 4.75398 | 5050 | 2050 | 2824 | -176 | 2232188 | -635797
Obj.-002 | rdc | 90 | 90 | 2 | 21 | 0 | rdc | 3 | 1423.62 | 150 | 2050 | 1900 | 0 | 150 | 150 | 0.213544 | 0.0238154 | 3000 | 0 | 2.94421 | 5050 | 2050 | 2824 | -176 | 2232767 | -631730
Obj.-002 | rdc | 90 | 90 | 2 | 21 | 0 | rdc | 3 | 1698.92 | 150 | 2050 | 1900 | 0 | 150 | 150 | 0.254837 | 0.02859 | 3000 | 0 | 3.50321 | 5050 | 2050 | 2824 | -176 | 2229876 | -631730
Obj.-002 | rdc | 90 | 90 | 2 | 21 | 90 | rdc | 3 | 1773.44 | 150 | 2050 | 1900 | 0 | 150 | 150 | 0.266016 | 0.0298826 | 3000 | 0 | 3.65453 | 5050 | 2050 | 2824 | -176 | 2234266 | -633581
Obj.-002 | rdc | 90 | 90 | 2 | 21 | 90 | rdc | 3 | 2147.95 | 150 | 2050 | 1900 | 0 | 150 | 150 | 0.322192 | 0.0363779 | 3000 | 0 | 4.41499 | 5050 | 2050 | 2824 | -176 | 2234266 | -635729
Obj.-002 | rdc | 90 | 90 | 7 | 7 | 0 | rdc | 3 | 7519.99 | 250 | 1000 | 850 | 90 | 90 | 90 | 1.88 | 0.121828 | 3000 | 0 | 9.48603 | 4000 | 1000 | 2824 | -176 | 2234357 | -632565
Obj.-002 | rdc | 90 | 90 | 2 | 21 | 0 | rdc | 3 | 1192.25 | 150 | 2050 | 1900 | 0 | 150 | 150 | 0.178838 | 0.0198026 | 3000 | 0 | 2.4744 | 5050 | 2050 | 2824 | -176 | 2231575 | -631730
Obj.-002 | Etage1 | 90 | 135 | 2 | 7 | 0 | Etage1 | 4 | 1176.91 | 250 | 1000 | 850 | 0 | 150 | 150 | 0.294228 | 0.018682 | 5750 | 0 | 1.48631 | 6750 | 1000 | 5574 | -176 | 2229653 | -626665
Obj.-002 | Etage1 | 45 | 44.9992 | 5 | 7 | 270 | Etage1 | 4 | 5249.57 | 250 | 1000 | 850 | 90 | 90 | 90 | 1.31239 | 0.0849379 | 5750 | 0 | 6.62562 | 6750 | 1000 | 5574 | -176 | 2215864 | -644141
Obj.-002 | Etage1 | 90 | 90 | 3 | 7 | 270.046 | Etage1 | 4 | 2000 | 250 | 1000 | 850 | 90 | 90 | 90 | 0.5 | 0.0325952 | 5750 | 0 | 2.62482 | 6750 | 1000 | 5574 | -176 | 2234233 | -652114
Obj.-002 | Etage1 | 90 | 45.002 | 7 | 7 | 354.213 | Etage1 | 4 | 8743.48 | 250 | 1000 | 850 | 0 | 150 | 150 | 2.18587 | 0.140743 | 5750 | 0 | 10.8251 | 6750 | 1000 | 5574 | -176 | 2229668 | -621984 | ArchiCADProperties - Zones conflictuelles: balcon; balcon
Obj.-002 | Etage1 | 45 | 90 | 5 | 7 | 90 | Etage1 | 4 | 5140.06 | 250 | 1000 | 850 | 0 | 150 | 150 | 1.28501 | 0.0828159 | 5750 | 0 | 6.42999 | 6750 | 1000 | 5574 | -176 | 2234232 | -660182
Obj.-002 | Etage1 | 45 | 45 | 12 | 7 | 0 | Etage1 | 4 | 18399 | 250 | 1000 | 850 | 90 | 90 | 90 | 4.59976 | 0.296164 | 5750 | 0 | 22.623 | 6750 | 1000 | 5574 | -176 | 2234232 | -660182
Obj.-002 | Etage1 | 90 | 90 | 3 | 7 | 90 | Etage1 | 4 | 2000 | 250 | 1000 | 850 | 90 | 90 | 90 | 0.5 | 0.0325952 | 5750 | 0 | 2.62482 | 6750 | 1000 | 5574 | -176 | 2216759 | -649630
Obj.-002 | Etage1 | 90 | 90 | 3 | 7 | 90 | Etage1 | 4 | 2000 | 250 | 1000 | 850 | 90 | 90 | 90 | 0.5 | 0.0325952 | 5750 | 0 | 2.62482 | 6750 | 1000 | 5574 | -176 | 2216759 | -609632
Obj.-002 | Etage1 | 45 | 45 | 4 | 7 | 270 | Etage1 | 4 | 3384.39 | 250 | 1000 | 850 | 0 | 133.091 | 90 | 0.846097 | 0.0548314 | 5750 | 0 | 4.33208 | 6750 | 1000 | 5574 | -176 | 2216034 | -603908
Obj.-002 | Etage1 | 45 | 45 | 5 | 7 | 270 | Etage1 | 4 | 5265.06 | 250 | 1000 | 850 | 90 | 90 | 90 | 1.31626 | 0.0851823 | 5750 | 0 | 6.64333 | 6750 | 1000 | 5574 | -176 | 2215883 | -660182
Obj.-002 | Etage1 | 135 | 135 | 4 | 7 | 270 | Etage1 | 4 | 4858.21 | 250 | 1000 | 850 | 90 | 90 | 90 | 1.21455 | 0.0782316 | 5750 | 0 | 6.04085 | 6750 | 1000 | 5574 | -176 | 2230830 | -631523
Obj.-002 | Etage1 | 45.0006 | 90 | 2 | 7 | 0 | Etage1 | 4 | 770.003 | 250 | 1000 | 850 | 0 | 150 | 150 | 0.192501 | 0.0122604 | 5750 | 0 | 1.021 | 6750 | 1000 | 5574 | -176 | 2215864 | -644141
Obj.-002 | Etage1 | 134.999 | 90 | 2 | 7 | 0 | Etage1 | 4 | 770.073 | 250 | 1000 | 850 | 0 | 150 | 150 | 0.192518 | 0.0122615 | 5750 | 0 | 1.02108 | 6750 | 1000 | 5574 | -176 | 2215864 | -638892
Obj.-002 | Etage1 | 90 | 90 | 4 | 7 | 354.213 | Etage1 | 4 | 3880.5 | 250 | 1000 | 850 | 0 | 150 | 150 | 0.970125 | 0.0624083 | 5750 | 0 | 4.84724 | 6750 | 1000 | 5574 | -176 | 2226512 | -604878
Obj.-002 | Etage1 | 45.0123 | 90 | 2 | 7 | 84.1984 | Etage1 | 4 | 1591.05 | 250 | 1000 | 850 | 90 | 90 | 90 | 0.397762 | 0.0256113 | 5750 | 0 | 2.0251 | 6750 | 1000 | 5574 | -176 | 2238367 | -622865
Obj.-002 | Etage1 | 90 | 45 | 2 | 7 | 0 | Etage1 | 4 | 1176.91 | 250 | 1000 | 850 | 0 | 150 | 150 | 0.294228 | 0.018682 | 5750 | 0 | 1.48631 | 6750 | 1000 | 5574 | -176 | 2229653 | -631523
Obj.-002 | Etage1 | 45 | 90 | 2 | 7 | 0 | Etage1 | 4 | 600.362 | 250 | 1000 | 850 | 0 | 150 | 150 | 0.150091 | 0.00958328 | 5750 | 0 | 0.827015 | 6750 | 1000 | 5574 | -176 | 2216034 | -607292
Obj.-002 | Etage1 | 90 | 90 | 5 | 7 | 90 | Etage1 | 4 | 5713.12 | 250 | 1000 | 850 | 90 | 90 | 90 | 1.42828 | 0.0922532 | 5750 | 0 | 7.14534 | 6750 | 1000 | 5574 | -176 | 2234227 | -646738
Obj.-002 | Etage1 | 140.787 | 90 | 2 | 7 | 354.213 | Etage1 | 4 | 2100.79 | 250 | 1000 | 850 | 0 | 150 | 150 | 0.525198 | 0.0332619 | 5750 | 0 | 2.54488 | 6750 | 1000 | 5574 | -176 | 2216032 | -603908
Obj.-002 | Etage1 | 90 | 135 | 2 | 7 | 0 | Etage1 | 4 | 751.615 | 250 | 1000 | 850 | 0 | 150 | 150 | 0.187904 | 0.0119702 | 5750 | 0 | 0.999976 | 6750 | 1000 | 5574 | -176 | 2216634 | -654916
Obj.-002 | Etage1 | 45.0005 | 45.1464 | 5 | 7 | 270 | Etage1 | 4 | 5533.05 | 250 | 1000 | 850 | 90 | 90 | 90 | 1.38326 | 0.0894116 | 5750 | 0 | 6.94974 | 6750 | 1000 | 5574 | -176 | 2215834 | -626196
Obj.-002 | Etage1 | 135.617 | 90 | 4 | 7 | 270 | Etage1 | 4 | 3155.66 | 250 | 1000 | 850 | 0 | 150 | 150 | 0.788915 | 0.0509694 | 5750 | 0 | 4.02374 | 6750 | 1000 | 5574 | -176 | 2216759 | -620663 | ArchiCADProperties - Zones conflictuelles: balcon
Obj.-002 | Etage1 | 135.001 | 90 | 2 | 7 | 180 | Etage1 | 4 | 800 | 250 | 1000 | 850 | 0 | 150 | 150 | 0.2 | 0.0127338 | 5750 | 0 | 1.05531 | 6750 | 1000 | 5574 | -176 | 2215834 | -626196
Obj.-002 | Etage1 | 44.8536 | 134.383 | 2 | 7 | 180 | Etage1 | 4 | 924.998 | 250 | 1000 | 850 | 0 | 150 | 150 | 0.231249 | 0.0147064 | 5750 | 0 | 1.20328 | 6750 | 1000 | 5574 | -176 | 2215834 | -620663
Obj.-002 | Etage1 | 90 | 90 | 3 | 7 | 270.046 | Etage1 | 4 | 2000 | 250 | 1000 | 850 | 90 | 90 | 90 | 0.5 | 0.0325952 | 5750 | 1.77636e-12 | 2.62482 | 6750 | 1000 | 5574 | -176 | 2234232 | -639413
Obj.-002 | Etage1 | 90 | 90 | 3 | 7 | 84.1973 | Etage1 | 4 | 2000 | 250 | 1000 | 850 | 90 | 90 | 90 | 0.5 | 0.0325952 | 5750 | 0 | 2.62482 | 6750 | 1000 | 5574 | -176 | 2239804 | -608724
Obj.-002 | Etage 2 | 90 | 90 | 3 | 7 | 264.152 | Etage 2 | 5 | 2000 | 250 | 1000 | 850 | 90 | 90 | 90 | 0.5 | 0.0325952 | 8500 | 0 | 2.62482 | 9500 | 1000 | 8324 | -176 | 2238617 | -620390
Obj.-002 | Etage 2 | 44.9994 | 90 | 2 | 7 | 84.1984 | Etage 2 | 5 | 1591.3 | 250 | 1000 | 850 | 90 | 90 | 90 | 0.397825 | 0.0256153 | 8500 | 0 | 2.0254 | 9500 | 1000 | 8324 | -176 | 2237360 | -622763
Obj.-002 | Etage 2 | 135.617 | 90 | 4 | 7 | 270 | Etage 2 | 5 | 3155.66 | 250 | 1000 | 850 | 0 | 150 | 150 | 0.788915 | 0.0509694 | 8500 | 0 | 4.02374 | 9500 | 1000 | 8324 | -176 | 2216759 | -620663 | ArchiCADProperties - Zones conflictuelles: balcon
Obj.-002 | Etage 2 | 45.0008 | 90 | 2 | 7 | 180 | Etage 2 | 5 | 770.084 | 250 | 1000 | 850 | 0 | 150 | 150 | 0.192521 | 0.0122617 | 8500 | 0 | 1.0211 | 9500 | 1000 | 8324 | -176 | 2215864 | -638892
Obj.-002 | Etage 2 | 90 | 90 | 3 | 7 | 89.9543 | Etage 2 | 5 | 2000 | 250 | 1000 | 850 | 90 | 90 | 90 | 0.5 | 0.0325952 | 8500 | 0 | 2.62482 | 9500 | 1000 | 8324 | -176 | 2216758 | -632277
Obj.-002 | Etage 2 | 45.0005 | 45.1464 | 5 | 7 | 270 | Etage 2 | 5 | 5533.05 | 250 | 1000 | 850 | 90 | 90 | 90 | 1.38326 | 0.0894116 | 8500 | 0 | 6.94974 | 9500 | 1000 | 8324 | -176 | 2215834 | -626196
Obj.-002 | Etage 2 | 90 | 90 | 3 | 7 | 89.9543 | Etage 2 | 5 | 2000 | 250 | 1000 | 850 | 90 | 90 | 90 | 0.5 | 0.0325952 | 8500 | 0 | 2.62482 | 9500 | 1000 | 8324 | -176 | 2216758 | -649630
Obj.-002 | Etage 2 | 135.001 | 90 | 2 | 7 | 180 | Etage 2 | 5 | 800 | 250 | 1000 | 850 | 0 | 150 | 150 | 0.2 | 0.0127338 | 8500 | 0 | 1.05531 | 9500 | 1000 | 8324 | -176 | 2215834 | -626196
Obj.-002 | Etage 2 | 135 | 90 | 2 | 7 | 180 | Etage 2 | 5 | 770.081 | 250 | 1000 | 850 | 0 | 150 | 150 | 0.19252 | 0.0122616 | 8500 | 0 | 1.02109 | 9500 | 1000 | 8324 | -176 | 2215864 | -644141
Obj.-002 | Etage 2 | 45.0002 | 44.9994 | 5 | 7 | 270 | Etage 2 | 5 | 5249.57 | 250 | 1000 | 850 | 90 | 90 | 90 | 1.31239 | 0.0849379 | 8500 | 0 | 6.62562 | 9500 | 1000 | 8324 | -176 | 2215864 | -644141
Obj.-002 | Etage 2 | 44.8536 | 134.383 | 2 | 7 | 180 | Etage 2 | 5 | 924.998 | 250 | 1000 | 850 | 0 | 150 | 150 | 0.231249 | 0.0147064 | 8500 | 0 | 1.20328 | 9500 | 1000 | 8324 | -176 | 2215834 | -620663
Obj.-002 | Etage 2 | 90 | 45.0077 | 6 | 7 | 354.213 | Etage 2 | 5 | 7731 | 250 | 1000 | 850 | 0 | 150 | 150 | 1.93275 | 0.124234 | 8500 | 0 | 9.53003 | 9500 | 1000 | 8324 | -176 | 2229668 | -621984 | ArchiCADProperties - Zones conflictuelles: balcon; balcon
Obj.-002 | Etage 2 | 90 | 90 | 3 | 7 | 89.9543 | Etage 2 | 5 | 2000 | 250 | 1000 | 850 | 90 | 90 | 90 | 0.5 | 0.0325952 | 8500 | 0 | 2.62482 | 9500 | 1000 | 8324 | -176 | 2216758 | -613995
Obj.-002 | Etage 2 | 90 | 90 | 3 | 7 | 270.046 | Etage 2 | 5 | 2000 | 250 | 1000 | 850 | 90 | 90 | 90 | 0.5 | 0.0325952 | 8500 | 0 | 2.62482 | 9500 | 1000 | 8324 | -176 | 2229530 | -627815
Obj.-002 | Etage 2 | 90 | 90 | 3 | 7 | 354.197 | Etage 2 | 5 | 2000 | 250 | 1000 | 850 | 90 | 90 | 90 | 0.5 | 0.0325952 | 8500 | 0 | 2.62482 | 9500 | 1000 | 8324 | -176 | 2236661 | -606004
Obj.-002 | Etage 2 | 90 | 90 | 3 | 7 | 270.046 | Etage 2 | 5 | 2000 | 250 | 1000 | 850 | 90 | 90 | 90 | 0.5 | 0.0325952 | 8500 | 0 | 2.62482 | 9500 | 1000 | 8324 | -176 | 2234229 | -649260
Obj.-002 | Etage 2 | 45 | 90 | 5 | 7 | 270 | Etage 2 | 5 | 5131.64 | 250 | 1000 | 850 | 0 | 150 | 150 | 1.28291 | 0.082683 | 8500 | 0 | 6.42036 | 9500 | 1000 | 8324 | -176 | 2216759 | -660173
Obj.-002 | Etage 2 | 45 | 45 | 12 | 7 | 0 | Etage 2 | 5 | 17455.5 | 250 | 1000 | 850 | 90 | 90 | 90 | 4.36388 | 0.281274 | 8500 | 0 | 21.5441 | 9500 | 1000 | 8324 | -176 | 2234215 | -660173
Obj.-002 | Etage 2 | 135 | 90 | 5 | 7 | 270 | Etage 2 | 5 | 5131.64 | 250 | 1000 | 850 | 90 | 90 | 90 | 1.28291 | 0.0830767 | 8500 | 0 | 6.48558 | 9500 | 1000 | 8324 | -176 | 2234215 | -660173
Obj.-002 | Etage 2 | 90 | 90 | 4 | 7 | 354.213 | Etage 2 | 5 | 3880.5 | 250 | 1000 | 850 | 0 | 150 | 150 | 0.970125 | 0.0624083 | 8500 | 0 | 4.84724 | 9500 | 1000 | 8324 | -176 | 2226512 | -604878
Obj.-002 | Etage 2 | 135 | 135 | 3 | 7 | 270 | Etage 2 | 5 | 2926.48 | 250 | 1000 | 850 | 90 | 90 | 90 | 0.73162 | 0.0472163 | 8500 | 0 | 3.69462 | 9500 | 1000 | 8324 | -176 | 2230830 | -631869
Obj.-002 | Etage 2 | 90 | 135 | 2 | 7 | 0 | Etage 2 | 5 | 1176.91 | 250 | 1000 | 850 | 0 | 150 | 150 | 0.294228 | 0.018682 | 8500 | 0 | 1.48631 | 9500 | 1000 | 8324 | -176 | 2229653 | -628942
Obj.-002 | Etage 2 | 90 | 45 | 2 | 7 | 0 | Etage 2 | 5 | 1176.91 | 250 | 1000 | 850 | 0 | 150 | 150 | 0.294228 | 0.018682 | 8500 | 0 | 1.48631 | 9500 | 1000 | 8324 | -176 | 2229653 | -631869
Obj.-002 | Etage 2 | 45 | 90 | 2 | 7 | 0 | Etage 2 | 5 | 600.362 | 250 | 1000 | 850 | 0 | 150 | 150 | 0.150091 | 0.00958328 | 8500 | 0 | 0.827015 | 9500 | 1000 | 8324 | -176 | 2216034 | -607292
Obj.-002 | Etage 2 | 141.207 | 90 | 2 | 7 | 354.213 | Etage 2 | 5 | 2098.48 | 250 | 1000 | 850 | 0 | 150 | 150 | 0.524619 | 0.0332254 | 8500 | 0 | 2.54241 | 9500 | 1000 | 8324 | -176 | 2216034 | -603908 | ArchiCADProperties - Zones conflictuelles: balcon
Obj.-002 | Etage 2 | 45 | 45 | 4 | 7 | 270 | Etage 2 | 5 | 3384.39 | 250 | 1000 | 850 | 90 | 90 | 90 | 0.846097 | 0.0549728 | 8500 | 0 | 4.3555 | 9500 | 1000 | 8324 | -176 | 2216034 | -603908
Obj.-002 | Etage 2 | 90 | 90 | 3 | 7 | 270.046 | Etage 2 | 5 | 2000 | 250 | 1000 | 850 | 90 | 90 | 90 | 0.5 | 0.0325952 | 8500 | 0 | 2.62482 | 9500 | 1000 | 8324 | -176 | 2234229 | -639733
Obj.-002 | Etage 2 | 90 | 90 | 5 | 7 | 90 | Etage 2 | 5 | 5713.12 | 250 | 1000 | 850 | 90 | 90 | 90 | 1.42828 | 0.0922532 | 8500 | 0 | 7.14534 | 9500 | 1000 | 8324 | -176 | 2234227 | -646738
Obj.-002 | Etage 3 | 90 | 44.9938 | 2 | 7 | 0 | Etage 3 | 6 | 1374.97 | 250 | 1000 | 850 | 0 | 150 | 150 | 0.343743 | 0.0218076 | 11550 | 0 | 1.7128 | 12550 | 1000 | 11374 | -176 | 2218134 | -654916
Obj.-002 | Etage 3 | 90 | 90 | 3 | 7 | 270.046 | Etage 3 | 6 | 2000 | 250 | 1000 | 850 | 90 | 90 | 90 | 0.5 | 0.0325952 | 11550 | -1.77636e-12 | 2.62482 | 12550 | 1000 | 11374 | -176 | 2234233 | -652114
Obj.-002 | Etage 3 | 90 | 90 | 5 | 7 | 90 | Etage 3 | 6 | 5713.12 | 250 | 1000 | 850 | 90 | 90 | 90 | 1.42828 | 0.0922532 | 11550 | 0 | 7.14534 | 12550 | 1000 | 11374 | -176 | 2234227 | -646738
Obj.-002 | Etage 3 | 90 | 90 | 3 | 7 | 270.046 | Etage 3 | 6 | 2000 | 250 | 1000 | 850 | 90 | 90 | 90 | 0.5 | 0.0325952 | 11550 | 0 | 2.62482 | 12550 | 1000 | 11374 | -176 | 2218261 | -619854
Obj.-002 | Etage 3 | 90 | 45.0077 | 7 | 7 | 354.213 | Etage 3 | 6 | 8743.45 | 250 | 1000 | 850 | 0 | 150 | 150 | 2.18586 | 0.140742 | 11550 | 0 | 10.825 | 12550 | 1000 | 11374 | -176 | 2229668 | -621984 | ArchiCADProperties - Zones conflictuelles: balcon; balcon
Obj.-002 | Etage 3 | 135 | 90 | 2 | 7 | 180 | Etage 3 | 6 | 770.081 | 250 | 1000 | 850 | 0 | 150 | 150 | 0.19252 | 0.0122616 | 11550 | 0 | 1.02109 | 12550 | 1000 | 11374 | -176 | 2215864 | -644141
Obj.-002 | Etage 3 | 45 | 45 | 10 | 7 | 0 | Etage 3 | 6 | 14417.4 | 250 | 1000 | 850 | 90 | 90 | 90 | 3.60436 | 0.232269 | 11550 | 0 | 17.7955 | 12550 | 1000 | 11374 | -176 | 2232682 | -657693
Obj.-002 | Etage 3 | 90 | 90 | 3 | 7 | 270.046 | Etage 3 | 6 | 2000 | 250 | 1000 | 850 | 90 | 90 | 90 | 0.5 | 0.0325952 | 11550 | 0 | 2.62482 | 12550 | 1000 | 11374 | -176 | 2229530 | -625008
Obj.-002 | Etage 3 | 135.599 | 90 | 3 | 7 | 270 | Etage 3 | 6 | 2649.21 | 250 | 1000 | 850 | 0 | 150 | 150 | 0.662303 | 0.0424469 | 11550 | 0 | 3.30735 | 12550 | 1000 | 11374 | -176 | 2232682 | -657691
Obj.-002 | Etage 3 | 45.0002 | 44.9994 | 5 | 7 | 270 | Etage 3 | 6 | 5249.57 | 250 | 1000 | 850 | 90 | 90 | 90 | 1.31239 | 0.0849379 | 11550 | 0 | 6.62562 | 12550 | 1000 | 11374 | -176 | 2215864 | -644141
Obj.-002 | Etage 3 | 44.4009 | 90 | 3 | 7 | 270 | Etage 3 | 6 | 2649.21 | 250 | 1000 | 850 | 0 | 150 | 150 | 0.662303 | 0.0424469 | 11550 | 0 | 3.30735 | 12550 | 1000 | 11374 | -176 | 2218264 | -657691
Obj.-002 | Etage 3 | 90 | 135.051 | 2 | 7 | 84.1984 | Etage 3 | 6 | 1470 | 250 | 1000 | 850 | 0 | 150 | 150 | 0.3675 | 0.0233072 | 11550 | 0 | 1.82148 | 12550 | 1000 | 11374 | -176 | 2230348 | -606744 | ArchiCADProperties - Zones conflictuelles: Terrasse
Obj.-002 | Etage 3 | 134.949 | 134.994 | 7 | 7 | 354.198 | Etage 3 | 6 | 9607.94 | 250 | 1000 | 850 | 90 | 90 | 90 | 2.40198 | 0.154779 | 11550 | 0 | 11.884 | 12550 | 1000 | 11374 | -176 | 2230497 | -605282
Obj.-002 | Etage 3 | 90 | 137.894 | 2 | 7 | 89.9857 | Etage 3 | 6 | 1461.55 | 250 | 1000 | 850 | 0 | 150 | 150 | 0.365387 | 0.0231739 | 11550 | 0 | 1.81276 | 12550 | 1000 | 11374 | -176 | 2218262 | -605504 | ArchiCADProperties - Zones conflictuelles: Terrasse
Obj.-002 | Etage 3 | 90 | 45.0006 | 2 | 7 | 84.1984 | Etage 3 | 6 | 1470.19 | 250 | 1000 | 850 | 0 | 150 | 150 | 0.367548 | 0.0233103 | 11550 | 0 | 1.82168 | 12550 | 1000 | 11374 | -176 | 2239907 | -607716 | ArchiCADProperties - Zones conflictuelles: Terrasse
Obj.-002 | Etage 3 | 90 | 45 | 2 | 7 | 84.1984 | Etage 3 | 6 | 1464.45 | 250 | 1000 | 850 | 0 | 150 | 150 | 0.366113 | 0.0232197 | 11550 | 0 | 1.81512 | 12550 | 1000 | 11374 | -176 | 2226237 | -606324
Obj.-002 | Etage 3 | 135.683 | 133.702 | 7 | 7 | 89.9857 | Etage 3 | 6 | 10095.3 | 250 | 1000 | 850 | 90 | 90 | 90 | 2.52382 | 0.16247 | 11550 | 0 | 12.4411 | 12550 | 1000 | 11374 | -176 | 2216757 | -617382 | ArchiCADProperties - Zones conflictuelles: Terrasse
Obj.-002 | Etage 3 | 90 | 43.7021 | 2 | 7 | 179.986 | Etage 3 | 6 | 1377.7 | 250 | 1000 | 850 | 0 | 150 | 150 | 0.344426 | 0.0218507 | 11550 | 0 | 1.71633 | 12550 | 1000 | 11374 | -176 | 2218137 | -607287
Obj.-002 | Etage 3 | 90 | 134.317 | 2 | 7 | 179.986 | Etage 3 | 6 | 1377.58 | 250 | 1000 | 850 | 0 | 150 | 150 | 0.344395 | 0.0218488 | 11550 | 0 | 1.71557 | 12550 | 1000 | 11374 | -176 | 2218134 | -617383
Obj.-002 | Etage 3 | 137.894 | 135 | 6 | 7 | 354.198 | Etage 3 | 6 | 8163.98 | 250 | 1000 | 850 | 90 | 90 | 90 | 2.041 | 0.131461 | 11550 | 0 | 10.0965 | 12550 | 1000 | 11374 | -176 | 2218263 | -604042
Obj.-002 | Etage 3 | 135 | 90 | 2 | 7 | 0 | Etage 3 | 6 | 1368.01 | 250 | 1000 | 850 | 0 | 150 | 150 | 0.342003 | 0.0216978 | 11550 | 0 | 1.70484 | 12550 | 1000 | 11374 | -176 | 2231021 | -627825
Obj.-002 | Etage 3 | 135 | 135 | 5 | 7 | 270 | Etage 3 | 6 | 4986.48 | 250 | 1000 | 850 | 90 | 90 | 90 | 1.24662 | 0.080786 | 11550 | 0 | 6.32477 | 12550 | 1000 | 11374 | -176 | 2231021 | -632812
Obj.-002 | Etage 3 | 45.0005 | 42.1063 | 5 | 7 | 270 | Etage 3 | 6 | 5533.05 | 250 | 1000 | 850 | 90 | 90 | 90 | 1.38326 | 0.0894116 | 11550 | 0 | 6.95075 | 12550 | 1000 | 11374 | -176 | 2215834 | -626196
Obj.-002 | Etage 3 | 135.001 | 90 | 2 | 7 | 180 | Etage 3 | 6 | 799.998 | 250 | 1000 | 850 | 0 | 150 | 150 | 0.199999 | 0.0127338 | 11550 | 0 | 1.0553 | 12550 | 1000 | 11374 | -176 | 2215834 | -626196
Obj.-002 | Etage 3 | 42.1063 | 90 | 4 | 7 | 174.213 | Etage 3 | 6 | 2311.78 | 250 | 1000 | 850 | 0 | 150 | 150 | 0.577945 | 0.037652 | 11550 | 0 | 3.05952 | 12550 | 1000 | 11374 | -176 | 2215834 | -620663
Obj.-002 | Etage 3 | 90 | 134.988 | 2 | 7 | 0 | Etage 3 | 6 | 1374.97 | 250 | 1000 | 850 | 0 | 150 | 150 | 0.343743 | 0.0218076 | 11550 | 0 | 1.71279 | 12550 | 1000 | 11374 | -176 | 2218134 | -644141
Obj.-002 | Etage 3 | 45.0062 | 44.9877 | 10 | 7 | 270 | Etage 3 | 6 | 10775.1 | 250 | 1000 | 850 | 90 | 90 | 90 | 2.69377 | 0.174788 | 11550 | 0 | 13.6304 | 12550 | 1000 | 11374 | -176 | 2216759 | -654916 | ArchiCADProperties - Zones conflictuelles: balcon
Obj.-002 | Etage 3 | 45 | 90 | 2 | 7 | 0 | Etage 3 | 6 | 1368.01 | 250 | 1000 | 850 | 0 | 150 | 150 | 0.342003 | 0.0216978 | 11550 | 0 | 1.70484 | 12550 | 1000 | 11374 | -176 | 2231021 | -632812
Obj.-002 | Etage 3 | 45.0006 | 90 | 2 | 7 | 180 | Etage 3 | 6 | 770.083 | 250 | 1000 | 850 | 0 | 150 | 150 | 0.192521 | 0.0122617 | 11550 | 0 | 1.02109 | 12550 | 1000 | 11374 | -176 | 2215864 | -638892
Obj.-002 | Etage 3 | 45.0092 | 90 | 2 | 7 | 84.1973 | Etage 3 | 6 | 1595.66 | 250 | 1000 | 850 | 90 | 90 | 90 | 0.398916 | 0.0256841 | 11550 | 0 | 2.03038 | 12550 | 1000 | 11374 | -176 | 2238367 | -622865
Obj.-002 | Etage 3 | 90 | 90 | 3 | 7 | 270.046 | Etage 3 | 6 | 2319.26 | 250 | 1000 | 850 | 90 | 90 | 90 | 0.579815 | 0.0376336 | 11550 | 0 | 2.9899 | 12550 | 1000 | 11374 | -176 | 2234233 | -639733
Obj.-002 | etage 4 | 135 | 90 | 2 | 7 | 180 | etage 4 | 7 | 800 | 250 | 1000 | 850 | 0 | 150 | 150 | 0.2 | 0.0127338 | 14600 | 0 | 1.0553 | 15600 | 1000 | 14424 | -176 | 2215834 | -626196
Obj.-002 | etage 4 | 45 | 90 | 3 | 7 | 270 | etage 4 | 7 | 2503.79 | 250 | 1000 | 850 | 0 | 150 | 150 | 0.625946 | 0.0401519 | 14600 | 0 | 3.14087 | 15600 | 1000 | 14424 | -176 | 2218259 | -654916
Obj.-002 | etage 4 | 44.9995 | 42.1063 | 5 | 7 | 270 | etage 4 | 7 | 5533.05 | 250 | 1000 | 850 | 90 | 90 | 90 | 1.38326 | 0.0894116 | 14600 | 0 | 6.95075 | 15600 | 1000 | 14424 | -176 | 2215834 | -626196
Obj.-002 | etage 4 | 42.1063 | 90 | 3 | 7 | 174.213 | etage 4 | 7 | 2311.78 | 250 | 1000 | 850 | 0 | 150 | 150 | 0.577945 | 0.0371218 | 14600 | 0 | 2.92227 | 15600 | 1000 | 14424 | -176 | 2215834 | -620663
Obj.-002 | etage 4 | 90 | 90 | 3 | 7 | 89.9543 | etage 4 | 7 | 2000 | 250 | 1000 | 850 | 90 | 90 | 90 | 0.5 | 0.0325952 | 14600 | 0 | 2.62482 | 15600 | 1000 | 14424 | -176 | 2216758 | -634766
Obj.-002 | etage 4 | 45 | 44.9994 | 6 | 7 | 270 | etage 4 | 7 | 6877.87 | 250 | 1000 | 850 | 90 | 90 | 90 | 1.71947 | 0.111165 | 14600 | 0 | 8.62486 | 15600 | 1000 | 14424 | -176 | 2215864 | -645770
Obj.-002 | etage 4 | 135 | 90 | 3 | 7 | 0 | etage 4 | 7 | 4578.2 | 250 | 1000 | 850 | 0 | 150 | 150 | 1.14455 | 0.0728886 | 14600 | 0 | 5.51299 | 15600 | 1000 | 14424 | -176 | 2234232 | -636087
Obj.-002 | etage 4 | 45 | 45 | 10 | 7 | 0 | etage 4 | 7 | 15972.4 | 250 | 1000 | 850 | 90 | 90 | 90 | 3.99311 | 0.256809 | 14600 | 0 | 19.5737 | 15600 | 1000 | 14424 | -176 | 2234232 | -654916
Obj.-002 | etage 4 | 45 | 45 | 12 | 7 | 90 | etage 4 | 7 | 18829.4 | 250 | 1000 | 850 | 90 | 90 | 90 | 4.70736 | 0.302956 | 14600 | 0 | 23.1152 | 15600 | 1000 | 14424 | -176 | 2234232 | -636087
Obj.-002 | etage 4 | 45 | 90 | 2 | 7 | 0 | etage 4 | 7 | 1368.01 | 250 | 1000 | 850 | 0 | 150 | 150 | 0.342003 | 0.0216978 | 14600 | 0 | 1.70484 | 15600 | 1000 | 14424 | -176 | 2231021 | -630327
Obj.-002 | etage 4 | 135 | 90 | 2 | 7 | 0 | etage 4 | 7 | 1368.01 | 250 | 1000 | 850 | 0 | 150 | 150 | 0.342003 | 0.0216978 | 14600 | 0 | 1.70484 | 15600 | 1000 | 14424 | -176 | 2231021 | -625341
Obj.-002 | etage 4 | 135 | 137.082 | 13 | 7 | 354.197 | etage 4 | 7 | 21747.3 | 250 | 1000 | 850 | 90 | 90 | 90 | 5.43683 | 0.349535 | 15100 | 500 | 26.5898 | 16100 | 1500 | 14924 | 324 | 2239894 | -607840
Obj.-002 | etage 4 | 90 | 41.2524 | 9 | 7 | 270 | etage 4 | 7 | 15200.2 | 250 | 1000 | 850 | 90 | 90 | 90 | 3.80006 | 0.244093 | 15100 | 500 | 18.5495 | 16100 | 1500 | 14924 | 324 | 2218258 | -620842
Obj.-002 | etage 4 | 45.0002 | 135 | 4 | 7 | 354.197 | etage 4 | 7 | 8871.04 | 250 | 1000 | 850 | 90 | 90 | 90 | 2.21776 | 0.141559 | 15100 | 500 | 10.6296 | 16100 | 1500 | 14924 | 324 | 2238542 | -621143
Obj.-002 | etage 4 | 44.9996 | 45.0004 | 6 | 7 | 84.197 | etage 4 | 7 | 13371.8 | 250 | 1000 | 850 | 90 | 90 | 90 | 3.34295 | 0.213647 | 15100 | 500 | 16.0508 | 16100 | 1500 | 14924 | 324 | 2239894 | -607840
Obj.-002 | etage 4 | 135 | 90 | 2 | 7 | 84.197 | etage 4 | 7 | 1763.19 | 250 | 1000 | 850 | 90 | 90 | 90 | 0.440797 | 0.0283279 | 15100 | 500 | 2.22195 | 16100 | 1500 | 14924 | 324 | 2229717 | -620247
Obj.-002 | etage 4 | 45.0006 | 90 | 2 | 7 | 180 | etage 4 | 7 | 770.083 | 250 | 1000 | 850 | 0 | 150 | 150 | 0.192521 | 0.0122617 | 14600 | 0 | 1.02109 | 15600 | 1000 | 14424 | -176 | 2215864 | -638892
Obj.-002 | etage 4 | 135 | 90 | 2 | 7 | 180 | etage 4 | 7 | 2270 | 250 | 1000 | 850 | 0 | 150 | 150 | 0.5675 | 0.0359323 | 14600 | 0 | 2.73628 | 15600 | 1000 | 14424 | -176 | 2215864 | -645770
Obj.-002 | etage 4 | 135 | 135 | 5 | 7 | 270 | etage 4 | 7 | 4986.48 | 250 | 1000 | 850 | 90 | 90 | 90 | 1.24662 | 0.080786 | 14600 | 0 | 6.32477 | 15600 | 1000 | 14424 | -176 | 2231021 | -630327
Obj.-002 | etage 4 | 90 | 90 | 3 | 7 | 89.9543 | etage 4 | 7 | 2000 | 250 | 1000 | 850 | 90 | 90 | 90 | 0.5 | 0.0325952 | 14600 | 0 | 2.62482 | 15600 | 1000 | 14424 | -176 | 2296758 | -634766
Obj.-002 | etage 4 | 44.9995 | 42.1063 | 5 | 7 | 270 | etage 4 | 7 | 5533.05 | 250 | 1000 | 850 | 90 | 90 | 90 | 1.38326 | 0.0894116 | 14600 | 0 | 6.95075 | 15600 | 1000 | 14424 | -176 | 2295834 | -626196
Obj.-002 | etage 4 | 42.1063 | 90 | 3 | 7 | 174.213 | etage 4 | 7 | 2311.78 | 250 | 1000 | 850 | 0 | 150 | 150 | 0.577945 | 0.0371218 | 14600 | 0 | 2.92227 | 15600 | 1000 | 14424 | -176 | 2295834 | -620663
Obj.-002 | etage 4 | 135 | 90 | 2 | 7 | 180 | etage 4 | 7 | 800 | 250 | 1000 | 850 | 0 | 150 | 150 | 0.2 | 0.0127338 | 14600 | 0 | 1.0553 | 15600 | 1000 | 14424 | -176 | 2295834 | -626196
Obj.-002 | etage 4 | 135 | 90 | 2 | 7 | 180 | etage 4 | 7 | 2270 | 250 | 1000 | 850 | 0 | 150 | 150 | 0.5675 | 0.0359323 | 14600 | 0 | 2.73628 | 15600 | 1000 | 14424 | -176 | 2295864 | -645770
Obj.-002 | etage 4 | 45 | 44.9994 | 6 | 7 | 270 | etage 4 | 7 | 6877.87 | 250 | 1000 | 850 | 90 | 90 | 90 | 1.71947 | 0.111165 | 14600 | 0 | 8.62486 | 15600 | 1000 | 14424 | -176 | 2295864 | -645770
Obj.-002 | etage 4 | 135 | 137.082 | 13 | 7 | 354.197 | etage 4 | 7 | 21747.3 | 250 | 1000 | 850 | 90 | 90 | 90 | 5.43683 | 0.349535 | 15100 | 500 | 26.5898 | 16100 | 1500 | 14924 | 324 | 2319894 | -607840
Obj.-002 | etage 4 | 45.0006 | 90 | 2 | 7 | 180 | etage 4 | 7 | 770.083 | 250 | 1000 | 850 | 0 | 150 | 150 | 0.192521 | 0.0122617 | 14600 | 0 | 1.02109 | 15600 | 1000 | 14424 | -176 | 2295864 | -638892
Obj.-002 | etage 4 | 90 | 41.2524 | 9 | 7 | 270 | etage 4 | 7 | 15200.2 | 250 | 1000 | 850 | 90 | 90 | 90 | 3.80006 | 0.244093 | 15100 | 500 | 18.5495 | 16100 | 1500 | 14924 | 324 | 2298258 | -620842
Obj.-002 | etage 4 | 45 | 45 | 10 | 7 | 0 | etage 4 | 7 | 15972.4 | 250 | 1000 | 850 | 90 | 90 | 90 | 3.99311 | 0.256809 | 14600 | 0 | 19.5737 | 15600 | 1000 | 14424 | -176 | 2314232 | -654916
Obj.-002 | etage 4 | 45 | 90 | 3 | 7 | 270 | etage 4 | 7 | 2503.79 | 250 | 1000 | 850 | 0 | 150 | 150 | 0.625946 | 0.0401519 | 14600 | 0 | 3.14087 | 15600 | 1000 | 14424 | -176 | 2298259 | -654916
Obj.-002 | Etage 5 | 90 | 135 | 2 | 7 | 0 | Etage 5 | 8 | 1374.92 | 250 | 1000 | 850 | 90 | 90 | 90 | 0.343729 | 0.0222005 | 17650 | 0 | 1.77796 | 18650 | 1000 | 17474 | -176 | 2218134 | -626196
Obj.-002 | Etage 5 | 42.1063 | 50.7873 | 7 | 7 | 174.213 | Etage 5 | 8 | 11328.6 | 250 | 1000 | 850 | 0 | 150 | 150 | 2.83214 | 0.181539 | 17650 | 0 | 13.7858 | 18650 | 1000 | 17474 | -176 | 2218259 | -621004
Obj.-002 | Etage 5 | 45 | 45 | 9 | 7 | 270 | Etage 5 | 8 | 12695.6 | 250 | 1000 | 850 | 90 | 90 | 90 | 3.1739 | 0.204566 | 17650 | 0 | 15.6893 | 18650 | 1000 | 17474 | -176 | 2216759 | -638892
Obj.-002 | Etage 5 | 90 | 135 | 3 | 7 | 270 | Etage 5 | 8 | 2360.55 | 250 | 1000 | 850 | 0 | 150 | 150 | 0.590137 | 0.0378914 | 17650 | 0 | 2.97707 | 18650 | 1000 | 17474 | -176 | 2229528 | -624507
Obj.-002 | Etage 5 | 90 | 90 | 3 | 7 | 270 | Etage 5 | 8 | 1220 | 50 | 1000 | 850 | 90 | 90 | 90 | 0.061 | 0.00808587 | 17650 | 0 | 1.22488 | 18650 | 1000 | 17474 | -176 | 2227115 | -637233
Obj.-002 | Etage 5 | 90 | 42.1063 | 4 | 7 | 270 | Etage 5 | 8 | 3502.6 | 250 | 1000 | 850 | 90 | 90 | 90 | 0.875649 | 0.0568383 | 17650 | 0 | 4.48646 | 18650 | 1000 | 17474 | -176 | 2218259 | -624507
Obj.-002 | Etage 5 | 135 | 90 | 3 | 7 | 0 | Etage 5 | 8 | 2105.76 | 250 | 1000 | 850 | 90 | 90 | 90 | 0.526439 | 0.0342642 | 17650 | 0 | 2.75093 | 18650 | 1000 | 17474 | -176 | 2231759 | -637263
Obj.-002 | Etage 5 | 45 | 45 | 10 | 7 | 0 | Etage 5 | 8 | 13495 | 250 | 1000 | 850 | 90 | 90 | 90 | 3.37375 | 0.217712 | 17650 | 0 | 16.7407 | 18650 | 1000 | 17474 | -176 | 2231759 | -652288
Obj.-002 | Etage 5 | 45 | 90 | 3 | 7 | 270 | Etage 5 | 8 | 2365.98 | 250 | 1000 | 850 | 0 | 150 | 150 | 0.591495 | 0.0379771 | 17650 | 0 | 2.98328 | 18650 | 1000 | 17474 | -176 | 2218264 | -652288
Obj.-002 | Etage 5 | 90 | 45 | 2 | 7 | 0 | Etage 5 | 8 | 1374.92 | 250 | 1000 | 850 | 90 | 90 | 90 | 0.343729 | 0.0222005 | 17650 | 0 | 1.77796 | 18650 | 1000 | 17474 | -176 | 2218134 | -638892
Obj.-002 | Etage 5 | 135 | 135 | 10 | 7 | 270 | Etage 5 | 8 | 15024.3 | 250 | 1000 | 850 | 0 | 150 | 150 | 3.75608 | 0.241453 | 17650 | 0 | 18.4243 | 18650 | 1000 | 17474 | -176 | 2231759 | -652288
Obj.-002 | Etage 5 | 45 | 45 | 9 | 7 | 270 | Etage 5 | 8 | 12695.6 | 250 | 1000 | 850 | 90 | 90 | 90 | 3.1739 | 0.204566 | 17650 | 0 | 15.6893 | 18650 | 1000 | 17474 | -176 | 2296759 | -638892
Obj.-002 | Etage 5 | 90 | 135 | 2 | 7 | 0 | Etage 5 | 8 | 1374.92 | 250 | 1000 | 850 | 90 | 90 | 90 | 0.343729 | 0.0222005 | 17650 | 0 | 1.77796 | 18650 | 1000 | 17474 | -176 | 2298134 | -626196
Obj.-002 | Etage 5 | 42.1063 | 50.7873 | 7 | 7 | 174.213 | Etage 5 | 8 | 11328.6 | 250 | 1000 | 850 | 0 | 150 | 150 | 2.83214 | 0.181539 | 17650 | 0 | 13.7858 | 18650 | 1000 | 17474 | -176 | 2298259 | -621004
Obj.-002 | Etage 5 | 90 | 42.1063 | 4 | 7 | 270 | Etage 5 | 8 | 3502.6 | 250 | 1000 | 850 | 90 | 90 | 90 | 0.875649 | 0.0568383 | 17650 | 0 | 4.48646 | 18650 | 1000 | 17474 | -176 | 2298259 | -624507
Obj.-002 | Etage 5 | 90 | 45 | 2 | 7 | 0 | Etage 5 | 8 | 1374.92 | 250 | 1000 | 850 | 90 | 90 | 90 | 0.343729 | 0.0222005 | 17650 | 0 | 1.77796 | 18650 | 1000 | 17474 | -176 | 2298134 | -638892
Obj.-002 | Etage 5 | 45 | 90 | 3 | 7 | 270 | Etage 5 | 8 | 2365.98 | 250 | 1000 | 850 | 0 | 150 | 150 | 0.591495 | 0.0379771 | 17650 | 0 | 2.98328 | 18650 | 1000 | 17474 | -176 | 2298264 | -652288
Obj.-002 | Etage 5 | 45 | 45 | 10 | 7 | 0 | Etage 5 | 8 | 13495 | 250 | 1000 | 850 | 90 | 90 | 90 | 3.37375 | 0.217712 | 17650 | 0 | 16.7407 | 18650 | 1000 | 17474 | -176 | 2311759 | -652288
Obj.-002 | toiture | 135 | 135 | 8 | 7 | 0 | toiture | 9 | 11270.5 | 250 | 1000 | 850 | 0 | 150 | 150 | 2.81763 | 0.181153 | 20850 | 500 | 13.8572 | 21850 | 1500 | 20674 | 324 | 2309528 | -624632
Obj.-002 | toiture | 45 | 45 | 17 | 7 | 270 | toiture | 9 | 25184.5 | 250 | 1000 | 850 | 0 | 150 | 150 | 6.29613 | 0.405505 | 20850 | 500 | 31.0034 | 21850 | 1500 | 20674 | 324 | 2298258 | -649817
Obj.-002 | toiture | 45 | 45 | 8 | 7 | 0 | toiture | 9 | 11270.5 | 250 | 1000 | 850 | 0 | 150 | 150 | 2.81763 | 0.181153 | 20850 | 500 | 13.8572 | 21850 | 1500 | 20674 | 324 | 2309528 | -649817
Obj.-002 | toiture | 135 | 90 | 8 | 7 | 270 | toiture | 9 | 5268.58 | 250 | 1000 | 850 | 0 | 150 | 150 | 1.31715 | 0.0864348 | 20850 | 500 | 6.9887 | 21850 | 1500 | 20674 | 324 | 2229528 | -649817 | ArchiCADProperties - Zones conflictuelles: Terrasse/eng.
Obj.-002 | toiture | 45 | 45 | 8 | 7 | 0 | toiture | 9 | 11270.5 | 250 | 1000 | 850 | 0 | 150 | 150 | 2.81763 | 0.181153 | 20850 | 500 | 13.8572 | 21850 | 1500 | 20674 | 324 | 2229528 | -649817
Obj.-002 | toiture | 135 | 135 | 8 | 7 | 0 | toiture | 9 | 11270.5 | 250 | 1000 | 850 | 0 | 150 | 150 | 2.81763 | 0.181153 | 20850 | 500 | 13.8572 | 21850 | 1500 | 20674 | 324 | 2229528 | -624632
Obj.-002 | toiture | 45 | 135 | 6 | 7 | 270 | toiture | 9 | 16507.6 | 250 | 1000 | 850 | 0 | 150 | 150 | 4.1269 | 0.26274 | 20850 | 500 | 19.5714 | 21850 | 1500 | 20674 | 324 | 2229528 | -641140 | ArchiCADProperties - Zones conflictuelles: Terrasse/eng.
Obj.-002 | toiture | 45 | 45 | 17 | 7 | 270 | toiture | 9 | 25184.5 | 250 | 1000 | 850 | 0 | 150 | 150 | 6.29613 | 0.405505 | 20850 | 500 | 31.0034 | 21850 | 1500 | 20674 | 324 | 2218258 | -649817
Obj.-002 | toiture | 90 | 135 | 3 | 7 | 270 | toiture | 9 | 3610.23 | 250 | 1000 | 850 | 0 | 150 | 150 | 0.902559 | 0.057613 | 20850 | 500 | 4.40611 | 21850 | 1500 | 20674 | 324 | 2230683 | -644750 | ArchiCADProperties - Zones conflictuelles: Terrasse/eng.
Obj.-002 | toiture | 45.0718 | 135 | 2 | 7 | 5.08889e-14 | toiture | 9 | 1155 | 250 | 1000 | 850 | 0 | 150 | 150 | 0.28875 | 0.0183362 | 20850 | 500 | 1.46641 | 21850 | 1500 | 20674 | 324 | 2229528 | -641140

# IfcSlab: 100 % (2) 313493396 10, Dalle-038
In: Etage1
Type - PredefinedType: FLOOR
Classification: Dalle (Classification ARCHICAD); Material: 100 % (2) 313493396 10 mm
AC_Pset_RenovationAndPhasing - Renovation Status: Existing
ArchiCADProperties - Emplacement de plan de référence: Haut; ID de l'élément: Dalle-038; Lien et ID d'élément: Dalle-038; Calque: dalles; Matériau de construction / Composite / Profil / Hachure: 100 % (2) 313493396; Matériau de construction: 100 % (2) 313493396; Verrouillé: no; Nom d'étage d'implantation: Etage1; Numéro d'étage d'implantation: 4; Type d'élément: Dalle; Type de structure: Basique; ID de Parent: Dalle-038; Matériaux de construction (Tous): 100 % (2) 313493396; Surfaces (Toutes): Métal-Fer; Hachure de recouvrement: 100 %; Nombre de percements: 0; Surface supérieure: Métal-Fer; Surface latérale: Métal-Fer; Surface inférieure: Métal-Fer; Nom de Variante: Modèle principal; Nom de Jeu de Variantes: Modèle principal; Position: Non défini; Fonction structurelle: Non défini; Affichage sur filtre de rénovation: Tous les filtres appropriés; État de rénovation: Existant; État de Variante: Modèle principal; Jeu de Variantes: Modèle principal
ArchiCADQuantities - Altitude inférieure: 5490 mm; Superficie supérieure de la dalle (conditionnelle): 1.0787 m2; Superficie inférieure de la dalle (brute): 1.0787 m2; Superficie inférieure de la dalle (brute, sans trous): 1.0787 m2; Superficie des arêtes de dalle (brute): 0.0912959 m2; Superficie des arêtes de dalle (brute, sans trous): 0.0912959 m2; Superficie supérieure de la dalle (brute): 1.0787 m2; Superficie supérieure de la dalle (brute, sans trous): 1.0787 m2; Superficie des trous: 0 m2; Altitude supérieure: 5500 mm; Superficie: 1.0787 m2; Hauteur: 10 mm; Volume (net): 0.010787 m3; Altitude à Zéro du Projet: 5500 mm; Altitude de Référence Niveau 1: 5500 mm; Altitude de Référence Niveau 2: 5500 mm; Altitude à niveau de la mer: 5500 mm; Altitude à étage lié/étage d'implantation: -250 mm; Décalage étage d'implantation: -250 mm; Superficie en plan: 1.0787 m2; Épaisseur: 10 mm; Volume (conditionnel): 0.010787 m3; Volume (brut): 0.010787 m3; Périmètre Plan: 9129.59 mm; Périmètre trous Plan: 0 mm; Altitude supérieure à premier niveau de référence: 5500 mm; Altitude supérieure à étage d'implantation: -250 mm; Altitude supérieure à Zéro du projet: 5500 mm; Altitude supérieure à niveau de la mer: 5500 mm; Altitude supérieure à deuxième niveau de référence: 5500 mm; Altitude inférieure à premier niveau de référence: 5490 mm; Altitude inférieure à étage d'implantation: -260 mm; Altitude inférieure à Zéro du projet: 5490 mm; Altitude inférieure à niveau de la mer: 5490 mm; Altitude inférieure à deuxième niveau de référence: 5490 mm; Superficie supérieure (nette): 1.0787 m2; Superficie supérieure (conditionnelle): 1.0787 m2; Superficie de l'arête (nette): 0.0912959 m2; Superficie inférieure (nette): 1.0787 m2; Superficie inférieure (conditionnelle): 1.0787 m2; Superficie surface inférieure (Brute): 1.0787 m2; Superficie surface d'arête (Brute): 0.0912959 m2; Superficie surface supérieure (Brute): 1.0787 m2

# IfcSlab: 100 % (2) 313493396 40 (17)
Type - PredefinedType: FLOOR
Classification: Dalle (Classification ARCHICAD); Material: 100 % (2) 313493396 40 mm
ArchiCADProperties - Emplacement de plan de référence: Haut; Calque: dalles; Matériau de construction / Composite / Profil / Hachure: 100 % (2) 313493396; Matériau de construction: 100 % (2) 313493396; Verrouillé: no; Type d'élément: Dalle; Type de structure: Basique; Matériaux de construction (Tous): 100 % (2) 313493396; Hachure de recouvrement: Empty Fill; Nombre de percements: 0; Nom de Variante: Modèle principal; Nom de Jeu de Variantes: Modèle principal; Position: Non défini; Fonction structurelle: Non défini; Affichage sur filtre de rénovation: Tous les filtres appropriés; État de rénovation: Existant; État de Variante: Modèle principal; Jeu de Variantes: Modèle principal
AC_Pset_RenovationAndPhasing - Renovation Status: Existing
ArchiCADQuantities - Hauteur: 40 mm; Épaisseur: 40 mm
Name | In | ID de l'élément = Lien et ID d'élément = ID de Parent | Nom d'étage d'implantation | Numéro d'étage d'implantation | Surfaces (Toutes) = Surface supérieure = Surface latérale = Surface inférieure | Altitude inférieure (mm) = Altitude inférieure à premier niveau de référence (mm) = Altitude inférieure à Zéro du projet (mm) = Altitude inférieure à niveau de la mer (mm) = Altitude inférieure à deuxième niveau de référence (mm) | Superficie supérieure de la dalle (conditionnelle) (m2) = Superficie inférieure de la dalle (brute, sans trous) (m2) = Superficie supérieure de la dalle (brute, sans trous) (m2) = Superficie (m2) = Superficie en plan (m2) = Superficie supérieure (nette) (m2) = Superficie supérieure (conditionnelle) (m2) = Superficie inférieure (nette) (m2) = Superficie inférieure (conditionnelle) (m2) | Superficie inférieure de la dalle (brute) (m2) = Superficie supérieure de la dalle (brute) (m2) = Superficie surface inférieure (Brute) (m2) = Superficie surface supérieure (Brute) (m2) | Superficie des arêtes de dalle (brute) (m2) = Superficie surface d'arête (Brute) (m2) | Superficie des arêtes de dalle (brute, sans trous) (m2) | Superficie des trous (m2) | Altitude supérieure (mm) = Altitude à Zéro du Projet (mm) = Altitude de Référence Niveau 1 (mm) = Altitude de Référence Niveau 2 (mm) = Altitude à niveau de la mer (mm) = Altitude supérieure à premier niveau de référence (mm) = Altitude supérieure à Zéro du projet (mm) = Altitude supérieure à niveau de la mer (mm) = Altitude supérieure à deuxième niveau de référence (mm) | Volume (net) (m3) | Altitude à étage lié/étage d'implantation (mm) = Décalage étage d'implantation (mm) | Volume (conditionnel) (m3) | Volume (brut) (m3) | Périmètre Plan (mm) | Périmètre trous Plan (mm) | Altitude supérieure à étage d'implantation (mm) | Altitude inférieure à étage d'implantation (mm) | Superficie de l'arête (nette) (m2)
Dalle-064 | Etage 3 | Dalle-064 | Etage 3 | 6 | Peinture-03 | 11510 | 4.33029 | 4.33029 | 1.59894 | 1.59894 | 0 | 11550 | 0.173211 | 0 | 0.173211 | 0.173211 | 39973.5 | 0 | 0 | -40 | 1.59894
Dalle-063 | Etage 3 | Dalle-063 | Etage 3 | 6 | Peinture-03 | 11510 | 3.00632 | 3.00632 | 1.11081 | 1.11081 | 0 | 11550 | 0.120253 | 0 | 0.120253 | 0.120253 | 27770.2 | 0 | 0 | -40 | 1.11081
Dalle-060 | Etage 3 | Dalle-060 | Etage 3 | 6 | Peinture-03 | 11510 | 2.85593 | 2.85593 | 1.05621 | 1.05621 | 0 | 11550 | 0.114237 | 0 | 0.114237 | 0.114237 | 26405.3 | 0 | 0 | -40 | 1.05621
Dalle-062 | Etage 3 | Dalle-062 | Etage 3 | 6 | Peinture-03 | 11510 | 2.74979 | 2.74979 | 1.01741 | 1.01741 | 0 | 11550 | 0.109992 | 0 | 0.109992 | 0.109992 | 25435.4 | 0 | 0 | -40 | 1.01741
Dalle-061 | Etage 3 | Dalle-061 | Etage 3 | 6 | Peinture-03 | 11510 | 2.43267 | 2.43267 | 0.902369 | 0.902369 | 0 | 11550 | 0.0973068 | 0 | 0.0973068 | 0.0973068 | 22559.2 | 0 | 0 | -40 | 0.902369
Dalle-058 | etage 4 | Dalle-058 | etage 4 | 7 | Peinture-03 | 15660 | 15.9155 | 311.026 | 2.92901 | 5.78744 | 295.111 | 15700 | 0.636619 | 1100 | 0.636619 | 12.441 | 144686 | 71460.8 | 1100 | 1060 | 5.78744
Dalle-059 | etage 4 | Dalle-059 | etage 4 | 7 | Peinture-03 | 14560 | 9.94038 | 9.94038 | 3.3826 | 3.3826 | 0 | 14600 | 0.397615 | 0 | 0.397615 | 0.397615 | 84565.1 | 0 | 0 | -40 | 3.3826
2 x Dalle-055 | Etage 5 | Dalle-055 | Etage 5 | 8 | Peinture-03 | 17610 | 3.42882 | 3.42882 | 1.26445 | 1.26445 | 0 | 17650 | 0.137153 | 0 | 0.137153 | 0.137153 | 31611.2 | 0 | 0 | -40 | 1.26445
Dalle-053 | Etage 5 | Dalle-053 | Etage 5 | 8 | Métal-Nickel | 17910 | 10.5006 | 10.5006 | 1.94579 | 1.94579 | 0 | 17950 | 0.420023 | 300 | 0.420023 | 0.420023 | 48644.7 | 0 | 300 | 260 | 1.94579
2 x Dalle-057 | Etage 5 | Dalle-057 | Etage 5 | 8 | Peinture-03 | 17610 | 7.24484 | 7.24484 | 2.65209 | 2.65209 | 0 | 17650 | 0.289793 | 0 | 0.289793 | 0.289793 | 66302.1 | 0 | 0 | -40 | 2.65209
Dalle-054 | Etage 5 | Dalle-054 | Etage 5 | 8 | Peinture-03 | 17610 | 3.81405 | 3.81405 | 1.40453 | 1.40453 | 3.63238e-07 | 17650 | 0.152562 | 0 | 0.152562 | 0.152562 | 35113.2 | 0 | 9.17446e-07 | -40 | 1.40373
Dalle-054 | Etage 5 | Dalle-054 | Etage 5 | 8 | Peinture-03 | 17610 | 3.81405 | 3.81405 | 1.40453 | 1.40453 | 0 | 17650 | 0.152562 | 0 | 0.152562 | 0.152562 | 35113.2 | 0 | 0 | -40 | 1.40453
Dalle-053 | Etage 5 | Dalle-053 | Etage 5 | 8 | Métal-Nickel | 18460 | 3.49541 | 6.39701 | 0.429408 | 0.703008 | 2.9016 | 18500 | 0.139816 | 850 | 0.25588 | 0.25588 | 17575.2 | 6840 | 850 | 810 | 0.703008
2 x Dalle-052 | toiture | Dalle-052 | toiture | 9 | Peinture-03 | 21410 | 21.5407 | 168.411 | 4.49545 | 6.96671 | 146.871 | 21450 | 0.861627 | 1100 | 0.987378 | 6.73646 | 174168 | 61781.6 | 1100 | 1060 | 6.96671 | ArchiCADProperties - Zones conflictuelles: Terrasse/eng.

# IfcSlab: AS_EMPTY 272048125 200 (3)
Type - PredefinedType: FLOOR
Classification: Dalle (Classification ARCHICAD); Material: AS_EMPTY 272048125 200 mm
ArchiCADProperties - Emplacement de plan de référence: Haut; ID de l'élément: Dalle-050; Lien et ID d'élément: Dalle-050; Calque: ESQ dalles balcons; Matériau de construction / Composite / Profil / Hachure: AS_EMPTY 272048125; Matériau de construction: AS_EMPTY 272048125; Verrouillé: no; Type d'élément: Dalle; Type de structure: Basique; ID de Parent: Dalle-050; Matériaux de construction (Tous): AS_EMPTY 272048125; Surfaces (Toutes): Pierre-Calcaire Brillant; Peinture-01; Hachure de recouvrement: Dallage 50x50; Nombre de percements: 0; Surface supérieure: Pierre-Calcaire Brillant; Surface latérale: Peinture-01; Surface inférieure: Peinture-01; Nom de Variante: Modèle principal; Nom de Jeu de Variantes: Modèle principal; Position: Non défini; Fonction structurelle: Non défini; Affichage sur filtre de rénovation: Tous les filtres appropriés; État de rénovation: Existant; État de Variante: Modèle principal; Jeu de Variantes: Modèle principal
AC_Pset_RenovationAndPhasing - Renovation Status: Existing
ArchiCADQuantities - Superficie des trous: 0 m2; Hauteur: 200 mm; Altitude à étage lié/étage d'implantation: 0 mm; Décalage étage d'implantation: 0 mm; Épaisseur: 200 mm; Périmètre trous Plan: 0 mm; Altitude supérieure à étage d'implantation: 0 mm; Altitude inférieure à étage d'implantation: -200 mm
Name | In | Nom de zone liée | Numéro de zone liée | Nom d'étage d'implantation | Numéro d'étage d'implantation | Altitude inférieure (mm) = Altitude inférieure à premier niveau de référence (mm) = Altitude inférieure à Zéro du projet (mm) = Altitude inférieure à niveau de la mer (mm) = Altitude inférieure à deuxième niveau de référence (mm) | Superficie supérieure de la dalle (conditionnelle) (m2) = Superficie inférieure de la dalle (brute) (m2) = Superficie inférieure de la dalle (brute, sans trous) (m2) = Superficie supérieure de la dalle (brute) (m2) = Superficie supérieure de la dalle (brute, sans trous) (m2) = Superficie (m2) = Superficie en plan (m2) = Superficie supérieure (nette) (m2) = Superficie supérieure (conditionnelle) (m2) = Superficie inférieure (nette) (m2) = Superficie inférieure (conditionnelle) (m2) = Superficie surface inférieure (Brute) (m2) = Superficie surface supérieure (Brute) (m2) | Superficie des arêtes de dalle (brute) (m2) = Superficie des arêtes de dalle (brute, sans trous) (m2) = Superficie de l'arête (nette) (m2) = Superficie surface d'arête (Brute) (m2) | Altitude supérieure (mm) = Altitude à Zéro du Projet (mm) = Altitude de Référence Niveau 1 (mm) = Altitude de Référence Niveau 2 (mm) = Altitude à niveau de la mer (mm) = Altitude supérieure à premier niveau de référence (mm) = Altitude supérieure à Zéro du projet (mm) = Altitude supérieure à niveau de la mer (mm) = Altitude supérieure à deuxième niveau de référence (mm) | Volume (net) (m3) = Volume (conditionnel) (m3) = Volume (brut) (m3) | Périmètre Plan (mm)
Dalle-050 | Etage1 | balcon | A11 | Etage1 | 4 | 5550 | 7.49135 | 2.30635 | 5750 | 1.49827 | 11531.8
Dalle-050 | Etage1 |  |  | Etage1 | 4 | 5550 | 12.4217 | 3.15784 | 5750 | 2.48434 | 15789.2
Dalle-050 | Etage 2 | balcon | A21 | Etage 2 | 5 | 8300 | 7.49135 | 2.30635 | 8500 | 1.49827 | 11531.8

# IfcSlab: Isolant styromousse 288701002 15 (6)
Type - PredefinedType: ROOF
Classification: Toit (Classification ARCHICAD)
ArchiCADProperties - Corps de découpe: Ligne de référence vers le bas; Calque: 3D; Matériau de construction / Composite / Profil / Hachure: Isolant styromousse 288701002; Matériau de construction: Isolant styromousse 288701002; Verrouillé: no; Type d'élément: Toiture; Type de structure: Basique; Matériaux de construction (Tous): Isolant styromousse 288701002; Surfaces (Toutes): BETON65; Peinture-03; Fer; Surface latérale: Peinture-03; Nom de Variante: Modèle principal; Nom de Jeu de Variantes: Modèle principal; Position: Extérieur; Fonction structurelle: Élément non porteur; Affichage sur filtre de rénovation: Tous les filtres appropriés; État de rénovation: Existant; État de Variante: Modèle principal; Jeu de Variantes: Modèle principal
AC_Pset_RenovationAndPhasing - Renovation Status: Existing
ArchiCADQuantities - Longueur connexion dôme: 0 mm; Longueur de la connexion mur d’extrémité: 0 mm; Longueur rive: 0 mm; Superficie des trous: 0 m2; Longueur connexion creux: 0 mm; Nombre de trous: 0; Nombre d'Ouvertures de toit: 0; Superficie des ouvertures: 0 m2; Longueur rive de tête: 0 mm; Longueur faîtage: 0 mm; Longueur connexion mur latéral: 0 mm; Longueur noue: 0 mm; Épaisseur: 15.3209 mm; Hauteur: 15.3209 mm
Name | In | Material | Option de géométrie | Pente (deg) | Niveau du toit | ID de l'élément = Lien et ID d'élément = ID de Parent | Nom d'étage d'implantation | Numéro d'étage d'implantation | Hachure de recouvrement | Longueur d'avant-toit (mm) | Superficie inférieure du toit (brute) (m2) = Superficie supérieure du toit (brute) (m2) = Superficie inférieure du toit (nette) (m2) | Superficie des arêtes de toit (brute) (m2) | Longueur arêtier (mm) | Épaisseur verticales (mm) | Altitude à Zéro du Projet (mm) = Altitude de Référence Niveau 1 (mm) = Altitude de Référence Niveau 2 (mm) = Altitude à niveau de la mer (mm) | Altitude à étage lié/étage d'implantation (mm) = Décalage étage d'implantation (mm) | Altitude supérieure à premier niveau de référence (mm) = Altitude supérieure à Zéro du projet (mm) = Altitude supérieure à niveau de la mer (mm) = Altitude supérieure à deuxième niveau de référence (mm) | Altitude supérieure à étage d'implantation (mm) | Altitude inférieure à premier niveau de référence (mm) = Altitude inférieure à Zéro du projet (mm) = Altitude inférieure à niveau de la mer (mm) = Altitude inférieure à deuxième niveau de référence (mm) | Altitude inférieure à étage d'implantation (mm)
Toit-022 | rdc | Isolant styromousse 288701002 15.3209 mm | Panneau-simple | 30.508 | 1 | Toit-022 | rdc | 3 | Sans Trame | 0 | 0.699894 | 0.125546 | 0 | 17.7828 | 2008.29 | -991.711 | 4000 | 1000 | 2008.29 | -991.711
Toit-020 | Etage1 | Isolant styromousse 288701002 15.3209 mm | Panneau-simple | 2 | 1 | Toit-020 | Etage1 | 4 | Hachure toit/2 | 0 | 15.856 | 0.244902 | 0 | 15.3302 | 5552.5 | -197.504 | 5675.34 | -74.6599 | 5531.8 | -218.198
Toit-024 | Etage 2 | Isolant styromousse 288701002 | Pans multiples | 45 |  | Toit-024 | Etage 2 | 5 | Sans Trame | 42585.7 | 146.959 | 0.922704 | 32386 |  | 10068.9 | 1568.89 | 13097.3 | 4597.32 | 9268.89 | 768.886
Toit-023 | Etage 2 | Isolant styromousse 288701002 15.3209 mm | Panneau-simple | 60.7 | 1 | Toit-023 | Etage 2 | 5 | Sans Trame | 0 | 20.6975 | 0.608804 | 0 | 31.3066 | 8885.41 | 385.406 | 12840.3 | 4340.31 | 8885.41 | 385.406
Toit-023 | Etage 2 | Isolant styromousse 288701002 15.3209 mm | Panneau-simple | 40 | 1 | Toit-023 | Etage 2 | 5 | Sans Trame | 0 | 47.1192 | 0.506829 | 0 | 20 | 9150.95 | 650.947 | 12850.7 | 4350.72 | 8943.6 | 443.602
Toit-023 | Etage 2 | Isolant styromousse 288701002 15.3209 mm | Panneau-simple | 40 | 1 | Toit-023 | Etage 2 | 5 | Sans Trame | 0 | 45.1476 | 0.494941 | 0 | 20 | 9150.95 | 650.947 | 12824.6 | 4324.57 | 8922.34 | 422.34

# IfcSlab: Isolant styromousse 288701002 38, Toit-021
In: toiture
Type - PredefinedType: ROOF
Classification: Toit (Classification ARCHICAD); Material: Isolant styromousse 288701002 38.3022 mm
ArchiCADProperties - Option de géométrie: Panneau-simple; Pente: 29.2868 deg; Niveau du toit: 1; Corps de découpe: Ligne de référence vers le bas; ID de l'élément: Toit-021; Lien et ID d'élément: Toit-021; Calque: 3D; Matériau de construction / Composite / Profil / Hachure: Isolant styromousse 288701002; Matériau de construction: Isolant styromousse 288701002; Zones conflictuelles: Terrasse; Verrouillé: no; Nom d'étage d'implantation: toiture; Numéro d'étage d'implantation: 9; Type d'élément: Toiture; Type de structure: Basique; ID de Parent: Toit-021; Matériaux de construction (Tous): Isolant styromousse 288701002; Surfaces (Toutes): C02; Hachure de recouvrement: Sans Trame; Surface latérale: C02; Nom de Variante: Modèle principal; Nom de Jeu de Variantes: Modèle principal; Position: Extérieur; Fonction structurelle: Élément non porteur; Affichage sur filtre de rénovation: Tous les filtres appropriés; État de rénovation: Existant; État de Variante: Modèle principal; Jeu de Variantes: Modèle principal
AC_Pset_RenovationAndPhasing - Renovation Status: Existing
ArchiCADQuantities - Longueur connexion dôme: 0 mm; Longueur d'avant-toit: 0 mm; Longueur de la connexion mur d’extrémité: 0 mm; Longueur rive: 0 mm; Superficie inférieure du toit (brute): 1.49532 m2; Superficie des arêtes de toit (brute): 0.48015 m2; Superficie supérieure du toit (brute): 1.49532 m2; Longueur arêtier: 0 mm; Superficie des trous: 0 m2; Longueur connexion creux: 0 mm; Superficie inférieure du toit (nette): 1.49532 m2; Nombre de trous: 0; Nombre d'Ouvertures de toit: 0; Superficie des ouvertures: 0 m2; Longueur rive de tête: 0 mm; Longueur faîtage: 0 mm; Longueur connexion mur latéral: 0 mm; Longueur noue: 0 mm; Épaisseur: 38.3022 mm; Épaisseur verticales: 43.9154 mm; Hauteur: 38.3022 mm; Altitude à Zéro du Projet: 18880.2 mm; Altitude de Référence Niveau 1: 18880.2 mm; Altitude de Référence Niveau 2: 18880.2 mm; Altitude à niveau de la mer: 18880.2 mm; Altitude à étage lié/étage d'implantation: -1469.84 mm; Décalage étage d'implantation: -1469.84 mm; Altitude supérieure à premier niveau de référence: 21850 mm; Altitude supérieure à étage d'implantation: 1500 mm; Altitude supérieure à Zéro du projet: 21850 mm; Altitude supérieure à niveau de la mer: 21850 mm; Altitude supérieure à deuxième niveau de référence: 21850 mm; Altitude inférieure à premier niveau de référence: 18880.2 mm; Altitude inférieure à étage d'implantation: -1469.84 mm; Altitude inférieure à Zéro du projet: 18880.2 mm; Altitude inférieure à niveau de la mer: 18880.2 mm; Altitude inférieure à deuxième niveau de référence: 18880.2 mm

# IfcSlab: MANQUANT 200 (17)
Type - PredefinedType: FLOOR
Classification: Dalle (Classification ARCHICAD); Material: MANQUANT 200 mm
AC_Pset_RenovationAndPhasing - Renovation Status: Existing
ArchiCADQuantities - Superficie des trous: 0 m2; Hauteur: 200 mm; Épaisseur: 200 mm; Périmètre trous Plan: 0 mm; Altitude inférieure à étage d'implantation: -200 mm
ArchiCADProperties - Emplacement de plan de référence: Haut; ID de l'élément: Dalle-050; Lien et ID d'élément: Dalle-050; Matériau de construction / Composite / Profil / Hachure: MANQUANT; Matériau de construction: MANQUANT; Verrouillé: no; Type d'élément: Dalle; Type de structure: Basique; ID de Parent: Dalle-050; Matériaux de construction (Tous): MANQUANT; Surfaces (Toutes): Pierre-Calcaire Brillant; Peinture-01; Hachure de recouvrement: Dallage 50x50; Nombre de percements: 0; Surface supérieure: Pierre-Calcaire Brillant; Surface latérale: Peinture-01; Nom de Variante: Modèle principal; Nom de Jeu de Variantes: Modèle principal; Position: Non défini; Fonction structurelle: Non défini; Affichage sur filtre de rénovation: Tous les filtres appropriés; État de rénovation: Existant; État de Variante: Modèle principal; Jeu de Variantes: Modèle principal
Name | In | Altitude inférieure (mm) = Altitude inférieure à premier niveau de référence (mm) = Altitude inférieure à Zéro du projet (mm) = Altitude inférieure à niveau de la mer (mm) = Altitude inférieure à deuxième niveau de référence (mm) | Superficie supérieure de la dalle (conditionnelle) (m2) = Superficie inférieure de la dalle (brute) (m2) = Superficie inférieure de la dalle (brute, sans trous) (m2) = Superficie supérieure de la dalle (brute) (m2) = Superficie supérieure de la dalle (brute, sans trous) (m2) = Superficie (m2) = Superficie en plan (m2) = Superficie supérieure (nette) (m2) = Superficie supérieure (conditionnelle) (m2) = Superficie inférieure (nette) (m2) = Superficie inférieure (conditionnelle) (m2) = Superficie surface inférieure (Brute) (m2) = Superficie surface supérieure (Brute) (m2) | Superficie des arêtes de dalle (brute) (m2) = Superficie des arêtes de dalle (brute, sans trous) (m2) = Superficie de l'arête (nette) (m2) = Superficie surface d'arête (Brute) (m2) | Altitude supérieure (mm) = Altitude à Zéro du Projet (mm) = Altitude de Référence Niveau 1 (mm) = Altitude de Référence Niveau 2 (mm) = Altitude à niveau de la mer (mm) = Altitude supérieure à premier niveau de référence (mm) = Altitude supérieure à Zéro du projet (mm) = Altitude supérieure à niveau de la mer (mm) = Altitude supérieure à deuxième niveau de référence (mm) | Volume (net) (m3) = Volume (conditionnel) (m3) = Volume (brut) (m3) | Altitude à étage lié/étage d'implantation (mm) = Décalage étage d'implantation (mm) = Altitude supérieure à étage d'implantation (mm) | Périmètre Plan (mm) | Calque | Nom de zone liée | Numéro de zone liée | Nom d'étage d'implantation | Numéro d'étage d'implantation | Surface inférieure
Dalle-050 | Etage1 | 5550 | 8.8554 | 2.90525 | 5750 | 1.77108 | 0 | 14526.3 | ESQ dalles balcons | balcon | B16 | Etage1 | 4 | Peinture-01
Dalle-050 | Etage1 | 5550 | 15.2899 | 4.23836 | 5750 | 3.05798 | 0 | 21191.8 | ESQ dalles balcons | balcon | A13 | Etage1 | 4 | Peinture-01
Dalle-050 | Etage1 | 5550 | 6.65045 | 2.56405 | 5750 | 1.33009 | 0 | 12820.3 | ESQ dalles balcons | balcon | B11 | Etage1 | 4 | Peinture-01
Dalle-050 | Etage1 | 5550 | 18.1927 | 4.49614 | 5750 | 3.63854 | -4.44089e-12 | 22480.7 | ESQ dalles balcons | balcon | A12 | Etage1 | 4 | Peinture-01
Dalle-050 | Etage 2 | 8300 | 4.1355 | 1.79136 | 8500 | 0.8271 | -3.55271e-12 | 8956.79 | ESQ dalles balcons | balcon | B21 | Etage 2 | 5 | Peinture-01
Dalle-050 | Etage 2 | 8300 | 18.1927 | 4.49614 | 8500 | 3.63854 | -3.55271e-12 | 22480.7 | ESQ dalles balcons | balcon | A22 | Etage 2 | 5 | Peinture-01
Dalle-050 | Etage 2 | 8300 | 13.5415 | 3.8309 | 8500 | 2.70831 | 0 | 19154.5 | ESQ dalles balcons | balcon | A23 | Etage 2 | 5 | Peinture-01
Dalle-050 | Etage 2 | 8300 | 12.4217 | 3.15786 | 8500 | 2.48434 | -3.55271e-12 | 15789.3 | ESQ dalles balcons | balcon | B23 | Etage 2 | 5 | Peinture-01
Dalle-050 | Etage 2 | 8300 | 8.8554 | 2.90525 | 8500 | 1.77108 | 0 | 14526.3 | ESQ dalles balcons | balcon | B26 | Etage 2 | 5 | Peinture-01
Dalle-050 | Etage 3 | 11350 | 15.2905 | 4.2385 | 11550 | 3.0581 | 0 | 21192.5 | ESQ blacon grosse rampe | balcon | A32 | Etage 3 | 6 | Peinture-01
Dalle-050 | Etage 3 | 11350 | 12.4217 | 3.15786 | 11550 | 2.48434 | -3.55271e-12 | 15789.3 | ESQ dalles balcons | balcon | B33 | Etage 3 | 6 | Peinture-01
Dalle-050 | Etage 3 | 11350 | 13.3807 | 3.24169 | 11550 | 2.67614 | -3.55271e-12 | 16208.4 | ESQ blacon grosse rampe |  |  | Etage 3 | 6 | Peinture-01
Dalle-050 | Etage 3 | 11350 | 8.8554 | 2.90525 | 11550 | 1.77108 | 0 | 14526.3 | ESQ dalles balcons | balcon | B35 | Etage 3 | 6 | Peinture-01
Dalle-050 | Etage 3 | 11350 | 7.81813 | 2.6918 | 11550 | 1.56363 | 0 | 13459 | ESQ blacon grosse rampe | balcon | B31 | Etage 3 | 6 | Pierre-Calcaire Brillant
Dalle-050 | etage 4 | 14400 | 16.6965 | 3.80917 | 14600 | 3.33931 | -3.55271e-12 | 19045.8 | ESQ dalles balcons | Balcon | B43 | etage 4 | 7 | Peinture-01
Dalle-050 | etage 4 | 14400 | 7.81813 | 2.6918 | 14600 | 1.56363 | 0 | 13459 | ESQ dalles balcons | balcon | B41 | etage 4 | 7 | Pierre-Calcaire Brillant
Dalle-050 | etage 4 | 14400 | 13.3807 | 3.24169 | 14600 | 2.67614 | -3.55271e-12 | 16208.4 | ESQ blacon grosse rampe |  |  | etage 4 | 7 | Peinture-01

# IfcSlab: Parpaing 2676271321 200 (2)
In: sousol
Type - PredefinedType: FLOOR
Classification: Dalle (Classification ARCHICAD); Material: Parpaing 2676271321 200 mm
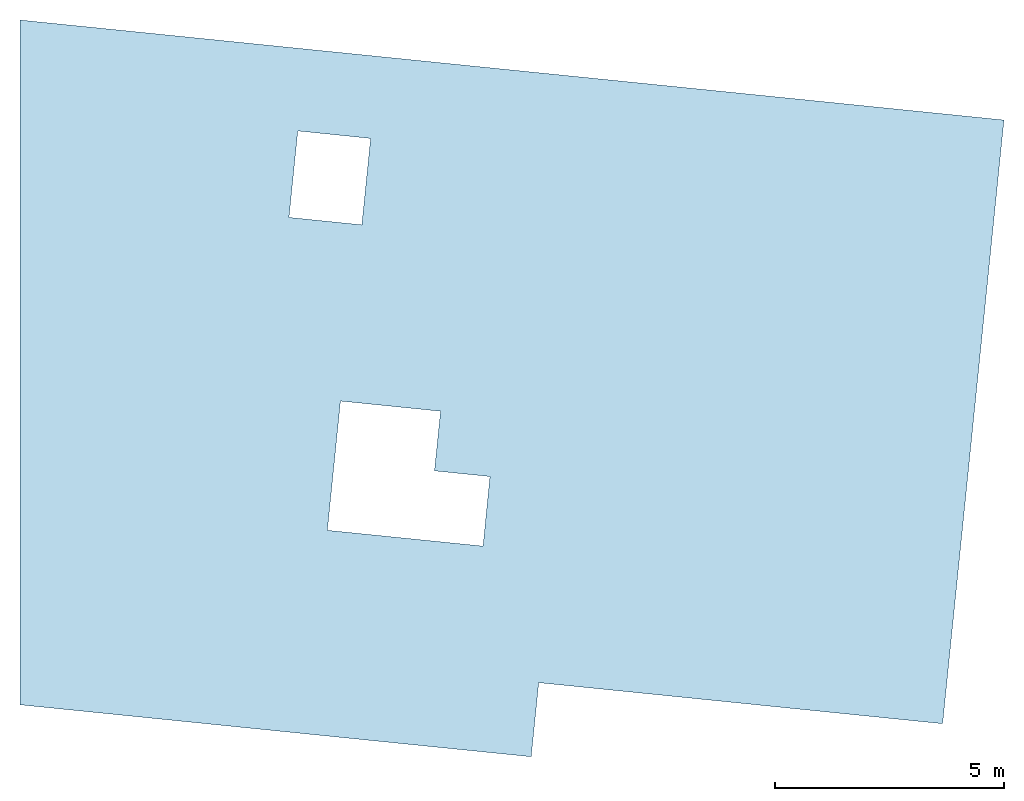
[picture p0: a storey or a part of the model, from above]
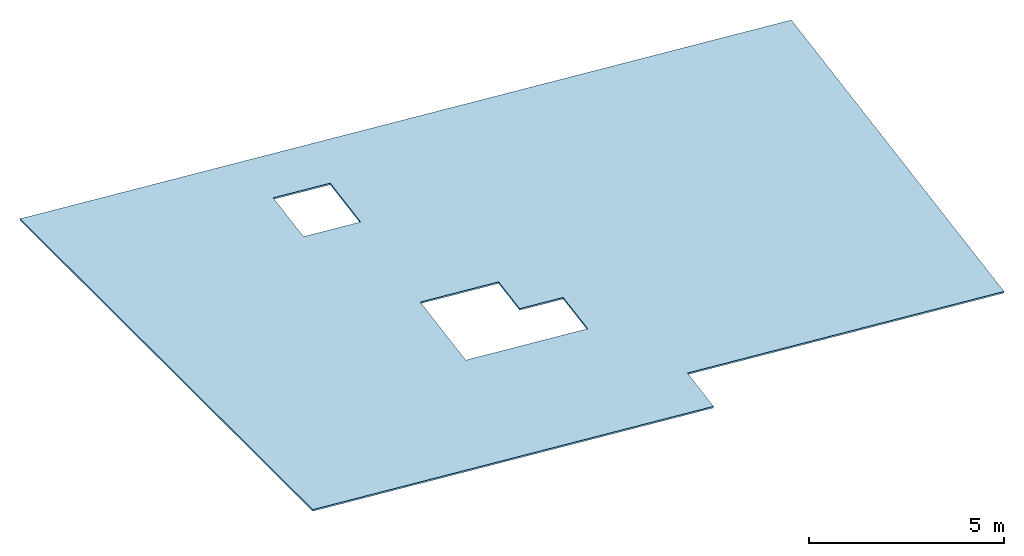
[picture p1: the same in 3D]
Properties of the parts of a building model (IFC2X3), part 18 of 44

# IfcSlab: Parpaing 2676271321 200 (2)
ArchiCADProperties - Emplacement de plan de référence: Haut; ID de l'élément: Dalle-051; Lien et ID d'élément: Dalle-051; Calque: dalles; Matériau de construction / Composite / Profil / Hachure: Parpaing 2676271321; Matériau de construction: Parpaing 2676271321; Verrouillé: no; Nom d'étage d'implantation: sousol; Numéro d'étage d'implantation: 2; Type d'élément: Dalle; Type de structure: Basique; ID de Parent: Dalle-051; Matériaux de construction (Tous): Parpaing 2676271321; Surfaces (Toutes): Métal-Nickel; Hachure de recouvrement: Empty Fill; Nombre de percements: 0; Surface supérieure: Métal-Nickel; Surface latérale: Métal-Nickel; Surface inférieure: Métal-Nickel; Nom de Variante: Modèle principal; Nom de Jeu de Variantes: Modèle principal; Position: Non défini; Fonction structurelle: Non défini; Affichage sur filtre de rénovation: Tous les filtres appropriés; État de rénovation: Existant; État de Variante: Modèle principal; Jeu de Variantes: Modèle principal
AC_Pset_RenovationAndPhasing - Renovation Status: Existing
ArchiCADQuantities - Hauteur: 200 mm; Épaisseur: 200 mm
Name | Altitude inférieure (mm) = Altitude inférieure à premier niveau de référence (mm) = Altitude inférieure à étage d'implantation (mm) = Altitude inférieure à Zéro du projet (mm) = Altitude inférieure à niveau de la mer (mm) = Altitude inférieure à deuxième niveau de référence (mm) | Superficie supérieure de la dalle (conditionnelle) (m2) = Superficie inférieure de la dalle (brute, sans trous) (m2) = Superficie supérieure de la dalle (brute, sans trous) (m2) = Superficie (m2) = Superficie en plan (m2) = Superficie supérieure (nette) (m2) = Superficie supérieure (conditionnelle) (m2) = Superficie inférieure (nette) (m2) = Superficie inférieure (conditionnelle) (m2) | Superficie inférieure de la dalle (brute) (m2) = Superficie supérieure de la dalle (brute) (m2) = Superficie surface inférieure (Brute) (m2) = Superficie surface supérieure (Brute) (m2) | Superficie des arêtes de dalle (brute) (m2) = Superficie surface d'arête (Brute) (m2) | Superficie des arêtes de dalle (brute, sans trous) (m2) = Superficie de l'arête (nette) (m2) | Superficie des trous (m2) | Altitude supérieure (mm) = Altitude à Zéro du Projet (mm) = Altitude de Référence Niveau 1 (mm) = Altitude de Référence Niveau 2 (mm) = Altitude à niveau de la mer (mm) = Altitude à étage lié/étage d'implantation (mm) = Décalage étage d'implantation (mm) = Altitude supérieure à premier niveau de référence (mm) = Altitude supérieure à étage d'implantation (mm) = Altitude supérieure à Zéro du projet (mm) = Altitude supérieure à niveau de la mer (mm) = Altitude supérieure à deuxième niveau de référence (mm) | Volume (net) (m3) | Volume (conditionnel) (m3) = Volume (brut) (m3) | Périmètre Plan (mm) | Périmètre trous Plan (mm)
Dalle-051 | -200 | 1353.16 | 1356.38 | 36.9646 | 38.4085 | 3.21556 | 0 | 270.633 | 271.276 | 192042 | 7219.45 | ArchiCADProperties - Nom de zone liée: Pl; Numéro de zone liée: 818
Dalle-051 | -1200 | 3.04 | 3.04 | 1.4 | 1.4 | 0 | -1000 | 0.608 | 0.608 | 7000 | 0

# IfcSlab: Parpaing 288701002 10, Dalle-035
In: toiture
Type - PredefinedType: FLOOR
Classification: Dalle (Classification ARCHICAD); Material: Parpaing 288701002 10 mm
ArchiCADProperties - Emplacement de plan de référence: Haut; ID de l'élément: Dalle-035; Lien et ID d'élément: Dalle-035; Calque: dalles; Matériau de construction / Composite / Profil / Hachure: Parpaing 288701002; Matériau de construction: Parpaing 288701002; Zones conflictuelles: Terrasse/eng.; Verrouillé: no; Nom d'étage d'implantation: toiture; Numéro d'étage d'implantation: 9; Type d'élément: Dalle; Type de structure: Basique; ID de Parent: Dalle-035; Matériaux de construction (Tous): Parpaing 288701002; Surfaces (Toutes): Bois-Chêne; Hachure de recouvrement: 100 %; Nombre de percements: 0; Surface supérieure: Bois-Chêne; Surface latérale: Bois-Chêne; Surface inférieure: Bois-Chêne; Nom de Variante: Modèle principal; Nom de Jeu de Variantes: Modèle principal; Position: Non défini; Fonction structurelle: Non défini; Affichage sur filtre de rénovation: Tous les filtres appropriés; État de rénovation: Existant; État de Variante: Modèle principal; Jeu de Variantes: Modèle principal
AC_Pset_RenovationAndPhasing - Renovation Status: Existing
ArchiCADQuantities - Altitude inférieure: 20770.4 mm; Superficie supérieure de la dalle (conditionnelle): 4.14054 m2; Superficie inférieure de la dalle (brute): 4.14054 m2; Superficie inférieure de la dalle (brute, sans trous): 4.14054 m2; Superficie des arêtes de dalle (brute): 0.0926387 m2; Superficie des arêtes de dalle (brute, sans trous): 0.0926387 m2; Superficie supérieure de la dalle (brute): 4.14054 m2; Superficie supérieure de la dalle (brute, sans trous): 4.14054 m2; Superficie des trous: 0 m2; Altitude supérieure: 20780.4 mm; Superficie: 4.14054 m2; Hauteur: 10 mm; Volume (net): 0.0414054 m3; Altitude à Zéro du Projet: 20780.4 mm; Altitude de Référence Niveau 1: 20780.4 mm; Altitude de Référence Niveau 2: 20780.4 mm; Altitude à niveau de la mer: 20780.4 mm; Altitude à étage lié/étage d'implantation: 430.42 mm; Décalage étage d'implantation: 430.42 mm; Superficie en plan: 4.14054 m2; Épaisseur: 10 mm; Volume (conditionnel): 0.0414054 m3; Volume (brut): 0.0414054 m3; Périmètre Plan: 9263.87 mm; Périmètre trous Plan: 0 mm; Altitude supérieure à premier niveau de référence: 20780.4 mm; Altitude supérieure à étage d'implantation: 430.42 mm; Altitude supérieure à Zéro du projet: 20780.4 mm; Altitude supérieure à niveau de la mer: 20780.4 mm; Altitude supérieure à deuxième niveau de référence: 20780.4 mm; Altitude inférieure à premier niveau de référence: 20770.4 mm; Altitude inférieure à étage d'implantation: 420.42 mm; Altitude inférieure à Zéro du projet: 20770.4 mm; Altitude inférieure à niveau de la mer: 20770.4 mm; Altitude inférieure à deuxième niveau de référence: 20770.4 mm; Superficie supérieure (nette): 4.14054 m2; Superficie supérieure (conditionnelle): 4.14054 m2; Superficie de l'arête (nette): 0.0926387 m2; Superficie inférieure (nette): 4.14054 m2; Superficie inférieure (conditionnelle): 4.14054 m2; Superficie surface inférieure (Brute): 4.14054 m2; Superficie surface d'arête (Brute): 0.0926387 m2; Superficie surface supérieure (Brute): 4.14054 m2

# IfcSlab: dalle 20 + faux plafond 30cm 500, Dalle-065
In: etage 4
Type - PredefinedType: FLOOR
Classification: Dalle (Classification ARCHICAD); Material: Parpaing 288701002 200 mm, Empty Fill 288701002 250 mm, 100 % 292236652 50 mm
ArchiCADProperties - Emplacement de plan de référence: Haut; ID de l'élément: Dalle-065; Lien et ID d'élément: Dalle-065; Calque: dalles; Matériau de construction / Composite / Profil / Hachure: dalle 20 + faux plafond 30cm; Structure Composite: dalle 20 + faux plafond 30cm; Verrouillé: no; Nom d'étage d'implantation: etage 4; Numéro d'étage d'implantation: 7; Type d'élément: Dalle; Type de structure: Composite; ID de Parent: Dalle-065; Matériaux de construction (Tous): Parpaing 288701002; Empty Fill 288701002; 100 % 292236652; Surfaces (Toutes): Métal-Nickel; Hachure de recouvrement: Empty Fill; Nombre de percements: 0; Surface supérieure: Métal-Nickel; Surface latérale: Métal-Nickel; Surface inférieure: Métal-Nickel; Nom de Variante: Modèle principal; Nom de Jeu de Variantes: Modèle principal; Position: Non défini; Fonction structurelle: Non défini; Affichage sur filtre de rénovation: Tous les filtres appropriés; État de rénovation: Existant; État de Variante: Modèle principal; Jeu de Variantes: Modèle principal
AC_Pset_RenovationAndPhasing - Renovation Status: Existing
ArchiCADQuantities - Altitude inférieure: 14220 mm; Superficie supérieure de la dalle (conditionnelle): 12.4344 m2; Superficie inférieure de la dalle (brute): 12.4344 m2; Superficie inférieure de la dalle (brute, sans trous): 12.4344 m2; Superficie des arêtes de dalle (brute): 10.1416 m2; Superficie des arêtes de dalle (brute, sans trous): 10.1416 m2; Superficie supérieure de la dalle (brute): 12.4344 m2; Superficie supérieure de la dalle (brute, sans trous): 12.4344 m2; Superficie des trous: 0 m2; Altitude supérieure: 14720 mm; Superficie: 12.4344 m2; Hauteur: 500 mm; Volume (net): 6.21718 m3; Altitude à Zéro du Projet: 14720 mm; Altitude de Référence Niveau 1: 14720 mm; Altitude de Référence Niveau 2: 14720 mm; Altitude à niveau de la mer: 14720 mm; Altitude à étage lié/étage d'implantation: 120 mm; Décalage étage d'implantation: 120 mm; Superficie en plan: 12.4344 m2; Épaisseur: 500 mm; Volume (conditionnel): 6.21718 m3; Volume (brut): 6.21718 m3; Périmètre Plan: 20283.1 mm; Périmètre trous Plan: 0 mm; Altitude supérieure à premier niveau de référence: 14720 mm; Altitude supérieure à étage d'implantation: 120 mm; Altitude supérieure à Zéro du projet: 14720 mm; Altitude supérieure à niveau de la mer: 14720 mm; Altitude supérieure à deuxième niveau de référence: 14720 mm; Altitude inférieure à premier niveau de référence: 14220 mm; Altitude inférieure à étage d'implantation: -380 mm; Altitude inférieure à Zéro du projet: 14220 mm; Altitude inférieure à niveau de la mer: 14220 mm; Altitude inférieure à deuxième niveau de référence: 14220 mm; Superficie supérieure (nette): 12.4344 m2; Superficie supérieure (conditionnelle): 12.4344 m2; Superficie de l'arête (nette): 10.1416 m2; Superficie inférieure (nette): 12.4344 m2; Superficie inférieure (conditionnelle): 12.4344 m2; Superficie surface inférieure (Brute): 12.4344 m2; Superficie surface d'arête (Brute): 10.1416 m2; Superficie surface supérieure (Brute): 12.4344 m2

# IfcSlab: dalle 20 +isol 17+ gazon 30 670 (5)
Type - PredefinedType: FLOOR
Classification: Dalle (Classification ARCHICAD); Material: Pierre 285292438 300 mm, Isolation laine de roche 288701167 170 mm, Parpaing 288701002 200 mm
AC_Pset_RenovationAndPhasing - Renovation Status: Existing
ArchiCADQuantities - Hauteur: 670 mm; Épaisseur: 670 mm
ArchiCADProperties - Emplacement de plan de référence: Haut; ID de l'élément: Dalle-030; Lien et ID d'élément: Dalle-030; Calque: dalles; Matériau de construction / Composite / Profil / Hachure: dalle 20 +isol 17+ gazon 30; Structure Composite: dalle 20 +isol 17+ gazon 30; Verrouillé: no; Type d'élément: Dalle; Type de structure: Composite; ID de Parent: Dalle-030; Matériaux de construction (Tous): Pierre 285292438; Isolation laine de roche 288701167; Parpaing 288701002; Hachure de recouvrement: Pierre; Nombre de percements: 0; Surface latérale: HAG Black Matt; Surface inférieure: Lavis blanc; Nom de Variante: Modèle principal; Nom de Jeu de Variantes: Modèle principal; Position: Non défini; Fonction structurelle: Non défini; Affichage sur filtre de rénovation: Tous les filtres appropriés; État de rénovation: Existant; État de Variante: Modèle principal; Jeu de Variantes: Modèle principal
Name | In | Altitude inférieure (mm) = Altitude inférieure à premier niveau de référence (mm) = Altitude inférieure à Zéro du projet (mm) = Altitude inférieure à niveau de la mer (mm) = Altitude inférieure à deuxième niveau de référence (mm) | Superficie supérieure de la dalle (conditionnelle) (m2) = Superficie supérieure (conditionnelle) (m2) = Superficie inférieure (conditionnelle) (m2) | Superficie inférieure de la dalle (brute) (m2) = Superficie supérieure de la dalle (brute) (m2) = Superficie surface inférieure (Brute) (m2) = Superficie surface supérieure (Brute) (m2) | Superficie inférieure de la dalle (brute, sans trous) (m2) = Superficie supérieure de la dalle (brute, sans trous) (m2) = Superficie (m2) = Superficie en plan (m2) = Superficie supérieure (nette) (m2) = Superficie inférieure (nette) (m2) | Superficie des arêtes de dalle (brute) (m2) = Superficie surface d'arête (Brute) (m2) | Superficie des arêtes de dalle (brute, sans trous) (m2) = Superficie de l'arête (nette) (m2) | Superficie des trous (m2) | Altitude supérieure (mm) = Altitude à Zéro du Projet (mm) = Altitude de Référence Niveau 1 (mm) = Altitude de Référence Niveau 2 (mm) = Altitude à niveau de la mer (mm) = Altitude supérieure à premier niveau de référence (mm) = Altitude supérieure à Zéro du projet (mm) = Altitude supérieure à niveau de la mer (mm) = Altitude supérieure à deuxième niveau de référence (mm) | Volume (net) (m3) | Altitude à étage lié/étage d'implantation (mm) = Décalage étage d'implantation (mm) = Altitude supérieure à étage d'implantation (mm) | Volume (conditionnel) (m3) | Volume (brut) (m3) | Périmètre Plan (mm) | Périmètre trous Plan (mm) | Altitude inférieure à étage d'implantation (mm) | Nom d'étage d'implantation | Numéro d'étage d'implantation | Surfaces (Toutes) | Surface supérieure
Dalle-030 | etage 4 | 14050 | 199.614 | 296.541 | 199.614 | 47.9861 | 83.591 | 96.9275 | 14720 | 133.741 | 120 | 133.741 | 198.682 | 124763 | 53141.5 | -550 | etage 4 | 7 | Divers-Feuillage persistant; HAG Black Matt; Lavis blanc | Divers-Feuillage persistant
2 x Dalle-030 | toiture | 20150 | 59.109 | 59.109 | 59.109 | 33.2824 | 33.2824 | 0 | 20820 | 39.603 | 470 | 39.603 | 39.603 | 49675.2 | 0 | -200 | toiture | 9 | Divers-Feuillage persistant; HAG Black Matt; Lavis blanc | Divers-Feuillage persistant | ArchiCADProperties - Zones conflictuelles: Terrasse/eng.
Dalle-030 | toiture | 20150 | 145.811 | 145.811 | 144.811 | 37.0479 | 39.7274 | 0.999687 | 20820 | 97.0236 | 470 | 97.6934 | 97.6934 | 59294.7 | 3999.37 | -200 | toiture | 9 | Pierre-Calcaire Brillant; HAG Black Matt; Lavis blanc | Pierre-Calcaire Brillant
Dalle-030 | toiture | 20150 | 144.619 | 144.619 | 143.619 | 36.7231 | 39.4026 | 0.999687 | 20820 | 96.2248 | 470 | 96.8946 | 96.8946 | 58809.9 | 3999.37 | -200 | toiture | 9 | Pierre-Calcaire Brillant; HAG Black Matt; Lavis blanc | Pierre-Calcaire Brillant

# IfcSlab: dalle 20 0025571715 200 (7)
Type - PredefinedType: FLOOR
Classification: Dalle (Classification ARCHICAD); Material: Parpaing 288701002 200 mm
ArchiCADProperties - Emplacement de plan de référence: Haut; Matériau de construction / Composite / Profil / Hachure: dalle 20 0025571715; Structure Composite: dalle 20 0025571715; Verrouillé: no; Type d'élément: Dalle; Type de structure: Composite; Matériaux de construction (Tous): Parpaing 288701002; Nombre de percements: 0; Nom de Variante: Modèle principal; Nom de Jeu de Variantes: Modèle principal; Position: Non défini; Fonction structurelle: Non défini; Affichage sur filtre de rénovation: Tous les filtres appropriés; État de rénovation: Existant; État de Variante: Modèle principal; Jeu de Variantes: Modèle principal
AC_Pset_RenovationAndPhasing - Renovation Status: Existing
ArchiCADQuantities - Superficie des trous: 0 m2; Hauteur: 200 mm; Épaisseur: 200 mm; Périmètre trous Plan: 0 mm; Altitude inférieure à étage d'implantation: -200 mm
Name | In | ID de l'élément = Lien et ID d'élément = ID de Parent | Calque | Nom de zone liée | Numéro de zone liée | Nom d'étage d'implantation | Numéro d'étage d'implantation | Surfaces (Toutes) | Hachure de recouvrement | Surface supérieure | Surface latérale | Surface inférieure | Altitude inférieure (mm) = Altitude inférieure à premier niveau de référence (mm) = Altitude inférieure à Zéro du projet (mm) = Altitude inférieure à niveau de la mer (mm) = Altitude inférieure à deuxième niveau de référence (mm) | Superficie supérieure de la dalle (conditionnelle) (m2) = Superficie inférieure de la dalle (brute) (m2) = Superficie inférieure de la dalle (brute, sans trous) (m2) = Superficie supérieure de la dalle (brute) (m2) = Superficie supérieure de la dalle (brute, sans trous) (m2) = Superficie (m2) = Superficie en plan (m2) = Superficie supérieure (nette) (m2) = Superficie supérieure (conditionnelle) (m2) = Superficie surface inférieure (Brute) (m2) = Superficie surface supérieure (Brute) (m2) | Superficie des arêtes de dalle (brute) (m2) = Superficie des arêtes de dalle (brute, sans trous) (m2) = Superficie surface d'arête (Brute) (m2) | Altitude supérieure (mm) = Altitude à Zéro du Projet (mm) = Altitude de Référence Niveau 1 (mm) = Altitude de Référence Niveau 2 (mm) = Altitude à niveau de la mer (mm) = Altitude supérieure à premier niveau de référence (mm) = Altitude supérieure à Zéro du projet (mm) = Altitude supérieure à niveau de la mer (mm) = Altitude supérieure à deuxième niveau de référence (mm) | Volume (net) (m3) = Volume (conditionnel) (m3) | Altitude à étage lié/étage d'implantation (mm) = Décalage étage d'implantation (mm) = Altitude supérieure à étage d'implantation (mm) | Volume (brut) (m3) | Périmètre Plan (mm) | Superficie de l'arête (nette) (m2) | Superficie inférieure (nette) (m2) = Superficie inférieure (conditionnelle) (m2)
Dalle-030 | rdc | Dalle-030 | dalles | Sdb | B03 | rdc | 3 | Menuiserie Plastique; Bois-Pin horizontal | Empty Fill | Bois-Pin horizontal | Menuiserie Plastique | Menuiserie Plastique | 2800 | 510.482 | 25.2568 | 3000 | 91.1287 | 0 | 102.096 | 126284 | 17.9787 | 437.364
Dalle-030 | rdc | Dalle-030 | dalles | Sdb | B03 | rdc | 3 | Menuiserie Plastique; Bois-Pin horizontal | Empty Fill | Bois-Pin horizontal | Menuiserie Plastique | Menuiserie Plastique | 2800 | 509.759 | 24.4529 | 3000 | 90.984 | 0 | 101.952 | 122265 | 17.1668 | 436.64
Dalle-050 | Etage1 | Dalle-050 | dalles |  |  | Etage1 | 4 | Pierre-Calcaire Brillant; Peinture-01 | Dallage 50x50 | Pierre-Calcaire Brillant | Peinture-01 | Peinture-01 | 5550 | 5.81995 | 2.15268 | 5750 | 1.16399 | 0 | 1.16399 | 10763.4 | 2.15268 | 5.81995
Dalle-050 | Etage1 | Dalle-050 | ESQ dalles balcons | balcon | B14 | Etage1 | 4 | Pierre-Calcaire Brillant; Peinture-01 | Dallage 50x50 | Pierre-Calcaire Brillant | Peinture-01 | Peinture-01 | 5550 | 57.6004 | 10.7547 | 5750 | 11.5201 | 0 | 11.5201 | 53773.5 | 10.7547 | 57.6004
Dalle-050 | Etage 2 | Dalle-050 | ESQ dalles balcons |  |  | Etage 2 | 5 | Pierre-Calcaire Brillant; Peinture-01 | Dallage 50x50 | Pierre-Calcaire Brillant | Peinture-01 | Peinture-01 | 8300 | 5.82421 | 2.15312 | 8500 | 1.16484 | -3.55271e-12 | 1.16484 | 10765.6 | 2.15312 | 5.82421
Dalle-050 | Etage 2 | Dalle-050 | ESQ dalles balcons | balcon | B24 | Etage 2 | 5 | Pierre-Calcaire Brillant; Peinture-01 | Dallage 50x50 | Pierre-Calcaire Brillant | Peinture-01 | Peinture-01 | 8300 | 52.6059 | 10.2956 | 8500 | 10.5212 | 0 | 10.5212 | 51478 | 10.2956 | 52.6059
Dalle-046 | Etage 5 | Dalle-046 | dalles | Cellier | B52 | Etage 5 | 8 | Pierre-Grès; HAG Black Matt; Lavis blanc | hachure bati | Pierre-Grès | HAG Black Matt | Lavis blanc | 17450 | 5.25747 | 2.41989 | 17650 | 1.05149 | 0 | 1.05149 | 12099.5 | 2.41989 | 5.25747

# IfcSlab: dalle 20 200, Dalle-036
In: rdc
Type - PredefinedType: FLOOR
Classification: Dalle (Classification ARCHICAD); Material: Parpaing 288701002 200 mm
ArchiCADProperties - Emplacement de plan de référence: Haut; ID de l'élément: Dalle-036; Lien et ID d'élément: Dalle-036; Calque: dalles; Matériau de construction / Composite / Profil / Hachure: dalle 20; Structure Composite: dalle 20; Verrouillé: no; Nom d'étage d'implantation: rdc; Numéro d'étage d'implantation: 3; Type d'élément: Dalle; Type de structure: Composite; ID de Parent: Dalle-036; Matériaux de construction (Tous): Parpaing 288701002; Surfaces (Toutes): Peinture-01; Hachure de recouvrement: 100 %; Nombre de percements: 0; Surface supérieure: Peinture-01; Surface latérale: Peinture-01; Surface inférieure: Peinture-01; Nom de Variante: Modèle principal; Nom de Jeu de Variantes: Modèle principal; Position: Non défini; Fonction structurelle: Non défini; Affichage sur filtre de rénovation: Tous les filtres appropriés; État de rénovation: Existant; État de Variante: Modèle principal; Jeu de Variantes: Modèle principal
AC_Pset_RenovationAndPhasing - Renovation Status: Existing
ArchiCADQuantities - Altitude inférieure: 3800 mm; Superficie supérieure de la dalle (conditionnelle): 5.55537 m2; Superficie inférieure de la dalle (brute): 5.55537 m2; Superficie inférieure de la dalle (brute, sans trous): 5.55537 m2; Superficie des arêtes de dalle (brute): 1.98366 m2; Superficie des arêtes de dalle (brute, sans trous): 1.98366 m2; Superficie supérieure de la dalle (brute): 5.55537 m2; Superficie supérieure de la dalle (brute, sans trous): 5.55537 m2; Superficie des trous: 0 m2; Altitude supérieure: 4000 mm; Superficie: 5.55537 m2; Hauteur: 200 mm; Volume (net): 1.11107 m3; Altitude à Zéro du Projet: 4000 mm; Altitude de Référence Niveau 1: 4000 mm; Altitude de Référence Niveau 2: 4000 mm; Altitude à niveau de la mer: 4000 mm; Altitude à étage lié/étage d'implantation: 1000 mm; Décalage étage d'implantation: 1000 mm; Superficie en plan: 5.55537 m2; Épaisseur: 200 mm; Volume (conditionnel): 1.11107 m3; Volume (brut): 1.11107 m3; Périmètre Plan: 9918.32 mm; Périmètre trous Plan: 0 mm; Altitude supérieure à premier niveau de référence: 4000 mm; Altitude supérieure à étage d'implantation: 1000 mm; Altitude supérieure à Zéro du projet: 4000 mm; Altitude supérieure à niveau de la mer: 4000 mm; Altitude supérieure à deuxième niveau de référence: 4000 mm; Altitude inférieure à premier niveau de référence: 3800 mm; Altitude inférieure à étage d'implantation: 800 mm; Altitude inférieure à Zéro du projet: 3800 mm; Altitude inférieure à niveau de la mer: 3800 mm; Altitude inférieure à deuxième niveau de référence: 3800 mm; Superficie supérieure (nette): 5.55537 m2; Superficie supérieure (conditionnelle): 5.55537 m2; Superficie de l'arête (nette): 1.98366 m2; Superficie inférieure (nette): 5.55537 m2; Superficie inférieure (conditionnelle): 5.55537 m2; Superficie surface inférieure (Brute): 5.55537 m2; Superficie surface d'arête (Brute): 1.98366 m2; Superficie surface supérieure (Brute): 5.55537 m2

# IfcSlab: dalle 20+ isolation 16 +plots15 550 (13)
Type - PredefinedType: FLOOR
Classification: Dalle (Classification ARCHICAD); Material: 100 % 288701002 40 mm, AS_EMPTY 288701002 150 mm, Isolation laine de roche 288701002 160 mm, Parpaing 288701002 200 mm
ArchiCADProperties - Emplacement de plan de référence: Haut; ID de l'élément: Dalle-050; Lien et ID d'élément: Dalle-050; Calque: dalles; Matériau de construction / Composite / Profil / Hachure: dalle 20+ isolation 16 +plots15; Structure Composite: dalle 20+ isolation 16 +plots15; Verrouillé: no; Type d'élément: Dalle; Type de structure: Composite; ID de Parent: Dalle-050; Matériaux de construction (Tous): 100 % 288701002; AS_EMPTY 288701002; Isolation laine de roche 288701002; Parpaing 288701002; Surfaces (Toutes): Pierre-Calcaire Brillant; Bois-Chêne; Hachure de recouvrement: Dallage 50 cm; Nombre de percements: 0; Surface supérieure: Bois-Chêne; Surface latérale: Pierre-Calcaire Brillant; Surface inférieure: Pierre-Calcaire Brillant; Nom de Variante: Modèle principal; Nom de Jeu de Variantes: Modèle principal; Position: Non défini; Fonction structurelle: Non défini; Affichage sur filtre de rénovation: Tous les filtres appropriés; État de rénovation: Existant; État de Variante: Modèle principal; Jeu de Variantes: Modèle principal
AC_Pset_RenovationAndPhasing - Renovation Status: Existing
ArchiCADQuantities - Superficie des trous: 0 m2; Hauteur: 550 mm; Altitude à étage lié/étage d'implantation: 0 mm; Décalage étage d'implantation: 0 mm; Épaisseur: 550 mm; Périmètre trous Plan: 0 mm; Altitude supérieure à étage d'implantation: 0 mm; Altitude inférieure à étage d'implantation: -550 mm
Name | In | Nom d'étage d'implantation | Numéro d'étage d'implantation | Altitude inférieure (mm) = Altitude inférieure à premier niveau de référence (mm) = Altitude inférieure à Zéro du projet (mm) = Altitude inférieure à niveau de la mer (mm) = Altitude inférieure à deuxième niveau de référence (mm) | Superficie supérieure de la dalle (conditionnelle) (m2) = Superficie inférieure de la dalle (brute) (m2) = Superficie inférieure de la dalle (brute, sans trous) (m2) = Superficie supérieure de la dalle (brute) (m2) = Superficie supérieure de la dalle (brute, sans trous) (m2) = Superficie (m2) = Superficie en plan (m2) = Superficie supérieure (nette) (m2) = Superficie supérieure (conditionnelle) (m2) = Superficie surface inférieure (Brute) (m2) = Superficie surface supérieure (Brute) (m2) | Superficie des arêtes de dalle (brute) (m2) = Superficie des arêtes de dalle (brute, sans trous) (m2) = Superficie surface d'arête (Brute) (m2) | Altitude supérieure (mm) = Altitude à Zéro du Projet (mm) = Altitude de Référence Niveau 1 (mm) = Altitude de Référence Niveau 2 (mm) = Altitude à niveau de la mer (mm) = Altitude supérieure à premier niveau de référence (mm) = Altitude supérieure à Zéro du projet (mm) = Altitude supérieure à niveau de la mer (mm) = Altitude supérieure à deuxième niveau de référence (mm) | Volume (net) (m3) = Volume (conditionnel) (m3) | Volume (brut) (m3) | Périmètre Plan (mm) | Superficie de l'arête (nette) (m2) | Superficie inférieure (nette) (m2) = Superficie inférieure (conditionnelle) (m2)
Dalle-050 | Etage 3 | Etage 3 | 6 | 11000 | 12.5369 | 11.8995 | 11550 | 6.89532 | 6.89532 | 21635.4 | 11.8995 | 12.5369 | ArchiCADProperties - Nom de zone liée: Terrasse; Numéro de zone liée: A34
Dalle-050 | Etage 3 | Etage 3 | 6 | 11000 | 10.5252 | 10.2269 | 11550 | 5.78888 | 5.78888 | 18594.4 | 10.2269 | 10.5252 | ArchiCADProperties - Nom de zone liée: Terrasse; Numéro de zone liée: A31
Dalle-050 | Etage 3 | Etage 3 | 6 | 11000 | 13.1875 | 12.4319 | 11550 | 7.25314 | 7.25314 | 22603.4 | 12.4319 | 13.1875
Dalle-050 | Etage 3 | Etage 3 | 6 | 11000 | 14.0779 | 13.1836 | 11550 | 7.74286 | 7.74286 | 23970.2 | 13.1836 | 14.0779 | ArchiCADProperties - Nom de zone liée: Terrasse; Numéro de zone liée: B34
Dalle-050 | Etage 3 | Etage 3 | 6 | 11000 | 36.8638 | 18.4716 | 11550 | 20.2751 | 20.2751 | 33584.8 | 18.4716 | 36.8638 | ArchiCADProperties - Nom de zone liée: Terrasse; Numéro de zone liée: B34
Dalle-050 | etage 4 | etage 4 | 7 | 14050 | 79.6085 | 40.3825 | 14600 | 43.5721 | 43.7847 | 73422.6 | 40.2025 | 79.1833 | ArchiCADProperties - Nom de zone liée: Terrasse; Numéro de zone liée: B44
Dalle-050 | etage 4 | etage 4 | 7 | 14050 | 80.671 | 40.3055 | 14600 | 44.3691 | 44.3691 | 73282.6 | 40.3055 | 80.671
Dalle-050 | Etage 5 | Etage 5 | 8 | 17100 | 32.1276 | 15.4737 | 17650 | 17.6702 | 17.6702 | 28134 | 15.4737 | 32.1276 | ArchiCADProperties - Nom de zone liée: Terrasse; Numéro de zone liée: B51
2 x Dalle-050 | Etage 5 | Etage 5 | 8 | 17100 | 54.6153 | 30.8433 | 17650 | 29.9559 | 30.0384 | 56078.7 | 30.7713 | 54.2029
2 x Dalle-050 | Etage 5 | Etage 5 | 8 | 17100 | 16.6125 | 15.2961 | 17650 | 9.13686 | 9.13686 | 27811.1 | 15.2961 | 16.6125
Dalle-050 | Etage 5 | Etage 5 | 8 | 17100 | 32.1276 | 15.4737 | 17650 | 17.6702 | 17.6702 | 28134 | 15.4737 | 32.1276

# IfcSlab: dalle 20+ isolation 16 360, Dalle-030
In: toiture
Type - PredefinedType: FLOOR
Classification: Dalle (Classification ARCHICAD); Material: Isolation laine de roche 288701002 160 mm, Parpaing 288701002 200 mm
AC_Pset_RenovationAndPhasing - Renovation Status: Existing
ArchiCADProperties - Emplacement de plan de référence: Haut; ID de l'élément: Dalle-030; Lien et ID d'élément: Dalle-030; Calque: dalles; Matériau de construction / Composite / Profil / Hachure: dalle 20+ isolation 16; Structure Composite: dalle 20+ isolation 16; Verrouillé: no; Nom d'étage d'implantation: toiture; Numéro d'étage d'implantation: 9; Type d'élément: Dalle; Type de structure: Composite; ID de Parent: Dalle-030; Matériaux de construction (Tous): Isolation laine de roche 288701002; Parpaing 288701002; Surfaces (Toutes): Pierre-Calcaire Brillant; HAG Black Matt; Lavis blanc; Hachure de recouvrement: Pierre; Nombre de percements: 0; Surface supérieure: Pierre-Calcaire Brillant; Surface latérale: HAG Black Matt; Surface inférieure: Lavis blanc; Nom de Variante: Modèle principal; Nom de Jeu de Variantes: Modèle principal; Position: Non défini; Fonction structurelle: Non défini; Affichage sur filtre de rénovation: Tous les filtres appropriés; État de rénovation: Existant; État de Variante: Modèle principal; Jeu de Variantes: Modèle principal
ArchiCADQuantities - Altitude inférieure: 21090 mm; Superficie supérieure de la dalle (conditionnelle): 3.89771 m2; Superficie inférieure de la dalle (brute): 3.89771 m2; Superficie inférieure de la dalle (brute, sans trous): 3.89771 m2; Superficie des arêtes de dalle (brute): 2.8582 m2; Superficie des arêtes de dalle (brute, sans trous): 2.8582 m2; Superficie supérieure de la dalle (brute): 3.89771 m2; Superficie supérieure de la dalle (brute, sans trous): 3.89771 m2; Superficie des trous: 0 m2; Altitude supérieure: 21450 mm; Superficie: 3.89771 m2; Hauteur: 360 mm; Volume (net): 1.40317 m3; Altitude à Zéro du Projet: 21450 mm; Altitude de Référence Niveau 1: 21450 mm; Altitude de Référence Niveau 2: 21450 mm; Altitude à niveau de la mer: 21450 mm; Altitude à étage lié/étage d'implantation: 1100 mm; Décalage étage d'implantation: 1100 mm; Superficie en plan: 3.89771 m2; Épaisseur: 360 mm; Volume (conditionnel): 1.40317 m3; Volume (brut): 1.40317 m3; Périmètre Plan: 7939.44 mm; Périmètre trous Plan: 0 mm; Altitude supérieure à premier niveau de référence: 21450 mm; Altitude supérieure à étage d'implantation: 1100 mm; Altitude supérieure à Zéro du projet: 21450 mm; Altitude supérieure à niveau de la mer: 21450 mm; Altitude supérieure à deuxième niveau de référence: 21450 mm; Altitude inférieure à premier niveau de référence: 21090 mm; Altitude inférieure à étage d'implantation: 740 mm; Altitude inférieure à Zéro du projet: 21090 mm; Altitude inférieure à niveau de la mer: 21090 mm; Altitude inférieure à deuxième niveau de référence: 21090 mm; Superficie supérieure (nette): 3.89771 m2; Superficie supérieure (conditionnelle): 3.89771 m2; Superficie de l'arête (nette): 2.8582 m2; Superficie inférieure (nette): 3.89771 m2; Superficie inférieure (conditionnelle): 3.89771 m2; Superficie surface inférieure (Brute): 3.89771 m2; Superficie surface d'arête (Brute): 2.8582 m2; Superficie surface supérieure (Brute): 3.89771 m2

# IfcSlab: dalle 20+ isolation 17 +plots30 670 (3)
Type - PredefinedType: FLOOR
Classification: Dalle (Classification ARCHICAD); Material: 100 % 288701002 40 mm, AS_EMPTY 288701002 260 mm, Isolation laine de roche 288701002 170 mm, Parpaing 288701002 200 mm
ArchiCADProperties - Emplacement de plan de référence: Haut; ID de l'élément: Dalle-050; Lien et ID d'élément: Dalle-050; Calque: dalles; Matériau de construction / Composite / Profil / Hachure: dalle 20+ isolation 17 +plots30; Structure Composite: dalle 20+ isolation 17 +plots30; Verrouillé: no; Type d'élément: Dalle; Type de structure: Composite; ID de Parent: Dalle-050; Matériaux de construction (Tous): 100 % 288701002; AS_EMPTY 288701002; Isolation laine de roche 288701002; Parpaing 288701002; Surfaces (Toutes): Pierre-Calcaire Brillant; Bois-Chêne; Hachure de recouvrement: Dallage 50 cm; Nombre de percements: 0; Surface supérieure: Bois-Chêne; Surface latérale: Pierre-Calcaire Brillant; Surface inférieure: Pierre-Calcaire Brillant; Nom de Variante: Modèle principal; Nom de Jeu de Variantes: Modèle principal; Position: Non défini; Fonction structurelle: Non défini; Affichage sur filtre de rénovation: Tous les filtres appropriés; État de rénovation: Existant; État de Variante: Modèle principal; Jeu de Variantes: Modèle principal
AC_Pset_RenovationAndPhasing - Renovation Status: Existing
ArchiCADQuantities - Superficie des trous: 0 m2; Hauteur: 670 mm; Épaisseur: 670 mm; Périmètre trous Plan: 0 mm
Name | In | Nom d'étage d'implantation | Numéro d'étage d'implantation | Altitude inférieure (mm) = Altitude inférieure à premier niveau de référence (mm) = Altitude inférieure à Zéro du projet (mm) = Altitude inférieure à niveau de la mer (mm) = Altitude inférieure à deuxième niveau de référence (mm) | Superficie supérieure de la dalle (conditionnelle) (m2) = Superficie inférieure de la dalle (brute) (m2) = Superficie inférieure de la dalle (brute, sans trous) (m2) = Superficie supérieure de la dalle (brute) (m2) = Superficie supérieure de la dalle (brute, sans trous) (m2) = Superficie (m2) = Superficie en plan (m2) = Superficie supérieure (nette) (m2) = Superficie supérieure (conditionnelle) (m2) = Superficie inférieure (nette) (m2) = Superficie inférieure (conditionnelle) (m2) = Superficie surface inférieure (Brute) (m2) = Superficie surface supérieure (Brute) (m2) | Superficie des arêtes de dalle (brute) (m2) = Superficie des arêtes de dalle (brute, sans trous) (m2) = Superficie de l'arête (nette) (m2) = Superficie surface d'arête (Brute) (m2) | Altitude supérieure (mm) = Altitude à Zéro du Projet (mm) = Altitude de Référence Niveau 1 (mm) = Altitude de Référence Niveau 2 (mm) = Altitude à niveau de la mer (mm) = Altitude supérieure à premier niveau de référence (mm) = Altitude supérieure à Zéro du projet (mm) = Altitude supérieure à niveau de la mer (mm) = Altitude supérieure à deuxième niveau de référence (mm) | Volume (net) (m3) = Volume (conditionnel) (m3) = Volume (brut) (m3) | Altitude à étage lié/étage d'implantation (mm) = Décalage étage d'implantation (mm) = Altitude supérieure à étage d'implantation (mm) | Périmètre Plan (mm) | Altitude inférieure à étage d'implantation (mm) | Zones conflictuelles
Dalle-050 | etage 4 | etage 4 | 7 | 14050 | 64.4041 | 34.8729 | 14720 | 43.1507 | 120 | 52049.2 | -550
Dalle-050 | toiture | toiture | 9 | 20150 | 67.7511 | 22.3821 | 20820 | 45.3932 | 470 | 33406.1 | -200 | Terrasse/eng.
Dalle-050 | toiture | toiture | 9 | 20110.4 | 67.7511 | 22.3821 | 20780.4 | 45.3932 | 430.42 | 33406.1 | -239.58 | cellier; Ch 1; Ch 2; Ch 3; Dgt; entree/pl; Sde 1; Sde 2; sde 3; Sejour Cuisine; Terrasse/eng.; Wc

# IfcSlab: dalle 20+plots 340 (10)
Type - PredefinedType: FLOOR
Classification: Dalle (Classification ARCHICAD); Material: 100 % 288701002 40 mm, AS_EMPTY 288701002 100 mm, Parpaing 288701002 200 mm
ArchiCADProperties - Emplacement de plan de référence: Haut; ID de l'élément: Dalle-050; Lien et ID d'élément: Dalle-050; Calque: dalles; Matériau de construction / Composite / Profil / Hachure: dalle 20+plots; Structure Composite: dalle 20+plots; Verrouillé: no; Type d'élément: Dalle; Type de structure: Composite; ID de Parent: Dalle-050; Matériaux de construction (Tous): 100 % 288701002; AS_EMPTY 288701002; Parpaing 288701002; Nombre de percements: 0; Nom de Variante: Modèle principal; Nom de Jeu de Variantes: Modèle principal; Position: Non défini; Fonction structurelle: Non défini; Affichage sur filtre de rénovation: Tous les filtres appropriés; État de rénovation: Existant; État de Variante: Modèle principal; Jeu de Variantes: Modèle principal
AC_Pset_RenovationAndPhasing - Renovation Status: Existing
ArchiCADQuantities - Hauteur: 340 mm; Épaisseur: 340 mm; Périmètre trous Plan: 0 mm
Name | In | Nom d'étage d'implantation | Numéro d'étage d'implantation | Surfaces (Toutes) | Hachure de recouvrement | Surface supérieure | Surface latérale = Surface inférieure | Altitude inférieure (mm) = Altitude inférieure à premier niveau de référence (mm) = Altitude inférieure à Zéro du projet (mm) = Altitude inférieure à niveau de la mer (mm) = Altitude inférieure à deuxième niveau de référence (mm) | Superficie supérieure de la dalle (conditionnelle) (m2) = Superficie (m2) = Superficie en plan (m2) = Superficie supérieure (nette) (m2) = Superficie supérieure (conditionnelle) (m2) | Superficie inférieure de la dalle (brute) (m2) = Superficie inférieure de la dalle (brute, sans trous) (m2) = Superficie supérieure de la dalle (brute) (m2) = Superficie supérieure de la dalle (brute, sans trous) (m2) = Superficie surface inférieure (Brute) (m2) = Superficie surface supérieure (Brute) (m2) | Superficie des arêtes de dalle (brute) (m2) = Superficie des arêtes de dalle (brute, sans trous) (m2) = Superficie surface d'arête (Brute) (m2) | Superficie des trous (m2) | Altitude supérieure (mm) = Altitude à Zéro du Projet (mm) = Altitude de Référence Niveau 1 (mm) = Altitude de Référence Niveau 2 (mm) = Altitude à niveau de la mer (mm) = Altitude supérieure à premier niveau de référence (mm) = Altitude supérieure à Zéro du projet (mm) = Altitude supérieure à niveau de la mer (mm) = Altitude supérieure à deuxième niveau de référence (mm) | Volume (net) (m3) = Volume (conditionnel) (m3) | Altitude à étage lié/étage d'implantation (mm) = Décalage étage d'implantation (mm) = Altitude supérieure à étage d'implantation (mm) | Volume (brut) (m3) | Périmètre Plan (mm) | Altitude inférieure à étage d'implantation (mm) | Superficie de l'arête (nette) (m2) | Superficie inférieure (nette) (m2) = Superficie inférieure (conditionnelle) (m2)
Dalle-050 | rdc | rdc | 3 | Pierre-Calcaire Brillant; Bois-Chêne | Dallage 50 cm | Bois-Chêne | Pierre-Calcaire Brillant | 2660 | 6.59955 | 6.59955 | 4.29734 | 0 | 3000 | 2.1655 | 0 | 2.24385 | 12639.2 | -340 | 2.81611 | 6.32939
Dalle-050 | rdc | rdc | 3 | Pierre-Calcaire Brillant; Bois-Chêne | Dallage 50 cm | Bois-Chêne | Pierre-Calcaire Brillant | 2660 | 61.5672 | 61.5672 | 17.6908 | 0 | 3000 | 20.2508 | -9.76996e-12 | 20.9328 | 52031.8 | -340 | 16.0981 | 59.2153 | ArchiCADProperties - Nom de zone liée: Terrasse; Numéro de zone liée: B03
Dalle-050 | rdc | rdc | 3 | Pierre-Calcaire Brillant; Bois-Chêne | Dallage 50 cm | Bois-Chêne | Pierre-Calcaire Brillant | 2660 | 6.96483 | 6.96483 | 4.48785 | 0 | 3000 | 2.13515 | 0 | 2.36804 | 13199.6 | -340 | 2.98587 | 6.16175 | ArchiCADProperties - Nom de zone liée: Terrasse; Numéro de zone liée: B01
Dalle-050 | rdc | rdc | 3 | Pierre-Calcaire Brillant | Dallage 50 cm | Pierre-Calcaire Brillant | Pierre-Calcaire Brillant | 2660 | 14.4576 | 14.4576 | 7.14465 | 0 | 3000 | 4.66941 | 0 | 4.91557 | 21013.7 | -340 | 4.60539 | 13.6087 | ArchiCADProperties - Nom de zone liée: Terrasse; Numéro de zone liée: A03
Dalle-050 | rdc | rdc | 3 | Pierre-Calcaire Brillant; Bois-Chêne | Dallage 50 cm | Bois-Chêne | Pierre-Calcaire Brillant | 2460 | 3.80331 | 4.03664 | 2.97939 | 0.233324 | 2800 | 1.29737 | -200 | 1.37246 | 8762.92 | -540 | 1.66325 | 3.85045 | ArchiCADProperties - Zones conflictuelles: Pl
Dalle-050 | rdc | rdc | 3 | Pierre-Calcaire Brillant; Bois-Chêne | Dallage 50 cm | Bois-Chêne | Pierre-Calcaire Brillant | 2660 | 4.03664 | 4.03664 | 2.97939 | 0 | 3000 | 1.30479 | 0 | 1.37246 | 8762.92 | -340 | 1.75749 | 3.80331 | ArchiCADProperties - Nom de zone liée: Terrasse; Numéro de zone liée: A01
Dalle-050 | rdc | rdc | 3 | Pierre-Calcaire Brillant | Dallage 50 cm | Pierre-Calcaire Brillant | Pierre-Calcaire Brillant | 2660 | 12.814 | 12.814 | 4.88443 | 0 | 3000 | 4.32371 | 0 | 4.35675 | 14366 | -340 | 3.99414 | 12.7
Dalle-050 | rdc | rdc | 3 | Pierre-Calcaire Brillant; Bois-Chêne | Dallage 50 cm | Bois-Chêne | Pierre-Calcaire Brillant | 2460 | 4.12259 | 4.31234 | 3.12144 | 0.189751 | 2800 | 1.40168 | -200 | 1.4662 | 9180.71 | -540 | 2.02579 | 4.12259
Dalle-050 | rdc | rdc | 3 | Pierre-Calcaire Brillant; Bois-Chêne | Dallage 50 cm | Bois-Chêne | Pierre-Calcaire Brillant | 2660 | 7.39856 | 7.39856 | 4.76553 | 0 | 3000 | 2.33699 | 0 | 2.51551 | 14016.3 | -340 | 3.04623 | 6.78297 | ArchiCADProperties - Nom de zone liée: Terrasse; Numéro de zone liée: B05
Dalle-050 | Etage1 | Etage1 | 4 | Peinture-01 | Cloison | Peinture-01 | Peinture-01 | 5210 | 26.4312 | 26.4312 | 6.99856 | 0 | 5550 | 8.9866 | -200 | 8.9866 | 20584 | -540 | 6.99856 | 26.4312

# IfcSlab: dalle 23+ chape5+ isolant sousface15 430 (2)
In: rdc
Type - PredefinedType: FLOOR
Classification: Dalle (Classification ARCHICAD); Material: Brique 1 268964100 50 mm, Parpaing 288701002 230 mm, Isolation toiture terrasse 288701002 150 mm
AC_Pset_RenovationAndPhasing - Renovation Status: Existing
ArchiCADQuantities - Altitude inférieure: 2570 mm; Altitude supérieure: 3000 mm; Hauteur: 430 mm; Altitude à Zéro du Projet: 3000 mm; Altitude de Référence Niveau 1: 3000 mm; Altitude de Référence Niveau 2: 3000 mm; Altitude à niveau de la mer: 3000 mm; Altitude à étage lié/étage d'implantation: 0 mm; Décalage étage d'implantation: 0 mm; Épaisseur: 430 mm; Périmètre trous Plan: 0 mm; Altitude supérieure à premier niveau de référence: 3000 mm; Altitude supérieure à étage d'implantation: 0 mm; Altitude supérieure à Zéro du projet: 3000 mm; Altitude supérieure à niveau de la mer: 3000 mm; Altitude supérieure à deuxième niveau de référence: 3000 mm; Altitude inférieure à premier niveau de référence: 2570 mm; Altitude inférieure à étage d'implantation: -430 mm; Altitude inférieure à Zéro du projet: 2570 mm; Altitude inférieure à niveau de la mer: 2570 mm; Altitude inférieure à deuxième niveau de référence: 2570 mm
ArchiCADProperties - Emplacement de plan de référence: Haut; ID de l'élément: Dalle-030; Lien et ID d'élément: Dalle-030; Calque: dalles; Matériau de construction / Composite / Profil / Hachure: dalle 23+ chape5+ isolant sousface15; Structure Composite: dalle 23+ chape5+ isolant sousface15; Verrouillé: no; Nom d'étage d'implantation: rdc; Numéro d'étage d'implantation: 3; Type d'élément: Dalle; Type de structure: Composite; ID de Parent: Dalle-030; Matériaux de construction (Tous): Brique 1 268964100; Parpaing 288701002; Isolation toiture terrasse 288701002; Surfaces (Toutes): Menuiserie Plastique; Bois-Pin horizontal; Hachure de recouvrement: Empty Fill; Nombre de percements: 0; Surface supérieure: Bois-Pin horizontal; Surface latérale: Menuiserie Plastique; Surface inférieure: Menuiserie Plastique; Nom de Variante: Modèle principal; Nom de Jeu de Variantes: Modèle principal; Position: Non défini; Fonction structurelle: Non défini; Affichage sur filtre de rénovation: Tous les filtres appropriés; État de rénovation: Existant; État de Variante: Modèle principal; Jeu de Variantes: Modèle principal
Name | Superficie supérieure de la dalle (conditionnelle) (m2) = Superficie inférieure de la dalle (brute) (m2) = Superficie inférieure de la dalle (brute, sans trous) (m2) = Superficie supérieure de la dalle (brute) (m2) = Superficie supérieure de la dalle (brute, sans trous) (m2) = Superficie (m2) = Superficie en plan (m2) = Superficie supérieure (nette) (m2) = Superficie supérieure (conditionnelle) (m2) = Superficie surface inférieure (Brute) (m2) = Superficie surface supérieure (Brute) (m2) | Superficie des arêtes de dalle (brute) (m2) = Superficie des arêtes de dalle (brute, sans trous) (m2) = Superficie surface d'arête (Brute) (m2) | Superficie des trous (m2) | Volume (net) (m3) = Volume (conditionnel) (m3) | Volume (brut) (m3) | Périmètre Plan (mm) | Superficie de l'arête (nette) (m2) | Superficie inférieure (nette) (m2) = Superficie inférieure (conditionnelle) (m2) | Nom de zone liée | Numéro de zone liée
Dalle-030 | 520.793 | 50.2031 | 0.000158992 | 195.4 | 223.941 | 116751 | 31.6627 | 446.375 | Sdb | B03
Dalle-030 | 327.046 | 39.2952 | 0 | 130.661 | 140.63 | 91384.3 | 29.6941 | 301.576 | Cellier | A02

# IfcSlab: dalle 23+ isolant sousface10 0817885410 330, Dalle-030
In: Etage1
Type - PredefinedType: FLOOR
Classification: Dalle (Classification ARCHICAD); Material: Parpaing 288701002 230 mm, Isolation toiture terrasse 288701002 100 mm
ArchiCADProperties - Emplacement de plan de référence: Haut; ID de l'élément: Dalle-030; Lien et ID d'élément: Dalle-030; Calque: dalles; Matériau de construction / Composite / Profil / Hachure: dalle 23+ isolant sousface10 0817885410; Structure Composite: dalle 23+ isolant sousface10 0817885410; Verrouillé: no; Nom d'étage d'implantation: Etage1; Numéro d'étage d'implantation: 4; Type d'élément: Dalle; Type de structure: Composite; ID de Parent: Dalle-030; Matériaux de construction (Tous): Parpaing 288701002; Isolation toiture terrasse 288701002; Surfaces (Toutes): BETON65; Hachure de recouvrement: Pierre coupé; Nombre de percements: 0; Surface supérieure: BETON65; Surface latérale: BETON65; Surface inférieure: BETON65; Nom de Variante: Modèle principal; Nom de Jeu de Variantes: Modèle principal; Position: Non défini; Fonction structurelle: Non défini; Affichage sur filtre de rénovation: Tous les filtres appropriés; État de rénovation: Existant; État de Variante: Modèle principal; Jeu de Variantes: Modèle principal
ArchiCADQuantities - Altitude inférieure: 5333.6 mm; Superficie supérieure de la dalle (conditionnelle): 6.25042 m2; Superficie inférieure de la dalle (brute): 6.25042 m2; Superficie inférieure de la dalle (brute, sans trous): 6.25042 m2; Superficie des arêtes de dalle (brute): 3.45799 m2; Superficie des arêtes de dalle (brute, sans trous): 3.45799 m2; Superficie supérieure de la dalle (brute): 6.25042 m2; Superficie supérieure de la dalle (brute, sans trous): 6.25042 m2; Superficie des trous: 0 m2; Altitude supérieure: 5663.6 mm; Superficie: 6.25042 m2; Hauteur: 330 mm; Volume (net): 2.06264 m3; Altitude à Zéro du Projet: 5663.6 mm; Altitude de Référence Niveau 1: 5663.6 mm; Altitude de Référence Niveau 2: 5663.6 mm; Altitude à niveau de la mer: 5663.6 mm; Altitude à étage lié/étage d'implantation: -86.404 mm; Décalage étage d'implantation: -86.404 mm; Superficie en plan: 6.25042 m2; Épaisseur: 330 mm; Volume (conditionnel): 2.06264 m3; Volume (brut): 2.06264 m3; Périmètre Plan: 10478.8 mm; Périmètre trous Plan: 0 mm; Altitude supérieure à premier niveau de référence: 5663.6 mm; Altitude supérieure à étage d'implantation: -86.404 mm; Altitude supérieure à Zéro du projet: 5663.6 mm; Altitude supérieure à niveau de la mer: 5663.6 mm; Altitude supérieure à deuxième niveau de référence: 5663.6 mm; Altitude inférieure à premier niveau de référence: 5333.6 mm; Altitude inférieure à étage d'implantation: -416.404 mm; Altitude inférieure à Zéro du projet: 5333.6 mm; Altitude inférieure à niveau de la mer: 5333.6 mm; Altitude inférieure à deuxième niveau de référence: 5333.6 mm; Superficie supérieure (nette): 6.25042 m2; Superficie supérieure (conditionnelle): 6.25042 m2; Superficie de l'arête (nette): 3.45799 m2; Superficie inférieure (nette): 6.25042 m2; Superficie inférieure (conditionnelle): 6.25042 m2; Superficie surface inférieure (Brute): 6.25042 m2; Superficie surface d'arête (Brute): 3.45799 m2; Superficie surface supérieure (Brute): 6.25042 m2
AC_Pset_RenovationAndPhasing - Renovation Status: Existing

# IfcSlab: dalle 24 + gazon 30 0025571715 540 (5)
Type - PredefinedType: FLOOR
Classification: Dalle (Classification ARCHICAD); Material: Pierre 285292438 300 mm, Parpaing 288701002 240 mm
ArchiCADProperties - Emplacement de plan de référence: Haut; Calque: dalles; Matériau de construction / Composite / Profil / Hachure: dalle 24 + gazon 30 0025571715; Structure Composite: dalle 24 + gazon 30 0025571715; Verrouillé: no; Type d'élément: Dalle; Type de structure: Composite; Matériaux de construction (Tous): Pierre 285292438; Parpaing 288701002; Nombre de percements: 0; Nom de Variante: Modèle principal; Nom de Jeu de Variantes: Modèle principal; Position: Non défini; Fonction structurelle: Non défini; Affichage sur filtre de rénovation: Tous les filtres appropriés; État de rénovation: Existant; État de Variante: Modèle principal; Jeu de Variantes: Modèle principal
ArchiCADQuantities - Hauteur: 540 mm; Épaisseur: 540 mm
AC_Pset_RenovationAndPhasing - Renovation Status: Existing
Name | In | ID de l'élément = Lien et ID d'élément = ID de Parent | Nom d'étage d'implantation | Numéro d'étage d'implantation | Surfaces (Toutes) | Hachure de recouvrement | Surface supérieure | Surface latérale | Surface inférieure | Altitude inférieure (mm) = Altitude inférieure à premier niveau de référence (mm) = Altitude inférieure à Zéro du projet (mm) = Altitude inférieure à niveau de la mer (mm) = Altitude inférieure à deuxième niveau de référence (mm) | Superficie supérieure de la dalle (conditionnelle) (m2) = Superficie inférieure de la dalle (brute) (m2) = Superficie supérieure de la dalle (brute) (m2) = Superficie supérieure (conditionnelle) (m2) = Superficie surface inférieure (Brute) (m2) = Superficie surface supérieure (Brute) (m2) | Superficie inférieure de la dalle (brute, sans trous) (m2) = Superficie supérieure de la dalle (brute, sans trous) (m2) = Superficie (m2) = Superficie en plan (m2) = Superficie supérieure (nette) (m2) | Superficie des arêtes de dalle (brute) (m2) = Superficie surface d'arête (Brute) (m2) | Superficie des arêtes de dalle (brute, sans trous) (m2) | Superficie des trous (m2) | Altitude supérieure (mm) = Altitude à Zéro du Projet (mm) = Altitude de Référence Niveau 1 (mm) = Altitude de Référence Niveau 2 (mm) = Altitude à niveau de la mer (mm) = Altitude supérieure à premier niveau de référence (mm) = Altitude supérieure à Zéro du projet (mm) = Altitude supérieure à niveau de la mer (mm) = Altitude supérieure à deuxième niveau de référence (mm) | Volume (net) (m3) | Altitude à étage lié/étage d'implantation (mm) = Décalage étage d'implantation (mm) = Altitude supérieure à étage d'implantation (mm) | Volume (conditionnel) (m3) | Volume (brut) (m3) | Périmètre Plan (mm) | Périmètre trous Plan (mm) | Altitude inférieure à étage d'implantation (mm) | Superficie de l'arête (nette) (m2) | Superficie inférieure (nette) (m2) | Superficie inférieure (conditionnelle) (m2)
Dalle-031 | rdc | Dalle-031 | rdc | 3 | Revêt. murs ext. | 100 % | Revêt. murs ext. | Revêt. murs ext. | Revêt. murs ext. | 2260 | 2.47385 | 2.47385 | 3.40113 | 3.40113 | 0 | 2800 | 1.32781 | -200 | 1.32781 | 1.33588 | 6298.39 | 0 | -740 | 3.01369 | 2.44695 | 2.44695
Dalle-031 | rdc | Dalle-031 | rdc | 3 | Revêt. murs ext. | 100 % | Revêt. murs ext. | Revêt. murs ext. | Revêt. murs ext. | 2460 | 4.73261 | 4.73261 | 5.08245 | 5.08245 | 0 | 3000 | 2.55561 | 0 | 2.55561 | 2.55561 | 9411.94 | 0 | -540 | 5.08245 | 4.73261 | 4.73261
Dalle-029 | rdc | Dalle-029 | rdc | 3 | Divers-Gazon; Escalier Limon | 25 % | Divers-Gazon | Escalier Limon | Escalier Limon | 2460 | 0.00376079 | 0.00376079 | 4.03888 | 4.03888 | 0 | 3000 | 0.000363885 | 0 | 0.000363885 | 0.00203082 | 7479.4 | 0 | -540 | 0.562545 | 0.000358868 | 0.000358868
Dalle-030 | Etage 5 | Dalle-030 | Etage 5 | 8 | Pierre-Calcaire Brillant; HAG Black Matt; Lavis blanc | Pierre | Pierre-Calcaire Brillant | HAG Black Matt | Lavis blanc | 17220 | 20.4064 | 19.4067 | 12.2374 | 14.3971 | 0.999687 | 17760 | 10.4796 | 110 | 11.0194 | 11.0194 | 26661.3 | 3999.37 | -430 | 14.3971 | 19.4067 | 20.4064
Dalle-030 | Etage 5 | Dalle-030 | Etage 5 | 8 | Pierre-Calcaire Brillant; HAG Black Matt; Lavis blanc | Pierre | Pierre-Calcaire Brillant | HAG Black Matt | Lavis blanc | 17960 | 3.04 | 3.04 | 3.78 | 3.78 | 0 | 18500 | 1.6416 | 850 | 1.6416 | 1.6416 | 7000 | 0 | 310 | 3.78 | 3.04 | 3.04

# IfcSlab: dalle 24 + gazon 50 740 (5)
In: rdc
Type - PredefinedType: FLOOR
Classification: Dalle (Classification ARCHICAD); Material: Pierre 285292438 500 mm, Parpaing 288701002 240 mm
ArchiCADProperties - Emplacement de plan de référence: Haut; Calque: dalles; Matériau de construction / Composite / Profil / Hachure: dalle 24 + gazon 50; Structure Composite: dalle 24 + gazon 50; Verrouillé: no; Nom d'étage d'implantation: rdc; Numéro d'étage d'implantation: 3; Type d'élément: Dalle; Type de structure: Composite; Matériaux de construction (Tous): Pierre 285292438; Parpaing 288701002; Nombre de percements: 0; Nom de Variante: Modèle principal; Nom de Jeu de Variantes: Modèle principal; Position: Non défini; Fonction structurelle: Non défini; Affichage sur filtre de rénovation: Tous les filtres appropriés; État de rénovation: Existant; État de Variante: Modèle principal; Jeu de Variantes: Modèle principal
AC_Pset_RenovationAndPhasing - Renovation Status: Existing
ArchiCADQuantities - Altitude inférieure: 2260 mm; Superficie des trous: 0 m2; Altitude supérieure: 3000 mm; Hauteur: 740 mm; Altitude à Zéro du Projet: 3000 mm; Altitude de Référence Niveau 1: 3000 mm; Altitude de Référence Niveau 2: 3000 mm; Altitude à niveau de la mer: 3000 mm; Épaisseur: 740 mm; Périmètre trous Plan: 0 mm; Altitude supérieure à premier niveau de référence: 3000 mm; Altitude supérieure à Zéro du projet: 3000 mm; Altitude supérieure à niveau de la mer: 3000 mm; Altitude supérieure à deuxième niveau de référence: 3000 mm; Altitude inférieure à premier niveau de référence: 2260 mm; Altitude inférieure à étage d'implantation: -740 mm; Altitude inférieure à Zéro du projet: 2260 mm; Altitude inférieure à niveau de la mer: 2260 mm; Altitude inférieure à deuxième niveau de référence: 2260 mm
Name | ID de l'élément = Lien et ID d'élément = ID de Parent | Zones conflictuelles | Surfaces (Toutes) | Hachure de recouvrement | Surface supérieure | Surface latérale | Surface inférieure | Superficie supérieure de la dalle (conditionnelle) (m2) = Superficie inférieure de la dalle (brute) (m2) = Superficie inférieure de la dalle (brute, sans trous) (m2) = Superficie supérieure de la dalle (brute) (m2) = Superficie supérieure de la dalle (brute, sans trous) (m2) = Superficie (m2) = Superficie en plan (m2) = Superficie supérieure (nette) (m2) = Superficie supérieure (conditionnelle) (m2) = Superficie surface inférieure (Brute) (m2) = Superficie surface supérieure (Brute) (m2) | Superficie des arêtes de dalle (brute) (m2) = Superficie des arêtes de dalle (brute, sans trous) (m2) = Superficie surface d'arête (Brute) (m2) | Volume (net) (m3) = Volume (conditionnel) (m3) | Altitude à étage lié/étage d'implantation (mm) = Décalage étage d'implantation (mm) | Volume (brut) (m3) | Périmètre Plan (mm) | Altitude supérieure à étage d'implantation (mm) | Superficie de l'arête (nette) (m2) | Superficie inférieure (nette) (m2) = Superficie inférieure (conditionnelle) (m2)
Dalle-031 | Dalle-031 | Pl | Revêt. murs ext. | 100 % | Revêt. murs ext. | Revêt. murs ext. | Revêt. murs ext. | 83.4798 | 39.3273 | 61.4942 | 4.44089e-13 | 61.775 | 53145 | 8.88178e-13 | 34.8662 | 83.1459
Dalle-032 | Dalle-032 | Pl | Divers-Feuillage persistant; HAG Black Matt; Lavis blanc | 25 % | Divers-Feuillage persistant | HAG Black Matt | Lavis blanc | 168.69 | 46.3259 | 123.767 | 0 | 124.83 | 62602.6 | 0 | 42.5727 | 164.905 | ArchiCADProperties - Nom de zone liée: Jardin; Numéro de zone liée: A04
Dalle-032 | Dalle-032 |  | Divers-Feuillage persistant; HAG Black Matt; Lavis blanc | 25 % | Divers-Feuillage persistant | HAG Black Matt | Lavis blanc | 66.4439 | 24.1951 | 48.7854 | 0 | 49.1685 | 32696.1 | 0 | 24.1951 | 64.8479
Dalle-032 | Dalle-032 | Pl | Divers-Feuillage persistant; HAG Black Matt; Lavis blanc | 25 % | Divers-Feuillage persistant | HAG Black Matt | Lavis blanc | 2.45941 | 4.97766 | 1.81996 | 0 | 1.81996 | 6726.57 | 0 | 4.97766 | 2.45941
Dalle-032 | Dalle-032 | Pl | Divers-Feuillage persistant; HAG Black Matt; Lavis blanc | 25 % | Divers-Feuillage persistant | HAG Black Matt | Lavis blanc | 6.95151 | 12.7425 | 5.14412 | 0 | 5.14412 | 17219.6 | 0 | 12.7425 | 6.95151

# IfcSlab: dalle 25 20+chape 250 (5)
Type - PredefinedType: FLOOR
Classification: Dalle (Classification ARCHICAD); Material: Brique 1 268964100 50 mm, Parpaing 288701002 200 mm
ArchiCADProperties - Emplacement de plan de référence: Haut; ID de l'élément: Dalle-030; Lien et ID d'élément: Dalle-030; Calque: dalles; Matériau de construction / Composite / Profil / Hachure: dalle 25 20+chape; Structure Composite: dalle 25 20+chape; Verrouillé: no; Type d'élément: Dalle; Type de structure: Composite; ID de Parent: Dalle-030; Matériaux de construction (Tous): Brique 1 268964100; Parpaing 288701002; Surfaces (Toutes): Menuiserie Plastique; Bois-Pin horizontal; Hachure de recouvrement: Empty Fill; Nombre de percements: 0; Surface supérieure: Bois-Pin horizontal; Surface latérale: Menuiserie Plastique; Surface inférieure: Menuiserie Plastique; Nom de Variante: Modèle principal; Nom de Jeu de Variantes: Modèle principal; Position: Non défini; Fonction structurelle: Non défini; Affichage sur filtre de rénovation: Tous les filtres appropriés; État de rénovation: Existant; État de Variante: Modèle principal; Jeu de Variantes: Modèle principal
ArchiCADQuantities - Hauteur: 250 mm; Altitude à étage lié/étage d'implantation: 0 mm; Décalage étage d'implantation: 0 mm; Épaisseur: 250 mm; Altitude supérieure à étage d'implantation: 0 mm; Altitude inférieure à étage d'implantation: -250 mm
AC_Pset_RenovationAndPhasing - Renovation Status: Existing
Name | In | Nom de zone liée | Numéro de zone liée | Nom d'étage d'implantation | Numéro d'étage d'implantation | Altitude inférieure (mm) = Altitude inférieure à premier niveau de référence (mm) = Altitude inférieure à Zéro du projet (mm) = Altitude inférieure à niveau de la mer (mm) = Altitude inférieure à deuxième niveau de référence (mm) | Superficie supérieure de la dalle (conditionnelle) (m2) = Superficie inférieure de la dalle (brute, sans trous) (m2) = Superficie supérieure de la dalle (brute, sans trous) (m2) = Superficie (m2) = Superficie en plan (m2) = Superficie supérieure (nette) (m2) = Superficie supérieure (conditionnelle) (m2) = Superficie inférieure (nette) (m2) = Superficie inférieure (conditionnelle) (m2) | Superficie inférieure de la dalle (brute) (m2) = Superficie supérieure de la dalle (brute) (m2) = Superficie surface inférieure (Brute) (m2) = Superficie surface supérieure (Brute) (m2) | Superficie des arêtes de dalle (brute) (m2) = Superficie surface d'arête (Brute) (m2) | Superficie des arêtes de dalle (brute, sans trous) (m2) = Superficie de l'arête (nette) (m2) | Superficie des trous (m2) | Altitude supérieure (mm) = Altitude à Zéro du Projet (mm) = Altitude de Référence Niveau 1 (mm) = Altitude de Référence Niveau 2 (mm) = Altitude à niveau de la mer (mm) = Altitude supérieure à premier niveau de référence (mm) = Altitude supérieure à Zéro du projet (mm) = Altitude supérieure à niveau de la mer (mm) = Altitude supérieure à deuxième niveau de référence (mm) | Volume (net) (m3) | Volume (conditionnel) (m3) = Volume (brut) (m3) | Périmètre Plan (mm) | Périmètre trous Plan (mm)
Dalle-030 | Etage1 | Sejour cuisine | B11 | Etage1 | 4 | 5500 | 510.623 | 510.623 | 31.5284 | 31.5284 | 0 | 5750 | 127.656 | 127.656 | 126114 | 0
Dalle-030 | Etage1 | Cellier | A12 | Etage1 | 4 | 5500 | 326.671 | 337.724 | 20.196 | 25.0756 | 11.0529 | 5750 | 81.6678 | 84.431 | 100302 | 19518.5
Dalle-030 | Etage 2 | Cellier | A22 | Etage 2 | 5 | 8250 | 326.574 | 337.724 | 20.196 | 25.0758 | 11.1501 | 8500 | 81.6434 | 84.4309 | 100303 | 19519.1
Dalle-030 | Etage 2 | Ch 1 | B21 | Etage 2 | 5 | 8250 | 510.494 | 510.494 | 30.5373 | 30.5373 | 0 | 8500 | 127.623 | 127.623 | 122149 | 0
Dalle-030 | Etage 3 | Sde | A32 | Etage 3 | 6 | 11300 | 285.405 | 296.555 | 17.9051 | 22.7849 | 11.1501 | 11550 | 71.3512 | 74.1388 | 91139.5 | 19519.1

# IfcSlab: dalle 25 chape + faux plafond 30cm 550 (4)
Type - PredefinedType: FLOOR
Classification: Dalle (Classification ARCHICAD); Material: Brique 1 268964100 50 mm, Parpaing 288701002 200 mm, Empty Fill 288701002 250 mm, 100 % 292236652 50 mm
ArchiCADProperties - Emplacement de plan de référence: Haut; ID de l'élément: Dalle-030; Lien et ID d'élément: Dalle-030; Calque: dalles; Matériau de construction / Composite / Profil / Hachure: dalle 25 chape + faux plafond 30cm; Structure Composite: dalle 25 chape + faux plafond 30cm; Verrouillé: no; Type d'élément: Dalle; Type de structure: Composite; ID de Parent: Dalle-030; Matériaux de construction (Tous): Brique 1 268964100; Parpaing 288701002; Empty Fill 288701002; 100 % 292236652; Surfaces (Toutes): Menuiserie Plastique; Bois-Pin horizontal; Hachure de recouvrement: Empty Fill; Nombre de percements: 0; Surface supérieure: Bois-Pin horizontal; Surface latérale: Menuiserie Plastique; Surface inférieure: Menuiserie Plastique; Nom de Variante: Modèle principal; Nom de Jeu de Variantes: Modèle principal; Position: Non défini; Fonction structurelle: Non défini; Affichage sur filtre de rénovation: Tous les filtres appropriés; État de rénovation: Existant; État de Variante: Modèle principal; Jeu de Variantes: Modèle principal
ArchiCADQuantities - Hauteur: 550 mm; Altitude à étage lié/étage d'implantation: 0 mm; Décalage étage d'implantation: 0 mm; Épaisseur: 550 mm; Altitude supérieure à étage d'implantation: 0 mm; Altitude inférieure à étage d'implantation: -550 mm
AC_Pset_RenovationAndPhasing - Renovation Status: Existing
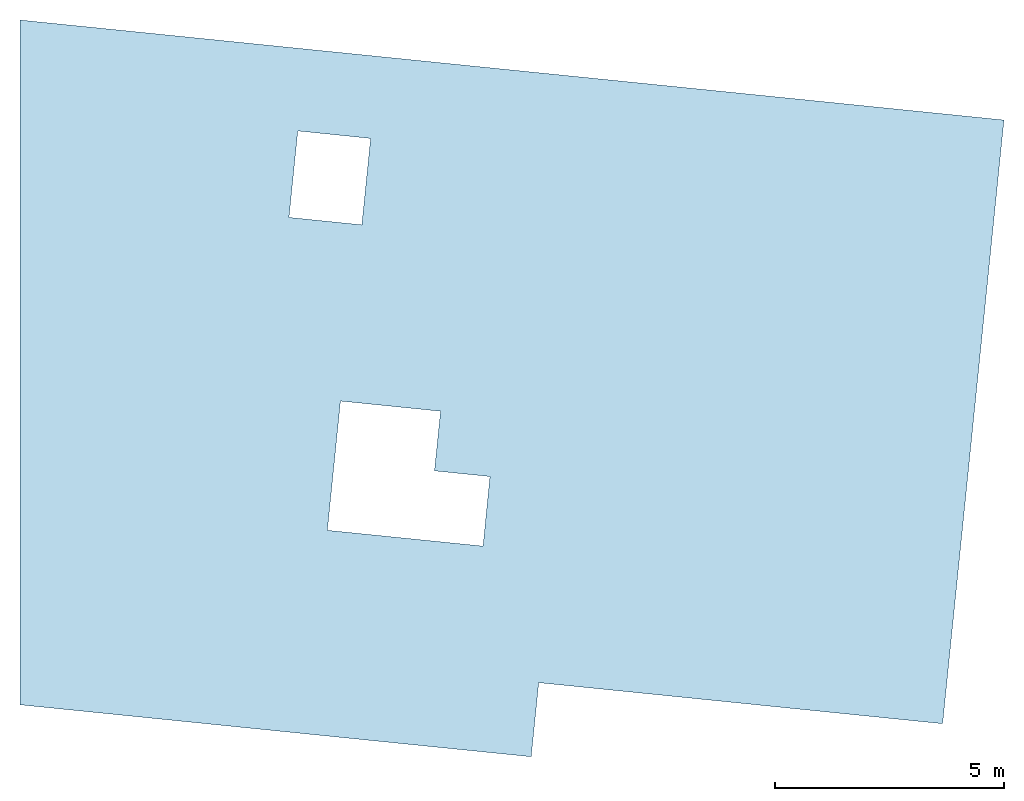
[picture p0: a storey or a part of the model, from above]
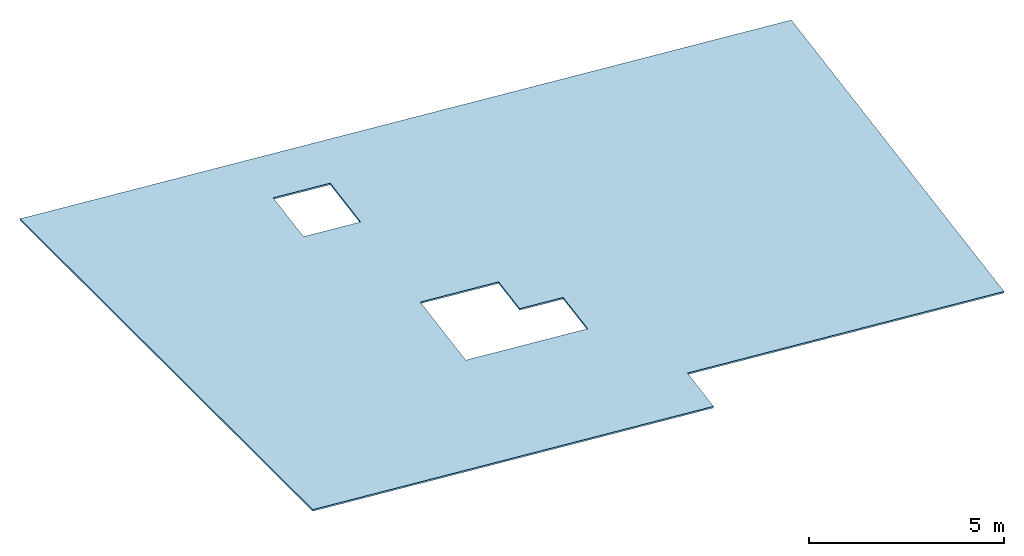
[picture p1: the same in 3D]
Properties of the parts of a building model (IFC2X3), part 19 of 44

# IfcSlab: dalle 25 chape + faux plafond 30cm 550 (4)
Name | In | Nom de zone liée | Numéro de zone liée | Nom d'étage d'implantation | Numéro d'étage d'implantation | Altitude inférieure (mm) = Altitude inférieure à premier niveau de référence (mm) = Altitude inférieure à Zéro du projet (mm) = Altitude inférieure à niveau de la mer (mm) = Altitude inférieure à deuxième niveau de référence (mm) | Superficie supérieure de la dalle (conditionnelle) (m2) = Superficie inférieure de la dalle (brute) (m2) = Superficie supérieure de la dalle (brute) (m2) = Superficie supérieure (conditionnelle) (m2) = Superficie surface inférieure (Brute) (m2) = Superficie surface supérieure (Brute) (m2) | Superficie inférieure de la dalle (brute, sans trous) (m2) = Superficie supérieure de la dalle (brute, sans trous) (m2) = Superficie (m2) = Superficie en plan (m2) = Superficie supérieure (nette) (m2) | Superficie des arêtes de dalle (brute) (m2) = Superficie surface d'arête (Brute) (m2) | Superficie des arêtes de dalle (brute, sans trous) (m2) | Superficie des trous (m2) | Altitude supérieure (mm) = Altitude à Zéro du Projet (mm) = Altitude de Référence Niveau 1 (mm) = Altitude de Référence Niveau 2 (mm) = Altitude à niveau de la mer (mm) = Altitude supérieure à premier niveau de référence (mm) = Altitude supérieure à Zéro du projet (mm) = Altitude supérieure à niveau de la mer (mm) = Altitude supérieure à deuxième niveau de référence (mm) | Volume (net) (m3) | Volume (conditionnel) (m3) | Volume (brut) (m3) | Périmètre Plan (mm) | Périmètre trous Plan (mm) | Superficie de l'arête (nette) (m2) | Superficie inférieure (nette) (m2) | Superficie inférieure (conditionnelle) (m2)
Dalle-030 | Etage 3 | Ch 1/pl | B31 | Etage 3 | 6 | 11000 | 455.704 | 455.704 | 62.5397 | 62.5397 | 0 | 11550 | 250.328 | 250.328 | 250.637 | 113709 | 0 | 60.4063 | 455.683 | 455.683
Dalle-030 | etage 4 | Sejour cuisine/pl | B41 | etage 4 | 7 | 14050 | 379.623 | 379.623 | 53.9143 | 53.9143 | 0 | 14600 | 208.6 | 208.6 | 208.793 | 98026 | 0 | 44.3138 | 378.979 | 378.979
Dalle-030 | Etage 5 | Ch 2 | B54 | Etage 5 | 8 | 17100 | 265.486 | 263.723 | 43.773 | 49.0628 | 1.76355 | 17650 | 145.045 | 146.015 | 146.018 | 89205 | 9617.77 | 46.5967 | 263.71 | 265.473
Dalle-030 | Etage 5 | Ch 3 | B51 | Etage 5 | 8 | 17100 | 265.486 | 263.521 | 43.773 | 49.6174 | 1.96522 | 17650 | 144.934 | 146.015 | 146.018 | 90213.4 | 10626.1 | 47.1512 | 263.508 | 265.473

# IfcSlab: dalle 5 50 (53)
Type - PredefinedType: FLOOR
Classification: Dalle (Classification ARCHICAD); Material: 100 % (2) 313493396 50 mm
AC_Pset_RenovationAndPhasing - Renovation Status: Existing
ArchiCADProperties - Emplacement de plan de référence: Haut; Calque: dalles; Matériau de construction / Composite / Profil / Hachure: dalle 5; Structure Composite: dalle 5; Verrouillé: no; Type d'élément: Dalle; Type de structure: Composite; Matériaux de construction (Tous): 100 % (2) 313493396; Nombre de percements: 0; Surface inférieure: Lavis blanc; Nom de Variante: Modèle principal; Nom de Jeu de Variantes: Modèle principal; Position: Non défini; Fonction structurelle: Non défini; Affichage sur filtre de rénovation: Tous les filtres appropriés; État de rénovation: Existant; État de Variante: Modèle principal; Jeu de Variantes: Modèle principal
ArchiCADQuantities - Hauteur: 50 mm; Altitude à étage lié/étage d'implantation: 2300 mm; Décalage étage d'implantation: 2300 mm; Épaisseur: 50 mm; Altitude supérieure à étage d'implantation: 2300 mm; Altitude inférieure à étage d'implantation: 2250 mm
Name | In | ID de l'élément = Lien et ID d'élément = ID de Parent | Zones conflictuelles | Nom d'étage d'implantation | Numéro d'étage d'implantation | Surfaces (Toutes) | Hachure de recouvrement | Surface supérieure | Surface latérale | Altitude inférieure (mm) = Altitude inférieure à premier niveau de référence (mm) = Altitude inférieure à Zéro du projet (mm) = Altitude inférieure à niveau de la mer (mm) = Altitude inférieure à deuxième niveau de référence (mm) | Superficie supérieure de la dalle (conditionnelle) (m2) = Superficie (m2) = Superficie en plan (m2) = Superficie supérieure (nette) (m2) = Superficie supérieure (conditionnelle) (m2) = Superficie inférieure (nette) (m2) = Superficie inférieure (conditionnelle) (m2) | Superficie inférieure de la dalle (brute) (m2) = Superficie supérieure de la dalle (brute) (m2) = Superficie surface inférieure (Brute) (m2) = Superficie surface supérieure (Brute) (m2) | Superficie inférieure de la dalle (brute, sans trous) (m2) = Superficie supérieure de la dalle (brute, sans trous) (m2) | Superficie des arêtes de dalle (brute) (m2) = Superficie surface d'arête (Brute) (m2) | Superficie des arêtes de dalle (brute, sans trous) (m2) | Superficie des trous (m2) | Altitude supérieure (mm) = Altitude à Zéro du Projet (mm) = Altitude de Référence Niveau 1 (mm) = Altitude de Référence Niveau 2 (mm) = Altitude à niveau de la mer (mm) = Altitude supérieure à premier niveau de référence (mm) = Altitude supérieure à Zéro du projet (mm) = Altitude supérieure à niveau de la mer (mm) = Altitude supérieure à deuxième niveau de référence (mm) | Volume (net) (m3) | Volume (conditionnel) (m3) | Volume (brut) (m3) | Périmètre Plan (mm) | Périmètre trous Plan (mm) | Superficie de l'arête (nette) (m2) | Nom de zone liée | Numéro de zone liée
Dalle-033 | cadastre | Dalle-033 | Pl; Pl | cadastre | 1 | Pierre-Grès; HAG Black Matt; Lavis blanc | hachure bati | Pierre-Grès | HAG Black Matt | 2250 | 268.972 | 296.558 | 285.409 | 3.58119 | 4.55705 | 27.5858 | 2300 | 13.4486 | 13.9783 | 14.8279 | 91141.1 | 19517.3 | 3.9713
Dalle-042 | rdc | Dalle-042 | Ch 2; Entree/pl; Sejour cuisine; Wc | rdc | 3 | Pierre-Grès; HAG Black Matt; Lavis blanc | hachure bati | Pierre-Grès | HAG Black Matt | 5250 | 10.8469 | 10.8469 | 10.8469 | 1.15728 | 1.15728 | 0 | 5300 | 0.542344 | 0.542344 | 0.542344 | 23145.6 | 0 | 1.15728 | Wc | B05
Dalle-032 | rdc | Dalle-032 | Cellier; Ch 2; Entree/pl; Sejour cuisine/pl | rdc | 3 | Pierre-Grès; HAG Black Matt; Lavis blanc | hachure bati | Pierre-Grès | HAG Black Matt | 5250 | 14.0334 | 14.0334 | 14.0334 | 1.30879 | 1.30879 | 0 | 5300 | 0.701669 | 0.701669 | 0.701669 | 26175.8 | 0 | 1.30879 | Cellier | B04
Dalle-032 | rdc | Dalle-032 | Sejour cuisine | rdc | 3 | Pierre-Grès; HAG Black Matt; Lavis blanc | hachure bati | Pierre-Grès | HAG Black Matt | 5250 | 2.35935 | 2.35935 | 2.35935 | 0.418049 | 0.418049 | 0 | 5300 | 0.117967 | 0.117967 | 0.117967 | 8360.99 | 0 | 0.418049
Dalle-041 | rdc | Dalle-041 | Wc | rdc | 3 | Pierre-Grès; HAG Black Matt; Lavis blanc | hachure bati | Pierre-Grès | HAG Black Matt | 5250 | 2.07363 | 2.07363 | 2.07363 | 0.288473 | 0.288473 | 0 | 5300 | 0.103682 | 0.103682 | 0.103682 | 5769.46 | 0 | 0.288473 | Wc | B02
Dalle-040 | rdc | Dalle-040 | Wc | rdc | 3 | Pierre-Grès; HAG Black Matt; Lavis blanc | AS_EMPTY | Pierre-Grès | HAG Black Matt | 5250 | 2.07363 | 2.07363 | 2.07363 | 0.288473 | 0.288473 | 0 | 5300 | 0.103682 | 0.103682 | 0.103682 | 5769.46 | 0 | 0.288473 | Wc | B02
Dalle-039 | rdc | Dalle-039 |  | rdc | 3 | Pierre-Grès; HAG Black Matt; Lavis blanc | AS_EMPTY | Pierre-Grès | HAG Black Matt | 5250 | 10.0983 | 10.0983 | 10.0983 | 0.640197 | 0.640197 | 0 | 5300 | 0.504916 | 0.504916 | 0.504916 | 12803.9 | 0 | 0.640197
Dalle-032 | rdc | Dalle-032 | Entree; Sdb; Sejour cuisine/pl | rdc | 3 | Pierre-Grès; HAG Black Matt; Lavis blanc | hachure bati | Pierre-Grès | HAG Black Matt | 5250 | 16.1967 | 16.1967 | 16.1967 | 1.13943 | 1.13943 | 0 | 5300 | 0.809837 | 0.809837 | 0.809837 | 22788.6 | 0 | 1.13943 | Entree | A01
Dalle-032 | rdc | Dalle-032 | Ch 1; Dressing; Sejour cuisine; Wc | rdc | 3 | Pierre-Grès; HAG Black Matt; Lavis blanc | hachure bati | Pierre-Grès | HAG Black Matt | 5250 | 9.33792 | 9.96411 | 9.96411 | 1.16937 | 1.16937 | 0.626186 | 5300 | 0.466896 | 0.466896 | 0.498206 | 23387.3 | 0 | 1.09835 | Wc | A03
Dalle-033 | rdc | Dalle-033 |  | rdc | 3 | Pierre-Grès; HAG Black Matt; Lavis blanc | AS_EMPTY | Pierre-Grès | HAG Black Matt | 5250 | 18.3454 | 18.3454 | 18.3454 | 1.4175 | 1.4175 | 0 | 5300 | 0.917268 | 0.917268 | 0.917268 | 28350 | 0 | 1.4175
Dalle-032 | rdc | Dalle-032 | Cellier; Dgt; Sdb | rdc | 3 | Pierre-Grès; HAG Black Matt; Lavis blanc | hachure bati | Pierre-Grès | HAG Black Matt | 5250 | 10.9608 | 10.9608 | 10.9608 | 0.857816 | 0.857816 | 0 | 5300 | 0.548042 | 0.548042 | 0.548042 | 17156.3 | 0 | 0.857816
Dalle-038 | rdc | Dalle-038 |  | rdc | 3 | HAG Acrylic White; Lavis blanc; Aluminium | AS_EMPTY | Aluminium | HAG Acrylic White | 5250 | 42.9712 | 42.9712 | 42.9712 | 2.85998 | 2.85998 | 0 | 5300 | 2.14856 | 2.14856 | 2.14856 | 57199.6 | 0 | 2.85998
Dalle-032 | rdc | Dalle-032 | Cellier; Ch 2; Entree/pl; Wc | rdc | 3 | Pierre-Grès; HAG Black Matt; Lavis blanc | hachure bati | Pierre-Grès | HAG Black Matt | 5250 | 13.1264 | 13.1264 | 13.1264 | 1.43586 | 1.43586 | 0 | 5300 | 0.656318 | 0.656318 | 0.656318 | 28717.1 | 0 | 1.43586 | Cellier | A02
Dalle-032 | rdc | Dalle-032 | Sdb | rdc | 3 | Pierre-Grès; HAG Black Matt; Lavis blanc | hachure bati | Pierre-Grès | HAG Black Matt | 5250 | 0.846138 | 0.846138 | 0.846138 | 0.258905 | 0.258905 | 0 | 5300 | 0.0423069 | 0.0423069 | 0.0423069 | 5178.09 | 0 | 0.258905
Dalle-032 | rdc | Dalle-032 | Ch 3 | rdc | 3 | Pierre-Grès; HAG Black Matt; Lavis blanc | hachure bati | Pierre-Grès | HAG Black Matt | 5250 | 0.900931 | 0.900931 | 0.900931 | 0.2735 | 0.2735 | 0 | 5300 | 0.0450465 | 0.0450465 | 0.0450465 | 5470 | 0 | 0.2735 | Ch 3 | B03
Dalle-032 | rdc | Dalle-032 | Cellier; Entree/pl; Sejour cuisine; Wc | rdc | 3 | Pierre-Grès; HAG Black Matt; Lavis blanc | hachure bati | Pierre-Grès | HAG Black Matt | 5250 | 14.4521 | 14.4521 | 14.4521 | 0.811112 | 0.811112 | 0 | 5300 | 0.722604 | 0.722604 | 0.722604 | 16222.2 | 0 | 0.811112 | Cellier | B03
Dalle-032 | rdc | Dalle-032 | Pl | rdc | 3 | Pierre-Grès; HAG Black Matt; Lavis blanc | hachure bati | Pierre-Grès | HAG Black Matt | 5250 | 1.42729 | 1.42729 | 1.42729 | 0.433536 | 0.433536 | 0 | 5300 | 0.0713646 | 0.0713646 | 0.0713646 | 8670.72 | 0 | 0.433536 | Pl | 678
Dalle-032 | rdc | Dalle-032 |  | rdc | 3 | Pierre-Grès; HAG Black Matt; Lavis blanc | AS_EMPTY | Pierre-Grès | HAG Black Matt | 5250 | 3.26538 | 3.26538 | 3.26538 | 1.50626 | 1.50626 | 0 | 5300 | 0.163269 | 0.163269 | 0.163269 | 30125.3 | 0 | 1.50626
Dalle-042 | Etage1 | Dalle-042 | Ch 2; Entree/pl; Sejour cuisine; Wc | Etage1 | 4 | Pierre-Grès; HAG Black Matt; Lavis blanc | hachure bati | Pierre-Grès | HAG Black Matt | 8000 | 10.7626 | 10.7626 | 10.7626 | 1.27771 | 1.27771 | 0 | 8050 | 0.538129 | 0.538129 | 0.538129 | 25554.2 | 0 | 1.27771 | Wc | B16
Dalle-043 | Etage1 | Dalle-043 | Cellier; Entree/pl; Sejour cuisine; Wc | Etage1 | 4 | Pierre-Grès; HAG Black Matt; Lavis blanc | hachure bati | Pierre-Grès | HAG Black Matt | 8000 | 14.8714 | 14.8714 | 14.8714 | 0.857987 | 0.857987 | 0 | 8050 | 0.743568 | 0.743568 | 0.743568 | 17159.7 | 0 | 0.857987 | Entree/pl | B14
Dalle-033 | Etage1 | Dalle-033 | Ch 1; Dressing; Sejour cuisine; Wc | Etage1 | 4 | Pierre-Grès; HAG Black Matt; Lavis blanc | hachure bati | Pierre-Grès | HAG Black Matt | 8000 | 9.31987 | 9.9491 | 9.9491 | 1.16927 | 1.16927 | 0.629225 | 8050 | 0.465994 | 0.465994 | 0.497455 | 23385.5 | 0 | 1.09544
Dalle-034 | Etage1 | Dalle-034 | Ch 1; Sde; Sejour cuisine/pl; Wc | Etage1 | 4 | Pierre-Grès; HAG Black Matt; Lavis blanc | hachure bati | Pierre-Grès | HAG Black Matt | 8000 | 16.5812 | 16.5812 | 16.5812 | 1.56446 | 1.56446 | 0 | 8050 | 0.829062 | 0.829062 | 0.829062 | 31289.1 | 0 | 1.56446
Dalle-033 | Etage1 | Dalle-033 | Sde | Etage1 | 4 | Pierre-Grès; HAG Black Matt; Lavis blanc | hachure bati | Pierre-Grès | HAG Black Matt | 8000 | 0.000372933 | 0.000372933 | 0.000372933 | 0.193501 | 0.193501 | 0 | 8050 | 0.0000186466 | 0.0000186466 | 0.0000186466 | 3870.02 | 0 | 0.193501 | Sde | A12
Dalle-041 | Etage1 | Dalle-041 | Wc | Etage1 | 4 | Pierre-Grès; HAG Black Matt; Lavis blanc | hachure bati | Pierre-Grès | HAG Black Matt | 8000 | 2.07363 | 2.07363 | 2.07363 | 0.288473 | 0.288473 | 0 | 8050 | 0.103682 | 0.103682 | 0.103682 | 5769.46 | 0 | 0.288473 | Wc | B13
Dalle-040 | Etage1 | Dalle-040 | Cellier; Wc | Etage1 | 4 | Pierre-Grès; HAG Black Matt; Lavis blanc | AS_EMPTY | Pierre-Grès | HAG Black Matt | 8000 | 3.50163 | 3.50163 | 3.50163 | 0.393473 | 0.393473 | 0 | 8050 | 0.175082 | 0.175082 | 0.175082 | 7869.46 | 0 | 0.393473 | Cellier | B13
Dalle-038 | Etage1 | Dalle-038 |  | Etage1 | 4 | Pierre-Grès; HAG Black Matt; Lavis blanc | AS_EMPTY | Pierre-Grès | HAG Black Matt | 8000 | 32.6815 | 32.6815 | 32.6815 | 2.44937 | 2.44937 | 0 | 8050 | 1.63407 | 1.63407 | 1.63407 | 48987.4 | 0 | 2.44937
Dalle-043 | Etage1 | Dalle-043 | Sejour cuisine | Etage1 | 4 | Pierre-Grès; HAG Black Matt; Lavis blanc | hachure bati | Pierre-Grès | HAG Black Matt | 8000 | 2.35101 | 2.35101 | 2.35101 | 0.417779 | 0.417779 | 0 | 8050 | 0.11755 | 0.11755 | 0.11755 | 8355.58 | 0 | 0.417779 | Sejour cuisine | B14
Dalle-034 | Etage1 | Dalle-034 | Cellier; Dgt; Sdb | Etage1 | 4 | Pierre-Grès; HAG Black Matt; Lavis blanc | hachure bati | Pierre-Grès | HAG Black Matt | 8000 | 10.35 | 10.35 | 10.35 | 0.857516 | 0.857516 | 0 | 8050 | 0.5175 | 0.5175 | 0.5175 | 17150.3 | 0 | 0.857516 | Dgt | A14
Dalle-032 | Etage1 | Dalle-032 | Entree; Sde; Sejour cuisine/pl | Etage1 | 4 | Pierre-Grès; HAG Black Matt; Lavis blanc | hachure bati | Pierre-Grès | HAG Black Matt | 8000 | 16.3312 | 16.846 | 16.846 | 1.13947 | 1.13947 | 0.5148 | 8050 | 0.816559 | 0.816559 | 0.842299 | 22789.5 | 0 | 1.12147 | Entree | A11
Dalle-042 | Etage1 | Dalle-042 | Sejour cuisine | Etage1 | 4 | Pierre-Grès; HAG Black Matt; Lavis blanc | hachure bati | Pierre-Grès | HAG Black Matt | 8000 | 3.32554 | 3.32554 | 3.32554 | 0.450353 | 0.450353 | 0 | 8050 | 0.166277 | 0.166277 | 0.166277 | 9007.06 | 0 | 0.450353
Dalle-033 | Etage1 | Dalle-033 |  | Etage1 | 4 | Pierre-Grès; HAG Black Matt; Lavis blanc | AS_EMPTY | Pierre-Grès | HAG Black Matt | 8000 | 18.3454 | 18.3454 | 18.3454 | 1.4175 | 1.4175 | 0 | 8050 | 0.917268 | 0.917268 | 0.917268 | 28350 | 0 | 1.4175
Dalle-033 | Etage1 | Dalle-033 | Cellier; Ch 2; Entree/pl; Wc | Etage1 | 4 | Pierre-Grès; HAG Black Matt; Lavis blanc | hachure bati | Pierre-Grès | HAG Black Matt | 8000 | 13.4535 | 13.4535 | 13.4535 | 1.44286 | 1.44286 | 0 | 8050 | 0.672674 | 0.672674 | 0.672674 | 28857.1 | 0 | 1.44286 | Cellier | A12
Dalle-033 | Etage1 | Dalle-033 | Sde | Etage1 | 4 | Pierre-Grès; HAG Black Matt; Lavis blanc | hachure bati | Pierre-Grès | HAG Black Matt | 8000 | 0.846138 | 0.846138 | 0.846138 | 0.258905 | 0.258905 | 0 | 8050 | 0.0423069 | 0.0423069 | 0.0423069 | 5178.09 | 0 | 0.258905
Dalle-044 | Etage1 | Dalle-044 | Cellier; Entree/pl; Sejour cuisine | Etage1 | 4 | Pierre-Grès; HAG Black Matt; Lavis blanc | hachure bati | Pierre-Grès | HAG Black Matt | 8000 | 15.6936 | 15.6936 | 15.6936 | 1.32472 | 1.32472 | 0 | 8050 | 0.784678 | 0.784678 | 0.784678 | 26494.4 | 0 | 1.32472 | Cellier | B15
Dalle-043 | Etage1 | Dalle-043 | Ch 3 | Etage1 | 4 | Pierre-Grès; HAG Black Matt; Lavis blanc | hachure bati | Pierre-Grès | HAG Black Matt | 8000 | 0.921798 | 0.921798 | 0.921798 | 0.27425 | 0.27425 | 0 | 8050 | 0.0460899 | 0.0460899 | 0.0460899 | 5484.99 | 0 | 0.27425 | Ch 3 | B14
Dalle-033 | Etage 2 | Dalle-033 | Ch 1 | Etage 2 | 5 | Pierre-Grès; HAG Black Matt; Lavis blanc | hachure bati | Pierre-Grès | HAG Black Matt | 10750 | 1.9209 | 1.9209 | 1.9209 | 0.450159 | 0.450159 | 0 | 10800 | 0.0960452 | 0.0960452 | 0.0960452 | 9003.18 | 0 | 0.450159 | Ch 1 | A25
Dalle-033 | Etage 2 | Dalle-033 | Ch 1/pl | Etage 2 | 5 | Pierre-Grès; HAG Black Matt; Lavis blanc | hachure bati | Pierre-Grès | HAG Black Matt | 10750 | 1.96468 | 1.96468 | 1.96468 | 0.464835 | 0.464835 | 0 | 10800 | 0.0982341 | 0.0982341 | 0.0982341 | 9296.7 | 0 | 0.464835
Dalle-033 | Etage 2 | Dalle-033 | Sejour cuisine/pl | Etage 2 | 5 | Pierre-Grès; HAG Black Matt; Lavis blanc | hachure bati | Pierre-Grès | HAG Black Matt | 10750 | 5.37814 | 5.37814 | 5.37814 | 0.490007 | 0.490007 | 0 | 10800 | 0.268907 | 0.268907 | 0.268907 | 9800.14 | 0 | 0.490007
Dalle-033 | Etage 2 | Dalle-033 | Ch 2 | Etage 2 | 5 | Pierre-Grès; HAG Black Matt; Lavis blanc | hachure bati | Pierre-Grès | HAG Black Matt | 10750 | 1.28304 | 1.28304 | 1.28304 | 0.498222 | 0.498222 | 0 | 10800 | 0.0641521 | 0.0641521 | 0.0641521 | 9964.44 | 0 | 0.498222 | Ch 2 | A22
Dalle-034 | Etage 3 | Dalle-034 |  | Etage 3 | 6 | Pierre-Grès; HAG Black Matt; Lavis blanc | hachure bati | Pierre-Grès | HAG Black Matt | 13800 | 0.00158688 | 0.00158688 | 0.00158688 | 0.0321291 | 0.0321291 | 0 | 13850 | 0.0000793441 | 0.0000793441 | 0.0000793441 | 642.581 | 0 | 0.0321291
Dalle-034 | Etage 3 | Dalle-034 | Sejour cuisine; Wc | Etage 3 | 6 | Pierre-Grès; HAG Black Matt; Lavis blanc | hachure bati | Pierre-Grès | HAG Black Matt | 13800 | 6.46408 | 6.89679 | 6.89679 | 0.690404 | 0.690404 | 0.432716 | 13850 | 0.323204 | 0.323204 | 0.34484 | 13808.1 | 0 | 0.641248
Dalle-034 | Etage 3 | Dalle-034 | Ch 1; Dressing; Sejour cuisine | Etage 3 | 6 | Pierre-Grès; HAG Black Matt; Lavis blanc | hachure bati | Pierre-Grès | HAG Black Matt | 13800 | 3.08865 | 3.08865 | 3.08865 | 0.574263 | 0.574263 | 0 | 13850 | 0.154433 | 0.154433 | 0.154433 | 11485.3 | 0 | 0.574263
Dalle-034 | Etage 3 | Dalle-034 | Sejour cuisine/pl | Etage 3 | 6 | Pierre-Grès; HAG Black Matt; Lavis blanc | hachure bati | Pierre-Grès | HAG Black Matt | 13800 | 0.000033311 | 0.000033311 | 0.000033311 | 0.0709267 | 0.0709267 | 0 | 13850 | 0.00000166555 | 0.00000166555 | 0.00000166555 | 1418.53 | 0 | 0.0709267
Dalle-034 | Etage 3 | Dalle-034 | Sejour cuisine/pl | Etage 3 | 6 | Pierre-Grès; HAG Black Matt; Lavis blanc | hachure bati | Pierre-Grès | HAG Black Matt | 13800 | 1.81212e-08 | 1.81212e-08 | 1.81212e-08 | 0.0000731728 | 0.0000731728 | 0 | 13850 | 9.06058e-10 | 9.06058e-10 | 9.06058e-10 | 1.46346 | 0 | 0.0000731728 | Sejour cuisine/pl | A33
Dalle-034 | Etage 3 | Dalle-034 | Dgt; Sde; Wc | Etage 3 | 6 | Pierre-Grès; HAG Black Matt; Lavis blanc | hachure bati | Pierre-Grès | HAG Black Matt | 13800 | 10.3878 | 10.3878 | 10.3878 | 0.864363 | 0.864363 | 0 | 13850 | 0.51939 | 0.51939 | 0.51939 | 17287.3 | 0 | 0.864363 | Wc | A33
Dalle-034 | Etage 3 | Dalle-034 | Dgt; Sejour cuisine/pl; Wc | Etage 3 | 6 | Pierre-Grès; HAG Black Matt; Lavis blanc | hachure bati | Pierre-Grès | HAG Black Matt | 13800 | 11.6294 | 11.6294 | 11.6294 | 1.14107 | 1.14107 | 0 | 13850 | 0.581472 | 0.581472 | 0.581472 | 22821.3 | 0 | 1.14107 | Wc | A31
Dalle-042 | Etage 3 | Dalle-042 | Ch 2 | Etage 3 | 6 | Pierre-Grès; HAG Black Matt; Lavis blanc | hachure bati | Pierre-Grès | HAG Black Matt | 13800 | 1.47458 | 1.47458 | 1.47458 | 0.433781 | 0.433781 | 0 | 13850 | 0.073729 | 0.073729 | 0.073729 | 8675.63 | 0 | 0.433781 | Ch 2 | B35
Dalle-034 | Etage 3 | Dalle-034 | Ch 1; Sde/pl; Sejour cuisine/pl | Etage 3 | 6 | Pierre-Grès; HAG Black Matt; Lavis blanc | hachure bati | Pierre-Grès | HAG Black Matt | 13800 | 11.3364 | 11.3364 | 11.3364 | 0.963194 | 0.963194 | 0 | 13850 | 0.566821 | 0.566821 | 0.566821 | 19263.9 | 0 | 0.963194
Dalle-034 | Etage 3 | Dalle-034 | Sejour cuisine/pl | Etage 3 | 6 | Pierre-Grès; HAG Black Matt; Lavis blanc | hachure bati | Pierre-Grès | HAG Black Matt | 13800 | 0.0000516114 | 0.0000516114 | 0.0000516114 | 0.15214 | 0.15214 | 0 | 13850 | 0.00000258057 | 0.00000258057 | 0.00000258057 | 3042.8 | 0 | 0.15214 | Sejour cuisine/pl | A34
Dalle-033 | Etage 3 | Dalle-033 | Sejour cuisine | Etage 3 | 6 | Pierre-Grès; HAG Black Matt; Lavis blanc | hachure bati | Pierre-Grès | HAG Black Matt | 13800 | 1.96468 | 1.96468 | 1.96468 | 0.464835 | 0.464835 | 0 | 13850 | 0.0982341 | 0.0982341 | 0.0982341 | 9296.7 | 0 | 0.464835
Dalle-044 | Etage 5 | Dalle-044 | Ch 3/pl; Ch 4/Pl; Dgt/pl; Entree; Wc | Etage 5 | 8 | Pierre-Grès; HAG Black Matt; Lavis blanc | hachure bati | Pierre-Grès | HAG Black Matt | 19900 | 16.432 | 16.432 | 16.432 | 1.42207 | 1.42207 | 0 | 19950 | 0.821598 | 0.821598 | 0.821598 | 28441.3 | 0 | 1.42207
Dalle-044 | Etage 5 | Dalle-044 | cellier | Etage 5 | 8 | Pierre-Grès; HAG Black Matt; Lavis blanc | hachure bati | Pierre-Grès | HAG Black Matt | 19900 | 1.8612 | 1.8612 | 1.8612 | 0.288065 | 0.288065 | 0 | 19950 | 0.0930598 | 0.0930598 | 0.0930598 | 5761.29 | 0 | 0.288065
Dalle-038 | Etage 5 | Dalle-038 | Dgt; Entree/pl; Sejour cuisine; Wc | Etage 5 | 8 | Pierre-Grès; HAG Black Matt; Lavis blanc | AS_EMPTY | Pierre-Grès | HAG Black Matt | 19900 | 7.38322 | 7.38322 | 7.38322 | 0.653115 | 0.653115 | 0 | 19950 | 0.369161 | 0.369161 | 0.369161 | 13062.3 | 0 | 0.653115

# IfcStair (12)
Classification: Escalier (Classification ARCHICAD)
ArchiCADQuantities - Hauteur d'échappée requise: 2200 mm; Giron minimal (par règle): 250 mm; Giron maximal (par règle): 350 mm; Hauteur minimale de contremarche (par règle): 150 mm; Hauteur maximale de contremarche (par règle): 200 mm; Décalage supérieur: 0 mm
AC_Pset_RenovationAndPhasing - Renovation Status: Existing
ArchiCADProperties - Angle d'inclinaison de contremarche par défaut: 90 deg; Calque: Calque Archicad; Verrouillé: no; Type d'élément: Escalier; Étage supérieur lié absolu: Non lié; Étage supérieur lié relatif: Non lié; Étage supérieur lié: Non lié; Nom de Variante: Modèle principal; Nom de Jeu de Variantes: Modèle principal; Position: Non défini; Fonction structurelle: Non défini; Affichage sur filtre de rénovation: Tous les filtres appropriés; État de rénovation: Existant; État de Variante: Modèle principal; Jeu de Variantes: Modèle principal
Name | In | Profondeur de marche par défaut (mm) | Hauteur contremarche par défaut (mm) | Largeur d'escalier par défaut (mm) | Superficie avant escalier (m2) | Nombre contremarches (total) = Nombre de contremarches par volées | Nombre de marches (total) = Nombre de marches par volées | Longueur de ligne de foulée (mm) | Superficie (m2) = Superficie supérieure (nette) (m2) | Hauteur (mm) | Volume (net) (m3) | Altitude à Zéro du Projet (mm) = Altitude de Référence Niveau 1 (mm) = Altitude de Référence Niveau 2 (mm) = Altitude à niveau de la mer (mm) | Altitude à étage lié/étage d'implantation (mm) = Décalage étage d'implantation (mm) | Altitude supérieure à premier niveau de référence (mm) = Altitude supérieure à Zéro du projet (mm) = Altitude supérieure à niveau de la mer (mm) = Altitude supérieure à deuxième niveau de référence (mm) | Altitude supérieure à étage d'implantation (mm) | Altitude inférieure à premier niveau de référence (mm) = Altitude inférieure à Zéro du projet (mm) = Altitude inférieure à niveau de la mer (mm) = Altitude inférieure à deuxième niveau de référence (mm) | Altitude inférieure à étage d'implantation (mm) | Pente de l'escalier (deg) | ID de l'élément = Lien et ID d'élément = ID de Parent | Nom d'étage d'implantation | Numéro d'étage d'implantation | Matériaux de construction (Tous)
ESC-014 | sousol | 289.75 | 166.667 | 1200 | 3.80346 | 18 | 18 | 5215.5 | 7.87568 | 3000 | 2.26194 | 0 | 0 | 3000 | 3000 | -130 | -130 | 29.9079 | ESC-014 | sousol | 2 | Cloison 274992075
ESC-021 | sousol | 335.714 | 150 | 1400 | 4.0589 | 14 | 14 | 4700 | 9.07669 | 2100 | 2.3583 | 900 | 900 | 3000 | 3000 | 770 | 770 | 24.0755 | ESC-021 | sousol | 2 | Cloison 274992075
ESC-020 | rdc | 325.101 | 161.765 | 1220 | 3.68979 | 17 | 16 | 5201.61 | 7.67332 | 2750 | 2.12994 | 3000 | 0 | 5750 | 2750 | 2870 | -130 | 26.4542 | ESC-020 | rdc | 3 | Cloison 274992075
ESC-020 | rdc | 325.101 | 161.765 | 1220 | 3.68979 | 17 | 16 | 5201.61 | 7.67332 | 2750 | 2.12994 | 3000 | 0 | 5750 | 2750 | 2870 | -130 | 26.4542 | ESC-020 | rdc | 3 | Cloison 274992075 | ArchiCADProperties - Surfaces (Toutes): Peinture-11
ESC-020 | Etage1 | 325.101 | 161.765 | 1220 | 3.68979 | 17 | 16 | 5201.61 | 7.67332 | 2750 | 2.12994 | 5750 | 0 | 8500 | 2750 | 5620 | -130 | 26.4542 | ESC-020 | Etage1 | 4 | Cloison 274992075
ESC-020 | Etage1 | 325.101 | 161.765 | 1220 | 3.68979 | 17 | 16 | 5201.61 | 7.67332 | 2750 | 2.12994 | 5750 | 0 | 8500 | 2750 | 5620 | -130 | 26.4542 | ESC-020 | Etage1 | 4 | Cloison 274992075 | ArchiCADProperties - Surfaces (Toutes): Peinture-11
ESC-020 | Etage 2 | 310.727 | 169.444 | 1220 | 4.0548 | 18 | 17 | 5282.36 | 7.77184 | 3050 | 2.20892 | 8500 | 0 | 11550 | 3050 | 8370 | -130 | 28.6043 | ESC-020 | Etage 2 | 5 | Cloison 274992075
ESC-020 | Etage 2 | 310.727 | 169.444 | 1220 | 4.0548 | 18 | 17 | 5282.36 | 7.77184 | 3050 | 2.20892 | 8500 | 0 | 11550 | 3050 | 8370 | -130 | 28.6043 | ESC-020 | Etage 2 | 5 | Cloison 274992075 | ArchiCADProperties - Surfaces (Toutes): Peinture-11
ESC-020 | etage 4 | 310.727 | 169.444 | 1220 | 4.0548 | 18 | 17 | 5282.36 | 7.77184 | 3050 | 2.20892 | 14600 | 0 | 17650 | 3050 | 14470 | -130 | 28.6043 | ESC-020 | etage 4 | 7 | Cloison 274992075 | ArchiCADProperties - Surfaces (Toutes): Peinture-11
ESC-020 | Etage 3 | 310.727 | 169.444 | 1220 | 4.0548 | 18 | 17 | 5282.36 | 7.77184 | 3050 | 2.20892 | 11550 | 0 | 14600 | 3050 | 11420 | -130 | 28.6043 | ESC-020 | Etage 3 | 6 | Cloison 274992075 | ArchiCADProperties - Surfaces (Toutes): Peinture-11
ESC-021 | Etage 5 | 297.778 | 161.579 | 1000 | 3.07 | 19 | 18 | 5360 | 5.375 | 3070 | 0.105086 | 17650 | 0 | 20776.9 | 3126.89 | 17640.9 | -9.08071 | 28.485 | ESC-021 | Etage 5 | 8 | ArchiCADProperties - Surfaces (Toutes): Bois-Chêne; Innvik Tex Stripe 1440; Zones conflictuelles: Terrasse; Terrasse/eng.; Nom de zone liée: Terrasse; Numéro de zone liée: B52
ESC-020 | Etage 3 | 281.235 | 166.842 | 1220 | 4.47665 | 19 | 18 | 5062.22 | 8.45912 | 3170 | 2.4235 | 11550 | 0 | 14720 | 3170 | 11420 | -130 | 30.6785 | ESC-020 | Etage 3 | 6 | Cloison 274992075

# IfcWall: Beton 18 0170347028 180, Mur-133
In: sousol
Classification: Mur (Classification ARCHICAD); Material: Parpaing 314940890
ArchiCADProperties - Complexité de mur: Incliné; Option de géométrie: Uniforme; Emplacement de ligne de référence: Face extérieure; Surface de face intérieure: Plâtre Lisse; Surface de face extérieure: Plâtre Lisse; Angle d'inclinaison interne de mur: 90 deg; Angle d'inclinaison externe de mur: 90 deg; ID de l'élément: Mur-133; Lien et ID d'élément: Mur-133; Calque: 3D; Matériau de construction / Composite / Profil / Hachure: Beton 18 0170347028; Structure Composite: Beton 18 0170347028; Verrouillé: no; Nom d'étage d'implantation: sousol; Numéro d'étage d'implantation: 2; Type d'élément: Mur; Étage supérieur lié absolu: Non lié; Étage supérieur lié relatif: Non lié; Étage supérieur lié: Non lié; Type de structure: Composite; ID de Parent: Mur-133; Matériaux de construction (Tous): Parpaing 314940890; Surfaces (Toutes): Plâtre Lisse; Angle d'inclinaison: 90 deg; Nombre de percements: 0; Surface latérale: Plâtre Lisse; Nom de Variante: Modèle principal; Nom de Jeu de Variantes: Modèle principal; Position: Non défini; Fonction structurelle: Non défini; Affichage sur filtre de rénovation: Tous les filtres appropriés; État de rénovation: Existant; État de Variante: Modèle principal; Jeu de Variantes: Modèle principal
AC_Pset_RenovationAndPhasing - Renovation Status: Existing
ArchiCADQuantities - Nombre de Portes: 0; Nombre de trous (Nombre d'ouvertures vides): 0; Nombre de Fenêtres: 0; Nombre de Poteaux: 0; Volume des poteaux: 0 m3; Hauteur maximale de la couche de Mur sur face intérieure: 3982.22 mm; Hauteur minimale de la couche de Mur sur face intérieure: 2008.29 mm; Hauteur maximale du Mur: 3982.22 mm; Hauteur minimale du Mur: 2008.29 mm; Hauteur maximale de la couche de Mur sur face extérieure: 3982.22 mm; Hauteur minimale de la couche de Mur sur face extérieure: 2008.29 mm; Épaisseur couche d'air: 0 mm; Superficie des portes: 0 m2; Largeur totale des Portes: 0 mm; Épaisseur de composant de mur sur face intérieure: 180 mm; Épaisseur de composant de mur sur face extérieure: 180 mm; Superficie des fenêtres: 0 m2; Largeur totale des Fenêtres: 0 mm; Volume de composant de mur sur face intérieure (net): 1.80614 m3; Volume de composant de mur sur face extérieure (net): 1.80614 m3; Superficie analytique des ouvertures sur face intérieure: 0 m2; Superficie analytique des ouvertures sur face extérieure: 0 m2; Longueur moyenne du mur: 3350 mm; Superficie de la face intérieure du mur (nette): 10.0341 m2; Superficie de la face extérieure du mur (nette): 10.0341 m2; Volume analytique des ouvertures: 0 m3; Longueur de ligne de référence: 3350 mm; Longueur de la face intérieure du mur (conditionnelle): 3350 mm; Superficie de la face intérieure du mur (conditionnelle): 10.0341 m2; Longueur de la face extérieure du mur (conditionnelle): 3350 mm; Superficie de la face extérieure du mur (conditionnelle): 10.0341 m2; Volume du composant face intérieure du mur (conditionnel): 1.80614 m3; Volume du composant face extérieure du mur (conditionnel): 1.80614 m3; Superficie de la face intérieure du mur (brute): 10.0341 m2; Superficie de la face extérieure du mur (brute): 10.0341 m2; Épaisseur du Mur à la fin: 180 mm; Longueur du Mur au centre: 3350 mm; Longueur de Mur sur face intérieure: 3350 mm; Longueur de Mur sur face extérieure: 3350 mm; Superficie des baies libres dans le Mur: 0 m2; Superficie: 0.603 m2; Hauteur: 4000 mm; Volume (net): 1.80614 m3; Largeur: 180 mm; Altitude à Zéro du Projet: 4.18415e-12 mm; Altitude de Référence Niveau 1: 4.18415e-12 mm; Altitude de Référence Niveau 2: 4.18415e-12 mm; Altitude à niveau de la mer: 4.18415e-12 mm; Altitude à étage lié/étage d'implantation: 4.18415e-12 mm; Décalage étage d'implantation: 4.18415e-12 mm; Décalage supérieur: 0 mm; Superficie en plan: 10.0341 m2; Longueur 3D: 3350 mm; Épaisseur: 180 mm; Volume (conditionnel): 1.80614 m3; Volume (brut): 1.80614 m3; Épaisseur couche isolation: 0 mm; Périmètre Plan: 7060 mm; Altitude supérieure à premier niveau de référence: 3982.22 mm; Altitude supérieure à étage d'implantation: 3982.22 mm; Altitude supérieure à Zéro du projet: 3982.22 mm; Altitude supérieure à niveau de la mer: 3982.22 mm; Altitude supérieure à deuxième niveau de référence: 3982.22 mm; Altitude inférieure à premier niveau de référence: 4.21885e-12 mm; Altitude inférieure à étage d'implantation: 4.21885e-12 mm; Altitude inférieure à Zéro du projet: 4.21885e-12 mm; Altitude inférieure à niveau de la mer: 4.21885e-12 mm; Altitude inférieure à deuxième niveau de référence: 4.21885e-12 mm; Superficie supérieure (nette): 0.603 m2; Superficie de l'arête (nette): 1.68129 m2; Superficie inférieure (nette): 10.0341 m2

# IfcWall: Empty Fill 272047960 340 (7)
In: Etage 2
Classification: Mur (Classification ARCHICAD); Material: Empty Fill 272047960
ArchiCADProperties - Complexité de mur: Droit; Option de géométrie: Uniforme; Emplacement de ligne de référence: Face extérieure; Surface de face intérieure: Peinture-01; Surface de face extérieure: Peinture-01; Angle d'inclinaison interne de mur: 90 deg; Angle d'inclinaison externe de mur: 90 deg; Calque: Interieurs logements; Matériau de construction / Composite / Profil / Hachure: Empty Fill 272047960; Matériau de construction: Empty Fill 272047960; Verrouillé: no; Nom d'étage d'implantation: Etage 2; Numéro d'étage d'implantation: 5; Type d'élément: Mur; Étage supérieur lié absolu: Non lié; Étage supérieur lié relatif: Non lié; Étage supérieur lié: Non lié; Type de structure: Basique; Matériaux de construction (Tous): Empty Fill 272047960; Surfaces (Toutes): Peinture-01; Angle d'inclinaison: 90 deg; Nombre de percements: 0; Surface latérale: Peinture-01; Nom de Variante: Modèle principal; Nom de Jeu de Variantes: Modèle principal; Position: Non défini; Fonction structurelle: Non défini; Affichage sur filtre de rénovation: Tous les filtres appropriés; État de rénovation: Existant; État de Variante: Modèle principal; Jeu de Variantes: Modèle principal
ArchiCADQuantities - Nombre de Portes: 0; Nombre de trous (Nombre d'ouvertures vides): 0; Nombre de Fenêtres: 0; Nombre de Poteaux: 0; Volume des poteaux: 0 m3; Hauteur maximale de la couche de Mur sur face intérieure: 0 mm; Hauteur minimale de la couche de Mur sur face intérieure: 0 mm; Hauteur maximale de la couche de Mur sur face extérieure: 0 mm; Hauteur minimale de la couche de Mur sur face extérieure: 0 mm; Épaisseur couche d'air: 0 mm; Superficie des portes: 0 m2; Largeur totale des Portes: 0 mm; Épaisseur de composant de mur sur face intérieure: 0 mm; Épaisseur de composant de mur sur face extérieure: 0 mm; Superficie des fenêtres: 0 m2; Largeur totale des Fenêtres: 0 mm; Superficie analytique des ouvertures sur face intérieure: 0 m2; Superficie analytique des ouvertures sur face extérieure: 0 m2; Volume analytique des ouvertures: 0 m3; Épaisseur du Mur à la fin: 340 mm; Superficie des baies libres dans le Mur: 0 m2; Largeur: 340 mm; Altitude à Zéro du Projet: 8750 mm; Altitude de Référence Niveau 1: 8750 mm; Altitude de Référence Niveau 2: 8750 mm; Altitude à niveau de la mer: 8750 mm; Altitude à étage lié/étage d'implantation: 250 mm; Décalage étage d'implantation: 250 mm; Décalage supérieur: 0 mm; Épaisseur: 340 mm; Épaisseur couche isolation: 0 mm; Altitude inférieure à premier niveau de référence: 8750 mm; Altitude inférieure à étage d'implantation: 250 mm; Altitude inférieure à Zéro du projet: 8750 mm; Altitude inférieure à niveau de la mer: 8750 mm; Altitude inférieure à deuxième niveau de référence: 8750 mm
AC_Pset_RenovationAndPhasing - Renovation Status: Existing
Name | ID de l'élément = Lien et ID d'élément = ID de Parent | Hauteur maximale du Mur (mm) | Hauteur minimale du Mur (mm) | Longueur moyenne du mur (mm) = Longueur du Mur au centre (mm) | Superficie de la face intérieure du mur (nette) (m2) = Superficie de la face intérieure du mur (conditionnelle) (m2) = Superficie de la face intérieure du mur (brute) (m2) | Superficie de la face extérieure du mur (nette) (m2) = Superficie de la face extérieure du mur (conditionnelle) (m2) = Superficie en plan (m2) = Superficie inférieure (nette) (m2) | Longueur de ligne de référence (mm) = Longueur de la face extérieure du mur (conditionnelle) (mm) = Longueur de Mur sur face extérieure (mm) | Longueur de la face intérieure du mur (conditionnelle) (mm) = Longueur de Mur sur face intérieure (mm) | Superficie de la face extérieure du mur (brute) (m2) | Superficie (m2) = Superficie supérieure (nette) (m2) | Hauteur (mm) | Volume (net) (m3) = Volume (conditionnel) (m3) = Volume (brut) (m3) | Longueur 3D (mm) | Périmètre Plan (mm) | Altitude supérieure à premier niveau de référence (mm) = Altitude supérieure à Zéro du projet (mm) = Altitude supérieure à niveau de la mer (mm) = Altitude supérieure à deuxième niveau de référence (mm) | Altitude supérieure à étage d'implantation (mm) | Superficie de l'arête (nette) (m2)
Mur-143 | Mur-143 | 686.241 | 0 | 8296.11 | 5.38497 | 3.33923 | 8455.76 | 8136.47 | 3.33923 | 2.74982 | 2750 | 1.49089 | 8328.35 | 17395.6 | 9436.24 | 936.241 | 3.0017
Mur-147 | Mur-147 | 1658.89 | 1318.89 | 5567.29 | 8.67479 | 7.78841 | 5905.29 | 5229.28 | 7.78841 | 1.89288 | 2750 | 2.81177 | 5905.29 | 12093.4 | 10408.9 | 1908.89 | 3.32053
Mur-145 | Mur-145 | 686.241 | 0 | 8832.44 | 5.74521 | 3.56696 | 9013.8 | 8651.08 | 3.56696 | 2.93562 | 2750 | 1.59155 | 8896.34 | 18505.4 | 9436.24 | 936.241 | 3.20766
Mur-146 | Mur-146 | 1658.89 | 1318.89 | 11758.6 | 18.9437 | 15.0205 | 12097.8 | 11419.5 | 15.9556 | 3.99794 | 2750 | 5.94595 | 12097.8 | 24477.8 | 10408.9 | 1908.89 | 5.42798
Mur-142 | Mur-142 | 1658.89 | 1318.89 | 11789.9 | 18.9925 | 15.9992 | 12130.8 | 11448.9 | 15.9992 | 4.00856 | 2750 | 5.96172 | 12130.8 | 24542.8 | 10408.9 | 1908.89 | 5.44248
Mur-143 | Mur-143 | 1658.89 | 1318.89 | 5708.62 | 8.90244 | 7.98021 | 6050.72 | 5366.51 | 7.98021 | 1.94093 | 2750 | 2.88323 | 6050.72 | 12381.9 | 10408.9 | 1908.89 | 3.37724
Mur-144 | Mur-144 | 4000 | 400.947 | 8424.44 | 19.2083 | 19.579 | 8765.45 | 8083.43 | 19.579 | 2.86431 | 4000 | 6.59935 | 8765.45 | 17812.7 | 12750 | 4250 | 3.44319

# IfcWallStandardCase: 100 % 282141195 50 (208)
Classification: Mur (Classification ARCHICAD); Material: 100 % 282141195 50 mm
ArchiCADProperties - Complexité de mur: Droit; Option de géométrie: Uniforme; Angle d'inclinaison interne de mur: 90 deg; Angle d'inclinaison externe de mur: 90 deg; ID de l'élément: Mur-153; Lien et ID d'élément: Mur-153; Calque: Interieurs logements; Matériau de construction / Composite / Profil / Hachure: 100 % 282141195; Matériau de construction: 100 % 282141195; Verrouillé: no; Type d'élément: Mur; Étage supérieur lié absolu: Non lié; Étage supérieur lié relatif: Non lié; Étage supérieur lié: Non lié; Type de structure: Basique; ID de Parent: Mur-153; Matériaux de construction (Tous): 100 % 282141195; Angle d'inclinaison: 90 deg; Nombre de percements: 0; Nom de Variante: Modèle principal; Nom de Jeu de Variantes: Modèle principal; Position: Non défini; Fonction structurelle: Non défini; Affichage sur filtre de rénovation: Tous les filtres appropriés; État de rénovation: Existant; État de Variante: Modèle principal; Jeu de Variantes: Modèle principal
AC_Pset_RenovationAndPhasing - Renovation Status: Existing
ArchiCADQuantities - Nombre de Portes: 0; Nombre de trous (Nombre d'ouvertures vides): 0; Nombre de Fenêtres: 0; Nombre de Poteaux: 0; Volume des poteaux: 0 m3; Hauteur maximale de la couche de Mur sur face intérieure: 0 mm; Hauteur minimale de la couche de Mur sur face intérieure: 0 mm; Hauteur maximale de la couche de Mur sur face extérieure: 0 mm; Hauteur minimale de la couche de Mur sur face extérieure: 0 mm; Épaisseur couche d'air: 0 mm; Superficie des portes: 0 m2; Largeur totale des Portes: 0 mm; Épaisseur de composant de mur sur face intérieure: 0 mm; Épaisseur de composant de mur sur face extérieure: 0 mm; Superficie des fenêtres: 0 m2; Largeur totale des Fenêtres: 0 mm; Superficie analytique des ouvertures sur face intérieure: 0 m2; Superficie analytique des ouvertures sur face extérieure: 0 m2; Volume analytique des ouvertures: 0 m3; Épaisseur du Mur à la fin: 50 mm; Superficie des baies libres dans le Mur: 0 m2; Largeur: 50 mm; Décalage supérieur: 0 mm; Épaisseur: 50 mm; Épaisseur couche isolation: 0 mm
Name | In | Emplacement de ligne de référence | Surface de face intérieure = Surface de face extérieure = Surfaces (Toutes) = Surface latérale | Nom d'étage d'implantation | Numéro d'étage d'implantation | Hauteur maximale du Mur (mm) = Hauteur (mm) | Hauteur minimale du Mur (mm) | Longueur moyenne du mur (mm) = Longueur du Mur au centre (mm) | Superficie de la face intérieure du mur (nette) (m2) = Superficie de la face intérieure du mur (conditionnelle) (m2) | Superficie de la face extérieure du mur (nette) (m2) = Superficie de la face extérieure du mur (conditionnelle) (m2) = Superficie en plan (m2) = Superficie inférieure (nette) (m2) | Longueur de ligne de référence (mm) | Longueur de la face intérieure du mur (conditionnelle) (mm) = Longueur de Mur sur face intérieure (mm) | Longueur de la face extérieure du mur (conditionnelle) (mm) = Longueur de Mur sur face extérieure (mm) | Superficie de la face intérieure du mur (brute) (m2) | Superficie de la face extérieure du mur (brute) (m2) | Superficie (m2) = Superficie supérieure (nette) (m2) | Volume (net) (m3) = Volume (conditionnel) (m3) | Altitude à Zéro du Projet (mm) = Altitude de Référence Niveau 1 (mm) = Altitude de Référence Niveau 2 (mm) = Altitude à niveau de la mer (mm) = Altitude inférieure à premier niveau de référence (mm) = Altitude inférieure à Zéro du projet (mm) = Altitude inférieure à niveau de la mer (mm) = Altitude inférieure à deuxième niveau de référence (mm) | Altitude à étage lié/étage d'implantation (mm) = Décalage étage d'implantation (mm) = Altitude inférieure à étage d'implantation (mm) | Longueur 3D (mm) | Volume (brut) (m3) | Périmètre Plan (mm) | Altitude supérieure à premier niveau de référence (mm) = Altitude supérieure à Zéro du projet (mm) = Altitude supérieure à niveau de la mer (mm) = Altitude supérieure à deuxième niveau de référence (mm) | Altitude supérieure à étage d'implantation (mm) | Superficie de l'arête (nette) (m2) | Zones conflictuelles
6 x Mur-153 | Etage 3 | Face extérieure | Bois-Acajou | Etage 3 | 6 | 100 | 0 | 14567.4 | 1.41174 | 1.41174 | 14667.4 | 14567.4 | 14567.4 | 1.41174 | 1.41174 | 0.705873 | 0.0705871 | 11050 | -500 | 14117.4 | 0.0705871 | 29234.8 | 11150 | -400 | 1.42174
9 x Mur-153 | Etage 3 | Face extérieure | Innvik Tex Stripe 1440 | Etage 3 | 6 | 100 | 100 | 2379.78 | 0.207978 | 0.207978 | 2479.78 | 2379.78 | 2379.78 | 0.237978 | 0.237978 | 0.118989 | 0.0118989 | 11050 | -500 | 2379.78 | 0.0118989 | 4859.56 | 11150 | -400 | 0.247978
2 x Mur-153 | Etage 3 | Face extérieure | Innvik Tex Stripe 1440 | Etage 3 | 6 | 150 | 150 | 2429.78 | 0.326967 | 0.371967 | 2479.78 | 2379.78 | 2479.78 | 0.356967 | 0.371967 | 0.121489 | 0.0182234 | 11050 | -500 | 2479.78 | 0.0182234 | 5000.98 | 11200 | -350 | 0.264191
2 x Mur-153 | Etage 3 | Face extérieure | Innvik Tex Stripe 1440 | Etage 3 | 6 | 150 | 150 | 14617.4 | 2.14011 | 2.20011 | 14667.4 | 14567.4 | 14667.4 | 2.18511 | 2.20011 | 0.730871 | 0.109631 | 11050 | -500 | 14667.4 | 0.109631 | 29376.3 | 11200 | -350 | 1.48296
3 x Mur-153 | etage 4 | Face extérieure | Innvik Tex Stripe 1440 | etage 4 | 7 | 100 | 0 | 1385.76 | 0.113576 | 0.113576 | 1435.76 | 1385.76 | 1385.76 | 0.113576 | 0.113576 | 0.0567879 | 0.00567879 | 13986.6 | -613.422 | 1135.76 | 0.00567879 | 2871.51 | 14086.6 | -513.422 | 0.123576 | balcon
2 x Mur-153 | etage 4 | Face extérieure | Innvik Tex Stripe 1440 | etage 4 | 7 | 100 | 1.77636e-12 | 1385.76 | 0.113576 | 0.113576 | 1435.76 | 1385.76 | 1385.76 | 0.113576 | 0.113576 | 0.0567879 | 0.00567879 | 13986.6 | -613.422 | 1135.76 | 0.00567879 | 2871.51 | 14086.6 | -513.422 | 0.123576 | balcon
5 x Mur-153 | etage 4 | Face extérieure | Bois-Acajou | etage 4 | 7 | 100 | 100 | 8771.04 | 0.852104 | 0.852104 | 8821.04 | 8771.04 | 8771.04 | 0.877104 | 0.877104 | 0.438552 | 0.0438552 | 13986.6 | -613.422 | 8771.04 | 0.0438552 | 17642.1 | 14086.6 | -513.422 | 0.887104 | balcon; balcon
Mur-153 | etage 4 | Face extérieure | Innvik Tex Stripe 1440 | etage 4 | 7 | 150 | 134.122 | 1410.76 | 0.215364 | 0.182864 | 1435.76 | 1435.76 | 1385.76 | 0.215364 | 0.207864 | 0.0705379 | 0.0105607 | 13986.6 | -613.422 | 1435.76 | 0.0105807 | 2942.22 | 14136.6 | -463.422 | 0.157921
Mur-153 | etage 4 | Face extérieure | Innvik Tex Stripe 1440 | etage 4 | 7 | 150 | 150 | 8821.04 | 1.29066 | 1.33066 | 8821.04 | 8771.04 | 8871.04 | 1.31566 | 1.33066 | 0.441052 | 0.0661578 | 13986.6 | -613.422 | 8871.04 | 0.0661578 | 17783.5 | 14136.6 | -463.422 | 0.903317 | balcon; balcon
Mur-153 | etage 4 | Face extérieure | Innvik Tex Stripe 1440 | etage 4 | 7 | 150 | 150 | 8871.04 | 1.33066 | 1.33066 | 8871.04 | 8871.04 | 8871.04 | 1.33066 | 1.33066 | 0.443552 | 0.0665328 | 13986.6 | -613.422 | 8871.04 | 0.0665328 | 17842.1 | 14136.6 | -463.422 | 0.902104 | balcon; balcon
Mur-153 | etage 4 | Face extérieure | Innvik Tex Stripe 1440 | etage 4 | 7 | 150 | 134.122 | 1410.76 | 0.182864 | 0.215364 | 1435.76 | 1385.76 | 1435.76 | 0.207864 | 0.215364 | 0.0705379 | 0.0105607 | 13986.6 | -613.422 | 1435.76 | 0.0105807 | 2942.22 | 14136.6 | -463.422 | 0.157921 | balcon
9 x Mur-153 | etage 4 | Face extérieure | Innvik Tex Stripe 1440 | etage 4 | 7 | 100 | 100 | 850 | 0.06 | 0.06 | 950 | 850 | 850 | 0.085 | 0.085 | 0.0425 | 0.00425 | 13986.6 | -613.422 | 850 | 0.00425 | 1800 | 14086.6 | -513.422 | 0.095 | Terrasse
5 x Mur-153 | etage 4 | Face extérieure | Bois-Acajou | etage 4 | 7 | 100 | 0 | 14592.4 | 1.41424 | 1.41424 | 14642.4 | 14592.4 | 14592.4 | 1.41424 | 1.41424 | 0.707121 | 0.0707121 | 13986.6 | -613.422 | 14142.4 | 0.0707121 | 29284.8 | 14086.6 | -513.422 | 1.42424 | Terrasse
Mur-153 | etage 4 | Face extérieure | Innvik Tex Stripe 1440 | etage 4 | 7 | 150 | 150 | 14617.4 | 2.14386 | 2.19636 | 14642.4 | 14592.4 | 14642.4 | 2.18886 | 2.19636 | 0.730871 | 0.109631 | 13986.6 | -613.422 | 14642.4 | 0.109631 | 29355.6 | 14136.6 | -463.422 | 1.47985 | Terrasse
Mur-153 | etage 4 | Face extérieure | Innvik Tex Stripe 1440 | etage 4 | 7 | 150 | 134.122 | 925 | 0.135 | 0.1425 | 950 | 900 | 950 | 0.135 | 0.1425 | 0.04625 | 0.00690409 | 13986.6 | -613.422 | 950 | 0.0069375 | 1970.71 | 14136.6 | -463.422 | 0.108428
Mur-153 | etage 4 | Face extérieure | Innvik Tex Stripe 1440 | etage 4 | 7 | 150 | 134.122 | 14642.4 | 2.14177 | 2.20386 | 14692.4 | 14592.4 | 14692.4 | 2.18886 | 2.20386 | 0.732122 | 0.109791 | 13986.6 | -613.422 | 14692.4 | 0.109818 | 29426.3 | 14136.6 | -463.422 | 1.4853 | Terrasse
2 x Mur-153 | etage 4 | Face extérieure | Innvik Tex Stripe 1440 | etage 4 | 7 | 150 | 134.122 | 900 | 0.1025 | 0.1425 | 950 | 850 | 950 | 0.1275 | 0.1425 | 0.045 | 0.00671675 | 13986.6 | -613.422 | 950 | 0.00675 | 1941.42 | 14136.6 | -463.422 | 0.109008
2 x Mur-153 | etage 4 | Face extérieure | Innvik Tex Stripe 1440 | etage 4 | 7 | 100 | 100 | 850 | 0.06 | 0.06 | 950 | 850 | 850 | 0.085 | 0.085 | 0.0425 | 0.00425 | 13986.6 | -613.422 | 850 | 0.00425 | 1800 | 14086.6 | -513.422 | 0.095
5 x Mur-153 | etage 4 | Face extérieure | Bois-Acajou | etage 4 | 7 | 100 | 0 | 14592.4 | 1.41424 | 1.41424 | 14642.4 | 14592.4 | 14592.4 | 1.41424 | 1.41424 | 0.707121 | 0.0707121 | 13986.6 | -613.422 | 14142.4 | 0.0707121 | 29284.8 | 14086.6 | -513.422 | 1.42424
Mur-153 | etage 4 | Face extérieure | Innvik Tex Stripe 1440 | etage 4 | 7 | 150 | 134.122 | 14642.4 | 2.14177 | 2.20386 | 14692.4 | 14592.4 | 14692.4 | 2.18886 | 2.20386 | 0.732122 | 0.109791 | 13986.6 | -613.422 | 14692.4 | 0.109818 | 29426.3 | 14136.6 | -463.422 | 1.4853
Mur-153 | etage 4 | Face extérieure | Innvik Tex Stripe 1440 | etage 4 | 7 | 150 | 150 | 14617.4 | 2.14386 | 2.19636 | 14642.4 | 14592.4 | 14642.4 | 2.18886 | 2.19636 | 0.730871 | 0.109631 | 13986.6 | -613.422 | 14642.4 | 0.109631 | 29355.6 | 14136.6 | -463.422 | 1.47985
16 x Mur-153 | Etage 5 | Face extérieure | Bois-Acajou | Etage 5 | 8 | 200 | 200 | 6853.85 | 1.36077 | 1.36077 | 6953.85 | 6853.85 | 6853.85 | 1.37077 | 1.37077 | 0.342692 | 0.0685385 | 17650 | 0 | 6853.85 | 0.0685385 | 13807.7 | 17850 | 200 | 0.705385
Mur-153 | Etage 5 | Centre | Innvik Tex Stripe 1440 | Etage 5 | 8 | 200 | 0 | 6158.77 | 1.06175 | 1.06175 | 6258.77 | 6158.77 | 6158.77 | 1.06175 | 1.06175 | 0.265438 | 0.0530877 | 17650 | 0 | 5308.77 | 0.0530877 | 12417.5 | 17850 | 200 | 0.550877
Mur-153 | Etage 5 | Face extérieure | Innvik Tex Stripe 1440 | Etage 5 | 8 | 200 | 200 | 6853.85 | 1.36077 | 1.36077 | 6953.85 | 6853.85 | 6853.85 | 1.37077 | 1.37077 | 0.342692 | 0.0685385 | 17650 | 0 | 6853.85 | 0.0685385 | 13807.7 | 17850 | 200 | 0.705385
2 x Mur-153 | Etage 5 | Face extérieure | Innvik Tex Stripe 1440 | Etage 5 | 8 | 200 | 200 | 6208.77 | 1.06175 | 1.25175 | 6258.77 | 6158.77 | 6258.77 | 1.23175 | 1.25175 | 0.310438 | 0.0620877 | 17650 | 0 | 6258.77 | 0.0620877 | 12559 | 17850 | 200 | 0.649161
2 x Mur-153 | Etage 5 | Face extérieure | Innvik Tex Stripe 1440 | Etage 5 | 8 | 200 | 200 | 6903.85 | 1.36077 | 1.39077 | 6953.85 | 6853.85 | 6953.85 | 1.37077 | 1.39077 | 0.345192 | 0.0690385 | 17650 | 0 | 6953.85 | 0.0690385 | 13949.1 | 17850 | 200 | 0.718669
4 x Mur-153 | Etage 5 | Face extérieure | Bois-Acajou | Etage 5 | 8 | 100 | 100 | 10430 | 1.013 | 1.013 | 10480 | 10430 | 10430 | 1.043 | 1.043 | 0.5215 | 0.05215 | 16948.3 | -701.704 | 10430 | 0.05215 | 20960 | 17048.3 | -601.704 | 1.053 | Terrasse
Mur-153 | Etage 5 | Face extérieure | Innvik Tex Stripe 1440 | Etage 5 | 8 | 150 | 0 | 13083.8 | 1.96581 | 1.91839 | 13108.8 | 13108.8 | 13058.8 | 1.96632 | 1.95882 | 0.654189 | 0.0981049 | 16948.3 | -701.704 | 13108.8 | 0.0981284 | 26288.3 | 17098.3 | -551.704 | 1.31261
Mur-153 | Etage 5 | Face extérieure | Innvik Tex Stripe 1440 | Etage 5 | 8 | 150 | 150 | 10455 | 1.537 | 1.572 | 10480 | 10430 | 10480 | 1.567 | 1.572 | 0.524 | 0.078475 | 16948.3 | -701.704 | 10480 | 0.078475 | 21030.7 | 17098.3 | -551.704 | 1.06507 | Terrasse
6 x Mur-153 | Etage 5 | Centre | Innvik Tex Stripe 1440 | Etage 5 | 8 | 100 | 0 | 2372.44 | 0.217244 | 0.217244 | 2422.44 | 2372.44 | 2372.44 | 0.217244 | 0.217244 | 0.108622 | 0.0108622 | 16948.3 | -701.704 | 2172.44 | 0.0108622 | 4844.88 | 17048.3 | -601.704 | 0.227244 | Terrasse
2 x Mur-153 | Etage 5 | Face extérieure | Innvik Tex Stripe 1440 | Etage 5 | 8 | 150 | 0 | 2555.66 | 0.353178 | 0.390593 | 2605.66 | 2505.66 | 2605.66 | 0.378349 | 0.390849 | 0.129033 | 0.0192193 | 16948.3 | -701.704 | 2605.66 | 0.0192299 | 5252.74 | 17098.3 | -551.704 | 0.271873
8 x Mur-153 | Etage 5 | Face extérieure | Bois-Acajou | Etage 5 | 8 | 100 | 0 | 14295 | 1.3845 | 1.3845 | 14345 | 14295 | 14295 | 1.3845 | 1.3845 | 0.692249 | 0.069225 | 16948.3 | -701.704 | 13845 | 0.069225 | 28690 | 17048.3 | -601.704 | 1.3945 | Terrasse
2 x Mur-153 | Etage 5 | Face extérieure | Innvik Tex Stripe 1440 | Etage 5 | 8 | 100 | 100 | 16142.4 | 1.56174 | 1.61674 | 16167.4 | 16117.4 | 16167.4 | 1.61174 | 1.61674 | 0.807122 | 0.0807122 | 16948.3 | -701.704 | 16167.4 | 0.0807122 | 32405.6 | 17048.3 | -601.704 | 1.62631 | Terrasse
2 x Mur-153 | Etage 5 | Face extérieure | Bois-Acajou | Etage 5 | 8 | 100 | 0 | 14320 | 1.3895 | 1.3845 | 14345 | 14345 | 14295 | 1.3895 | 1.3845 | 0.6935 | 0.06935 | 16948.3 | -701.704 | 13895 | 0.06935 | 28760.7 | 17048.3 | -601.704 | 1.39907 | Terrasse
9 x Mur-153 | Etage 5 | Face extérieure | Innvik Tex Stripe 1440 | Etage 5 | 8 | 100 | 100 | 2505.66 | 0.225566 | 0.225566 | 2605.66 | 2505.66 | 2505.66 | 0.250566 | 0.250566 | 0.125283 | 0.0125283 | 16948.3 | -701.704 | 2505.66 | 0.0125283 | 5111.32 | 17048.3 | -601.704 | 0.260566 | Terrasse
2 x Mur-153 | Etage 5 | Face extérieure | Innvik Tex Stripe 1440 | Etage 5 | 8 | 100 | 0 | 2505.66 | 0.225396 | 0.225396 | 2605.66 | 2505.66 | 2505.66 | 0.250566 | 0.250566 | 0.125283 | 0.0125198 | 16948.3 | -701.704 | 2505.66 | 0.0125283 | 5111.32 | 17048.3 | -601.704 | 0.255481 | Terrasse
Mur-153 | Etage 5 | Face extérieure | Innvik Tex Stripe 1440 | Etage 5 | 8 | 100 | 0 | 2397.44 | 0.217073 | 0.242073 | 2422.44 | 2372.44 | 2422.44 | 0.237244 | 0.242244 | 0.119872 | 0.0119787 | 16948.3 | -701.704 | 2422.44 | 0.0119872 | 4915.59 | 17048.3 | -601.704 | 0.24673 | Terrasse
2 x Mur-153 | Etage 5 | Face extérieure | Innvik Tex Stripe 1440 | Etage 5 | 8 | 150 | 0 | 16167.4 | 2.37176 | 2.43159 | 16167.4 | 16117.4 | 16217.4 | 2.41762 | 2.43262 | 0.808371 | 0.121209 | 16948.3 | -701.704 | 16217.4 | 0.121256 | 32476.3 | 17098.3 | -551.704 | 1.61022
Mur-153 | Etage 5 | Face extérieure | Bois-Acajou | Etage 5 | 8 | 100 | 100 | 725 | 0.075 | 0.05 | 750 | 750 | 700 | 0.075 | 0.07 | 0.03625 | 0.003625 | 16948.3 | -701.704 | 750 | 0.003625 | 1570.71 | 17048.3 | -601.704 | 0.0845711 | Terrasse
10 x Mur-153 | toiture | Face extérieure | Bois-Acajou | toiture | 9 | 100 | 0 | 11420.5 | 1.10705 | 1.10705 | 11520.5 | 11420.5 | 11420.5 | 1.13705 | 1.13705 | 0.568525 | 0.0568525 | 20286 | -63.9782 | 11370.5 | 0.0568525 | 22941 | 20386 | 36.0218 | 1.14705
Mur-153 | toiture | Face extérieure | Innvik Tex Stripe 1440 | toiture | 9 | 150 | 63.9782 | 900 | 0.1025 | 0.1425 | 950 | 850 | 950 | 0.1275 | 0.1425 | 0.045 | 0.00665412 | 20286 | -63.9782 | 950 | 0.00675 | 1941.42 | 20436 | 86.0218 | 0.109416
2 x Mur-153 | toiture | Face extérieure | Innvik Tex Stripe 1440 | toiture | 9 | 150 | 150 | 11470.5 | 1.67808 | 1.72808 | 11520.5 | 11420.5 | 11520.5 | 1.71308 | 1.72808 | 0.573525 | 0.0860288 | 20286 | -63.9782 | 11520.5 | 0.0860288 | 23082.4 | 20436 | 86.0218 | 1.16826
8 x Mur-153 | toiture | Face extérieure | Innvik Tex Stripe 1440 | toiture | 9 | 100 | 0 | 850 | 0.06 | 0.06 | 950 | 850 | 850 | 0.06 | 0.06 | 0.03 | 0.00297958 | 20286 | -63.9782 | 600 | 0.003 | 1800 | 20386 | 36.0218 | 0.0679494
2 x Mur-153 | toiture | Face extérieure | Innvik Tex Stripe 1440 | toiture | 9 | 150 | 63.9782 | 900 | 0.1025 | 0.1425 | 950 | 850 | 950 | 0.1275 | 0.1425 | 0.045 | 0.00665621 | 20286 | -63.9782 | 950 | 0.00675 | 1941.42 | 20436 | 86.0218 | 0.109294
2 x Mur-153 | toiture | Face extérieure | Innvik Tex Stripe 1440 | toiture | 9 | 150 | 63.9782 | 11470.5 | 1.67167 | 1.72808 | 11520.5 | 11420.5 | 11520.5 | 1.71308 | 1.72808 | 0.573525 | 0.0858628 | 20286 | -63.9782 | 11520.5 | 0.0860288 | 23082.4 | 20436 | 86.0218 | 1.1669
Mur-153 | toiture | Face extérieure | Innvik Tex Stripe 1440 | toiture | 9 | 100 | 63.9782 | 850 | 0.06 | 0.06 | 950 | 850 | 850 | 0.085 | 0.085 | 0.0425 | 0.00422958 | 20286 | -63.9782 | 850 | 0.00425 | 1800 | 20386 | 36.0218 | 0.0929494
44 x Mur-153 | toiture2 | Face extérieure | Bois-Acajou | toiture2 | 10 | 200 | 200 | 7262.02 | 1.4424 | 1.4424 | 7362.02 | 7262.02 | 7262.02 | 1.4524 | 1.4524 | 0.363101 | 0.0726202 | 22800 | -250 | 7262.02 | 0.0726202 | 14624 | 23000 | -50 | 0.746202 | Terrasse/eng.
2 x Mur-153 | toiture2 | Face extérieure | Bois-Acajou | toiture2 | 10 | 200 | 0 | 7287.02 | 1.4324 | 1.4524 | 7362.02 | 7262.02 | 7312.02 | 1.4424 | 1.4524 | 0.361851 | 0.0723702 | 22800 | -250 | 7262.02 | 0.0723702 | 14694.8 | 23000 | -50 | 0.747844 | Terrasse/eng.
4 x Mur-153 | toiture2 | Face extérieure | Innvik Tex Stripe 1440 | toiture2 | 10 | 200 | 200 | 7312.02 | 1.4424 | 1.4724 | 7362.02 | 7262.02 | 7362.02 | 1.4524 | 1.4724 | 0.365601 | 0.0731202 | 22800 | -250 | 7362.02 | 0.0731202 | 14765.5 | 23000 | -50 | 0.759486 | Terrasse/eng.
2 x Mur-153 | toiture2 | Face extérieure | Innvik Tex Stripe 1440 | toiture2 | 10 | 200 | 200 | 4150 | 0.715 | 0.835 | 4175 | 4125 | 4175 | 0.825 | 0.835 | 0.2075 | 0.0415 | 22800 | -250 | 4175 | 0.0415 | 8420.71 | 23000 | -50 | 0.439142 | Terrasse/eng.
2 x Mur-153 | toiture2 | Face extérieure | Innvik Tex Stripe 1440 | toiture2 | 10 | 200 | 200 | 4150 | 0.705 | 0.835 | 4175 | 4125 | 4175 | 0.825 | 0.835 | 0.2075 | 0.0415 | 22800 | -250 | 4175 | 0.0415 | 8420.71 | 23000 | -50 | 0.439142 | Terrasse/eng.
Mur-153 | toiture2 | Face extérieure | Innvik Tex Stripe 1440 | toiture2 | 10 | 200 | 200 | 4049.34 | 0.694869 | 0.814869 | 4074.34 | 4024.34 | 4074.34 | 0.804869 | 0.814869 | 0.202467 | 0.0404934 | 22800 | -250 | 4074.34 | 0.0404934 | 8219.4 | 23000 | -50 | 0.429077 | Terrasse/eng.
Mur-153 | toiture2 | Centre | Innvik Tex Stripe 1440 | toiture2 | 10 | 200 | 0 | 4125 | 0.705 | 0.705 | 4175 | 4125 | 4125 | 0.715 | 0.715 | 0.17875 | 0.03575 | 22800 | -250 | 3575 | 0.03575 | 8350 | 23000 | -50 | 0.3775 | Terrasse/eng.
Mur-153 | toiture2 | Face extérieure | Innvik Tex Stripe 1440 | toiture2 | 10 | 200 | 200 | 4125 | 0.705 | 0.835 | 4175 | 4075 | 4175 | 0.815 | 0.835 | 0.20625 | 0.04125 | 22800 | -250 | 4175 | 0.04125 | 8391.42 | 23000 | -50 | 0.440784 | Terrasse/eng.
Mur-153 | toiture2 | Centre | Innvik Tex Stripe 1440 | toiture2 | 10 | 200 | 0 | 4075 | 0.705 | 0.705 | 4175 | 4075 | 4075 | 0.705 | 0.705 | 0.17625 | 0.03525 | 22800 | -250 | 3525 | 0.03525 | 8250 | 23000 | -50 | 0.3725 | Terrasse/eng.

# IfcWallStandardCase: 100 % 282141195 65 (5)
In: rdc
Classification: Mur (Classification ARCHICAD); Material: 100 % 282141195 65.1528 mm
AC_Pset_RenovationAndPhasing - Renovation Status: Existing
ArchiCADQuantities - Nombre de Portes: 0; Nombre de trous (Nombre d'ouvertures vides): 0; Nombre de Fenêtres: 0; Volume des poteaux: 0 m3; Hauteur maximale de la couche de Mur sur face intérieure: 0 mm; Hauteur minimale de la couche de Mur sur face intérieure: 0 mm; Hauteur maximale de la couche de Mur sur face extérieure: 0 mm; Hauteur minimale de la couche de Mur sur face extérieure: 0 mm; Épaisseur couche d'air: 0 mm; Superficie des portes: 0 m2; Largeur totale des Portes: 0 mm; Épaisseur de composant de mur sur face intérieure: 0 mm; Épaisseur de composant de mur sur face extérieure: 0 mm; Superficie des fenêtres: 0 m2; Largeur totale des Fenêtres: 0 mm; Superficie analytique des ouvertures sur face intérieure: 0 m2; Superficie analytique des ouvertures sur face extérieure: 0 m2; Volume analytique des ouvertures: 0 m3; Épaisseur du Mur à la fin: 65.1528 mm; Superficie des baies libres dans le Mur: 0 m2; Largeur: 65.1528 mm; Décalage supérieur: 0 mm; Épaisseur: 65.1528 mm; Épaisseur couche isolation: 0 mm
ArchiCADProperties - Complexité de mur: Droit; Option de géométrie: Uniforme; Angle d'inclinaison interne de mur: 90 deg; Angle d'inclinaison externe de mur: 90 deg; ID de l'élément: Mur-153; Lien et ID d'élément: Mur-153; Calque: Interieurs logements; Matériau de construction / Composite / Profil / Hachure: 100 % 282141195; Matériau de construction: 100 % 282141195; Verrouillé: no; Nom d'étage d'implantation: rdc; Numéro d'étage d'implantation: 3; Type d'élément: Mur; Étage supérieur lié absolu: Non lié; Étage supérieur lié relatif: Non lié; Étage supérieur lié: Non lié; Type de structure: Basique; ID de Parent: Mur-153; Matériaux de construction (Tous): 100 % 282141195; Angle d'inclinaison: 90 deg; Nombre de percements: 0; Nom de Variante: Modèle principal; Nom de Jeu de Variantes: Modèle principal; Position: Non défini; Fonction structurelle: Non défini; Affichage sur filtre de rénovation: Tous les filtres appropriés; État de rénovation: Existant; État de Variante: Modèle principal; Jeu de Variantes: Modèle principal
Name | Nombre de Poteaux | Hauteur maximale du Mur (mm) = Hauteur (mm) | Hauteur minimale du Mur (mm) | Longueur moyenne du mur (mm) = Longueur du Mur au centre (mm) | Superficie de la face intérieure du mur (nette) (m2) = Superficie de la face intérieure du mur (conditionnelle) (m2) | Superficie de la face extérieure du mur (nette) (m2) = Superficie de la face extérieure du mur (conditionnelle) (m2) = Superficie en plan (m2) = Superficie inférieure (nette) (m2) | Longueur de ligne de référence (mm) | Longueur de la face intérieure du mur (conditionnelle) (mm) = Longueur de Mur sur face intérieure (mm) | Longueur de la face extérieure du mur (conditionnelle) (mm) = Longueur de Mur sur face extérieure (mm) | Superficie de la face intérieure du mur (brute) (m2) | Superficie de la face extérieure du mur (brute) (m2) | Superficie (m2) = Superficie supérieure (nette) (m2) | Volume (net) (m3) = Volume (conditionnel) (m3) | Altitude à Zéro du Projet (mm) = Altitude de Référence Niveau 1 (mm) = Altitude de Référence Niveau 2 (mm) = Altitude à niveau de la mer (mm) = Altitude inférieure à premier niveau de référence (mm) = Altitude inférieure à Zéro du projet (mm) = Altitude inférieure à niveau de la mer (mm) = Altitude inférieure à deuxième niveau de référence (mm) | Altitude à étage lié/étage d'implantation (mm) = Décalage étage d'implantation (mm) = Altitude inférieure à étage d'implantation (mm) | Longueur 3D (mm) | Volume (brut) (m3) | Périmètre Plan (mm) | Altitude supérieure à premier niveau de référence (mm) = Altitude supérieure à Zéro du projet (mm) = Altitude supérieure à niveau de la mer (mm) = Altitude supérieure à deuxième niveau de référence (mm) | Altitude supérieure à étage d'implantation (mm) | Superficie de l'arête (nette) (m2) | Emplacement de ligne de référence | Surface de face intérieure = Surface de face extérieure = Surfaces (Toutes) = Surface latérale
Mur-153 | 2 | 307.905 | 0 | 4171.54 | 1.24607 | 1.3045 | 4204.12 | 4106.39 | 4236.7 | 1.27141 | 1.3045 | 0.272668 | 0.0825275 | 5392.1 | 2392.1 | 4236.7 | 0.0839138 | 8527.36 | 5700 | 2700 | 0.580007 | Face extérieure | Innvik Tex Stripe 1440
Mur-153 | 0 | 200 | 200 | 4206.59 | 0.821773 | 0.847834 | 4239.17 | 4174.02 | 4239.17 | 0.834803 | 0.847834 | 0.274071 | 0.0548143 | 5500 | 2500 | 4239.17 | 0.0548143 | 8570.48 | 5700 | 2700 | 0.579601 | Face extérieure | Innvik Tex Stripe 1440
Mur-153 | 0 | 100 | 100 | 4106.39 | 0.410639 | 0.410639 | 4204.12 | 4106.39 | 4106.39 | 0.410639 | 0.410639 | 0.267543 | 0.0267543 | 5500 | 2500 | 4106.39 | 0.0267543 | 8343.09 | 5600 | 2600 | 0.548116 | Face extérieure | Bois-Acajou
Mur-153 | 2 | 307.905 | 0 | 4555.46 | 1.37262 | 1.38734 | 4653.19 | 4522.88 | 4588.04 | 1.39965 | 1.41971 | 0.298282 | 0.0898675 | 5392.1 | 2392.1 | 4610.76 | 0.0918445 | 9268.21 | 5700 | 2700 | 0.621885 | Centre | Innvik Tex Stripe 1440
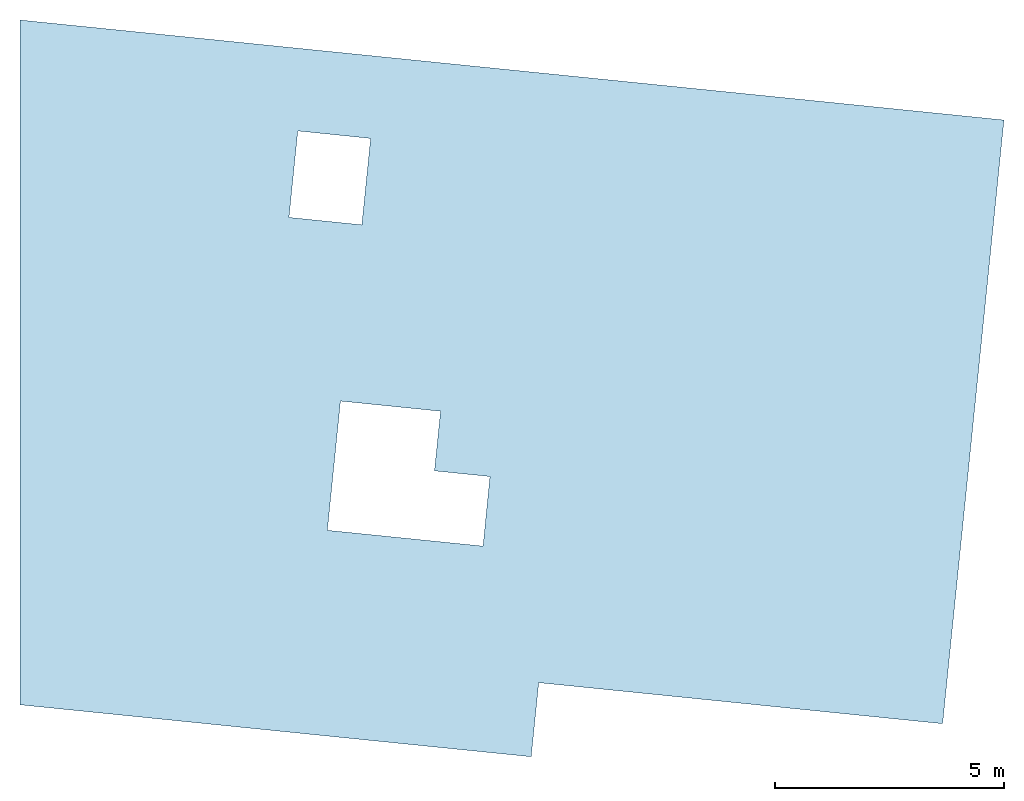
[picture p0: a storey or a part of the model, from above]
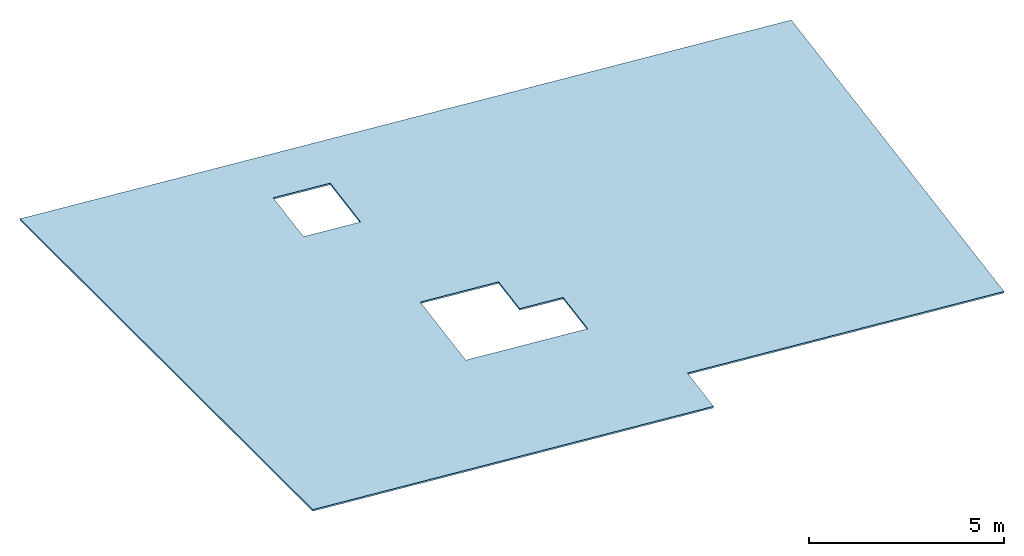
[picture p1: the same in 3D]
Properties of the parts of a building model (IFC2X3), part 20 of 44

# IfcWallStandardCase: 100 % 282141195 65 (5)
Name | Nombre de Poteaux | Hauteur maximale du Mur (mm) = Hauteur (mm) | Hauteur minimale du Mur (mm) | Longueur moyenne du mur (mm) = Longueur du Mur au centre (mm) | Superficie de la face intérieure du mur (nette) (m2) = Superficie de la face intérieure du mur (conditionnelle) (m2) | Superficie de la face extérieure du mur (nette) (m2) = Superficie de la face extérieure du mur (conditionnelle) (m2) = Superficie en plan (m2) = Superficie inférieure (nette) (m2) | Longueur de ligne de référence (mm) | Longueur de la face intérieure du mur (conditionnelle) (mm) = Longueur de Mur sur face intérieure (mm) | Longueur de la face extérieure du mur (conditionnelle) (mm) = Longueur de Mur sur face extérieure (mm) | Superficie de la face intérieure du mur (brute) (m2) | Superficie de la face extérieure du mur (brute) (m2) | Superficie (m2) = Superficie supérieure (nette) (m2) | Volume (net) (m3) = Volume (conditionnel) (m3) | Altitude à Zéro du Projet (mm) = Altitude de Référence Niveau 1 (mm) = Altitude de Référence Niveau 2 (mm) = Altitude à niveau de la mer (mm) = Altitude inférieure à premier niveau de référence (mm) = Altitude inférieure à Zéro du projet (mm) = Altitude inférieure à niveau de la mer (mm) = Altitude inférieure à deuxième niveau de référence (mm) | Altitude à étage lié/étage d'implantation (mm) = Décalage étage d'implantation (mm) = Altitude inférieure à étage d'implantation (mm) | Longueur 3D (mm) | Volume (brut) (m3) | Périmètre Plan (mm) | Altitude supérieure à premier niveau de référence (mm) = Altitude supérieure à Zéro du projet (mm) = Altitude supérieure à niveau de la mer (mm) = Altitude supérieure à deuxième niveau de référence (mm) | Altitude supérieure à étage d'implantation (mm) | Superficie de l'arête (nette) (m2) | Emplacement de ligne de référence | Surface de face intérieure = Surface de face extérieure = Surfaces (Toutes) = Surface latérale
Mur-153 | 0 | 200 | 200 | 4588.04 | 0.904577 | 0.930638 | 4653.19 | 4522.88 | 4653.19 | 0.904577 | 0.930638 | 0.298923 | 0.0597847 | 5500 | 2500 | 4653.19 | 0.0597847 | 9360.35 | 5700 | 2700 | 0.634703 | Face extérieure | Innvik Tex Stripe 1440

# IfcWallStandardCase: Beton 18 0018356637 180 (140)
Classification: Mur (Classification ARCHICAD); Material: Parpaing 314940890 180 mm
ArchiCADQuantities - Nombre de Fenêtres: 0; Nombre de Poteaux: 0; Volume des poteaux: 0 m3; Épaisseur couche d'air: 0 mm; Épaisseur de composant de mur sur face intérieure: 180 mm; Épaisseur de composant de mur sur face extérieure: 180 mm; Superficie des fenêtres: 0 m2; Largeur totale des Fenêtres: 0 mm; Épaisseur du Mur à la fin: 180 mm; Largeur: 180 mm; Décalage supérieur: 0 mm; Épaisseur: 180 mm; Épaisseur couche isolation: 0 mm
ArchiCADProperties - Complexité de mur: Droit; Option de géométrie: Uniforme; Angle d'inclinaison interne de mur: 90 deg; Angle d'inclinaison externe de mur: 90 deg; Matériau de construction / Composite / Profil / Hachure: Beton 18 0018356637; Structure Composite: Beton 18 0018356637; Verrouillé: no; Type d'élément: Mur; Étage supérieur lié absolu: Non lié; Étage supérieur lié relatif: Non lié; Étage supérieur lié: Non lié; Type de structure: Composite; Matériaux de construction (Tous): Parpaing 314940890; Angle d'inclinaison: 90 deg; Nombre de percements: 0; Nom de Variante: Modèle principal; Nom de Jeu de Variantes: Modèle principal; Position: Non défini; Fonction structurelle: Non défini; Affichage sur filtre de rénovation: Tous les filtres appropriés; État de rénovation: Existant; État de Variante: Modèle principal; Jeu de Variantes: Modèle principal
AC_Pset_RenovationAndPhasing - Renovation Status: Existing
Name | In | Nombre de Portes | Nombre de trous (Nombre d'ouvertures vides) | Hauteur maximale de la couche de Mur sur face intérieure (mm) = Hauteur maximale du Mur (mm) = Hauteur maximale de la couche de Mur sur face extérieure (mm) = Hauteur (mm) | Hauteur minimale de la couche de Mur sur face intérieure (mm) = Hauteur minimale du Mur (mm) = Hauteur minimale de la couche de Mur sur face extérieure (mm) | Superficie des portes (m2) | Largeur totale des Portes (mm) | Volume de composant de mur sur face intérieure (net) (m3) = Volume de composant de mur sur face extérieure (net) (m3) | Superficie analytique des ouvertures sur face intérieure (m2) | Superficie analytique des ouvertures sur face extérieure (m2) | Longueur moyenne du mur (mm) = Longueur du Mur au centre (mm) | Superficie de la face intérieure du mur (nette) (m2) | Superficie de la face extérieure du mur (nette) (m2) = Superficie en plan (m2) = Superficie inférieure (nette) (m2) | Volume analytique des ouvertures (m3) | Longueur de ligne de référence (mm) | Longueur de la face intérieure du mur (conditionnelle) (mm) | Superficie de la face intérieure du mur (conditionnelle) (m2) | Longueur de la face extérieure du mur (conditionnelle) (mm) | Superficie de la face extérieure du mur (conditionnelle) (m2) | Volume du composant face intérieure du mur (conditionnel) (m3) = Volume du composant face extérieure du mur (conditionnel) (m3) | Superficie de la face intérieure du mur (brute) (m2) | Superficie de la face extérieure du mur (brute) (m2) | Longueur de Mur sur face intérieure (mm) | Longueur de Mur sur face extérieure (mm) | Superficie des baies libres dans le Mur (m2) | Superficie (m2) = Superficie supérieure (nette) (m2) | Volume (net) (m3) | Altitude à Zéro du Projet (mm) = Altitude de Référence Niveau 1 (mm) = Altitude de Référence Niveau 2 (mm) = Altitude à niveau de la mer (mm) = Altitude inférieure à premier niveau de référence (mm) = Altitude inférieure à Zéro du projet (mm) = Altitude inférieure à niveau de la mer (mm) = Altitude inférieure à deuxième niveau de référence (mm) | Altitude à étage lié/étage d'implantation (mm) = Décalage étage d'implantation (mm) | Longueur 3D (mm) | Volume (conditionnel) (m3) | Volume (brut) (m3) | Périmètre Plan (mm) | Altitude supérieure à premier niveau de référence (mm) = Altitude supérieure à Zéro du projet (mm) = Altitude supérieure à niveau de la mer (mm) = Altitude supérieure à deuxième niveau de référence (mm) | Altitude supérieure à étage d'implantation (mm) | Altitude inférieure à étage d'implantation (mm) | Superficie de l'arête (nette) (m2) | Emplacement de ligne de référence | Surface de face intérieure = Surface de face extérieure = Surfaces (Toutes) = Surface latérale | ID de l'élément = Lien et ID d'élément = ID de Parent | Calque | Nom de zone liée | Numéro de zone liée | Nom d'étage d'implantation | Numéro d'étage d'implantation
Mur-143 | rdc | 0 | 0 | 2500 | 2300 | 0 | 0 | 0.396034 | 0 | 0 | 956.544 | 2.28064 | 2.13578 | 0 | 1026.6 | 956.49 | 2.28064 | 956.598 | 2.13578 | 0.396034 | 2.39122 | 2.3915 | 956.49 | 956.598 | 0 | 0.172178 | 0.396034 | 3000 | 0 | 956.598 | 0.396034 | 0.430445 | 2273.09 | 5500 | 2500 | 0 | 1.0004 | Face extérieure | Peinture-01 | Mur-143 | Interieurs logements | Ch 2 | B04 | rdc | 3
Mur-142 | rdc | 2 | 0 | 2750 | 2750 | 4 | 2000 | 1.03513 | 4.1004 | 4.1004 | 3582.23 | 5.25573 | 6.24573 | 0.738072 | 3762.23 | 3402.23 | 5.25573 | 3762.23 | 6.24573 | 1.7732 | 9.35613 | 10.3461 | 3402.23 | 3762.23 | 0 | 0.644801 | 1.03513 | 2400 | -600 | 3762.23 | 1.7732 | 1.7732 | 7673.57 | 5150 | 2150 | -600 | 2.68967 | Face extérieure | Peinture-01 | Mur-142 | Interieurs logements |  |  | rdc | 3
Mur-142 | rdc | 0 | 0 | 3014.87 | 3014.87 | 0 | 0 | 1.09895 | 0 | 0 | 2017.15 | 5.58646 | 6.62414 | 0 | 2197.15 | 1837.15 | 5.58646 | 2197.15 | 6.62414 | 1.09895 | 5.58646 | 6.62414 | 1837.15 | 2197.15 | 0 | 0.379288 | 1.09895 | 2135.13 | -864.872 | 2197.15 | 1.09895 | 1.09895 | 4543.42 | 5150 | 2150 | -864.872 | 2.27375 | Face extérieure | Peinture-01 | Mur-142 | Interieurs logements |  |  | rdc | 3
Mur-143 | rdc | 0 | 0 | 2700 | 0 | 0 | 0 | 3.32074 | 0 | 0 | 6832.91 | 18.0955 | 17.6682 | 0 | 7445.51 | 6842.06 | 18.0955 | 6823.76 | 17.6682 | 3.32074 | 18.4735 | 18.2352 | 6842.06 | 6823.76 | 0 | 1.2299 | 3.32074 | 3000 | 0 | 6842.06 | 3.32074 | 3.32074 | 14026.7 | 5700 | 2700 | 0 | 3.43431 | Face extérieure | Peinture-01 | Mur-143 | Interieurs logements | Entree | A01 | rdc | 3 | ArchiCADProperties - Zones conflictuelles: Sdb/pl
Mur-143 | rdc | 0 | 0 | 2700 | 4.44089e-13 | 0 | 0 | 1.69968 | 0 | 0 | 3497.33 | 9.44279 | 9.25379 | 0 | 3777.33 | 3497.33 | 9.44279 | 3497.33 | 9.25379 | 1.69968 | 9.44279 | 9.25379 | 3497.33 | 3497.33 | 0 | 0.62951 | 1.69968 | 3000 | 0 | 3497.38 | 1.69968 | 1.69968 | 7354.66 | 5700 | 2700 | -4.44089e-13 | 2.23102 | Face extérieure | Peinture-01 | Mur-143 | Interieurs logements | Sejour Cuisine | A02 | rdc | 3
Mur-142 | rdc | 0 | 0 | 3014.87 | 3014.87 | 0 | 0 | 1.94399 | 0 | 0 | 3582.23 | 10.2573 | 11.3426 | 0 | 3762.23 | 3402.23 | 10.2573 | 3762.23 | 11.3426 | 1.94399 | 10.2573 | 11.3426 | 3402.23 | 3762.23 | 0 | 0.644801 | 1.94399 | 2135.13 | -864.872 | 3762.23 | 1.94399 | 1.94399 | 7673.57 | 5150 | 2150 | -864.872 | 2.82452 | Face extérieure | Peinture-01 | Mur-142 | Interieurs logements |  |  | rdc | 3
Mur-142 | rdc | 0 | 0 | 3014.87 | 464.872 | 0 | 0 | 1.09895 | 0 | 0 | 2017.15 | 5.58646 | 6.61385 | 0 | 2197.15 | 1837.15 | 5.58646 | 2197.15 | 6.61385 | 1.09895 | 5.58646 | 6.61385 | 1837.15 | 2197.15 | 0 | 0.379288 | 1.09895 | 2135.13 | -864.872 | 2197.15 | 1.09895 | 1.09895 | 4543.42 | 5150 | 2150 | -864.872 | 2.27375 | Face extérieure | Peinture-01 | Mur-142 | Interieurs logements |  |  | rdc | 3
Mur-142 | rdc | 0 | 0 | 3000 | 3000 | 0 | 0 | 0.215967 | 0 | 0 | 399.94 | 1.19975 | 1.19989 | 0 | 399.964 | 399.916 | 1.19975 | 399.964 | 1.19989 | 0.215967 | 1.19975 | 1.19989 | 399.916 | 399.964 | 0 | 0.0719892 | 0.215967 | 3000 | 0 | 579.916 | 0.215967 | 0.215967 | 1308.96 | 6000 | 3000 | 0 | 1.67123 | Face extérieure | Peinture-01 | Mur-142 | Interieurs logements | Sejour cuisine | A03 | rdc | 3
Mur-143 | rdc | 2 | 0 | 2750 | 2750 | 3.7944 | 1860 | 1.80455 | 4.2016 | 4.2016 | 5177.59 | 9.13428 | 10.1603 | 0.756288 | 4947.59 | 3107.59 | 9.13428 | 3207.59 | 10.1603 | 2.56084 | 14.0919 | 14.3619 | 5127.59 | 5227.59 | 0 | 0.568367 | 1.80455 | 3000 | 0 | 5407.59 | 2.56084 | 2.56084 | 10942.6 | 5750 | 2750 | 0 | 3.10438 | Face extérieure | Peinture-01 | Mur-143 | Interieurs logements | Entree/pl | A02 | rdc | 3
Mur-142 | rdc | 1 | 0 | 2700 | 0 | 1.8972 | 930 | 0.349236 | 2.1008 | 2.1008 | 1670 | 2.1652 | 1.7152 | 0.378144 | 1580 | 750 | 2.1652 | 570 | 1.7152 | 0.72738 | 4.266 | 3.816 | 1760 | 1580 | 0 | 0.1188 | 0.349236 | 3000 | 0 | 1760 | 0.72738 | 0.72738 | 3774.56 | 5700 | 2700 | 0 | 1.5454 | Face extérieure | Peinture-01 | Mur-142 | Interieurs logements | Entree/pl | B04 | rdc | 3
Mur-133 | rdc | 0 | 0 | 1500 | 0 | 0 | 0 | 1.42559 | 0 | 0 | 5331.31 | 8.05448 | 7.86197 | 0 | 5241.31 | 5421.31 | 8.05448 | 5241.31 | 7.86197 | 1.42559 | 8.13197 | 7.86197 | 5421.31 | 5241.31 | 0 | 0.959636 | 1.42559 | 2500 | -500 | 5421.31 | 1.42559 | 1.43945 | 11097.2 | 4000 | 1000 | -500 | 2.33985 | Face extérieure | Peinture-01 | Mur-133 | 3D |  |  | rdc | 3
Mur-136 | rdc | 0 | 0 | 1500 | 0 | 0 | 0 | 0.3726 | 0 | 0 | 1380 | 2.34 | 1.8 | 0 | 1200 | 1560 | 2.34 | 1200 | 1.8 | 0.3726 | 2.34 | 1.8 | 1560 | 1200 | 0 | 0.2484 | 0.3726 | 2500 | -500 | 1560 | 0.3726 | 0.3726 | 3269.12 | 4000 | 1000 | -500 | 1.26033 | Face extérieure | Peinture-01 | Mur-136 | 3D |  |  | rdc | 3
Mur-134 | rdc | 0 | 0 | 1500 | 1500 | 0 | 0 | 1.78775 | 0 | 0 | 6621.31 | 10.202 | 9.66197 | 0 | 6441.31 | 6801.31 | 10.202 | 6441.31 | 9.66197 | 1.78775 | 10.202 | 9.66197 | 6801.31 | 6441.31 | 0 | 1.19184 | 1.78775 | 2500 | -500 | 6801.31 | 1.78775 | 1.78775 | 13751.7 | 4000 | 1000 | -500 | 3.14735 | Face extérieure | Peinture-01 | Mur-134 | 3D |  |  | rdc | 3
Mur-134 | rdc | 0 | 0 | 1500 | 1500 | 0 | 0 | 0.3969 | 0 | 0 | 1470 | 2.34 | 2.07 | 0 | 1380 | 1560 | 2.34 | 1380 | 2.07 | 0.3969 | 2.34 | 2.07 | 1560 | 1380 | 0 | 0.2646 | 0.3969 | 2500 | -500 | 1560 | 0.3969 | 0.3969 | 3374.56 | 4000 | 1000 | -500 | 1.18104 | Face extérieure | Peinture-01 | Mur-134 | 3D |  |  | rdc | 3
Mur-142 | rdc | 0 | 0 | 3000 | 0 | 0 | 0 | 1.95733 | 0 | 0 | 3736.69 | 11.126 | 10.6041 | 0 | 3926.69 | 3826.69 | 11.126 | 3646.69 | 10.6041 | 1.95733 | 11.144 | 10.6041 | 3826.69 | 3646.69 | 0 | 0.697799 | 1.95733 | 3000 | 0 | 3966.74 | 1.95733 | 1.95733 | 7907.9 | 6000 | 3000 | 0 | 2.69917 | Face extérieure | Peinture-01 | Mur-142 | Interieurs logements | Sejour cuisine | A03 | rdc | 3 | ArchiCADProperties - Zones conflictuelles: Sejour cuisine
Mur-142 | rdc | 1 | 0 | 3000 | 3000 | 1.8972 | 930 | 0.44644 | 2.1008 | 2.1008 | 1509.01 | 2.21029 | 2.75016 | 0.378144 | 1778.99 | 409.035 | 2.21029 | 588.987 | 2.75016 | 0.824584 | 4.31109 | 4.85096 | 1419.03 | 1598.99 | 0 | 0.122218 | 0.44644 | 3000 | 0 | 1778.99 | 0.824584 | 0.824584 | 3452.58 | 6000 | 3000 | 0 | 1.72991 | Face extérieure | Peinture-01 | Mur-142 | Interieurs logements | Sejour cuisine | A03 | rdc | 3
Mur-142 | rdc | 0 | 0 | 2500 | 0 | 0 | 0 | 3.22115 | 0 | 0 | 7338.11 | 17.5453 | 17.5453 | 0 | 7678.11 | 7338.11 | 17.5453 | 7338.11 | 17.5453 | 3.22115 | 17.8953 | 17.8953 | 7338.11 | 7338.11 | 0 | 1.28846 | 3.22115 | 3000 | 0 | 7158.11 | 3.22115 | 3.22115 | 15036.2 | 5500 | 2500 | 0 | 3.47692 | Face extérieure | Peinture-01 | Mur-142 | Interieurs logements | Ch 1 | B01 | rdc | 3 | ArchiCADProperties - Zones conflictuelles: Sdb
Mur-143 | rdc | 0 | 0 | 2750 | 2750 | 0 | 0 | 1.74207 | 0 | 0 | 3511.16 | 9.90318 | 9.45318 | 0 | 3941.16 | 3601.16 | 9.90318 | 3421.16 | 9.45318 | 1.74207 | 9.90318 | 9.45318 | 3601.16 | 3421.16 | 0 | 0.648208 | 1.74207 | 3000 | 0 | 3601.16 | 1.74207 | 1.74207 | 7456.87 | 5750 | 2750 | 0 | 2.47281 | Face extérieure | Peinture-01 | Mur-143 | Interieurs logements |  |  | rdc | 3
Mur-142 | rdc | 0 | 0 | 2700 | 2700 | 0 | 0 | 1.89799 | 0 | 0 | 3881.62 | 10.5443 | 10.5444 | 0 | 4381.63 | 3881.61 | 10.5443 | 3881.63 | 10.5444 | 1.89799 | 10.5443 | 10.5444 | 3881.61 | 3881.63 | 0 | 0.756291 | 1.89799 | 3000 | 0 | 4201.63 | 1.89799 | 1.89799 | 8123.23 | 5700 | 2700 | -4.44089e-13 | 2.48458 | Face extérieure | Peinture-01 | Mur-142 | Interieurs logements | Pl | 678 | rdc | 3
Mur-142 | rdc | 1 | 0 | 2700 | 2700 | 1.8972 | 930 | 3.12289 | 2.1008 | 2.1008 | 7199.7 | 16.2674 | 17.5674 | 0.378144 | 7629.7 | 6099.7 | 16.2674 | 6279.7 | 17.5674 | 3.50103 | 19.2322 | 19.6682 | 7109.7 | 7289.7 | 0 | 1.12581 | 3.12289 | 3000 | 0 | 7289.75 | 3.50103 | 3.50103 | 14833.9 | 5700 | 2700 | 0 | 3.59436 | Face extérieure | Peinture-01 | Mur-142 | Interieurs logements | Sejour Cuisine/pl | A04 | rdc | 3
Mur-142 | rdc | 0 | 0 | 2500 | 2500 | 0 | 0 | 1.09555 | 0 | 0 | 2434.56 | 5.86141 | 6.08641 | 0 | 2614.56 | 2434.56 | 5.86141 | 2434.56 | 6.08641 | 1.09555 | 6.08641 | 6.08641 | 2434.56 | 2434.56 | 0 | 0.438221 | 1.09555 | 3000 | 0 | 2434.56 | 1.09555 | 1.09555 | 5229.12 | 5500 | 2500 | 0 | 1.77644 | Face extérieure | Peinture-01 | Mur-142 | Interieurs logements | Sde | B04 | rdc | 3
Mur-143 | rdc | 3 | 0 | 2500 | 0 | 4.0869 | 2310 | 6.05435 | 4.5299 | 4.5299 | 15336.1 | 30.8353 | 33.6353 | 0.815382 | 15156.1 | 13316.1 | 31.1636 | 13316.1 | 33.9636 | 6.86974 | 38.1652 | 38.1652 | 15336.1 | 15336.1 | 0 | 2.38429 | 6.05435 | 3000 | 0 | 15446.1 | 6.86974 | 6.86974 | 31181.3 | 5500 | 2500 | 0 | 6.40498 | Face extérieure | Peinture-01 | Mur-143 | Interieurs logements | Sde | B04 | rdc | 3
Mur-142 | rdc | 0 | 0 | 2500 | 0 | 0 | 0 | 2.23175 | 0 | 0 | 5029.44 | 11.1236 | 12.0986 | 0 | 5189.44 | 4939.44 | 11.1236 | 5119.44 | 12.0986 | 2.23175 | 12.1736 | 12.6236 | 4939.44 | 5119.44 | 0 | 0.892699 | 2.23175 | 3000 | 0 | 5049.44 | 2.23175 | 2.23175 | 10493.4 | 5500 | 2500 | 0 | 2.87179 | Face extérieure | Peinture-01 | Mur-142 | Interieurs logements | Cellier | B02 | rdc | 3
Mur-143 | rdc | 2 | 0 | 2500 | 0 | 2.1897 | 1380 | 6.82197 | 2.4291 | 2.4291 | 16371.6 | 35.5499 | 37.2889 | 0.437238 | 16621.6 | 15271.6 | 35.8782 | 15451.6 | 37.6172 | 7.2592 | 40.104 | 40.554 | 16281.6 | 16461.6 | 0 | 2.72189 | 6.82197 | 3000 | 0 | 16221.6 | 7.2592 | 7.25921 | 33177.7 | 5500 | 2500 | 0 | 6.71193 | Face extérieure | Peinture-01 | Mur-143 | Interieurs logements | Sdb | B03 | rdc | 3
Mur-142 | rdc | 0 | 0 | 2700 | 2700 | 0 | 0 | 1.45478 | 0 | 0 | 2980.03 | 7.89309 | 8.08209 | 0 | 3160.03 | 2980.03 | 7.89309 | 2980.03 | 8.08209 | 1.45478 | 8.08209 | 8.08209 | 2980.03 | 2980.03 | 0 | 0.568806 | 1.45478 | 3000 | 0 | 3160.03 | 1.45478 | 1.45478 | 6320.07 | 5700 | 2700 | 0 | 2.10961 | Face extérieure | Peinture-01 | Mur-142 | Interieurs logements | Sdb | B03 | rdc | 3
Mur-142 | rdc | 0 | 0 | 2700 | 2700 | 0 | 0 | 0.20088 | 0 | 0 | 400 | 1.116 | 1.116 | 0 | 579.999 | 400.001 | 1.116 | 399.999 | 1.116 | 0.20088 | 1.116 | 1.116 | 400.001 | 399.999 | 0 | 0.1044 | 0.20088 | 3000 | 0 | 580.001 | 0.20088 | 0.20088 | 1309.12 | 5700 | 2700 | 0 | 1.5536 | Face extérieure | Peinture-01 | Mur-142 | Interieurs logements | Entree/pl | B02 | rdc | 3
Mur-142 | rdc | 0 | 0 | 3000 | 3000 | 0 | 0 | 0.22905 | 0 | 0 | 399.999 | 1.29 | 1.255 | 0 | 579.999 | 400 | 1.29 | 399.999 | 1.255 | 0.22905 | 1.29 | 1.255 | 400 | 399.999 | 0 | 0.0998641 | 0.22905 | 3000 | 0 | 580.002 | 0.22905 | 0.22905 | 1309.12 | 6000 | 3000 | 0 | 1.65909 | Face extérieure | Peinture-01 | Mur-142 | Interieurs logements |  |  | rdc | 3
Mur-142 | rdc | 2 | 1 | 2750 | 2150 | 4.2024 | 2060 | 0.750028 | 4.6617 | 4.6617 | 3210.38 | 3.42436 | 4.36031 | 0.839106 | 3300.37 | 132.569 | 3.42436 | 312.552 | 4.36031 | 1.58913 | 8.58106 | 9.07601 | 3120.38 | 3300.37 | 0.0441 | 0.178268 | 0.750028 | 3000 | 0 | 3300.38 | 1.58913 | 1.58914 | 6855.31 | 5750 | 2750 | -4.44089e-13 | 1.95117 | Face extérieure | Peinture-01 | Mur-142 | Interieurs logements | Pl | 678 | rdc | 3
Mur-143 | rdc | 0 | 0 | 2500 | 2500 | 0 | 0 | 0.39692 | 0 | 0 | 882.045 | 1.98017 | 2.43005 | 0 | 972.021 | 792.069 | 1.98017 | 972.021 | 2.43005 | 0.39692 | 1.98017 | 2.43005 | 792.069 | 972.021 | 0 | 0.158768 | 0.39692 | 3000 | 0 | 972.021 | 0.39692 | 0.39692 | 2198.61 | 5500 | 2500 | 0 | 1.40385 | Face extérieure | Peinture-01 | Mur-143 | Interieurs logements | Wc | A04 | rdc | 3
Mur-143 | rdc | 2 | 0 | 2500 | 0 | 3.7944 | 1860 | 3.19469 | 4.2016 | 4.2016 | 8779.94 | 15.8482 | 16.0897 | 0.756289 | 8759.94 | 6669.94 | 15.8482 | 6849.94 | 16.0897 | 3.95098 | 21.7248 | 22.0663 | 8689.94 | 8869.94 | 0 | 1.21679 | 3.19469 | 3000 | 0 | 8869.94 | 3.95098 | 3.95098 | 17994.4 | 5500 | 2500 | 0 | 3.88358 | Face extérieure | Peinture-01 | Mur-143 | Interieurs logements | Entree/pl | B01 | rdc | 3
Mur-134 | rdc | 0 | 0 | 1500 | 1500 | 0 | 0 | 0.412979 | 0 | 0 | 1529.55 | 2.02433 | 2.56433 | 0 | 1709.55 | 1349.55 | 2.02433 | 1709.55 | 2.56433 | 0.412979 | 2.02433 | 2.56433 | 1349.55 | 1709.55 | 0 | 0.275319 | 0.412979 | 2500 | -500 | 1709.55 | 0.412979 | 0.412979 | 3568.22 | 4000 | 1000 | -500 | 1.31431 | Face extérieure | Peinture-01 | Mur-134 | 3D |  |  | rdc | 3
Mur-134 | rdc | 0 | 0 | 1500 | 1500 | 0 | 0 | 0.828794 | 0 | 0 | 3069.61 | 4.33441 | 4.87441 | 0 | 3249.61 | 2889.61 | 4.33441 | 3249.61 | 4.87441 | 0.828794 | 4.33441 | 4.87441 | 2889.61 | 3249.61 | 0 | 0.55253 | 0.828794 | 2500 | -500 | 3249.61 | 0.828794 | 0.828794 | 6648.33 | 4000 | 1000 | -500 | 1.86873 | Face extérieure | Peinture-01 | Mur-134 | 3D |  |  | rdc | 3
Mur-134 | rdc | 0 | 1 | 1500 | 1500 | 0 | 0 | 0.522806 | 1.69558 | 1.7 | 3069.61 | 2.63883 | 3.17441 | 0.305989 | 3249.61 | 2889.61 | 4.33441 | 3249.61 | 4.87441 | 0.828794 | 4.33441 | 4.87441 | 2889.61 | 3249.61 | 1.7 | 0.55253 | 0.522806 | 2500 | -500 | 3249.61 | 0.828794 | 0.828794 | 6648.33 | 4000 | 1000 | -500 | 1.86249 | Face extérieure | Peinture-01 | Mur-134 | 3D |  |  | rdc | 3
Mur-134 | rdc | 0 | 1 | 1500 | 1500 | 0 | 0 | 0.229379 | 1.02 | 1.02 | 1529.55 | 1.00433 | 1.54433 | 0.1836 | 1709.55 | 1349.55 | 2.02433 | 1709.55 | 2.56433 | 0.412979 | 2.02433 | 2.56433 | 1349.55 | 1709.55 | 1.02 | 0.275319 | 0.229379 | 2500 | -500 | 1709.55 | 0.412979 | 0.412979 | 3568.22 | 4000 | 1000 | -500 | 1.31431 | Face extérieure | Peinture-01 | Mur-134 | 3D |  |  | rdc | 3
Mur-142 | Etage1 | 0 | 0 | 2750 | 0 | 0 | 0 | 3.51971 | 0 | 0 | 7158.11 | 18.9764 | 19.3614 | 0 | 7678.11 | 7158.11 | 18.9764 | 7158.11 | 19.3614 | 3.51971 | 19.5539 | 19.5539 | 7158.11 | 7158.11 | 0 | 1.32086 | 3.51971 | 5750 | 0 | 7338.11 | 3.51971 | 3.51971 | 14676.2 | 8500 | 2750 | 0 | 3.61912 | Face extérieure | Peinture-01 | Mur-142 | Interieurs logements | Sde | B13 | Etage1 | 4
Mur-143 | Etage1 | 0 | 0 | 2700 | 2700 | 0 | 0 | 3.48069 | 0 | 0 | 7161.92 | 19.1482 | 18.7702 | 0 | 7501.92 | 7161.92 | 19.1482 | 7161.92 | 18.7702 | 3.48069 | 19.3372 | 19.3372 | 7161.92 | 7161.92 | 0 | 1.28914 | 3.48069 | 5750 | 0 | 7161.92 | 3.48069 | 3.48069 | 14683.8 | 8450 | 2700 | -8.88178e-13 | 3.55029 | Face extérieure | Peinture-01 | Mur-143 | Interieurs logements | Ch 2 | A14 | Etage1 | 4 | ArchiCADProperties - Zones conflictuelles: Cellier
Mur-142 | Etage1 | 0 | 0 | 3000 | 3000 | 0 | 0 | 0.2538 | 0 | 0 | 454.999 | 1.115 | 1.255 | 0 | 579.999 | 329.999 | 1.115 | 579.999 | 1.255 | 0.2538 | 1.115 | 1.705 | 329.999 | 579.999 | 0 | 0.0998642 | 0.2538 | 5750 | 0 | 580.004 | 0.2538 | 0.2538 | 1357.69 | 8750 | 3000 | 0 | 1.50552 | Face extérieure | Peinture-01 | Mur-142 | Interieurs logements |  |  | Etage1 | 4
Mur-142 | Etage1 | 1 | 0 | 2700 | 2700 | 1.8972 | 930 | 3.12091 | 2.1008 | 2.1008 | 7199.7 | 16.2314 | 17.5814 | 0.378144 | 7629.7 | 6099.7 | 16.2314 | 6279.7 | 17.5814 | 3.49905 | 19.1962 | 19.6822 | 7109.7 | 7289.7 | 0 | 1.11415 | 3.12091 | 5750 | 0 | 7289.7 | 3.49905 | 3.49905 | 14833.9 | 8450 | 2700 | 0 | 3.58331 | Face extérieure | Peinture-01 | Mur-142 | Interieurs logements | Sejour Cuisine/pl | A14 | Etage1 | 4
Mur-142 | Etage1 | 0 | 0 | 2500 | 2500 | 0 | 0 | 2.26325 | 0 | 0 | 5029.44 | 11.1236 | 12.2736 | 0 | 5189.44 | 4939.44 | 11.1236 | 5119.44 | 12.2736 | 2.26325 | 12.3486 | 12.7986 | 4939.44 | 5119.44 | 0 | 0.905299 | 2.26325 | 5750 | 0 | 5119.44 | 2.26325 | 2.26325 | 10493.4 | 8250 | 2500 | 0 | 2.89699 | Face extérieure | Peinture-01 | Mur-142 | Interieurs logements | Cellier | B13 | Etage1 | 4
Mur-142 | Etage1 | 0 | 0 | 2700 | 2700 | 0 | 0 | 0.20088 | 0 | 0 | 399.999 | 1.116 | 1.116 | 0 | 579.999 | 400 | 1.116 | 399.999 | 1.116 | 0.20088 | 1.116 | 1.116 | 400 | 399.999 | 0 | 0.1044 | 0.20088 | 5750 | 0 | 580 | 0.20088 | 0.20088 | 1309.12 | 8450 | 2700 | 0 | 1.5536 | Face extérieure | Peinture-01 | Mur-142 | Interieurs logements | Entree/pl | B13 | Etage1 | 4
Mur-143 | Etage1 | 2 | 0 | 2500 | 0 | 2.1897 | 1380 | 6.56092 | 2.4291 | 2.4291 | 16281.6 | 35.9999 | 35.1639 | 0.437238 | 16621.6 | 14781.6 | 36.3282 | 14781.6 | 35.4922 | 6.99816 | 38.879 | 38.704 | 16281.6 | 16281.6 | 0 | 2.52926 | 6.56092 | 5750 | 0 | 15551.6 | 6.99816 | 6.99816 | 32923.2 | 8250 | 2500 | 0 | 6.22849 | Face extérieure | Peinture-01 | Mur-143 | Interieurs logements | Sde | B14 | Etage1 | 4 | ArchiCADProperties - Zones conflictuelles: Cellier; Sde; Sejour Cuisine
2 x Mur-150 | Etage1 | 0 | 0 | 600 | 600 | 0 | 0 | 0.386881 | 0 | 0 | 3582.23 | 2.04134 | 2.25734 | 0 | 3762.23 | 3402.23 | 2.04134 | 3762.23 | 2.25734 | 0.386881 | 2.04134 | 2.25734 | 3402.23 | 3762.23 | 0 | 0.644801 | 0.386881 | 5150 | -600 | 3762.23 | 0.386881 | 0.386881 | 7673.57 | 5750 | 0 | -600 | 1.59507 | Face extérieure | Peinture-01 | Mur-150 | Interieurs logements |  |  | Etage1 | 4
2 x Mur-150 | Etage1 | 0 | 0 | 600 | 600 | 0 | 0 | 0.217853 | 0 | 0 | 2017.15 | 1.10229 | 1.31829 | 0 | 2197.15 | 1837.15 | 1.10229 | 2197.15 | 1.31829 | 0.217853 | 1.10229 | 1.31829 | 1837.15 | 2197.15 | 0 | 0.363088 | 0.217853 | 5150 | -600 | 2197.15 | 0.217853 | 0.217853 | 4543.42 | 5750 | 0 | -600 | 1.03165 | Face extérieure | Peinture-01 | Mur-150 | Interieurs logements |  |  | Etage1 | 4
Mur-143 | Etage1 | 3 | 0 | 2500 | 0 | 4.0869 | 2310 | 6.05435 | 4.5299 | 4.5299 | 15336.1 | 30.8353 | 33.6353 | 0.815382 | 15156.1 | 13316.1 | 31.1636 | 13316.1 | 33.9636 | 6.86974 | 38.1652 | 38.1652 | 15336.1 | 15336.1 | 0 | 2.38429 | 6.05435 | 5750 | 0 | 15446.1 | 6.86974 | 6.86974 | 31181.3 | 8250 | 2500 | 0 | 6.40498 | Face extérieure | Peinture-01 | Mur-143 | Interieurs logements | Sejour cuisine | B16 | Etage1 | 4
Mur-143 | Etage1 | 2 | 0 | 2750 | 2750 | 3.7944 | 1860 | 1.80581 | 4.2016 | 4.2016 | 5177.59 | 9.13428 | 10.1743 | 0.756288 | 4947.59 | 3107.59 | 9.13428 | 3207.59 | 10.1743 | 2.5621 | 14.0919 | 14.3759 | 5127.59 | 5227.59 | 0 | 0.568367 | 1.80581 | 5750 | 0 | 5407.59 | 2.5621 | 2.5621 | 10942.6 | 8500 | 2750 | 0 | 3.11202 | Face extérieure | Peinture-01 | Mur-143 | Interieurs logements | Entree/pl | A12 | Etage1 | 4
Mur-142 | Etage1 | 0 | 0 | 3000 | 3000 | 0 | 0 | 0.215967 | 0 | 0 | 399.94 | 1.19975 | 1.19989 | 0 | 399.964 | 399.916 | 1.19975 | 399.964 | 1.19989 | 0.215967 | 1.19975 | 1.19989 | 399.916 | 399.964 | 0 | 0.0719892 | 0.215967 | 5750 | 0 | 579.916 | 0.215967 | 0.215967 | 1308.96 | 8750 | 3000 | 0 | 1.67123 | Face extérieure | Peinture-01 | Mur-142 | Interieurs logements | Sejour cuisine | A13 | Etage1 | 4
Mur-143 | Etage1 | 0 | 0 | 2700 | 8.88178e-13 | 0 | 0 | 3.32074 | 0 | 0 | 6832.91 | 17.7175 | 17.6682 | 0 | 7445.51 | 6842.06 | 17.7175 | 6823.76 | 17.6682 | 3.32074 | 18.4735 | 18.2352 | 6842.06 | 6823.76 | 0 | 1.2299 | 3.32074 | 5750 | 0 | 6842.06 | 3.32074 | 3.32074 | 14026.7 | 8450 | 2700 | -8.88178e-13 | 3.43431 | Face extérieure | Peinture-01 | Mur-143 | Interieurs logements | Ch 1 | A12 | Etage1 | 4 | ArchiCADProperties - Zones conflictuelles: Sde
Mur-142 | Etage1 | 0 | 0 | 2700 | 0 | 0 | 0 | 1.45478 | 0 | 0 | 3160.03 | 7.89309 | 8.08209 | 0 | 3160.03 | 3160.03 | 7.89309 | 3160.03 | 8.08209 | 1.45478 | 8.08209 | 8.08209 | 3160.03 | 3160.03 | 0 | 0.568806 | 1.45478 | 5750 | 0 | 3160.03 | 1.45478 | 1.45478 | 6680.06 | 8450 | 2700 | 0 | 2.07721 | Face extérieure | Peinture-01 | Mur-142 | Interieurs logements | Sejour Cuisine | B13 | Etage1 | 4
Mur-143 | Etage1 | 2 | 0 | 2500 | 8.88178e-13 | 3.7944 | 1860 | 5.66306 | 4.2016 | 4.2016 | 14335.3 | 29.4094 | 31.0137 | 0.756288 | 14517.6 | 12234.4 | 29.4094 | 12396.1 | 31.0137 | 6.41935 | 35.461 | 35.5653 | 14254.4 | 14416.1 | 0 | 2.20414 | 5.66306 | 5750 | 0 | 14364.4 | 6.41935 | 6.41935 | 29106 | 8250 | 2500 | -8.88178e-13 | 5.86059 | Face extérieure | Peinture-01 | Mur-143 | Interieurs logements | Sejour cuisine | B12 | Etage1 | 4 | ArchiCADProperties - Zones conflictuelles: Sde
Mur-142 | Etage1 | 0 | 0 | 3000 | 2100 | 0 | 0 | 2.01781 | 0 | 0 | 3736.69 | 11.0421 | 10.5201 | 0 | 3926.69 | 3826.69 | 11.0421 | 3646.69 | 10.5201 | 2.01781 | 11.4801 | 10.9401 | 3826.69 | 3646.69 | 0 | 0.672603 | 2.01781 | 5750 | 0 | 3826.69 | 2.01781 | 2.01781 | 7907.9 | 8750 | 3000 | 0 | 2.64878 | Face extérieure | Peinture-01 | Mur-142 | Interieurs logements | Wc | A13 | Etage1 | 4 | ArchiCADProperties - Zones conflictuelles: Sejour cuisine
Mur-142 | Etage1 | 0 | 0 | 2500 | 2500 | 0 | 0 | 1.09555 | 0 | 0 | 2434.56 | 5.86141 | 6.08641 | 0 | 2614.56 | 2434.56 | 5.86141 | 2434.56 | 6.08641 | 1.09555 | 6.08641 | 6.08641 | 2434.56 | 2434.56 | 0 | 0.438221 | 1.09555 | 5750 | 0 | 2434.56 | 1.09555 | 1.09555 | 5229.12 | 8250 | 2500 | 0 | 1.77644 | Face extérieure | Peinture-01 | Mur-142 | Interieurs logements | Sde | B16 | Etage1 | 4
Mur-143 | Etage1 | 1 | 0 | 2700 | 2700 | 1.8972 | 930 | 1.68058 | 2.1008 | 2.1008 | 4236.06 | 8.82356 | 9.47156 | 0.378144 | 4466.06 | 3176.06 | 8.82356 | 3276.06 | 9.47156 | 2.05872 | 11.3024 | 11.5724 | 4186.06 | 4286.06 | 0 | 0.58069 | 1.68058 | 5750 | 0 | 4466.06 | 2.05872 | 2.05872 | 9059.54 | 8450 | 2700 | 0 | 2.92923 | Face extérieure | Peinture-01 | Mur-143 | Interieurs logements | Sejour cuisine | B11 | Etage1 | 4
Mur-143 | Etage1 | 0 | 0 | 2750 | 2750 | 0 | 0 | 1.74207 | 0 | 0 | 3511.16 | 9.90318 | 9.45318 | 0 | 3941.16 | 3601.16 | 9.90318 | 3421.16 | 9.45318 | 1.74207 | 9.90318 | 9.45318 | 3601.16 | 3421.16 | 0 | 0.648208 | 1.74207 | 5750 | 0 | 3601.16 | 1.74207 | 1.74207 | 7456.87 | 8500 | 2750 | 0 | 2.47281 | Face extérieure | Peinture-01 | Mur-143 | Interieurs logements |  |  | Etage1 | 4
Mur-142 | Etage1 | 1 | 0 | 3000 | 3000 | 1.8972 | 930 | 0.44644 | 2.1008 | 2.1008 | 1509.01 | 2.21029 | 2.75016 | 0.378144 | 1778.99 | 409.035 | 2.21029 | 588.987 | 2.75016 | 0.824584 | 4.31109 | 4.85096 | 1419.03 | 1598.99 | 0 | 0.122218 | 0.44644 | 5750 | 0 | 1778.99 | 0.824584 | 0.824584 | 3452.58 | 8750 | 3000 | 0 | 1.72991 | Face extérieure | Peinture-01 | Mur-142 | Interieurs logements | Sejour cuisine | A13 | Etage1 | 4
Mur-142 | Etage1 | 1 | 0 | 2700 | 2700 | 0.2925 | 450 | 0.606942 | 0.3283 | 0.3283 | 1370 | 3.1289 | 3.2921 | 0.059094 | 1400 | 1280 | 3.4572 | 1460 | 3.6204 | 0.666036 | 3.4572 | 3.9432 | 1280 | 1460 | 0 | 0.2682 | 0.606942 | 5750 | 0 | 1580 | 0.666036 | 0.666036 | 3174.56 | 8450 | 2700 | 0 | 1.70971 | Face extérieure | Peinture-01 | Mur-142 | Interieurs logements | Sde | B11 | Etage1 | 4
Mur-142 | Etage1 | 1 | 0 | 2700 | 2700 | 1.8972 | 930 | 0.342756 | 2.1008 | 2.1008 | 1490 | 2.1292 | 1.6792 | 0.378144 | 1400 | 570 | 2.1292 | 390 | 1.6792 | 0.7209 | 4.23 | 3.78 | 1580 | 1400 | 0 | 0.0864 | 0.342756 | 5750 | 0 | 1580 | 0.7209 | 0.7209 | 3414.56 | 8450 | 2700 | 0 | 1.513 | Face extérieure | Peinture-01 | Mur-142 | Interieurs logements | Entree/pl | B15 | Etage1 | 4
Mur-143 | Etage1 | 0 | 0 | 2700 | 0 | 0 | 0 | 1.69968 | 0 | 0 | 3497.33 | 9.44279 | 9.25379 | 0 | 3777.33 | 3497.33 | 9.44279 | 3497.33 | 9.25379 | 1.69968 | 9.44279 | 9.25379 | 3497.33 | 3497.33 | 0 | 0.62951 | 1.69968 | 5750 | 0 | 3497.38 | 1.69968 | 1.69968 | 7354.66 | 8450 | 2700 | 0 | 2.23102 | Face extérieure | Peinture-01 | Mur-143 | Interieurs logements | Sejour cuisine | A12 | Etage1 | 4
Mur-143 | Etage1 | 1 | 0 | 2750 | 0 | 1.8972 | 930 | 3.89403 | 2.1008 | 2.1008 | 8622.86 | 20.8236 | 20.4455 | 0.378143 | 9052.84 | 7522.89 | 20.8236 | 7702.84 | 20.4455 | 4.27218 | 23.4914 | 23.7883 | 8532.89 | 8712.84 | 0 | 1.44771 | 3.89403 | 5750 | 0 | 9052.84 | 4.27218 | 4.27218 | 17680.3 | 8500 | 2750 | 0 | 4.26843 | Face extérieure | Peinture-01 | Mur-143 | Interieurs logements | Wc | A15 | Etage1 | 4
Mur-143 | Etage1 | 0 | 0 | 2500 | 0 | 0 | 0 | 0.408528 | 0 | 0 | 1026.62 | 2.39118 | 2.26949 | 0 | 1026.6 | 1026.65 | 2.39118 | 1026.6 | 2.26949 | 0.408528 | 2.39149 | 2.39149 | 1026.65 | 1026.6 | 0 | 0.172187 | 0.408528 | 5750 | 0 | 956.692 | 0.408528 | 0.430468 | 2413.24 | 8250 | 2500 | 0 | 1.09868 | Face extérieure | Peinture-01 | Mur-143 | Interieurs logements | Ch 2 | B15 | Etage1 | 4 | ArchiCADProperties - Zones conflictuelles: Cellier; Ch 2; Sejour cuisine
Mur-143 | Etage 2 | 2 | 0 | 3050 | 3050 | 3.7944 | 1860 | 2.08414 | 4.2016 | 4.2016 | 5177.59 | 10.5886 | 10.8886 | 0.756288 | 4947.59 | 3107.59 | 10.5886 | 3207.59 | 10.8886 | 2.84043 | 15.6302 | 15.9302 | 5127.59 | 5227.59 | 0 | 0.568367 | 2.08414 | 8500 | 0 | 5407.59 | 2.84043 | 2.84043 | 10942.6 | 11550 | 3050 | 0 | 3.28061 | Face extérieure | Peinture-01 | Mur-143 | Interieurs logements | Entree/pl | A22 | Etage 2 | 5
Mur-142 | Etage 2 | 0 | 0 | 3000 | 3000 | 0 | 0 | 0.26658 | 0 | 0 | 489.999 | 1.236 | 1.186 | 0 | 579.999 | 399.999 | 1.236 | 579.999 | 1.186 | 0.26658 | 1.236 | 1.726 | 399.999 | 579.999 | 0 | 0.0998642 | 0.26658 | 8500 | 0 | 580.004 | 0.26658 | 0.26658 | 1414.56 | 11500 | 3000 | 0 | 1.49112 | Face extérieure | Peinture-01 | Mur-142 | Interieurs logements |  |  | Etage 2 | 5
Mur-143 | Etage 2 | 1 | 0 | 3000 | 3000 | 1.8972 | 930 | 1.90933 | 2.1008 | 2.1008 | 4236.06 | 9.84837 | 10.7574 | 0.378144 | 4466.06 | 3176.06 | 9.84837 | 3276.06 | 10.7574 | 2.28747 | 12.5582 | 12.8582 | 4186.06 | 4286.06 | 0 | 0.58069 | 1.90933 | 8500 | 0 | 4466.06 | 2.28747 | 2.28747 | 9059.54 | 11500 | 3000 | 0 | 3.10546 | Face extérieure | Peinture-01 | Mur-143 | Interieurs logements | Sejour cuisine | B21 | Etage 2 | 5
Mur-143 | Etage 2 | 0 | 0 | 3000 | 0 | 0 | 0 | 3.6832 | 0 | 0 | 6832.91 | 20.112 | 19.8051 | 0 | 7445.51 | 6842.06 | 20.112 | 6823.76 | 19.8051 | 3.6832 | 20.5262 | 20.2613 | 6842.06 | 6823.76 | 0 | 1.2299 | 3.6832 | 8500 | 0 | 6842.06 | 3.6832 | 3.68971 | 14026.7 | 11500 | 3000 | 0 | 3.54259 | Face extérieure | Peinture-01 | Mur-143 | Interieurs logements | Ch 1 | A22 | Etage 2 | 5
Mur-143 | Etage 2 | 0 | 0 | 3000 | 3000 | 0 | 0 | 2.43941 | 0 | 0 | 4517.43 | 13.1324 | 12.2922 | 0 | 4657.4 | 4657.45 | 13.1324 | 4377.4 | 12.2922 | 2.43941 | 13.9724 | 13.1322 | 4657.45 | 4377.4 | 0 | 0.813137 | 2.43941 | 8500 | 0 | 4657.45 | 2.43941 | 2.43941 | 9547.76 | 11500 | 3000 | 0 | 3.165 | Face extérieure | Peinture-01 | Mur-143 | Interieurs logements | Sejour cuisine | A22 | Etage 2 | 5 | ArchiCADProperties - Zones conflictuelles: Sejour cuisine
Mur-143 | Etage 2 | 1 | 0 | 3050 | 3050 | 1.8972 | 930 | 4.45148 | 2.1008 | 2.1008 | 8792.86 | 24.4035 | 23.2484 | 0.378144 | 9052.84 | 7862.89 | 24.4035 | 7702.84 | 23.2484 | 4.82962 | 27.0713 | 26.5912 | 8872.89 | 8712.84 | 0 | 1.44771 | 4.45148 | 8500 | 0 | 9052.84 | 4.82962 | 4.82962 | 18225 | 11550 | 3050 | 0 | 5.01292 | Face extérieure | Peinture-01 | Mur-143 | Interieurs logements | Wc | A25 | Etage 2 | 5
Mur-143 | Etage 2 | 0 | 0 | 2500 | 0 | 0 | 0 | 2.3939 | 0 | 0 | 5389.8 | 13.2995 | 12.9495 | 0 | 5729.79 | 5389.81 | 13.2995 | 5389.79 | 12.9495 | 2.3939 | 13.2995 | 12.9495 | 5389.81 | 5389.79 | 0 | 0.957559 | 2.3939 | 8500 | 0 | 5319.84 | 2.3939 | 2.3939 | 11139.6 | 11000 | 2500 | 0 | 2.81512 | Face extérieure | Peinture-01 | Mur-143 | Interieurs logements | Ch 2 | B25 | Etage 2 | 5 | ArchiCADProperties - Zones conflictuelles: Sejour cuisine
Mur-142 | Etage 2 | 0 | 0 | 3000 | 2100 | 0 | 0 | 2.01781 | 0 | 0 | 3736.69 | 11.0421 | 10.5201 | 0 | 3926.69 | 3826.69 | 11.0421 | 3646.69 | 10.5201 | 2.01781 | 11.4801 | 10.9401 | 3826.69 | 3646.69 | 0 | 0.672603 | 2.01781 | 8500 | 0 | 3826.69 | 2.01781 | 2.01781 | 7907.9 | 11500 | 3000 | 0 | 2.64878 | Face extérieure | Peinture-01 | Mur-142 | Interieurs logements | Sejour cuisine | A23 | Etage 2 | 5 | ArchiCADProperties - Zones conflictuelles: Sejour cuisine
Mur-142 | Etage 2 | 0 | 0 | 3000 | 3000 | 0 | 0 | 0.215967 | 0 | 0 | 399.94 | 1.19975 | 1.19989 | 0 | 399.964 | 399.916 | 1.19975 | 399.964 | 1.19989 | 0.215967 | 1.19975 | 1.19989 | 399.916 | 399.964 | 0 | 0.0719892 | 0.215967 | 8500 | 0 | 579.916 | 0.215967 | 0.215967 | 1308.96 | 11500 | 3000 | 0 | 1.67123 | Face extérieure | Peinture-01 | Mur-142 | Interieurs logements | Sejour cuisine | A23 | Etage 2 | 5
Mur-143 | Etage 2 | 2 | 0 | 2800 | 1.77636e-12 | 3.7944 | 1860 | 6.46866 | 4.2016 | 4.2016 | 14335.3 | 33.6457 | 34.5597 | 0.756288 | 14517.6 | 12234.4 | 33.6457 | 12396.1 | 34.5597 | 7.22495 | 39.9123 | 39.8463 | 14254.4 | 14416.1 | 0 | 2.21675 | 6.46866 | 8500 | 0 | 14434.4 | 7.22495 | 7.22495 | 29106 | 11300 | 2800 | -1.77636e-12 | 6.01645 | Face extérieure | Peinture-01 | Mur-143 | Interieurs logements | Ch 1 | B21 | Etage 2 | 5 | ArchiCADProperties - Zones conflictuelles: Sde
Mur-142 | Etage 2 | 0 | 0 | 3000 | 0 | 0 | 0 | 1.48804 | 0 | 0 | 2819.64 | 8.24891 | 8.28491 | 0 | 2819.64 | 2819.64 | 8.24891 | 2819.64 | 8.28491 | 1.48804 | 8.24891 | 8.28491 | 2819.64 | 2819.64 | 0 | 0.511135 | 1.48804 | 8500 | 0 | 2929.65 | 1.48804 | 1.48804 | 5999.27 | 11500 | 3000 | 0 | 2.11718 | Face extérieure | Peinture-01 | Mur-142 | Interieurs logements | Sejour cuisine | B23 | Etage 2 | 5
Mur-142 | Etage 2 | 0 | 0 | 3000 | 3000 | 0 | 0 | 0.22248 | 0 | 0 | 399.999 | 1.236 | 1.236 | 0 | 579.999 | 400 | 1.236 | 399.999 | 1.236 | 0.22248 | 1.236 | 1.236 | 400 | 399.999 | 0 | 0.1044 | 0.22248 | 8500 | 0 | 580 | 0.22248 | 0.22248 | 1309.12 | 11500 | 3000 | 0 | 1.70633 | Face extérieure | Peinture-01 | Mur-142 | Interieurs logements | Entree/pl | B23 | Etage 2 | 5
Mur-143 | Etage 2 | 0 | 0 | 3050 | 3050 | 0 | 0 | 1.93168 | 0 | 0 | 3511.16 | 10.9835 | 10.4795 | 0 | 3941.16 | 3601.16 | 10.9835 | 3421.16 | 10.4795 | 1.93168 | 10.9835 | 10.4795 | 3601.16 | 3421.16 | 0 | 0.648208 | 1.93168 | 8500 | 0 | 3601.16 | 1.93168 | 1.93168 | 7456.87 | 11550 | 3050 | 0 | 2.60318 | Face extérieure | Peinture-01 | Mur-143 | Interieurs logements |  |  | Etage 2 | 5
Mur-142 | Etage 2 | 1 | 0 | 3000 | 3000 | 0.2925 | 450 | 0.745486 | 0.3283 | 0.3283 | 1489.96 | 3.87159 | 4.08879 | 0.059094 | 1399.96 | 1399.96 | 4.19989 | 1579.96 | 4.41709 | 0.80458 | 4.19989 | 4.73989 | 1399.96 | 1579.96 | 0 | 0.268193 | 0.745486 | 8500 | 0 | 1579.96 | 0.80458 | 0.80458 | 3414.48 | 11500 | 3000 | 0 | 1.84006 | Face extérieure | Peinture-01 | Mur-142 | Interieurs logements | Sde | B21 | Etage 2 | 5
Mur-143 | Etage 2 | 3 | 0 | 2800 | 0 | 4.0869 | 2310 | 6.87998 | 4.5299 | 4.5299 | 15336.1 | 35.3575 | 38.2221 | 0.815382 | 15156.1 | 13316.1 | 35.6858 | 13316.1 | 38.5504 | 7.69536 | 42.752 | 42.752 | 15336.1 | 15336.1 | 0 | 2.39689 | 6.87998 | 8500 | 0 | 15516.1 | 7.69536 | 7.69536 | 31181.3 | 11300 | 2800 | 0 | 6.57032 | Face extérieure | Peinture-01 | Mur-143 | Interieurs logements | Wc | B26 | Etage 2 | 5
Mur-142 | Etage 2 | 0 | 0 | 2800 | 2800 | 0 | 0 | 2.97457 | 0 | 0 | 5901.91 | 16.1754 | 16.1474 | 0 | 6081.91 | 5901.91 | 16.1754 | 5901.91 | 16.1474 | 2.97457 | 16.5254 | 16.5254 | 5901.91 | 5901.91 | 0 | 1.06234 | 2.97457 | 8500 | 0 | 5901.91 | 2.97457 | 2.97457 | 12163.8 | 11300 | 2800 | 0 | 3.13269 | Face extérieure | Peinture-01 | Mur-142 | Interieurs logements | Ch 1/pl | B26 | Etage 2 | 5
Mur-142 | Etage 2 | 1 | 0 | 3000 | 3000 | 1.8972 | 930 | 0.423216 | 2.1008 | 2.1008 | 1490 | 2.6032 | 2.0992 | 0.378144 | 1400 | 570 | 2.6032 | 390 | 2.0992 | 0.80136 | 4.704 | 4.2 | 1580 | 1400 | 0 | 0.0864 | 0.423216 | 8500 | 0 | 1580 | 0.80136 | 0.80136 | 3414.56 | 11500 | 3000 | 0 | 1.64336 | Face extérieure | Peinture-01 | Mur-142 | Interieurs logements | Entree/pl | B25 | Etage 2 | 5
Mur-142 | Etage 2 | 0 | 0 | 2800 | 0 | 0 | 0 | 2.49956 | 0 | 0 | 5029.44 | 12.4584 | 13.5504 | 0 | 5189.44 | 4939.44 | 12.4584 | 5119.44 | 13.5504 | 2.49956 | 13.6344 | 14.1384 | 4939.44 | 5119.44 | 0 | 0.892699 | 2.49956 | 8500 | 0 | 5049.44 | 2.49956 | 2.49956 | 10493.4 | 11300 | 2800 | 0 | 3.00216 | Face extérieure | Peinture-01 | Mur-142 | Interieurs logements | Cellier | B23 | Etage 2 | 5
Mur-143 | Etage 2 | 2 | 0 | 2800 | 0 | 2.1897 | 1380 | 6.22446 | 2.4291 | 2.4291 | 13371.9 | 32.9058 | 33.7394 | 0.437238 | 13801.9 | 12271.9 | 33.2341 | 12451.9 | 34.0677 | 6.66169 | 36.8115 | 37.3155 | 13281.9 | 13461.9 | 0 | 2.22515 | 6.22446 | 8500 | 0 | 13461.9 | 6.66169 | 6.67142 | 27178.5 | 11300 | 2800 | 0 | 5.79123 | Face extérieure | Peinture-01 | Mur-143 | Interieurs logements | Sde | B24 | Etage 2 | 5 | ArchiCADProperties - Zones conflictuelles: Sde; Sejour cuisine
Mur-142 | Etage 2 | 0 | 0 | 3000 | 3000 | 0 | 0 | 1.65778 | 0 | 0 | 3069.97 | 8.5559 | 9.4439 | 0 | 3159.97 | 2979.97 | 8.5559 | 3159.97 | 9.4439 | 1.65778 | 8.9759 | 9.4439 | 2979.97 | 3159.97 | 0 | 0.560694 | 1.65778 | 8500 | 0 | 3159.97 | 1.65778 | 1.65778 | 6574.49 | 11500 | 3000 | 0 | 2.42506 | Face extérieure | Peinture-01 | Mur-142 | Interieurs logements | Sejour cuisine | B23 | Etage 2 | 5
Mur-142 | Etage 2 | 0 | 0 | 3000 | 0 | 0 | 0 | 3.87134 | 0 | 0 | 7158.11 | 20.8803 | 20.9284 | 0 | 7678.1 | 7158.11 | 20.8803 | 7158.1 | 20.9284 | 3.87134 | 21.5103 | 21.3143 | 7158.11 | 7158.1 | 0 | 1.32086 | 3.87185 | 8500 | 0 | 7338.11 | 3.87185 | 3.87185 | 14676.2 | 11500 | 3000 | 0 | 3.72171 | Face extérieure | Peinture-01 | Mur-142 | Interieurs logements | Sde | B23 | Etage 2 | 5 | ArchiCADProperties - Zones conflictuelles: Sde
Mur-143 | Etage 2 | 0 | 0 | 2700 | 2300 | 0 | 0 | 3.47421 | 0 | 0 | 7161.92 | 19.1122 | 18.5452 | 0 | 7501.92 | 7161.92 | 19.1122 | 7161.92 | 18.5452 | 3.47421 | 19.3372 | 19.3372 | 7161.92 | 7161.92 | 0 | 1.28914 | 3.47421 | 8500 | 0 | 7161.92 | 3.47421 | 3.48069 | 14683.8 | 11200 | 2700 | 0 | 3.55029 | Face extérieure | Peinture-01 | Mur-143 | Interieurs logements | Ch 2/pl | A24 | Etage 2 | 5 | ArchiCADProperties - Zones conflictuelles: Wc
Mur-142 | Etage 2 | 1 | 0 | 3000 | 3000 | 1.8972 | 930 | 3.50969 | 2.1008 | 2.1008 | 7199.7 | 18.2683 | 19.7683 | 0.378144 | 7629.7 | 6099.7 | 18.2683 | 6279.7 | 19.7683 | 3.88784 | 21.3291 | 21.8691 | 7109.7 | 7289.7 | 0 | 1.11415 | 3.50969 | 8500 | 0 | 7289.7 | 3.88784 | 3.88784 | 14833.9 | 11500 | 3000 | 0 | 3.71366 | Face extérieure | Peinture-01 | Mur-142 | Interieurs logements | Sejour cuisine/pl | A24 | Etage 2 | 5
Mur-142 | Etage 2 | 1 | 0 | 3000 | 3000 | 1.8972 | 930 | 0.436722 | 2.1008 | 2.1008 | 1509.01 | 2.1563 | 2.69616 | 0.378144 | 1778.99 | 409.035 | 2.1563 | 588.987 | 2.69616 | 0.814866 | 4.2571 | 4.79696 | 1419.03 | 1598.99 | 0 | 0.0898219 | 0.436722 | 8500 | 0 | 1599.03 | 0.814866 | 0.814866 | 3452.58 | 11500 | 3000 | 0 | 1.66512 | Face extérieure | Peinture-01 | Mur-142 | Interieurs logements | Sejour cuisine | A23 | Etage 2 | 5
Mur-142 | Etage 2 | 0 | 0 | 3000 | 3000 | 0 | 0 | 1.21286 | 0 | 0 | 2246.04 | 6.79811 | 6.46811 | 0 | 2156.04 | 2336.04 | 6.79811 | 2156.04 | 6.46811 | 1.21286 | 7.00811 | 6.46811 | 2336.04 | 2156.04 | 0 | 0.404286 | 1.21286 | 8500 | 0 | 2336.04 | 1.21286 | 1.21286 | 4926.63 | 11500 | 3000 | 0 | 2.11225 | Face extérieure | Peinture-01 | Mur-142 | Interieurs logements | Sde | A22 | Etage 2 | 5
Mur-142 | Etage 3 | 1 | 1 | 2800 | 0 | 0.2925 | 450 | 6.35906 | 2.1643 | 2.1643 | 13594.7 | 33.9001 | 34.8801 | 0.389574 | 13844.7 | 12604.7 | 36.0644 | 12784.7 | 37.0444 | 6.74864 | 37.2944 | 37.7984 | 13504.7 | 13684.7 | 1.836 | 2.27245 | 6.35906 | 11550 | 0 | 13614.7 | 6.74864 | 6.75836 | 27624 | 14350 | 2800 | 0 | 5.86967 | Face extérieure | Peinture-01 | Mur-142 | Interieurs logements | Sdb | B34 | Etage 3 | 6 | ArchiCADProperties - Zones conflictuelles: Entree; Sdb
Mur-142 | Etage 3 | 0 | 0 | 3000 | 0 | 0 | 0 | 3.83658 | 0 | 0 | 7158.11 | 20.6843 | 21.1043 | 0 | 7678.11 | 7158.11 | 20.6843 | 7158.11 | 21.1043 | 3.83658 | 21.3143 | 21.3143 | 7158.11 | 7158.11 | 0 | 1.32086 | 3.83658 | 11550 | 0 | 7338.11 | 3.83658 | 3.83658 | 14676.2 | 14550 | 3000 | 0 | 3.70912 | Face extérieure | Peinture-01 | Mur-142 | Interieurs logements | Sde | B32 | Etage 3 | 6
Mur-142 | Etage 3 | 0 | 0 | 2800 | 0 | 0 | 0 | 2.49956 | 0 | 0 | 5029.44 | 12.4584 | 13.7464 | 0 | 5189.44 | 4939.44 | 12.4584 | 5119.44 | 13.7464 | 2.49956 | 13.6344 | 14.1384 | 4939.44 | 5119.44 | 0 | 0.892699 | 2.49956 | 11550 | 0 | 5049.44 | 2.49956 | 2.49956 | 10493.4 | 14350 | 2800 | 0 | 3.00216 | Face extérieure | Peinture-01 | Mur-142 | Interieurs logements | Cellier | B33 | Etage 3 | 6
Mur-143 | Etage 3 | 1 | 0 | 3050 | 0 | 1.8972 | 930 | 4.41368 | 2.1008 | 2.1008 | 8792.86 | 23.0564 | 24.7605 | 0.378144 | 9052.89 | 7702.84 | 23.0564 | 7862.89 | 24.7605 | 4.79182 | 26.3812 | 26.8613 | 8712.84 | 8872.89 | 0 | 1.44772 | 4.41368 | 11550 | 0 | 9052.89 | 4.79182 | 4.79182 | 18225 | 14600 | 3050 | 0 | 5.00034 | Face extérieure | Peinture-01 | Mur-143 | Interieurs logements | Wc | A33 | Etage 3 | 6
Mur-143 | Etage 3 | 0 | 0 | 3000 | 3000 | 0 | 0 | 0.216032 | 0 | 0 | 400.06 | 1.2 | 1.20036 | 0 | 400.12 | 399.999 | 1.2 | 400.121 | 1.20036 | 0.216032 | 1.2 | 1.20036 | 399.999 | 400.121 | 0 | 0.0720107 | 0.216032 | 11550 | 0 | 580.996 | 0.216032 | 0.216032 | 1310.56 | 14550 | 3000 | 0 | 1.67535 | Face extérieure | Peinture-01 | Mur-143 | Interieurs logements | Sejour cuisine | A32 | Etage 3 | 6
Mur-142 | Etage 3 | 1 | 0 | 3000 | 3000 | 1.8972 | 930 | 3.50969 | 2.1008 | 2.1008 | 7199.7 | 18.2683 | 19.7683 | 0.378144 | 7449.7 | 6099.7 | 18.2683 | 6279.7 | 19.7683 | 3.88784 | 21.3291 | 21.8691 | 7109.7 | 7289.7 | 0 | 1.11415 | 3.50969 | 11550 | 0 | 7289.7 | 3.88784 | 3.88784 | 14833.9 | 14550 | 3000 | 0 | 3.71366 | Face extérieure | Peinture-01 | Mur-142 | Interieurs logements | Sejour cuisine | A32 | Etage 3 | 6
Mur-143 | Etage 3 | 2 | 0 | 2800 | 0 | 3.7944 | 1860 | 6.43338 | 4.2016 | 4.2016 | 14335.3 | 33.4497 | 34.5597 | 0.756288 | 14517.6 | 12234.4 | 33.4497 | 12396.1 | 34.5597 | 7.18967 | 39.7163 | 39.6503 | 14254.4 | 14416.1 | 0 | 2.20415 | 6.43338 | 11550 | 0 | 14364.4 | 7.18967 | 7.18967 | 29106 | 14350 | 2800 | 0 | 5.99125 | Face extérieure | Peinture-01 | Mur-143 | Interieurs logements | Ch 1/pl | B31 | Etage 3 | 6 | ArchiCADProperties - Zones conflictuelles: Sde; Sde
Mur-143 | Etage 3 | 0 | 0 | 3000 | 0 | 0 | 0 | 2.01699 | 0 | 0 | 3737.36 | 11.0636 | 10.3106 | 0 | 4106.86 | 3827.86 | 11.0636 | 3646.86 | 10.3106 | 2.01699 | 11.4836 | 10.3106 | 3827.86 | 3646.86 | 0 | 0.67233 | 2.01699 | 11550 | 0 | 3827.86 | 2.01699 | 2.01699 | 7909.98 | 14550 | 3000 | 0 | 2.65045 | Face extérieure | Peinture-01 | Mur-143 | Interieurs logements | Wc | A32 | Etage 3 | 6
Mur-143 | Etage 3 | 1 | 0 | 3170 | 3170 | 1.8972 | 930 | 2.65471 | 2.1008 | 2.1008 | 5318.62 | 14.1689 | 14.4739 | 0.378144 | 5228.62 | 4398.62 | 14.1689 | 4218.62 | 14.4739 | 3.03286 | 17.1237 | 16.5747 | 5408.62 | 5228.62 | 0 | 0.775551 | 2.65471 | 11550 | 0 | 5408.62 | 3.03286 | 3.03286 | 11071.8 | 14720 | 3170 | 0 | 3.10151 | Face extérieure | Peinture-01 | Mur-143 | Interieurs logements |  |  | Etage 3 | 6
Mur-143 | Etage 3 | 0 | 0 | 3050 | 3050 | 0 | 0 | 1.93168 | 0 | 0 | 3511.16 | 10.9835 | 10.4795 | 0 | 3941.16 | 3601.16 | 10.9835 | 3421.16 | 10.4795 | 1.93168 | 10.9835 | 10.4795 | 3601.16 | 3421.16 | 0 | 0.648208 | 1.93168 | 11550 | 0 | 3601.16 | 1.93168 | 1.93168 | 7456.87 | 14600 | 3050 | 0 | 2.60318 | Face extérieure | Peinture-01 | Mur-143 | Interieurs logements |  |  | Etage 3 | 6
Mur-142 | Etage 3 | 0 | 0 | 3000 | 3000 | 0 | 0 | 0.221221 | 0 | 0 | 400.002 | 1.23601 | 1.222 | 0 | 579.999 | 400.004 | 1.23601 | 399.999 | 1.222 | 0.221221 | 1.23601 | 1.222 | 400.004 | 399.999 | 0 | 0.0998646 | 0.221221 | 11550 | 0 | 580.008 | 0.221221 | 0.221221 | 1309.12 | 14550 | 3000 | 0 | 1.69989 | Face extérieure | Peinture-01 | Mur-142 | Interieurs logements |  |  | Etage 3 | 6
Mur-143 | Etage 3 | 1 | 0 | 3000 | 3000 | 1.8972 | 930 | 1.90933 | 2.1008 | 2.1008 | 4236.06 | 9.82737 | 10.7574 | 0.378144 | 4466.06 | 3176.06 | 9.82737 | 3276.06 | 10.7574 | 2.28747 | 12.5582 | 12.8582 | 4186.06 | 4286.06 | 0 | 0.58069 | 1.90933 | 11550 | 0 | 4466.06 | 2.28747 | 2.28747 | 9059.54 | 14550 | 3000 | 0 | 3.10546 | Face extérieure | Peinture-01 | Mur-143 | Interieurs logements | Sejour cuisine/pl | B31 | Etage 3 | 6
Mur-142 | Etage 3 | 1 | 0 | 3000 | 0 | 1.8972 | 930 | 2.61948 | 2.1008 | 2.1008 | 5551.2 | 14.3428 | 13.6168 | 0.378144 | 5551.2 | 4541.2 | 14.3428 | 4541.2 | 13.6168 | 2.99762 | 16.6536 | 16.5996 | 5551.2 | 5551.2 | 0 | 0.817417 | 2.61948 | 11550 | 0 | 5551.2 | 2.99762 | 2.99762 | 11462.4 | 14550 | 3000 | 0 | 2.89662 | Face extérieure | Peinture-01 | Mur-142 | Interieurs logements | cellier | B34 | Etage 3 | 6 | ArchiCADProperties - Zones conflictuelles: Sde
Mur-142 | Etage 3 | 1 | 0 | 3000 | 3000 | 0.2925 | 450 | 0.745486 | 0.3283 | 0.3283 | 1489.96 | 3.87159 | 4.08879 | 0.059094 | 1399.96 | 1399.96 | 4.19989 | 1579.96 | 4.41709 | 0.80458 | 4.19989 | 4.73989 | 1399.96 | 1579.96 | 0 | 0.268193 | 0.745486 | 11550 | 0 | 1579.96 | 0.80458 | 0.80458 | 3414.48 | 14550 | 3000 | 0 | 1.84006 | Face extérieure | Peinture-01 | Mur-142 | Interieurs logements | Sde | B31 | Etage 3 | 6
Mur-142 | Etage 3 | 0 | 0 | 3000 | 3000 | 0 | 0 | 3.15257 | 0 | 0 | 5838.09 | 16.8843 | 17.5143 | 0 | 6178.09 | 5838.09 | 16.8843 | 5838.09 | 17.5143 | 3.15257 | 17.5143 | 17.5143 | 5838.09 | 5838.09 | 0 | 1.05086 | 3.15257 | 11550 | 0 | 5838.09 | 3.15257 | 3.15257 | 12036.2 | 14550 | 3000 | 0 | 3.18171 | Face extérieure | Peinture-01 | Mur-142 | Interieurs logements | Sdb | B34 | Etage 3 | 6
Mur-143 | Etage 3 | 1 | 0 | 3000 | 3000 | 1.8972 | 930 | 0.436486 | 2.1008 | 2.1008 | 1508.57 | 2.15368 | 2.69616 | 0.378144 | 1598.98 | 408.16 | 2.15368 | 588.987 | 2.69616 | 0.81463 | 4.25448 | 4.79696 | 1418.16 | 1598.99 | 0 | 0.0897432 | 0.436486 | 11550 | 0 | 1599.03 | 0.81463 | 0.81463 | 3452.32 | 14550 | 3000 | 0 | 1.66682 | Face extérieure | Peinture-01 | Mur-143 | Interieurs logements | Sejour cuisine | A32 | Etage 3 | 6
Mur-143 | Etage 3 | 3 | 0 | 2800 | 2800 | 4.0869 | 2310 | 5.45182 | 4.5299 | 4.5299 | 12434.9 | 27.6893 | 30.5399 | 0.815382 | 12344.9 | 10324.9 | 28.0176 | 10504.9 | 30.8682 | 6.2672 | 34.5658 | 35.0698 | 12344.9 | 12524.9 | 0 | 1.87469 | 5.45182 | 11550 | 0 | 12524.9 | 6.2672 | 6.2672 | 25304.4 | 14350 | 2800 | 0 | 5.32974 | Face extérieure | Peinture-01 | Mur-143 | Interieurs logements | Sejour cuisine/pl | B35 | Etage 3 | 6 | ArchiCADProperties - Zones conflictuelles: Sde
Mur-142 | Etage 3 | 0 | 0 | 3000 | 3000 | 0 | 0 | 0.22248 | 0 | 0 | 399.999 | 1.236 | 1.236 | 0 | 579.999 | 400 | 1.236 | 399.999 | 1.236 | 0.22248 | 1.236 | 1.236 | 400 | 399.999 | 0 | 0.1044 | 0.22248 | 11550 | 0 | 580 | 0.22248 | 0.22248 | 1309.12 | 14550 | 3000 | 0 | 1.70633 | Face extérieure | Peinture-01 | Mur-142 | Interieurs logements | Entree/pl | B33 | Etage 3 | 6
Mur-143 | etage 4 | 2 | 0 | 2800 | 0 | 3.7944 | 1860 | 6.39326 | 4.2016 | 4.2016 | 14275 | 33.2269 | 34.1619 | 0.756288 | 14517.6 | 12174.1 | 33.2269 | 12335.8 | 34.1619 | 7.14955 | 39.5475 | 39.5025 | 14194.1 | 14355.8 | 0 | 2.19329 | 6.39326 | 14600 | 0 | 14304.1 | 7.14955 | 7.15927 | 28985.4 | 17400 | 2800 | 0 | 5.93714 | Face extérieure | Peinture-01 | Mur-143 | Interieurs logements | Sde | B41 | etage 4 | 7 | ArchiCADProperties - Zones conflictuelles: Sde; Sde
Mur-142 | etage 4 | 0 | 0 | 3000 | 0 | 0 | 0 | 3.83658 | 0 | 0 | 7158.11 | 20.6843 | 21.1043 | 0 | 7678.11 | 7158.11 | 20.6843 | 7158.11 | 21.1043 | 3.83658 | 21.3143 | 21.3143 | 7158.11 | 7158.11 | 0 | 1.32086 | 3.83658 | 14600 | 0 | 7338.11 | 3.83658 | 3.83658 | 14676.2 | 17600 | 3000 | 0 | 3.70912 | Face extérieure | Peinture-01 | Mur-142 | Interieurs logements | Sde | B42 | etage 4 | 7
Mur-143 | etage 4 | 0 | 0 | 3050 | 3050 | 0 | 0 | 1.93168 | 0 | 0 | 3511.16 | 10.9835 | 10.4795 | 0 | 3941.16 | 3601.16 | 10.9835 | 3421.16 | 10.4795 | 1.93168 | 10.9835 | 10.4795 | 3601.16 | 3421.16 | 0 | 0.648208 | 1.93168 | 14600 | 0 | 3601.16 | 1.93168 | 1.93168 | 7456.87 | 17650 | 3050 | 0 | 2.60318 | Face extérieure | Peinture-01 | Mur-143 | Interieurs logements |  |  | etage 4 | 7
Mur-143 | etage 4 | 4 | 0 | 2800 | 2800 | 5.5761 | 3040 | 5.20402 | 6.2147 | 6.2147 | 12544.9 | 26.3335 | 28.6591 | 1.11865 | 12524.9 | 9624.93 | 30.4474 | 9804.92 | 32.773 | 6.32267 | 34.8738 | 35.3778 | 12454.9 | 12634.9 | 0 | 1.74869 | 5.20402 | 14600 | 0 | 12634.9 | 6.32267 | 6.32267 | 25524.4 | 17400 | 2800 | 0 | 5.22356 | Face extérieure | Peinture-01 | Mur-143 | Interieurs logements | Ch 3/sde | B44 | etage 4 | 7
Mur-142 | etage 4 | 0 | 0 | 3000 | 3000 | 0 | 0 | 0.221221 | 0 | 0 | 400.002 | 1.23601 | 1.222 | 0 | 579.999 | 400.004 | 1.23601 | 399.999 | 1.222 | 0.221221 | 1.23601 | 1.222 | 400.004 | 399.999 | 0 | 0.0998646 | 0.221221 | 14600 | 0 | 580.008 | 0.221221 | 0.221221 | 1309.12 | 17600 | 3000 | 0 | 1.69989 | Face extérieure | Peinture-01 | Mur-142 | Interieurs logements |  |  | etage 4 | 7
Mur-142 | etage 4 | 0 | 0 | 3000 | 3000 | 0 | 0 | 3.06185 | 0 | 0 | 5658.09 | 16.5903 | 17.0103 | 0 | 6178.09 | 5658.09 | 16.5903 | 5658.09 | 17.0103 | 3.06185 | 17.0103 | 17.0103 | 5658.09 | 5658.09 | 0 | 1.05086 | 3.06185 | 14600 | 0 | 5838.09 | 3.06185 | 3.06185 | 11676.2 | 17600 | 3000 | 0 | 3.18171 | Face extérieure | Peinture-01 | Mur-142 | Interieurs logements | Sejour cuisine | B43 | etage 4 | 7
Mur-142 | etage 4 | 0 | 0 | 2800 | 0 | 0 | 0 | 3.29185 | 0 | 0 | 6671.44 | 17.042 | 17.938 | 0 | 6546.44 | 6546.44 | 17.042 | 6796.44 | 17.938 | 3.29185 | 17.938 | 18.638 | 6546.44 | 6796.44 | 0 | 1.17566 | 3.29185 | 14600 | 0 | 6656.46 | 3.29185 | 3.29185 | 13790.6 | 17400 | 2800 | 0 | 3.60486 | Face extérieure | Peinture-01 | Mur-142 | Interieurs logements | Dressing | B44 | etage 4 | 7
Mur-143 | etage 4 | 0 | 0 | 2500 | 2500 | 0 | 0 | 0.312262 | 0 | 0 | 693.915 | 1.73479 | 1.73479 | 0 | 693.915 | 693.915 | 1.73479 | 693.915 | 1.73479 | 0.312262 | 1.73479 | 1.73479 | 693.915 | 693.915 | 0 | 0.124905 | 0.312262 | 14720 | 120 | 693.915 | 0.312262 | 0.312262 | 1747.83 | 17220 | 2620 | 120 | 1.14981 | Face extérieure | Peinture-01 | Mur-143 | Interieurs logements |  |  | etage 4 | 7
Mur-143 | etage 4 | 0 | 0 | 2500 | 2500 | 0 | 0 | 0.245039 | 0 | 0 | 544.532 | 1.36133 | 1.36133 | 0 | 544.532 | 544.532 | 1.36133 | 544.532 | 1.36133 | 0.245039 | 1.36133 | 1.36133 | 544.532 | 544.532 | 0 | 0.0980157 | 0.245039 | 14720 | 120 | 544.532 | 0.245039 | 0.245039 | 1449.06 | 17220 | 2620 | 120 | 1.09603 | Face extérieure | Peinture-01 | Mur-143 | Interieurs logements |  |  | etage 4 | 7
Mur-143 | etage 4 | 1 | 0 | 2500 | 2500 | 1.8972 | 930 | 1.16226 | 2.1008 | 2.1008 | 3423.13 | 6.45687 | 6.45717 | 0.378144 | 3423.19 | 2413.07 | 6.45687 | 2413.19 | 6.45717 | 1.54041 | 8.55767 | 8.55797 | 3423.07 | 3423.19 | 0 | 0.434363 | 1.16226 | 14720 | 120 | 3423.19 | 1.54041 | 1.54041 | 7206.26 | 17220 | 2620 | 120 | 1.95053 | Face extérieure | Peinture-01 | Mur-143 | Interieurs logements |  |  | etage 4 | 7
Mur-142 | etage 4 | 0 | 0 | 3000 | 3000 | 0 | 0 | 0.22248 | 0 | 0 | 399.999 | 1.236 | 1.236 | 0 | 579.999 | 400 | 1.236 | 399.999 | 1.236 | 0.22248 | 1.236 | 1.236 | 400 | 399.999 | 0 | 0.1044 | 0.22248 | 14600 | 0 | 580 | 0.22248 | 0.22248 | 1309.12 | 17600 | 3000 | 0 | 1.70633 | Face extérieure | Peinture-01 | Mur-142 | Interieurs logements | Entree/pl | B43 | etage 4 | 7
Mur-142 | etage 4 | 0 | 0 | 2800 | 2800 | 0 | 0 | 2.52476 | 0 | 0 | 5009.44 | 12.3464 | 13.9424 | 0 | 5189.44 | 4829.44 | 12.3464 | 5189.44 | 13.9424 | 2.52476 | 13.5224 | 14.5304 | 4829.44 | 5189.44 | 0 | 0.901699 | 2.52476 | 14600 | 0 | 5189.44 | 2.52476 | 2.52476 | 10528 | 17400 | 2800 | 0 | 3.22893 | Face extérieure | Peinture-01 | Mur-142 | Interieurs logements | Sejour cuisine | B43 | etage 4 | 7
Mur-143 | etage 4 | 1 | 0 | 3000 | 3000 | 1.8972 | 930 | 1.90933 | 2.1008 | 2.1008 | 4236.06 | 10.2474 | 10.7574 | 0.378144 | 4466.06 | 3176.06 | 10.2474 | 3276.06 | 10.7574 | 2.28747 | 12.5582 | 12.8582 | 4186.06 | 4286.06 | 0 | 0.58069 | 1.90933 | 14600 | 0 | 4466.06 | 2.28747 | 2.28747 | 9059.54 | 17600 | 3000 | 0 | 3.10546 | Face extérieure | Peinture-01 | Mur-143 | Interieurs logements | Sejour cuisine/pl | B41 | etage 4 | 7
Mur-142 | etage 4 | 1 | 0 | 3000 | 3000 | 0.2925 | 450 | 0.745486 | 0.3283 | 0.3283 | 1489.96 | 3.87159 | 4.08879 | 0.059094 | 1399.96 | 1399.96 | 4.19989 | 1579.96 | 4.41709 | 0.80458 | 4.19989 | 4.73989 | 1399.96 | 1579.96 | 0 | 0.268193 | 0.745486 | 14600 | 0 | 1579.96 | 0.80458 | 0.80458 | 3414.48 | 17600 | 3000 | 0 | 1.84006 | Face extérieure | Peinture-01 | Mur-142 | Interieurs logements | Sde | B41 | etage 4 | 7
Mur-142 | etage 4 | 0 | 0 | 2800 | 2500 | 0 | 0 | 1.6308 | 0 | 0 | 3248.56 | 8.96197 | 8.76597 | 0 | 3623.56 | 3213.56 | 8.96197 | 3283.56 | 8.76597 | 1.6308 | 8.99797 | 9.19397 | 3213.56 | 3283.56 | 0 | 0.584741 | 1.6308 | 14600 | 0 | 3283.56 | 1.6308 | 1.63728 | 6870.26 | 17400 | 2800 | 0 | 2.21425 | Face extérieure | Peinture-01 | Mur-142 | Interieurs logements | Sde 1 | B44 | etage 4 | 7
Mur-142 | etage 4 | 1 | 0 | 2800 | 2500 | 1.6932 | 830 | 2.45602 | 1.8928 | 1.8928 | 5561.91 | 13.6446 | 13.4486 | 0.340704 | 6081.91 | 4651.91 | 15.5374 | 4651.91 | 15.3414 | 2.79673 | 15.5734 | 15.5734 | 5561.91 | 5561.91 | 0 | 0.837345 | 2.45602 | 14600 | 0 | 5561.91 | 2.79673 | 2.80321 | 11483.8 | 17400 | 2800 | 0 | 2.84649 | Face intérieure | Peinture-01 | Mur-142 | Interieurs logements | Ch 3/sde | B44 | etage 4 | 7 | ArchiCADProperties - Zones conflictuelles: Dgt
Mur-142 | etage 4 | 1 | 0 | 3000 | 3000 | 1.8972 | 930 | 0.377827 | 2.1008 | 2.1008 | 1399.95 | 2.09904 | 2.09904 | 0.378144 | 1399.95 | 389.951 | 2.09904 | 389.947 | 2.09904 | 0.755971 | 4.19984 | 4.19984 | 1399.95 | 1399.95 | 0 | 0.0701904 | 0.377827 | 14600 | 0 | 1399.95 | 0.755971 | 0.755971 | 3159.9 | 17600 | 3000 | 0 | 1.40218 | Face extérieure | Peinture-01 | Mur-142 | Interieurs logements | Entree | B44 | etage 4 | 7
Mur-142 | etage 4 | 0 | 0 | 2800 | 2800 | 0 | 0 | 0.550413 | 0 | 0 | 1092.09 | 3.05785 | 3.05785 | 0 | 1272.09 | 1092.09 | 3.05785 | 1092.09 | 3.05785 | 0.550413 | 3.05785 | 3.05785 | 1092.09 | 1092.09 | 0 | 0.196576 | 0.550413 | 14600 | 0 | 1092.09 | 0.550413 | 0.550413 | 2544.18 | 17400 | 2800 | 0 | 1.40115 | Face extérieure | Peinture-01 | Mur-142 | Interieurs logements | Wc | B44 | etage 4 | 7
Mur-142 | etage 4 | 0 | 0 | 3000 | 3000 | 0 | 0 | 3.87188 | 0 | 0 | 7158.15 | 21.5104 | 21.5104 | 0 | 7678.15 | 7158.14 | 21.5104 | 7158.15 | 21.5104 | 3.87188 | 21.5104 | 21.5104 | 7158.14 | 7158.15 | 0 | 1.32087 | 3.87188 | 14600 | 0 | 7338.15 | 3.87188 | 3.87188 | 14676.3 | 17600 | 3000 | 0 | 3.72173 | Face extérieure | Peinture-01 | Mur-142 | Interieurs logements |  |  | etage 4 | 7
Mur-142 | etage 4 | 0 | 0 | 3000 | 3000 | 0 | 0 | 3.10725 | 0 | 0 | 5748.16 | 17.3045 | 17.0105 | 0 | 6178.16 | 5838.16 | 17.3045 | 5658.16 | 17.0105 | 3.10725 | 17.5145 | 17.0105 | 5838.16 | 5658.16 | 0 | 1.05087 | 3.10725 | 14600 | 0 | 5838.16 | 3.10725 | 3.10725 | 11930.9 | 17600 | 3000 | 0 | 3.3905 | Face extérieure | Peinture-01 | Mur-142 | Interieurs logements | Sejour cuisine | B53 | etage 4 | 7
Mur-142 | Etage 5 | 0 | 0 | 2700 | 2700 | 0 | 0 | 2.79361 | 0 | 0 | 5748.17 | 14.9518 | 14.838 | 0 | 6178.17 | 5838.17 | 14.9518 | 5658.17 | 14.838 | 2.79361 | 15.763 | 15.277 | 5838.17 | 5658.17 | 0 | 1.03467 | 2.79361 | 17650 | 0 | 5838.17 | 2.79361 | 2.79361 | 11930.9 | 20350 | 2700 | 0 | 3.24265 | Face extérieure | Peinture-01 | Mur-142 | Interieurs logements | Ch 1 | B51 | Etage 5 | 8
Mur-142 | Etage 5 | 1 | 0 | 2700 | 2700 | 1.8972 | 930 | 0.543596 | 2.1008 | 2.1008 | 1889.92 | 2.61998 | 3.24498 | 0.378144 | 1979.92 | 789.918 | 2.61998 | 969.918 | 3.24498 | 0.92174 | 4.89578 | 5.34578 | 1799.92 | 1979.92 | 0 | 0.174585 | 0.543596 | 17650 | 0 | 1979.92 | 0.92174 | 0.92174 | 4214.39 | 20350 | 2700 | 0 | 1.68937 | Face extérieure | Peinture-01 | Mur-142 | Interieurs logements | Entree | B52 | Etage 5 | 8
Mur-142 | Etage 5 | 0 | 0 | 2700 | 2700 | 0 | 0 | 0.693302 | 0 | 0 | 1426.55 | 3.17668 | 3.66268 | 0 | 1496.55 | 1426.55 | 3.17668 | 1426.55 | 3.66268 | 0.693302 | 3.85168 | 3.85168 | 1426.55 | 1426.55 | 0 | 0.256779 | 0.693302 | 17650 | 0 | 1496.55 | 0.693302 | 0.693302 | 3239.36 | 20350 | 2700 | 0 | 1.55647 | Face extérieure | Peinture-01 | Mur-142 | Interieurs logements | Wc | B52 | Etage 5 | 8
Mur-143 | Etage 5 | 0 | 0 | 2700 | 2700 | 0 | 0 | 1.71559 | 0 | 0 | 3530.03 | 9.53107 | 9.53107 | 0 | 3870.03 | 3530.03 | 9.53107 | 3530.03 | 9.53107 | 1.71559 | 9.53107 | 9.53107 | 3530.03 | 3530.03 | 0 | 0.635405 | 1.71559 | 17650 | 0 | 3530.03 | 1.71559 | 1.71559 | 7420.06 | 20350 | 2700 | 0 | 2.24281 | Face extérieure | Peinture-01 | Mur-143 | Interieurs logements | Ch 1 | B51 | Etage 5 | 8 | ArchiCADProperties - Zones conflictuelles: Sejour cuisine
Mur-143 | Etage 5 | 5 | 0 | 2700 | 0 | 7.2693 | 3870 | 4.63739 | 8.1075 | 8.1075 | 12614.9 | 23.2692 | 25.3318 | 1.45929 | 12524.9 | 8784.93 | 29.2759 | 8964.93 | 31.3385 | 6.09668 | 33.6283 | 34.1143 | 12524.9 | 12704.9 | 0 | 1.58488 | 4.63739 | 17650 | 0 | 12634.9 | 6.09668 | 6.09668 | 25664.4 | 20350 | 2700 | 0 | 5.01621 | Face extérieure | Peinture-01 | Mur-143 | Interieurs logements | Ch 3/pl | B52 | Etage 5 | 8 | ArchiCADProperties - Zones conflictuelles: Entree
Mur-142 | Etage 5 | 0 | 0 | 2500 | 2500 | 0 | 0 | 2.21375 | 0 | 0 | 4919.44 | 11.0236 | 11.9986 | 0 | 5189.44 | 4829.44 | 11.0236 | 5009.44 | 11.9986 | 2.21375 | 12.0736 | 12.5236 | 4829.44 | 5009.44 | 0 | 0.885499 | 2.21375 | 17650 | 0 | 5009.44 | 2.21375 | 2.21375 | 10273.4 | 20150 | 2500 | 0 | 2.85739 | Face extérieure | Peinture-01 | Mur-142 | Interieurs logements | Sde 1 | B52 | Etage 5 | 8
Mur-143 | Etage 5 | 0 | 0 | 2700 | 2700 | 0 | 0 | 1.70642 | 0 | 0 | 3511.16 | 9.72313 | 9.23713 | 0 | 3941.16 | 3601.16 | 9.72313 | 3421.16 | 9.23713 | 1.70642 | 9.72313 | 9.23713 | 3601.16 | 3421.16 | 0 | 0.632008 | 1.70642 | 17650 | 0 | 3601.16 | 1.70642 | 1.70642 | 7456.87 | 20350 | 2700 | 0 | 2.43732 | Face extérieure | Peinture-01 | Mur-143 | Interieurs logements |  |  | Etage 5 | 8
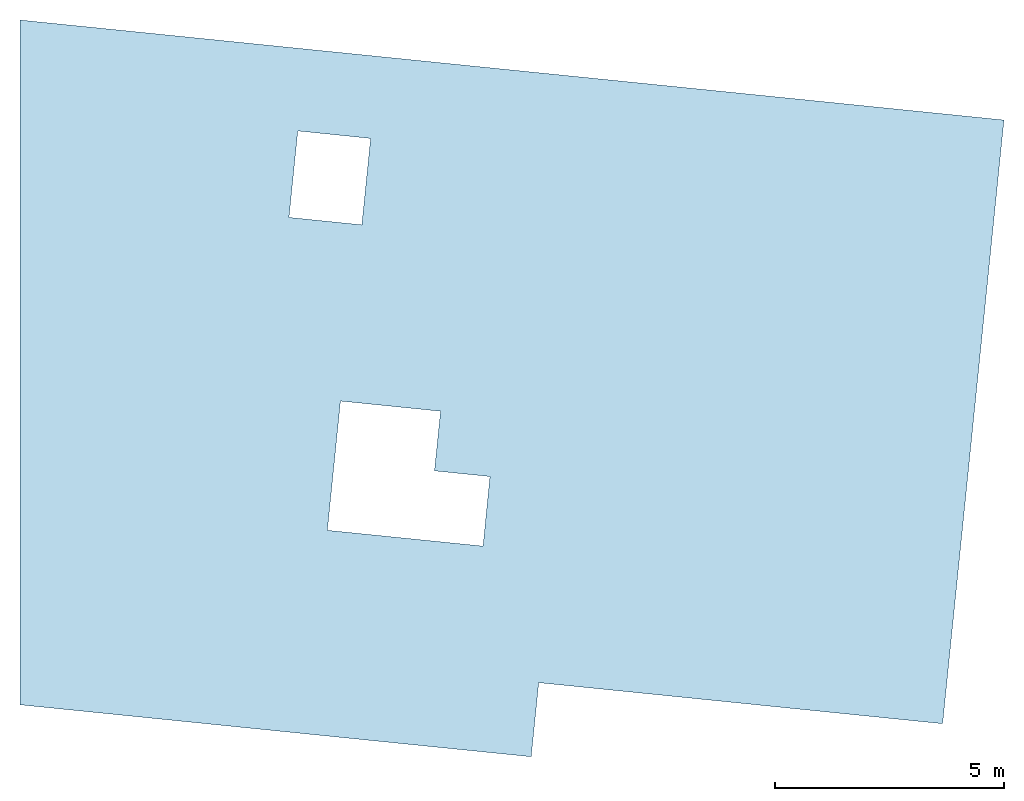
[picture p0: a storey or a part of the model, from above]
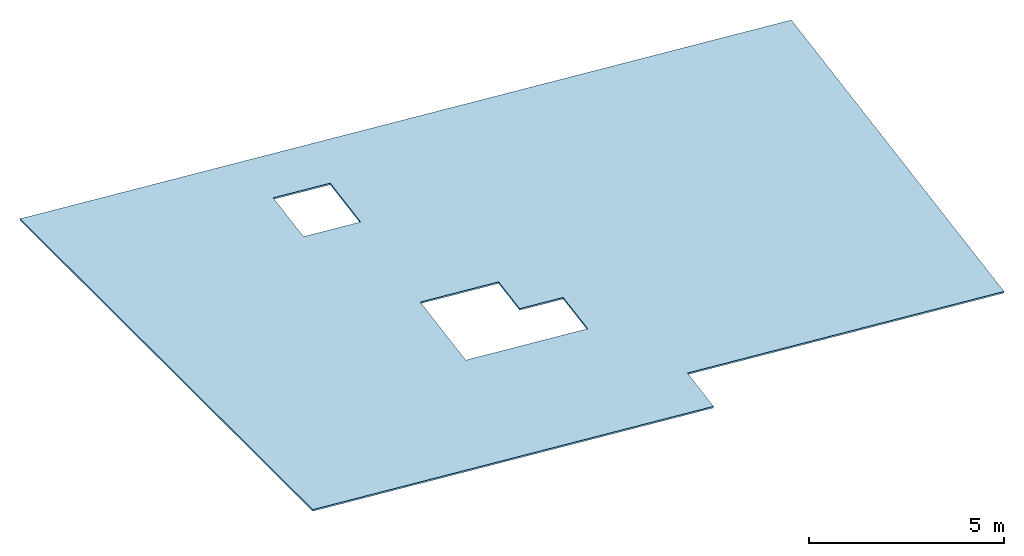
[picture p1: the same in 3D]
Properties of the parts of a building model (IFC2X3), part 21 of 44

# IfcWallStandardCase: Beton 18 0018356637 180 (140)
Name | In | Nombre de Portes | Nombre de trous (Nombre d'ouvertures vides) | Hauteur maximale de la couche de Mur sur face intérieure (mm) = Hauteur maximale du Mur (mm) = Hauteur maximale de la couche de Mur sur face extérieure (mm) = Hauteur (mm) | Hauteur minimale de la couche de Mur sur face intérieure (mm) = Hauteur minimale du Mur (mm) = Hauteur minimale de la couche de Mur sur face extérieure (mm) | Superficie des portes (m2) | Largeur totale des Portes (mm) | Volume de composant de mur sur face intérieure (net) (m3) = Volume de composant de mur sur face extérieure (net) (m3) | Superficie analytique des ouvertures sur face intérieure (m2) | Superficie analytique des ouvertures sur face extérieure (m2) | Longueur moyenne du mur (mm) = Longueur du Mur au centre (mm) | Superficie de la face intérieure du mur (nette) (m2) | Superficie de la face extérieure du mur (nette) (m2) = Superficie en plan (m2) = Superficie inférieure (nette) (m2) | Volume analytique des ouvertures (m3) | Longueur de ligne de référence (mm) | Longueur de la face intérieure du mur (conditionnelle) (mm) | Superficie de la face intérieure du mur (conditionnelle) (m2) | Longueur de la face extérieure du mur (conditionnelle) (mm) | Superficie de la face extérieure du mur (conditionnelle) (m2) | Volume du composant face intérieure du mur (conditionnel) (m3) = Volume du composant face extérieure du mur (conditionnel) (m3) | Superficie de la face intérieure du mur (brute) (m2) | Superficie de la face extérieure du mur (brute) (m2) | Longueur de Mur sur face intérieure (mm) | Longueur de Mur sur face extérieure (mm) | Superficie des baies libres dans le Mur (m2) | Superficie (m2) = Superficie supérieure (nette) (m2) | Volume (net) (m3) | Altitude à Zéro du Projet (mm) = Altitude de Référence Niveau 1 (mm) = Altitude de Référence Niveau 2 (mm) = Altitude à niveau de la mer (mm) = Altitude inférieure à premier niveau de référence (mm) = Altitude inférieure à Zéro du projet (mm) = Altitude inférieure à niveau de la mer (mm) = Altitude inférieure à deuxième niveau de référence (mm) | Altitude à étage lié/étage d'implantation (mm) = Décalage étage d'implantation (mm) | Longueur 3D (mm) | Volume (conditionnel) (m3) | Volume (brut) (m3) | Périmètre Plan (mm) | Altitude supérieure à premier niveau de référence (mm) = Altitude supérieure à Zéro du projet (mm) = Altitude supérieure à niveau de la mer (mm) = Altitude supérieure à deuxième niveau de référence (mm) | Altitude supérieure à étage d'implantation (mm) | Altitude inférieure à étage d'implantation (mm) | Superficie de l'arête (nette) (m2) | Emplacement de ligne de référence | Surface de face intérieure = Surface de face extérieure = Surfaces (Toutes) = Surface latérale | ID de l'élément = Lien et ID d'élément = ID de Parent | Calque | Nom de zone liée | Numéro de zone liée | Nom d'étage d'implantation | Numéro d'étage d'implantation
Mur-143 | Etage 5 | 1 | 0 | 2700 | 2700 | 1.6932 | 830 | 2.40916 | 1.8928 | 1.8928 | 5658.16 | 13.3842 | 12.8172 | 0.340704 | 6178.16 | 4748.16 | 15.277 | 4748.16 | 14.71 | 2.74986 | 15.277 | 15.277 | 5658.16 | 5658.16 | 0 | 0.854668 | 2.40916 | 17650 | 0 | 5658.16 | 2.74986 | 2.74986 | 11676.3 | 20350 | 2700 | 0 | 2.84514 | Face extérieure | Peinture-01 | Mur-143 | Interieurs logements | Entree | B52 | Etage 5 | 8
Mur-143 | Etage 5 | 0 | 0 | 2700 | 2450 | 0 | 0 | 1.65819 | 0 | 0 | 3421.16 | 9.23713 | 8.82163 | 0 | 3941.16 | 3421.16 | 9.23713 | 3421.16 | 8.82163 | 1.65819 | 9.23713 | 9.23713 | 3421.16 | 3421.16 | 0 | 0.615808 | 1.65819 | 17650 | 0 | 3421.16 | 1.65819 | 1.66268 | 7202.32 | 20350 | 2700 | 0 | 2.18563 | Face extérieure | Peinture-01 | Mur-143 | Interieurs logements | Sejour Cuisine | B52 | Etage 5 | 8
Mur-143 | Etage 5 | 1 | 0 | 2700 | 2700 | 1.8972 | 930 | 1.68105 | 2.1008 | 2.1008 | 4237.02 | 8.52916 | 8.82616 | 0.378144 | 4147.02 | 3137.02 | 8.52916 | 3317.02 | 8.82616 | 2.05919 | 11.197 | 11.683 | 4147.02 | 4327.02 | 0 | 0.580864 | 1.68105 | 17650 | 0 | 4327.02 | 2.05919 | 2.05919 | 8908.61 | 20350 | 2700 | 0 | 2.51684 | Face extérieure | Peinture-01 | Mur-143 | Interieurs logements | Entree/pl | B51 | Etage 5 | 8 | ArchiCADProperties - Zones conflictuelles: Wc
Mur-143 | Etage 5 | 0 | 0 | 2700 | 2700 | 0 | 0 | 0.499085 | 0 | 0 | 1026.92 | 2.77269 | 2.77269 | 0 | 1026.92 | 1026.93 | 2.77269 | 1026.92 | 2.77269 | 0.499085 | 2.77269 | 2.77269 | 1026.93 | 1026.92 | 0 | 0.184846 | 0.499085 | 17650 | 0 | 1026.92 | 0.499085 | 0.499085 | 2413.85 | 20350 | 2700 | 0 | 1.34169 | Face extérieure | Peinture-01 | Mur-143 | Interieurs logements | Sejour cuisine | B51 | Etage 5 | 8 | ArchiCADProperties - Zones conflictuelles: Dgt
Mur-143 | Etage 5 | 0 | 0 | 2700 | 2700 | 0 | 0 | 1.71559 | 0 | 0 | 3530.03 | 9.53107 | 9.53107 | 0 | 3870.03 | 3530.03 | 9.53107 | 3530.03 | 9.53107 | 1.71559 | 9.53107 | 9.53107 | 3530.03 | 3530.03 | 0 | 0.635405 | 1.71559 | 17650 | 0 | 3530.03 | 1.71559 | 1.71559 | 7420.06 | 20350 | 2700 | 0 | 2.24281 | Face extérieure | Peinture-01 | Mur-143 | Interieurs logements |  |  | Etage 5 | 8
Mur-143 | Etage 5 | 0 | 1 | 2700 | 2700 | 0 | 0 | 0.651901 | 8.11836 | 8.11836 | 4348.16 | 3.62167 | 3.43267 | 1.4613 | 4688.16 | 740 | 3.62167 | 740 | 3.43267 | 2.1132 | 11.74 | 11.74 | 4348.16 | 4348.16 | 8.11836 | 0.1332 | 0.651901 | 17650 | 0 | 4348.16 | 2.1132 | 2.1132 | 9056.32 | 20350 | 2700 | 0 | 1.48287 | Face extérieure | Peinture-01 | Mur-143 | Interieurs logements | Sejour Cuisine | B54 | Etage 5 | 8 | ArchiCADProperties - Zones conflictuelles: Sejour Cuisine
Mur-142 | Etage 5 | 0 | 0 | 2700 | 2700 | 0 | 0 | 2.79361 | 0 | 0 | 5748.17 | 15.1408 | 15.277 | 0 | 6178.17 | 5838.17 | 15.1408 | 5658.17 | 15.277 | 2.79361 | 15.763 | 15.277 | 5838.17 | 5658.17 | 0 | 1.03467 | 2.79361 | 17650 | 0 | 5838.17 | 2.79361 | 2.79361 | 11930.9 | 20350 | 2700 | 0 | 3.24265 | Face extérieure | Peinture-01 | Mur-142 | Interieurs logements | Ch 1 | B54 | Etage 5 | 8
Mur-135 | toiture | 0 | 0 | 1300 | 1300 | 0 | 0 | 0.432359 | 0 | 0 | 1860 | 2.116 | 2.688 | 0 | 1780 | 1600 | 2.116 | 2120 | 2.688 | 0.432359 | 2.116 | 2.688 | 1600 | 2120 | 0 | 0.351 | 0.432359 | 20150 | -199.999 | 2120 | 0.432359 | 0.432359 | 4359.26 | 21450 | 1100 | -199.999 | 1.47719 | Face extérieure | Poutre | Mur-135 | 3D |  |  | toiture | 9
Mur-135 | toiture | 0 | 0 | 1100 | 1100 | 0 | 0 | 0.415745 | 0 | 0 | 2099.72 | 2.2107 | 2.4087 | 0 | 2369.72 | 2009.72 | 2.2107 | 2189.72 | 2.4087 | 0.415745 | 2.2107 | 2.4087 | 2009.72 | 2189.72 | 0 | 0.37795 | 0.415745 | 20350 | 3.55271e-12 | 2189.72 | 0.415745 | 0.415745 | 4634 | 21450 | 1100 | 3.55271e-12 | 1.23391 | Face extérieure | Poutre | Mur-135 | 3D |  |  | toiture | 9

# IfcWallStandardCase: Beton 18 0170347028 180 (93)
Classification: Mur (Classification ARCHICAD); Material: Parpaing 314940890 180 mm
ArchiCADProperties - Complexité de mur: Droit; Option de géométrie: Uniforme; Angle d'inclinaison interne de mur: 90 deg; Angle d'inclinaison externe de mur: 90 deg; Calque: 3D; Matériau de construction / Composite / Profil / Hachure: Beton 18 0170347028; Structure Composite: Beton 18 0170347028; Verrouillé: no; Type d'élément: Mur; Étage supérieur lié absolu: Non lié; Étage supérieur lié relatif: Non lié; Étage supérieur lié: Non lié; Type de structure: Composite; Matériaux de construction (Tous): Parpaing 314940890; Angle d'inclinaison: 90 deg; Nombre de percements: 0; Nom de Variante: Modèle principal; Nom de Jeu de Variantes: Modèle principal; Position: Non défini; Fonction structurelle: Non défini; Affichage sur filtre de rénovation: Tous les filtres appropriés; État de rénovation: Existant; État de Variante: Modèle principal; Jeu de Variantes: Modèle principal
ArchiCADQuantities - Nombre de Fenêtres: 0; Volume des poteaux: 0 m3; Épaisseur couche d'air: 0 mm; Épaisseur de composant de mur sur face intérieure: 180 mm; Épaisseur de composant de mur sur face extérieure: 180 mm; Superficie des fenêtres: 0 m2; Largeur totale des Fenêtres: 0 mm; Épaisseur du Mur à la fin: 180 mm; Largeur: 180 mm; Décalage supérieur: 0 mm; Épaisseur: 180 mm; Épaisseur couche isolation: 0 mm
AC_Pset_RenovationAndPhasing - Renovation Status: Existing
Name | In | Emplacement de ligne de référence | Surface de face intérieure = Surface de face extérieure = Surfaces (Toutes) = Surface latérale | ID de l'élément = Lien et ID d'élément = ID de Parent | Nom d'étage d'implantation | Numéro d'étage d'implantation | Nombre de Portes | Nombre de trous (Nombre d'ouvertures vides) | Nombre de Poteaux | Hauteur maximale de la couche de Mur sur face intérieure (mm) = Hauteur maximale du Mur (mm) = Hauteur maximale de la couche de Mur sur face extérieure (mm) = Hauteur (mm) = Altitude supérieure à étage d'implantation (mm) | Hauteur minimale de la couche de Mur sur face intérieure (mm) = Hauteur minimale du Mur (mm) = Hauteur minimale de la couche de Mur sur face extérieure (mm) | Superficie des portes (m2) | Largeur totale des Portes (mm) | Volume de composant de mur sur face intérieure (net) (m3) = Volume de composant de mur sur face extérieure (net) (m3) = Volume (net) (m3) | Superficie analytique des ouvertures sur face intérieure (m2) = Superficie analytique des ouvertures sur face extérieure (m2) | Longueur moyenne du mur (mm) = Longueur du Mur au centre (mm) | Superficie de la face intérieure du mur (nette) (m2) | Superficie de la face extérieure du mur (nette) (m2) = Superficie en plan (m2) = Superficie inférieure (nette) (m2) | Volume analytique des ouvertures (m3) | Longueur de ligne de référence (mm) | Longueur de la face intérieure du mur (conditionnelle) (mm) | Superficie de la face intérieure du mur (conditionnelle) (m2) | Longueur de la face extérieure du mur (conditionnelle) (mm) | Superficie de la face extérieure du mur (conditionnelle) (m2) | Volume du composant face intérieure du mur (conditionnel) (m3) = Volume du composant face extérieure du mur (conditionnel) (m3) = Volume (conditionnel) (m3) | Superficie de la face intérieure du mur (brute) (m2) | Superficie de la face extérieure du mur (brute) (m2) | Longueur de Mur sur face intérieure (mm) | Longueur de Mur sur face extérieure (mm) | Superficie des baies libres dans le Mur (m2) | Superficie (m2) = Superficie supérieure (nette) (m2) | Altitude à Zéro du Projet (mm) = Altitude de Référence Niveau 1 (mm) = Altitude de Référence Niveau 2 (mm) = Altitude à niveau de la mer (mm) | Altitude à étage lié/étage d'implantation (mm) = Décalage étage d'implantation (mm) | Longueur 3D (mm) | Volume (brut) (m3) | Périmètre Plan (mm) | Altitude supérieure à premier niveau de référence (mm) = Altitude supérieure à Zéro du projet (mm) = Altitude supérieure à niveau de la mer (mm) = Altitude supérieure à deuxième niveau de référence (mm) | Altitude inférieure à premier niveau de référence (mm) = Altitude inférieure à Zéro du projet (mm) = Altitude inférieure à niveau de la mer (mm) = Altitude inférieure à deuxième niveau de référence (mm) | Altitude inférieure à étage d'implantation (mm) | Superficie de l'arête (nette) (m2)
Mur-133 | sousol | Face extérieure | Plâtre Lisse | Mur-133 | sousol | 2 | 0 | 0 | 0 | 3000 | 3000 | 0 | 0 | 3.02314 | 0 | 5590 | 16.5504 | 16.014 | 0 | 5860 | 5500 | 16.5504 | 5680 | 16.014 | 3.02314 | 16.5504 | 17.04 | 5500 | 5680 | 0 | 1.0224 | 4.18415e-12 | 4.18415e-12 | 5680 | 3.02314 | 11614.6 | 3000 | 0 | 0 | 3.3276
Mur-132 | sousol | Centre | Lavis blanc | Mur-132 | sousol | 2 | 0 | 0 | 0 | 2700 | 2000 | 0 | 0 | 0.176678 | 0 | 400 | 0.981531 | 0.981555 | 0 | 400 | 400 | 0.981531 | 400 | 0.981555 | 0.176678 | 1.08 | 1.08 | 400 | 400 | 0 | 0.072 | 4.18415e-12 | 4.18415e-12 | 400 | 0.1944 | 1160 | 2700 | 4.21885e-12 | 4.21885e-12 | 1.026
Mur-133 | sousol | Face extérieure | Plâtre Lisse | Mur-133 | sousol | 2 | 0 | 0 | 1 | 3000 | 0 | 0 | 0 | 2.6892 | 0 | 5360 | 14.94 | 14.94 | 0 | 5630 | 5270 | 14.94 | 5450 | 14.94 | 2.6892 | 15.8604 | 16.35 | 5270 | 5450 | 0 | 0.909 | 4.18415e-12 | 4.18415e-12 | 5050 | 2.89894 | 11154.6 | 3000 | 0 | 0 | 2.358
Mur-132 | sousol | Face extérieure | Lavis blanc | Mur-132 | sousol | 2 | 0 | 0 | 0 | 2460 | 2000 | 0 | 0 | 0.179302 | 0 | 442.327 | 0.996124 | 0.996124 | 0 | 442.327 | 442.327 | 0.996124 | 442.327 | 0.996124 | 0.179302 | 1.08812 | 1.08812 | 442.327 | 442.327 | 0 | 0.0796189 | 4.18415e-12 | 4.18415e-12 | 442.327 | 0.195862 | 1244.65 | 2460 | 4.21885e-12 | 4.21885e-12 | 1.00884
Mur-132 | sousol | Face extérieure | Peinture-11 | Mur-132 | sousol | 2 | 2 | 2 | 0 | 3000 | 3000 | 0.411671 | 823.342 | 19.796 | 0.780305 | 36919.3 | 106.128 | 110.537 | 0.140455 | 36927.9 | 36209.6 | 106.908 | 36588.9 | 111.318 | 19.9365 | 110.199 | 111.318 | 36729.6 | 37108.9 | 0.34 | 6.50641 | 4.18415e-12 | 4.18415e-12 | 37108.9 | 19.9365 | 74361.6 | 3000 | 0 | 0 | 14.7292
Mur-132 | sousol | Face extérieure | Peinture-11 | Mur-132 | sousol | 2 | 0 | 0 | 0 | 2460 | 2460 | 0 | 0 | 2.31366 | 0 | 5225.07 | 12.6077 | 12.8537 | 0 | 5044.15 | 5225.07 | 12.6077 | 5225.07 | 12.8537 | 2.31366 | 12.8537 | 12.8537 | 5225.07 | 5225.07 | 0 | 0.940513 | 4.18415e-12 | 4.18415e-12 | 5387.71 | 2.31366 | 10935.3 | 2460 | 0 | 0 | 3.07457
2 x Mur-133 | sousol | Face extérieure | Plâtre Lisse | Mur-133 | sousol | 2 | 0 | 0 | 0 | 3000 | 2100 | 0 | 0 | 2.81376 | 0 | 5270 | 15.632 | 15.632 | 0 | 5630 | 5270 | 15.632 | 5270 | 15.632 | 2.81376 | 15.8604 | 15.8604 | 5270 | 5270 | 0 | 0.981 | 4.18415e-12 | 4.18415e-12 | 5450 | 2.85487 | 10900 | 3000 | 4.21885e-12 | 4.21885e-12 | 2.8566
Mur-133 | sousol | Face extérieure | Plâtre Lisse | Mur-133 | sousol | 2 | 0 | 0 | 0 | 2700 | 2260 | 0 | 0 | 2.88369 | 0 | 5982.41 | 16.0205 | 15.5741 | 0 | 6342.41 | 5982.41 | 16.0205 | 5982.41 | 15.5741 | 2.88369 | 16.1525 | 16.1525 | 5982.41 | 5982.41 | 0 | 1.07683 | 4.18415e-12 | 4.18415e-12 | 5982.41 | 2.90745 | 12324.8 | 2700 | 4.21885e-12 | 4.21885e-12 | 3.07167
Mur-132 | sousol | Face extérieure | Peinture-11 | Mur-132 | sousol | 2 | 0 | 0 | 0 | 2586.04 | 2586.04 | 0 | 0 | 4.07965 | 0 | 8780 | 22.2399 | 23.0895 | 0 | 8600 | 8600 | 22.2399 | 8960 | 23.0895 | 4.07965 | 22.2399 | 23.0895 | 8600 | 8960 | 0 | 1.5804 | 4.18415e-12 | 4.18415e-12 | 8960 | 4.07965 | 18069.1 | 2586.04 | 0 | 0 | 4.44369
Mur-133 | sousol | Face extérieure | Plâtre Lisse | Mur-133 | sousol | 2 | 0 | 0 | 0 | 3000 | 3000 | 0 | 0 | 0.95958 | 0 | 1780 | 5.862 | 4.8 | 0 | 1600 | 1960 | 5.862 | 1600 | 4.8 | 0.95958 | 5.862 | 4.8 | 1960 | 1600 | 0 | 0.3204 | 4.18415e-12 | 4.18415e-12 | 1960 | 0.95958 | 4069.12 | 3000 | 0 | 0 | 2.16069
Mur-132 | sousol | Face extérieure | Lavis blanc | Mur-132 | sousol | 2 | 0 | 0 | 0 | 2700 | 2700 | 0 | 0 | 0.82134 | 0 | 1690 | 4.32 | 4.806 | 0 | 1780 | 1600 | 4.32 | 1780 | 4.806 | 0.82134 | 4.32 | 4.806 | 1600 | 1780 | 0 | 0.3042 | 4.18415e-12 | 4.18415e-12 | 1780 | 0.82134 | 3814.56 | 2700 | 0 | 0 | 1.78171
Mur-133 | sousol | Face extérieure | Plâtre Lisse | Mur-133 | sousol | 2 | 0 | 0 | 0 | 2260 | 2260 | 0 | 0 | 1.19218 | 0 | 2930.62 | 6.4198 | 6.8266 | 0 | 3020.62 | 2840.62 | 6.4198 | 3020.62 | 6.8266 | 1.19218 | 6.4198 | 6.8266 | 2840.62 | 3020.62 | 0 | 0.527512 | 4.18415e-12 | 4.18415e-12 | 3020.62 | 1.19218 | 6295.8 | 2260 | 0 | 0 | 2.03713
Mur-132 | sousol | Face extérieure | Peinture-11 | Mur-132 | sousol | 2 | 1 | 0 | 0 | 3000 | 3000 | 0.25 | 500 | 8.95231 | 0.2652 | 16665.4 | 47.8549 | 50.2738 | 0.047736 | 16846.3 | 16484.5 | 48.1201 | 16846.3 | 50.539 | 9.00004 | 49.4615 | 50.539 | 16484.5 | 16846.3 | 0 | 3.01441 | 4.18415e-12 | 4.18415e-12 | 16846.3 | 9.00004 | 33841.9 | 3000 | 0 | 0 | 7.55894 | ArchiCADProperties - Nom de zone liée: Pl; Numéro de zone liée: 818
Mur-133 | sousol | Face extérieure | Plâtre Lisse | Mur-133 | sousol | 2 | 0 | 0 | 0 | 3000 | 3000 | 0 | 0 | 2.91004 | 0 | 5387.61 | 15.8996 | 15.8942 | 0 | 5659 | 5297.14 | 15.8996 | 5478.07 | 15.8942 | 2.91004 | 15.8996 | 16.4342 | 5297.14 | 5478.07 | 0 | 0.984406 | 4.18415e-12 | 4.18415e-12 | 5478.07 | 2.91004 | 11198.7 | 3000 | 0 | 0 | 3.23624 | ArchiCADProperties - Nom de zone liée: Pl; Numéro de zone liée: 818
Mur-133 | sousol | Face extérieure | Plâtre Lisse | Mur-133 | sousol | 2 | 0 | 0 | 0 | 3000 | 3000 | 0 | 0 | 1.96399 | 0 | 3637.03 | 11.1807 | 10.1014 | 0 | 3727.14 | 3726.91 | 11.1807 | 3547.14 | 10.1014 | 1.96399 | 11.1807 | 10.6414 | 3726.91 | 3547.14 | 0 | 0.654665 | 4.18415e-12 | 4.18415e-12 | 3726.91 | 1.96399 | 7708.29 | 3000 | 0 | 0 | 2.61204 | ArchiCADProperties - Nom de zone liée: Pl; Numéro de zone liée: 818; Zones conflictuelles: Pl
Mur-132 | sousol | Face extérieure | Lavis blanc | Mur-132 | sousol | 2 | 0 | 0 | 0 | 3000 | 2750 | 0 | 0 | 2.83158 | 0 | 5230 | 15.533 | 15.929 | 0 | 5500 | 5140 | 15.533 | 5320 | 15.929 | 2.83158 | 15.573 | 15.969 | 5140 | 5320 | 0 | 0.99 | 4.18415e-12 | 4.18415e-12 | 5500 | 2.83878 | 10894.6 | 3000 | 0 | 0 | 3.22403
Mur-132 | sousol | Face extérieure | Lavis blanc | Mur-132 | sousol | 2 | 4 | 0 | 0 | 2200 | 2200 | 16.8612 | 8230 | 1.00765 | 17.0688 | 10303.1 | 4.38807 | 5.57607 | 3.07238 | 10573.1 | 1903.12 | 4.38807 | 2083.12 | 5.57607 | 4.08004 | 22.4689 | 22.8649 | 10213.1 | 10393.1 | 0 | 0.358762 | 4.18415e-12 | 4.18415e-12 | 10393.1 | 4.08004 | 21040.8 | 2200 | 0 | 0 | 3.16935 | ArchiCADProperties - Nom de zone liée: Pl; Numéro de zone liée: 818
Mur-132 | sousol | Face extérieure | Lavis blanc | Mur-132 | sousol | 2 | 1 | 0 | 0 | 2586.04 | 2586.04 | 3.88268 | 2773.35 | 5.82137 | 3.93862 | 14006.3 | 31.6657 | 31.7238 | 0.708951 | 14285.9 | 11294.3 | 31.6657 | 11131.6 | 31.7238 | 6.53032 | 36.4899 | 36.0692 | 14087.7 | 13925 | 0 | 2.05073 | 4.18415e-12 | 4.18415e-12 | 14267.6 | 6.53032 | 28435.2 | 2586.04 | 0 | 0 | 5.6971
Mur-133 | sousol | Face extérieure | Plâtre Lisse | Mur-133 | sousol | 2 | 0 | 0 | 0 | 3000 | 2100 | 0 | 0 | 2.8818 | 0 | 5450 | 16.01 | 16.01 | 0 | 5630 | 5450 | 16.01 | 5450 | 16.01 | 2.8818 | 16.35 | 16.35 | 5450 | 5450 | 0 | 0.981 | 4.18415e-12 | 4.18415e-12 | 5450 | 2.943 | 11260 | 3000 | 4.21885e-12 | 4.21885e-12 | 2.889
Mur-133 | sousol | Face extérieure | Plâtre Lisse | Mur-133 | sousol | 2 | 0 | 0 | 1 | 2950 | 0 | 0 | 0 | 3.05984 | 0 | 5982.41 | 16.8991 | 16.9991 | 0 | 6342.41 | 5982.41 | 16.8991 | 5982.41 | 16.9991 | 3.05984 | 17.6895 | 17.6895 | 5982.41 | 5982.41 | 0 | 1.03723 | 4.18415e-12 | 4.18415e-12 | 5762.41 | 3.18411 | 12324.8 | 2950 | 0 | 0 | 2.60547
Mur-133 | sousol | Face extérieure | Plâtre Lisse | Mur-133 | sousol | 2 | 0 | 0 | 1 | 2950 | 0 | 0 | 0 | 2.68154 | 0 | 5270 | 14.7925 | 14.8975 | 0 | 5630 | 5270 | 14.7925 | 5270 | 14.8975 | 2.68154 | 15.5879 | 15.5879 | 5270 | 5270 | 0 | 0.909 | 4.18415e-12 | 4.18415e-12 | 5050 | 2.80582 | 10900 | 2950 | 0 | 0 | 2.34899
Mur-133 | sousol | Face extérieure | Plâtre Lisse | Mur-133 | sousol | 2 | 0 | 0 | 0 | 2700 | 2700 | 0 | 0 | 3.2693 | 0 | 6712.29 | 18.3662 | 17.9594 | 0 | 6802.29 | 6802.29 | 18.3662 | 6622.29 | 17.9594 | 3.2693 | 18.3662 | 17.9594 | 6802.29 | 6622.29 | 0 | 1.22441 | 4.18415e-12 | 4.18415e-12 | 6802.29 | 3.2693 | 13859.1 | 2700 | 0 | 0 | 3.58933
Mur-133 | sousol | Face extérieure | Plâtre Lisse | Mur-133 | sousol | 2 | 1 | 0 | 0 | 2480 | 2480 | 1.8972 | 930 | 1.13202 | 2.1008 | 3382.98 | 6.28898 | 5.84258 | 0.378144 | 3382.98 | 2372.98 | 6.28898 | 2372.98 | 5.84258 | 1.51016 | 8.38978 | 8.38978 | 3382.98 | 3382.98 | 0 | 0.427136 | 4.18415e-12 | 4.18415e-12 | 3382.98 | 1.51016 | 7125.95 | 2480 | 4.21885e-12 | 4.21885e-12 | 1.92887
2 x Mur-132 | sousol | Face extérieure | Lavis blanc | Mur-132 | sousol | 2 | 0 | 0 | 0 | 2460 | 2460 | 0 | 0 | 1.36175 | 0 | 3075.32 | 7.78668 | 6.90108 | 0 | 3165.32 | 3165.32 | 7.78668 | 2985.32 | 6.90108 | 1.36175 | 7.78668 | 7.34388 | 3165.32 | 2985.32 | 0 | 0.553557 | 4.18415e-12 | 4.18415e-12 | 3165.32 | 1.36175 | 6585.19 | 2460 | 0 | 0 | 2.17613
Mur-132 | sousol | Face extérieure | Lavis blanc | Mur-132 | sousol | 2 | 1 | 0 | 0 | 2260 | 2260 | 1.8972 | 930 | 4.27141 | 2.1008 | 11429.6 | 23.3232 | 23.3233 | 0.378144 | 11429.6 | 10419.6 | 23.3232 | 10419.6 | 23.3233 | 4.64955 | 25.8308 | 25.8309 | 11429.6 | 11429.6 | 0 | 1.87552 | 4.18415e-12 | 4.18415e-12 | 11609.6 | 4.64955 | 23368.3 | 2260 | 0 | 0 | 5.08351
Mur-133 | sousol | Face extérieure | Plâtre Lisse | Mur-133 | sousol | 2 | 0 | 0 | 1 | 2950 | 0 | 0 | 0 | 3.22445 | 0 | 6572.41 | 17.1585 | 18.1791 | 0 | 6662.41 | 6482.41 | 17.1585 | 6662.41 | 18.1791 | 3.22445 | 19.1231 | 19.6541 | 6482.41 | 6662.41 | 0 | 1.09303 | 4.18415e-12 | 4.18415e-12 | 6162.41 | 3.48995 | 13579.4 | 2950 | 0 | 0 | 2.93701
Mur-132 | sousol | Face extérieure | Peinture-11 | Mur-132 | sousol | 2 | 0 | 1 | 1 | 2460 | 0 | 0 | 0 | 7.12267 | 12.15 | 21778.3 | 39.5994 | 39.0538 | 2.187 | 21958.3 | 16558.3 | 39.5994 | 16198.3 | 39.0538 | 9.30967 | 53.5746 | 52.725 | 21958.3 | 21598.3 | 12.15 | 2.91029 | 4.18415e-12 | 4.18415e-12 | 16258.3 | 9.56697 | 44065.7 | 2460 | 0 | 0 | 7.05801 | ArchiCADProperties - Nom de zone liée: Pl; Numéro de zone liée: 818
Mur-133 | sousol | Face extérieure | Plâtre Lisse | Mur-133 | sousol | 2 | 3 | 1 | 2 | 2720 | 0 | 16.605 | 8100 | 1.24026 | 23.4448 | 13990.3 | 5.55902 | 6.97047 | 4.22007 | 14031.1 | 2512.94 | 5.55902 | 2594.65 | 6.97047 | 5.46033 | 37.9425 | 38.1647 | 13949.4 | 14031.1 | 6.84288 | 0.360683 | 4.18415e-12 | 4.18415e-12 | 13499.4 | 6.84965 | 28367.4 | 2720 | 0 | 0 | 1.89651
Mur-132 | sousol | Face extérieure | Lavis blanc | Mur-132 | sousol | 2 | 0 | 0 | 0 | 3000 | 1950 | 0 | 0 | 2.84033 | 0 | 5270 | 15.7796 | 15.7796 | 0 | 5630 | 5270 | 15.7796 | 5270 | 15.7796 | 2.84033 | 15.819 | 15.819 | 5270 | 5270 | 0 | 0.981 | 4.18415e-12 | 4.18415e-12 | 5450 | 2.84742 | 10900 | 3000 | 4.21885e-12 | 4.21885e-12 | 2.862
Mur-132 | sousol | Face extérieure | Lavis blanc | Mur-132 | sousol | 2 | 0 | 0 | 0 | 2460 | 2000 | 0 | 0 | 0.16056 | 0 | 400 | 0.892 | 0.892 | 0 | 400 | 400 | 0.892 | 400 | 0.892 | 0.16056 | 0.984 | 0.984 | 400 | 400 | 0 | 0.072 | 4.18415e-12 | 4.18415e-12 | 400 | 0.17712 | 1160 | 2460 | 4.21885e-12 | 4.21885e-12 | 0.9936
Mur-132 | sousol | Centre | Lavis blanc | Mur-132 | sousol | 2 | 0 | 0 | 0 | 2700 | 2000 | 0 | 0 | 0.176612 | 0 | 400 | 0.981167 | 0.981192 | 0 | 400 | 400 | 0.981167 | 400 | 0.981192 | 0.176612 | 1.08 | 1.08 | 400 | 400 | 0 | 0.072 | 4.18415e-12 | 4.18415e-12 | 400 | 0.1944 | 1160 | 2700 | 4.21885e-12 | 4.21885e-12 | 1.026
Mur-132 | sousol | Face extérieure | Lavis blanc | Mur-132 | sousol | 2 | 0 | 1 | 0 | 2950 | 2100 | 0 | 0 | 6.1931 | 10.714 | 16840.1 | 33.0147 | 34.6498 | 1.92851 | 16921.4 | 11401.7 | 33.0147 | 11564.4 | 34.6498 | 8.12161 | 49.4382 | 49.9181 | 16758.7 | 16921.4 | 10.714 | 2.06696 | 4.18415e-12 | 4.18415e-12 | 16921.4 | 8.94207 | 34102.7 | 2950 | 0 | 0 | 5.37923
Mur-133 | sousol | Face extérieure | Plâtre Lisse | Mur-133 | sousol | 2 | 0 | 0 | 0 | 2950 | 2950 | 0 | 0 | 3.61233 | 0 | 6802.89 | 20.057 | 19.3566 | 0 | 6892.89 | 6892.89 | 20.057 | 6712.89 | 19.3566 | 3.61233 | 20.334 | 19.803 | 6892.89 | 6712.89 | 0 | 1.22452 | 4.18415e-12 | 4.18415e-12 | 6892.89 | 3.61233 | 14040.3 | 2950 | 0 | 0 | 3.73099
Mur-133 | sousol | Face extérieure | Plâtre Lisse | Mur-133 | sousol | 2 | 1 | 0 | 0 | 2950 | 2950 | 1.8972 | 930 | 1.80698 | 2.1008 | 4115.1 | 9.81465 | 9.77325 | 0.378144 | 4025.1 | 3195.1 | 9.81465 | 3015.1 | 9.77325 | 2.18512 | 12.4051 | 11.8741 | 4205.1 | 4025.1 | 0 | 0.558918 | 4.18415e-12 | 4.18415e-12 | 4205.1 | 2.18512 | 8664.76 | 2950 | 0 | 0 | 2.58158
Mur-133 | sousol | Face extérieure | Plâtre Lisse | Mur-133 | sousol | 2 | 3 | 1 | 5 | 2720 | 0 | 14.76 | 7200 | 1.34784 | 24.1484 | 13531.9 | 5.61173 | 8.60689 | 4.34671 | 13801.9 | 1547.05 | 5.61173 | 1727.05 | 8.60689 | 5.69455 | 36.5621 | 37.0517 | 13441.9 | 13621.9 | 9.44487 | 0.0642857 | 4.18415e-12 | 4.18415e-12 | 12471.9 | 6.62524 | 27498.5 | 2720 | 0 | 0 | 1.7709
Mur-133 | sousol | Face extérieure | Plâtre Lisse | Mur-133 | sousol | 2 | 0 | 0 | 1 | 2950 | 0 | 0 | 0 | 2.8462 | 0 | 5860.07 | 15.0571 | 16.0777 | 0 | 5950.07 | 5770.07 | 15.0571 | 5950.07 | 16.0777 | 2.8462 | 17.0217 | 17.5527 | 5770.07 | 5950.07 | 0 | 0.964813 | 4.18415e-12 | 4.18415e-12 | 5450.07 | 3.1117 | 12154.7 | 2950 | 0 | 0 | 2.68057
Mur-133 | sousol | Face extérieure | Peinture-11 | Mur-133 | sousol | 2 | 0 | 0 | 0 | 3000 | 3000 | 0 | 0 | 9.4729 | 0 | 17542.4 | 51.09 | 53.1672 | 0 | 17722.4 | 17362.4 | 51.09 | 17722.4 | 53.1672 | 9.4729 | 52.0872 | 53.1672 | 17362.4 | 17722.4 | 0 | 3.15763 | 4.18415e-12 | 4.18415e-12 | 17722.4 | 9.4729 | 35593.9 | 3000 | 0 | 0 | 7.84262
Mur-133 | sousol | Face extérieure | Plâtre Lisse | Mur-133 | sousol | 2 | 0 | 0 | 1 | 3000 | 0 | 0 | 0 | 3.20322 | 0 | 6162.41 | 17.5257 | 17.5257 | 0 | 6342.41 | 5982.41 | 17.5257 | 6342.41 | 17.5257 | 3.20322 | 17.9886 | 19.0272 | 5982.41 | 6342.41 | 0 | 1.06774 | 4.18415e-12 | 4.18415e-12 | 6021.88 | 3.33143 | 12833.9 | 3000 | 0 | 0 | 2.89915
Mur-133 | sousol | Face extérieure | Plâtre Lisse | Mur-133 | sousol | 2 | 0 | 1 | 0 | 2950 | 2100 | 0 | 0 | 6.10713 | 10.714 | 16665.4 | 34.4373 | 32.2105 | 1.92851 | 16846.3 | 11489.3 | 34.4373 | 11127.5 | 32.2105 | 8.03564 | 49.7056 | 48.7178 | 16846.3 | 16484.5 | 10.714 | 2.05344 | 4.18415e-12 | 4.18415e-12 | 16864.6 | 8.85811 | 33841.9 | 2950 | 0 | 0 | 5.57941
Mur-133 | sousol | Face extérieure | Plâtre Lisse | Mur-133 | sousol | 2 | 0 | 0 | 0 | 3000 | 2100 | 0 | 0 | 3.15562 | 0 | 5982.41 | 17.5312 | 17.5312 | 0 | 6342.41 | 5982.41 | 17.5312 | 5982.41 | 17.5312 | 3.15562 | 17.9886 | 17.9886 | 5982.41 | 5982.41 | 0 | 1.10923 | 4.18415e-12 | 4.18415e-12 | 6162.41 | 3.23795 | 12324.8 | 3000 | 4.21885e-12 | 4.21885e-12 | 3.11307
Mur-132 | sousol | Face extérieure | Lavis blanc | Mur-132 | sousol | 2 | 0 | 0 | 0 | 2260 | 2260 | 0 | 0 | 0.666983 | 0 | 1639.58 | 3.29872 | 3.70541 | 0 | 1639.56 | 1639.61 | 3.29872 | 1639.56 | 3.70541 | 0.666983 | 3.70552 | 3.70541 | 1639.61 | 1639.56 | 0 | 0.295125 | 4.18415e-12 | 4.18415e-12 | 1819.6 | 0.666983 | 3788.31 | 2260 | 0 | 0 | 1.7409
Mur-133 | sousol | Face extérieure | Plâtre Lisse | Mur-133 | sousol | 2 | 1 | 0 | 0 | 3000 | 4.21885e-12 | 1.8972 | 930 | 2.38612 | 2.1008 | 5290 | 13.0132 | 12.9592 | 0.378144 | 5560 | 4190 | 13.0132 | 4370 | 12.9592 | 2.76426 | 15.114 | 15.6 | 5200 | 5380 | 0 | 0.7542 | 4.18415e-12 | 4.18415e-12 | 5200 | 2.76426 | 11014.6 | 3000 | 0 | 0 | 2.97151
Mur-133 | sousol | Face extérieure | Plâtre Lisse | Mur-133 | sousol | 2 | 1 | 0 | 0 | 3000 | 3000 | 1.8972 | 930 | 0.518055 | 2.1008 | 1659.63 | 2.87877 | 2.8774 | 0.378144 | 1659.4 | 649.857 | 2.87877 | 649.399 | 2.8774 | 0.896199 | 4.97957 | 4.9782 | 1659.86 | 1659.4 | 0 | 0.116933 | 4.18415e-12 | 4.18415e-12 | 1659.86 | 0.896199 | 3679.26 | 3000 | 4.21885e-12 | 4.21885e-12 | 1.49567
Mur-133 | sousol | Face extérieure | Plâtre Lisse | Mur-133 | sousol | 2 | 1 | 0 | 0 | 3000 | 3000 | 1.8972 | 930 | 1.52298 | 2.1008 | 3520.6 | 7.65169 | 8.19032 | 0.378144 | 3430.37 | 2420.83 | 7.65169 | 2600.37 | 8.19032 | 1.90112 | 10.2925 | 10.8311 | 3430.83 | 3610.37 | 0 | 0.451908 | 4.18415e-12 | 4.18415e-12 | 3610.37 | 1.90112 | 7475.44 | 3000 | 0 | 0 | 2.38832 | ArchiCADProperties - Nom de zone liée: Pl; Numéro de zone liée: 818
Mur-133 | sousol | Face extérieure | Plâtre Lisse | Mur-133 | sousol | 2 | 1 | 0 | 0 | 3000 | 3000 | 2.1012 | 1030 | 0.32194 | 2.3088 | 1365.79 | 1.78891 | 1.78821 | 0.415584 | 1365.67 | 255.904 | 1.78891 | 255.668 | 1.78821 | 0.737524 | 4.09771 | 4.09701 | 1365.9 | 1365.67 | 0 | 0.0460415 | 4.18415e-12 | 4.18415e-12 | 1365.9 | 0.737524 | 3091.57 | 3000 | 0 | 0 | 1.37188 | ArchiCADProperties - Nom de zone liée: Pl; Numéro de zone liée: 818; Zones conflictuelles: Pl
Mur-132 | sousol | Face extérieure | Lavis blanc | Mur-132 | sousol | 2 | 0 | 0 | 0 | 2700 | 2250 | 0 | 0 | 2.84418 | 0 | 5857.77 | 15.7886 | 15.3273 | 0 | 6042.34 | 5853.2 | 15.7886 | 5862.34 | 15.3273 | 2.84418 | 15.8937 | 15.9183 | 5853.2 | 5862.34 | 0 | 1.0868 | 4.18415e-12 | 4.18415e-12 | 6042.34 | 2.86308 | 12075.8 | 2700 | 0 | 0 | 3.01122
2 x Mur-132 | sousol | Face extérieure | Peinture-11 | Mur-132 | sousol | 2 | 0 | 0 | 0 | 3000 | 3000 | 0 | 0 | 0.378 | 0 | 700 | 1.56 | 2.64 | 0 | 880 | 520 | 1.56 | 880 | 2.64 | 0.378 | 1.56 | 2.64 | 520 | 880 | 0 | 0.126 | 4.18415e-12 | 4.18415e-12 | 880 | 0.378 | 1909.12 | 3000 | 0 | 0 | 1.77935
Mur-132 | sousol | Face extérieure | Peinture-11 | Mur-132 | sousol | 2 | 0 | 0 | 0 | 3000 | 2800 | 0 | 0 | 10.2611 | 0 | 19011.9 | 53.6535 | 57.5496 | 0 | 19183.2 | 18840.6 | 53.6535 | 19183.2 | 57.5496 | 10.2611 | 56.5625 | 57.5496 | 18840.6 | 19183.2 | 0 | 3.43678 | 4.18415e-12 | 4.18415e-12 | 19183.2 | 10.2701 | 38520.9 | 3000 | 0 | 0 | 8.3043
Mur-133 | sousol | Face extérieure | Plâtre Lisse | Mur-133 | sousol | 2 | 0 | 0 | 0 | 3000 | 2720 | 0 | 0 | 2.97907 | 0 | 5500 | 16.5504 | 16.5277 | 0 | 5860 | 5500 | 16.5504 | 5500 | 16.5277 | 2.97907 | 16.5504 | 16.5504 | 5500 | 5500 | 0 | 1.0224 | 4.18415e-12 | 4.18415e-12 | 5680.05 | 2.97907 | 11360 | 3000 | 4.21885e-12 | 4.21885e-12 | 3.0834
Mur-132 | sousol | Face extérieure | Lavis blanc | Mur-132 | sousol | 2 | 0 | 0 | 0 | 2586.04 | 2586.04 | 0 | 0 | 1.80198 | 0 | 3859.78 | 10.2143 | 9.80751 | 0 | 3949.79 | 3949.78 | 10.2143 | 3769.79 | 9.80751 | 1.80198 | 10.2143 | 9.80751 | 3949.78 | 3769.79 | 0 | 0.71097 | 4.18415e-12 | 4.18415e-12 | 3949.79 | 1.80198 | 8154.12 | 2586.04 | 0 | 0 | 2.52141
Mur-133 | sousol | Face extérieure | Plâtre Lisse | Mur-133 | sousol | 2 | 4 | 0 | 2 | 2720 | 0 | 16.6572 | 8130 | 0.844099 | 16.8608 | 10377.5 | 3.63456 | 4.71432 | 3.03494 | 10566.6 | 2158.35 | 3.63456 | 2176.64 | 4.71432 | 3.87904 | 28.2019 | 28.2517 | 10368.4 | 10386.6 | 0 | 0.24435 | 4.18415e-12 | 4.18415e-12 | 9576.64 | 5.08082 | 21115.9 | 2720 | 0 | 0 | 1.6495
Mur-132 | sousol | Face extérieure | Peinture-11 | Mur-132 | sousol | 2 | 0 | 0 | 0 | 3000 | 3000 | 0 | 0 | 1.66401 | 0 | 3080 | 8.70899 | 9.78 | 0 | 3260 | 2900 | 8.70899 | 3260 | 9.78 | 1.66401 | 8.70899 | 9.78 | 2900 | 3260 | 0 | 0.5706 | 4.18415e-12 | 4.18415e-12 | 3260 | 1.66401 | 6669.12 | 3000 | 0 | 0 | 2.66483
Mur-133 | sousol | Face extérieure | Plâtre Lisse | Mur-133 | sousol | 2 | 0 | 0 | 0 | 2749.08 | 2749.08 | 0 | 0 | 0.474454 | 0 | 967.365 | 2.61235 | 2.65936 | 0 | 967.365 | 967.365 | 2.61235 | 967.365 | 2.65936 | 0.474454 | 2.61235 | 2.65936 | 967.365 | 967.365 | 0 | 0.174126 | 4.18415e-12 | 4.18415e-12 | 1130 | 0.474454 | 2419.91 | 2749.08 | 0 | 0 | 1.66396
Mur-132 | sousol | Face extérieure | Lavis blanc | Mur-132 | sousol | 2 | 6 | 1 | 3 | 2720 | 0 | 29.52 | 14400 | 2.38408 | 36.5119 | 22430.7 | 11.5781 | 13.0469 | 6.57215 | 22520.7 | 4354.41 | 11.5781 | 4534.41 | 13.0469 | 8.95622 | 60.7667 | 61.2563 | 22340.7 | 22520.7 | 7.35192 | 1.78278 | 4.18415e-12 | 4.18415e-12 | 20780.7 | 10.9821 | 45296 | 2720 | 0 | 0 | 4.51668
Mur-133 | sousol | Face extérieure | Plâtre Lisse | Mur-133 | sousol | 2 | 3 | 0 | 0 | 2950 | 1950 | 14.76 | 7200 | 1.08736 | 14.0401 | 9794.93 | 4.98501 | 6.28824 | 2.52721 | 10066.3 | 2504.47 | 4.98501 | 2685.4 | 6.28824 | 3.61458 | 28.6282 | 29.1619 | 9704.47 | 9885.4 | 0 | 0.467088 | 4.18415e-12 | 4.18415e-12 | 2686.11 | 5.20111 | 20013.4 | 2950 | 0 | 0 | 1.89261
Mur-132 | sousol | Face extérieure | Lavis blanc | Mur-132 | sousol | 2 | 0 | 0 | 0 | 2260 | 2260 | 0 | 0 | 3.53627 | 0 | 8692.88 | 19.4425 | 19.8493 | 0 | 8602.88 | 8602.88 | 19.4425 | 8782.88 | 19.8493 | 3.53627 | 19.4425 | 19.8493 | 8602.88 | 8782.88 | 0 | 1.56472 | 4.18415e-12 | 4.18415e-12 | 8782.88 | 3.53627 | 17820.3 | 2260 | 0 | 0 | 4.11154 | ArchiCADProperties - Nom de zone liée: Pl; Numéro de zone liée: 818
Mur-133 | sousol | Face extérieure | Plâtre Lisse | Mur-133 | sousol | 2 | 0 | 1 | 2 | 2720 | 0 | 0 | 0 | 0.692489 | 9.67709 | 5492.15 | 3.35756 | 3.84716 | 1.74188 | 5672.15 | 653.606 | 3.35756 | 653.606 | 3.84716 | 2.43436 | 14.9386 | 14.9386 | 5492.15 | 5492.15 | 9.67709 | 0.0240491 | 4.18415e-12 | 4.18415e-12 | 4972.15 | 2.68896 | 11344.3 | 2720 | 0 | 0 | 1.40864
Mur-133 | sousol | Face extérieure | Plâtre Lisse | Mur-133 | sousol | 2 | 0 | 0 | 0 | 3000 | 3000 | 0 | 0 | 0.247714 | 0 | 458.73 | 1.37619 | 1.37619 | 0 | 638.73 | 458.73 | 1.37619 | 458.73 | 1.37619 | 0.247714 | 1.37619 | 1.37619 | 458.73 | 458.73 | 0 | 0.0825714 | 4.18415e-12 | 4.18415e-12 | 458.73 | 0.247714 | 1277.46 | 3000 | 4.21885e-12 | 4.21885e-12 | 1.24514
Mur-133 | sousol | Face extérieure | Plâtre Lisse | Mur-133 | sousol | 2 | 0 | 0 | 0 | 3000 | 0 | 0 | 0 | 3.46414 | 0 | 6562.41 | 18.7916 | 19.2002 | 0 | 6742.41 | 6562.41 | 18.7916 | 6562.41 | 19.2002 | 3.46414 | 19.4102 | 19.4102 | 6562.41 | 6562.41 | 0 | 1.18123 | 4.18415e-12 | 4.18415e-12 | 6562.41 | 3.49384 | 13484.8 | 3000 | 4.21885e-12 | 4.21885e-12 | 3.28047
Mur-132 | sousol | Face extérieure | Peinture-11 | Mur-132 | sousol | 2 | 2 | 0 | 0 | 3000 | 2350 | 1.30289 | 1016.12 | 12.4021 | 1.36425 | 23390.4 | 66.0548 | 66.743 | 0.245565 | 23670 | 22754.7 | 67.4191 | 22953.9 | 68.1072 | 12.6476 | 69.9695 | 70.5672 | 23290.8 | 23490 | 0 | 4.14617 | 4.18415e-12 | 4.18415e-12 | 23670 | 12.6483 | 47229.3 | 3000 | 0 | 0 | 9.73432 | ArchiCADProperties - Nom de zone liée: Pl; Numéro de zone liée: 818
Mur-133 | sousol | Face extérieure | Plâtre Lisse | Mur-133 | sousol | 2 | 0 | 0 | 0 | 2749.08 | 2749.08 | 0 | 0 | 2.41175 | 0 | 4873.03 | 13.1284 | 13.6689 | 0 | 4972.18 | 4773.89 | 13.1284 | 4972.18 | 13.6689 | 2.41175 | 13.1284 | 13.6689 | 4773.89 | 4972.18 | 0 | 0.878792 | 4.18415e-12 | 4.18415e-12 | 4972.18 | 2.41175 | 10181.6 | 2749.08 | 0 | 0 | 2.95454 | ArchiCADProperties - Nom de zone liée: Pl; Numéro de zone liée: 818
Mur-133 | sousol | Face extérieure | Plâtre Lisse | Mur-133 | sousol | 2 | 0 | 0 | 1 | 3000 | 0 | 0 | 0 | 1.11762 | 0 | 2289.67 | 6.44386 | 5.93908 | 0 | 2379.69 | 2379.64 | 6.44386 | 2199.69 | 5.93908 | 1.11762 | 7.18935 | 6.64948 | 2379.64 | 2199.69 | 0 | 0.372545 | 4.18415e-12 | 4.18415e-12 | 2159.74 | 1.24549 | 5013.9 | 3000 | 0 | 0 | 1.51775
Mur-133 | sousol | Face extérieure | Plâtre Lisse | Mur-133 | sousol | 2 | 0 | 0 | 0 | 2950 | 2950 | 0 | 0 | 2.89687 | 0 | 5450 | 15.5789 | 16.6085 | 0 | 5630 | 5270 | 15.5789 | 5630 | 16.6085 | 2.89687 | 15.5789 | 16.6085 | 5270 | 5630 | 0 | 0.9972 | 4.18415e-12 | 4.18415e-12 | 5630 | 2.89687 | 11409.1 | 2950 | 0 | 0 | 3.48287
Mur-133 | sousol | Face extérieure | Plâtre Lisse | Mur-133 | sousol | 2 | 1 | 0 | 0 | 2770 | 2450 | 4.92 | 2400 | 0.466898 | 4.92 | 2989.71 | 2.34457 | 2.84319 | 0.8856 | 3259.71 | 499.71 | 2.34457 | 679.714 | 2.84319 | 1.3525 | 8.0322 | 8.53081 | 2899.71 | 3079.71 | 0 | 0.106148 | 4.18415e-12 | 4.18415e-12 | 3079.71 | 1.49067 | 6413.98 | 2770 | 0 | 0 | 1.41623
Mur-132 | sousol | Face extérieure | Peinture-11 | Mur-132 | sousol | 2 | 0 | 0 | 0 | 3000 | 3000 | 0 | 0 | 1.66377 | 0 | 3079.56 | 8.70768 | 9.77867 | 0 | 3259.56 | 2899.56 | 8.70768 | 3259.56 | 9.77867 | 1.66377 | 8.70768 | 9.77867 | 2899.56 | 3259.56 | 0 | 0.57052 | 4.18415e-12 | 4.18415e-12 | 3259.56 | 1.66377 | 6668.23 | 3000 | 0 | 0 | 2.66465
4 x Mur-132 | sousol | Face extérieure | Peinture-11 | Mur-132 | sousol | 2 | 0 | 0 | 0 | 3000 | 3000 | 0 | 0 | 0.221892 | 0 | 410.91 | 0.962731 | 1.50273 | 0 | 500.91 | 320.91 | 0.962731 | 500.91 | 1.50273 | 0.221892 | 0.962731 | 1.50273 | 320.91 | 500.91 | 0 | 0.0739639 | 4.18415e-12 | 4.18415e-12 | 500.91 | 0.221892 | 1256.38 | 3000 | 0 | 0 | 1.4516
Mur-133 | sousol | Face extérieure | Plâtre Lisse | Mur-133 | sousol | 2 | 0 | 0 | 0 | 2950 | 2950 | 0 | 0 | 3.27515 | 0 | 6162.41 | 17.6805 | 18.7101 | 0 | 6342.41 | 5982.41 | 17.6805 | 6342.41 | 18.7101 | 3.27515 | 17.6805 | 18.7101 | 5982.41 | 6342.41 | 0 | 1.12543 | 4.18415e-12 | 4.18415e-12 | 6342.41 | 3.27515 | 12833.9 | 2950 | 0 | 0 | 3.73934
Mur-132 | sousol | Face extérieure | Peinture-11 | Mur-132 | sousol | 2 | 0 | 0 | 0 | 2460 | 2350 | 0 | 0 | 4.62013 | 0 | 10428.3 | 25.446 | 25.8888 | 0 | 10698.3 | 10338.3 | 25.446 | 10518.3 | 25.8888 | 4.62013 | 25.479 | 25.9218 | 10338.3 | 10518.3 | 0 | 1.90949 | 4.18415e-12 | 4.18415e-12 | 10698.3 | 4.62607 | 21291.2 | 2460 | 0 | 0 | 4.834 | ArchiCADProperties - Nom de zone liée: Pl; Numéro de zone liée: 818
Mur-132 | sousol | Face extérieure | Lavis blanc | Mur-132 | sousol | 2 | 0 | 0 | 0 | 2500 | 2500 | 0 | 0 | 1.33749 | 0 | 2970.77 | 7.00583 | 7.4029 | 0 | 3142.09 | 2799.45 | 7.00583 | 3142.09 | 7.4029 | 1.33749 | 7.00583 | 7.85522 | 2799.45 | 3142.09 | 0 | 0.550938 | 4.18415e-12 | 4.18415e-12 | 3142.09 | 1.33749 | 6438.69 | 2500 | 0 | 0 | 2.34177 | ArchiCADProperties - Nom de zone liée: Pl; Numéro de zone liée: 818
Mur-132 | sousol | Face extérieure | Lavis blanc | Mur-132 | sousol | 2 | 0 | 0 | 0 | 2586.04 | 2586.04 | 0 | 0 | 1.42478 | 0 | 3069.61 | 8.35824 | 7.47264 | 0 | 2889.61 | 3249.61 | 8.35824 | 2889.61 | 7.47264 | 1.42478 | 8.35824 | 7.47264 | 3249.61 | 2889.61 | 0 | 0.55253 | 4.18415e-12 | 4.18415e-12 | 3249.61 | 1.42478 | 6648.33 | 2586.04 | 0 | 0 | 2.40286
Mur-133 | sousol | Face extérieure | Plâtre Lisse | Mur-133 | sousol | 2 | 1 | 0 | 0 | 2770 | 2450 | 4.92 | 2400 | 0.466972 | 4.92 | 2989.86 | 2.345 | 2.84359 | 0.8856 | 3259.86 | 499.863 | 2.345 | 679.859 | 2.84359 | 1.35257 | 8.03262 | 8.53121 | 2899.86 | 3079.86 | 0 | 0.106175 | 4.18415e-12 | 4.18415e-12 | 3079.86 | 1.49074 | 6414.28 | 2770 | 0 | 0 | 1.41629
Mur-132 | sousol | Face extérieure | Peinture-11 | Mur-132 | sousol | 2 | 0 | 0 | 0 | 3000 | 3000 | 0 | 0 | 2.96846 | 0 | 5495.64 | 15.6949 | 16.7569 | 0 | 5585.64 | 5405.64 | 15.6949 | 5585.64 | 16.7569 | 2.96846 | 16.2259 | 16.7569 | 5405.64 | 5585.64 | 0 | 1.00542 | 4.18415e-12 | 4.18415e-12 | 5585.64 | 2.96846 | 11425.8 | 3000 | 0 | 0 | 3.31078
Mur-133 | sousol | Face extérieure | Plâtre Lisse | Mur-133 | sousol | 2 | 1 | 0 | 0 | 3000 | 3000 | 1.8972 | 930 | 4.57423 | 2.1008 | 9184.8 | 25.2021 | 24.9027 | 0.378144 | 9085.19 | 8093.48 | 25.2021 | 8256.12 | 24.9027 | 4.95237 | 27.3029 | 27.7235 | 9103.48 | 9266.12 | 0 | 1.47146 | 4.18415e-12 | 4.18415e-12 | 9266.12 | 4.95237 | 18792.2 | 3000 | 0 | 0 | 4.36659 | ArchiCADProperties - Nom de zone liée: Pl; Numéro de zone liée: 818; Zones conflictuelles: Pl
Mur-133 | sousol | Face extérieure | Plâtre Lisse | Mur-133 | sousol | 2 | 0 | 0 | 0 | 4000 | 4000 | 0 | 0 | 1.044 | 0 | 1450 | 5.8 | 5.8 | 0 | 1450 | 1450 | 5.8 | 1450 | 5.8 | 1.044 | 5.8 | 5.8 | 1450 | 1450 | 0 | 0.261 | 4.18415e-12 | 4.18415e-12 | 1450 | 1.044 | 3260 | 4000 | 3.9968e-12 | 3.9968e-12 | 1.962
Mur-133 | sousol | Face extérieure | Plâtre Lisse | Mur-133 | sousol | 2 | 1 | 0 | 0 | 2749.08 | 2749.08 | 0.25 | 500 | 1.23388 | 0.2652 | 2590 | 6.6075 | 7.10233 | 0.047736 | 2680 | 2500 | 6.8727 | 2680 | 7.36753 | 1.28162 | 6.8727 | 7.36753 | 2500 | 2680 | 0 | 0.4662 | 4.18415e-12 | 4.18415e-12 | 2680 | 1.28162 | 5614.56 | 2749.08 | 0 | 0 | 2.12704 | ArchiCADProperties - Nom de zone liée: Pl; Numéro de zone liée: 818; Zones conflictuelles: Pl
Mur-133 | sousol | Face extérieure | Plâtre Lisse | Mur-133 | sousol | 2 | 0 | 0 | 0 | 2026.07 | 2026.07 | 0 | 0 | 0.664198 | 0 | 1821.25 | 3.68999 | 3.68999 | 0 | 1821.25 | 1821.25 | 3.68999 | 1821.25 | 3.68999 | 0.664198 | 3.68999 | 3.68999 | 1821.25 | 1821.25 | 0 | 0.327825 | 4.18415e-12 | 4.18415e-12 | 1821.25 | 0.664198 | 4002.5 | 2026.07 | 4.18415e-12 | 4.18415e-12 | 1.38504
Mur-132 | sousol | Face extérieure | Lavis blanc | Mur-132 | sousol | 2 | 0 | 1 | 0 | 2586.04 | 2586.04 | 0 | 0 | 0.307094 | 5.76656 | 2889.61 | 1.70608 | 1.70608 | 1.03798 | 2889.61 | 62.8612 | 1.70608 | 62.8612 | 1.70608 | 1.34508 | 7.47264 | 7.47264 | 2889.61 | 2889.61 | 5.76656 | 0.011315 | 4.18415e-12 | 4.18415e-12 | 2889.61 | 1.34508 | 6139.22 | 2586.04 | 4.21885e-12 | 4.21885e-12 | 1.46242
Mur-132 | sousol | Face extérieure | Lavis blanc | Mur-132 | sousol | 2 | 0 | 0 | 0 | 2950 | 2950 | 0 | 0 | 2.44624 | 0 | 4594.07 | 13.3747 | 13.8058 | 0 | 4679.94 | 4508.2 | 13.3747 | 4679.94 | 13.8058 | 2.44624 | 13.3747 | 13.8058 | 4508.2 | 4679.94 | 0 | 0.842389 | 4.18415e-12 | 4.18415e-12 | 4679.94 | 2.44624 | 9610.96 | 2950 | 0 | 0 | 2.90387
Mur-133 | sousol | Face extérieure | Plâtre Lisse | Mur-133 | sousol | 2 | 3 | 0 | 1 | 2770 | 0 | 16.605 | 8100 | 0.886123 | 16.605 | 9415.42 | 4.15231 | 4.65091 | 2.9889 | 9685.42 | 1225.42 | 4.15231 | 1405.42 | 4.65091 | 3.87502 | 25.8314 | 26.33 | 9325.42 | 9505.42 | 0 | 0.210024 | 4.18415e-12 | 4.18415e-12 | 9266.8 | 4.69453 | 19265.4 | 2770 | 0 | 0 | 1.14149
Mur-133 | sousol | Face extérieure | Plâtre Lisse | Mur-133 | sousol | 2 | 0 | 0 | 0 | 3000 | 2550 | 0 | 0 | 0.487934 | 0 | 903.582 | 2.44074 | 2.44075 | 0 | 813.582 | 993.582 | 2.44074 | 813.582 | 2.44075 | 0.487934 | 2.98075 | 2.44075 | 993.582 | 813.582 | 0 | 0.162645 | 4.18415e-12 | 4.18415e-12 | 993.582 | 0.487934 | 2241.72 | 3000 | 0 | 0 | 1.62895
Mur-133 | sousol | Face extérieure | Plâtre Lisse | Mur-133 | sousol | 2 | 0 | 0 | 0 | 3000 | 3000 | 0 | 0 | 1.68486 | 0 | 3120.11 | 9.36041 | 9.36027 | 0 | 3480.09 | 3120.14 | 9.36041 | 3120.09 | 9.36027 | 1.68486 | 9.36041 | 9.36027 | 3120.14 | 3120.09 | 0 | 0.56162 | 4.18415e-12 | 4.18415e-12 | 3120.14 | 1.68486 | 6600.23 | 3000 | 4.21885e-12 | 4.21885e-12 | 2.20324
Mur-132 | sousol | Face extérieure | Peinture-11 | Mur-132 | sousol | 2 | 2 | 0 | 0 | 3000 | 3000 | 9.8265 | 4530 | 1.06395 | 10.0309 | 5313.92 | 5.91086 | 5.91086 | 1.80556 | 5313.92 | 1713.92 | 5.91086 | 1713.92 | 5.91086 | 2.86952 | 15.9418 | 15.9418 | 5313.92 | 5313.92 | 0 | 0.308506 | 4.18415e-12 | 4.18415e-12 | 5313.92 | 2.86952 | 10987.8 | 3000 | 4.21885e-12 | 4.21885e-12 | 2.34501
Mur-133 | rdc | Face intérieure | Peinture-11 | Mur-133 | rdc | 3 | 0 | 0 | 0 | 100 | 100 | 0 | 0 | 0.0172839 | 0 | 960.218 | 0.105022 | 0.0870216 | 0 | 1050.22 | 1050.22 | 0.105022 | 870.216 | 0.0870216 | 0.0172839 | 0.105022 | 0.0870216 | 1050.22 | 870.216 | 0 | 0.172839 | 3000 | 3.9968e-12 | 1050.22 | 0.0172839 | 2355 | 3100 | 3000 | 3.9968e-12 | 0.389135
Mur-134 | rdc | Face intérieure | Peinture-11 | Mur-134 | rdc | 3 | 0 | 0 | 0 | 100 | 100 | 0 | 0 | 0.0172764 | 0 | 959.801 | 0.10498 | 0.0869804 | 0 | 1049.8 | 1049.8 | 0.10498 | 869.804 | 0.0869804 | 0.0172764 | 0.10498 | 0.0869804 | 1049.8 | 869.804 | 0 | 0.172764 | 3000 | 3.9968e-12 | 1049.8 | 0.0172764 | 2354.16 | 3100 | 3000 | 3.9968e-12 | 0.388984
Mur-134 | rdc | Face intérieure | Peinture-11 | Mur-134 | rdc | 3 | 0 | 0 | 0 | 100 | 100 | 0 | 0 | 0.315763 | 0 | 17542.4 | 1.77224 | 1.73624 | 0 | 17722.4 | 17722.4 | 1.77224 | 17362.4 | 1.73624 | 0.315763 | 1.77224 | 1.73624 | 17722.4 | 17362.4 | 0 | 3.15763 | 3000 | 3.9968e-12 | 17722.4 | 0.315763 | 35593.9 | 3100 | 3000 | 3.9968e-12 | 6.36618
Mur-133 | rdc | Face intérieure | Peinture-11 | Mur-133 | rdc | 3 | 0 | 0 | 0 | 100 | 100 | 0 | 0 | 0.0901194 | 0 | 5006.64 | 0.500664 | 0.500664 | 0 | 5006.64 | 5006.64 | 0.500664 | 5006.64 | 0.500664 | 0.0901194 | 0.500664 | 0.500664 | 5006.64 | 5006.64 | 0 | 0.901194 | 3000 | 3.9968e-12 | 5006.64 | 0.0901194 | 10373.3 | 3100 | 3000 | 3.9968e-12 | 1.83839
Mur-134 | rdc | Face intérieure | Peinture-11 | Mur-134 | rdc | 3 | 0 | 0 | 0 | 100 | 100 | 0 | 0 | 0.0901194 | 0 | 5006.64 | 0.500664 | 0.500664 | 0 | 5006.64 | 5006.64 | 0.500664 | 5006.64 | 0.500664 | 0.0901194 | 0.500664 | 0.500664 | 5006.64 | 5006.64 | 0 | 0.901194 | 3000 | 3.9968e-12 | 5006.64 | 0.0901194 | 10373.3 | 3100 | 3000 | 3.9968e-12 | 1.83839

# IfcWallStandardCase: Beton 18 0836643197 180 (23)
Classification: Mur (Classification ARCHICAD); Material: Parpaing 312445824 180 mm
ArchiCADProperties - Complexité de mur: Droit; Option de géométrie: Uniforme; Emplacement de ligne de référence: Face extérieure; Angle d'inclinaison interne de mur: 90 deg; Angle d'inclinaison externe de mur: 90 deg; Calque: Interieurs logements; Matériau de construction / Composite / Profil / Hachure: Beton 18 0836643197; Structure Composite: Beton 18 0836643197; Verrouillé: no; Type d'élément: Mur; Étage supérieur lié absolu: Non lié; Étage supérieur lié relatif: Non lié; Étage supérieur lié: Non lié; Type de structure: Composite; Matériaux de construction (Tous): Parpaing 312445824; Angle d'inclinaison: 90 deg; Nombre de percements: 0; Nom de Variante: Modèle principal; Nom de Jeu de Variantes: Modèle principal; Position: Non défini; Fonction structurelle: Non défini; Affichage sur filtre de rénovation: Tous les filtres appropriés; État de rénovation: Existant; État de Variante: Modèle principal; Jeu de Variantes: Modèle principal
AC_Pset_RenovationAndPhasing - Renovation Status: Existing
ArchiCADQuantities - Nombre de Poteaux: 0; Volume des poteaux: 0 m3; Épaisseur couche d'air: 0 mm; Épaisseur de composant de mur sur face intérieure: 180 mm; Épaisseur de composant de mur sur face extérieure: 180 mm; Épaisseur du Mur à la fin: 180 mm; Largeur: 180 mm; Décalage supérieur: 0 mm; Épaisseur: 180 mm; Épaisseur couche isolation: 0 mm
Name | In | Surface de face intérieure = Surface de face extérieure = Surfaces (Toutes) = Surface latérale | ID de l'élément = Lien et ID d'élément = ID de Parent | Nom de zone liée | Numéro de zone liée | Nom d'étage d'implantation | Numéro d'étage d'implantation | Nombre de Portes | Nombre de trous (Nombre d'ouvertures vides) | Nombre de Fenêtres | Hauteur maximale de la couche de Mur sur face intérieure (mm) = Hauteur maximale du Mur (mm) = Hauteur maximale de la couche de Mur sur face extérieure (mm) = Hauteur (mm) | Hauteur minimale de la couche de Mur sur face intérieure (mm) = Hauteur minimale du Mur (mm) = Hauteur minimale de la couche de Mur sur face extérieure (mm) | Superficie des portes (m2) | Largeur totale des Portes (mm) | Superficie des fenêtres (m2) | Largeur totale des Fenêtres (mm) | Volume de composant de mur sur face intérieure (net) (m3) = Volume de composant de mur sur face extérieure (net) (m3) = Volume (net) (m3) | Superficie analytique des ouvertures sur face intérieure (m2) = Superficie analytique des ouvertures sur face extérieure (m2) | Longueur moyenne du mur (mm) = Longueur du Mur au centre (mm) | Superficie de la face intérieure du mur (nette) (m2) | Superficie de la face extérieure du mur (nette) (m2) = Superficie en plan (m2) = Superficie inférieure (nette) (m2) | Volume analytique des ouvertures (m3) | Longueur de ligne de référence (mm) | Longueur de la face intérieure du mur (conditionnelle) (mm) | Superficie de la face intérieure du mur (conditionnelle) (m2) | Longueur de la face extérieure du mur (conditionnelle) (mm) | Superficie de la face extérieure du mur (conditionnelle) (m2) | Volume du composant face intérieure du mur (conditionnel) (m3) = Volume du composant face extérieure du mur (conditionnel) (m3) = Volume (conditionnel) (m3) | Superficie de la face intérieure du mur (brute) (m2) | Superficie de la face extérieure du mur (brute) (m2) | Longueur de Mur sur face intérieure (mm) | Longueur de Mur sur face extérieure (mm) | Superficie des baies libres dans le Mur (m2) | Superficie (m2) = Superficie supérieure (nette) (m2) | Altitude à Zéro du Projet (mm) = Altitude de Référence Niveau 1 (mm) = Altitude de Référence Niveau 2 (mm) = Altitude à niveau de la mer (mm) = Altitude inférieure à premier niveau de référence (mm) = Altitude inférieure à Zéro du projet (mm) = Altitude inférieure à niveau de la mer (mm) = Altitude inférieure à deuxième niveau de référence (mm) | Altitude à étage lié/étage d'implantation (mm) = Décalage étage d'implantation (mm) = Altitude inférieure à étage d'implantation (mm) | Longueur 3D (mm) | Volume (brut) (m3) | Périmètre Plan (mm) | Altitude supérieure à premier niveau de référence (mm) = Altitude supérieure à Zéro du projet (mm) = Altitude supérieure à niveau de la mer (mm) = Altitude supérieure à deuxième niveau de référence (mm) | Altitude supérieure à étage d'implantation (mm) | Superficie de l'arête (nette) (m2)
Mur-142 | rdc | Peinture-01 | Mur-142 | Sdb/pl | A02 | rdc | 3 | 0 | 0 | 0 | 2700 | 2700 | 0 | 0 | 0 | 0 | 1.09188 | 0 | 2246.66 | 6.11998 | 5.82298 | 0 | 2156.66 | 2336.66 | 6.11998 | 2156.66 | 5.82298 | 1.09188 | 6.30898 | 5.82298 | 2336.66 | 2156.66 | 0 | 0.404399 | 3000 | 0 | 2336.66 | 1.09188 | 4927.88 | 5700 | 2700 | 1.98211
Mur-143 | rdc | Peinture-01 | Mur-143 | Sejour cuisine/pl | B04 | rdc | 3 | 0 | 0 | 0 | 2500 | 2500 | 0 | 0 | 0 | 0 | 0.0792307 | 0 | 176.068 | 0.440171 | 0.440171 | 0 | 176.068 | 176.068 | 0.440171 | 176.068 | 0.440171 | 0.0792307 | 0.440171 | 0.440171 | 176.068 | 176.068 | 0 | 0.0316923 | 3000 | 0 | 176.068 | 0.0792307 | 712.136 | 5500 | 2500 | 0.963385
Mur-145 | rdc | Peinture-01 | Mur-145 | Pl | 679 | rdc | 3 | 0 | 0 | 0 | 2750 | 2750 | 0 | 0 | 0 | 0 | 2.55794 | 0 | 5137.48 | 13.9643 | 14.2648 | 0 | 5549.59 | 5047.02 | 13.9643 | 5227.95 | 14.2648 | 2.55794 | 13.9643 | 14.4573 | 5047.02 | 5227.95 | 0 | 0.98429 | 3000 | 0 | 5549.59 | 2.55794 | 10698.5 | 5750 | 2750 | 3.13302
Mur-142 | rdc | Poutre | Mur-142 | Pl | 678 | rdc | 3 | 0 | 1 | 1 | 2750 | 2750 | 0 | 0 | 4.72998 | 2199.99 | 1.15175 | 4.77408 | 4062.8 | 5.91264 | 5.90364 | 0.859334 | 4062.8 | 1862.8 | 5.95674 | 1862.81 | 5.94774 | 2.01109 | 11.1727 | 11.1727 | 4062.79 | 4062.8 | 0.0441 | 0.335307 | 3000 | 0 | 4062.8 | 2.01109 | 8485.59 | 5750 | 2750 | 2.05661
Mur-144 | rdc | Poutre | Mur-144 | Pl | 679 | rdc | 3 | 1 | 0 | 1 | 3270 | 0 | 2.163 | 1030 | 4.16779 | 1984.66 | 4.00493 | 6.54319 | 10219.7 | 21.476 | 22.4682 | 1.17777 | 10581 | 10138.4 | 21.476 | 10301 | 22.4682 | 5.1827 | 33.3966 | 33.8438 | 10138.4 | 10301 | 0 | 1.86858 | 2480 | -520 | 10581 | 6.05164 | 20861.9 | 5750 | 2750 | 3.41815
Mur-142 | rdc | Poutre | Mur-142 | Pl | 678 | rdc | 3 | 0 | 0 | 0 | 2750 | 2750 | 0 | 0 | 0 | 0 | 1.07603 | 0 | 2167.99 | 6.22555 | 5.73038 | 0 | 2397.96 | 2258.02 | 6.22555 | 2077.96 | 5.73038 | 1.07603 | 6.22555 | 5.73038 | 2258.02 | 2077.96 | 0 | 0.447838 | 3000 | 0 | 2578.02 | 1.07603 | 4770.58 | 5750 | 2750 | 2.09083 | ArchiCADProperties - Zones conflictuelles: Pl
Mur-142 | rdc | Poutre | Mur-142 | Pl | 678 | rdc | 3 | 0 | 0 | 0 | 2750 | 2750 | 0 | 0 | 0 | 0 | 0.667886 | 0 | 1349.27 | 3.46296 | 3.958 | 0 | 1619.27 | 1259.26 | 3.46296 | 1439.27 | 3.958 | 0.667886 | 3.46296 | 3.958 | 1259.26 | 1439.27 | 0 | 0.242868 | 3000 | 0 | 1439.27 | 0.667886 | 3133.09 | 5750 | 2750 | 1.68077 | ArchiCADProperties - Zones conflictuelles: Pl
Mur-142 | rdc | Poutre | Mur-142 | Pl | 678 | rdc | 3 | 0 | 0 | 0 | 2750 | 2750 | 0 | 0 | 0 | 0 | 1.01437 | 0 | 2049.23 | 5.63548 | 5.6353 | 0 | 2049.2 | 2049.26 | 5.63548 | 2049.2 | 5.6353 | 1.01437 | 5.63548 | 5.6353 | 2049.26 | 2049.2 | 0 | 0.368862 | 3000 | 0 | 2229.26 | 1.01437 | 4607.63 | 5750 | 2750 | 2.13792 | ArchiCADProperties - Zones conflictuelles: Pl
Mur-143 | rdc | Peinture-01 | Mur-143 | Ch 2/pl | B03 | rdc | 3 | 0 | 0 | 0 | 2500 | 2500 | 0 | 0 | 0 | 0 | 0.0809119 | 0 | 179.804 | 0.449511 | 0.449511 | 0 | 179.804 | 179.804 | 0.449511 | 179.804 | 0.449511 | 0.0809119 | 0.449511 | 0.449511 | 179.804 | 179.804 | 0 | 0.0323648 | 3000 | 0 | 179.804 | 0.0809119 | 719.609 | 5500 | 2500 | 0.96473
Mur-143 | rdc | Peinture-01 | Mur-143 | Ch 1 | B03 | rdc | 3 | 0 | 0 | 0 | 2500 | 2500 | 0 | 0 | 0 | 0 | 0.0809119 | 0 | 179.804 | 0.449511 | 0.449511 | 0 | 179.804 | 179.804 | 0.449511 | 179.804 | 0.449511 | 0.0809119 | 0.449511 | 0.449511 | 179.804 | 179.804 | 0 | 0.0323648 | 3000 | 0 | 179.804 | 0.0809119 | 719.609 | 5500 | 2500 | 0.96473
Mur-143 | rdc | Peinture-01 | Mur-143 | Ch 3 | B03 | rdc | 3 | 0 | 0 | 0 | 2500 | 2500 | 0 | 0 | 0 | 0 | 0.0809119 | 0 | 179.804 | 0.449511 | 0.449511 | 0 | 179.804 | 179.804 | 0.449511 | 179.804 | 0.449511 | 0.0809119 | 0.449511 | 0.449511 | 179.804 | 179.804 | 0 | 0.0323648 | 3000 | 0 | 179.804 | 0.0809119 | 719.609 | 5500 | 2500 | 0.96473
Mur-142 | Etage1 | Peinture-01 | Mur-142 | Sde | A12 | Etage1 | 4 | 0 | 0 | 0 | 2700 | 2700 | 0 | 0 | 0 | 0 | 1.09188 | 0 | 2246.66 | 6.11998 | 5.82298 | 0 | 2156.66 | 2336.66 | 6.11998 | 2156.66 | 5.82298 | 1.09188 | 6.30898 | 5.82298 | 2336.66 | 2156.66 | 0 | 0.404399 | 5750 | 0 | 2336.66 | 1.09188 | 4927.88 | 8450 | 2700 | 1.98211
Mur-143 | Etage1 | Peinture-01 | Mur-143 | Sejour cuisine | B15 | Etage1 | 4 | 0 | 0 | 0 | 2500 | 2500 | 0 | 0 | 0 | 0 | 0.0477326 | 0 | 106.072 | 0.265181 | 0.265181 | 0 | 176.068 | 106.072 | 0.265181 | 106.072 | 0.265181 | 0.0477326 | 0.265181 | 0.265181 | 106.072 | 106.072 | 0 | 0.019093 | 5750 | 0 | 106.072 | 0.0477326 | 572.145 | 8250 | 2500 | 0.938186
Mur-143 | Etage1 | Peinture-01 | Mur-143 | Ch 1 | A12 | Etage1 | 4 | 0 | 0 | 0 | 2500 | 2500 | 0 | 0 | 0 | 0 | 0.0792307 | 0 | 176.068 | 0.440171 | 0.440171 | 0 | 176.068 | 176.068 | 0.440171 | 176.068 | 0.440171 | 0.0792307 | 0.440171 | 0.440171 | 176.068 | 176.068 | 0 | 0.0316923 | 5750 | 0 | 176.068 | 0.0792307 | 712.136 | 8250 | 2500 | 0.963385
Mur-143 | Etage1 | Peinture-01 | Mur-143 | Ch 2/pl | B14 | Etage1 | 4 | 0 | 0 | 0 | 2500 | 2500 | 0 | 0 | 0 | 0 | 0.0792288 | 0 | 176.064 | 0.44016 | 0.44016 | 0 | 176.064 | 176.064 | 0.44016 | 176.064 | 0.44016 | 0.0792288 | 0.44016 | 0.44016 | 176.064 | 176.064 | 0 | 0.0316915 | 5750 | 0 | 176.064 | 0.0792288 | 712.128 | 8250 | 2500 | 0.963383
Mur-143 | Etage1 | Peinture-01 | Mur-143 | Ch 3 | B14 | Etage1 | 4 | 0 | 0 | 0 | 2500 | 2500 | 0 | 0 | 0 | 0 | 0.0792307 | 0 | 176.068 | 0.440171 | 0.440171 | 0 | 176.068 | 176.068 | 0.440171 | 176.068 | 0.440171 | 0.0792307 | 0.440171 | 0.440171 | 176.068 | 176.068 | 0 | 0.0316923 | 5750 | 0 | 176.068 | 0.0792307 | 712.136 | 8250 | 2500 | 0.963385
Mur-143 | Etage1 | Peinture-01 | Mur-143 | Ch 1/pl | B14 | Etage1 | 4 | 0 | 0 | 0 | 2500 | 2500 | 0 | 0 | 0 | 0 | 0.0792307 | 0 | 176.068 | 0.440171 | 0.440171 | 0 | 176.068 | 176.068 | 0.440171 | 176.068 | 0.440171 | 0.0792307 | 0.440171 | 0.440171 | 176.068 | 176.068 | 0 | 0.0316923 | 5750 | 0 | 176.068 | 0.0792307 | 712.136 | 8250 | 2500 | 0.963385
Mur-143 | Etage 2 | Peinture-01 | Mur-143 | Sejour cuisine | B25 | Etage 2 | 5 | 0 | 0 | 0 | 2500 | 2500 | 0 | 0 | 0 | 0 | 0.0477326 | 0 | 106.072 | 0.265181 | 0.265181 | 0 | 176.068 | 106.072 | 0.265181 | 106.072 | 0.265181 | 0.0477326 | 0.265181 | 0.265181 | 106.072 | 106.072 | 0 | 0.019093 | 8500 | 0 | 106.072 | 0.0477326 | 572.145 | 11000 | 2500 | 0.938186
Mur-143 | Etage 2 | Peinture-01 | Mur-143 | Ch 3 | B24 | Etage 2 | 5 | 0 | 0 | 0 | 2500 | 2500 | 0 | 0 | 0 | 0 | 0.0792288 | 0 | 176.064 | 0.44016 | 0.44016 | 0 | 176.064 | 176.064 | 0.44016 | 176.064 | 0.44016 | 0.0792288 | 0.44016 | 0.44016 | 176.064 | 176.064 | 0 | 0.0316915 | 8500 | 0 | 176.064 | 0.0792288 | 712.128 | 11000 | 2500 | 0.963383
Mur-143 | Etage 2 | Peinture-01 | Mur-143 | Ch 1 | A22 | Etage 2 | 5 | 0 | 0 | 0 | 2500 | 2300 | 0 | 0 | 0 | 0 | 0.0729814 | 0 | 176.068 | 0.406381 | 0.406222 | 0 | 176.068 | 176.068 | 0.406381 | 176.068 | 0.406222 | 0.0729814 | 0.440171 | 0.440171 | 176.068 | 176.068 | 0 | 0.0316923 | 8500 | 0 | 176.068 | 0.0792307 | 712.136 | 11000 | 2500 | 0.88658
Mur-143 | Etage 2 | Peinture-01 | Mur-143 | Ch 2/pl | B24 | Etage 2 | 5 | 0 | 0 | 0 | 2500 | 2500 | 0 | 0 | 0 | 0 | 0.0792288 | 0 | 176.064 | 0.44016 | 0.44016 | 0 | 176.064 | 176.064 | 0.44016 | 176.064 | 0.44016 | 0.0792288 | 0.44016 | 0.44016 | 176.064 | 176.064 | 0 | 0.0316915 | 8500 | 0 | 176.064 | 0.0792288 | 712.128 | 11000 | 2500 | 0.963383
Mur-143 | Etage 2 | Peinture-01 | Mur-143 | Ch 1/pl | B24 | Etage 2 | 5 | 0 | 0 | 0 | 2500 | 2500 | 0 | 0 | 0 | 0 | 0.0792307 | 0 | 176.068 | 0.440171 | 0.440171 | 0 | 176.068 | 176.068 | 0.440171 | 176.068 | 0.440171 | 0.0792307 | 0.440171 | 0.440171 | 176.068 | 176.068 | 0 | 0.0316923 | 8500 | 0 | 176.068 | 0.0792307 | 712.136 | 11000 | 2500 | 0.963385
Mur-142 | Etage 3 | Peinture-01 | Mur-142 | Sejour cuisine/pl | A31 | Etage 3 | 6 | 0 | 0 | 0 | 3050 | 3050 | 0 | 0 | 0 | 0 | 1.21451 | 0 | 2211.65 | 6.70674 | 6.57781 | 0 | 2156.66 | 2266.63 | 6.70674 | 2156.66 | 6.57781 | 1.21451 | 6.91674 | 6.57781 | 2266.63 | 2156.66 | 0 | 0.404399 | 11550 | 0 | 2336.66 | 1.21451 | 4870.99 | 14600 | 3050 | 2.17362

# IfcWallStandardCase: Beton 18 180 (24)
Classification: Mur (Classification ARCHICAD); Material: Parpaing 314940890 180 mm
AC_Pset_RenovationAndPhasing - Renovation Status: Existing
ArchiCADProperties - Complexité de mur: Droit; Option de géométrie: Uniforme; Emplacement de ligne de référence: Face extérieure; Angle d'inclinaison interne de mur: 90 deg; Angle d'inclinaison externe de mur: 90 deg; Calque: Interieurs logements; Matériau de construction / Composite / Profil / Hachure: Beton 18; Structure Composite: Beton 18; Verrouillé: no; Type d'élément: Mur; Étage supérieur lié absolu: Non lié; Étage supérieur lié relatif: Non lié; Étage supérieur lié: Non lié; Type de structure: Composite; Matériaux de construction (Tous): Parpaing 314940890; Angle d'inclinaison: 90 deg; Nombre de percements: 0; Nom de Variante: Modèle principal; Nom de Jeu de Variantes: Modèle principal; Position: Non défini; Fonction structurelle: Non défini; Affichage sur filtre de rénovation: Tous les filtres appropriés; État de rénovation: Existant; État de Variante: Modèle principal; Jeu de Variantes: Modèle principal
ArchiCADQuantities - Nombre de Portes: 0; Nombre de Fenêtres: 0; Nombre de Poteaux: 0; Volume des poteaux: 0 m3; Épaisseur couche d'air: 0 mm; Superficie des portes: 0 m2; Largeur totale des Portes: 0 mm; Épaisseur de composant de mur sur face intérieure: 180 mm; Épaisseur de composant de mur sur face extérieure: 180 mm; Superficie des fenêtres: 0 m2; Largeur totale des Fenêtres: 0 mm; Épaisseur du Mur à la fin: 180 mm; Largeur: 180 mm; Altitude à étage lié/étage d'implantation: 0 mm; Décalage étage d'implantation: 0 mm; Décalage supérieur: 0 mm; Épaisseur: 180 mm; Épaisseur couche isolation: 0 mm
Name | In | Surface de face intérieure = Surface de face extérieure = Surfaces (Toutes) = Surface latérale | ID de l'élément = Lien et ID d'élément = ID de Parent | Nom d'étage d'implantation | Numéro d'étage d'implantation | Nombre de trous (Nombre d'ouvertures vides) | Hauteur maximale de la couche de Mur sur face intérieure (mm) = Hauteur maximale du Mur (mm) = Hauteur maximale de la couche de Mur sur face extérieure (mm) = Hauteur (mm) = Altitude supérieure à étage d'implantation (mm) | Hauteur minimale de la couche de Mur sur face intérieure (mm) = Hauteur minimale du Mur (mm) = Hauteur minimale de la couche de Mur sur face extérieure (mm) | Volume de composant de mur sur face intérieure (net) (m3) = Volume de composant de mur sur face extérieure (net) (m3) = Volume (net) (m3) | Superficie analytique des ouvertures sur face intérieure (m2) = Superficie analytique des ouvertures sur face extérieure (m2) = Superficie des baies libres dans le Mur (m2) | Longueur moyenne du mur (mm) = Longueur du Mur au centre (mm) | Superficie de la face intérieure du mur (nette) (m2) | Superficie de la face extérieure du mur (nette) (m2) = Superficie en plan (m2) = Superficie inférieure (nette) (m2) | Volume analytique des ouvertures (m3) | Longueur de ligne de référence (mm) | Longueur de la face intérieure du mur (conditionnelle) (mm) = Longueur de Mur sur face intérieure (mm) | Superficie de la face intérieure du mur (conditionnelle) (m2) | Longueur de la face extérieure du mur (conditionnelle) (mm) = Longueur de Mur sur face extérieure (mm) | Superficie de la face extérieure du mur (conditionnelle) (m2) | Volume du composant face intérieure du mur (conditionnel) (m3) = Volume du composant face extérieure du mur (conditionnel) (m3) = Volume (conditionnel) (m3) | Superficie de la face intérieure du mur (brute) (m2) | Superficie de la face extérieure du mur (brute) (m2) | Superficie (m2) = Superficie supérieure (nette) (m2) | Altitude à Zéro du Projet (mm) = Altitude de Référence Niveau 1 (mm) = Altitude de Référence Niveau 2 (mm) = Altitude à niveau de la mer (mm) = Altitude inférieure à premier niveau de référence (mm) = Altitude inférieure à Zéro du projet (mm) = Altitude inférieure à niveau de la mer (mm) = Altitude inférieure à deuxième niveau de référence (mm) | Longueur 3D (mm) | Volume (brut) (m3) | Périmètre Plan (mm) | Altitude supérieure à premier niveau de référence (mm) = Altitude supérieure à Zéro du projet (mm) = Altitude supérieure à niveau de la mer (mm) = Altitude supérieure à deuxième niveau de référence (mm) | Altitude inférieure à étage d'implantation (mm) | Superficie de l'arête (nette) (m2)
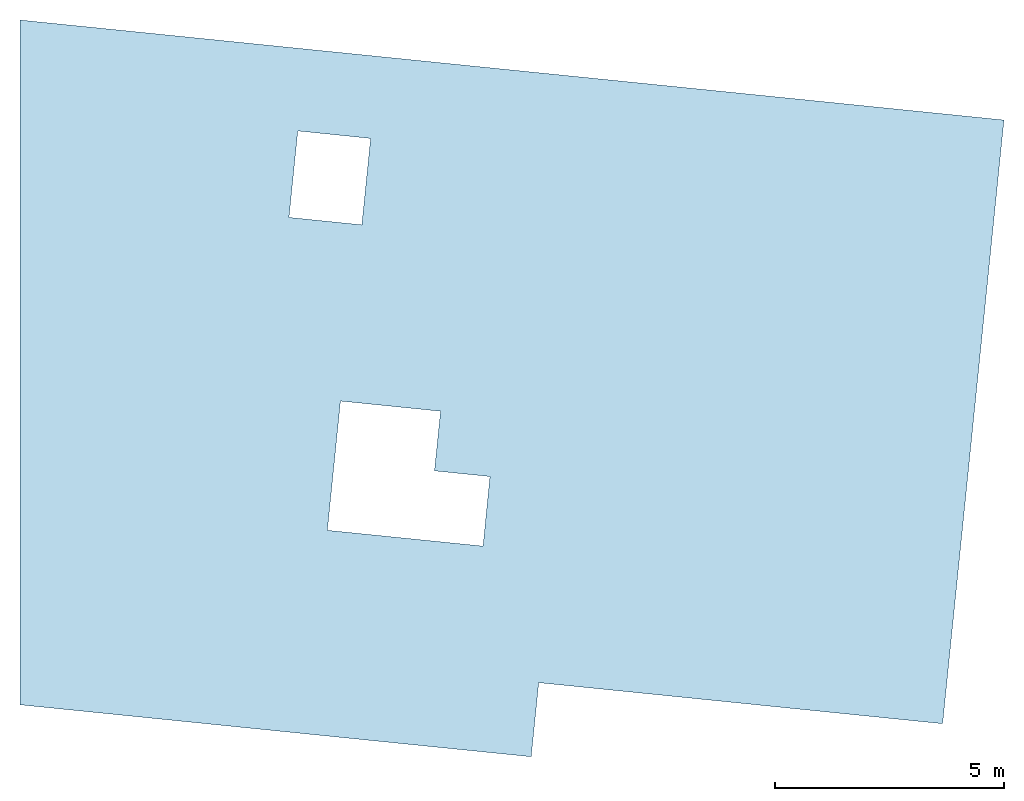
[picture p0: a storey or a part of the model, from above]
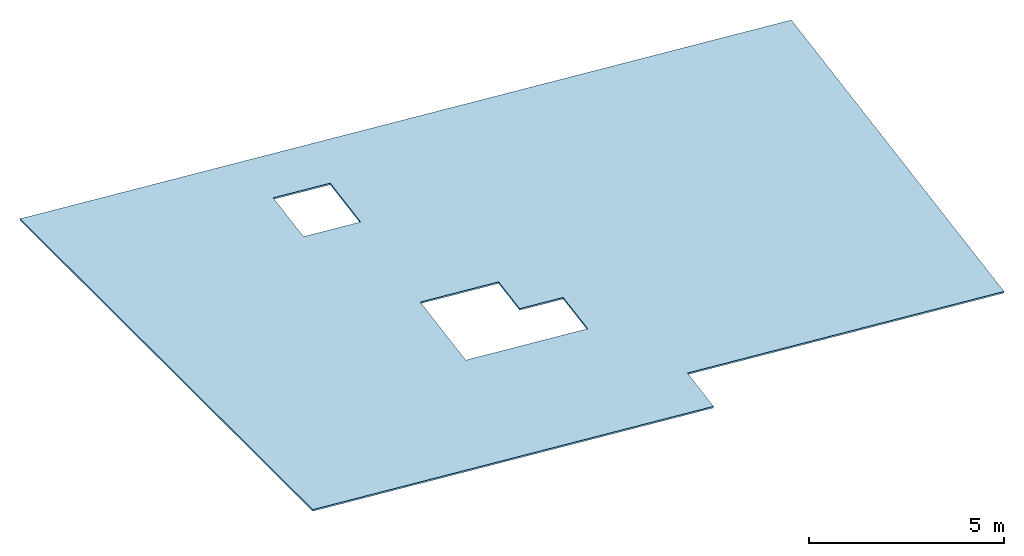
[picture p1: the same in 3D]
Properties of the parts of a building model (IFC2X3), part 22 of 44

# IfcWallStandardCase: Beton 18 180 (24)
Name | In | Surface de face intérieure = Surface de face extérieure = Surfaces (Toutes) = Surface latérale | ID de l'élément = Lien et ID d'élément = ID de Parent | Nom d'étage d'implantation | Numéro d'étage d'implantation | Nombre de trous (Nombre d'ouvertures vides) | Hauteur maximale de la couche de Mur sur face intérieure (mm) = Hauteur maximale du Mur (mm) = Hauteur maximale de la couche de Mur sur face extérieure (mm) = Hauteur (mm) = Altitude supérieure à étage d'implantation (mm) | Hauteur minimale de la couche de Mur sur face intérieure (mm) = Hauteur minimale du Mur (mm) = Hauteur minimale de la couche de Mur sur face extérieure (mm) | Volume de composant de mur sur face intérieure (net) (m3) = Volume de composant de mur sur face extérieure (net) (m3) = Volume (net) (m3) | Superficie analytique des ouvertures sur face intérieure (m2) = Superficie analytique des ouvertures sur face extérieure (m2) = Superficie des baies libres dans le Mur (m2) | Longueur moyenne du mur (mm) = Longueur du Mur au centre (mm) | Superficie de la face intérieure du mur (nette) (m2) | Superficie de la face extérieure du mur (nette) (m2) = Superficie en plan (m2) = Superficie inférieure (nette) (m2) | Volume analytique des ouvertures (m3) | Longueur de ligne de référence (mm) | Longueur de la face intérieure du mur (conditionnelle) (mm) = Longueur de Mur sur face intérieure (mm) | Superficie de la face intérieure du mur (conditionnelle) (m2) | Longueur de la face extérieure du mur (conditionnelle) (mm) = Longueur de Mur sur face extérieure (mm) | Superficie de la face extérieure du mur (conditionnelle) (m2) | Volume du composant face intérieure du mur (conditionnel) (m3) = Volume du composant face extérieure du mur (conditionnel) (m3) = Volume (conditionnel) (m3) | Superficie de la face intérieure du mur (brute) (m2) | Superficie de la face extérieure du mur (brute) (m2) | Superficie (m2) = Superficie supérieure (nette) (m2) | Altitude à Zéro du Projet (mm) = Altitude de Référence Niveau 1 (mm) = Altitude de Référence Niveau 2 (mm) = Altitude à niveau de la mer (mm) = Altitude inférieure à premier niveau de référence (mm) = Altitude inférieure à Zéro du projet (mm) = Altitude inférieure à niveau de la mer (mm) = Altitude inférieure à deuxième niveau de référence (mm) | Longueur 3D (mm) | Volume (brut) (m3) | Périmètre Plan (mm) | Altitude supérieure à premier niveau de référence (mm) = Altitude supérieure à Zéro du projet (mm) = Altitude supérieure à niveau de la mer (mm) = Altitude supérieure à deuxième niveau de référence (mm) | Altitude inférieure à étage d'implantation (mm) | Superficie de l'arête (nette) (m2)
Mur-142 | rdc | Peinture-01 | Mur-142 | rdc | 3 | 2 | 2750 | 2750 | 1.77199 | 0.0882 | 3606.02 | 9.59693 | 10.0918 | 0.015876 | 4016 | 3516.05 | 9.68513 | 3696 | 10.18 | 1.78786 | 9.68513 | 10.18 | 0.70668 | 3000 | 4016 | 1.78786 | 7646.61 | 5750 | 0 | 2.6084 | ArchiCADProperties - Nom de zone liée: Pl; Numéro de zone liée: 678
Mur-142 | Etage 3 | Peinture-01 | Mur-142 | Etage 3 | 6 | 0 | 3000 | 2300 | 0.106799 | 0 | 247.192 | 0.692137 | 0.617979 | 0 | 247.192 | 247.192 | 0.692137 | 247.192 | 0.617979 | 0.106799 | 0.741575 | 0.741575 | 0.0444945 | 11550 | 247.192 | 0.133484 | 854.384 | 14550 | 0 | 0.908618 | ArchiCADProperties - Nom de zone liée: Sejour cuisine; Numéro de zone liée: B34
Mur-145 | Etage 3 | Peinture-01 | Mur-145 | Etage 3 | 6 | 0 | 3000 | 1.77636e-12 | 3.01963 | 0 | 5661.91 | 16.5657 | 16.7757 | 0 | 6181.91 | 5661.91 | 16.5657 | 5661.91 | 16.7757 | 3.01963 | 16.7757 | 16.7757 | 1.00654 | 11550 | 5591.96 | 3.01963 | 11683.8 | 14550 | -1.77636e-12 | 3.09309 | ArchiCADProperties - Nom de zone liée: Ch 2/pl; Numéro de zone liée: A33
Mur-142 | etage 4 | Poutre | Mur-142 | etage 4 | 7 | 0 | 1100 | 1100 | 0.3168 | 0 | 1600 | 1.76 | 1.76 | 0 | 1600 | 1600 | 1.76 | 1600 | 1.76 | 0.3168 | 1.76 | 1.76 | 0.288 | 14600 | 1600 | 0.3168 | 3560 | 15700 | 0 | 0.972
Mur-142 | etage 4 | Peinture-01 | Mur-142 | etage 4 | 7 | 0 | 3050 | 3050 | 0.8784 | 0 | 1600 | 4.88 | 4.88 | 0 | 1600 | 1600 | 4.88 | 1600 | 4.88 | 0.8784 | 4.88 | 4.88 | 0.288 | 14600 | 1600 | 0.8784 | 3560 | 17650 | 0 | 1.674
2 x Mur-142 | etage 4 | Poutre | Mur-142 | etage 4 | 7 | 0 | 1100 | 1100 | 1.2645 | 0 | 6386.39 | 6.91548 | 7.13457 | 0 | 6485.97 | 6286.8 | 6.91548 | 6485.97 | 7.13457 | 1.2645 | 6.91548 | 7.13457 | 1.14955 | 14600 | 6485.97 | 1.2645 | 13221.2 | 15700 | 0 | 2.7924
Mur-142 | etage 4 | Poutre | Mur-142 | etage 4 | 7 | 0 | 1100 | 1100 | 2.73848 | 0 | 13830.7 | 15.1148 | 15.3128 | 0 | 13920.7 | 13740.7 | 15.1148 | 13920.7 | 15.3128 | 2.73848 | 15.1148 | 15.3128 | 2.48953 | 14600 | 13920.7 | 2.73848 | 28096 | 15700 | 0 | 5.45707
Mur-142 | etage 4 | Peinture-01 | Mur-142 | etage 4 | 7 | 0 | 1100 | 130.119 | 2.66333 | 0 | 13451.6 | 14.5988 | 14.9948 | 0 | 13631.6 | 13271.6 | 14.5988 | 13631.6 | 14.9948 | 2.66333 | 14.5988 | 14.9948 | 2.42129 | 14600 | 13631.6 | 2.66342 | 27412.3 | 15700 | 0 | 5.40136
Mur-142 | etage 4 | Peinture-01 | Mur-142 | etage 4 | 7 | 0 | 1100 | 114.128 | 1.75724 | 0 | 8878.45 | 9.7663 | 9.76011 | 0 | 8878.45 | 8878.45 | 9.7663 | 8878.45 | 9.76011 | 1.75724 | 9.7663 | 9.7663 | 1.59812 | 14600 | 9058.45 | 1.75793 | 18266 | 15700 | 0 | 3.75502
2 x Mur-142 | etage 4 | Peinture-01 | Mur-142 | etage 4 | 7 | 0 | 1100 | 1100 | 2.25921 | 0 | 11410.1 | 12.3627 | 12.7396 | 0 | 11581.5 | 11238.8 | 12.3627 | 11581.5 | 12.7396 | 2.25921 | 12.3627 | 12.7396 | 2.05383 | 14600 | 11581.5 | 2.25921 | 23317.5 | 15700 | 0 | 4.65455
Mur-142 | etage 4 | Poutre | Mur-142 | etage 4 | 7 | 0 | 1100 | 1100 | 0.32242 | 0 | 1628.39 | 1.79122 | 1.79122 | 0 | 1628.39 | 1628.39 | 1.79122 | 1628.39 | 1.79122 | 0.32242 | 1.79122 | 1.79122 | 0.29311 | 14600 | 1808.39 | 0.32242 | 3765.89 | 15700 | 0 | 1.14625
2 x Mur-142 | etage 4 | Poutre | Mur-142 | etage 4 | 7 | 0 | 1100 | 1100 | 3.00114 | 0 | 15157.3 | 16.474 | 16.872 | 0 | 15338.2 | 14976.3 | 16.474 | 15338.2 | 16.872 | 3.00114 | 16.474 | 16.872 | 2.72831 | 14600 | 15338.2 | 3.00114 | 30825.6 | 15700 | 0 | 6.0188
Mur-143 | toiture | Poutre | Mur-143 | toiture | 9 | 0 | 430.42 | 430.42 | 0.265116 | 0 | 3421.93 | 1.47287 | 1.47287 | 0 | 3421.93 | 3421.93 | 1.47287 | 3421.93 | 1.47287 | 0.265116 | 1.47287 | 1.47287 | 0.615948 | 20350 | 3421.93 | 0.265116 | 7203.87 | 20780.4 | 0 | 1.38685 | ArchiCADProperties - Nom de zone liée: Terrasse/eng.; Numéro de zone liée: B52; Zones conflictuelles: Terrasse/eng.
Mur-143 | toiture | Peinture-01 | Mur-143 | toiture | 9 | 0 | 1100 | 718.408 | 2.24504 | 0 | 11339.2 | 12.2752 | 12.6639 | 0 | 11519.2 | 11159.2 | 12.2752 | 11519.2 | 12.6639 | 2.24504 | 12.2752 | 12.6712 | 2.04106 | 20350 | 11519.2 | 2.24517 | 23187.6 | 21450 | 0 | 4.64145
Mur-143 | toiture | Poutre | Mur-143 | toiture | 9 | 0 | 1100 | 734.577 | 1.04615 | 0 | 5283.58 | 5.71294 | 5.91094 | 0 | 5373.58 | 5193.58 | 5.71294 | 5373.58 | 5.91094 | 1.04615 | 5.71294 | 5.91094 | 0.951045 | 20350 | 5373.58 | 1.04615 | 11001.7 | 21450 | 0 | 2.37971 | ArchiCADProperties - Nom de zone liée: Terrasse/eng.; Numéro de zone liée: B52; Zones conflictuelles: Terrasse/eng.
Mur-143 | toiture | Peinture-01 | Mur-143 | toiture | 9 | 0 | 1100 | 1100 | 2.24568 | 0 | 11341.8 | 12.278 | 12.674 | 0 | 11521.8 | 11161.8 | 12.278 | 11521.8 | 12.674 | 2.24568 | 12.278 | 12.674 | 2.04152 | 20350 | 11521.8 | 2.24568 | 23192.7 | 21450 | 0 | 4.64309
Mur-143 | toiture | Poutre | Mur-143 | toiture | 9 | 0 | 1100 | 736.963 | 4.99633 | 0 | 25234 | 27.5594 | 27.9554 | 0 | 25414 | 25054 | 27.5594 | 25414 | 27.9554 | 4.99633 | 27.5594 | 27.9554 | 4.54212 | 20350 | 25414 | 4.99633 | 50977.1 | 21450 | 0 | 9.64395
Mur-143 | toiture | Peinture-01 | Mur-143 | toiture | 9 | 0 | 1100 | 718.408 | 2.24504 | 0 | 11339.3 | 12.2752 | 12.6639 | 0 | 11519.2 | 11159.3 | 12.2752 | 11519.2 | 12.6639 | 2.24504 | 12.2752 | 12.6712 | 2.04107 | 20350 | 11519.2 | 2.24517 | 23187.6 | 21450 | 0 | 4.64144
Mur-143 | toiture | Peinture-01 | Mur-143 | toiture | 9 | 0 | 1100 | 1100 | 2.24517 | 0 | 11339.2 | 12.2752 | 12.6712 | 0 | 11519.2 | 11159.2 | 12.2752 | 11519.2 | 12.6712 | 2.24517 | 12.2752 | 12.6712 | 2.04106 | 20350 | 11519.2 | 2.24517 | 23187.6 | 21450 | 0 | 4.64216
Mur-143 | toiture | Poutre | Mur-143 | toiture | 9 | 0 | 1100 | 736.962 | 4.99644 | 0 | 25234.5 | 27.186 | 27.956 | 0 | 25414.5 | 25054.5 | 27.186 | 25414.5 | 27.956 | 4.99644 | 27.56 | 27.956 | 4.54222 | 20350 | 25414.5 | 4.99644 | 50978.2 | 21450 | 0 | 9.64415
Mur-143 | toiture | Poutre | Mur-143 | toiture | 9 | 0 | 1100 | 1100 | 3.27544 | 0 | 16542.6 | 17.1519 | 18.2959 | 0 | 16632.6 | 16452.6 | 17.1519 | 16632.6 | 18.2959 | 3.27544 | 18.0979 | 18.2959 | 2.97767 | 20350 | 16632.6 | 3.27544 | 33519.8 | 21450 | 0 | 6.43335

# IfcWallStandardCase: Beton 22 0018356637 220 (2)
In: rdc
Classification: Mur (Classification ARCHICAD); Material: Parpaing 314940890 220 mm
AC_Pset_RenovationAndPhasing - Renovation Status: Existing
ArchiCADQuantities - Nombre de Portes: 0; Nombre de trous (Nombre d'ouvertures vides): 0; Nombre de Fenêtres: 0; Nombre de Poteaux: 0; Volume des poteaux: 0 m3; Hauteur maximale de la couche de Mur sur face intérieure: 1000 mm; Hauteur minimale de la couche de Mur sur face intérieure: 1000 mm; Hauteur maximale du Mur: 1000 mm; Hauteur minimale du Mur: 1000 mm; Hauteur maximale de la couche de Mur sur face extérieure: 1000 mm; Hauteur minimale de la couche de Mur sur face extérieure: 1000 mm; Épaisseur couche d'air: 0 mm; Superficie des portes: 0 m2; Largeur totale des Portes: 0 mm; Épaisseur de composant de mur sur face intérieure: 220 mm; Épaisseur de composant de mur sur face extérieure: 220 mm; Superficie des fenêtres: 0 m2; Largeur totale des Fenêtres: 0 mm; Volume de composant de mur sur face intérieure (net): 1.69356 m3; Volume de composant de mur sur face extérieure (net): 1.69356 m3; Superficie analytique des ouvertures sur face intérieure: 0 m2; Superficie analytique des ouvertures sur face extérieure: 0 m2; Longueur moyenne du mur: 7679.99 mm; Superficie de la face intérieure du mur (nette): 7.69999 m2; Superficie de la face extérieure du mur (nette): 7.69599 m2; Volume analytique des ouvertures: 0 m3; Longueur de ligne de référence: 7699.99 mm; Longueur de la face intérieure du mur (conditionnelle): 7699.99 mm; Superficie de la face intérieure du mur (conditionnelle): 7.69999 m2; Longueur de la face extérieure du mur (conditionnelle): 7659.99 mm; Superficie de la face extérieure du mur (conditionnelle): 7.69599 m2; Volume du composant face intérieure du mur (conditionnel): 1.69356 m3; Volume du composant face extérieure du mur (conditionnel): 1.69356 m3; Superficie de la face intérieure du mur (brute): 7.69999 m2; Superficie de la face extérieure du mur (brute): 7.69599 m2; Épaisseur du Mur à la fin: 220 mm; Longueur du Mur au centre: 7679.99 mm; Longueur de Mur sur face intérieure: 7699.99 mm; Longueur de Mur sur face extérieure: 7659.99 mm; Superficie des baies libres dans le Mur: 0 m2; Superficie: 1.694 m2; Hauteur: 1000 mm; Volume (net): 1.69356 m3; Largeur: 220 mm; Altitude à étage lié/étage d'implantation: -3000 mm; Décalage étage d'implantation: -3000 mm; Décalage supérieur: 0 mm; Superficie en plan: 7.69599 m2; Longueur 3D: 7699.99 mm; Épaisseur: 220 mm; Volume (conditionnel): 1.69356 m3; Volume (brut): 1.69356 m3; Épaisseur couche isolation: 0 mm; Périmètre Plan: 15803.6 mm; Altitude supérieure à premier niveau de référence: 1000 mm; Altitude supérieure à étage d'implantation: -2000 mm; Altitude supérieure à Zéro du projet: 1000 mm; Altitude supérieure à niveau de la mer: 1000 mm; Altitude supérieure à deuxième niveau de référence: 1000 mm; Altitude inférieure à étage d'implantation: -3000 mm; Superficie supérieure (nette): 1.694 m2; Superficie de l'arête (nette): 3.82835 m2; Superficie inférieure (nette): 7.69599 m2
ArchiCADProperties - Complexité de mur: Droit; Option de géométrie: Uniforme; Emplacement de ligne de référence: Face intérieure; Surface de face intérieure: Peinture-01; Surface de face extérieure: Peinture-01; Angle d'inclinaison interne de mur: 90 deg; Angle d'inclinaison externe de mur: 90 deg; Calque: 1-Projet; Matériau de construction / Composite / Profil / Hachure: Beton 22 0018356637; Structure Composite: Beton 22 0018356637; Verrouillé: no; Nom d'étage d'implantation: rdc; Numéro d'étage d'implantation: 3; Type d'élément: Mur; Étage supérieur lié absolu: Non lié; Étage supérieur lié relatif: Non lié; Étage supérieur lié: Non lié; Type de structure: Composite; Matériaux de construction (Tous): Parpaing 314940890; Surfaces (Toutes): Peinture-01; Angle d'inclinaison: 90 deg; Nombre de percements: 0; Surface latérale: Peinture-01; Nom de Variante: Modèle principal; Nom de Jeu de Variantes: Modèle principal; Position: Non défini; Fonction structurelle: Non défini; Affichage sur filtre de rénovation: Tous les filtres appropriés; État de rénovation: Existant; État de Variante: Modèle principal; Jeu de Variantes: Modèle principal
Name | Altitude à Zéro du Projet (mm) = Altitude de Référence Niveau 1 (mm) = Altitude de Référence Niveau 2 (mm) = Altitude à niveau de la mer (mm) = Altitude inférieure à premier niveau de référence (mm) = Altitude inférieure à Zéro du projet (mm) = Altitude inférieure à niveau de la mer (mm) = Altitude inférieure à deuxième niveau de référence (mm) | ID de l'élément = Lien et ID d'élément = ID de Parent
Mur-168 | 4.44089e-12 | Mur-168
Mur-150 | 0 | Mur-150

# IfcWallStandardCase: Beton 25 250 (4)
Classification: Mur (Classification ARCHICAD); Material: Parpaing 314940890 250 mm
AC_Pset_RenovationAndPhasing - Renovation Status: Existing
ArchiCADQuantities - Nombre de Portes: 0; Nombre de trous (Nombre d'ouvertures vides): 0; Nombre de Fenêtres: 0; Nombre de Poteaux: 0; Volume des poteaux: 0 m3; Hauteur maximale de la couche de Mur sur face intérieure: 3000 mm; Hauteur minimale de la couche de Mur sur face intérieure: 3000 mm; Hauteur maximale du Mur: 3000 mm; Hauteur minimale du Mur: 3000 mm; Hauteur maximale de la couche de Mur sur face extérieure: 3000 mm; Hauteur minimale de la couche de Mur sur face extérieure: 3000 mm; Épaisseur couche d'air: 0 mm; Superficie des portes: 0 m2; Largeur totale des Portes: 0 mm; Épaisseur de composant de mur sur face intérieure: 250 mm; Épaisseur de composant de mur sur face extérieure: 250 mm; Superficie des fenêtres: 0 m2; Largeur totale des Fenêtres: 0 mm; Superficie analytique des ouvertures sur face intérieure: 0 m2; Superficie analytique des ouvertures sur face extérieure: 0 m2; Volume analytique des ouvertures: 0 m3; Longueur de ligne de référence: 316.192 mm; Épaisseur du Mur à la fin: 250 mm; Superficie des baies libres dans le Mur: 0 m2; Hauteur: 3000 mm; Largeur: 250 mm; Altitude à étage lié/étage d'implantation: 0 mm; Décalage étage d'implantation: 0 mm; Décalage supérieur: 0 mm; Épaisseur: 250 mm; Épaisseur couche isolation: 0 mm; Altitude supérieure à étage d'implantation: 3000 mm
ArchiCADProperties - Complexité de mur: Droit; Option de géométrie: Uniforme; Emplacement de ligne de référence: Face extérieure; Surface de face intérieure: Peinture-01; Surface de face extérieure: Peinture-01; Angle d'inclinaison interne de mur: 90 deg; Angle d'inclinaison externe de mur: 90 deg; ID de l'élément: Mur-142; Lien et ID d'élément: Mur-142; Calque: Interieurs logements; Matériau de construction / Composite / Profil / Hachure: Beton 25; Structure Composite: Beton 25; Nom de zone liée: Sejour cuisine; Verrouillé: no; Type d'élément: Mur; Étage supérieur lié absolu: Non lié; Étage supérieur lié relatif: Non lié; Étage supérieur lié: Non lié; Type de structure: Composite; ID de Parent: Mur-142; Matériaux de construction (Tous): Parpaing 314940890; Surfaces (Toutes): Peinture-01; Angle d'inclinaison: 90 deg; Nombre de percements: 0; Surface latérale: Peinture-01; Nom de Variante: Modèle principal; Nom de Jeu de Variantes: Modèle principal; Position: Non défini; Fonction structurelle: Non défini; Affichage sur filtre de rénovation: Tous les filtres appropriés; État de rénovation: Existant; État de Variante: Modèle principal; Jeu de Variantes: Modèle principal
Name | In | Volume de composant de mur sur face intérieure (net) (m3) = Volume de composant de mur sur face extérieure (net) (m3) = Volume du composant face intérieure du mur (conditionnel) (m3) = Volume du composant face extérieure du mur (conditionnel) (m3) = Volume (net) (m3) = Volume (conditionnel) (m3) = Volume (brut) (m3) | Longueur moyenne du mur (mm) = Longueur du Mur au centre (mm) | Superficie de la face intérieure du mur (nette) (m2) = Superficie de la face intérieure du mur (conditionnelle) (m2) | Superficie de la face extérieure du mur (nette) (m2) = Superficie de la face extérieure du mur (conditionnelle) (m2) = Superficie de la face extérieure du mur (brute) (m2) = Superficie en plan (m2) = Superficie inférieure (nette) (m2) | Longueur de la face intérieure du mur (conditionnelle) (mm) = Longueur de Mur sur face intérieure (mm) | Longueur de la face extérieure du mur (conditionnelle) (mm) = Longueur de Mur sur face extérieure (mm) = Longueur 3D (mm) | Superficie de la face intérieure du mur (brute) (m2) | Superficie (m2) = Superficie supérieure (nette) (m2) | Altitude à Zéro du Projet (mm) = Altitude de Référence Niveau 1 (mm) = Altitude de Référence Niveau 2 (mm) = Altitude à niveau de la mer (mm) = Altitude inférieure à premier niveau de référence (mm) = Altitude inférieure à Zéro du projet (mm) = Altitude inférieure à niveau de la mer (mm) = Altitude inférieure à deuxième niveau de référence (mm) | Périmètre Plan (mm) | Altitude supérieure à premier niveau de référence (mm) = Altitude supérieure à Zéro du projet (mm) = Altitude supérieure à niveau de la mer (mm) = Altitude supérieure à deuxième niveau de référence (mm) | Altitude inférieure à étage d'implantation (mm) | Superficie de l'arête (nette) (m2) | Numéro de zone liée | Nom d'étage d'implantation | Numéro d'étage d'implantation
Mur-142 | rdc | 0.210894 | 281.192 | 0.528577 | 0.948577 | 246.192 | 316.192 | 0.738577 | 0.0702981 | 3000 | 1072 | 6000 | 0 | 1.66944 | A03 | rdc | 3
Mur-142 | Etage1 | 0.210894 | 281.192 | 0.528577 | 0.948577 | 246.192 | 316.192 | 0.738577 | 0.0702981 | 5750 | 1072 | 8750 | 0 | 1.66944 | A13 | Etage1 | 4
Mur-142 | Etage 2 | 0.184644 | 246.191 | 0.528574 | 0.738574 | 246.191 | 246.191 | 0.738574 | 0.0615479 | 8500 | 992.383 | 11500 | -1.77636e-12 | 1.6231 | A23 | Etage 2 | 5
Mur-142 | Etage 3 | 0.184644 | 246.191 | 0.528574 | 0.738574 | 246.191 | 246.191 | 0.738574 | 0.0615479 | 11550 | 992.383 | 14550 | -1.77636e-12 | 1.6231 | A32 | Etage 3 | 6

# IfcWallStandardCase: Cloison 100 0826278243 100 (6)
Classification: Mur (Classification ARCHICAD); Material: Hachure solide 268963992 100 mm
ArchiCADQuantities - Nombre de trous (Nombre d'ouvertures vides): 0; Nombre de Fenêtres: 0; Nombre de Poteaux: 0; Volume des poteaux: 0 m3; Épaisseur couche d'air: 0 mm; Épaisseur de composant de mur sur face intérieure: 100 mm; Épaisseur de composant de mur sur face extérieure: 100 mm; Superficie des fenêtres: 0 m2; Largeur totale des Fenêtres: 0 mm; Épaisseur du Mur à la fin: 100 mm; Superficie des baies libres dans le Mur: 0 m2; Largeur: 100 mm; Altitude à étage lié/étage d'implantation: 0 mm; Décalage étage d'implantation: 0 mm; Décalage supérieur: 0 mm; Épaisseur: 100 mm; Épaisseur couche isolation: 0 mm; Altitude inférieure à étage d'implantation: 0 mm
AC_Pset_RenovationAndPhasing - Renovation Status: Existing
ArchiCADProperties - Complexité de mur: Droit; Option de géométrie: Uniforme; Angle d'inclinaison interne de mur: 90 deg; Angle d'inclinaison externe de mur: 90 deg; ID de l'élément: Mur-149; Lien et ID d'élément: Mur-149; Calque: 1-Projet; Matériau de construction / Composite / Profil / Hachure: Cloison 100 0826278243; Structure Composite: Cloison 100 0826278243; Verrouillé: no; Type d'élément: Mur; Étage supérieur lié absolu: Non lié; Étage supérieur lié relatif: Non lié; Étage supérieur lié: Non lié; Type de structure: Composite; ID de Parent: Mur-149; Matériaux de construction (Tous): Hachure solide 268963992; Angle d'inclinaison: 90 deg; Nombre de percements: 0; Nom de Variante: Modèle principal; Nom de Jeu de Variantes: Modèle principal; Position: Non défini; Fonction structurelle: Non défini; Affichage sur filtre de rénovation: Tous les filtres appropriés; État de rénovation: Existant; État de Variante: Modèle principal; Jeu de Variantes: Modèle principal
Name | In | Nombre de Portes | Hauteur maximale de la couche de Mur sur face intérieure (mm) = Hauteur maximale du Mur (mm) = Hauteur maximale de la couche de Mur sur face extérieure (mm) = Hauteur (mm) = Altitude supérieure à étage d'implantation (mm) | Hauteur minimale de la couche de Mur sur face intérieure (mm) = Hauteur minimale du Mur (mm) = Hauteur minimale de la couche de Mur sur face extérieure (mm) | Superficie des portes (m2) | Largeur totale des Portes (mm) | Volume de composant de mur sur face intérieure (net) (m3) = Volume de composant de mur sur face extérieure (net) (m3) = Volume (net) (m3) | Superficie analytique des ouvertures sur face intérieure (m2) = Superficie analytique des ouvertures sur face extérieure (m2) | Longueur moyenne du mur (mm) = Longueur du Mur au centre (mm) | Superficie de la face intérieure du mur (nette) (m2) | Superficie de la face extérieure du mur (nette) (m2) = Superficie en plan (m2) = Superficie inférieure (nette) (m2) | Volume analytique des ouvertures (m3) | Longueur de ligne de référence (mm) | Longueur de la face intérieure du mur (conditionnelle) (mm) | Superficie de la face intérieure du mur (conditionnelle) (m2) | Longueur de la face extérieure du mur (conditionnelle) (mm) | Superficie de la face extérieure du mur (conditionnelle) (m2) | Volume du composant face intérieure du mur (conditionnel) (m3) = Volume du composant face extérieure du mur (conditionnel) (m3) = Volume (conditionnel) (m3) | Superficie de la face intérieure du mur (brute) (m2) | Superficie de la face extérieure du mur (brute) (m2) | Longueur de Mur sur face intérieure (mm) = Longueur 3D (mm) | Longueur de Mur sur face extérieure (mm) | Superficie (m2) = Superficie supérieure (nette) (m2) | Altitude à Zéro du Projet (mm) = Altitude de Référence Niveau 1 (mm) = Altitude de Référence Niveau 2 (mm) = Altitude à niveau de la mer (mm) = Altitude inférieure à premier niveau de référence (mm) = Altitude inférieure à Zéro du projet (mm) = Altitude inférieure à niveau de la mer (mm) = Altitude inférieure à deuxième niveau de référence (mm) | Volume (brut) (m3) | Périmètre Plan (mm) | Altitude supérieure à premier niveau de référence (mm) = Altitude supérieure à Zéro du projet (mm) = Altitude supérieure à niveau de la mer (mm) = Altitude supérieure à deuxième niveau de référence (mm) | Superficie de l'arête (nette) (m2) | Emplacement de ligne de référence | Surface de face intérieure = Surface de face extérieure = Surfaces (Toutes) = Surface latérale | Nom de zone liée | Numéro de zone liée | Nom d'étage d'implantation | Numéro d'étage d'implantation
Mur-149 | rdc | 0 | 2700 | 2700 | 0 | 0 | 0.252452 | 0 | 935.007 | 2.619 | 2.43004 | 0 | 900 | 970 | 2.619 | 900.013 | 2.43004 | 0.252452 | 2.619 | 2.43004 | 970 | 900.013 | 0.0935007 | 3000 | 0.252452 | 2092.07 | 5700 | 0.786558 | Face intérieure | Peinture-01 | Sdb | A04 | rdc | 3
Mur-149 | Etage1 | 0 | 2700 | 2700 | 0 | 0 | 0.252452 | 0 | 935.007 | 2.619 | 2.43004 | 0 | 900 | 970 | 2.619 | 900.014 | 2.43004 | 0.252452 | 2.619 | 2.43004 | 970 | 900.014 | 0.0935007 | 5750 | 0.252452 | 2092.07 | 8450 | 0.786557 | Face intérieure | Peinture-01 | Sdb | A14 | Etage1 | 4 | ArchiCADProperties - Zones conflictuelles: Sdb
Mur-149 | Etage 2 | 0 | 2700 | 2700 | 0 | 0 | 0.252466 | 0 | 935.059 | 2.619 | 2.43032 | 0 | 900 | 970 | 2.619 | 900.118 | 2.43032 | 0.252466 | 2.619 | 2.43032 | 970 | 900.118 | 0.0935059 | 8500 | 0.252466 | 2092.12 | 11200 | 0.786406 | Face intérieure | Peinture-01 | Sde | A24 | Etage 2 | 5 | ArchiCADProperties - Zones conflictuelles: Sde
Mur-149 | Etage 3 | 1 | 2800 | 2500 | 1.89 | 900 | 0.836529 | 1.89 | 3664.75 | 8.16929 | 7.97329 | 0.189 | 3664.75 | 2764.75 | 10.0593 | 2764.75 | 9.86329 | 1.02553 | 10.2613 | 10.2613 | 3664.75 | 3664.75 | 0.276475 | 11550 | 1.02613 | 7529.5 | 14350 | 1.17095 | Face extérieure | Lavis blanc | Dgt/pl | B34 | Etage 3 | 6
Mur-149 | Etage 5 | 2 | 2500 | 0 | 3.5832 | 1730 | 0.39033 | 3.7828 | 3074.49 | 3.90289 | 3.72844 | 0.37828 | 3074.49 | 1264.49 | 7.68569 | 1264.49 | 7.51124 | 0.76861 | 7.68569 | 7.68624 | 3074.49 | 3074.49 | 0.126444 | 17650 | 0.76861 | 6348.99 | 20150 | 0.858889 | Face intérieure | Surface-Blanche | Ch 1 | B51 | Etage 5 | 8
Mur-149 | Etage 5 | 1 | 2700 | 2700 | 1.89 | 900 | 0.397412 | 1.89 | 2175.01 | 3.87122 | 3.69902 | 0.189 | 2140.01 | 1310.01 | 5.76122 | 1240.01 | 5.58902 | 0.586412 | 5.95022 | 5.77802 | 2210.01 | 2140.01 | 0.127501 | 17650 | 0.586412 | 4572.08 | 20350 | 0.939283 | Face intérieure | Surface-Blanche | Ch 1 | B54 | Etage 5 | 8

# IfcWallStandardCase: Cloison 100 100 (4)
Classification: Mur (Classification ARCHICAD); Material: Hachure solide 268963992 100 mm
ArchiCADProperties - Complexité de mur: Droit; Option de géométrie: Uniforme; Emplacement de ligne de référence: Face intérieure; Surface de face intérieure: Peinture-01; Surface de face extérieure: Peinture-01; Angle d'inclinaison interne de mur: 90 deg; Angle d'inclinaison externe de mur: 90 deg; ID de l'élément: Mur-149; Lien et ID d'élément: Mur-149; Calque: 1-Projet; Matériau de construction / Composite / Profil / Hachure: Cloison 100; Structure Composite: Cloison 100; Verrouillé: no; Type d'élément: Mur; Étage supérieur lié absolu: Non lié; Étage supérieur lié relatif: Non lié; Étage supérieur lié: Non lié; Type de structure: Composite; ID de Parent: Mur-149; Matériaux de construction (Tous): Hachure solide 268963992; Surfaces (Toutes): Peinture-01; Angle d'inclinaison: 90 deg; Nombre de percements: 0; Surface latérale: Peinture-01; Nom de Variante: Modèle principal; Nom de Jeu de Variantes: Modèle principal; Position: Non défini; Fonction structurelle: Non défini; Affichage sur filtre de rénovation: Tous les filtres appropriés; État de rénovation: Existant; État de Variante: Modèle principal; Jeu de Variantes: Modèle principal
ArchiCADQuantities - Nombre de Portes: 0; Nombre de trous (Nombre d'ouvertures vides): 0; Nombre de Fenêtres: 0; Nombre de Poteaux: 0; Volume des poteaux: 0 m3; Hauteur maximale de la couche de Mur sur face intérieure: 2700 mm; Hauteur maximale du Mur: 2700 mm; Hauteur maximale de la couche de Mur sur face extérieure: 2700 mm; Épaisseur couche d'air: 0 mm; Superficie des portes: 0 m2; Largeur totale des Portes: 0 mm; Épaisseur de composant de mur sur face intérieure: 100 mm; Épaisseur de composant de mur sur face extérieure: 100 mm; Superficie des fenêtres: 0 m2; Largeur totale des Fenêtres: 0 mm; Superficie analytique des ouvertures sur face intérieure: 0 m2; Superficie analytique des ouvertures sur face extérieure: 0 m2; Longueur moyenne du mur: 1698.5 mm; Volume analytique des ouvertures: 0 m3; Longueur de ligne de référence: 1698.5 mm; Longueur de la face intérieure du mur (conditionnelle): 1698.5 mm; Longueur de la face extérieure du mur (conditionnelle): 1698.5 mm; Superficie de la face extérieure du mur (brute): 4.58594 m2; Épaisseur du Mur à la fin: 100 mm; Longueur du Mur au centre: 1698.5 mm; Longueur de Mur sur face intérieure: 1698.5 mm; Longueur de Mur sur face extérieure: 1698.5 mm; Superficie des baies libres dans le Mur: 0 m2; Hauteur: 2700 mm; Largeur: 100 mm; Altitude à étage lié/étage d'implantation: 0 mm; Décalage étage d'implantation: 0 mm; Décalage supérieur: 0 mm; Longueur 3D: 1698.5 mm; Épaisseur: 100 mm; Épaisseur couche isolation: 0 mm; Périmètre Plan: 3596.99 mm; Altitude supérieure à étage d'implantation: 2700 mm; Altitude inférieure à étage d'implantation: 0 mm
AC_Pset_RenovationAndPhasing - Renovation Status: Existing
Name | In | Nom de zone liée | Numéro de zone liée | Nom d'étage d'implantation | Numéro d'étage d'implantation | Hauteur minimale de la couche de Mur sur face intérieure (mm) = Hauteur minimale du Mur (mm) = Hauteur minimale de la couche de Mur sur face extérieure (mm) | Volume de composant de mur sur face intérieure (net) (m3) = Volume de composant de mur sur face extérieure (net) (m3) = Volume du composant face intérieure du mur (conditionnel) (m3) = Volume du composant face extérieure du mur (conditionnel) (m3) = Volume (net) (m3) = Volume (conditionnel) (m3) = Volume (brut) (m3) | Superficie de la face intérieure du mur (nette) (m2) = Superficie de la face intérieure du mur (conditionnelle) (m2) = Superficie de la face intérieure du mur (brute) (m2) | Superficie de la face extérieure du mur (nette) (m2) = Superficie de la face extérieure du mur (conditionnelle) (m2) = Superficie en plan (m2) = Superficie inférieure (nette) (m2) | Superficie (m2) = Superficie supérieure (nette) (m2) | Altitude à Zéro du Projet (mm) = Altitude de Référence Niveau 1 (mm) = Altitude de Référence Niveau 2 (mm) = Altitude à niveau de la mer (mm) = Altitude inférieure à premier niveau de référence (mm) = Altitude inférieure à Zéro du projet (mm) = Altitude inférieure à niveau de la mer (mm) = Altitude inférieure à deuxième niveau de référence (mm) | Altitude supérieure à premier niveau de référence (mm) = Altitude supérieure à Zéro du projet (mm) = Altitude supérieure à niveau de la mer (mm) = Altitude supérieure à deuxième niveau de référence (mm) | Superficie de l'arête (nette) (m2)
Mur-149 | rdc | Sdb | B05 | rdc | 3 | 0 | 0.458567 | 4.53194 | 4.58594 | 0.16984 | 3000 | 5700 | 0.879679 | ArchiCADProperties - Zones conflictuelles: Sdb
Mur-149 | Etage1 | Sde | B16 | Etage1 | 4 | 0 | 0.458567 | 4.53194 | 4.58594 | 0.16984 | 5750 | 8450 | 0.879679 | ArchiCADProperties - Zones conflictuelles: Sde
Mur-149 | Etage 2 |  |  | Etage 2 | 5 | 2700 | 0.458594 | 4.58594 | 4.58594 | 0.16985 | 8500 | 11200 | 0.879699
Mur-149 | Etage 3 | Sde | B35 | Etage 3 | 6 | 2700 | 0.458594 | 4.58594 | 4.53194 | 0.16985 | 11550 | 14250 | 0.879699

# IfcWallStandardCase: Cloison 100 gaine 0826278243 100 (44)
Classification: Mur (Classification ARCHICAD); Material: Brique 1 268964100 100 mm
ArchiCADProperties - Complexité de mur: Droit; Option de géométrie: Uniforme; Emplacement de ligne de référence: Face extérieure; Surface de face intérieure: Peinture-01; Surface de face extérieure: Peinture-01; Angle d'inclinaison interne de mur: 90 deg; Angle d'inclinaison externe de mur: 90 deg; ID de l'élément: Mur-149; Lien et ID d'élément: Mur-149; Calque: 1-Projet; Matériau de construction / Composite / Profil / Hachure: Cloison 100 gaine 0826278243; Structure Composite: Cloison 100 gaine 0826278243; Verrouillé: no; Type d'élément: Mur; Étage supérieur lié absolu: Non lié; Étage supérieur lié relatif: Non lié; Étage supérieur lié: Non lié; Type de structure: Composite; ID de Parent: Mur-149; Matériaux de construction (Tous): Brique 1 268964100; Surfaces (Toutes): Peinture-01; Angle d'inclinaison: 90 deg; Nombre de percements: 0; Surface latérale: Peinture-01; Nom de Variante: Modèle principal; Nom de Jeu de Variantes: Modèle principal; Position: Non défini; Fonction structurelle: Non défini; Affichage sur filtre de rénovation: Tous les filtres appropriés; État de rénovation: Existant; État de Variante: Modèle principal; Jeu de Variantes: Modèle principal
AC_Pset_RenovationAndPhasing - Renovation Status: Existing
ArchiCADQuantities - Nombre de Portes: 0; Nombre de trous (Nombre d'ouvertures vides): 0; Nombre de Fenêtres: 0; Nombre de Poteaux: 0; Volume des poteaux: 0 m3; Épaisseur couche d'air: 0 mm; Superficie des portes: 0 m2; Largeur totale des Portes: 0 mm; Épaisseur de composant de mur sur face intérieure: 100 mm; Épaisseur de composant de mur sur face extérieure: 100 mm; Superficie des fenêtres: 0 m2; Largeur totale des Fenêtres: 0 mm; Superficie analytique des ouvertures sur face intérieure: 0 m2; Superficie analytique des ouvertures sur face extérieure: 0 m2; Volume analytique des ouvertures: 0 m3; Épaisseur du Mur à la fin: 100 mm; Superficie des baies libres dans le Mur: 0 m2; Largeur: 100 mm; Altitude à étage lié/étage d'implantation: 0 mm; Décalage étage d'implantation: 0 mm; Décalage supérieur: 0 mm; Épaisseur: 100 mm; Épaisseur couche isolation: 0 mm; Altitude inférieure à étage d'implantation: 0 mm
Name | In | Nom d'étage d'implantation | Numéro d'étage d'implantation | Hauteur maximale de la couche de Mur sur face intérieure (mm) = Hauteur minimale de la couche de Mur sur face intérieure (mm) = Hauteur maximale du Mur (mm) = Hauteur minimale du Mur (mm) = Hauteur maximale de la couche de Mur sur face extérieure (mm) = Hauteur minimale de la couche de Mur sur face extérieure (mm) = Hauteur (mm) = Altitude supérieure à étage d'implantation (mm) | Volume de composant de mur sur face intérieure (net) (m3) = Volume de composant de mur sur face extérieure (net) (m3) = Volume du composant face intérieure du mur (conditionnel) (m3) = Volume du composant face extérieure du mur (conditionnel) (m3) | Longueur moyenne du mur (mm) = Longueur du Mur au centre (mm) | Superficie de la face intérieure du mur (nette) (m2) = Superficie de la face intérieure du mur (conditionnelle) (m2) = Superficie de la face intérieure du mur (brute) (m2) | Superficie de la face extérieure du mur (nette) (m2) = Superficie de la face extérieure du mur (conditionnelle) (m2) = Superficie de la face extérieure du mur (brute) (m2) = Superficie en plan (m2) = Superficie inférieure (nette) (m2) | Longueur de ligne de référence (mm) = Longueur de la face extérieure du mur (conditionnelle) (mm) = Longueur de Mur sur face extérieure (mm) | Longueur de la face intérieure du mur (conditionnelle) (mm) = Longueur de Mur sur face intérieure (mm) | Superficie (m2) = Superficie supérieure (nette) (m2) | Volume (net) (m3) = Volume (conditionnel) (m3) = Volume (brut) (m3) | Altitude à Zéro du Projet (mm) = Altitude de Référence Niveau 1 (mm) = Altitude de Référence Niveau 2 (mm) = Altitude à niveau de la mer (mm) = Altitude inférieure à premier niveau de référence (mm) = Altitude inférieure à Zéro du projet (mm) = Altitude inférieure à niveau de la mer (mm) = Altitude inférieure à deuxième niveau de référence (mm) | Longueur 3D (mm) | Périmètre Plan (mm) | Altitude supérieure à premier niveau de référence (mm) = Altitude supérieure à Zéro du projet (mm) = Altitude supérieure à niveau de la mer (mm) = Altitude supérieure à deuxième niveau de référence (mm) | Superficie de l'arête (nette) (m2)
2 x Mur-149 | rdc | rdc | 3 | 2750 | 0.129445 | 470.971 | 0.865398 | 1.73154 | 628.05 | 313.891 | 0.047217 | 0.129847 | 3000 | 785.13 | 1141.94 | 5750 | 0.644434
2 x Mur-149 | rdc | rdc | 3 | 2750 | 0.129847 | 470.971 | 0.865398 | 1.73154 | 628.05 | 313.891 | 0.047217 | 0.129847 | 3000 | 785.13 | 1141.94 | 5750 | 0.644434
4 x Mur-149 | rdc | rdc | 3 | 2750 | 0.159083 | 578.483 | 1.59083 | 1.59083 | 578.483 | 578.483 | 0.0578483 | 0.159083 | 3000 | 578.483 | 1356.97 | 5750 | 0.665697
2 x Mur-149 | Etage1 | Etage1 | 4 | 2750 | 0.129847 | 470.971 | 0.865398 | 1.73154 | 628.05 | 313.891 | 0.047217 | 0.129847 | 5750 | 785.13 | 1141.94 | 8500 | 0.644434
3 x Mur-149 | Etage1 | Etage1 | 4 | 2750 | 0.159083 | 578.483 | 1.59083 | 1.59083 | 578.483 | 578.483 | 0.0578483 | 0.159083 | 5750 | 578.483 | 1356.97 | 8500 | 0.665697
Mur-149 | Etage1 | Etage1 | 4 | 2700 | 0.15619 | 578.483 | 1.5619 | 1.5619 | 578.483 | 578.483 | 0.0578483 | 0.15619 | 5750 | 578.483 | 1356.97 | 8450 | 0.655697
2 x Mur-149 | Etage1 | Etage1 | 4 | 2750 | 0.129445 | 470.971 | 0.865398 | 1.73154 | 628.05 | 313.891 | 0.047217 | 0.129847 | 5750 | 785.13 | 1141.94 | 8500 | 0.644434
2 x Mur-149 | Etage 2 | Etage 2 | 5 | 3050 | 0.144012 | 470.971 | 0.959805 | 1.92043 | 628.05 | 313.891 | 0.047217 | 0.144012 | 8500 | 785.13 | 1141.94 | 11550 | 0.704434
3 x Mur-149 | Etage 2 | Etage 2 | 5 | 3050 | 0.176437 | 578.483 | 1.76437 | 1.76437 | 578.483 | 578.483 | 0.0578483 | 0.176437 | 8500 | 578.483 | 1356.97 | 11550 | 0.725697
Mur-149 | Etage 2 | Etage 2 | 5 | 3000 | 0.173545 | 578.483 | 1.73545 | 1.73545 | 578.483 | 578.483 | 0.0578483 | 0.173545 | 8500 | 578.483 | 1356.97 | 11500 | 0.715697
2 x Mur-149 | Etage 2 | Etage 2 | 5 | 3050 | 0.143566 | 470.971 | 0.959805 | 1.92043 | 628.05 | 313.891 | 0.047217 | 0.144012 | 8500 | 785.13 | 1141.94 | 11550 | 0.704434
3 x Mur-149 | Etage 3 | Etage 3 | 6 | 3050 | 0.176437 | 578.483 | 1.76437 | 1.76437 | 578.483 | 578.483 | 0.0578483 | 0.176437 | 11550 | 578.483 | 1356.97 | 14600 | 0.725697
2 x Mur-149 | Etage 3 | Etage 3 | 6 | 3050 | 0.143566 | 470.971 | 0.959805 | 1.92043 | 628.05 | 313.891 | 0.047217 | 0.144012 | 11550 | 785.13 | 1141.94 | 14600 | 0.704434
2 x Mur-149 | Etage 3 | Etage 3 | 6 | 3050 | 0.144012 | 470.971 | 0.959805 | 1.92043 | 628.05 | 313.891 | 0.047217 | 0.144012 | 11550 | 785.13 | 1141.94 | 14600 | 0.704434
Mur-149 | Etage 3 | Etage 3 | 6 | 3000 | 0.173545 | 578.483 | 1.73545 | 1.73545 | 578.483 | 578.483 | 0.0578483 | 0.173545 | 11550 | 578.483 | 1356.97 | 14550 | 0.715697
2 x Mur-149 | etage 4 | etage 4 | 7 | 3050 | 0.144012 | 470.971 | 0.959805 | 1.92043 | 628.05 | 313.891 | 0.047217 | 0.144012 | 14600 | 785.13 | 1141.94 | 17650 | 0.704434
2 x Mur-149 | etage 4 | etage 4 | 7 | 3050 | 0.176437 | 578.483 | 1.76437 | 1.76437 | 578.483 | 578.483 | 0.0578483 | 0.176437 | 14600 | 578.483 | 1356.97 | 17650 | 0.725697
2 x Mur-149 | etage 4 | etage 4 | 7 | 1000 | 0.0578483 | 578.483 | 0.578483 | 0.578483 | 578.483 | 578.483 | 0.0578483 | 0.0578483 | 14600 | 578.483 | 1356.97 | 15600 | 0.315697
2 x Mur-149 | etage 4 | etage 4 | 7 | 1000 | 0.0470709 | 470.971 | 0.31469 | 0.629649 | 628.05 | 313.891 | 0.047217 | 0.047217 | 14600 | 785.13 | 1141.94 | 15600 | 0.294434
2 x Mur-149 | Etage 5 | Etage 5 | 8 | 1000 | 0.047217 | 470.971 | 0.31469 | 0.629649 | 628.05 | 313.891 | 0.047217 | 0.047217 | 17650 | 785.13 | 1141.94 | 18650 | 0.294434
2 x Mur-149 | Etage 5 | Etage 5 | 8 | 1000 | 0.0578483 | 578.483 | 0.578483 | 0.578483 | 578.483 | 578.483 | 0.0578483 | 0.0578483 | 17650 | 578.483 | 1356.97 | 18650 | 0.315697

# IfcWallStandardCase: Cloison 100 gaine 100 (19)
Classification: Mur (Classification ARCHICAD); Material: Brique 1 268964100 100 mm
ArchiCADProperties - Complexité de mur: Droit; Option de géométrie: Uniforme; Emplacement de ligne de référence: Face extérieure; Surface de face intérieure: Plâtre Lisse; Surface de face extérieure: Plâtre Lisse; Angle d'inclinaison interne de mur: 90 deg; Angle d'inclinaison externe de mur: 90 deg; ID de l'élément: Mur-133; Lien et ID d'élément: Mur-133; Calque: 3D; Matériau de construction / Composite / Profil / Hachure: Cloison 100 gaine; Structure Composite: Cloison 100 gaine; Verrouillé: no; Type d'élément: Mur; Étage supérieur lié absolu: Non lié; Étage supérieur lié relatif: Non lié; Étage supérieur lié: Non lié; Type de structure: Composite; ID de Parent: Mur-133; Matériaux de construction (Tous): Brique 1 268964100; Surfaces (Toutes): Plâtre Lisse; Angle d'inclinaison: 90 deg; Nombre de percements: 0; Surface latérale: Plâtre Lisse; Nom de Variante: Modèle principal; Nom de Jeu de Variantes: Modèle principal; Position: Non défini; Fonction structurelle: Non défini; Affichage sur filtre de rénovation: Tous les filtres appropriés; État de rénovation: Existant; État de Variante: Modèle principal; Jeu de Variantes: Modèle principal
AC_Pset_RenovationAndPhasing - Renovation Status: Existing
ArchiCADQuantities - Nombre de Fenêtres: 0; Volume des poteaux: 0 m3; Épaisseur couche d'air: 0 mm; Épaisseur de composant de mur sur face intérieure: 100 mm; Épaisseur de composant de mur sur face extérieure: 100 mm; Superficie des fenêtres: 0 m2; Largeur totale des Fenêtres: 0 mm; Épaisseur du Mur à la fin: 100 mm; Largeur: 100 mm; Décalage supérieur: 0 mm; Épaisseur: 100 mm; Épaisseur couche isolation: 0 mm
Name | In | Nom d'étage d'implantation | Numéro d'étage d'implantation | Nombre de Portes | Nombre de trous (Nombre d'ouvertures vides) | Nombre de Poteaux | Hauteur maximale de la couche de Mur sur face intérieure (mm) = Hauteur maximale du Mur (mm) = Hauteur maximale de la couche de Mur sur face extérieure (mm) = Hauteur (mm) = Altitude supérieure à étage d'implantation (mm) | Hauteur minimale de la couche de Mur sur face intérieure (mm) = Hauteur minimale du Mur (mm) = Hauteur minimale de la couche de Mur sur face extérieure (mm) | Superficie des portes (m2) | Largeur totale des Portes (mm) | Volume de composant de mur sur face intérieure (net) (m3) = Volume de composant de mur sur face extérieure (net) (m3) = Volume (net) (m3) | Superficie analytique des ouvertures sur face intérieure (m2) = Superficie analytique des ouvertures sur face extérieure (m2) | Longueur moyenne du mur (mm) = Longueur du Mur au centre (mm) | Superficie de la face intérieure du mur (nette) (m2) | Superficie de la face extérieure du mur (nette) (m2) = Superficie en plan (m2) = Superficie inférieure (nette) (m2) | Volume analytique des ouvertures (m3) | Longueur de ligne de référence (mm) | Longueur de la face intérieure du mur (conditionnelle) (mm) | Superficie de la face intérieure du mur (conditionnelle) (m2) | Longueur de la face extérieure du mur (conditionnelle) (mm) | Superficie de la face extérieure du mur (conditionnelle) (m2) | Volume du composant face intérieure du mur (conditionnel) (m3) = Volume du composant face extérieure du mur (conditionnel) (m3) = Volume (conditionnel) (m3) | Superficie de la face intérieure du mur (brute) (m2) | Superficie de la face extérieure du mur (brute) (m2) | Longueur de Mur sur face intérieure (mm) | Longueur de Mur sur face extérieure (mm) | Superficie des baies libres dans le Mur (m2) | Superficie (m2) = Superficie supérieure (nette) (m2) | Altitude à Zéro du Projet (mm) = Altitude de Référence Niveau 1 (mm) = Altitude de Référence Niveau 2 (mm) = Altitude à niveau de la mer (mm) | Altitude à étage lié/étage d'implantation (mm) = Décalage étage d'implantation (mm) | Longueur 3D (mm) | Volume (brut) (m3) | Périmètre Plan (mm) | Altitude supérieure à premier niveau de référence (mm) = Altitude supérieure à Zéro du projet (mm) = Altitude supérieure à niveau de la mer (mm) = Altitude supérieure à deuxième niveau de référence (mm) | Altitude inférieure à premier niveau de référence (mm) = Altitude inférieure à Zéro du projet (mm) = Altitude inférieure à niveau de la mer (mm) = Altitude inférieure à deuxième niveau de référence (mm) | Altitude inférieure à étage d'implantation (mm) | Superficie de l'arête (nette) (m2)
Mur-133 | sousol | sousol | 2 | 0 | 0 | 2 | 2950 | 0 | 0 | 0 | 1.24782 | 0 | 5020 | 12.4782 | 12.4782 | 0 | 5380 | 5020 | 12.4782 | 5020 | 12.4782 | 1.24782 | 14.9386 | 14.9386 | 5020 | 5020 | 0 | 0.438 | 4.18415e-12 | 4.18415e-12 | 4380 | 1.49386 | 10240 | 2950 | 0 | 0 | 1.171
Mur-133 | sousol | sousol | 2 | 0 | 0 | 2 | 2950 | 0 | 0 | 0 | 1.25375 | 0 | 5070 | 12.39 | 12.685 | 0 | 5200 | 5020 | 12.39 | 5120 | 12.685 | 1.25375 | 14.8504 | 15.1454 | 5020 | 5120 | 0 | 0.425 | 4.18415e-12 | 4.18415e-12 | 4300 | 1.49979 | 10381.4 | 2950 | 0 | 0 | 1.26719
Mur-133 | sousol | sousol | 2 | 0 | 0 | 0 | 2720 | 0 | 0 | 0 | 1.60243 | 0 | 6162.47 | 16.0243 | 16.0243 | 0 | 6342.47 | 6162.47 | 16.0243 | 6162.47 | 16.0243 | 1.60243 | 16.2723 | 16.2723 | 6162.47 | 6162.47 | 0 | 0.598247 | 4.18415e-12 | 4.18415e-12 | 5982.47 | 1.62723 | 12524.9 | 2720 | 4.21885e-12 | 4.21885e-12 | 1.70049
Mur-133 | sousol | sousol | 2 | 0 | 0 | 0 | 3000 | 2100 | 0 | 0 | 1.5821 | 0 | 5360 | 15.632 | 16.01 | 0 | 5450 | 5270 | 15.632 | 5450 | 16.01 | 1.5821 | 15.8604 | 16.35 | 5270 | 5450 | 0 | 0.545 | 4.18415e-12 | 4.18415e-12 | 5450 | 1.61052 | 11025.9 | 3000 | 0 | 0 | 1.81842
Mur-133 | sousol | sousol | 2 | 0 | 0 | 0 | 2950 | 2950 | 0 | 0 | 0.0442947 | 0 | 150.152 | 0.590447 | 0.295447 | 0 | 200.152 | 200.152 | 0.590447 | 100.152 | 0.295447 | 0.0442947 | 0.590447 | 0.295447 | 200.152 | 100.152 | 0 | 0.0150152 | 4.18415e-12 | 4.18415e-12 | 200.152 | 0.0442947 | 541.725 | 2950 | 0 | 0 | 0.742223
Mur-133 | sousol | sousol | 2 | 0 | 0 | 1 | 3000 | 0 | 0 | 0 | 1.455 | 0 | 5270 | 14.55 | 14.55 | 0 | 5450 | 5270 | 14.55 | 5270 | 14.55 | 1.455 | 15.8604 | 15.8604 | 5270 | 5270 | 0 | 0.485 | 4.18415e-12 | 4.18415e-12 | 4850 | 1.58604 | 10740 | 3000 | 0 | 0 | 1.27
Mur-133 | sousol | sousol | 2 | 0 | 0 | 1 | 2586.04 | 0 | 0 | 0 | 1.28276 | 0 | 5270 | 12.8276 | 12.8276 | 0 | 5630 | 5270 | 12.8276 | 5270 | 12.8276 | 1.28276 | 13.6284 | 13.6284 | 5270 | 5270 | 0 | 0.497 | 4.18415e-12 | 4.18415e-12 | 4970 | 1.36284 | 10740 | 2586.04 | 0 | 0 | 1.44366
Mur-133 | sousol | sousol | 2 | 1 | 0 | 0 | 2770 | 2770 | 4.92 | 2400 | 0.344493 | 4.92 | 3019.83 | 2.94633 | 2.94633 | 0.492 | 3199.83 | 619.829 | 2.94633 | 619.829 | 2.94633 | 0.836493 | 8.36493 | 8.36493 | 3019.83 | 3019.83 | 0 | 0.0619829 | 4.18415e-12 | 4.18415e-12 | 3019.83 | 0.836493 | 6239.66 | 2770 | 4.21885e-12 | 4.21885e-12 | 0.917966
Mur-133 | sousol | sousol | 2 | 0 | 0 | 2 | 3000 | 0 | 0 | 0 | 1.395 | 0 | 5270 | 13.95 | 13.95 | 0 | 5630 | 5270 | 13.95 | 5270 | 13.95 | 1.395 | 15.8604 | 15.8604 | 5270 | 5270 | 0 | 0.465 | 4.18415e-12 | 4.18415e-12 | 4650 | 1.58604 | 10740 | 3000 | 0 | 0 | 1.23
2 x Mur-133 | sousol | sousol | 2 | 0 | 0 | 0 | 2260 | 2000 | 0 | 0 | 1.24248 | 0 | 5500 | 12.4248 | 12.4248 | 0 | 5500 | 5500 | 12.4248 | 5500 | 12.4248 | 1.24248 | 12.43 | 12.43 | 5500 | 5500 | 0 | 0.55 | 4.18415e-12 | 4.18415e-12 | 5500 | 1.243 | 11200 | 2260 | 4.21885e-12 | 4.21885e-12 | 1.524
Mur-133 | sousol | sousol | 2 | 0 | 0 | 2 | 3000 | 0 | 0 | 0 | 1.39853 | 0 | 5270 | 13.9853 | 13.9853 | 0 | 5630 | 5270 | 13.9853 | 5270 | 13.9853 | 1.39853 | 15.8604 | 15.8604 | 5270 | 5270 | 0 | 0.466176 | 4.18415e-12 | 4.18415e-12 | 4661.76 | 1.58604 | 10740 | 3000 | 0 | 0 | 1.23235
Mur-133 | sousol | sousol | 2 | 0 | 0 | 1 | 3000 | 0 | 0 | 0 | 1.61401 | 0 | 5860 | 16.1401 | 16.1401 | 0 | 5860 | 5860 | 16.1401 | 5860 | 16.1401 | 1.61401 | 17.04 | 17.04 | 5860 | 5860 | 0 | 0.538004 | 4.18415e-12 | 4.18415e-12 | 5380.04 | 1.704 | 11920 | 3000 | 0 | 0 | 1.37601
Mur-133 | sousol | sousol | 2 | 0 | 0 | 0 | 2586.04 | 0 | 0 | 0 | 1.37063 | 0 | 5500 | 13.7063 | 13.7063 | 0 | 5500 | 5500 | 13.7063 | 5500 | 13.7063 | 1.37063 | 13.8272 | 13.8272 | 5500 | 5500 | 0 | 0.55 | 4.18415e-12 | 4.18415e-12 | 5500 | 1.38272 | 11200 | 2586.04 | 4.21885e-12 | 4.21885e-12 | 1.43013
Mur-133 | rdc | rdc | 3 | 0 | 0 | 0 | 2500 | 2500 | 0 | 0 | 0.0816936 | 0 | 326.774 | 0.941936 | 0.691936 | 0 | 376.774 | 376.774 | 0.941936 | 276.774 | 0.691936 | 0.0816936 | 0.941936 | 0.691936 | 376.774 | 276.774 | 0 | 0.0326774 | 3000 | 3.9968e-12 | 376.774 | 0.0816936 | 894.97 | 5500 | 3000 | 3.9968e-12 | 0.668908 | ArchiCADProperties - Zones conflictuelles: Pl; Nom de zone liée: Pl; Numéro de zone liée: 679
Mur-133 | rdc | rdc | 3 | 1 | 0 | 0 | 2500 | 2500 | 2.163 | 1030 | 1.07178 | 2.3754 | 5237.29 | 10.5928 | 10.5928 | 0.23754 | 5307.29 | 4077.29 | 10.5928 | 4177.29 | 10.5928 | 1.30932 | 12.9682 | 13.2182 | 5187.29 | 5287.29 | 0 | 0.412729 | 3000 | 3.9968e-12 | 5287.29 | 1.30932 | 10716 | 5500 | 3000 | 3.9968e-12 | 1.54001 | ArchiCADProperties - Nom de zone liée: Pl; Numéro de zone liée: 819
Mur-133 | rdc | rdc | 3 | 0 | 0 | 0 | 2500 | 2500 | 0 | 0 | 0.930286 | 0 | 3721.14 | 9.17786 | 9.17786 | 0 | 4091.13 | 3771.14 | 9.17786 | 3671.14 | 9.17786 | 0.930286 | 9.42786 | 9.17786 | 3771.14 | 3671.14 | 0 | 0.372114 | 3000 | 3.9968e-12 | 3771.14 | 0.930286 | 7683.71 | 5500 | 3000 | 3.9968e-12 | 1.34778 | ArchiCADProperties - Nom de zone liée: Pl; Numéro de zone liée: 819
Mur-133 | rdc | rdc | 3 | 1 | 0 | 0 | 2500 | 2500 | 2.163 | 1030 | 0.07496 | 2.3754 | 1250 | 0.7496 | 0.7496 | 0.23754 | 1430 | 140 | 0.7496 | 140 | 0.7496 | 0.3125 | 3.125 | 3.125 | 1250 | 1250 | 0 | 0.014 | 3000 | 3.9968e-12 | 1250 | 0.3125 | 2700 | 5500 | 3000 | 3.9968e-12 | 0.425 | ArchiCADProperties - Nom de zone liée: Pl; Numéro de zone liée: 679
Mur-133 | rdc | rdc | 3 | 0 | 3 | 0 | 2500 | 2500 | 0 | 0 | 0.157169 | 0.0441 | 646.318 | 1.6967 | 1.44669 | 0.00441 | 916.317 | 696.318 | 1.7408 | 596.317 | 1.49079 | 0.161579 | 1.7408 | 1.49079 | 696.318 | 596.317 | 0.1323 | 0.0646318 | 3000 | 3.9968e-12 | 696.318 | 0.161579 | 1534.06 | 5500 | 3000 | 3.55271e-12 | 0.732817 | ArchiCADProperties - Zones conflictuelles: Pl; Nom de zone liée: Pl; Numéro de zone liée: 679

# IfcWallStandardCase: Cloison 120 120, Mur-133
In: rdc
Classification: Mur (Classification ARCHICAD); Material: Brique 1 268964100 120 mm
ArchiCADProperties - Complexité de mur: Droit; Option de géométrie: Uniforme; Emplacement de ligne de référence: Face extérieure; Surface de face intérieure: Plâtre Lisse; Surface de face extérieure: Plâtre Lisse; Angle d'inclinaison interne de mur: 90 deg; Angle d'inclinaison externe de mur: 90 deg; ID de l'élément: Mur-133; Lien et ID d'élément: Mur-133; Calque: 3D; Matériau de construction / Composite / Profil / Hachure: Cloison 120; Structure Composite: Cloison 120; Zones conflictuelles: Pl; Nom de zone liée: Pl; Numéro de zone liée: 819; Verrouillé: no; Nom d'étage d'implantation: rdc; Numéro d'étage d'implantation: 3; Type d'élément: Mur; Étage supérieur lié absolu: Non lié; Étage supérieur lié relatif: Non lié; Étage supérieur lié: Non lié; Type de structure: Composite; ID de Parent: Mur-133; Matériaux de construction (Tous): Brique 1 268964100; Surfaces (Toutes): Plâtre Lisse; Angle d'inclinaison: 90 deg; Nombre de percements: 0; Surface latérale: Plâtre Lisse; Nom de Variante: Modèle principal; Nom de Jeu de Variantes: Modèle principal; Position: Non défini; Fonction structurelle: Non défini; Affichage sur filtre de rénovation: Tous les filtres appropriés; État de rénovation: Existant; État de Variante: Modèle principal; Jeu de Variantes: Modèle principal
AC_Pset_RenovationAndPhasing - Renovation Status: Existing
ArchiCADQuantities - Nombre de Portes: 0; Nombre de trous (Nombre d'ouvertures vides): 0; Nombre de Fenêtres: 0; Nombre de Poteaux: 0; Volume des poteaux: 0 m3; Hauteur maximale de la couche de Mur sur face intérieure: 2500 mm; Hauteur minimale de la couche de Mur sur face intérieure: 2500 mm; Hauteur maximale du Mur: 2500 mm; Hauteur minimale du Mur: 2500 mm; Hauteur maximale de la couche de Mur sur face extérieure: 2500 mm; Hauteur minimale de la couche de Mur sur face extérieure: 2500 mm; Épaisseur couche d'air: 0 mm; Superficie des portes: 0 m2; Largeur totale des Portes: 0 mm; Épaisseur de composant de mur sur face intérieure: 120 mm; Épaisseur de composant de mur sur face extérieure: 120 mm; Superficie des fenêtres: 0 m2; Largeur totale des Fenêtres: 0 mm; Volume de composant de mur sur face intérieure (net): 1.03235 m3; Volume de composant de mur sur face extérieure (net): 1.03235 m3; Superficie analytique des ouvertures sur face intérieure: 0 m2; Superficie analytique des ouvertures sur face extérieure: 0 m2; Longueur moyenne du mur: 3441.16 mm; Superficie de la face intérieure du mur (nette): 8.35289 m2; Superficie de la face extérieure du mur (nette): 8.60289 m2; Volume analytique des ouvertures: 0 m3; Longueur de ligne de référence: 3941.16 mm; Longueur de la face intérieure du mur (conditionnelle): 3441.16 mm; Superficie de la face intérieure du mur (conditionnelle): 8.35289 m2; Longueur de la face extérieure du mur (conditionnelle): 3441.16 mm; Superficie de la face extérieure du mur (conditionnelle): 8.60289 m2; Volume du composant face intérieure du mur (conditionnel): 1.03235 m3; Volume du composant face extérieure du mur (conditionnel): 1.03235 m3; Superficie de la face intérieure du mur (brute): 8.60289 m2; Superficie de la face extérieure du mur (brute): 8.60289 m2; Épaisseur du Mur à la fin: 120 mm; Longueur du Mur au centre: 3441.16 mm; Longueur de Mur sur face intérieure: 3441.16 mm; Longueur de Mur sur face extérieure: 3441.16 mm; Superficie des baies libres dans le Mur: 0 m2; Superficie: 0.412939 m2; Hauteur: 2500 mm; Volume (net): 1.03235 m3; Largeur: 120 mm; Altitude à Zéro du Projet: 3000 mm; Altitude de Référence Niveau 1: 3000 mm; Altitude de Référence Niveau 2: 3000 mm; Altitude à niveau de la mer: 3000 mm; Altitude à étage lié/étage d'implantation: 3.9968e-12 mm; Décalage étage d'implantation: 3.9968e-12 mm; Décalage supérieur: 0 mm; Superficie en plan: 8.60289 m2; Longueur 3D: 3441.16 mm; Épaisseur: 120 mm; Volume (conditionnel): 1.03235 m3; Volume (brut): 1.03235 m3; Épaisseur couche isolation: 0 mm; Périmètre Plan: 7122.32 mm; Altitude supérieure à premier niveau de référence: 5500 mm; Altitude supérieure à étage d'implantation: 2500 mm; Altitude supérieure à Zéro du projet: 5500 mm; Altitude supérieure à niveau de la mer: 5500 mm; Altitude supérieure à deuxième niveau de référence: 5500 mm; Altitude inférieure à premier niveau de référence: 3000 mm; Altitude inférieure à étage d'implantation: 3.9968e-12 mm; Altitude inférieure à Zéro du projet: 3000 mm; Altitude inférieure à niveau de la mer: 3000 mm; Altitude inférieure à deuxième niveau de référence: 3000 mm; Superficie supérieure (nette): 0.412939 m2; Superficie de l'arête (nette): 1.42588 m2; Superficie inférieure (nette): 8.60289 m2

# IfcWallStandardCase: Cloison 50 50 (28)
Classification: Mur (Classification ARCHICAD); Material: Hachure solide 268963992 50 mm
AC_Pset_RenovationAndPhasing - Renovation Status: Existing
ArchiCADProperties - Complexité de mur: Droit; Option de géométrie: Uniforme; Surface de face intérieure: Surface-Blanche; Surface de face extérieure: Surface-Blanche; Angle d'inclinaison interne de mur: 90 deg; Angle d'inclinaison externe de mur: 90 deg; Calque: 1-Projet; Matériau de construction / Composite / Profil / Hachure: Cloison 50; Structure Composite: Cloison 50; Verrouillé: no; Type d'élément: Mur; Étage supérieur lié absolu: Non lié; Étage supérieur lié relatif: Non lié; Étage supérieur lié: Non lié; Type de structure: Composite; Matériaux de construction (Tous): Hachure solide 268963992; Surfaces (Toutes): Surface-Blanche; Angle d'inclinaison: 90 deg; Nombre de percements: 0; Surface latérale: Surface-Blanche; Nom de Variante: Modèle principal; Nom de Jeu de Variantes: Modèle principal; Position: Non défini; Fonction structurelle: Non défini; Affichage sur filtre de rénovation: Tous les filtres appropriés; État de rénovation: Existant; État de Variante: Modèle principal; Jeu de Variantes: Modèle principal
ArchiCADQuantities - Nombre de Portes: 0; Nombre de trous (Nombre d'ouvertures vides): 0; Nombre de Fenêtres: 0; Volume des poteaux: 0 m3; Épaisseur couche d'air: 0 mm; Superficie des portes: 0 m2; Largeur totale des Portes: 0 mm; Épaisseur de composant de mur sur face intérieure: 50 mm; Épaisseur de composant de mur sur face extérieure: 50 mm; Superficie des fenêtres: 0 m2; Largeur totale des Fenêtres: 0 mm; Superficie analytique des ouvertures sur face intérieure: 0 m2; Superficie analytique des ouvertures sur face extérieure: 0 m2; Volume analytique des ouvertures: 0 m3; Épaisseur du Mur à la fin: 50 mm; Superficie des baies libres dans le Mur: 0 m2; Largeur: 50 mm; Décalage supérieur: 0 mm; Épaisseur: 50 mm; Épaisseur couche isolation: 0 mm
Name | In | Emplacement de ligne de référence | ID de l'élément = Lien et ID d'élément = ID de Parent | Nom d'étage d'implantation | Numéro d'étage d'implantation | Nombre de Poteaux | Hauteur maximale de la couche de Mur sur face intérieure (mm) = Hauteur maximale du Mur (mm) = Hauteur maximale de la couche de Mur sur face extérieure (mm) = Hauteur (mm) | Hauteur minimale de la couche de Mur sur face intérieure (mm) = Hauteur minimale du Mur (mm) = Hauteur minimale de la couche de Mur sur face extérieure (mm) | Volume de composant de mur sur face intérieure (net) (m3) = Volume de composant de mur sur face extérieure (net) (m3) = Volume du composant face intérieure du mur (conditionnel) (m3) = Volume du composant face extérieure du mur (conditionnel) (m3) | Longueur moyenne du mur (mm) = Longueur du Mur au centre (mm) | Superficie de la face intérieure du mur (nette) (m2) = Superficie de la face intérieure du mur (conditionnelle) (m2) | Superficie de la face extérieure du mur (nette) (m2) = Superficie de la face extérieure du mur (conditionnelle) (m2) = Superficie en plan (m2) = Superficie inférieure (nette) (m2) | Longueur de ligne de référence (mm) | Longueur de la face intérieure du mur (conditionnelle) (mm) = Longueur de Mur sur face intérieure (mm) | Longueur de la face extérieure du mur (conditionnelle) (mm) = Longueur de Mur sur face extérieure (mm) | Superficie de la face intérieure du mur (brute) (m2) | Superficie de la face extérieure du mur (brute) (m2) | Superficie (m2) = Superficie supérieure (nette) (m2) | Volume (net) (m3) = Volume (conditionnel) (m3) | Altitude à Zéro du Projet (mm) = Altitude de Référence Niveau 1 (mm) = Altitude de Référence Niveau 2 (mm) = Altitude à niveau de la mer (mm) = Altitude inférieure à premier niveau de référence (mm) = Altitude inférieure à Zéro du projet (mm) = Altitude inférieure à niveau de la mer (mm) = Altitude inférieure à deuxième niveau de référence (mm) | Altitude à étage lié/étage d'implantation (mm) = Décalage étage d'implantation (mm) | Longueur 3D (mm) | Volume (brut) (m3) | Périmètre Plan (mm) | Altitude supérieure à premier niveau de référence (mm) = Altitude supérieure à Zéro du projet (mm) = Altitude supérieure à niveau de la mer (mm) = Altitude supérieure à deuxième niveau de référence (mm) | Altitude supérieure à étage d'implantation (mm) | Altitude inférieure à étage d'implantation (mm) | Superficie de l'arête (nette) (m2)
Mur-167 | sousol | Face extérieure | Mur-167 | sousol | 2 | 1 | 1000 | 0 | 0.028445 | 611.028 | 0.543899 | 0.593899 | 816.028 | 586.028 | 636.028 | 0.586028 | 0.636028 | 0.028445 | 0.028445 | 0 | 0 | 593.899 | 0.0305514 | 1342.77 | 1000 | 1000 | 0 | 0.127601
Mur-169 | sousol | Face extérieure | Mur-169 | sousol | 2 | 0 | 1000 | 1000 | 0.0305514 | 611.028 | 0.586028 | 0.636028 | 816.028 | 586.028 | 636.028 | 0.586028 | 0.636028 | 0.0305514 | 0.0305514 | 0 | 0 | 636.028 | 0.0305514 | 1342.77 | 1000 | 1000 | 0 | 0.181813
Mur-168 | sousol | Face extérieure | Mur-168 | sousol | 2 | 0 | 1000 | 1000 | 0.0626234 | 1252.47 | 1.20247 | 1.30247 | 1302.47 | 1202.47 | 1302.47 | 1.20247 | 1.30247 | 0.0626234 | 0.0626234 | 0 | 0 | 1302.47 | 0.0626234 | 2646.36 | 1000 | 1000 | 0 | 0.266668
Mur-161 | rdc | Face extérieure | Mur-161 | rdc | 3 | 0 | 100 | 100 | 0.03085 | 6170 | 0.611 | 0.619 | 6190 | 6150 | 6190 | 0.615 | 0.619 | 0.3085 | 0.03085 | 900 | -2100 | 6190 | 0.03085 | 12454 | 1000 | -2000 | -2100 | 0.628403
Mur-154 | rdc | Face intérieure | Mur-154 | rdc | 3 | 0 | 205.783 | 205.783 | 0.00657452 | 638.975 | 0.136635 | 0.126346 | 663.975 | 663.975 | 613.975 | 0.136635 | 0.126346 | 0.0319487 | 0.00657452 | 2600 | -400 | 663.975 | 0.00657452 | 1398.66 | 2805.78 | -194.217 | -400 | 0.0887377
Mur-152 | rdc | Face intérieure | Mur-152 | rdc | 3 | 1 | 600 | 500 | 0.622455 | 20739.6 | 12.4512 | 12.4427 | 20752 | 20752 | 20727.3 | 12.4512 | 12.4487 | 1.0376 | 0.622455 | 2500 | -500 | 20752 | 0.622498 | 41585 | 3100 | 100 | -500 | 2.13535
Mur-149 | rdc | Face intérieure | Mur-149 | rdc | 3 | 0 | 100 | 100 | 0.00239009 | 478.018 | 0.0476751 | 0.0479285 | 476.751 | 476.751 | 479.285 | 0.0476751 | 0.0479285 | 0.0239009 | 0.00239009 | 3000 | 0 | 479.285 | 0.00239009 | 1056.1 | 3100 | 100 | 0 | 0.0578082
Mur-161 | rdc | Face extérieure | Mur-161 | rdc | 3 | 0 | 100 | 100 | 0.00372485 | 744.969 | 0.0719907 | 0.0770031 | 770.031 | 719.907 | 770.031 | 0.0719907 | 0.0770031 | 0.0372485 | 0.00372485 | 900 | -2100 | 770.031 | 0.00372485 | 1610.74 | 1000 | -2000 | -2100 | 0.0865768
Mur-165 | rdc | Face extérieure | Mur-165 | rdc | 3 | 1 | 100 | 100 | 0.0383279 | 7665.66 | 0.766566 | 0.766566 | 7715.66 | 7665.66 | 7665.66 | 0.766566 | 0.766566 | 0.383279 | 0.0383279 | 3000 | 0 | 7665.66 | 0.0383279 | 15431.3 | 3100 | 100 | 0 | 0.776558
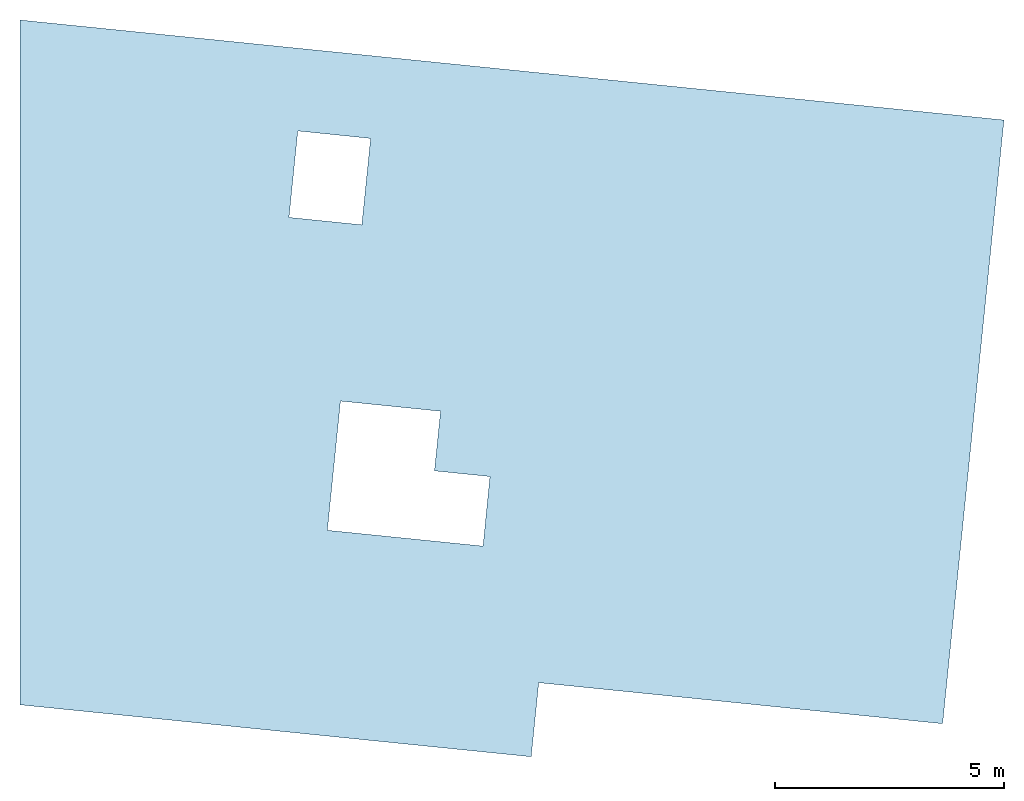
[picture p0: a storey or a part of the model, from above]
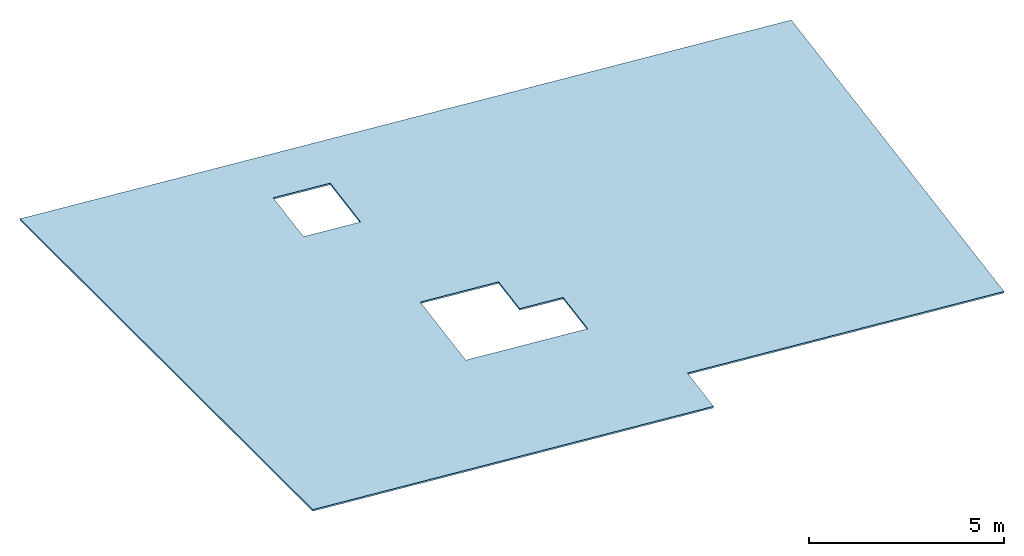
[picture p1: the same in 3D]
Properties of the parts of a building model (IFC2X3), part 23 of 44

# IfcWallStandardCase: Cloison 50 50 (28)
Name | In | Emplacement de ligne de référence | ID de l'élément = Lien et ID d'élément = ID de Parent | Nom d'étage d'implantation | Numéro d'étage d'implantation | Nombre de Poteaux | Hauteur maximale de la couche de Mur sur face intérieure (mm) = Hauteur maximale du Mur (mm) = Hauteur maximale de la couche de Mur sur face extérieure (mm) = Hauteur (mm) | Hauteur minimale de la couche de Mur sur face intérieure (mm) = Hauteur minimale du Mur (mm) = Hauteur minimale de la couche de Mur sur face extérieure (mm) | Volume de composant de mur sur face intérieure (net) (m3) = Volume de composant de mur sur face extérieure (net) (m3) = Volume du composant face intérieure du mur (conditionnel) (m3) = Volume du composant face extérieure du mur (conditionnel) (m3) | Longueur moyenne du mur (mm) = Longueur du Mur au centre (mm) | Superficie de la face intérieure du mur (nette) (m2) = Superficie de la face intérieure du mur (conditionnelle) (m2) | Superficie de la face extérieure du mur (nette) (m2) = Superficie de la face extérieure du mur (conditionnelle) (m2) = Superficie en plan (m2) = Superficie inférieure (nette) (m2) | Longueur de ligne de référence (mm) | Longueur de la face intérieure du mur (conditionnelle) (mm) = Longueur de Mur sur face intérieure (mm) | Longueur de la face extérieure du mur (conditionnelle) (mm) = Longueur de Mur sur face extérieure (mm) | Superficie de la face intérieure du mur (brute) (m2) | Superficie de la face extérieure du mur (brute) (m2) | Superficie (m2) = Superficie supérieure (nette) (m2) | Volume (net) (m3) = Volume (conditionnel) (m3) | Altitude à Zéro du Projet (mm) = Altitude de Référence Niveau 1 (mm) = Altitude de Référence Niveau 2 (mm) = Altitude à niveau de la mer (mm) = Altitude inférieure à premier niveau de référence (mm) = Altitude inférieure à Zéro du projet (mm) = Altitude inférieure à niveau de la mer (mm) = Altitude inférieure à deuxième niveau de référence (mm) | Altitude à étage lié/étage d'implantation (mm) = Décalage étage d'implantation (mm) | Longueur 3D (mm) | Volume (brut) (m3) | Périmètre Plan (mm) | Altitude supérieure à premier niveau de référence (mm) = Altitude supérieure à Zéro du projet (mm) = Altitude supérieure à niveau de la mer (mm) = Altitude supérieure à deuxième niveau de référence (mm) | Altitude supérieure à étage d'implantation (mm) | Altitude inférieure à étage d'implantation (mm) | Superficie de l'arête (nette) (m2)
Mur-165 | rdc | Face extérieure | Mur-165 | rdc | 3 | 0 | 100 | 100 | 0.00450898 | 901.797 | 0.0851797 | 0.0901797 | 901.797 | 901.797 | 901.797 | 0.0901797 | 0.0901797 | 0.0450898 | 0.00450898 | 3000 | 0 | 901.797 | 0.00450898 | 1903.59 | 3100 | 100 | 0 | 0.10018
Mur-151 | rdc | Face intérieure | Mur-151 | rdc | 3 | 0 | 100 | 100 | 0.00981441 | 1962.88 | 0.19837 | 0.194207 | 1983.7 | 1983.7 | 1942.07 | 0.19837 | 0.194207 | 0.0981441 | 0.00981441 | 3000 | 0 | 1983.7 | 0.00981441 | 4034.32 | 3100 | 100 | 0 | 0.207144
Mur-165 | rdc | Face extérieure | Mur-165 | rdc | 3 | 0 | 100 | 100 | 0.00582187 | 1164.37 | 0.118614 | 0.11426 | 1142.6 | 1186.14 | 1142.6 | 0.118614 | 0.11426 | 0.0582187 | 0.00582187 | 3000 | 0 | 1186.14 | 0.00582187 | 2445.05 | 3100 | 100 | 0 | 0.128068
Mur-149 | rdc | Face intérieure | Mur-149 | rdc | 3 | 0 | 100 | 100 | 0.00217539 | 435.079 | 0.0435079 | 0.0435079 | 435.079 | 435.079 | 435.079 | 0.0435079 | 0.0435079 | 0.0217539 | 0.00217539 | 3000 | 0 | 435.079 | 0.00217539 | 970.157 | 3100 | 100 | 0 | 0.0535079
Mur-151 | rdc | Face intérieure | Mur-151 | rdc | 3 | 0 | 100 | 100 | 0.0678307 | 13566.1 | 1.35733 | 1.35589 | 13573.3 | 13573.3 | 13558.9 | 1.35733 | 1.35589 | 0.678307 | 0.0678307 | 3000 | 0 | 13575.9 | 0.0678307 | 27235.1 | 3100 | 100 | 0 | 1.3669
Mur-154 | rdc | Face intérieure | Mur-154 | rdc | 3 | 0 | 205.783 | 205.783 | 0.0248774 | 2417.83 | 0.502693 | 0.492404 | 2442.83 | 2442.83 | 2392.82 | 0.502693 | 0.492404 | 0.120891 | 0.0248774 | 2600 | -400 | 2442.83 | 0.0248774 | 4956.36 | 2805.78 | -194.217 | -400 | 0.266623
Mur-158 | rdc | Face intérieure | Mur-158 | rdc | 3 | 0 | 100 | 100 | 0.0347438 | 7023.26 | 0.699178 | 0.705693 | 6990.68 | 6990.68 | 7055.83 | 0.699178 | 0.705693 | 0.351218 | 0.0351218 | 2400 | -600 | 6958.11 | 0.0351218 | 14146.5 | 2500 | -500 | -600 | 0.712435
Mur-157 | rdc | Face intérieure | Mur-157 | rdc | 3 | 0 | 100 | 100 | 0.0255622 | 5112.44 | 0.511244 | 0.511244 | 5112.44 | 5112.44 | 5112.43 | 0.511244 | 0.511244 | 0.255622 | 0.0255622 | 2740.07 | -259.93 | 5112.44 | 0.0255622 | 10324.9 | 2840.07 | -159.93 | -259.93 | 0.521244
Mur-162 | rdc | Face extérieure | Mur-162 | rdc | 3 | 0 | 100 | 100 | 0.0463472 | 9269.44 | 0.926944 | 0.926944 | 9269.44 | 9269.44 | 9269.44 | 0.926944 | 0.926944 | 0.463472 | 0.0463472 | 1000 | -2000 | 9269.44 | 0.0463472 | 18638.9 | 1100 | -1900 | -2000 | 0.936944
Mur-159 | rdc | Face intérieure | Mur-159 | rdc | 3 | 0 | 100 | 100 | 0.0558498 | 11170 | 1.117 | 1.117 | 11170 | 11170 | 11170 | 1.117 | 1.117 | 0.558498 | 0.0558498 | 1000 | -2000 | 11170 | 0.0558498 | 22439.9 | 1100 | -1900 | -2000 | 1.127
Mur-160 | rdc | Face intérieure | Mur-160 | rdc | 3 | 0 | 100 | 100 | 0.130539 | 26112.9 | 2.60879 | 2.61277 | 26087.9 | 26087.9 | 26137.9 | 2.60879 | 2.61277 | 1.30565 | 0.130539 | 920.44 | -2079.56 | 26137.9 | 0.130539 | 52346.5 | 1020.44 | -1979.56 | -2079.56 | 2.62294
Mur-163 | rdc | Face extérieure | Mur-163 | rdc | 3 | 0 | 100 | 100 | 0.0216234 | 4379.12 | 0.440929 | 0.435085 | 4349.9 | 4408.33 | 4349.9 | 0.440929 | 0.435085 | 0.219002 | 0.0219002 | 2400 | -600 | 4320.69 | 0.0219002 | 8858.23 | 2500 | -500 | -600 | 0.448003
Mur-164 | rdc | Face extérieure | Mur-164 | rdc | 3 | 0 | 100 | 100 | 0.0148638 | 2972.76 | 0.299535 | 0.295017 | 3000.43 | 2995.35 | 2950.17 | 0.299535 | 0.295017 | 0.148638 | 0.0148638 | 3000 | 0 | 2995.35 | 0.0148638 | 6062.88 | 3100 | 100 | 0 | 0.309013
Mur-165 | rdc | Face extérieure | Mur-165 | rdc | 3 | 0 | 100 | 100 | 0.0188303 | 3766.06 | 0.376525 | 0.376686 | 3716.6 | 3765.25 | 3766.86 | 0.376525 | 0.376686 | 0.188303 | 0.0188303 | 3000 | 0 | 3810.4 | 0.0188303 | 7665.78 | 3100 | 100 | 0 | 0.389972
Mur-161 | rdc | Face extérieure | Mur-161 | rdc | 3 | 0 | 100 | 100 | 0.0377148 | 7548.06 | 0.753778 | 0.754812 | 7548.12 | 7548 | 7548.12 | 0.753778 | 0.754812 | 0.377403 | 0.0377148 | 900 | -2100 | 7598.12 | 0.0377148 | 15237.6 | 1000 | -2000 | -2100 | 0.768533
Mur-170 | rdc | Face intérieure | Mur-170 | rdc | 3 | 0 | 100 | 100 | 0.015 | 3000 | 0.3 | 0.3 | 3000 | 3000 | 3000 | 0.3 | 0.3 | 0.15 | 0.015 | 3000 | 0 | 3000 | 0.015 | 6100 | 3100 | 100 | 0 | 0.31
Mur-170 | rdc | Face intérieure | Mur-170 | rdc | 3 | 0 | 100 | 100 | 0.0105031 | 2100.61 | 0.210061 | 0.210061 | 2100.61 | 2100.61 | 2100.61 | 0.210061 | 0.210061 | 0.105031 | 0.0105031 | 3000 | 0 | 2100.61 | 0.0105031 | 4301.23 | 3100 | 100 | 0 | 0.220061
Mur-171 | etage 4 | Face intérieure | Mur-171 | etage 4 | 7 | 0 | 1000 | 1000 | 0.066428 | 1353.79 | 1.40242 | 1.28756 | 1419.91 | 1419.91 | 1287.66 | 1.40242 | 1.28756 | 0.066428 | 0.066428 | 14600 | 0 | 1402.42 | 0.066428 | 2898.97 | 15600 | 1000 | -1.77636e-12 | 0.310311
Mur-171 | etage 4 | Face intérieure | Mur-171 | etage 4 | 7 | 0 | 1000 | 1000 | 0.0452395 | 904.79 | 0.90483 | 0.90475 | 1144.83 | 904.83 | 904.75 | 0.90483 | 0.90475 | 0.0452395 | 0.0452395 | 14600 | 0 | 904.834 | 0.0452395 | 1909.58 | 15600 | 1000 | -1.77636e-12 | 0.190479

# IfcWallStandardCase: Cloison 7 0826278243 70 (6)
Classification: Mur (Classification ARCHICAD); Material: Vide 288701167 70 mm
ArchiCADQuantities - Nombre de Portes: 0; Nombre de trous (Nombre d'ouvertures vides): 0; Nombre de Fenêtres: 0; Nombre de Poteaux: 0; Volume des poteaux: 0 m3; Hauteur maximale de la couche de Mur sur face intérieure: 2700 mm; Hauteur maximale du Mur: 2700 mm; Hauteur maximale de la couche de Mur sur face extérieure: 2700 mm; Épaisseur couche d'air: 0 mm; Superficie des portes: 0 m2; Largeur totale des Portes: 0 mm; Épaisseur de composant de mur sur face intérieure: 70 mm; Épaisseur de composant de mur sur face extérieure: 70 mm; Superficie des fenêtres: 0 m2; Largeur totale des Fenêtres: 0 mm; Superficie analytique des ouvertures sur face intérieure: 0 m2; Superficie analytique des ouvertures sur face extérieure: 0 m2; Volume analytique des ouvertures: 0 m3; Épaisseur du Mur à la fin: 70 mm; Superficie des baies libres dans le Mur: 0 m2; Hauteur: 2700 mm; Largeur: 70 mm; Altitude à étage lié/étage d'implantation: 0 mm; Décalage étage d'implantation: 0 mm; Décalage supérieur: 0 mm; Épaisseur: 70 mm; Épaisseur couche isolation: 0 mm; Altitude supérieure à étage d'implantation: 2700 mm; Altitude inférieure à étage d'implantation: 0 mm
AC_Pset_RenovationAndPhasing - Renovation Status: Existing
ArchiCADProperties - Complexité de mur: Droit; Option de géométrie: Uniforme; Emplacement de ligne de référence: Face extérieure; Surface de face intérieure: Peinture-01; Surface de face extérieure: Peinture-01; Angle d'inclinaison interne de mur: 90 deg; Angle d'inclinaison externe de mur: 90 deg; ID de l'élément: Mur-148; Lien et ID d'élément: Mur-148; Calque: 1-Projet; Matériau de construction / Composite / Profil / Hachure: Cloison 7 0826278243; Structure Composite: Cloison 7 0826278243; Verrouillé: no; Type d'élément: Mur; Étage supérieur lié absolu: Non lié; Étage supérieur lié relatif: Non lié; Étage supérieur lié: Non lié; Type de structure: Composite; ID de Parent: Mur-148; Matériaux de construction (Tous): Vide 288701167; Surfaces (Toutes): Peinture-01; Angle d'inclinaison: 90 deg; Nombre de percements: 0; Surface latérale: Peinture-01; Nom de Variante: Modèle principal; Nom de Jeu de Variantes: Modèle principal; Position: Non défini; Fonction structurelle: Non défini; Affichage sur filtre de rénovation: Tous les filtres appropriés; État de rénovation: Existant; État de Variante: Modèle principal; Jeu de Variantes: Modèle principal
Name | In | Hauteur minimale de la couche de Mur sur face intérieure (mm) = Hauteur minimale du Mur (mm) = Hauteur minimale de la couche de Mur sur face extérieure (mm) | Volume de composant de mur sur face intérieure (net) (m3) = Volume de composant de mur sur face extérieure (net) (m3) = Volume du composant face intérieure du mur (conditionnel) (m3) = Volume du composant face extérieure du mur (conditionnel) (m3) = Volume (net) (m3) = Volume (conditionnel) (m3) = Volume (brut) (m3) | Longueur moyenne du mur (mm) = Longueur du Mur au centre (mm) | Superficie de la face intérieure du mur (nette) (m2) = Superficie de la face intérieure du mur (conditionnelle) (m2) | Superficie de la face extérieure du mur (nette) (m2) = Superficie de la face extérieure du mur (conditionnelle) (m2) = Superficie en plan (m2) = Superficie inférieure (nette) (m2) | Longueur de ligne de référence (mm) | Longueur de la face intérieure du mur (conditionnelle) (mm) = Longueur de Mur sur face intérieure (mm) | Longueur de la face extérieure du mur (conditionnelle) (mm) = Longueur de Mur sur face extérieure (mm) | Superficie de la face intérieure du mur (brute) (m2) | Superficie de la face extérieure du mur (brute) (m2) | Superficie (m2) = Superficie supérieure (nette) (m2) | Altitude à Zéro du Projet (mm) = Altitude de Référence Niveau 1 (mm) = Altitude de Référence Niveau 2 (mm) = Altitude à niveau de la mer (mm) = Altitude inférieure à premier niveau de référence (mm) = Altitude inférieure à Zéro du projet (mm) = Altitude inférieure à niveau de la mer (mm) = Altitude inférieure à deuxième niveau de référence (mm) | Longueur 3D (mm) | Périmètre Plan (mm) | Altitude supérieure à premier niveau de référence (mm) = Altitude supérieure à Zéro du projet (mm) = Altitude supérieure à niveau de la mer (mm) = Altitude supérieure à deuxième niveau de référence (mm) | Superficie de l'arête (nette) (m2) | Nom de zone liée | Numéro de zone liée | Nom d'étage d'implantation | Numéro d'étage d'implantation
Mur-148 | Etage1 | 2700 | 0.293865 | 1554.84 | 4.10326 | 4.10389 | 1519.96 | 1519.72 | 1589.96 | 4.10326 | 4.29289 | 0.108839 | 5750 | 1589.96 | 3278.85 | 8450 | 0.674415 | Sde | A15 | Etage1 | 4
Mur-148 | Etage1 | 0 | 0.165835 | 1057.43 | 2.27458 | 2.46356 | 1092.43 | 1022.43 | 1092.43 | 2.27458 | 2.46356 | 0.0614203 | 5750 | 912.436 | 2283.86 | 8450 | 0.390127 | Sde | A15 | Etage1 | 4
Mur-148 | Etage1 | 2700 | 0.048404 | 256.106 | 0.597303 | 0.785668 | 290.988 | 221.223 | 290.988 | 0.597303 | 0.785668 | 0.0179274 | 5750 | 291.223 | 681.207 | 8450 | 0.492142 | Sde | A15 | Etage1 | 4
Mur-148 | Etage 2 | 2700 | 0.048404 | 256.106 | 0.597303 | 0.785668 | 360.989 | 221.223 | 290.988 | 0.597303 | 0.785668 | 0.0179274 | 8500 | 291.223 | 681.207 | 11200 | 0.492142 | Sde | A25 | Etage 2 | 5
Mur-148 | Etage 2 | 2700 | 0.287306 | 1520.14 | 3.91537 | 4.10438 | 1520.14 | 1520.14 | 1520.14 | 4.10437 | 4.10438 | 0.10641 | 8500 | 1520.38 | 3180.28 | 11200 | 0.590822 | Wc | A25 | Etage 2 | 5
Mur-148 | Etage 2 | 0 | 0.165835 | 1057.43 | 2.27458 | 2.46356 | 1092.43 | 1022.43 | 1092.43 | 2.27458 | 2.46356 | 0.0614203 | 8500 | 912.436 | 2283.86 | 11200 | 0.390127 | Sde | A25 | Etage 2 | 5

# IfcWallStandardCase: Cloison 70 0826278243 70 (896)
Classification: Mur (Classification ARCHICAD); Material: Hachure solide 268963992 70 mm
ArchiCADQuantities - Nombre de Fenêtres: 0; Nombre de Poteaux: 0; Volume des poteaux: 0 m3; Épaisseur couche d'air: 0 mm; Épaisseur de composant de mur sur face intérieure: 70 mm; Épaisseur de composant de mur sur face extérieure: 70 mm; Superficie des fenêtres: 0 m2; Largeur totale des Fenêtres: 0 mm; Épaisseur du Mur à la fin: 70 mm; Largeur: 70 mm; Altitude à étage lié/étage d'implantation: 0 mm; Décalage étage d'implantation: 0 mm; Décalage supérieur: 0 mm; Épaisseur: 70 mm; Épaisseur couche isolation: 0 mm
AC_Pset_RenovationAndPhasing - Renovation Status: Existing
ArchiCADProperties - Complexité de mur: Droit; Option de géométrie: Uniforme; Angle d'inclinaison interne de mur: 90 deg; Angle d'inclinaison externe de mur: 90 deg; Matériau de construction / Composite / Profil / Hachure: Cloison 70 0826278243; Structure Composite: Cloison 70 0826278243; Verrouillé: no; Type d'élément: Mur; Étage supérieur lié absolu: Non lié; Étage supérieur lié relatif: Non lié; Étage supérieur lié: Non lié; Type de structure: Composite; Matériaux de construction (Tous): Hachure solide 268963992; Angle d'inclinaison: 90 deg; Nombre de percements: 0; Nom de Variante: Modèle principal; Nom de Jeu de Variantes: Modèle principal; Position: Non défini; Fonction structurelle: Non défini; Affichage sur filtre de rénovation: Tous les filtres appropriés; État de rénovation: Existant; État de Variante: Modèle principal; Jeu de Variantes: Modèle principal
Name | In | Nombre de Portes | Nombre de trous (Nombre d'ouvertures vides) | Hauteur maximale de la couche de Mur sur face intérieure (mm) = Hauteur maximale du Mur (mm) = Hauteur maximale de la couche de Mur sur face extérieure (mm) | Hauteur minimale de la couche de Mur sur face intérieure (mm) = Hauteur minimale du Mur (mm) = Hauteur minimale de la couche de Mur sur face extérieure (mm) | Superficie des portes (m2) | Largeur totale des Portes (mm) | Volume de composant de mur sur face intérieure (net) (m3) = Volume de composant de mur sur face extérieure (net) (m3) | Superficie analytique des ouvertures sur face intérieure (m2) | Superficie analytique des ouvertures sur face extérieure (m2) | Longueur moyenne du mur (mm) = Longueur du Mur au centre (mm) | Superficie de la face intérieure du mur (nette) (m2) | Superficie de la face extérieure du mur (nette) (m2) = Superficie en plan (m2) = Superficie inférieure (nette) (m2) | Volume analytique des ouvertures (m3) | Longueur de ligne de référence (mm) | Longueur de la face intérieure du mur (conditionnelle) (mm) | Superficie de la face intérieure du mur (conditionnelle) (m2) | Longueur de la face extérieure du mur (conditionnelle) (mm) | Superficie de la face extérieure du mur (conditionnelle) (m2) | Volume du composant face intérieure du mur (conditionnel) (m3) = Volume du composant face extérieure du mur (conditionnel) (m3) = Volume (conditionnel) (m3) | Superficie de la face intérieure du mur (brute) (m2) | Superficie de la face extérieure du mur (brute) (m2) | Longueur de Mur sur face intérieure (mm) | Longueur de Mur sur face extérieure (mm) | Superficie des baies libres dans le Mur (m2) | Superficie (m2) = Superficie supérieure (nette) (m2) | Hauteur (mm) | Volume (net) (m3) | Altitude à Zéro du Projet (mm) = Altitude de Référence Niveau 1 (mm) = Altitude de Référence Niveau 2 (mm) = Altitude à niveau de la mer (mm) | Longueur 3D (mm) | Volume (brut) (m3) | Périmètre Plan (mm) | Altitude supérieure à premier niveau de référence (mm) = Altitude supérieure à Zéro du projet (mm) = Altitude supérieure à niveau de la mer (mm) = Altitude supérieure à deuxième niveau de référence (mm) | Altitude supérieure à étage d'implantation (mm) | Altitude inférieure à premier niveau de référence (mm) = Altitude inférieure à Zéro du projet (mm) = Altitude inférieure à niveau de la mer (mm) = Altitude inférieure à deuxième niveau de référence (mm) | Altitude inférieure à étage d'implantation (mm) | Superficie de l'arête (nette) (m2) | Emplacement de ligne de référence | Surface de face intérieure = Surface de face extérieure = Surfaces (Toutes) = Surface latérale | ID de l'élément = Lien et ID d'élément = ID de Parent | Calque | Nom de zone liée | Numéro de zone liée | Nom d'étage d'implantation | Numéro d'étage d'implantation
Mur-149 | rdc | 0 | 0 | 2700 | 2300 | 0 | 0 | 0.169603 | 0 | 0 | 969.163 | 2.33541 | 2.51041 | 0 | 934.163 | 934.163 | 2.33541 | 1004.16 | 2.51041 | 0.169603 | 2.52224 | 2.71124 | 934.163 | 1004.16 | 0 | 0.0678414 | 2700 | 0.169603 | 3000 | 1004.16 | 0.183172 | 2107.32 | 5700 | 2700 | 3000 | 0 | 0.55817 | Face intérieure | Peinture-01 | Mur-149 | 1-Projet | Sejour cuisine | B05 | rdc | 3
Mur-149 | rdc | 0 | 0 | 2700 | 2700 | 0 | 0 | 0.303029 | 0 | 0 | 1590 | 4.32899 | 4.13999 | 0 | 1840 | 1590 | 4.32899 | 1590 | 4.13999 | 0.303029 | 4.32899 | 4.32899 | 1590 | 1590 | 0 | 0.1239 | 2700 | 0.303029 | 3000 | 1770 | 0.303029 | 3319.99 | 5700 | 2700 | 3000 | 0 | 0.6258 | Face intérieure | Peinture-01 | Mur-149 | 1-Projet | Wc | B03 | rdc | 3
Mur-148 | rdc | 0 | 0 | 2700 | 2700 | 0 | 0 | 0.156863 | 0 | 0 | 830.003 | 2.241 | 2.24102 | 0 | 900 | 830 | 2.241 | 830.006 | 2.24102 | 0.156863 | 2.241 | 2.24102 | 830 | 830.006 | 0 | 0.0580975 | 2700 | 0.156863 | 3000 | 830.006 | 0.156863 | 1800.01 | 5700 | 2700 | 3000 | 0 | 0.494178 | Face intérieure | Peinture-01 | Mur-148 | 1-Projet | Sdb/pl | A02 | rdc | 3 | ArchiCADProperties - Zones conflictuelles: Sdb/pl
Mur-149 | rdc | 0 | 0 | 2700 | 2700 | 0 | 0 | 0.431738 | 0 | 0 | 2284.33 | 6.15856 | 5.9878 | 0 | 2280.59 | 2350.95 | 6.15856 | 2217.7 | 5.9878 | 0.431738 | 6.34756 | 5.9878 | 2350.95 | 2217.7 | 0 | 0.159903 | 2700 | 0.431738 | 3000 | 2350.95 | 0.431738 | 4761.98 | 5700 | 2700 | 3000 | 0 | 0.841804 | Face intérieure | Peinture-01 | Mur-149 | 1-Projet | Ch 2 | A02 | rdc | 3
Mur-149 | rdc | 0 | 0 | 2700 | 2700 | 0 | 0 | 0.749575 | 0 | 0 | 3966.01 | 10.7082 | 10.7082 | 0 | 4306.01 | 3966.01 | 10.7082 | 3966.01 | 10.7082 | 0.749575 | 10.7082 | 10.7082 | 3966.01 | 3966.01 | 0 | 0.277621 | 2700 | 0.749575 | 3000 | 3966.01 | 0.749575 | 8072.02 | 5700 | 2700 | 3000 | 0 | 0.933241 | Face intérieure | Peinture-01 | Mur-149 | 1-Projet | Ch 2 | B05 | rdc | 3
Mur-121 | rdc | 0 | 0 | 3000 | 3000 | 0 | 0 | 0.24462 | 0 | 0 | 1164.86 | 3.28457 | 3.28457 | 0 | 1164.86 | 1164.86 | 3.28457 | 1164.86 | 3.28457 | 0.24462 | 3.49457 | 3.49457 | 1164.86 | 1164.86 | 0 | 0.0815401 | 3000 | 0.24462 | 3000 | 1164.86 | 0.24462 | 2469.72 | 6000 | 3000 | 3000 | 0 | 0.58308 | Face extérieure | Lavis blanc | Mur-121 | 1-Projet | Sejour cuisine | A03 | rdc | 3 | ArchiCADProperties - Zones conflictuelles: Ch 1; Ch 1; Sejour cuisine; Sejour cuisine
Mur-149 | rdc | 1 | 0 | 2700 | 2700 | 1.1832 | 580 | 0.031842 | 1.1366 | 1.1366 | 589.44 | 0.549386 | 0.360386 | 0.0795621 | 624.44 | 70 | 1.68599 | 0 | 1.49699 | 0.111404 | 1.68599 | 1.49699 | 624.44 | 554.44 | 0 | 0.00245 | 2700 | 0.031842 | 3000 | 624.44 | 0.111404 | 1347.87 | 5700 | 2700 | 3000 | 0 | 0.356497 | Face intérieure | Peinture-01 | Mur-149 | 1-Projet | Sejour cuisine/pl | B04 | rdc | 3
Mur-149 | rdc | 1 | 0 | 3000 | 3000 | 1.6932 | 830 | 0.374722 | 1.8928 | 1.8928 | 2411.82 | 5.44767 | 5.04867 | 0.132496 | 2516.82 | 1536.82 | 7.34047 | 1466.82 | 6.94147 | 0.507218 | 7.34047 | 7.15147 | 2446.82 | 2376.82 | 0 | 0.107578 | 3000 | 0.374722 | 3000 | 2446.82 | 0.507218 | 4992.64 | 6000 | 3000 | 3000 | -4.44089e-13 | 0.777142 | Face intérieure | Surface-Blanche | Mur-149 | 1-Projet | Entree/pl | B01 | rdc | 3
Mur-150 | rdc | 0 | 0 | 3000 | 3000 | 0 | 0 | 0.0919155 | 0 | 0 | 437.693 | 1.418 | 1.20816 | 0 | 472.666 | 472.666 | 1.418 | 402.719 | 1.20816 | 0.0919155 | 1.418 | 1.20816 | 472.666 | 402.719 | 0 | 0.0306385 | 3000 | 0.0919155 | 3000 | 472.666 | 0.0919155 | 1044.34 | 6000 | 3000 | 3000 | 0 | 0.568149 | Face intérieure | Surface-Blanche | Mur-150 | 1-Projet |  |  | rdc | 3
Mur-149 | rdc | 0 | 1 | 2700 | 0 | 0 | 0 | 0.45531 | 1.91776 | 1.91776 | 3189.33 | 6.50445 | 6.3154 | 0.134243 | 3469.34 | 2249.26 | 8.42221 | 2249.25 | 8.23316 | 0.589553 | 8.42221 | 8.42216 | 3189.34 | 3189.33 | 1.91776 | 0.152548 | 2700 | 0.45531 | 3000 | 3119.34 | 0.589553 | 6518.66 | 5700 | 2700 | 3000 | 0 | 0.606101 | Face intérieure | Peinture-01 | Mur-149 | 1-Projet | Cellier | A02 | rdc | 3
Mur-149 | rdc | 1 | 0 | 2700 | 2700 | 2.02618 | 1013.09 | 0.121189 | 1.9765 | 1.9765 | 1373.25 | 1.44778 | 1.82578 | 0.138355 | 1408.25 | 350 | 3.42428 | 420 | 3.80228 | 0.259545 | 3.61328 | 3.80228 | 1338.25 | 1408.25 | 0 | 0.02695 | 2700 | 0.121189 | 3000 | 1408.25 | 0.259545 | 2915.5 | 5700 | 2700 | 3000 | 0 | 0.439364 | Face intérieure | Peinture-01 | Mur-149 | 1-Projet | Entree/pl | A02 | rdc | 3
Mur-149 | rdc | 0 | 0 | 2700 | 2700 | 0 | 0 | 0.116235 | 0 | 0 | 615 | 1.755 | 1.566 | 0 | 650 | 650 | 1.755 | 580 | 1.566 | 0.116235 | 1.755 | 1.566 | 650 | 580 | 0 | 0.04305 | 2700 | 0.116235 | 3000 | 650 | 0.116235 | 1398.99 | 5700 | 2700 | 3000 | 0 | 0.542386 | Face intérieure | Peinture-01 | Mur-149 | 1-Projet | Sdb | A01 | rdc | 3
Mur-149 | rdc | 0 | 0 | 2700 | 2700 | 0 | 0 | 0.134461 | 0 | 0 | 711.435 | 2.01538 | 1.82637 | 0 | 816.44 | 746.436 | 2.01538 | 676.435 | 1.82637 | 0.134461 | 2.01538 | 1.82637 | 746.436 | 676.435 | 0 | 0.0498005 | 2700 | 0.134461 | 3000 | 746.436 | 0.134461 | 1591.86 | 5700 | 2700 | 3000 | 0 | 0.555867 | Face intérieure | Peinture-01 | Mur-149 | 1-Projet | Sdb | A01 | rdc | 3
Mur-149 | rdc | 0 | 0 | 2700 | 2700 | 0 | 0 | 0.168024 | 0 | 0 | 889.015 | 2.44083 | 2.30585 | 0 | 924.009 | 924.009 | 2.44083 | 854.02 | 2.30585 | 0.168024 | 2.49483 | 2.30585 | 924.009 | 854.02 | 0 | 0.062231 | 2700 | 0.168024 | 3000 | 924.009 | 0.168024 | 1947.02 | 5700 | 2700 | 3000 | 0 | 0.580728 | Face intérieure | Peinture-01 | Mur-149 | 1-Projet | Sdb | A01 | rdc | 3
Mur-149 | rdc | 0 | 0 | 2700 | 2700 | 0 | 0 | 0.568041 | 0 | 0 | 3005.51 | 8.0295 | 8.20025 | 0 | 3044.25 | 2973.89 | 8.0295 | 3037.13 | 8.20025 | 0.568041 | 8.0295 | 8.20025 | 2973.89 | 3037.13 | 0 | 0.210386 | 2700 | 0.568041 | 3000 | 3037.13 | 0.568041 | 6175.36 | 5700 | 2700 | 3000 | 0 | 0.864483 | Face intérieure | Peinture-01 | Mur-149 | 1-Projet | Ch 2 | A02 | rdc | 3
Mur-149 | rdc | 2 | 0 | 2700 | 2700 | 2.8764 | 1410 | 0.252964 | 3.1228 | 3.1228 | 2495.03 | 2.95227 | 2.57427 | 0.218596 | 2460.03 | 1020.03 | 6.07507 | 950.026 | 5.69707 | 0.47156 | 6.83107 | 6.64207 | 2530.03 | 2460.03 | 0 | 0.0689518 | 2700 | 0.252964 | 3000 | 2530.03 | 0.47156 | 5159.05 | 5700 | 2700 | 3000 | 0 | 0.69989 | Face intérieure | Peinture-01 | Mur-149 | 1-Projet | Wc | A02 | rdc | 3
Mur-149 | rdc | 1 | 0 | 2700 | 2700 | 3.03993 | 1519.97 | 0.0735127 | 2.95993 | 2.95993 | 1485.23 | 1.05018 | 1.05018 | 0.207195 | 1485.23 | 5.26069 | 1.05018 | 5.26068 | 1.05018 | 0.280708 | 4.01012 | 4.01012 | 1485.23 | 1485.23 | 0 | 0.000368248 | 2700 | 0.0735127 | 3000 | 1485.23 | 0.280708 | 3110.46 | 5700 | 2700 | 3000 | 0 | 0.342334 | Face intérieure | Peinture-01 | Mur-149 | 1-Projet | Ch 2/pl | B03 | rdc | 3
Mur-149 | rdc | 1 | 0 | 2700 | 2700 | 1.6932 | 830 | 0.167131 | 1.8928 | 1.8928 | 1585.33 | 2.29309 | 2.29309 | 0.132496 | 1620.33 | 710.33 | 4.18589 | 640.33 | 4.18589 | 0.299627 | 4.37489 | 4.18589 | 1620.33 | 1550.33 | 0 | 0.0472731 | 2700 | 0.167131 | 3000 | 1620.33 | 0.299627 | 3339.65 | 5700 | 2700 | 3000 | 0 | 0.614533 | Face intérieure | Peinture-01 | Mur-149 | 1-Projet | Ch 2 | A02 | rdc | 3
Mur-149 | rdc | 1 | 0 | 2700 | 2700 | 1.6932 | 830 | 0.344584 | 1.8928 | 1.8928 | 2524.23 | 4.63913 | 4.63913 | 0.132496 | 2629.23 | 1579.23 | 6.53193 | 1649.23 | 6.53193 | 0.47708 | 6.72093 | 6.90993 | 2489.23 | 2559.23 | 0 | 0.112996 | 2700 | 0.344584 | 3000 | 2559.23 | 0.47708 | 5217.46 | 5700 | 2700 | 3000 | 0 | 0.745979 | Face intérieure | Peinture-01 | Mur-149 | 1-Projet | Cellier | A02 | rdc | 3
Mur-149 | rdc | 0 | 0 | 2700 | 2700 | 0 | 0 | 0.310905 | 0 | 0 | 1645 | 4.536 | 4.158 | 0 | 1610 | 1680 | 4.536 | 1610 | 4.158 | 0.310905 | 4.536 | 4.347 | 1680 | 1610 | 0 | 0.11515 | 2700 | 0.310905 | 3000 | 1680 | 0.310905 | 3458.99 | 5700 | 2700 | 3000 | 0 | 0.686586 | Face intérieure | Peinture-01 | Mur-149 | 1-Projet | Cellier | A02 | rdc | 3
Mur-149 | rdc | 0 | 0 | 2700 | 2700 | 0 | 0 | 0.199611 | 0 | 0 | 1056.14 | 2.85159 | 2.85159 | 0 | 1196.14 | 1056.14 | 2.85159 | 1056.14 | 2.85159 | 0.199611 | 2.85159 | 2.85159 | 1056.14 | 1056.14 | 0 | 0.07393 | 2700 | 0.199611 | 3000 | 1056.14 | 0.199611 | 2252.29 | 5700 | 2700 | 3000 | 0 | 0.52586 | Face intérieure | Peinture-01 | Mur-149 | 1-Projet | Cellier | A02 | rdc | 3
Mur-149 | rdc | 1 | 0 | 2700 | 2700 | 1.6932 | 830 | 0.500276 | 1.8928 | 1.8928 | 3348 | 7.0523 | 7.0523 | 0.132496 | 3313 | 2403 | 8.9451 | 2473 | 8.9451 | 0.632772 | 8.9451 | 9.1341 | 3313 | 3383 | 0 | 0.17066 | 2700 | 0.500276 | 3000 | 3383 | 0.632772 | 6865 | 5700 | 2700 | 3000 | 0 | 0.861306 | Face intérieure | Peinture-01 | Mur-149 | 1-Projet | Sdb/pl | A02 | rdc | 3
Mur-149 | rdc | 0 | 0 | 2700 | 2700 | 0 | 0 | 0.613441 | 0 | 0 | 3245.72 | 8.77306 | 8.75384 | 0 | 3591.03 | 3249.28 | 8.77306 | 3242.16 | 8.75384 | 0.613441 | 8.77306 | 8.75384 | 3249.28 | 3242.16 | 0 | 0.227201 | 2700 | 0.613441 | 3000 | 3249.28 | 0.613441 | 6631.8 | 5700 | 2700 | 3000 | 0 | 0.833376 | Face intérieure | Peinture-01 | Mur-149 | 1-Projet | Ch 2 | A02 | rdc | 3
Mur-149 | rdc | 0 | 0 | 3000 | 3000 | 0 | 0 | 0.072904 | 0 | 0 | 347.162 | 1.14649 | 0.936479 | 0 | 382.164 | 382.164 | 1.14649 | 312.16 | 0.936479 | 0.072904 | 1.14649 | 0.936479 | 382.164 | 312.16 | 0 | 0.0243013 | 3000 | 0.072904 | 3000 | 382.164 | 0.072904 | 863.322 | 6000 | 3000 | 3000 | 0 | 0.555597 | Face intérieure | Surface-Blanche | Mur-149 | 1-Projet | Sdb | A03 | rdc | 3
Mur-149 | rdc | 1 | 1 | 2700 | 2700 | 2.01361 | 1006.8 | 0.350344 | 3.91647 | 3.91647 | 3304.22 | 5.09943 | 4.34341 | 0.274153 | 3339.22 | 1399.64 | 7.00228 | 1329.63 | 6.24626 | 0.624497 | 9.01589 | 8.82687 | 3339.22 | 3269.21 | 1.90286 | 0.0955246 | 2700 | 0.350344 | 3000 | 3339.22 | 0.624497 | 6777.43 | 5700 | 2700 | 3000 | 0 | 0.640321 | Face intérieure | Peinture-01 | Mur-149 | 1-Projet | Entree | A01 | rdc | 3 | ArchiCADProperties - Zones conflictuelles: Sejour cuisine/pl
Mur-149 | rdc | 1 | 0 | 2700 | 2700 | 1.1832 | 580 | 0.0459056 | 1.23 | 1.23 | 685.108 | 0.750304 | 0.561285 | 0.0861 | 900.117 | 120.112 | 1.9803 | 50.1047 | 1.79129 | 0.132006 | 1.9803 | 1.79129 | 720.112 | 650.105 | 0 | 0.0185582 | 2700 | 0.0459056 | 3000 | 900.117 | 0.132006 | 1539.21 | 5700 | 2700 | 3000 | 0 | 0.535403 | Face intérieure | Peinture-01 | Mur-149 | 1-Projet | Entree/pl | B05 | rdc | 3
Mur-149 | rdc | 1 | 0 | 2700 | 2700 | 1.6932 | 830 | 0.104699 | 1.8928 | 1.8928 | 1255 | 1.4012 | 1.5902 | 0.132496 | 1220 | 310 | 3.294 | 380 | 3.483 | 0.237195 | 3.294 | 3.483 | 1220 | 1290 | 0 | 0.02415 | 2700 | 0.104699 | 3000 | 1290 | 0.237195 | 2678.99 | 5700 | 2700 | 3000 | 0 | 0.422686 | Face intérieure | Peinture-01 | Mur-149 | 1-Projet | Ch 1 | A02 | rdc | 3
Mur-149 | rdc | 0 | 0 | 2700 | 2700 | 0 | 0 | 0.428363 | 0 | 0 | 2266.47 | 6.11948 | 6.11947 | 0 | 2336.48 | 2266.48 | 6.11948 | 2266.47 | 6.11947 | 0.428363 | 6.11948 | 6.11947 | 2266.48 | 2266.47 | 0 | 0.158653 | 2700 | 0.428363 | 3000 | 2266.49 | 0.428363 | 4672.95 | 5700 | 2700 | 3000 | -4.44089e-13 | 0.695306 | Face intérieure | Peinture-01 | Mur-149 | 1-Projet | Sdb/pl | A02 | rdc | 3
Mur-149 | rdc | 1 | 0 | 2700 | 2700 | 1.1832 | 580 | 0.0397213 | 1.23 | 1.23 | 665.721 | 0.472938 | 0.661955 | 0.0861 | 700.718 | 30.7179 | 1.70294 | 100.724 | 1.89195 | 0.125821 | 1.70294 | 1.89195 | 630.718 | 700.724 | 0 | 0.00460047 | 2700 | 0.0397213 | 3000 | 700.724 | 0.125821 | 1500.44 | 5700 | 2700 | 3000 | 0 | 0.507485 | Face intérieure | Peinture-01 | Mur-149 | 1-Projet | Entree | A01 | rdc | 3 | ArchiCADProperties - Zones conflictuelles: Entree
Mur-149 | rdc | 1 | 0 | 2700 | 2700 | 1.6932 | 830 | 0.349769 | 1.8928 | 1.8928 | 2538.33 | 4.9967 | 4.8077 | 0.132496 | 2788.33 | 2538.33 | 6.8895 | 2538.33 | 6.7005 | 0.482265 | 6.8895 | 6.8895 | 2538.33 | 2538.33 | 0 | 0.190283 | 2700 | 0.349769 | 3000 | 2718.33 | 0.482265 | 5216.66 | 5700 | 2700 | 3000 | 0 | 0.758566 | Face intérieure | Peinture-01 | Mur-149 | 1-Projet | Entree/pl | B05 | rdc | 3
Mur-149 | rdc | 0 | 0 | 2500 | 2500 | 0 | 0 | 0.148292 | 0 | 0 | 847.385 | 2.20596 | 2.03096 | 0 | 882.385 | 882.385 | 2.20596 | 812.385 | 2.03096 | 0.148292 | 2.20596 | 2.03096 | 882.385 | 812.385 | 0 | 0.059317 | 2500 | 0.148292 | 3000 | 882.385 | 0.148292 | 1863.77 | 5500 | 2500 | 3000 | 0 | 0.541121 | Face intérieure | Surface-Blanche | Mur-149 | 1-Projet | Sde | B04 | rdc | 3
Mur-153 | rdc | 0 | 0 | 2700 | 2700 | 0 | 0 | 0.133245 | 0 | 0 | 705 | 1.809 | 1.998 | 0 | 740 | 670 | 1.809 | 740 | 1.998 | 0.133245 | 1.809 | 1.998 | 670 | 740 | 0 | 0.04935 | 2700 | 0.133245 | 3000 | 740 | 0.133245 | 1578.99 | 5700 | 2700 | 3000 | 0 | 0.554986 | Face extérieure | Peinture-01 | Mur-153 | 1-Projet | Ch 2/pl | A04 | rdc | 3 | ArchiCADProperties - Zones conflictuelles: Ch 2/pl
Mur-149 | rdc | 1 | 0 | 2700 | 2700 | 1.1832 | 580 | 0.0330825 | 1.189 | 1.189 | 615.41 | 0.567107 | 0.378107 | 0.08323 | 650.41 | 70.4101 | 1.75611 | 0.410108 | 1.56711 | 0.116313 | 1.75611 | 1.56711 | 650.41 | 580.41 | 0 | 0.00247871 | 2700 | 0.0330825 | 3000 | 650.41 | 0.116313 | 1399.82 | 5700 | 2700 | 3000 | 0 | 0.358344 | Face intérieure | Peinture-01 | Mur-149 | 1-Projet | Sejour cuisine | B03 | rdc | 3 | ArchiCADProperties - Zones conflictuelles: Sejour cuisine
Mur-149 | rdc | 0 | 0 | 2300 | 2300 | 0 | 0 | 0.702476 | 0 | 0 | 4363.2 | 9.86032 | 10.0354 | 0 | 4703.18 | 4363.18 | 9.86032 | 4363.23 | 10.0354 | 0.702476 | 10.908 | 10.9081 | 4363.18 | 4363.23 | 0 | 0.305424 | 2500 | 0.702476 | 3000 | 4363.23 | 0.763561 | 8866.41 | 5300 | 2300 | 3000 | 0 | 0.627424 | Face intérieure | Peinture-01 | Mur-149 | 1-Projet | Ch 2 | B04 | rdc | 3
2 x Mur-121 | rdc | 0 | 0 | 3000 | 3000 | 0 | 0 | 0.0903109 | 0 | 0 | 400.052 | 1.11516 | 1.11516 | 0 | 580.052 | 400.052 | 1.11516 | 400.052 | 1.11516 | 0.0903109 | 1.29016 | 1.29016 | 400.052 | 400.052 | 0 | 0.0406037 | 3000 | 0.0903109 | 3000 | 580.052 | 0.0903109 | 940.104 | 6000 | 3000 | 3000 | 0 | 0.501207 | Face extérieure | Lavis blanc | Mur-121 | 1-Projet |  |  | rdc | 3
Mur-149 | rdc | 1 | 0 | 2700 | 2700 | 1.6932 | 830 | 0.490414 | 1.8928 | 1.8928 | 3295.82 | 7.00592 | 6.81692 | 0.132496 | 3545.82 | 2385.82 | 8.89872 | 2385.82 | 8.70972 | 0.62291 | 8.89872 | 8.89872 | 3295.82 | 3295.82 | 0 | 0.167008 | 2700 | 0.490414 | 3000 | 3295.82 | 0.62291 | 6731.64 | 5700 | 2700 | 3000 | 0 | 0.775715 | Face intérieure | Peinture-01 | Mur-149 | 1-Projet | Entree | A01 | rdc | 3
Mur-153 | rdc | 1 | 0 | 3000 | 0 | 1.6932 | 830 | 0.408336 | 1.8928 | 1.8928 | 2655.13 | 5.62336 | 5.83337 | 0.132496 | 2655.13 | 1745.13 | 7.51616 | 1745.13 | 7.72617 | 0.540832 | 7.7554 | 7.7554 | 2655.13 | 2655.13 | 0 | 0.117259 | 3000 | 0.408336 | 3000 | 2585.14 | 0.542878 | 5450.27 | 6000 | 3000 | 3000 | 0 | 0.704219 | Face extérieure | Peinture-01 | Mur-153 | 1-Projet | Sejour cuisine | A03 | rdc | 3
Mur-149 | rdc | 0 | 0 | 2700 | 0 | 0 | 0 | 0.616295 | 0 | 0 | 3330.82 | 8.89872 | 8.52072 | 0 | 3545.82 | 3365.82 | 8.89872 | 3295.82 | 8.52072 | 0.616295 | 8.89872 | 8.70972 | 3365.82 | 3295.82 | 0 | 0.228258 | 2700 | 0.616295 | 3000 | 3295.84 | 0.616295 | 6830.64 | 5700 | 2700 | 3000 | 0 | 0.912816 | Face intérieure | Peinture-01 | Mur-149 | 1-Projet | Sdb | A01 | rdc | 3
Mur-149 | rdc | 0 | 1 | 3000 | 3000 | 0 | 0 | 0.889273 | 2.24284 | 2.24284 | 4982.25 | 12.7039 | 12.2839 | 0.156999 | 4982.25 | 3882.81 | 12.7039 | 3882.81 | 12.2839 | 1.04627 | 14.9467 | 14.9467 | 4982.25 | 4982.25 | 2.24284 | 0.271797 | 3000 | 0.889273 | 3000 | 4982.25 | 1.04627 | 10104.5 | 6000 | 3000 | 3000 | 0 | 1.04055 | Face intérieure | Surface-Blanche | Mur-149 | 1-Projet | Sejour Cuisine | B01 | rdc | 3
Mur-149 | rdc | 0 | 0 | 2700 | 2700 | 0 | 0 | 0.137089 | 0 | 0 | 725.338 | 2.05291 | 1.86391 | 0 | 1040.34 | 760.338 | 2.05291 | 690.338 | 1.86391 | 0.137089 | 2.05291 | 1.86391 | 760.338 | 690.338 | 0 | 0.0507737 | 2700 | 0.137089 | 3000 | 760.338 | 0.137089 | 1619.67 | 5700 | 2700 | 3000 | 0 | 0.557834 | Face intérieure | Peinture-01 | Mur-149 | 1-Projet | Sejour cuisine/pl | A01 | rdc | 3
Mur-149 | rdc | 2 | 0 | 2512.25 | 2512.25 | 3.3864 | 1660 | 0.467056 | 3.7856 | 3.7856 | 4162.76 | 6.14466 | 6.49637 | 0.264992 | 4162.76 | 2342.76 | 9.93026 | 2342.76 | 10.282 | 0.732048 | 10.4578 | 10.4578 | 4162.76 | 4162.76 | 0 | 0.163993 | 2512.25 | 0.467056 | 3000 | 4162.76 | 0.732048 | 8465.52 | 5512.25 | 2512.25 | 3000 | 0 | 0.807101 | Face intérieure | Surface-Blanche | Mur-149 | 1-Projet | Ch 2 | B02 | rdc | 3
Mur-153 | rdc | 0 | 0 | 3000 | 3000 | 0 | 0 | 0.0635883 | 0 | 0 | 284.801 | 1.01338 | 0.803433 | 0 | 429.811 | 319.79 | 1.01338 | 249.811 | 0.803433 | 0.0635883 | 1.01338 | 0.803433 | 319.79 | 249.811 | 0 | 0.0325368 | 3000 | 0.0635883 | 3000 | 499.811 | 0.0635883 | 738.596 | 6000 | 3000 | 3000 | 0 | 0.572058 | Face extérieure | Peinture-01 | Mur-153 | 1-Projet | Sejour cuisine | A03 | rdc | 3 | ArchiCADProperties - Zones conflictuelles: Sejour Cuisine/pl
Mur-121 | rdc | 0 | 0 | 3000 | 0 | 0 | 0 | 0.0691482 | 0 | 0 | 399.277 | 0.987831 | 0.987831 | 0 | 399.277 | 399.277 | 0.987831 | 399.277 | 0.987831 | 0.0691482 | 0.987831 | 0.987831 | 399.277 | 399.277 | 0 | 0.0230494 | 3000 | 0.0691482 | 3000 | 329.277 | 0.0691482 | 938.554 | 6000 | 3000 | 3000 | 0 | 0.466099 | Face extérieure | Lavis blanc | Mur-121 | 1-Projet |  |  | rdc | 3
Mur-149 | rdc | 0 | 0 | 2700 | 2700 | 0 | 0 | 0.0538515 | 0 | 0 | 284.929 | 0.674817 | 0.863797 | 0 | 319.932 | 249.932 | 0.674817 | 319.925 | 0.863797 | 0.0538515 | 0.674817 | 0.863797 | 249.932 | 319.925 | 0 | 0.019945 | 2700 | 0.0538515 | 3000 | 319.931 | 0.0538515 | 738.851 | 5700 | 2700 | 3000 | 0 | 0.496174 | Face intérieure | Peinture-01 | Mur-149 | 1-Projet | Entree | A01 | rdc | 3
Mur-149 | rdc | 1 | 0 | 2700 | 2700 | 1.6932 | 830 | 0.174913 | 1.8928 | 1.8928 | 1626.5 | 2.40426 | 2.21526 | 0.132496 | 1661.5 | 681.504 | 4.29706 | 751.504 | 4.10806 | 0.307409 | 4.29706 | 4.48606 | 1591.5 | 1661.5 | 0 | 0.0501553 | 2700 | 0.174913 | 3000 | 1661.5 | 0.307409 | 3422 | 5700 | 2700 | 3000 | 0 | 0.620297 | Face intérieure | Peinture-01 | Mur-149 | 1-Projet | Sdb | B03 | rdc | 3
Mur-149 | rdc | 0 | 0 | 2700 | 2700 | 0 | 0 | 0.109258 | 0 | 0 | 578.084 | 1.65533 | 1.46633 | 0 | 613.084 | 613.084 | 1.65533 | 543.084 | 1.46633 | 0.109258 | 1.65533 | 1.46633 | 613.084 | 543.084 | 0 | 0.0404658 | 2700 | 0.109258 | 3000 | 613.084 | 0.109258 | 1325.16 | 5700 | 2700 | 3000 | 0 | 0.537218 | Face intérieure | Peinture-01 | Mur-149 | 1-Projet | Sejour Cuisine/pl | A04 | rdc | 3
Mur-149 | rdc | 2 | 0 | 2700 | 2300 | 3.3864 | 1660 | 0.820912 | 3.7856 | 3.7856 | 5748.12 | 11.4508 | 11.4508 | 0.264992 | 5713.12 | 3893.12 | 15.2364 | 3963.12 | 15.2364 | 1.0859 | 15.4254 | 15.6144 | 5713.12 | 5783.12 | 0 | 0.274968 | 2700 | 0.820912 | 3000 | 5783.12 | 1.08639 | 11665.2 | 5700 | 2700 | 3000 | 0 | 1.11382 | Face intérieure | Peinture-01 | Mur-149 | 1-Projet | Sejour cuisine | B05 | rdc | 3
Mur-149 | rdc | 0 | 0 | 2700 | 2700 | 0 | 0 | 0.303245 | 0 | 0 | 1604.47 | 4.33207 | 4.14307 | 0 | 1604.47 | 1604.48 | 4.33207 | 1604.47 | 4.14307 | 0.303245 | 4.33207 | 4.33207 | 1604.48 | 1604.47 | 0 | 0.112313 | 2700 | 0.303245 | 3000 | 1604.47 | 0.303245 | 3348.95 | 5700 | 2700 | 3000 | 0 | 0.602626 | Face intérieure | Peinture-01 | Mur-149 | 1-Projet | Entree/pl | B04 | rdc | 3
Mur-149 | rdc | 0 | 0 | 3000 | 3000 | 0 | 0 | 0.457933 | 0 | 0 | 2150.61 | 6.5419 | 6.5419 | 0 | 2400.61 | 2150.61 | 6.5419 | 2150.61 | 6.5419 | 0.457933 | 6.5419 | 6.5419 | 2150.61 | 2150.61 | 0 | 0.163143 | 3000 | 0.457933 | 3000 | 2330.61 | 0.457933 | 4441.22 | 6000 | 3000 | 3000 | -4.44089e-13 | 0.746286 | Face intérieure | Surface-Blanche | Mur-149 | 1-Projet | Ch 1 | B01 | rdc | 3 | ArchiCADProperties - Zones conflictuelles: Sde
Mur-149 | rdc | 0 | 0 | 3000 | 3000 | 0 | 0 | 0.0588067 | 0 | 0 | 280.032 | 0.945096 | 0.735096 | 0 | 385.032 | 315.032 | 0.945096 | 245.032 | 0.735096 | 0.0588067 | 0.945096 | 0.735096 | 315.032 | 245.032 | 0 | 0.0196022 | 3000 | 0.0588067 | 3000 | 315.032 | 0.0588067 | 729.059 | 6000 | 3000 | 3000 | 0 | 0.546189 | Face intérieure | Surface-Blanche | Mur-149 | 1-Projet | Sdb | B01 | rdc | 3
Mur-149 | rdc | 0 | 0 | 2700 | 2700 | 0 | 0 | 0.106849 | 0 | 0 | 565.338 | 1.62091 | 1.43191 | 0 | 940.338 | 600.338 | 1.62091 | 530.338 | 1.43191 | 0.106849 | 1.62091 | 1.43191 | 600.338 | 530.338 | 0 | 0.0395736 | 2700 | 0.106849 | 3000 | 600.338 | 0.106849 | 1299.67 | 5700 | 2700 | 3000 | 0 | 0.535434 | Face intérieure | Peinture-01 | Mur-149 | 1-Projet | Sejour cuisine/pl | A01 | rdc | 3
Mur-149 | rdc | 0 | 0 | 2700 | 2700 | 0 | 0 | 0.121905 | 0 | 0 | 645 | 1.836 | 1.458 | 0 | 680 | 680 | 1.836 | 610 | 1.458 | 0.121905 | 1.836 | 1.647 | 680 | 610 | 0 | 0.04515 | 2700 | 0.121905 | 3000 | 680 | 0.121905 | 1458.99 | 5700 | 2700 | 3000 | 0 | 0.546586 | Face intérieure | Peinture-01 | Mur-149 | 1-Projet | Sejour cuisine/pl | B04 | rdc | 3
Mur-149 | rdc | 0 | 0 | 3000 | 3000 | 0 | 0 | 0.187948 | 0 | 0 | 864.993 | 2.78998 | 2.57997 | 0 | 1080 | 899.993 | 2.78998 | 829.994 | 2.57997 | 0.187948 | 2.78998 | 2.57997 | 899.993 | 829.994 | 0 | 0.0731488 | 3000 | 0.187948 | 3000 | 1080 | 0.187948 | 1899 | 6000 | 3000 | 3000 | 0 | 0.653352 | Face intérieure | Surface-Blanche | Mur-149 | 1-Projet | Sdb | B02 | rdc | 3 | ArchiCADProperties - Zones conflictuelles: Sdb; Sde
Mur-149 | rdc | 0 | 0 | 2700 | 2700 | 0 | 0 | 0.789664 | 0 | 0 | 4178.12 | 11.2809 | 11.2809 | 0 | 4518.12 | 4178.12 | 11.2809 | 4178.12 | 11.2809 | 0.789664 | 11.2809 | 11.2809 | 4178.12 | 4178.12 | 0 | 0.292468 | 2700 | 0.789664 | 3000 | 4178.12 | 0.789664 | 8496.24 | 5700 | 2700 | 3000 | 0 | 0.962936 | Face intérieure | Peinture-01 | Mur-149 | 1-Projet | Ch 1 | B03 | rdc | 3
Mur-149 | rdc | 0 | 0 | 2700 | 2700 | 0 | 0 | 0.12663 | 0 | 0 | 670 | 1.809 | 1.809 | 0 | 670 | 670 | 1.809 | 670 | 1.809 | 0.12663 | 1.809 | 1.809 | 670 | 670 | 0 | 0.0469 | 2700 | 0.12663 | 3000 | 670 | 0.12663 | 1480 | 5700 | 2700 | 3000 | 0 | 0.4718 | Face intérieure | Peinture-01 | Mur-149 | 1-Projet | Ch 2/pl | B03 | rdc | 3
Mur-149 | rdc | 1 | 0 | 2700 | 2700 | 1.6932 | 830 | 0.111349 | 1.8928 | 1.8928 | 1285 | 1.6852 | 1.4962 | 0.132496 | 1320 | 410 | 3.578 | 340 | 3.389 | 0.243845 | 3.578 | 3.389 | 1320 | 1250 | 0 | 0.03115 | 2700 | 0.111349 | 3000 | 1390 | 0.243845 | 2738.99 | 5700 | 2700 | 3000 | 0 | 0.582286 | Face intérieure | Peinture-01 | Mur-149 | 1-Projet | Sdb | B03 | rdc | 3
Mur-149 | rdc | 0 | 0 | 3000 | 0 | 0 | 0 | 0.124599 | 0 | 0 | 628.555 | 1.88498 | 1.67498 | 0 | 593.555 | 663.555 | 1.88498 | 593.555 | 1.67498 | 0.124599 | 1.88498 | 1.67498 | 663.555 | 593.555 | 0 | 0.0415329 | 3000 | 0.124599 | 3000 | 628.327 | 0.124599 | 1426.11 | 6000 | 3000 | 3000 | 0 | 0.380051 | Face intérieure | Surface-Blanche | Mur-149 | 1-Projet | Sejour cuisine | B02 | rdc | 3
Mur-149 | rdc | 0 | 0 | 2700 | 2700 | 0 | 0 | 0.342256 | 0 | 0 | 1795 | 4.977 | 4.35166 | 0 | 2010 | 1830 | 4.977 | 1760 | 4.35166 | 0.342256 | 4.977 | 4.80166 | 1830 | 1760 | 0 | 0.140702 | 2700 | 0.342256 | 3000 | 2010 | 0.342256 | 3759 | 5700 | 2700 | 3000 | -4.44089e-13 | 0.732033 | Face intérieure | Surface-Blanche | Mur-149 | 1-Projet | Entree/pl | B02 | rdc | 3
Mur-149 | rdc | 2 | 0 | 2504.83 | 2504.83 | 3.3864 | 1660 | 0.180318 | 3.7856 | 3.7856 | 2539.73 | 2.66364 | 2.31297 | 0.264992 | 2644.73 | 754.727 | 6.44924 | 684.727 | 6.09857 | 0.44531 | 6.44924 | 6.27391 | 2574.73 | 2504.73 | 0 | 0.0503809 | 2504.83 | 0.180318 | 3000 | 2574.73 | 0.44531 | 5248.45 | 5504.83 | 2504.83 | 3000 | -4.44089e-13 | 0.651465 | Face intérieure | Surface-Blanche | Mur-149 | 1-Projet | Entree/pl | B02 | rdc | 3
Mur-150 | rdc | 2 | 0 | 3000 | 0 | 2.8764 | 1410 | 0.450583 | 3.1228 | 3.1228 | 3336.57 | 6.3319 | 6.1219 | 0.218596 | 3371.57 | 1791.57 | 9.4547 | 1861.57 | 9.2447 | 0.669179 | 9.4547 | 9.6647 | 3301.57 | 3371.57 | 0 | 0.12786 | 3000 | 0.450583 | 3000 | 3371.57 | 0.669179 | 6842.13 | 6000 | 3000 | 3000 | 0 | 0.855804 | Face intérieure | Surface-Blanche | Mur-150 | 1-Projet | Ch 1 | B01 | rdc | 3 | ArchiCADProperties - Zones conflictuelles: Entree/pl
Mur-149 | rdc | 1 | 0 | 2700 | 2700 | 1.6932 | 830 | 0.201722 | 1.8928 | 1.8928 | 1755.01 | 2.97624 | 2.78724 | 0.132496 | 1970.01 | 880.014 | 4.86904 | 810.013 | 4.68004 | 0.334218 | 4.86904 | 4.68004 | 1790.01 | 1720.01 | 0 | 0.071751 | 2700 | 0.201722 | 3000 | 1970.01 | 0.334218 | 3679.02 | 5700 | 2700 | 3000 | -4.44089e-13 | 0.663489 | Face intérieure | Peinture-01 | Mur-149 | 1-Projet | Entree/pl | B01 | rdc | 3
Mur-150 | rdc | 0 | 0 | 3000 | 3000 | 0 | 0 | 0.187865 | 0 | 0 | 864.639 | 2.78801 | 2.57956 | 0 | 1079.34 | 899.335 | 2.78801 | 829.943 | 2.57956 | 0.187865 | 2.78801 | 2.57956 | 899.335 | 829.943 | 0 | 0.0731061 | 3000 | 0.187865 | 3000 | 1079.34 | 0.187865 | 1898.23 | 6000 | 3000 | 3000 | -4.44089e-13 | 0.653068 | Face intérieure | Surface-Blanche | Mur-150 | 1-Projet | Sdb | B02 | rdc | 3
Mur-149 | rdc | 0 | 0 | 2700 | 2700 | 0 | 0 | 0.762915 | 0 | 0 | 4036.59 | 10.8988 | 10.8988 | 0 | 4376.59 | 4036.59 | 10.8988 | 4036.59 | 10.8988 | 0.762915 | 10.8988 | 10.8988 | 4036.59 | 4036.59 | 0 | 0.282561 | 2700 | 0.762915 | 3000 | 4036.59 | 0.762915 | 8213.18 | 5700 | 2700 | 3000 | 0 | 0.943122 | Face intérieure | Surface-Blanche | Mur-149 | 1-Projet | Ch 2 | B02 | rdc | 3
Mur-121 | rdc | 0 | 0 | 3000 | 3000 | 0 | 0 | 0.090315 | 0 | 0 | 400.072 | 1.11521 | 1.11521 | 0 | 580.072 | 400.072 | 1.11521 | 400.072 | 1.11521 | 0.090315 | 1.29021 | 1.29021 | 400.072 | 400.072 | 0 | 0.040605 | 3000 | 0.090315 | 3000 | 580.072 | 0.090315 | 940.143 | 6000 | 3000 | 3000 | 0 | 0.50121 | Face extérieure | Lavis blanc | Mur-121 | 1-Projet |  |  | rdc | 3
Mur-149 | rdc | 0 | 0 | 2700 | 2700 | 0 | 0 | 0.120068 | 0 | 0 | 635.278 | 1.80975 | 1.62075 | 0 | 670.278 | 670.278 | 1.80975 | 600.278 | 1.62075 | 0.120068 | 1.80975 | 1.62075 | 670.278 | 600.278 | 0 | 0.0444695 | 2700 | 0.120068 | 3000 | 670.278 | 0.120068 | 1439.52 | 5700 | 2700 | 3000 | 0 | 0.545148 | Face intérieure | Peinture-01 | Mur-149 | 1-Projet | Sejour cuisine | B03 | rdc | 3
Mur-149 | rdc | 0 | 0 | 2700 | 2700 | 0 | 0 | 0.789664 | 0 | 0 | 4178.12 | 11.0919 | 11.2809 | 0 | 4518.12 | 4178.12 | 11.0919 | 4178.12 | 11.2809 | 0.789664 | 11.2809 | 11.2809 | 4178.12 | 4178.12 | 0 | 0.292468 | 2700 | 0.789664 | 3000 | 4178.12 | 0.789664 | 8496.24 | 5700 | 2700 | 3000 | 0 | 0.962936 | Face intérieure | Peinture-01 | Mur-149 | 1-Projet | Ch 2/pl | B03 | rdc | 3
Mur-149 | rdc | 0 | 0 | 2700 | 2700 | 0 | 0 | 0.0916727 | 0 | 0 | 485.041 | 1.4041 | 1.21512 | 0 | 520.037 | 520.037 | 1.4041 | 450.045 | 1.21512 | 0.0916727 | 1.4041 | 1.21512 | 520.037 | 450.045 | 0 | 0.0339529 | 2700 | 0.0916727 | 3000 | 520.037 | 0.0916727 | 1138.99 | 5700 | 2700 | 3000 | 0 | 0.523968 | Face intérieure | Peinture-01 | Mur-149 | 1-Projet | Cellier | A04 | rdc | 3
Mur-149 | rdc | 0 | 0 | 2700 | 2700 | 0 | 0 | 0.175281 | 0 | 0 | 916.672 | 2.49702 | 2.51101 | 0 | 1096.67 | 916.672 | 2.49702 | 916.672 | 2.51101 | 0.175281 | 2.49702 | 2.51101 | 916.672 | 916.672 | 0 | 0.0767671 | 2700 | 0.175281 | 3000 | 1096.67 | 0.175281 | 1973.34 | 5700 | 2700 | 3000 | 0 | 0.537333 | Face intérieure | Peinture-01 | Mur-149 | 1-Projet | Sejour cuisine | B03 | rdc | 3
Mur-150 | rdc | 0 | 0 | 3000 | 0 | 0 | 0 | 0.188632 | 0 | 0 | 1048.25 | 2.79966 | 2.58982 | 0 | 1083.22 | 1083.22 | 2.79966 | 1013.27 | 2.58982 | 0.188632 | 2.79966 | 2.58982 | 1083.22 | 1013.27 | 0 | 0.0733772 | 3000 | 0.188632 | 3000 | 1083.22 | 0.188632 | 2265.45 | 6000 | 3000 | 3000 | 0 | 0.641026 | Face intérieure | Surface-Blanche | Mur-150 | 1-Projet | Sdb | B01 | rdc | 3
Mur-149 | rdc | 0 | 0 | 2700 | 2700 | 0 | 0 | 0.303031 | 0 | 0 | 1590 | 4.32901 | 4.32901 | 0 | 1840.01 | 1590.01 | 4.32901 | 1590 | 4.32901 | 0.303031 | 4.32901 | 4.32901 | 1590.01 | 1590 | 0 | 0.1239 | 2700 | 0.303031 | 3000 | 1770.01 | 0.303031 | 3320.01 | 5700 | 2700 | 3000 | 0 | 0.625801 | Face intérieure | Peinture-01 | Mur-149 | 1-Projet | Entree/pl | B03 | rdc | 3
Mur-149 | rdc | 3 | 0 | 3000 | 3000 | 7.04544 | 3489.52 | 0.281784 | 7.36464 | 7.36464 | 3796.71 | 3.71048 | 3.71048 | 0.515525 | 3761.71 | 222.185 | 7.49608 | 152.185 | 7.49608 | 0.797309 | 11.4951 | 11.2851 | 3831.71 | 3761.71 | 0 | 0.013103 | 3000 | 0.281784 | 3000 | 3831.71 | 0.797309 | 7762.41 | 6000 | 3000 | 3000 | 0 | 0.645858 | Face intérieure | Surface-Blanche | Mur-149 | 1-Projet | Ch 2 | B01 | rdc | 3
Mur-149 | rdc | 1 | 0 | 2700 | 2700 | 0.2925 | 450 | 0.194658 | 0.3283 | 0.3283 | 1151.53 | 2.87533 | 2.49733 | 0.022981 | 1256.53 | 1186.53 | 3.20363 | 1116.53 | 2.82563 | 0.217639 | 3.20363 | 3.01463 | 1186.53 | 1116.53 | 0 | 0.080607 | 2700 | 0.194658 | 3000 | 1186.53 | 0.217639 | 2472.05 | 5700 | 2700 | 3000 | 0 | 0.6175 | Face intérieure | Peinture-01 | Mur-149 | 1-Projet | Sejour Cuisine/pl | A04 | rdc | 3
Mur-149 | rdc | 0 | 1 | 3000 | 3000 | 0 | 0 | 0.400997 | 2.26017 | 2.26017 | 2651.52 | 5.51853 | 5.55319 | 0.158212 | 2721.52 | 1543.59 | 5.51853 | 1543.59 | 5.55319 | 0.559209 | 7.9887 | 7.9887 | 2651.52 | 2651.52 | 2.26017 | 0.112951 | 3000 | 0.400997 | 3000 | 2721.52 | 0.559209 | 5443.04 | 6000 | 3000 | 3000 | 0 | 0.580658 | Face intérieure | Surface-Blanche | Mur-149 | 1-Projet | Entree/pl | B02 | rdc | 3
Mur-151 | rdc | 1 | 1 | 3000 | 3000 | 1.6932 | 830 | 0.659054 | 3.84693 | 3.84693 | 4397.33 | 8.43506 | 8.64505 | 0.269285 | 4677.33 | 2529.42 | 12.282 | 2529.42 | 12.492 | 0.928339 | 13.262 | 13.262 | 4397.33 | 4397.33 | 1.95413 | 0.196659 | 3000 | 0.659054 | 3000 | 4677.33 | 0.928339 | 8934.66 | 6000 | 3000 | 3000 | 0 | 0.944072 | Face extérieure | Peinture-01 | Mur-151 | 1-Projet | Sdb | A03 | rdc | 3 | ArchiCADProperties - Zones conflictuelles: Ch 1
Mur-153 | rdc | 2 | 0 | 2700 | 0 | 3.3864 | 1660 | 0.748613 | 3.7856 | 3.7856 | 5502.99 | 10.6945 | 10.5055 | 0.264992 | 5502.99 | 3682.99 | 14.4801 | 3682.99 | 14.2911 | 1.01361 | 14.4801 | 14.4801 | 5502.99 | 5502.99 | 0 | 0.248009 | 2700 | 0.748613 | 3000 | 5363.01 | 1.01361 | 11146 | 5700 | 2700 | 3000 | 0 | 1.00142 | Face extérieure | Peinture-01 | Mur-153 | 1-Projet | Ch 2/pl | A04 | rdc | 3 | ArchiCADProperties - Zones conflictuelles: Cellier; Ch 2/pl; Dgt; Sdb
Mur-153 | rdc | 0 | 0 | 2700 | 2700 | 0 | 0 | 0.45824 | 0 | 0 | 2424.3 | 6.58612 | 6.12716 | 0 | 2509.32 | 2509.29 | 6.58612 | 2339.32 | 6.12716 | 0.45824 | 6.77512 | 6.31616 | 2509.29 | 2339.32 | 0 | 0.169719 | 2700 | 0.45824 | 3000 | 2509.31 | 0.45824 | 5069.65 | 5700 | 2700 | 3000 | 0 | 0.9363 | Face extérieure | Peinture-01 | Mur-153 | 1-Projet | Sdb | A04 | rdc | 3
Mur-149 | rdc | 1 | 0 | 2700 | 2700 | 1.6932 | 830 | 0.307687 | 1.8928 | 1.8928 | 2329.01 | 4.39553 | 4.39553 | 0.132496 | 2329.01 | 1419.01 | 6.28833 | 1419.01 | 6.28833 | 0.440183 | 6.28833 | 6.28833 | 2329.01 | 2329.01 | 0 | 0.0993307 | 2700 | 0.307687 | 3000 | 2329.01 | 0.440183 | 4798.02 | 5700 | 2700 | 3000 | 0 | 0.640361 | Face intérieure | Peinture-01 | Mur-149 | 1-Projet | Ch 1 | A01 | rdc | 3
Mur-149 | rdc | 0 | 0 | 2700 | 2700 | 0 | 0 | 0.303033 | 0 | 0 | 1590.01 | 4.14004 | 4.32904 | 0 | 1840.01 | 1590.01 | 4.14004 | 1590.01 | 4.32904 | 0.303033 | 4.32904 | 4.32904 | 1590.01 | 1590.01 | 0 | 0.123901 | 2700 | 0.303033 | 3000 | 1770.01 | 0.303033 | 3320.03 | 5700 | 2700 | 3000 | -4.44089e-13 | 0.625802 | Face intérieure | Peinture-01 | Mur-149 | 1-Projet | Cellier | B03 | rdc | 3
Mur-149 | rdc | 1 | 0 | 2700 | 2700 | 1.6932 | 830 | 0.381584 | 1.8928 | 1.8928 | 2720 | 5.2622 | 4.8982 | 0.132496 | 2720 | 1810 | 7.155 | 1810 | 6.791 | 0.51408 | 7.344 | 7.344 | 2720 | 2720 | 0 | 0.1267 | 2700 | 0.381584 | 3000 | 2720 | 0.51408 | 5580 | 5700 | 2700 | 3000 | 0 | 0.6951 | Face intérieure | Peinture-01 | Mur-149 | 1-Projet | Sejour cuisine | B03 | rdc | 3
Mur-150 | rdc | 2 | 0 | 2700 | 0 | 2.8764 | 1410 | 0.361581 | 3.1228 | 3.1228 | 3231.52 | 5.16544 | 4.97644 | 0.218596 | 3301.52 | 1721.52 | 8.28824 | 1721.52 | 8.09924 | 0.580177 | 8.28824 | 8.28824 | 3231.52 | 3231.52 | 0 | 0.125406 | 2700 | 0.361581 | 3000 | 3301.52 | 0.580177 | 6603.04 | 5700 | 2700 | 3000 | 0 | 0.721912 | Face intérieure | Surface-Blanche | Mur-150 | 1-Projet | Entree/pl | B02 | rdc | 3
Mur-149 | rdc | 0 | 0 | 3000 | 3000 | 0 | 0 | 0.134581 | 0 | 0 | 640.862 | 1.81759 | 2.02758 | 0 | 675.861 | 605.862 | 1.81759 | 675.861 | 2.02758 | 0.134581 | 1.81759 | 2.02758 | 605.862 | 675.861 | 0 | 0.0448603 | 3000 | 0.134581 | 3000 | 675.861 | 0.134581 | 1450.72 | 6000 | 3000 | 3000 | 0 | 0.596705 | Face extérieure | Lavis blanc | Mur-149 | 1-Projet | Sejour Cuisine | B01 | rdc | 3
Mur-149 | rdc | 0 | 0 | 3000 | 0 | 0 | 0 | 0.832975 | 0 | 0 | 4036.54 | 11.8996 | 11.8996 | 0 | 4036.54 | 4036.54 | 11.8996 | 4036.54 | 11.8996 | 0.832975 | 11.8996 | 11.8996 | 4036.54 | 4036.54 | 0 | 0.277658 | 3000 | 0.832975 | 3000 | 3966.55 | 0.832975 | 8213.09 | 6000 | 3000 | 3000 | 0 | 0.765317 | Face intérieure | Surface-Blanche | Mur-149 | 1-Projet | Ch 2 | B01 | rdc | 3
Mur-150 | rdc | 0 | 0 | 3000 | 3000 | 0 | 0 | 0.0829114 | 0 | 0 | 394.825 | 1.2902 | 1.0787 | 0 | 430.104 | 430.097 | 1.2902 | 359.553 | 1.0787 | 0.0829114 | 1.2902 | 1.0787 | 430.097 | 359.553 | 0 | 0.0276479 | 3000 | 0.0829114 | 3000 | 430.104 | 0.0829114 | 958.603 | 6000 | 3000 | 3000 | -4.44089e-13 | 0.562153 | Face intérieure | Surface-Blanche | Mur-150 | 1-Projet | Sdb | B02 | rdc | 3
Mur-149 | rdc | 2 | 0 | 2500 | 2500 | 3.3864 | 1660 | 0.109429 | 3.7856 | 3.7856 | 2139.55 | 1.12578 | 1.47578 | 0.264992 | 2104.55 | 284.55 | 4.91138 | 354.55 | 5.26138 | 0.374421 | 5.26138 | 5.43638 | 2104.55 | 2174.55 | 0 | 0.0223685 | 2500 | 0.109429 | 3000 | 2174.55 | 0.374421 | 4448.1 | 5500 | 2500 | 3000 | 0 | 0.594625 | Face intérieure | Surface-Blanche | Mur-149 | 1-Projet | Ch 1/pl | B04 | rdc | 3 | ArchiCADProperties - Zones conflictuelles: Entree/pl
Mur-121 | rdc | 0 | 0 | 3000 | 3000 | 0 | 0 | 0.0903206 | 0 | 0 | 400.098 | 1.11529 | 1.11529 | 0 | 580.098 | 400.098 | 1.11529 | 400.098 | 1.11529 | 0.0903206 | 1.29029 | 1.29029 | 400.098 | 400.098 | 0 | 0.0406069 | 3000 | 0.0903206 | 3000 | 580.098 | 0.0903206 | 940.196 | 6000 | 3000 | 3000 | 0 | 0.501214 | Face extérieure | Lavis blanc | Mur-121 | 1-Projet |  |  | rdc | 3
Mur-149 | rdc | 0 | 0 | 3000 | 3000 | 0 | 0 | 0.140333 | 0 | 0 | 668.251 | 1.89975 | 2.10975 | 0 | 703.251 | 633.251 | 1.89975 | 703.251 | 2.10975 | 0.140333 | 1.89975 | 2.10975 | 633.251 | 703.251 | 0 | 0.0467776 | 3000 | 0.140333 | 3000 | 703.251 | 0.140333 | 1505.5 | 6000 | 3000 | 3000 | 0 | 0.60054 | Face intérieure | Surface-Blanche | Mur-149 | 1-Projet | Sejour cuisine | B02 | rdc | 3
Mur-149 | rdc | 0 | 0 | 2700 | 2700 | 0 | 0 | 0.12041 | 0 | 0 | 637.092 | 1.8145 | 1.62579 | 0 | 742.039 | 672.039 | 1.8145 | 602.146 | 1.62579 | 0.12041 | 1.8145 | 1.62579 | 672.039 | 602.146 | 0 | 0.0445965 | 2700 | 0.12041 | 3000 | 672.039 | 0.12041 | 1443.1 | 5700 | 2700 | 3000 | 0 | 0.545255 | Face intérieure | Peinture-01 | Mur-149 | 1-Projet | Cellier | A04 | rdc | 3
Mur-149 | rdc | 0 | 0 | 2700 | 2700 | 0 | 0 | 0.120068 | 0 | 0 | 635.278 | 1.80975 | 1.62075 | 0 | 670.278 | 670.278 | 1.80975 | 600.278 | 1.62075 | 0.120068 | 1.80975 | 1.62075 | 670.278 | 600.278 | 0 | 0.0444694 | 2700 | 0.120068 | 3000 | 670.278 | 0.120068 | 1439.55 | 5700 | 2700 | 3000 | 0 | 0.545225 | Face intérieure | Peinture-01 | Mur-149 | 1-Projet | Sejour cuisine | B03 | rdc | 3 | ArchiCADProperties - Zones conflictuelles: Sejour cuisine
Mur-149 | rdc | 0 | 0 | 3000 | 4.44089e-13 | 0 | 0 | 0.294327 | 0 | 0 | 1540 | 4.20467 | 4.20467 | 0 | 1610 | 1540 | 4.20467 | 1540 | 4.20467 | 0.294327 | 4.20467 | 4.20467 | 1540 | 1540 | 0 | 0.1127 | 3000 | 0.294327 | 3000 | 1610 | 0.294327 | 3220 | 6000 | 3000 | 3000 | -4.44089e-13 | 0.4578 | Face intérieure | Surface-Blanche | Mur-149 | 1-Projet | Cellier | B02 | rdc | 3
Mur-149 | rdc | 0 | 0 | 2700 | 2700 | 0 | 0 | 0.536404 | 0 | 0 | 2838.12 | 7.47392 | 7.66292 | 0 | 2838.12 | 2838.12 | 7.47392 | 2838.12 | 7.66292 | 0.536404 | 7.66292 | 7.66292 | 2838.12 | 2838.12 | 0 | 0.198668 | 2700 | 0.536404 | 3000 | 2838.12 | 0.536404 | 5816.24 | 5700 | 2700 | 3000 | 0 | 0.775336 | Face intérieure | Peinture-01 | Mur-149 | 1-Projet | Ch 3 | B03 | rdc | 3
Mur-149 | rdc | 0 | 0 | 2700 | 2700 | 0 | 0 | 0.06286 | 0 | 0 | 330 | 0.905 | 0.891 | 0 | 400 | 330 | 0.905 | 330 | 0.891 | 0.06286 | 0.905 | 0.891 | 330 | 330 | 0 | 0.02555 | 2700 | 0.06286 | 3000 | 400 | 0.06286 | 800 | 5700 | 2700 | 3000 | 0 | 0.434899 | Face intérieure | Peinture-01 | Mur-149 | 1-Projet |  |  | rdc | 3
Mur-149 | rdc | 0 | 0 | 2700 | 2700 | 0 | 0 | 0.120971 | 0 | 0 | 633.393 | 1.65169 | 1.80464 | 0 | 598.402 | 598.402 | 1.65169 | 668.383 | 1.80464 | 0.120971 | 1.65169 | 1.80464 | 598.402 | 668.383 | 0 | 0.0506375 | 2700 | 0.120971 | 3000 | 848.402 | 0.120971 | 1435.78 | 5700 | 2700 | 3000 | 0 | 0.582191 | Face intérieure | Peinture-01 | Mur-149 | 1-Projet | Sejour Cuisine/pl | A04 | rdc | 3
Mur-153 | rdc | 2 | 0 | 2700 | 2700 | 3.3864 | 1660 | 0.298619 | 3.7856 | 3.7856 | 2982.07 | 3.98249 | 3.79349 | 0.264992 | 2947.07 | 1197.07 | 7.76809 | 1127.07 | 7.57909 | 0.563611 | 8.14609 | 7.95709 | 3017.07 | 2947.07 | 0 | 0.0813449 | 2700 | 0.298619 | 3000 | 3017.07 | 0.563611 | 6133.14 | 5700 | 2700 | 3000 | 0 | 0.746376 | Face extérieure | Peinture-01 | Mur-153 | 1-Projet | Ch 2/pl | A04 | rdc | 3 | ArchiCADProperties - Zones conflictuelles: Ch 2/pl
Mur-149 | rdc | 0 | 0 | 2700 | 2700 | 0 | 0 | 0.105472 | 0 | 0 | 558.051 | 1.50674 | 1.50674 | 0 | 968.051 | 558.051 | 1.50674 | 558.051 | 1.50674 | 0.105472 | 1.50674 | 1.50674 | 558.051 | 558.051 | 0 | 0.0390636 | 2700 | 0.105472 | 3000 | 558.051 | 0.105472 | 1256.1 | 5700 | 2700 | 3000 | 0 | 0.456127 | Face intérieure | Peinture-01 | Mur-149 | 1-Projet | Sejour Cuisine/pl | A04 | rdc | 3
Mur-149 | rdc | 0 | 0 | 2500 | 2500 | 0 | 0 | 0.111125 | 0 | 0 | 635 | 1.5 | 1.675 | 0 | 850 | 600 | 1.5 | 670 | 1.675 | 0.111125 | 1.5 | 1.675 | 600 | 670 | 0 | 0.0444501 | 2500 | 0.111125 | 3000 | 670 | 0.111125 | 1438.99 | 5500 | 2500 | 3000 | 0 | 0.511388 | Face intérieure | Peinture-01 | Mur-149 | 1-Projet | Sejour cuisine | B05 | rdc | 3
Mur-149 | rdc | 0 | 0 | 3000 | 3000 | 0 | 0 | 0.538833 | 0 | 0 | 2571.56 | 7.39969 | 7.78555 | 0 | 2536.56 | 2536.56 | 7.39969 | 2606.56 | 7.78555 | 0.538833 | 7.60969 | 7.78555 | 2536.56 | 2606.56 | 0 | 0.180009 | 3000 | 0.538833 | 3000 | 2606.56 | 0.538833 | 5312.12 | 6000 | 3000 | 3000 | 0 | 0.852862 | Face intérieure | Surface-Blanche | Mur-149 | 1-Projet | Ch 2 | B02 | rdc | 3
Mur-149 | rdc | 0 | 0 | 3000 | 3000 | 0 | 0 | 0.13335 | 0 | 0 | 635 | 2.01 | 1.8 | 0 | 670 | 670 | 2.01 | 600 | 1.8 | 0.13335 | 2.01 | 1.8 | 670 | 600 | 0 | 0.0444501 | 3000 | 0.13335 | 3000 | 669.999 | 0.13335 | 1438.99 | 6000 | 3000 | 3000 | 0 | 0.595887 | Face intérieure | Surface-Blanche | Mur-149 | 1-Projet | Ch 2 | B02 | rdc | 3
Mur-153 | rdc | 1 | 0 | 2700 | 2700 | 1.6932 | 830 | 0.462053 | 1.8928 | 1.8928 | 3145.76 | 6.41178 | 6.03373 | 0.132496 | 3145.75 | 2235.77 | 8.30458 | 2235.75 | 7.92653 | 0.594549 | 8.49358 | 8.49353 | 3145.77 | 3145.75 | 0 | 0.156503 | 2700 | 0.462053 | 3000 | 3145.77 | 0.594549 | 6431.52 | 5700 | 2700 | 3000 | 0 | 0.754706 | Face extérieure | Peinture-01 | Mur-153 | 1-Projet | Ch 1 | A04 | rdc | 3 | ArchiCADProperties - Zones conflictuelles: Ch 1
2 x Mur-121 | rdc | 0 | 0 | 3000 | 3000 | 0 | 0 | 0.0693254 | 0 | 0 | 330.121 | 0.990362 | 0.990362 | 0 | 400.121 | 330.121 | 0.990362 | 330.121 | 0.990362 | 0.0693254 | 0.990362 | 0.990362 | 330.121 | 330.121 | 0 | 0.0231085 | 3000 | 0.0693254 | 3000 | 330.121 | 0.0693254 | 800.242 | 6000 | 3000 | 3000 | 0 | 0.466217 | Face extérieure | Lavis blanc | Mur-121 | 1-Projet |  |  | rdc | 3
Mur-149 | rdc | 0 | 0 | 2700 | 2300 | 0 | 0 | 0.128776 | 0 | 0 | 681.519 | 1.93411 | 1.74521 | 0 | 716.498 | 716.498 | 1.93411 | 646.541 | 1.74521 | 0.128776 | 1.93454 | 1.74565 | 716.498 | 646.541 | 0 | 0.0477064 | 2700 | 0.128776 | 3000 | 716.541 | 0.128807 | 1532.03 | 5700 | 2700 | 3000 | 0 | 0.537698 | Face intérieure | Peinture-01 | Mur-149 | 1-Projet | Sejour cuisine/pl | B04 | rdc | 3
Mur-149 | rdc | 0 | 0 | 3000 | 3000 | 0 | 0 | 0.187956 | 0 | 0 | 865.03 | 2.79009 | 2.58009 | 0 | 1080.03 | 900.03 | 2.79009 | 830.03 | 2.58009 | 0.187956 | 2.79009 | 2.58009 | 900.03 | 830.03 | 0 | 0.0731521 | 3000 | 0.187956 | 3000 | 1080.03 | 0.187956 | 1899.06 | 6000 | 3000 | 3000 | -4.44089e-13 | 0.653289 | Face intérieure | Surface-Blanche | Mur-149 | 1-Projet | Sdb | B01 | rdc | 3
Mur-149 | rdc | 0 | 0 | 3000 | 3000 | 0 | 0 | 0.362498 | 0 | 0 | 1726.18 | 5.17855 | 4.96855 | 0 | 1796.18 | 1726.18 | 5.17855 | 1726.18 | 4.96855 | 0.362498 | 5.17855 | 5.17855 | 1726.18 | 1726.18 | 0 | 0.120833 | 3000 | 0.362498 | 3000 | 1726.18 | 0.362498 | 3592.36 | 6000 | 3000 | 3000 | 0 | 0.661666 | Face intérieure | Surface-Blanche | Mur-149 | 1-Projet | Wc | B01 | rdc | 3
Mur-153 | rdc | 1 | 0 | 2700 | 2700 | 3.14284 | 1571.42 | 0.0816545 | 3.06284 | 3.06284 | 1566.42 | 1.07199 | 1.26099 | 0.214399 | 1601.42 | 1.16129e-10 | 1.07199 | 70 | 1.26099 | 0.296053 | 4.13483 | 4.32383 | 1531.42 | 1601.42 | 0 | 0.00245 | 2700 | 0.0816545 | 3000 | 1601.42 | 0.296053 | 3301.83 | 5700 | 2700 | 3000 | 0 | 0.428386 | Face extérieure | Peinture-01 | Mur-153 | 1-Projet | Ch 2/pl | A04 | rdc | 3
Mur-149 | rdc | 0 | 0 | 3000 | 3000 | 0 | 0 | 0.0614228 | 0 | 0 | 285.489 | 0.982517 | 0.772419 | 0 | 390.511 | 320.505 | 0.982517 | 250.472 | 0.772419 | 0.0614228 | 0.982517 | 0.772419 | 320.505 | 250.472 | 0 | 0.0248846 | 3000 | 0.0614228 | 3000 | 390.511 | 0.0614228 | 739.996 | 6000 | 3000 | 3000 | 0 | 0.556824 | Face intérieure | Surface-Blanche | Mur-149 | 1-Projet | Sdb | B02 | rdc | 3 | ArchiCADProperties - Zones conflictuelles: Sdb
Mur-153 | rdc | 1 | 0 | 2700 | 2700 | 2.34909 | 1174.54 | 0.129553 | 2.34908 | 2.34909 | 1555.5 | 1.47279 | 1.85073 | 0.164436 | 1555.49 | 310.965 | 1.47279 | 450.946 | 1.85073 | 0.293989 | 4.01087 | 4.38882 | 1485.51 | 1625.49 | 0 | 0.0266669 | 2700 | 0.129553 | 3000 | 1625.49 | 0.293989 | 3308.97 | 5700 | 2700 | 3000 | 0 | 0.670089 | Face extérieure | Peinture-01 | Mur-153 | 1-Projet | Dgt | A04 | rdc | 3 | ArchiCADProperties - Zones conflictuelles: Sejour Cuisine/pl
Mur-153 | rdc | 0 | 0 | 2700 | 2700 | 0 | 0 | 0.796746 | 0 | 0 | 4215.59 | 11.3821 | 11.3821 | 0 | 4555.58 | 4215.6 | 11.3821 | 4215.58 | 11.3821 | 0.796746 | 11.3821 | 11.3821 | 4215.6 | 4215.58 | 0 | 0.295091 | 2700 | 0.796746 | 3000 | 4215.6 | 0.796746 | 8571.17 | 5700 | 2700 | 3000 | 0 | 0.968182 | Face extérieure | Peinture-01 | Mur-153 | 1-Projet | Ch 2/pl | A04 | rdc | 3
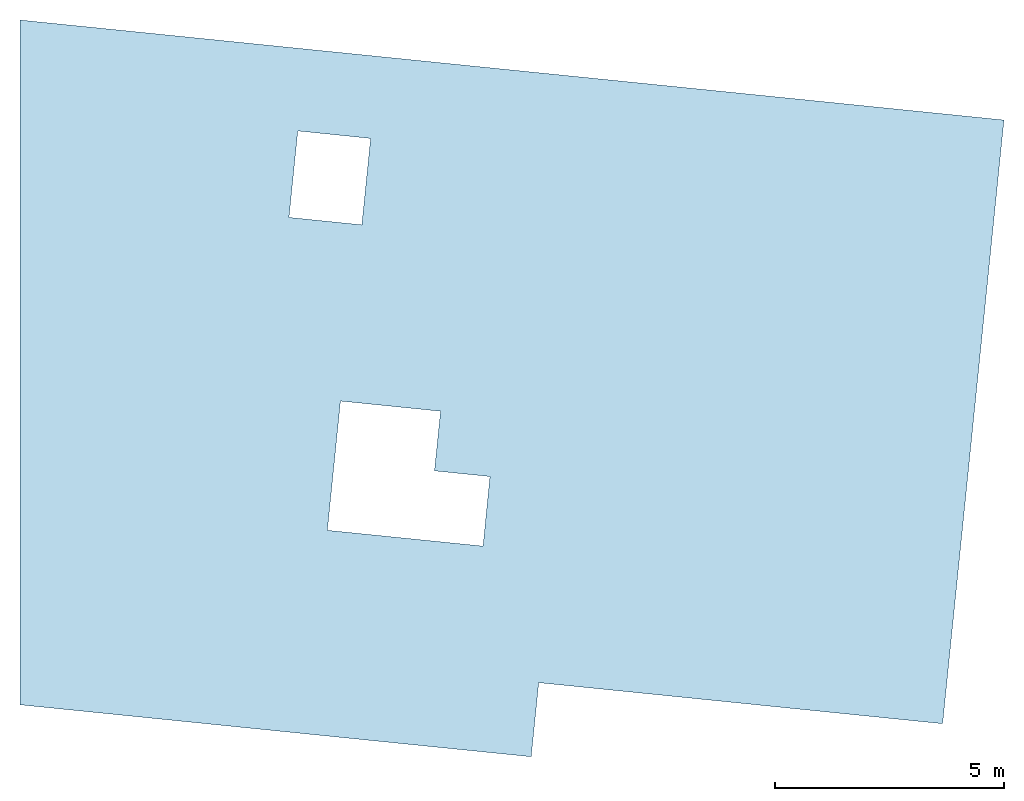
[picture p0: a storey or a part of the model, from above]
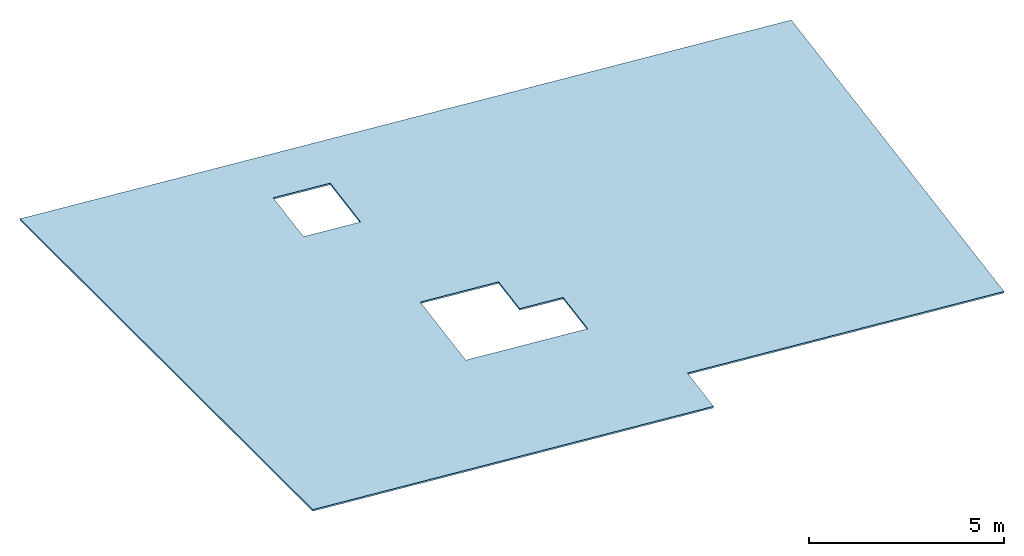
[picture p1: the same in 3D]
Properties of the parts of a building model (IFC2X3), part 24 of 44

# IfcWallStandardCase: Cloison 70 0826278243 70 (896)
Name | In | Nombre de Portes | Nombre de trous (Nombre d'ouvertures vides) | Hauteur maximale de la couche de Mur sur face intérieure (mm) = Hauteur maximale du Mur (mm) = Hauteur maximale de la couche de Mur sur face extérieure (mm) | Hauteur minimale de la couche de Mur sur face intérieure (mm) = Hauteur minimale du Mur (mm) = Hauteur minimale de la couche de Mur sur face extérieure (mm) | Superficie des portes (m2) | Largeur totale des Portes (mm) | Volume de composant de mur sur face intérieure (net) (m3) = Volume de composant de mur sur face extérieure (net) (m3) | Superficie analytique des ouvertures sur face intérieure (m2) | Superficie analytique des ouvertures sur face extérieure (m2) | Longueur moyenne du mur (mm) = Longueur du Mur au centre (mm) | Superficie de la face intérieure du mur (nette) (m2) | Superficie de la face extérieure du mur (nette) (m2) = Superficie en plan (m2) = Superficie inférieure (nette) (m2) | Volume analytique des ouvertures (m3) | Longueur de ligne de référence (mm) | Longueur de la face intérieure du mur (conditionnelle) (mm) | Superficie de la face intérieure du mur (conditionnelle) (m2) | Longueur de la face extérieure du mur (conditionnelle) (mm) | Superficie de la face extérieure du mur (conditionnelle) (m2) | Volume du composant face intérieure du mur (conditionnel) (m3) = Volume du composant face extérieure du mur (conditionnel) (m3) = Volume (conditionnel) (m3) | Superficie de la face intérieure du mur (brute) (m2) | Superficie de la face extérieure du mur (brute) (m2) | Longueur de Mur sur face intérieure (mm) | Longueur de Mur sur face extérieure (mm) | Superficie des baies libres dans le Mur (m2) | Superficie (m2) = Superficie supérieure (nette) (m2) | Hauteur (mm) | Volume (net) (m3) | Altitude à Zéro du Projet (mm) = Altitude de Référence Niveau 1 (mm) = Altitude de Référence Niveau 2 (mm) = Altitude à niveau de la mer (mm) | Longueur 3D (mm) | Volume (brut) (m3) | Périmètre Plan (mm) | Altitude supérieure à premier niveau de référence (mm) = Altitude supérieure à Zéro du projet (mm) = Altitude supérieure à niveau de la mer (mm) = Altitude supérieure à deuxième niveau de référence (mm) | Altitude supérieure à étage d'implantation (mm) | Altitude inférieure à premier niveau de référence (mm) = Altitude inférieure à Zéro du projet (mm) = Altitude inférieure à niveau de la mer (mm) = Altitude inférieure à deuxième niveau de référence (mm) | Altitude inférieure à étage d'implantation (mm) | Superficie de l'arête (nette) (m2) | Emplacement de ligne de référence | Surface de face intérieure = Surface de face extérieure = Surfaces (Toutes) = Surface latérale | ID de l'élément = Lien et ID d'élément = ID de Parent | Calque | Nom de zone liée | Numéro de zone liée | Nom d'étage d'implantation | Numéro d'étage d'implantation
Mur-149 | rdc | 0 | 0 | 2700 | 2700 | 0 | 0 | 0.126221 | 0 | 0 | 670.43 | 1.98511 | 1.62122 | 0 | 670.41 | 740.41 | 1.98511 | 600.451 | 1.62122 | 0.126221 | 1.98511 | 1.62122 | 740.41 | 600.451 | 0 | 0.0469301 | 2700 | 0.126221 | 3000 | 740.41 | 0.126221 | 1538.82 | 5700 | 2700 | 3000 | 0 | 0.622556 | Face intérieure | Peinture-01 | Mur-149 | 1-Projet | Sejour cuisine | B03 | rdc | 3
Mur-150 | rdc | 0 | 0 | 3000 | 3000 | 0 | 0 | 0.132422 | 0 | 0 | 600.573 | 1.99682 | 1.78668 | 0 | 815.567 | 635.573 | 1.99682 | 565.573 | 1.78668 | 0.132422 | 1.99682 | 1.78668 | 635.573 | 565.573 | 0 | 0.05463 | 3000 | 0.132422 | 3000 | 815.567 | 0.132422 | 1370.1 | 6000 | 3000 | 3000 | -4.44089e-13 | 0.616132 | Face intérieure | Surface-Blanche | Mur-150 | 1-Projet | Sdb | B01 | rdc | 3
Mur-149 | rdc | 0 | 0 | 3000 | 3000 | 0 | 0 | 0.35271 | 0 | 0 | 1679.57 | 4.93372 | 4.93371 | 0 | 1784.57 | 1644.57 | 4.93372 | 1714.57 | 4.93371 | 0.35271 | 4.93372 | 5.14371 | 1644.57 | 1714.57 | 0 | 0.11757 | 3000 | 0.35271 | 3000 | 1714.57 | 0.35271 | 3528.14 | 6000 | 3000 | 3000 | -4.44089e-13 | 0.742124 | Face extérieure | Lavis blanc | Mur-149 | 1-Projet | Sejour Cuisine | B01 | rdc | 3
Mur-149 | rdc | 0 | 0 | 3000 | 3000 | 0 | 0 | 0.13335 | 0 | 0 | 635.001 | 2.01 | 1.8 | 0 | 670 | 670.001 | 2.01 | 600.001 | 1.8 | 0.13335 | 2.01 | 1.8 | 670.001 | 600.001 | 0 | 0.04445 | 3000 | 0.13335 | 3000 | 670 | 0.13335 | 1439 | 6000 | 3000 | 3000 | 0 | 0.595885 | Face intérieure | Surface-Blanche | Mur-149 | 1-Projet | Ch 2 | B01 | rdc | 3
Mur-149 | rdc | 1 | 1 | 2500 | 2500 | 1.6932 | 830 | 0.17629 | 3.8274 | 3.8274 | 2538.33 | 2.51843 | 2.34343 | 0.267918 | 2788.33 | 680 | 6.34583 | 680 | 6.17083 | 0.444208 | 6.34583 | 6.34583 | 2538.33 | 2538.33 | 1.9346 | 0.0476 | 2500 | 0.17629 | 3000 | 2538.33 | 0.444208 | 5216.66 | 5500 | 2500 | 3000 | 0 | 0.432483 | Face intérieure | Peinture-01 | Mur-149 | 1-Projet | Sejour cuisine | B05 | rdc | 3
Mur-120 | rdc | 7 | 0 | 2500 | 0 | 7.2216 | 3540 | 0.257652 | 7.51785 | 7.51785 | 4829.44 | 3.50575 | 3.68075 | 0.526249 | 5009.44 | 1929.44 | 8.4816 | 1929.44 | 8.6566 | 0.783901 | 11.1986 | 11.1986 | 4829.44 | 4829.44 | 0 | 0.0568536 | 2500 | 0.257652 | 3000 | 4479.44 | 0.783901 | 9798.88 | 5500 | 2500 | 3000 | 0 | 0.720413 | Face extérieure | Peinture-01 | Mur-120 | 3D |  |  | rdc | 3
Mur-120 | rdc | 5 | 0 | 3000 | 3000 | 5.61 | 2750 | 0.356614 | 5.8425 | 5.8425 | 3645.66 | 4.04448 | 4.67448 | 0.408975 | 3645.66 | 795.661 | 9.88698 | 795.661 | 10.517 | 0.765589 | 10.937 | 10.937 | 3645.66 | 3645.66 | 0 | 0.0556963 | 3000 | 0.356614 | 3000 | 3645.66 | 0.765589 | 7431.32 | 6000 | 3000 | 3000 | 0 | 0.730893 | Face extérieure | Lavis blanc | Mur-120 | 3D |  |  | rdc | 3
Mur-149 | rdc | 0 | 0 | 3000 | 3000 | 0 | 0 | 0.39155 | 0 | 0 | 1864.52 | 5.69857 | 5.48857 | 0 | 1969.52 | 1899.52 | 5.69857 | 1829.52 | 5.48857 | 0.39155 | 5.69857 | 5.48857 | 1899.52 | 1829.52 | 0 | 0.130517 | 3000 | 0.39155 | 3000 | 1899.52 | 0.39155 | 3898.04 | 6000 | 3000 | 3000 | -4.44089e-13 | 0.768018 | Face intérieure | Surface-Blanche | Mur-149 | 1-Projet | Ch 2 | B01 | rdc | 3
Mur-149 | rdc | 0 | 0 | 3000 | 3000 | 0 | 0 | 0.406458 | 0 | 0 | 1935.51 | 5.91154 | 5.70154 | 0 | 1970.51 | 1970.51 | 5.91154 | 1900.51 | 5.70154 | 0.406458 | 5.91154 | 5.70154 | 1970.51 | 1900.51 | 0 | 0.135486 | 3000 | 0.406458 | 3000 | 1970.51 | 0.406458 | 4040.02 | 6000 | 3000 | 3000 | 0 | 0.777957 | Face intérieure | Surface-Blanche | Mur-149 | 1-Projet | Ch 2 | B02 | rdc | 3
Mur-121 | rdc | 0 | 0 | 3000 | 3000 | 0 | 0 | 0.109559 | 0 | 0 | 510.044 | 1.11514 | 1.11514 | 0 | 580.052 | 510.044 | 1.11514 | 510.044 | 1.11514 | 0.109559 | 1.56514 | 1.56514 | 510.044 | 510.044 | 0 | 0.0406037 | 3000 | 0.109559 | 3000 | 580.052 | 0.109559 | 1160.09 | 6000 | 3000 | 3000 | -4.44089e-13 | 0.501207 | Face extérieure | Lavis blanc | Mur-121 | 1-Projet | Sejour cuisine | B02 | rdc | 3 | ArchiCADProperties - Zones conflictuelles: Sejour Cuisine
Mur-121 | rdc | 0 | 0 | 3000 | 0 | 0 | 0 | 0.0690435 | 0 | 0 | 398.779 | 0.986336 | 0.986336 | 0 | 398.779 | 398.779 | 0.986336 | 398.779 | 0.986336 | 0.0690435 | 0.986336 | 0.986336 | 398.779 | 398.779 | 0 | 0.0230145 | 3000 | 0.0690435 | 3000 | 328.779 | 0.0690435 | 937.557 | 6000 | 3000 | 3000 | 0 | 0.466029 | Face extérieure | Lavis blanc | Mur-121 | 1-Projet |  |  | rdc | 3
Mur-148 | rdc | 0 | 0 | 3000 | 3000 | 0 | 0 | 0.159843 | 0 | 0 | 761.157 | 1.84841 | 1.63853 | 0 | 796.136 | 796.136 | 1.84841 | 726.178 | 1.63853 | 0.159843 | 2.38841 | 2.17853 | 796.136 | 726.178 | 0 | 0.053281 | 3000 | 0.159843 | 3000 | 796.136 | 0.159843 | 1691.28 | 6000 | 3000 | 3000 | 0 | 0.61346 | Face intérieure | Surface-Blanche | Mur-148 | 1-Projet | Sejour cuisine | A03 | rdc | 3 | ArchiCADProperties - Zones conflictuelles: Sejour cuisine
Mur-121 | rdc | 0 | 0 | 3000 | 3000 | 0 | 0 | 0.100726 | 0 | 0 | 479.648 | 1.33401 | 1.54388 | 0 | 584.628 | 444.669 | 1.33401 | 514.628 | 1.54388 | 0.100726 | 1.33401 | 1.54388 | 444.669 | 514.628 | 0 | 0.0335754 | 3000 | 0.100726 | 3000 | 514.628 | 0.100726 | 1128.26 | 6000 | 3000 | 3000 | 0 | 0.574048 | Face extérieure | Lavis blanc | Mur-121 | 1-Projet | Sejour cuisine | A03 | rdc | 3
Mur-148 | rdc | 0 | 0 | 3000 | 3000 | 0 | 0 | 0.366061 | 0 | 0 | 1743.15 | 4.58438 | 4.5845 | 0 | 1708.13 | 1708.13 | 4.58438 | 1778.17 | 4.5845 | 0.366061 | 5.12438 | 5.3345 | 1708.13 | 1778.17 | 0 | 0.12202 | 3000 | 0.366061 | 3000 | 1778.17 | 0.366061 | 3655.32 | 6000 | 3000 | 3000 | 0 | 0.751105 | Face intérieure | Surface-Blanche | Mur-148 | 1-Projet | Sejour cuisine | A03 | rdc | 3
Mur-149 | rdc | 0 | 0 | 3000 | 3000 | 0 | 0 | 0.186695 | 0 | 0 | 889.026 | 2.77208 | 2.56207 | 0 | 924.028 | 924.028 | 2.77208 | 854.025 | 2.56207 | 0.186695 | 2.77208 | 2.56207 | 924.028 | 854.025 | 0 | 0.0622318 | 3000 | 0.186695 | 3000 | 924.028 | 0.186695 | 1947.05 | 6000 | 3000 | 3000 | 0 | 0.631458 | Face intérieure | Surface-Blanche | Mur-149 | 1-Projet | Sdb | A03 | rdc | 3
Mur-153 | rdc | 1 | 0 | 3000 | 3000 | 1.1832 | 580 | 0.068173 | 1.23 | 1.23 | 734.633 | 1.0789 | 0.6589 | 0.0861 | 699.633 | 169.633 | 2.3089 | 99.6332 | 1.8889 | 0.154273 | 2.3089 | 2.0989 | 769.633 | 699.633 | 0 | 0.00942433 | 3000 | 0.068173 | 3000 | 769.633 | 0.154273 | 1638.26 | 6000 | 3000 | 3000 | 0 | 0.567834 | Face extérieure | Peinture-01 | Mur-153 | 1-Projet | Sejour cuisine | A03 | rdc | 3
Mur-149 | rdc | 0 | 0 | 3000 | 3000 | 0 | 0 | 0.332467 | 0 | 0 | 1583.18 | 4.53948 | 4.74958 | 0 | 1653.16 | 1583.16 | 4.53948 | 1583.19 | 4.74958 | 0.332467 | 4.74948 | 4.74958 | 1583.16 | 1583.19 | 0 | 0.110822 | 3000 | 0.332467 | 3000 | 1583.19 | 0.332467 | 3306.35 | 6000 | 3000 | 3000 | 0 | 0.641645 | Face intérieure | Surface-Blanche | Mur-149 | 1-Projet | Sdb | A03 | rdc | 3
Mur-121 | rdc | 1 | 0 | 3000 | 3000 | 1.6932 | 830 | 0.228297 | 1.8928 | 1.8928 | 1718.06 | 3.15624 | 3.36654 | 0.132496 | 1683.11 | 773.014 | 5.04904 | 843.112 | 5.25934 | 0.360793 | 5.04904 | 5.25934 | 1683.01 | 1753.11 | 0 | 0.0565644 | 3000 | 0.228297 | 3000 | 1753.11 | 0.360793 | 3605.19 | 6000 | 3000 | 3000 | 0 | 0.684023 | Face extérieure | Lavis blanc | Mur-121 | 1-Projet | Sejour cuisine | A03 | rdc | 3 | ArchiCADProperties - Zones conflictuelles: Sejour cuisine; Wc
Mur-149 | rdc | 0 | 0 | 2500 | 0 | 0 | 0 | 0.151442 | 0 | 0 | 865.873 | 2.20218 | 2.07718 | 0 | 1080.87 | 900.873 | 2.20218 | 830.873 | 2.07718 | 0.151442 | 2.20218 | 2.07718 | 900.873 | 830.873 | 0 | 0.0605769 | 2500 | 0.151442 | 3000 | 900.021 | 0.151442 | 1900.74 | 5500 | 2500 | 3000 | 0 | 0.540628 | Face intérieure | Surface-Blanche | Mur-149 | 1-Projet | Sde | B04 | rdc | 3
Mur-149 | rdc | 0 | 0 | 2500 | 2500 | 0 | 0 | 0.451701 | 0 | 0 | 2661.15 | 6.27788 | 6.27788 | 0 | 2991.15 | 2581.15 | 6.27788 | 2741.15 | 6.27788 | 0.451701 | 6.45288 | 6.45288 | 2581.15 | 2741.15 | 0 | 0.180681 | 2500 | 0.451701 | 3000 | 2581.15 | 0.451701 | 5566.95 | 5500 | 2500 | 3000 | 0 | 0.711361 | Face intérieure | Surface-Blanche | Mur-149 | 1-Projet | Ch 1/pl | B04 | rdc | 3
Mur-149 | rdc | 1 | 0 | 2500 | 2500 | 3.1372 | 1568.6 | 0.061026 | 3.1372 | 3.1372 | 1603.6 | 0.9593 | 0.7843 | 0.219604 | 1908.6 | 70 | 0.9593 | 1.42109e-11 | 0.7843 | 0.28063 | 4.0965 | 3.9215 | 1638.6 | 1568.6 | 0 | 0.00245 | 2500 | 0.061026 | 3000 | 1638.6 | 0.28063 | 3376.19 | 5500 | 2500 | 3000 | 0 | 0.397189 | Face intérieure | Surface-Blanche | Mur-149 | 1-Projet | Ch 1/pl | B04 | rdc | 3 | ArchiCADProperties - Zones conflictuelles: Ch 1/pl
Mur-149 | rdc | 0 | 0 | 2500 | 2500 | 0 | 0 | 0.824209 | 0 | 0 | 4709.77 | 11.7744 | 11.7744 | 0 | 5119.76 | 4709.77 | 11.7744 | 4709.76 | 11.7744 | 0.824209 | 11.7744 | 11.7744 | 4709.77 | 4709.76 | 0 | 0.329684 | 2500 | 0.824209 | 3000 | 4709.77 | 0.824209 | 9559.53 | 5500 | 2500 | 3000 | -4.44089e-13 | 1.00937 | Face intérieure | Surface-Blanche | Mur-149 | 1-Projet | Ch 1/pl | B04 | rdc | 3
Mur-149 | rdc | 0 | 0 | 2700 | 2700 | 0 | 0 | 0.120505 | 0 | 0 | 635 | 1.634 | 1.809 | 0 | 670 | 600 | 1.634 | 670 | 1.809 | 0.120505 | 1.634 | 1.809 | 600 | 670 | 0 | 0.0469 | 2700 | 0.120505 | 3000 | 670 | 0.120505 | 1438.99 | 5700 | 2700 | 3000 | 0 | 0.544287 | Face intérieure | Surface-Blanche | Mur-149 | 1-Projet | Ch 1/pl | B04 | rdc | 3
Mur-149 | rdc | 0 | 0 | 2500 | 2500 | 0 | 0 | 0.0991941 | 0 | 0 | 566.824 | 1.50456 | 1.32956 | 0 | 671.824 | 601.824 | 1.50456 | 531.824 | 1.32956 | 0.0991941 | 1.50456 | 1.32956 | 601.824 | 531.824 | 0 | 0.0396776 | 2500 | 0.0991941 | 3000 | 601.824 | 0.0991941 | 1302.64 | 5500 | 2500 | 3000 | 0 | 0.501843 | Face intérieure | Surface-Blanche | Mur-149 | 1-Projet | Sde | B04 | rdc | 3
Mur-149 | rdc | 0 | 0 | 2700 | 2700 | 0 | 0 | 0.156892 | 0 | 0 | 830.117 | 1.79132 | 1.79132 | 0 | 900.117 | 830.117 | 1.79132 | 830.117 | 1.79132 | 0.156892 | 2.24132 | 2.24132 | 830.117 | 830.117 | 0 | 0.0581082 | 2700 | 0.156892 | 3000 | 830.117 | 0.156892 | 1800.23 | 5700 | 2700 | 3000 | 0 | 0.494216 | Face intérieure | Peinture-01 | Mur-149 | 1-Projet | Entree/pl | B05 | rdc | 3
Mur-149 | rdc | 1 | 0 | 2500 | 0 | 1.1832 | 580 | 0.118652 | 1.23 | 1.23 | 1240.01 | 1.69503 | 1.69503 | 0.0861 | 1240.01 | 640.012 | 2.92503 | 640.012 | 2.92503 | 0.204752 | 2.92503 | 2.92503 | 1240.01 | 1240.01 | 0 | 0.0399009 | 2500 | 0.118652 | 3000 | 1170.06 | 0.204752 | 2620.02 | 5500 | 2500 | 3000 | 0 | 0.471802 | Face intérieure | Surface-Blanche | Mur-149 | 1-Projet | Sde | B04 | rdc | 3 | ArchiCADProperties - Zones conflictuelles: Entree/pl
Mur-149 | rdc | 0 | 0 | 2700 | 2700 | 0 | 0 | 0.185149 | 0 | 0 | 979.625 | 2.45599 | 2.45599 | 0 | 1049.63 | 979.625 | 2.45599 | 979.625 | 2.45599 | 0.185149 | 2.64499 | 2.64499 | 979.625 | 979.625 | 0 | 0.0685738 | 2700 | 0.185149 | 3000 | 979.625 | 0.185149 | 2099.25 | 5700 | 2700 | 3000 | 0 | 0.515148 | Face intérieure | Peinture-01 | Mur-149 | 1-Projet | Sdb | B05 | rdc | 3
Mur-149 | rdc | 0 | 1 | 660 | 660 | 0 | 0 | 0.05873 | 2.55 | 2.55 | 1250 | 0.839 | 0.839 | 0.1785 | 1320 | 0 | 0.839 | 6.95991e-07 | 0.839 | 0.23723 | 3.389 | 3.389 | 1250 | 1250 | 2.55 | 0.0049 | 2700 | 0.05873 | 3000 | 1320 | 0.23723 | 2640 | 5700 | 2700 | 5040 | 2040 | 0.1897 | Face intérieure | Peinture-01 | Mur-149 | 1-Projet | Sejour cuisine | B03 | rdc | 3
Mur-120 | rdc | 0 | 0 | 2460 | 2460 | 0 | 0 | 0.0869144 | 0 | 0 | 504.729 | 1.41383 | 1.06943 | 0 | 915.562 | 574.729 | 1.41383 | 434.729 | 1.06943 | 0.0869144 | 1.41383 | 1.06943 | 574.729 | 434.729 | 0 | 0.035331 | 2460 | 0.0869144 | 3000 | 574.729 | 0.0869144 | 1207.45 | 5460 | 2460 | 3000 | 0 | 0.557717 | Face extérieure | Lavis blanc | Mur-120 | 3D |  |  | rdc | 3
Mur-149 | rdc | 0 | 0 | 2700 | 2300 | 0 | 0 | 0.384361 | 0 | 0 | 2046.99 | 5.39637 | 4.94637 | 0 | 2081.99 | 2081.99 | 5.39637 | 2011.99 | 4.94637 | 0.384361 | 5.62137 | 5.43237 | 2081.99 | 2011.99 | 0 | 0.143289 | 2700 | 0.384361 | 3000 | 2081.99 | 0.386881 | 4262.98 | 5700 | 2700 | 3000 | 0 | 0.742864 | Face intérieure | Peinture-01 | Mur-149 | 1-Projet | Ch 2 | B04 | rdc | 3
Mur-149 | rdc | 0 | 0 | 2700 | 2700 | 0 | 0 | 0.1134 | 0 | 0 | 600 | 1.62 | 1.62 | 0 | 670 | 600 | 1.62 | 600 | 1.62 | 0.1134 | 1.62 | 1.62 | 600 | 600 | 0 | 0.042 | 2700 | 0.1134 | 3000 | 600 | 0.1134 | 1340 | 5700 | 2700 | 3000 | -4.44089e-13 | 0.462 | Face intérieure | Peinture-01 | Mur-149 | 1-Projet | Entree/pl | A02 | rdc | 3
Mur-153 | rdc | 0 | 0 | 3000 | 3000 | 0 | 0 | 0.056282 | 0 | 0 | 250.011 | 0.804057 | 0.804 | 0 | 430 | 250.021 | 0.804057 | 250 | 0.804 | 0.056282 | 0.804057 | 0.804 | 250.021 | 250 | 0 | 0.0301 | 3000 | 0.056282 | 3000 | 430 | 0.056282 | 640.021 | 6000 | 3000 | 3000 | 0 | 0.4802 | Face extérieure | Peinture-01 | Mur-153 | 1-Projet | Sejour cuisine | A03 | rdc | 3
Mur-149 | rdc | 0 | 0 | 2700 | 2700 | 0 | 0 | 0.210132 | 0 | 0 | 1111.81 | 2.71839 | 2.90739 | 0 | 1146.81 | 1076.81 | 2.71839 | 1146.81 | 2.90739 | 0.210132 | 2.90739 | 3.09639 | 1076.81 | 1146.81 | 0 | 0.0778268 | 2700 | 0.210132 | 3000 | 1146.81 | 0.210132 | 2392.62 | 5700 | 2700 | 3000 | 0 | 0.61194 | Face intérieure | Peinture-01 | Mur-149 | 1-Projet | Sdb | A01 | rdc | 3 | ArchiCADProperties - Zones conflictuelles: Ch 1
Mur-149 | rdc | 1 | 0 | 700 | 700 | 3.17993 | 1589.97 | 0.0759484 | 3.09993 | 3.09993 | 1549.97 | 1.08498 | 1.08498 | 0.216995 | 1549.97 | 0 | 1.08498 | 0 | 1.08498 | 0.292944 | 4.18491 | 4.18491 | 1549.97 | 1549.97 | 0 | 0 | 2700 | 0.0759484 | 3000 | 1549.97 | 0.292944 | 3239.93 | 5700 | 2700 | 5000 | 2000 | 0.206498 | Face intérieure | Peinture-01 | Mur-149 | 1-Projet | Entree/pl | B03 | rdc | 3
Mur-149 | rdc | 1 | 0 | 2512.25 | 2512.25 | 3.61146 | 1805.73 | 0.0860795 | 3.52819 | 3.52819 | 1893.88 | 1.14178 | 1.14178 | 0.246973 | 1858.88 | 94.7825 | 1.14178 | 164.783 | 1.14178 | 0.333053 | 4.66997 | 4.84583 | 1858.88 | 1928.88 | 0 | 0.00908479 | 2512.25 | 0.0860795 | 3000 | 1928.88 | 0.333053 | 3956.75 | 5512.25 | 2512.25 | 3000 | 0 | 0.426215 | Face intérieure | Surface-Blanche | Mur-149 | 1-Projet | Entree/pl | B02 | rdc | 3
Mur-149 | rdc | 1 | 0 | 2500 | 2500 | 1.1832 | 580 | 0.0317316 | 1.23 | 1.23 | 673.323 | 0.453308 | 0.453308 | 0.0861 | 743.323 | 73.3232 | 1.68331 | 73.3232 | 1.68331 | 0.117832 | 1.68331 | 1.68331 | 673.323 | 673.323 | 0 | 0.00513262 | 2500 | 0.0317316 | 3000 | 673.323 | 0.117832 | 1486.65 | 5500 | 2500 | 3000 | 0 | 0.402265 | Face intérieure | Peinture-01 | Mur-149 | 1-Projet | Sejour cuisine | B03 | rdc | 3
Mur-149 | rdc | 1 | 1 | 2500 | 0 | 1.6932 | 830 | 0.13903 | 4.43159 | 4.43159 | 2649.56 | 2.06669 | 1.90565 | 0.310211 | 2684.56 | 530.059 | 3.95949 | 460.058 | 3.79845 | 0.449242 | 6.53428 | 6.35928 | 2684.56 | 2614.56 | 2.54052 | 0.0296946 | 2500 | 0.13903 | 3000 | 2613.71 | 0.451275 | 5468.12 | 5500 | 2500 | 3000 | 0 | 0.427791 | Face intérieure | Peinture-01 | Mur-149 | 1-Projet | Dgt | B04 | rdc | 3 | ArchiCADProperties - Zones conflictuelles: Dgt; Sejour cuisine/pl
Mur-149 | rdc | 1 | 0 | 2700 | 2300 | 1.6932 | 830 | 0.294014 | 1.8928 | 1.8928 | 2270 | 3.8222 | 4.3892 | 0.132496 | 2270 | 1290 | 5.715 | 1430 | 6.282 | 0.42651 | 5.94 | 6.318 | 2200 | 2340 | 0 | 0.1035 | 2700 | 0.294014 | 3000 | 2340 | 0.42903 | 4737.99 | 5700 | 2700 | 3000 | 0 | 0.788673 | Face intérieure | Peinture-01 | Mur-149 | 1-Projet | Entree/pl | B04 | rdc | 3
Mur-149 | rdc | 0 | 0 | 2500 | 2500 | 0 | 0 | 0.362171 | 0 | 0 | 2069.55 | 4.91138 | 4.91138 | 0 | 2034.55 | 2104.55 | 4.91138 | 2034.55 | 4.91138 | 0.362171 | 5.26138 | 5.08638 | 2104.55 | 2034.55 | 0 | 0.144869 | 2500 | 0.362171 | 3000 | 2104.55 | 0.362171 | 4308.1 | 5500 | 2500 | 3000 | 0 | 0.712224 | Face intérieure | Peinture-01 | Mur-149 | 1-Projet | Ch 2 | B04 | rdc | 3 | ArchiCADProperties - Zones conflictuelles: Entree/pl
Mur-149 | rdc | 1 | 0 | 2700 | 2700 | 1.6932 | 830 | 0.116106 | 1.8928 | 1.8928 | 1315.35 | 1.48365 | 1.65866 | 0.132496 | 1315.35 | 335.354 | 3.37645 | 475.354 | 3.55146 | 0.248602 | 3.37645 | 3.72646 | 1245.35 | 1385.35 | 0 | 0.0308248 | 2700 | 0.116106 | 3000 | 1385.35 | 0.248602 | 2828.7 | 5700 | 2700 | 3000 | 0 | 0.648325 | Face intérieure | Peinture-01 | Mur-149 | 1-Projet | Ch 1/pl | B04 | rdc | 3
Mur-149 | rdc | 1 | 0 | 2700 | 2700 | 1.95213 | 976.066 | 0.173211 | 1.95213 | 1.95213 | 1639.47 | 2.19094 | 2.56894 | 0.136649 | 1604.47 | 628.406 | 4.14307 | 698.405 | 4.52107 | 0.30986 | 4.33207 | 4.52107 | 1604.47 | 1674.47 | 0 | 0.0464384 | 2700 | 0.173211 | 3000 | 1674.47 | 0.30986 | 3447.94 | 5700 | 2700 | 3000 | 0 | 0.617488 | Face intérieure | Peinture-01 | Mur-149 | 1-Projet | Entree/pl | B04 | rdc | 3 | ArchiCADProperties - Zones conflictuelles: Entree/pl
Mur-149 | rdc | 0 | 0 | 2500 | 2300 | 0 | 0 | 0.234726 | 0 | 0 | 1355.69 | 3.26573 | 3.44073 | 0 | 1390.69 | 1320.69 | 3.26573 | 1390.69 | 3.44073 | 0.234726 | 3.30173 | 3.47673 | 1320.69 | 1390.69 | 0 | 0.0948985 | 2500 | 0.234726 | 3000 | 1390.69 | 0.237246 | 2880.38 | 5500 | 2500 | 3000 | 0 | 0.599684 | Face intérieure | Peinture-01 | Mur-149 | 1-Projet | Sejour cuisine | B05 | rdc | 3
Mur-149 | rdc | 0 | 0 | 3000 | 3000 | 0 | 0 | 0.148858 | 0 | 0 | 708.846 | 2.23191 | 2.02117 | 0 | 743.969 | 743.969 | 2.23191 | 673.724 | 2.02117 | 0.148858 | 2.23191 | 2.02117 | 743.969 | 673.724 | 0 | 0.0496192 | 3000 | 0.148858 | 3000 | 743.969 | 0.148858 | 1586.86 | 6000 | 3000 | 3000 | 0 | 0.606744 | Face intérieure | Surface-Blanche | Mur-149 | 1-Projet | Sdb | B03 | rdc | 3
Mur-149 | rdc | 0 | 0 | 2500 | 2500 | 0 | 0 | 0.0623494 | 0 | 0 | 356.282 | 0.803206 | 0.628206 | 0 | 391.282 | 391.282 | 0.803206 | 321.282 | 0.628206 | 0.0623494 | 0.978206 | 0.803206 | 391.282 | 321.282 | 0 | 0.0249398 | 2500 | 0.0623494 | 3000 | 391.282 | 0.0623494 | 881.56 | 5500 | 2500 | 3000 | 0 | 0.472367 | Face intérieure | Surface-Blanche | Mur-149 | 1-Projet | Sde | B04 | rdc | 3
Mur-149 | rdc | 0 | 0 | 2700 | 2700 | 0 | 0 | 0.11177 | 0 | 0 | 567.673 | 1.69129 | 1.50214 | 0 | 922.7 | 602.7 | 1.69129 | 532.646 | 1.50214 | 0.11177 | 1.69129 | 1.50214 | 602.7 | 532.646 | 0 | 0.0621364 | 2700 | 0.11177 | 3000 | 922.7 | 0.11177 | 1304.38 | 5700 | 2700 | 3000 | -4.44089e-13 | 0.580658 | Face intérieure | Surface-Blanche | Mur-149 | 1-Projet | Pl | 819 | rdc | 3
Mur-149 | rdc | 0 | 0 | 2700 | 2700 | 0 | 0 | 0.0558651 | 0 | 0 | 295.452 | 0.892292 | 0.703853 | 0 | 330.478 | 330.478 | 0.892292 | 260.426 | 0.703853 | 0.0558651 | 0.892292 | 0.703853 | 330.478 | 260.426 | 0 | 0.0231552 | 2700 | 0.0558651 | 3000 | 401.153 | 0.0558651 | 759.938 | 5700 | 2700 | 3000 | 0 | 0.502994 | Face intérieure | Surface-Blanche | Mur-149 | 1-Projet | Pl | 819 | rdc | 3
Mur-149 | rdc | 0 | 0 | 3000 | 3000 | 0 | 0 | 0.137107 | 0 | 0 | 622.488 | 1.95866 | 1.95867 | 0 | 922.487 | 622.488 | 1.95866 | 622.488 | 1.95867 | 0.137107 | 1.95866 | 1.95867 | 622.488 | 622.488 | 0 | 0.0645741 | 3000 | 0.137107 | 3000 | 922.487 | 0.137107 | 1384.98 | 6000 | 3000 | 3000 | 0 | 0.549154 | Face intérieure | Surface-Blanche | Mur-149 | 1-Projet |  |  | rdc | 3
Mur-149 | rdc | 0 | 0 | 3000 | 3000 | 0 | 0 | 0.0914496 | 0 | 0 | 435.489 | 1.4114 | 1.20144 | 0 | 470.468 | 470.468 | 1.4114 | 400.51 | 1.20144 | 0.0914496 | 1.4114 | 1.20144 | 470.468 | 400.51 | 0 | 0.0304842 | 3000 | 0.0914496 | 3000 | 470.756 | 0.0914496 | 1040.15 | 6000 | 3000 | 3000 | 0 | 0.568476 | Face intérieure | Surface-Blanche | Mur-149 | 1-Projet | Sdb | B03 | rdc | 3
Mur-149 | rdc | 0 | 0 | 2700 | 2300 | 0 | 0 | 0.12172 | 0 | 0 | 644.023 | 1.7388 | 1.7389 | 0 | 714.002 | 644.002 | 1.7388 | 644.044 | 1.7389 | 0.12172 | 1.7388 | 1.73891 | 644.002 | 644.044 | 0 | 0.0450816 | 2700 | 0.12172 | 3000 | 644.044 | 0.12172 | 1428.05 | 5700 | 2700 | 3000 | 0 | 0.456762 | Face intérieure | Peinture-01 | Mur-149 | 1-Projet | Sejour cuisine/pl | B04 | rdc | 3
Mur-149 | rdc | 3 | 0 | 2500 | 2500 | 5.0796 | 2490 | 1.12354 | 5.6784 | 5.6784 | 8771.58 | 15.2631 | 15.7881 | 0.397488 | 9066.58 | 5926.58 | 20.9415 | 6156.58 | 21.4665 | 1.52103 | 21.6415 | 21.8165 | 8656.58 | 8886.58 | 0 | 0.417311 | 2500 | 1.12354 | 3000 | 8726.58 | 1.52103 | 17816.8 | 5500 | 2500 | 3000 | 0 | 1.44821 | Face intérieure | Peinture-01 | Mur-149 | 1-Projet | Sdb | B03 | rdc | 3
Mur-149 | rdc | 0 | 0 | 2700 | 2700 | 0 | 0 | 0.0634704 | 0 | 0 | 335.692 | 1.00004 | 0.813404 | 0 | 370.383 | 370.383 | 1.00004 | 301.001 | 0.813404 | 0.0634704 | 1.00004 | 0.813404 | 370.383 | 301.001 | 0 | 0.0259505 | 2700 | 0.0634704 | 3000 | 441.058 | 0.0634704 | 840.382 | 5700 | 2700 | 3000 | 0 | 0.508489 | Face intérieure | Surface-Blanche | Mur-149 | 1-Projet | Pl | 819 | rdc | 3 | ArchiCADProperties - Zones conflictuelles: Pl
Mur-149 | rdc | 0 | 0 | 2700 | 2700 | 0 | 0 | 0.0751457 | 0 | 0 | 397.596 | 1.16884 | 0.978175 | 0 | 752.917 | 432.905 | 1.16884 | 362.287 | 0.978175 | 0.0751457 | 1.16884 | 0.978175 | 432.905 | 362.287 | 0 | 0.0278317 | 2700 | 0.0751457 | 3000 | 432.905 | 0.0751457 | 964.19 | 5700 | 2700 | 3000 | 0 | 0.511957 | Face intérieure | Surface-Blanche | Mur-149 | 1-Projet | Pl | 819 | rdc | 3 | ArchiCADProperties - Zones conflictuelles: Pl
Mur-121 | rdc | 0 | 0 | 2500 | 2500 | 0 | 0 | 0.0700172 | 0 | 0 | 400.098 | 0.825245 | 0.825245 | 0 | 580.098 | 400.098 | 0.825245 | 400.098 | 0.825245 | 0.0700172 | 1.00025 | 1.00025 | 400.098 | 400.098 | 0 | 0.0280069 | 2500 | 0.0700172 | 3000 | 400.098 | 0.0700172 | 940.196 | 5500 | 2500 | 3000 | 0 | 0.406014 | Face extérieure | Lavis blanc | Mur-121 | 1-Projet |  |  | rdc | 3
Mur-121 | rdc | 0 | 0 | 3000 | 3000 | 0 | 0 | 0.0693254 | 0 | 0 | 330.121 | 0.990363 | 0.990363 | 0 | 400.121 | 330.121 | 0.990363 | 330.121 | 0.990363 | 0.0693254 | 0.990363 | 0.990363 | 330.121 | 330.121 | 0 | 0.0231085 | 3000 | 0.0693254 | 3000 | 330.121 | 0.0693254 | 800.242 | 6000 | 3000 | 3000 | 0 | 0.466217 | Face extérieure | Lavis blanc | Mur-121 | 1-Projet |  |  | rdc | 3
Mur-149 | rdc | 0 | 0 | 2700 | 2300 | 0 | 0 | 0.247225 | 0 | 0 | 1389.55 | 3.84628 | 3.45037 | 0 | 1424.55 | 1424.55 | 3.84628 | 1354.54 | 3.45037 | 0.247225 | 3.84628 | 3.67128 | 1424.55 | 1354.54 | 0 | 0.0997184 | 2700 | 0.247225 | 3000 | 1424.55 | 0.263115 | 2948.09 | 5700 | 2700 | 3000 | 0 | 0.616255 | Face intérieure | Peinture-01 | Mur-149 | 1-Projet | Cellier | B04 | rdc | 3 | ArchiCADProperties - Zones conflictuelles: Sejour cuisine/pl
Mur-149 | rdc | 1 | 0 | 2700 | 2700 | 1.68669 | 843.343 | 0.100789 | 1.60669 | 1.60669 | 1128.34 | 1.53434 | 1.15634 | 0.112468 | 1163.34 | 360 | 3.14103 | 290 | 2.76303 | 0.213257 | 3.14103 | 2.95203 | 1163.34 | 1093.34 | 0 | 0.02275 | 2700 | 0.100789 | 3000 | 1163.34 | 0.213257 | 2425.68 | 5700 | 2700 | 3000 | 0 | 0.41802 | Face intérieure | Peinture-01 | Mur-149 | 1-Projet | Entree/pl | B05 | rdc | 3
Mur-149 | rdc | 0 | 0 | 2700 | 0 | 0 | 0 | 0.159106 | 0 | 0 | 898.496 | 2.27294 | 2.27294 | 0 | 1078.5 | 898.496 | 2.27294 | 898.496 | 2.27294 | 0.159106 | 2.27294 | 2.27294 | 898.496 | 898.496 | 0 | 0.0705947 | 2700 | 0.159106 | 3000 | 1008.5 | 0.159106 | 1936.99 | 5700 | 2700 | 3000 | 0 | 0.519189 | Face intérieure | Peinture-01 | Mur-149 | 1-Projet | Sdb | B05 | rdc | 3 | ArchiCADProperties - Zones conflictuelles: Sdb
Mur-149 | rdc | 0 | 0 | 2512.25 | 2512.25 | 0 | 0 | 0.11167 | 0 | 0 | 635 | 1.68321 | 1.50735 | 0 | 670 | 670 | 1.68321 | 600 | 1.50735 | 0.11167 | 1.68321 | 1.50735 | 670 | 600 | 0 | 0.04445 | 2512.25 | 0.11167 | 3000 | 670 | 0.11167 | 1438.99 | 5512.25 | 2512.25 | 3000 | 0 | 0.513458 | Face intérieure | Surface-Blanche | Mur-149 | 1-Projet | Ch 1/pl | B02 | rdc | 3
Mur-149 | rdc | 1 | 0 | 2512.25 | 2512.25 | 3.10624 | 1553.12 | 0.0604119 | 3.02624 | 3.02624 | 1548.12 | 0.950955 | 0.775098 | 0.211837 | 1583.12 | 70 | 0.950955 | 0 | 0.775098 | 0.272249 | 3.9772 | 3.80134 | 1583.12 | 1513.12 | 0 | 0.00245 | 2512.25 | 0.0604119 | 3000 | 1583.12 | 0.272249 | 3265.24 | 5512.25 | 2512.25 | 3000 | 0 | 0.395376 | Face intérieure | Surface-Blanche | Mur-149 | 1-Projet | Ch 1/pl | B02 | rdc | 3
Mur-149 | rdc | 0 | 0 | 2700 | 2700 | 0 | 0 | 0.1134 | 0 | 0 | 600 | 1.62 | 1.62 | 0 | 670 | 600 | 1.62 | 600 | 1.62 | 0.1134 | 1.62 | 1.62 | 600 | 600 | 0 | 0.042 | 2700 | 0.1134 | 3000 | 600 | 0.1134 | 1340 | 5700 | 2700 | 3000 | 0 | 0.462 | Face intérieure | Peinture-01 | Mur-149 | 1-Projet |  |  | rdc | 3
Mur-149 | rdc | 0 | 0 | 3000 | 3000 | 0 | 0 | 0.341674 | 0 | 0 | 1590.02 | 4.88106 | 4.88106 | 0 | 1840.02 | 1590.02 | 4.88106 | 1590.02 | 4.88106 | 0.341674 | 4.88106 | 4.88106 | 1590.02 | 1590.02 | 0 | 0.128801 | 3000 | 0.341674 | 3000 | 1840.02 | 0.341674 | 3320.04 | 6000 | 3000 | 3000 | 0 | 0.677603 | Face intérieure | Surface-Blanche | Mur-149 | 1-Projet | Sdb | B03 | rdc | 3
Mur-148 | rdc | 1 | 0 | 3000 | 0 | 0.2925 | 450 | 0.30735 | 0.3283 | 0.3283 | 1625 | 4.30671 | 3.90772 | 0.022981 | 1840 | 1660 | 4.63501 | 1590 | 4.23602 | 0.330331 | 4.82401 | 4.61402 | 1660 | 1590 | 0 | 0.121451 | 3000 | 0.30735 | 3000 | 1770.02 | 0.330331 | 3418.99 | 6000 | 3000 | 3000 | 0 | 0.749853 | Face intérieure | Surface-Blanche | Mur-148 | 1-Projet | Sdb/pl | A02 | rdc | 3 | ArchiCADProperties - Zones conflictuelles: Sdb/pl; Sde
Mur-152 | rdc | 0 | 0 | 3000 | 2100 | 0 | 0 | 0.236744 | 0 | 0 | 1164.86 | 3.49457 | 3.0516 | 0 | 1414.86 | 1164.86 | 3.49457 | 1164.86 | 3.0516 | 0.236744 | 3.49457 | 3.49457 | 1164.86 | 1164.86 | 0 | 0.0815401 | 3000 | 0.236744 | 3000 | 1164.86 | 0.24462 | 2469.72 | 6000 | 3000 | 3000 | 0 | 0.569557 | Face extérieure | Peinture-01 | Mur-152 | 1-Projet | Sejour cuisine | A03 | rdc | 3
Mur-152 | rdc | 0 | 0 | 3000 | 3000 | 0 | 0 | 0.0304683 | 0 | 0 | 145.087 | 0.0602645 | 0.810257 | 0 | 340.086 | 20.0882 | 0.0602645 | 270.086 | 0.810257 | 0.0304683 | 0.0602645 | 0.810257 | 20.0882 | 270.086 | 0 | 0.0101561 | 3000 | 0.0304683 | 3000 | 270.088 | 0.0304683 | 619.789 | 6000 | 3000 | 3000 | 0 | 1.00916 | Face extérieure | Peinture-01 | Mur-152 | 1-Projet | Sejour cuisine | A03 | rdc | 3
Mur-149 | rdc | 0 | 0 | 2700 | 2700 | 0 | 0 | 0.219983 | 0 | 0 | 1163.93 | 2.95362 | 3.14262 | 0 | 1503.93 | 1163.93 | 2.95362 | 1163.93 | 3.14262 | 0.219983 | 3.14262 | 3.14262 | 1163.93 | 1163.93 | 0 | 0.0814752 | 2700 | 0.219983 | 3000 | 1163.93 | 0.219983 | 2467.86 | 5700 | 2700 | 3000 | 0 | 0.54095 | Face intérieure | Peinture-01 | Mur-149 | 1-Projet | Ch 3 | B03 | rdc | 3
Mur-149 | rdc | 0 | 0 | 3000 | 3000 | 0 | 0 | 0.147901 | 0 | 0 | 674.29 | 2.00796 | 2.21778 | 0 | 819.318 | 639.32 | 2.00796 | 709.26 | 2.21778 | 0.147901 | 2.00796 | 2.21778 | 639.32 | 709.26 | 0 | 0.0598001 | 3000 | 0.147901 | 3000 | 889.258 | 0.147901 | 1517.53 | 6000 | 3000 | 3000 | 0 | 0.626457 | Face intérieure | Surface-Blanche | Mur-149 | 1-Projet | Cellier | B03 | rdc | 3 | ArchiCADProperties - Zones conflictuelles: Cellier
Mur-149 | rdc | 0 | 0 | 2700 | 2700 | 0 | 0 | 0.30986 | 0 | 0 | 1639.47 | 4.52107 | 4.33207 | 0 | 1604.47 | 1674.47 | 4.52107 | 1604.47 | 4.33207 | 0.30986 | 4.52107 | 4.33207 | 1674.47 | 1604.47 | 0 | 0.114763 | 2700 | 0.30986 | 3000 | 1674.47 | 0.30986 | 3447.94 | 5700 | 2700 | 3000 | 0 | 0.685812 | Face intérieure | Peinture-01 | Mur-149 | 1-Projet | Wc | B04 | rdc | 3
Mur-150 | rdc | 0 | 0 | 3000 | 3000 | 0 | 0 | 0.0438144 | 0 | 0 | 208.64 | 0.730841 | 0.521 | 0 | 243.614 | 243.614 | 0.730841 | 173.667 | 0.521 | 0.0438144 | 0.730841 | 0.521 | 243.614 | 173.667 | 0 | 0.0146048 | 3000 | 0.0438144 | 3000 | 243.614 | 0.0438144 | 586.238 | 6000 | 3000 | 3000 | 0 | 0.536082 | Face intérieure | Surface-Blanche | Mur-150 | 1-Projet |  |  | rdc | 3
Mur-149 | rdc | 0 | 0 | 3000 | 3000 | 0 | 0 | 0.0477887 | 0 | 0 | 227.568 | 0.577705 | 0.787687 | 0 | 192.568 | 192.568 | 0.577705 | 262.568 | 0.787687 | 0.0477887 | 0.577705 | 0.787687 | 192.568 | 262.568 | 0 | 0.0159298 | 3000 | 0.0477887 | 3000 | 262.568 | 0.0477887 | 624.089 | 6000 | 3000 | 3000 | 0 | 0.538717 | Face intérieure | Surface-Blanche | Mur-149 | 1-Projet |  |  | rdc | 3 | ArchiCADProperties - Zones conflictuelles: Cellier
Mur-149 | rdc | 0 | 0 | 2700 | 2700 | 0 | 0 | 0.053865 | 0 | 0 | 285 | 0.864 | 0.675 | 0 | 320 | 320 | 0.864 | 250 | 0.675 | 0.053865 | 0.864 | 0.675 | 320 | 250 | 0 | 0.01995 | 2700 | 0.053865 | 3000 | 320 | 0.053865 | 738.995 | 5700 | 2700 | 3000 | 0 | 0.496186 | Face intérieure | Peinture-01 | Mur-149 | 1-Projet |  |  | rdc | 3
Mur-121 | rdc | 0 | 0 | 3000 | 3000 | 0 | 0 | 0.0755995 | 0 | 0 | 329.988 | 1.07997 | 1.07997 | 0 | 579.993 | 329.987 | 1.07997 | 329.989 | 1.07997 | 0.0755995 | 1.07997 | 1.07997 | 329.987 | 329.989 | 0 | 0.0357002 | 3000 | 0.0755995 | 3000 | 509.997 | 0.0755995 | 799.976 | 6000 | 3000 | 3000 | 0 | 0.491409 | Face extérieure | Lavis blanc | Mur-121 | 1-Projet | Sejour cuisine | B02 | rdc | 3
Mur-121 | rdc | 0 | 0 | 3000 | 3000 | 0 | 0 | 0.119409 | 0 | 0 | 553.614 | 1.45084 | 1.75084 | 0 | 553.614 | 553.613 | 1.45084 | 553.614 | 1.75084 | 0.119409 | 1.66084 | 1.75084 | 553.613 | 553.614 | 0 | 0.045053 | 3000 | 0.119409 | 3000 | 733.614 | 0.119409 | 1247.23 | 6000 | 3000 | 3000 | 0 | 0.571673 | Face extérieure | Lavis blanc | Mur-121 | 1-Projet | Sejour cuisine | B02 | rdc | 3
Mur-149 | Etage1 | 1 | 0 | 2700 | 2700 | 1.6932 | 830 | 0.234182 | 1.8928 | 1.8928 | 1940.1 | 2.98996 | 2.80096 | 0.132496 | 1975.1 | 1065.1 | 4.88276 | 995.095 | 4.69376 | 0.366678 | 5.33276 | 5.14376 | 1975.1 | 1905.1 | 0 | 0.0721067 | 2700 | 0.234182 | 5750 | 1975.1 | 0.366678 | 4049.19 | 8450 | 2700 | 5750 | 0 | 0.6642 | Face intérieure | Peinture-01 | Mur-149 | 1-Projet | Wc | B12 | Etage1 | 4 | ArchiCADProperties - Zones conflictuelles: Wc
Mur-149 | rdc | 0 | 0 | 2700 | 2700 | 0 | 0 | 0.07749 | 0 | 0 | 410 | 1.2015 | 1.0125 | 0 | 445 | 445 | 1.2015 | 375 | 1.0125 | 0.07749 | 1.2015 | 1.0125 | 445 | 375 | 0 | 0.0287 | 2700 | 0.07749 | 3000 | 445 | 0.07749 | 988.995 | 5700 | 2700 | 3000 | 0 | 0.513686 | Face intérieure | Peinture-01 | Mur-149 | 1-Projet |  |  | rdc | 3
Mur-148 | Etage1 | 0 | 0 | 2700 | 2700 | 0 | 0 | 0.156863 | 0 | 0 | 830.003 | 2.241 | 2.24102 | 0 | 900 | 830 | 2.241 | 830.006 | 2.24102 | 0.156863 | 2.241 | 2.24102 | 830 | 830.006 | 0 | 0.0580975 | 2700 | 0.156863 | 5750 | 830.006 | 0.156863 | 1800.01 | 8450 | 2700 | 5750 | 0 | 0.494178 | Face intérieure | Surface-Blanche | Mur-148 | 1-Projet | Sde | A12 | Etage1 | 4 | ArchiCADProperties - Zones conflictuelles: Sde
Mur-152 | Etage1 | 0 | 0 | 3000 | 3000 | 0 | 0 | 0.24462 | 0 | 0 | 1164.86 | 3.07457 | 3.28457 | 0 | 1164.86 | 1164.86 | 3.07457 | 1164.86 | 3.28457 | 0.24462 | 3.49457 | 3.49457 | 1164.86 | 1164.86 | 0 | 0.0815401 | 3000 | 0.24462 | 5750 | 1164.86 | 0.24462 | 2469.72 | 8750 | 3000 | 5750 | 0 | 0.58308 | Face extérieure | Peinture-01 | Mur-152 | 1-Projet | Ch 1 | A13 | Etage1 | 4
Mur-149 | Etage1 | 0 | 0 | 2700 | 2700 | 0 | 0 | 0.428363 | 0 | 0 | 2266.47 | 6.11948 | 6.11947 | 0 | 2336.48 | 2266.48 | 6.11948 | 2266.47 | 6.11947 | 0.428363 | 6.11948 | 6.11947 | 2266.48 | 2266.47 | 0 | 0.158653 | 2700 | 0.428363 | 5750 | 2266.49 | 0.428363 | 4672.95 | 8450 | 2700 | 5750 | 0 | 0.695306 | Face intérieure | Surface-Blanche | Mur-149 | 1-Projet | Ch 1 | A12 | Etage1 | 4 | ArchiCADProperties - Zones conflictuelles: Sde
Mur-149 | Etage1 | 0 | 0 | 2700 | 0 | 0 | 0 | 0.33457 | 0 | 0 | 1840.21 | 4.32957 | 4.32957 | 0 | 1840.21 | 1840.21 | 4.32957 | 1840.21 | 4.32957 | 0.33457 | 4.77957 | 4.77957 | 1840.21 | 1840.21 | 0 | 0.123915 | 2700 | 0.33457 | 5750 | 1770.22 | 0.33457 | 3820.42 | 8450 | 2700 | 5750 | 0 | 0.62583 | Face intérieure | Surface-Blanche | Mur-149 | 1-Projet | Entree/pl | B14 | Etage1 | 4
Mur-149 | Etage1 | 0 | 0 | 2700 | 2700 | 0 | 0 | 0.0909891 | 0 | 0 | 481.424 | 1.39434 | 1.20535 | 0 | 516.427 | 516.424 | 1.39434 | 446.424 | 1.20535 | 0.0909891 | 1.39434 | 1.20535 | 516.424 | 446.424 | 0 | 0.0336997 | 2700 | 0.0909891 | 5750 | 516.424 | 0.0909891 | 1131.82 | 8450 | 2700 | 5750 | -8.88178e-13 | 0.523613 | Face intérieure | Peinture-01 | Mur-149 | 1-Projet | Cellier | A14 | Etage1 | 4
Mur-148 | Etage1 | 0 | 0 | 3000 | 0 | 0 | 0 | 0.122043 | 0 | 0 | 761.157 | 1.84841 | 1.63853 | 0 | 796.136 | 796.136 | 1.84841 | 726.178 | 1.63853 | 0.122043 | 1.84841 | 1.63853 | 796.136 | 726.178 | 0 | 0.040681 | 3000 | 0.122043 | 5750 | 616.157 | 0.122043 | 1691.28 | 8750 | 3000 | 5750 | 0 | 0.58826 | Face intérieure | Surface-Blanche | Mur-148 | 1-Projet | Sejour cuisine | A13 | Etage1 | 4
Mur-149 | Etage1 | 0 | 0 | 3000 | 0 | 0 | 0 | 0.29435 | 0 | 0 | 1540 | 4.205 | 4.205 | 0 | 1610 | 1540 | 4.205 | 1540 | 4.205 | 0.29435 | 4.205 | 4.205 | 1540 | 1540 | 0 | 0.1127 | 3000 | 0.29435 | 5750 | 1610 | 0.29435 | 3220 | 8750 | 3000 | 5750 | 0 | 0.4578 | Face intérieure | Surface-Blanche | Mur-149 | 1-Projet | Cellier | B13 | Etage1 | 4
Mur-149 | Etage1 | 0 | 1 | 3000 | 3000 | 0 | 0 | 0.856131 | 2.7163 | 2.7163 | 4982.24 | 12.2304 | 11.8104 | 0.190141 | 4982.24 | 3650.73 | 12.2304 | 3650.73 | 11.8104 | 1.04627 | 14.9467 | 14.9467 | 4982.24 | 4982.24 | 2.7163 | 0.255551 | 3000 | 0.856131 | 5750 | 4982.24 | 1.04627 | 10104.5 | 8750 | 3000 | 5750 | 0 | 1.02431 | Face intérieure | Surface-Blanche | Mur-149 | 1-Projet | Sejour cuisine | B12 | Etage1 | 4
Mur-153 | Etage1 | 1 | 0 | 3000 | 3000 | 1.1832 | 580 | 0.068173 | 1.23 | 1.23 | 734.633 | 1.0789 | 0.6589 | 0.0861 | 699.633 | 169.633 | 2.3089 | 99.6332 | 1.8889 | 0.154273 | 2.3089 | 2.0989 | 769.633 | 699.633 | 0 | 0.00942433 | 3000 | 0.068173 | 5750 | 769.633 | 0.154273 | 1638.26 | 8750 | 3000 | 5750 | 0 | 0.567834 | Face extérieure | Peinture-01 | Mur-153 | 1-Projet | Sejour cuisine | A13 | Etage1 | 4
Mur-149 | Etage1 | 0 | 0 | 3000 | 3000 | 0 | 0 | 0.187949 | 0 | 0 | 865 | 2.79 | 2.57998 | 0 | 1080 | 900 | 2.79 | 830 | 2.57998 | 0.187949 | 2.79 | 2.57998 | 900 | 830 | 0 | 0.0731489 | 3000 | 0.187949 | 5750 | 1080 | 0.187949 | 1899.02 | 8750 | 3000 | 5750 | 0 | 0.653352 | Face intérieure | Surface-Blanche | Mur-149 | 1-Projet | Sde | B13 | Etage1 | 4 | ArchiCADProperties - Zones conflictuelles: Sde
Mur-149 | Etage1 | 0 | 0 | 3000 | 3000 | 0 | 0 | 0.140333 | 0 | 0 | 668.251 | 1.89975 | 2.10975 | 0 | 703.251 | 633.251 | 1.89975 | 703.251 | 2.10975 | 0.140333 | 1.89975 | 2.10975 | 633.251 | 703.251 | 0 | 0.0467776 | 3000 | 0.140333 | 5750 | 703.251 | 0.140333 | 1505.5 | 8750 | 3000 | 5750 | 0 | 0.60054 | Face intérieure | Surface-Blanche | Mur-149 | 1-Projet | Sejour Cuisine | B13 | Etage1 | 4
Mur-149 | Etage1 | 0 | 0 | 2700 | 2700 | 0 | 0 | 0.161516 | 0 | 0 | 854.584 | 1.95188 | 1.76288 | 0 | 889.584 | 889.584 | 1.95188 | 819.584 | 1.76288 | 0.161516 | 2.40188 | 2.21288 | 889.584 | 819.584 | 0 | 0.0598209 | 2700 | 0.161516 | 5750 | 889.584 | 0.161516 | 1878.16 | 8450 | 2700 | 5750 | 0 | 0.575929 | Face intérieure | Surface-Blanche | Mur-149 | 1-Projet | Cellier | B14 | Etage1 | 4 | ArchiCADProperties - Zones conflictuelles: Cellier
Mur-150 | Etage1 | 0 | 0 | 3000 | 3000 | 0 | 0 | 0.0829742 | 0 | 0 | 395.103 | 1.29031 | 1.08038 | 0 | 430.104 | 430.104 | 1.29031 | 360.101 | 1.08038 | 0.0829742 | 1.29031 | 1.08038 | 430.104 | 360.101 | 0 | 0.0276678 | 3000 | 0.0829742 | 5750 | 430.104 | 0.0829742 | 958.776 | 8750 | 3000 | 5750 | 0 | 0.561046 | Face intérieure | Surface-Blanche | Mur-150 | 1-Projet | Sde | B13 | Etage1 | 4
Mur-149 | Etage1 | 0 | 0 | 3000 | 3000 | 0 | 0 | 0.538833 | 0 | 0 | 2571.56 | 7.39968 | 7.78554 | 0 | 2536.56 | 2536.56 | 7.39968 | 2606.56 | 7.78554 | 0.538833 | 7.60968 | 7.78554 | 2536.56 | 2606.56 | 0 | 0.180009 | 3000 | 0.538833 | 5750 | 2606.56 | 0.538833 | 5312.12 | 8750 | 3000 | 5750 | 0 | 0.852861 | Face intérieure | Surface-Blanche | Mur-149 | 1-Projet | Sejour Cuisine | B13 | Etage1 | 4
Mur-149 | Etage1 | 0 | 0 | 2700 | 2700 | 0 | 0 | 0.0430913 | 0 | 0 | 227.996 | 0.710087 | 0.521092 | 0 | 332.995 | 262.995 | 0.710087 | 192.997 | 0.521092 | 0.0430913 | 0.710087 | 0.521092 | 262.995 | 192.997 | 0 | 0.0159597 | 2700 | 0.0430913 | 5750 | 262.998 | 0.0430913 | 624.988 | 8450 | 2700 | 5750 | 0 | 0.488207 | Face intérieure | Surface-Blanche | Mur-149 | 1-Projet |  |  | Etage1 | 4 | ArchiCADProperties - Zones conflictuelles: Cellier
Mur-149 | Etage1 | 0 | 0 | 2700 | 2700 | 0 | 0 | 0.0954478 | 0 | 0 | 505.015 | 1.458 | 1.08008 | 0 | 540 | 540 | 1.458 | 470.03 | 1.08008 | 0.0954478 | 1.458 | 1.26908 | 540 | 470.03 | 0 | 0.035351 | 2700 | 0.0954478 | 5750 | 540 | 0.0954478 | 1179 | 8450 | 2700 | 5750 | 0 | 0.52693 | Face intérieure | Peinture-01 | Mur-149 | 1-Projet | Sejour cuisine | B15 | Etage1 | 4
Mur-149 | Etage1 | 0 | 0 | 2700 | 2700 | 0 | 0 | 0.0558414 | 0 | 0 | 295.457 | 0.892292 | 0.703176 | 0 | 330.478 | 330.478 | 0.892292 | 260.436 | 0.703176 | 0.0558414 | 0.892292 | 0.703176 | 330.478 | 260.436 | 0 | 0.020682 | 2700 | 0.0558414 | 5750 | 330.489 | 0.0558414 | 759.947 | 8450 | 2700 | 5750 | -8.88178e-13 | 0.497753 | Face intérieure | Surface-Blanche | Mur-149 | 1-Projet | Sde | B11 | Etage1 | 4
Mur-149 | Etage1 | 0 | 1 | 3000 | 3000 | 0 | 0 | 0.400997 | 2.26017 | 2.26017 | 2651.52 | 5.51853 | 5.55353 | 0.158212 | 2721.52 | 1543.59 | 5.51853 | 1543.59 | 5.55353 | 0.559209 | 7.9887 | 7.9887 | 2651.52 | 2651.52 | 2.26017 | 0.112951 | 3000 | 0.400997 | 5750 | 2721.52 | 0.559209 | 5443.04 | 8750 | 3000 | 5750 | 0 | 0.580658 | Face intérieure | Surface-Blanche | Mur-149 | 1-Projet | Wc | B13 | Etage1 | 4
Mur-149 | Etage1 | 0 | 0 | 3000 | 3000 | 0 | 0 | 0.35271 | 0 | 0 | 1679.57 | 4.93372 | 4.93371 | 0 | 1784.57 | 1644.57 | 4.93372 | 1714.57 | 4.93371 | 0.35271 | 4.93372 | 5.14371 | 1644.57 | 1714.57 | 0 | 0.11757 | 3000 | 0.35271 | 5750 | 1714.57 | 0.35271 | 3528.14 | 8750 | 3000 | 5750 | -8.88178e-13 | 0.742124 | Face extérieure | Lavis blanc | Mur-149 | 1-Projet | Sejour cuisine | B12 | Etage1 | 4
Mur-121 | Etage1 | 0 | 0 | 3000 | 3000 | 0 | 0 | 0.100726 | 0 | 0 | 479.648 | 1.33401 | 1.54388 | 0 | 584.628 | 444.669 | 1.33401 | 514.628 | 1.54388 | 0.100726 | 1.33401 | 1.54388 | 444.669 | 514.628 | 0 | 0.0335754 | 3000 | 0.100726 | 5750 | 514.628 | 0.100726 | 1128.26 | 8750 | 3000 | 5750 | 0 | 0.574048 | Face extérieure | Lavis blanc | Mur-121 | 1-Projet | Sejour cuisine | A13 | Etage1 | 4
Mur-150 | Etage1 | 0 | 0 | 3000 | 3000 | 0 | 0 | 0.187871 | 0 | 0 | 864.622 | 2.78796 | 2.57977 | 0 | 1079.32 | 899.32 | 2.78796 | 829.925 | 2.57977 | 0.187871 | 2.78796 | 2.57977 | 899.32 | 829.925 | 0 | 0.0731236 | 3000 | 0.187871 | 5750 | 1079.32 | 0.187871 | 1897.81 | 8750 | 3000 | 5750 | 0 | 0.65195 | Face intérieure | Surface-Blanche | Mur-150 | 1-Projet |  |  | Etage1 | 4
Mur-149 | Etage1 | 1 | 0 | 2500 | 2500 | 1.6932 | 830 | 0.311956 | 1.8928 | 1.8928 | 2539.73 | 4.54402 | 4.19402 | 0.132496 | 2644.73 | 1664.73 | 6.43682 | 1594.73 | 6.08682 | 0.444452 | 6.43682 | 6.26182 | 2574.73 | 2504.73 | 0 | 0.114081 | 2500 | 0.311956 | 5750 | 2574.73 | 0.444452 | 5248.45 | 8250 | 2500 | 5750 | 0 | 0.714349 | Face intérieure | Surface-Blanche | Mur-149 | 1-Projet | Cellier | B13 | Etage1 | 4
Mur-149 | Etage1 | 0 | 0 | 2700 | 2700 | 0 | 0 | 0.110953 | 0 | 0 | 587.052 | 1.49049 | 1.30159 | 0 | 622.033 | 622.033 | 1.49049 | 552.071 | 1.30159 | 0.110953 | 1.67949 | 1.49059 | 622.033 | 552.071 | 0 | 0.0410936 | 2700 | 0.110953 | 5750 | 622.033 | 0.110953 | 1343.07 | 8450 | 2700 | 5750 | 0 | 0.538401 | Face intérieure | Peinture-01 | Mur-149 | 1-Projet | Wc | A14 | Etage1 | 4 | ArchiCADProperties - Zones conflictuelles: Wc
Mur-153 | Etage1 | 2 | 0 | 2700 | 2700 | 3.3864 | 1660 | 0.774271 | 3.7856 | 3.7856 | 5498.75 | 10.683 | 10.872 | 0.264992 | 5498.75 | 3678.75 | 14.4686 | 3678.75 | 14.6576 | 1.03926 | 14.8466 | 14.8466 | 5498.75 | 5498.75 | 0 | 0.257512 | 2700 | 0.774271 | 5750 | 5498.75 | 1.03926 | 11137.5 | 8450 | 2700 | 5750 | 0 | 1.02042 | Face extérieure | Peinture-01 | Mur-153 | 1-Projet | Ch 2 | A14 | Etage1 | 4
Mur-149 | Etage1 | 0 | 0 | 3000 | 0 | 0 | 0 | 0.124599 | 0 | 0 | 628.555 | 1.88498 | 1.67498 | 0 | 593.555 | 663.555 | 1.88498 | 593.555 | 1.67498 | 0.124599 | 1.88498 | 1.67498 | 663.555 | 593.555 | 0 | 0.0415329 | 3000 | 0.124599 | 5750 | 628.327 | 0.124599 | 1426.11 | 8750 | 3000 | 5750 | 0 | 0.380051 | Face intérieure | Surface-Blanche | Mur-149 | 1-Projet | Sejour Cuisine | B13 | Etage1 | 4
Mur-149 | Etage1 | 0 | 0 | 2700 | 2700 | 0 | 0 | 0.11793 | 0 | 0 | 623.967 | 1.77921 | 1.59021 | 0 | 658.967 | 658.967 | 1.77921 | 588.967 | 1.59021 | 0.11793 | 1.77921 | 1.59021 | 658.967 | 588.967 | 0 | 0.0436777 | 2700 | 0.11793 | 5750 | 658.967 | 0.11793 | 1416.93 | 8450 | 2700 | 5750 | 0 | 0.543642 | Face intérieure | Surface-Blanche | Mur-149 | 1-Projet | Ch 1 | B11 | Etage1 | 4
Mur-121 | Etage1 | 0 | 0 | 3000 | 0 | 0 | 0 | 0.0780706 | 0 | 0 | 400.098 | 1.11529 | 1.11529 | 0 | 580.098 | 400.098 | 1.11529 | 400.098 | 1.11529 | 0.0780706 | 1.11529 | 1.11529 | 400.098 | 400.098 | 0 | 0.0406069 | 3000 | 0.0780706 | 5750 | 580.098 | 0.0780706 | 940.196 | 8750 | 3000 | 5750 | 0 | 0.496314 | Face extérieure | Lavis blanc | Mur-121 | 1-Projet |  |  | Etage1 | 4
Mur-149 | Etage1 | 0 | 0 | 2700 | 2700 | 0 | 0 | 0.13375 | 0 | 0 | 707.673 | 2.00529 | 1.81614 | 0 | 742.7 | 742.7 | 2.00529 | 672.646 | 1.81614 | 0.13375 | 2.00529 | 1.81614 | 742.7 | 672.646 | 0 | 0.0495371 | 2700 | 0.13375 | 5750 | 742.7 | 0.13375 | 1584.38 | 8450 | 2700 | 5750 | 0 | 0.555463 | Face intérieure | Surface-Blanche | Mur-149 | 1-Projet | Sde | B11 | Etage1 | 4
Mur-149 | Etage1 | 0 | 0 | 3000 | 3000 | 0 | 0 | 0.140881 | 0 | 0 | 640.862 | 1.90759 | 2.11758 | 0 | 855.861 | 605.862 | 1.90759 | 675.861 | 2.11758 | 0.140881 | 1.90759 | 2.11758 | 605.862 | 675.861 | 0 | 0.0574603 | 3000 | 0.140881 | 5750 | 855.861 | 0.140881 | 1450.72 | 8750 | 3000 | 5750 | 0 | 0.621905 | Face extérieure | Lavis blanc | Mur-149 | 1-Projet | Sejour cuisine | B12 | Etage1 | 4
Mur-149 | Etage1 | 1 | 0 | 2700 | 2700 | 1.6932 | 830 | 0.111514 | 1.89045 | 1.89045 | 1285 | 1.68755 | 1.49855 | 0.132331 | 1320 | 411.13 | 3.578 | 341.13 | 3.389 | 0.243845 | 3.578 | 3.389 | 1320 | 1250 | 0 | 0.0312291 | 2700 | 0.111514 | 5750 | 1390 | 0.243845 | 2738.99 | 8450 | 2700 | 5750 | 0 | 0.436767 | Face intérieure | Surface-Blanche | Mur-149 | 1-Projet | Sde | B14 | Etage1 | 4
Mur-149 | Etage1 | 0 | 0 | 2700 | 0 | 0 | 0 | 0.159106 | 0 | 0 | 898.496 | 2.27294 | 2.27294 | 0 | 1078.5 | 898.496 | 2.27294 | 898.496 | 2.27294 | 0.159106 | 2.27294 | 2.27294 | 898.496 | 898.496 | 0 | 0.0705947 | 2700 | 0.159106 | 5750 | 1008.5 | 0.159106 | 1936.99 | 8450 | 2700 | 5750 | 0 | 0.519189 | Face intérieure | Peinture-01 | Mur-149 | 1-Projet | Sde | B16 | Etage1 | 4 | ArchiCADProperties - Zones conflictuelles: Sde
Mur-150 | Etage1 | 2 | 0 | 2700 | 2700 | 2.8764 | 1410 | 0.361579 | 3.1228 | 3.1228 | 3051.51 | 5.16542 | 4.97642 | 0.218596 | 3301.52 | 1541.51 | 8.28822 | 1541.51 | 8.09922 | 0.580175 | 8.28822 | 8.28822 | 3051.51 | 3051.51 | 0 | 0.125406 | 2700 | 0.361579 | 5750 | 3301.52 | 0.580175 | 6243.02 | 8450 | 2700 | 5750 | 0 | 0.734512 | Face intérieure | Surface-Blanche | Mur-150 | 1-Projet | Sde | B13 | Etage1 | 4
Mur-149 | Etage1 | 1 | 0 | 2700 | 2700 | 1.4892 | 730 | 0.0501589 | 1.6848 | 1.6848 | 889.391 | 0.811056 | 0.622056 | 0.117936 | 1104.39 | 114.391 | 2.49586 | 44.3912 | 2.30686 | 0.168095 | 2.49586 | 2.30686 | 924.391 | 854.391 | 0 | 0.00555738 | 2700 | 0.0501589 | 5750 | 924.403 | 0.168095 | 1947.79 | 8450 | 2700 | 5750 | 0 | 0.524123 | Face intérieure | Surface-Blanche | Mur-149 | 1-Projet | Ch 1 | A11 | Etage1 | 4 | ArchiCADProperties - Zones conflictuelles: Ch 1
Mur-153 | Etage1 | 1 | 0 | 2700 | 2700 | 1.1832 | 580 | 0.0310039 | 1.23 | 1.23 | 619.597 | 0.442862 | 0.442963 | 0.0861 | 619.616 | 19.5785 | 1.67286 | 19.6161 | 1.67296 | 0.117104 | 1.67286 | 1.67296 | 619.579 | 619.616 | 0 | 0.00137181 | 2700 | 0.0310039 | 5750 | 619.616 | 0.117104 | 1379.19 | 8450 | 2700 | 5750 | 0 | 0.422744 | Face extérieure | Peinture-01 | Mur-153 | 1-Projet | Sejour cuisine/pl | A15 | Etage1 | 4
Mur-153 | Etage1 | 0 | 0 | 2700 | 2700 | 0 | 0 | 0.123692 | 0 | 0 | 654.456 | 1.86153 | 1.67253 | 0 | 619.456 | 689.456 | 1.86153 | 619.456 | 1.67253 | 0.123692 | 1.86153 | 1.67253 | 689.456 | 619.456 | 0 | 0.0458119 | 2700 | 0.123692 | 5750 | 689.456 | 0.123692 | 1477.91 | 8450 | 2700 | 5750 | 0 | 0.54791 | Face extérieure | Peinture-01 | Mur-153 | 1-Projet | Sejour cuisine/pl | A15 | Etage1 | 4
Mur-149 | Etage1 | 0 | 0 | 2700 | 2700 | 0 | 0 | 0.112087 | 0 | 0 | 593.051 | 1.69574 | 1.50674 | 0 | 968.051 | 628.051 | 1.69574 | 558.051 | 1.50674 | 0.112087 | 1.69574 | 1.50674 | 628.051 | 558.051 | 0 | 0.0415136 | 2700 | 0.112087 | 5750 | 628.051 | 0.112087 | 1355.1 | 8450 | 2700 | 5750 | -8.88178e-13 | 0.539314 | Face intérieure | Peinture-01 | Mur-149 | 1-Projet | Sejour Cuisine/pl | A14 | Etage1 | 4
Mur-149 | Etage1 | 1 | 0 | 2512.25 | 2512.25 | 3.61146 | 1805.73 | 0.0860795 | 3.52819 | 3.52819 | 1893.88 | 1.14178 | 1.14178 | 0.246973 | 1858.88 | 94.7825 | 1.14178 | 164.782 | 1.14178 | 0.333053 | 4.66997 | 4.84583 | 1858.88 | 1928.88 | 0 | 0.00908477 | 2512.25 | 0.0860795 | 5750 | 1928.88 | 0.333053 | 3956.75 | 8262.25 | 2512.25 | 5750 | 0 | 0.426214 | Face intérieure | Surface-Blanche | Mur-149 | 1-Projet | Sejour Cuisine | B13 | Etage1 | 4
Mur-149 | Etage1 | 0 | 0 | 2500 | 2500 | 0 | 0 | 0.824246 | 0 | 0 | 4709.79 | 11.7745 | 11.7745 | 0 | 5119.79 | 4709.79 | 11.7745 | 4709.8 | 11.7745 | 0.824246 | 11.7745 | 11.7745 | 4709.79 | 4709.8 | 0 | 0.329698 | 2500 | 0.824246 | 5750 | 4709.8 | 0.824246 | 9559.59 | 8250 | 2500 | 5750 | 0 | 1.00941 | Face intérieure | Surface-Blanche | Mur-149 | 1-Projet | Ch 2 | B15 | Etage1 | 4
Mur-149 | Etage1 | 1 | 0 | 2700 | 2700 | 1.6932 | 830 | 0.490414 | 1.8928 | 1.8928 | 3295.82 | 7.00592 | 7.00592 | 0.132496 | 3475.82 | 2385.82 | 8.89872 | 2385.82 | 8.89872 | 0.62291 | 8.89872 | 8.89872 | 3295.82 | 3295.82 | 0 | 0.167008 | 2700 | 0.490414 | 5750 | 3295.82 | 0.62291 | 6731.64 | 8450 | 2700 | 5750 | 0 | 0.775715 | Face intérieure | Peinture-01 | Mur-149 | 1-Projet | Entree | A11 | Etage1 | 4
Mur-149 | Etage1 | 0 | 0 | 2700 | 2700 | 0 | 0 | 0.0794692 | 0 | 0 | 420.472 | 1.04077 | 1.22977 | 0 | 385.472 | 385.472 | 1.04077 | 455.472 | 1.22977 | 0.0794692 | 1.04077 | 1.22977 | 385.472 | 455.472 | 0 | 0.029433 | 2700 | 0.0794692 | 5750 | 455.472 | 0.0794692 | 1009.94 | 8450 | 2700 | 5750 | 0 | 0.515152 | Face intérieure | Surface-Blanche | Mur-149 | 1-Projet | Sejour cuisine | B11 | Etage1 | 4
Mur-149 | Etage1 | 1 | 0 | 2700 | 2700 | 1.6932 | 830 | 0.104699 | 1.8928 | 1.8928 | 1255 | 1.4012 | 1.5902 | 0.132496 | 1220 | 310 | 3.294 | 380 | 3.483 | 0.237195 | 3.294 | 3.483 | 1220 | 1290 | 0 | 0.02415 | 2700 | 0.104699 | 5750 | 1290 | 0.237195 | 2678.99 | 8450 | 2700 | 5750 | 0 | 0.422686 | Face intérieure | Surface-Blanche | Mur-149 | 1-Projet | Ch 1 | A12 | Etage1 | 4
Mur-121 | Etage1 | 0 | 0 | 3000 | 0 | 0 | 0 | 0.078065 | 0 | 0 | 400.072 | 1.11521 | 1.11521 | 0 | 580.072 | 400.072 | 1.11521 | 400.072 | 1.11521 | 0.078065 | 1.11521 | 1.11521 | 400.072 | 400.072 | 0 | 0.040605 | 3000 | 0.078065 | 5750 | 580.072 | 0.078065 | 940.143 | 8750 | 3000 | 5750 | 0 | 0.49631 | Face extérieure | Lavis blanc | Mur-121 | 1-Projet |  |  | Etage1 | 4
3 x Mur-121 | Etage1 | 0 | 0 | 3000 | 0 | 0 | 0 | 0.0780609 | 0 | 0 | 400.052 | 1.11516 | 1.11516 | 0 | 580.052 | 400.052 | 1.11516 | 400.052 | 1.11516 | 0.0780609 | 1.11516 | 1.11516 | 400.052 | 400.052 | 0 | 0.0406037 | 3000 | 0.0780609 | 5750 | 580.052 | 0.0780609 | 940.104 | 8750 | 3000 | 5750 | 0 | 0.496307 | Face extérieure | Lavis blanc | Mur-121 | 1-Projet |  |  | Etage1 | 4
Mur-149 | Etage1 | 1 | 0 | 2700 | 2700 | 1.6932 | 830 | 0.20977 | 1.8928 | 1.8928 | 1795 | 3.0842 | 2.4592 | 0.132496 | 2010 | 920 | 4.977 | 850 | 4.352 | 0.342267 | 4.977 | 4.802 | 1830 | 1760 | 0 | 0.0770007 | 2700 | 0.20977 | 5750 | 2010 | 0.342267 | 3759 | 8450 | 2700 | 5750 | 0 | 0.668191 | Face intérieure | Surface-Blanche | Mur-149 | 1-Projet | Cellier | B13 | Etage1 | 4
Mur-153 | Etage1 | 0 | 0 | 3000 | 3000 | 0 | 0 | 0.0635883 | 0 | 0 | 284.801 | 1.01338 | 0.803433 | 0 | 429.811 | 319.79 | 1.01338 | 249.811 | 0.803433 | 0.0635883 | 1.01338 | 0.803433 | 319.79 | 249.811 | 0 | 0.0325368 | 3000 | 0.0635883 | 5750 | 499.811 | 0.0635883 | 738.596 | 8750 | 3000 | 5750 | 0 | 0.572058 | Face extérieure | Peinture-01 | Mur-153 | 1-Projet | Sejour cuisine | A13 | Etage1 | 4 | ArchiCADProperties - Zones conflictuelles: Sejour cuisine/pl
Mur-149 | Etage1 | 0 | 0 | 3000 | 3000 | 0 | 0 | 0.13335 | 0 | 0 | 635.001 | 2.01 | 1.8 | 0 | 670 | 670.001 | 2.01 | 600.001 | 1.8 | 0.13335 | 2.01 | 1.8 | 670.001 | 600.001 | 0 | 0.04445 | 3000 | 0.13335 | 5750 | 670 | 0.13335 | 1439 | 8750 | 3000 | 5750 | 0 | 0.595885 | Face intérieure | Surface-Blanche | Mur-149 | 1-Projet | Ch 2 | B13 | Etage1 | 4 | ArchiCADProperties - Zones conflictuelles: Entree/pl
Mur-149 | Etage1 | 0 | 0 | 3000 | 0 | 0 | 0 | 0.832975 | 0 | 0 | 4036.54 | 11.8996 | 11.8996 | 0 | 4036.54 | 4036.54 | 11.8996 | 4036.54 | 11.8996 | 0.832975 | 11.8996 | 11.8996 | 4036.54 | 4036.54 | 0 | 0.277658 | 3000 | 0.832975 | 5750 | 3966.55 | 0.832975 | 8213.09 | 8750 | 3000 | 5750 | 0 | 0.765317 | Face intérieure | Surface-Blanche | Mur-149 | 1-Projet | Ch 2 | B12 | Etage1 | 4
Mur-149 | Etage1 | 0 | 0 | 2500 | 2500 | 0 | 0 | 0.451701 | 0 | 0 | 2741.15 | 6.27788 | 6.27788 | 0 | 2991.15 | 2741.15 | 6.27788 | 2741.15 | 6.27788 | 0.451701 | 6.45288 | 6.45288 | 2741.15 | 2741.15 | 0 | 0.180681 | 2500 | 0.451701 | 5750 | 2581.15 | 0.451701 | 5622.3 | 8250 | 2500 | 5750 | 0 | 0.711361 | Face intérieure | Surface-Blanche | Mur-149 | 1-Projet | Ch 1/pl | B15 | Etage1 | 4
Mur-149 | Etage1 | 0 | 0 | 3000 | 3000 | 0 | 0 | 0.367507 | 0 | 0 | 1720.03 | 5.2501 | 5.0401 | 0 | 1970.03 | 1720.03 | 5.2501 | 1720.03 | 5.0401 | 0.367507 | 5.2501 | 5.2501 | 1720.03 | 1720.03 | 0 | 0.133002 | 3000 | 0.367507 | 5750 | 1900.03 | 0.367507 | 3580.06 | 8750 | 3000 | 5750 | 0 | 0.686005 | Face intérieure | Surface-Blanche | Mur-149 | 1-Projet | Wc | B12 | Etage1 | 4
Mur-149 | Etage1 | 0 | 0 | 2700 | 2700 | 0 | 0 | 0.334535 | 0 | 0 | 1770.02 | 4.32907 | 4.14007 | 0 | 1840.02 | 1770.02 | 4.32907 | 1770.03 | 4.14007 | 0.334535 | 4.77907 | 4.77907 | 1770.02 | 1770.03 | 0 | 0.123902 | 2700 | 0.334535 | 5750 | 1770.03 | 0.334535 | 3680.05 | 8450 | 2700 | 5750 | -8.88178e-13 | 0.625803 | Face intérieure | Surface-Blanche | Mur-149 | 1-Projet | Sde | B14 | Etage1 | 4
Mur-148 | Etage1 | 0 | 0 | 3000 | 0 | 0 | 0 | 0.320911 | 0 | 0 | 1708.15 | 4.58438 | 4.3745 | 0 | 1778.13 | 1708.13 | 4.58438 | 1708.17 | 4.3745 | 0.320911 | 4.58438 | 4.5845 | 1708.13 | 1708.17 | 0 | 0.10697 | 3000 | 0.320911 | 5750 | 1528.19 | 0.320911 | 3556.29 | 8750 | 3000 | 5750 | 0 | 0.633941 | Face intérieure | Surface-Blanche | Mur-148 | 1-Projet | Wc | A13 | Etage1 | 4
Mur-149 | Etage1 | 4 | 0 | 3000 | 3000 | 11.3437 | 5638.63 | 0.443034 | 11.6629 | 11.6629 | 5982.3 | 5.90905 | 5.90905 | 0.816399 | 6162.3 | 223.675 | 9.69465 | 223.675 | 9.69465 | 1.25943 | 17.9919 | 17.9919 | 5982.3 | 5982.3 | 0 | 0.0282572 | 3000 | 0.443034 | 5750 | 6162.3 | 1.25943 | 12104.6 | 8750 | 3000 | 5750 | 0 | 0.599619 | Face intérieure | Surface-Blanche | Mur-149 | 1-Projet | Ch 2 | B12 | Etage1 | 4 | ArchiCADProperties - Zones conflictuelles: Ch 1/pl; Ch 1/pl; Entree/pl
Mur-149 | Etage1 | 0 | 0 | 2500 | 0 | 0 | 0 | 0.151442 | 0 | 0 | 865.873 | 2.20218 | 2.07718 | 0 | 1080.87 | 900.873 | 2.20218 | 830.873 | 2.07718 | 0.151442 | 2.20218 | 2.07718 | 900.873 | 830.873 | 0 | 0.0605769 | 2500 | 0.151442 | 5750 | 900.021 | 0.151442 | 1900.74 | 8250 | 2500 | 5750 | 0 | 0.540628 | Face intérieure | Surface-Blanche | Mur-149 | 1-Projet | Sde | B15 | Etage1 | 4
Mur-149 | Etage1 | 0 | 0 | 2700 | 2700 | 0 | 0 | 0.4482 | 0 | 0 | 2371.43 | 6.40286 | 6.40286 | 0 | 2371.43 | 2371.43 | 6.40286 | 2371.43 | 6.40286 | 0.4482 | 6.40286 | 6.40286 | 2371.43 | 2371.43 | 0 | 0.166 | 2700 | 0.4482 | 5750 | 2371.43 | 0.4482 | 4882.86 | 8450 | 2700 | 5750 | 0 | 0.71 | Face intérieure | Surface-Blanche | Mur-149 | 1-Projet | Ch 1 | A11 | Etage1 | 4 | ArchiCADProperties - Zones conflictuelles: Sde
Mur-153 | Etage1 | 1 | 0 | 2700 | 0 | 1.6932 | 830 | 0.448823 | 1.8928 | 1.8928 | 3077.59 | 6.41176 | 6.03376 | 0.132496 | 3147.6 | 2167.58 | 8.30456 | 2167.6 | 7.92656 | 0.581319 | 8.30456 | 8.30456 | 3077.58 | 3077.6 | 0 | 0.151603 | 2700 | 0.448823 | 5750 | 3075.78 | 0.581319 | 6295.19 | 8450 | 2700 | 5750 | 0 | 0.555907 | Face extérieure | Peinture-01 | Mur-153 | 1-Projet | Dgt | A14 | Etage1 | 4
Mur-149 | Etage1 | 0 | 0 | 2700 | 2700 | 0 | 0 | 0.120068 | 0 | 0 | 635.278 | 1.80975 | 1.62075 | 0 | 670.278 | 670.278 | 1.80975 | 600.278 | 1.62075 | 0.120068 | 1.80975 | 1.62075 | 670.278 | 600.278 | 0 | 0.0444694 | 2700 | 0.120068 | 5750 | 670.278 | 0.120068 | 1439.55 | 8450 | 2700 | 5750 | 0 | 0.545225 | Face intérieure | Peinture-01 | Mur-149 | 1-Projet | Sejour cuisine | B14 | Etage1 | 4 | ArchiCADProperties - Zones conflictuelles: Sejour cuisine
Mur-153 | Etage1 | 0 | 0 | 2700 | 2700 | 0 | 0 | 0.069842 | 0 | 0 | 369.534 | 1.09224 | 0.714242 | 0 | 334.534 | 404.534 | 1.09224 | 334.534 | 0.714242 | 0.069842 | 1.09224 | 0.903242 | 404.534 | 334.534 | 0 | 0.0258674 | 2700 | 0.069842 | 5750 | 404.534 | 0.069842 | 908.063 | 8450 | 2700 | 5750 | 0 | 0.508021 | Face extérieure | Peinture-01 | Mur-153 | 1-Projet | Sejour cuisine/pl | A15 | Etage1 | 4
Mur-149 | Etage1 | 0 | 0 | 2700 | 2300 | 0 | 0 | 0.250276 | 0 | 0 | 1424.55 | 3.57538 | 3.57538 | 0 | 1494.55 | 1424.55 | 3.57538 | 1424.55 | 3.57538 | 0.250276 | 3.86029 | 3.86029 | 1424.55 | 1424.55 | 0 | 0.104619 | 2700 | 0.250276 | 5750 | 1494.55 | 0.27022 | 2989.1 | 8450 | 2700 | 5750 | 0 | 0.559237 | Face intérieure | Peinture-01 | Mur-149 | 1-Projet | Cellier | B15 | Etage1 | 4
Mur-149 | Etage1 | 0 | 0 | 3000 | 3000 | 0 | 0 | 0.0906896 | 0 | 0 | 435.464 | 1.41139 | 1.17974 | 0 | 470.464 | 470.464 | 1.41139 | 400.464 | 1.17974 | 0.0906896 | 1.41139 | 1.17974 | 470.464 | 400.464 | 0 | 0.0304825 | 3000 | 0.0906896 | 5750 | 470.464 | 0.0906896 | 1039.92 | 8750 | 3000 | 5750 | 0 | 0.576905 | Face intérieure | Surface-Blanche | Mur-149 | 1-Projet | Sde | B14 | Etage1 | 4 | ArchiCADProperties - Zones conflictuelles: Sde; Sde
Mur-149 | Etage1 | 0 | 0 | 3000 | 3000 | 0 | 0 | 0.186773 | 0 | 0 | 889.397 | 2.77317 | 2.56322 | 0 | 924.381 | 924.389 | 2.77317 | 854.406 | 2.56322 | 0.186773 | 2.77317 | 2.56322 | 924.389 | 854.406 | 0 | 0.0622578 | 3000 | 0.186773 | 5750 | 924.41 | 0.186773 | 1947.79 | 8750 | 3000 | 5750 | 0 | 0.63151 | Face intérieure | Surface-Blanche | Mur-149 | 1-Projet | Sde | A13 | Etage1 | 4 | ArchiCADProperties - Zones conflictuelles: Sde
Mur-149 | Etage1 | 0 | 0 | 3000 | 3000 | 0 | 0 | 0.39155 | 0 | 0 | 1864.52 | 5.69857 | 5.48857 | 0 | 1969.52 | 1899.52 | 5.69857 | 1829.52 | 5.48857 | 0.39155 | 5.69857 | 5.48857 | 1899.52 | 1829.52 | 0 | 0.130517 | 3000 | 0.39155 | 5750 | 1899.52 | 0.39155 | 3898.04 | 8750 | 3000 | 5750 | 0 | 0.768018 | Face intérieure | Surface-Blanche | Mur-149 | 1-Projet | Ch 2 | B12 | Etage1 | 4
Mur-149 | Etage1 | 1 | 0 | 3000 | 3000 | 1.6932 | 830 | 0.373031 | 1.8928 | 1.8928 | 2403.77 | 5.42352 | 5.02452 | 0.132496 | 2508.77 | 1528.77 | 7.31632 | 1458.77 | 6.91732 | 0.505527 | 7.31632 | 7.12732 | 2438.77 | 2368.77 | 0 | 0.107014 | 3000 | 0.373031 | 5750 | 2438.77 | 0.505527 | 4976.54 | 8750 | 3000 | 5750 | 0 | 0.776015 | Face intérieure | Surface-Blanche | Mur-149 | 1-Projet | Entree/pl | B12 | Etage1 | 4 | ArchiCADProperties - Zones conflictuelles: Entree/pl
Mur-149 | Etage1 | 0 | 0 | 3000 | 3000 | 0 | 0 | 0.13335 | 0 | 0 | 635.001 | 2.01 | 1.8 | 0 | 670 | 670.001 | 2.01 | 600.001 | 1.8 | 0.13335 | 2.01 | 1.8 | 670.001 | 600.001 | 0 | 0.04445 | 3000 | 0.13335 | 5750 | 670 | 0.13335 | 1439 | 8750 | 3000 | 5750 | 0 | 0.595885 | Face intérieure | Surface-Blanche | Mur-149 | 1-Projet | Ch 2 | B12 | Etage1 | 4
Mur-149 | Etage1 | 0 | 0 | 3000 | 3000 | 0 | 0 | 0.406458 | 0 | 0 | 1935.51 | 5.91154 | 5.70154 | 0 | 1970.51 | 1970.51 | 5.91154 | 1900.51 | 5.70154 | 0.406458 | 5.91154 | 5.70154 | 1970.51 | 1900.51 | 0 | 0.135486 | 3000 | 0.406458 | 5750 | 1970.51 | 0.406458 | 4040.02 | 8750 | 3000 | 5750 | 0 | 0.777957 | Face intérieure | Surface-Blanche | Mur-149 | 1-Projet | Ch 2 | B13 | Etage1 | 4 | ArchiCADProperties - Zones conflictuelles: Entree/pl
Mur-149 | Etage1 | 0 | 0 | 2500 | 2500 | 0 | 0 | 0.148292 | 0 | 0 | 847.385 | 2.20596 | 2.03096 | 0 | 882.385 | 882.385 | 2.20596 | 812.385 | 2.03096 | 0.148292 | 2.20596 | 2.03096 | 882.385 | 812.385 | 0 | 0.059317 | 2500 | 0.148292 | 5750 | 882.385 | 0.148292 | 1863.77 | 8250 | 2500 | 5750 | 0 | 0.541121 | Face intérieure | Surface-Blanche | Mur-149 | 1-Projet | Sde | B15 | Etage1 | 4
Mur-121 | Etage1 | 1 | 0 | 3000 | 3000 | 1.6932 | 830 | 0.207762 | 1.8928 | 1.8928 | 1620.27 | 2.86286 | 3.07318 | 0.132496 | 1655.33 | 675.221 | 4.75566 | 745.328 | 4.96598 | 0.340258 | 4.75566 | 4.96598 | 1585.22 | 1655.33 | 0 | 0.0497192 | 3000 | 0.207762 | 5750 | 1655.33 | 0.340258 | 3409.62 | 8750 | 3000 | 5750 | 0 | 0.67035 | Face extérieure | Lavis blanc | Mur-121 | 1-Projet | Wc | A13 | Etage1 | 4 | ArchiCADProperties - Zones conflictuelles: Sejour cuisine; Wc
Mur-149 | Etage1 | 1 | 0 | 2500 | 2500 | 1.6932 | 830 | 0.386499 | 1.8928 | 1.8928 | 2965.69 | 5.52141 | 5.52141 | 0.132496 | 3375.69 | 2055.69 | 7.41421 | 2055.69 | 7.41421 | 0.518995 | 7.41421 | 7.41421 | 2965.69 | 2965.69 | 0 | 0.143898 | 2500 | 0.386499 | 5750 | 2965.69 | 0.518995 | 6071.37 | 8250 | 2500 | 5750 | 0 | 0.701496 | Face intérieure | Surface-Blanche | Mur-149 | 1-Projet | Sejour cuisine | B11 | Etage1 | 4
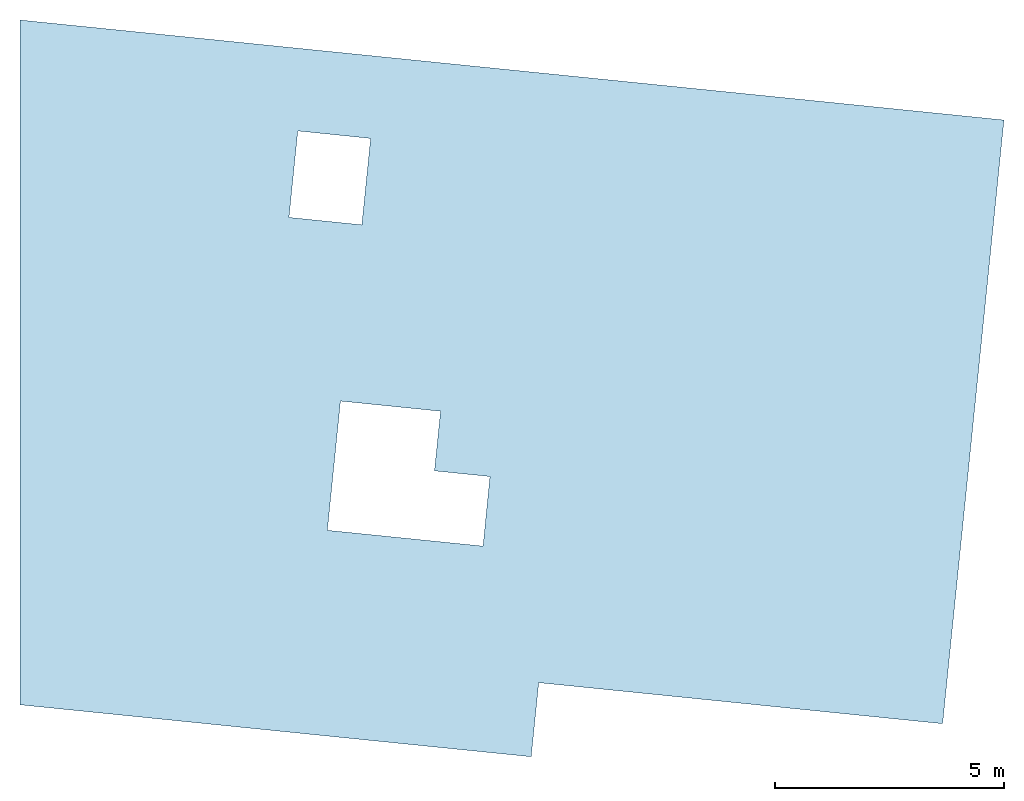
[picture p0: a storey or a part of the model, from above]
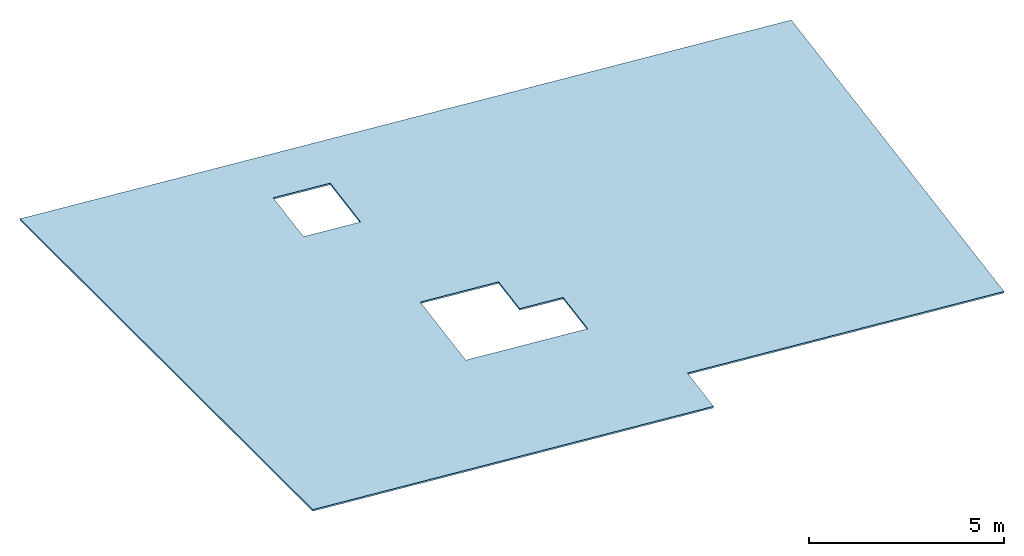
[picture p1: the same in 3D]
Properties of the parts of a building model (IFC2X3), part 25 of 44

# IfcWallStandardCase: Cloison 70 0826278243 70 (896)
Name | In | Nombre de Portes | Nombre de trous (Nombre d'ouvertures vides) | Hauteur maximale de la couche de Mur sur face intérieure (mm) = Hauteur maximale du Mur (mm) = Hauteur maximale de la couche de Mur sur face extérieure (mm) | Hauteur minimale de la couche de Mur sur face intérieure (mm) = Hauteur minimale du Mur (mm) = Hauteur minimale de la couche de Mur sur face extérieure (mm) | Superficie des portes (m2) | Largeur totale des Portes (mm) | Volume de composant de mur sur face intérieure (net) (m3) = Volume de composant de mur sur face extérieure (net) (m3) | Superficie analytique des ouvertures sur face intérieure (m2) | Superficie analytique des ouvertures sur face extérieure (m2) | Longueur moyenne du mur (mm) = Longueur du Mur au centre (mm) | Superficie de la face intérieure du mur (nette) (m2) | Superficie de la face extérieure du mur (nette) (m2) = Superficie en plan (m2) = Superficie inférieure (nette) (m2) | Volume analytique des ouvertures (m3) | Longueur de ligne de référence (mm) | Longueur de la face intérieure du mur (conditionnelle) (mm) | Superficie de la face intérieure du mur (conditionnelle) (m2) | Longueur de la face extérieure du mur (conditionnelle) (mm) | Superficie de la face extérieure du mur (conditionnelle) (m2) | Volume du composant face intérieure du mur (conditionnel) (m3) = Volume du composant face extérieure du mur (conditionnel) (m3) = Volume (conditionnel) (m3) | Superficie de la face intérieure du mur (brute) (m2) | Superficie de la face extérieure du mur (brute) (m2) | Longueur de Mur sur face intérieure (mm) | Longueur de Mur sur face extérieure (mm) | Superficie des baies libres dans le Mur (m2) | Superficie (m2) = Superficie supérieure (nette) (m2) | Hauteur (mm) | Volume (net) (m3) | Altitude à Zéro du Projet (mm) = Altitude de Référence Niveau 1 (mm) = Altitude de Référence Niveau 2 (mm) = Altitude à niveau de la mer (mm) | Longueur 3D (mm) | Volume (brut) (m3) | Périmètre Plan (mm) | Altitude supérieure à premier niveau de référence (mm) = Altitude supérieure à Zéro du projet (mm) = Altitude supérieure à niveau de la mer (mm) = Altitude supérieure à deuxième niveau de référence (mm) | Altitude supérieure à étage d'implantation (mm) | Altitude inférieure à premier niveau de référence (mm) = Altitude inférieure à Zéro du projet (mm) = Altitude inférieure à niveau de la mer (mm) = Altitude inférieure à deuxième niveau de référence (mm) | Altitude inférieure à étage d'implantation (mm) | Superficie de l'arête (nette) (m2) | Emplacement de ligne de référence | Surface de face intérieure = Surface de face extérieure = Surfaces (Toutes) = Surface latérale | ID de l'élément = Lien et ID d'élément = ID de Parent | Calque | Nom de zone liée | Numéro de zone liée | Nom d'étage d'implantation | Numéro d'étage d'implantation
Mur-153 | Etage1 | 0 | 0 | 2700 | 2700 | 0 | 0 | 0.796604 | 0 | 0 | 4214.84 | 11.3801 | 11.3801 | 0 | 4554.84 | 4214.84 | 11.3801 | 4214.84 | 11.3801 | 0.796604 | 11.3801 | 11.3801 | 4214.84 | 4214.84 | 0 | 0.295038 | 2700 | 0.796604 | 5750 | 4214.84 | 0.796604 | 8569.67 | 8450 | 2700 | 5750 | 0 | 0.968077 | Face extérieure | Peinture-01 | Mur-153 | 1-Projet | Ch 2 | A14 | Etage1 | 4
Mur-149 | Etage1 | 0 | 0 | 3000 | 3000 | 0 | 0 | 0.0614228 | 0 | 0 | 285.489 | 0.982517 | 0.772419 | 0 | 390.511 | 320.505 | 0.982517 | 250.472 | 0.772419 | 0.0614228 | 0.982517 | 0.772419 | 320.505 | 250.472 | 0 | 0.0248846 | 3000 | 0.0614228 | 5750 | 390.511 | 0.0614228 | 739.996 | 8750 | 3000 | 5750 | 0 | 0.556824 | Face intérieure | Surface-Blanche | Mur-149 | 1-Projet | Sde | B13 | Etage1 | 4
Mur-149 | Etage1 | 0 | 0 | 2700 | 2700 | 0 | 0 | 0.137089 | 0 | 0 | 725.338 | 2.05291 | 1.86391 | 0 | 1040.34 | 760.338 | 2.05291 | 690.338 | 1.86391 | 0.137089 | 2.05291 | 1.86391 | 760.338 | 690.338 | 0 | 0.0507737 | 2700 | 0.137089 | 5750 | 760.338 | 0.137089 | 1619.67 | 8450 | 2700 | 5750 | -8.88178e-13 | 0.557834 | Face intérieure | Surface-Blanche | Mur-149 | 1-Projet | Sejour cuisine/pl | A11 | Etage1 | 4
Mur-149 | Etage1 | 0 | 0 | 2700 | 2700 | 0 | 0 | 0.789664 | 0 | 0 | 4178.12 | 11.2809 | 11.2809 | 0 | 4518.12 | 4178.12 | 11.2809 | 4178.12 | 11.2809 | 0.789664 | 11.2809 | 11.2809 | 4178.12 | 4178.12 | 0 | 0.292468 | 2700 | 0.789664 | 5750 | 4178.12 | 0.789664 | 8496.24 | 8450 | 2700 | 5750 | 0 | 0.962936 | Face intérieure | Surface-Blanche | Mur-149 | 1-Projet | Ch 1/pl | B14 | Etage1 | 4
Mur-149 | Etage1 | 1 | 0 | 2700 | 2700 | 1.122 | 550 | 0.149794 | 1.1685 | 1.1685 | 1225.34 | 2.23441 | 1.85641 | 0.081795 | 1600.34 | 690.338 | 3.40291 | 620.338 | 3.02491 | 0.231589 | 3.40291 | 3.21391 | 1260.34 | 1190.34 | 0 | 0.0458736 | 2700 | 0.149794 | 5750 | 1260.34 | 0.231589 | 2619.67 | 8450 | 2700 | 5750 | 0 | 0.587934 | Face intérieure | Surface-Blanche | Mur-149 | 1-Projet | Sejour cuisine/pl | A11 | Etage1 | 4 | ArchiCADProperties - Zones conflictuelles: Sejour cuisine/pl
Mur-153 | Etage1 | 0 | 0 | 2700 | 2700 | 0 | 0 | 0.464826 | 0 | 0 | 2459.31 | 6.58615 | 6.12716 | 0 | 2509.32 | 2509.31 | 6.58615 | 2409.32 | 6.12716 | 0.464826 | 6.77515 | 6.50516 | 2509.31 | 2409.32 | 0 | 0.172158 | 2700 | 0.464826 | 5750 | 2509.31 | 0.464826 | 5110.68 | 8450 | 2700 | 5750 | 0 | 0.862892 | Face extérieure | Peinture-01 | Mur-153 | 1-Projet | Sejour Cuisine/pl | A14 | Etage1 | 4 | ArchiCADProperties - Zones conflictuelles: Sejour Cuisine/pl
Mur-149 | Etage1 | 0 | 0 | 2700 | 2700 | 0 | 0 | 0.130474 | 0 | 0 | 690.338 | 1.86391 | 1.86391 | 0 | 1040.34 | 690.338 | 1.86391 | 690.338 | 1.86391 | 0.130474 | 1.86391 | 1.86391 | 690.338 | 690.338 | 0 | 0.0483237 | 2700 | 0.130474 | 5750 | 690.338 | 0.130474 | 1520.68 | 8450 | 2700 | 5750 | 0 | 0.474647 | Face intérieure | Surface-Blanche | Mur-149 | 1-Projet | Sejour cuisine/pl | A11 | Etage1 | 4
Mur-153 | Etage1 | 1 | 0 | 2700 | 0 | 2.34909 | 1174.54 | 0.114361 | 2.26909 | 2.26909 | 1445.51 | 1.44473 | 1.63372 | 0.158836 | 1445.51 | 310.965 | 1.44473 | 310.965 | 1.63372 | 0.273197 | 3.90282 | 3.90281 | 1445.51 | 1445.51 | 0 | 0.0217661 | 2700 | 0.114361 | 5750 | 1445.49 | 0.273197 | 3031.02 | 8450 | 2700 | 5750 | 0 | 0.17195 | Face extérieure | Peinture-01 | Mur-153 | 1-Projet | Sejour Cuisine/pl | A14 | Etage1 | 4
Mur-149 | Etage1 | 0 | 0 | 2700 | 2700 | 0 | 0 | 0.119711 | 0 | 0 | 633.393 | 1.61569 | 1.80464 | 0 | 598.402 | 598.402 | 1.61569 | 668.383 | 1.80464 | 0.119711 | 1.61569 | 1.80464 | 598.402 | 668.383 | 0 | 0.0443375 | 2700 | 0.119711 | 5750 | 668.402 | 0.119711 | 1435.78 | 8450 | 2700 | 5750 | 0 | 0.544961 | Face intérieure | Peinture-01 | Mur-149 | 1-Projet | Wc | A14 | Etage1 | 4
Mur-149 | Etage1 | 1 | 1 | 2700 | 2700 | 1.6932 | 830 | 0.732375 | 3.79491 | 3.79493 | 5280.53 | 10.0797 | 10.4673 | 0.265644 | 5348.75 | 3436.34 | 13.8746 | 3439.89 | 14.2622 | 0.99802 | 14.2526 | 14.2622 | 5278.75 | 5282.3 | 1.90213 | 0.240668 | 2700 | 0.732375 | 5750 | 5282.3 | 0.99802 | 10701.1 | 8450 | 2700 | 5750 | 0 | 0.845748 | Face intérieure | Surface-Blanche | Mur-149 | 1-Projet | Entree | A11 | Etage1 | 4
Mur-149 | Etage1 | 0 | 0 | 2700 | 2700 | 0 | 0 | 0.130294 | 0 | 0 | 689.385 | 1.67234 | 1.86134 | 0 | 689.385 | 689.385 | 1.67234 | 689.385 | 1.86134 | 0.130294 | 1.86134 | 1.86134 | 689.385 | 689.385 | 0 | 0.048257 | 2700 | 0.130294 | 5750 | 689.385 | 0.130294 | 1518.77 | 8450 | 2700 | 5750 | 0 | 0.474514 | Face intérieure | Surface-Blanche | Mur-149 | 1-Projet | Sejour cuisine | B11 | Etage1 | 4
Mur-150 | Etage1 | 0 | 0 | 3000 | 3000 | 0 | 0 | 0.195976 | 0 | 0 | 903.217 | 2.79965 | 2.58965 | 0 | 1083.22 | 903.217 | 2.79965 | 903.217 | 2.58965 | 0.195976 | 2.79965 | 2.79965 | 903.217 | 903.217 | 0 | 0.0758253 | 3000 | 0.195976 | 5750 | 1083.22 | 0.195976 | 1946.43 | 8750 | 3000 | 5750 | 0 | 0.571651 | Face intérieure | Surface-Blanche | Mur-150 | 1-Projet | Sde | B12 | Etage1 | 4 | ArchiCADProperties - Zones conflictuelles: Sde; Sde
Mur-120 | Etage1 | 7 | 0 | 2500 | 2500 | 7.2216 | 3540 | 0.332822 | 7.544 | 7.544 | 4919.44 | 3.4796 | 4.1046 | 0.52808 | 5009.44 | 1919.44 | 8.4816 | 2099.44 | 9.1066 | 0.860902 | 12.0736 | 12.5236 | 4829.44 | 5009.44 | 0 | 0.0867608 | 2500 | 0.332822 | 5750 | 5009.44 | 0.860902 | 10102 | 8250 | 2500 | 5750 | 0 | 1.08895 | Face extérieure | Peinture-01 | Mur-120 | 3D |  |  | Etage1 | 4
Mur-149 | Etage1 | 1 | 0 | 2700 | 2700 | 3.44032 | 1720.16 | 0.090903 | 3.44032 | 3.44032 | 1755.16 | 1.39311 | 1.20411 | 0.240823 | 1790.16 | 70 | 1.39311 | 0 | 1.20411 | 0.331726 | 4.83344 | 4.64444 | 1790.16 | 1720.16 | 0 | 0.00245 | 2700 | 0.090903 | 5750 | 1790.16 | 0.331726 | 3679.32 | 8450 | 2700 | 5750 | 0 | 0.441598 | Face intérieure | Peinture-01 | Mur-149 | 1-Projet | Ch 1/pl | B16 | Etage1 | 4 | ArchiCADProperties - Zones conflictuelles: Ch 1/pl
Mur-149 | Etage1 | 0 | 0 | 3000 | 3000 | 0 | 0 | 0.454462 | 0 | 0 | 2149.1 | 6.49231 | 6.49231 | 0 | 2399.1 | 2149.1 | 6.49231 | 2149.1 | 6.49231 | 0.454462 | 6.49231 | 6.49231 | 2149.1 | 2149.1 | 0 | 0.163037 | 3000 | 0.454462 | 5750 | 2329.1 | 0.454462 | 4438.21 | 8750 | 3000 | 5750 | 0 | 0.746075 | Face intérieure | Surface-Blanche | Mur-149 | 1-Projet | Ch 1/pl | B12 | Etage1 | 4
Mur-153 | Etage1 | 0 | 0 | 3000 | 3000 | 0 | 0 | 0.056282 | 0 | 0 | 250.011 | 0.804057 | 0.804 | 0 | 430 | 250.021 | 0.804057 | 250 | 0.804 | 0.056282 | 0.804057 | 0.804 | 250.021 | 250 | 0 | 0.0301 | 3000 | 0.056282 | 5750 | 430 | 0.056282 | 640.021 | 8750 | 3000 | 5750 | 0 | 0.4802 | Face extérieure | Peinture-01 | Mur-153 | 1-Projet | Sejour cuisine | A13 | Etage1 | 4
Mur-149 | Etage1 | 0 | 1 | 2500 | 2300 | 0 | 0 | 0.784549 | 1.86871 | 1.86871 | 5245.02 | 11.0328 | 10.5828 | 0.13081 | 5585.02 | 4328.98 | 12.9015 | 4328.98 | 12.4515 | 0.915358 | 13.1125 | 13.1125 | 5245.02 | 5245.02 | 1.86871 | 0.303029 | 2500 | 0.784549 | 5750 | 5245.02 | 0.917878 | 10630 | 8250 | 2500 | 5750 | 0 | 0.99358 | Face intérieure | Peinture-01 | Mur-149 | 1-Projet | Sejour cuisine | B15 | Etage1 | 4
Mur-149 | Etage1 | 1 | 0 | 2700 | 2700 | 1.1832 | 580 | 0.0375788 | 1.23 | 1.23 | 654.385 | 0.63134 | 0.44234 | 0.0861 | 799.385 | 89.385 | 1.86134 | 19.385 | 1.67234 | 0.123679 | 1.86134 | 1.67234 | 689.385 | 619.385 | 0 | 0.00380695 | 2700 | 0.0375788 | 5750 | 689.385 | 0.123679 | 1477.76 | 8450 | 2700 | 5750 | 0 | 0.5059 | Face intérieure | Surface-Blanche | Mur-149 | 1-Projet | Sejour cuisine | B11 | Etage1 | 4
Mur-149 | Etage1 | 1 | 0 | 2512.25 | 2512.25 | 3.10624 | 1553.12 | 0.0618462 | 3.10625 | 3.10625 | 1588.12 | 0.971446 | 0.795589 | 0.217437 | 1623.12 | 70 | 0.971451 | 0 | 0.795593 | 0.279284 | 4.0777 | 3.90184 | 1623.12 | 1553.12 | 0 | 0.00245 | 2512.25 | 0.0618462 | 5750 | 1623.12 | 0.279284 | 3345.24 | 8262.25 | 2512.25 | 5750 | 0 | 0.398176 | Face intérieure | Surface-Blanche | Mur-149 | 1-Projet | Ch 1/pl | B13 | Etage1 | 4 | ArchiCADProperties - Zones conflictuelles: Ch 1/pl
Mur-149 | Etage1 | 0 | 0 | 3000 | 3000 | 0 | 0 | 0.058494 | 0 | 0 | 278.543 | 0.940629 | 0.730629 | 0 | 383.543 | 313.543 | 0.940629 | 243.543 | 0.730629 | 0.058494 | 0.940629 | 0.730629 | 313.543 | 243.543 | 0 | 0.019498 | 3000 | 0.058494 | 5750 | 313.543 | 0.058494 | 726.081 | 8750 | 3000 | 5750 | 0 | 0.545981 | Face intérieure | Surface-Blanche | Mur-149 | 1-Projet | Sde | B12 | Etage1 | 4
Mur-150 | Etage1 | 0 | 0 | 3000 | 3000 | 0 | 0 | 0.121915 | 0 | 0 | 565.561 | 1.74168 | 1.74161 | 0 | 815.561 | 565.561 | 1.74168 | 565.561 | 1.74161 | 0.121915 | 1.74168 | 1.74161 | 565.561 | 565.561 | 0 | 0.0521786 | 3000 | 0.121915 | 5750 | 745.561 | 0.121915 | 1271.12 | 8750 | 3000 | 5750 | 0 | 0.524357 | Face intérieure | Surface-Blanche | Mur-150 | 1-Projet |  |  | Etage1 | 4 | ArchiCADProperties - Zones conflictuelles: Sde
Mur-149 | Etage1 | 0 | 0 | 2700 | 2700 | 0 | 0 | 0.067095 | 0 | 0 | 355 | 0.864 | 1.053 | 0 | 390 | 320 | 0.864 | 390 | 1.053 | 0.067095 | 0.864 | 1.053 | 320 | 390 | 0 | 0.02485 | 2700 | 0.067095 | 5750 | 390 | 0.067095 | 878.995 | 8450 | 2700 | 5750 | 0 | 0.505986 | Face intérieure | Surface-Blanche | Mur-149 | 1-Projet | Sejour cuisine | B11 | Etage1 | 4
Mur-149 | Etage1 | 0 | 0 | 2700 | 2700 | 0 | 0 | 0.0633191 | 0 | 0 | 335.022 | 0.999059 | 0.810059 | 0 | 370.022 | 370.022 | 0.999059 | 300.021 | 0.810059 | 0.0633191 | 0.999059 | 0.810059 | 370.022 | 300.021 | 0 | 0.0234515 | 2700 | 0.0633191 | 5750 | 370.022 | 0.0633191 | 839.038 | 8450 | 2700 | 5750 | 0 | 0.503189 | Face intérieure | Surface-Blanche | Mur-149 | 1-Projet | Ch 1 | B11 | Etage1 | 4
Mur-149 | Etage1 | 0 | 0 | 2700 | 2700 | 0 | 0 | 0.120505 | 0 | 0 | 635 | 1.809 | 1.634 | 0 | 670 | 670 | 1.809 | 600 | 1.634 | 0.120505 | 1.809 | 1.634 | 670 | 600 | 0 | 0.0469 | 2700 | 0.120505 | 5750 | 670 | 0.120505 | 1438.99 | 8450 | 2700 | 5750 | 0 | 0.544287 | Face intérieure | Surface-Blanche | Mur-149 | 1-Projet | Ch 1/pl | B15 | Etage1 | 4
Mur-149 | Etage1 | 0 | 0 | 2500 | 2500 | 0 | 0 | 0.0991941 | 0 | 0 | 566.824 | 1.50456 | 1.32956 | 0 | 671.824 | 601.824 | 1.50456 | 531.824 | 1.32956 | 0.0991941 | 1.50456 | 1.32956 | 601.824 | 531.824 | 0 | 0.0396776 | 2500 | 0.0991941 | 5750 | 601.824 | 0.0991941 | 1302.64 | 8250 | 2500 | 5750 | 0 | 0.501843 | Face intérieure | Surface-Blanche | Mur-149 | 1-Projet | Sde | B15 | Etage1 | 4
Mur-149 | Etage1 | 2 | 0 | 2512.25 | 2512.25 | 3.3864 | 1660 | 0.498719 | 3.7856 | 3.7856 | 4342.78 | 6.14477 | 6.49649 | 0.264992 | 4342.78 | 2522.78 | 9.93037 | 2522.78 | 10.2821 | 0.763711 | 10.9102 | 10.9102 | 4342.78 | 4342.78 | 0 | 0.176595 | 2512.25 | 0.498719 | 5750 | 4342.78 | 0.763711 | 8825.56 | 8262.25 | 2512.25 | 5750 | 0 | 0.832304 | Face intérieure | Surface-Blanche | Mur-149 | 1-Projet | Sde | B13 | Etage1 | 4
Mur-148 | Etage1 | 0 | 0 | 2700 | 2700 | 0 | 0 | 0.273716 | 0 | 0 | 1448.23 | 3.91023 | 3.91021 | 0 | 1518.23 | 1448.23 | 3.91023 | 1448.23 | 3.91021 | 0.273716 | 3.91023 | 3.91021 | 1448.23 | 1448.23 | 0 | 0.101376 | 2700 | 0.273716 | 5750 | 1448.25 | 0.273716 | 3036.46 | 8450 | 2700 | 5750 | -8.88178e-13 | 0.580752 | Face extérieure | Lavis blanc | Mur-148 | 1-Projet | Sejour cuisine/pl | A15 | Etage1 | 4
Mur-149 | Etage1 | 0 | 0 | 2700 | 2700 | 0 | 0 | 0.0482085 | 0 | 0 | 255.071 | 0.594183 | 0.783203 | 0 | 500.068 | 220.068 | 0.594183 | 290.075 | 0.783203 | 0.0482085 | 0.594183 | 0.783203 | 220.068 | 290.075 | 0 | 0.017855 | 2700 | 0.0482085 | 5750 | 290.075 | 0.0482085 | 679.139 | 8450 | 2700 | 5750 | -8.88178e-13 | 0.492 | Face intérieure | Peinture-01 | Mur-149 | 1-Projet | Entree | A11 | Etage1 | 4
Mur-149 | Etage1 | 0 | 0 | 2700 | 0 | 0 | 0 | 0.168091 | 0 | 0 | 889.391 | 2.44186 | 2.30686 | 0 | 1104.39 | 924.391 | 2.44186 | 854.391 | 2.30686 | 0.168091 | 2.44186 | 2.30686 | 924.391 | 854.391 | 0 | 0.0622559 | 2700 | 0.168091 | 5750 | 924.391 | 0.168091 | 1947.77 | 8450 | 2700 | 5750 | 0 | 0.580776 | Face intérieure | Surface-Blanche | Mur-149 | 1-Projet | Sde | A11 | Etage1 | 4 | ArchiCADProperties - Zones conflictuelles: Sde
Mur-149 | Etage1 | 0 | 0 | 2700 | 2700 | 0 | 0 | 0.334534 | 0 | 0 | 1770.01 | 4.32903 | 4.32903 | 0 | 1840.01 | 1770.01 | 4.32903 | 1770.01 | 4.32903 | 0.334534 | 4.77903 | 4.77903 | 1770.01 | 1770.01 | 0 | 0.123901 | 2700 | 0.334534 | 5750 | 1770.01 | 0.334534 | 3680.02 | 8450 | 2700 | 5750 | 0 | 0.625805 | Face intérieure | Surface-Blanche | Mur-149 | 1-Projet | Cellier | B14 | Etage1 | 4
Mur-149 | Etage1 | 0 | 0 | 2700 | 2700 | 0 | 0 | 0.204153 | 0 | 0 | 1080.17 | 2.91647 | 2.53847 | 0 | 1150.17 | 1150.17 | 2.91647 | 1010.17 | 2.53847 | 0.204153 | 3.10547 | 2.72747 | 1150.17 | 1010.17 | 0 | 0.0756121 | 2700 | 0.204153 | 5750 | 1150.17 | 0.204153 | 2358.34 | 8450 | 2700 | 5750 | 0 | 0.685797 | Face intérieure | Surface-Blanche | Mur-149 | 1-Projet | Ch 1 | A11 | Etage1 | 4 | ArchiCADProperties - Zones conflictuelles: Ch 1; Sde
Mur-149 | Etage1 | 0 | 0 | 2700 | 2700 | 0 | 0 | 0.120015 | 0 | 0 | 635 | 1.809 | 1.62 | 0 | 670 | 670 | 1.809 | 600 | 1.62 | 0.120015 | 1.809 | 1.62 | 670 | 600 | 0 | 0.04445 | 2700 | 0.120015 | 5750 | 670 | 0.120015 | 1438.99 | 8450 | 2700 | 5750 | 0 | 0.545186 | Face intérieure | Surface-Blanche | Mur-149 | 1-Projet | Ch 2/pl | B14 | Etage1 | 4
Mur-148 | Etage1 | 0 | 0 | 2700 | 2700 | 0 | 0 | 0.145091 | 0 | 0 | 767.68 | 2.16674 | 1.97873 | 0 | 732.862 | 802.498 | 2.16674 | 732.862 | 1.97873 | 0.145091 | 2.16674 | 1.97873 | 802.498 | 732.862 | 0 | 0.0537376 | 2700 | 0.145091 | 5750 | 802.498 | 0.145091 | 1704.1 | 8450 | 2700 | 5750 | 0 | 0.563068 | Face extérieure | Lavis blanc | Mur-148 | 1-Projet | Sejour cuisine/pl | A15 | Etage1 | 4
Mur-148 | Etage1 | 2 | 0 | 2700 | 2700 | 4.5893 | 2278.05 | 0.43821 | 4.7089 | 4.7089 | 4062.61 | 6.16515 | 6.16613 | 0.329623 | 4027.79 | 1779.38 | 8.05795 | 1709.74 | 8.05893 | 0.767832 | 11.063 | 10.875 | 4097.42 | 4027.79 | 0 | 0.122119 | 2700 | 0.43821 | 5750 | 4097.42 | 0.767832 | 8293.95 | 8450 | 2700 | 5750 | 0 | 0.722094 | Face extérieure | Lavis blanc | Mur-148 | 1-Projet | Sejour cuisine/pl | A15 | Etage1 | 4
Mur-148 | Etage1 | 1 | 0 | 2700 | 0 | 1.6932 | 830 | 0.161452 | 1.8928 | 1.8928 | 1735.28 | 2.21195 | 2.40095 | 0.132496 | 1700.28 | 790.279 | 4.10475 | 860.277 | 4.29375 | 0.293948 | 4.10475 | 4.29375 | 1700.28 | 1770.28 | 0 | 0.0451695 | 2700 | 0.161452 | 5750 | 1590.28 | 0.293948 | 3639.55 | 8450 | 2700 | 5750 | 0 | 0.610322 | Face extérieure | Lavis blanc | Mur-148 | 1-Projet | Wc | A15 | Etage1 | 4
Mur-148 | Etage1 | 0 | 0 | 2700 | 2700 | 0 | 0 | 0.285239 | 0 | 0 | 1509.19 | 4.07514 | 3.8855 | 0 | 1579.08 | 1579.31 | 4.07514 | 1439.07 | 3.8855 | 0.285239 | 4.26414 | 3.8855 | 1579.31 | 1439.07 | 0 | 0.105644 | 2700 | 0.285239 | 5750 | 1579.31 | 0.285239 | 3216.54 | 8450 | 2700 | 5750 | 0 | 0.746311 | Face extérieure | Lavis blanc | Mur-148 | 1-Projet | Wc | A15 | Etage1 | 4
Mur-148 | Etage1 | 1 | 0 | 2700 | 2700 | 1.6932 | 830 | 0.405561 | 1.88898 | 1.88898 | 2845.45 | 5.79372 | 5.60474 | 0.132228 | 3095.45 | 1937.28 | 7.6827 | 1937.29 | 7.49371 | 0.537789 | 7.6827 | 7.68271 | 2845.44 | 2845.45 | 0 | 0.13561 | 2700 | 0.405561 | 5750 | 2845.45 | 0.537789 | 5830.89 | 8450 | 2700 | 5750 | 0 | 0.567191 | Face extérieure | Lavis blanc | Mur-148 | 1-Projet | Sejour cuisine/pl | A15 | Etage1 | 4
Mur-149 | Etage1 | 1 | 0 | 2700 | 2700 | 3.05046 | 1525.23 | 0.0813512 | 3.05046 | 3.05046 | 1560.23 | 1.25666 | 1.06766 | 0.213532 | 1595.23 | 70 | 1.25666 | 0 | 1.06766 | 0.294883 | 4.30712 | 4.11812 | 1595.23 | 1525.23 | 0 | 0.00245 | 2700 | 0.0813512 | 5750 | 1595.23 | 0.294883 | 3289.45 | 8450 | 2700 | 5750 | 0 | 0.427952 | Face intérieure | Surface-Blanche | Mur-149 | 1-Projet | Ch 2/pl | B14 | Etage1 | 4 | ArchiCADProperties - Zones conflictuelles: Ch 2/pl
Mur-149 | Etage1 | 0 | 0 | 2700 | 2700 | 0 | 0 | 0.621831 | 0 | 0 | 3284.93 | 8.7888 | 8.8028 | 0 | 3319.93 | 3249.93 | 8.7888 | 3319.93 | 8.8028 | 0.621831 | 8.7888 | 8.9778 | 3249.93 | 3319.93 | 0 | 0.234845 | 2700 | 0.621831 | 5750 | 3389.93 | 0.621831 | 6738.85 | 8450 | 2700 | 5750 | 0 | 0.925976 | Face intérieure | Surface-Blanche | Mur-149 | 1-Projet | Sejour cuisine | B11 | Etage1 | 4
Mur-150 | Etage1 | 2 | 0 | 3000 | 3000 | 2.8764 | 1410 | 0.443233 | 3.1228 | 3.1228 | 3121.57 | 6.3319 | 5.9119 | 0.218596 | 3371.57 | 1611.57 | 9.4547 | 1611.57 | 9.0347 | 0.661829 | 9.4547 | 9.4547 | 3121.57 | 3121.57 | 0 | 0.12541 | 3000 | 0.443233 | 5750 | 3301.57 | 0.661829 | 6383.13 | 8750 | 3000 | 5750 | 0 | 0.776519 | Face intérieure | Surface-Blanche | Mur-150 | 1-Projet | Ch 1/pl | B12 | Etage1 | 4 | ArchiCADProperties - Zones conflictuelles: Ch 1/pl
Mur-149 | Etage1 | 0 | 0 | 2700 | 2700 | 0 | 0 | 0.536395 | 0 | 0 | 2838.07 | 7.47378 | 7.66278 | 0 | 2838.07 | 2838.07 | 7.47378 | 2838.07 | 7.66278 | 0.536395 | 7.66278 | 7.66278 | 2838.07 | 2838.07 | 0 | 0.198665 | 2700 | 0.536395 | 5750 | 2838.07 | 0.536395 | 5816.14 | 8450 | 2700 | 5750 | 0 | 0.77533 | Face intérieure | Surface-Blanche | Mur-149 | 1-Projet | Ch 2/pl | B14 | Etage1 | 4
Mur-153 | Etage1 | 2 | 0 | 2700 | 2700 | 3.3864 | 1660 | 0.285391 | 3.7856 | 3.7856 | 2912.08 | 3.98252 | 3.79352 | 0.264992 | 2947.07 | 1127.08 | 7.76812 | 1057.08 | 7.57912 | 0.550383 | 7.95712 | 7.76812 | 2947.08 | 2877.08 | 0 | 0.0764456 | 2700 | 0.285391 | 5750 | 2947.08 | 0.550383 | 5993.15 | 8450 | 2700 | 5750 | 0 | 0.590978 | Face extérieure | Peinture-01 | Mur-153 | 1-Projet | Wc | A14 | Etage1 | 4
Mur-149 | Etage1 | 1 | 0 | 2700 | 2700 | 1.6932 | 830 | 0.500276 | 1.8928 | 1.8928 | 3348 | 7.0523 | 7.0523 | 0.132496 | 3313 | 2403 | 8.9451 | 2473 | 8.9451 | 0.632772 | 8.9451 | 9.1341 | 3313 | 3383 | 0 | 0.17066 | 2700 | 0.500276 | 5750 | 3383 | 0.632772 | 6865 | 8450 | 2700 | 5750 | 0 | 0.861306 | Face intérieure | Surface-Blanche | Mur-149 | 1-Projet | Ch 1 | A12 | Etage1 | 4
Mur-149 | Etage1 | 0 | 0 | 2700 | 2700 | 0 | 0 | 0.762915 | 0 | 0 | 4036.59 | 10.8988 | 10.8988 | 0 | 4376.59 | 4036.59 | 10.8988 | 4036.59 | 10.8988 | 0.762915 | 10.8988 | 10.8988 | 4036.59 | 4036.59 | 0 | 0.282561 | 2700 | 0.762915 | 5750 | 4036.59 | 0.762915 | 8213.18 | 8450 | 2700 | 5750 | 0 | 0.943122 | Face intérieure | Surface-Blanche | Mur-149 | 1-Projet | Ch 2 | B13 | Etage1 | 4
Mur-149 | Etage1 | 0 | 0 | 2700 | 2700 | 0 | 0 | 0.199611 | 0 | 0 | 1056.14 | 2.85159 | 2.85159 | 0 | 1196.14 | 1056.14 | 2.85159 | 1056.14 | 2.85159 | 0.199611 | 2.85159 | 2.85159 | 1056.14 | 1056.14 | 0 | 0.07393 | 2700 | 0.199611 | 5750 | 1056.14 | 0.199611 | 2252.29 | 8450 | 2700 | 5750 | 8.88178e-13 | 0.52586 | Face intérieure | Surface-Blanche | Mur-149 | 1-Projet | Cellier | A12 | Etage1 | 4
Mur-149 | Etage1 | 0 | 0 | 2700 | 2700 | 0 | 0 | 0.310905 | 0 | 0 | 1645 | 4.536 | 4.158 | 0 | 1610 | 1680 | 4.536 | 1610 | 4.158 | 0.310905 | 4.536 | 4.347 | 1680 | 1610 | 0 | 0.11515 | 2700 | 0.310905 | 5750 | 1680 | 0.310905 | 3458.99 | 8450 | 2700 | 5750 | 0 | 0.686586 | Face intérieure | Surface-Blanche | Mur-149 | 1-Projet | Cellier | A12 | Etage1 | 4
Mur-149 | Etage1 | 0 | 0 | 2700 | 2700 | 0 | 0 | 0.613441 | 0 | 0 | 3245.72 | 8.77306 | 8.75384 | 0 | 3591.03 | 3249.28 | 8.77306 | 3242.16 | 8.75384 | 0.613441 | 8.77306 | 8.75384 | 3249.28 | 3242.16 | 0 | 0.227201 | 2700 | 0.613441 | 5750 | 3249.28 | 0.613441 | 6631.8 | 8450 | 2700 | 5750 | 0 | 0.833376 | Face intérieure | Surface-Blanche | Mur-149 | 1-Projet | Ch 1 | A12 | Etage1 | 4 | ArchiCADProperties - Zones conflictuelles: Ch 2
Mur-149 | Etage1 | 1 | 0 | 2700 | 2700 | 1.6932 | 830 | 0.344584 | 1.8928 | 1.8928 | 2524.23 | 4.63913 | 4.63913 | 0.132496 | 2629.23 | 1579.23 | 6.53193 | 1649.23 | 6.53193 | 0.47708 | 6.72093 | 6.90993 | 2489.23 | 2559.23 | 0 | 0.112996 | 2700 | 0.344584 | 5750 | 2559.23 | 0.47708 | 5217.46 | 8450 | 2700 | 5750 | 0 | 0.745979 | Face intérieure | Surface-Blanche | Mur-149 | 1-Projet | Cellier | A12 | Etage1 | 4
Mur-149 | Etage1 | 1 | 0 | 2700 | 2700 | 1.6932 | 830 | 0.167131 | 1.8928 | 1.8928 | 1585.33 | 2.29309 | 2.29309 | 0.132496 | 1620.33 | 710.33 | 4.18589 | 640.33 | 4.18589 | 0.299627 | 4.37489 | 4.18589 | 1620.33 | 1550.33 | 0 | 0.0472731 | 2700 | 0.167131 | 5750 | 1620.33 | 0.299627 | 3339.65 | 8450 | 2700 | 5750 | 0 | 0.614533 | Face intérieure | Surface-Blanche | Mur-149 | 1-Projet | Ch 2 | A12 | Etage1 | 4
Mur-149 | Etage1 | 1 | 0 | 2700 | 2700 | 2.02618 | 1013.09 | 0.121189 | 1.9765 | 1.9765 | 1373.25 | 1.44778 | 1.82578 | 0.138355 | 1408.25 | 350 | 3.42428 | 420 | 3.80228 | 0.259545 | 3.61328 | 3.80228 | 1338.25 | 1408.25 | 0 | 0.02695 | 2700 | 0.121189 | 5750 | 1408.25 | 0.259545 | 2915.5 | 8450 | 2700 | 5750 | 0 | 0.439364 | Face intérieure | Surface-Blanche | Mur-149 | 1-Projet | Entree/pl | A12 | Etage1 | 4
Mur-149 | Etage1 | 0 | 0 | 2700 | 2700 | 0 | 0 | 0.568041 | 0 | 0 | 3005.51 | 8.0295 | 8.20025 | 0 | 3044.25 | 2973.89 | 8.0295 | 3037.13 | 8.20025 | 0.568041 | 8.0295 | 8.20025 | 2973.89 | 3037.13 | 0 | 0.210386 | 2700 | 0.568041 | 5750 | 3037.13 | 0.568041 | 6175.36 | 8450 | 2700 | 5750 | 0 | 0.864483 | Face intérieure | Surface-Blanche | Mur-149 | 1-Projet | Ch 2 | A12 | Etage1 | 4
Mur-149 | Etage1 | 0 | 0 | 2700 | 2700 | 0 | 0 | 0.0192353 | 0 | 0 | 101.774 | 0.27 | 0.279579 | 0 | 100 | 100 | 0.27 | 103.548 | 0.279579 | 0.0192353 | 0.27 | 0.279579 | 100 | 103.548 | 0 | 0.00712417 | 2700 | 0.0192353 | 5750 | 103.548 | 0.0192353 | 343.638 | 8450 | 2700 | 5750 | 0 | 0.392491 | Face intérieure | Surface-Blanche | Mur-149 | 1-Projet | Ch 1 | A11 | Etage1 | 4
Mur-149 | Etage1 | 0 | 1 | 2700 | 8.88178e-13 | 0 | 0 | 0.45531 | 1.91776 | 1.91776 | 3189.33 | 6.50445 | 6.3154 | 0.134243 | 3469.34 | 2249.26 | 8.42221 | 2249.25 | 8.23316 | 0.589553 | 8.42221 | 8.42216 | 3189.34 | 3189.33 | 1.91776 | 0.152548 | 2700 | 0.45531 | 5750 | 3119.34 | 0.589553 | 6518.66 | 8450 | 2700 | 5750 | -8.88178e-13 | 0.606101 | Face intérieure | Surface-Blanche | Mur-149 | 1-Projet | Cellier | A12 | Etage1 | 4
Mur-149 | Etage1 | 0 | 0 | 2700 | 2700 | 0 | 0 | 0.431738 | 0 | 0 | 2284.33 | 6.15856 | 5.9878 | 0 | 2280.59 | 2350.95 | 6.15856 | 2217.7 | 5.9878 | 0.431738 | 6.34756 | 5.9878 | 2350.95 | 2217.7 | 0 | 0.159903 | 2700 | 0.431738 | 5750 | 2350.95 | 0.431738 | 4761.98 | 8450 | 2700 | 5750 | 0 | 0.841804 | Face intérieure | Surface-Blanche | Mur-149 | 1-Projet | Ch 2 | A12 | Etage1 | 4
Mur-148 | Etage1 | 0 | 0 | 2700 | 2700 | 0 | 0 | 0.121192 | 0 | 0 | 641.226 | 1.82581 | 1.63681 | 0 | 676.226 | 676.226 | 1.82581 | 606.226 | 1.63681 | 0.121192 | 1.82581 | 1.63681 | 676.226 | 606.226 | 0 | 0.0448858 | 2700 | 0.121192 | 5750 | 676.226 | 0.121192 | 1451.45 | 8450 | 2700 | 5750 | 0 | 0.546058 | Face intérieure | Surface-Blanche | Mur-148 | 1-Projet | Sejour cuisine | B11 | Etage1 | 4
Mur-149 | Etage1 | 1 | 0 | 2700 | 2700 | 1.1832 | 580 | 0.0459056 | 1.23 | 1.23 | 685.108 | 0.750304 | 0.561285 | 0.0861 | 900.117 | 120.112 | 1.9803 | 50.1047 | 1.79129 | 0.132006 | 1.9803 | 1.79129 | 720.112 | 650.105 | 0 | 0.0185582 | 2700 | 0.0459056 | 5750 | 900.117 | 0.132006 | 1539.21 | 8450 | 2700 | 5750 | 0 | 0.535403 | Face intérieure | Peinture-01 | Mur-149 | 1-Projet | Entree/pl | B16 | Etage1 | 4
Mur-149 | Etage1 | 0 | 0 | 2512.25 | 2512.25 | 0 | 0 | 0.11167 | 0 | 0 | 635 | 1.68321 | 1.50735 | 0 | 670 | 670 | 1.68321 | 600 | 1.50735 | 0.11167 | 1.68321 | 1.50735 | 670 | 600 | 0 | 0.04445 | 2512.25 | 0.11167 | 5750 | 670 | 0.11167 | 1438.99 | 8262.25 | 2512.25 | 5750 | 0 | 0.513458 | Face intérieure | Surface-Blanche | Mur-149 | 1-Projet | Ch 1/pl | B13 | Etage1 | 4
Mur-149 | Etage1 | 0 | 0 | 2500 | 2500 | 0 | 0 | 0.0623494 | 0 | 0 | 356.282 | 0.803206 | 0.628206 | 0 | 391.282 | 391.282 | 0.803206 | 321.282 | 0.628206 | 0.0623494 | 0.978206 | 0.803206 | 391.282 | 321.282 | 0 | 0.0249398 | 2500 | 0.0623494 | 5750 | 391.282 | 0.0623494 | 881.56 | 8250 | 2500 | 5750 | 0 | 0.472367 | Face intérieure | Surface-Blanche | Mur-149 | 1-Projet | Entree/pl | B15 | Etage1 | 4
Mur-149 | Etage1 | 0 | 0 | 2700 | 2700 | 0 | 0 | 0.185149 | 0 | 0 | 979.625 | 2.45599 | 2.45599 | 0 | 1049.63 | 979.625 | 2.45599 | 979.625 | 2.45599 | 0.185149 | 2.64499 | 2.64499 | 979.625 | 979.625 | 0 | 0.0685738 | 2700 | 0.185149 | 5750 | 979.625 | 0.185149 | 2099.25 | 8450 | 2700 | 5750 | 0 | 0.515148 | Face intérieure | Peinture-01 | Mur-149 | 1-Projet | Sde | B16 | Etage1 | 4
Mur-149 | Etage1 | 0 | 0 | 2700 | 2700 | 0 | 0 | 0.111798 | 0 | 0 | 591.524 | 1.69161 | 1.50261 | 0 | 696.528 | 626.523 | 1.69161 | 556.524 | 1.50261 | 0.111798 | 1.69161 | 1.50261 | 626.523 | 556.524 | 0 | 0.0414067 | 2700 | 0.111798 | 5750 | 626.524 | 0.111798 | 1352.04 | 8450 | 2700 | 5750 | 0 | 0.5391 | Face intérieure | Peinture-01 | Mur-149 | 1-Projet | Sejour Cuisine/pl | A14 | Etage1 | 4
Mur-149 | Etage1 | 1 | 0 | 2700 | 2700 | 1.6932 | 830 | 0.174913 | 1.8928 | 1.8928 | 1626.5 | 2.40426 | 2.21526 | 0.132496 | 1661.5 | 681.504 | 4.29706 | 751.505 | 4.10806 | 0.307409 | 4.29706 | 4.48606 | 1591.5 | 1661.5 | 0 | 0.0501553 | 2700 | 0.174913 | 5750 | 1661.5 | 0.307409 | 3422 | 8450 | 2700 | 5750 | 0 | 0.620298 | Face intérieure | Surface-Blanche | Mur-149 | 1-Projet | Sde | B14 | Etage1 | 4
Mur-149 | Etage1 | 1 | 0 | 2700 | 2700 | 1.6932 | 830 | 0.349769 | 1.8928 | 1.8928 | 2538.33 | 4.9967 | 4.8077 | 0.132496 | 2718.33 | 2538.33 | 6.8895 | 2538.33 | 6.7005 | 0.482265 | 6.8895 | 6.8895 | 2538.33 | 2538.33 | 0 | 0.190283 | 2700 | 0.349769 | 5750 | 2718.33 | 0.482265 | 5216.66 | 8450 | 2700 | 5750 | 0 | 0.758566 | Face intérieure | Peinture-01 | Mur-149 | 1-Projet | Sde | B16 | Etage1 | 4
Mur-149 | Etage1 | 1 | 0 | 2500 | 2500 | 3.1372 | 1568.6 | 0.061026 | 3.1372 | 3.1372 | 1603.6 | 0.9593 | 0.7843 | 0.219604 | 1978.6 | 70 | 0.9593 | 0 | 0.7843 | 0.28063 | 4.0965 | 3.9215 | 1638.6 | 1568.6 | 0 | 0.00245 | 2500 | 0.061026 | 5750 | 1638.6 | 0.28063 | 3376.19 | 8250 | 2500 | 5750 | 0 | 0.397189 | Face intérieure | Surface-Blanche | Mur-149 | 1-Projet | Ch 1/pl | B15 | Etage1 | 4 | ArchiCADProperties - Zones conflictuelles: Ch 1/pl
Mur-149 | Etage1 | 2 | 0 | 2700 | 2300 | 3.3864 | 1660 | 0.820912 | 3.7856 | 3.7856 | 5748.12 | 11.4508 | 11.2618 | 0.264992 | 5713.12 | 3963.12 | 15.2364 | 3893.12 | 15.0474 | 1.0859 | 15.6144 | 15.4254 | 5783.12 | 5713.12 | 0 | 0.274968 | 2700 | 0.820912 | 5750 | 5783.12 | 1.08639 | 11665.2 | 8450 | 2700 | 5750 | 0 | 1.11382 | Face intérieure | Peinture-01 | Mur-149 | 1-Projet | Sejour cuisine | B16 | Etage1 | 4
Mur-149 | Etage1 | 1 | 0 | 2700 | 2700 | 1.1832 | 580 | 0.031842 | 1.1366 | 1.1366 | 589.44 | 0.549386 | 0.360386 | 0.0795621 | 624.44 | 70 | 1.68599 | 0 | 1.49699 | 0.111404 | 1.68599 | 1.49699 | 624.44 | 554.44 | 0 | 0.00245 | 2700 | 0.031842 | 5750 | 624.44 | 0.111404 | 1347.87 | 8450 | 2700 | 5750 | 0 | 0.356497 | Face intérieure | Peinture-01 | Mur-149 | 1-Projet | Sejour cuisine | B15 | Etage1 | 4
Mur-152 | Etage1 | 0 | 0 | 3000 | 3000 | 0 | 0 | 0.0304683 | 0 | 0 | 145.087 | 0.0602645 | 0.810257 | 0 | 340.086 | 20.0882 | 0.0602645 | 270.086 | 0.810257 | 0.0304683 | 0.0602645 | 0.810257 | 20.0882 | 270.086 | 0 | 0.0101561 | 3000 | 0.0304683 | 5750 | 270.088 | 0.0304683 | 619.789 | 8750 | 3000 | 5750 | 0 | 1.00916 | Face extérieure | Peinture-01 | Mur-152 | 1-Projet | Sejour cuisine | A13 | Etage1 | 4
Mur-149 | Etage1 | 0 | 0 | 3000 | 3000 | 0 | 0 | 0.346856 | 0 | 0 | 1651.7 | 4.74509 | 4.95509 | 0 | 1651.7 | 1651.7 | 4.74509 | 1651.7 | 4.95509 | 0.346856 | 4.95509 | 4.95509 | 1651.7 | 1651.7 | 0 | 0.115619 | 3000 | 0.346856 | 5750 | 1651.7 | 0.346856 | 3443.39 | 8750 | 3000 | 5750 | 0 | 0.651237 | Face intérieure | Surface-Blanche | Mur-149 | 1-Projet | Ch 1 | A13 | Etage1 | 4 | ArchiCADProperties - Zones conflictuelles: Ch 1; Ch 1; Dressing; Sde
Mur-153 | Etage1 | 1 | 0 | 3000 | 0 | 1.6932 | 830 | 0.408336 | 1.8928 | 1.8928 | 2655.13 | 5.62336 | 5.83337 | 0.132496 | 2655.13 | 1745.13 | 7.51616 | 1745.13 | 7.72617 | 0.540832 | 7.7554 | 7.7554 | 2655.13 | 2655.13 | 0 | 0.117259 | 3000 | 0.408336 | 5750 | 2585.14 | 0.542878 | 5450.27 | 8750 | 3000 | 5750 | 0 | 0.704219 | Face extérieure | Peinture-01 | Mur-153 | 1-Projet | Sejour cuisine | A13 | Etage1 | 4
Mur-151 | Etage1 | 1 | 1 | 3000 | 3000 | 1.6932 | 830 | 0.599631 | 3.86583 | 3.86582 | 4097.33 | 8.56616 | 8.56617 | 0.270608 | 4657.33 | 2220.16 | 12.432 | 2220.16 | 12.432 | 0.870239 | 12.432 | 12.432 | 4097.33 | 4097.33 | 1.97302 | 0.194611 | 3000 | 0.599631 | 5750 | 4657.33 | 0.870239 | 8334.66 | 8750 | 3000 | 5750 | 0 | 0.797824 | Face extérieure | Peinture-01 | Mur-151 | 1-Projet | Ch 1 | A13 | Etage1 | 4 | ArchiCADProperties - Zones conflictuelles: Ch 1; Ch 1
Mur-149 | Etage1 | 0 | 0 | 3000 | 3000 | 0 | 0 | 0.072904 | 0 | 0 | 347.162 | 1.14649 | 0.936479 | 0 | 382.164 | 382.164 | 1.14649 | 312.16 | 0.936479 | 0.072904 | 1.14649 | 0.936479 | 382.164 | 312.16 | 0 | 0.0243013 | 3000 | 0.072904 | 5750 | 382.164 | 0.072904 | 863.322 | 8750 | 3000 | 5750 | 0 | 0.555597 | Face intérieure | Surface-Blanche | Mur-149 | 1-Projet | Sde | A13 | Etage1 | 4
Mur-152 | Etage1 | 0 | 0 | 3000 | 2100 | 0 | 0 | 0.236744 | 0 | 0 | 1164.86 | 3.49457 | 2.8416 | 0 | 1414.86 | 1164.86 | 3.49457 | 1164.86 | 2.8416 | 0.236744 | 3.49457 | 3.49457 | 1164.86 | 1164.86 | 0 | 0.0815401 | 3000 | 0.236744 | 5750 | 1164.86 | 0.24462 | 2469.72 | 8750 | 3000 | 5750 | 0 | 0.569557 | Face extérieure | Peinture-01 | Mur-152 | 1-Projet | Sejour cuisine | A13 | Etage1 | 4
Mur-149 | Etage1 | 0 | 0 | 2500 | 2500 | 0 | 0 | 0.111125 | 0 | 0 | 635 | 1.5 | 1.675 | 0 | 850 | 600 | 1.5 | 670 | 1.675 | 0.111125 | 1.5 | 1.675 | 600 | 670 | 0 | 0.0444501 | 2500 | 0.111125 | 5750 | 670 | 0.111125 | 1438.99 | 8250 | 2500 | 5750 | 0 | 0.511388 | Face intérieure | Peinture-01 | Mur-149 | 1-Projet | Sejour cuisine | B16 | Etage1 | 4
Mur-149 | Etage1 | 1 | 0 | 2500 | 0 | 1.1832 | 580 | 0.130902 | 1.23 | 1.23 | 1310.01 | 1.69503 | 1.87003 | 0.0861 | 1310.01 | 710.012 | 2.92503 | 710.012 | 3.10003 | 0.217002 | 3.10003 | 3.10003 | 1310.01 | 1310.01 | 0 | 0.0448008 | 2500 | 0.130902 | 5750 | 1240.06 | 0.217002 | 2760.02 | 8250 | 2500 | 5750 | 0 | 0.481602 | Face intérieure | Surface-Blanche | Mur-149 | 1-Projet | Entree/pl | B15 | Etage1 | 4
Mur-152 | Etage1 | 0 | 0 | 3000 | 2100 | 0 | 0 | 0.0349537 | 0 | 0 | 176.192 | 0.499338 | 0.499338 | 0 | 246.192 | 176.192 | 0.499338 | 176.192 | 0.499338 | 0.0349537 | 0.528577 | 0.528577 | 176.192 | 176.192 | 0 | 0.0123335 | 3000 | 0.0349537 | 5750 | 176.192 | 0.0370004 | 492.384 | 8750 | 3000 | 5750 | -8.88178e-13 | 0.430667 | Face extérieure | Peinture-01 | Mur-152 | 1-Projet |  |  | Etage1 | 4
Mur-149 | Etage1 | 0 | 0 | 2700 | 2700 | 0 | 0 | 0.749575 | 0 | 0 | 3966.01 | 10.7082 | 10.7082 | 0 | 4376.01 | 3966.01 | 10.7082 | 3966.01 | 10.7082 | 0.749575 | 10.7082 | 10.7082 | 3966.01 | 3966.01 | 0 | 0.277621 | 2700 | 0.749575 | 5750 | 3966.01 | 0.749575 | 8072.02 | 8450 | 2700 | 5750 | 0 | 0.933241 | Face intérieure | Peinture-01 | Mur-149 | 1-Projet | Ch 2 | B16 | Etage1 | 4
Mur-149 | Etage1 | 1 | 0 | 2700 | 2700 | 1.68669 | 843.343 | 0.100789 | 1.60669 | 1.60669 | 1128.34 | 1.53434 | 1.15634 | 0.112468 | 1163.34 | 360 | 3.14103 | 290 | 2.76303 | 0.213257 | 3.14103 | 2.95203 | 1163.34 | 1093.34 | 0 | 0.02275 | 2700 | 0.100789 | 5750 | 1163.34 | 0.213257 | 2425.68 | 8450 | 2700 | 5750 | 0 | 0.41802 | Face intérieure | Peinture-01 | Mur-149 | 1-Projet | Entree/pl | B16 | Etage1 | 4
Mur-149 | Etage1 | 0 | 0 | 2500 | 2300 | 0 | 0 | 0.234726 | 0 | 0 | 1355.69 | 3.26573 | 3.44073 | 0 | 1390.69 | 1320.69 | 3.26573 | 1390.69 | 3.44073 | 0.234726 | 3.30173 | 3.47673 | 1320.69 | 1390.69 | 0 | 0.0948985 | 2500 | 0.234726 | 5750 | 1390.69 | 0.237246 | 2880.38 | 8250 | 2500 | 5750 | 0 | 0.599684 | Face intérieure | Peinture-01 | Mur-149 | 1-Projet | Sejour cuisine | B16 | Etage1 | 4
Mur-149 | Etage1 | 1 | 0 | 2500 | 2500 | 1.6932 | 830 | 0.223672 | 1.8928 | 1.8928 | 2035.25 | 3.02032 | 3.02032 | 0.132496 | 2035.25 | 1125.25 | 4.91312 | 1125.25 | 4.91312 | 0.356168 | 5.08812 | 5.08812 | 2035.25 | 2035.25 | 0 | 0.0787673 | 2500 | 0.223672 | 5750 | 2035.25 | 0.356168 | 4210.49 | 8250 | 2500 | 5750 | 0 | 0.571235 | Face intérieure | Surface-Blanche | Mur-149 | 1-Projet | Sde | B11 | Etage1 | 4
Mur-149 | Etage1 | 1 | 0 | 2700 | 0 | 1.6932 | 830 | 0.334334 | 1.8928 | 1.8928 | 2610 | 4.6817 | 4.4927 | 0.132496 | 2645 | 1735 | 6.5745 | 1665 | 6.3855 | 0.46683 | 6.7635 | 6.5745 | 2645 | 2575 | 0 | 0.1092 | 2700 | 0.334334 | 5750 | 2505.02 | 0.46683 | 5388.99 | 8450 | 2700 | 5750 | 0 | 0.738364 | Face intérieure | Peinture-01 | Mur-149 | 1-Projet | Sejour cuisine | B14 | Etage1 | 4 | ArchiCADProperties - Zones conflictuelles: Entree/pl; Sejour cuisine; Wc
Mur-149 | Etage1 | 0 | 0 | 2700 | 2700 | 0 | 0 | 0.206781 | 0 | 0 | 1096.67 | 2.49702 | 2.51102 | 0 | 1096.67 | 1096.67 | 2.49702 | 1096.67 | 2.51102 | 0.206781 | 2.94702 | 2.96102 | 1096.67 | 1096.67 | 0 | 0.0767671 | 2700 | 0.206781 | 5750 | 1096.67 | 0.206781 | 2333.34 | 8450 | 2700 | 5750 | 0 | 0.537333 | Face intérieure | Peinture-01 | Mur-149 | 1-Projet | Sejour cuisine | B14 | Etage1 | 4
Mur-149 | Etage1 | 1 | 0 | 2500 | 2500 | 1.1832 | 580 | 0.0441057 | 1.23 | 1.23 | 744.033 | 0.455082 | 0.630082 | 0.0861 | 744.033 | 144.033 | 1.68508 | 144.033 | 1.86008 | 0.130206 | 1.86008 | 1.86008 | 744.033 | 744.033 | 0 | 0.0100823 | 2500 | 0.0441057 | 5750 | 744.033 | 0.130206 | 1628.07 | 8250 | 2500 | 5750 | 0 | 0.412165 | Face intérieure | Peinture-01 | Mur-149 | 1-Projet | Sejour cuisine | B14 | Etage1 | 4 | ArchiCADProperties - Zones conflictuelles: Sejour cuisine
Mur-149 | Etage1 | 0 | 0 | 2700 | 2700 | 0 | 0 | 0.536404 | 0 | 0 | 2838.12 | 7.47392 | 7.66292 | 0 | 2838.12 | 2838.12 | 7.47392 | 2838.12 | 7.66292 | 0.536404 | 7.66292 | 7.66292 | 2838.12 | 2838.12 | 0 | 0.198668 | 2700 | 0.536404 | 5750 | 2838.12 | 0.536404 | 5816.24 | 8450 | 2700 | 5750 | 0 | 0.775336 | Face intérieure | Surface-Blanche | Mur-149 | 1-Projet | Ch 3 | B14 | Etage1 | 4
Mur-149 | Etage1 | 0 | 0 | 2700 | 2700 | 0 | 0 | 0.120068 | 0 | 0 | 635.278 | 1.80975 | 1.62075 | 0 | 670.278 | 670.278 | 1.80975 | 600.278 | 1.62075 | 0.120068 | 1.80975 | 1.62075 | 670.278 | 600.278 | 0 | 0.0444695 | 2700 | 0.120068 | 5750 | 670.278 | 0.120068 | 1439.52 | 8450 | 2700 | 5750 | 0 | 0.545148 | Face intérieure | Peinture-01 | Mur-149 | 1-Projet | Sejour cuisine | B14 | Etage1 | 4
Mur-149 | Etage1 | 0 | 0 | 2700 | 2700 | 0 | 0 | 0.259781 | 0 | 0 | 1374.5 | 3.52216 | 3.52216 | 0 | 1374.5 | 1374.5 | 3.52216 | 1374.5 | 3.52216 | 0.259781 | 3.71116 | 3.71116 | 1374.5 | 1374.5 | 0 | 0.0962153 | 2700 | 0.259781 | 5750 | 1374.5 | 0.259781 | 2889.01 | 8450 | 2700 | 5750 | 0 | 0.570431 | Face intérieure | Peinture-01 | Mur-149 | 1-Projet | Entree/pl | B15 | Etage1 | 4
Mur-149 | Etage1 | 1 | 0 | 2700 | 2700 | 1.74386 | 871.932 | 0.13513 | 1.6363 | 1.6363 | 1321.01 | 1.74143 | 1.93043 | 0.114541 | 1321.01 | 502.859 | 3.37773 | 502.859 | 3.56673 | 0.249671 | 3.56673 | 3.56673 | 1321.01 | 1321.01 | 0 | 0.0352002 | 2700 | 0.13513 | 5750 | 1321.01 | 0.249671 | 2782.02 | 8450 | 2700 | 5750 | 0 | 0.365671 | Face intérieure | Peinture-01 | Mur-149 | 1-Projet | Entree/pl | B15 | Etage1 | 4
Mur-149 | Etage1 | 1 | 0 | 2700 | 2700 | 1.6932 | 830 | 0.493046 | 1.8928 | 1.8928 | 3312.34 | 6.50601 | 6.68103 | 0.132496 | 3347.34 | 2367.34 | 8.39881 | 2437.34 | 8.57383 | 0.625542 | 8.84881 | 9.02383 | 3277.34 | 3347.34 | 0 | 0.168164 | 2700 | 0.493046 | 5750 | 3347.34 | 0.625542 | 6793.67 | 8450 | 2700 | 5750 | 0 | 0.850506 | Face intérieure | Peinture-01 | Mur-149 | 1-Projet | Ch 2 | B15 | Etage1 | 4 | ArchiCADProperties - Zones conflictuelles: Ch 2; Sejour cuisine
Mur-149 | Etage1 | 1 | 0 | 2500 | 2500 | 1.6932 | 830 | 0.22355 | 1.8928 | 1.8928 | 2034.55 | 3.19358 | 3.19358 | 0.132496 | 2104.55 | 1124.55 | 5.08638 | 1124.55 | 5.08638 | 0.356046 | 5.08638 | 5.08638 | 2034.55 | 2034.55 | 0 | 0.0787185 | 2500 | 0.22355 | 5750 | 2034.55 | 0.356046 | 4209.1 | 8250 | 2500 | 5750 | 0 | 0.571137 | Face intérieure | Peinture-01 | Mur-149 | 1-Projet | Cellier | B15 | Etage1 | 4
Mur-149 | Etage1 | 0 | 0 | 2700 | 0 | 0 | 0 | 0.113451 | 0 | 0 | 670.271 | 1.62073 | 1.62073 | 0 | 670.271 | 670.271 | 1.62073 | 670.271 | 1.62073 | 0.113451 | 1.62073 | 1.62073 | 670.271 | 670.271 | 0 | 0.042019 | 2700 | 0.113451 | 5750 | 600.271 | 0.113451 | 1480.54 | 8450 | 2700 | 5750 | 0 | 0.462038 | Face intérieure | Peinture-01 | Mur-149 | 1-Projet | Wc | B15 | Etage1 | 4
Mur-149 | Etage1 | 1 | 0 | 2700 | 2300 | 1.6932 | 830 | 0.29517 | 1.8928 | 1.8928 | 2276.12 | 4.02772 | 4.21672 | 0.132496 | 2346.12 | 1366.12 | 5.92052 | 1366.12 | 6.10952 | 0.427666 | 6.14552 | 6.14552 | 2276.12 | 2276.12 | 0 | 0.102447 | 2700 | 0.29517 | 5750 | 2276.12 | 0.430186 | 4692.24 | 8450 | 2700 | 5750 | 0 | 0.632957 | Face intérieure | Peinture-01 | Mur-149 | 1-Projet | Wc | B15 | Etage1 | 4
Mur-149 | Etage1 | 0 | 1 | 2500 | 2300 | 0 | 0 | 0.271583 | 2.54052 | 2.54052 | 2573.71 | 3.87976 | 3.70476 | 0.177836 | 2573.71 | 1328.36 | 3.87976 | 1328.36 | 3.70476 | 0.44942 | 6.43428 | 6.43428 | 2573.71 | 2573.71 | 2.54052 | 0.0929851 | 2500 | 0.271583 | 5750 | 2573.71 | 0.4504 | 5287.42 | 8250 | 2500 | 5750 | 0 | 0.461445 | Face intérieure | Peinture-01 | Mur-149 | 1-Projet | Cellier | B15 | Etage1 | 4
Mur-149 | Etage1 | 1 | 0 | 2700 | 2700 | 1.6932 | 830 | 0.400482 | 1.8928 | 1.8928 | 2819.99 | 5.72118 | 5.53218 | 0.132496 | 2819.99 | 1909.99 | 7.61398 | 1909.99 | 7.42498 | 0.532978 | 7.61398 | 7.61398 | 2819.99 | 2819.99 | 0 | 0.133699 | 2700 | 0.400482 | 5750 | 2819.99 | 0.532978 | 5779.98 | 8450 | 2700 | 5750 | 0 | 0.709099 | Face intérieure | Peinture-01 | Mur-149 | 1-Projet | Ch 3 | B15 | Etage1 | 4
Mur-149 | Etage1 | 0 | 0 | 2700 | 2300 | 0 | 0 | 0.118813 | 0 | 0 | 628.645 | 1.79179 | 1.60287 | 0 | 663.63 | 663.63 | 1.79179 | 593.66 | 1.60287 | 0.118813 | 1.7918 | 1.60288 | 663.63 | 593.66 | 0 | 0.0440051 | 2700 | 0.118813 | 5750 | 663.63 | 0.118814 | 1426.26 | 8450 | 2700 | 5750 | 0 | 0.530239 | Face intérieure | Peinture-01 | Mur-149 | 1-Projet | Sejour cuisine | B15 | Etage1 | 4
Mur-149 | Etage1 | 2 | 0 | 2700 | 2700 | 2.8764 | 1410 | 0.252964 | 3.1228 | 3.1228 | 2495.03 | 2.95227 | 2.57427 | 0.218596 | 2460.03 | 1020.03 | 6.07507 | 950.026 | 5.69707 | 0.47156 | 6.83107 | 6.64207 | 2530.03 | 2460.03 | 0 | 0.0689518 | 2700 | 0.252964 | 5750 | 2530.03 | 0.47156 | 5159.05 | 8450 | 2700 | 5750 | 0 | 0.69989 | Face intérieure | Peinture-01 | Mur-149 | 1-Projet | Wc | A12 | Etage1 | 4
Mur-149 | Etage1 | 0 | 0 | 2700 | 2700 | 0 | 0 | 0.1134 | 0 | 0 | 600 | 1.62 | 1.62 | 0 | 670 | 600 | 1.62 | 600 | 1.62 | 0.1134 | 1.62 | 1.62 | 600 | 600 | 0 | 0.042 | 2700 | 0.1134 | 5750 | 600 | 0.1134 | 1340 | 8450 | 2700 | 5750 | -8.88178e-13 | 0.462 | Face intérieure | Surface-Blanche | Mur-149 | 1-Projet | Entree/pl | A12 | Etage1 | 4
Mur-149 | Etage1 | 0 | 0 | 2700 | 2700 | 0 | 0 | 0.128392 | 0 | 0 | 679.323 | 1.92867 | 1.73967 | 0 | 714.322 | 714.322 | 1.92867 | 644.323 | 1.73967 | 0.128392 | 1.92867 | 1.73967 | 714.322 | 644.323 | 0 | 0.0475526 | 2700 | 0.128392 | 5750 | 714.322 | 0.128392 | 1527.64 | 8450 | 2700 | 5750 | 0 | 0.551391 | Face intérieure | Peinture-01 | Mur-149 | 1-Projet | Sejour cuisine | B15 | Etage1 | 4
Mur-149 | Etage1 | 1 | 0 | 2700 | 2700 | 1.1832 | 580 | 0.0803341 | 1.23 | 1.23 | 880.604 | 0.95849 | 1.14777 | 0.0861 | 880.552 | 210.552 | 2.18849 | 350.655 | 2.37777 | 0.166434 | 2.18849 | 2.56677 | 810.552 | 950.655 | 0 | 0.0196422 | 2700 | 0.0803341 | 5750 | 950.655 | 0.166434 | 1959.27 | 8450 | 2700 | 5750 | 0 | 0.616054 | Face intérieure | Peinture-01 | Mur-149 | 1-Projet | Entree | A11 | Etage1 | 4
Mur-149 | Etage1 | 0 | 0 | 2700 | 2300 | 0 | 0 | 0.169603 | 0 | 0 | 969.163 | 2.33541 | 2.51041 | 0 | 1004.16 | 934.163 | 2.33541 | 1004.16 | 2.51041 | 0.169603 | 2.52224 | 2.71124 | 934.163 | 1004.16 | 0 | 0.0678414 | 2700 | 0.169603 | 5750 | 1004.16 | 0.183172 | 2107.32 | 8450 | 2700 | 5750 | 0 | 0.55817 | Face intérieure | Peinture-01 | Mur-149 | 1-Projet | Sejour cuisine | B16 | Etage1 | 4
Mur-149 | Etage1 | 0 | 1 | 2700 | 2700 | 0 | 0 | 0.07196 | 2.55 | 2.55 | 1320 | 0.839 | 0.839 | 0.1785 | 1390 | 70 | 0.839 | 70 | 0.839 | 0.25046 | 3.578 | 3.578 | 1320 | 1320 | 2.55 | 0.0098 | 2700 | 0.07196 | 5750 | 1390 | 0.25046 | 2780 | 8450 | 2700 | 5750 | 0 | 0.3423 | Face intérieure | Peinture-01 | Mur-149 | 1-Projet | Sejour cuisine | B14 | Etage1 | 4 | ArchiCADProperties - Zones conflictuelles: Wc
Mur-149 | Etage1 | 0 | 0 | 2700 | 2700 | 0 | 0 | 0.347875 | 0 | 0 | 1840.61 | 4.33065 | 4.14165 | 0 | 1840.61 | 1840.61 | 4.33065 | 1840.61 | 4.14165 | 0.347875 | 4.96965 | 4.96965 | 1840.61 | 1840.61 | 0 | 0.128843 | 2700 | 0.347875 | 5750 | 1840.61 | 0.347875 | 3821.22 | 8450 | 2700 | 5750 | 0 | 0.635686 | Face intérieure | Peinture-01 | Mur-149 | 1-Projet | Sejour cuisine | B14 | Etage1 | 4 | ArchiCADProperties - Zones conflictuelles: Sejour cuisine
Mur-149 | Etage1 | 1 | 1 | 2500 | 2500 | 1.6932 | 830 | 0.17629 | 3.8274 | 3.8274 | 2538.33 | 2.51843 | 2.34343 | 0.267918 | 2718.33 | 680 | 6.34583 | 680 | 6.17083 | 0.444208 | 6.34583 | 6.34583 | 2538.33 | 2538.33 | 1.9346 | 0.0476 | 2500 | 0.17629 | 5750 | 2538.33 | 0.444208 | 5216.66 | 8250 | 2500 | 5750 | 0 | 0.432483 | Face intérieure | Peinture-01 | Mur-149 | 1-Projet | Sejour cuisine | B16 | Etage1 | 4
Mur-149 | Etage1 | 0 | 0 | 2700 | 2700 | 0 | 0 | 0.126221 | 0 | 0 | 670.43 | 1.98511 | 1.62122 | 0 | 670.41 | 740.41 | 1.98511 | 600.451 | 1.62122 | 0.126221 | 1.98511 | 1.62122 | 740.41 | 600.451 | 0 | 0.0469301 | 2700 | 0.126221 | 5750 | 740.41 | 0.126221 | 1538.82 | 8450 | 2700 | 5750 | 0 | 0.622556 | Face intérieure | Peinture-01 | Mur-149 | 1-Projet | Sejour cuisine | B14 | Etage1 | 4
Mur-149 | Etage1 | 0 | 0 | 2700 | 2700 | 0 | 0 | 0.06286 | 0 | 0 | 330 | 0.905 | 0.891 | 0 | 400 | 330 | 0.905 | 330 | 0.891 | 0.06286 | 0.905 | 0.891 | 330 | 330 | 0 | 0.02555 | 2700 | 0.06286 | 5750 | 400 | 0.06286 | 800 | 8450 | 2700 | 5750 | 0 | 0.434899 | Face intérieure | Peinture-01 | Mur-149 | 1-Projet |  |  | Etage1 | 4
Mur-149 | Etage1 | 0 | 0 | 3000 | 3000 | 0 | 0 | 0.152696 | 0 | 0 | 709.124 | 2.28637 | 2.07637 | 0 | 924.124 | 744.124 | 2.28637 | 674.124 | 2.07637 | 0.152696 | 2.28637 | 2.07637 | 744.124 | 674.124 | 0 | 0.0622387 | 3000 | 0.152696 | 5750 | 924.124 | 0.152696 | 1587.24 | 8750 | 3000 | 5750 | 0 | 0.631462 | Face intérieure | Surface-Blanche | Mur-149 | 1-Projet | Sde | B14 | Etage1 | 4
Mur-149 | Etage1 | 1 | 0 | 2700 | 2700 | 3.17997 | 1589.99 | 0.0825623 | 3.09997 | 3.09996 | 1584.97 | 1.27394 | 1.08499 | 0.216998 | 1619.97 | 69.9812 | 1.27394 | 0 | 1.08497 | 0.29956 | 4.37391 | 4.18494 | 1619.97 | 1549.98 | 0 | 0.00244934 | 2700 | 0.0825623 | 5750 | 1619.97 | 0.29956 | 3338.93 | 8450 | 2700 | 5750 | 0 | 0.42965 | Face intérieure | Surface-Blanche | Mur-149 | 1-Projet | Entree/pl | B14 | Etage1 | 4
Mur-149 | Etage1 | 0 | 0 | 3000 | 3000 | 0 | 0 | 0.110316 | 0 | 0 | 649.202 | 1.58677 | 1.56512 | 0 | 744.125 | 624.125 | 1.58677 | 674.279 | 1.56512 | 0.110316 | 1.58677 | 1.56512 | 624.125 | 674.279 | 0 | 0.0496441 | 3000 | 0.110316 | 5750 | 744.125 | 0.110316 | 1454.52 | 8750 | 3000 | 5750 | 0 | 0.528244 | Face intérieure | Surface-Blanche | Mur-149 | 1-Projet |  |  | Etage1 | 4 | ArchiCADProperties - Zones conflictuelles: Sde
Mur-121 | Etage1 | 0 | 0 | 2500 | 2500 | 0 | 0 | 0.0577501 | 0 | 0 | 330.001 | 0.825001 | 0.825001 | 0 | 580.001 | 330.001 | 0.825001 | 330.001 | 0.825001 | 0.0577501 | 0.825001 | 0.825001 | 330.001 | 330.001 | 0 | 0.0231 | 2500 | 0.0577501 | 5750 | 330.001 | 0.0577501 | 800.001 | 8250 | 2500 | 5750 | -8.88178e-13 | 0.3962 | Face extérieure | Lavis blanc | Mur-121 | 1-Projet |  |  | Etage1 | 4
Mur-149 | Etage1 | 1 | 0 | 2700 | 2700 | 1.1832 | 580 | 0.0330825 | 1.189 | 1.189 | 615.41 | 0.567107 | 0.378107 | 0.08323 | 650.41 | 70.4101 | 1.75611 | 0.410108 | 1.56711 | 0.116313 | 1.75611 | 1.56711 | 650.41 | 580.41 | 0 | 0.00247871 | 2700 | 0.0330825 | 5750 | 650.41 | 0.116313 | 1399.82 | 8450 | 2700 | 5750 | 0 | 0.358344 | Face intérieure | Peinture-01 | Mur-149 | 1-Projet | Sejour cuisine | B14 | Etage1 | 4 | ArchiCADProperties - Zones conflictuelles: Sejour cuisine
Mur-149 | Etage1 | 0 | 0 | 2700 | 2700 | 0 | 0 | 0.824646 | 0 | 0 | 4363.21 | 11.5916 | 11.7807 | 0 | 4703.2 | 4363.2 | 11.5916 | 4363.22 | 11.7807 | 0.824646 | 11.7806 | 11.7807 | 4363.2 | 4363.22 | 0 | 0.305424 | 2700 | 0.824646 | 5750 | 4363.22 | 0.824646 | 8866.41 | 8450 | 2700 | 5750 | 0 | 0.988849 | Face intérieure | Peinture-01 | Mur-149 | 1-Projet | Ch 2 | B15 | Etage1 | 4
Mur-121 | Etage1 | 0 | 0 | 3000 | 0 | 0 | 0 | 0.0691482 | 0 | 0 | 399.277 | 0.987831 | 0.987831 | 0 | 399.277 | 399.277 | 0.987831 | 399.277 | 0.987831 | 0.0691482 | 0.987831 | 0.987831 | 399.277 | 399.277 | 0 | 0.0230494 | 3000 | 0.0691482 | 5750 | 329.277 | 0.0691482 | 938.554 | 8750 | 3000 | 5750 | 0 | 0.466099 | Face extérieure | Lavis blanc | Mur-121 | 1-Projet |  |  | Etage1 | 4
2 x Mur-121 | Etage1 | 0 | 0 | 3000 | 3000 | 0 | 0 | 0.0693254 | 0 | 0 | 330.121 | 0.990362 | 0.990362 | 0 | 400.121 | 330.121 | 0.990362 | 330.121 | 0.990362 | 0.0693254 | 0.990362 | 0.990362 | 330.121 | 330.121 | 0 | 0.0231085 | 3000 | 0.0693254 | 5750 | 330.121 | 0.0693254 | 800.242 | 8750 | 3000 | 5750 | 0 | 0.466217 | Face extérieure | Lavis blanc | Mur-121 | 1-Projet |  |  | Etage1 | 4
Mur-120 | Etage1 | 5 | 0 | 3000 | 3000 | 5.61 | 2750 | 0.356614 | 5.8425 | 5.8425 | 3645.66 | 4.04448 | 4.67448 | 0.408975 | 3645.66 | 795.661 | 9.88698 | 795.661 | 10.517 | 0.765589 | 10.937 | 10.937 | 3645.66 | 3645.66 | 0 | 0.0556963 | 3000 | 0.356614 | 5750 | 3645.66 | 0.765589 | 7431.32 | 8750 | 3000 | 5750 | 0 | 0.730893 | Face extérieure | Lavis blanc | Mur-120 | 3D |  |  | Etage1 | 4
Mur-121 | Etage1 | 0 | 0 | 3000 | 3000 | 0 | 0 | 0.0693254 | 0 | 0 | 330.121 | 0.990363 | 0.990363 | 0 | 400.121 | 330.121 | 0.990363 | 330.121 | 0.990363 | 0.0693254 | 0.990363 | 0.990363 | 330.121 | 330.121 | 0 | 0.0231085 | 3000 | 0.0693254 | 5750 | 330.121 | 0.0693254 | 800.242 | 8750 | 3000 | 5750 | 0 | 0.466217 | Face extérieure | Lavis blanc | Mur-121 | 1-Projet |  |  | Etage1 | 4
Mur-121 | Etage1 | 0 | 0 | 3000 | 0 | 0 | 0 | 0.0690435 | 0 | 0 | 398.779 | 0.986336 | 0.986336 | 0 | 398.779 | 398.779 | 0.986336 | 398.779 | 0.986336 | 0.0690435 | 0.986336 | 0.986336 | 398.779 | 398.779 | 0 | 0.0230145 | 3000 | 0.0690435 | 5750 | 328.779 | 0.0690435 | 937.557 | 8750 | 3000 | 5750 | 0 | 0.466029 | Face extérieure | Lavis blanc | Mur-121 | 1-Projet |  |  | Etage1 | 4
Mur-120 | Etage1 | 0 | 0 | 2460 | 2460 | 0 | 0 | 0.0869144 | 0 | 0 | 504.729 | 1.41383 | 1.06943 | 0 | 915.562 | 574.729 | 1.41383 | 434.729 | 1.06943 | 0.0869144 | 1.41383 | 1.06943 | 574.729 | 434.729 | 0 | 0.035331 | 2460 | 0.0869144 | 5750 | 574.729 | 0.0869144 | 1207.45 | 8210 | 2460 | 5750 | 0 | 0.557717 | Face extérieure | Lavis blanc | Mur-120 | 3D |  |  | Etage1 | 4
Mur-149 | Etage1 | 2 | 0 | 2500 | 2500 | 3.3864 | 1660 | 0.109429 | 3.7856 | 3.7856 | 2139.55 | 1.47578 | 1.47576 | 0.264992 | 2104.55 | 284.55 | 5.26138 | 354.545 | 5.26136 | 0.374421 | 5.26138 | 5.43636 | 2104.55 | 2174.54 | 0 | 0.0223683 | 2500 | 0.109429 | 5750 | 2174.54 | 0.374421 | 4448.09 | 8250 | 2500 | 5750 | 0 | 0.594615 | Face intérieure | Surface-Blanche | Mur-149 | 1-Projet | Dgt | B15 | Etage1 | 4
Mur-149 | Etage1 | 0 | 0 | 2700 | 2700 | 0 | 0 | 0.0485467 | 0 | 0 | 256.861 | 0.788161 | 0.598888 | 0 | 221.911 | 291.911 | 0.788161 | 221.81 | 0.598888 | 0.0485467 | 0.788161 | 0.598888 | 291.911 | 221.81 | 0 | 0.0179803 | 2700 | 0.0485467 | 5750 | 291.911 | 0.0485467 | 682.788 | 8450 | 2700 | 5750 | 0 | 0.49244 | Face intérieure | Peinture-01 | Mur-149 | 1-Projet | Sejour cuisine/pl | A11 | Etage1 | 4 | ArchiCADProperties - Zones conflictuelles: Sejour cuisine/pl
Mur-149 | Etage1 | 3 | 0 | 2500 | 2500 | 5.0796 | 2490 | 1.12354 | 5.6784 | 5.6784 | 8771.58 | 15.2631 | 15.7881 | 0.397488 | 9066.58 | 5926.58 | 20.9415 | 6156.58 | 21.4665 | 1.52103 | 21.6415 | 21.8165 | 8656.58 | 8886.58 | 0 | 0.417311 | 2500 | 1.12354 | 5750 | 8726.58 | 1.52103 | 17816.8 | 8250 | 2500 | 5750 | 0 | 1.44821 | Face intérieure | Peinture-01 | Mur-149 | 1-Projet | Sde | B14 | Etage1 | 4
Mur-149 | Etage1 | 0 | 0 | 3000 | 3000 | 0 | 0 | 0.187961 | 0 | 0 | 865.05 | 2.79015 | 2.58015 | 0 | 1080.05 | 900.051 | 2.79015 | 830.05 | 2.58015 | 0.187961 | 2.79015 | 2.58015 | 900.051 | 830.05 | 0 | 0.0731535 | 3000 | 0.187961 | 5750 | 1080.05 | 0.187961 | 1899.1 | 8750 | 3000 | 5750 | 0 | 0.653292 | Face intérieure | Surface-Blanche | Mur-149 | 1-Projet | Sde | B12 | Etage1 | 4
Mur-149 | Etage1 | 0 | 0 | 2700 | 2700 | 0 | 0 | 0.120015 | 0 | 0 | 635 | 1.809 | 1.62 | 0 | 740 | 670 | 1.809 | 600 | 1.62 | 0.120015 | 1.809 | 1.62 | 670 | 600 | 0 | 0.04445 | 2700 | 0.120015 | 5750 | 670 | 0.120015 | 1438.99 | 8450 | 2700 | 5750 | 0 | 0.545186 | Face intérieure | Peinture-01 | Mur-149 | 1-Projet | Ch 1/pl | B16 | Etage1 | 4
Mur-149 | Etage1 | 0 | 0 | 2700 | 2700 | 0 | 0 | 0.16148 | 0 | 0 | 854.391 | 2.30686 | 2.30686 | 0 | 1104.39 | 854.391 | 2.30686 | 854.391 | 2.30686 | 0.16148 | 2.30686 | 2.30686 | 854.391 | 854.391 | 0 | 0.0598074 | 2700 | 0.16148 | 5750 | 854.403 | 0.16148 | 1848.78 | 8450 | 2700 | 5750 | 0 | 0.497615 | Face intérieure | Surface-Blanche | Mur-149 | 1-Projet | Ch 1 | A11 | Etage1 | 4
Mur-149 | Etage1 | 0 | 0 | 2700 | 2700 | 0 | 0 | 0.156892 | 0 | 0 | 830.117 | 1.79132 | 1.79132 | 0 | 900.117 | 830.117 | 1.79132 | 830.117 | 1.79132 | 0.156892 | 2.24132 | 2.24132 | 830.117 | 830.117 | 0 | 0.0581082 | 2700 | 0.156892 | 5750 | 830.117 | 0.156892 | 1800.23 | 8450 | 2700 | 5750 | 0 | 0.494216 | Face intérieure | Peinture-01 | Mur-149 | 1-Projet | Entree/pl | B16 | Etage1 | 4
Mur-148 | Etage1 | 1 | 0 | 3000 | 0 | 0.2925 | 450 | 0.30735 | 0.3283 | 0.3283 | 1625 | 4.30671 | 3.90772 | 0.022981 | 1840 | 1660 | 4.63501 | 1590 | 4.23602 | 0.330331 | 4.82401 | 4.61402 | 1660 | 1590 | 0 | 0.121451 | 3000 | 0.30735 | 5750 | 1770.02 | 0.330331 | 3418.99 | 8750 | 3000 | 5750 | 0 | 0.749853 | Face intérieure | Surface-Blanche | Mur-148 | 1-Projet | Sde | A12 | Etage1 | 4 | ArchiCADProperties - Zones conflictuelles: Sde
Mur-149 | Etage1 | 0 | 0 | 2700 | 2700 | 0 | 0 | 0.219983 | 0 | 0 | 1163.93 | 2.95362 | 3.14262 | 0 | 1503.93 | 1163.93 | 2.95362 | 1163.93 | 3.14262 | 0.219983 | 3.14262 | 3.14262 | 1163.93 | 1163.93 | 0 | 0.0814752 | 2700 | 0.219983 | 5750 | 1163.93 | 0.219983 | 2467.86 | 8450 | 2700 | 5750 | 0 | 0.54095 | Face intérieure | Surface-Blanche | Mur-149 | 1-Projet | Ch 3 | B14 | Etage1 | 4
Mur-149 | Etage1 | 0 | 0 | 2700 | 2700 | 0 | 0 | 0.219993 | 0 | 0 | 1163.99 | 3.14276 | 3.14276 | 0 | 1503.99 | 1163.99 | 3.14276 | 1163.99 | 3.14276 | 0.219993 | 3.14276 | 3.14276 | 1163.99 | 1163.99 | 0 | 0.081479 | 2700 | 0.219993 | 5750 | 1163.99 | 0.219993 | 2467.97 | 8450 | 2700 | 5750 | 0 | 0.540958 | Face intérieure | Surface-Blanche | Mur-149 | 1-Projet | Ch 2/pl | B14 | Etage1 | 4
Mur-149 | Etage 2 | 1 | 0 | 3000 | 3000 | 1.6932 | 830 | 0.132454 | 1.8928 | 1.8928 | 1250 | 1.8922 | 1.8922 | 0.132496 | 1320 | 340 | 3.785 | 340 | 3.785 | 0.26495 | 3.785 | 3.785 | 1250 | 1250 | 0 | 0.0287 | 3000 | 0.132454 | 8500 | 1320 | 0.26495 | 2640 | 11500 | 3000 | 8500 | 0 | 0.5411 | Face intérieure | Surface-Blanche | Mur-149 | 1-Projet | Entree/pl | B24 | Etage 2 | 5
Mur-121 | Etage1 | 0 | 0 | 3000 | 3000 | 0 | 0 | 0.119409 | 0 | 0 | 553.613 | 1.45084 | 1.75084 | 0 | 553.614 | 553.612 | 1.45084 | 553.614 | 1.75084 | 0.119409 | 1.66084 | 1.75084 | 553.612 | 553.614 | 0 | 0.045053 | 3000 | 0.119409 | 5750 | 733.614 | 0.119409 | 1247.23 | 8750 | 3000 | 5750 | 0 | 0.571673 | Face extérieure | Lavis blanc | Mur-121 | 1-Projet | Sejour Cuisine | B13 | Etage1 | 4
Mur-149 | Etage 2 | 0 | 0 | 3000 | 2500 | 0 | 0 | 0.874885 | 0 | 0 | 4178.12 | 12.2884 | 12.4984 | 0 | 4518.12 | 4178.12 | 12.2884 | 4178.12 | 12.4984 | 0.874885 | 12.5344 | 12.5344 | 4178.12 | 4178.12 | 0 | 0.292468 | 3000 | 0.874885 | 8500 | 4178.12 | 0.877405 | 8496.24 | 11500 | 3000 | 8500 | 0 | 1.00494 | Face intérieure | Surface-Blanche | Mur-149 | 1-Projet | Ch 2/pl | B24 | Etage 2 | 5
Mur-149 | Etage 2 | 0 | 0 | 3000 | 3000 | 0 | 0 | 0.697675 | 0 | 0 | 3319.93 | 9.76378 | 9.97378 | 0 | 3319.93 | 3249.93 | 9.76378 | 3389.93 | 9.97378 | 0.697675 | 9.76378 | 10.1698 | 3249.93 | 3389.93 | 0 | 0.234845 | 3000 | 0.697675 | 8500 | 3389.93 | 0.697675 | 6837.85 | 11500 | 3000 | 8500 | 0 | 1.05786 | Face intérieure | Surface-Blanche | Mur-149 | 1-Projet | Ch 1 | B21 | Etage 2 | 5
Mur-149 | Etage 2 | 3 | 0 | 2500 | 2500 | 5.0796 | 2490 | 1.12354 | 5.6784 | 5.6784 | 8771.58 | 15.2631 | 15.6131 | 0.397488 | 9066.58 | 5926.58 | 20.9415 | 6156.58 | 21.2915 | 1.52103 | 21.6415 | 21.8165 | 8656.58 | 8886.58 | 0 | 0.417311 | 2500 | 1.12354 | 8500 | 8726.58 | 1.52103 | 17816.8 | 11000 | 2500 | 8500 | 0 | 1.44821 | Face intérieure | Peinture-01 | Mur-149 | 1-Projet | Sde | B24 | Etage 2 | 5
Mur-121 | Etage1 | 0 | 0 | 3000 | 3000 | 0 | 0 | 0.1071 | 0 | 0 | 509.992 | 1.07998 | 1.07997 | 0 | 579.993 | 509.993 | 1.07998 | 509.991 | 1.07997 | 0.1071 | 1.52998 | 1.52997 | 509.993 | 509.991 | 0 | 0.0357 | 3000 | 0.1071 | 5750 | 509.993 | 0.1071 | 1159.98 | 8750 | 3000 | 5750 | 0 | 0.491407 | Face extérieure | Lavis blanc | Mur-121 | 1-Projet | Sejour Cuisine | B13 | Etage1 | 4
Mur-149 | Etage 2 | 1 | 0 | 3000 | 3000 | 2.02618 | 1013.09 | 0.157362 | 1.9765 | 1.9765 | 1408.18 | 2.03803 | 2.24803 | 0.138355 | 1408.18 | 419.925 | 4.01453 | 419.925 | 4.22453 | 0.295717 | 4.22453 | 4.22453 | 1408.18 | 1408.18 | 0 | 0.0293947 | 3000 | 0.157362 | 8500 | 1408.18 | 0.295717 | 2956.35 | 11500 | 3000 | 8500 | 0 | 0.407967 | Face intérieure | Surface-Blanche | Mur-149 | 1-Projet | Entree/pl | A22 | Etage 2 | 5
Mur-152 | Etage 2 | 0 | 0 | 3000 | 3000 | 0 | 0 | 0.29712 | 0 | 0 | 1414.86 | 2.86457 | 4.03457 | 0 | 1414.86 | 1414.86 | 2.86457 | 1414.86 | 4.03457 | 0.29712 | 4.24457 | 4.24457 | 1414.86 | 1414.86 | 0 | 0.0990401 | 3000 | 0.29712 | 8500 | 1414.86 | 0.29712 | 2969.72 | 11500 | 3000 | 8500 | 0 | 0.61808 | Face extérieure | Peinture-01 | Mur-152 | 1-Projet | Ch 1 | A23 | Etage 2 | 5 | ArchiCADProperties - Zones conflictuelles: Sejour cuisine
Mur-149 | Etage 2 | 1 | 1 | 3000 | 3000 | 1.6932 | 830 | 0.865265 | 3.7336 | 3.73359 | 5357.84 | 11.9829 | 12.3609 | 0.261352 | 5427.84 | 3545.49 | 15.7165 | 3545.49 | 16.0945 | 1.12662 | 16.0945 | 16.0945 | 5357.84 | 5357.83 | 1.8408 | 0.253085 | 3000 | 0.865265 | 8500 | 5427.84 | 1.12662 | 10855.7 | 11500 | 3000 | 8500 | 0 | 0.910233 | Face intérieure | Surface-Blanche | Mur-149 | 1-Projet | Sejour cuisine/pl | A21 | Etage 2 | 5
2 x Mur-121 | Etage 2 | 0 | 0 | 3000 | 0 | 0 | 0 | 0.0742809 | 0 | 0 | 400.052 | 1.06116 | 1.06116 | 0 | 580.052 | 400.052 | 1.06116 | 400.052 | 1.06116 | 0.0742809 | 1.06116 | 1.06116 | 400.052 | 400.052 | 0 | 0.0406037 | 3000 | 0.0742809 | 8500 | 580.052 | 0.0742809 | 940.104 | 11500 | 3000 | 8500 | 0 | 0.496307 | Face extérieure | Lavis blanc | Mur-121 | 1-Projet |  |  | Etage 2 | 5
Mur-149 | Etage 2 | 0 | 0 | 2700 | 2700 | 0 | 0 | 0.0954454 | 0 | 0 | 505.002 | 1.458 | 1.08001 | 0 | 540 | 540 | 1.458 | 470.005 | 1.08001 | 0.0954454 | 1.458 | 1.26901 | 540 | 470.005 | 0 | 0.0353501 | 2700 | 0.0954454 | 8500 | 540 | 0.0954454 | 1179 | 11200 | 2700 | 8500 | 0 | 0.526977 | Face intérieure | Peinture-01 | Mur-149 | 1-Projet | Sejour cuisine | B25 | Etage 2 | 5
Mur-149 | Etage 2 | 1 | 1 | 2500 | 2500 | 1.6932 | 830 | 0.17629 | 3.8274 | 3.8274 | 2538.33 | 2.51843 | 2.34343 | 0.267918 | 2718.33 | 680 | 6.34583 | 680 | 6.17083 | 0.444208 | 6.34583 | 6.34583 | 2538.33 | 2538.33 | 1.9346 | 0.0476 | 2500 | 0.17629 | 8500 | 2538.33 | 0.444208 | 5216.66 | 11000 | 2500 | 8500 | 0 | 0.432483 | Face intérieure | Peinture-01 | Mur-149 | 1-Projet | Wc | B26 | Etage 2 | 5
Mur-153 | Etage 2 | 0 | 0 | 3000 | 3000 | 0 | 0 | 0.0525022 | 0 | 0 | 250.011 | 0.750063 | 0.75 | 0 | 430 | 250.021 | 0.750063 | 250 | 0.75 | 0.0525022 | 0.750063 | 0.75 | 250.021 | 250 | 0 | 0.0175007 | 3000 | 0.0525022 | 8500 | 250.021 | 0.0525022 | 640.021 | 11500 | 3000 | 8500 | 0 | 0.455001 | Face extérieure | Peinture-01 | Mur-153 | 1-Projet | Sejour cuisine | A23 | Etage 2 | 5
Mur-149 | Etage 2 | 0 | 0 | 3000 | 3000 | 0 | 0 | 0.152321 | 0 | 0 | 725.338 | 2.28101 | 2.07101 | 0 | 1040.34 | 760.338 | 2.28101 | 690.338 | 2.07101 | 0.152321 | 2.28101 | 2.07101 | 760.338 | 690.338 | 0 | 0.0507737 | 3000 | 0.152321 | 8500 | 760.338 | 0.152321 | 1619.67 | 11500 | 3000 | 8500 | -1.77636e-12 | 0.608532 | Face intérieure | Surface-Blanche | Mur-149 | 1-Projet | Sejour cuisine/pl | A21 | Etage 2 | 5
Mur-149 | Etage 2 | 1 | 0 | 3000 | 3000 | 3.05046 | 1525.23 | 0.114116 | 3.05046 | 3.05046 | 1560.23 | 1.73523 | 1.52523 | 0.213532 | 1595.23 | 70 | 1.73523 | 1.42109e-10 | 1.52523 | 0.327648 | 4.78568 | 4.57568 | 1595.23 | 1525.23 | 0 | 0.00245 | 3000 | 0.114116 | 8500 | 1595.23 | 0.327648 | 3289.45 | 11500 | 3000 | 8500 | 0 | 0.478651 | Face intérieure | Surface-Blanche | Mur-149 | 1-Projet | Ch 2/pl | B24 | Etage 2 | 5 | ArchiCADProperties - Zones conflictuelles: Ch 2/pl
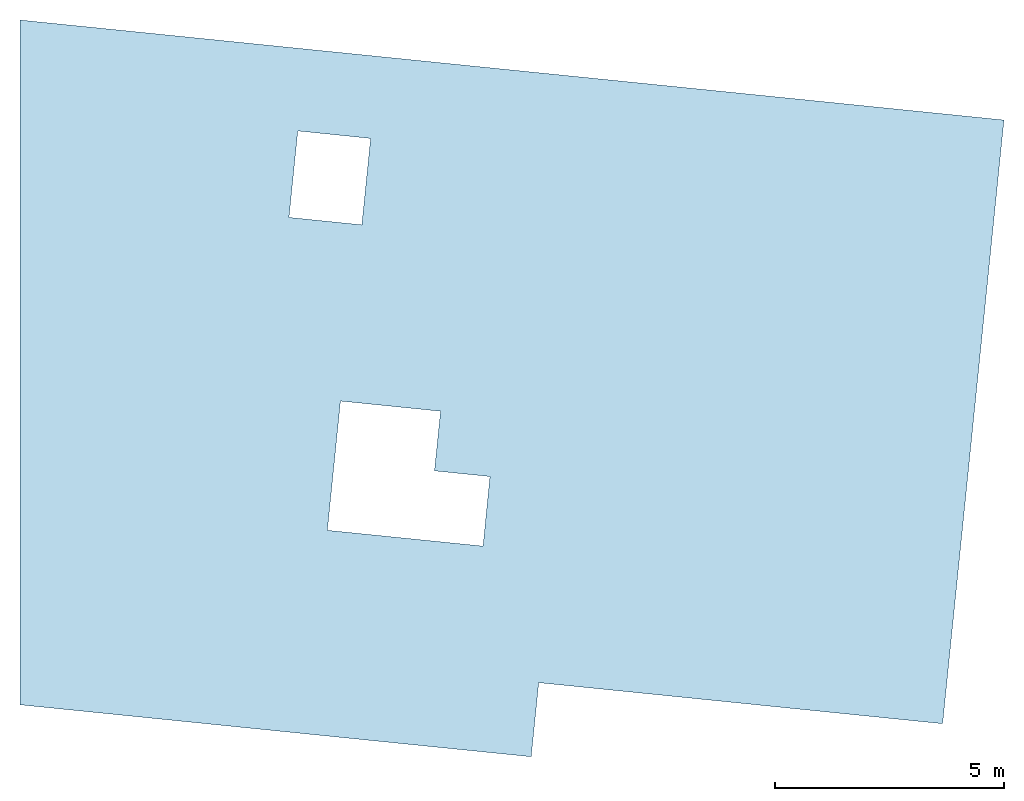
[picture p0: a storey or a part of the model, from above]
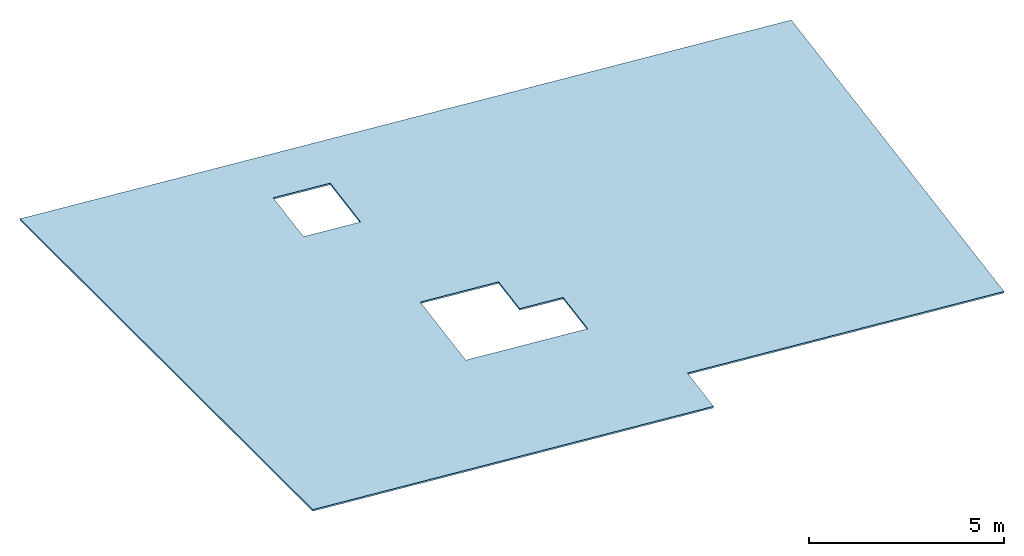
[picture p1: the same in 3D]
Properties of the parts of a building model (IFC2X3), part 26 of 44

# IfcWallStandardCase: Cloison 70 0826278243 70 (896)
Name | In | Nombre de Portes | Nombre de trous (Nombre d'ouvertures vides) | Hauteur maximale de la couche de Mur sur face intérieure (mm) = Hauteur maximale du Mur (mm) = Hauteur maximale de la couche de Mur sur face extérieure (mm) | Hauteur minimale de la couche de Mur sur face intérieure (mm) = Hauteur minimale du Mur (mm) = Hauteur minimale de la couche de Mur sur face extérieure (mm) | Superficie des portes (m2) | Largeur totale des Portes (mm) | Volume de composant de mur sur face intérieure (net) (m3) = Volume de composant de mur sur face extérieure (net) (m3) | Superficie analytique des ouvertures sur face intérieure (m2) | Superficie analytique des ouvertures sur face extérieure (m2) | Longueur moyenne du mur (mm) = Longueur du Mur au centre (mm) | Superficie de la face intérieure du mur (nette) (m2) | Superficie de la face extérieure du mur (nette) (m2) = Superficie en plan (m2) = Superficie inférieure (nette) (m2) | Volume analytique des ouvertures (m3) | Longueur de ligne de référence (mm) | Longueur de la face intérieure du mur (conditionnelle) (mm) | Superficie de la face intérieure du mur (conditionnelle) (m2) | Longueur de la face extérieure du mur (conditionnelle) (mm) | Superficie de la face extérieure du mur (conditionnelle) (m2) | Volume du composant face intérieure du mur (conditionnel) (m3) = Volume du composant face extérieure du mur (conditionnel) (m3) = Volume (conditionnel) (m3) | Superficie de la face intérieure du mur (brute) (m2) | Superficie de la face extérieure du mur (brute) (m2) | Longueur de Mur sur face intérieure (mm) | Longueur de Mur sur face extérieure (mm) | Superficie des baies libres dans le Mur (m2) | Superficie (m2) = Superficie supérieure (nette) (m2) | Hauteur (mm) | Volume (net) (m3) | Altitude à Zéro du Projet (mm) = Altitude de Référence Niveau 1 (mm) = Altitude de Référence Niveau 2 (mm) = Altitude à niveau de la mer (mm) | Longueur 3D (mm) | Volume (brut) (m3) | Périmètre Plan (mm) | Altitude supérieure à premier niveau de référence (mm) = Altitude supérieure à Zéro du projet (mm) = Altitude supérieure à niveau de la mer (mm) = Altitude supérieure à deuxième niveau de référence (mm) | Altitude supérieure à étage d'implantation (mm) | Altitude inférieure à premier niveau de référence (mm) = Altitude inférieure à Zéro du projet (mm) = Altitude inférieure à niveau de la mer (mm) = Altitude inférieure à deuxième niveau de référence (mm) | Altitude inférieure à étage d'implantation (mm) | Superficie de l'arête (nette) (m2) | Emplacement de ligne de référence | Surface de face intérieure = Surface de face extérieure = Surfaces (Toutes) = Surface latérale | ID de l'élément = Lien et ID d'élément = ID de Parent | Calque | Nom de zone liée | Numéro de zone liée | Nom d'étage d'implantation | Numéro d'étage d'implantation
Mur-149 | Etage 2 | 0 | 0 | 3000 | 3000 | 0 | 0 | 0.631157 | 0 | 0 | 3005.51 | 8.92166 | 9.11139 | 0 | 3044.25 | 2973.89 | 8.92166 | 3037.13 | 9.11139 | 0.631157 | 8.92166 | 9.11139 | 2973.89 | 3037.13 | 0 | 0.210386 | 3000 | 0.631157 | 8500 | 3037.13 | 0.631157 | 6175.36 | 11500 | 3000 | 8500 | 0 | 0.913784 | Face intérieure | Surface-Blanche | Mur-149 | 1-Projet | Ch 2 | A22 | Etage 2 | 5
Mur-149 | Etage 2 | 0 | 1 | 3000 | 0 | 0 | 0 | 0.541973 | 1.91776 | 1.91776 | 3290.08 | 7.74248 | 7.53248 | 0.134243 | 3290.08 | 2350 | 9.66024 | 2350 | 9.45024 | 0.676217 | 9.66024 | 9.66024 | 3290.08 | 3290.08 | 1.91776 | 0.1596 | 3000 | 0.541973 | 8500 | 3220.08 | 0.676217 | 6720.16 | 11500 | 3000 | 8500 | 0 | 0.662206 | Face intérieure | Surface-Blanche | Mur-149 | 1-Projet | Cellier | A22 | Etage 2 | 5
Mur-149 | Etage 2 | 1 | 0 | 3000 | 3000 | 1.6932 | 830 | 0.200423 | 1.8928 | 1.8928 | 1585.33 | 2.75819 | 2.75819 | 0.132496 | 1620.33 | 710.33 | 4.65099 | 640.33 | 4.65099 | 0.332919 | 4.86099 | 4.65099 | 1620.33 | 1550.33 | 0 | 0.0472731 | 3000 | 0.200423 | 8500 | 1620.33 | 0.332919 | 3339.65 | 11500 | 3000 | 8500 | 0 | 0.665231 | Face intérieure | Surface-Blanche | Mur-149 | 1-Projet | Ch 2 | A22 | Etage 2 | 5
Mur-149 | Etage 2 | 1 | 0 | 3000 | 3000 | 1.6932 | 830 | 0.399078 | 1.8928 | 1.8928 | 2524.31 | 5.38612 | 5.38612 | 0.132496 | 2629.31 | 1579.31 | 7.27892 | 1649.31 | 7.27892 | 0.531574 | 7.48892 | 7.69892 | 2489.31 | 2559.31 | 0 | 0.117901 | 3000 | 0.399078 | 8500 | 2629.31 | 0.531574 | 5217.61 | 11500 | 3000 | 8500 | 0 | 0.806488 | Face intérieure | Surface-Blanche | Mur-149 | 1-Projet | Cellier | A22 | Etage 2 | 5 | ArchiCADProperties - Zones conflictuelles: Sejour cuisine
Mur-149 | Etage 2 | 0 | 0 | 2500 | 2500 | 0 | 0 | 0.0623494 | 0 | 0 | 356.282 | 0.803206 | 0.628206 | 0 | 391.282 | 391.282 | 0.803206 | 321.282 | 0.628206 | 0.0623494 | 0.978206 | 0.803206 | 391.282 | 321.282 | 0 | 0.0249398 | 2500 | 0.0623494 | 8500 | 391.282 | 0.0623494 | 881.56 | 11000 | 2500 | 8500 | 0 | 0.472367 | Face intérieure | Surface-Blanche | Mur-149 | 1-Projet | Entree/pl | B25 | Etage 2 | 5
Mur-149 | Etage 2 | 0 | 0 | 3000 | 3000 | 0 | 0 | 0.34545 | 0 | 0 | 1645 | 5.04 | 4.62 | 0 | 1610 | 1680 | 5.04 | 1610 | 4.62 | 0.34545 | 5.04 | 4.83 | 1680 | 1610 | 0 | 0.11515 | 3000 | 0.34545 | 8500 | 1680 | 0.34545 | 3458.99 | 11500 | 3000 | 8500 | 0 | 0.737285 | Face intérieure | Surface-Blanche | Mur-149 | 1-Projet | Cellier | A22 | Etage 2 | 5
Mur-149 | Etage 2 | 0 | 0 | 3000 | 2300 | 0 | 0 | 0.679069 | 0 | 0 | 3245.72 | 9.71166 | 9.6903 | 0 | 3591.03 | 3249.28 | 9.71166 | 3242.16 | 9.6903 | 0.679069 | 9.74784 | 9.72649 | 3249.28 | 3242.16 | 0 | 0.227201 | 3000 | 0.679069 | 8500 | 3249.28 | 0.681602 | 6631.8 | 11500 | 3000 | 8500 | 0 | 0.875484 | Face intérieure | Surface-Blanche | Mur-149 | 1-Projet | Ch 1 | A22 | Etage 2 | 5 | ArchiCADProperties - Zones conflictuelles: Ch 2
Mur-149 | Etage 2 | 0 | 0 | 3000 | 3000 | 0 | 0 | 0.22179 | 0 | 0 | 1056.14 | 3.16843 | 3.16843 | 0 | 1196.14 | 1056.14 | 3.16843 | 1056.14 | 3.16843 | 0.22179 | 3.16843 | 3.16843 | 1056.14 | 1056.14 | 0 | 0.07393 | 3000 | 0.22179 | 8500 | 1056.14 | 0.22179 | 2252.29 | 11500 | 3000 | 8500 | 0 | 0.56786 | Face intérieure | Surface-Blanche | Mur-149 | 1-Projet | Cellier | A22 | Etage 2 | 5
Mur-149 | Etage 2 | 0 | 0 | 2500 | 2500 | 0 | 0 | 0.240538 | 0 | 0 | 1374.5 | 3.43626 | 3.26126 | 0 | 1374.5 | 1374.5 | 3.43626 | 1374.5 | 3.26126 | 0.240538 | 3.43626 | 3.43626 | 1374.5 | 1374.5 | 0 | 0.0962153 | 2500 | 0.240538 | 8500 | 1374.5 | 0.240538 | 2889.01 | 11000 | 2500 | 8500 | 0 | 0.542431 | Face intérieure | Peinture-01 | Mur-149 | 1-Projet | Entree/pl | B25 | Etage 2 | 5
Mur-153 | Etage 2 | 1 | 0 | 3000 | 0 | 1.6932 | 830 | 0.408336 | 1.8928 | 1.8928 | 2655.13 | 5.62337 | 5.83337 | 0.132496 | 2655.13 | 1745.13 | 7.51617 | 1745.13 | 7.72617 | 0.540832 | 7.7554 | 7.7554 | 2655.13 | 2655.13 | 0 | 0.117259 | 3000 | 0.408336 | 8500 | 2585.13 | 0.542878 | 5450.27 | 11500 | 3000 | 8500 | 0 | 0.704219 | Face extérieure | Peinture-01 | Mur-153 | 1-Projet | Ch 1 | A23 | Etage 2 | 5
Mur-149 | Etage 2 | 0 | 0 | 2500 | 2500 | 0 | 0 | 0.148292 | 0 | 0 | 847.385 | 2.20596 | 2.03096 | 0 | 882.385 | 882.385 | 2.20596 | 812.385 | 2.03096 | 0.148292 | 2.20596 | 2.03096 | 882.385 | 812.385 | 0 | 0.059317 | 2500 | 0.148292 | 8500 | 882.385 | 0.148292 | 1863.77 | 11000 | 2500 | 8500 | 0 | 0.541121 | Face intérieure | Surface-Blanche | Mur-149 | 1-Projet | Sde | B25 | Etage 2 | 5
Mur-149 | Etage 2 | 0 | 0 | 3000 | 3000 | 0 | 0 | 0.40716 | 0 | 0 | 1938.86 | 5.92157 | 5.71157 | 0 | 1973.86 | 1973.86 | 5.92157 | 1903.86 | 5.71157 | 0.40716 | 5.92157 | 5.71157 | 1973.86 | 1903.86 | 0 | 0.13572 | 3000 | 0.40716 | 8500 | 1973.86 | 0.40716 | 4046.71 | 11500 | 3000 | 8500 | 0 | 0.778427 | Face intérieure | Surface-Blanche | Mur-149 | 1-Projet | Ch 2 | B23 | Etage 2 | 5
Mur-149 | Etage 2 | 0 | 0 | 3000 | 3000 | 0 | 0 | 0.539556 | 0 | 0 | 2571.65 | 7.39994 | 7.80594 | 0 | 2536.65 | 2536.65 | 7.39994 | 2606.65 | 7.80594 | 0.539556 | 7.60994 | 7.80594 | 2536.65 | 2606.65 | 0 | 0.180015 | 3000 | 0.539556 | 8500 | 2606.65 | 0.539556 | 5312.29 | 11500 | 3000 | 8500 | 0 | 0.861218 | Face intérieure | Surface-Blanche | Mur-149 | 1-Projet | Ch 2 | B23 | Etage 2 | 5
Mur-149 | Etage 2 | 0 | 0 | 3000 | 3000 | 0 | 0 | 0.144172 | 0 | 0 | 674.534 | 2.1646 | 1.9546 | 0 | 889.534 | 709.534 | 2.1646 | 639.534 | 1.9546 | 0.144172 | 2.1646 | 1.9546 | 709.534 | 639.534 | 0 | 0.0598174 | 3000 | 0.144172 | 8500 | 889.534 | 0.144172 | 1518.06 | 11500 | 3000 | 8500 | 0 | 0.626619 | Face intérieure | Surface-Blanche | Mur-149 | 1-Projet |  |  | Etage 2 | 5
Mur-150 | Etage 2 | 0 | 0 | 3000 | 3000 | 0 | 0 | 0.0829618 | 0 | 0 | 395.096 | 1.29017 | 1.08016 | 0 | 430.104 | 430.097 | 1.29017 | 360.095 | 1.08016 | 0.0829618 | 1.29017 | 1.08016 | 430.097 | 360.095 | 0 | 0.0276539 | 3000 | 0.0829618 | 8500 | 430.058 | 0.0829618 | 958.763 | 11500 | 3000 | 8500 | -1.77636e-12 | 0.561019 | Face intérieure | Surface-Blanche | Mur-150 | 1-Projet | Sde | B23 | Etage 2 | 5
Mur-149 | Etage 2 | 1 | 0 | 2700 | 2700 | 1.1832 | 580 | 0.0433855 | 1.23 | 1.23 | 685.108 | 0.714303 | 0.525283 | 0.0861 | 900.117 | 120.112 | 1.9443 | 50.1047 | 1.75528 | 0.129485 | 1.9443 | 1.75528 | 720.112 | 650.105 | 0 | 0.00595758 | 2700 | 0.0433855 | 8500 | 720.112 | 0.129485 | 1539.21 | 11200 | 2700 | 8500 | 0 | 0.510202 | Face intérieure | Peinture-01 | Mur-149 | 1-Projet | Entree/Pl | B26 | Etage 2 | 5
Mur-149 | Etage 2 | 2 | 0 | 2700 | 2600 | 3.3864 | 1660 | 0.821157 | 3.7856 | 3.7856 | 5748.12 | 11.4578 | 11.2618 | 0.264992 | 5713.12 | 3963.12 | 15.2434 | 3893.12 | 15.0474 | 1.08615 | 15.6144 | 15.4254 | 5783.12 | 5713.12 | 0 | 0.274968 | 2700 | 0.821157 | 8500 | 5783.12 | 1.08639 | 11665.2 | 11200 | 2700 | 8500 | 0 | 1.12127 | Face intérieure | Peinture-01 | Mur-149 | 1-Projet | Ch 2 | B26 | Etage 2 | 5
Mur-153 | Etage 2 | 1 | 0 | 2700 | 2700 | 3.134 | 1567 | 0.083398 | 3.134 | 3.134 | 1602 | 1.0969 | 1.2859 | 0.21938 | 1637 | 2.29816e-10 | 1.0969 | 70 | 1.2859 | 0.302778 | 4.2309 | 4.4199 | 1567 | 1637 | 0 | 0.00245 | 2700 | 0.083398 | 8500 | 1637 | 0.302778 | 3372.99 | 11200 | 2700 | 8500 | 0 | 0.430876 | Face extérieure | Peinture-01 | Mur-153 | 1-Projet | Ch 2/pl | A24 | Etage 2 | 5 | ArchiCADProperties - Zones conflictuelles: Ch 2/pl
Mur-148 | Etage 2 | 1 | 0 | 2700 | 2700 | 1.6932 | 830 | 0.405561 | 1.88898 | 1.88898 | 2845.45 | 5.79372 | 5.60474 | 0.132228 | 3095.45 | 1937.28 | 7.6827 | 1937.29 | 7.49371 | 0.537789 | 7.6827 | 7.68271 | 2845.44 | 2845.45 | 0 | 0.13561 | 2700 | 0.405561 | 8500 | 2845.45 | 0.537789 | 5830.89 | 11200 | 2700 | 8500 | 0 | 0.567191 | Face extérieure | Lavis blanc | Mur-148 | 1-Projet | Ch 1 | A25 | Etage 2 | 5
Mur-152 | Etage 2 | 0 | 0 | 3000 | 2300 | 0 | 0 | 0.236744 | 0 | 0 | 1164.86 | 3.49457 | 2.6316 | 0 | 1414.86 | 1164.86 | 3.49457 | 1164.86 | 2.6316 | 0.236744 | 3.49457 | 3.49457 | 1164.86 | 1164.86 | 0 | 0.0815401 | 3000 | 0.236744 | 8500 | 1164.86 | 0.24462 | 2469.72 | 11500 | 3000 | 8500 | 0 | 0.569557 | Face extérieure | Peinture-01 | Mur-152 | 1-Projet | Sejour cuisine | A23 | Etage 2 | 5
Mur-153 | Etage 2 | 2 | 0 | 2700 | 2700 | 3.3864 | 1660 | 0.285391 | 3.7856 | 3.7856 | 2912.08 | 3.98252 | 3.79352 | 0.264992 | 2947.08 | 1127.08 | 7.76812 | 1057.08 | 7.57912 | 0.550383 | 7.95712 | 7.76812 | 2947.08 | 2877.08 | 0 | 0.0764456 | 2700 | 0.285391 | 8500 | 2947.08 | 0.550383 | 5993.15 | 11200 | 2700 | 8500 | 0 | 0.736578 | Face extérieure | Peinture-01 | Mur-153 | 1-Projet | Dgt | A24 | Etage 2 | 5 | ArchiCADProperties - Zones conflictuelles: Cellier
Mur-153 | Etage 2 | 0 | 0 | 2700 | 2700 | 0 | 0 | 0.0566137 | 0 | 0 | 299.544 | 0.714293 | 0.714242 | 0 | 404.534 | 264.553 | 0.714293 | 334.534 | 0.714242 | 0.0566137 | 0.714293 | 0.903242 | 264.553 | 334.534 | 0 | 0.0209681 | 2700 | 0.0566137 | 8500 | 334.534 | 0.0566137 | 768.069 | 11200 | 2700 | 8500 | 0 | 0.498187 | Face extérieure | Peinture-01 | Mur-153 | 1-Projet | Sejour cuisine/pl | A25 | Etage 2 | 5 | ArchiCADProperties - Zones conflictuelles: Sejour cuisine/pl
Mur-121 | Etage 2 | 0 | 0 | 3000 | 3000 | 0 | 0 | 0.0693254 | 0 | 0 | 330.121 | 0.990363 | 0.990363 | 0 | 400.121 | 330.121 | 0.990363 | 330.121 | 0.990363 | 0.0693254 | 0.990363 | 0.990363 | 330.121 | 330.121 | 0 | 0.0231085 | 3000 | 0.0693254 | 8500 | 330.121 | 0.0693254 | 800.242 | 11500 | 3000 | 8500 | 0 | 0.466217 | Face extérieure | Lavis blanc | Mur-121 | 1-Projet |  |  | Etage 2 | 5
Mur-149 | Etage 2 | 1 | 0 | 3000 | 3000 | 1.6932 | 830 | 0.570584 | 1.8928 | 1.8928 | 3348 | 8.0462 | 8.0462 | 0.132496 | 3313 | 2403 | 9.939 | 2473 | 9.939 | 0.70308 | 9.939 | 10.149 | 3313 | 3383 | 0 | 0.17066 | 3000 | 0.570584 | 8500 | 3383 | 0.70308 | 6865 | 11500 | 3000 | 8500 | 0 | 0.912005 | Face intérieure | Surface-Blanche | Mur-149 | 1-Projet | Ch 1 | A22 | Etage 2 | 5
Mur-149 | Etage 2 | 0 | 0 | 3000 | 0 | 0 | 0 | 0.0477953 | 0 | 0 | 297.597 | 0.78779 | 0.577791 | 0 | 332.597 | 332.597 | 0.78779 | 262.597 | 0.577791 | 0.0477953 | 0.78779 | 0.577791 | 332.597 | 262.597 | 0 | 0.0159318 | 3000 | 0.0477953 | 8500 | 262.597 | 0.0477953 | 764.188 | 11500 | 3000 | 8500 | 0 | 0.538848 | Face intérieure | Surface-Blanche | Mur-149 | 1-Projet | Sde | B24 | Etage 2 | 5 | ArchiCADProperties - Zones conflictuelles: Sde
Mur-149 | Etage 2 | 0 | 0 | 2700 | 2700 | 0 | 0 | 0.067095 | 0 | 0 | 355 | 0.864 | 1.053 | 0 | 390 | 320 | 0.864 | 390 | 1.053 | 0.067095 | 0.864 | 1.053 | 320 | 390 | 0 | 0.02485 | 2700 | 0.067095 | 8500 | 390 | 0.067095 | 878.995 | 11200 | 2700 | 8500 | 0 | 0.505986 | Face intérieure | Surface-Blanche | Mur-149 | 1-Projet | Sejour cuisine | B21 | Etage 2 | 5
Mur-149 | Etage 2 | 1 | 0 | 2700 | 2700 | 1.4892 | 730 | 0.0501332 | 1.6848 | 1.6848 | 889.255 | 0.810689 | 0.621689 | 0.117936 | 924.255 | 114.255 | 2.49549 | 44.2551 | 2.30649 | 0.168069 | 2.49549 | 2.30649 | 924.255 | 854.255 | 0 | 0.00554786 | 2700 | 0.0501332 | 8500 | 924.255 | 0.168069 | 1947.51 | 11200 | 2700 | 8500 | 0 | 0.524082 | Face intérieure | Surface-Blanche | Mur-149 | 1-Projet | Ch 1/pl | A21 | Etage 2 | 5 | ArchiCADProperties - Zones conflictuelles: Ch 1/pl
Mur-149 | Etage 2 | 1 | 0 | 3000 | 3000 | 1.6932 | 830 | 0.131054 | 1.8928 | 1.8928 | 1255 | 1.7672 | 1.9772 | 0.132496 | 1220 | 310 | 3.66 | 380 | 3.87 | 0.26355 | 3.66 | 3.87 | 1220 | 1290 | 0 | 0.02415 | 3000 | 0.131054 | 8500 | 1290 | 0.26355 | 2678.99 | 11500 | 3000 | 8500 | 0 | 0.473385 | Face intérieure | Surface-Blanche | Mur-149 | 1-Projet | Ch 1 | A22 | Etage 2 | 5
Mur-149 | Etage 2 | 0 | 0 | 3000 | 3000 | 0 | 0 | 0.479708 | 0 | 0 | 2284.33 | 6.84284 | 6.65311 | 0 | 2280.59 | 2350.95 | 6.84284 | 2217.7 | 6.65311 | 0.479708 | 7.05284 | 6.65311 | 2350.95 | 2217.7 | 0 | 0.159903 | 3000 | 0.479708 | 8500 | 2350.95 | 0.479708 | 4761.98 | 11500 | 3000 | 8500 | 0 | 0.899804 | Face intérieure | Surface-Blanche | Mur-149 | 1-Projet | Ch 2 | A22 | Etage 2 | 5
Mur-121 | Etage 2 | 0 | 0 | 3000 | 0 | 0 | 0 | 0.074285 | 0 | 0 | 400.072 | 1.06121 | 1.06121 | 0 | 580.072 | 400.072 | 1.06121 | 400.072 | 1.06121 | 0.074285 | 1.06121 | 1.06121 | 400.072 | 400.072 | 0 | 0.040605 | 3000 | 0.074285 | 8500 | 580.072 | 0.074285 | 940.143 | 11500 | 3000 | 8500 | 0 | 0.49631 | Face extérieure | Lavis blanc | Mur-121 | 1-Projet |  |  | Etage 2 | 5
Mur-121 | Etage 2 | 0 | 0 | 3000 | 3000 | 0 | 0 | 0.0865309 | 0 | 0 | 400.052 | 1.06116 | 1.06116 | 0 | 580.052 | 400.052 | 1.06116 | 400.052 | 1.06116 | 0.0865309 | 1.23616 | 1.23616 | 400.052 | 400.052 | 0 | 0.0406037 | 3000 | 0.0865309 | 8500 | 580.052 | 0.0865309 | 940.104 | 11500 | 3000 | 8500 | 0 | 0.501207 | Face extérieure | Lavis blanc | Mur-121 | 1-Projet |  |  | Etage 2 | 5
Mur-121 | Etage 2 | 0 | 0 | 3000 | 0 | 0 | 0 | 0.0742906 | 0 | 0 | 400.098 | 1.06129 | 1.06129 | 0 | 580.098 | 400.098 | 1.06129 | 400.098 | 1.06129 | 0.0742906 | 1.06129 | 1.06129 | 400.098 | 400.098 | 0 | 0.0406069 | 3000 | 0.0742906 | 8500 | 580.098 | 0.0742906 | 940.196 | 11500 | 3000 | 8500 | 0 | 0.496314 | Face extérieure | Lavis blanc | Mur-121 | 1-Projet |  |  | Etage 2 | 5
Mur-149 | Etage 2 | 0 | 1 | 2700 | 2700 | 0 | 0 | 0.0719989 | 2.54944 | 2.54944 | 1320 | 0.839556 | 0.839556 | 0.178461 | 1390 | 70.2726 | 0.839556 | 70.2726 | 0.839556 | 0.25046 | 3.578 | 3.578 | 1320 | 1320 | 2.54944 | 0.00981908 | 2700 | 0.0719989 | 8500 | 1390 | 0.25046 | 2780 | 11200 | 2700 | 8500 | 0 | 0.342319 | Face intérieure | Peinture-01 | Mur-149 | 1-Projet | Wc | B24 | Etage 2 | 5 | ArchiCADProperties - Zones conflictuelles: Wc
Mur-149 | Etage 2 | 0 | 0 | 3000 | 3000 | 0 | 0 | 0.0882991 | 0 | 0 | 420.472 | 1.15642 | 1.36642 | 0 | 385.472 | 385.472 | 1.15642 | 455.472 | 1.36642 | 0.0882991 | 1.15642 | 1.36642 | 385.472 | 455.472 | 0 | 0.029433 | 3000 | 0.0882991 | 8500 | 455.472 | 0.0882991 | 1009.94 | 11500 | 3000 | 8500 | 0 | 0.565851 | Face intérieure | Surface-Blanche | Mur-149 | 1-Projet | Sde | B21 | Etage 2 | 5
Mur-149 | Etage 2 | 0 | 0 | 2700 | 2700 | 0 | 0 | 0.156892 | 0 | 0 | 830.117 | 1.75532 | 1.75532 | 0 | 900.117 | 830.117 | 1.75532 | 830.117 | 1.75532 | 0.156892 | 2.24132 | 2.24132 | 830.117 | 830.117 | 0 | 0.0581082 | 2700 | 0.156892 | 8500 | 830.117 | 0.156892 | 1800.23 | 11200 | 2700 | 8500 | 0 | 0.494216 | Face intérieure | Peinture-01 | Mur-149 | 1-Projet | Entree/Pl | B26 | Etage 2 | 5
Mur-149 | Etage 2 | 0 | 0 | 3000 | 3000 | 0 | 0 | 0.336413 | 0 | 0 | 1589.97 | 4.5959 | 4.5959 | 0 | 1839.97 | 1589.97 | 4.5959 | 1589.97 | 4.5959 | 0.336413 | 4.8059 | 4.8059 | 1589.97 | 1589.97 | 0 | 0.123898 | 3000 | 0.336413 | 8500 | 1769.97 | 0.336413 | 3319.93 | 11500 | 3000 | 8500 | 0 | 0.667795 | Face intérieure | Surface-Blanche | Mur-149 | 1-Projet | Sde | B24 | Etage 2 | 5
Mur-149 | Etage 2 | 0 | 0 | 3000 | 3000 | 0 | 0 | 0.144971 | 0 | 0 | 690.338 | 2.07101 | 2.07101 | 0 | 1040.34 | 690.338 | 2.07101 | 690.338 | 2.07101 | 0.144971 | 2.07101 | 2.07101 | 690.338 | 690.338 | 0 | 0.0483237 | 3000 | 0.144971 | 8500 | 690.338 | 0.144971 | 1520.68 | 11500 | 3000 | 8500 | 0 | 0.516647 | Face intérieure | Surface-Blanche | Mur-149 | 1-Projet | Sejour cuisine/pl | A21 | Etage 2 | 5
Mur-149 | Etage 2 | 0 | 0 | 3000 | 0 | 0 | 0 | 0.125009 | 0 | 0 | 628.555 | 1.89074 | 1.68094 | 0 | 593.555 | 663.555 | 1.89074 | 593.555 | 1.68094 | 0.125009 | 1.89074 | 1.68094 | 663.555 | 593.555 | 0 | 0.0416696 | 3000 | 0.125009 | 8500 | 630.313 | 0.125009 | 1426.11 | 11500 | 3000 | 8500 | 0 | 0.380324 | Face intérieure | Surface-Blanche | Mur-149 | 1-Projet | Sejour cuisine | B23 | Etage 2 | 5
2 x Mur-152 | Etage 2 | 0 | 0 | 3000 | 2300 | 0 | 0 | 0.0349535 | 0 | 0 | 176.191 | 0.499336 | 0.499336 | 0 | 246.192 | 176.191 | 0.499336 | 176.191 | 0.499336 | 0.0349535 | 0.528574 | 0.528574 | 176.191 | 176.191 | 0 | 0.0123334 | 3000 | 0.0349535 | 8500 | 176.191 | 0.0370002 | 492.383 | 11500 | 3000 | 8500 | -1.77636e-12 | 0.430667 | Face extérieure | Peinture-01 | Mur-152 | 1-Projet |  |  | Etage 2 | 5
Mur-149 | Etage 2 | 1 | 0 | 2700 | 2700 | 1.1832 | 580 | 0.0330825 | 1.189 | 1.189 | 615.41 | 0.567107 | 0.378107 | 0.08323 | 650.41 | 70.4101 | 1.75611 | 0.410108 | 1.56711 | 0.116313 | 1.75611 | 1.56711 | 650.41 | 580.41 | 0 | 0.00247871 | 2700 | 0.0330825 | 8500 | 650.41 | 0.116313 | 1399.82 | 11200 | 2700 | 8500 | 0 | 0.358344 | Face intérieure | Peinture-01 | Mur-149 | 1-Projet | Sejour cuisine | B24 | Etage 2 | 5
Mur-149 | Etage 2 | 0 | 0 | 3000 | 3000 | 0 | 0 | 0.0728756 | 0 | 0 | 347.027 | 1.14608 | 0.93608 | 0 | 382.027 | 382.027 | 1.14608 | 312.027 | 0.93608 | 0.0728756 | 1.14608 | 0.93608 | 382.027 | 312.027 | 0 | 0.0242919 | 3000 | 0.0728756 | 8500 | 382.027 | 0.0728756 | 863.048 | 11500 | 3000 | 8500 | 0 | 0.555569 | Face intérieure | Surface-Blanche | Mur-149 | 1-Projet | Sde | A23 | Etage 2 | 5
Mur-149 | Etage 2 | 1 | 0 | 3000 | 3000 | 1.02 | 500 | 0.168001 | 1.066 | 1.066 | 1155.34 | 2.50501 | 2.08501 | 0.07462 | 1530.34 | 670.338 | 3.57101 | 600.338 | 3.15101 | 0.242621 | 3.57101 | 3.36101 | 1190.34 | 1120.34 | 0 | 0.0444736 | 3000 | 0.168001 | 8500 | 1190.34 | 0.242621 | 2479.67 | 11500 | 3000 | 8500 | 0 | 0.632332 | Face intérieure | Surface-Blanche | Mur-149 | 1-Projet | Sejour cuisine/pl | A21 | Etage 2 | 5 | ArchiCADProperties - Zones conflictuelles: Sejour cuisine/pl
Mur-149 | Etage 2 | 1 | 0 | 2500 | 0 | 1.6932 | 830 | 0.2113 | 1.8928 | 1.8928 | 2034.55 | 3.01858 | 3.01858 | 0.132496 | 2104.55 | 1124.55 | 4.91138 | 1124.55 | 4.91138 | 0.343796 | 4.91138 | 4.91138 | 2034.55 | 2034.55 | 0 | 0.0738185 | 2500 | 0.2113 | 8500 | 1964.55 | 0.343796 | 4209.1 | 11000 | 2500 | 8500 | 0 | 0.561337 | Face intérieure | Peinture-01 | Mur-149 | 1-Projet | Dgt | B25 | Etage 2 | 5
Mur-148 | Etage 2 | 1 | 0 | 2700 | 0 | 1.6932 | 830 | 0.161451 | 1.8928 | 1.8928 | 1735.28 | 2.21193 | 2.40095 | 0.132496 | 1700.28 | 790.278 | 4.10473 | 860.277 | 4.29375 | 0.293947 | 4.10473 | 4.29375 | 1700.28 | 1770.28 | 0 | 0.0451692 | 2700 | 0.161451 | 8500 | 1590.28 | 0.293947 | 3639.55 | 11200 | 2700 | 8500 | 0 | 0.421323 | Face extérieure | Lavis blanc | Mur-148 | 1-Projet | Wc | A25 | Etage 2 | 5
Mur-150 | Etage 2 | 0 | 0 | 3000 | 3000 | 0 | 0 | 0.118777 | 0 | 0 | 565.566 | 1.69682 | 1.69682 | 0 | 815.559 | 565.566 | 1.69682 | 565.566 | 1.69682 | 0.118777 | 1.69682 | 1.69682 | 565.566 | 565.566 | 0 | 0.0395924 | 3000 | 0.118777 | 8500 | 565.626 | 0.118777 | 1271.13 | 11500 | 3000 | 8500 | -1.77636e-12 | 0.499185 | Face intérieure | Surface-Blanche | Mur-150 | 1-Projet |  |  | Etage 2 | 5
Mur-153 | Etage 2 | 0 | 0 | 2700 | 2700 | 0 | 0 | 0.120015 | 0 | 0 | 635 | 1.62 | 1.809 | 0 | 670 | 600 | 1.62 | 670 | 1.809 | 0.120015 | 1.62 | 1.809 | 600 | 670 | 0 | 0.04445 | 2700 | 0.120015 | 8500 | 670 | 0.120015 | 1438.99 | 11200 | 2700 | 8500 | 0 | 0.545186 | Face extérieure | Peinture-01 | Mur-153 | 1-Projet | Ch 2/pl | A24 | Etage 2 | 5
Mur-148 | Etage 2 | 0 | 0 | 2700 | 2700 | 0 | 0 | 0.291831 | 0 | 0 | 1544.07 | 4.0745 | 3.8855 | 0 | 1579.08 | 1579.07 | 4.0745 | 1509.08 | 3.8855 | 0.291831 | 4.2635 | 4.0745 | 1579.07 | 1509.08 | 0 | 0.108086 | 2700 | 0.291831 | 8500 | 1579.07 | 0.291831 | 3257.14 | 11200 | 2700 | 8500 | 0 | 0.672457 | Face extérieure | Lavis blanc | Mur-148 | 1-Projet | Wc | A25 | Etage 2 | 5
Mur-151 | Etage 2 | 1 | 1 | 3000 | 0 | 1.6932 | 830 | 0.586448 | 3.7042 | 3.70413 | 4097.33 | 8.37778 | 8.37786 | 0.259292 | 4657.33 | 2299.39 | 12.082 | 2299.42 | 12.082 | 0.845739 | 12.082 | 12.082 | 4097.33 | 4097.33 | 1.95413 | 0.156058 | 3000 | 0.586448 | 8500 | 4027.37 | 0.845739 | 8334.66 | 11500 | 3000 | 8500 | 0 | 0.857971 | Face extérieure | Peinture-01 | Mur-151 | 1-Projet | Sde | A23 | Etage 2 | 5 | ArchiCADProperties - Zones conflictuelles: Ch 1; Sde
Mur-121 | Etage 2 | 0 | 0 | 3000 | 0 | 0 | 0 | 0.0690435 | 0 | 0 | 398.779 | 0.986336 | 0.986336 | 0 | 398.779 | 398.779 | 0.986336 | 398.779 | 0.986336 | 0.0690435 | 0.986336 | 0.986336 | 398.779 | 398.779 | 0 | 0.0230145 | 3000 | 0.0690435 | 8500 | 328.779 | 0.0690435 | 937.557 | 11500 | 3000 | 8500 | 0 | 0.466029 | Face extérieure | Lavis blanc | Mur-121 | 1-Projet |  |  | Etage 2 | 5
Mur-149 | Etage 2 | 0 | 1 | 3000 | 0 | 0 | 0 | 0.400305 | 2.26017 | 2.26004 | 2702.4 | 5.10257 | 5.52271 | 0.158207 | 2772.43 | 1594.5 | 5.10257 | 1594.5 | 5.52271 | 0.558512 | 7.97875 | 7.97875 | 2702.43 | 2702.36 | 2.26017 | 0.116517 | 3000 | 0.400305 | 8500 | 2772.43 | 0.558512 | 5544.79 | 11500 | 3000 | 8500 | 0 | 0.388226 | Face intérieure | Surface-Blanche | Mur-149 | 1-Projet | Wc | B23 | Etage 2 | 5 | ArchiCADProperties - Zones conflictuelles: Entree/pl; Wc
Mur-149 | Etage 2 | 0 | 0 | 3000 | 3000 | 0 | 0 | 0.336413 | 0 | 0 | 1589.97 | 4.8059 | 4.8059 | 0 | 1839.97 | 1589.97 | 4.8059 | 1589.97 | 4.8059 | 0.336413 | 4.8059 | 4.8059 | 1589.97 | 1589.97 | 0 | 0.123898 | 3000 | 0.336413 | 8500 | 1769.97 | 0.336413 | 3319.93 | 11500 | 3000 | 8500 | 0 | 0.667795 | Face intérieure | Surface-Blanche | Mur-149 | 1-Projet | Cellier | B24 | Etage 2 | 5
Mur-149 | Etage 2 | 0 | 0 | 3000 | 3000 | 0 | 0 | 0.379962 | 0 | 0 | 1795 | 5.526 | 4.826 | 0 | 2010 | 1830 | 5.526 | 1760 | 4.826 | 0.379962 | 5.526 | 5.33 | 1830 | 1760 | 0 | 0.140701 | 3000 | 0.379962 | 8500 | 2010 | 0.379962 | 3759 | 11500 | 3000 | 8500 | 0 | 0.78259 | Face intérieure | Surface-Blanche | Mur-149 | 1-Projet | Cellier | B23 | Etage 2 | 5
Mur-149 | Etage 2 | 0 | 0 | 3000 | 3000 | 0 | 0 | 0.0599527 | 0 | 0 | 285.489 | 0.961516 | 0.751417 | 0 | 390.511 | 320.505 | 0.961516 | 250.472 | 0.751417 | 0.0599527 | 0.961516 | 0.751417 | 320.505 | 250.472 | 0 | 0.0199842 | 3000 | 0.0599527 | 8500 | 320.505 | 0.0599527 | 739.996 | 11500 | 3000 | 8500 | 0 | 0.547023 | Face intérieure | Surface-Blanche | Mur-149 | 1-Projet | Sde | B23 | Etage 2 | 5
Mur-149 | Etage 2 | 0 | 0 | 2700 | 2700 | 0 | 0 | 0.0604931 | 0 | 0 | 320.069 | 0.675187 | 0.864187 | 0 | 320.069 | 320.069 | 0.675187 | 320.069 | 0.864187 | 0.0604931 | 0.864187 | 0.864187 | 320.069 | 320.069 | 0 | 0.0224048 | 2700 | 0.0604931 | 8500 | 320.069 | 0.0604931 | 780.139 | 11200 | 2700 | 8500 | 0 | 0.42281 | Face intérieure | Peinture-01 | Mur-149 | 1-Projet | Sejour cuisine/pl | A21 | Etage 2 | 5 | ArchiCADProperties - Zones conflictuelles: Sejour cuisine/pl
Mur-149 | Etage 2 | 0 | 0 | 3000 | 3000 | 0 | 0 | 0.18417 | 0 | 0 | 865 | 2.736 | 2.52599 | 0 | 1080 | 900 | 2.736 | 830 | 2.52599 | 0.18417 | 2.736 | 2.52599 | 900 | 830 | 0 | 0.0731489 | 3000 | 0.18417 | 8500 | 1080 | 0.18417 | 1899.02 | 11500 | 3000 | 8500 | 0 | 0.653352 | Face intérieure | Surface-Blanche | Mur-149 | 1-Projet | Sde | B23 | Etage 2 | 5
Mur-149 | Etage 2 | 0 | 0 | 3000 | 3000 | 0 | 0 | 0.347185 | 0 | 0 | 1653.26 | 4.53979 | 4.74979 | 0 | 1653.26 | 1653.26 | 4.53979 | 1653.26 | 4.74979 | 0.347185 | 4.95979 | 4.95979 | 1653.26 | 1653.26 | 0 | 0.115728 | 3000 | 0.347185 | 8500 | 1653.26 | 0.347185 | 3446.53 | 11500 | 3000 | 8500 | 0 | 0.651457 | Face intérieure | Surface-Blanche | Mur-149 | 1-Projet | Sde | A23 | Etage 2 | 5 | ArchiCADProperties - Zones conflictuelles: Ch 1
Mur-149 | Etage 2 | 0 | 0 | 3000 | 3000 | 0 | 0 | 0.35271 | 0 | 0 | 1679.57 | 4.93372 | 4.93371 | 0 | 1784.57 | 1644.57 | 4.93372 | 1714.57 | 4.93371 | 0.35271 | 4.93372 | 5.14371 | 1644.57 | 1714.57 | 0 | 0.11757 | 3000 | 0.35271 | 8500 | 1714.57 | 0.35271 | 3528.14 | 11500 | 3000 | 8500 | -1.77636e-12 | 0.742124 | Face extérieure | Lavis blanc | Mur-149 | 1-Projet | Sejour cuisine | B22 | Etage 2 | 5
Mur-149 | Etage 2 | 1 | 0 | 2500 | 0 | 1.1832 | 580 | 0.130902 | 1.23 | 1.23 | 1310.01 | 1.69503 | 1.87003 | 0.0861 | 1310.01 | 710.012 | 2.92503 | 710.012 | 3.10003 | 0.217002 | 3.10003 | 3.10003 | 1310.01 | 1310.01 | 0 | 0.0448008 | 2500 | 0.130902 | 8500 | 1240.06 | 0.217002 | 2760.02 | 11000 | 2500 | 8500 | 0 | 0.481602 | Face intérieure | Surface-Blanche | Mur-149 | 1-Projet | Entree/pl | B25 | Etage 2 | 5
Mur-149 | Etage 2 | 0 | 1 | 3000 | 3000 | 0 | 0 | 0.856122 | 2.71642 | 2.71642 | 4982.24 | 12.2303 | 11.8103 | 0.19015 | 4982.24 | 3650.66 | 12.2303 | 3650.66 | 11.8103 | 1.04627 | 14.9467 | 14.9467 | 4982.24 | 4982.24 | 2.71642 | 0.255546 | 3000 | 0.856122 | 8500 | 4982.24 | 1.04627 | 10104.5 | 11500 | 3000 | 8500 | 0 | 1.0243 | Face intérieure | Surface-Blanche | Mur-149 | 1-Projet | Sejour cuisine | B22 | Etage 2 | 5
Mur-150 | Etage 2 | 2 | 0 | 3000 | 3000 | 2.8764 | 1410 | 0.454166 | 3.1228 | 3.1228 | 3191.63 | 6.27808 | 5.85808 | 0.218596 | 3371.63 | 1681.63 | 9.40088 | 1681.63 | 8.98088 | 0.672762 | 9.61088 | 9.61088 | 3191.63 | 3191.63 | 0 | 0.130314 | 3000 | 0.454166 | 8500 | 3371.63 | 0.672762 | 6523.25 | 11500 | 3000 | 8500 | 0 | 0.786328 | Face intérieure | Surface-Blanche | Mur-150 | 1-Projet | Ch 1/pl | B22 | Etage 2 | 5
Mur-149 | Etage 2 | 0 | 0 | 2800 | 2800 | 0 | 0 | 0.115437 | 0 | 0 | 588.967 | 1.64911 | 1.64911 | 0 | 658.967 | 588.967 | 1.64911 | 588.967 | 1.64911 | 0.115437 | 1.64911 | 1.64911 | 588.967 | 588.967 | 0 | 0.0412276 | 2800 | 0.115437 | 8500 | 588.967 | 0.115437 | 1317.93 | 11300 | 2800 | 8500 | 0 | 0.474454 | Face intérieure | Surface-Blanche | Mur-149 | 1-Projet | Ch 1 | B21 | Etage 2 | 5
Mur-149 | Etage 2 | 0 | 0 | 2600 | 2600 | 0 | 0 | 0.259758 | 0 | 0 | 1424.55 | 3.71083 | 3.53583 | 0 | 1494.55 | 1424.55 | 3.71083 | 1424.55 | 3.53583 | 0.259758 | 3.86029 | 3.86029 | 1424.55 | 1424.55 | 0 | 0.104619 | 2700 | 0.259758 | 8500 | 1494.55 | 0.27022 | 2989.1 | 11100 | 2600 | 8500 | 0 | 0.468619 | Face intérieure | Peinture-01 | Mur-149 | 1-Projet | Cellier | B25 | Etage 2 | 5
Mur-150 | Etage 2 | 0 | 0 | 3000 | 3000 | 0 | 0 | 0.19222 | 0 | 0 | 903.333 | 2.746 | 2.536 | 0 | 1083.33 | 903.332 | 2.746 | 903.333 | 2.536 | 0.19222 | 2.746 | 2.746 | 903.332 | 903.333 | 0 | 0.0758333 | 3000 | 0.19222 | 8500 | 1083.33 | 0.19222 | 1946.67 | 11500 | 3000 | 8500 | 0 | 0.571667 | Face intérieure | Surface-Blanche | Mur-150 | 1-Projet | Sde | B22 | Etage 2 | 5 | ArchiCADProperties - Zones conflictuelles: Sde
Mur-149 | Etage 2 | 0 | 0 | 2700 | 2700 | 0 | 0 | 0.749575 | 0 | 0 | 3966.01 | 10.7082 | 10.7082 | 0 | 4376.01 | 3966.01 | 10.7082 | 3966.01 | 10.7082 | 0.749575 | 10.7082 | 10.7082 | 3966.01 | 3966.01 | 0 | 0.277621 | 2700 | 0.749575 | 8500 | 3966.01 | 0.749575 | 8072.02 | 11200 | 2700 | 8500 | 0 | 0.933241 | Face intérieure | Peinture-01 | Mur-149 | 1-Projet | Ch 2 | B26 | Etage 2 | 5
Mur-149 | Etage 2 | 4 | 0 | 3000 | 0 | 11.3437 | 5638.65 | 0.410488 | 11.6629 | 11.6629 | 5982.32 | 5.65411 | 5.65411 | 0.816167 | 6162.32 | 153.649 | 5.50401 | 153.649 | 5.65411 | 1.22689 | 17.527 | 17.527 | 5982.32 | 5982.32 | 0 | 0.00585769 | 3000 | 0.410726 | 8500 | 5842.35 | 1.22689 | 12104.6 | 11500 | 3000 | 8500 | 0 | 0.695055 | Face intérieure | Surface-Blanche | Mur-149 | 1-Projet | Ch 2 | B22 | Etage 2 | 5 | ArchiCADProperties - Zones conflictuelles: Ch 1/pl; Ch 2; Entree/pl
Mur-149 | Etage 2 | 0 | 0 | 3000 | 3000 | 0 | 0 | 0.14805 | 0 | 0 | 705 | 2.01 | 1.8 | 0 | 740 | 740 | 2.01 | 670 | 1.8 | 0.14805 | 2.22 | 2.01 | 740 | 670 | 0 | 0.04935 | 3000 | 0.14805 | 8500 | 740 | 0.14805 | 1579 | 11500 | 3000 | 8500 | 0 | 0.605685 | Face intérieure | Surface-Blanche | Mur-149 | 1-Projet | Ch 2 | B22 | Etage 2 | 5
Mur-149 | Etage 2 | 0 | 0 | 2700 | 2700 | 0 | 0 | 0.101089 | 0 | 0 | 529.677 | 1.25513 | 1.25513 | 0 | 599.677 | 529.677 | 1.25513 | 529.677 | 1.25513 | 0.101089 | 1.44413 | 1.44413 | 529.677 | 529.677 | 0 | 0.0419774 | 2700 | 0.101089 | 8500 | 599.677 | 0.101089 | 1199.35 | 11200 | 2700 | 8500 | 0 | 0.461955 | Face intérieure | Peinture-01 | Mur-149 | 1-Projet | Entree/pl | B25 | Etage 2 | 5
Mur-149 | Etage 2 | 1 | 0 | 2700 | 2700 | 1.1832 | 580 | 0.0375788 | 1.23 | 1.23 | 654.385 | 0.63134 | 0.44234 | 0.0861 | 799.385 | 89.385 | 1.86134 | 19.385 | 1.67234 | 0.123679 | 1.86134 | 1.67234 | 689.385 | 619.385 | 0 | 0.00380695 | 2700 | 0.0375788 | 8500 | 689.385 | 0.123679 | 1477.76 | 11200 | 2700 | 8500 | 0 | 0.5059 | Face intérieure | Surface-Blanche | Mur-149 | 1-Projet | Sejour cuisine | B21 | Etage 2 | 5
Mur-149 | Etage 2 | 1 | 0 | 2800 | 2800 | 1.6932 | 830 | 0.448778 | 1.8928 | 1.8928 | 2965.69 | 6.41112 | 6.41112 | 0.132496 | 3375.69 | 2055.69 | 8.30392 | 2055.69 | 8.30392 | 0.581274 | 8.30392 | 8.30392 | 2965.69 | 2965.69 | 0 | 0.143898 | 2800 | 0.448778 | 8500 | 2965.69 | 0.581274 | 6071.37 | 11300 | 2800 | 8500 | 0 | 0.743496 | Face intérieure | Surface-Blanche | Mur-149 | 1-Projet | Ch 1 | B21 | Etage 2 | 5
Mur-149 | Etage 2 | 1 | 0 | 2800 | 2800 | 3.61802 | 1809.01 | 0.124567 | 3.53987 | 3.53987 | 1899.78 | 1.68152 | 1.68152 | 0.247791 | 1864.78 | 94.8482 | 1.68152 | 164.849 | 1.68152 | 0.372357 | 5.22139 | 5.41739 | 1864.78 | 1934.78 | 0 | 0.0090894 | 2800 | 0.124567 | 8500 | 1934.78 | 0.372357 | 3968.56 | 11300 | 2800 | 8500 | 0 | 0.475262 | Face intérieure | Surface-Blanche | Mur-149 | 1-Projet | Entree/pl | B23 | Etage 2 | 5
Mur-150 | Etage 2 | 2 | 0 | 3000 | 3000 | 2.8764 | 1410 | 0.425733 | 3.1228 | 3.1228 | 3051.56 | 6.08189 | 5.87189 | 0.218596 | 3301.57 | 1541.56 | 9.20469 | 1541.56 | 8.99469 | 0.644329 | 9.20469 | 9.20469 | 3051.56 | 3051.56 | 0 | 0.12541 | 3000 | 0.425733 | 8500 | 3301.57 | 0.644329 | 6243.13 | 11500 | 3000 | 8500 | 0 | 0.77652 | Face intérieure | Surface-Blanche | Mur-150 | 1-Projet | Sde | B23 | Etage 2 | 5
Mur-149 | Etage 2 | 0 | 0 | 3000 | 3000 | 0 | 0 | 0.137101 | 0 | 0 | 640.862 | 1.85359 | 2.06358 | 0 | 855.861 | 605.862 | 1.85359 | 675.861 | 2.06358 | 0.137101 | 1.85359 | 2.06358 | 605.862 | 675.861 | 0 | 0.0574603 | 3000 | 0.137101 | 8500 | 855.861 | 0.137101 | 1450.72 | 11500 | 3000 | 8500 | 0 | 0.621905 | Face extérieure | Lavis blanc | Mur-149 | 1-Projet | Sejour cuisine | B22 | Etage 2 | 5
Mur-149 | Etage 2 | 2 | 0 | 2800 | 0 | 3.3864 | 1660 | 0.232795 | 3.7856 | 3.7856 | 2609.73 | 3.42364 | 3.03164 | 0.264992 | 2644.73 | 824.727 | 7.20924 | 754.727 | 6.81724 | 0.497787 | 7.20924 | 7.01324 | 2644.73 | 2574.73 | 0 | 0.0503809 | 2800 | 0.232795 | 8500 | 2574.79 | 0.497787 | 5388.45 | 11300 | 2800 | 8500 | 0 | 0.701348 | Face intérieure | Surface-Blanche | Mur-149 | 1-Projet | Cellier | B23 | Etage 2 | 5
Mur-150 | Etage 2 | 0 | 0 | 3000 | 0 | 0 | 0 | 0.184897 | 0 | 0 | 1048.46 | 2.74548 | 2.5373 | 0 | 1083.16 | 1083.16 | 2.74548 | 1013.77 | 2.5373 | 0.184897 | 2.74548 | 2.5373 | 1083.16 | 1013.77 | 0 | 0.0733924 | 3000 | 0.184897 | 8500 | 1083.16 | 0.184897 | 2265.49 | 11500 | 3000 | 8500 | 0 | 0.639888 | Face intérieure | Surface-Blanche | Mur-150 | 1-Projet |  |  | Etage 2 | 5
Mur-149 | Etage 2 | 0 | 0 | 3000 | 3000 | 0 | 0 | 0.140333 | 0 | 0 | 668.251 | 1.89975 | 2.10975 | 0 | 703.251 | 633.251 | 1.89975 | 703.251 | 2.10975 | 0.140333 | 1.89975 | 2.10975 | 633.251 | 703.251 | 0 | 0.0467776 | 3000 | 0.140333 | 8500 | 703.251 | 0.140333 | 1505.5 | 11500 | 3000 | 8500 | 0 | 0.60054 | Face intérieure | Surface-Blanche | Mur-149 | 1-Projet | Sejour cuisine | B23 | Etage 2 | 5
Mur-149 | Etage 2 | 0 | 0 | 3000 | 3000 | 0 | 0 | 0.133351 | 0 | 0 | 634.998 | 2.01 | 1.79999 | 0 | 670 | 669.998 | 2.01 | 599.998 | 1.79999 | 0.133351 | 2.01 | 1.79999 | 669.998 | 599.998 | 0 | 0.0444502 | 3000 | 0.133351 | 8500 | 669.999 | 0.133351 | 1438.99 | 11500 | 3000 | 8500 | 0 | 0.595892 | Face intérieure | Surface-Blanche | Mur-149 | 1-Projet | Ch 2 | B23 | Etage 2 | 5
Mur-149 | Etage 2 | 1 | 0 | 3000 | 3000 | 3.17993 | 1589.97 | 0.116583 | 3.09993 | 3.09995 | 1584.97 | 1.75997 | 1.57097 | 0.216996 | 1619.97 | 70 | 1.75997 | 0.00876892 | 1.57099 | 0.333579 | 4.8599 | 4.67093 | 1619.97 | 1549.98 | 0 | 0.00489969 | 3000 | 0.116583 | 8500 | 1619.97 | 0.333579 | 3338.93 | 11500 | 3000 | 8500 | 0 | 0.476582 | Face intérieure | Surface-Blanche | Mur-149 | 1-Projet | Entree/pl | B24 | Etage 2 | 5
Mur-149 | Etage 2 | 0 | 0 | 2700 | 0 | 0 | 0 | 0.762908 | 0 | 0 | 4036.58 | 10.8987 | 10.8987 | 0 | 4376.59 | 4036.58 | 10.8987 | 4036.58 | 10.8987 | 0.762908 | 10.8987 | 10.8987 | 4036.58 | 4036.58 | 0 | 0.282558 | 2700 | 0.762908 | 8500 | 4036.55 | 0.762908 | 8213.17 | 11200 | 2700 | 8500 | 0 | 0.754117 | Face intérieure | Surface-Blanche | Mur-149 | 1-Projet | Ch 2 | B23 | Etage 2 | 5
Mur-149 | Etage 2 | 2 | 0 | 2800 | 2800 | 3.3864 | 1660 | 0.550257 | 3.7856 | 3.7856 | 4159.43 | 7.11096 | 7.66482 | 0.264992 | 4159.43 | 2339.43 | 10.8966 | 2339.43 | 11.4504 | 0.815249 | 11.6464 | 11.6464 | 4159.43 | 4159.43 | 0 | 0.16376 | 2800 | 0.550257 | 8500 | 4159.43 | 0.815249 | 8458.87 | 11300 | 2800 | 8500 | 0 | 0.846921 | Face intérieure | Surface-Blanche | Mur-149 | 1-Projet | Sde | B23 | Etage 2 | 5 | ArchiCADProperties - Zones conflictuelles: Ch 1/pl
Mur-148 | Etage 2 | 1 | 0 | 3000 | 0 | 0.2925 | 450 | 0.30357 | 0.3283 | 0.3283 | 1625 | 4.44171 | 4.23171 | 0.022981 | 1840 | 1660 | 4.77001 | 1590 | 4.56001 | 0.326551 | 4.77001 | 4.56001 | 1660 | 1590 | 0 | 0.10885 | 3000 | 0.30357 | 8500 | 1590.02 | 0.326551 | 3418.99 | 11500 | 3000 | 8500 | 0 | 0.724652 | Face intérieure | Surface-Blanche | Mur-148 | 1-Projet | Sde | A22 | Etage 2 | 5
Mur-149 | Etage 2 | 1 | 0 | 2700 | 2700 | 1.6932 | 830 | 0.487396 | 1.8928 | 1.8928 | 3282.34 | 6.25002 | 6.60003 | 0.132498 | 3317.34 | 2337.34 | 8.14282 | 2407.34 | 8.49283 | 0.619894 | 8.76782 | 8.94283 | 3247.34 | 3317.34 | 0 | 0.166071 | 2700 | 0.487396 | 8500 | 3317.34 | 0.619894 | 6733.68 | 11200 | 2700 | 8500 | 0 | 0.846344 | Face intérieure | Peinture-01 | Mur-149 | 1-Projet | Dgt | B25 | Etage 2 | 5
Mur-149 | Etage 2 | 0 | 0 | 2700 | 2700 | 0 | 0 | 0.185149 | 0 | 0 | 979.625 | 2.45599 | 2.45599 | 0 | 1049.63 | 979.625 | 2.45599 | 979.625 | 2.45599 | 0.185149 | 2.64499 | 2.64499 | 979.625 | 979.625 | 0 | 0.0685738 | 2700 | 0.185149 | 8500 | 979.625 | 0.185149 | 2099.25 | 11200 | 2700 | 8500 | 0 | 0.515148 | Face intérieure | Peinture-01 | Mur-149 | 1-Projet | Sde | B26 | Etage 2 | 5
Mur-149 | Etage 2 | 0 | 0 | 2500 | 2500 | 0 | 0 | 0.824213 | 0 | 0 | 4709.79 | 11.7745 | 11.7745 | 0 | 5119.79 | 4709.79 | 11.7745 | 4709.79 | 11.7745 | 0.824213 | 11.7745 | 11.7745 | 4709.79 | 4709.79 | 0 | 0.329685 | 2500 | 0.824213 | 8500 | 4709.79 | 0.824213 | 9559.58 | 11000 | 2500 | 8500 | 0 | 1.00937 | Face intérieure | Surface-Blanche | Mur-149 | 1-Projet | Ch 1/pl | B25 | Etage 2 | 5
Mur-149 | Etage 2 | 0 | 0 | 3000 | 3000 | 0 | 0 | 0.47596 | 0 | 0 | 2266.47 | 6.79943 | 6.79943 | 0 | 2336.48 | 2266.48 | 6.79943 | 2266.47 | 6.79943 | 0.47596 | 6.79943 | 6.79943 | 2266.48 | 2266.47 | 0 | 0.158653 | 3000 | 0.47596 | 8500 | 2266.48 | 0.47596 | 4672.95 | 11500 | 3000 | 8500 | 0 | 0.737307 | Face intérieure | Surface-Blanche | Mur-149 | 1-Projet | Ch 1 | A22 | Etage 2 | 5
Mur-149 | Etage 2 | 0 | 0 | 3000 | 2500 | 0 | 0 | 0.874885 | 0 | 0 | 4178.12 | 12.4984 | 12.4984 | 0 | 4518.12 | 4178.12 | 12.4984 | 4178.12 | 12.4984 | 0.874885 | 12.5344 | 12.5344 | 4178.12 | 4178.12 | 0 | 0.292468 | 3000 | 0.874885 | 8500 | 4178.12 | 0.877405 | 8496.24 | 11500 | 3000 | 8500 | 0 | 1.00494 | Face intérieure | Surface-Blanche | Mur-149 | 1-Projet | Ch 1/pl | B24 | Etage 2 | 5
Mur-149 | Etage 2 | 1 | 0 | 2700 | 2700 | 1.1832 | 580 | 0.0736484 | 1.23 | 1.23 | 845.229 | 0.957619 | 0.957619 | 0.0861 | 880.229 | 210.229 | 2.18762 | 280.229 | 2.18762 | 0.159748 | 2.18762 | 2.37662 | 810.229 | 880.229 | 0 | 0.0171661 | 2700 | 0.0736484 | 8500 | 880.229 | 0.159748 | 1859.45 | 11200 | 2700 | 8500 | 0 | 0.532618 | Face intérieure | Peinture-01 | Mur-149 | 1-Projet | Sejour cuisine/pl | A21 | Etage 2 | 5
Mur-149 | Etage 2 | 0 | 0 | 3000 | 0 | 0 | 0 | 0.832974 | 0 | 0 | 4036.54 | 11.8996 | 11.8996 | 0 | 4036.54 | 4036.54 | 11.8996 | 4036.54 | 11.8996 | 0.832974 | 11.8996 | 11.8996 | 4036.54 | 4036.54 | 0 | 0.277658 | 3000 | 0.832974 | 8500 | 3966.55 | 0.832974 | 8213.09 | 11500 | 3000 | 8500 | 0 | 0.975316 | Face intérieure | Surface-Blanche | Mur-149 | 1-Projet | Ch 2 | B22 | Etage 2 | 5
2 x Mur-121 | Etage 2 | 0 | 0 | 3000 | 3000 | 0 | 0 | 0.0693254 | 0 | 0 | 330.121 | 0.990362 | 0.990362 | 0 | 400.121 | 330.121 | 0.990362 | 330.121 | 0.990362 | 0.0693254 | 0.990362 | 0.990362 | 330.121 | 330.121 | 0 | 0.0231085 | 3000 | 0.0693254 | 8500 | 330.121 | 0.0693254 | 800.242 | 11500 | 3000 | 8500 | 0 | 0.466217 | Face extérieure | Lavis blanc | Mur-121 | 1-Projet |  |  | Etage 2 | 5
Mur-149 | Etage 2 | 0 | 0 | 3000 | 3000 | 0 | 0 | 0.077704 | 0 | 0 | 370.022 | 1.11006 | 0.914056 | 0 | 370.019 | 370.022 | 1.11006 | 370.021 | 0.914056 | 0.077704 | 1.11006 | 1.11006 | 370.022 | 370.021 | 0 | 0.0259013 | 3000 | 0.077704 | 8500 | 370.019 | 0.077704 | 880.043 | 11500 | 3000 | 8500 | 0 | 0.471803 | Face intérieure | Surface-Blanche | Mur-149 | 1-Projet | Ch 1 | B21 | Etage 2 | 5
Mur-149 | Etage 2 | 0 | 0 | 3000 | 3000 | 0 | 0 | 0.39155 | 0 | 0 | 1864.52 | 5.69857 | 5.48857 | 0 | 1969.52 | 1899.52 | 5.69857 | 1829.52 | 5.48857 | 0.39155 | 5.69857 | 5.48857 | 1899.52 | 1829.52 | 0 | 0.130517 | 3000 | 0.39155 | 8500 | 1899.52 | 0.39155 | 3898.04 | 11500 | 3000 | 8500 | 0 | 0.768018 | Face intérieure | Surface-Blanche | Mur-149 | 1-Projet | Ch 2 | B22 | Etage 2 | 5
Mur-149 | Etage 2 | 0 | 0 | 3000 | 3000 | 0 | 0 | 0.144771 | 0 | 0 | 689.385 | 1.87916 | 2.06816 | 0 | 869.385 | 689.385 | 1.87916 | 689.385 | 2.06816 | 0.144771 | 2.06816 | 2.06816 | 689.385 | 689.385 | 0 | 0.048257 | 3000 | 0.144771 | 8500 | 689.385 | 0.144771 | 1518.77 | 11500 | 3000 | 8500 | 0 | 0.516514 | Face intérieure | Surface-Blanche | Mur-149 | 1-Projet | Sejour cuisine | B21 | Etage 2 | 5
Mur-149 | Etage 2 | 1 | 0 | 3000 | 3000 | 1.6932 | 830 | 0.372978 | 1.8928 | 1.8928 | 2403.52 | 5.42275 | 5.02375 | 0.132496 | 2508.52 | 1528.52 | 7.31555 | 1458.52 | 6.91655 | 0.505474 | 7.31555 | 7.12655 | 2438.52 | 2368.52 | 0 | 0.106996 | 3000 | 0.372978 | 8500 | 2438.52 | 0.505474 | 4976.03 | 11500 | 3000 | 8500 | 0 | 0.775979 | Face intérieure | Surface-Blanche | Mur-149 | 1-Projet | Entree/pl | B22 | Etage 2 | 5
Mur-149 | Etage 2 | 2 | 0 | 2500 | 2500 | 3.3864 | 1660 | 0.109429 | 3.7856 | 3.7856 | 2139.55 | 1.47578 | 1.47578 | 0.264992 | 2104.55 | 284.55 | 5.26138 | 354.55 | 5.26138 | 0.374421 | 5.26138 | 5.43638 | 2104.55 | 2174.55 | 0 | 0.0223685 | 2500 | 0.109429 | 8500 | 2174.55 | 0.374421 | 4448.1 | 11000 | 2500 | 8500 | 0 | 0.594624 | Face intérieure | Surface-Blanche | Mur-149 | 1-Projet | Sde | B25 | Etage 2 | 5
Mur-149 | Etage 2 | 1 | 0 | 3000 | 3000 | 1.6932 | 830 | 0.21644 | 1.8928 | 1.8928 | 1661.6 | 2.88201 | 2.67201 | 0.132496 | 1661.6 | 751.602 | 4.77481 | 751.602 | 4.56481 | 0.348936 | 4.98481 | 4.98481 | 1661.6 | 1661.6 | 0 | 0.0526121 | 3000 | 0.21644 | 8500 | 1661.6 | 0.348936 | 3463.2 | 11500 | 3000 | 8500 | 0 | 0.588924 | Face intérieure | Surface-Blanche | Mur-149 | 1-Projet | Sde | B24 | Etage 2 | 5
Mur-149 | Etage 2 | 1 | 0 | 2700 | 2700 | 1.6932 | 830 | 0.347249 | 1.8928 | 1.8928 | 2538.33 | 4.9607 | 4.7717 | 0.132496 | 2718.33 | 2538.33 | 6.8535 | 2538.33 | 6.6645 | 0.479745 | 6.8535 | 6.8535 | 2538.33 | 2538.33 | 0 | 0.177683 | 2700 | 0.347249 | 8500 | 2538.33 | 0.479745 | 5216.66 | 11200 | 2700 | 8500 | 0 | 0.733366 | Face intérieure | Peinture-01 | Mur-149 | 1-Projet | Entree/Pl | B26 | Etage 2 | 5
Mur-149 | Etage 2 | 1 | 0 | 2700 | 2700 | 1.6932 | 830 | 0.199207 | 1.8928 | 1.8928 | 1755.04 | 2.94031 | 2.75131 | 0.132496 | 1970.04 | 880.041 | 4.83311 | 810.04 | 4.64411 | 0.331703 | 4.83311 | 4.64411 | 1790.04 | 1720.04 | 0 | 0.0591528 | 2700 | 0.199207 | 8500 | 1790.04 | 0.331703 | 3679.08 | 11200 | 2700 | 8500 | 0 | 0.638292 | Face intérieure | Peinture-01 | Mur-149 | 1-Projet | Entree/pl | B22 | Etage 2 | 5
Mur-148 | Etage 2 | 0 | 0 | 3000 | 3000 | 0 | 0 | 0.134657 | 0 | 0 | 641.226 | 2.02868 | 1.81868 | 0 | 676.226 | 676.226 | 2.02868 | 606.226 | 1.81868 | 0.134657 | 2.02868 | 1.81868 | 676.226 | 606.226 | 0 | 0.0448858 | 3000 | 0.134657 | 8500 | 676.226 | 0.134657 | 1451.45 | 11500 | 3000 | 8500 | 0 | 0.596757 | Face intérieure | Surface-Blanche | Mur-148 | 1-Projet | Sejour cuisine | B21 | Etage 2 | 5
Mur-149 | Etage 2 | 0 | 0 | 3000 | 3000 | 0 | 0 | 0.363727 | 0 | 0 | 1720.03 | 5.1961 | 4.98609 | 0 | 1970.03 | 1720.03 | 5.1961 | 1720.03 | 4.98609 | 0.363727 | 5.1961 | 5.19609 | 1720.03 | 1720.03 | 0 | 0.133002 | 3000 | 0.363727 | 8500 | 1900.03 | 0.363727 | 3580.06 | 11500 | 3000 | 8500 | 0 | 0.686005 | Face intérieure | Surface-Blanche | Mur-149 | 1-Projet | Wc | B22 | Etage 2 | 5
Mur-148 | Etage 2 | 0 | 0 | 3000 | 0 | 0 | 0 | 0.122043 | 0 | 0 | 761.157 | 1.84841 | 1.63853 | 0 | 796.137 | 796.137 | 1.84841 | 726.178 | 1.63853 | 0.122043 | 1.84841 | 1.63853 | 796.137 | 726.178 | 0 | 0.040681 | 3000 | 0.122043 | 8500 | 616.157 | 0.122043 | 1691.28 | 11500 | 3000 | 8500 | 0 | 0.58826 | Face intérieure | Surface-Blanche | Mur-148 | 1-Projet |  |  | Etage 2 | 5
Mur-149 | Etage 2 | 0 | 0 | 2700 | 2700 | 0 | 0 | 0.0909898 | 0 | 0 | 481.427 | 1.39435 | 1.20535 | 0 | 516.427 | 516.427 | 1.39435 | 446.427 | 1.20535 | 0.0909898 | 1.39435 | 1.20535 | 516.427 | 446.427 | 0 | 0.0336999 | 2700 | 0.0909898 | 8500 | 516.427 | 0.0909898 | 1131.85 | 11200 | 2700 | 8500 | 0 | 0.523686 | Face intérieure | Peinture-01 | Mur-149 | 1-Projet | Cellier | A24 | Etage 2 | 5
Mur-149 | Etage 2 | 0 | 0 | 3000 | 3000 | 0 | 0 | 0.058494 | 0 | 0 | 278.543 | 0.940629 | 0.730629 | 0 | 383.543 | 313.543 | 0.940629 | 243.543 | 0.730629 | 0.058494 | 0.940629 | 0.730629 | 313.543 | 243.543 | 0 | 0.019498 | 3000 | 0.058494 | 8500 | 313.543 | 0.058494 | 726.081 | 11500 | 3000 | 8500 | 0 | 0.545981 | Face intérieure | Surface-Blanche | Mur-149 | 1-Projet | Sde | B22 | Etage 2 | 5
Mur-149 | Etage 2 | 0 | 0 | 2700 | 2700 | 0 | 0 | 0.0977248 | 0 | 0 | 517.062 | 1.49055 | 1.30159 | 0 | 622.054 | 552.054 | 1.49055 | 482.07 | 1.30159 | 0.0977248 | 1.49055 | 1.30159 | 552.054 | 482.07 | 0 | 0.0361944 | 2700 | 0.0977248 | 8500 | 552.07 | 0.0977248 | 1203.12 | 11200 | 2700 | 8500 | 0 | 0.528675 | Face intérieure | Peinture-01 | Mur-149 | 1-Projet | Cellier | A24 | Etage 2 | 5
Mur-121 | Etage 2 | 0 | 0 | 3000 | 3000 | 0 | 0 | 0.100802 | 0 | 0 | 480.009 | 1.33509 | 1.54497 | 0 | 584.989 | 445.03 | 1.33509 | 514.989 | 1.54497 | 0.100802 | 1.33509 | 1.54497 | 445.03 | 514.989 | 0 | 0.0336007 | 3000 | 0.100802 | 8500 | 514.989 | 0.100802 | 1128.98 | 11500 | 3000 | 8500 | 0 | 0.574099 | Face extérieure | Lavis blanc | Mur-121 | 1-Projet | Sejour cuisine | A23 | Etage 2 | 5
Mur-153 | Etage 2 | 2 | 0 | 2700 | 2700 | 3.3864 | 1660 | 0.774271 | 3.7856 | 3.7856 | 5498.75 | 10.683 | 10.683 | 0.264992 | 5498.75 | 3678.75 | 14.4686 | 3678.75 | 14.4686 | 1.03926 | 14.8466 | 14.8466 | 5498.75 | 5498.75 | 0 | 0.257512 | 2700 | 0.774271 | 8500 | 5498.75 | 1.03926 | 11137.5 | 11200 | 2700 | 8500 | 0 | 1.02042 | Face extérieure | Peinture-01 | Mur-153 | 1-Projet | Ch 2/pl | A24 | Etage 2 | 5
Mur-149 | Etage 2 | 0 | 0 | 2700 | 2700 | 0 | 0 | 0.105472 | 0 | 0 | 558.051 | 1.50674 | 1.50674 | 0 | 968.051 | 558.051 | 1.50674 | 558.051 | 1.50674 | 0.105472 | 1.50674 | 1.50674 | 558.051 | 558.051 | 0 | 0.0390636 | 2700 | 0.105472 | 8500 | 558.051 | 0.105472 | 1256.1 | 11200 | 2700 | 8500 | -1.77636e-12 | 0.456127 | Face intérieure | Peinture-01 | Mur-149 | 1-Projet | Sejour cuisine/pl | A24 | Etage 2 | 5
Mur-153 | Etage 2 | 1 | 0 | 2700 | 2700 | 1.6932 | 830 | 0.449164 | 1.8928 | 1.8928 | 3077.57 | 6.22753 | 6.03873 | 0.132496 | 3147.6 | 2167.53 | 8.12033 | 2167.6 | 7.93153 | 0.58166 | 8.30933 | 8.30953 | 3077.53 | 3077.6 | 0 | 0.15173 | 2700 | 0.449164 | 8500 | 3077.6 | 0.58166 | 6295.13 | 11200 | 2700 | 8500 | 0 | 0.745159 | Face extérieure | Peinture-01 | Mur-153 | 1-Projet | Dgt | A24 | Etage 2 | 5
Mur-148 | Etage 2 | 0 | 0 | 3000 | 0 | 0 | 0 | 0.328261 | 0 | 0 | 1743.15 | 4.58438 | 4.5845 | 0 | 1778.13 | 1708.13 | 4.58438 | 1778.17 | 4.5845 | 0.328261 | 4.58438 | 4.7945 | 1708.13 | 1778.17 | 0 | 0.10942 | 3000 | 0.328261 | 8500 | 1598.19 | 0.328261 | 3655.32 | 11500 | 3000 | 8500 | 0 | 0.725905 | Face intérieure | Surface-Blanche | Mur-148 | 1-Projet | Sejour cuisine | A23 | Etage 2 | 5
Mur-153 | Etage 2 | 1 | 1 | 2700 | 0 | 1.1832 | 580 | 0.103006 | 3.98443 | 3.98421 | 2160.68 | 1.47143 | 1.4716 | 0.278902 | 2230.67 | 210.482 | 2.70143 | 210.566 | 2.7016 | 0.381908 | 5.45586 | 5.45581 | 2160.69 | 2160.67 | 2.75443 | 0.00493658 | 2700 | 0.103006 | 8500 | 2020.77 | 0.381908 | 4461.36 | 11200 | 2700 | 8500 | 0 | 0.192584 | Face extérieure | Peinture-01 | Mur-153 | 1-Projet | Dgt | A24 | Etage 2 | 5
Mur-121 | Etage 2 | 1 | 0 | 3000 | 3000 | 1.6932 | 830 | 0.195449 | 1.8928 | 1.8928 | 1561.64 | 2.68697 | 2.89729 | 0.132496 | 1596.7 | 616.59 | 4.57977 | 686.696 | 4.79009 | 0.327945 | 4.57977 | 4.79009 | 1526.59 | 1596.7 | 0 | 0.045615 | 3000 | 0.195449 | 8500 | 1596.7 | 0.327945 | 3292.36 | 11500 | 3000 | 8500 | 0 | 0.662139 | Face extérieure | Lavis blanc | Mur-121 | 1-Projet | Sejour cuisine | A23 | Etage 2 | 5 | ArchiCADProperties - Zones conflictuelles: Wc
Mur-149 | Etage 2 | 0 | 0 | 3000 | 3000 | 0 | 0 | 0.186692 | 0 | 0 | 889.01 | 2.77203 | 2.56203 | 0 | 924.009 | 924.01 | 2.77203 | 854.01 | 2.56203 | 0.186692 | 2.77203 | 2.56203 | 924.01 | 854.01 | 0 | 0.0622306 | 3000 | 0.186692 | 8500 | 924.009 | 0.186692 | 1947.01 | 11500 | 3000 | 8500 | 0 | 0.631446 | Face intérieure | Surface-Blanche | Mur-149 | 1-Projet | Sde | A23 | Etage 2 | 5
Mur-153 | Etage 2 | 0 | 0 | 2700 | 2300 | 0 | 0 | 0.794084 | 0 | 0 | 4214.84 | 11.3441 | 11.3441 | 0 | 4554.84 | 4214.84 | 11.3441 | 4214.84 | 11.3441 | 0.794084 | 11.3801 | 11.3801 | 4214.84 | 4214.84 | 0 | 0.295038 | 2700 | 0.794084 | 8500 | 4214.84 | 0.796604 | 8569.67 | 11200 | 2700 | 8500 | -1.77636e-12 | 0.968077 | Face extérieure | Peinture-01 | Mur-153 | 1-Projet | Ch 2/pl | A24 | Etage 2 | 5
Mur-153 | Etage 2 | 1 | 0 | 2700 | 2700 | 2.34891 | 1174.46 | 0.136678 | 2.34891 | 2.34891 | 1593.13 | 1.48009 | 1.858 | 0.164424 | 1558.12 | 383.691 | 1.48009 | 453.66 | 1.858 | 0.301102 | 4.207 | 4.39591 | 1558.15 | 1628.12 | 0 | 0.0293073 | 2700 | 0.136678 | 8500 | 1628.12 | 0.301102 | 3355.24 | 11200 | 2700 | 8500 | 0 | 0.597053 | Face extérieure | Peinture-01 | Mur-153 | 1-Projet | Dgt | A24 | Etage 2 | 5 | ArchiCADProperties - Zones conflictuelles: Dgt; Sejour cuisine/pl
Mur-149 | Etage 2 | 0 | 0 | 2700 | 2700 | 0 | 0 | 0.119711 | 0 | 0 | 633.393 | 1.61569 | 1.80464 | 0 | 598.402 | 598.402 | 1.61569 | 668.383 | 1.80464 | 0.119711 | 1.61569 | 1.80464 | 598.402 | 668.383 | 0 | 0.0443375 | 2700 | 0.119711 | 8500 | 668.402 | 0.119711 | 1435.78 | 11200 | 2700 | 8500 | 0 | 0.544961 | Face intérieure | Peinture-01 | Mur-149 | 1-Projet | Wc | A24 | Etage 2 | 5
Mur-153 | Etage 2 | 0 | 0 | 2700 | 0 | 0 | 0 | 0.444955 | 0 | 0 | 2424.26 | 6.58585 | 5.93816 | 0 | 2509.32 | 2509.2 | 6.58585 | 2339.32 | 5.93816 | 0.444955 | 6.58585 | 6.12716 | 2509.2 | 2339.32 | 0 | 0.164798 | 2700 | 0.444955 | 8500 | 2439.28 | 0.444955 | 5069.49 | 11200 | 2700 | 8500 | 0 | 0.926218 | Face extérieure | Peinture-01 | Mur-153 | 1-Projet | Sejour cuisine/pl | A24 | Etage 2 | 5
Mur-148 | Etage 2 | 0 | 0 | 2700 | 2700 | 0 | 0 | 0.273714 | 0 | 0 | 1448.22 | 3.9102 | 3.91019 | 0 | 1518.22 | 1448.22 | 3.9102 | 1448.22 | 3.91019 | 0.273714 | 3.9102 | 3.91019 | 1448.22 | 1448.22 | 0 | 0.101375 | 2700 | 0.273714 | 8500 | 1448.22 | 0.273714 | 3036.44 | 11200 | 2700 | 8500 | 0 | 0.580751 | Face extérieure | Lavis blanc | Mur-148 | 1-Projet | Sejour cuisine/pl | A25 | Etage 2 | 5
Mur-148 | Etage 2 | 0 | 0 | 2700 | 2700 | 0 | 0 | 0.117368 | 0 | 0 | 620.997 | 1.77058 | 1.58281 | 0 | 586.225 | 655.769 | 1.77058 | 586.225 | 1.58281 | 0.117368 | 1.77058 | 1.58281 | 655.769 | 586.225 | 0 | 0.0434698 | 2700 | 0.117368 | 8500 | 655.769 | 0.117368 | 1410.67 | 11200 | 2700 | 8500 | 0 | 0.542357 | Face extérieure | Lavis blanc | Mur-148 | 1-Projet | Ch 1 | A25 | Etage 2 | 5
Mur-148 | Etage 2 | 2 | 0 | 2700 | 2700 | 4.5893 | 2278.05 | 0.438201 | 4.7089 | 4.7089 | 4062.56 | 6.1649 | 6.16613 | 0.329623 | 4027.79 | 1779.28 | 8.0577 | 1709.74 | 8.05893 | 0.767824 | 11.0628 | 10.875 | 4097.33 | 4027.79 | 0 | 0.122116 | 2700 | 0.438201 | 8500 | 4097.33 | 0.767824 | 8293.79 | 11200 | 2700 | 8500 | 0 | 0.721912 | Face extérieure | Lavis blanc | Mur-148 | 1-Projet | Sejour cuisine/pl | A25 | Etage 2 | 5
Mur-121 | Etage 2 | 0 | 0 | 2800 | 0 | 0 | 0 | 0.0661692 | 0 | 0 | 400.098 | 0.945275 | 0.945275 | 0 | 580.098 | 400.098 | 0.945275 | 400.098 | 0.945275 | 0.0661692 | 0.945275 | 0.945275 | 400.098 | 400.098 | 0 | 0.0280069 | 2800 | 0.0661692 | 8500 | 400.098 | 0.0661692 | 940.196 | 11300 | 2800 | 8500 | 0 | 0.443114 | Face extérieure | Lavis blanc | Mur-121 | 1-Projet |  |  | Etage 2 | 5
Mur-149 | Etage 2 | 1 | 0 | 2700 | 2700 | 1.1832 | 580 | 0.031842 | 1.1366 | 1.1366 | 589.44 | 0.549386 | 0.360386 | 0.0795621 | 624.44 | 70 | 1.68599 | 0 | 1.49699 | 0.111404 | 1.68599 | 1.49699 | 624.44 | 554.44 | 0 | 0.00245 | 2700 | 0.031842 | 8500 | 624.44 | 0.111404 | 1347.87 | 11200 | 2700 | 8500 | 0 | 0.356497 | Face intérieure | Peinture-01 | Mur-149 | 1-Projet | Sejour cuisine | B25 | Etage 2 | 5
Mur-149 | Etage 2 | 1 | 0 | 2700 | 0 | 1.71426 | 857.128 | 0.1232 | 1.69157 | 1.69157 | 1348.36 | 1.76 | 1.76 | 0.11841 | 1348.36 | 502.573 | 3.45157 | 502.573 | 3.45157 | 0.24161 | 3.45157 | 3.45157 | 1348.36 | 1348.36 | 0 | 0.0302801 | 2700 | 0.1232 | 8500 | 1278.36 | 0.24161 | 2836.72 | 11200 | 2700 | 8500 | 0 | 0.357765 | Face intérieure | Peinture-01 | Mur-149 | 1-Projet | Entree/pl | B25 | Etage 2 | 5 | ArchiCADProperties - Zones conflictuelles: Entree/pl
Mur-149 | Etage 2 | 0 | 0 | 2500 | 2500 | 0 | 0 | 0.479701 | 0 | 0 | 2741.15 | 6.67788 | 6.67788 | 0 | 2991.15 | 2741.15 | 6.67788 | 2741.15 | 6.67788 | 0.479701 | 6.85288 | 6.85288 | 2741.15 | 2741.15 | 0 | 0.191881 | 2500 | 0.479701 | 8500 | 2741.15 | 0.479701 | 5622.3 | 11000 | 2500 | 8500 | 0 | 0.733761 | Face intérieure | Surface-Blanche | Mur-149 | 1-Projet | Sde | B25 | Etage 2 | 5
Mur-149 | Etage 2 | 0 | 1 | 2500 | 2500 | 0 | 0 | 0.781195 | 1.95262 | 1.95262 | 5245.02 | 10.9849 | 10.5349 | 0.136683 | 5585.02 | 4287.85 | 12.9375 | 4287.85 | 12.4875 | 0.917878 | 13.1125 | 13.1125 | 5245.02 | 5245.02 | 1.95262 | 0.30015 | 2500 | 0.781195 | 8500 | 5245.02 | 0.917878 | 10630 | 11000 | 2500 | 8500 | 0 | 1.0173 | Face intérieure | Peinture-01 | Mur-149 | 1-Projet | Sejour cuisine | B25 | Etage 2 | 5
Mur-149 | Etage 2 | 1 | 0 | 2700 | 0 | 1.6932 | 830 | 0.334336 | 1.8928 | 1.8928 | 2680 | 4.87068 | 4.5067 | 0.132496 | 2714.99 | 1804.99 | 6.76348 | 1735 | 6.3995 | 0.466832 | 6.76348 | 6.5745 | 2714.99 | 2645 | 0 | 0.109201 | 2700 | 0.334336 | 8500 | 2505.02 | 0.466832 | 5528.98 | 11200 | 2700 | 8500 | 0 | 0.738371 | Face intérieure | Peinture-01 | Mur-149 | 1-Projet | Wc | B24 | Etage 2 | 5 | ArchiCADProperties - Zones conflictuelles: Sejour cuisine; Wc
Mur-120 | Etage 2 | 7 | 0 | 2500 | 0 | 7.2216 | 3540 | 0.304689 | 7.544 | 7.544 | 4828.68 | 3.4777 | 3.4777 | 0.52808 | 4828.68 | 1918.68 | 8.4797 | 1918.68 | 8.4797 | 0.832769 | 11.8967 | 11.8967 | 4828.68 | 4828.68 | 0 | 0.0755076 | 2500 | 0.304689 | 8500 | 4758.68 | 0.832769 | 9797.36 | 11000 | 2500 | 8500 | 0 | 0.758615 | Face extérieure | Peinture-01 | Mur-120 | 3D |  |  | Etage 2 | 5
Mur-149 | Etage 2 | 0 | 0 | 2500 | 2500 | 0 | 0 | 0.220213 | 0 | 0 | 1258.36 | 2.9709 | 2.9709 | 0 | 1328.36 | 1258.36 | 2.9709 | 1258.36 | 2.9709 | 0.220213 | 3.1459 | 3.1459 | 1258.36 | 1258.36 | 0 | 0.0880851 | 2500 | 0.220213 | 8500 | 1258.36 | 0.220213 | 2656.72 | 11000 | 2500 | 8500 | 0 | 0.52617 | Face intérieure | Peinture-01 | Mur-149 | 1-Projet | Dgt | B25 | Etage 2 | 5
Mur-149 | Etage 2 | 0 | 0 | 3000 | 3000 | 0 | 0 | 0.13335 | 0 | 0 | 635 | 2.01 | 1.8 | 0 | 670 | 670 | 2.01 | 600 | 1.8 | 0.13335 | 2.01 | 1.8 | 670 | 600 | 0 | 0.04445 | 3000 | 0.13335 | 8500 | 670 | 0.13335 | 1438.99 | 11500 | 3000 | 8500 | 0 | 0.595885 | Face intérieure | Surface-Blanche | Mur-149 | 1-Projet | Ch 2/pl | B24 | Etage 2 | 5
Mur-149 | Etage 2 | 2 | 0 | 2700 | 2700 | 2.8764 | 1410 | 0.193353 | 3.1228 | 3.1228 | 2179.62 | 2.76221 | 2.57316 | 0.218596 | 2459.63 | 669.632 | 5.88501 | 669.614 | 5.69596 | 0.411949 | 5.88501 | 5.88496 | 2179.63 | 2179.61 | 0 | 0.0468736 | 2700 | 0.193353 | 8500 | 2179.63 | 0.411949 | 4499.25 | 11200 | 2700 | 8500 | 0 | 0.433947 | Face intérieure | Peinture-01 | Mur-149 | 1-Projet | Wc | A22 | Etage 2 | 5
Mur-149 | Etage 2 | 0 | 0 | 3000 | 3000 | 0 | 0 | 0.144774 | 0 | 0 | 689.402 | 2.06821 | 1.87921 | 0 | 689.402 | 689.402 | 2.06821 | 689.402 | 1.87921 | 0.144774 | 2.06821 | 2.06821 | 689.402 | 689.402 | 0 | 0.0482582 | 3000 | 0.144774 | 8500 | 689.402 | 0.144774 | 1518.8 | 11500 | 3000 | 8500 | 0 | 0.516516 | Face intérieure | Surface-Blanche | Mur-149 | 1-Projet | Sejour cuisine/pl | A25 | Etage 2 | 5
Mur-153 | Etage 2 | 1 | 0 | 2700 | 2700 | 1.1832 | 580 | 0.0310074 | 1.23 | 1.23 | 619.616 | 0.442963 | 0.442963 | 0.0861 | 619.616 | 19.6161 | 1.67296 | 19.6161 | 1.67296 | 0.117107 | 1.67296 | 1.67296 | 619.616 | 619.616 | 0 | 0.00137313 | 2700 | 0.0310074 | 8500 | 619.616 | 0.117107 | 1379.23 | 11200 | 2700 | 8500 | 0 | 0.422746 | Face extérieure | Peinture-01 | Mur-153 | 1-Projet |  |  | Etage 2 | 5
Mur-149 | Etage 2 | 0 | 0 | 3000 | 3000 | 0 | 0 | 0.126 | 0 | 0 | 600 | 1.8 | 1.8 | 0 | 670 | 600 | 1.8 | 600 | 1.8 | 0.126 | 1.8 | 1.8 | 600 | 600 | 0 | 0.042 | 3000 | 0.126 | 8500 | 600 | 0.126 | 1340 | 11500 | 3000 | 8500 | 0 | 0.504 | Face intérieure | Surface-Blanche | Mur-149 | 1-Projet | Entree/pl | A22 | Etage 2 | 5
Mur-149 | Etage 2 | 0 | 0 | 2700 | 2700 | 0 | 0 | 0.161454 | 0 | 0 | 854.253 | 2.30648 | 2.30648 | 0 | 924.253 | 854.253 | 2.30648 | 854.253 | 2.30648 | 0.161454 | 2.30648 | 2.30648 | 854.253 | 854.253 | 0 | 0.0597977 | 2700 | 0.161454 | 8500 | 854.253 | 0.161454 | 1848.51 | 11200 | 2700 | 8500 | -1.77636e-12 | 0.497595 | Face intérieure | Surface-Blanche | Mur-149 | 1-Projet | Ch 1/pl | A21 | Etage 2 | 5
Mur-153 | Etage 2 | 1 | 0 | 3000 | 3000 | 1.1832 | 580 | 0.068173 | 1.23 | 1.23 | 734.633 | 1.0789 | 0.6589 | 0.0861 | 699.633 | 169.633 | 2.3089 | 99.6332 | 1.8889 | 0.154273 | 2.3089 | 2.0989 | 769.633 | 699.633 | 0 | 0.00942433 | 3000 | 0.068173 | 8500 | 769.633 | 0.154273 | 1638.26 | 11500 | 3000 | 8500 | 0 | 0.567834 | Face extérieure | Peinture-01 | Mur-153 | 1-Projet | Sejour cuisine | A23 | Etage 2 | 5
Mur-149 | Etage 2 | 0 | 0 | 2700 | 0 | 0 | 0 | 0.156586 | 0 | 0 | 898.496 | 2.23694 | 2.23694 | 0 | 1078.5 | 898.496 | 2.23694 | 898.496 | 2.23694 | 0.156586 | 2.23694 | 2.23694 | 898.496 | 898.496 | 0 | 0.0579947 | 2700 | 0.156586 | 8500 | 828.496 | 0.156586 | 1936.99 | 11200 | 2700 | 8500 | 0 | 0.493989 | Face intérieure | Peinture-01 | Mur-149 | 1-Projet | Sde | B26 | Etage 2 | 5 | ArchiCADProperties - Zones conflictuelles: Sde
Mur-149 | Etage 2 | 0 | 0 | 2700 | 2700 | 0 | 0 | 0.120015 | 0 | 0 | 635 | 1.809 | 1.62 | 0 | 740 | 670 | 1.809 | 600 | 1.62 | 0.120015 | 1.809 | 1.62 | 670 | 600 | 0 | 0.04445 | 2700 | 0.120015 | 8500 | 670 | 0.120015 | 1438.99 | 11200 | 2700 | 8500 | 0 | 0.545186 | Face intérieure | Peinture-01 | Mur-149 | 1-Projet | Ch 1/pl | B26 | Etage 2 | 5
Mur-149 | Etage 2 | 0 | 0 | 2700 | 2700 | 0 | 0 | 0.313768 | 0 | 0 | 1660.15 | 4.29341 | 4.29341 | 0 | 1840.15 | 1660.15 | 4.29341 | 1660.15 | 4.29341 | 0.313768 | 4.48241 | 4.48241 | 1660.15 | 1660.15 | 0 | 0.116211 | 2700 | 0.313768 | 8500 | 1660.15 | 0.313768 | 3460.3 | 11200 | 2700 | 8500 | 0 | 0.610421 | Face intérieure | Peinture-01 | Mur-149 | 1-Projet | Wc | B24 | Etage 2 | 5
Mur-149 | Etage 2 | 0 | 0 | 2700 | 2700 | 0 | 0 | 0.109258 | 0 | 0 | 578.084 | 1.65533 | 1.46633 | 0 | 613.084 | 613.084 | 1.65533 | 543.084 | 1.46633 | 0.109258 | 1.65533 | 1.46633 | 613.084 | 543.084 | 0 | 0.0404658 | 2700 | 0.109258 | 8500 | 613.084 | 0.109258 | 1325.16 | 11200 | 2700 | 8500 | 0 | 0.537218 | Face intérieure | Peinture-01 | Mur-149 | 1-Projet | Sejour cuisine/pl | A24 | Etage 2 | 5
Mur-120 | Etage 2 | 5 | 0 | 3000 | 3000 | 5.61 | 2750 | 0.356614 | 5.8425 | 5.8425 | 3645.66 | 4.04448 | 4.67448 | 0.408975 | 3645.66 | 795.661 | 9.88698 | 795.661 | 10.517 | 0.765589 | 10.937 | 10.937 | 3645.66 | 3645.66 | 0 | 0.0556963 | 3000 | 0.356614 | 8500 | 3645.66 | 0.765589 | 7431.32 | 11500 | 3000 | 8500 | 0 | 0.730893 | Face extérieure | Lavis blanc | Mur-120 | 3D |  |  | Etage 2 | 5
Mur-149 | Etage 2 | 0 | 0 | 2700 | 2700 | 0 | 0 | 0.120505 | 0 | 0 | 635 | 1.634 | 1.809 | 0 | 670 | 600 | 1.634 | 670 | 1.809 | 0.120505 | 1.634 | 1.809 | 600 | 670 | 0 | 0.0469 | 2700 | 0.120505 | 8500 | 670.059 | 0.120505 | 1439.04 | 11200 | 2700 | 8500 | 0 | 0.544392 | Face intérieure | Surface-Blanche | Mur-149 | 1-Projet | Ch 1/pl | B25 | Etage 2 | 5
Mur-149 | Etage 2 | 0 | 0 | 2500 | 2500 | 0 | 0 | 0.0929611 | 0 | 0 | 531.206 | 1.41572 | 1.24031 | 0 | 636.287 | 566.287 | 1.41572 | 496.126 | 1.24031 | 0.0929611 | 1.41572 | 1.24031 | 566.287 | 496.126 | 0 | 0.0371845 | 2500 | 0.0929611 | 8500 | 566.287 | 0.0929611 | 1231.52 | 11000 | 2500 | 8500 | 0 | 0.497142 | Face intérieure | Surface-Blanche | Mur-149 | 1-Projet | Sde | B25 | Etage 2 | 5
Mur-149 | Etage 2 | 0 | 0 | 2700 | 2600 | 0 | 0 | 0.113141 | 0 | 0 | 598.633 | 1.7108 | 1.52181 | 0 | 633.631 | 633.631 | 1.7108 | 563.635 | 1.52181 | 0.113141 | 1.7108 | 1.52182 | 633.631 | 563.635 | 0 | 0.0419043 | 2700 | 0.113141 | 8500 | 633.631 | 0.113142 | 1366.26 | 11200 | 2700 | 8500 | 0 | 0.533083 | Face intérieure | Peinture-01 | Mur-149 | 1-Projet | Sejour cuisine | B25 | Etage 2 | 5
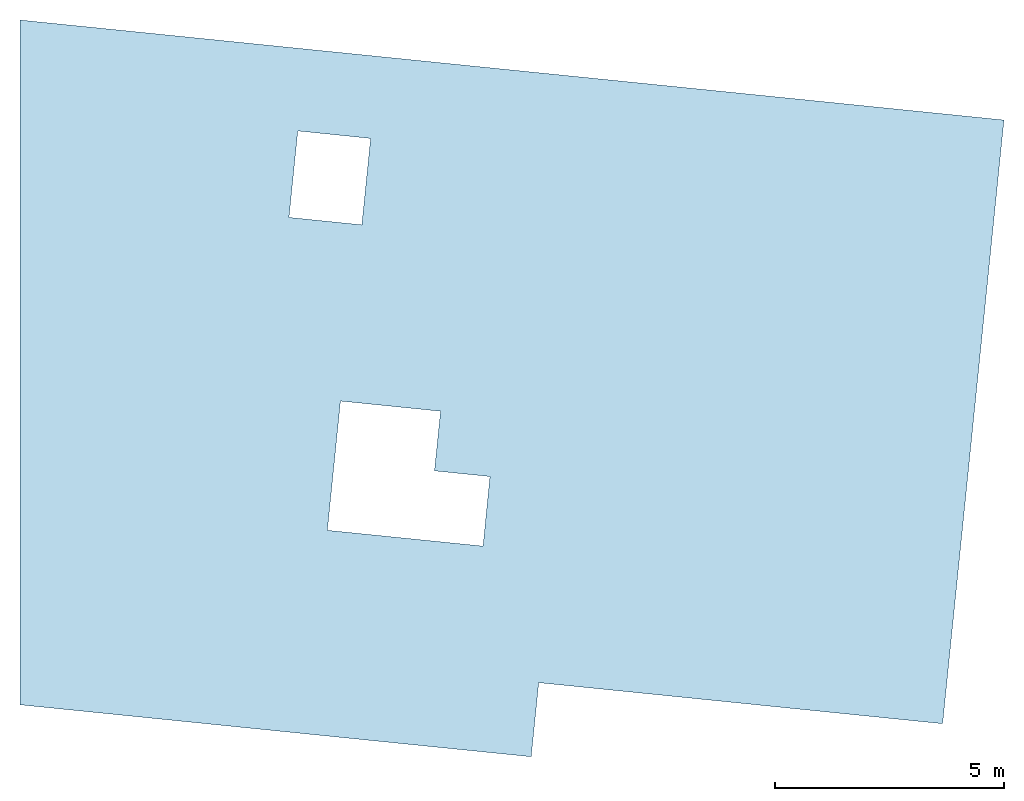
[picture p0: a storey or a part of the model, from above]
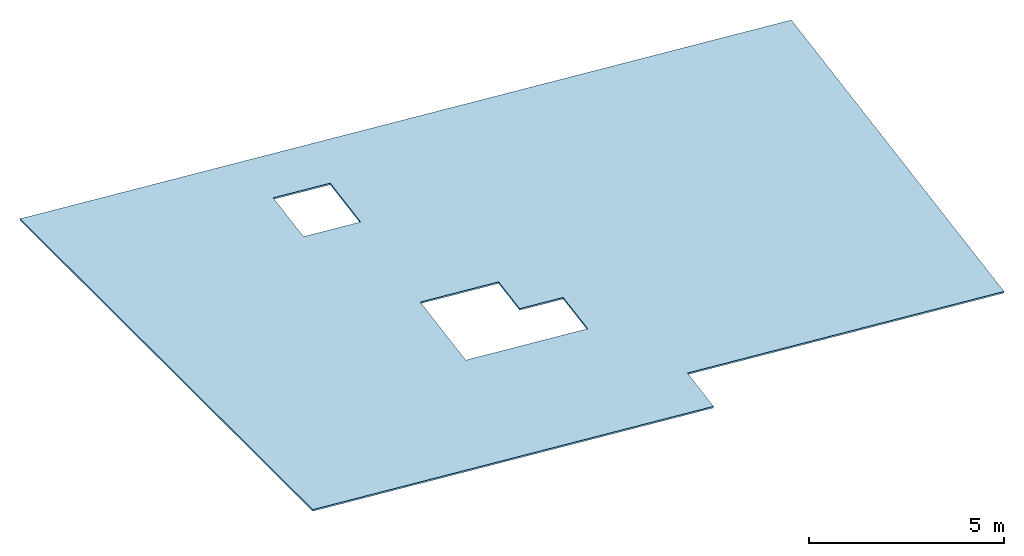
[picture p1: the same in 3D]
Properties of the parts of a building model (IFC2X3), part 27 of 44

# IfcWallStandardCase: Cloison 70 0826278243 70 (896)
Name | In | Nombre de Portes | Nombre de trous (Nombre d'ouvertures vides) | Hauteur maximale de la couche de Mur sur face intérieure (mm) = Hauteur maximale du Mur (mm) = Hauteur maximale de la couche de Mur sur face extérieure (mm) | Hauteur minimale de la couche de Mur sur face intérieure (mm) = Hauteur minimale du Mur (mm) = Hauteur minimale de la couche de Mur sur face extérieure (mm) | Superficie des portes (m2) | Largeur totale des Portes (mm) | Volume de composant de mur sur face intérieure (net) (m3) = Volume de composant de mur sur face extérieure (net) (m3) | Superficie analytique des ouvertures sur face intérieure (m2) | Superficie analytique des ouvertures sur face extérieure (m2) | Longueur moyenne du mur (mm) = Longueur du Mur au centre (mm) | Superficie de la face intérieure du mur (nette) (m2) | Superficie de la face extérieure du mur (nette) (m2) = Superficie en plan (m2) = Superficie inférieure (nette) (m2) | Volume analytique des ouvertures (m3) | Longueur de ligne de référence (mm) | Longueur de la face intérieure du mur (conditionnelle) (mm) | Superficie de la face intérieure du mur (conditionnelle) (m2) | Longueur de la face extérieure du mur (conditionnelle) (mm) | Superficie de la face extérieure du mur (conditionnelle) (m2) | Volume du composant face intérieure du mur (conditionnel) (m3) = Volume du composant face extérieure du mur (conditionnel) (m3) = Volume (conditionnel) (m3) | Superficie de la face intérieure du mur (brute) (m2) | Superficie de la face extérieure du mur (brute) (m2) | Longueur de Mur sur face intérieure (mm) | Longueur de Mur sur face extérieure (mm) | Superficie des baies libres dans le Mur (m2) | Superficie (m2) = Superficie supérieure (nette) (m2) | Hauteur (mm) | Volume (net) (m3) | Altitude à Zéro du Projet (mm) = Altitude de Référence Niveau 1 (mm) = Altitude de Référence Niveau 2 (mm) = Altitude à niveau de la mer (mm) | Longueur 3D (mm) | Volume (brut) (m3) | Périmètre Plan (mm) | Altitude supérieure à premier niveau de référence (mm) = Altitude supérieure à Zéro du projet (mm) = Altitude supérieure à niveau de la mer (mm) = Altitude supérieure à deuxième niveau de référence (mm) | Altitude supérieure à étage d'implantation (mm) | Altitude inférieure à premier niveau de référence (mm) = Altitude inférieure à Zéro du projet (mm) = Altitude inférieure à niveau de la mer (mm) = Altitude inférieure à deuxième niveau de référence (mm) | Altitude inférieure à étage d'implantation (mm) | Superficie de l'arête (nette) (m2) | Emplacement de ligne de référence | Surface de face intérieure = Surface de face extérieure = Surfaces (Toutes) = Surface latérale | ID de l'élément = Lien et ID d'élément = ID de Parent | Calque | Nom de zone liée | Numéro de zone liée | Nom d'étage d'implantation | Numéro d'étage d'implantation
Mur-149 | Etage 2 | 1 | 1 | 2500 | 2500 | 2.37672 | 1188.36 | 0.0925429 | 4.83724 | 4.83724 | 2463.71 | 1.32204 | 1.14704 | 0.338607 | 2463.71 | 70 | 1.32204 | 70 | 1.14704 | 0.43115 | 6.15928 | 6.15928 | 2463.71 | 2463.71 | 2.54052 | 0.0049 | 2500 | 0.0925429 | 8500 | 2463.71 | 0.43115 | 5067.42 | 11000 | 2500 | 8500 | 0 | 0.24456 | Face intérieure | Peinture-01 | Mur-149 | 1-Projet | Dgt | B25 | Etage 2 | 5
Mur-149 | Etage 2 | 0 | 0 | 2500 | 2500 | 0 | 0 | 0.151528 | 0 | 0 | 865.875 | 2.25219 | 2.07719 | 0 | 1080.88 | 900.875 | 2.25219 | 830.875 | 2.07719 | 0.151528 | 2.25219 | 2.07719 | 900.875 | 830.875 | 0 | 0.0606113 | 2500 | 0.151528 | 8500 | 901.036 | 0.151528 | 1900.86 | 11000 | 2500 | 8500 | 0 | 0.543996 | Face intérieure | Surface-Blanche | Mur-149 | 1-Projet |  |  | Etage 2 | 5
Mur-149 | Etage 2 | 0 | 0 | 3000 | 3000 | 0 | 0 | 0.18165 | 0 | 0 | 865 | 2.7 | 2.49 | 0 | 900 | 900 | 2.7 | 830 | 2.49 | 0.18165 | 2.7 | 2.49 | 900 | 830 | 0 | 0.06055 | 3000 | 0.18165 | 8500 | 900 | 0.18165 | 1898.99 | 11500 | 3000 | 8500 | 0 | 0.628085 | Face intérieure | Surface-Blanche | Mur-149 | 1-Projet | Sde | B22 | Etage 2 | 5
Mur-149 | Etage 2 | 1 | 0 | 2700 | 2600 | 1.6932 | 830 | 0.269858 | 1.8928 | 1.8928 | 2135.52 | 3.68012 | 3.85512 | 0.132496 | 2205.52 | 1225.52 | 5.57292 | 1225.52 | 5.74792 | 0.402354 | 5.76592 | 5.76592 | 2135.52 | 2135.52 | 0 | 0.0857867 | 2700 | 0.269858 | 8500 | 2135.52 | 0.403614 | 4411.05 | 11200 | 2700 | 8500 | 0 | 0.600673 | Face intérieure | Peinture-01 | Mur-149 | 1-Projet | Entree/pl | B25 | Etage 2 | 5
Mur-149 | Etage 2 | 0 | 0 | 2500 | 2500 | 0 | 0 | 0.237246 | 0 | 0 | 1355.69 | 3.30173 | 3.47673 | 0 | 1390.69 | 1320.69 | 3.30173 | 1390.69 | 3.47673 | 0.237246 | 3.30173 | 3.47673 | 1320.69 | 1390.69 | 0 | 0.0948985 | 2500 | 0.237246 | 8500 | 1390.69 | 0.237246 | 2880.38 | 11000 | 2500 | 8500 | 0 | 0.612284 | Face intérieure | Peinture-01 | Mur-149 | 1-Projet | Wc | B26 | Etage 2 | 5
Mur-149 | Etage 2 | 1 | 0 | 2700 | 2700 | 1.6932 | 830 | 0.400486 | 1.8928 | 1.8928 | 2820.01 | 5.72123 | 5.53223 | 0.132496 | 2820.01 | 1910.01 | 7.61403 | 1910.01 | 7.42503 | 0.532982 | 7.61403 | 7.61403 | 2820.01 | 2820.01 | 0 | 0.133701 | 2700 | 0.400486 | 8500 | 2820.01 | 0.532982 | 5780.02 | 11200 | 2700 | 8500 | 0 | 0.709102 | Face intérieure | Peinture-01 | Mur-149 | 1-Projet | Ch 3 | B25 | Etage 2 | 5
Mur-149 | Etage 2 | 0 | 0 | 2600 | 2600 | 0 | 0 | 0.176388 | 0 | 0 | 969.163 | 2.42882 | 2.61082 | 0 | 1004.16 | 934.163 | 2.42882 | 1004.16 | 2.61082 | 0.176388 | 2.52224 | 2.71124 | 934.163 | 1004.16 | 0 | 0.0678414 | 2700 | 0.176388 | 8500 | 1004.16 | 0.183172 | 2107.32 | 11100 | 2600 | 8500 | 0 | 0.507228 | Face intérieure | Peinture-01 | Mur-149 | 1-Projet | Ch 2 | B26 | Etage 2 | 5
Mur-149 | Etage 2 | 0 | 0 | 2700 | 2700 | 0 | 0 | 0.0558414 | 0 | 0 | 295.457 | 0.892292 | 0.703176 | 0 | 330.478 | 330.478 | 0.892292 | 260.436 | 0.703176 | 0.0558414 | 0.892292 | 0.703176 | 330.478 | 260.436 | 0 | 0.020682 | 2700 | 0.0558414 | 8500 | 330.489 | 0.0558414 | 759.947 | 11200 | 2700 | 8500 | -1.77636e-12 | 0.497753 | Face intérieure | Surface-Blanche | Mur-149 | 1-Projet | Sde | B21 | Etage 2 | 5
Mur-149 | Etage 2 | 0 | 0 | 2700 | 2700 | 0 | 0 | 0.13375 | 0 | 0 | 707.673 | 2.00529 | 1.81614 | 0 | 742.7 | 742.7 | 2.00529 | 672.646 | 1.81614 | 0.13375 | 2.00529 | 1.81614 | 742.7 | 672.646 | 0 | 0.0495371 | 2700 | 0.13375 | 8500 | 742.7 | 0.13375 | 1584.38 | 11200 | 2700 | 8500 | 0 | 0.555463 | Face intérieure | Surface-Blanche | Mur-149 | 1-Projet | Sde | B21 | Etage 2 | 5
Mur-149 | Etage 2 | 0 | 0 | 3000 | 3000 | 0 | 0 | 0.0914474 | 0 | 0 | 435.464 | 1.41139 | 1.20139 | 0 | 470.464 | 470.464 | 1.41139 | 400.464 | 1.20139 | 0.0914474 | 1.41139 | 1.20139 | 470.464 | 400.464 | 0 | 0.0304825 | 3000 | 0.0914474 | 8500 | 470.464 | 0.0914474 | 1039.92 | 11500 | 3000 | 8500 | 0 | 0.56795 | Face intérieure | Surface-Blanche | Mur-149 | 1-Projet | Sde | B24 | Etage 2 | 5 | ArchiCADProperties - Zones conflictuelles: Sde
Mur-149 | Etage 2 | 0 | 0 | 3000 | 3000 | 0 | 0 | 0.148916 | 0 | 0 | 709.124 | 2.23237 | 2.02237 | 0 | 924.124 | 744.124 | 2.23237 | 674.124 | 2.02237 | 0.148916 | 2.23237 | 2.02237 | 744.124 | 674.124 | 0 | 0.0496387 | 3000 | 0.148916 | 8500 | 744.124 | 0.148916 | 1587.24 | 11500 | 3000 | 8500 | 0 | 0.606262 | Face intérieure | Surface-Blanche | Mur-149 | 1-Projet | Sde | B24 | Etage 2 | 5
Mur-149 | Etage 2 | 0 | 0 | 3000 | 3000 | 0 | 0 | 0.451322 | 0 | 0 | 2149.12 | 6.44745 | 6.44745 | 0 | 2399.12 | 2149.12 | 6.44745 | 2149.12 | 6.44745 | 0.451322 | 6.44745 | 6.44745 | 2149.12 | 2149.12 | 0 | 0.150441 | 3000 | 0.451322 | 8500 | 2149.15 | 0.451322 | 4438.24 | 11500 | 3000 | 8500 | -1.77636e-12 | 0.720881 | Face intérieure | Surface-Blanche | Mur-149 | 1-Projet | Ch 1/pl | B22 | Etage 2 | 5
Mur-149 | Etage 2 | 0 | 0 | 2700 | 2700 | 0 | 0 | 0.120068 | 0 | 0 | 635.278 | 1.80975 | 1.62075 | 0 | 670.278 | 670.278 | 1.80975 | 600.278 | 1.62075 | 0.120068 | 1.80975 | 1.62075 | 670.278 | 600.278 | 0 | 0.0444695 | 2700 | 0.120068 | 8500 | 670.278 | 0.120068 | 1439.52 | 11200 | 2700 | 8500 | 0 | 0.545148 | Face intérieure | Peinture-01 | Mur-149 | 1-Projet | Sejour cuisine | B24 | Etage 2 | 5
Mur-149 | Etage 2 | 0 | 0 | 2700 | 2700 | 0 | 0 | 0.206781 | 0 | 0 | 1096.67 | 2.46102 | 2.47502 | 0 | 1096.67 | 1096.67 | 2.46102 | 1096.67 | 2.47502 | 0.206781 | 2.94702 | 2.96102 | 1096.67 | 1096.67 | 0 | 0.0767671 | 2700 | 0.206781 | 8500 | 1096.67 | 0.206781 | 2333.34 | 11200 | 2700 | 8500 | 0 | 0.537333 | Face intérieure | Peinture-01 | Mur-149 | 1-Projet | Wc | B25 | Etage 2 | 5 | ArchiCADProperties - Zones conflictuelles: Wc
Mur-149 | Etage 2 | 0 | 0 | 3000 | 3000 | 0 | 0 | 0.141566 | 0 | 0 | 674.124 | 2.02237 | 2.02237 | 0 | 924.124 | 674.124 | 2.02237 | 674.124 | 2.02237 | 0.141566 | 2.02237 | 2.02237 | 674.124 | 674.124 | 0 | 0.0471887 | 3000 | 0.141566 | 8500 | 674.124 | 0.141566 | 1488.25 | 11500 | 3000 | 8500 | 0 | 0.514377 | Face intérieure | Surface-Blanche | Mur-149 | 1-Projet |  |  | Etage 2 | 5
Mur-149 | Etage 2 | 0 | 0 | 2700 | 2700 | 0 | 0 | 0.06286 | 0 | 0 | 330 | 0.905 | 0.891 | 0 | 400 | 330 | 0.905 | 330 | 0.891 | 0.06286 | 0.905 | 0.891 | 330 | 330 | 0 | 0.02555 | 2700 | 0.06286 | 8500 | 400 | 0.06286 | 800 | 11200 | 2700 | 8500 | 0 | 0.434899 | Face intérieure | Peinture-01 | Mur-149 | 1-Projet |  |  | Etage 2 | 5
Mur-149 | Etage 2 | 0 | 0 | 2700 | 2700 | 0 | 0 | 0.347815 | 0 | 0 | 1840.29 | 4.29379 | 4.10479 | 0 | 1840.29 | 1840.29 | 4.29379 | 1840.29 | 4.10479 | 0.347815 | 4.96879 | 4.96879 | 1840.29 | 1840.29 | 0 | 0.12882 | 2700 | 0.347815 | 8500 | 1840.29 | 0.347815 | 3820.58 | 11200 | 2700 | 8500 | 0 | 0.635641 | Face intérieure | Peinture-01 | Mur-149 | 1-Projet | Wc | B24 | Etage 2 | 5 | ArchiCADProperties - Zones conflictuelles: Sejour cuisine
Mur-149 | Etage 2 | 0 | 0 | 2700 | 2700 | 0 | 0 | 0.126221 | 0 | 0 | 670.43 | 1.98511 | 1.62122 | 0 | 670.41 | 740.41 | 1.98511 | 600.451 | 1.62122 | 0.126221 | 1.98511 | 1.62122 | 740.41 | 600.451 | 0 | 0.0469301 | 2700 | 0.126221 | 8500 | 740.41 | 0.126221 | 1538.82 | 11200 | 2700 | 8500 | 0 | 0.622556 | Face intérieure | Peinture-01 | Mur-149 | 1-Projet | Sejour cuisine | B24 | Etage 2 | 5
Mur-149 | Etage 2 | 1 | 0 | 2500 | 2500 | 1.1832 | 580 | 0.0317903 | 1.23 | 1.23 | 673.659 | 0.454136 | 0.454158 | 0.0861 | 743.663 | 73.6546 | 1.68414 | 73.6633 | 1.68416 | 0.11789 | 1.68414 | 1.68416 | 673.655 | 673.663 | 0 | 0.00515613 | 2500 | 0.0317903 | 8500 | 673.663 | 0.11789 | 1487.32 | 11000 | 2500 | 8500 | -1.77636e-12 | 0.402312 | Face intérieure | Peinture-01 | Mur-149 | 1-Projet | Sejour cuisine | B24 | Etage 2 | 5 | ArchiCADProperties - Zones conflictuelles: Sejour cuisine
Mur-121 | Etage 2 | 0 | 0 | 3000 | 0 | 0 | 0 | 0.0691482 | 0 | 0 | 399.277 | 0.987831 | 0.987831 | 0 | 399.277 | 399.277 | 0.987831 | 399.277 | 0.987831 | 0.0691482 | 0.987831 | 0.987831 | 399.277 | 399.277 | 0 | 0.0230494 | 3000 | 0.0691482 | 8500 | 329.277 | 0.0691482 | 938.554 | 11500 | 3000 | 8500 | 0 | 0.466099 | Face extérieure | Lavis blanc | Mur-121 | 1-Projet |  |  | Etage 2 | 5
Mur-149 | Etage 2 | 1 | 0 | 2700 | 2700 | 0.2925 | 450 | 0.207888 | 0.3283 | 0.3283 | 1221.53 | 2.87533 | 2.49733 | 0.022981 | 1256.53 | 1256.53 | 3.20363 | 1186.53 | 2.82563 | 0.230869 | 3.39263 | 3.20363 | 1256.53 | 1186.53 | 0 | 0.085507 | 2700 | 0.207888 | 8500 | 1256.53 | 0.230869 | 2612.05 | 11200 | 2700 | 8500 | 0 | 0.6273 | Face intérieure | Peinture-01 | Mur-149 | 1-Projet | Sde | A24 | Etage 2 | 5
Mur-149 | Etage 2 | 0 | 0 | 3000 | 3000 | 0 | 0 | 0.32438 | 0 | 0 | 1540 | 4.13 | 4.13 | 0 | 1610 | 1540 | 4.13 | 1540 | 4.13 | 0.32438 | 4.634 | 4.634 | 1540 | 1540 | 0 | 0.1127 | 3000 | 0.32438 | 8500 | 1610 | 0.32438 | 3220 | 11500 | 3000 | 8500 | 0 | 0.6454 | Face intérieure | Surface-Blanche | Mur-149 | 1-Projet | Cellier | B23 | Etage 2 | 5
Mur-149 | Etage 2 | 0 | 0 | 2700 | 2700 | 0 | 0 | 0.128392 | 0 | 0 | 679.322 | 1.92867 | 1.73967 | 0 | 714.322 | 714.322 | 1.92867 | 644.322 | 1.73967 | 0.128392 | 1.92867 | 1.73967 | 714.322 | 644.322 | 0 | 0.0475526 | 2700 | 0.128392 | 8500 | 714.322 | 0.128392 | 1527.64 | 11200 | 2700 | 8500 | 0 | 0.551391 | Face intérieure | Peinture-01 | Mur-149 | 1-Projet | Sejour cuisine | B25 | Etage 2 | 5
Mur-149 | Etage 2 | 1 | 0 | 2700 | 2700 | 1.68669 | 843.343 | 0.100789 | 1.60669 | 1.60669 | 1128.34 | 1.53434 | 1.15634 | 0.112468 | 1163.34 | 360 | 3.14103 | 290 | 2.76303 | 0.213257 | 3.14103 | 2.95203 | 1163.34 | 1093.34 | 0 | 0.02275 | 2700 | 0.100789 | 8500 | 1163.34 | 0.213257 | 2425.68 | 11200 | 2700 | 8500 | 0 | 0.41802 | Face intérieure | Peinture-01 | Mur-149 | 1-Projet | Entree/Pl | B26 | Etage 2 | 5
Mur-120 | Etage 2 | 0 | 0 | 2460 | 2460 | 0 | 0 | 0.0869144 | 0 | 0 | 504.729 | 1.41383 | 1.06943 | 0 | 915.562 | 574.729 | 1.41383 | 434.729 | 1.06943 | 0.0869144 | 1.41383 | 1.06943 | 574.729 | 434.729 | 0 | 0.035331 | 2460 | 0.0869144 | 8500 | 574.729 | 0.0869144 | 1207.45 | 10960 | 2460 | 8500 | 0 | 0.557717 | Face extérieure | Lavis blanc | Mur-120 | 3D |  |  | Etage 2 | 5
Mur-149 | Etage 2 | 0 | 0 | 2700 | 0 | 0 | 0 | 0.168091 | 0 | 0 | 889.391 | 2.44186 | 2.30686 | 0 | 1104.39 | 924.391 | 2.44186 | 854.391 | 2.30686 | 0.168091 | 2.44186 | 2.30686 | 924.391 | 854.391 | 0 | 0.0622559 | 2700 | 0.168091 | 8500 | 924.391 | 0.168091 | 1947.77 | 11200 | 2700 | 8500 | 0 | 0.580776 | Face intérieure | Surface-Blanche | Mur-149 | 1-Projet | Sde | A21 | Etage 2 | 5 | ArchiCADProperties - Zones conflictuelles: Sde
Mur-149 | Etage 2 | 0 | 0 | 2700 | 2700 | 0 | 0 | 0.204154 | 0 | 0 | 1080.18 | 2.91647 | 2.5385 | 0 | 1150.17 | 1150.17 | 2.91647 | 1010.18 | 2.5385 | 0.204154 | 3.10547 | 2.7275 | 1150.17 | 1010.18 | 0 | 0.0756125 | 2700 | 0.204154 | 8500 | 1150.17 | 0.204154 | 2358.34 | 11200 | 2700 | 8500 | 0 | 0.685775 | Face intérieure | Surface-Blanche | Mur-149 | 1-Projet | Ch 1/pl | A21 | Etage 2 | 5 | ArchiCADProperties - Zones conflictuelles: Sde
Mur-149 | Etage 2 | 0 | 0 | 2700 | 2700 | 0 | 0 | 0.0538618 | 0 | 0 | 284.983 | 0.863944 | 0.674964 | 0 | 529.979 | 319.979 | 0.863944 | 249.987 | 0.674964 | 0.0538618 | 0.863944 | 0.674964 | 319.979 | 249.987 | 0 | 0.0199488 | 2700 | 0.0538618 | 8500 | 319.987 | 0.0538618 | 738.961 | 11200 | 2700 | 8500 | 0 | 0.496184 | Face intérieure | Peinture-01 | Mur-149 | 1-Projet | Entree | A21 | Etage 2 | 5
Mur-149 | Etage 2 | 1 | 0 | 2700 | 2700 | 1.6932 | 830 | 0.490414 | 1.8928 | 1.8928 | 3295.82 | 7.00592 | 7.00592 | 0.132496 | 3475.82 | 2385.82 | 8.89872 | 2385.82 | 8.89872 | 0.62291 | 8.89872 | 8.89872 | 3295.82 | 3295.82 | 0 | 0.167008 | 2700 | 0.490414 | 8500 | 3295.82 | 0.62291 | 6731.64 | 11200 | 2700 | 8500 | 0 | 0.775715 | Face intérieure | Peinture-01 | Mur-149 | 1-Projet | Entree | A21 | Etage 2 | 5
Mur-149 | Etage 2 | 0 | 0 | 2700 | 2700 | 0 | 0 | 0.4482 | 0 | 0 | 2371.43 | 6.40286 | 6.40286 | 0 | 2371.43 | 2371.43 | 6.40286 | 2371.43 | 6.40286 | 0.4482 | 6.40286 | 6.40286 | 2371.43 | 2371.43 | 0 | 0.166 | 2700 | 0.4482 | 8500 | 2371.43 | 0.4482 | 4882.86 | 11200 | 2700 | 8500 | 0 | 0.71 | Face intérieure | Surface-Blanche | Mur-149 | 1-Projet | Ch 1/pl | A21 | Etage 2 | 5
Mur-149 | Etage 2 | 1 | 0 | 2700 | 2700 | 3.44032 | 1720.16 | 0.090903 | 3.44032 | 3.44032 | 1755.16 | 1.39311 | 1.20411 | 0.240823 | 1790.16 | 70 | 1.39311 | 1.91022e-07 | 1.20411 | 0.331726 | 4.83344 | 4.64444 | 1790.16 | 1720.16 | 0 | 0.00245 | 2700 | 0.090903 | 8500 | 1790.16 | 0.331726 | 3679.32 | 11200 | 2700 | 8500 | 0 | 0.441598 | Face intérieure | Peinture-01 | Mur-149 | 1-Projet | Ch 1/pl | B26 | Etage 2 | 5 | ArchiCADProperties - Zones conflictuelles: Ch 1/pl
Mur-149 | Etage 2 | 0 | 0 | 2512.25 | 2512.25 | 0 | 0 | 0.111659 | 0 | 0 | 634.94 | 1.68306 | 1.5072 | 0 | 669.941 | 669.941 | 1.68306 | 599.94 | 1.5072 | 0.111659 | 1.68306 | 1.5072 | 669.941 | 599.94 | 0 | 0.0444459 | 2512.25 | 0.111659 | 8500 | 669.941 | 0.111659 | 1438.88 | 11012.3 | 2512.25 | 8500 | 0 | 0.513449 | Face intérieure | Surface-Blanche | Mur-149 | 1-Projet | Ch 1/pl | B23 | Etage 2 | 5
Mur-149 | Etage 2 | 1 | 0 | 2512.25 | 2512.25 | 3.10624 | 1553.12 | 0.0618453 | 3.10619 | 3.10619 | 1588.12 | 0.971434 | 0.795576 | 0.217434 | 1623.12 | 70.0224 | 0.971434 | 0.022822 | 0.795576 | 0.279279 | 4.07763 | 3.90177 | 1623.12 | 1553.12 | 0 | 0.00245 | 2512.25 | 0.0618453 | 8500 | 1623.1 | 0.279279 | 3345.23 | 11012.3 | 2512.25 | 8500 | 0 | 0.398175 | Face intérieure | Surface-Blanche | Mur-149 | 1-Projet | Ch 1/pl | B23 | Etage 2 | 5 | ArchiCADProperties - Zones conflictuelles: Ch 1/pl
Mur-149 | Etage 2 | 1 | 0 | 2500 | 2500 | 3.13708 | 1568.54 | 0.0610291 | 3.13708 | 3.13708 | 1603.57 | 0.959418 | 0.78427 | 0.219596 | 1908.6 | 70.0592 | 0.959418 | 0 | 0.78427 | 0.280625 | 4.0965 | 3.92135 | 1638.6 | 1568.54 | 0 | 0.00245207 | 2500 | 0.0610291 | 8500 | 1638.6 | 0.280625 | 3376.18 | 11000 | 2500 | 8500 | 0 | 0.397294 | Face intérieure | Surface-Blanche | Mur-149 | 1-Projet | Ch 1/pl | B25 | Etage 2 | 5 | ArchiCADProperties - Zones conflictuelles: Ch 1/pl
Mur-149 | Etage 2 | 0 | 0 | 2700 | 2700 | 0 | 0 | 0.120068 | 0 | 0 | 635.278 | 1.80975 | 1.62075 | 0 | 670.278 | 670.278 | 1.80975 | 600.278 | 1.62075 | 0.120068 | 1.80975 | 1.62075 | 670.278 | 600.278 | 0 | 0.0444694 | 2700 | 0.120068 | 8500 | 670.278 | 0.120068 | 1439.55 | 11200 | 2700 | 8500 | 0 | 0.545225 | Face intérieure | Peinture-01 | Mur-149 | 1-Projet | Sejour cuisine | B24 | Etage 2 | 5
Mur-149 | Etage 2 | 1 | 0 | 2800 | 2800 | 1.6932 | 830 | 0.259597 | 1.8928 | 1.8928 | 2000.47 | 3.61052 | 3.61052 | 0.132496 | 1965.47 | 1125.47 | 5.50332 | 1055.47 | 5.50332 | 0.392093 | 5.69932 | 5.50332 | 2035.47 | 1965.47 | 0 | 0.076333 | 2800 | 0.259597 | 8500 | 2035.47 | 0.392093 | 4169.94 | 11300 | 2800 | 8500 | 0 | 0.689552 | Face intérieure | Surface-Blanche | Mur-149 | 1-Projet | Ch 1 | B21 | Etage 2 | 5
Mur-153 | Etage 2 | 0 | 0 | 3000 | 3000 | 0 | 0 | 0.0598081 | 0 | 0 | 284.801 | 0.95937 | 0.749433 | 0 | 429.811 | 319.79 | 0.95937 | 249.811 | 0.749433 | 0.0598081 | 0.95937 | 0.749433 | 319.79 | 249.811 | 0 | 0.019936 | 3000 | 0.0598081 | 8500 | 319.811 | 0.0598081 | 738.596 | 11500 | 3000 | 8500 | 0 | 0.546857 | Face extérieure | Peinture-01 | Mur-153 | 1-Projet | Sejour cuisine | A23 | Etage 2 | 5
Mur-149 | Etage 2 | 0 | 0 | 3000 | 0 | 0 | 0 | 0.598428 | 0 | 0 | 2908.12 | 8.35997 | 8.54897 | 0 | 2908.12 | 2908.12 | 8.35997 | 2908.12 | 8.54897 | 0.598428 | 8.54937 | 8.54937 | 2908.12 | 2908.12 | 0 | 0.203569 | 3000 | 0.598428 | 8500 | 2908.12 | 0.598456 | 5956.24 | 11500 | 3000 | 8500 | 0 | 0.633237 | Face intérieure | Surface-Blanche | Mur-149 | 1-Projet | Ch 3 | B24 | Etage 2 | 5
Mur-152 | Etage 2 | 0 | 0 | 3000 | 3000 | 0 | 0 | 0.0567197 | 0 | 0 | 270.094 | 0.810282 | 0.810281 | 0 | 340.086 | 270.094 | 0.810282 | 270.094 | 0.810281 | 0.0567197 | 0.810282 | 0.810281 | 270.094 | 270.094 | 0 | 0.0189066 | 3000 | 0.0567197 | 8500 | 270.094 | 0.0567197 | 680.188 | 11500 | 3000 | 8500 | -1.77636e-12 | 0.457813 | Face extérieure | Peinture-01 | Mur-152 | 1-Projet | Sejour cuisine | A23 | Etage 2 | 5
Mur-149 | Etage 2 | 0 | 0 | 3000 | 2500 | 0 | 0 | 0.244398 | 0 | 0 | 1163.93 | 3.3024 | 3.4914 | 0 | 1503.93 | 1163.93 | 3.3024 | 1163.93 | 3.4914 | 0.244398 | 3.4918 | 3.4918 | 1163.93 | 1163.93 | 0 | 0.0814752 | 3000 | 0.244398 | 8500 | 1163.93 | 0.244426 | 2467.86 | 11500 | 3000 | 8500 | 0 | 0.56895 | Face intérieure | Surface-Blanche | Mur-149 | 1-Projet | Ch 3 | B24 | Etage 2 | 5
Mur-121 | Etage 2 | 0 | 0 | 3000 | 3000 | 0 | 0 | 0.1071 | 0 | 0 | 509.992 | 0.989978 | 0.989972 | 0 | 579.993 | 509.993 | 0.989978 | 509.991 | 0.989972 | 0.1071 | 1.52998 | 1.52997 | 509.993 | 509.991 | 0 | 0.0357 | 3000 | 0.1071 | 8500 | 509.993 | 0.1071 | 1159.98 | 11500 | 3000 | 8500 | 0 | 0.491407 | Face extérieure | Lavis blanc | Mur-121 | 1-Projet | Sejour cuisine | B23 | Etage 2 | 5
Mur-121 | Etage 2 | 0 | 0 | 3000 | 3000 | 0 | 0 | 0.117519 | 0 | 0 | 553.613 | 1.45084 | 1.69684 | 0 | 553.614 | 553.612 | 1.45084 | 553.614 | 1.69684 | 0.117519 | 1.66084 | 1.69684 | 553.612 | 553.614 | 0 | 0.045053 | 3000 | 0.117519 | 8500 | 733.614 | 0.117519 | 1247.23 | 11500 | 3000 | 8500 | 0 | 0.534733 | Face extérieure | Lavis blanc | Mur-121 | 1-Projet | Sejour cuisine | B23 | Etage 2 | 5
Mur-149 | Etage 3 | 0 | 0 | 3000 | 3000 | 0 | 0 | 0.13335 | 0 | 0 | 635.001 | 2.01 | 1.8 | 0 | 670 | 670.001 | 2.01 | 600.001 | 1.8 | 0.13335 | 2.01 | 1.8 | 670.001 | 600.001 | 0 | 0.04445 | 3000 | 0.13335 | 11550 | 670 | 0.13335 | 1439 | 14550 | 3000 | 11550 | 0 | 0.595885 | Face intérieure | Surface-Blanche | Mur-149 | 1-Projet | Ch 2 | B32 | Etage 3 | 6
Mur-148 | Etage 3 | 0 | 0 | 3000 | 3000 | 0 | 0 | 0.133239 | 0 | 0 | 634.469 | 1.79848 | 1.58833 | 0 | 669.494 | 669.494 | 1.79848 | 599.445 | 1.58833 | 0.133239 | 2.00848 | 1.79833 | 669.494 | 599.445 | 0 | 0.0444129 | 3000 | 0.133239 | 11550 | 669.494 | 0.133239 | 1437.97 | 14550 | 3000 | 11550 | 0 | 0.595914 | Face intérieure | Surface-Blanche | Mur-148 | 1-Projet | Ch 3 | A31 | Etage 3 | 6
Mur-121 | Etage 3 | 0 | 0 | 3000 | 0 | 0 | 0 | 0.0742906 | 0 | 0 | 400.098 | 1.06129 | 1.06129 | 0 | 580.098 | 400.098 | 1.06129 | 400.098 | 1.06129 | 0.0742906 | 1.06129 | 1.06129 | 400.098 | 400.098 | 0 | 0.0406069 | 3000 | 0.0742906 | 11550 | 580.098 | 0.0742906 | 940.196 | 14550 | 3000 | 11550 | 0 | 0.496314 | Face extérieure | Lavis blanc | Mur-121 | 1-Projet |  |  | Etage 3 | 6
Mur-120 | Etage 3 | 7 | 0 | 2500 | 0 | 7.2216 | 3540 | 0.304822 | 7.544 | 7.544 | 4829.44 | 3.4796 | 3.4796 | 0.52808 | 5009.44 | 1919.44 | 8.4816 | 1919.44 | 8.4816 | 0.832902 | 11.8986 | 11.8986 | 4829.44 | 4829.44 | 0 | 0.0755608 | 2500 | 0.304822 | 11550 | 4759.44 | 0.832902 | 9798.88 | 14050 | 2500 | 11550 | 0 | 0.758722 | Face extérieure | Peinture-01 | Mur-120 | 3D |  |  | Etage 3 | 6
Mur-152 | Etage 3 | 0 | 0 | 3000 | 2300 | 0 | 0 | 0.0349542 | 0 | 0 | 176.191 | 0.499355 | 0.499336 | 0 | 246.191 | 176.191 | 0.499355 | 176.191 | 0.499336 | 0.0349542 | 0.528595 | 0.528574 | 176.191 | 176.191 | 0 | 0.0123336 | 3000 | 0.0349542 | 11550 | 176.198 | 0.0370009 | 492.383 | 14550 | 3000 | 11550 | 0 | 0.430667 | Face extérieure | Peinture-01 | Mur-152 | 1-Projet |  |  | Etage 3 | 6
Mur-153 | Etage 3 | 0 | 0 | 3000 | 3000 | 0 | 0 | 0.290882 | 0 | 0 | 1385.15 | 3.84048 | 4.26044 | 0 | 1600.15 | 1350.16 | 3.84048 | 1420.15 | 4.26044 | 0.290882 | 4.05048 | 4.26044 | 1350.16 | 1420.15 | 0 | 0.0969607 | 3000 | 0.290882 | 11550 | 1420.15 | 0.290882 | 2939.29 | 14550 | 3000 | 11550 | 0 | 0.700879 | Face extérieure | Peinture-01 | Mur-153 | 1-Projet | Sejour cuisine/pl | A34 | Etage 3 | 6
Mur-156 | Etage 3 | 2 | 0 | 3000 | 3000 | 3.3864 | 1660 | 0.161361 | 3.7856 | 3.7856 | 2030.25 | 2.09515 | 2.09515 | 0.264992 | 2030.25 | 210.251 | 5.88075 | 210.251 | 5.88075 | 0.426353 | 6.09075 | 6.09075 | 2030.25 | 2030.25 | 0 | 0.0147176 | 3000 | 0.161361 | 11550 | 2030.25 | 0.426353 | 4200.5 | 14550 | 3000 | 11550 | 0 | 0.576835 | Face intérieure | Peinture-01 | Mur-156 | 1-Projet | Ch 1 | A33 | Etage 3 | 6
Mur-121 | Etage 3 | 0 | 0 | 3000 | 0 | 0 | 0 | 0.074285 | 0 | 0 | 400.072 | 1.06121 | 1.06121 | 0 | 580.072 | 400.072 | 1.06121 | 400.072 | 1.06121 | 0.074285 | 1.06121 | 1.06121 | 400.072 | 400.072 | 0 | 0.040605 | 3000 | 0.074285 | 11550 | 580.072 | 0.074285 | 940.143 | 14550 | 3000 | 11550 | 0 | 0.49631 | Face extérieure | Lavis blanc | Mur-121 | 1-Projet |  |  | Etage 3 | 6
Mur-149 | Etage 3 | 0 | 0 | 3000 | 0 | 0 | 0 | 0.319102 | 0 | 0 | 1520 | 4.5586 | 4.36261 | 0 | 1520 | 1520 | 4.5586 | 1520 | 4.36261 | 0.319102 | 4.5586 | 4.55861 | 1520 | 1520 | 0 | 0.1064 | 3000 | 0.319102 | 11550 | 1520 | 0.319102 | 3180 | 14550 | 3000 | 11550 | 0 | 0.436765 | Face extérieure | Lavis blanc | Mur-149 | 1-Projet | Wc 1 | B34 | Etage 3 | 6
Mur-153 | Etage 3 | 1 | 0 | 3000 | 3000 | 2.07643 | 1038.21 | 0.143088 | 2.00572 | 2.00572 | 1349.95 | 1.93913 | 2.1491 | 0.140401 | 1384.94 | 312.088 | 1.93913 | 382.081 | 2.1491 | 0.283489 | 3.94485 | 4.15483 | 1314.95 | 1384.94 | 0 | 0.0242959 | 3000 | 0.143088 | 11550 | 1384.94 | 0.283489 | 2868.88 | 14550 | 3000 | 11550 | 0 | 0.48576 | Face extérieure | Peinture-01 | Mur-153 | 1-Projet | Sejour cuisine/pl | A34 | Etage 3 | 6
Mur-121 | Etage 3 | 0 | 0 | 3000 | 3000 | 0 | 0 | 0.0865309 | 0 | 0 | 400.052 | 1.06116 | 1.06116 | 0 | 580.052 | 400.052 | 1.06116 | 400.052 | 1.06116 | 0.0865309 | 1.23616 | 1.23616 | 400.052 | 400.052 | 0 | 0.0406037 | 3000 | 0.0865309 | 11550 | 580.052 | 0.0865309 | 940.104 | 14550 | 3000 | 11550 | 0 | 0.501207 | Face extérieure | Lavis blanc | Mur-121 | 1-Projet |  |  | Etage 3 | 6
Mur-149 | Etage 3 | 0 | 0 | 3000 | 3000 | 0 | 0 | 0.406458 | 0 | 0 | 1935.51 | 5.91154 | 5.70154 | 0 | 1970.51 | 1970.51 | 5.91154 | 1900.51 | 5.70154 | 0.406458 | 5.91154 | 5.70154 | 1970.51 | 1900.51 | 0 | 0.135486 | 3000 | 0.406458 | 11550 | 1970.51 | 0.406458 | 4040.02 | 14550 | 3000 | 11550 | 0 | 0.777957 | Face intérieure | Surface-Blanche | Mur-149 | 1-Projet | Ch 2 | B33 | Etage 3 | 6
Mur-149 | Etage 3 | 0 | 1 | 3000 | 3000 | 0 | 0 | 0.399587 | 2.26017 | 2.26017 | 2651.52 | 5.49839 | 5.51239 | 0.158212 | 2721.52 | 1543.59 | 5.49839 | 1543.59 | 5.51239 | 0.557799 | 7.96856 | 7.96856 | 2651.52 | 2651.52 | 2.26017 | 0.112952 | 3000 | 0.399587 | 11550 | 2721.52 | 0.557799 | 5443.04 | 14550 | 3000 | 11550 | 0 | 0.580658 | Face intérieure | Surface-Blanche | Mur-149 | 1-Projet | Wc | B33 | Etage 3 | 6
Mur-149 | Etage 3 | 0 | 0 | 2800 | 2800 | 0 | 0 | 0.166918 | 0 | 0 | 851.622 | 2.28654 | 2.48254 | 0 | 886.622 | 816.622 | 2.28654 | 886.622 | 2.48254 | 0.166918 | 2.28654 | 2.48254 | 816.622 | 886.622 | 0 | 0.0596136 | 2800 | 0.166918 | 11550 | 886.622 | 0.166918 | 1872.22 | 14350 | 2800 | 11550 | 0 | 0.592344 | Face extérieure | Lavis blanc | Mur-149 | 1-Projet | cellier | B34 | Etage 3 | 6
Mur-149 | Etage 3 | 0 | 0 | 3000 | 3000 | 0 | 0 | 0.167697 | 0 | 0 | 796.223 | 2.29771 | 2.49362 | 0 | 831.205 | 761.24 | 2.29771 | 831.205 | 2.49362 | 0.167697 | 2.29771 | 2.49362 | 761.24 | 831.205 | 0 | 0.0581844 | 3000 | 0.167697 | 11550 | 831.205 | 0.167697 | 1761.42 | 14550 | 3000 | 11550 | 0 | 0.617486 | Face extérieure | Lavis blanc | Mur-149 | 1-Projet | cellier | B34 | Etage 3 | 6
Mur-149 | Etage 3 | 1 | 0 | 720 | 720 | 1.6932 | 830 | 0.0427458 | 1.76412 | 1.76412 | 848.134 | 0.610655 | 0.610655 | 0.123488 | 1028.13 | 1.13687e-10 | 2.37477 | 1.13687e-10 | 2.37478 | 0.166234 | 2.37477 | 2.37478 | 848.133 | 848.135 | 0 | 0 | 2800 | 0.0427458 | 11550 | 848.135 | 0.166234 | 1836.27 | 14350 | 2800 | 13630 | 2080 | 0.160169 | Face extérieure | Lavis blanc | Mur-149 | 1-Projet | Dgt/pl | B34 | Etage 3 | 6
Mur-149 | Etage 3 | 0 | 0 | 3000 | 0 | 0 | 0 | 0.703986 | 0 | 0 | 3417.65 | 10.0569 | 10.0569 | 0 | 3757.65 | 3417.65 | 10.0569 | 3417.65 | 10.0569 | 0.703986 | 10.0569 | 10.0569 | 3417.65 | 3417.65 | 0 | 0.239235 | 3000 | 0.703986 | 11550 | 3417.65 | 0.703986 | 6975.29 | 14550 | 3000 | 11550 | 0 | 0.89357 | Face extérieure | Lavis blanc | Mur-149 | 1-Projet | Dgt/pl | B34 | Etage 3 | 6
Mur-149 | Etage 3 | 0 | 0 | 3000 | 3000 | 0 | 0 | 0.462136 | 0 | 0 | 2200.65 | 6.60194 | 6.39194 | 0 | 2380.65 | 2200.65 | 6.60194 | 2200.65 | 6.39194 | 0.462136 | 6.60194 | 6.60194 | 2200.65 | 2200.65 | 0 | 0.154045 | 3000 | 0.462136 | 11550 | 2200.65 | 0.462136 | 4541.3 | 14550 | 3000 | 11550 | 0 | 0.728091 | Face extérieure | Lavis blanc | Mur-149 | 1-Projet | Sdb | B34 | Etage 3 | 6
2 x Mur-121 | Etage 3 | 0 | 0 | 3000 | 0 | 0 | 0 | 0.0742809 | 0 | 0 | 400.052 | 1.06116 | 1.06116 | 0 | 580.052 | 400.052 | 1.06116 | 400.052 | 1.06116 | 0.0742809 | 1.06116 | 1.06116 | 400.052 | 400.052 | 0 | 0.0406037 | 3000 | 0.0742809 | 11550 | 580.052 | 0.0742809 | 940.104 | 14550 | 3000 | 11550 | 0 | 0.496307 | Face extérieure | Lavis blanc | Mur-121 | 1-Projet |  |  | Etage 3 | 6
Mur-150 | Etage 3 | 0 | 0 | 3000 | 3000 | 0 | 0 | 0.126119 | 0 | 0 | 600.565 | 1.90669 | 1.69669 | 0 | 815.566 | 635.565 | 1.90669 | 565.564 | 1.69669 | 0.126119 | 1.90669 | 1.69669 | 635.565 | 565.564 | 0 | 0.0420395 | 3000 | 0.126119 | 11550 | 635.565 | 0.126119 | 1369.94 | 14550 | 3000 | 11550 | 0 | 0.590522 | Face intérieure | Surface-Blanche | Mur-150 | 1-Projet |  |  | Etage 3 | 6
Mur-153 | Etage 3 | 1 | 0 | 3000 | 3000 | 3.40014 | 1700.07 | 0.220544 | 3.32183 | 3.32183 | 2157.43 | 3.15047 | 2.94046 | 0.232537 | 2227.44 | 496.519 | 3.15047 | 496.513 | 2.94046 | 0.453081 | 6.47231 | 6.47229 | 2157.44 | 2157.43 | 0 | 0.0347576 | 3000 | 0.220544 | 11550 | 2157.44 | 0.453081 | 4454.86 | 14550 | 3000 | 11550 | 0 | 0.465803 | Face extérieure | Peinture-01 | Mur-153 | 1-Projet | Sejour cuisine/pl | A31 | Etage 3 | 6
Mur-149 | Etage 3 | 0 | 0 | 3000 | 3000 | 0 | 0 | 0.379962 | 0 | 0 | 1795 | 5.526 | 4.826 | 0 | 2010 | 1830 | 5.526 | 1760 | 4.826 | 0.379962 | 5.526 | 5.33 | 1830 | 1760 | 0 | 0.140701 | 3000 | 0.379962 | 11550 | 2010 | 0.379962 | 3759 | 14550 | 3000 | 11550 | 0 | 0.78259 | Face intérieure | Surface-Blanche | Mur-149 | 1-Projet | Cellier | B33 | Etage 3 | 6
Mur-153 | Etage 3 | 0 | 0 | 3000 | 3000 | 0 | 0 | 0.141113 | 0 | 0 | 671.966 | 2.01592 | 2.01588 | 0 | 741.959 | 671.973 | 2.01592 | 671.959 | 2.01588 | 0.141113 | 2.01592 | 2.01588 | 671.973 | 671.959 | 0 | 0.0470376 | 3000 | 0.141113 | 11550 | 671.973 | 0.141113 | 1483.93 | 14550 | 3000 | 11550 | 0 | 0.514075 | Face extérieure | Peinture-01 | Mur-153 | 1-Projet | Sejour cuisine/pl | A34 | Etage 3 | 6
Mur-153 | Etage 3 | 1 | 0 | 3000 | 3000 | 1.6932 | 830 | 0.524541 | 1.8928 | 1.8928 | 3128.75 | 7.49344 | 7.31845 | 0.132496 | 3468.75 | 2218.75 | 9.38624 | 2218.75 | 9.21125 | 0.657037 | 9.38624 | 9.38625 | 3128.75 | 3128.75 | 0 | 0.155312 | 3000 | 0.524541 | 11550 | 3128.75 | 0.657037 | 6397.5 | 14550 | 3000 | 11550 | -1.77636e-12 | 0.794325 | Face extérieure | Peinture-01 | Mur-153 | 1-Projet | Ch 1 | A34 | Etage 3 | 6
Mur-153 | Etage 3 | 0 | 0 | 3000 | 3000 | 0 | 0 | 0.123899 | 0 | 0 | 589.996 | 1.76999 | 1.76999 | 0 | 729.996 | 589.996 | 1.76999 | 589.996 | 1.76999 | 0.123899 | 1.76999 | 1.76999 | 589.996 | 589.996 | 0 | 0.0412997 | 3000 | 0.123899 | 11550 | 590.04 | 0.123899 | 1319.99 | 14550 | 3000 | 11550 | 0 | 0.5026 | Face extérieure | Peinture-01 | Mur-153 | 1-Projet | Sejour cuisine/pl | A34 | Etage 3 | 6
Mur-153 | Etage 3 | 0 | 0 | 3000 | 3000 | 0 | 0 | 0.572214 | 0 | 0 | 2713.16 | 7.42449 | 7.63449 | 0 | 2783.16 | 2713.16 | 7.42449 | 2713.16 | 7.63449 | 0.572214 | 8.17449 | 8.17449 | 2713.16 | 2713.16 | 0 | 0.194821 | 3000 | 0.572214 | 11550 | 2783.16 | 0.572214 | 5566.33 | 14550 | 3000 | 11550 | 0 | 0.809643 | Face extérieure | Peinture-01 | Mur-153 | 1-Projet | Sde/pl | A34 | Etage 3 | 6
Mur-153 | Etage 3 | 1 | 0 | 3000 | 3000 | 1.0812 | 530 | 0.226686 | 1.21723 | 1.21723 | 1485.2 | 3.02837 | 3.23837 | 0.0852064 | 1665.2 | 899.991 | 4.2456 | 899.994 | 4.45561 | 0.311892 | 4.4556 | 4.45561 | 1485.2 | 1485.2 | 0 | 0.0629995 | 3000 | 0.226686 | 11550 | 1485.2 | 0.311892 | 3110.4 | 14550 | 3000 | 11550 | 0 | 0.441364 | Face extérieure | Peinture-01 | Mur-153 | 1-Projet | Sde/pl | A34 | Etage 3 | 6
Mur-153 | Etage 3 | 0 | 0 | 3000 | 3000 | 0 | 0 | 0.0525022 | 0 | 0 | 250.01 | 0.750063 | 0.75 | 0 | 430 | 250.021 | 0.750063 | 250 | 0.75 | 0.0525022 | 0.750063 | 0.75 | 250.021 | 250 | 0 | 0.0175007 | 3000 | 0.0525022 | 11550 | 250.021 | 0.0525022 | 640.021 | 14550 | 3000 | 11550 | 0 | 0.455001 | Face extérieure | Peinture-01 | Mur-153 | 1-Projet | Sejour cuisine | A32 | Etage 3 | 6
Mur-153 | Etage 3 | 1 | 0 | 3000 | 3000 | 1.1832 | 580 | 0.068173 | 1.23 | 1.23 | 734.633 | 1.0789 | 0.6589 | 0.0861 | 699.633 | 169.633 | 2.3089 | 99.6332 | 1.8889 | 0.154273 | 2.3089 | 2.0989 | 769.633 | 699.633 | 0 | 0.00942433 | 3000 | 0.068173 | 11550 | 769.633 | 0.154273 | 1638.26 | 14550 | 3000 | 11550 | 0 | 0.567834 | Face extérieure | Peinture-01 | Mur-153 | 1-Projet | Sejour cuisine | A32 | Etage 3 | 6
Mur-148 | Etage 3 | 0 | 0 | 3000 | 3000 | 0 | 0 | 0.0863788 | 0 | 0 | 411.328 | 1.44478 | 1.02319 | 0 | 481.592 | 481.592 | 1.44478 | 341.064 | 1.02319 | 0.0863788 | 1.44478 | 1.02319 | 481.592 | 341.064 | 0 | 0.0287929 | 3000 | 0.0863788 | 11550 | 481.592 | 0.0863788 | 1021.02 | 14550 | 3000 | 11550 | 0 | 0.652678 | Face intérieure | Surface-Blanche | Mur-148 | 1-Projet | Sejour cuisine/pl | A31 | Etage 3 | 6
Mur-148 | Etage 3 | 0 | 0 | 3000 | 3000 | 0 | 0 | 0.133127 | 0 | 0 | 633.937 | 1.79753 | 1.79609 | 0 | 669.177 | 669.177 | 1.79753 | 598.697 | 1.79609 | 0.133127 | 2.00753 | 1.79609 | 669.177 | 598.697 | 0 | 0.0443756 | 3000 | 0.133127 | 11550 | 669.177 | 0.133127 | 1437.21 | 14550 | 3000 | 11550 | 0 | 0.596755 | Face intérieure | Surface-Blanche | Mur-148 | 1-Projet | Sejour cuisine/pl | A31 | Etage 3 | 6
Mur-149 | Etage 3 | 0 | 0 | 3000 | 3000 | 0 | 0 | 0.125997 | 0 | 0 | 599.99 | 1.79996 | 1.79996 | 0 | 599.987 | 599.99 | 1.79996 | 599.99 | 1.79996 | 0.125997 | 1.79996 | 1.79996 | 599.99 | 599.99 | 0 | 0.0419991 | 3000 | 0.125997 | 11550 | 599.987 | 0.125997 | 1339.98 | 14550 | 3000 | 11550 | 0 | 0.503998 | Face intérieure | Surface-Blanche | Mur-149 | 1-Projet | Ch 1/pl | B31 | Etage 3 | 6
Mur-149 | Etage 3 | 0 | 0 | 2800 | 0 | 0 | 0 | 0.0661692 | 0 | 0 | 400.098 | 0.945275 | 0.945274 | 0 | 580.098 | 400.098 | 0.945275 | 400.098 | 0.945274 | 0.0661692 | 0.945275 | 0.945274 | 400.098 | 400.098 | 0 | 0.0280069 | 2800 | 0.0661692 | 11550 | 400.098 | 0.0661692 | 940.196 | 14350 | 2800 | 11550 | 0 | 0.443114 | Face intérieure | Surface-Blanche | Mur-149 | 1-Projet |  |  | Etage 3 | 6
Mur-149 | Etage 3 | 1 | 0 | 2700 | 2700 | 1.78669 | 893.343 | 0.0937888 | 1.70669 | 1.70669 | 1128.34 | 1.43434 | 1.05634 | 0.119468 | 1163.34 | 310 | 3.14103 | 240 | 2.76303 | 0.213257 | 3.14103 | 2.95203 | 1163.34 | 1093.34 | 0 | 0.01925 | 2700 | 0.0937888 | 11550 | 1163.34 | 0.213257 | 2425.68 | 14250 | 2700 | 11550 | 0 | 0.41452 | Face intérieure | Peinture-01 | Mur-149 | 1-Projet | Entree/pl | B35 | Etage 3 | 6
Mur-149 | Etage 3 | 0 | 0 | 3000 | 3000 | 0 | 0 | 0.32438 | 0 | 0 | 1540 | 4.13 | 4.13 | 0 | 1610 | 1540 | 4.13 | 1540 | 4.13 | 0.32438 | 4.634 | 4.634 | 1540 | 1540 | 0 | 0.1127 | 3000 | 0.32438 | 11550 | 1610 | 0.32438 | 3220 | 14550 | 3000 | 11550 | 0 | 0.6454 | Face intérieure | Surface-Blanche | Mur-149 | 1-Projet | Cellier | B33 | Etage 3 | 6
Mur-152 | Etage 3 | 0 | 0 | 3000 | 2300 | 0 | 0 | 0.0349542 | 0 | 0 | 176.191 | 0.499355 | 0.499336 | 0 | 246.191 | 176.191 | 0.499355 | 176.191 | 0.499336 | 0.0349542 | 0.528595 | 0.528574 | 176.191 | 176.191 | 0 | 0.0123336 | 3000 | 0.0349542 | 11550 | 176.198 | 0.0370009 | 492.383 | 14550 | 3000 | 11550 | -1.77636e-12 | 0.430667 | Face extérieure | Peinture-01 | Mur-152 | 1-Projet |  |  | Etage 3 | 6
Mur-149 | Etage 3 | 1 | 0 | 3000 | 3000 | 1.1832 | 580 | 0.141085 | 1.23 | 1.23 | 1081.83 | 1.8055 | 2.01549 | 0.0861 | 1151.83 | 481.832 | 3.0355 | 481.831 | 3.24549 | 0.227185 | 3.2455 | 3.24549 | 1081.83 | 1081.83 | 0 | 0.0337282 | 3000 | 0.141085 | 11550 | 1151.83 | 0.227185 | 2361.65 | 14550 | 3000 | 11550 | 0 | 0.703424 | Face extérieure | Lavis blanc | Mur-149 | 1-Projet | Sdb | B34 | Etage 3 | 6
Mur-152 | Etage 3 | 0 | 0 | 3000 | 3000 | 0 | 0 | 0.29712 | 0 | 0 | 1414.86 | 2.86457 | 4.03457 | 0 | 1414.86 | 1414.86 | 2.86457 | 1414.86 | 4.03457 | 0.29712 | 4.24457 | 4.24457 | 1414.86 | 1414.86 | 0 | 0.0990401 | 3000 | 0.29712 | 11550 | 1414.86 | 0.29712 | 2969.72 | 14550 | 3000 | 11550 | 0 | 0.61808 | Face extérieure | Peinture-01 | Mur-152 | 1-Projet | Ch 1 | A32 | Etage 3 | 6 | ArchiCADProperties - Zones conflictuelles: Sejour cuisine
Mur-156 | Etage 3 | 0 | 0 | 3000 | 3000 | 0 | 0 | 0.155524 | 0 | 0 | 740.591 | 1.80177 | 1.80177 | 0 | 740.591 | 740.591 | 1.80177 | 740.591 | 1.80177 | 0.155524 | 2.22177 | 2.22177 | 740.591 | 740.591 | 0 | 0.0518414 | 3000 | 0.155524 | 11550 | 740.591 | 0.155524 | 1621.18 | 14550 | 3000 | 11550 | 0 | 0.523683 | Face intérieure | Peinture-01 | Mur-156 | 1-Projet | Sde | A33 | Etage 3 | 6 | ArchiCADProperties - Zones conflictuelles: Sde
Mur-153 | Etage 3 | 1 | 0 | 2500 | 2500 | 1.6932 | 830 | 0.565595 | 1.8928 | 1.8928 | 3989.09 | 7.90494 | 8.07993 | 0.132496 | 4329.09 | 3079.1 | 9.79774 | 3079.09 | 9.97273 | 0.698091 | 9.97274 | 9.97273 | 3989.1 | 3989.09 | 0 | 0.215537 | 2500 | 0.565595 | 11550 | 3989.1 | 0.698091 | 8118.19 | 14050 | 2500 | 11550 | 0 | 0.844773 | Face extérieure | Peinture-01 | Mur-153 | 1-Projet | Ch 1 | A34 | Etage 3 | 6
Mur-149 | Etage 3 | 0 | 0 | 3000 | 3000 | 0 | 0 | 0.0841808 | 0 | 0 | 400.861 | 1.20263 | 0.992534 | 0 | 400.88 | 400.878 | 1.20263 | 400.845 | 0.992534 | 0.0841808 | 1.20263 | 1.20253 | 400.878 | 400.845 | 0 | 0.0280603 | 3000 | 0.0841808 | 11550 | 400.878 | 0.0841808 | 941.722 | 14550 | 3000 | 11550 | 0 | 0.476121 | Face intérieure | Surface-Blanche | Mur-149 | 1-Projet | Sde | A32 | Etage 3 | 6
Mur-149 | Etage 3 | 0 | 0 | 3000 | 3000 | 0 | 0 | 0.140333 | 0 | 0 | 668.251 | 1.89975 | 2.10975 | 0 | 703.251 | 633.251 | 1.89975 | 703.251 | 2.10975 | 0.140333 | 1.89975 | 2.10975 | 633.251 | 703.251 | 0 | 0.0467776 | 3000 | 0.140333 | 11550 | 703.251 | 0.140333 | 1505.5 | 14550 | 3000 | 11550 | 0 | 0.60054 | Face intérieure | Surface-Blanche | Mur-149 | 1-Projet | Sejour cuisine | B33 | Etage 3 | 6
Mur-149 | Etage 3 | 0 | 0 | 3000 | 3000 | 0 | 0 | 0.0599527 | 0 | 0 | 285.489 | 0.961516 | 0.751417 | 0 | 390.511 | 320.505 | 0.961516 | 250.472 | 0.751417 | 0.0599527 | 0.961516 | 0.751417 | 320.505 | 250.472 | 0 | 0.0199842 | 3000 | 0.0599527 | 11550 | 320.505 | 0.0599527 | 739.996 | 14550 | 3000 | 11550 | 0 | 0.547023 | Face intérieure | Surface-Blanche | Mur-149 | 1-Projet | Sde | B33 | Etage 3 | 6
Mur-153 | Etage 3 | 0 | 0 | 3000 | 3000 | 0 | 0 | 0.0834595 | 0 | 0 | 397.426 | 1.29728 | 1.08728 | 0 | 362.426 | 432.426 | 1.29728 | 362.426 | 1.08728 | 0.0834595 | 1.29728 | 1.08728 | 432.426 | 362.426 | 0 | 0.0278198 | 3000 | 0.0834595 | 11550 | 432.426 | 0.0834595 | 963.848 | 14550 | 3000 | 11550 | 0 | 0.562625 | Face extérieure | Peinture-01 | Mur-153 | 1-Projet | Dressing | A34 | Etage 3 | 6
Mur-153 | Etage 3 | 0 | 0 | 3000 | 3000 | 0 | 0 | 0.0834595 | 0 | 0 | 397.426 | 1.08728 | 1.29728 | 0 | 362.426 | 362.426 | 1.08728 | 432.426 | 1.29728 | 0.0834595 | 1.08728 | 1.29728 | 362.426 | 432.426 | 0 | 0.0278198 | 3000 | 0.0834595 | 11550 | 432.426 | 0.0834595 | 963.848 | 14550 | 3000 | 11550 | 0 | 0.562625 | Face extérieure | Peinture-01 | Mur-153 | 1-Projet | Dressing | A34 | Etage 3 | 6
Mur-150 | Etage 3 | 0 | 0 | 3000 | 3000 | 0 | 0 | 0.0567067 | 0 | 0 | 270.032 | 0.915096 | 0.705096 | 0 | 375.032 | 305.032 | 0.915096 | 235.032 | 0.705096 | 0.0567067 | 0.915096 | 0.705096 | 305.032 | 235.032 | 0 | 0.0189022 | 3000 | 0.0567067 | 11550 | 305.032 | 0.0567067 | 709.059 | 14550 | 3000 | 11550 | 0 | 0.544789 | Face intérieure | Surface-Blanche | Mur-150 | 1-Projet | Sde | B32 | Etage 3 | 6
Mur-121 | Etage 3 | 1 | 0 | 3000 | 3000 | 1.6932 | 830 | 0.195419 | 1.8928 | 1.8928 | 1561.5 | 2.68673 | 2.89668 | 0.132496 | 1596.49 | 616.51 | 4.57953 | 686.492 | 4.78948 | 0.327915 | 4.57953 | 4.78948 | 1526.51 | 1596.49 | 0 | 0.0456051 | 3000 | 0.195419 | 11550 | 1596.49 | 0.327915 | 3291.98 | 14550 | 3000 | 11550 | 0 | 0.661858 | Face extérieure | Lavis blanc | Mur-121 | 1-Projet | Wc | A32 | Etage 3 | 6
Mur-149 | Etage 3 | 1 | 0 | 3000 | 3000 | 1.6932 | 830 | 0.372978 | 1.8928 | 1.8928 | 2403.52 | 5.42275 | 5.02375 | 0.132496 | 2508.52 | 1528.52 | 7.31555 | 1458.52 | 6.91655 | 0.505474 | 7.31555 | 7.12655 | 2438.52 | 2368.52 | 0 | 0.106996 | 3000 | 0.372978 | 11550 | 2438.52 | 0.505474 | 4976.03 | 14550 | 3000 | 11550 | 0 | 0.775979 | Face intérieure | Surface-Blanche | Mur-149 | 1-Projet | Wc | B32 | Etage 3 | 6
Mur-149 | Etage 3 | 0 | 0 | 2500 | 2500 | 0 | 0 | 0.111125 | 0 | 0 | 635 | 1.5 | 1.675 | 0 | 850 | 600 | 1.5 | 670 | 1.675 | 0.111125 | 1.5 | 1.675 | 600 | 670 | 0 | 0.04445 | 2500 | 0.111125 | 11550 | 670 | 0.111125 | 1438.99 | 14050 | 2500 | 11550 | 0 | 0.511387 | Face intérieure | Peinture-01 | Mur-149 | 1-Projet | Sejour cuisine/pl | B35 | Etage 3 | 6
Mur-149 | Etage 3 | 3 | 0 | 2800 | 2800 | 6.99786 | 3465.73 | 0.712751 | 7.39706 | 7.39706 | 6278.29 | 9.0193 | 9.38416 | 0.517794 | 6243.29 | 2617.56 | 12.8049 | 2687.56 | 13.1698 | 1.23055 | 17.4812 | 17.6772 | 6243.29 | 6313.29 | 0 | 0.185679 | 2800 | 0.712751 | 11550 | 6313.29 | 1.23055 | 12725.6 | 14350 | 2800 | 11550 | 0 | 1.09835 | Face intérieure | Surface-Blanche | Mur-149 | 1-Projet | Sde | B33 | Etage 3 | 6 | ArchiCADProperties - Zones conflictuelles: Entree/pl
Mur-149 | Etage 3 | 0 | 0 | 3000 | 3000 | 0 | 0 | 0.39155 | 0 | 0 | 1864.52 | 5.69857 | 5.48857 | 0 | 1969.52 | 1899.52 | 5.69857 | 1829.52 | 5.48857 | 0.39155 | 5.69857 | 5.48857 | 1899.52 | 1829.52 | 0 | 0.130517 | 3000 | 0.39155 | 11550 | 1899.52 | 0.39155 | 3898.04 | 14550 | 3000 | 11550 | 0 | 0.768018 | Face intérieure | Surface-Blanche | Mur-149 | 1-Projet | Ch 2 | B32 | Etage 3 | 6
Mur-149 | Etage 3 | 0 | 0 | 3000 | 3000 | 0 | 0 | 0.144771 | 0 | 0 | 689.385 | 1.85816 | 2.06816 | 0 | 869.385 | 689.385 | 1.85816 | 689.385 | 2.06816 | 0.144771 | 2.06816 | 2.06816 | 689.385 | 689.385 | 0 | 0.048257 | 3000 | 0.144771 | 11550 | 689.385 | 0.144771 | 1518.77 | 14550 | 3000 | 11550 | 0 | 0.516514 | Face intérieure | Surface-Blanche | Mur-149 | 1-Projet | Sejour cuisine/pl | B31 | Etage 3 | 6
Mur-149 | Etage 3 | 0 | 0 | 3000 | 0 | 0 | 0 | 0.124599 | 0 | 0 | 628.555 | 1.88498 | 1.67498 | 0 | 593.555 | 663.555 | 1.88498 | 593.555 | 1.67498 | 0.124599 | 1.88498 | 1.67498 | 663.555 | 593.555 | 0 | 0.0415329 | 3000 | 0.124599 | 11550 | 628.327 | 0.124599 | 1426.11 | 14550 | 3000 | 11550 | 0 | 0.380051 | Face intérieure | Surface-Blanche | Mur-149 | 1-Projet | Sejour cuisine | B33 | Etage 3 | 6
Mur-149 | Etage 3 | 0 | 0 | 3000 | 0 | 0 | 0 | 0.179308 | 0 | 0 | 854.034 | 2.56149 | 2.56159 | 0 | 924.028 | 854.037 | 2.56149 | 854.031 | 2.56159 | 0.179308 | 2.56149 | 2.56159 | 854.037 | 854.031 | 0 | 0.0597692 | 3000 | 0.179308 | 11550 | 853.868 | 0.179308 | 1848.07 | 14550 | 3000 | 11550 | 0 | 0.329538 | Face intérieure | Surface-Blanche | Mur-149 | 1-Projet |  |  | Etage 3 | 6
Mur-149 | Etage 3 | 0 | 0 | 3000 | 3000 | 0 | 0 | 0.449524 | 0 | 0 | 2140.59 | 6.42178 | 6.42178 | 0 | 2390.59 | 2140.59 | 6.42178 | 2140.59 | 6.42178 | 0.449524 | 6.42178 | 6.42178 | 2140.59 | 2140.59 | 0 | 0.149841 | 3000 | 0.449524 | 11550 | 2140.59 | 0.449524 | 4421.19 | 14550 | 3000 | 11550 | 0 | 0.719683 | Face intérieure | Surface-Blanche | Mur-149 | 1-Projet | Sde | B32 | Etage 3 | 6
Mur-149 | Etage 3 | 0 | 0 | 2700 | 2700 | 0 | 0 | 0.1512 | 0 | 0 | 800 | 2.16 | 2.16 | 0 | 940 | 800 | 2.16 | 800 | 2.16 | 0.1512 | 2.16 | 2.16 | 800 | 800 | 0 | 0.056 | 2700 | 0.1512 | 11550 | 800 | 0.1512 | 1740 | 14250 | 2700 | 11550 | 0 | 0.49 | Face intérieure | Peinture-01 | Mur-149 | 1-Projet | Sde | B35 | Etage 3 | 6
Mur-121 | Etage 3 | 0 | 0 | 3000 | 3000 | 0 | 0 | 0.100802 | 0 | 0 | 480.011 | 1.33509 | 1.54497 | 0 | 584.989 | 445.032 | 1.33509 | 514.991 | 1.54497 | 0.100802 | 1.33509 | 1.54497 | 445.032 | 514.991 | 0 | 0.0336008 | 3000 | 0.100802 | 11550 | 514.991 | 0.100802 | 1128.99 | 14550 | 3000 | 11550 | -1.77636e-12 | 0.574099 | Face extérieure | Lavis blanc | Mur-121 | 1-Projet | Sejour cuisine | A32 | Etage 3 | 6
Mur-149 | Etage 3 | 2 | 0 | 2800 | 2800 | 3.3864 | 1660 | 0.232795 | 3.7856 | 3.7856 | 2539.73 | 3.42364 | 3.03164 | 0.264992 | 2644.73 | 754.727 | 7.20924 | 684.727 | 6.81724 | 0.497787 | 7.20924 | 7.01324 | 2574.73 | 2504.73 | 0 | 0.0503809 | 2800 | 0.232795 | 11550 | 2574.73 | 0.497787 | 5248.45 | 14350 | 2800 | 11550 | -1.77636e-12 | 0.701348 | Face intérieure | Surface-Blanche | Mur-149 | 1-Projet | Cellier | B33 | Etage 3 | 6
Mur-149 | Etage 3 | 0 | 0 | 2700 | 2700 | 0 | 0 | 0.762915 | 0 | 0 | 4036.59 | 10.8988 | 10.8988 | 0 | 4376.59 | 4036.59 | 10.8988 | 4036.59 | 10.8988 | 0.762915 | 10.8988 | 10.8988 | 4036.59 | 4036.59 | 0 | 0.282561 | 2700 | 0.762915 | 11550 | 4036.59 | 0.762915 | 8213.18 | 14250 | 2700 | 11550 | -1.77636e-12 | 0.943123 | Face intérieure | Surface-Blanche | Mur-149 | 1-Projet | Ch 2 | B33 | Etage 3 | 6
Mur-149 | Etage 3 | 1 | 0 | 2800 | 2800 | 1.6932 | 830 | 0.448778 | 1.8928 | 1.8928 | 2965.69 | 6.41112 | 6.41112 | 0.132496 | 3375.69 | 2055.69 | 8.30392 | 2055.69 | 8.30392 | 0.581274 | 8.30392 | 8.30392 | 2965.69 | 2965.69 | 0 | 0.143898 | 2800 | 0.448778 | 11550 | 2965.69 | 0.581274 | 6071.37 | 14350 | 2800 | 11550 | 0 | 0.743496 | Face intérieure | Surface-Blanche | Mur-149 | 1-Projet | Ch 1/pl | B31 | Etage 3 | 6
Mur-150 | Etage 3 | 0 | 0 | 3000 | 3000 | 0 | 0 | 0.220177 | 0 | 0 | 1048.46 | 2.74548 | 2.5373 | 0 | 1083.16 | 1083.16 | 2.74548 | 1013.77 | 2.5373 | 0.220177 | 3.24948 | 3.0413 | 1083.16 | 1013.77 | 0 | 0.0733924 | 3000 | 0.220177 | 11550 | 1083.16 | 0.220177 | 2265.49 | 14550 | 3000 | 11550 | 0 | 0.652488 | Face intérieure | Surface-Blanche | Mur-150 | 1-Projet |  |  | Etage 3 | 6
Mur-149 | Etage 3 | 0 | 0 | 3000 | 3000 | 0 | 0 | 0.0882991 | 0 | 0 | 420.472 | 1.15642 | 1.36642 | 0 | 385.472 | 385.472 | 1.15642 | 455.472 | 1.36642 | 0.0882991 | 1.15642 | 1.36642 | 385.472 | 455.472 | 0 | 0.029433 | 3000 | 0.0882991 | 11550 | 455.472 | 0.0882991 | 1009.94 | 14550 | 3000 | 11550 | 0 | 0.565851 | Face intérieure | Surface-Blanche | Mur-149 | 1-Projet | Sejour cuisine/pl | B31 | Etage 3 | 6
Mur-148 | Etage 3 | 0 | 0 | 3000 | 3000 | 0 | 0 | 0.122043 | 0 | 0 | 581.156 | 1.84854 | 1.6384 | 0 | 796.179 | 616.179 | 1.84854 | 546.134 | 1.6384 | 0.122043 | 1.84854 | 1.6384 | 616.179 | 546.134 | 0 | 0.0406809 | 3000 | 0.122043 | 11550 | 616.179 | 0.122043 | 1331.28 | 14550 | 3000 | 11550 | 0 | 0.58826 | Face intérieure | Surface-Blanche | Mur-148 | 1-Projet | Sejour cuisine | A32 | Etage 3 | 6
Mur-148 | Etage 3 | 0 | 0 | 3000 | 3000 | 0 | 0 | 0.134657 | 0 | 0 | 641.226 | 2.02868 | 1.81868 | 0 | 676.226 | 676.226 | 2.02868 | 606.226 | 1.81868 | 0.134657 | 2.02868 | 1.81868 | 676.226 | 606.226 | 0 | 0.0448858 | 3000 | 0.134657 | 11550 | 676.226 | 0.134657 | 1451.45 | 14550 | 3000 | 11550 | 0 | 0.596757 | Face intérieure | Surface-Blanche | Mur-148 | 1-Projet | Sejour cuisine/pl | B31 | Etage 3 | 6
Mur-148 | Etage 3 | 0 | 0 | 3000 | 3000 | 0 | 0 | 0.328266 | 0 | 0 | 1563.17 | 4.58438 | 4.58463 | 0 | 1778.13 | 1528.13 | 4.58438 | 1598.21 | 4.58463 | 0.328266 | 4.58438 | 4.79463 | 1528.13 | 1598.21 | 0 | 0.109422 | 3000 | 0.328266 | 11550 | 1598.21 | 0.328266 | 3295.36 | 14550 | 3000 | 11550 | 0 | 0.725908 | Face intérieure | Surface-Blanche | Mur-148 | 1-Projet | Wc | A32 | Etage 3 | 6
Mur-149 | Etage 3 | 1 | 0 | 2700 | 2700 | 1.1832 | 580 | 0.0433802 | 1.23 | 1.23 | 685.081 | 0.714218 | 0.525218 | 0.0861 | 720.081 | 120.081 | 1.94422 | 50.0807 | 1.75522 | 0.12948 | 1.94422 | 1.75522 | 720.081 | 650.081 | 0 | 0.00595565 | 2700 | 0.0433802 | 11550 | 720.081 | 0.12948 | 1539.16 | 14250 | 2700 | 11550 | 0 | 0.510198 | Face intérieure | Peinture-01 | Mur-149 | 1-Projet | Entree/pl | B35 | Etage 3 | 6
Mur-150 | Etage 3 | 0 | 0 | 3000 | 3000 | 0 | 0 | 0.184181 | 0 | 0 | 865.05 | 2.73615 | 2.52615 | 0 | 1080.05 | 900.051 | 2.73615 | 830.05 | 2.52615 | 0.184181 | 2.73615 | 2.52615 | 900.051 | 830.05 | 0 | 0.0731535 | 3000 | 0.184181 | 11550 | 1080.05 | 0.184181 | 1899.1 | 14550 | 3000 | 11550 | 0 | 0.653292 | Face intérieure | Surface-Blanche | Mur-150 | 1-Projet | Sde | B32 | Etage 3 | 6
Mur-149 | Etage 3 | 1 | 0 | 2700 | 2700 | 1.6932 | 830 | 0.347249 | 1.8928 | 1.8928 | 2538.33 | 4.9607 | 4.7717 | 0.132496 | 2718.33 | 2538.33 | 6.8535 | 2538.33 | 6.6645 | 0.479745 | 6.8535 | 6.8535 | 2538.33 | 2538.33 | 0 | 0.177683 | 2700 | 0.347249 | 11550 | 2538.33 | 0.479745 | 5216.66 | 14250 | 2700 | 11550 | 0 | 0.733366 | Face intérieure | Peinture-01 | Mur-149 | 1-Projet | Entree/pl | B35 | Etage 3 | 6
Mur-149 | Etage 3 | 1 | 0 | 3000 | 3000 | 1.1832 | 580 | 0.0513209 | 1.23 | 1.23 | 654.385 | 0.838155 | 0.628155 | 0.0861 | 799.385 | 89.385 | 2.06816 | 19.385 | 1.85816 | 0.137421 | 2.06816 | 1.85816 | 689.385 | 619.385 | 0 | 0.00380695 | 3000 | 0.0513209 | 11550 | 689.385 | 0.137421 | 1477.76 | 14550 | 3000 | 11550 | 0 | 0.556599 | Face intérieure | Surface-Blanche | Mur-149 | 1-Projet | Sejour cuisine/pl | B31 | Etage 3 | 6
Mur-152 | Etage 3 | 0 | 0 | 3000 | 2300 | 0 | 0 | 0.236744 | 0 | 0 | 1164.86 | 3.49457 | 2.6316 | 0 | 1414.86 | 1164.86 | 3.49457 | 1164.86 | 2.6316 | 0.236744 | 3.49457 | 3.49457 | 1164.86 | 1164.86 | 0 | 0.0815401 | 3000 | 0.236744 | 11550 | 1164.86 | 0.24462 | 2469.72 | 14550 | 3000 | 11550 | 0 | 0.569557 | Face extérieure | Peinture-01 | Mur-152 | 1-Projet | Sejour cuisine | A32 | Etage 3 | 6
Mur-149 | Etage 3 | 0 | 0 | 3000 | 3000 | 0 | 0 | 0.137101 | 0 | 0 | 640.862 | 1.85359 | 2.06358 | 0 | 855.861 | 605.862 | 1.85359 | 675.861 | 2.06358 | 0.137101 | 1.85359 | 2.06358 | 605.862 | 675.861 | 0 | 0.0574603 | 3000 | 0.137101 | 11550 | 855.861 | 0.137101 | 1450.72 | 14550 | 3000 | 11550 | 0 | 0.621905 | Face extérieure | Lavis blanc | Mur-149 | 1-Projet | Sejour cuisine | B32 | Etage 3 | 6
Mur-149 | Etage 3 | 0 | 0 | 3000 | 3000 | 0 | 0 | 0.18417 | 0 | 0 | 865 | 2.736 | 2.52599 | 0 | 1080 | 900 | 2.736 | 830 | 2.52599 | 0.18417 | 2.736 | 2.52599 | 900 | 830 | 0 | 0.0731489 | 3000 | 0.18417 | 11550 | 1080 | 0.18417 | 1899.02 | 14550 | 3000 | 11550 | 0 | 0.653352 | Face intérieure | Surface-Blanche | Mur-149 | 1-Projet | Sde | B33 | Etage 3 | 6
Mur-149 | Etage 3 | 0 | 1 | 3000 | 3000 | 0 | 0 | 0.856131 | 2.7163 | 2.7163 | 4982.25 | 12.2304 | 11.8104 | 0.190141 | 4982.25 | 3650.73 | 12.2304 | 3650.73 | 11.8104 | 1.04627 | 14.9467 | 14.9467 | 4982.25 | 4982.25 | 2.7163 | 0.255551 | 3000 | 0.856131 | 11550 | 4982.25 | 1.04627 | 10104.5 | 14550 | 3000 | 11550 | 0 | 1.02431 | Face intérieure | Surface-Blanche | Mur-149 | 1-Projet | Sejour cuisine | B32 | Etage 3 | 6
Mur-149 | Etage 3 | 0 | 0 | 2700 | 2700 | 0 | 0 | 0.120015 | 0 | 0 | 635 | 1.809 | 1.62 | 0 | 740 | 670 | 1.809 | 600 | 1.62 | 0.120015 | 1.809 | 1.62 | 670 | 600 | 0 | 0.04445 | 2700 | 0.120015 | 11550 | 670 | 0.120015 | 1438.99 | 14250 | 2700 | 11550 | 0 | 0.545186 | Face intérieure | Peinture-01 | Mur-149 | 1-Projet | Ch 1/pl | B35 | Etage 3 | 6
Mur-150 | Etage 3 | 2 | 0 | 3000 | 3000 | 2.8764 | 1410 | 0.425721 | 3.1228 | 3.1228 | 3051.51 | 6.08173 | 5.87173 | 0.218596 | 3301.52 | 1541.51 | 9.20453 | 1541.51 | 8.99453 | 0.644317 | 9.20453 | 9.20453 | 3051.51 | 3051.51 | 0 | 0.125406 | 3000 | 0.425721 | 11550 | 3301.52 | 0.644317 | 6243.02 | 14550 | 3000 | 11550 | -1.77636e-12 | 0.776512 | Face intérieure | Surface-Blanche | Mur-150 | 1-Projet | Sde | B33 | Etage 3 | 6
Mur-149 | Etage 3 | 0 | 0 | 3000 | 3000 | 0 | 0 | 0.332243 | 0 | 0 | 1582.1 | 4.32632 | 4.74632 | 0 | 1652.11 | 1582.1 | 4.32632 | 1582.1 | 4.74632 | 0.332243 | 4.74632 | 4.74632 | 1582.1 | 1582.1 | 0 | 0.110748 | 3000 | 0.332243 | 11550 | 1582.11 | 0.332243 | 3304.21 | 14550 | 3000 | 11550 | -1.77636e-12 | 0.641495 | Face intérieure | Surface-Blanche | Mur-149 | 1-Projet | Sde | A32 | Etage 3 | 6 | ArchiCADProperties - Zones conflictuelles: Sde
Mur-149 | Etage 3 | 0 | 0 | 3000 | 3000 | 0 | 0 | 0.07455 | 0 | 0 | 355 | 0.96 | 1.17 | 0 | 390 | 320 | 0.96 | 390 | 1.17 | 0.07455 | 0.96 | 1.17 | 320 | 390 | 0 | 0.02485 | 3000 | 0.07455 | 11550 | 390 | 0.07455 | 878.995 | 14550 | 3000 | 11550 | 0 | 0.556685 | Face intérieure | Surface-Blanche | Mur-149 | 1-Projet | Sejour cuisine/pl | B31 | Etage 3 | 6
Mur-149 | Etage 3 | 1 | 0 | 3000 | 3000 | 1.6932 | 830 | 0.186683 | 1.8928 | 1.8928 | 1519.9 | 2.6669 | 2.66691 | 0.132496 | 1699.9 | 609.904 | 4.5597 | 609.903 | 4.55971 | 0.319179 | 4.5597 | 4.55971 | 1519.9 | 1519.9 | 0 | 0.0426931 | 3000 | 0.186683 | 11550 | 1519.9 | 0.319179 | 3179.81 | 14550 | 3000 | 11550 | 0 | 0.569086 | Face extérieure | Lavis blanc | Mur-149 | 1-Projet |  |  | Etage 3 | 6
Mur-149 | Etage 3 | 1 | 0 | 3000 | 3000 | 1.6932 | 830 | 0.207469 | 1.8928 | 1.8928 | 1618.88 | 2.66284 | 3.06884 | 0.132496 | 1583.88 | 673.88 | 4.55564 | 743.88 | 4.96164 | 0.339965 | 4.75164 | 4.96164 | 1583.88 | 1653.88 | 0 | 0.0496216 | 3000 | 0.207469 | 11550 | 1653.88 | 0.339965 | 3406.76 | 14550 | 3000 | 11550 | 0 | 0.669928 | Face extérieure | Lavis blanc | Mur-149 | 1-Projet | Sdb | B34 | Etage 3 | 6
Mur-149 | Etage 3 | 4 | 0 | 3000 | 3000 | 11.3066 | 5620.11 | 0.442476 | 11.6258 | 11.6258 | 5982.3 | 5.90107 | 5.90107 | 0.813807 | 6162.3 | 242.186 | 9.68667 | 242.186 | 9.68667 | 1.25628 | 17.9469 | 17.9469 | 5982.3 | 5982.3 | 0 | 0.0169531 | 3000 | 0.442476 | 11550 | 5982.3 | 1.25628 | 12104.6 | 14550 | 3000 | 11550 | 0 | 0.575714 | Face intérieure | Surface-Blanche | Mur-149 | 1-Projet | Ch 2 | B32 | Etage 3 | 6 | ArchiCADProperties - Zones conflictuelles: Ch 1/pl
Mur-149 | Etage 3 | 1 | 0 | 2700 | 2700 | 1.6932 | 830 | 0.199207 | 1.8928 | 1.8928 | 1755.04 | 2.94031 | 2.75131 | 0.132496 | 1970.04 | 880.041 | 4.83311 | 810.04 | 4.64411 | 0.331703 | 4.83311 | 4.64411 | 1790.04 | 1720.04 | 0 | 0.0591529 | 2700 | 0.199207 | 11550 | 1790.04 | 0.331703 | 3679.08 | 14250 | 2700 | 11550 | 0 | 0.638292 | Face intérieure | Peinture-01 | Mur-149 | 1-Projet | Wc | B32 | Etage 3 | 6
Mur-150 | Etage 3 | 2 | 0 | 3000 | 3000 | 2.8764 | 1410 | 0.439453 | 3.1228 | 3.1228 | 3121.57 | 6.2779 | 5.8579 | 0.218596 | 3371.57 | 1611.57 | 9.4007 | 1611.57 | 8.9807 | 0.658049 | 9.4007 | 9.4007 | 3121.57 | 3121.57 | 0 | 0.12541 | 3000 | 0.439453 | 11550 | 3301.57 | 0.658049 | 6383.13 | 14550 | 3000 | 11550 | 0 | 0.776519 | Face intérieure | Surface-Blanche | Mur-150 | 1-Projet | Sde | B32 | Etage 3 | 6
Mur-149 | Etage 3 | 0 | 0 | 3000 | 3000 | 0 | 0 | 0.539556 | 0 | 0 | 2571.65 | 7.39994 | 7.80594 | 0 | 2536.65 | 2536.65 | 7.39994 | 2606.65 | 7.80594 | 0.539556 | 7.60994 | 7.80594 | 2536.65 | 2606.65 | 0 | 0.180015 | 3000 | 0.539556 | 11550 | 2606.65 | 0.539556 | 5312.29 | 14550 | 3000 | 11550 | 0 | 0.861216 | Face intérieure | Surface-Blanche | Mur-149 | 1-Projet | Ch 2 | B33 | Etage 3 | 6
Mur-149 | Etage 3 | 0 | 0 | 3000 | 3000 | 0 | 0 | 0.697675 | 0 | 0 | 3319.93 | 9.76378 | 9.97378 | 0 | 3319.93 | 3249.93 | 9.76378 | 3389.93 | 9.97378 | 0.697675 | 9.76378 | 10.1698 | 3249.93 | 3389.93 | 0 | 0.234845 | 3000 | 0.697675 | 11550 | 3389.93 | 0.697675 | 6837.85 | 14550 | 3000 | 11550 | 0 | 1.05786 | Face intérieure | Surface-Blanche | Mur-149 | 1-Projet | Ch 1/pl | B31 | Etage 3 | 6
Mur-149 | Etage 3 | 1 | 0 | 3000 | 0 | 1.6932 | 830 | 0.12428 | 1.8928 | 1.8928 | 1250.74 | 1.77542 | 1.77542 | 0.132496 | 1250.74 | 340.741 | 3.66822 | 340.741 | 3.66822 | 0.256776 | 3.66822 | 3.66822 | 1250.74 | 1250.74 | 0 | 0.0238519 | 3000 | 0.12428 | 11550 | 1250.74 | 0.256776 | 2641.48 | 14550 | 3000 | 11550 | 0 | 0.333304 | Face extérieure | Lavis blanc | Mur-149 | 1-Projet | Dgt/pl | B34 | Etage 3 | 6
Mur-149 | Etage 3 | 0 | 0 | 3000 | 3000 | 0 | 0 | 0.35271 | 0 | 0 | 1679.57 | 4.93372 | 4.93371 | 0 | 1784.57 | 1644.57 | 4.93372 | 1714.57 | 4.93371 | 0.35271 | 4.93372 | 5.14371 | 1644.57 | 1714.57 | 0 | 0.11757 | 3000 | 0.35271 | 11550 | 1714.57 | 0.35271 | 3528.14 | 14550 | 3000 | 11550 | -1.77636e-12 | 0.742124 | Face extérieure | Lavis blanc | Mur-149 | 1-Projet | Sejour cuisine | B32 | Etage 3 | 6
Mur-149 | Etage 3 | 2 | 0 | 2800 | 2800 | 3.3864 | 1660 | 0.621153 | 3.7856 | 3.7856 | 4521.15 | 8.57961 | 8.57961 | 0.264992 | 4556.15 | 2666.15 | 12.3652 | 2736.15 | 12.3652 | 0.886145 | 12.5612 | 12.7572 | 4486.15 | 4556.15 | 0 | 0.18908 | 2800 | 0.621153 | 11550 | 4556.15 | 0.886145 | 9211.29 | 14350 | 2800 | 11550 | 0 | 0.978746 | Face extérieure | Lavis blanc | Mur-149 | 1-Projet | Dgt/pl | B34 | Etage 3 | 6 | ArchiCADProperties - Zones conflictuelles: Ch 2; Ch 3
Mur-150 | Etage 3 | 0 | 0 | 3000 | 3000 | 0 | 0 | 0.0829716 | 0 | 0 | 395.103 | 1.29031 | 1.0803 | 0 | 430.104 | 430.104 | 1.29031 | 360.101 | 1.0803 | 0.0829716 | 1.29031 | 1.0803 | 430.104 | 360.101 | 0 | 0.0276572 | 3000 | 0.0829716 | 11550 | 430.104 | 0.0829716 | 958.776 | 14550 | 3000 | 11550 | 0 | 0.561025 | Face intérieure | Surface-Blanche | Mur-150 | 1-Projet | Sde | B33 | Etage 3 | 6
Mur-150 | Etage 3 | 0 | 0 | 3000 | 3000 | 0 | 0 | 0.184209 | 0 | 0 | 865.186 | 2.73617 | 2.52694 | 0 | 1080.06 | 900.057 | 2.73617 | 830.314 | 2.52694 | 0.184209 | 2.73617 | 2.52694 | 900.057 | 830.314 | 0 | 0.073163 | 3000 | 0.184209 | 11550 | 1080.06 | 0.184209 | 1899.19 | 14550 | 3000 | 11550 | 0 | 0.652767 | Face intérieure | Surface-Blanche | Mur-150 | 1-Projet | Sde | B32 | Etage 3 | 6
Mur-153 | Etage 3 | 0 | 0 | 3000 | 3000 | 0 | 0 | 0.111357 | 0 | 0 | 530.27 | 1.80081 | 1.38081 | 0 | 530.27 | 600.27 | 1.80081 | 460.27 | 1.38081 | 0.111357 | 1.80081 | 1.38081 | 600.27 | 460.27 | 0 | 0.0371189 | 3000 | 0.111357 | 11550 | 600.27 | 0.111357 | 1258.53 | 14550 | 3000 | 11550 | 0 | 0.668207 | Face extérieure | Peinture-01 | Mur-153 | 1-Projet | Dressing | A34 | Etage 3 | 6
Mur-149 | Etage 3 | 0 | 0 | 2700 | 2500 | 0 | 0 | 0.210931 | 0 | 0 | 1187.83 | 2.9258 | 3.1008 | 0 | 1222.83 | 1152.83 | 2.9258 | 1222.83 | 3.1008 | 0.210931 | 3.11263 | 3.30163 | 1152.83 | 1222.83 | 0 | 0.0831478 | 2700 | 0.210931 | 11550 | 1222.83 | 0.224499 | 2544.65 | 14250 | 2700 | 11550 | 0 | 0.534942 | Face intérieure | Peinture-01 | Mur-149 | 1-Projet | Sejour cuisine/pl | B35 | Etage 3 | 6
Mur-153 | Etage 3 | 0 | 0 | 3000 | 3000 | 0 | 0 | 0.0986429 | 0 | 0 | 469.728 | 1.40919 | 1.40918 | 0 | 879.726 | 469.729 | 1.40919 | 469.726 | 1.40918 | 0.0986429 | 1.40919 | 1.40918 | 469.729 | 469.726 | 0 | 0.032881 | 3000 | 0.0986429 | 11550 | 469.729 | 0.0986429 | 1079.46 | 14550 | 3000 | 11550 | -1.77636e-12 | 0.485762 | Face extérieure | Peinture-01 | Mur-153 | 1-Projet | Sde/pl | A34 | Etage 3 | 6
Mur-153 | Etage 3 | 0 | 0 | 3000 | 3000 | 0 | 0 | 0.113337 | 0 | 0 | 539.698 | 1.6191 | 1.61909 | 0 | 879.697 | 539.7 | 1.6191 | 539.697 | 1.61909 | 0.113337 | 1.6191 | 1.61909 | 539.7 | 539.697 | 0 | 0.0377789 | 3000 | 0.113337 | 11550 | 539.7 | 0.113337 | 1219.4 | 14550 | 3000 | 11550 | 0 | 0.495558 | Face extérieure | Peinture-01 | Mur-153 | 1-Projet | Sde/pl | A34 | Etage 3 | 6
Mur-155 | Etage 3 | 1 | 1 | 3000 | 0 | 1.1832 | 580 | 0.332852 | 2.92317 | 2.92317 | 2629.4 | 4.54503 | 4.54502 | 0.204622 | 2629.4 | 1199.41 | 7.46819 | 1199.41 | 7.46819 | 0.537473 | 7.67819 | 7.67819 | 2629.4 | 2629.4 | 1.6932 | 0.0790589 | 3000 | 0.332852 | 11550 | 2559.4 | 0.537473 | 5398.79 | 14550 | 3000 | 11550 | 0 | 0.678217 | Face extérieure | Peinture-01 | Mur-155 | 1-Projet | Wc | A33 | Etage 3 | 6 | ArchiCADProperties - Zones conflictuelles: Sde
Mur-158 | Etage 3 | 0 | 0 | 3000 | 3000 | 0 | 0 | 0.648863 | 0 | 0 | 3089.82 | 9.26944 | 8.8495 | 0 | 3429.81 | 3089.81 | 9.26944 | 3089.83 | 8.8495 | 0.648863 | 9.26944 | 9.2695 | 3089.81 | 3089.83 | 0 | 0.216288 | 3000 | 0.648863 | 11550 | 3089.83 | 0.648863 | 6319.65 | 14550 | 3000 | 11550 | 0 | 0.852575 | Face intérieure | Peinture-01 | Mur-158 | 1-Projet | Sde | A33 | Etage 3 | 6
Mur-156 | Etage 3 | 0 | 0 | 3000 | 3000 | 0 | 0 | 0.182768 | 0 | 0 | 870.325 | 2.71597 | 2.50597 | 0 | 975.325 | 905.325 | 2.71597 | 835.325 | 2.50597 | 0.182768 | 2.71597 | 2.50597 | 905.325 | 835.325 | 0 | 0.0609227 | 3000 | 0.182768 | 11550 | 905.325 | 0.182768 | 1909.59 | 14550 | 3000 | 11550 | 0 | 0.628677 | Face intérieure | Peinture-01 | Mur-156 | 1-Projet | Sde | A33 | Etage 3 | 6
Mur-156 | Etage 3 | 0 | 0 | 3000 | 3000 | 0 | 0 | 0.314437 | 0 | 0 | 1497.32 | 4.28192 | 4.49198 | 0 | 1747.31 | 1497.31 | 4.28192 | 1497.33 | 4.49198 | 0.314437 | 4.49192 | 4.49198 | 1497.31 | 1497.33 | 0 | 0.104812 | 3000 | 0.314437 | 11550 | 1497.33 | 0.314437 | 3134.63 | 14550 | 3000 | 11550 | 0 | 0.629624 | Face intérieure | Peinture-01 | Mur-156 | 1-Projet | Ch 2/pl | A33 | Etage 3 | 6
Mur-156 | Etage 3 | 0 | 0 | 3000 | 3000 | 0 | 0 | 0.883423 | 0 | 0 | 4206.78 | 12.6203 | 12.6204 | 0 | 4546.77 | 4206.77 | 12.6203 | 4206.79 | 12.6204 | 0.883423 | 12.6203 | 12.6204 | 4206.77 | 4206.79 | 0 | 0.294474 | 3000 | 0.883423 | 11550 | 4206.79 | 0.883423 | 8553.55 | 14550 | 3000 | 11550 | 0 | 1.00895 | Face intérieure | Peinture-01 | Mur-156 | 1-Projet | Ch 1 | A33 | Etage 3 | 6
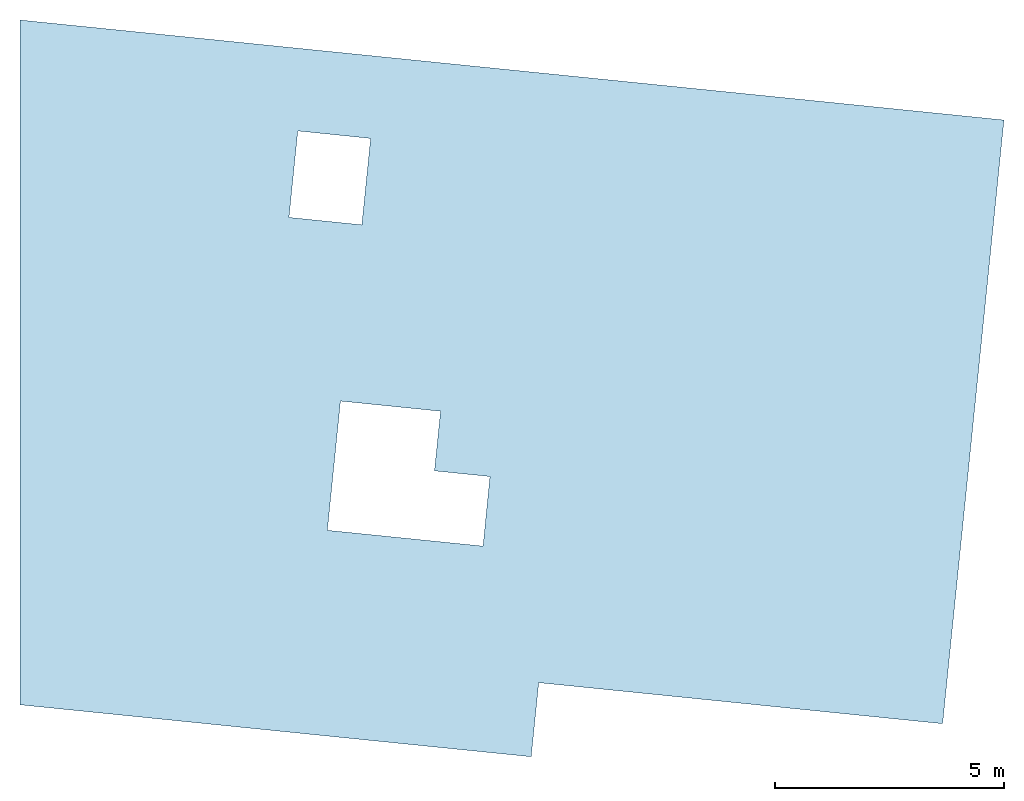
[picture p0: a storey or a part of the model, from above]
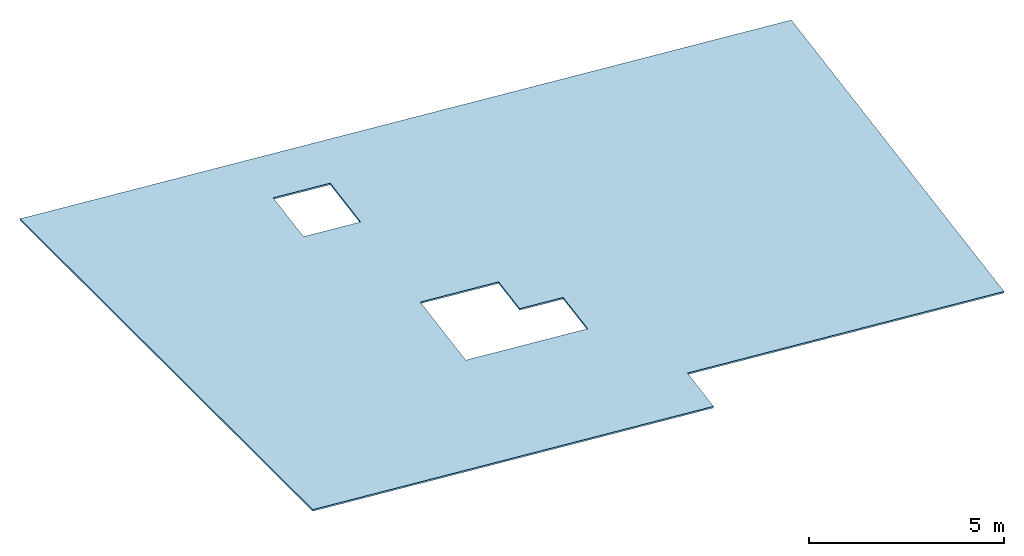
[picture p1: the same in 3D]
Properties of the parts of a building model (IFC2X3), part 28 of 44

# IfcWallStandardCase: Cloison 70 0826278243 70 (896)
Name | In | Nombre de Portes | Nombre de trous (Nombre d'ouvertures vides) | Hauteur maximale de la couche de Mur sur face intérieure (mm) = Hauteur maximale du Mur (mm) = Hauteur maximale de la couche de Mur sur face extérieure (mm) | Hauteur minimale de la couche de Mur sur face intérieure (mm) = Hauteur minimale du Mur (mm) = Hauteur minimale de la couche de Mur sur face extérieure (mm) | Superficie des portes (m2) | Largeur totale des Portes (mm) | Volume de composant de mur sur face intérieure (net) (m3) = Volume de composant de mur sur face extérieure (net) (m3) | Superficie analytique des ouvertures sur face intérieure (m2) | Superficie analytique des ouvertures sur face extérieure (m2) | Longueur moyenne du mur (mm) = Longueur du Mur au centre (mm) | Superficie de la face intérieure du mur (nette) (m2) | Superficie de la face extérieure du mur (nette) (m2) = Superficie en plan (m2) = Superficie inférieure (nette) (m2) | Volume analytique des ouvertures (m3) | Longueur de ligne de référence (mm) | Longueur de la face intérieure du mur (conditionnelle) (mm) | Superficie de la face intérieure du mur (conditionnelle) (m2) | Longueur de la face extérieure du mur (conditionnelle) (mm) | Superficie de la face extérieure du mur (conditionnelle) (m2) | Volume du composant face intérieure du mur (conditionnel) (m3) = Volume du composant face extérieure du mur (conditionnel) (m3) = Volume (conditionnel) (m3) | Superficie de la face intérieure du mur (brute) (m2) | Superficie de la face extérieure du mur (brute) (m2) | Longueur de Mur sur face intérieure (mm) | Longueur de Mur sur face extérieure (mm) | Superficie des baies libres dans le Mur (m2) | Superficie (m2) = Superficie supérieure (nette) (m2) | Hauteur (mm) | Volume (net) (m3) | Altitude à Zéro du Projet (mm) = Altitude de Référence Niveau 1 (mm) = Altitude de Référence Niveau 2 (mm) = Altitude à niveau de la mer (mm) | Longueur 3D (mm) | Volume (brut) (m3) | Périmètre Plan (mm) | Altitude supérieure à premier niveau de référence (mm) = Altitude supérieure à Zéro du projet (mm) = Altitude supérieure à niveau de la mer (mm) = Altitude supérieure à deuxième niveau de référence (mm) | Altitude supérieure à étage d'implantation (mm) | Altitude inférieure à premier niveau de référence (mm) = Altitude inférieure à Zéro du projet (mm) = Altitude inférieure à niveau de la mer (mm) = Altitude inférieure à deuxième niveau de référence (mm) | Altitude inférieure à étage d'implantation (mm) | Superficie de l'arête (nette) (m2) | Emplacement de ligne de référence | Surface de face intérieure = Surface de face extérieure = Surfaces (Toutes) = Surface latérale | ID de l'élément = Lien et ID d'élément = ID de Parent | Calque | Nom de zone liée | Numéro de zone liée | Nom d'étage d'implantation | Numéro d'étage d'implantation
Mur-156 | Etage 3 | 1 | 0 | 3000 | 3000 | 1.6932 | 830 | 0.341209 | 1.8928 | 1.8928 | 2255.74 | 4.76941 | 4.55941 | 0.132496 | 2290.74 | 1380.74 | 6.66221 | 1310.74 | 6.45221 | 0.473705 | 6.87221 | 6.66221 | 2290.74 | 2220.74 | 0 | 0.0942015 | 3000 | 0.341209 | 11550 | 2290.74 | 0.473705 | 4680.48 | 14550 | 3000 | 11550 | 0 | 0.759088 | Face intérieure | Peinture-01 | Mur-156 | 1-Projet | Ch 2/pl | A33 | Etage 3 | 6
Mur-156 | Etage 3 | 0 | 0 | 3000 | 3000 | 0 | 0 | 0.126 | 0 | 0 | 600 | 1.8 | 1.8 | 0 | 670 | 600 | 1.8 | 600 | 1.8 | 0.126 | 1.8 | 1.8 | 600 | 600 | 0 | 0.042 | 3000 | 0.126 | 11550 | 600 | 0.126 | 1340 | 14550 | 3000 | 11550 | 0 | 0.504 | Face intérieure | Peinture-01 | Mur-156 | 1-Projet | Ch 2/pl | A33 | Etage 3 | 6
Mur-156 | Etage 3 | 1 | 0 | 3000 | 0 | 1.6932 | 830 | 0.42362 | 1.8928 | 1.8928 | 2718.17 | 5.84171 | 5.84171 | 0.132496 | 2858.17 | 1808.17 | 7.73451 | 1808.17 | 7.73451 | 0.556116 | 7.94451 | 7.94451 | 2718.17 | 2718.17 | 0 | 0.121672 | 3000 | 0.42362 | 11550 | 2648.19 | 0.556116 | 5576.34 | 14550 | 3000 | 11550 | 0 | 0.727044 | Face intérieure | Peinture-01 | Mur-156 | 1-Projet | Dgt | A33 | Etage 3 | 6
Mur-155 | Etage 3 | 0 | 0 | 3000 | 3000 | 0 | 0 | 0.139481 | 0 | 0 | 664.194 | 1.88766 | 2.0975 | 0 | 1039.17 | 629.221 | 1.88766 | 699.167 | 2.0975 | 0.139481 | 1.88766 | 2.0975 | 629.221 | 699.167 | 0 | 0.0464936 | 3000 | 0.139481 | 11550 | 699.167 | 0.139481 | 1497.33 | 14550 | 3000 | 11550 | 0 | 0.599819 | Face extérieure | Peinture-01 | Mur-155 | 1-Projet | Sde | A33 | Etage 3 | 6
Mur-156 | Etage 3 | 0 | 0 | 3000 | 3000 | 0 | 0 | 0.104832 | 0 | 0 | 499.199 | 1.65374 | 1.34145 | 0 | 551.246 | 551.246 | 1.65374 | 447.151 | 1.34145 | 0.104832 | 1.65374 | 1.34145 | 551.246 | 447.151 | 0 | 0.0349439 | 3000 | 0.104832 | 11550 | 551.246 | 0.104832 | 1177.54 | 14550 | 3000 | 11550 | 0 | 0.607306 | Face intérieure | Peinture-01 | Mur-156 | 1-Projet | Ch 1 | A33 | Etage 3 | 6 | ArchiCADProperties - Zones conflictuelles: Ch 1
Mur-151 | Etage 3 | 1 | 1 | 3000 | 3000 | 1.6932 | 830 | 0.591149 | 3.84701 | 3.84701 | 4097.33 | 8.23498 | 8.44498 | 0.26929 | 4657.33 | 2229.38 | 12.082 | 2229.38 | 12.292 | 0.860439 | 12.292 | 12.292 | 4097.33 | 4097.33 | 1.95421 | 0.156057 | 3000 | 0.591149 | 11550 | 4097.33 | 0.860439 | 8334.66 | 14550 | 3000 | 11550 | -1.77636e-12 | 0.86287 | Face extérieure | Peinture-01 | Mur-151 | 1-Projet | Sde | A32 | Etage 3 | 6 | ArchiCADProperties - Zones conflictuelles: Sde
Mur-156 | Etage 3 | 1 | 0 | 3000 | 3000 | 1.96219 | 981.097 | 0.222231 | 1.96219 | 1.96219 | 1712.31 | 2.73973 | 2.31973 | 0.137354 | 1747.31 | 766.211 | 4.70192 | 696.211 | 4.28192 | 0.359585 | 5.24192 | 5.03192 | 1747.31 | 1677.31 | 0 | 0.0511847 | 3000 | 0.222231 | 11550 | 1747.31 | 0.359585 | 3593.61 | 14550 | 3000 | 11550 | 0 | 0.678031 | Face intérieure | Peinture-01 | Mur-156 | 1-Projet | Ch 2/pl | A33 | Etage 3 | 6 | ArchiCADProperties - Zones conflictuelles: Ch 2/pl
Mur-156 | Etage 3 | 1 | 0 | 3000 | 1.77636e-12 | 1.87453 | 937.266 | 0.116609 | 1.7945 | 1.79453 | 1223.45 | 1.66586 | 1.66583 | 0.125616 | 1293.45 | 326.203 | 3.46036 | 326.188 | 3.46036 | 0.242225 | 3.46036 | 3.46036 | 1223.45 | 1223.45 | 0 | 0.0179337 | 3000 | 0.116609 | 11550 | 1153.47 | 0.242225 | 2586.91 | 14550 | 3000 | 11550 | -1.77636e-12 | 0.378675 | Face intérieure | Peinture-01 | Mur-156 | 1-Projet | Sejour cuisine/pl | A33 | Etage 3 | 6
Mur-156 | Etage 3 | 0 | 0 | 3000 | 3000 | 0 | 0 | 0.324963 | 0 | 0 | 1547.44 | 4.68293 | 4.60172 | 0 | 1900.98 | 1560.98 | 4.68293 | 1533.91 | 4.60172 | 0.324963 | 4.68293 | 4.60172 | 1560.98 | 1533.91 | 0 | 0.108321 | 3000 | 0.324963 | 11550 | 1560.98 | 0.324963 | 3239.93 | 14550 | 3000 | 11550 | 0 | 0.651777 | Face intérieure | Peinture-01 | Mur-156 | 1-Projet | Ch 1 | A33 | Etage 3 | 6 | ArchiCADProperties - Zones conflictuelles: Ch 1
Mur-149 | Etage 3 | 0 | 0 | 3000 | 3000 | 0 | 0 | 0.363727 | 0 | 0 | 1720.03 | 5.1961 | 4.9861 | 0 | 1970.03 | 1720.03 | 5.1961 | 1720.03 | 4.9861 | 0.363727 | 5.1961 | 5.1961 | 1720.03 | 1720.03 | 0 | 0.133002 | 3000 | 0.363727 | 11550 | 1900.03 | 0.363727 | 3580.06 | 14550 | 3000 | 11550 | 0 | 0.686005 | Face intérieure | Surface-Blanche | Mur-149 | 1-Projet | Wc | B32 | Etage 3 | 6
Mur-149 | Etage 3 | 1 | 1 | 2800 | 2800 | 1.6932 | 830 | 0.748753 | 4.74901 | 4.74901 | 5516.24 | 10.7945 | 10.0105 | 0.332431 | 5551.24 | 3241.14 | 12.6873 | 3171.13 | 11.9033 | 1.08118 | 15.5435 | 15.3475 | 5551.24 | 5481.24 | 2.85621 | 0.22443 | 2800 | 0.748753 | 11550 | 5551.25 | 1.08118 | 11201.5 | 14350 | 2800 | 11550 | 0 | 0.940956 | Face extérieure | Lavis blanc | Mur-149 | 1-Projet | Sejour cuisine | B34 | Etage 3 | 6 | ArchiCADProperties - Zones conflictuelles: cellier; Entree; Wc 1
Mur-149 | Etage 3 | 0 | 0 | 3000 | 3000 | 0 | 0 | 0.13335 | 0 | 0 | 635 | 2.01 | 1.8 | 0 | 670 | 670 | 2.01 | 600 | 1.8 | 0.13335 | 2.01 | 1.8 | 670 | 600 | 0 | 0.0444501 | 3000 | 0.13335 | 11550 | 669.999 | 0.13335 | 1438.99 | 14550 | 3000 | 11550 | 0 | 0.595887 | Face intérieure | Surface-Blanche | Mur-149 | 1-Projet | Ch 2 | B33 | Etage 3 | 6
2 x Mur-121 | Etage 3 | 0 | 0 | 3000 | 3000 | 0 | 0 | 0.0693254 | 0 | 0 | 330.121 | 0.990362 | 0.990362 | 0 | 400.121 | 330.121 | 0.990362 | 330.121 | 0.990362 | 0.0693254 | 0.990362 | 0.990362 | 330.121 | 330.121 | 0 | 0.0231085 | 3000 | 0.0693254 | 11550 | 330.121 | 0.0693254 | 800.242 | 14550 | 3000 | 11550 | 0 | 0.466217 | Face extérieure | Lavis blanc | Mur-121 | 1-Projet |  |  | Etage 3 | 6
Mur-149 | Etage 3 | 0 | 0 | 3000 | 3000 | 0 | 0 | 0.210384 | 0 | 0 | 989.831 | 3.00549 | 3.00549 | 0 | 1169.83 | 989.831 | 3.00549 | 989.831 | 3.00549 | 0.210384 | 3.00549 | 3.00549 | 989.831 | 989.831 | 0 | 0.0818878 | 3000 | 0.210384 | 11550 | 1169.83 | 0.210384 | 2119.66 | 14550 | 3000 | 11550 | 0 | 0.583776 | Face extérieure | Lavis blanc | Mur-149 | 1-Projet | Wc 2 | B34 | Etage 3 | 6
Mur-149 | Etage 3 | 0 | 0 | 3000 | 0 | 0 | 0 | 0.832976 | 0 | 0 | 4036.55 | 11.8997 | 11.8997 | 0 | 4376.55 | 4036.55 | 11.8997 | 4036.55 | 11.8997 | 0.832976 | 11.8997 | 11.8997 | 4036.55 | 4036.55 | 0 | 0.277659 | 3000 | 0.832976 | 11550 | 3966.55 | 0.832976 | 8213.09 | 14550 | 3000 | 11550 | 0 | 0.765317 | Face intérieure | Surface-Blanche | Mur-149 | 1-Projet | Ch 2 | B32 | Etage 3 | 6
Mur-153 | Etage 3 | 0 | 0 | 3000 | 3000 | 0 | 0 | 0.141537 | 0 | 0 | 673.984 | 1.81195 | 2.02196 | 0 | 853.986 | 673.983 | 1.81195 | 673.986 | 2.02196 | 0.141537 | 2.02195 | 2.02196 | 673.983 | 673.986 | 0 | 0.0471789 | 3000 | 0.141537 | 11550 | 673.986 | 0.141537 | 1487.97 | 14550 | 3000 | 11550 | 0 | 0.514358 | Face extérieure | Peinture-01 | Mur-153 | 1-Projet | Sejour cuisine/pl | A34 | Etage 3 | 6
Mur-149 | Etage 3 | 0 | 0 | 3000 | 3000 | 0 | 0 | 0.148916 | 0 | 0 | 709.124 | 2.23237 | 2.02237 | 0 | 924.124 | 744.124 | 2.23237 | 674.124 | 2.02237 | 0.148916 | 2.23237 | 2.02237 | 744.124 | 674.124 | 0 | 0.0496387 | 3000 | 0.148916 | 11550 | 744.124 | 0.148916 | 1587.24 | 14550 | 3000 | 11550 | 0 | 0.606262 | Face intérieure | Surface-Blanche | Mur-149 | 1-Projet |  |  | Etage 3 | 6 | ArchiCADProperties - Zones conflictuelles: Sdb
Mur-153 | Etage 3 | 1 | 0 | 3000 | 3000 | 1.1832 | 580 | 0.0549981 | 1.23002 | 1.23 | 671.898 | 0.575706 | 0.995664 | 0.0861006 | 741.888 | 1.90862 | 1.80573 | 141.888 | 2.22566 | 0.141099 | 1.80573 | 2.22566 | 601.909 | 741.888 | 0 | 0.0050326 | 3000 | 0.0549981 | 11550 | 741.888 | 0.141099 | 1541.77 | 14550 | 3000 | 11550 | 0 | 0.646005 | Face extérieure | Peinture-01 | Mur-153 | 1-Projet | Sejour cuisine/pl | A34 | Etage 3 | 6
Mur-149 | Etage 3 | 0 | 0 | 3000 | 3000 | 0 | 0 | 0.202008 | 0 | 0 | 949.944 | 2.67583 | 2.88583 | 0 | 1199.94 | 949.943 | 2.67583 | 949.945 | 2.88583 | 0.202008 | 2.88583 | 2.88583 | 949.943 | 949.945 | 0 | 0.0790957 | 3000 | 0.202008 | 11550 | 1129.94 | 0.202008 | 2039.89 | 14550 | 3000 | 11550 | 0 | 0.578191 | Face extérieure | Lavis blanc | Mur-149 | 1-Projet | Sdb | B34 | Etage 3 | 6
Mur-149 | Etage 3 | 0 | 0 | 2512.25 | 2512.25 | 0 | 0 | 0.11167 | 0 | 0 | 635 | 1.68321 | 1.50735 | 0 | 670 | 670 | 1.68321 | 600 | 1.50735 | 0.11167 | 1.68321 | 1.50735 | 670 | 600 | 0 | 0.04445 | 2512.25 | 0.11167 | 11550 | 670 | 0.11167 | 1438.99 | 14062.3 | 2512.25 | 11550 | 0 | 0.513458 | Face intérieure | Surface-Blanche | Mur-149 | 1-Projet | Ch 1/pl | B33 | Etage 3 | 6
Mur-149 | Etage 3 | 1 | 0 | 3000 | 3000 | 1.224 | 600 | 0.0522943 | 1.2505 | 1.2505 | 665.854 | 0.852061 | 0.642061 | 0.087535 | 700.854 | 90.8537 | 2.10256 | 20.8537 | 1.89256 | 0.139829 | 2.10256 | 1.89256 | 700.854 | 630.854 | 0 | 0.00390976 | 3000 | 0.0522943 | 11550 | 700.854 | 0.139829 | 1500.7 | 14550 | 3000 | 11550 | 0 | 0.414004 | Face intérieure | Surface-Blanche | Mur-149 | 1-Projet | Sejour cuisine/pl | B31 | Etage 3 | 6
Mur-149 | Etage 3 | 0 | 0 | 2500 | 2500 | 0 | 0 | 0.345196 | 0 | 0 | 1972.55 | 4.64787 | 4.73888 | 0 | 2117.55 | 1937.55 | 4.64787 | 2007.55 | 4.73888 | 0.345196 | 5.42514 | 5.62114 | 1937.55 | 2007.55 | 0 | 0.138079 | 2800 | 0.345196 | 11550 | 2007.55 | 0.38662 | 4114.09 | 14050 | 2500 | 11550 | 0 | 0.560566 | Face extérieure | Lavis blanc | Mur-149 | 1-Projet | Ch 1/pl | B34 | Etage 3 | 6 | ArchiCADProperties - Zones conflictuelles: Ch 1/pl
Mur-149 | Etage 3 | 0 | 0 | 3000 | 3000 | 0 | 0 | 0.32606 | 0 | 0 | 1555 | 4.56 | 4.756 | 0 | 1520 | 1520 | 4.56 | 1590 | 4.756 | 0.32606 | 4.56 | 4.756 | 1520 | 1590 | 0 | 0.10885 | 3000 | 0.32606 | 11550 | 1590 | 0.32606 | 3278.99 | 14550 | 3000 | 11550 | 0 | 0.718889 | Face extérieure | Lavis blanc | Mur-149 | 1-Projet | Sejour cuisine | B34 | Etage 3 | 6
Mur-149 | Etage 3 | 0 | 0 | 2800 | 2800 | 0 | 0 | 0.180297 | 0 | 0 | 919.883 | 2.57567 | 2.57568 | 0 | 1199.88 | 919.882 | 2.57567 | 919.884 | 2.57568 | 0.180297 | 2.57567 | 2.57568 | 919.882 | 919.884 | 0 | 0.0643918 | 2800 | 0.180297 | 11550 | 919.884 | 0.180297 | 1979.77 | 14350 | 2800 | 11550 | 0 | 0.520784 | Face extérieure | Lavis blanc | Mur-149 | 1-Projet | Dgt/pl | B34 | Etage 3 | 6
Mur-149 | Etage 3 | 0 | 0 | 2700 | 2700 | 0 | 0 | 0.122865 | 0 | 0 | 650.081 | 1.75522 | 1.75522 | 0 | 720.081 | 650.081 | 1.75522 | 650.081 | 1.75522 | 0.122865 | 1.75522 | 1.75522 | 650.081 | 650.081 | 0 | 0.0455056 | 2700 | 0.122865 | 11550 | 650.081 | 0.122865 | 1440.16 | 14250 | 2700 | 11550 | 0 | 0.469011 | Face intérieure | Peinture-01 | Mur-149 | 1-Projet | Entree/pl | B35 | Etage 3 | 6
Mur-149 | Etage 3 | 0 | 0 | 2700 | 2500 | 0 | 0 | 0.747055 | 0 | 0 | 3966.01 | 10.6722 | 10.6722 | 0 | 4376.01 | 3966.01 | 10.6722 | 3966.01 | 10.6722 | 0.747055 | 10.7082 | 10.7082 | 3966.01 | 3966.01 | 0 | 0.277621 | 2700 | 0.747055 | 11550 | 3966.01 | 0.749575 | 8072.02 | 14250 | 2700 | 11550 | 0 | 0.920641 | Face intérieure | Peinture-01 | Mur-149 | 1-Projet | Ch 2 | B35 | Etage 3 | 6
Mur-149 | Etage 3 | 2 | 0 | 3000 | 2500 | 3.1824 | 1560 | 0.2521 | 3.5776 | 3.5776 | 2413.84 | 3.68892 | 3.30392 | 0.250432 | 2788.84 | 728.841 | 7.26652 | 658.841 | 6.88152 | 0.502532 | 7.34652 | 7.15052 | 2448.84 | 2378.84 | 0 | 0.0485689 | 3000 | 0.2521 | 11550 | 2448.84 | 0.507397 | 4996.68 | 14550 | 3000 | 11550 | 0 | 0.666275 | Face extérieure | Lavis blanc | Mur-149 | 1-Projet | Ch 1/pl | B34 | Etage 3 | 6 | ArchiCADProperties - Zones conflictuelles: Ch 1/pl
Mur-149 | Etage 3 | 1 | 0 | 2512.25 | 2512.25 | 3.10624 | 1553.12 | 0.0618462 | 3.10625 | 3.10625 | 1588.12 | 0.971446 | 0.795589 | 0.217437 | 1623.12 | 70 | 0.971451 | 0 | 0.795593 | 0.279284 | 4.0777 | 3.90184 | 1623.12 | 1553.12 | 0 | 0.00245 | 2512.25 | 0.0618462 | 11550 | 1623.12 | 0.279284 | 3345.24 | 14062.3 | 2512.25 | 11550 | 0 | 0.398176 | Face intérieure | Surface-Blanche | Mur-149 | 1-Projet | Ch 1/pl | B33 | Etage 3 | 6 | ArchiCADProperties - Zones conflictuelles: Ch 1/pl
Mur-149 | Etage 3 | 0 | 0 | 2500 | 2500 | 0 | 0 | 0.237246 | 0 | 0 | 1355.69 | 3.30173 | 3.47673 | 0 | 1390.69 | 1320.69 | 3.30173 | 1390.69 | 3.47673 | 0.237246 | 3.30173 | 3.47673 | 1320.69 | 1390.69 | 0 | 0.0948985 | 2500 | 0.237246 | 11550 | 1390.69 | 0.237246 | 2880.38 | 14050 | 2500 | 11550 | 0 | 0.612284 | Face intérieure | Peinture-01 | Mur-149 | 1-Projet | Sejour cuisine/pl | B35 | Etage 3 | 6
Mur-153 | Etage 3 | 0 | 0 | 3000 | 3000 | 0 | 0 | 0.0598081 | 0 | 0 | 284.801 | 0.95937 | 0.749433 | 0 | 429.811 | 319.79 | 0.95937 | 249.811 | 0.749433 | 0.0598081 | 0.95937 | 0.749433 | 319.79 | 249.811 | 0 | 0.019936 | 3000 | 0.0598081 | 11550 | 319.811 | 0.0598081 | 738.596 | 14550 | 3000 | 11550 | 0 | 0.546857 | Face extérieure | Peinture-01 | Mur-153 | 1-Projet | Sejour cuisine | A32 | Etage 3 | 6
Mur-153 | Etage 3 | 1 | 0 | 3000 | 0 | 1.6932 | 830 | 0.408336 | 1.8928 | 1.8928 | 2655.13 | 5.62336 | 5.83337 | 0.132496 | 2655.13 | 1745.13 | 7.51616 | 1745.13 | 7.72617 | 0.540832 | 7.7554 | 7.7554 | 2655.13 | 2655.13 | 0 | 0.117259 | 3000 | 0.408336 | 11550 | 2585.14 | 0.542878 | 5450.27 | 14550 | 3000 | 11550 | 0 | 0.704219 | Face extérieure | Peinture-01 | Mur-153 | 1-Projet | Sejour cuisine | A32 | Etage 3 | 6
Mur-149 | Etage 3 | 2 | 0 | 2700 | 2500 | 3.3864 | 1660 | 0.820912 | 3.7856 | 3.7856 | 5748.12 | 11.4508 | 11.2618 | 0.264992 | 5713.12 | 3963.12 | 15.2364 | 3893.12 | 15.0474 | 1.0859 | 15.6144 | 15.4254 | 5783.12 | 5713.12 | 0 | 0.274968 | 2700 | 0.820912 | 11550 | 5783.12 | 1.08639 | 11665.2 | 14250 | 2700 | 11550 | 0 | 1.11137 | Face intérieure | Peinture-01 | Mur-149 | 1-Projet | Sejour cuisine/pl | B35 | Etage 3 | 6
Mur-149 | Etage 3 | 0 | 0 | 2700 | 2700 | 0 | 0 | 0.169816 | 0 | 0 | 898.496 | 2.42594 | 2.23694 | 0 | 1078.5 | 898.496 | 2.42594 | 898.496 | 2.23694 | 0.169816 | 2.42594 | 2.42594 | 898.496 | 898.496 | 0 | 0.0628947 | 2700 | 0.169816 | 11550 | 898.496 | 0.169816 | 1936.99 | 14250 | 2700 | 11550 | 0 | 0.503789 | Face intérieure | Peinture-01 | Mur-149 | 1-Projet | Sde | B35 | Etage 3 | 6 | ArchiCADProperties - Zones conflictuelles: Sde
Mur-149 | Etage 3 | 1 | 1 | 2500 | 2500 | 1.6932 | 830 | 0.17629 | 3.8274 | 3.8274 | 2538.33 | 2.51843 | 2.34343 | 0.267918 | 2718.33 | 680 | 6.34583 | 680 | 6.17083 | 0.444208 | 6.34583 | 6.34583 | 2538.33 | 2538.33 | 1.9346 | 0.0476 | 2500 | 0.17629 | 11550 | 2538.33 | 0.444208 | 5216.66 | 14050 | 2500 | 11550 | 0 | 0.432483 | Face intérieure | Peinture-01 | Mur-149 | 1-Projet | Sejour cuisine/pl | B35 | Etage 3 | 6
Mur-149 | Etage 3 | 0 | 0 | 3000 | 3000 | 0 | 0 | 0.209355 | 0 | 0 | 984.928 | 2.67578 | 3.09578 | 0 | 1199.92 | 949.929 | 2.67578 | 1019.93 | 3.09578 | 0.209355 | 2.88578 | 3.09578 | 949.929 | 1019.93 | 0 | 0.0815445 | 3000 | 0.209355 | 11550 | 1199.92 | 0.209355 | 2138.85 | 14550 | 3000 | 11550 | 0 | 0.670072 | Face extérieure | Lavis blanc | Mur-149 | 1-Projet | Dgt/pl | B34 | Etage 3 | 6
Mur-149 | Etage 3 | 1 | 0 | 2800 | 2800 | 4.65858 | 2329.29 | 0.260295 | 4.65858 | 4.65858 | 2991.82 | 3.53246 | 3.70854 | 0.326101 | 3276.81 | 666.081 | 3.53246 | 658.967 | 3.70854 | 0.586396 | 8.38704 | 8.36712 | 2995.37 | 2988.26 | 0 | 0.0463767 | 2800 | 0.260295 | 11550 | 2995.37 | 0.586396 | 6123.99 | 14350 | 2800 | 11550 | 0 | 0.648813 | Face intérieure | Surface-Blanche | Mur-149 | 1-Projet | Ch 1/pl | B31 | Etage 3 | 6 | ArchiCADProperties - Zones conflictuelles: Ch 1/pl
Mur-149 | Etage 3 | 0 | 0 | 3000 | 3000 | 0 | 0 | 0.710782 | 0 | 0 | 3382.34 | 10.252 | 10.056 | 0 | 3757.34 | 3417.34 | 10.252 | 3347.34 | 10.056 | 0.710782 | 10.252 | 10.056 | 3417.34 | 3347.34 | 0 | 0.239214 | 3000 | 0.710782 | 11550 | 3417.34 | 0.710782 | 6933.68 | 14550 | 3000 | 11550 | 0 | 0.979614 | Face extérieure | Lavis blanc | Mur-149 | 1-Projet | Ch 2 | B34 | Etage 3 | 6
Mur-149 | Etage 3 | 0 | 0 | 2700 | 2700 | 0 | 0 | 0.0558414 | 0 | 0 | 295.457 | 0.892292 | 0.703176 | 0 | 330.478 | 330.478 | 0.892292 | 260.436 | 0.703176 | 0.0558414 | 0.892292 | 0.703176 | 330.478 | 260.436 | 0 | 0.020682 | 2700 | 0.0558414 | 11550 | 330.489 | 0.0558414 | 759.947 | 14250 | 2700 | 11550 | -1.77636e-12 | 0.497753 | Face intérieure | Surface-Blanche | Mur-149 | 1-Projet |  |  | Etage 3 | 6
Mur-149 | Etage 3 | 0 | 0 | 3000 | 3000 | 0 | 0 | 0.148916 | 0 | 0 | 709.124 | 2.23237 | 2.02237 | 0 | 924.124 | 744.124 | 2.23237 | 674.124 | 2.02237 | 0.148916 | 2.23237 | 2.02237 | 744.124 | 674.124 | 0 | 0.0496387 | 3000 | 0.148916 | 11550 | 744.124 | 0.148916 | 1587.24 | 14550 | 3000 | 11550 | 0 | 0.606262 | Face intérieure | Surface-Blanche | Mur-149 | 1-Projet | Sdb | B34 | Etage 3 | 6
Mur-149 | Etage 3 | 0 | 0 | 3000 | 3000 | 0 | 0 | 0.0840974 | 0 | 0 | 400.464 | 1.41139 | 0.991392 | 0 | 470.464 | 470.464 | 1.41139 | 330.464 | 0.991392 | 0.0840974 | 1.41139 | 0.991392 | 470.464 | 330.464 | 0 | 0.0280325 | 3000 | 0.0840974 | 11550 | 470.464 | 0.0840974 | 998.918 | 14550 | 3000 | 11550 | 0 | 0.650035 | Face intérieure | Surface-Blanche | Mur-149 | 1-Projet | Sdb | B34 | Etage 3 | 6 | ArchiCADProperties - Zones conflictuelles: Sdb
Mur-149 | Etage 3 | 0 | 0 | 3000 | 2500 | 0 | 0 | 0.1785 | 0 | 0 | 864.998 | 2.445 | 2.655 | 0 | 969.998 | 829.998 | 2.445 | 899.998 | 2.655 | 0.1785 | 2.504 | 2.714 | 829.998 | 899.998 | 0 | 0.0605499 | 3000 | 0.1785 | 11550 | 899.998 | 0.18263 | 1898.99 | 14550 | 3000 | 11550 | 0 | 0.586785 | Face extérieure | Lavis blanc | Mur-149 | 1-Projet | Ch 1/pl | B34 | Etage 3 | 6
Mur-149 | Etage 3 | 0 | 0 | 3000 | 3000 | 0 | 0 | 0.126001 | 0 | 0 | 600.004 | 1.80001 | 1.80001 | 0 | 740.003 | 600.004 | 1.80001 | 600.003 | 1.80001 | 0.126001 | 1.80001 | 1.80001 | 600.004 | 600.003 | 0 | 0.0420003 | 3000 | 0.126001 | 11550 | 600.004 | 0.126001 | 1340.01 | 14550 | 3000 | 11550 | 0 | 0.504001 | Face extérieure | Lavis blanc | Mur-149 | 1-Projet |  |  | Etage 3 | 6
Mur-121 | Etage 3 | 0 | 0 | 3000 | 3000 | 0 | 0 | 0.0693254 | 0 | 0 | 330.121 | 0.990363 | 0.990363 | 0 | 400.121 | 330.121 | 0.990363 | 330.121 | 0.990363 | 0.0693254 | 0.990363 | 0.990363 | 330.121 | 330.121 | 0 | 0.0231085 | 3000 | 0.0693254 | 11550 | 330.121 | 0.0693254 | 800.242 | 14550 | 3000 | 11550 | 0 | 0.466217 | Face extérieure | Lavis blanc | Mur-121 | 1-Projet |  |  | Etage 3 | 6
Mur-149 | Etage 3 | 0 | 0 | 3000 | 3000 | 0 | 0 | 0.13283 | 0 | 0 | 632.525 | 1.79258 | 2.00258 | 0 | 667.525 | 597.525 | 1.79258 | 667.525 | 2.00258 | 0.13283 | 1.79258 | 2.00258 | 597.525 | 667.525 | 0 | 0.0442768 | 3000 | 0.13283 | 11550 | 667.525 | 0.13283 | 1434.05 | 14550 | 3000 | 11550 | 0 | 0.595538 | Face extérieure | Lavis blanc | Mur-149 | 1-Projet | Ch 1/pl | B34 | Etage 3 | 6
Mur-149 | Etage 3 | 0 | 0 | 2700 | 2700 | 0 | 0 | 0.13375 | 0 | 0 | 707.673 | 2.00529 | 1.81614 | 0 | 742.7 | 742.7 | 2.00529 | 672.646 | 1.81614 | 0.13375 | 2.00529 | 1.81614 | 742.7 | 672.646 | 0 | 0.0495371 | 2700 | 0.13375 | 11550 | 742.7 | 0.13375 | 1584.38 | 14250 | 2700 | 11550 | 0 | 0.555463 | Face intérieure | Surface-Blanche | Mur-149 | 1-Projet |  |  | Etage 3 | 6
Mur-120 | Etage 3 | 5 | 0 | 3000 | 3000 | 5.61 | 2750 | 0.356614 | 5.8425 | 5.8425 | 3645.66 | 4.04448 | 4.67448 | 0.408975 | 3645.66 | 795.661 | 9.88698 | 795.661 | 10.517 | 0.765589 | 10.937 | 10.937 | 3645.66 | 3645.66 | 0 | 0.0556963 | 3000 | 0.356614 | 11550 | 3645.66 | 0.765589 | 7431.32 | 14550 | 3000 | 11550 | 0 | 0.730893 | Face extérieure | Lavis blanc | Mur-120 | 3D |  |  | Etage 3 | 6
Mur-121 | Etage 3 | 0 | 0 | 3000 | 0 | 0 | 0 | 0.0690435 | 0 | 0 | 398.779 | 0.986336 | 0.986336 | 0 | 398.779 | 398.779 | 0.986336 | 398.779 | 0.986336 | 0.0690435 | 0.986336 | 0.986336 | 398.779 | 398.779 | 0 | 0.0230145 | 3000 | 0.0690435 | 11550 | 328.779 | 0.0690435 | 937.557 | 14550 | 3000 | 11550 | 0 | 0.466029 | Face extérieure | Lavis blanc | Mur-121 | 1-Projet |  |  | Etage 3 | 6
Mur-120 | Etage 3 | 0 | 0 | 2460 | 2460 | 0 | 0 | 0.0869144 | 0 | 0 | 504.729 | 1.41383 | 1.06943 | 0 | 915.562 | 574.729 | 1.41383 | 434.729 | 1.06943 | 0.0869144 | 1.41383 | 1.06943 | 574.729 | 434.729 | 0 | 0.035331 | 2460 | 0.0869144 | 11550 | 574.729 | 0.0869144 | 1207.45 | 14010 | 2460 | 11550 | 0 | 0.557717 | Face extérieure | Lavis blanc | Mur-120 | 3D |  |  | Etage 3 | 6
Mur-149 | Etage 3 | 0 | 0 | 2800 | 2500 | 0 | 0 | 0.464363 | 0 | 0 | 2378.84 | 6.63376 | 6.63376 | 0 | 2718.84 | 2378.84 | 6.63376 | 2378.84 | 6.63376 | 0.464363 | 6.66075 | 6.66076 | 2378.84 | 2378.84 | 0 | 0.166519 | 2800 | 0.464363 | 11550 | 2378.84 | 0.466253 | 4897.68 | 14350 | 2800 | 11550 | 0 | 0.697738 | Face extérieure | Lavis blanc | Mur-149 | 1-Projet | Sde | B34 | Etage 3 | 6 | ArchiCADProperties - Zones conflictuelles: Sde
Mur-149 | Etage 3 | 1 | 0 | 2700 | 2700 | 3.44032 | 1720.16 | 0.090903 | 3.44032 | 3.44032 | 1755.16 | 1.39311 | 1.20411 | 0.240823 | 1790.16 | 70 | 1.39311 | 0 | 1.20411 | 0.331726 | 4.83344 | 4.64444 | 1790.16 | 1720.16 | 0 | 0.00245 | 2700 | 0.090903 | 11550 | 1790.16 | 0.331726 | 3679.32 | 14250 | 2700 | 11550 | 0 | 0.441598 | Face intérieure | Peinture-01 | Mur-149 | 1-Projet | Ch 1/pl | B35 | Etage 3 | 6 | ArchiCADProperties - Zones conflictuelles: Ch 1/pl
Mur-153 | Etage 3 | 0 | 1 | 960 | 960 | 0 | 0 | 0.091392 | 2.77441 | 2.7744 | 1360 | 1.3056 | 1.3056 | 0.194208 | 1700 | 6.88338e-12 | 1.30561 | 6.88338e-12 | 1.3056 | 0.2856 | 4.08001 | 4.08 | 1360 | 1360 | 2.7744 | 0 | 3000 | 0.091392 | 11550 | 1360 | 0.2856 | 2860 | 14550 | 3000 | 13590 | 2040 | 0.2296 | Face extérieure | Peinture-01 | Mur-153 | 1-Projet | Dressing | A34 | Etage 3 | 6
Mur-121 | Etage 3 | 0 | 0 | 3000 | 0 | 0 | 0 | 0.0691482 | 0 | 0 | 399.277 | 0.987831 | 0.987831 | 0 | 399.277 | 399.277 | 0.987831 | 399.277 | 0.987831 | 0.0691482 | 0.987831 | 0.987831 | 399.277 | 399.277 | 0 | 0.0230494 | 3000 | 0.0691482 | 11550 | 329.277 | 0.0691482 | 938.554 | 14550 | 3000 | 11550 | 0 | 0.466099 | Face extérieure | Lavis blanc | Mur-121 | 1-Projet |  |  | Etage 3 | 6
Mur-149 | Etage 3 | 1 | 0 | 2800 | 2800 | 1.6932 | 830 | 0.259597 | 1.8928 | 1.8928 | 2000.47 | 3.61052 | 3.61052 | 0.132496 | 1965.47 | 1125.47 | 5.50332 | 1055.47 | 5.50332 | 0.392093 | 5.69932 | 5.50332 | 2035.47 | 1965.47 | 0 | 0.076333 | 2800 | 0.259597 | 11550 | 2035.47 | 0.392093 | 4169.94 | 14350 | 2800 | 11550 | 0 | 0.689552 | Face intérieure | Surface-Blanche | Mur-149 | 1-Projet | Ch 1/pl | B31 | Etage 3 | 6
Mur-149 | Etage 3 | 0 | 0 | 3000 | 3000 | 0 | 0 | 0.11857 | 0 | 0 | 564.618 | 1.79885 | 1.58885 | 0 | 879.618 | 599.618 | 1.79885 | 529.618 | 1.58885 | 0.11857 | 1.79885 | 1.58885 | 599.618 | 529.618 | 0 | 0.0395233 | 3000 | 0.11857 | 11550 | 599.618 | 0.11857 | 1298.23 | 14550 | 3000 | 11550 | 0 | 0.586031 | Face intérieure | Surface-Blanche | Mur-149 | 1-Projet | Sejour cuisine/pl | B31 | Etage 3 | 6
Mur-121 | Etage 3 | 0 | 0 | 3000 | 3000 | 0 | 0 | 0.117519 | 0 | 0 | 553.613 | 1.45084 | 1.69684 | 0 | 553.614 | 553.612 | 1.45084 | 553.614 | 1.69684 | 0.117519 | 1.66084 | 1.69684 | 553.612 | 553.614 | 0 | 0.045053 | 3000 | 0.117519 | 11550 | 733.614 | 0.117519 | 1247.23 | 14550 | 3000 | 11550 | 0 | 0.534733 | Face extérieure | Lavis blanc | Mur-121 | 1-Projet | Sejour cuisine | B33 | Etage 3 | 6
Mur-152 | Etage 3 | 0 | 0 | 3000 | 3000 | 0 | 0 | 0.0567183 | 0 | 0 | 270.087 | 0.810265 | 0.810257 | 0 | 340.086 | 270.088 | 0.810265 | 270.086 | 0.810257 | 0.0567183 | 0.810265 | 0.810257 | 270.088 | 270.086 | 0 | 0.0189061 | 3000 | 0.0567183 | 11550 | 270.088 | 0.0567183 | 680.174 | 14550 | 3000 | 11550 | 0 | 0.457812 | Face extérieure | Peinture-01 | Mur-152 | 1-Projet | Sejour cuisine | A32 | Etage 3 | 6
Mur-149 | etage 4 | 0 | 0 | 3000 | 3000 | 0 | 0 | 0.149087 | 0 | 0 | 709.938 | 2.23481 | 2.02481 | 0 | 744.938 | 744.938 | 2.23481 | 674.938 | 2.02481 | 0.149087 | 2.23481 | 2.02481 | 744.938 | 674.938 | 0 | 0.0496957 | 3000 | 0.149087 | 14600 | 744.938 | 0.149087 | 1588.87 | 17600 | 3000 | 14600 | 0 | 0.606376 | Face intérieure | Surface-Blanche | Mur-149 | 1-Projet | Sejour cuisine | B53 | etage 4 | 7
Mur-121 | Etage 3 | 0 | 0 | 3000 | 3000 | 0 | 0 | 0.1071 | 0 | 0 | 509.992 | 1.02598 | 1.02597 | 0 | 579.993 | 509.993 | 1.02598 | 509.991 | 1.02597 | 0.1071 | 1.52998 | 1.52997 | 509.993 | 509.991 | 0 | 0.0357 | 3000 | 0.1071 | 11550 | 509.993 | 0.1071 | 1159.98 | 14550 | 3000 | 11550 | 0 | 0.491407 | Face extérieure | Lavis blanc | Mur-121 | 1-Projet | Sejour cuisine | B33 | Etage 3 | 6
Mur-149 | etage 4 | 0 | 0 | 3000 | 3000 | 0 | 0 | 0.0945991 | 0 | 0 | 450.472 | 1.24642 | 1.45642 | 0 | 415.472 | 415.472 | 1.24642 | 485.472 | 1.45642 | 0.0945991 | 1.24642 | 1.45642 | 415.472 | 485.472 | 0 | 0.031533 | 3000 | 0.0945991 | 14600 | 485.472 | 0.0945991 | 1069.94 | 17600 | 3000 | 14600 | 0 | 0.570051 | Face intérieure | Surface-Blanche | Mur-149 | 1-Projet | Sejour cuisine/pl | B41 | etage 4 | 7
Mur-121 | etage 4 | 0 | 0 | 3000 | 0 | 0 | 0 | 0.0742906 | 0 | 0 | 400.098 | 1.06129 | 1.06129 | 0 | 580.098 | 400.098 | 1.06129 | 400.098 | 1.06129 | 0.0742906 | 1.06129 | 1.06129 | 400.098 | 400.098 | 0 | 0.0406069 | 3000 | 0.0742906 | 14600 | 580.098 | 0.0742906 | 940.196 | 17600 | 3000 | 14600 | 0 | 0.496314 | Face extérieure | Lavis blanc | Mur-121 | 1-Projet |  |  | etage 4 | 7
Mur-121 | etage 4 | 0 | 0 | 3000 | 0 | 0 | 0 | 0.074285 | 0 | 0 | 400.072 | 1.06121 | 1.06121 | 0 | 580.072 | 400.072 | 1.06121 | 400.072 | 1.06121 | 0.074285 | 1.06121 | 1.06121 | 400.072 | 400.072 | 0 | 0.040605 | 3000 | 0.074285 | 14600 | 580.072 | 0.074285 | 940.143 | 17600 | 3000 | 14600 | 0 | 0.49631 | Face extérieure | Lavis blanc | Mur-121 | 1-Projet |  |  | etage 4 | 7
Mur-149 | etage 4 | 0 | 0 | 3000 | 0 | 0 | 0 | 0.124599 | 0 | 0 | 628.555 | 1.88498 | 1.67498 | 0 | 593.555 | 663.555 | 1.88498 | 593.555 | 1.67498 | 0.124599 | 1.88498 | 1.67498 | 663.555 | 593.555 | 0 | 0.0415329 | 3000 | 0.124599 | 14600 | 628.327 | 0.124599 | 1426.11 | 17600 | 3000 | 14600 | 0 | 0.380051 | Face intérieure | Surface-Blanche | Mur-149 | 1-Projet | Sejour cuisine | B43 | etage 4 | 7
Mur-149 | etage 4 | 0 | 0 | 3000 | 3000 | 0 | 0 | 0.378734 | 0 | 0 | 1791.5 | 5.30549 | 5.51549 | 0 | 2006.5 | 1756.5 | 5.30549 | 1826.5 | 5.51549 | 0.378734 | 5.30549 | 5.51549 | 1756.5 | 1826.5 | 0 | 0.138005 | 3000 | 0.378734 | 14600 | 2006.5 | 0.378734 | 3751.99 | 17600 | 3000 | 14600 | 0 | 0.782994 | Face extérieure | Lavis blanc | Mur-149 | 1-Projet | Ch 2 | B44 | etage 4 | 7
Mur-150 | etage 4 | 0 | 0 | 3000 | 3000 | 0 | 0 | 0.184209 | 0 | 0 | 865.185 | 2.73617 | 2.52694 | 0 | 1080.06 | 900.056 | 2.73617 | 830.313 | 2.52694 | 0.184209 | 2.73617 | 2.52694 | 900.056 | 830.313 | 0 | 0.0731629 | 3000 | 0.184209 | 14600 | 1080.06 | 0.184209 | 1899.18 | 17600 | 3000 | 14600 | 0 | 0.652767 | Face intérieure | Surface-Blanche | Mur-150 | 1-Projet | Sde | B42 | etage 4 | 7
Mur-149 | etage 4 | 0 | 0 | 3000 | 3000 | 0 | 0 | 0.13335 | 0 | 0 | 635 | 1.8 | 2.01 | 0 | 600 | 600 | 1.8 | 670 | 2.01 | 0.13335 | 1.8 | 2.01 | 600 | 670 | 0 | 0.04445 | 3000 | 0.13335 | 14600 | 670 | 0.13335 | 1438.99 | 17600 | 3000 | 14600 | 0 | 0.595885 | Face intérieure | Surface-Blanche | Mur-149 | 1-Projet | Sejour cuisine/pl | B41 | etage 4 | 7
2 x Mur-121 | etage 4 | 0 | 0 | 3000 | 0 | 0 | 0 | 0.0742809 | 0 | 0 | 400.052 | 1.06116 | 1.06116 | 0 | 580.052 | 400.052 | 1.06116 | 400.052 | 1.06116 | 0.0742809 | 1.06116 | 1.06116 | 400.052 | 400.052 | 0 | 0.0406037 | 3000 | 0.0742809 | 14600 | 580.052 | 0.0742809 | 940.104 | 17600 | 3000 | 14600 | 0 | 0.496307 | Face extérieure | Lavis blanc | Mur-121 | 1-Projet |  |  | etage 4 | 7
Mur-149 | etage 4 | 0 | 0 | 3000 | 3000 | 0 | 0 | 0.0651702 | 0 | 0 | 310.334 | 0.721003 | 1.141 | 0 | 310.334 | 240.334 | 0.721003 | 380.334 | 1.141 | 0.0651702 | 0.721003 | 1.141 | 240.334 | 380.334 | 0 | 0.0217234 | 3000 | 0.0651702 | 14600 | 380.334 | 0.0651702 | 818.659 | 17600 | 3000 | 14600 | 0 | 0.637417 | Face intérieure | Surface-Blanche | Mur-149 | 1-Projet | Sejour cuisine/pl | B41 | etage 4 | 7
Mur-149 | etage 4 | 0 | 0 | 3000 | 3000 | 0 | 0 | 0.399067 | 0 | 0 | 1900.32 | 5.19695 | 4.98695 | 0 | 1970.32 | 1900.32 | 5.19695 | 1900.32 | 4.98695 | 0.399067 | 5.70095 | 5.70095 | 1900.32 | 1900.32 | 0 | 0.133022 | 3000 | 0.399067 | 14600 | 1900.32 | 0.399067 | 3940.63 | 17600 | 3000 | 14600 | 0 | 0.686044 | Face intérieure | Surface-Blanche | Mur-149 | 1-Projet | Wc | B42 | etage 4 | 7
Mur-150 | etage 4 | 2 | 0 | 3000 | 3000 | 2.8764 | 1410 | 0.439453 | 3.1228 | 3.1228 | 3121.57 | 6.2779 | 5.8579 | 0.218596 | 3371.57 | 1611.57 | 9.4007 | 1611.57 | 8.9807 | 0.658049 | 9.4007 | 9.4007 | 3121.57 | 3121.57 | 0 | 0.12541 | 3000 | 0.439453 | 14600 | 3301.57 | 0.658049 | 6383.13 | 17600 | 3000 | 14600 | 0 | 0.776519 | Face intérieure | Surface-Blanche | Mur-150 | 1-Projet | Sde | B42 | etage 4 | 7
Mur-149 | etage 4 | 0 | 0 | 3000 | 0 | 0 | 0 | 0.832976 | 0 | 0 | 4036.55 | 11.8997 | 11.8997 | 0 | 4376.55 | 4036.55 | 11.8997 | 4036.55 | 11.8997 | 0.832976 | 11.8997 | 11.8997 | 4036.55 | 4036.55 | 0 | 0.277659 | 3000 | 0.832976 | 14600 | 3966.55 | 0.832976 | 8213.09 | 17600 | 3000 | 14600 | 0 | 0.765317 | Face intérieure | Surface-Blanche | Mur-149 | 1-Projet | Ch 2 | B42 | etage 4 | 7
Mur-150 | etage 4 | 0 | 0 | 3000 | 3000 | 0 | 0 | 0.18418 | 0 | 0 | 865.05 | 2.73615 | 2.52615 | 0 | 1080.05 | 900.05 | 2.73615 | 830.049 | 2.52615 | 0.18418 | 2.73615 | 2.52615 | 900.05 | 830.049 | 0 | 0.0731535 | 3000 | 0.18418 | 14600 | 1080.05 | 0.18418 | 1899.09 | 17600 | 3000 | 14600 | 0 | 0.653292 | Face intérieure | Surface-Blanche | Mur-150 | 1-Projet | Sde | B42 | etage 4 | 7
Mur-149 | etage 4 | 0 | 0 | 3000 | 3000 | 0 | 0 | 0.18417 | 0 | 0 | 865 | 2.736 | 2.52599 | 0 | 1080 | 900 | 2.736 | 830 | 2.52599 | 0.18417 | 2.736 | 2.52599 | 900 | 830 | 0 | 0.0731489 | 3000 | 0.18417 | 14600 | 1080 | 0.18417 | 1899.02 | 17600 | 3000 | 14600 | 0 | 0.653352 | Face intérieure | Surface-Blanche | Mur-149 | 1-Projet | Sde | B43 | etage 4 | 7
Mur-149 | etage 4 | 0 | 0 | 3000 | 3000 | 0 | 0 | 0.140333 | 0 | 0 | 668.251 | 1.89975 | 2.10975 | 0 | 703.251 | 633.251 | 1.89975 | 703.251 | 2.10975 | 0.140333 | 1.89975 | 2.10975 | 633.251 | 703.251 | 0 | 0.0467776 | 3000 | 0.140333 | 14600 | 703.251 | 0.140333 | 1505.5 | 17600 | 3000 | 14600 | 0 | 0.60054 | Face intérieure | Surface-Blanche | Mur-149 | 1-Projet |  |  | etage 4 | 7
Mur-149 | etage 4 | 0 | 0 | 3000 | 3000 | 0 | 0 | 0.35271 | 0 | 0 | 1679.57 | 4.93372 | 4.93371 | 0 | 1784.57 | 1644.57 | 4.93372 | 1714.57 | 4.93371 | 0.35271 | 4.93372 | 5.14371 | 1644.57 | 1714.57 | 0 | 0.11757 | 3000 | 0.35271 | 14600 | 1714.57 | 0.35271 | 3528.14 | 17600 | 3000 | 14600 | -1.77636e-12 | 0.742124 | Face extérieure | Lavis blanc | Mur-149 | 1-Projet | Sejour cuisine | B42 | etage 4 | 7
Mur-149 | etage 4 | 1 | 0 | 2500 | 2500 | 1.6932 | 830 | 0.381249 | 1.8928 | 1.8928 | 2935.69 | 5.44641 | 5.44641 | 0.132496 | 3345.69 | 2025.69 | 7.33921 | 2025.69 | 7.33921 | 0.513745 | 7.33921 | 7.33921 | 2935.69 | 2935.69 | 0 | 0.141798 | 2500 | 0.381249 | 14600 | 2935.69 | 0.513745 | 6011.37 | 17100 | 2500 | 14600 | 0 | 0.697296 | Face intérieure | Surface-Blanche | Mur-149 | 1-Projet | Sejour cuisine/pl | B41 | etage 4 | 7
Mur-149 | etage 4 | 1 | 0 | 2500 | 2500 | 4.53796 | 2268.98 | 0.203791 | 4.53796 | 4.53796 | 2979.71 | 2.74519 | 2.90241 | 0.317658 | 3325.01 | 714.281 | 2.74519 | 707.168 | 2.90241 | 0.521449 | 7.45816 | 7.44038 | 2983.26 | 2976.15 | 0 | 0.0497507 | 2500 | 0.203791 | 14600 | 2983.26 | 0.521449 | 6099.77 | 17100 | 2500 | 14600 | 0 | 0.609232 | Face intérieure | Surface-Blanche | Mur-149 | 1-Projet | Ch 1/pl | B41 | etage 4 | 7 | ArchiCADProperties - Zones conflictuelles: Ch 1/pl
Mur-149 | etage 4 | 0 | 0 | 3000 | 3000 | 0 | 0 | 0.539556 | 0 | 0 | 2571.65 | 7.39994 | 7.80594 | 0 | 2536.65 | 2536.65 | 7.39994 | 2606.65 | 7.80594 | 0.539556 | 7.60994 | 7.80594 | 2536.65 | 2606.65 | 0 | 0.180015 | 3000 | 0.539556 | 14600 | 2606.65 | 0.539556 | 5312.29 | 17600 | 3000 | 14600 | 0 | 0.861216 | Face intérieure | Surface-Blanche | Mur-149 | 1-Projet | Sejour cuisine | B43 | etage 4 | 7
Mur-149 | etage 4 | 4 | 0 | 3000 | 2000 | 11.3266 | 5630.12 | 0.426372 | 11.6458 | 11.6458 | 5982.3 | 5.88107 | 5.67107 | 0.815198 | 6162.3 | 232.186 | 9.66667 | 232.186 | 9.45667 | 1.24157 | 17.7369 | 17.7369 | 5982.3 | 5982.3 | 0 | 0.011353 | 3000 | 0.426372 | 14600 | 5912.3 | 1.24157 | 12104.6 | 17600 | 3000 | 14600 | 0 | 0.56521 | Face intérieure | Surface-Blanche | Mur-149 | 1-Projet | Ch 2 | B42 | etage 4 | 7 | ArchiCADProperties - Zones conflictuelles: Ch 1/pl
Mur-149 | etage 4 | 1 | 0 | 3000 | 3000 | 1.6932 | 830 | 0.372978 | 1.8928 | 1.8928 | 2403.52 | 5.42275 | 5.02375 | 0.132496 | 2508.52 | 1528.52 | 7.31555 | 1458.52 | 6.91655 | 0.505474 | 7.31555 | 7.12655 | 2438.52 | 2368.52 | 0 | 0.106996 | 3000 | 0.372978 | 14600 | 2438.52 | 0.505474 | 4976.03 | 17600 | 3000 | 14600 | 0 | 0.775979 | Face intérieure | Surface-Blanche | Mur-149 | 1-Projet | Wc | B42 | etage 4 | 7
Mur-150 | etage 4 | 0 | 0 | 3000 | 3000 | 0 | 0 | 0.0567067 | 0 | 0 | 270.032 | 0.915096 | 0.705096 | 0 | 375.032 | 305.032 | 0.915096 | 235.032 | 0.705096 | 0.0567067 | 0.915096 | 0.705096 | 305.032 | 235.032 | 0 | 0.0189022 | 3000 | 0.0567067 | 14600 | 305.032 | 0.0567067 | 709.059 | 17600 | 3000 | 14600 | 0 | 0.544789 | Face intérieure | Surface-Blanche | Mur-150 | 1-Projet | Sde | B42 | etage 4 | 7
Mur-149 | etage 4 | 0 | 0 | 3000 | 3000 | 0 | 0 | 0.39155 | 0 | 0 | 1864.52 | 5.69857 | 5.48857 | 0 | 1969.52 | 1899.52 | 5.69857 | 1829.52 | 5.48857 | 0.39155 | 5.69857 | 5.48857 | 1899.52 | 1829.52 | 0 | 0.130517 | 3000 | 0.39155 | 14600 | 1899.52 | 0.39155 | 3898.04 | 17600 | 3000 | 14600 | 0 | 0.768018 | Face intérieure | Surface-Blanche | Mur-149 | 1-Projet | Ch 2 | B42 | etage 4 | 7
Mur-149 | etage 4 | 1 | 0 | 3000 | 3000 | 1.224 | 600 | 0.0522943 | 1.2505 | 1.2505 | 665.854 | 0.852061 | 0.642061 | 0.087535 | 700.854 | 90.8537 | 2.10256 | 20.8537 | 1.89256 | 0.139829 | 2.10256 | 1.89256 | 700.854 | 630.854 | 0 | 0.00390976 | 3000 | 0.0522943 | 14600 | 700.854 | 0.139829 | 1500.7 | 17600 | 3000 | 14600 | 0 | 0.414004 | Face intérieure | Surface-Blanche | Mur-149 | 1-Projet | Sejour cuisine/pl | B41 | etage 4 | 7
Mur-149 | etage 4 | 0 | 1 | 3000 | 3000 | 0 | 0 | 0.85613 | 2.7163 | 2.7163 | 4982.24 | 12.2304 | 11.8104 | 0.190141 | 4982.24 | 3650.73 | 12.2304 | 3650.73 | 11.8104 | 1.04627 | 14.9467 | 14.9467 | 4982.24 | 4982.24 | 2.7163 | 0.255551 | 3000 | 0.85613 | 14600 | 4982.24 | 1.04627 | 10104.5 | 17600 | 3000 | 14600 | 0 | 1.02431 | Face intérieure | Surface-Blanche | Mur-149 | 1-Projet | Sejour cuisine | B42 | etage 4 | 7
Mur-149 | etage 4 | 0 | 1 | 3000 | 3000 | 0 | 0 | 0.399587 | 2.26017 | 2.26017 | 2651.52 | 5.49839 | 5.51239 | 0.158212 | 2721.52 | 1543.59 | 5.49839 | 1543.59 | 5.51239 | 0.557799 | 7.96856 | 7.96856 | 2651.52 | 2651.52 | 2.26017 | 0.112952 | 3000 | 0.399587 | 14600 | 2721.52 | 0.557799 | 5443.04 | 17600 | 3000 | 14600 | 0 | 0.580658 | Face intérieure | Surface-Blanche | Mur-149 | 1-Projet | Sejour cuisine | B43 | etage 4 | 7
Mur-149 | etage 4 | 0 | 0 | 3000 | 0 | 0 | 0 | 0.125998 | 0 | 0 | 600.009 | 1.79997 | 1.79997 | 0 | 600.008 | 600.009 | 1.79997 | 600.009 | 1.79997 | 0.125998 | 1.79997 | 1.79997 | 600.009 | 600.009 | 0 | 0.0420006 | 3000 | 0.125998 | 14600 | 600.008 | 0.125998 | 1340.02 | 17600 | 3000 | 14600 | 0 | 0.308 | Face intérieure | Surface-Blanche | Mur-149 | 1-Projet | Ch 1/pl | B41 | etage 4 | 7
Mur-149 | etage 4 | 1 | 0 | 3000 | 3000 | 1.1832 | 580 | 0.04725 | 1.23 | 1.23 | 635 | 0.78 | 0.57 | 0.0861 | 600 | 70 | 2.01 | 1.13687e-10 | 1.8 | 0.13335 | 2.01 | 1.8 | 670 | 600 | 0 | 0.00245 | 3000 | 0.04725 | 14600 | 670 | 0.13335 | 1438.99 | 17600 | 3000 | 14600 | 0 | 0.410385 | Face intérieure | Surface-Blanche | Mur-149 | 1-Projet | Sejour cuisine/pl | B41 | etage 4 | 7
Mur-149 | etage 4 | 1 | 0 | 2700 | 2700 | 1.6932 | 830 | 0.199207 | 1.8928 | 1.8928 | 1755.04 | 2.94031 | 2.75131 | 0.132496 | 1970.04 | 880.041 | 4.83311 | 810.04 | 4.64411 | 0.331703 | 4.83311 | 4.64411 | 1790.04 | 1720.04 | 0 | 0.0591528 | 2700 | 0.199207 | 14600 | 1790.04 | 0.331703 | 3679.08 | 17300 | 2700 | 14600 | 0 | 0.638292 | Face intérieure | Peinture-01 | Mur-149 | 1-Projet | Wc | B42 | etage 4 | 7
Mur-149 | etage 4 | 0 | 0 | 3000 | 3000 | 0 | 0 | 0.11857 | 0 | 0 | 564.618 | 1.79885 | 1.58885 | 0 | 879.618 | 599.618 | 1.79885 | 529.618 | 1.58885 | 0.11857 | 1.79885 | 1.58885 | 599.618 | 529.618 | 0 | 0.0395233 | 3000 | 0.11857 | 14600 | 599.618 | 0.11857 | 1298.23 | 17600 | 3000 | 14600 | 0 | 0.586031 | Face intérieure | Surface-Blanche | Mur-149 | 1-Projet | Sejour cuisine/pl | B41 | etage 4 | 7
Mur-149 | etage 4 | 0 | 0 | 3000 | 3000 | 0 | 0 | 0.0599565 | 0 | 0 | 285.495 | 0.961571 | 0.751472 | 0 | 390.511 | 320.511 | 0.961571 | 250.478 | 0.751472 | 0.0599565 | 0.961571 | 0.751472 | 320.511 | 250.478 | 0 | 0.0199855 | 3000 | 0.0599565 | 14600 | 320.524 | 0.0599565 | 740.007 | 17600 | 3000 | 14600 | 0 | 0.547025 | Face intérieure | Surface-Blanche | Mur-149 | 1-Projet | Sde | B43 | etage 4 | 7
Mur-149 | etage 4 | 0 | 0 | 3000 | 3000 | 0 | 0 | 0.137101 | 0 | 0 | 640.862 | 1.85359 | 2.06358 | 0 | 855.861 | 605.862 | 1.85359 | 675.861 | 2.06358 | 0.137101 | 1.85359 | 2.06358 | 605.862 | 675.861 | 0 | 0.0574603 | 3000 | 0.137101 | 14600 | 855.861 | 0.137101 | 1450.72 | 17600 | 3000 | 14600 | 0 | 0.621905 | Face extérieure | Lavis blanc | Mur-149 | 1-Projet | Sejour cuisine | B42 | etage 4 | 7
Mur-148 | etage 4 | 0 | 0 | 3000 | 3000 | 0 | 0 | 0.134657 | 0 | 0 | 641.226 | 2.02868 | 1.81868 | 0 | 676.226 | 676.226 | 2.02868 | 606.226 | 1.81868 | 0.134657 | 2.02868 | 1.81868 | 676.226 | 606.226 | 0 | 0.0448858 | 3000 | 0.134657 | 14600 | 676.226 | 0.134657 | 1451.45 | 17600 | 3000 | 14600 | 0 | 0.596757 | Face intérieure | Surface-Blanche | Mur-148 | 1-Projet | Sejour cuisine/pl | B41 | etage 4 | 7
Mur-150 | etage 4 | 0 | 0 | 3000 | 3000 | 0 | 0 | 0.126119 | 0 | 0 | 600.565 | 1.90669 | 1.69669 | 0 | 815.566 | 635.565 | 1.90669 | 565.564 | 1.69669 | 0.126119 | 1.90669 | 1.69669 | 635.565 | 565.564 | 0 | 0.0420395 | 3000 | 0.126119 | 14600 | 635.565 | 0.126119 | 1369.94 | 17600 | 3000 | 14600 | 0 | 0.590522 | Face intérieure | Surface-Blanche | Mur-150 | 1-Projet |  |  | etage 4 | 7
Mur-149 | etage 4 | 0 | 0 | 3000 | 3000 | 0 | 0 | 0.688288 | 0 | 0 | 3271.73 | 9.58618 | 9.85018 | 0 | 3271.73 | 3201.73 | 9.58618 | 3341.73 | 9.85018 | 0.688288 | 9.64018 | 10.0252 | 3201.73 | 3341.73 | 0 | 0.231471 | 3000 | 0.688288 | 14600 | 3341.73 | 0.688288 | 6741.44 | 17600 | 3000 | 14600 | 0 | 1.04241 | Face intérieure | Surface-Blanche | Mur-149 | 1-Projet | Sejour cuisine/pl | B41 | etage 4 | 7
Mur-149 | etage 4 | 1 | 0 | 2800 | 2500 | 1.6932 | 830 | 0.955119 | 1.8928 | 1.8928 | 5561.91 | 13.4486 | 13.4486 | 0.132496 | 6081.91 | 4651.91 | 15.3414 | 4651.91 | 15.3414 | 1.08762 | 15.5734 | 15.5734 | 5561.91 | 5561.91 | 0 | 0.325634 | 2800 | 0.955119 | 14600 | 5561.91 | 1.09014 | 11263.8 | 17400 | 2800 | 14600 | 0 | 1.10697 | Face intérieure | Surface-Blanche | Mur-149 | 1-Projet | Ch 2 | B44 | etage 4 | 7
Mur-149 | etage 4 | 0 | 0 | 3000 | 3000 | 0 | 0 | 0.308484 | 0 | 0 | 1456.97 | 4.30191 | 4.30191 | 0 | 1601.97 | 1421.97 | 4.30191 | 1491.97 | 4.30191 | 0.308484 | 4.30191 | 4.51191 | 1421.97 | 1491.97 | 0 | 0.114588 | 3000 | 0.308484 | 14600 | 1671.97 | 0.308484 | 3082.93 | 17600 | 3000 | 14600 | 0 | 0.736161 | Face intérieure | Surface-Blanche | Mur-149 | 1-Projet | Sde 1 | B44 | etage 4 | 7
Mur-149 | etage 4 | 0 | 0 | 3000 | 3000 | 0 | 0 | 0.20607 | 0 | 0 | 976.619 | 2.94386 | 2.94386 | 0 | 1116.62 | 976.619 | 2.94386 | 976.619 | 2.94386 | 0.20607 | 2.94386 | 2.94386 | 976.619 | 976.619 | 0 | 0.0732633 | 3000 | 0.20607 | 14600 | 1046.62 | 0.20607 | 2093.24 | 17600 | 3000 | 14600 | 0 | 0.566527 | Face intérieure | Surface-Blanche | Mur-149 | 1-Projet | Sde 1 | B44 | etage 4 | 7
Mur-149 | etage 4 | 0 | 0 | 3000 | 3000 | 0 | 0 | 0.168 | 0 | 0 | 800 | 2.4 | 2.4 | 0 | 800 | 800 | 2.4 | 800 | 2.4 | 0.168 | 2.4 | 2.4 | 800 | 800 | 0 | 0.056 | 3000 | 0.168 | 14600 | 800 | 0.168 | 1740 | 17600 | 3000 | 14600 | 0 | 0.532 | Face intérieure | Surface-Blanche | Mur-149 | 1-Projet | Sde 1 | B44 | etage 4 | 7 | ArchiCADProperties - Zones conflictuelles: Sde 1
Mur-149 | etage 4 | 0 | 1 | 3000 | 3000 | 0 | 0 | 0.177581 | 2.20334 | 2.20334 | 1580.07 | 2.11687 | 2.03287 | 0.154234 | 1580.07 | 499.998 | 2.11687 | 499.998 | 2.03287 | 0.331814 | 4.7402 | 4.7402 | 1580.07 | 1580.07 | 2.20334 | 0.035 | 3000 | 0.177581 | 14600 | 1580.07 | 0.331814 | 3300.13 | 17600 | 3000 | 14600 | 0 | 0.422805 | Face intérieure | Surface-Blanche | Mur-149 | 1-Projet | Sejour cuisine | B44 | etage 4 | 7
Mur-149 | etage 4 | 0 | 0 | 3000 | 0 | 0 | 0 | 0.269711 | 0 | 0 | 1354.34 | 3.85302 | 3.64302 | 0 | 1354.34 | 1354.34 | 3.85302 | 1354.34 | 3.64302 | 0.269711 | 3.85302 | 3.85302 | 1354.34 | 1354.34 | 0 | 0.0899038 | 3000 | 0.269711 | 14600 | 1284.34 | 0.269711 | 2848.69 | 17600 | 3000 | 14600 | 0 | 0.599808 | Face intérieure | Surface-Blanche | Mur-149 | 1-Projet | Sejour cuisine | B44 | etage 4 | 7
Mur-149 | etage 4 | 0 | 0 | 3000 | 3000 | 0 | 0 | 0.140151 | 0 | 0 | 661.384 | 2.14915 | 1.85515 | 0 | 786.384 | 716.384 | 2.14915 | 606.384 | 1.85515 | 0.140151 | 2.14915 | 1.85515 | 716.384 | 606.384 | 0 | 0.0532829 | 3000 | 0.140151 | 14600 | 786.384 | 0.140151 | 1614.9 | 17600 | 3000 | 14600 | 0 | 0.95832 | Face intérieure | Surface-Blanche | Mur-149 | 1-Projet | Sejour cuisine | B44 | etage 4 | 7
Mur-149 | etage 4 | 1 | 0 | 3000 | 3000 | 1.8972 | 930 | 1.06128 | 2.1008 | 2.1008 | 5748 | 14.9092 | 15.4132 | 0.147056 | 6178 | 4648 | 14.9092 | 4828 | 15.4132 | 1.20834 | 17.01 | 17.514 | 5658 | 5838 | 0 | 0.33796 | 3000 | 1.06128 | 14600 | 5838 | 1.20834 | 11759.1 | 17600 | 3000 | 14600 | 0 | 1.51139 | Face intérieure | Surface-Blanche | Mur-149 | 1-Projet | Sejour cuisine | B44 | etage 4 | 7
Mur-149 | etage 4 | 1 | 0 | 3000 | 3000 | 1.6932 | 830 | 0.196568 | 1.8928 | 1.8928 | 1566.97 | 2.70311 | 2.91311 | 0.132496 | 1601.97 | 621.969 | 4.59591 | 691.969 | 4.80591 | 0.329064 | 4.59591 | 4.80591 | 1531.97 | 1601.97 | 0 | 0.0459878 | 3000 | 0.196568 | 14600 | 1601.97 | 0.329064 | 3302.93 | 17600 | 3000 | 14600 | 0 | 0.517061 | Face intérieure | Surface-Blanche | Mur-149 | 1-Projet | Sejour cuisine | B44 | etage 4 | 7
Mur-149 | etage 4 | 1 | 1 | 3000 | 3000 | 1.6932 | 830 | 0.465861 | 3.98482 | 3.98482 | 3546.66 | 6.65515 | 6.44516 | 0.278937 | 3726.66 | 1590.65 | 8.54795 | 1590.65 | 8.33796 | 0.744798 | 10.64 | 10.64 | 3546.66 | 3546.66 | 2.09202 | 0.111345 | 3000 | 0.465861 | 14600 | 3546.66 | 0.744798 | 7233.32 | 17600 | 3000 | 14600 | 0 | 0.639611 | Face intérieure | Surface-Blanche | Mur-149 | 1-Projet | Sde 2 | B44 | etage 4 | 7
Mur-149 | etage 4 | 1 | 0 | 3000 | 3000 | 1.6932 | 830 | 0.137354 | 1.8928 | 1.8928 | 1285 | 2.0672 | 1.8572 | 0.132496 | 1250 | 410 | 3.96 | 340 | 3.75 | 0.26985 | 3.96 | 3.75 | 1320 | 1250 | 0 | 0.02625 | 3000 | 0.137354 | 14600 | 1320 | 0.26985 | 2738.99 | 17600 | 3000 | 14600 | 0 | 0.623185 | Face extérieure | Lavis blanc | Mur-149 | 1-Projet | Ch 2 | B44 | etage 4 | 7
Mur-149 | etage 4 | 0 | 0 | 3000 | 3000 | 0 | 0 | 0.103795 | 0 | 0 | 494.264 | 1.48279 | 1.48279 | 0 | 494.264 | 494.264 | 1.48279 | 494.264 | 1.48279 | 0.103795 | 1.48279 | 1.48279 | 494.264 | 494.264 | 0 | 0.0345985 | 3000 | 0.103795 | 14600 | 564.264 | 0.103795 | 1186.52 | 17600 | 3000 | 14600 | 0 | 0.663167 | Face extérieure | Lavis blanc | Mur-149 | 1-Projet | Ch 2 | B44 | etage 4 | 7
Mur-149 | etage 4 | 0 | 0 | 3000 | 3000 | 0 | 0 | 0.18415 | 0 | 0 | 864.904 | 2.73571 | 2.52571 | 0 | 1079.9 | 899.904 | 2.73571 | 829.903 | 2.52571 | 0.18415 | 2.73571 | 2.52571 | 899.904 | 829.903 | 0 | 0.0731428 | 3000 | 0.18415 | 14600 | 1079.9 | 0.18415 | 1898.8 | 17600 | 3000 | 14600 | 0 | 0.653271 | Face intérieure | Surface-Blanche | Mur-149 | 1-Projet | Sde 2 | B44 | etage 4 | 7
Mur-149 | etage 4 | 0 | 0 | 3000 | 3000 | 0 | 0 | 0.14805 | 0 | 0 | 705 | 2.01 | 1.8 | 0 | 740 | 740 | 2.01 | 670 | 1.8 | 0.14805 | 2.22 | 2.01 | 740 | 670 | 0 | 0.04935 | 3000 | 0.14805 | 14600 | 740 | 0.14805 | 1578.99 | 17600 | 3000 | 14600 | 0 | 0.605685 | Face intérieure | Surface-Blanche | Mur-149 | 1-Projet | Ch 2 | B42 | etage 4 | 7
Mur-149 | etage 4 | 0 | 0 | 3000 | 3000 | 0 | 0 | 0.406458 | 0 | 0 | 1935.51 | 5.91154 | 5.70154 | 0 | 1970.51 | 1970.51 | 5.91154 | 1900.51 | 5.70154 | 0.406458 | 5.91154 | 5.70154 | 1970.51 | 1900.51 | 0 | 0.135486 | 3000 | 0.406458 | 14600 | 1970.51 | 0.406458 | 4040.02 | 17600 | 3000 | 14600 | 0 | 0.777957 | Face intérieure | Surface-Blanche | Mur-149 | 1-Projet | Ch 2 | B43 | etage 4 | 7
Mur-149 | etage 4 | 0 | 0 | 3000 | 3000 | 0 | 0 | 0.29344 | 0 | 0 | 1395 | 4.29 | 4.094 | 0 | 1430 | 1430 | 4.29 | 1360 | 4.094 | 0.29344 | 4.29 | 4.094 | 1430 | 1360 | 0 | 0.1001 | 3000 | 0.29344 | 14600 | 1430 | 0.29344 | 2959 | 17600 | 3000 | 14600 | 0 | 0.701386 | Face intérieure | Surface-Blanche | Mur-149 | 1-Projet | Cellier | B43 | etage 4 | 7
Mur-149 | etage 4 | 2 | 0 | 2800 | 2800 | 3.3864 | 1660 | 0.586193 | 3.7856 | 3.7856 | 4342.78 | 7.30932 | 7.67418 | 0.264992 | 4342.78 | 2522.78 | 11.0949 | 2522.78 | 11.4598 | 0.851185 | 12.1598 | 12.1598 | 4342.78 | 4342.78 | 0 | 0.176595 | 2800 | 0.586193 | 14600 | 4342.78 | 0.851185 | 8825.56 | 17400 | 2800 | 14600 | 0 | 0.872589 | Face intérieure | Surface-Blanche | Mur-149 | 1-Projet | Ch 1/pl | B42 | etage 4 | 7
Mur-149 | etage 4 | 2 | 0 | 2800 | 2800 | 3.3864 | 1660 | 0.232795 | 3.7856 | 3.7856 | 2539.73 | 3.42364 | 3.03164 | 0.264992 | 2644.73 | 754.727 | 7.20924 | 684.727 | 6.81724 | 0.497787 | 7.20924 | 7.01324 | 2574.73 | 2504.73 | 0 | 0.0503809 | 2800 | 0.232795 | 14600 | 2574.73 | 0.497787 | 5248.45 | 17400 | 2800 | 14600 | -1.77636e-12 | 0.701348 | Face intérieure | Surface-Blanche | Mur-149 | 1-Projet | Cellier | B43 | etage 4 | 7
Mur-149 | etage 4 | 0 | 0 | 2700 | 2700 | 0 | 0 | 0.762915 | 0 | 0 | 4036.59 | 10.8988 | 10.8988 | 0 | 4376.59 | 4036.59 | 10.8988 | 4036.59 | 10.8988 | 0.762915 | 10.8988 | 10.8988 | 4036.59 | 4036.59 | 0 | 0.282561 | 2700 | 0.762915 | 14600 | 4036.59 | 0.762915 | 8213.18 | 17300 | 2700 | 14600 | -1.77636e-12 | 0.943123 | Face intérieure | Surface-Blanche | Mur-149 | 1-Projet | Ch 2 | B43 | etage 4 | 7
Mur-150 | etage 4 | 0 | 0 | 3000 | 3000 | 0 | 0 | 0.0829716 | 0 | 0 | 395.103 | 1.29031 | 1.0803 | 0 | 430.104 | 430.104 | 1.29031 | 360.101 | 1.0803 | 0.0829716 | 1.29031 | 1.0803 | 430.104 | 360.101 | 0 | 0.0276572 | 3000 | 0.0829716 | 14600 | 430.104 | 0.0829716 | 958.776 | 17600 | 3000 | 14600 | 0 | 0.561025 | Face intérieure | Surface-Blanche | Mur-150 | 1-Projet | Sde | B43 | etage 4 | 7 | ArchiCADProperties - Zones conflictuelles: Sde
Mur-150 | etage 4 | 2 | 0 | 3000 | 3000 | 2.8764 | 1410 | 0.425721 | 3.1228 | 3.1228 | 3051.51 | 6.08173 | 5.87173 | 0.218596 | 3301.52 | 1541.51 | 9.20453 | 1541.51 | 8.99453 | 0.644317 | 9.20453 | 9.20453 | 3051.51 | 3051.51 | 0 | 0.125406 | 3000 | 0.425721 | 14600 | 3301.52 | 0.644317 | 6243.02 | 17600 | 3000 | 14600 | 0 | 0.776512 | Face intérieure | Surface-Blanche | Mur-150 | 1-Projet | Entree/pl | B43 | etage 4 | 7
Mur-150 | etage 4 | 0 | 0 | 3000 | 3000 | 0 | 0 | 0.184091 | 0 | 0 | 864.622 | 2.73396 | 2.52577 | 0 | 1079.32 | 899.32 | 2.73396 | 829.925 | 2.52577 | 0.184091 | 2.73396 | 2.52577 | 899.32 | 829.925 | 0 | 0.0731236 | 3000 | 0.184091 | 14600 | 1079.32 | 0.184091 | 1897.81 | 17600 | 3000 | 14600 | 0 | 0.65195 | Face intérieure | Surface-Blanche | Mur-150 | 1-Projet |  |  | etage 4 | 7
Mur-149 | etage 4 | 0 | 0 | 3000 | 3000 | 0 | 0 | 0.13335 | 0 | 0 | 635 | 2.01 | 1.8 | 0 | 670 | 670 | 2.01 | 600 | 1.8 | 0.13335 | 2.01 | 1.8 | 670 | 600 | 0 | 0.0444501 | 3000 | 0.13335 | 14600 | 669.999 | 0.13335 | 1438.99 | 17600 | 3000 | 14600 | 0 | 0.595887 | Face intérieure | Surface-Blanche | Mur-149 | 1-Projet | Ch 2 | B43 | etage 4 | 7
Mur-149 | etage 4 | 0 | 0 | 3000 | 3000 | 0 | 0 | 0.149721 | 0 | 0 | 712.956 | 2.03387 | 2.24387 | 0 | 677.956 | 677.956 | 2.03387 | 747.956 | 2.24387 | 0.149721 | 2.03387 | 2.24387 | 677.956 | 747.956 | 0 | 0.0499069 | 3000 | 0.149721 | 14600 | 747.956 | 0.149721 | 1594.91 | 17600 | 3000 | 14600 | 0 | 0.606799 | Face intérieure | Surface-Blanche | Mur-149 | 1-Projet | Sejour cuisine | B44 | etage 4 | 7
Mur-121 | etage 4 | 0 | 0 | 3000 | 3000 | 0 | 0 | 0.1071 | 0 | 0 | 509.992 | 1.02598 | 1.02597 | 0 | 579.993 | 509.993 | 1.02598 | 509.991 | 1.02597 | 0.1071 | 1.52998 | 1.52997 | 509.993 | 509.991 | 0 | 0.0357 | 3000 | 0.1071 | 14600 | 509.993 | 0.1071 | 1159.98 | 17600 | 3000 | 14600 | 0 | 0.491407 | Face extérieure | Lavis blanc | Mur-121 | 1-Projet | Sejour cuisine | B43 | etage 4 | 7
Mur-149 | etage 4 | 0 | 0 | 2800 | 2800 | 0 | 0 | 0.245695 | 0 | 0 | 1253.55 | 3.50954 | 3.31432 | 0 | 1253.41 | 1323.41 | 3.50954 | 1183.68 | 3.31432 | 0.245695 | 3.70554 | 3.31432 | 1323.41 | 1183.68 | 0 | 0.0877482 | 2800 | 0.245695 | 14600 | 1323.41 | 0.245695 | 2704.88 | 17400 | 2800 | 14600 | 0 | 0.729317 | Face intérieure | Surface-Blanche | Mur-149 | 1-Projet | Sejour cuisine | B44 | etage 4 | 7
Mur-149 | etage 4 | 1 | 0 | 3000 | 3000 | 1.1832 | 580 | 0.0535388 | 1.23 | 1.23 | 664.947 | 0.86984 | 0.65984 | 0.0861 | 1039.95 | 99.9466 | 2.09984 | 29.9466 | 1.88984 | 0.139639 | 2.09984 | 1.88984 | 699.947 | 629.947 | 0 | 0.00454626 | 3000 | 0.0535388 | 14600 | 699.947 | 0.139639 | 1498.89 | 17600 | 3000 | 14600 | 0 | 0.558077 | Face intérieure | Surface-Blanche | Mur-149 | 1-Projet | Sde 1 | B44 | etage 4 | 7 | ArchiCADProperties - Zones conflictuelles: Sde 1
Mur-149 | etage 4 | 0 | 0 | 3000 | 3000 | 0 | 0 | 0.07455 | 0 | 0 | 355 | 0.96 | 0.75 | 0 | 390 | 390 | 0.96 | 320 | 0.75 | 0.07455 | 1.17 | 0.96 | 390 | 320 | 0 | 0.02485 | 3000 | 0.07455 | 14600 | 390 | 0.07455 | 878.995 | 17600 | 3000 | 14600 | 0 | 0.556685 | Face intérieure | Surface-Blanche | Mur-149 | 1-Projet | Sejour cuisine | B44 | etage 4 | 7
Mur-149 | etage 4 | 1 | 0 | 3000 | 3000 | 1.1832 | 580 | 0.0576759 | 1.23 | 1.23 | 684.645 | 0.928941 | 0.718941 | 0.0861 | 719.647 | 119.646 | 2.15894 | 49.6447 | 1.94894 | 0.143776 | 2.15894 | 1.94894 | 719.646 | 649.645 | 0 | 0.00592528 | 3000 | 0.0576759 | 14600 | 719.647 | 0.143776 | 1538.29 | 17600 | 3000 | 14600 | 0 | 0.560835 | Face intérieure | Surface-Blanche | Mur-149 | 1-Projet | Sejour cuisine | B44 | etage 4 | 7
Mur-149 | etage 4 | 0 | 0 | 3000 | 3000 | 0 | 0 | 0.28658 | 0 | 0 | 1360 | 4.094 | 4.094 | 0 | 1430 | 1360 | 4.094 | 1360 | 4.094 | 0.28658 | 4.094 | 4.094 | 1360 | 1360 | 0 | 0.1001 | 3000 | 0.28658 | 14600 | 1430 | 0.28658 | 2860 | 17600 | 3000 | 14600 | 0 | 0.6202 | Face intérieure | Surface-Blanche | Mur-149 | 1-Projet | Cellier | B43 | etage 4 | 7
Mur-149 | etage 4 | 0 | 0 | 2800 | 0 | 0 | 0 | 0.0661692 | 0 | 0 | 400.098 | 0.945275 | 0.945274 | 0 | 580.098 | 400.098 | 0.945275 | 400.098 | 0.945274 | 0.0661692 | 0.945275 | 0.945274 | 400.098 | 400.098 | 0 | 0.0280069 | 2800 | 0.0661692 | 14600 | 400.098 | 0.0661692 | 940.196 | 17400 | 2800 | 14600 | 0 | 0.443114 | Face intérieure | Surface-Blanche | Mur-149 | 1-Projet |  |  | etage 4 | 7
Mur-149 | etage 4 | 0 | 0 | 2700 | 2700 | 0 | 0 | 0.0558414 | 0 | 0 | 295.457 | 0.892292 | 0.703176 | 0 | 330.478 | 330.478 | 0.892292 | 260.436 | 0.703176 | 0.0558414 | 0.892292 | 0.703176 | 330.478 | 260.436 | 0 | 0.020682 | 2700 | 0.0558414 | 14600 | 330.489 | 0.0558414 | 759.947 | 17300 | 2700 | 14600 | -1.77636e-12 | 0.497753 | Face intérieure | Surface-Blanche | Mur-149 | 1-Projet |  |  | etage 4 | 7
Mur-149 | etage 4 | 1 | 0 | 2800 | 2800 | 3.58526 | 1792.63 | 0.125794 | 3.49244 | 3.49244 | 1889.1 | 1.69905 | 1.69905 | 0.244471 | 1854.1 | 107.884 | 1.69905 | 177.884 | 1.69905 | 0.370264 | 5.19149 | 5.38749 | 1854.1 | 1924.1 | 0 | 0.0100019 | 2800 | 0.125794 | 14600 | 1924.1 | 0.370264 | 3947.2 | 17400 | 2800 | 14600 | 0 | 0.475425 | Face intérieure | Surface-Blanche | Mur-149 | 1-Projet | Sejour cuisine | B43 | etage 4 | 7
Mur-149 | etage 4 | 0 | 0 | 3000 | 3000 | 0 | 0 | 0.0976499 | 0 | 0 | 465 | 1.5 | 1.29 | 0 | 680 | 500 | 1.5 | 430 | 1.29 | 0.0976499 | 1.5 | 1.29 | 500 | 430 | 0 | 0.03255 | 3000 | 0.0976499 | 14600 | 500 | 0.0976499 | 1098.99 | 17600 | 3000 | 14600 | 0 | 0.572085 | Face intérieure | Surface-Blanche | Mur-149 | 1-Projet | Sde 2 | B44 | etage 4 | 7 | ArchiCADProperties - Zones conflictuelles: Sde 2
Mur-149 | etage 4 | 0 | 0 | 3000 | 3000 | 0 | 0 | 0.230624 | 0 | 0 | 1098.21 | 2.89563 | 2.68563 | 0 | 1133.21 | 1133.21 | 2.89563 | 1063.21 | 2.68563 | 0.230624 | 3.39963 | 3.18963 | 1133.21 | 1063.21 | 0 | 0.0768747 | 3000 | 0.230624 | 14600 | 1133.21 | 0.230624 | 2365.41 | 17600 | 3000 | 14600 | 0 | 0.660734 | Face intérieure | Surface-Blanche | Mur-149 | 1-Projet | Sde 2 | B44 | etage 4 | 7 | ArchiCADProperties - Zones conflictuelles: Entree; Sde 2
Mur-149 | etage 4 | 0 | 0 | 3000 | 3000 | 0 | 0 | 0.146086 | 0 | 0 | 695.648 | 2.19194 | 1.98195 | 0 | 730.648 | 730.648 | 2.19194 | 660.648 | 1.98195 | 0.146086 | 2.19194 | 1.98195 | 730.648 | 660.648 | 0 | 0.0486954 | 3000 | 0.146086 | 14600 | 730.648 | 0.146086 | 1560.29 | 17600 | 3000 | 14600 | 0 | 0.604375 | Face intérieure | Surface-Blanche | Mur-149 | 1-Projet | Sde 2 | B44 | etage 4 | 7
Mur-149 | etage 4 | 0 | 0 | 3000 | 3000 | 0 | 0 | 0.349667 | 0 | 0 | 1653.08 | 4.78525 | 4.99524 | 0 | 1903.08 | 1653.08 | 4.78525 | 1653.08 | 4.99524 | 0.349667 | 4.99525 | 4.99524 | 1653.08 | 1653.08 | 0 | 0.128316 | 3000 | 0.349667 | 14600 | 1833.08 | 0.349667 | 3446.16 | 17600 | 3000 | 14600 | -1.77636e-12 | 0.676631 | Face intérieure | Surface-Blanche | Mur-149 | 1-Projet | Sde 2 | B44 | etage 4 | 7
Mur-149 | etage 4 | 0 | 0 | 3000 | 3000 | 0 | 0 | 0.449524 | 0 | 0 | 2140.59 | 6.42178 | 6.42178 | 0 | 2390.59 | 2140.59 | 6.42178 | 2140.59 | 6.42178 | 0.449524 | 6.42178 | 6.42178 | 2140.59 | 2140.59 | 0 | 0.149841 | 3000 | 0.449524 | 14600 | 2140.59 | 0.449524 | 4421.19 | 17600 | 3000 | 14600 | 0 | 0.719683 | Face intérieure | Surface-Blanche | Mur-149 | 1-Projet | Sde | B42 | etage 4 | 7
Mur-149 | etage 4 | 0 | 0 | 3000 | 3000 | 0 | 0 | 0.249605 | 0 | 0 | 1186.26 | 3.36279 | 3.55879 | 0 | 1186.26 | 1186.26 | 3.36279 | 1186.26 | 3.55879 | 0.249605 | 3.57279 | 3.55879 | 1186.26 | 1186.26 | 0 | 0.0854884 | 3000 | 0.249605 | 14600 | 1256.26 | 0.249605 | 2512.53 | 17600 | 3000 | 14600 | 0 | 0.596776 | Face intérieure | Surface-Blanche | Mur-149 | 1-Projet | Sde 1 | B44 | etage 4 | 7
Mur-149 | etage 4 | 0 | 0 | 3000 | 3000 | 0 | 0 | 0.32655 | 0 | 0 | 1555 | 4.56 | 4.77 | 0 | 1520 | 1520 | 4.56 | 1590 | 4.77 | 0.32655 | 4.56 | 4.77 | 1520 | 1590 | 0 | 0.10885 | 3000 | 0.32655 | 14600 | 1590 | 0.32655 | 3278.99 | 17600 | 3000 | 14600 | 0 | 0.724685 | Face intérieure | Surface-Blanche | Mur-149 | 1-Projet | Sde 1 | B44 | etage 4 | 7
Mur-149 | etage 4 | 0 | 0 | 3000 | 3000 | 0 | 0 | 0.123002 | 0 | 0 | 571.389 | 1.85517 | 1.65917 | 0 | 786.39 | 606.389 | 1.85517 | 536.388 | 1.65917 | 0.123002 | 1.85517 | 1.65917 | 606.389 | 536.388 | 0 | 0.0550473 | 3000 | 0.123002 | 14600 | 786.39 | 0.123002 | 1311.58 | 17600 | 3000 | 14600 | 0 | 0.610731 | Face intérieure | Surface-Blanche | Mur-149 | 1-Projet | Cellier | B44 | etage 4 | 7
Mur-149 | etage 4 | 0 | 0 | 3000 | 3000 | 0 | 0 | 0.119258 | 0 | 0 | 567.895 | 1.80868 | 1.59868 | 0 | 602.895 | 602.895 | 1.80868 | 532.895 | 1.59868 | 0.119258 | 1.80868 | 1.59868 | 602.895 | 532.895 | 0 | 0.0397526 | 3000 | 0.119258 | 14600 | 602.895 | 0.119258 | 1304.78 | 17600 | 3000 | 14600 | 0 | 0.58649 | Face intérieure | Surface-Blanche | Mur-149 | 1-Projet | Sde 1 | B44 | etage 4 | 7
Mur-149 | etage 4 | 0 | 0 | 2700 | 2700 | 0 | 0 | 0.13375 | 0 | 0 | 707.673 | 2.00529 | 1.81614 | 0 | 742.7 | 742.7 | 2.00529 | 672.646 | 1.81614 | 0.13375 | 2.00529 | 1.81614 | 742.7 | 672.646 | 0 | 0.0495371 | 2700 | 0.13375 | 14600 | 742.7 | 0.13375 | 1584.38 | 17300 | 2700 | 14600 | 0 | 0.555463 | Face intérieure | Surface-Blanche | Mur-149 | 1-Projet |  |  | etage 4 | 7
Mur-120 | etage 4 | 0 | 0 | 2460 | 2460 | 0 | 0 | 0.0869144 | 0 | 0 | 504.729 | 1.41383 | 1.06943 | 0 | 915.562 | 574.729 | 1.41383 | 434.729 | 1.06943 | 0.0869144 | 1.41383 | 1.06943 | 574.729 | 434.729 | 0 | 0.035331 | 2460 | 0.0869144 | 14600 | 574.729 | 0.0869144 | 1207.45 | 17060 | 2460 | 14600 | 0 | 0.557717 | Face extérieure | Lavis blanc | Mur-120 | 3D |  |  | etage 4 | 7
Mur-149 | etage 4 | 1 | 0 | 2512.25 | 2512.25 | 3.10624 | 1553.12 | 0.0618462 | 3.10625 | 3.10625 | 1588.12 | 0.971446 | 0.795589 | 0.217437 | 1623.12 | 70 | 0.971451 | 0 | 0.795593 | 0.279284 | 4.0777 | 3.90184 | 1623.12 | 1553.12 | 0 | 0.00245 | 2512.25 | 0.0618462 | 14600 | 1623.12 | 0.279284 | 3345.24 | 17112.3 | 2512.25 | 14600 | 0 | 0.398176 | Face intérieure | Surface-Blanche | Mur-149 | 1-Projet | Ch 1/pl | B43 | etage 4 | 7 | ArchiCADProperties - Zones conflictuelles: Ch 1/pl
Mur-149 | etage 4 | 0 | 0 | 2512.25 | 2512.25 | 0 | 0 | 0.11167 | 0 | 0 | 635 | 1.68321 | 1.50735 | 0 | 670 | 670 | 1.68321 | 600 | 1.50735 | 0.11167 | 1.68321 | 1.50735 | 670 | 600 | 0 | 0.04445 | 2512.25 | 0.11167 | 14600 | 670 | 0.11167 | 1438.99 | 17112.3 | 2512.25 | 14600 | 0 | 0.513458 | Face intérieure | Surface-Blanche | Mur-149 | 1-Projet | Ch 1/pl | B43 | etage 4 | 7
Mur-149 | etage 4 | 0 | 0 | 3000 | 3000 | 0 | 0 | 0.131307 | 0 | 0 | 625.272 | 1.77082 | 1.98082 | 0 | 840.264 | 590.272 | 1.77082 | 660.272 | 1.98082 | 0.131307 | 1.77082 | 1.98082 | 590.272 | 660.272 | 0 | 0.043769 | 3000 | 0.131307 | 14600 | 660.272 | 0.131307 | 1419.54 | 17600 | 3000 | 14600 | 0 | 0.594523 | Face intérieure | Surface-Blanche | Mur-149 | 1-Projet | Sejour cuisine | B53 | etage 4 | 7
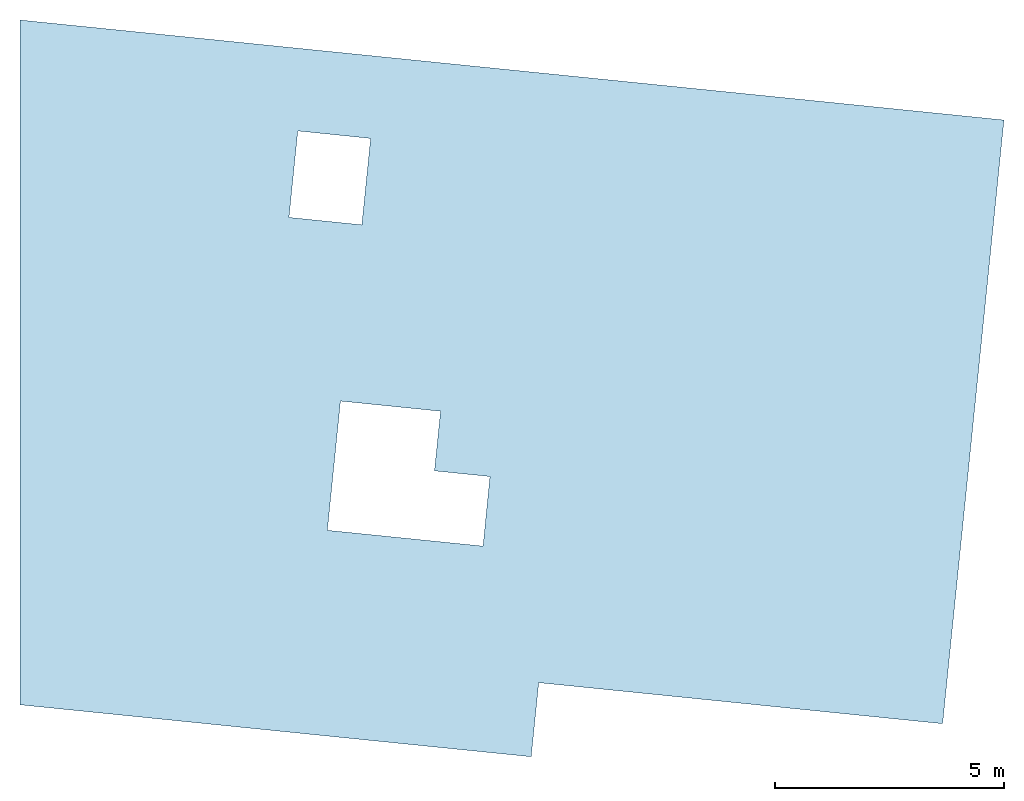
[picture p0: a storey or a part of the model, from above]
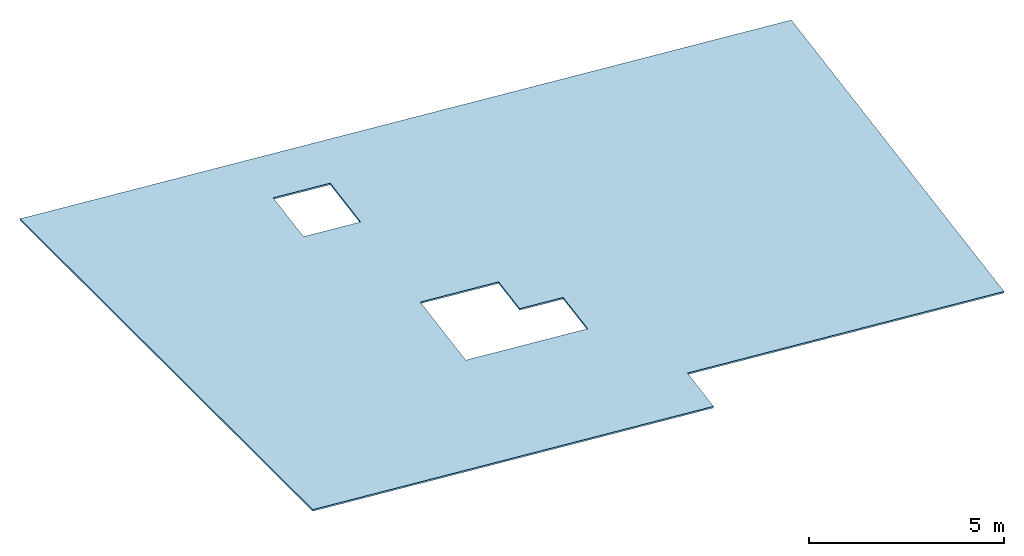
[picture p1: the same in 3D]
Properties of the parts of a building model (IFC2X3), part 29 of 44

# IfcWallStandardCase: Cloison 70 0826278243 70 (896)
Name | In | Nombre de Portes | Nombre de trous (Nombre d'ouvertures vides) | Hauteur maximale de la couche de Mur sur face intérieure (mm) = Hauteur maximale du Mur (mm) = Hauteur maximale de la couche de Mur sur face extérieure (mm) | Hauteur minimale de la couche de Mur sur face intérieure (mm) = Hauteur minimale du Mur (mm) = Hauteur minimale de la couche de Mur sur face extérieure (mm) | Superficie des portes (m2) | Largeur totale des Portes (mm) | Volume de composant de mur sur face intérieure (net) (m3) = Volume de composant de mur sur face extérieure (net) (m3) | Superficie analytique des ouvertures sur face intérieure (m2) | Superficie analytique des ouvertures sur face extérieure (m2) | Longueur moyenne du mur (mm) = Longueur du Mur au centre (mm) | Superficie de la face intérieure du mur (nette) (m2) | Superficie de la face extérieure du mur (nette) (m2) = Superficie en plan (m2) = Superficie inférieure (nette) (m2) | Volume analytique des ouvertures (m3) | Longueur de ligne de référence (mm) | Longueur de la face intérieure du mur (conditionnelle) (mm) | Superficie de la face intérieure du mur (conditionnelle) (m2) | Longueur de la face extérieure du mur (conditionnelle) (mm) | Superficie de la face extérieure du mur (conditionnelle) (m2) | Volume du composant face intérieure du mur (conditionnel) (m3) = Volume du composant face extérieure du mur (conditionnel) (m3) = Volume (conditionnel) (m3) | Superficie de la face intérieure du mur (brute) (m2) | Superficie de la face extérieure du mur (brute) (m2) | Longueur de Mur sur face intérieure (mm) | Longueur de Mur sur face extérieure (mm) | Superficie des baies libres dans le Mur (m2) | Superficie (m2) = Superficie supérieure (nette) (m2) | Hauteur (mm) | Volume (net) (m3) | Altitude à Zéro du Projet (mm) = Altitude de Référence Niveau 1 (mm) = Altitude de Référence Niveau 2 (mm) = Altitude à niveau de la mer (mm) | Longueur 3D (mm) | Volume (brut) (m3) | Périmètre Plan (mm) | Altitude supérieure à premier niveau de référence (mm) = Altitude supérieure à Zéro du projet (mm) = Altitude supérieure à niveau de la mer (mm) = Altitude supérieure à deuxième niveau de référence (mm) | Altitude supérieure à étage d'implantation (mm) | Altitude inférieure à premier niveau de référence (mm) = Altitude inférieure à Zéro du projet (mm) = Altitude inférieure à niveau de la mer (mm) = Altitude inférieure à deuxième niveau de référence (mm) | Altitude inférieure à étage d'implantation (mm) | Superficie de l'arête (nette) (m2) | Emplacement de ligne de référence | Surface de face intérieure = Surface de face extérieure = Surfaces (Toutes) = Surface latérale | ID de l'élément = Lien et ID d'élément = ID de Parent | Calque | Nom de zone liée | Numéro de zone liée | Nom d'étage d'implantation | Numéro d'étage d'implantation
Mur-149 | etage 4 | 1 | 0 | 2500 | 2500 | 1.6932 | 830 | 0.222837 | 1.8928 | 1.8928 | 2030.47 | 3.09588 | 3.09588 | 0.132496 | 1995.47 | 1155.47 | 4.98868 | 1085.47 | 4.98868 | 0.355333 | 5.16368 | 4.98868 | 2065.47 | 1995.47 | 0 | 0.078433 | 2500 | 0.222837 | 14600 | 2065.47 | 0.355333 | 4229.94 | 17100 | 2500 | 14600 | 0 | 0.643053 | Face intérieure | Surface-Blanche | Mur-149 | 1-Projet | Sde | B41 | etage 4 | 7
Mur-120 | etage 4 | 7 | 0 | 2500 | 0 | 7.2216 | 3540 | 0.304822 | 7.544 | 7.544 | 4829.44 | 3.4796 | 3.4796 | 0.52808 | 5009.44 | 1919.44 | 8.4816 | 1919.44 | 8.4816 | 0.832902 | 11.8986 | 11.8986 | 4829.44 | 4829.44 | 0 | 0.0755608 | 2500 | 0.304822 | 14600 | 4759.44 | 0.832902 | 9798.88 | 17100 | 2500 | 14600 | 0 | 0.758722 | Face extérieure | Peinture-01 | Mur-120 | 3D |  |  | etage 4 | 7
Mur-121 | etage 4 | 0 | 0 | 3000 | 3000 | 0 | 0 | 0.117519 | 0 | 0 | 553.613 | 1.45084 | 1.69684 | 0 | 553.614 | 553.612 | 1.45084 | 553.614 | 1.69684 | 0.117519 | 1.66084 | 1.69684 | 553.612 | 553.614 | 0 | 0.045053 | 3000 | 0.117519 | 14600 | 733.614 | 0.117519 | 1247.23 | 17600 | 3000 | 14600 | 0 | 0.534733 | Face extérieure | Lavis blanc | Mur-121 | 1-Projet | Sejour cuisine | B43 | etage 4 | 7
Mur-121 | etage 4 | 0 | 0 | 3000 | 3000 | 0 | 0 | 0.0865309 | 0 | 0 | 400.052 | 1.06116 | 1.06116 | 0 | 580.052 | 400.052 | 1.06116 | 400.052 | 1.06116 | 0.0865309 | 1.23616 | 1.23616 | 400.052 | 400.052 | 0 | 0.0406037 | 3000 | 0.0865309 | 14600 | 580.052 | 0.0865309 | 940.104 | 17600 | 3000 | 14600 | 0 | 0.501207 | Face extérieure | Lavis blanc | Mur-121 | 1-Projet |  |  | etage 4 | 7
Mur-149 | Etage 5 | 0 | 0 | 2700 | 2700 | 0 | 0 | 0.082143 | 0 | 0 | 434.619 | 1.26797 | 1.07897 | 0 | 749.619 | 469.619 | 1.26797 | 399.619 | 1.07897 | 0.082143 | 1.26797 | 1.07897 | 469.619 | 399.619 | 0 | 0.0304233 | 2700 | 0.082143 | 17650 | 469.619 | 0.082143 | 1038.23 | 20350 | 2700 | 17650 | 0 | 0.517133 | Face intérieure | Surface-Blanche | Mur-149 | 1-Projet | Wc | B51 | Etage 5 | 8 | ArchiCADProperties - Zones conflictuelles: Wc
Mur-149 | Etage 5 | 0 | 0 | 2700 | 2700 | 0 | 0 | 0.38514 | 0 | 0 | 2037.78 | 5.59649 | 5.21849 | 0 | 2282.77 | 2072.78 | 5.59649 | 2002.78 | 5.21849 | 0.38514 | 5.59649 | 5.40749 | 2072.78 | 2002.78 | 0 | 0.142644 | 2700 | 0.38514 | 17650 | 2072.78 | 0.38514 | 4244.55 | 20350 | 2700 | 17650 | 0 | 0.741575 | Face intérieure | Surface-Blanche | Mur-149 | 1-Projet | Ch 3 | B51 | Etage 5 | 8
Mur-121 | Etage 5 | 0 | 0 | 2700 | 0 | 0 | 0 | 0.0658835 | 0 | 0 | 400.072 | 0.941193 | 0.941193 | 0 | 580.072 | 400.072 | 0.941193 | 400.072 | 0.941193 | 0.0658835 | 0.941193 | 0.941193 | 400.072 | 400.072 | 0 | 0.040605 | 2700 | 0.0658835 | 17650 | 580.072 | 0.0658835 | 940.143 | 20350 | 2700 | 17650 | 0 | 0.45431 | Face extérieure | Lavis blanc | Mur-121 | 1-Projet |  |  | Etage 5 | 8
Mur-149 | Etage 5 | 0 | 0 | 2700 | 2700 | 0 | 0 | 0.275113 | 0 | 0 | 1455.63 | 4.02469 | 3.83569 | 0 | 1490.63 | 1490.63 | 4.02469 | 1420.63 | 3.83569 | 0.275113 | 4.02469 | 3.83569 | 1490.63 | 1420.63 | 0 | 0.101894 | 2700 | 0.275113 | 17650 | 1490.63 | 0.275113 | 3080.25 | 20350 | 2700 | 17650 | 0 | 0.660074 | Face intérieure | Surface-Blanche | Mur-149 | 1-Projet | Sejour cuisine | B51 | Etage 5 | 8
Mur-121 | Etage 5 | 0 | 0 | 2700 | 0 | 0 | 0 | 0.0658798 | 0 | 0 | 400.052 | 0.941141 | 0.941141 | 0 | 580.052 | 400.052 | 0.941141 | 400.052 | 0.941141 | 0.0658798 | 0.941141 | 0.941141 | 400.052 | 400.052 | 0 | 0.0406037 | 2700 | 0.0658798 | 17650 | 580.052 | 0.0658798 | 940.104 | 20350 | 2700 | 17650 | 0 | 0.454307 | Face extérieure | Lavis blanc | Mur-121 | 1-Projet |  |  | Etage 5 | 8
Mur-121 | Etage 5 | 0 | 0 | 2700 | 0 | 0 | 0 | 0.0658885 | 0 | 0 | 400.098 | 0.941264 | 0.941264 | 0 | 580.098 | 400.098 | 0.941264 | 400.098 | 0.941264 | 0.0658885 | 0.941264 | 0.941264 | 400.098 | 400.098 | 0 | 0.0406069 | 2700 | 0.0658885 | 17650 | 580.098 | 0.0658885 | 940.196 | 20350 | 2700 | 17650 | 0 | 0.454314 | Face extérieure | Lavis blanc | Mur-121 | 1-Projet |  |  | Etage 5 | 8
Mur-149 | Etage 5 | 2 | 0 | 2700 | 2700 | 5.35335 | 2660.08 | 0.244765 | 5.55295 | 5.55295 | 3351.7 | 3.30764 | 3.49664 | 0.388707 | 3351.7 | 611.627 | 5.20044 | 611.627 | 5.38944 | 0.633471 | 9.04959 | 9.04959 | 3351.7 | 3351.7 | 0 | 0.0428137 | 2700 | 0.244765 | 17650 | 3351.7 | 0.633471 | 6843.41 | 20350 | 2700 | 17650 | 0 | 0.515433 | Face intérieure | Surface-Blanche | Mur-149 | 1-Projet | Dgt/pl | B52 | Etage 5 | 8 | ArchiCADProperties - Zones conflictuelles: Ch 1/pl
Mur-149 | Etage 5 | 0 | 0 | 2700 | 2700 | 0 | 0 | 0.1134 | 0 | 0 | 599.998 | 1.61999 | 1.61999 | 0 | 669.998 | 599.998 | 1.61999 | 599.998 | 1.61999 | 0.1134 | 1.61999 | 1.61999 | 599.998 | 599.998 | 0 | 0.0419998 | 2700 | 0.1134 | 17650 | 599.998 | 0.1134 | 1340 | 20350 | 2700 | 17650 | 0 | 0.462 | Face intérieure | Surface-Blanche | Mur-149 | 1-Projet | Entree/pl | B51 | Etage 5 | 8
Mur-149 | Etage 5 | 0 | 0 | 2700 | 2700 | 0 | 0 | 0.163486 | 0 | 0 | 865.003 | 2.43001 | 2.24101 | 0 | 900.003 | 900.003 | 2.43001 | 830.004 | 2.24101 | 0.163486 | 2.43001 | 2.24101 | 900.003 | 830.004 | 0 | 0.0605502 | 2700 | 0.163486 | 17650 | 900.003 | 0.163486 | 1899 | 20350 | 2700 | 17650 | 0 | 0.577386 | Face intérieure | Surface-Blanche | Mur-149 | 1-Projet | sde | B51 | Etage 5 | 8
Mur-149 | Etage 5 | 0 | 0 | 2700 | 2700 | 0 | 0 | 0.0289437 | 0 | 0 | 153.142 | 0.507983 | 0.318984 | 0 | 368.142 | 188.142 | 0.507983 | 118.142 | 0.318984 | 0.0289437 | 0.507983 | 0.318984 | 188.142 | 118.142 | 0 | 0.0107199 | 2700 | 0.0289437 | 17650 | 188.142 | 0.0289437 | 475.279 | 20350 | 2700 | 17650 | 0 | 0.477725 | Face intérieure | Surface-Blanche | Mur-149 | 1-Projet | sde | B51 | Etage 5 | 8
Mur-149 | Etage 5 | 0 | 0 | 2700 | 2700 | 0 | 0 | 0.264586 | 0 | 0 | 1399.93 | 3.77981 | 3.77981 | 0 | 1399.93 | 1399.93 | 3.77981 | 1399.93 | 3.77981 | 0.264586 | 3.77981 | 3.77981 | 1399.93 | 1399.93 | 0 | 0.097995 | 2700 | 0.264586 | 17650 | 1399.93 | 0.264586 | 2939.86 | 20350 | 2700 | 17650 | 0 | 0.57399 | Face intérieure | Surface-Blanche | Mur-149 | 1-Projet | Wc | B52 | Etage 5 | 8
Mur-149 | Etage 5 | 0 | 0 | 3000 | 3000 | 0 | 0 | 0.0757112 | 0 | 0 | 360.529 | 1.18659 | 0.976588 | 0 | 395.529 | 395.529 | 1.18659 | 325.529 | 0.976588 | 0.0757112 | 1.18659 | 0.976588 | 395.529 | 325.529 | 0 | 0.0252371 | 3000 | 0.0757112 | 17650 | 395.529 | 0.0757112 | 890.054 | 20650 | 3000 | 17650 | 0 | 0.557459 | Face intérieure | Surface-Blanche | Mur-149 | 1-Projet | Sejour Cuisine | B52 | Etage 5 | 8 | ArchiCADProperties - Zones conflictuelles: Terrasse/eng.
Mur-149 | Etage 5 | 0 | 0 | 2700 | 2700 | 0 | 0 | 0.163485 | 0 | 0 | 865.001 | 2.43 | 2.241 | 0 | 900.001 | 900.001 | 2.43 | 830.001 | 2.241 | 0.163485 | 2.43 | 2.241 | 900.001 | 830.001 | 0 | 0.0605501 | 2700 | 0.163485 | 17650 | 900.001 | 0.163485 | 1899 | 20350 | 2700 | 17650 | 0 | 0.577386 | Face intérieure | Surface-Blanche | Mur-149 | 1-Projet | Sde 1 | B52 | Etage 5 | 8
Mur-149 | Etage 5 | 1 | 0 | 2700 | 2700 | 1.6932 | 830 | 0.158375 | 1.8928 | 1.8928 | 1539 | 2.168 | 1.979 | 0.132496 | 1504 | 663.999 | 4.0608 | 593.999 | 3.8718 | 0.290871 | 4.2498 | 4.0608 | 1574 | 1504 | 0 | 0.0440299 | 2700 | 0.158375 | 17650 | 1574 | 0.290871 | 3246.99 | 20350 | 2700 | 17650 | 0 | 0.608046 | Face intérieure | Surface-Blanche | Mur-149 | 1-Projet | Ch 2/pl | B52 | Etage 5 | 8
Mur-149 | Etage 5 | 1 | 0 | 2700 | 2700 | 1.6932 | 830 | 0.163292 | 1.8928 | 1.8928 | 1565.02 | 2.42724 | 2.06324 | 0.132496 | 1600.02 | 690.016 | 4.32004 | 620.016 | 3.95604 | 0.295788 | 4.32004 | 4.13104 | 1600.02 | 1530.02 | 0 | 0.0458511 | 2700 | 0.163292 | 17650 | 1600.02 | 0.295788 | 3299.03 | 20350 | 2700 | 17650 | 0 | 0.611689 | Face intérieure | Surface-Blanche | Mur-149 | 1-Projet | Sejour cuisine | B51 | Etage 5 | 8
Mur-149 | Etage 5 | 0 | 0 | 2700 | 2700 | 0 | 0 | 0.0781993 | 0 | 0 | 413.753 | 1.21163 | 1.02263 | 0 | 518.753 | 448.753 | 1.21163 | 378.753 | 1.02263 | 0.0781993 | 1.21163 | 1.02263 | 448.753 | 378.753 | 0 | 0.0289627 | 2700 | 0.0781993 | 17650 | 448.753 | 0.0781993 | 996.501 | 20350 | 2700 | 17650 | 0 | 0.514212 | Face intérieure | Surface-Blanche | Mur-149 | 1-Projet | Sde 1 | B52 | Etage 5 | 8
Mur-149 | Etage 5 | 0 | 0 | 2700 | 2700 | 0 | 0 | 0.0650945 | 0 | 0 | 344.415 | 1.02442 | 0.835422 | 0 | 559.416 | 379.416 | 1.02442 | 309.415 | 0.835422 | 0.0650945 | 1.02442 | 0.835422 | 379.416 | 309.415 | 0 | 0.0241091 | 2700 | 0.0650945 | 17650 | 379.416 | 0.0650945 | 857.826 | 20350 | 2700 | 17650 | 0 | 0.504505 | Face intérieure | Surface-Blanche | Mur-149 | 1-Projet | Ch 4/Pl | B52 | Etage 5 | 8
Mur-149 | Etage 5 | 0 | 0 | 2700 | 2700 | 0 | 0 | 0.137741 | 0 | 0 | 731.901 | 1.95933 | 1.97613 | 0 | 731.901 | 731.901 | 1.95933 | 731.901 | 1.97613 | 0.137741 | 1.95933 | 1.97613 | 731.901 | 731.901 | 0 | 0.051233 | 2700 | 0.137741 | 17650 | 801.901 | 0.137741 | 1661.79 | 20350 | 2700 | 17650 | 0 | 0.63008 | Face intérieure | Surface-Blanche | Mur-149 | 1-Projet | Ch 2/pl | B52 | Etage 5 | 8
Mur-149 | Etage 5 | 0 | 0 | 2700 | 2700 | 0 | 0 | 0.587872 | 0 | 0 | 3110.43 | 8.30367 | 8.49267 | 0 | 3485.43 | 3075.43 | 8.30367 | 3145.43 | 8.49267 | 0.587872 | 8.30367 | 8.49267 | 3075.43 | 3145.43 | 0 | 0.21773 | 2700 | 0.587872 | 17650 | 3145.43 | 0.587872 | 6389.86 | 20350 | 2700 | 17650 | 0 | 0.891747 | Face intérieure | Surface-Blanche | Mur-149 | 1-Projet | Sejour cuisine | B51 | Etage 5 | 8
Mur-149 | Etage 5 | 0 | 0 | 2700 | 2700 | 0 | 0 | 0.587872 | 0 | 0 | 3110.43 | 8.30367 | 8.49267 | 0 | 3485.43 | 3075.43 | 8.30367 | 3145.43 | 8.49267 | 0.587872 | 8.30367 | 8.49267 | 3075.43 | 3145.43 | 0 | 0.21773 | 2700 | 0.587872 | 17650 | 3145.43 | 0.587872 | 6389.86 | 20350 | 2700 | 17650 | 0 | 0.891747 | Face intérieure | Surface-Blanche | Mur-149 | 1-Projet | Sdb | B51 | Etage 5 | 8
Mur-149 | Etage 5 | 0 | 0 | 2700 | 2700 | 0 | 0 | 0.120026 | 0 | 0 | 635.058 | 1.80916 | 1.62016 | 0 | 670.058 | 670.058 | 1.80916 | 600.058 | 1.62016 | 0.120026 | 1.80916 | 1.62016 | 670.058 | 600.058 | 0 | 0.0444541 | 2700 | 0.120026 | 17650 | 670.058 | 0.120026 | 1439.11 | 20350 | 2700 | 17650 | 0 | 0.545195 | Face intérieure | Surface-Blanche | Mur-149 | 1-Projet | Entree | B52 | Etage 5 | 8
Mur-149 | Etage 5 | 1 | 0 | 2700 | 2700 | 3.66015 | 1830.08 | 0.234415 | 1.61107 | 1.61107 | 1836.98 | 3.44329 | 3.25429 | 0.112775 | 1871.98 | 1871.98 | 5.05436 | 1801.98 | 4.86536 | 0.34719 | 5.05436 | 4.86536 | 1871.98 | 1801.98 | 0 | 0.128589 | 2700 | 0.234415 | 17650 | 1871.98 | 0.34719 | 3842.96 | 20350 | 2700 | 17650 | 0 | 0.525159 | Face intérieure | Surface-Blanche | Mur-149 | 1-Projet | Dgt/pl | B52 | Etage 5 | 8
Mur-149 | Etage 5 | 0 | 0 | 2700 | 2700 | 0 | 0 | 0.141575 | 0 | 0 | 749.077 | 2.11701 | 1.92801 | 0 | 784.077 | 784.077 | 2.11701 | 714.077 | 1.92801 | 0.141575 | 2.11701 | 1.92801 | 784.077 | 714.077 | 0 | 0.0524354 | 2700 | 0.141575 | 17650 | 784.077 | 0.141575 | 1667.15 | 20350 | 2700 | 17650 | 0 | 0.561157 | Face intérieure | Surface-Blanche | Mur-149 | 1-Projet | Ch 4/Pl | B52 | Etage 5 | 8
Mur-149 | Etage 5 | 0 | 0 | 2700 | 2700 | 0 | 0 | 0.120015 | 0 | 0 | 635 | 1.809 | 1.62 | 0 | 670 | 670 | 1.809 | 600 | 1.62 | 0.120015 | 1.809 | 1.62 | 670 | 600 | 0 | 0.04445 | 2700 | 0.120015 | 17650 | 670 | 0.120015 | 1438.99 | 20350 | 2700 | 17650 | 0 | 0.545186 | Face intérieure | Surface-Blanche | Mur-149 | 1-Projet | Dgt/pl | B52 | Etage 5 | 8
Mur-149 | Etage 5 | 1 | 0 | 2700 | 2700 | 1.6932 | 830 | 0.227951 | 1.8928 | 1.8928 | 1907.12 | 3.16194 | 3.16194 | 0.132496 | 1872.12 | 1032.12 | 5.05474 | 962.125 | 5.05474 | 0.360447 | 5.24374 | 5.05474 | 1942.12 | 1872.12 | 0 | 0.0697987 | 2700 | 0.227951 | 17650 | 1942.12 | 0.360447 | 3983.24 | 20350 | 2700 | 17650 | 0 | 0.659584 | Face intérieure | Surface-Blanche | Mur-149 | 1-Projet | Sdb | B51 | Etage 5 | 8
Mur-149 | Etage 5 | 0 | 0 | 2500 | 2500 | 0 | 0 | 0.595661 | 0 | 0 | 3403.78 | 8.50945 | 8.50945 | 0 | 3813.78 | 3403.78 | 8.50945 | 3403.78 | 8.50945 | 0.595661 | 8.50945 | 8.50945 | 3403.78 | 3403.78 | 0 | 0.238265 | 2500 | 0.595661 | 17650 | 3403.78 | 0.595661 | 6947.56 | 20150 | 2500 | 17650 | 0 | 0.826529 | Face intérieure | Surface-Blanche | Mur-149 | 1-Projet | Ch 3 | B51 | Etage 5 | 8
Mur-149 | Etage 5 | 2 | 0 | 2700 | 2700 | 3.3864 | 1660 | 0.163688 | 3.7856 | 3.7856 | 2268.15 | 2.3384 | 2.1634 | 0.264992 | 2338.15 | 448.146 | 6.124 | 448.146 | 5.949 | 0.42868 | 6.124 | 6.124 | 2268.15 | 2268.15 | 0 | 0.0313703 | 2700 | 0.163688 | 17650 | 2268.15 | 0.42868 | 4676.29 | 20350 | 2700 | 17650 | 0 | 0.422541 | Face intérieure | Surface-Blanche | Mur-149 | 1-Projet | Ch 3 | B51 | Etage 5 | 8
Mur-149 | Etage 5 | 0 | 0 | 2700 | 2700 | 0 | 0 | 0.0617763 | 0 | 0 | 326.859 | 0.882518 | 0.693518 | 0 | 506.859 | 326.859 | 0.882518 | 326.859 | 0.693518 | 0.0617763 | 0.882518 | 0.882518 | 326.859 | 326.859 | 0 | 0.0228801 | 2700 | 0.0617763 | 17650 | 326.859 | 0.0617763 | 793.717 | 20350 | 2700 | 17650 | 0 | 0.42376 | Face intérieure | Surface-Blanche | Mur-149 | 1-Projet | Entree | B52 | Etage 5 | 8
Mur-149 | Etage 5 | 0 | 0 | 2700 | 2700 | 0 | 0 | 0.122867 | 0 | 0 | 650.091 | 1.84974 | 1.66074 | 0 | 755.091 | 685.091 | 1.84974 | 615.091 | 1.66074 | 0.122867 | 1.84974 | 1.66074 | 685.091 | 615.091 | 0 | 0.0455063 | 2700 | 0.122867 | 17650 | 685.091 | 0.122867 | 1469.18 | 20350 | 2700 | 17650 | 0 | 0.547299 | Face intérieure | Surface-Blanche | Mur-149 | 1-Projet | Wc | B51 | Etage 5 | 8
Mur-149 | Etage 5 | 0 | 0 | 2700 | 2700 | 0 | 0 | 0.263758 | 0 | 0 | 1388.14 | 3.76797 | 3.57897 | 0 | 1668.14 | 1388.14 | 3.76797 | 1388.14 | 3.57897 | 0.263758 | 3.76797 | 3.76797 | 1388.14 | 1388.14 | 0 | 0.10417 | 2700 | 0.263758 | 17650 | 1488.14 | 0.263758 | 2916.27 | 20350 | 2700 | 17650 | 0 | 0.586339 | Face intérieure | Surface-Blanche | Mur-149 | 1-Projet | Entree/pl | B51 | Etage 5 | 8
Mur-149 | Etage 5 | 0 | 0 | 2700 | 2700 | 0 | 0 | 0.126138 | 0 | 0 | 669.994 | 1.48398 | 1.61995 | 0 | 669.994 | 739.994 | 1.48398 | 599.994 | 1.61995 | 0.126138 | 1.98398 | 1.61995 | 739.994 | 599.994 | 0 | 0.0468996 | 2700 | 0.126138 | 17650 | 739.994 | 0.126138 | 1537.98 | 20350 | 2700 | 17650 | 0 | 0.622596 | Face intérieure | Surface-Blanche | Mur-149 | 1-Projet | Ch 1 | B51 | Etage 5 | 8 | ArchiCADProperties - Zones conflictuelles: Ch 1
Mur-149 | Etage 5 | 0 | 0 | 2700 | 2700 | 0 | 0 | 0.289741 | 0 | 0 | 1533.03 | 3.95011 | 4.13922 | 0 | 1533 | 1533.01 | 3.95011 | 1533.05 | 4.13922 | 0.289741 | 4.13911 | 4.13922 | 1533.01 | 1533.05 | 0 | 0.107312 | 2700 | 0.289741 | 17650 | 1533.05 | 0.289741 | 3206.05 | 20350 | 2700 | 17650 | -3.55271e-12 | 0.592623 | Face intérieure | Surface-Blanche | Mur-149 | 1-Projet | Wc | B51 | Etage 5 | 8
Mur-149 | Etage 5 | 0 | 0 | 2500 | 0 | 0 | 0 | 0.0577672 | 0 | 0 | 400.098 | 0.825245 | 0.825245 | 0 | 580.098 | 400.098 | 0.825245 | 400.098 | 0.825245 | 0.0577672 | 0.825245 | 0.825245 | 400.098 | 400.098 | 0 | 0.0231069 | 2500 | 0.0577672 | 17650 | 330.098 | 0.0577672 | 940.196 | 20150 | 2500 | 17650 | 0 | 0.396214 | Face intérieure | Surface-Blanche | Mur-149 | 1-Projet |  |  | Etage 5 | 8
Mur-149 | Etage 5 | 0 | 0 | 2700 | 2300 | 0 | 0 | 0.306798 | 0 | 0 | 1640.43 | 4.52367 | 4.01359 | 0 | 2015.43 | 1675.43 | 4.52367 | 1605.43 | 4.01359 | 0.306798 | 4.52367 | 4.33467 | 1675.43 | 1605.43 | 0 | 0.11483 | 2700 | 0.306798 | 17650 | 1675.43 | 0.310042 | 3449.86 | 20350 | 2700 | 17650 | 0 | 0.681083 | Face intérieure | Surface-Blanche | Mur-149 | 1-Projet | Sdb | B51 | Etage 5 | 8
Mur-149 | Etage 5 | 1 | 0 | 2500 | 2500 | 1.6932 | 830 | 0.466207 | 1.8928 | 1.8928 | 3421.16 | 6.48509 | 6.48509 | 0.132496 | 3941.16 | 2511.16 | 8.37789 | 2511.16 | 8.37789 | 0.598703 | 8.55289 | 8.55289 | 3421.16 | 3421.16 | 0 | 0.175781 | 2500 | 0.466207 | 17650 | 3421.16 | 0.598703 | 6982.32 | 20150 | 2500 | 17650 | 0 | 0.765262 | Face intérieure | Surface-Blanche | Mur-149 | 1-Projet | Ch 4/Pl | B52 | Etage 5 | 8
Mur-149 | Etage 5 | 2 | 0 | 2700 | 2700 | 2.8764 | 1410 | 0.202433 | 3.12102 | 3.12103 | 2227.01 | 2.6084 | 2.7974 | 0.218472 | 2332.01 | 682.875 | 5.72942 | 752.874 | 5.91842 | 0.420905 | 5.91842 | 6.10742 | 2192.01 | 2262.01 | 0 | 0.0502513 | 2700 | 0.202433 | 17650 | 2262.01 | 0.420905 | 4623.01 | 20350 | 2700 | 17650 | 0 | 0.518928 | Face intérieure | Surface-Blanche | Mur-149 | 1-Projet | Ch 3 | B51 | Etage 5 | 8
Mur-149 | Etage 5 | 1 | 0 | 2500 | 2500 | 2.30995 | 1154.97 | 0.251643 | 2.30995 | 2.30995 | 2361.94 | 3.4199 | 3.5949 | 0.161696 | 2771.94 | 1206.96 | 3.4199 | 1206.96 | 3.5949 | 0.413339 | 5.90485 | 5.90485 | 2361.94 | 2361.94 | 0 | 0.0844875 | 2500 | 0.251643 | 17650 | 2361.94 | 0.413339 | 4863.88 | 20150 | 2500 | 17650 | 0 | 0.459823 | Face intérieure | Surface-Blanche | Mur-149 | 1-Projet | Ch 3/pl | B52 | Etage 5 | 8 | ArchiCADProperties - Zones conflictuelles: Ch 4/Pl
Mur-149 | Etage 5 | 1 | 0 | 2700 | 2700 | 1.6932 | 830 | 0.183118 | 1.8928 | 1.8928 | 1669.92 | 2.37297 | 1.88697 | 0.132496 | 1579.92 | 849.916 | 4.26577 | 669.916 | 3.77977 | 0.315614 | 4.75177 | 4.26577 | 1759.92 | 1579.92 | 0 | 0.0531941 | 2700 | 0.183118 | 17650 | 1759.92 | 0.315614 | 3602.96 | 20350 | 2700 | 17650 | 0 | 0.880545 | Face intérieure | Surface-Blanche | Mur-149 | 1-Projet | Wc | B52 | Etage 5 | 8
Mur-149 | Etage 5 | 0 | 0 | 2700 | 2700 | 0 | 0 | 0.141496 | 0 | 0 | 748.655 | 1.72457 | 1.83216 | 0 | 748.731 | 818.731 | 1.72457 | 678.578 | 1.83216 | 0.141496 | 2.21057 | 1.83216 | 818.731 | 678.578 | 0 | 0.0524058 | 2700 | 0.141496 | 17650 | 818.731 | 0.141496 | 1695.41 | 20350 | 2700 | 17650 | 0 | 0.639675 | Face intérieure | Surface-Blanche | Mur-149 | 1-Projet | Ch 1 | B51 | Etage 5 | 8
Mur-149 | Etage 5 | 1 | 0 | 2700 | 2700 | 1.1832 | 580 | 0.04053 | 1.23 | 1.23 | 670.001 | 0.579 | 0.579 | 0.0860999 | 740 | 70.002 | 1.809 | 70.002 | 1.809 | 0.12663 | 1.809 | 1.809 | 670.001 | 670.002 | 0 | 0.0049 | 2700 | 0.04053 | 17650 | 670 | 0.12663 | 1480 | 20350 | 2700 | 17650 | 0 | 0.2863 | Face intérieure | Surface-Blanche | Mur-149 | 1-Projet | Entree | B52 | Etage 5 | 8
Mur-149 | Etage 5 | 0 | 0 | 2460 | 2460 | 0 | 0 | 0.50599 | 0 | 0 | 2938.39 | 7.14233 | 7.14233 | 0 | 3153.39 | 2903.39 | 7.14233 | 2973.39 | 7.14233 | 0.50599 | 7.14233 | 7.31453 | 2903.39 | 2973.39 | 0 | 0.205687 | 2460 | 0.50599 | 17650 | 2973.39 | 0.50599 | 6045.77 | 20110 | 2460 | 17650 | 0 | 0.827102 | Face intérieure | Surface-Blanche | Mur-149 | 1-Projet | Ch 2/pl | B52 | Etage 5 | 8
Mur-149 | Etage 5 | 0 | 0 | 2700 | 2700 | 0 | 0 | 0.625837 | 0 | 0 | 3311.31 | 8.94053 | 8.94053 | 0 | 3721.31 | 3311.31 | 8.94053 | 3311.31 | 8.94053 | 0.625837 | 8.94053 | 8.94053 | 3311.31 | 3311.31 | 0 | 0.231792 | 2700 | 0.625837 | 17650 | 3311.31 | 0.625837 | 6762.62 | 20350 | 2700 | 17650 | 0 | 0.841583 | Face intérieure | Surface-Blanche | Mur-149 | 1-Projet | Ch 2/pl | B52 | Etage 5 | 8
Mur-149 | Etage 5 | 0 | 0 | 2700 | 2700 | 0 | 0 | 0.327681 | 0 | 0 | 1728.58 | 4.68116 | 4.50616 | 0 | 1798.58 | 1728.58 | 4.68116 | 1728.58 | 4.50616 | 0.327681 | 4.68116 | 4.68116 | 1728.58 | 1728.58 | 0 | 0.1259 | 2700 | 0.327681 | 17650 | 1798.58 | 0.327681 | 3597.16 | 20350 | 2700 | 17650 | 0 | 0.629801 | Face intérieure | Surface-Blanche | Mur-149 | 1-Projet | Cellier | B52 | Etage 5 | 8
Mur-149 | Etage 5 | 0 | 0 | 2700 | 0 | 0 | 0 | 0.120993 | 0 | 0 | 704.988 | 1.63397 | 1.82297 | 0 | 739.988 | 669.988 | 1.63397 | 739.988 | 1.82297 | 0.120993 | 1.63397 | 1.82297 | 669.988 | 739.988 | 0 | 0.0493493 | 2700 | 0.120993 | 17650 | 739.99 | 0.120993 | 1578.97 | 20350 | 2700 | 17650 | 0 | 0.375085 | Face intérieure | Surface-Blanche | Mur-149 | 1-Projet | Entree/pl | B51 | Etage 5 | 8
Mur-149 | Etage 5 | 0 | 0 | 2700 | 2300 | 0 | 0 | 0.0986051 | 0 | 0 | 535 | 1.314 | 1.31601 | 0 | 570 | 570 | 1.314 | 500 | 1.31601 | 0.0986051 | 1.539 | 1.35 | 570 | 500 | 0 | 0.03745 | 2700 | 0.0986051 | 17650 | 570 | 0.101115 | 1238.99 | 20350 | 2700 | 17650 | 0 | 0.528337 | Face intérieure | Surface-Blanche | Mur-149 | 1-Projet | Sdb | B51 | Etage 5 | 8
Mur-149 | Etage 5 | 1 | 0 | 500 | 500 | 5.15883 | 2579.42 | 0.0904756 | 5.15883 | 5.15883 | 2579.42 | 1.29251 | 1.29251 | 0.361118 | 2989.42 | 0 | 1.29251 | 0 | 1.29251 | 0.451594 | 6.45134 | 6.45134 | 2579.42 | 2579.42 | 0 | 0.00490001 | 2500 | 0.0904756 | 17650 | 2649.42 | 0.451594 | 5298.83 | 20150 | 2500 | 19650 | 2000 | 0.260359 | Face intérieure | Surface-Blanche | Mur-149 | 1-Projet | Ch 2/pl | B52 | Etage 5 | 8 | ArchiCADProperties - Zones conflictuelles: Ch 2/pl
Mur-149 | Etage 5 | 0 | 0 | 3000 | 3000 | 0 | 0 | 0.182735 | 0 | 0 | 865 | 2.696 | 2.525 | 0 | 900 | 900 | 2.696 | 830 | 2.525 | 0.182735 | 2.696 | 2.525 | 900 | 830 | 0 | 0.063 | 3000 | 0.182735 | 17650 | 900 | 0.182735 | 1898.99 | 20650 | 3000 | 17650 | 0 | 0.619359 | Face intérieure | Surface-Blanche | Mur-149 | 1-Projet | Sde 2 | B52 | Etage 5 | 8 | ArchiCADProperties - Zones conflictuelles: Terrasse/eng.
Mur-149 | Etage 5 | 2 | 0 | 2700 | 2700 | 4.10741 | 2037.1 | 0.232992 | 4.22701 | 4.22701 | 2798.32 | 3.32846 | 2.95046 | 0.295891 | 2798.32 | 1888.32 | 5.22126 | 1888.32 | 4.84326 | 0.528883 | 7.55547 | 7.55547 | 2798.32 | 2798.32 | 0 | 0.132183 | 2700 | 0.232992 | 17650 | 2798.32 | 0.528883 | 5736.65 | 20350 | 2700 | 17650 | 0 | 0.566065 | Face intérieure | Surface-Blanche | Mur-149 | 1-Projet | Sejour cuisine | B51 | Etage 5 | 8 | ArchiCADProperties - Zones conflictuelles: Sejour cuisine; Wc
Mur-149 | Etage 5 | 0 | 0 | 2500 | 2500 | 0 | 0 | 0.121483 | 0 | 0 | 694.188 | 1.82297 | 1.64797 | 0 | 799.188 | 729.188 | 1.82297 | 659.188 | 1.64797 | 0.121483 | 1.82297 | 1.64797 | 729.188 | 659.188 | 0 | 0.0485932 | 2500 | 0.121483 | 17650 | 729.188 | 0.121483 | 1557.37 | 20150 | 2500 | 17650 | 0 | 0.519674 | Face intérieure | Surface-Blanche | Mur-149 | 1-Projet | Sde 2 | B52 | Etage 5 | 8
Mur-149 | Etage 5 | 0 | 0 | 2700 | 2700 | 0 | 0 | 0.2646 | 0 | 0 | 1400 | 3.78 | 3.78 | 0 | 1470 | 1400 | 3.78 | 1400 | 3.78 | 0.2646 | 3.78 | 3.78 | 1400 | 1400 | 0 | 0.098 | 2700 | 0.2646 | 17650 | 1400 | 0.2646 | 2940 | 20350 | 2700 | 17650 | 0 | 0.574 | Face intérieure | Surface-Blanche | Mur-149 | 1-Projet | Sdb | B51 | Etage 5 | 8
Mur-149 | Etage 5 | 0 | 0 | 2500 | 2500 | 0 | 0 | 0.179238 | 0 | 0 | 1024.22 | 2.47305 | 2.64805 | 0 | 989.219 | 989.219 | 2.47305 | 1059.22 | 2.64805 | 0.179238 | 2.47305 | 2.64805 | 989.219 | 1059.22 | 0 | 0.0716954 | 2500 | 0.179238 | 17650 | 1059.22 | 0.179238 | 2217.43 | 20150 | 2500 | 17650 | 0 | 0.565878 | Face intérieure | Surface-Blanche | Mur-149 | 1-Projet | Ch 4/Pl | B52 | Etage 5 | 8
Mur-121 | Etage 5 | 0 | 0 | 3000 | 3000 | 0 | 0 | 0.0903109 | 0 | 0 | 400.052 | 1.11516 | 1.11516 | 0 | 580.052 | 400.052 | 1.11516 | 400.052 | 1.11516 | 0.0903109 | 1.29016 | 1.29016 | 400.052 | 400.052 | 0 | 0.0406037 | 3000 | 0.0903109 | 17650 | 580.052 | 0.0903109 | 940.104 | 20650 | 3000 | 17650 | 0 | 0.501207 | Face extérieure | Lavis blanc | Mur-121 | 1-Projet |  |  | Etage 5 | 8 | ArchiCADProperties - Zones conflictuelles: Terrasse/eng.
Mur-149 | Etage 5 | 0 | 0 | 2700 | 2700 | 0 | 0 | 0.155145 | 0 | 0 | 820.872 | 1.82486 | 1.93286 | 0 | 785.872 | 855.872 | 1.82486 | 785.872 | 1.93286 | 0.155145 | 2.31086 | 2.12186 | 855.872 | 785.872 | 0 | 0.0574611 | 2700 | 0.155145 | 17650 | 855.872 | 0.155145 | 1810.74 | 20350 | 2700 | 17650 | 0 | 0.571208 | Face intérieure | Surface-Blanche | Mur-149 | 1-Projet | Sejour cuisine | B51 | Etage 5 | 8
Mur-149 | Etage 5 | 0 | 0 | 2500 | 2500 | 0 | 0 | 0.329873 | 0 | 0 | 1884.99 | 4.45017 | 4.62479 | 0 | 1990.07 | 1850.07 | 4.45017 | 1919.92 | 4.62479 | 0.329873 | 4.62517 | 4.79979 | 1850.07 | 1919.92 | 0 | 0.131949 | 2500 | 0.329873 | 17650 | 1919.92 | 0.329873 | 3938.87 | 20150 | 2500 | 17650 | 0 | 0.686118 | Face intérieure | Surface-Blanche | Mur-149 | 1-Projet | Entree/pl | B51 | Etage 5 | 8
Mur-149 | Etage 5 | 1 | 0 | 2500 | 2500 | 2.27393 | 1136.96 | 0.260289 | 2.27393 | 2.27393 | 2396.94 | 3.80592 | 3.45592 | 0.159175 | 2771.94 | 1294.97 | 3.80592 | 1224.97 | 3.45592 | 0.419464 | 6.07985 | 5.90485 | 2431.94 | 2361.94 | 0 | 0.0881982 | 2500 | 0.260289 | 17650 | 2431.94 | 0.419464 | 4962.87 | 20150 | 2500 | 17650 | 0 | 0.678471 | Face intérieure | Surface-Blanche | Mur-149 | 1-Projet | Ch 3/pl | B52 | Etage 5 | 8 | ArchiCADProperties - Zones conflictuelles: Ch 3/pl
Mur-149 | Etage 5 | 0 | 0 | 2500 | 2500 | 0 | 0 | 0.104968 | 0 | 0 | 599.816 | 1.49954 | 1.49954 | 0 | 669.816 | 599.816 | 1.49954 | 599.816 | 1.49954 | 0.104968 | 1.49954 | 1.49954 | 599.816 | 599.816 | 0 | 0.0419871 | 2500 | 0.104968 | 17650 | 599.816 | 0.104968 | 1339.63 | 20150 | 2500 | 17650 | 0 | 0.433974 | Face intérieure | Surface-Blanche | Mur-149 | 1-Projet | Ch 3/pl | B52 | Etage 5 | 8
Mur-149 | Etage 5 | 0 | 0 | 2500 | 2500 | 0 | 0 | 0.186419 | 0 | 0 | 1065.25 | 2.66313 | 2.48813 | 0 | 1065.25 | 1065.25 | 2.66313 | 1065.25 | 2.48813 | 0.186419 | 2.66313 | 2.66313 | 1065.25 | 1065.25 | 0 | 0.0745677 | 2500 | 0.186419 | 17650 | 1135.25 | 0.186419 | 2328.5 | 20150 | 2500 | 17650 | 0 | 0.64411 | Face intérieure | Surface-Blanche | Mur-149 | 1-Projet | Ch 3/pl | B52 | Etage 5 | 8
Mur-149 | Etage 5 | 0 | 0 | 2700 | 2700 | 0 | 0 | 0.0496263 | 0 | 0 | 262.573 | 0.803448 | 0.614448 | 0 | 367.573 | 297.573 | 0.803448 | 227.573 | 0.614448 | 0.0496263 | 0.803448 | 0.614448 | 297.573 | 227.573 | 0 | 0.0183801 | 2700 | 0.0496263 | 17650 | 297.573 | 0.0496263 | 694.141 | 20350 | 2700 | 17650 | 0 | 0.493047 | Face intérieure | Surface-Blanche | Mur-149 | 1-Projet | sde | B51 | Etage 5 | 8
Mur-149 | Etage 5 | 0 | 0 | 2700 | 2700 | 0 | 0 | 0.106786 | 0 | 0 | 565.006 | 1.62002 | 1.43102 | 0 | 780.007 | 600.007 | 1.62002 | 530.006 | 1.43102 | 0.106786 | 1.62002 | 1.43102 | 600.007 | 530.006 | 0 | 0.0395504 | 2700 | 0.106786 | 17650 | 600.007 | 0.106786 | 1299.01 | 20350 | 2700 | 17650 | 0 | 0.535387 | Face intérieure | Surface-Blanche | Mur-149 | 1-Projet | sde | B51 | Etage 5 | 8
Mur-149 | Etage 5 | 0 | 1 | 2700 | 2700 | 0 | 0 | 0.0736182 | 3.00909 | 3.00909 | 1503.99 | 1.05169 | 1.05169 | 0.210636 | 1574 | 28.9485 | 1.05169 | 28.9485 | 1.05169 | 0.284254 | 4.06078 | 4.06078 | 1503.99 | 1503.99 | 3.00909 | 0.0020264 | 2700 | 0.0736182 | 17650 | 1503.99 | 0.284254 | 3147.98 | 20350 | 2700 | 17650 | 0 | 0.342506 | Face intérieure | Surface-Blanche | Mur-149 | 1-Projet | Ch 1 | B54 | Etage 5 | 8
Mur-149 | Etage 5 | 1 | 0 | 2700 | 2700 | 1.6932 | 830 | 0.861297 | 1.8928 | 1.8928 | 5258.17 | 11.7372 | 12.1152 | 0.132496 | 5598.17 | 4348.17 | 13.63 | 4348.17 | 14.008 | 0.993793 | 14.197 | 14.197 | 5258.17 | 5258.17 | 0 | 0.304372 | 2700 | 0.861297 | 17650 | 5258.17 | 0.993793 | 10656.3 | 20350 | 2700 | 17650 | 0 | 0.904843 | Face intérieure | Surface-Blanche | Mur-149 | 1-Projet | Sejour Cuisine | B54 | Etage 5 | 8
Mur-149 | Etage 5 | 0 | 0 | 2700 | 2700 | 0 | 0 | 0.100005 | 0 | 0 | 529.124 | 1.42878 | 1.42849 | 0 | 779.179 | 529.177 | 1.42878 | 529.072 | 1.42849 | 0.100005 | 1.42878 | 1.42849 | 529.177 | 529.072 | 0 | 0.0370387 | 2700 | 0.100005 | 17650 | 529.374 | 0.100005 | 1198.25 | 20350 | 2700 | 17650 | 0 | 0.45208 | Face intérieure | Surface-Blanche | Mur-149 | 1-Projet | Sde 1 | B52 | Etage 5 | 8
Mur-149 | Etage 5 | 0 | 0 | 2460 | 2460 | 0 | 0 | 0.503407 | 0 | 0 | 2923.39 | 7.06853 | 7.31453 | 0 | 3153.39 | 2873.39 | 7.06853 | 2973.39 | 7.31453 | 0.503407 | 7.06853 | 7.31453 | 2873.39 | 2973.39 | 0 | 0.204637 | 2460 | 0.503407 | 17650 | 2973.39 | 0.503407 | 6038.84 | 20110 | 2460 | 17650 | 0 | 0.881756 | Face intérieure | Surface-Blanche | Mur-149 | 1-Projet | Ch 1 | B54 | Etage 5 | 8
Mur-149 | Etage 5 | 1 | 0 | 2700 | 2700 | 1.02 | 500 | 0.185018 | 1.066 | 1.066 | 1373.75 | 2.73763 | 2.3596 | 0.07462 | 1408.75 | 888.75 | 3.80363 | 818.75 | 3.4256 | 0.259638 | 3.80363 | 3.6146 | 1408.75 | 1338.75 | 0 | 0.0597625 | 2700 | 0.185018 | 17650 | 1408.85 | 0.259638 | 2916.57 | 20350 | 2700 | 17650 | 0 | 0.612412 | Face intérieure | Surface-Blanche | Mur-149 | 1-Projet | Sde 1 | B52 | Etage 5 | 8 | ArchiCADProperties - Zones conflictuelles: Sde 1
Mur-149 | Etage 5 | 0 | 0 | 2700 | 2700 | 0 | 0 | 0.106775 | 0 | 0 | 564.948 | 1.62 | 1.43072 | 0 | 600 | 600 | 1.62 | 529.895 | 1.43072 | 0.106775 | 1.62 | 1.43072 | 600 | 529.895 | 0 | 0.0395463 | 2700 | 0.106775 | 17650 | 600 | 0.106775 | 1298.96 | 20350 | 2700 | 17650 | 0 | 0.535579 | Face intérieure | Surface-Blanche | Mur-149 | 1-Projet | Sde 1 | B52 | Etage 5 | 8
Mur-149 | Etage 5 | 0 | 0 | 3000 | 3000 | 0 | 0 | 0.0690409 | 0 | 0 | 319.766 | 1.3343 | 0.638299 | 0 | 444.766 | 444.766 | 1.3343 | 194.766 | 0.638299 | 0.0690409 | 1.3343 | 0.638299 | 444.766 | 194.766 | 0 | 0.0286836 | 3000 | 0.0690409 | 17650 | 444.766 | 0.0690409 | 931.66 | 20650 | 3000 | 17650 | 0 | 0.896809 | Face intérieure | Surface-Blanche | Mur-149 | 1-Projet | Sejour Cuisine | B52 | Etage 5 | 8 | ArchiCADProperties - Zones conflictuelles: Terrasse/eng.
Mur-149 | Etage 5 | 0 | 0 | 2700 | 2700 | 0 | 0 | 0.242865 | 0 | 0 | 1285 | 3.375 | 3.375 | 0 | 1320 | 1320 | 3.375 | 1250 | 3.375 | 0.242865 | 3.564 | 3.375 | 1320 | 1250 | 0 | 0.08995 | 2700 | 0.242865 | 17650 | 1320 | 0.242865 | 2738.99 | 20350 | 2700 | 17650 | 0 | 0.636186 | Face intérieure | Surface-Blanche | Mur-149 | 1-Projet | Sejour Cuisine | B54 | Etage 5 | 8
Mur-149 | Etage 5 | 0 | 0 | 2700 | 2700 | 0 | 0 | 0.17577 | 0 | 0 | 930 | 2.511 | 2.511 | 0 | 1000 | 930 | 2.511 | 930 | 2.511 | 0.17577 | 2.511 | 2.511 | 930 | 930 | 0 | 0.0651 | 2700 | 0.17577 | 17650 | 930 | 0.17577 | 2000 | 20350 | 2700 | 17650 | 0 | 0.5082 | Face intérieure | Surface-Blanche | Mur-149 | 1-Projet | cellier | B54 | Etage 5 | 8
Mur-149 | Etage 5 | 0 | 0 | 2700 | 2700 | 0 | 0 | 0.233168 | 0 | 0 | 1233.7 | 3.33098 | 3.33098 | 0 | 1233.69 | 1233.7 | 3.33098 | 1233.7 | 3.33098 | 0.233168 | 3.33098 | 3.33098 | 1233.7 | 1233.7 | 0 | 0.0863586 | 2700 | 0.233168 | 17650 | 1233.69 | 0.233168 | 2607.39 | 20350 | 2700 | 17650 | 0 | 0.550717 | Face intérieure | Surface-Blanche | Mur-149 | 1-Projet | Sejour Cuisine | B54 | Etage 5 | 8
Mur-120 | Etage 5 | 0 | 0 | 2460 | 2460 | 0 | 0 | 0.0869144 | 0 | 0 | 504.729 | 1.41383 | 1.06943 | 0 | 915.562 | 574.729 | 1.41383 | 434.729 | 1.06943 | 0.0869144 | 1.41383 | 1.06943 | 574.729 | 434.729 | 0 | 0.035331 | 2460 | 0.0869144 | 17650 | 574.729 | 0.0869144 | 1207.45 | 20110 | 2460 | 17650 | 0 | 0.557717 | Face extérieure | Lavis blanc | Mur-120 | 3D |  |  | Etage 5 | 8
Mur-149 | Etage 5 | 0 | 0 | 2700 | 2700 | 0 | 0 | 0.352499 | 0 | 0 | 1865.08 | 5.13021 | 4.94121 | 0 | 1900.08 | 1900.08 | 5.13021 | 1830.08 | 4.94121 | 0.352499 | 5.13021 | 4.94121 | 1900.08 | 1830.08 | 0 | 0.130555 | 2700 | 0.352499 | 17650 | 1900.08 | 0.352499 | 3899.15 | 20350 | 2700 | 17650 | 0 | 0.717397 | Face intérieure | Surface-Blanche | Mur-149 | 1-Projet | Entree | B52 | Etage 5 | 8
Mur-149 | Etage 5 | 1 | 0 | 2700 | 2700 | 1.6932 | 830 | 0.22223 | 1.8928 | 1.8928 | 1876.86 | 3.17471 | 2.98571 | 0.132496 | 1876.86 | 966.856 | 5.06751 | 966.856 | 4.87851 | 0.354726 | 5.06751 | 5.06751 | 1876.86 | 1876.86 | 0 | 0.0676799 | 2700 | 0.22223 | 17650 | 1876.86 | 0.354726 | 3893.71 | 20350 | 2700 | 17650 | 0 | 0.57706 | Face intérieure | Surface-Blanche | Mur-149 | 1-Projet | Sde 1 | B52 | Etage 5 | 8
Mur-149 | Etage 5 | 1 | 0 | 2700 | 2700 | 1.6932 | 830 | 0.247964 | 1.8928 | 1.8928 | 2013.01 | 3.25885 | 3.63685 | 0.132496 | 2048.02 | 1068.01 | 5.15165 | 1138.01 | 5.52965 | 0.38046 | 5.34065 | 5.52965 | 1978.01 | 2048.01 | 0 | 0.0772113 | 2700 | 0.247964 | 17650 | 2048.02 | 0.38046 | 4195.02 | 20350 | 2700 | 17650 | 0 | 0.674409 | Face intérieure | Surface-Blanche | Mur-149 | 1-Projet | Sejour Cuisine | B54 | Etage 5 | 8
Mur-121 | Etage 5 | 0 | 0 | 3000 | 0 | 0 | 0 | 0.0780609 | 0 | 0 | 400.052 | 1.11516 | 1.11516 | 0 | 580.052 | 400.052 | 1.11516 | 400.052 | 1.11516 | 0.0780609 | 1.11516 | 1.11516 | 400.052 | 400.052 | 0 | 0.0406037 | 3000 | 0.0780609 | 17650 | 580.052 | 0.0780609 | 940.104 | 20650 | 3000 | 17650 | 0 | 0.496307 | Face extérieure | Lavis blanc | Mur-121 | 1-Projet |  |  | Etage 5 | 8 | ArchiCADProperties - Zones conflictuelles: Terrasse/eng.
Mur-120 | Etage 5 | 7 | 0 | 2500 | 0 | 7.2216 | 3540 | 0.304822 | 7.544 | 7.544 | 4829.44 | 3.4796 | 3.4796 | 0.52808 | 5009.44 | 1919.44 | 8.4816 | 1919.44 | 8.4816 | 0.832902 | 11.8986 | 11.8986 | 4829.44 | 4829.44 | 0 | 0.0755608 | 2500 | 0.304822 | 17650 | 4759.44 | 0.832902 | 9798.88 | 20150 | 2500 | 17650 | 0 | 0.758722 | Face extérieure | Peinture-01 | Mur-120 | 3D |  |  | Etage 5 | 8

# IfcWallStandardCase: Cloison 70 0836576958 70 (90)
Classification: Mur (Classification ARCHICAD); Material: Hachure solide 269229667 70 mm
AC_Pset_RenovationAndPhasing - Renovation Status: Existing
ArchiCADProperties - Complexité de mur: Droit; Option de géométrie: Uniforme; Emplacement de ligne de référence: Face extérieure; Angle d'inclinaison interne de mur: 90 deg; Angle d'inclinaison externe de mur: 90 deg; ID de l'élément: Mur-148; Lien et ID d'élément: Mur-148; Calque: 1-Projet; Matériau de construction / Composite / Profil / Hachure: Cloison 70 0836576958; Structure Composite: Cloison 70 0836576958; Verrouillé: no; Type d'élément: Mur; Étage supérieur lié absolu: Non lié; Étage supérieur lié relatif: Non lié; Étage supérieur lié: Non lié; Type de structure: Composite; ID de Parent: Mur-148; Matériaux de construction (Tous): Hachure solide 269229667; Angle d'inclinaison: 90 deg; Nombre de percements: 0; Nom de Variante: Modèle principal; Nom de Jeu de Variantes: Modèle principal; Position: Non défini; Fonction structurelle: Non défini; Affichage sur filtre de rénovation: Tous les filtres appropriés; État de rénovation: Existant; État de Variante: Modèle principal; Jeu de Variantes: Modèle principal
ArchiCADQuantities - Nombre de Fenêtres: 0; Nombre de Poteaux: 0; Volume des poteaux: 0 m3; Épaisseur couche d'air: 0 mm; Épaisseur de composant de mur sur face intérieure: 70 mm; Épaisseur de composant de mur sur face extérieure: 70 mm; Superficie des fenêtres: 0 m2; Largeur totale des Fenêtres: 0 mm; Épaisseur du Mur à la fin: 70 mm; Largeur: 70 mm; Altitude à étage lié/étage d'implantation: 0 mm; Décalage étage d'implantation: 0 mm; Décalage supérieur: 0 mm; Épaisseur: 70 mm; Épaisseur couche isolation: 0 mm
Name | In | Surface de face intérieure = Surface de face extérieure = Surfaces (Toutes) = Surface latérale | Nom de zone liée | Numéro de zone liée | Nom d'étage d'implantation | Numéro d'étage d'implantation | Nombre de Portes | Nombre de trous (Nombre d'ouvertures vides) | Hauteur maximale de la couche de Mur sur face intérieure (mm) = Hauteur maximale du Mur (mm) = Hauteur maximale de la couche de Mur sur face extérieure (mm) = Hauteur (mm) = Altitude supérieure à étage d'implantation (mm) | Hauteur minimale de la couche de Mur sur face intérieure (mm) = Hauteur minimale du Mur (mm) = Hauteur minimale de la couche de Mur sur face extérieure (mm) | Superficie des portes (m2) | Largeur totale des Portes (mm) | Volume de composant de mur sur face intérieure (net) (m3) = Volume de composant de mur sur face extérieure (net) (m3) = Volume (net) (m3) | Superficie analytique des ouvertures sur face intérieure (m2) | Superficie analytique des ouvertures sur face extérieure (m2) | Longueur moyenne du mur (mm) = Longueur du Mur au centre (mm) | Superficie de la face intérieure du mur (nette) (m2) | Superficie de la face extérieure du mur (nette) (m2) = Superficie en plan (m2) = Superficie inférieure (nette) (m2) | Volume analytique des ouvertures (m3) | Longueur de ligne de référence (mm) | Longueur de la face intérieure du mur (conditionnelle) (mm) | Superficie de la face intérieure du mur (conditionnelle) (m2) | Longueur de la face extérieure du mur (conditionnelle) (mm) | Superficie de la face extérieure du mur (conditionnelle) (m2) | Volume du composant face intérieure du mur (conditionnel) (m3) = Volume du composant face extérieure du mur (conditionnel) (m3) = Volume (conditionnel) (m3) = Volume (brut) (m3) | Superficie de la face intérieure du mur (brute) (m2) | Superficie de la face extérieure du mur (brute) (m2) | Longueur de Mur sur face intérieure (mm) | Longueur de Mur sur face extérieure (mm) | Superficie des baies libres dans le Mur (m2) | Superficie (m2) = Superficie supérieure (nette) (m2) | Altitude à Zéro du Projet (mm) = Altitude de Référence Niveau 1 (mm) = Altitude de Référence Niveau 2 (mm) = Altitude à niveau de la mer (mm) = Altitude inférieure à premier niveau de référence (mm) = Altitude inférieure à Zéro du projet (mm) = Altitude inférieure à niveau de la mer (mm) = Altitude inférieure à deuxième niveau de référence (mm) | Longueur 3D (mm) | Périmètre Plan (mm) | Altitude supérieure à premier niveau de référence (mm) = Altitude supérieure à Zéro du projet (mm) = Altitude supérieure à niveau de la mer (mm) = Altitude supérieure à deuxième niveau de référence (mm) | Altitude inférieure à étage d'implantation (mm) | Superficie de l'arête (nette) (m2)
Mur-148 | rdc | Surface-Blanche | Sejour cuisine | A03 | rdc | 3 | 0 | 0 | 3000 | 3000 | 0 | 0 | 0.290636 | 0 | 0 | 1383.98 | 4.36215 | 3.94174 | 0 | 1383.91 | 1454.05 | 4.36215 | 1313.91 | 3.94174 | 0.290636 | 4.36215 | 3.94174 | 1454.05 | 1313.91 | 0 | 0.0968787 | 3000 | 1454.05 | 2966.05 | 6000 | 0 | 0.788016
Mur-148 | rdc | Peinture-01 | Dgt | A04 | rdc | 3 | 1 | 0 | 2700 | 2700 | 1.1832 | 580 | 0.046891 | 1.23 | 1.23 | 703.656 | 0.575371 | 0.764371 | 0.0861 | 738.656 | 68.656 | 1.80537 | 138.656 | 1.99437 | 0.132991 | 1.80537 | 1.99437 | 668.656 | 738.656 | 0 | 0.00725592 | 3000 | 738.656 | 1576.31 | 5700 | 0 | 0.512798
Mur-148 | rdc | Peinture-01 | Sdb/pl | A02 | rdc | 3 | 0 | 0 | 2700 | 0 | 0 | 0 | 0.0938531 | 0 | 0 | 566.577 | 1.34076 | 1.34076 | 0 | 566.577 | 566.577 | 1.34076 | 566.577 | 1.34076 | 0.0938531 | 1.34076 | 1.34076 | 566.577 | 566.577 | 0 | 0.0347604 | 3000 | 496.593 | 1273.15 | 5700 | 0 | 0.447521 | ArchiCADProperties - Zones conflictuelles: Sdb/pl
Mur-148 | rdc | Peinture-01 | Dgt | A04 | rdc | 3 | 0 | 1 | 2700 | 0 | 0 | 0 | 0.188843 | 2.75828 | 2.75832 | 2090.76 | 2.69776 | 2.69777 | 0.193081 | 2160.77 | 738.656 | 2.69776 | 738.656 | 2.69777 | 0.381924 | 5.45603 | 5.45608 | 2090.75 | 2090.77 | 2.75832 | 0.0468059 | 3000 | 2020.77 | 4321.53 | 5700 | 0 | 0.423459 | ArchiCADProperties - Zones conflictuelles: Dgt
Mur-148 | rdc | Peinture-01 | Wc | A04 | rdc | 3 | 0 | 0 | 2700 | 2700 | 0 | 0 | 0.296811 | 0 | 0 | 1570.43 | 4.05118 | 4.24014 | 0 | 1570.42 | 1570.44 | 4.05118 | 1570.42 | 4.24014 | 0.296811 | 4.24018 | 4.24014 | 1570.44 | 1570.42 | 0 | 0.10993 | 3000 | 1570.44 | 3280.86 | 5700 | 0 | 0.59786
Mur-148 | rdc | Peinture-01 | Sejour cuisine | B05 | rdc | 3 | 0 | 0 | 2700 | 2700 | 0 | 0 | 0.295925 | 0 | 0 | 1555 | 4.126 | 4.14 | 0 | 1700 | 1590 | 4.126 | 1520 | 4.14 | 0.295925 | 4.315 | 4.14 | 1590 | 1520 | 0 | 0.12145 | 3000 | 1770 | 3278.99 | 5700 | 0 | 0.693387
Mur-148 | rdc | Peinture-01 | Sejour cuisine | B05 | rdc | 3 | 0 | 0 | 2700 | 2700 | 0 | 0 | 0.12663 | 0 | 0 | 670 | 1.62 | 1.998 | 0 | 740 | 600 | 1.62 | 740 | 1.998 | 0.12663 | 1.62 | 1.998 | 600 | 740 | 0 | 0.0469 | 3000 | 740 | 1537.99 | 5700 | 0 | 0.628373
Mur-148 | rdc | Peinture-01 | Sejour cuisine | B05 | rdc | 3 | 0 | 0 | 2700 | 2700 | 0 | 0 | 0.110625 | 0 | 0 | 705 | 1.4855 | 1.6752 | 0 | 740 | 670 | 1.4855 | 740 | 1.6752 | 0.110625 | 1.4855 | 1.6752 | 670 | 740 | 0 | 0.0469 | 3000 | 740 | 1578.99 | 5700 | 0 | 0.550376
Mur-148 | rdc | Surface-Blanche |  |  | rdc | 3 | 0 | 0 | 3000 | 3000 | 0 | 0 | 0.104714 | 0 | 0 | 505.055 | 1.68662 | 1.30522 | 0 | 435.073 | 575.037 | 1.68662 | 435.073 | 1.30522 | 0.104714 | 1.68662 | 1.30522 | 575.037 | 435.073 | 0 | 0.0353539 | 3000 | 575.037 | 1208.07 | 6000 | 0 | 0.648661
Mur-148 | rdc | Peinture-01 | Sejour cuisine | B05 | rdc | 3 | 0 | 0 | 2700 | 2700 | 0 | 0 | 0.0965045 | 0 | 0 | 580.455 | 1.28379 | 1.47349 | 0 | 615.476 | 545.433 | 1.28379 | 615.476 | 1.47349 | 0.0965045 | 1.28379 | 1.47349 | 545.433 | 615.476 | 0 | 0.0381833 | 3000 | 615.476 | 1329.9 | 5700 | 0 | 0.532943
Mur-148 | rdc | Peinture-01 | Sejour cuisine | B05 | rdc | 3 | 0 | 0 | 2700 | 2700 | 0 | 0 | 0.103095 | 0 | 0 | 545.476 | 1.28379 | 1.66179 | 0 | 615.476 | 475.476 | 1.28379 | 615.476 | 1.66179 | 0.103095 | 1.28379 | 1.66179 | 475.476 | 615.476 | 0 | 0.0381833 | 3000 | 615.476 | 1288.94 | 5700 | 0 | 0.610939
Mur-148 | rdc | Surface-Blanche | Sdb/pl | A02 | rdc | 3 | 0 | 0 | 3000 | 3000 | 0 | 0 | 0.111633 | 0 | 0 | 531.585 | 1.48978 | 1.69973 | 0 | 566.577 | 496.593 | 1.48978 | 566.577 | 1.69973 | 0.111633 | 1.48978 | 1.69973 | 496.593 | 566.577 | 0 | 0.0372109 | 3000 | 566.577 | 1232.15 | 6000 | 0 | 0.581373
Mur-148 | rdc | Surface-Blanche | Sdb/pl | A02 | rdc | 3 | 0 | 0 | 3000 | 3000 | 0 | 0 | 0.118981 | 0 | 0 | 566.577 | 1.48973 | 1.48973 | 0 | 566.577 | 566.577 | 1.48973 | 566.577 | 1.48973 | 0.118981 | 1.69973 | 1.69973 | 566.577 | 566.577 | 0 | 0.0396604 | 3000 | 566.577 | 1273.15 | 6000 | 0 | 0.499321 | ArchiCADProperties - Zones conflictuelles: Sdb/pl; Sde
Mur-148 | rdc | Peinture-01 | Sejour cuisine | B05 | rdc | 3 | 0 | 0 | 2700 | 2700 | 0 | 0 | 0.113578 | 0 | 0 | 603.533 | 1.53504 | 1.71004 | 0 | 638.534 | 568.533 | 1.53504 | 638.533 | 1.71004 | 0.113578 | 1.53504 | 1.71004 | 568.533 | 638.533 | 0 | 0.0422473 | 3000 | 638.533 | 1376.06 | 5700 | 0 | 0.534981
Mur-148 | Etage1 | Surface-Blanche | Wc | A13 | Etage1 | 4 | 0 | 0 | 3000 | 3000 | 0 | 0 | 0.297991 | 0 | 0 | 1419 | 3.94185 | 4.36217 | 0 | 1454.06 | 1383.95 | 3.94185 | 1454.06 | 4.36217 | 0.297991 | 4.15185 | 4.36217 | 1383.95 | 1454.06 | 0 | 0.0993303 | 5750 | 1454.06 | 3007.08 | 8750 | 0 | 0.705872 | ArchiCADProperties - Zones conflictuelles: Sejour cuisine; Sejour cuisine
Mur-148 | Etage1 | Peinture-01 | Wc | A14 | Etage1 | 4 | 0 | 0 | 2700 | 0 | 0 | 0 | 0.282933 | 0 | 0 | 1567 | 4.0419 | 4.0419 | 0 | 1567 | 1567 | 4.0419 | 1567 | 4.0419 | 0.282933 | 4.0419 | 4.0419 | 1567 | 1567 | 0 | 0.10479 | 5750 | 1497 | 3274 | 8450 | 0 | 0.58758 | ArchiCADProperties - Zones conflictuelles: Cellier
Mur-148 | Etage1 | Surface-Blanche | Sde | A12 | Etage1 | 4 | 0 | 0 | 2700 | 0 | 0 | 0 | 0.0938531 | 0 | 0 | 566.577 | 1.34076 | 1.34076 | 0 | 566.577 | 566.577 | 1.34076 | 566.577 | 1.34076 | 0.0938531 | 1.34076 | 1.34076 | 566.577 | 566.577 | 0 | 0.0347604 | 5750 | 496.593 | 1273.15 | 8450 | 0 | 0.447521 | ArchiCADProperties - Zones conflictuelles: Sde
Mur-148 | Etage1 | Surface-Blanche | Sejour cuisine | B11 | Etage1 | 4 | 0 | 0 | 2700 | 2700 | 0 | 0 | 0.123679 | 0 | 0 | 654.385 | 1.67234 | 1.86134 | 0 | 869.385 | 619.385 | 1.67234 | 689.385 | 1.86134 | 0.123679 | 1.67234 | 1.86134 | 619.385 | 689.385 | 0 | 0.0458069 | 5750 | 689.385 | 1477.76 | 8450 | 0 | 0.5479
Mur-148 | Etage1 | Surface-Blanche | Sde | A12 | Etage1 | 4 | 0 | 0 | 3000 | 3000 | 0 | 0 | 0.111633 | 0 | 0 | 531.585 | 1.48978 | 1.69973 | 0 | 566.577 | 496.593 | 1.48978 | 566.577 | 1.69973 | 0.111633 | 1.48978 | 1.69973 | 496.593 | 566.577 | 0 | 0.0372109 | 5750 | 566.577 | 1232.15 | 8750 | 0 | 0.581373
Mur-148 | Etage1 | Peinture-01 | Sejour Cuisine/pl | A14 | Etage1 | 4 | 0 | 0 | 2700 | 2700 | 0 | 0 | 0.126376 | 0 | 0 | 668.656 | 1.80537 | 1.80537 | 0 | 738.656 | 668.656 | 1.80537 | 668.656 | 1.80537 | 0.126376 | 1.80537 | 1.80537 | 668.656 | 668.656 | 0 | 0.0468059 | 5750 | 668.656 | 1477.31 | 8450 | 0 | 0.471612
Mur-148 | Etage1 | Peinture-01 | Sejour cuisine | B16 | Etage1 | 4 | 0 | 0 | 2700 | 2700 | 0 | 0 | 0.113578 | 0 | 0 | 603.533 | 1.53504 | 1.71004 | 0 | 638.534 | 568.533 | 1.53504 | 638.533 | 1.71004 | 0.113578 | 1.53504 | 1.71004 | 568.533 | 638.533 | 0 | 0.0422473 | 5750 | 638.533 | 1376.06 | 8450 | 0 | 0.534981
Mur-148 | Etage1 | Peinture-01 | Sejour cuisine | B16 | Etage1 | 4 | 0 | 0 | 2700 | 2700 | 0 | 0 | 0.295925 | 0 | 0 | 1555 | 4.126 | 4.14 | 0 | 1700 | 1590 | 4.126 | 1520 | 4.14 | 0.295925 | 4.315 | 4.14 | 1590 | 1520 | 0 | 0.12145 | 5750 | 1770 | 3278.99 | 8450 | 0 | 0.693387
Mur-148 | Etage1 | Surface-Blanche | Sejour cuisine/pl | A15 | Etage1 | 4 | 0 | 0 | 2700 | 2700 | 0 | 0 | 0.121118 | 0 | 0 | 640.838 | 1.63576 | 1.82476 | 0 | 1015.84 | 605.838 | 1.63576 | 675.838 | 1.82476 | 0.121118 | 1.63576 | 1.82476 | 605.838 | 675.838 | 0 | 0.0448587 | 5750 | 675.838 | 1450.64 | 8450 | 0 | 0.54592
Mur-148 | Etage1 | Surface-Blanche | Sejour cuisine/pl | A15 | Etage1 | 4 | 0 | 0 | 2700 | 0 | 0 | 0 | 0.123683 | 0 | 0 | 834.407 | 1.67246 | 1.86134 | 0 | 869.385 | 799.429 | 1.67246 | 869.385 | 1.86134 | 0.123683 | 1.67246 | 1.86134 | 799.429 | 869.385 | 0 | 0.0458085 | 5750 | 689.385 | 1837.78 | 8450 | 0 | 0.35882
Mur-148 | Etage1 | Peinture-01 | Sejour cuisine | B16 | Etage1 | 4 | 0 | 0 | 2700 | 2700 | 0 | 0 | 0.13986 | 0 | 0 | 740 | 1.998 | 1.998 | 0 | 740 | 740 | 1.998 | 740 | 1.998 | 0.13986 | 1.998 | 1.998 | 740 | 740 | 0 | 0.0518 | 5750 | 740 | 1620 | 8450 | 0 | 0.4816
Mur-148 | Etage1 | Peinture-01 | Dgt | A14 | Etage1 | 4 | 1 | 1 | 2700 | 2700 | 1.1832 | 580 | 0.116242 | 3.98421 | 3.98426 | 2090.68 | 1.66059 | 1.2826 | 0.278896 | 2160.69 | 140.566 | 2.89059 | 140.563 | 2.5126 | 0.395138 | 5.6448 | 5.64486 | 2090.67 | 2090.69 | 2.75426 | 0.00983944 | 5750 | 2090.69 | 4321.36 | 8450 | 0 | 0.391387 | ArchiCADProperties - Zones conflictuelles: Sejour Cuisine/pl
Mur-148 | Etage1 | Peinture-01 | Sejour cuisine | B16 | Etage1 | 4 | 1 | 0 | 2700 | 2700 | 0.918 | 450 | 0.124132 | 0.925727 | 0.925727 | 1069.5 | 1.58397 | 1.77367 | 0.0648009 | 1069.52 | 617.9 | 2.5097 | 617.943 | 2.6994 | 0.188933 | 2.6987 | 2.6994 | 1069.47 | 1069.52 | 0 | 0.040806 | 5750 | 1069.52 | 2278.99 | 8450 | 0 | 0.348012
Mur-148 | Etage1 | Peinture-01 | Sejour cuisine | B16 | Etage1 | 4 | 0 | 0 | 2700 | 2700 | 0 | 0 | 0.110625 | 0 | 0 | 705 | 1.4855 | 1.6752 | 0 | 740 | 670 | 1.4855 | 740 | 1.6752 | 0.110625 | 1.4855 | 1.6752 | 670 | 740 | 0 | 0.0469 | 5750 | 740 | 1578.99 | 8450 | 0 | 0.550376
Mur-148 | Etage1 | Peinture-01 | Sejour cuisine | B16 | Etage1 | 4 | 0 | 0 | 2700 | 2700 | 0 | 0 | 0.120015 | 0 | 0 | 635 | 1.62 | 1.809 | 0 | 740 | 600 | 1.62 | 670 | 1.809 | 0.120015 | 1.62 | 1.809 | 600 | 670 | 0 | 0.04445 | 5750 | 670 | 1438.99 | 8450 | 0 | 0.545186
Mur-148 | Etage1 | Peinture-01 | Sejour cuisine | B16 | Etage1 | 4 | 0 | 0 | 2700 | 2700 | 0 | 0 | 0.103095 | 0 | 0 | 545.476 | 1.28379 | 1.66179 | 0 | 615.476 | 475.476 | 1.28379 | 615.476 | 1.66179 | 0.103095 | 1.28379 | 1.66179 | 475.476 | 615.476 | 0 | 0.0381833 | 5750 | 615.476 | 1288.94 | 8450 | 0 | 0.610939
Mur-148 | Etage1 | Surface-Blanche |  |  | Etage1 | 4 | 0 | 0 | 3000 | 3000 | 0 | 0 | 0.104714 | 0 | 0 | 505.055 | 1.68662 | 1.30522 | 0 | 435.073 | 575.037 | 1.68662 | 435.073 | 1.30522 | 0.104714 | 1.68662 | 1.30522 | 575.037 | 435.073 | 0 | 0.0353539 | 5750 | 575.037 | 1208.07 | 8750 | 0 | 0.648661
Mur-148 | Etage1 | Surface-Blanche | Sde | A12 | Etage1 | 4 | 0 | 0 | 3000 | 3000 | 0 | 0 | 0.118981 | 0 | 0 | 566.577 | 1.48973 | 1.48973 | 0 | 566.577 | 566.577 | 1.48973 | 566.577 | 1.48973 | 0.118981 | 1.69973 | 1.69973 | 566.577 | 566.577 | 0 | 0.0396604 | 5750 | 566.577 | 1273.15 | 8750 | 0 | 0.499321 | ArchiCADProperties - Zones conflictuelles: Sde
Mur-148 | Etage 2 | Surface-Blanche | Sde | A22 | Etage 2 | 5 | 0 | 0 | 3000 | 3000 | 0 | 0 | 0.118981 | 0 | 0 | 566.577 | 1.48973 | 1.48973 | 0 | 566.577 | 566.577 | 1.48973 | 566.577 | 1.48973 | 0.118981 | 1.69973 | 1.69973 | 566.577 | 566.577 | 0 | 0.0396604 | 8500 | 566.577 | 1273.15 | 11500 | 0 | 0.499321
Mur-148 | Etage 2 | Peinture-01 | Wc | B26 | Etage 2 | 5 | 0 | 0 | 2700 | 2700 | 0 | 0 | 0.293405 | 0 | 0 | 1555 | 4.09 | 4.104 | 0 | 1700 | 1590 | 4.09 | 1520 | 4.104 | 0.293405 | 4.279 | 4.104 | 1590 | 1520 | 0 | 0.10885 | 8500 | 1590 | 3278.99 | 11200 | 0 | 0.668187
Mur-148 | Etage 2 | Surface-Blanche | Sejour cuisine | B21 | Etage 2 | 5 | 0 | 0 | 3000 | 3000 | 0 | 0 | 0.137421 | 0 | 0 | 654.385 | 1.85815 | 2.06816 | 0 | 869.385 | 619.385 | 1.85815 | 689.385 | 2.06816 | 0.137421 | 1.85815 | 2.06816 | 619.385 | 689.385 | 0 | 0.0458069 | 8500 | 689.385 | 1477.76 | 11500 | 0 | 0.598599
Mur-148 | Etage 2 | Surface-Blanche | Sejour cuisine | A23 | Etage 2 | 5 | 0 | 0 | 3000 | 3000 | 0 | 0 | 0.290607 | 0 | 0 | 1383.84 | 3.94131 | 4.36174 | 0 | 1383.91 | 1313.77 | 3.94131 | 1453.91 | 4.36174 | 0.290607 | 3.94131 | 4.36174 | 1313.77 | 1453.91 | 0 | 0.096869 | 8500 | 1453.91 | 2965.78 | 11500 | 0 | 0.788011
Mur-148 | Etage 2 | Peinture-01 |  |  | Etage 2 | 5 | 0 | 0 | 2700 | 2700 | 0 | 0 | 0.296163 | 0 | 0 | 1567 | 4.0419 | 4.2309 | 0 | 1567 | 1567 | 4.0419 | 1567 | 4.2309 | 0.296163 | 4.2309 | 4.2309 | 1567 | 1567 | 0 | 0.10969 | 8500 | 1567.02 | 3274 | 11200 | 0 | 0.59738
Mur-148 | Etage 2 | Peinture-01 | Sejour cuisine/pl | A24 | Etage 2 | 5 | 0 | 0 | 2700 | 2700 | 0 | 0 | 0.126657 | 0 | 0 | 670.142 | 1.8095 | 1.80927 | 0 | 740.099 | 670.184 | 1.8095 | 670.099 | 1.80927 | 0.126657 | 1.8095 | 1.80927 | 670.184 | 670.099 | 0 | 0.0469099 | 8500 | 670.184 | 1480.28 | 11200 | -1.77636e-12 | 0.47182
Mur-148 | Etage 2 | Surface-Blanche | Sejour cuisine/pl | A25 | Etage 2 | 5 | 0 | 0 | 2700 | 0 | 0 | 0 | 0.123683 | 0 | 0 | 834.407 | 1.67246 | 1.86134 | 0 | 869.385 | 799.429 | 1.67246 | 869.385 | 1.86134 | 0.123683 | 1.67246 | 1.86134 | 799.429 | 869.385 | 0 | 0.0458085 | 8500 | 689.385 | 1837.78 | 11200 | 0 | 0.35882
Mur-148 | Etage 2 | Surface-Blanche | Sejour cuisine/pl | A25 | Etage 2 | 5 | 0 | 0 | 2700 | 2700 | 0 | 0 | 0.121118 | 0 | 0 | 640.838 | 1.63576 | 1.82476 | 0 | 1015.84 | 605.838 | 1.63576 | 675.838 | 1.82476 | 0.121118 | 1.63576 | 1.82476 | 605.838 | 675.838 | 0 | 0.0448587 | 8500 | 675.838 | 1450.64 | 11200 | 0 | 0.54592
Mur-148 | Etage 2 | Peinture-01 | Sejour cuisine | B26 | Etage 2 | 5 | 0 | 0 | 2700 | 2700 | 0 | 0 | 0.103095 | 0 | 0 | 545.476 | 1.28379 | 1.66179 | 0 | 615.476 | 475.476 | 1.28379 | 615.476 | 1.66179 | 0.103095 | 1.28379 | 1.66179 | 475.476 | 615.476 | 0 | 0.0381833 | 8500 | 615.476 | 1288.94 | 11200 | 0 | 0.610939
Mur-148 | Etage 2 | Peinture-01 | Sejour cuisine | B26 | Etage 2 | 5 | 0 | 0 | 2700 | 2700 | 0 | 0 | 0.12663 | 0 | 0 | 670 | 1.62 | 1.998 | 0 | 740 | 600 | 1.62 | 740 | 1.998 | 0.12663 | 1.62 | 1.998 | 600 | 740 | 0 | 0.0469 | 8500 | 740 | 1537.99 | 11200 | 0 | 0.628373
Mur-148 | Etage 2 | Peinture-01 | Sejour cuisine | B26 | Etage 2 | 5 | 0 | 0 | 2700 | 2700 | 0 | 0 | 0.110625 | 0 | 0 | 705 | 1.4855 | 1.6752 | 0 | 740 | 670 | 1.4855 | 740 | 1.6752 | 0.110625 | 1.4855 | 1.6752 | 670 | 740 | 0 | 0.0469 | 8500 | 740 | 1578.99 | 11200 | 0 | 0.550376
Mur-148 | Etage 2 | Peinture-01 | Sejour cuisine | B26 | Etage 2 | 5 | 0 | 0 | 2700 | 2700 | 0 | 0 | 0.120015 | 0 | 0 | 635 | 1.62 | 1.809 | 0 | 670 | 600 | 1.62 | 670 | 1.809 | 0.120015 | 1.62 | 1.809 | 600 | 670 | 0 | 0.04445 | 8500 | 670 | 1438.99 | 11200 | 0 | 0.545186
Mur-148 | Etage 2 | Peinture-01 | Sejour cuisine/pl | A25 | Etage 2 | 5 | 0 | 0 | 2700 | 2700 | 0 | 0 | 0.00661678 | 0 | 0 | 35 | 0.0000507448 | 0.189 | 0 | 70 | 0 | 0.0000507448 | 70 | 0.189 | 0.00661678 | 0.0000507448 | 0.189 | 0 | 70 | 0 | 0.00245066 | 8500 | 70 | 238.995 | 11200 | 0 | 0.461152 | ArchiCADProperties - Zones conflictuelles: Sejour cuisine/pl
Mur-148 | Etage 2 | Peinture-01 | Sejour cuisine | B26 | Etage 2 | 5 | 0 | 0 | 2700 | 2700 | 0 | 0 | 0.114069 | 0 | 0 | 603.541 | 1.53506 | 1.72406 | 0 | 708.541 | 568.541 | 1.53506 | 638.541 | 1.72406 | 0.114069 | 1.53506 | 1.72406 | 568.541 | 638.541 | 0 | 0.0422479 | 8500 | 638.541 | 1376.08 | 11200 | 0 | 0.540782
Mur-148 | Etage 2 | Surface-Blanche | Sde | A22 | Etage 2 | 5 | 0 | 0 | 3000 | 3000 | 0 | 0 | 0.111633 | 0 | 0 | 531.585 | 1.48978 | 1.69973 | 0 | 566.577 | 496.593 | 1.48978 | 566.577 | 1.69973 | 0.111633 | 1.48978 | 1.69973 | 496.593 | 566.577 | 0 | 0.0372109 | 8500 | 566.577 | 1232.15 | 11500 | 0 | 0.581373
Mur-148 | Etage 2 | Peinture-01 | Sejour cuisine | B26 | Etage 2 | 5 | 0 | 0 | 2700 | 2700 | 0 | 0 | 0.109681 | 0 | 0 | 580.455 | 1.47197 | 1.66179 | 0 | 615.476 | 545.433 | 1.47197 | 615.476 | 1.66179 | 0.109681 | 1.47197 | 1.66179 | 545.433 | 615.476 | 0 | 0.0406318 | 8500 | 615.476 | 1329.9 | 11200 | 0 | 0.53784
Mur-148 | Etage 2 | Surface-Blanche |  |  | Etage 2 | 5 | 0 | 0 | 3000 | 3000 | 0 | 0 | 0.106062 | 0 | 0 | 505.055 | 1.72511 | 1.30522 | 0 | 435.073 | 575.037 | 1.72511 | 435.073 | 1.30522 | 0.106062 | 1.72511 | 1.30522 | 575.037 | 435.073 | 0 | 0.0353539 | 8500 | 575.037 | 1208.07 | 11500 | 0 | 0.6646
Mur-148 | Etage 3 | Peinture-01 | Sejour cuisine/pl | B35 | Etage 3 | 6 | 0 | 0 | 2700 | 2700 | 0 | 0 | 0.293405 | 0 | 0 | 1555 | 4.09 | 4.104 | 0 | 1700 | 1590 | 4.09 | 1520 | 4.104 | 0.293405 | 4.279 | 4.104 | 1590 | 1520 | 0 | 0.10885 | 11550 | 1590 | 3278.99 | 14250 | 0 | 0.668187
Mur-148 | Etage 3 | Surface-Blanche |  |  | Etage 3 | 6 | 0 | 0 | 3000 | 3000 | 0 | 0 | 0.106089 | 0 | 0 | 505.187 | 1.72556 | 1.30556 | 0 | 435.187 | 575.187 | 1.72556 | 435.187 | 1.30556 | 0.106089 | 1.72556 | 1.30556 | 575.187 | 435.187 | 0 | 0.0353631 | 11550 | 575.187 | 1208.36 | 14550 | -1.77636e-12 | 0.664696
Mur-148 | Etage 3 | Surface-Blanche | Ch 2 | A31 | Etage 3 | 6 | 1 | 0 | 3000 | 3000 | 1.6932 | 830 | 0.801916 | 1.8928 | 1.8928 | 4449.58 | 11.1516 | 11.3403 | 0.132496 | 4752.78 | 3508.13 | 13.0444 | 3571.04 | 13.2331 | 0.934412 | 13.2544 | 13.4431 | 4418.13 | 4481.04 | 0 | 0.247771 | 11550 | 4488.13 | 9068.52 | 14550 | -1.77636e-12 | 1.06731
Mur-148 | Etage 3 | Surface-Blanche | Dgt | A31 | Etage 3 | 6 | 3 | 0 | 3000 | 3000 | 4.5696 | 2240 | 0.517518 | 5.0156 | 5.0156 | 4136.24 | 7.07812 | 7.2881 | 0.351092 | 4171.23 | 1751.24 | 12.0937 | 1681.23 | 12.3037 | 0.86861 | 12.5137 | 12.3037 | 4171.24 | 4101.23 | 0 | 0.120137 | 11550 | 4171.24 | 8441.47 | 14550 | 0 | 0.916668
Mur-148 | Etage 3 | Surface-Blanche | Sejour cuisine/pl | A31 | Etage 3 | 6 | 0 | 0 | 3000 | 1.77636e-12 | 0 | 0 | 0.744938 | 0 | 0 | 3687.2 | 10.6522 | 10.7773 | 0 | 4025.39 | 3690.75 | 10.6522 | 3683.65 | 10.7773 | 0.744938 | 10.6522 | 10.7773 | 3690.75 | 3683.65 | 0 | 0.248313 | 11550 | 3599.51 | 7514.76 | 14550 | -1.77636e-12 | 0.9177 | ArchiCADProperties - Zones conflictuelles: Sejour cuisine/pl
Mur-148 | Etage 3 | Surface-Blanche | Wc | A31 | Etage 3 | 6 | 0 | 0 | 3000 | 3000 | 0 | 0 | 0.11222 | 0 | 0 | 534.379 | 1.60314 | 1.39314 | 0 | 814.379 | 534.379 | 1.60314 | 534.379 | 1.39314 | 0.11222 | 1.60314 | 1.60314 | 534.379 | 534.379 | 0 | 0.0374065 | 11550 | 534.379 | 1208.76 | 14550 | 0 | 0.494813 | ArchiCADProperties - Zones conflictuelles: Wc
Mur-148 | Etage 3 | Surface-Blanche | Ch 3 | A31 | Etage 3 | 6 | 0 | 0 | 3000 | 3000 | 0 | 0 | 0.717705 | 0 | 0 | 3417.64 | 10.2636 | 10.2423 | 0 | 3755.84 | 3421.19 | 10.2636 | 3414.1 | 10.2423 | 0.717705 | 10.2636 | 10.2423 | 3421.19 | 3414.1 | 0 | 0.239235 | 11550 | 3421.19 | 6975.64 | 14550 | -1.77636e-12 | 0.899544 | ArchiCADProperties - Zones conflictuelles: Ch 3
Mur-148 | Etage 3 | Surface-Blanche | Sde2 | A31 | Etage 3 | 6 | 0 | 0 | 3000 | 3000 | 0 | 0 | 0.189027 | 0 | 0 | 900.127 | 2.49039 | 2.70037 | 0 | 1180.12 | 900.131 | 2.49039 | 900.122 | 2.70037 | 0.189027 | 2.70039 | 2.70037 | 900.131 | 900.122 | 0 | 0.0630089 | 11550 | 900.131 | 1940.25 | 14550 | 0 | 0.546018 | ArchiCADProperties - Zones conflictuelles: Sde2
Mur-148 | Etage 3 | Surface-Blanche | Ch 3 | A31 | Etage 3 | 6 | 2 | 0 | 3000 | 1.77636e-12 | 3.3864 | 1660 | 0.883442 | 3.7856 | 3.7856 | 5538.73 | 12.6206 | 12.6206 | 0.264992 | 5608.73 | 3718.73 | 16.4062 | 3718.73 | 16.4062 | 1.14843 | 16.4062 | 16.4062 | 5538.73 | 5538.73 | 0 | 0.255411 | 11550 | 5468.74 | 11217.5 | 14550 | -1.77636e-12 | 1.05822 | ArchiCADProperties - Zones conflictuelles: Dgt
Mur-148 | Etage 3 | Surface-Blanche | Ch 3 | A31 | Etage 3 | 6 | 0 | 1 | 3000 | 3000 | 0 | 0 | 0.212327 | 1.86492 | 1.86492 | 1632.72 | 2.82324 | 2.61324 | 0.130544 | 1632.72 | 718.543 | 4.68816 | 718.543 | 4.47816 | 0.342871 | 4.89816 | 4.89816 | 1632.72 | 1632.72 | 1.86492 | 0.050298 | 11550 | 1632.72 | 3405.44 | 14550 | 0 | 0.584588 | ArchiCADProperties - Zones conflictuelles: Ch 3
Mur-148 | Etage 3 | Surface-Blanche | Ch 1 | A31 | Etage 3 | 6 | 0 | 0 | 3000 | 3000 | 0 | 0 | 0.387438 | 0 | 0 | 1844.94 | 5.42982 | 5.42982 | 0 | 2159.94 | 1879.94 | 5.42982 | 1809.94 | 5.42982 | 0.387438 | 5.63982 | 5.42982 | 1879.94 | 1809.94 | 0 | 0.129146 | 11550 | 1879.95 | 3858.88 | 14550 | 0 | 0.765287 | ArchiCADProperties - Zones conflictuelles: Ch 1
Mur-148 | Etage 3 | Surface-Blanche | Sejour cuisine/pl | A31 | Etage 3 | 6 | 0 | 0 | 3000 | 3000 | 0 | 0 | 0.155142 | 0 | 0 | 738.772 | 1.7363 | 2.48633 | 0 | 828.776 | 648.767 | 1.7363 | 828.776 | 2.48633 | 0.155142 | 1.9463 | 2.48633 | 648.767 | 828.776 | 0 | 0.051714 | 11550 | 828.776 | 1740.68 | 14550 | 0 | 0.892852
Mur-148 | Etage 3 | Surface-Blanche | Sejour cuisine/pl | A31 | Etage 3 | 6 | 0 | 0 | 3000 | 3000 | 0 | 0 | 0.121518 | 0 | 0 | 578.655 | 1.73599 | 1.73594 | 0 | 758.648 | 578.663 | 1.73599 | 578.648 | 1.73594 | 0.121518 | 1.73599 | 1.73594 | 578.663 | 578.648 | 0 | 0.0405059 | 11550 | 578.67 | 1297.31 | 14550 | -1.77636e-12 | 0.501012
Mur-148 | Etage 3 | Peinture-01 | Sejour cuisine/pl | B35 | Etage 3 | 6 | 1 | 0 | 2700 | 2700 | 0.918 | 450 | 0.124132 | 0.925727 | 0.925727 | 1069.5 | 1.58397 | 1.77367 | 0.0648009 | 1069.52 | 617.9 | 2.5097 | 617.943 | 2.6994 | 0.188933 | 2.6987 | 2.6994 | 1069.47 | 1069.52 | 0 | 0.040806 | 11550 | 1069.52 | 2278.99 | 14250 | 0 | 0.348012
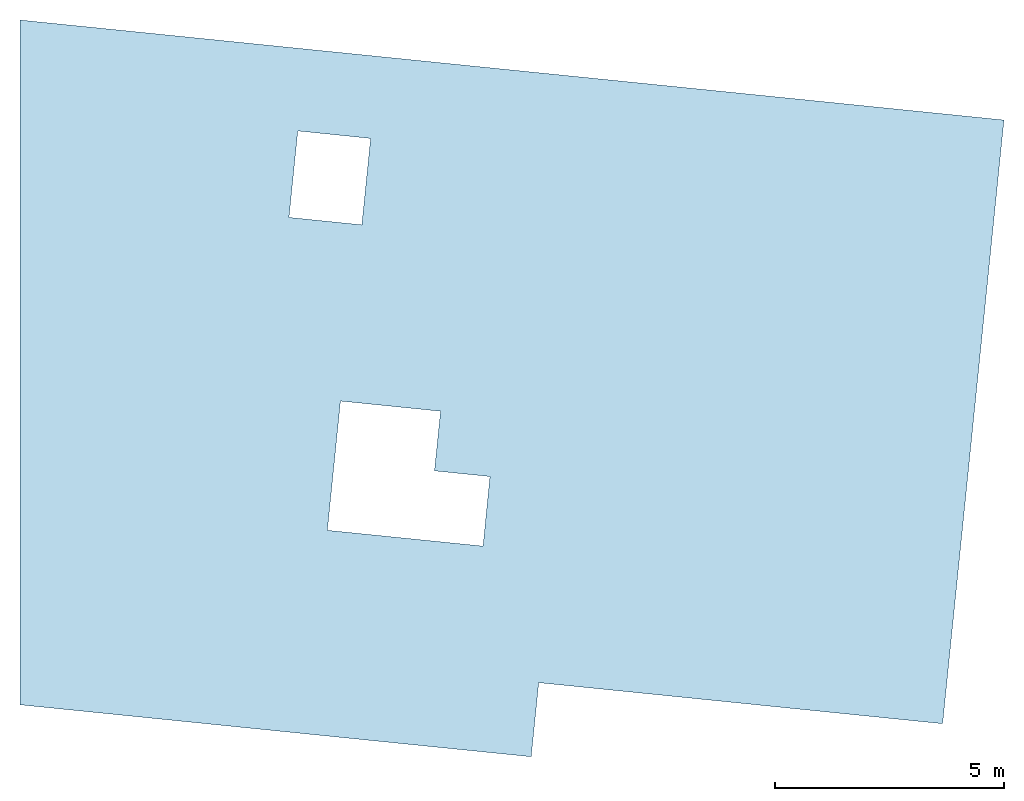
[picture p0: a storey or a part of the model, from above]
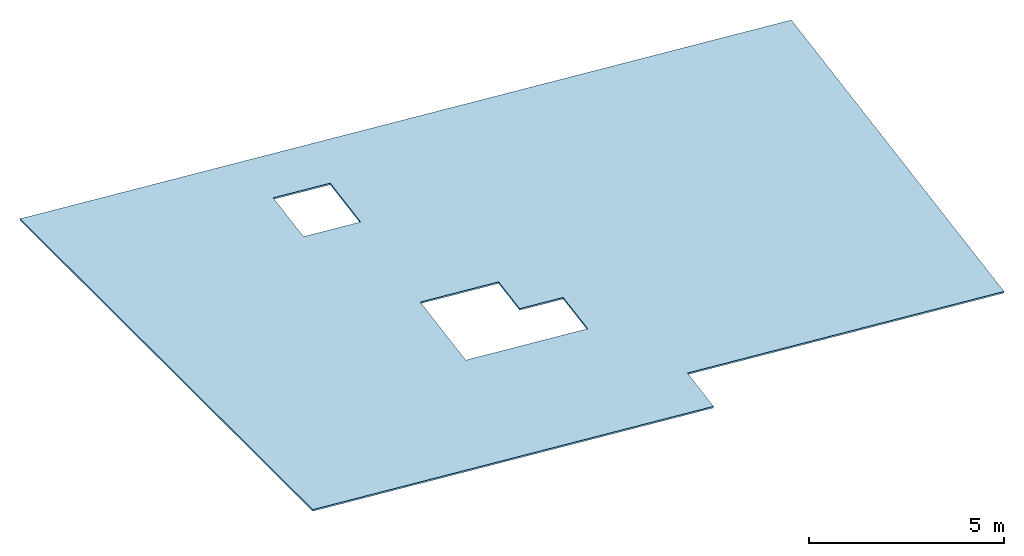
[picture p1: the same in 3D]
Properties of the parts of a building model (IFC2X3), part 30 of 44

# IfcWallStandardCase: Cloison 70 0836576958 70 (90)
Name | In | Surface de face intérieure = Surface de face extérieure = Surfaces (Toutes) = Surface latérale | Nom de zone liée | Numéro de zone liée | Nom d'étage d'implantation | Numéro d'étage d'implantation | Nombre de Portes | Nombre de trous (Nombre d'ouvertures vides) | Hauteur maximale de la couche de Mur sur face intérieure (mm) = Hauteur maximale du Mur (mm) = Hauteur maximale de la couche de Mur sur face extérieure (mm) = Hauteur (mm) = Altitude supérieure à étage d'implantation (mm) | Hauteur minimale de la couche de Mur sur face intérieure (mm) = Hauteur minimale du Mur (mm) = Hauteur minimale de la couche de Mur sur face extérieure (mm) | Superficie des portes (m2) | Largeur totale des Portes (mm) | Volume de composant de mur sur face intérieure (net) (m3) = Volume de composant de mur sur face extérieure (net) (m3) = Volume (net) (m3) | Superficie analytique des ouvertures sur face intérieure (m2) | Superficie analytique des ouvertures sur face extérieure (m2) | Longueur moyenne du mur (mm) = Longueur du Mur au centre (mm) | Superficie de la face intérieure du mur (nette) (m2) | Superficie de la face extérieure du mur (nette) (m2) = Superficie en plan (m2) = Superficie inférieure (nette) (m2) | Volume analytique des ouvertures (m3) | Longueur de ligne de référence (mm) | Longueur de la face intérieure du mur (conditionnelle) (mm) | Superficie de la face intérieure du mur (conditionnelle) (m2) | Longueur de la face extérieure du mur (conditionnelle) (mm) | Superficie de la face extérieure du mur (conditionnelle) (m2) | Volume du composant face intérieure du mur (conditionnel) (m3) = Volume du composant face extérieure du mur (conditionnel) (m3) = Volume (conditionnel) (m3) = Volume (brut) (m3) | Superficie de la face intérieure du mur (brute) (m2) | Superficie de la face extérieure du mur (brute) (m2) | Longueur de Mur sur face intérieure (mm) | Longueur de Mur sur face extérieure (mm) | Superficie des baies libres dans le Mur (m2) | Superficie (m2) = Superficie supérieure (nette) (m2) | Altitude à Zéro du Projet (mm) = Altitude de Référence Niveau 1 (mm) = Altitude de Référence Niveau 2 (mm) = Altitude à niveau de la mer (mm) = Altitude inférieure à premier niveau de référence (mm) = Altitude inférieure à Zéro du projet (mm) = Altitude inférieure à niveau de la mer (mm) = Altitude inférieure à deuxième niveau de référence (mm) | Longueur 3D (mm) | Périmètre Plan (mm) | Altitude supérieure à premier niveau de référence (mm) = Altitude supérieure à Zéro du projet (mm) = Altitude supérieure à niveau de la mer (mm) = Altitude supérieure à deuxième niveau de référence (mm) | Altitude inférieure à étage d'implantation (mm) | Superficie de l'arête (nette) (m2)
Mur-148 | Etage 3 | Surface-Blanche | Sde1 | A31 | Etage 3 | 6 | 0 | 0 | 3000 | 0 | 0 | 0 | 0.401146 | 0 | 0 | 1980.22 | 4.89065 | 4.89065 | 0 | 2050.22 | 1980.22 | 4.89065 | 1980.22 | 4.89065 | 0.401146 | 5.73065 | 5.73065 | 1980.22 | 1980.22 | 0 | 0.133715 | 11550 | 1910.22 | 4100.43 | 14550 | 0 | 0.68743 | ArchiCADProperties - Zones conflictuelles: Sde1
Mur-148 | Etage 3 | Surface-Blanche | Wc | A32 | Etage 3 | 6 | 0 | 0 | 3000 | 3000 | 0 | 0 | 0.29062 | 0 | 0 | 1383.9 | 3.94168 | 4.36174 | 0 | 1383.91 | 1313.89 | 3.94168 | 1453.91 | 4.36174 | 0.29062 | 3.94168 | 4.36174 | 1313.89 | 1453.91 | 0 | 0.0968733 | 11550 | 1453.91 | 2965.81 | 14550 | 0 | 0.787758
Mur-148 | Etage 3 | Peinture-01 | Sejour cuisine/pl | B35 | Etage 3 | 6 | 0 | 0 | 2700 | 2700 | 0 | 0 | 0.113579 | 0 | 0 | 603.541 | 1.53506 | 1.71006 | 0 | 638.534 | 568.541 | 1.53506 | 638.541 | 1.71006 | 0.113579 | 1.53506 | 1.71006 | 568.541 | 638.541 | 0 | 0.0422479 | 11550 | 638.541 | 1376.08 | 14250 | 0 | 0.534983
Mur-148 | Etage 3 | Surface-Blanche | Sejour cuisine/pl | B31 | Etage 3 | 6 | 0 | 0 | 3000 | 3000 | 0 | 0 | 0.137421 | 0 | 0 | 654.385 | 1.85815 | 2.06816 | 0 | 869.385 | 619.385 | 1.85815 | 689.385 | 2.06816 | 0.137421 | 1.85815 | 2.06816 | 619.385 | 689.385 | 0 | 0.0458069 | 11550 | 689.385 | 1477.76 | 14550 | 0 | 0.598599
Mur-148 | Etage 3 | Peinture-01 | Sejour cuisine/pl | B35 | Etage 3 | 6 | 0 | 0 | 2700 | 2700 | 0 | 0 | 0.13986 | 0 | 0 | 740 | 1.998 | 1.998 | 0 | 740 | 740 | 1.998 | 740 | 1.998 | 0.13986 | 1.998 | 1.998 | 740 | 740 | 0 | 0.0518 | 11550 | 740 | 1620 | 14250 | 0 | 0.4816
Mur-148 | Etage 3 | Surface-Blanche | Wc | A31 | Etage 3 | 6 | 0 | 0 | 3000 | 3000 | 0 | 0 | 0.0738142 | 0 | 0 | 351.496 | 1.0545 | 0.844482 | 0 | 421.494 | 351.499 | 1.0545 | 351.494 | 0.844482 | 0.0738142 | 1.0545 | 1.05448 | 351.499 | 351.494 | 0 | 0.0246047 | 11550 | 351.499 | 842.993 | 14550 | 0 | 0.469209
Mur-148 | Etage 3 | Peinture-01 | Sejour cuisine/pl | B35 | Etage 3 | 6 | 0 | 0 | 2700 | 2700 | 0 | 0 | 0.110625 | 0 | 0 | 705 | 1.4855 | 1.6752 | 0 | 740 | 670 | 1.4855 | 740 | 1.6752 | 0.110625 | 1.4855 | 1.6752 | 670 | 740 | 0 | 0.0469 | 11550 | 740 | 1578.99 | 14250 | 0 | 0.550376
Mur-148 | Etage 3 | Peinture-01 | Sejour cuisine/pl | B35 | Etage 3 | 6 | 0 | 0 | 2700 | 2700 | 0 | 0 | 0.103095 | 0 | 0 | 545.476 | 1.28379 | 1.66179 | 0 | 615.476 | 475.476 | 1.28379 | 615.476 | 1.66179 | 0.103095 | 1.28379 | 1.66179 | 475.476 | 615.476 | 0 | 0.0381833 | 11550 | 615.476 | 1288.94 | 14250 | 0 | 0.610939
Mur-148 | Etage 3 | Peinture-01 |  |  | Etage 3 | 6 | 0 | 0 | 2700 | 2700 | 0 | 0 | 0.120015 | 0 | 0 | 635 | 1.62 | 1.809 | 0 | 740 | 600 | 1.62 | 670 | 1.809 | 0.120015 | 1.62 | 1.809 | 600 | 670 | 0 | 0.04445 | 11550 | 670 | 1438.99 | 14250 | 0 | 0.545186
Mur-148 | Etage 3 | Surface-Blanche | Wc | A31 | Etage 3 | 6 | 0 | 0 | 3000 | 3000 | 0 | 0 | 0.143831 | 0 | 0 | 684.908 | 1.84473 | 1.84473 | 0 | 684.91 | 684.905 | 1.84473 | 684.91 | 1.84473 | 0.143831 | 2.05473 | 2.05473 | 684.905 | 684.91 | 0 | 0.0479437 | 11550 | 684.91 | 1509.82 | 14550 | 0 | 0.515887 | ArchiCADProperties - Zones conflictuelles: Sde1
Mur-148 | Etage 3 | Surface-Blanche | Wc | A31 | Etage 3 | 6 | 0 | 0 | 3000 | 3000 | 0 | 0 | 0.129084 | 0 | 0 | 614.684 | 1.84378 | 1.84432 | 0 | 614.774 | 614.594 | 1.84378 | 614.774 | 1.84432 | 0.129084 | 1.84378 | 1.84432 | 614.594 | 614.774 | 0 | 0.0430279 | 11550 | 614.774 | 1369.37 | 14550 | 0 | 0.506056
Mur-148 | Etage 3 | Surface-Blanche | Sde1 | A31 | Etage 3 | 6 | 0 | 0 | 3000 | 3000 | 0 | 0 | 0.26102 | 0 | 0 | 1242.95 | 3.62385 | 3.83387 | 0 | 1207.96 | 1207.95 | 3.62385 | 1277.96 | 3.83387 | 0.26102 | 3.62385 | 3.83387 | 1207.95 | 1277.96 | 0 | 0.0870068 | 11550 | 1277.96 | 2654.91 | 14550 | 0 | 0.681008 | ArchiCADProperties - Zones conflictuelles: Ch 1
Mur-148 | Etage 3 | Surface-Blanche |  |  | Etage 3 | 6 | 0 | 0 | 3000 | 3000 | 0 | 0 | 0.167794 | 0 | 0 | 799.02 | 2.39705 | 2.39707 | 0 | 939.023 | 799.018 | 2.39705 | 799.023 | 2.39707 | 0.167794 | 2.39705 | 2.39707 | 799.018 | 799.023 | 0 | 0.0559314 | 11550 | 799.238 | 1738.04 | 14550 | -1.77636e-12 | 0.531865
Mur-148 | etage 4 | Peinture-01 | Ch 3/sde | B44 | etage 4 | 7 | 1 | 0 | 2700 | 2700 | 3.69971 | 1849.85 | 0.104403 | 3.69971 | 3.69971 | 1922.66 | 1.39698 | 1.58598 | 0.25898 | 2297.66 | 37.8067 | 1.39698 | 107.807 | 1.58598 | 0.363383 | 5.09668 | 5.28568 | 1887.66 | 1957.66 | 0 | 0.00509647 | 14600 | 1957.66 | 4014.32 | 17300 | 0 | 0.595969
Mur-148 | etage 4 | Peinture-01 | Ch 3/sde | B44 | etage 4 | 7 | 0 | 0 | 2700 | 2700 | 0 | 0 | 0.12663 | 0 | 0 | 670 | 1.431 | 1.998 | 0 | 740 | 600 | 1.431 | 740 | 1.998 | 0.12663 | 1.62 | 1.998 | 600 | 740 | 0 | 0.0469 | 14600 | 740 | 1537.99 | 17300 | 0 | 0.628373
Mur-148 | etage 4 | Peinture-01 |  |  | etage 4 | 7 | 0 | 0 | 2700 | 2700 | 0 | 0 | 0.06048 | 0 | 0 | 320 | 0.675 | 1.053 | 0 | 390 | 250 | 0.675 | 390 | 1.053 | 0.06048 | 0.675 | 1.053 | 250 | 390 | 0 | 0.0224 | 14600 | 390 | 837.99 | 17300 | 0 | 0.579373
Mur-148 | etage 4 | Surface-Blanche | Sejour cuisine/pl | B41 | etage 4 | 7 | 0 | 0 | 3000 | 3000 | 0 | 0 | 0.137421 | 0 | 0 | 654.385 | 1.85815 | 2.06816 | 0 | 869.385 | 619.385 | 1.85815 | 689.385 | 2.06816 | 0.137421 | 1.85815 | 2.06816 | 619.385 | 689.385 | 0 | 0.0458069 | 14600 | 689.385 | 1477.76 | 17600 | 0 | 0.598599
Mur-148 | etage 4 | Peinture-01 |  |  | etage 4 | 7 | 0 | 0 | 2700 | 2700 | 0 | 0 | 0.0997817 | 0 | 0 | 527.945 | 1.23645 | 1.61445 | 0 | 597.945 | 457.945 | 1.23645 | 597.945 | 1.61445 | 0.0997817 | 1.23645 | 1.61445 | 457.945 | 597.945 | 0 | 0.0369562 | 14600 | 597.945 | 1253.88 | 17300 | 0 | 0.608485
Mur-148 | etage 4 | Peinture-01 |  |  | etage 4 | 7 | 0 | 0 | 2700 | 2700 | 0 | 0 | 0.053865 | 0 | 0 | 285 | 0.675 | 0.864 | 0 | 390 | 250 | 0.675 | 320 | 0.864 | 0.053865 | 0.675 | 0.864 | 250 | 320 | 0 | 0.01995 | 14600 | 320 | 738.995 | 17300 | 0 | 0.496186
Mur-148 | etage 4 | Peinture-01 | Ch 3/sde | B44 | etage 4 | 7 | 0 | 0 | 2700 | 2700 | 0 | 0 | 0.067091 | 0 | 0 | 354.979 | 0.863885 | 1.053 | 0 | 390 | 319.957 | 0.863885 | 390 | 1.053 | 0.067091 | 0.863885 | 1.053 | 319.957 | 390 | 0 | 0.02485 | 14600 | 390 | 878.952 | 17300 | -1.77636e-12 | 0.505986
Mur-148 | etage 4 | Peinture-01 | Ch 3/sde | B44 | etage 4 | 7 | 0 | 0 | 2700 | 2700 | 0 | 0 | 0.356768 | 0 | 0 | 1887.66 | 5.09668 | 5.09668 | 0 | 2297.66 | 1887.66 | 5.09668 | 1887.66 | 5.09668 | 0.356768 | 5.09668 | 5.09668 | 1887.66 | 1887.66 | 0 | 0.132136 | 14600 | 1887.66 | 3915.32 | 17300 | 0 | 0.642273 | ArchiCADProperties - Zones conflictuelles: Ch 3/sde
Mur-148 | etage 4 | Peinture-01 | Ch 3/sde | B44 | etage 4 | 7 | 1 | 0 | 2700 | 2700 | 1.6932 | 830 | 0.34121 | 1.8928 | 1.8928 | 2506.38 | 4.59093 | 4.96893 | 0.132496 | 2541.38 | 1561.38 | 6.48373 | 1631.38 | 6.86173 | 0.473706 | 6.67273 | 6.86173 | 2471.38 | 2541.38 | 0 | 0.111747 | 14600 | 2541.38 | 5181.76 | 17300 | 0 | 0.74348
Mur-148 | etage 4 | Surface-Blanche |  |  | etage 4 | 7 | 0 | 0 | 3000 | 3000 | 0 | 0 | 0.106089 | 0 | 0 | 505.187 | 1.72556 | 1.30556 | 0 | 435.187 | 575.187 | 1.72556 | 435.187 | 1.30556 | 0.106089 | 1.72556 | 1.30556 | 575.187 | 435.187 | 0 | 0.0353631 | 14600 | 575.187 | 1208.36 | 17600 | -1.77636e-12 | 0.664696
Mur-148 | Etage 5 | Peinture-01 | Ch 3/pl | B52 | Etage 5 | 8 | 0 | 0 | 2700 | 2700 | 0 | 0 | 0.12663 | 0 | 0 | 670 | 1.62 | 1.998 | 0 | 740 | 600 | 1.62 | 740 | 1.998 | 0.12663 | 1.62 | 1.998 | 600 | 740 | 0 | 0.0469 | 17650 | 740 | 1537.99 | 20350 | 0 | 0.628373
Mur-148 | Etage 5 | Peinture-01 | Ch 3/pl | B52 | Etage 5 | 8 | 0 | 0 | 2700 | 2700 | 0 | 0 | 0.0538895 | 0 | 0 | 354.979 | 0.675 | 0.8647 | 0 | 390 | 319.957 | 0.675 | 390 | 0.8647 | 0.0538895 | 0.675 | 0.8647 | 319.957 | 390 | 0 | 0.0224 | 17650 | 390 | 878.952 | 20350 | 0 | 0.501376
Mur-148 | Etage 5 | Peinture-01 | Ch 3/pl | B52 | Etage 5 | 8 | 0 | 0 | 2700 | 2700 | 0 | 0 | 0.110625 | 0 | 0 | 705 | 1.4855 | 1.6752 | 0 | 740 | 670 | 1.4855 | 740 | 1.6752 | 0.110625 | 1.4855 | 1.6752 | 670 | 740 | 0 | 0.0469 | 17650 | 740 | 1578.99 | 20350 | 0 | 0.550376
Mur-148 | Etage 5 | Peinture-01 |  |  | Etage 5 | 8 | 0 | 0 | 2700 | 2700 | 0 | 0 | 0.06048 | 0 | 0 | 320 | 0.675 | 1.053 | 0 | 390 | 250 | 0.675 | 390 | 1.053 | 0.06048 | 0.675 | 1.053 | 250 | 390 | 0 | 0.0224 | 17650 | 390 | 837.99 | 20350 | 0 | 0.579373

# IfcWallStandardCase: Cloison 70 blanc 70, Mur-148
In: Etage 3
Classification: Mur (Classification ARCHICAD); Material: Empty Fill 272047960 70 mm
ArchiCADProperties - Complexité de mur: Droit; Option de géométrie: Uniforme; Emplacement de ligne de référence: Face extérieure; Surface de face intérieure: Surface-Blanche; Surface de face extérieure: Surface-Blanche; Angle d'inclinaison interne de mur: 90 deg; Angle d'inclinaison externe de mur: 90 deg; ID de l'élément: Mur-148; Lien et ID d'élément: Mur-148; Calque: 1-Projet; Matériau de construction / Composite / Profil / Hachure: Cloison 70 blanc; Structure Composite: Cloison 70 blanc; Nom de zone liée: Ch 1; Numéro de zone liée: A31; Verrouillé: no; Nom d'étage d'implantation: Etage 3; Numéro d'étage d'implantation: 6; Type d'élément: Mur; Étage supérieur lié absolu: Non lié; Étage supérieur lié relatif: Non lié; Étage supérieur lié: Non lié; Type de structure: Composite; ID de Parent: Mur-148; Matériaux de construction (Tous): Empty Fill 272047960; Surfaces (Toutes): Surface-Blanche; Angle d'inclinaison: 90 deg; Nombre de percements: 0; Surface latérale: Surface-Blanche; Nom de Variante: Modèle principal; Nom de Jeu de Variantes: Modèle principal; Position: Non défini; Fonction structurelle: Non défini; Affichage sur filtre de rénovation: Tous les filtres appropriés; État de rénovation: Existant; État de Variante: Modèle principal; Jeu de Variantes: Modèle principal
AC_Pset_RenovationAndPhasing - Renovation Status: Existing
ArchiCADQuantities - Nombre de Portes: 1; Nombre de trous (Nombre d'ouvertures vides): 0; Nombre de Fenêtres: 0; Nombre de Poteaux: 0; Volume des poteaux: 0 m3; Hauteur maximale de la couche de Mur sur face intérieure: 3000 mm; Hauteur minimale de la couche de Mur sur face intérieure: 3000 mm; Hauteur maximale du Mur: 3000 mm; Hauteur minimale du Mur: 3000 mm; Hauteur maximale de la couche de Mur sur face extérieure: 3000 mm; Hauteur minimale de la couche de Mur sur face extérieure: 3000 mm; Épaisseur couche d'air: 0 mm; Superficie des portes: 1.6932 m2; Largeur totale des Portes: 830 mm; Épaisseur de composant de mur sur face intérieure: 70 mm; Épaisseur de composant de mur sur face extérieure: 70 mm; Superficie des fenêtres: 0 m2; Largeur totale des Fenêtres: 0 mm; Volume de composant de mur sur face intérieure (net): 0.239697 m3; Volume de composant de mur sur face extérieure (net): 0.239697 m3; Superficie analytique des ouvertures sur face intérieure: 1.8824 m2; Superficie analytique des ouvertures sur face extérieure: 1.8824 m2; Longueur moyenne du mur: 1768.88 mm; Superficie de la face intérieure du mur (nette): 3.42425 m2; Superficie de la face extérieure du mur (nette): 3.42424 m2; Volume analytique des ouvertures: 0.131768 m3; Longueur de ligne de référence: 2048.88 mm; Longueur de la face intérieure du mur (conditionnelle): 863.883 mm; Superficie de la face intérieure du mur (conditionnelle): 5.30665 m2; Longueur de la face extérieure du mur (conditionnelle): 863.879 mm; Superficie de la face extérieure du mur (conditionnelle): 5.30664 m2; Volume du composant face intérieure du mur (conditionnel): 0.371465 m3; Volume du composant face extérieure du mur (conditionnel): 0.371465 m3; Superficie de la face intérieure du mur (brute): 5.30665 m2; Superficie de la face extérieure du mur (brute): 5.30664 m2; Épaisseur du Mur à la fin: 70 mm; Longueur du Mur au centre: 1768.88 mm; Longueur de Mur sur face intérieure: 1768.88 mm; Longueur de Mur sur face extérieure: 1768.88 mm; Superficie des baies libres dans le Mur: 0 m2; Superficie: 0.0604717 m2; Hauteur: 3000 mm; Volume (net): 0.239697 m3; Largeur: 70 mm; Altitude à Zéro du Projet: 11550 mm; Altitude de Référence Niveau 1: 11550 mm; Altitude de Référence Niveau 2: 11550 mm; Altitude à niveau de la mer: 11550 mm; Altitude à étage lié/étage d'implantation: 0 mm; Décalage étage d'implantation: 0 mm; Décalage supérieur: 0 mm; Superficie en plan: 3.42424 m2; Longueur 3D: 1768.88 mm; Épaisseur: 70 mm; Volume (conditionnel): 0.371465 m3; Volume (brut): 0.371465 m3; Épaisseur couche isolation: 0 mm; Périmètre Plan: 3677.76 mm; Altitude supérieure à premier niveau de référence: 14550 mm; Altitude supérieure à étage d'implantation: 3000 mm; Altitude supérieure à Zéro du projet: 14550 mm; Altitude supérieure à niveau de la mer: 14550 mm; Altitude supérieure à deuxième niveau de référence: 14550 mm; Altitude inférieure à premier niveau de référence: 11550 mm; Altitude inférieure à étage d'implantation: 0 mm; Altitude inférieure à Zéro du projet: 11550 mm; Altitude inférieure à niveau de la mer: 11550 mm; Altitude inférieure à deuxième niveau de référence: 11550 mm; Superficie supérieure (nette): 0.0604717 m2; Superficie de l'arête (nette): 0.458693 m2; Superficie inférieure (nette): 3.42424 m2

# IfcWallStandardCase: Empty Fill 272047960 340 (18)
Classification: Mur (Classification ARCHICAD); Material: Empty Fill 272047960 340 mm
ArchiCADProperties - Complexité de mur: Droit; Option de géométrie: Uniforme; Emplacement de ligne de référence: Face extérieure; Surface de face intérieure: Peinture-01; Surface de face extérieure: Peinture-01; Angle d'inclinaison interne de mur: 90 deg; Angle d'inclinaison externe de mur: 90 deg; Calque: Interieurs logements; Matériau de construction / Composite / Profil / Hachure: Empty Fill 272047960; Matériau de construction: Empty Fill 272047960; Verrouillé: no; Type d'élément: Mur; Étage supérieur lié absolu: Non lié; Étage supérieur lié relatif: Non lié; Étage supérieur lié: Non lié; Type de structure: Basique; Matériaux de construction (Tous): Empty Fill 272047960; Angle d'inclinaison: 90 deg; Nombre de percements: 0; Surface latérale: Peinture-01; Nom de Variante: Modèle principal; Nom de Jeu de Variantes: Modèle principal; Position: Non défini; Fonction structurelle: Non défini; Affichage sur filtre de rénovation: Tous les filtres appropriés; État de rénovation: Existant; État de Variante: Modèle principal; Jeu de Variantes: Modèle principal
AC_Pset_RenovationAndPhasing - Renovation Status: Existing
ArchiCADQuantities - Nombre de trous (Nombre d'ouvertures vides): 0; Nombre de Poteaux: 0; Volume des poteaux: 0 m3; Hauteur maximale de la couche de Mur sur face intérieure: 0 mm; Hauteur minimale de la couche de Mur sur face intérieure: 0 mm; Hauteur maximale de la couche de Mur sur face extérieure: 0 mm; Hauteur minimale de la couche de Mur sur face extérieure: 0 mm; Épaisseur couche d'air: 0 mm; Épaisseur de composant de mur sur face intérieure: 0 mm; Épaisseur de composant de mur sur face extérieure: 0 mm; Épaisseur du Mur à la fin: 340 mm; Superficie des baies libres dans le Mur: 0 m2; Largeur: 340 mm; Décalage supérieur: 0 mm; Épaisseur: 340 mm; Épaisseur couche isolation: 0 mm
Name | In | ID de l'élément = Lien et ID d'élément = ID de Parent | Nom d'étage d'implantation | Numéro d'étage d'implantation | Surfaces (Toutes) | Nombre de Portes | Nombre de Fenêtres | Hauteur maximale du Mur (mm) = Hauteur minimale du Mur (mm) = Hauteur (mm) | Superficie des portes (m2) | Largeur totale des Portes (mm) | Superficie des fenêtres (m2) | Largeur totale des Fenêtres (mm) | Superficie analytique des ouvertures sur face intérieure (m2) = Superficie analytique des ouvertures sur face extérieure (m2) | Longueur moyenne du mur (mm) = Longueur du Mur au centre (mm) | Superficie de la face intérieure du mur (nette) (m2) | Superficie de la face extérieure du mur (nette) (m2) = Superficie en plan (m2) = Superficie inférieure (nette) (m2) | Volume analytique des ouvertures (m3) | Longueur de ligne de référence (mm) = Longueur de Mur sur face extérieure (mm) | Longueur de la face intérieure du mur (conditionnelle) (mm) | Superficie de la face intérieure du mur (conditionnelle) (m2) | Longueur de la face extérieure du mur (conditionnelle) (mm) | Superficie de la face extérieure du mur (conditionnelle) (m2) | Superficie de la face intérieure du mur (brute) (m2) | Superficie de la face extérieure du mur (brute) (m2) | Longueur de Mur sur face intérieure (mm) | Superficie (m2) = Superficie supérieure (nette) (m2) | Volume (net) (m3) | Altitude à Zéro du Projet (mm) = Altitude de Référence Niveau 1 (mm) = Altitude de Référence Niveau 2 (mm) = Altitude à niveau de la mer (mm) = Altitude inférieure à premier niveau de référence (mm) = Altitude inférieure à Zéro du projet (mm) = Altitude inférieure à niveau de la mer (mm) = Altitude inférieure à deuxième niveau de référence (mm) | Altitude à étage lié/étage d'implantation (mm) = Décalage étage d'implantation (mm) = Altitude inférieure à étage d'implantation (mm) | Longueur 3D (mm) | Volume (conditionnel) (m3) = Volume (brut) (m3) | Périmètre Plan (mm) | Altitude supérieure à premier niveau de référence (mm) = Altitude supérieure à Zéro du projet (mm) = Altitude supérieure à niveau de la mer (mm) = Altitude supérieure à deuxième niveau de référence (mm) | Altitude supérieure à étage d'implantation (mm) | Superficie de l'arête (nette) (m2)
Mur-145 | rdc | Mur-145 | rdc | 3 | Peinture-01 | 0 | 0 | 3200 | 0 | 0 | 0 | 0 | 0 | 5112.09 | 15.8145 | 16.9028 | 0 | 5282.14 | 4942.04 | 15.8145 | 5282.14 | 16.9028 | 15.8145 | 16.9028 | 4942.04 | 1.73811 | 5.56195 | 2500 | -500 | 5282.14 | 5.56195 | 11039.1 | 5700 | 2700 | 6.08386
Mur-144 | rdc | Mur-144 | rdc | 3 | Peinture-01 | 0 | 0 | 3079.49 | 0 | 0 | 0 | 0 | 0 | 5963.5 | 18.3751 | 18.3521 | 0 | 5959.47 | 5967.53 | 18.3751 | 5959.47 | 18.3521 | 18.3751 | 18.3521 | 5967.53 | 2.02759 | 6.24362 | 2266.06 | -733.937 | 5967.53 | 6.24362 | 12607.1 | 5345.55 | 2345.55 | 6.14951
Mur-144 | rdc | Mur-144 | rdc | 3 | Peinture-01 | 0 | 0 | 3200 | 0 | 0 | 0 | 0 | 0 | 5688.78 | 17.116 | 19.2922 | 0 | 6028.81 | 5348.75 | 17.116 | 6028.81 | 19.2922 | 17.116 | 19.2922 | 5348.75 | 1.93418 | 6.18939 | 2500 | -500 | 6028.81 | 6.18939 | 12339.3 | 5700 | 2700 | 6.94608
Mur-143 | rdc | Mur-143 | rdc | 3 | Peinture-01 | 1 | 3 | 3500 | 2.04 | 1000 | 4.0428 | 3080 | 6.2028 | 8638.39 | 23.6381 | 24.5825 | 2.10895 | 8795.79 | 8480.99 | 27.2381 | 8795.79 | 28.1825 | 29.8409 | 30.7853 | 8480.99 | 2.99057 | 8.19749 | 2500 | -500 | 8795.79 | 10.3064 | 18080.1 | 6000 | 3000 | 8.73122
Mur-143 | rdc | Mur-143 | rdc | 3 | Peinture-01 | 1 | 0 | 3200 | 4.55562 | 2536.58 | 0 | 0 | 4.55562 | 5112.17 | 11.2591 | 12.3475 | 1.54891 | 5282.22 | 2405.53 | 11.2591 | 2745.64 | 12.3475 | 15.8147 | 16.9031 | 4942.11 | 0.875699 | 4.01312 | 2500 | -500 | 5290.78 | 5.56204 | 11051.4 | 5700 | 2700 | 5.2606
Mur-147 | rdc | Mur-147 | rdc | 3 | Peinture-01 | 0 | 0 | 3000 | 0 | 0 | 0 | 0 | 0 | 5567.29 | 15.6878 | 17.7159 | 0 | 5905.29 | 5229.28 | 15.6878 | 5905.29 | 17.7159 | 15.6878 | 17.7159 | 5229.28 | 1.89288 | 5.67863 | 3000 | 0 | 5905.29 | 5.67863 | 12093.4 | 6000 | 3000 | 6.66238
Mur-143 | rdc | Mur-143 | rdc | 3 | Peinture-01; Noyer | 1 | 0 | 3827.62 | 5.5 | 2500 | 0 | 0 | 5.17726 | 5536.36 | 15.3465 | 16.6811 | 1.76027 | 5710.69 | 5362.02 | 15.3465 | 5710.69 | 16.6811 | 20.5238 | 21.8584 | 5362.02 | 1.88236 | 5.4447 | 2500 | -500 | 5710.69 | 7.20497 | 11899.7 | 6327.62 | 3327.62 | 6.93017
Mur-146 | rdc | Mur-146 | rdc | 3 | Peinture-01 | 0 | 0 | 3000 | 0 | 0 | 0 | 0 | 0 | 3358.38 | 10.0778 | 10.0725 | 0 | 3357.5 | 3359.26 | 10.0778 | 3357.5 | 10.0725 | 10.0778 | 10.0725 | 3359.26 | 1.14185 | 3.42555 | 3000 | 0 | 3702.02 | 3.42555 | 7683.59 | 6000 | 3000 | 5.18419
Mur-144 | rdc | Mur-144 | rdc | 3 | Peinture-01 | 0 | 0 | 3000 | 0 | 0 | 0 | 0 | 0 | 8424.44 | 24.2503 | 26.2963 | 0 | 8765.45 | 8083.43 | 24.2503 | 8765.45 | 26.2963 | 24.2503 | 26.2963 | 8083.43 | 2.86431 | 8.59293 | 3000 | 0 | 8765.45 | 8.59293 | 17812.7 | 6000 | 3000 | 8.62003
Mur-145 | rdc | Mur-145 | rdc | 3 | Peinture-01 | 0 | 0 | 3000 | 0 | 0 | 0 | 0 | 0 | 9002.46 | 26.9733 | 27.0414 | 0 | 9013.8 | 8991.11 | 26.9733 | 9013.8 | 27.0414 | 26.9733 | 27.0414 | 8991.11 | 3.06084 | 9.18251 | 3000 | 0 | 9358.32 | 9.18251 | 18989.4 | 6000 | 3000 | 9.07512
Mur-142 | rdc | Mur-142 | rdc | 3 | Peinture-01 | 0 | 0 | 3827.62 | 0 | 0 | 0 | 0 | 0 | 11789.9 | 44.098 | 45.3439 | 0 | 12130.8 | 11448.9 | 44.098 | 12130.8 | 45.3439 | 44.098 | 46.4323 | 11448.9 | 4.06521 | 15.3901 | 2500 | -500 | 12130.8 | 15.3901 | 24542.8 | 6327.62 | 3327.62 | 11.8174
Mur-143 | Etage1 | Mur-143 | Etage1 | 4 | Peinture-01 | 0 | 3 | 2750 | 0 | 0 | 5.4 | 3000 | 5.4 | 8638.39 | 17.9227 | 18.7884 | 1.836 | 8795.79 | 8480.99 | 23.3227 | 8795.79 | 24.1884 | 23.3227 | 24.1884 | 8480.99 | 2.93705 | 6.24089 | 6000 | 250 | 8795.79 | 8.07689 | 18080.1 | 8750 | 3000 | 8.08335
Mur-143 | Etage1 | Mur-143 | Etage1 | 4 | Peinture-01 | 0 | 2 | 2422.38 | 0 | 0 | 4.24641 | 2000 | 4.04842 | 5536.36 | 8.94041 | 9.78501 | 1.37646 | 5710.69 | 5362.02 | 8.94041 | 5710.69 | 9.78501 | 12.9888 | 13.8334 | 5362.02 | 1.88236 | 3.18332 | 6327.62 | 577.625 | 5710.69 | 4.55978 | 11899.7 | 8750 | 3000 | 5.08803
Mur-144 | Etage1 | Mur-144 | Etage1 | 4 | Peinture-01 | 0 | 0 | 2750 | 0 | 0 | 0 | 0 | 0 | 8424.44 | 22.2294 | 24.105 | 0 | 8765.45 | 8083.43 | 22.2294 | 8765.45 | 24.105 | 22.2294 | 24.105 | 8083.43 | 2.86431 | 7.87685 | 6000 | 250 | 8765.45 | 7.87685 | 17812.7 | 8750 | 3000 | 8.37908
Mur-147 | Etage1 | Mur-147 | Etage1 | 4 | Peinture-01 | 0 | 0 | 2750 | 0 | 0 | 0 | 0 | 0 | 5567.29 | 14.4897 | 16.2396 | 0 | 5905.29 | 5229.28 | 14.4897 | 5905.29 | 16.2396 | 14.4897 | 16.2396 | 5229.28 | 1.94953 | 5.22398 | 6000 | 250 | 5905.29 | 5.22398 | 12093.4 | 8750 | 3000 | 6.49138
Mur-145 | Etage1 | Mur-145 | Etage1 | 4 | Peinture-01 | 0 | 0 | 2750 | 0 | 0 | 0 | 0 | 0 | 9002.46 | 24.7256 | 24.788 | 0 | 9013.8 | 8991.11 | 24.7256 | 9013.8 | 24.788 | 24.7256 | 24.788 | 8991.11 | 3.06084 | 8.4173 | 6000 | 250 | 9358.32 | 8.4173 | 18989.4 | 8750 | 3000 | 8.829
Mur-146 | Etage1 | Mur-146 | Etage1 | 4 | Peinture-01 | 0 | 0 | 2750 | 0 | 0 | 0 | 0 | 0 | 3358.38 | 9.23797 | 9.23313 | 0 | 3357.5 | 3359.26 | 9.23797 | 3357.5 | 9.23313 | 9.23797 | 9.23313 | 3359.26 | 1.14185 | 3.14009 | 6000 | 250 | 3702.02 | 3.14009 | 7683.59 | 8750 | 3000 | 4.94248
Mur-142 | Etage1 | Mur-142 | Etage1 | 4 | Peinture-01 | 0 | 0 | 2422.38 | 0 | 0 | 0 | 0 | 0 | 11789.9 | 27.7336 | 29.3855 | 0 | 12130.8 | 11448.9 | 27.7336 | 12130.8 | 29.3855 | 27.7336 | 29.3855 | 11448.9 | 4.00856 | 9.71024 | 6327.62 | 577.625 | 12130.8 | 9.71024 | 24542.8 | 8750 | 3000 | 10.3501

# IfcWallStandardCase: MANQUANT 20 (143)
Classification: Mur (Classification ARCHICAD); Material: MANQUANT 20 mm
AC_Pset_RenovationAndPhasing - Renovation Status: Existing
ArchiCADQuantities - Nombre de Portes: 0; Nombre de trous (Nombre d'ouvertures vides): 0; Nombre de Fenêtres: 0; Volume des poteaux: 0 m3; Hauteur maximale de la couche de Mur sur face intérieure: 0 mm; Hauteur minimale de la couche de Mur sur face intérieure: 0 mm; Hauteur maximale de la couche de Mur sur face extérieure: 0 mm; Hauteur minimale de la couche de Mur sur face extérieure: 0 mm; Épaisseur couche d'air: 0 mm; Superficie des portes: 0 m2; Largeur totale des Portes: 0 mm; Épaisseur de composant de mur sur face intérieure: 0 mm; Épaisseur de composant de mur sur face extérieure: 0 mm; Superficie des fenêtres: 0 m2; Largeur totale des Fenêtres: 0 mm; Superficie analytique des ouvertures sur face intérieure: 0 m2; Superficie analytique des ouvertures sur face extérieure: 0 m2; Volume analytique des ouvertures: 0 m3; Épaisseur du Mur à la fin: 20 mm; Superficie des baies libres dans le Mur: 0 m2; Largeur: 20 mm; Décalage supérieur: 0 mm; Épaisseur: 20 mm; Épaisseur couche isolation: 0 mm
ArchiCADProperties - Complexité de mur: Droit; Option de géométrie: Uniforme; Emplacement de ligne de référence: Face intérieure; Angle d'inclinaison interne de mur: 90 deg; Angle d'inclinaison externe de mur: 90 deg; Calque: 1-Projet; Matériau de construction / Composite / Profil / Hachure: MANQUANT; Matériau de construction: MANQUANT; Verrouillé: no; Type d'élément: Mur; Étage supérieur lié absolu: Non lié; Étage supérieur lié relatif: Non lié; Étage supérieur lié: Non lié; Type de structure: Basique; Matériaux de construction (Tous): MANQUANT; Angle d'inclinaison: 90 deg; Nombre de percements: 0; Nom de Variante: Modèle principal; Nom de Jeu de Variantes: Modèle principal; Position: Non défini; Fonction structurelle: Non défini; Affichage sur filtre de rénovation: Tous les filtres appropriés; État de rénovation: Existant; État de Variante: Modèle principal; Jeu de Variantes: Modèle principal
Name | In | Nombre de Poteaux | Hauteur maximale du Mur (mm) = Hauteur (mm) | Hauteur minimale du Mur (mm) | Longueur moyenne du mur (mm) = Longueur du Mur au centre (mm) | Superficie de la face intérieure du mur (nette) (m2) = Superficie de la face intérieure du mur (conditionnelle) (m2) | Superficie de la face extérieure du mur (nette) (m2) = Superficie de la face extérieure du mur (conditionnelle) (m2) = Superficie en plan (m2) = Superficie inférieure (nette) (m2) | Longueur de ligne de référence (mm) | Longueur de la face intérieure du mur (conditionnelle) (mm) = Longueur de Mur sur face intérieure (mm) | Longueur de la face extérieure du mur (conditionnelle) (mm) = Longueur de Mur sur face extérieure (mm) | Superficie de la face intérieure du mur (brute) (m2) | Superficie de la face extérieure du mur (brute) (m2) | Superficie (m2) = Superficie supérieure (nette) (m2) | Volume (net) (m3) = Volume (conditionnel) (m3) | Altitude à Zéro du Projet (mm) = Altitude de Référence Niveau 1 (mm) = Altitude de Référence Niveau 2 (mm) = Altitude à niveau de la mer (mm) = Altitude inférieure à premier niveau de référence (mm) = Altitude inférieure à Zéro du projet (mm) = Altitude inférieure à niveau de la mer (mm) = Altitude inférieure à deuxième niveau de référence (mm) | Altitude à étage lié/étage d'implantation (mm) = Décalage étage d'implantation (mm) = Altitude inférieure à étage d'implantation (mm) | Longueur 3D (mm) | Volume (brut) (m3) | Périmètre Plan (mm) | Altitude supérieure à premier niveau de référence (mm) = Altitude supérieure à Zéro du projet (mm) = Altitude supérieure à niveau de la mer (mm) = Altitude supérieure à deuxième niveau de référence (mm) | Altitude supérieure à étage d'implantation (mm) | Superficie de l'arête (nette) (m2) | Surface de face intérieure = Surface de face extérieure = Surfaces (Toutes) = Surface latérale | ID de l'élément = Lien et ID d'élément = ID de Parent | Nom d'étage d'implantation | Numéro d'étage d'implantation
4 x Mur-150 | rdc | 0 | 400 | 400 | 2000 | 0.8 | 0.8 | 2000 | 2000 | 2000 | 0.8 | 0.8 | 0.04 | 0.016 | 3100 | 100 | 2000 | 0.016 | 4040 | 3500 | 500 | 0.096 | Vitrage-Bleu | Mur-150 | rdc | 3
Mur-152 | rdc | 0 | 400 | 0 | 3161.91 | 1.26313 | 1.26476 | 3161.91 | 3161.91 | 3161.91 | 1.26313 | 1.26476 | 0.0632009 | 0.0252804 | 3100 | 100 | 3161.91 | 0.0252804 | 6363.81 | 3500 | 500 | 0.138257 | Vitrage-Bleu | Mur-152 | rdc | 3
Mur-152 | rdc | 0 | 400 | 400 | 5281.03 | 2.11241 | 2.11241 | 5281.03 | 5281.03 | 5281.03 | 2.11241 | 2.11241 | 0.105621 | 0.0422482 | 3100 | 100 | 5281.03 | 0.0422482 | 10602.1 | 3500 | 500 | 0.227241 | Vitrage-Bleu | Mur-152 | rdc | 3
Mur-150 | rdc | 0 | 400 | 400 | 5713.12 | 2.28525 | 2.28525 | 5713.12 | 5713.12 | 5713.12 | 2.28525 | 2.28525 | 0.114262 | 0.0457049 | 3100 | 100 | 5713.12 | 0.0457049 | 11466.2 | 3500 | 500 | 0.244525 | Vitrage-Bleu | Mur-150 | rdc | 3
Mur-152 | rdc | 0 | 400 | 400 | 5892.69 | 2.35708 | 2.35708 | 5892.69 | 5892.69 | 5892.69 | 2.35708 | 2.35708 | 0.117854 | 0.0471415 | 3100 | 100 | 5892.69 | 0.0471415 | 11825.4 | 3500 | 500 | 0.251708 | Vitrage-Bleu | Mur-152 | rdc | 3
Mur-152 | rdc | 0 | 400 | 400 | 17722.4 | 7.08896 | 7.08896 | 17722.4 | 17722.4 | 17722.4 | 7.08896 | 7.08896 | 0.354448 | 0.141779 | 3100 | 100 | 17722.4 | 0.141779 | 35484.8 | 3500 | 500 | 0.724896 | Vitrage-Bleu | Mur-152 | rdc | 3
Mur-152 | rdc | 0 | 400 | 400 | 5912 | 2.3648 | 2.3648 | 5912 | 5912 | 5912 | 2.3648 | 2.3648 | 0.11824 | 0.047296 | 3100 | 100 | 5912 | 0.047296 | 11864 | 3500 | 500 | 0.25248 | Vitrage-Bleu | Mur-152 | rdc | 3
Mur-152 | rdc | 0 | 400 | 400 | 3137.46 | 1.25498 | 1.25498 | 3137.46 | 3137.46 | 3137.46 | 1.25498 | 1.25498 | 0.0627492 | 0.0250997 | 3100 | 100 | 3137.46 | 0.0250997 | 6314.92 | 3500 | 500 | 0.141498 | Vitrage-Bleu | Mur-152 | rdc | 3
Mur-152 | rdc | 0 | 400 | 400 | 1351.75 | 0.540699 | 0.540699 | 1351.75 | 1351.75 | 1351.75 | 0.540699 | 0.540699 | 0.0270349 | 0.010814 | 3100 | 100 | 1351.75 | 0.010814 | 2743.49 | 3500 | 500 | 0.0700699 | Vitrage-Bleu | Mur-152 | rdc | 3
Mur-152 | rdc | 0 | 400 | 400 | 4999.57 | 1.99983 | 1.99983 | 4999.57 | 4999.57 | 4999.57 | 1.99983 | 1.99983 | 0.0999914 | 0.0399966 | 3100 | 100 | 4999.57 | 0.0399966 | 10039.1 | 3500 | 500 | 0.215983 | Vitrage-Bleu | Mur-152 | rdc | 3
Mur-152 | rdc | 0 | 400 | 400 | 7519.99 | 3.008 | 3.008 | 7519.99 | 7519.99 | 7519.99 | 3.008 | 3.008 | 0.1504 | 0.0601599 | 3100 | 100 | 7519.99 | 0.0601599 | 15080 | 3500 | 500 | 0.3168 | Vitrage-Bleu | Mur-152 | rdc | 3
Mur-189 | Etage1 | 0 | 400 | 400 | 765.001 | 0.31 | 0.302 | 775 | 775.001 | 755.001 | 0.31 | 0.302 | 0.0153 | 0.00612 | 5850 | 100 | 775 | 0.00612 | 1578.29 | 6250 | 500 | 0.0499137 | Vitrage-Bleu | Mur-189 | Etage1 | 4
5 x Mur-150 | Etage1 | 0 | 400 | 400 | 2000 | 0.8 | 0.8 | 2000 | 2000 | 2000 | 0.8 | 0.8 | 0.04 | 0.016 | 5850 | 100 | 2000 | 0.016 | 4040 | 6250 | 500 | 0.096 | Vitrage-Bleu | Mur-150 | Etage1 | 4
Mur-150 | Etage1 | 0 | 400 | 400 | 5224.51 | 2.0978 | 2.0818 | 5244.51 | 5244.51 | 5204.51 | 2.0978 | 2.0818 | 0.10449 | 0.0417961 | 5850 | 100 | 5244.51 | 0.0417961 | 10505.6 | 6250 | 500 | 0.231608 | Vitrage-Bleu | Mur-150 | Etage1 | 4
Mur-149 | Etage1 | 0 | 400 | 400 | 741.608 | 0.300643 | 0.292643 | 751.608 | 751.608 | 731.608 | 0.300643 | 0.292643 | 0.0148322 | 0.00593286 | 5850 | 100 | 751.608 | 0.00593286 | 1531.5 | 6250 | 500 | 0.048978 | Vitrage-Bleu | Mur-149 | Etage1 | 4
Mur-151 | Etage1 | 3 | 400 | 0 | 18313 | 7.15319 | 7.13719 | 18333 | 18333 | 18293 | 7.33319 | 7.31719 | 0.35726 | 0.142904 | 5850 | 100 | 17883 | 0.146504 | 36682.5 | 6250 | 500 | 0.737147 | Vitrage-Bleu | Mur-151 | Etage1 | 4
Mur-154 | Etage1 | 0 | 400 | 400 | 5713.12 | 2.28525 | 2.28525 | 5713.12 | 5713.12 | 5713.12 | 2.28525 | 2.28525 | 0.114262 | 0.0457049 | 5850 | 100 | 5713.12 | 0.0457049 | 11466.2 | 6250 | 500 | 0.244525 | Vitrage-Bleu | Mur-154 | Etage1 | 4
Mur-152 | Etage1 | 0 | 400 | 400 | 5130.06 | 2.05602 | 2.04802 | 5140.06 | 5140.06 | 5120.06 | 2.05602 | 2.04802 | 0.102601 | 0.0410404 | 5850 | 100 | 5140.06 | 0.0410404 | 10308.4 | 6250 | 500 | 0.224516 | Vitrage-Bleu | Mur-152 | Etage1 | 4
Mur-159 | Etage1 | 0 | 400 | 400 | 1166.91 | 0.470765 | 0.462765 | 1176.91 | 1176.91 | 1156.91 | 0.470765 | 0.462765 | 0.0233383 | 0.0093353 | 5850 | 100 | 1176.91 | 0.0093353 | 2382.11 | 6250 | 500 | 0.0659902 | Vitrage-Bleu | Mur-159 | Etage1 | 4
Mur-160 | Etage1 | 0 | 400 | 400 | 4838.21 | 1.94329 | 1.92729 | 4858.21 | 4858.21 | 4818.21 | 1.94329 | 1.92729 | 0.0967643 | 0.0387057 | 5850 | 100 | 4858.21 | 0.0387057 | 9732.99 | 6250 | 500 | 0.216156 | Vitrage-Bleu | Mur-160 | Etage1 | 4
Mur-156 | Etage1 | 0 | 400 | 400 | 760.082 | 0.308029 | 0.300029 | 770.072 | 770.082 | 750.082 | 0.308029 | 0.300029 | 0.0152014 | 0.00608058 | 5850 | 100 | 770.072 | 0.00608058 | 1568.45 | 6250 | 500 | 0.0497166 | Vitrage-Bleu | Mur-156 | Etage1 | 4
Mur-161 | Etage1 | 0 | 400 | 400 | 1166.91 | 0.470765 | 0.462765 | 1176.91 | 1176.91 | 1156.91 | 0.470765 | 0.462765 | 0.0233383 | 0.0093353 | 5850 | 100 | 1176.91 | 0.0093353 | 2382.11 | 6250 | 500 | 0.0659902 | Vitrage-Bleu | Mur-161 | Etage1 | 4
Mur-165 | Etage1 | 0 | 400 | 400 | 3374.39 | 1.34571 | 1.33771 | 3384.39 | 3384.39 | 3364.39 | 1.35375 | 1.34575 | 0.0674877 | 0.0269951 | 5850 | 100 | 3384.39 | 0.0269951 | 6797.06 | 6250 | 500 | 0.154289 | Vitrage-Bleu | Mur-165 | Etage1 | 4
Mur-164 | Etage1 | 0 | 400 | 0 | 2110.42 | 0.836127 | 0.836127 | 2110.42 | 2110.42 | 2110.42 | 0.836127 | 0.836127 | 0.0418063 | 0.0167225 | 5850 | 100 | 2092.34 | 0.0167225 | 4260.84 | 6250 | 500 | 0.0996127 | Vitrage-Bleu | Mur-164 | Etage1 | 4
Mur-162 | Etage1 | 0 | 400 | 400 | 8695.4 | 3.48216 | 3.47416 | 8705.4 | 8705.4 | 8685.4 | 3.48216 | 3.47416 | 0.173908 | 0.0695632 | 5850 | 100 | 8705.4 | 0.0695632 | 17439.1 | 6250 | 500 | 0.36713 | Vitrage-Bleu | Mur-162 | Etage1 | 4
Mur-166 | Etage1 | 0 | 400 | 400 | 590.362 | 0.240145 | 0.232145 | 600.362 | 600.362 | 580.362 | 0.240145 | 0.232145 | 0.0118072 | 0.0047229 | 5850 | 100 | 600.362 | 0.0047229 | 1229.01 | 6250 | 500 | 0.0429282 | Vitrage-Bleu | Mur-166 | Etage1 | 4
Mur-163 | Etage1 | 0 | 400 | 400 | 1581.3 | 0.63652 | 0.62852 | 1591.3 | 1591.3 | 1571.3 | 0.63652 | 0.62852 | 0.031626 | 0.0126504 | 5850 | 100 | 1591.3 | 0.0126504 | 3210.88 | 6250 | 500 | 0.0825657 | Vitrage-Bleu | Mur-163 | Etage1 | 4
Mur-169 | Etage1 | 0 | 400 | 400 | 5162.63 | 2.07305 | 2.05705 | 5182.63 | 5182.63 | 5142.63 | 2.07305 | 2.05705 | 0.103253 | 0.041301 | 5850 | 100 | 5182.63 | 0.041301 | 10381.8 | 6250 | 500 | 0.229133 | Vitrage-Bleu | Mur-169 | Etage1 | 4
Mur-170 | Etage1 | 0 | 400 | 400 | 760.003 | 0.308001 | 0.300001 | 770.003 | 770.003 | 750.003 | 0.308001 | 0.300001 | 0.0152001 | 0.00608003 | 5850 | 100 | 770.003 | 0.00608003 | 1568.29 | 6250 | 500 | 0.0497138 | Vitrage-Bleu | Mur-170 | Etage1 | 4
Mur-186 | Etage1 | 0 | 400 | 400 | 3165.66 | 1.26226 | 1.27026 | 3155.66 | 3155.66 | 3175.66 | 1.26226 | 1.27026 | 0.0633132 | 0.0253253 | 5850 | 100 | 3175.66 | 0.0253253 | 6379.6 | 6250 | 500 | 0.14594 | Vitrage-Bleu | Mur-186 | Etage1 | 4
Mur-187 | Etage1 | 0 | 400 | 400 | 929.946 | 0.371978 | 0.371978 | 929.946 | 929.946 | 929.946 | 0.371978 | 0.371978 | 0.0185989 | 0.00743956 | 5850 | 100 | 949.946 | 0.00743956 | 1916.46 | 6250 | 500 | 0.0598252 | Vitrage-Bleu | Mur-187 | Etage1 | 4
Mur-188 | Etage1 | 0 | 400 | 400 | 5503.54 | 2.20942 | 2.19342 | 5523.54 | 5523.54 | 5483.54 | 2.20942 | 2.19342 | 0.110071 | 0.0440283 | 5850 | 100 | 5523.54 | 0.0440283 | 11063.7 | 6250 | 500 | 0.242769 | Vitrage-Bleu | Mur-188 | Etage1 | 4
Mur-186 | Etage1 | 0 | 400 | 400 | 3155.66 | 1.26226 | 1.26226 | 3155.66 | 3155.66 | 3155.66 | 1.26226 | 1.26226 | 0.0631132 | 0.0252453 | 3100 | -2650 | 3155.66 | 0.0252453 | 6351.32 | 3500 | -2250 | 0.142226 | Vitrage-Bleu | Mur-186 | Etage1 | 4
Mur-190 | Etage1 | 0 | 400 | 400 | 3880.49 | 1.5522 | 1.5522 | 3880.5 | 3880.49 | 3880.49 | 1.5522 | 1.5522 | 0.0776098 | 0.0310439 | 5850 | 100 | 3880.49 | 0.0310439 | 7800.98 | 6250 | 500 | 0.17122 | Vitrage-Bleu | Mur-190 | Etage1 | 4
8 x Mur-150 | Etage 2 | 0 | 400 | 400 | 2000 | 0.8 | 0.8 | 2000 | 2000 | 2000 | 0.8 | 0.8 | 0.04 | 0.016 | 8600 | 100 | 2000 | 0.016 | 4040 | 9000 | 500 | 0.096 | Vitrage-Bleu | Mur-150 | Etage 2 | 5
Mur-172 | Etage 2 | 0 | 400 | 400 | 1581.3 | 0.63652 | 0.628522 | 1591.3 | 1591.3 | 1571.31 | 0.63652 | 0.628522 | 0.0316261 | 0.0126504 | 8600 | 100 | 1591.3 | 0.0126504 | 3210.89 | 9000 | 500 | 0.0825643 | Vitrage-Bleu | Mur-172 | Etage 2 | 5
Mur-173 | Etage 2 | 0 | 400 | 400 | 1166.91 | 0.470765 | 0.462765 | 1176.91 | 1176.91 | 1156.91 | 0.470765 | 0.462765 | 0.0233383 | 0.0093353 | 8600 | 100 | 1176.91 | 0.0093353 | 2382.11 | 9000 | 500 | 0.0659902 | Vitrage-Bleu | Mur-173 | Etage 2 | 5
Mur-174 | Etage 2 | 0 | 400 | 400 | 2906.48 | 1.17059 | 1.15459 | 2926.48 | 2926.48 | 2886.48 | 1.17059 | 1.15459 | 0.0581296 | 0.0232518 | 8600 | 100 | 2926.48 | 0.0232518 | 5869.53 | 9000 | 500 | 0.138887 | Vitrage-Bleu | Mur-174 | Etage 2 | 5
Mur-171 | Etage 2 | 0 | 400 | 400 | 7721.01 | 3.0924 | 3.0844 | 7731 | 7731 | 7711.01 | 3.0924 | 3.0844 | 0.15442 | 0.061768 | 8600 | 100 | 7731 | 0.061768 | 15490.3 | 9000 | 500 | 0.328152 | Vitrage-Bleu | Mur-171 | Etage 2 | 5
Mur-175 | Etage 2 | 0 | 400 | 400 | 1166.91 | 0.470765 | 0.462765 | 1176.91 | 1176.91 | 1156.91 | 0.470765 | 0.462765 | 0.0233383 | 0.0093353 | 8600 | 100 | 1176.91 | 0.0093353 | 2382.11 | 9000 | 500 | 0.0659902 | Vitrage-Bleu | Mur-175 | Etage 2 | 5
Mur-179 | Etage 2 | 0 | 400 | 400 | 5110.55 | 2.04822 | 2.04022 | 5120.55 | 5120.55 | 5100.55 | 2.04822 | 2.04022 | 0.102211 | 0.0408844 | 8600 | 100 | 5120.55 | 0.0408844 | 10269.4 | 9000 | 500 | 0.223736 | Vitrage-Bleu | Mur-179 | Etage 2 | 5
Mur-180 | Etage 2 | 3 | 400 | 0 | 17399.7 | 6.78786 | 6.95186 | 17419.7 | 17419.7 | 17379.7 | 6.96786 | 6.95186 | 0.341731 | 0.136693 | 8600 | 100 | 17419.7 | 0.139197 | 34855.9 | 9000 | 500 | 0.70609 | Vitrage-Bleu | Mur-180 | Etage 2 | 5
Mur-183 | Etage 2 | 0 | 400 | 400 | 735.08 | 0.298032 | 0.290032 | 745.081 | 745.08 | 725.08 | 0.298032 | 0.290032 | 0.0147016 | 0.00588065 | 8600 | 100 | 745.081 | 0.00588065 | 1518.44 | 9000 | 500 | 0.0487169 | Vitrage-Bleu | Mur-183 | Etage 2 | 5
Mur-181 | Etage 2 | 0 | 400 | 400 | 5110.55 | 2.04822 | 2.04022 | 5120.55 | 5120.55 | 5100.55 | 2.04822 | 2.04022 | 0.102211 | 0.0408844 | 8600 | 100 | 5120.55 | 0.0408844 | 10269.4 | 9000 | 500 | 0.223736 | Vitrage-Bleu | Mur-181 | Etage 2 | 5
Mur-184 | Etage 2 | 0 | 400 | 400 | 5213.32 | 2.09333 | 2.07733 | 5233.32 | 5233.32 | 5193.32 | 2.09333 | 2.07733 | 0.104266 | 0.0417065 | 8600 | 100 | 5233.32 | 0.0417065 | 10483.2 | 9000 | 500 | 0.23116 | Vitrage-Bleu | Mur-184 | Etage 2 | 5
Mur-186 | Etage 2 | 0 | 400 | 400 | 3165.66 | 1.26226 | 1.27026 | 3155.66 | 3155.66 | 3175.66 | 1.26226 | 1.27026 | 0.0633132 | 0.0253253 | 8600 | 100 | 3175.66 | 0.0253253 | 6379.6 | 9000 | 500 | 0.14594 | Vitrage-Bleu | Mur-186 | Etage 2 | 5
Mur-187 | Etage 2 | 0 | 400 | 400 | 929.946 | 0.371978 | 0.371978 | 929.946 | 929.946 | 929.946 | 0.371978 | 0.371978 | 0.0185989 | 0.00743956 | 8600 | 100 | 949.946 | 0.00743956 | 1916.46 | 9000 | 500 | 0.0598252 | Vitrage-Bleu | Mur-187 | Etage 2 | 5
Mur-188 | Etage 2 | 0 | 400 | 400 | 5503.54 | 2.20942 | 2.19342 | 5523.54 | 5523.54 | 5483.54 | 2.20942 | 2.19342 | 0.110071 | 0.0440283 | 8600 | 100 | 5523.54 | 0.0440283 | 11063.7 | 9000 | 500 | 0.242769 | Vitrage-Bleu | Mur-188 | Etage 2 | 5
Mur-190 | Etage 2 | 0 | 400 | 400 | 3880.49 | 1.5522 | 1.5522 | 3880.5 | 3880.49 | 3880.49 | 1.5522 | 1.5522 | 0.0776098 | 0.0310439 | 8600 | 100 | 3880.49 | 0.0310439 | 7800.98 | 9000 | 500 | 0.17122 | Vitrage-Bleu | Mur-190 | Etage 2 | 5
Mur-185 | Etage 2 | 0 | 400 | 400 | 735 | 0.298 | 0.29 | 745 | 745 | 725 | 0.298 | 0.29 | 0.0147 | 0.00588 | 8600 | 100 | 745 | 0.00588 | 1518.28 | 9000 | 500 | 0.0487137 | Vitrage-Bleu | Mur-185 | Etage 2 | 5
Mur-165 | Etage 2 | 0 | 400 | 400 | 3374.15 | 1.35366 | 1.34566 | 3384.15 | 3384.15 | 3364.15 | 1.35366 | 1.34566 | 0.0674831 | 0.0269932 | 8600 | 100 | 3384.15 | 0.0269932 | 6796.59 | 9000 | 500 | 0.15428 | Vitrage-Bleu | Mur-165 | Etage 2 | 5
Mur-164 | Etage 2 | 0 | 400 | 400 | 2097.42 | 0.838968 | 0.838968 | 2097.42 | 2097.42 | 2097.42 | 0.838968 | 0.838968 | 0.0419484 | 0.0167794 | 8600 | 100 | 2097.42 | 0.0167794 | 4234.84 | 9000 | 500 | 0.0998968 | Vitrage-Bleu | Mur-164 | Etage 2 | 5
Mur-166 | Etage 2 | 0 | 400 | 400 | 590.362 | 0.240145 | 0.232145 | 600.362 | 600.362 | 580.362 | 0.240145 | 0.232145 | 0.0118072 | 0.0047229 | 8600 | 100 | 600.362 | 0.0047229 | 1229.01 | 9000 | 500 | 0.0429282 | Vitrage-Bleu | Mur-166 | Etage 2 | 5
Mur-189 | Etage 2 | 0 | 400 | 400 | 765.001 | 0.31 | 0.302 | 775 | 775.001 | 755.001 | 0.31 | 0.302 | 0.0153 | 0.00612 | 8600 | 100 | 775 | 0.00612 | 1578.29 | 9000 | 500 | 0.0499137 | Vitrage-Bleu | Mur-189 | Etage 2 | 5
Mur-154 | Etage 2 | 0 | 400 | 400 | 5713.12 | 2.28525 | 2.28525 | 5713.12 | 5713.12 | 5713.12 | 2.28525 | 2.28525 | 0.114262 | 0.0457049 | 8600 | 100 | 5713.12 | 0.0457049 | 11466.2 | 9000 | 500 | 0.244525 | Vitrage-Bleu | Mur-154 | Etage 2 | 5
Mur-154 | Etage 3 | 0 | 400 | 400 | 5713.12 | 2.28525 | 2.28525 | 5713.12 | 5713.12 | 5713.12 | 2.28525 | 2.28525 | 0.114262 | 0.0457049 | 11650 | 100 | 5713.12 | 0.0457049 | 11466.2 | 12050 | 500 | 0.244525 | Vitrage-Bleu | Mur-154 | Etage 3 | 6
Mur-183 | Etage 3 | 0 | 400 | 400 | 735.076 | 0.298032 | 0.290032 | 745.081 | 745.076 | 725.076 | 0.298032 | 0.290032 | 0.0147016 | 0.00588065 | 11650 | 100 | 745.081 | 0.00588065 | 1518.44 | 12050 | 500 | 0.0487169 | Vitrage-Bleu | Mur-183 | Etage 3 | 6
3 x Mur-150 | Etage 3 | 0 | 400 | 400 | 2000 | 0.8 | 0.8 | 2000 | 2000 | 2000 | 0.8 | 0.8 | 0.04 | 0.016 | 11650 | 100 | 2000 | 0.016 | 4040 | 12050 | 500 | 0.096 | Vitrage-Bleu | Mur-150 | Etage 3 | 6
Mur-214 | Etage 3 | 0 | 400 | 400 | 2639.21 | 1.05969 | 1.05169 | 2649.21 | 2649.21 | 2629.21 | 1.05969 | 1.05169 | 0.0527843 | 0.0211137 | 11650 | 100 | 2649.21 | 0.0211137 | 5326.71 | 12050 | 500 | 0.124882 | Vitrage-Bleu | Mur-214 | Etage 3 | 6
Mur-195 | Etage 3 | 0 | 400 | 400 | 1358.01 | 0.547205 | 0.539205 | 1368.01 | 1368.01 | 1348.01 | 0.547205 | 0.539205 | 0.0271603 | 0.0108641 | 11650 | 100 | 1368.01 | 0.0108641 | 2764.31 | 12050 | 500 | 0.0736342 | Vitrage-Bleu | Mur-195 | Etage 3 | 6
Mur-193 | Etage 3 | 0 | 400 | 400 | 1358.01 | 0.547205 | 0.539205 | 1368.01 | 1368.01 | 1348.01 | 0.547205 | 0.539205 | 0.0271603 | 0.0108641 | 11650 | 100 | 1368.01 | 0.0108641 | 2764.31 | 12050 | 500 | 0.0736342 | Vitrage-Bleu | Mur-193 | Etage 3 | 6
Mur-196 | Etage 3 | 0 | 400 | 400 | 8733.45 | 3.49738 | 3.48938 | 8743.45 | 8743.45 | 8723.45 | 3.49738 | 3.48938 | 0.174669 | 0.0698676 | 11650 | 100 | 8743.45 | 0.0698676 | 17515.2 | 12050 | 500 | 0.368652 | Vitrage-Bleu | Mur-196 | Etage 3 | 6
Mur-198 | Etage 3 | 0 | 400 | 400 | 1460.19 | 0.588076 | 0.580076 | 1470.19 | 1470.19 | 1450.19 | 0.588076 | 0.580076 | 0.0292038 | 0.0116815 | 11650 | 100 | 1470.19 | 0.0116815 | 2968.66 | 12050 | 500 | 0.0777214 | Vitrage-Bleu | Mur-198 | Etage 3 | 6
Mur-197 | Etage 3 | 0 | 400 | 400 | 1504.7 | 0.60588 | 0.597881 | 1514.7 | 1514.7 | 1494.7 | 0.60588 | 0.597881 | 0.030094 | 0.0120376 | 11650 | 100 | 1514.7 | 0.0120376 | 3057.69 | 12050 | 500 | 0.0795015 | Vitrage-Bleu | Mur-197 | Etage 3 | 6
Mur-199 | Etage 3 | 0 | 400 | 400 | 9558.01 | 3.8312 | 3.8152 | 9578.01 | 9578.01 | 9538.01 | 3.8312 | 3.8152 | 0.19116 | 0.0764641 | 11650 | 100 | 9578.01 | 0.0764641 | 19172.6 | 12050 | 500 | 0.404948 | Vitrage-Bleu | Mur-199 | Etage 3 | 6
Mur-194 | Etage 3 | 0 | 400 | 400 | 4966.48 | 1.99459 | 1.97859 | 4986.48 | 4986.48 | 4946.48 | 1.99459 | 1.97859 | 0.0993296 | 0.0397318 | 11650 | 100 | 4986.48 | 0.0397318 | 9989.53 | 12050 | 500 | 0.221287 | Vitrage-Bleu | Mur-194 | Etage 3 | 6
Mur-202 | Etage 3 | 0 | 400 | 400 | 8088.8 | 3.24394 | 3.22709 | 8109.86 | 8109.86 | 8067.73 | 3.24394 | 3.22709 | 0.161776 | 0.0647104 | 11650 | 100 | 8109.86 | 0.0647104 | 16235.7 | 12050 | 500 | 0.346797 | Vitrage-Bleu | Mur-202 | Etage 3 | 6
Mur-200 | Etage 3 | 0 | 400 | 400 | 1460.01 | 0.588001 | 0.580001 | 1470 | 1470 | 1450.01 | 0.588001 | 0.580001 | 0.0292 | 0.01168 | 11650 | 100 | 1470 | 0.01168 | 2968.29 | 12050 | 500 | 0.0777138 | Vitrage-Bleu | Mur-200 | Etage 3 | 6
Mur-203 | Etage 3 | 0 | 400 | 400 | 1450.93 | 0.584799 | 0.575947 | 1462 | 1462 | 1439.87 | 0.584799 | 0.575947 | 0.0290186 | 0.0116075 | 11650 | 100 | 1462 | 0.0116075 | 2951.69 | 12050 | 500 | 0.0779685 | Vitrage-Bleu | Mur-203 | Etage 3 | 6
Mur-201 | Etage 3 | 0 | 400 | 400 | 1456.86 | 0.586744 | 0.578744 | 1466.86 | 1466.86 | 1446.86 | 0.586744 | 0.578744 | 0.0291372 | 0.0116549 | 11650 | 100 | 1466.86 | 0.0116549 | 2962.01 | 12050 | 500 | 0.0775882 | Vitrage-Bleu | Mur-201 | Etage 3 | 6
Mur-205 | Etage 3 | 0 | 400 | 400 | 10034 | 4.02159 | 4.00559 | 10054 | 10054 | 10014 | 4.02159 | 4.00559 | 0.20068 | 0.0802718 | 11650 | 100 | 10054 | 0.0802718 | 20124.5 | 12050 | 500 | 0.423986 | Vitrage-Bleu | Mur-205 | Etage 3 | 6
Mur-206 | Etage 3 | 0 | 400 | 400 | 1347.7 | 0.543079 | 0.535079 | 1357.7 | 1357.7 | 1337.7 | 0.543079 | 0.535079 | 0.026954 | 0.0107816 | 11650 | 100 | 1357.7 | 0.0107816 | 2743.68 | 12050 | 500 | 0.0732216 | Vitrage-Bleu | Mur-206 | Etage 3 | 6
Mur-204 | Etage 3 | 0 | 400 | 400 | 1350.39 | 0.544156 | 0.536156 | 1360.39 | 1360.39 | 1340.39 | 0.544156 | 0.536156 | 0.0270078 | 0.0108031 | 11650 | 100 | 1360.39 | 0.0108031 | 2749.07 | 12050 | 500 | 0.0733294 | Vitrage-Bleu | Mur-204 | Etage 3 | 6
Mur-208 | Etage 3 | 0 | 400 | 400 | 5502.1 | 2.20927 | 2.19241 | 5523.16 | 5523.16 | 5481.03 | 2.20927 | 2.19241 | 0.110042 | 0.0440168 | 11650 | 100 | 5523.16 | 0.0440168 | 11062.3 | 12050 | 500 | 0.243329 | Vitrage-Bleu | Mur-208 | Etage 3 | 6
Mur-207 | Etage 3 | 0 | 400 | 400 | 2301.73 | 0.924712 | 0.916671 | 2311.78 | 2311.78 | 2291.68 | 0.924712 | 0.916671 | 0.0460346 | 0.0184138 | 11650 | 100 | 2313.81 | 0.0184138 | 4653.39 | 12050 | 500 | 0.112041 | Vitrage-Bleu | Mur-207 | Etage 3 | 6
Mur-209 | Etage 3 | 0 | 400 | 400 | 788.987 | 0.319595 | 0.311595 | 798.987 | 798.987 | 778.987 | 0.319595 | 0.311595 | 0.0157797 | 0.00631189 | 11650 | 100 | 798.987 | 0.00631189 | 1626.26 | 12050 | 500 | 0.0508732 | Vitrage-Bleu | Mur-209 | Etage 3 | 6
Mur-213 | Etage 3 | 0 | 400 | 400 | 14397.4 | 5.76697 | 5.75097 | 14417.4 | 14417.4 | 14377.4 | 5.76697 | 5.75097 | 0.287948 | 0.115179 | 11650 | 100 | 14417.4 | 0.115179 | 28851.4 | 12050 | 500 | 0.598524 | Vitrage-Bleu | Mur-213 | Etage 3 | 6
Mur-210 | Etage 3 | 0 | 400 | 400 | 10769.7 | 4.30789 | 4.30789 | 10769.7 | 10769.7 | 10769.7 | 4.30789 | 4.30789 | 0.215394 | 0.0861578 | 11650 | 100 | 10789.7 | 0.0861578 | 21596 | 12050 | 500 | 0.453416 | Vitrage-Bleu | Mur-210 | Etage 3 | 6
Mur-211 | Etage 3 | 0 | 400 | 400 | 1340.36 | 0.540144 | 0.532144 | 1350.36 | 1350.36 | 1330.36 | 0.540144 | 0.532144 | 0.0268072 | 0.0107229 | 11650 | 100 | 1350.36 | 0.0107229 | 2729 | 12050 | 500 | 0.0729281 | Vitrage-Bleu | Mur-211 | Etage 3 | 6
Mur-185 | Etage 3 | 0 | 400 | 400 | 894.64 | 0.357856 | 0.357856 | 894.64 | 894.64 | 894.64 | 0.357856 | 0.357856 | 0.0178928 | 0.00715712 | 11650 | 100 | 914.64 | 0.00715712 | 1845.85 | 12050 | 500 | 0.058413 | Vitrage-Bleu | Mur-185 | Etage 3 | 6
Mur-184 | Etage 3 | 0 | 400 | 400 | 5213.32 | 2.09333 | 2.07733 | 5233.32 | 5233.32 | 5193.32 | 2.09333 | 2.07733 | 0.104266 | 0.0417065 | 11650 | 100 | 5233.32 | 0.0417065 | 10483.2 | 12050 | 500 | 0.23116 | Vitrage-Bleu | Mur-184 | Etage 3 | 6
Mur-212 | Etage 3 | 0 | 400 | 400 | 2639.21 | 1.05969 | 1.05169 | 2649.21 | 2649.21 | 2629.21 | 1.05969 | 1.05169 | 0.0527843 | 0.0211137 | 11650 | 100 | 2649.21 | 0.0211137 | 5326.71 | 12050 | 500 | 0.124882 | Vitrage-Bleu | Mur-212 | Etage 3 | 6
Mur-150 | Etage 3 | 0 | 400 | 400 | 2500.1 | 1.00004 | 1.00004 | 2500.1 | 2500.1 | 2500.1 | 1.00004 | 1.00004 | 0.050002 | 0.0200008 | 11650 | 100 | 2500.1 | 0.0200008 | 5040.2 | 12050 | 500 | 0.116004 | Vitrage-Bleu | Mur-150 | Etage 3 | 6
Mur-183 | etage 4 | 0 | 400 | 400 | 735.076 | 0.298032 | 0.290032 | 745.081 | 745.076 | 725.076 | 0.298032 | 0.290032 | 0.0147016 | 0.00588065 | 14700 | 100 | 745.081 | 0.00588065 | 1518.44 | 15100 | 500 | 0.0487169 | Vitrage-Bleu | Mur-183 | etage 4 | 7
2 x Mur-208 | etage 4 | 0 | 400 | 400 | 5502.1 | 2.20927 | 2.19241 | 5523.16 | 5523.16 | 5481.03 | 2.20927 | 2.19241 | 0.110042 | 0.0440168 | 14700 | 100 | 5523.16 | 0.0440168 | 11062.3 | 15100 | 500 | 0.243329 | Vitrage-Bleu | Mur-208 | etage 4 | 7
2 x Mur-207 | etage 4 | 0 | 400 | 400 | 2301.73 | 0.924712 | 0.916671 | 2311.78 | 2311.78 | 2291.68 | 0.924712 | 0.916671 | 0.0460346 | 0.0184138 | 14700 | 100 | 2313.81 | 0.0184138 | 4653.39 | 15100 | 500 | 0.112041 | Vitrage-Bleu | Mur-207 | etage 4 | 7
2 x Mur-209 | etage 4 | 0 | 400 | 400 | 788.987 | 0.319595 | 0.311595 | 798.987 | 798.987 | 778.987 | 0.319595 | 0.311595 | 0.0157797 | 0.00631189 | 14700 | 100 | 798.987 | 0.00631189 | 1626.26 | 15100 | 500 | 0.0508732 | Vitrage-Bleu | Mur-209 | etage 4 | 7
2 x Mur-150 | etage 4 | 0 | 400 | 400 | 2000 | 0.8 | 0.8 | 2000 | 2000 | 2000 | 0.8 | 0.8 | 0.04 | 0.016 | 14700 | 100 | 2000 | 0.016 | 4040 | 15100 | 500 | 0.096 | Vitrage-Bleu | Mur-150 | etage 4 | 7
Mur-228 | etage 4 | 0 | 400 | 400 | 4568.2 | 1.83128 | 1.82328 | 4578.2 | 4578.2 | 4558.2 | 1.83128 | 1.82328 | 0.0913639 | 0.0365456 | 14700 | 100 | 4578.2 | 0.0365456 | 9184.67 | 15100 | 500 | 0.202042 | Vitrage-Bleu | Mur-228 | etage 4 | 7
Mur-218 | etage 4 | 0 | 400 | 400 | 1358.01 | 0.547205 | 0.539205 | 1368.01 | 1368.01 | 1348.01 | 0.547205 | 0.539205 | 0.0271603 | 0.0108641 | 14700 | 100 | 1368.01 | 0.0108641 | 2764.31 | 15100 | 500 | 0.0736342 | Vitrage-Bleu | Mur-218 | etage 4 | 7
Mur-219 | etage 4 | 0 | 400 | 400 | 4966.48 | 1.99459 | 1.97859 | 4986.48 | 4986.48 | 4946.48 | 1.99459 | 1.97859 | 0.0993296 | 0.0397318 | 14700 | 100 | 4986.48 | 0.0397318 | 9989.53 | 15100 | 500 | 0.221287 | Vitrage-Bleu | Mur-219 | etage 4 | 7
2 x Mur-184 | etage 4 | 0 | 400 | 400 | 6829.8 | 2.73992 | 2.72392 | 6849.8 | 6849.8 | 6809.8 | 2.73992 | 2.72392 | 0.136596 | 0.0546384 | 14700 | 100 | 6849.8 | 0.0546384 | 13716.2 | 15100 | 500 | 0.295819 | Vitrage-Bleu | Mur-184 | etage 4 | 7
2 x Mur-225 | etage 4 | 0 | 400 | 400 | 2438.79 | 0.979514 | 0.971514 | 2448.79 | 2448.79 | 2428.79 | 0.979514 | 0.971514 | 0.0487757 | 0.0195103 | 14700 | 100 | 2448.79 | 0.0195103 | 4925.86 | 15100 | 500 | 0.116865 | Vitrage-Bleu | Mur-225 | etage 4 | 7
2 x Mur-226 | etage 4 | 0 | 400 | 400 | 15922.4 | 6.37698 | 6.36098 | 15942.4 | 15942.4 | 15902.4 | 6.37698 | 6.36098 | 0.318449 | 0.12738 | 14700 | 100 | 15942.4 | 0.12738 | 31901.4 | 15100 | 500 | 0.659525 | Vitrage-Bleu | Mur-226 | etage 4 | 7
Mur-227 | etage 4 | 3 | 400 | 0 | 18754.4 | 7.32977 | 7.31377 | 18774.4 | 18774.4 | 18734.4 | 7.50977 | 7.49377 | 0.366091 | 0.146435 | 14700 | 100 | 18324.4 | 0.150035 | 37565.4 | 15100 | 500 | 0.754804 | Vitrage-Bleu | Mur-227 | etage 4 | 7
Mur-220 | etage 4 | 0 | 400 | 400 | 1358.01 | 0.547205 | 0.539205 | 1368.01 | 1368.01 | 1348.01 | 0.547205 | 0.539205 | 0.0271603 | 0.0108641 | 14700 | 100 | 1368.01 | 0.0108641 | 2764.31 | 15100 | 500 | 0.0736342 | Vitrage-Bleu | Mur-220 | etage 4 | 7
2 x Mur-185 | etage 4 | 0 | 400 | 400 | 2235 | 0.898 | 0.89 | 2245 | 2245 | 2225 | 0.898 | 0.89 | 0.0447 | 0.01788 | 14700 | 100 | 2245 | 0.01788 | 4518.28 | 15100 | 500 | 0.108714 | Vitrage-Bleu | Mur-185 | etage 4 | 7
Mur-183 | etage 4 | 0 | 400 | 400 | 735.081 | 0.298032 | 0.290032 | 745.081 | 745.081 | 725.081 | 0.298032 | 0.290032 | 0.0147016 | 0.00588065 | 14700 | 100 | 745.081 | 0.00588065 | 1518.45 | 15100 | 500 | 0.0487169 | Vitrage-Bleu | Mur-183 | etage 4 | 7
2 x Mur-234 | Etage 5 | 0 | 400 | 400 | 1344.25 | 0.5417 | 0.5337 | 1354.25 | 1354.25 | 1334.25 | 0.5417 | 0.5337 | 0.026885 | 0.010754 | 17750 | 100 | 1354.25 | 0.010754 | 2736.78 | 18150 | 500 | 0.0730837 | Vitrage-Bleu | Mur-234 | Etage 5 | 8
Mur-237 | Etage 5 | 0 | 400 | 400 | 15004.3 | 6.00974 | 5.99374 | 15024.3 | 15024.3 | 14984.3 | 6.00974 | 5.99374 | 0.300087 | 0.120035 | 17750 | 100 | 15024.3 | 0.120035 | 30065.2 | 18150 | 500 | 0.622801 | Vitrage-Bleu | Mur-237 | Etage 5 | 8
2 x Mur-230 | Etage 5 | 0 | 400 | 400 | 11276 | 4.51846 | 4.50237 | 11296.1 | 11296.1 | 11255.9 | 4.51846 | 4.50237 | 0.225521 | 0.0902083 | 17750 | 100 | 11296.1 | 0.0902083 | 22608.9 | 18150 | 500 | 0.473756 | Vitrage-Bleu | Mur-230 | Etage 5 | 8
Mur-238 | Etage 5 | 0 | 400 | 400 | 2095.76 | 0.842303 | 0.834303 | 2105.76 | 2105.76 | 2085.76 | 0.842303 | 0.834303 | 0.0419151 | 0.0167661 | 17750 | 100 | 2105.76 | 0.0167661 | 4239.8 | 18150 | 500 | 0.103144 | Vitrage-Bleu | Mur-238 | Etage 5 | 8
2 x Mur-236 | Etage 5 | 0 | 400 | 400 | 13475 | 5.398 | 5.382 | 13495 | 13495 | 13455 | 5.398 | 5.382 | 0.2695 | 0.1078 | 17750 | 100 | 13495 | 0.1078 | 27006.6 | 18150 | 500 | 0.561627 | Vitrage-Bleu | Mur-236 | Etage 5 | 8
Mur-229 | Etage 5 | 0 | 400 | 400 | 2345.25 | 0.941714 | 0.934486 | 2354.29 | 2354.29 | 2336.21 | 0.941714 | 0.934486 | 0.046905 | 0.018762 | 17750 | 100 | 2354.29 | 0.018762 | 4737.45 | 18150 | 500 | 0.112592 | Vitrage-Bleu | Mur-229 | Etage 5 | 8
2 x Mur-235 | Etage 5 | 0 | 400 | 400 | 2345.98 | 0.942392 | 0.934392 | 2355.98 | 2355.98 | 2335.98 | 0.942392 | 0.934392 | 0.0469196 | 0.0187678 | 17750 | 100 | 2355.98 | 0.0187678 | 4740.24 | 18150 | 500 | 0.113153 | Vitrage-Bleu | Mur-235 | Etage 5 | 8
2 x Mur-233 | Etage 5 | 0 | 400 | 400 | 12655.7 | 5.07029 | 5.05429 | 12675.7 | 12675.7 | 12635.7 | 5.07029 | 5.05429 | 0.253114 | 0.101246 | 17750 | 100 | 12675.7 | 0.101246 | 25368 | 18150 | 500 | 0.528856 | Vitrage-Bleu | Mur-233 | Etage 5 | 8
2 x Mur-231 | Etage 5 | 0 | 400 | 400 | 3485.29 | 1.39854 | 1.38969 | 3496.36 | 3496.36 | 3474.23 | 1.39854 | 1.38969 | 0.0697059 | 0.0278824 | 17750 | 100 | 3496.36 | 0.0278824 | 7020.42 | 18150 | 500 | 0.159345 | Vitrage-Bleu | Mur-231 | Etage 5 | 8
2 x Mur-232 | Etage 5 | 0 | 400 | 400 | 1344.25 | 0.5417 | 0.5337 | 1354.25 | 1354.25 | 1334.25 | 0.5417 | 0.5337 | 0.026885 | 0.010754 | 17750 | 100 | 1354.25 | 0.010754 | 2736.78 | 18150 | 500 | 0.0730837 | Vitrage-Bleu | Mur-232 | Etage 5 | 8
Mur-173 | toiture | 0 | 232.36 | 232.36 | 3431.93 | 0.795119 | 0.799767 | 3421.93 | 3421.93 | 3441.93 | 0.795119 | 0.799767 | 0.0686387 | 0.0159489 | 20548.1 | 198.06 | 3441.93 | 0.0159489 | 6912.15 | 20780.4 | 430.42 | 0.148497 | Innvik Tex Stripe 1440 | Mur-173 | toiture | 9
Mur-227 | toiture | 0 | 400 | 400 | 3411.93 | 1.36877 | 1.36077 | 3421.93 | 3421.93 | 3401.93 | 1.36877 | 1.36077 | 0.0682387 | 0.0272955 | 20980.4 | 630.42 | 3421.93 | 0.0272955 | 6872.15 | 21380.4 | 1030.42 | 0.155791 | Vitrage-Bleu | Mur-227 | toiture | 9
Mur-172 | toiture | 0 | 232.36 | 232.36 | 1040 | 0.23933 | 0.243978 | 1030 | 1030 | 1050 | 0.23933 | 0.243978 | 0.0208 | 0.00483308 | 20548.1 | 198.06 | 1050 | 0.00483308 | 2128.28 | 20780.4 | 430.42 | 0.0528193 | Innvik Tex Stripe 1440 | Mur-172 | toiture | 9
Mur-227 | toiture | 0 | 400 | 400 | 1121.27 | 0.452508 | 0.444508 | 1131.27 | 1131.27 | 1111.27 | 0.452508 | 0.444508 | 0.0224254 | 0.00897017 | 20980.4 | 630.42 | 1131.27 | 0.00897017 | 2290.83 | 21380.4 | 1030.42 | 0.0641646 | Vitrage-Bleu | Mur-227 | toiture | 9

# IfcWallStandardCase: SAA 120 120 (80)
Classification: Mur (Classification ARCHICAD); Material: AS_EMPTY 272048125 20 mm, Isolant styromousse 275581351 80 mm, AS_EMPTY 272048125 20 mm
AC_Pset_RenovationAndPhasing - Renovation Status: Existing
ArchiCADQuantities - Nombre de Portes: 0; Nombre de trous (Nombre d'ouvertures vides): 0; Nombre de Fenêtres: 0; Nombre de Poteaux: 0; Volume des poteaux: 0 m3; Épaisseur couche d'air: 0 mm; Superficie des portes: 0 m2; Largeur totale des Portes: 0 mm; Épaisseur de composant de mur sur face intérieure: 20 mm; Épaisseur de composant de mur sur face extérieure: 20 mm; Superficie des fenêtres: 0 m2; Largeur totale des Fenêtres: 0 mm; Superficie analytique des ouvertures sur face intérieure: 0 m2; Superficie analytique des ouvertures sur face extérieure: 0 m2; Volume analytique des ouvertures: 0 m3; Épaisseur du Mur à la fin: 120 mm; Superficie des baies libres dans le Mur: 0 m2; Largeur: 120 mm; Altitude à étage lié/étage d'implantation: 0 mm; Décalage étage d'implantation: 0 mm; Décalage supérieur: 0 mm; Épaisseur: 120 mm; Épaisseur couche isolation: 0 mm
ArchiCADProperties - Complexité de mur: Droit; Option de géométrie: Uniforme; Emplacement de ligne de référence: Face extérieure; Angle d'inclinaison interne de mur: 90 deg; Angle d'inclinaison externe de mur: 90 deg; ID de l'élément: Mur-156; Lien et ID d'élément: Mur-156; Calque: 3D; Matériau de construction / Composite / Profil / Hachure: SAA 120; Structure Composite: SAA 120; Verrouillé: no; Type d'élément: Mur; Étage supérieur lié absolu: Non lié; Étage supérieur lié relatif: Non lié; Étage supérieur lié: Non lié; Type de structure: Composite; ID de Parent: Mur-156; Matériaux de construction (Tous): AS_EMPTY 272048125; Isolant styromousse 275581351; AS_EMPTY 272048125; Angle d'inclinaison: 90 deg; Nombre de percements: 0; Nom de Variante: Modèle principal; Nom de Jeu de Variantes: Modèle principal; Position: Non défini; Fonction structurelle: Non défini; Affichage sur filtre de rénovation: Tous les filtres appropriés; État de rénovation: Existant; État de Variante: Modèle principal; Jeu de Variantes: Modèle principal
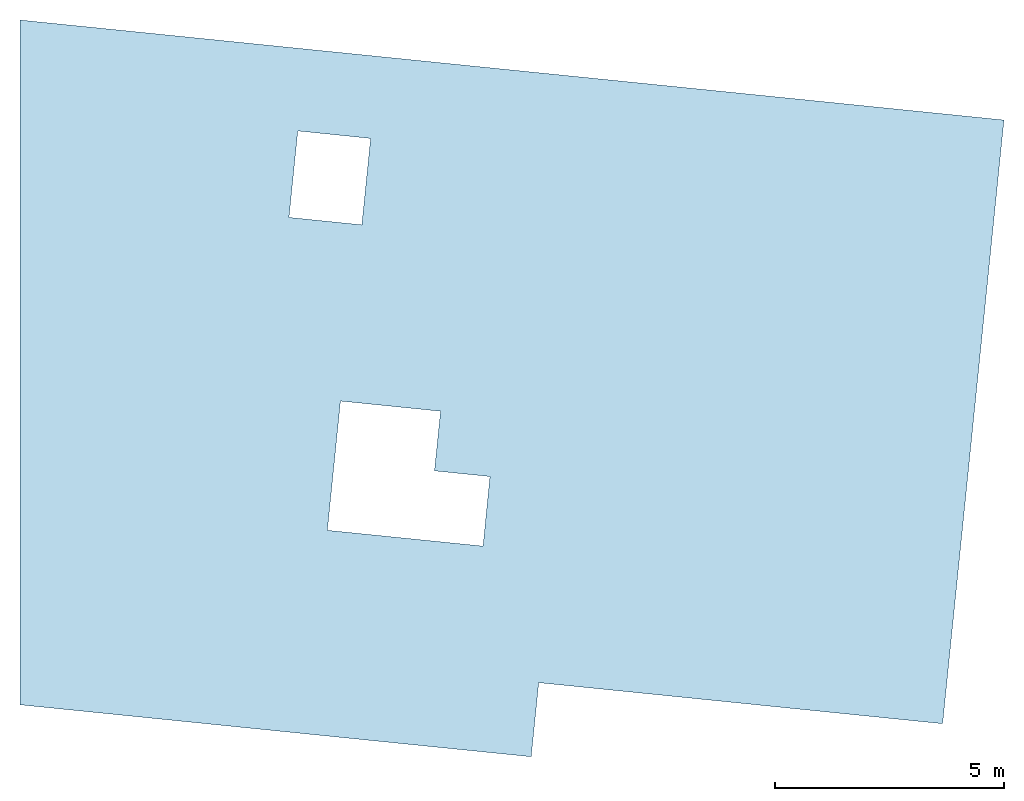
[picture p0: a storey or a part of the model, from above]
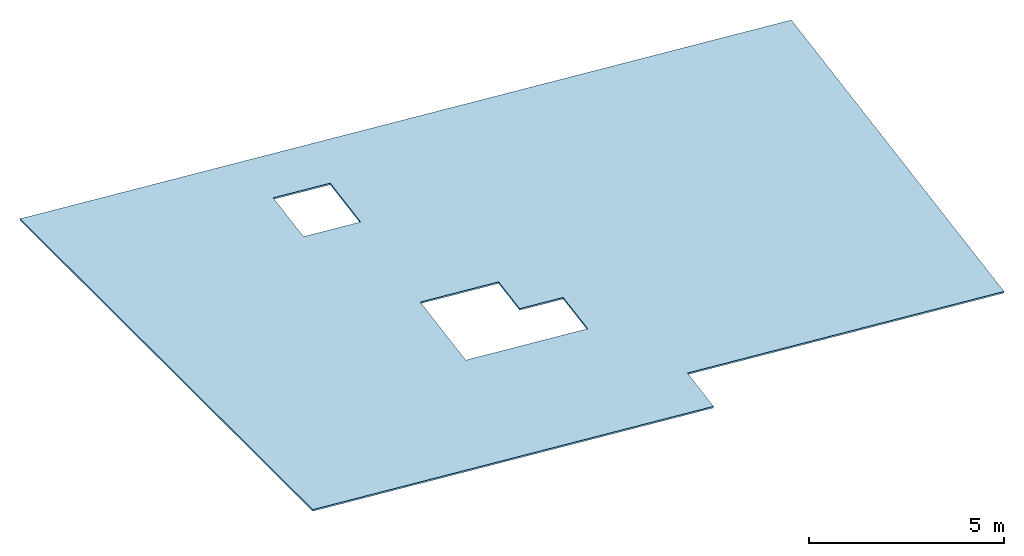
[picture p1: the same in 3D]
Properties of the parts of a building model (IFC2X3), part 31 of 44

# IfcWallStandardCase: SAA 120 120 (80)
Name | In | Hauteur maximale de la couche de Mur sur face intérieure (mm) = Hauteur maximale du Mur (mm) = Hauteur maximale de la couche de Mur sur face extérieure (mm) = Hauteur (mm) = Altitude supérieure à étage d'implantation (mm) | Hauteur minimale de la couche de Mur sur face intérieure (mm) | Hauteur minimale du Mur (mm) = Hauteur minimale de la couche de Mur sur face extérieure (mm) | Volume de composant de mur sur face intérieure (net) (m3) = Volume du composant face intérieure du mur (conditionnel) (m3) | Volume de composant de mur sur face extérieure (net) (m3) = Volume du composant face extérieure du mur (conditionnel) (m3) | Longueur moyenne du mur (mm) = Longueur du Mur au centre (mm) | Superficie de la face intérieure du mur (nette) (m2) = Superficie de la face intérieure du mur (conditionnelle) (m2) | Superficie de la face extérieure du mur (nette) (m2) = Superficie de la face extérieure du mur (conditionnelle) (m2) = Superficie en plan (m2) = Superficie inférieure (nette) (m2) | Longueur de ligne de référence (mm) | Longueur de la face intérieure du mur (conditionnelle) (mm) = Longueur de Mur sur face intérieure (mm) | Longueur de la face extérieure du mur (conditionnelle) (mm) = Longueur de Mur sur face extérieure (mm) | Superficie de la face intérieure du mur (brute) (m2) | Superficie de la face extérieure du mur (brute) (m2) | Superficie (m2) = Superficie supérieure (nette) (m2) | Volume (net) (m3) = Volume (conditionnel) (m3) = Volume (brut) (m3) | Altitude à Zéro du Projet (mm) = Altitude de Référence Niveau 1 (mm) = Altitude de Référence Niveau 2 (mm) = Altitude à niveau de la mer (mm) = Altitude inférieure à premier niveau de référence (mm) = Altitude inférieure à Zéro du projet (mm) = Altitude inférieure à niveau de la mer (mm) = Altitude inférieure à deuxième niveau de référence (mm) | Longueur 3D (mm) | Périmètre Plan (mm) | Altitude supérieure à premier niveau de référence (mm) = Altitude supérieure à Zéro du projet (mm) = Altitude supérieure à niveau de la mer (mm) = Altitude supérieure à deuxième niveau de référence (mm) | Altitude inférieure à étage d'implantation (mm) | Superficie de l'arête (nette) (m2) | Surface de face intérieure = Surface de face extérieure = Surfaces (Toutes) = Surface latérale | Nom d'étage d'implantation | Numéro d'étage d'implantation
Mur-156 | rdc | 2690 | 2690 | 2690 | 0.0275757 | 0.0329517 | 562.522 | 1.35191 | 1.67447 | 622.478 | 502.567 | 622.478 | 1.35191 | 1.67447 | 0.0675027 | 0.181582 | 3000 | 622.478 | 1414.69 | 5690 | 0 | 0.914144 | Métal-Vieux Cuivre | rdc | 3
Mur-156 | rdc | 2690 | 2690 | 2690 | 0.0171999 | 0.0225759 | 369.664 | 0.833115 | 1.15568 | 749.619 | 309.708 | 429.619 | 0.833115 | 1.15568 | 0.0443596 | 0.119327 | 3000 | 429.619 | 1028.97 | 5690 | 0 | 0.867858 | Métal-Vieux Cuivre | rdc | 3 | ArchiCADProperties - Nom de zone liée: Pl; Numéro de zone liée: 819
Mur-156 | rdc | 2690 | 2690 | 2690 | 0.0254259 | 0.0308092 | 509.917 | 1.24438 | 1.56738 | 749.954 | 449.881 | 569.954 | 1.24438 | 1.56738 | 0.0827901 | 0.168705 | 3000 | 749.954 | 1309.59 | 5690 | 0 | 0.945028 | Métal-Vieux Cuivre | rdc | 3
Mur-156 | rdc | 2690 | 2690 | 0 | 0.0281093 | 0.0387881 | 622.478 | 1.35167 | 1.80897 | 742.478 | 502.478 | 742.478 | 1.35167 | 1.80897 | 0.0746672 | 0.200855 | 3000 | 742.478 | 1584.37 | 5690 | 0 | 1.06235 | Métal-Vieux Cuivre | rdc | 3
Mur-156 | rdc | 2690 | 2690 | 2690 | 0.0254087 | 0.0307854 | 509.537 | 1.24355 | 1.56615 | 749.5 | 449.573 | 569.5 | 1.24355 | 1.56615 | 0.0827444 | 0.168582 | 3000 | 749.5 | 1308.73 | 5690 | 0 | 0.944657 | Métal-Vieux Cuivre | rdc | 3 | ArchiCADProperties - Nom de zone liée: Sejour cuisine; Numéro de zone liée: B05
Mur-156 | rdc | 2690 | 2690 | 0 | 0.0281093 | 0.0386964 | 622.478 | 1.35167 | 1.60999 | 742.478 | 502.478 | 742.478 | 1.35167 | 1.60999 | 0.0746331 | 0.200763 | 3000 | 741.584 | 1584.37 | 5690 | 0 | 1.05888 | Métal-Vieux Cuivre | rdc | 3
Mur-156 | rdc | 2690 | 2690 | 2690 | 0.0345028 | 0.0398861 | 691.347 | 1.24822 | 1.57122 | 751.384 | 631.31 | 751.384 | 1.69822 | 2.02122 | 0.0829617 | 0.223167 | 3000 | 751.384 | 1672.45 | 5690 | 0 | 0.945371 | Métal-Vieux Cuivre | rdc | 3 | ArchiCADProperties - Nom de zone liée: Sdb; Numéro de zone liée: B03
Mur-156 | rdc | 2690 | 2690 | 2690 | 0.0231383 | 0.023138 | 430.077 | 1.15692 | 1.1569 | 750.073 | 430.081 | 430.073 | 1.15692 | 1.1569 | 0.0516093 | 0.138829 | 3000 | 430.081 | 1100.15 | 5690 | 0 | 0.748819 | Métal-Vieux Cuivre | rdc | 3
Mur-156 | rdc | 2690 | 2690 | 2690 | 0.0345101 | 0.0398868 | 691.421 | 1.24862 | 1.57122 | 751.384 | 631.457 | 751.384 | 1.69862 | 2.02122 | 0.0829705 | 0.223191 | 3000 | 751.384 | 1672.49 | 5690 | 0 | 0.945109 | Métal-Vieux Cuivre | rdc | 3
Mur-156 | Etage1 | 2690 | 2690 | 2690 | 0.0254259 | 0.0308092 | 509.917 | 1.24438 | 1.56738 | 749.954 | 449.881 | 569.954 | 1.24438 | 1.56738 | 0.0827901 | 0.168705 | 5750 | 749.954 | 1309.59 | 8440 | 0 | 0.945028 | Métal-Vieux Cuivre | Etage1 | 4
Mur-156 | Etage1 | 2690 | 2690 | 2690 | 0.0254087 | 0.0307854 | 509.537 | 1.24355 | 1.56615 | 749.5 | 449.573 | 569.5 | 1.24355 | 1.56615 | 0.0827444 | 0.168582 | 5750 | 749.5 | 1308.73 | 8440 | 0 | 0.944657 | Métal-Vieux Cuivre | Etage1 | 4 | ArchiCADProperties - Nom de zone liée: Sejour cuisine; Numéro de zone liée: B16
Mur-156 | Etage1 | 2690 | 2690 | 0 | 0.0281093 | 0.0387881 | 622.478 | 1.35167 | 1.80897 | 742.478 | 502.478 | 742.478 | 1.35167 | 1.80897 | 0.0746672 | 0.200855 | 5750 | 742.478 | 1584.37 | 8440 | 0 | 1.06235 | Métal-Vieux Cuivre | Etage1 | 4
Mur-156 | Etage1 | 2690 | 2690 | 2690 | 0.0345101 | 0.0398868 | 691.421 | 1.24862 | 1.57122 | 751.384 | 631.457 | 751.384 | 1.69862 | 2.02122 | 0.0829705 | 0.223191 | 5750 | 751.384 | 1672.49 | 8440 | 0 | 0.945109 | Métal-Vieux Cuivre | Etage1 | 4
Mur-156 | Etage1 | 2690 | 2690 | 2690 | 0.0340309 | 0.0394076 | 682.515 | 1.67466 | 1.99727 | 742.478 | 622.551 | 742.478 | 1.67466 | 1.99727 | 0.0819018 | 0.220316 | 5750 | 742.478 | 1654.68 | 8440 | 0 | 0.942972 | Métal-Vieux Cuivre | Etage1 | 4
Mur-156 | Etage1 | 2690 | 2690 | 2690 | 0.0247311 | 0.0301078 | 509.656 | 1.20967 | 1.53228 | 569.619 | 449.693 | 569.619 | 1.20967 | 1.53228 | 0.0611587 | 0.164517 | 5750 | 569.619 | 1308.97 | 8440 | 0 | 0.901486 | Métal-Vieux Cuivre | Etage1 | 4 | ArchiCADProperties - Nom de zone liée: Sde; Numéro de zone liée: B11
Mur-156 | Etage1 | 2690 | 2690 | 2690 | 0.0344259 | 0.0398092 | 689.917 | 1.69438 | 2.01738 | 749.954 | 629.881 | 749.954 | 1.69438 | 2.01738 | 0.0827901 | 0.222705 | 5750 | 749.954 | 1669.59 | 8440 | 0 | 0.945028 | Métal-Vieux Cuivre | Etage1 | 4
Mur-156 | Etage1 | 2690 | 2690 | 2690 | 0.0404244 | 0.0404244 | 751.384 | 1.57122 | 1.57122 | 751.384 | 751.384 | 751.384 | 2.02122 | 2.02122 | 0.0901661 | 0.242547 | 5750 | 751.384 | 1742.77 | 8440 | 0 | 0.825932 | Métal-Vieux Cuivre | Etage1 | 4 | ArchiCADProperties - Nom de zone liée: Sde; Numéro de zone liée: B14; Zones conflictuelles: Sde
Mur-156 | Etage1 | 2690 | 2690 | 2690 | 0.0281093 | 0.0388693 | 622.478 | 1.35167 | 1.99727 | 742.478 | 502.478 | 742.478 | 1.35167 | 1.99727 | 0.0746973 | 0.200936 | 5750 | 742.478 | 1584.37 | 8440 | 0 | 1.06241 | Métal-Vieux Cuivre | Etage1 | 4
Mur-156 | Etage 2 | 2690 | 2690 | 2690 | 0.0281089 | 0.0388693 | 622.474 | 1.35164 | 1.99727 | 742.478 | 502.47 | 742.478 | 1.35164 | 1.99727 | 0.0746969 | 0.200935 | 8500 | 742.478 | 1584.36 | 11190 | 0 | 1.06243 | Métal-Vieux Cuivre | Etage 2 | 5
Mur-156 | Etage 2 | 2690 | 2690 | 2690 | 0.0247311 | 0.0301078 | 509.656 | 1.20967 | 1.53228 | 569.619 | 449.693 | 569.619 | 1.20967 | 1.53228 | 0.0611587 | 0.164517 | 8500 | 569.619 | 1308.97 | 11190 | 0 | 0.901486 | Métal-Vieux Cuivre | Etage 2 | 5 | ArchiCADProperties - Nom de zone liée: Sde; Numéro de zone liée: B21
Mur-156 | Etage 2 | 2690 | 2690 | 0 | 0.0281093 | 0.0387881 | 622.478 | 1.35167 | 1.80897 | 742.478 | 502.478 | 742.478 | 1.35167 | 1.80897 | 0.0746672 | 0.200855 | 8500 | 742.478 | 1584.37 | 11190 | 0 | 1.06235 | Métal-Vieux Cuivre | Etage 2 | 5
Mur-156 | Etage 2 | 2690 | 2690 | 2690 | 0.0247419 | 0.0301252 | 509.917 | 1.21018 | 1.53318 | 749.954 | 449.881 | 569.954 | 1.21018 | 1.53318 | 0.0611901 | 0.164601 | 8500 | 569.954 | 1309.59 | 11190 | 0 | 0.901828 | Métal-Vieux Cuivre | Etage 2 | 5
Mur-156 | Etage 2 | 2690 | 2690 | 2690 | 0.0247247 | 0.0301014 | 509.537 | 1.20935 | 1.53195 | 749.5 | 449.573 | 569.5 | 1.20935 | 1.53195 | 0.0611444 | 0.164478 | 8500 | 569.5 | 1308.73 | 11190 | 0 | 0.901457 | Métal-Vieux Cuivre | Etage 2 | 5 | ArchiCADProperties - Nom de zone liée: Sejour cuisine; Numéro de zone liée: B26
Mur-156 | Etage 2 | 2690 | 2690 | 2690 | 0.0281093 | 0.0388693 | 622.478 | 1.35167 | 1.99727 | 742.478 | 502.478 | 742.478 | 1.35167 | 1.99727 | 0.0746973 | 0.200936 | 8500 | 742.478 | 1584.37 | 11190 | 0 | 1.06241 | Métal-Vieux Cuivre | Etage 2 | 5
Mur-156 | Etage 2 | 2690 | 2690 | 2690 | 0.0248085 | 0.0301918 | 511.155 | 1.21351 | 1.53651 | 751.192 | 451.119 | 571.192 | 1.21351 | 1.53651 | 0.0613386 | 0.165001 | 8500 | 571.192 | 1312.07 | 11190 | 0 | 0.902125 | Métal-Vieux Cuivre | Etage 2 | 5
Mur-156 | Etage 2 | 2690 | 2690 | 2690 | 0.0247913 | 0.030168 | 510.774 | 1.21268 | 1.53528 | 750.738 | 450.811 | 570.738 | 1.21268 | 1.53528 | 0.0612929 | 0.164878 | 8500 | 570.738 | 1311.2 | 11190 | 0 | 0.901754 | Métal-Vieux Cuivre | Etage 2 | 5
Mur-156 | Etage 2 | 2690 | 2690 | 2690 | 0.0247479 | 0.0301316 | 510.033 | 1.21048 | 1.5335 | 570.073 | 449.992 | 570.073 | 1.21048 | 1.5335 | 0.0612039 | 0.164639 | 8500 | 570.073 | 1309.83 | 11190 | 0 | 0.901871 | Métal-Vieux Cuivre | Etage 2 | 5
Mur-156 | Etage 3 | 2690 | 2690 | 2690 | 0.0247247 | 0.0301014 | 509.537 | 1.20935 | 1.53195 | 749.5 | 449.573 | 569.5 | 1.20935 | 1.53195 | 0.0611444 | 0.164478 | 11550 | 569.5 | 1308.73 | 14240 | 0 | 0.901457 | Métal-Vieux Cuivre | Etage 3 | 6 | ArchiCADProperties - Nom de zone liée: Sejour cuisine/pl; Numéro de zone liée: B35
Mur-156 | Etage 3 | 2690 | 2690 | 2690 | 0.0247311 | 0.0301078 | 509.656 | 1.20967 | 1.53228 | 569.619 | 449.693 | 569.619 | 1.20967 | 1.53228 | 0.0611587 | 0.164517 | 11550 | 569.619 | 1308.97 | 14240 | 0 | 0.901486 | Métal-Vieux Cuivre | Etage 3 | 6
Mur-156 | Etage 3 | 2690 | 2690 | 2690 | 0.0281089 | 0.0388693 | 622.474 | 1.35164 | 1.99727 | 742.478 | 502.47 | 742.478 | 1.35164 | 1.99727 | 0.0746969 | 0.200935 | 11550 | 742.478 | 1584.36 | 14240 | 0 | 1.06243 | Métal-Vieux Cuivre | Etage 3 | 6
Mur-156 | Etage 3 | 2690 | 2690 | 2690 | 0.0281057 | 0.038869 | 622.441 | 1.35147 | 1.99727 | 622.478 | 502.404 | 742.478 | 1.35147 | 1.99727 | 0.0746929 | 0.200924 | 11550 | 742.478 | 1584.35 | 14240 | 0 | 1.06254 | Métal-Vieux Cuivre | Etage 3 | 6
Mur-156 | Etage 3 | 2690 | 2690 | 0 | 0.0281093 | 0.0387881 | 622.478 | 1.35167 | 1.80897 | 742.478 | 502.478 | 742.478 | 1.35167 | 1.80897 | 0.0746672 | 0.200855 | 11550 | 742.478 | 1584.37 | 14240 | 0 | 1.06235 | Métal-Vieux Cuivre | Etage 3 | 6
Mur-156 | Etage 3 | 2690 | 2690 | 2690 | 0.034489 | 0.0398723 | 691.089 | 1.21333 | 1.53633 | 751.126 | 631.053 | 751.126 | 1.69753 | 2.02053 | 0.0829307 | 0.223084 | 11550 | 751.126 | 1671.94 | 14240 | 0 | 0.945309 | Métal-Vieux Cuivre | Etage 3 | 6
Mur-156 | Etage 3 | 2690 | 2690 | 2690 | 0.0247419 | 0.0301252 | 509.917 | 1.21018 | 1.53318 | 749.954 | 449.881 | 569.954 | 1.21018 | 1.53318 | 0.0611901 | 0.164601 | 11550 | 569.954 | 1309.59 | 14240 | 0 | 0.901828 | Métal-Vieux Cuivre | Etage 3 | 6
Mur-156 | Etage 3 | 2690 | 2690 | 2690 | 0.0247479 | 0.0301316 | 510.033 | 1.21048 | 1.5335 | 570.073 | 449.992 | 570.073 | 1.21048 | 1.5335 | 0.0612039 | 0.164639 | 11550 | 570.073 | 1309.83 | 14240 | 0 | 0.901871 | Métal-Vieux Cuivre | Etage 3 | 6
Mur-156 | Etage 3 | 2690 | 2690 | 2690 | 0.030114 | 0.024734 | 509.74 | 1.5326 | 1.2098 | 569.74 | 569.74 | 449.74 | 1.5326 | 1.2098 | 0.0611688 | 0.164544 | 11550 | 569.74 | 1309.19 | 14240 | 0 | 0.901646 | Métal-Vieux Cuivre | Etage 3 | 6
Mur-156 | etage 4 | 2700 | 2700 | 2700 | 0.011134 | 0.021934 | 306.185 | 0.502701 | 1.1507 | 426.185 | 186.185 | 426.185 | 0.502701 | 1.1507 | 0.0367423 | 0.0992041 | 14600 | 426.185 | 951.782 | 17300 | 0 | 0.989895 | Peinture-01 | etage 4 | 7
Mur-156 | etage 4 | 2700 | 2700 | 2700 | 0.0439244 | 0.0493244 | 863.414 | 2.16922 | 2.49322 | 923.414 | 803.414 | 923.414 | 2.16922 | 2.49322 | 0.10361 | 0.279746 | 14600 | 923.414 | 2016.53 | 17300 | 0 | 0.989425 | Peinture-01 | etage 4 | 7
Mur-156 | etage 4 | 2700 | 2700 | 2700 | 0.0625514 | 0.0679599 | 1208.44 | 2.13253 | 2.50704 | 1268.53 | 1148.34 | 1268.53 | 3.10053 | 3.42504 | 0.145013 | 0.391534 | 14600 | 1268.53 | 2706.71 | 17300 | 0 | 1.07259 | Peinture-01 | etage 4 | 7
Mur-156 | etage 4 | 2700 | 2700 | 2700 | 0.0439078 | 0.0493078 | 863.108 | 2.16839 | 2.49239 | 923.108 | 803.108 | 923.108 | 2.16839 | 2.49239 | 0.103573 | 0.279647 | 14600 | 923.108 | 2015.92 | 17300 | 0 | 0.989351 | Peinture-01 | etage 4 | 7
Mur-156 | etage 4 | 3050 | 3050 | 3050 | 0.0497352 | 0.0558317 | 865.302 | 2.40628 | 2.82207 | 1265.27 | 805.337 | 925.268 | 2.45628 | 2.82207 | 0.103836 | 0.316701 | 14600 | 925.339 | 2020.31 | 17650 | 0 | 1.09128 | Peinture-01 | etage 4 | 7
Mur-156 | etage 4 | 2700 | 2700 | 2700 | 0.0157073 | 0.0199739 | 477.789 | 0.76403 | 1.02003 | 717.789 | 417.789 | 537.789 | 0.76403 | 1.02003 | 0.0585347 | 0.107044 | 14600 | 717.789 | 1245.28 | 17300 | 0 | 0.988186 | Peinture-01 | etage 4 | 7
Mur-156 | etage 4 | 3050 | 3050 | 3050 | 0.0278435 | 0.0393435 | 543.829 | 1.33468 | 2.02468 | 663.829 | 423.829 | 663.829 | 1.33468 | 2.02468 | 0.0724594 | 0.201561 | 14600 | 663.829 | 1427.07 | 17650 | 0 | 1.16273 | Peinture-01 | etage 4 | 7
Mur-156 | etage 4 | 3050 | 3050 | 3050 | 0.028818 | 0.034918 | 522.426 | 1.4104 | 1.7764 | 582.426 | 462.426 | 582.426 | 1.4104 | 1.7764 | 0.0626912 | 0.191208 | 14600 | 582.426 | 1334.56 | 17650 | 0 | 1.00898 | Peinture-01 | etage 4 | 7
Mur-156 | etage 4 | 3050 | 3050 | 3050 | 0.0224863 | 0.0254697 | 522.426 | 1.1094 | 1.2884 | 762.426 | 462.426 | 582.426 | 1.1094 | 1.2884 | 0.0638912 | 0.143868 | 14600 | 762.426 | 1334.56 | 17650 | 0 | 1.18449 | Peinture-01 | etage 4 | 7
Mur-156 | etage 4 | 3050 | 3050 | 3050 | 0.0294252 | 0.0416252 | 582.381 | 1.41026 | 2.14226 | 702.381 | 462.381 | 702.381 | 1.41026 | 2.14226 | 0.0698857 | 0.213151 | 14600 | 702.381 | 1504.17 | 17650 | 0 | 1.17498 | Peinture-01 | etage 4 | 7
Mur-156 | etage 4 | 3050 | 3050 | 3050 | 0.041826 | 0.047926 | 735.673 | 2.0608 | 2.4268 | 1135.67 | 675.673 | 795.673 | 2.0608 | 2.4268 | 0.0882807 | 0.269256 | 14600 | 795.673 | 1761.05 | 17650 | -1.77636e-12 | 1.06016 | Peinture-01 | etage 4 | 7
Mur-156 | etage 4 | 3310.2 | 3310.2 | 3310.2 | 0.0631907 | 0.0746994 | 1025.61 | 3.10199 | 3.79251 | 1145.7 | 905.515 | 1145.71 | 3.10199 | 3.79251 | 0.137484 | 0.41367 | 14600 | 1145.71 | 2390.77 | 17910.2 | 0 | 1.35559 | Peinture-01 | etage 4 | 7
Mur-156 | etage 4 | 3050 | 3050 | 3050 | 0.0163351 | 0.0224351 | 317.789 | 0.786256 | 1.15226 | 717.789 | 257.789 | 377.789 | 0.786256 | 1.15226 | 0.0381347 | 0.116311 | 14600 | 377.789 | 925.284 | 17650 | 0 | 0.959872 | Peinture-01 | etage 4 | 7
Mur-156 | etage 4 | 2690 | 2690 | 0 | 0.0281093 | 0.0387677 | 622.478 | 1.35167 | 1.62067 | 742.478 | 502.478 | 742.478 | 1.35167 | 1.62067 | 0.0746596 | 0.200834 | 14600 | 742.478 | 1584.37 | 17290 | 0 | 1.06234 | Métal-Vieux Cuivre | etage 4 | 7
Mur-156 | etage 4 | 2690 | 2690 | 2690 | 0.0247419 | 0.0301252 | 509.917 | 1.21018 | 1.53318 | 749.954 | 449.881 | 569.954 | 1.21018 | 1.53318 | 0.0611901 | 0.164601 | 14600 | 569.954 | 1309.59 | 17290 | 0 | 0.901828 | Métal-Vieux Cuivre | etage 4 | 7
Mur-156 | etage 4 | 2690 | 2690 | 2690 | 0.0247479 | 0.0301316 | 510.033 | 1.21048 | 1.5335 | 570.073 | 449.992 | 570.073 | 1.21048 | 1.5335 | 0.0612039 | 0.164639 | 14600 | 570.073 | 1309.83 | 17290 | 0 | 0.901871 | Métal-Vieux Cuivre | etage 4 | 7
Mur-156 | etage 4 | 3050 | 3050 | 3050 | 0.0291025 | 0.0352025 | 527.09 | 1.42462 | 1.79062 | 927.09 | 467.09 | 587.09 | 1.42462 | 1.79062 | 0.0632508 | 0.192915 | 14600 | 587.09 | 1343.89 | 17650 | 0 | 1.0101 | Peinture-01 | etage 4 | 7
Mur-156 | etage 4 | 2690 | 2690 | 2690 | 0.0247311 | 0.0301078 | 509.656 | 1.20967 | 1.53228 | 569.619 | 449.693 | 569.619 | 1.20967 | 1.53228 | 0.0611587 | 0.164517 | 14600 | 569.619 | 1308.97 | 17290 | 0 | 0.901486 | Métal-Vieux Cuivre | etage 4 | 7
Mur-156 | etage 4 | 2690 | 2690 | 2690 | 0.0247247 | 0.0301014 | 509.537 | 1.20935 | 1.53195 | 749.5 | 449.573 | 569.5 | 1.20935 | 1.53195 | 0.0611444 | 0.164478 | 14600 | 569.5 | 1308.73 | 17290 | 0 | 0.901457 | Métal-Vieux Cuivre | etage 4 | 7 | ArchiCADProperties - Nom de zone liée: Ch 3/sde; Numéro de zone liée: B44
Mur-156 | etage 4 | 2690 | 2690 | 2690 | 0.0281089 | 0.0388693 | 622.474 | 1.35164 | 1.99727 | 742.478 | 502.47 | 742.478 | 1.35164 | 1.99727 | 0.0746969 | 0.200935 | 14600 | 742.478 | 1584.36 | 17290 | 0 | 1.06243 | Métal-Vieux Cuivre | etage 4 | 7
Mur-156 | Etage 5 | 300 | 300 | 300 | 0.00123308 | 0.00243308 | 305.514 | 0.0556541 | 0.127654 | 425.514 | 185.514 | 425.514 | 0.0556541 | 0.127654 | 0.0366617 | 0.0109985 | 17650 | 425.514 | 950.439 | 17950 | 0 | 0.175147 | Peinture-01 | Etage 5 | 8
Mur-156 | Etage 5 | 300 | 300 | 300 | 0.00693154 | 0.00753165 | 1205.27 | 0.241577 | 0.277583 | 1265.28 | 1145.26 | 1265.28 | 0.343577 | 0.379583 | 0.144632 | 0.0433896 | 17650 | 1265.28 | 2700.25 | 17950 | 0 | 0.37618 | Peinture-01 | Etage 5 | 8
Mur-156 | Etage 5 | 2690 | 2690 | 2690 | 0.0193511 | 0.0247278 | 409.656 | 0.940673 | 1.26328 | 749.619 | 349.693 | 469.619 | 0.940673 | 1.26328 | 0.0491587 | 0.132237 | 17650 | 469.619 | 1108.97 | 20340 | 0 | 0.877486 | Métal-Vieux Cuivre | Etage 5 | 8 | ArchiCADProperties - Nom de zone liée: Wc; Numéro de zone liée: B51
Mur-156 | Etage 5 | 300 | 300 | 300 | 0.0028637 | 0.00346265 | 527.196 | 0.14019 | 0.176127 | 927.091 | 467.301 | 587.091 | 0.14019 | 0.176127 | 0.0632635 | 0.0189791 | 17650 | 587.301 | 1344.1 | 17950 | 0 | 0.213439 | Peinture-01 | Etage 5 | 8
2 x Mur-156 | Etage 5 | 300 | 300 | 300 | 0.00160673 | 0.00220673 | 317.789 | 0.0773367 | 0.113337 | 717.789 | 257.789 | 377.789 | 0.0773367 | 0.113337 | 0.0381347 | 0.0114404 | 17650 | 377.789 | 925.283 | 17950 | 0 | 0.163181 | Peinture-01 | Etage 5 | 8
Mur-156 | Etage 5 | 300 | 300 | 300 | 0.00411289 | 0.00471394 | 735.569 | 0.202639 | 0.238702 | 1135.67 | 675.464 | 795.674 | 0.202639 | 0.238702 | 0.0882683 | 0.0264805 | 17650 | 795.674 | 1760.84 | 17950 | 0 | 0.263448 | Peinture-01 | Etage 5 | 8
Mur-156 | Etage 5 | 300 | 300 | 300 | 0.00187456 | 0.00247456 | 362.426 | 0.0907279 | 0.126728 | 762.426 | 302.426 | 422.426 | 0.0907279 | 0.126728 | 0.0434912 | 0.0130473 | 17650 | 422.426 | 1014.56 | 17950 | 0 | 0.173894 | Peinture-01 | Etage 5 | 8
Mur-156 | Etage 5 | 810 | 810 | 810 | 0.00893657 | 0.0111566 | 582.381 | 0.435728 | 0.568928 | 702.381 | 462.381 | 702.381 | 0.435728 | 0.568928 | 0.0770857 | 0.0602794 | 17650 | 702.381 | 1504.17 | 18460 | 0 | 0.403745 | Peinture-01 | Etage 5 | 8
Mur-156 | Etage 5 | 810 | 810 | 810 | 0.00506131 | 0.00668131 | 362.426 | 0.244965 | 0.342165 | 762.426 | 302.426 | 422.426 | 0.244965 | 0.342165 | 0.0434912 | 0.0352278 | 17650 | 422.426 | 1014.56 | 18460 | 0 | 0.321644 | Peinture-01 | Etage 5 | 8
Mur-156 | Etage 5 | 300 | 300 | 300 | 0.0048777 | 0.00547856 | 863.022 | 0.24088 | 0.276933 | 923.108 | 802.935 | 923.108 | 0.24088 | 0.276933 | 0.103563 | 0.0310688 | 17650 | 923.108 | 2015.87 | 17950 | 0 | 0.294074 | Peinture-01 | Etage 5 | 8
Mur-156 | Etage 5 | 300 | 300 | 300 | 0.0048796 | 0.00547874 | 863.195 | 0.240985 | 0.276933 | 923.108 | 803.282 | 923.108 | 0.240985 | 0.276933 | 0.103583 | 0.031075 | 17650 | 923.108 | 2015.97 | 17950 | 0 | 0.294042 | Peinture-01 | Etage 5 | 8
Mur-156 | Etage 5 | 300 | 300 | 300 | 0.00555385 | 0.0067545 | 1025.7 | 0.271689 | 0.343728 | 1145.76 | 905.632 | 1145.76 | 0.271689 | 0.343728 | 0.123084 | 0.0369251 | 17650 | 1145.76 | 2390.9 | 17950 | 0 | 0.348018 | Peinture-01 | Etage 5 | 8
Mur-156 | Etage 5 | 300 | 300 | 300 | 0.00266297 | 0.00386297 | 543.829 | 0.127149 | 0.199149 | 663.829 | 423.829 | 663.829 | 0.127149 | 0.199149 | 0.0652594 | 0.0195778 | 17650 | 663.829 | 1427.07 | 17950 | 0 | 0.232342 | Peinture-01 | Etage 5 | 8
Mur-156 | Etage 5 | 2690 | 2690 | 0 | 0.0281088 | 0.0388693 | 622.473 | 1.35164 | 1.80881 | 742.478 | 502.468 | 742.478 | 1.35164 | 1.99711 | 0.0746967 | 0.200934 | 17650 | 742.419 | 1584.36 | 20340 | 0 | 1.0622 | Métal-Vieux Cuivre | Etage 5 | 8 | ArchiCADProperties - Nom de zone liée: Wc; Numéro de zone liée: B51
Mur-156 | Etage 5 | 300 | 300 | 300 | 0.00489496 | 0.00549536 | 865.86 | 0.241746 | 0.27777 | 1265.9 | 805.82 | 925.901 | 0.241746 | 0.27777 | 0.103903 | 0.031171 | 17650 | 925.929 | 2021.5 | 17950 | 0 | 0.294741 | Peinture-01 | Etage 5 | 8
Mur-156 | Etage 5 | 2690 | 2690 | 2690 | 0.0247247 | 0.0301014 | 509.537 | 1.20935 | 1.53195 | 749.5 | 449.573 | 569.5 | 1.20935 | 1.53195 | 0.0611444 | 0.164478 | 17650 | 569.5 | 1308.73 | 20340 | 0 | 0.901457 | Métal-Vieux Cuivre | Etage 5 | 8 | ArchiCADProperties - Nom de zone liée: Ch 3/pl; Numéro de zone liée: B52
Mur-156 | Etage 5 | 2690 | 2690 | 0 | 0.0281093 | 0.0387881 | 622.478 | 1.35167 | 1.80897 | 742.478 | 502.478 | 742.478 | 1.35167 | 1.80897 | 0.0746672 | 0.200855 | 17650 | 742.478 | 1584.37 | 20340 | 0 | 1.06235 | Métal-Vieux Cuivre | Etage 5 | 8
Mur-156 | Etage 5 | 2690 | 2690 | 2690 | 0.0247419 | 0.0301252 | 509.917 | 1.21018 | 1.53318 | 749.954 | 449.881 | 569.954 | 1.21018 | 1.53318 | 0.0611901 | 0.164601 | 17650 | 569.954 | 1309.59 | 20340 | 0 | 0.901828 | Métal-Vieux Cuivre | Etage 5 | 8
Mur-156 | Etage 5 | 2690 | 2690 | 2690 | 0.0344318 | 0.0398156 | 690.032 | 1.69467 | 2.0177 | 750.073 | 629.99 | 750.073 | 1.69467 | 2.0177 | 0.0828038 | 0.222742 | 17650 | 750.073 | 1669.83 | 20340 | 0 | 0.945075 | Métal-Vieux Cuivre | Etage 5 | 8 | ArchiCADProperties - Zones conflictuelles: Wc
Mur-156 | toiture | 1100 | 0 | 0 | 0.0112184 | 0.0134184 | 682.478 | 0.549919 | 0.681919 | 742.478 | 622.478 | 742.478 | 0.549919 | 0.681919 | 0.0671912 | 0.0739103 | 20350 | 619.927 | 1654.66 | 21450 | 0 | 0.321059 | Peinture-01 | toiture | 9
Mur-156 | toiture | 1100 | 1100 | 1100 | 0.0109984 | 0.0109984 | 499.927 | 0.549919 | 0.549919 | 619.927 | 499.927 | 499.927 | 0.549919 | 0.549919 | 0.0599912 | 0.0659903 | 20350 | 500 | 1239.85 | 21450 | 0 | 0.383982 | Peinture-01 | toiture | 9
Mur-156 | toiture | 1100 | 0 | 0 | 0.0112184 | 0.0134184 | 682.441 | 0.549919 | 0.681919 | 742.478 | 622.404 | 742.478 | 0.549919 | 0.681919 | 0.0671912 | 0.0739103 | 20350 | 620 | 1654.64 | 21450 | 0 | 0.321116 | Peinture-01 | toiture | 9
Mur-156 | toiture | 1100 | 1100 | 1100 | 0.0217953 | 0.0261967 | 1090.73 | 0.935759 | 1.33184 | 1210.76 | 970.69 | 1210.76 | 1.06776 | 1.33184 | 0.130887 | 0.143976 | 20350 | 1210.76 | 2520.92 | 21450 | 0 | 0.635184 | Peinture-01 | toiture | 9

# IfcWallStandardCase: SAD 180 blanc 180, Mur-142
In: Etage 3
Classification: Mur (Classification ARCHICAD); Material: AS_EMPTY 272048125 50 mm, Isolant styromousse 275581351 80 mm, AS_EMPTY 272048125 50 mm
ArchiCADProperties - Complexité de mur: Droit; Option de géométrie: Uniforme; Emplacement de ligne de référence: Face extérieure; Surface de face intérieure: Tablette bois; Surface de face extérieure: Tablette bois; Angle d'inclinaison interne de mur: 90 deg; Angle d'inclinaison externe de mur: 90 deg; ID de l'élément: Mur-142; Lien et ID d'élément: Mur-142; Calque: Interieurs logements; Matériau de construction / Composite / Profil / Hachure: SAD 180 blanc; Structure Composite: SAD 180 blanc; Nom de zone liée: Dressing; Numéro de zone liée: A34; Verrouillé: no; Nom d'étage d'implantation: Etage 3; Numéro d'étage d'implantation: 6; Type d'élément: Mur; Étage supérieur lié absolu: Non lié; Étage supérieur lié relatif: Non lié; Étage supérieur lié: Non lié; Type de structure: Composite; ID de Parent: Mur-142; Matériaux de construction (Tous): AS_EMPTY 272048125; Isolant styromousse 275581351; AS_EMPTY 272048125; Surfaces (Toutes): Tablette bois; Angle d'inclinaison: 90 deg; Nombre de percements: 0; Surface latérale: Tablette bois; Nom de Variante: Modèle principal; Nom de Jeu de Variantes: Modèle principal; Position: Non défini; Fonction structurelle: Non défini; Affichage sur filtre de rénovation: Tous les filtres appropriés; État de rénovation: Existant; État de Variante: Modèle principal; Jeu de Variantes: Modèle principal
AC_Pset_RenovationAndPhasing - Renovation Status: Existing
ArchiCADQuantities - Nombre de Portes: 0; Nombre de trous (Nombre d'ouvertures vides): 0; Nombre de Fenêtres: 0; Nombre de Poteaux: 0; Volume des poteaux: 0 m3; Hauteur maximale de la couche de Mur sur face intérieure: 3000 mm; Hauteur minimale de la couche de Mur sur face intérieure: 3000 mm; Hauteur maximale du Mur: 3000 mm; Hauteur minimale du Mur: 3000 mm; Hauteur maximale de la couche de Mur sur face extérieure: 3000 mm; Hauteur minimale de la couche de Mur sur face extérieure: 3000 mm; Épaisseur couche d'air: 0 mm; Superficie des portes: 0 m2; Largeur totale des Portes: 0 mm; Épaisseur de composant de mur sur face intérieure: 50 mm; Épaisseur de composant de mur sur face extérieure: 50 mm; Superficie des fenêtres: 0 m2; Largeur totale des Fenêtres: 0 mm; Volume de composant de mur sur face intérieure (net): 0.204 m3; Volume de composant de mur sur face extérieure (net): 0.204 m3; Superficie analytique des ouvertures sur face intérieure: 0 m2; Superficie analytique des ouvertures sur face extérieure: 0 m2; Longueur moyenne du mur: 1360 mm; Superficie de la face intérieure du mur (nette): 4.08 m2; Superficie de la face extérieure du mur (nette): 4.08 m2; Volume analytique des ouvertures: 0 m3; Longueur de ligne de référence: 1700 mm; Longueur de la face intérieure du mur (conditionnelle): 1360 mm; Superficie de la face intérieure du mur (conditionnelle): 4.08 m2; Longueur de la face extérieure du mur (conditionnelle): 1360 mm; Superficie de la face extérieure du mur (conditionnelle): 4.08 m2; Volume du composant face intérieure du mur (conditionnel): 0.204 m3; Volume du composant face extérieure du mur (conditionnel): 0.204 m3; Superficie de la face intérieure du mur (brute): 4.08 m2; Superficie de la face extérieure du mur (brute): 4.08 m2; Épaisseur du Mur à la fin: 180 mm; Longueur du Mur au centre: 1360 mm; Longueur de Mur sur face intérieure: 1360 mm; Longueur de Mur sur face extérieure: 1360 mm; Superficie des baies libres dans le Mur: 0 m2; Superficie: 0.2448 m2; Hauteur: 3000 mm; Volume (net): 0.7344 m3; Largeur: 180 mm; Altitude à Zéro du Projet: 11550 mm; Altitude de Référence Niveau 1: 11550 mm; Altitude de Référence Niveau 2: 11550 mm; Altitude à niveau de la mer: 11550 mm; Altitude à étage lié/étage d'implantation: 0 mm; Décalage étage d'implantation: 0 mm; Décalage supérieur: 0 mm; Superficie en plan: 4.08 m2; Longueur 3D: 1360 mm; Épaisseur: 180 mm; Volume (conditionnel): 0.7344 m3; Volume (brut): 0.7344 m3; Épaisseur couche isolation: 0 mm; Périmètre Plan: 3080 mm; Altitude supérieure à premier niveau de référence: 14550 mm; Altitude supérieure à étage d'implantation: 3000 mm; Altitude supérieure à Zéro du projet: 14550 mm; Altitude supérieure à niveau de la mer: 14550 mm; Altitude supérieure à deuxième niveau de référence: 14550 mm; Altitude inférieure à premier niveau de référence: 11550 mm; Altitude inférieure à étage d'implantation: 0 mm; Altitude inférieure à Zéro du projet: 11550 mm; Altitude inférieure à niveau de la mer: 11550 mm; Altitude inférieure à deuxième niveau de référence: 11550 mm; Superficie supérieure (nette): 0.2448 m2; Superficie de l'arête (nette): 1.5696 m2; Superficie inférieure (nette): 4.08 m2

# IfcWallStandardCase: acrotère 18 180, Mur-133
In: sousol
Classification: Mur (Classification ARCHICAD); Material: Empty Fill 292498448 180 mm
ArchiCADProperties - Complexité de mur: Droit; Option de géométrie: Uniforme; Emplacement de ligne de référence: Face extérieure; Surface de face intérieure: Plâtre Lisse; Surface de face extérieure: Plâtre Lisse; Angle d'inclinaison interne de mur: 90 deg; Angle d'inclinaison externe de mur: 90 deg; ID de l'élément: Mur-133; Lien et ID d'élément: Mur-133; Calque: 3D; Matériau de construction / Composite / Profil / Hachure: acrotère 18; Structure Composite: acrotère 18; Verrouillé: no; Nom d'étage d'implantation: sousol; Numéro d'étage d'implantation: 2; Type d'élément: Mur; Étage supérieur lié absolu: Non lié; Étage supérieur lié relatif: Non lié; Étage supérieur lié: Non lié; Type de structure: Composite; ID de Parent: Mur-133; Matériaux de construction (Tous): Empty Fill 292498448; Surfaces (Toutes): Plâtre Lisse; Angle d'inclinaison: 90 deg; Nombre de percements: 0; Surface latérale: Plâtre Lisse; Nom de Variante: Modèle principal; Nom de Jeu de Variantes: Modèle principal; Position: Non défini; Fonction structurelle: Non défini; Affichage sur filtre de rénovation: Tous les filtres appropriés; État de rénovation: Existant; État de Variante: Modèle principal; Jeu de Variantes: Modèle principal
AC_Pset_RenovationAndPhasing - Renovation Status: Existing
ArchiCADQuantities - Nombre de Portes: 0; Nombre de trous (Nombre d'ouvertures vides): 0; Nombre de Fenêtres: 0; Nombre de Poteaux: 0; Volume des poteaux: 0 m3; Hauteur maximale de la couche de Mur sur face intérieure: 1000 mm; Hauteur minimale de la couche de Mur sur face intérieure: 1000 mm; Hauteur maximale du Mur: 1000 mm; Hauteur minimale du Mur: 1000 mm; Hauteur maximale de la couche de Mur sur face extérieure: 1000 mm; Hauteur minimale de la couche de Mur sur face extérieure: 1000 mm; Épaisseur couche d'air: 0 mm; Superficie des portes: 0 m2; Largeur totale des Portes: 0 mm; Épaisseur de composant de mur sur face intérieure: 180 mm; Épaisseur de composant de mur sur face extérieure: 180 mm; Superficie des fenêtres: 0 m2; Largeur totale des Fenêtres: 0 mm; Volume de composant de mur sur face intérieure (net): 1.19183 m3; Volume de composant de mur sur face extérieure (net): 1.19183 m3; Superficie analytique des ouvertures sur face intérieure: 0 m2; Superficie analytique des ouvertures sur face extérieure: 0 m2; Longueur moyenne du mur: 6621.25 mm; Superficie de la face intérieure du mur (nette): 6.62125 m2; Superficie de la face extérieure du mur (nette): 6.62125 m2; Volume analytique des ouvertures: 0 m3; Longueur de ligne de référence: 6621.25 mm; Longueur de la face intérieure du mur (conditionnelle): 6621.25 mm; Superficie de la face intérieure du mur (conditionnelle): 6.62125 m2; Longueur de la face extérieure du mur (conditionnelle): 6621.25 mm; Superficie de la face extérieure du mur (conditionnelle): 6.62125 m2; Volume du composant face intérieure du mur (conditionnel): 1.19183 m3; Volume du composant face extérieure du mur (conditionnel): 1.19183 m3; Superficie de la face intérieure du mur (brute): 6.62125 m2; Superficie de la face extérieure du mur (brute): 6.62125 m2; Épaisseur du Mur à la fin: 180 mm; Longueur du Mur au centre: 6621.25 mm; Longueur de Mur sur face intérieure: 6621.25 mm; Longueur de Mur sur face extérieure: 6621.25 mm; Superficie des baies libres dans le Mur: 0 m2; Superficie: 1.19183 m2; Hauteur: 1000 mm; Volume (net): 1.19183 m3; Largeur: 180 mm; Altitude à Zéro du Projet: 4.18415e-12 mm; Altitude de Référence Niveau 1: 4.18415e-12 mm; Altitude de Référence Niveau 2: 4.18415e-12 mm; Altitude à niveau de la mer: 4.18415e-12 mm; Altitude à étage lié/étage d'implantation: 4.18415e-12 mm; Décalage étage d'implantation: 4.18415e-12 mm; Décalage supérieur: 0 mm; Superficie en plan: 6.62125 m2; Longueur 3D: 6621.25 mm; Épaisseur: 180 mm; Volume (conditionnel): 1.19183 m3; Volume (brut): 1.19183 m3; Épaisseur couche isolation: 0 mm; Périmètre Plan: 13602.5 mm; Altitude supérieure à premier niveau de référence: 1000 mm; Altitude supérieure à étage d'implantation: 1000 mm; Altitude supérieure à Zéro du projet: 1000 mm; Altitude supérieure à niveau de la mer: 1000 mm; Altitude supérieure à deuxième niveau de référence: 1000 mm; Altitude inférieure à premier niveau de référence: 4.21885e-12 mm; Altitude inférieure à étage d'implantation: 4.21885e-12 mm; Altitude inférieure à Zéro du projet: 4.21885e-12 mm; Altitude inférieure à niveau de la mer: 4.21885e-12 mm; Altitude inférieure à deuxième niveau de référence: 4.21885e-12 mm; Superficie supérieure (nette): 1.19183 m2; Superficie de l'arête (nette): 2.74365 m2; Superficie inférieure (nette): 6.62125 m2

# IfcWallStandardCase: acrotère 20 200 (3)
In: rdc
Classification: Mur (Classification ARCHICAD); Material: Empty Fill 292498448 200 mm
ArchiCADProperties - Complexité de mur: Droit; Option de géométrie: Uniforme; Emplacement de ligne de référence: Face intérieure; Surface de face intérieure: Surface-Blanche; Surface de face extérieure: Surface-Blanche; Angle d'inclinaison interne de mur: 90 deg; Angle d'inclinaison externe de mur: 90 deg; ID de l'élément: Mur-153; Lien et ID d'élément: Mur-153; Calque: 1-Projet; Matériau de construction / Composite / Profil / Hachure: acrotère 20; Structure Composite: acrotère 20; Verrouillé: no; Nom d'étage d'implantation: rdc; Numéro d'étage d'implantation: 3; Type d'élément: Mur; Étage supérieur lié absolu: Non lié; Étage supérieur lié relatif: Non lié; Étage supérieur lié: Non lié; Type de structure: Composite; ID de Parent: Mur-153; Matériaux de construction (Tous): Empty Fill 292498448; Surfaces (Toutes): Surface-Blanche; Angle d'inclinaison: 90 deg; Nombre de percements: 0; Surface latérale: Surface-Blanche; Nom de Variante: Modèle principal; Nom de Jeu de Variantes: Modèle principal; Position: Non défini; Fonction structurelle: Non défini; Affichage sur filtre de rénovation: Tous les filtres appropriés; État de rénovation: Existant; État de Variante: Modèle principal; Jeu de Variantes: Modèle principal
AC_Pset_RenovationAndPhasing - Renovation Status: Existing
ArchiCADQuantities - Nombre de Portes: 0; Nombre de trous (Nombre d'ouvertures vides): 0; Nombre de Fenêtres: 0; Volume des poteaux: 0 m3; Hauteur maximale de la couche de Mur sur face intérieure: 500 mm; Hauteur maximale du Mur: 500 mm; Hauteur maximale de la couche de Mur sur face extérieure: 500 mm; Épaisseur couche d'air: 0 mm; Superficie des portes: 0 m2; Largeur totale des Portes: 0 mm; Épaisseur de composant de mur sur face intérieure: 200 mm; Épaisseur de composant de mur sur face extérieure: 200 mm; Superficie des fenêtres: 0 m2; Largeur totale des Fenêtres: 0 mm; Superficie analytique des ouvertures sur face intérieure: 0 m2; Superficie analytique des ouvertures sur face extérieure: 0 m2; Volume analytique des ouvertures: 0 m3; Épaisseur du Mur à la fin: 200 mm; Superficie des baies libres dans le Mur: 0 m2; Hauteur: 500 mm; Largeur: 200 mm; Altitude à Zéro du Projet: 2600 mm; Altitude de Référence Niveau 1: 2600 mm; Altitude de Référence Niveau 2: 2600 mm; Altitude à niveau de la mer: 2600 mm; Altitude à étage lié/étage d'implantation: -400 mm; Décalage étage d'implantation: -400 mm; Décalage supérieur: 0 mm; Épaisseur: 200 mm; Épaisseur couche isolation: 0 mm; Altitude supérieure à premier niveau de référence: 3100 mm; Altitude supérieure à étage d'implantation: 100 mm; Altitude supérieure à Zéro du projet: 3100 mm; Altitude supérieure à niveau de la mer: 3100 mm; Altitude supérieure à deuxième niveau de référence: 3100 mm; Altitude inférieure à premier niveau de référence: 2600 mm; Altitude inférieure à étage d'implantation: -400 mm; Altitude inférieure à Zéro du projet: 2600 mm; Altitude inférieure à niveau de la mer: 2600 mm; Altitude inférieure à deuxième niveau de référence: 2600 mm
Name | Nombre de Poteaux | Hauteur minimale de la couche de Mur sur face intérieure (mm) = Hauteur minimale du Mur (mm) = Hauteur minimale de la couche de Mur sur face extérieure (mm) | Volume de composant de mur sur face intérieure (net) (m3) = Volume de composant de mur sur face extérieure (net) (m3) = Volume du composant face intérieure du mur (conditionnel) (m3) = Volume du composant face extérieure du mur (conditionnel) (m3) = Volume (net) (m3) = Volume (conditionnel) (m3) | Longueur moyenne du mur (mm) = Longueur du Mur au centre (mm) | Superficie de la face intérieure du mur (nette) (m2) = Superficie de la face intérieure du mur (conditionnelle) (m2) | Superficie de la face extérieure du mur (nette) (m2) = Superficie de la face extérieure du mur (conditionnelle) (m2) = Superficie de la face extérieure du mur (brute) (m2) = Superficie en plan (m2) = Superficie inférieure (nette) (m2) | Longueur de ligne de référence (mm) = Longueur de la face intérieure du mur (conditionnelle) (mm) = Longueur de Mur sur face intérieure (mm) | Longueur de la face extérieure du mur (conditionnelle) (mm) = Longueur de Mur sur face extérieure (mm) | Superficie de la face intérieure du mur (brute) (m2) | Superficie (m2) = Superficie supérieure (nette) (m2) | Longueur 3D (mm) | Volume (brut) (m3) | Périmètre Plan (mm) | Superficie de l'arête (nette) (m2)
Mur-153 | 1 | 400 | 0.0155376 | 157.176 | 0.121911 | 0.0292649 | 255.822 | 58.5298 | 0.127911 | 0.0314352 | 258.53 | 0.0157176 | 797.213 | 0.302501
Mur-153 | 5 | 400 | 0.87028 | 8710 | 4.355 | 4.355 | 8710 | 8710 | 4.355 | 1.742 | 8710 | 0.871 | 17820 | 3.6708
Mur-153 | 1 | 20.8198 | 0.0714184 | 716.655 | 0.408327 | 0.308327 | 816.655 | 616.655 | 0.408327 | 0.143331 | 816.655 | 0.0716655 | 1916.15 | 0.516594

# IfcWallStandardCase: isol int 18+10 0018356637 280 (42)
Classification: Mur (Classification ARCHICAD); Material: Parpaing 312445824 180 mm, Isolant styromousse 301821074 100 mm
ArchiCADProperties - Complexité de mur: Droit; Option de géométrie: Uniforme; Emplacement de ligne de référence: Face extérieure; Surface de face intérieure: Peinture-01; Surface de face extérieure: Peinture-01; Angle d'inclinaison interne de mur: 90 deg; Angle d'inclinaison externe de mur: 90 deg; Calque: Interieurs logements; Matériau de construction / Composite / Profil / Hachure: isol int 18+10 0018356637; Structure Composite: isol int 18+10 0018356637; Verrouillé: no; Type d'élément: Mur; Étage supérieur lié absolu: Non lié; Étage supérieur lié relatif: Non lié; Étage supérieur lié: Non lié; Type de structure: Composite; Matériaux de construction (Tous): Parpaing 312445824; Isolant styromousse 301821074; Surfaces (Toutes): Peinture-01; Angle d'inclinaison: 90 deg; Nombre de percements: 0; Surface latérale: Peinture-01; Nom de Variante: Modèle principal; Nom de Jeu de Variantes: Modèle principal; Position: Non défini; Fonction structurelle: Non défini; Affichage sur filtre de rénovation: Tous les filtres appropriés; État de rénovation: Existant; État de Variante: Modèle principal; Jeu de Variantes: Modèle principal
ArchiCADQuantities - Nombre de trous (Nombre d'ouvertures vides): 0; Nombre de Fenêtres: 0; Nombre de Poteaux: 0; Volume des poteaux: 0 m3; Épaisseur couche d'air: 0 mm; Épaisseur de composant de mur sur face intérieure: 100 mm; Épaisseur de composant de mur sur face extérieure: 180 mm; Superficie des fenêtres: 0 m2; Largeur totale des Fenêtres: 0 mm; Épaisseur du Mur à la fin: 280 mm; Superficie des baies libres dans le Mur: 0 m2; Largeur: 280 mm; Altitude à étage lié/étage d'implantation: 0 mm; Décalage étage d'implantation: 0 mm; Décalage supérieur: 0 mm; Épaisseur: 280 mm; Épaisseur couche isolation: 0 mm
AC_Pset_RenovationAndPhasing - Renovation Status: Existing
Name | In | ID de l'élément = Lien et ID d'élément = ID de Parent | Nom de zone liée | Numéro de zone liée | Nom d'étage d'implantation | Numéro d'étage d'implantation | Nombre de Portes | Hauteur maximale de la couche de Mur sur face intérieure (mm) = Hauteur maximale du Mur (mm) = Hauteur maximale de la couche de Mur sur face extérieure (mm) = Hauteur (mm) = Altitude supérieure à étage d'implantation (mm) | Hauteur minimale de la couche de Mur sur face intérieure (mm) | Hauteur minimale du Mur (mm) = Hauteur minimale de la couche de Mur sur face extérieure (mm) | Superficie des portes (m2) | Largeur totale des Portes (mm) | Volume de composant de mur sur face intérieure (net) (m3) | Volume de composant de mur sur face extérieure (net) (m3) | Superficie analytique des ouvertures sur face intérieure (m2) = Superficie analytique des ouvertures sur face extérieure (m2) | Longueur moyenne du mur (mm) = Longueur du Mur au centre (mm) | Superficie de la face intérieure du mur (nette) (m2) | Superficie de la face extérieure du mur (nette) (m2) = Superficie en plan (m2) = Superficie inférieure (nette) (m2) | Volume analytique des ouvertures (m3) | Longueur de ligne de référence (mm) | Longueur de la face intérieure du mur (conditionnelle) (mm) | Superficie de la face intérieure du mur (conditionnelle) (m2) | Longueur de la face extérieure du mur (conditionnelle) (mm) | Superficie de la face extérieure du mur (conditionnelle) (m2) | Volume du composant face intérieure du mur (conditionnel) (m3) | Volume du composant face extérieure du mur (conditionnel) (m3) | Superficie de la face intérieure du mur (brute) (m2) | Superficie de la face extérieure du mur (brute) (m2) | Longueur de Mur sur face intérieure (mm) | Longueur de Mur sur face extérieure (mm) | Superficie (m2) = Superficie supérieure (nette) (m2) | Volume (net) (m3) | Altitude à Zéro du Projet (mm) = Altitude de Référence Niveau 1 (mm) = Altitude de Référence Niveau 2 (mm) = Altitude à niveau de la mer (mm) = Altitude inférieure à premier niveau de référence (mm) = Altitude inférieure à Zéro du projet (mm) = Altitude inférieure à niveau de la mer (mm) = Altitude inférieure à deuxième niveau de référence (mm) | Longueur 3D (mm) | Volume (conditionnel) (m3) | Volume (brut) (m3) | Périmètre Plan (mm) | Altitude supérieure à premier niveau de référence (mm) = Altitude supérieure à Zéro du projet (mm) = Altitude supérieure à niveau de la mer (mm) = Altitude supérieure à deuxième niveau de référence (mm) | Altitude inférieure à étage d'implantation (mm) | Superficie de l'arête (nette) (m2)
Mur-142 | rdc | Mur-142 | Sejour cuisine | B05 | rdc | 3 | 0 | 2500 | 2500 | 0 | 0 | 0 | 0.3325 | 0.497692 | 0 | 1240 | 3.45 | 2.50647 | 0 | 1100 | 1380 | 3.45 | 1100 | 2.50647 | 0.3325 | 0.497692 | 3.45 | 2.50647 | 1380 | 1100 | 0.3472 | 0.830192 | 3000 | 1380 | 0.830192 | 0.830192 | 3155.98 | 5500 | 0 | 2.36898
Mur-142 | rdc | Mur-142 | Dressing | A03 | rdc | 3 | 0 | 2750 | 2100 | 2100 | 0 | 0 | 1.00293 | 1.73722 | 0 | 3561.19 | 9.97188 | 9.13595 | 0 | 3421.16 | 3701.23 | 9.97188 | 3421.16 | 9.13595 | 1.00293 | 1.73722 | 10.1644 | 9.40818 | 3701.23 | 3421.16 | 0.997134 | 2.74016 | 3000 | 3701.23 | 2.74016 | 2.74016 | 7798.37 | 5750 | 0 | 3.8474
Mur-142 | rdc | Mur-142 | Sejour cuisine | A03 | rdc | 3 | 0 | 2700 | 2100 | 2100 | 0 | 0 | 0.865427 | 1.45246 | 0 | 3070.76 | 8.39004 | 7.67004 | 0 | 3020.76 | 3300.76 | 8.39004 | 2840.76 | 7.67004 | 0.865427 | 1.45246 | 8.91204 | 7.67004 | 3300.76 | 2840.76 | 0.859813 | 2.31789 | 3000 | 3300.76 | 2.31789 | 2.32149 | 6870.36 | 5700 | 0 | 3.68749
Mur-145 | rdc | Mur-145 | Sejour Cuisine | B01 | rdc | 3 | 0 | 2750 | 2750 | 2750 | 0 | 0 | 1.59455 | 3.02778 | 0 | 6018.93 | 15.6328 | 17.3838 | 0 | 6028.98 | 5687.23 | 15.6328 | 6350.63 | 17.3838 | 1.59455 | 3.02778 | 15.6328 | 17.3838 | 5687.23 | 6350.63 | 1.6853 | 4.62232 | 3000 | 6350.63 | 4.62232 | 4.62232 | 12907.4 | 5750 | 0 | 5.7306
Mur-142 | rdc | Mur-142 | Sejour cuisine/pl | A01 | rdc | 3 | 0 | 2700 | 2700 | 2700 | 0 | 0 | 0.467293 | 0.855707 | 0 | 1750 | 4.455 | 4.806 | 0 | 1780 | 1720 | 4.455 | 1780 | 4.806 | 0.467293 | 0.855707 | 4.644 | 4.806 | 1720 | 1780 | 0.49 | 1.323 | 3000 | 2060 | 1.323 | 1.323 | 4336.43 | 5700 | 0 | 3.23837
Mur-142 | rdc | Mur-142 | Wc | A02 | rdc | 3 | 0 | 2700 | 0 | 0 | 0 | 0 | 0.985688 | 1.77426 | 0 | 3720.76 | 9.66784 | 8.83382 | 0 | 3900.76 | 3720.76 | 9.66784 | 3720.76 | 8.83382 | 0.985688 | 1.77426 | 9.85684 | 9.85704 | 3720.76 | 3720.76 | 1.0222 | 2.75994 | 3000 | 3650.83 | 2.75994 | 2.75994 | 8001.51 | 5700 | 0 | 3.5564
Mur-142 | rdc | Mur-142 | Entree | A01 | rdc | 3 | 1 | 2700 | 2700 | 2700 | 1.8972 | 930 | 0.782239 | 1.33999 | 2.1008 | 3585.26 | 7.95739 | 7.20139 | 0.588224 | 3445.26 | 2715.26 | 7.95739 | 2435.26 | 7.20139 | 0.992319 | 1.71813 | 10.0582 | 9.30219 | 3725.26 | 3445.26 | 0.721071 | 2.12223 | 3000 | 3725.26 | 2.71045 | 2.71045 | 7846.49 | 5700 | 0 | 3.55009
Mur-142 | rdc | Mur-142 | Sejour cuisine | B05 | rdc | 3 | 0 | 2700 | 2700 | 2700 | 0 | 0 | 1.02801 | 1.78742 | 0 | 3721.16 | 10.4051 | 9.4616 | 0 | 3761.16 | 3861.16 | 10.4051 | 3581.16 | 9.4616 | 1.02801 | 1.78742 | 10.4051 | 9.70513 | 3861.16 | 3581.16 | 1.09232 | 2.81544 | 3000 | 4041.16 | 2.81544 | 2.81544 | 8118.3 | 5700 | 0 | 3.9866
Mur-142 | rdc | Mur-142 |  |  | rdc | 3 | 0 | 2700 | 2700 | 2700 | 0 | 0 | 0.976748 | 1.75329 | 0 | 3611.16 | 9.77713 | 9.72313 | 0 | 3941.16 | 3621.16 | 9.77713 | 3601.16 | 9.72313 | 0.976748 | 1.75329 | 9.77713 | 9.72313 | 3621.16 | 3601.16 | 1.01112 | 2.73004 | 3000 | 3941.16 | 2.73004 | 2.73004 | 8087.98 | 5700 | 0 | 4.35953
Mur-145 | rdc | Mur-145 | Sejour Cuisine | A02 | rdc | 3 | 0 | 2750 | 0 | 0 | 0 | 0 | 3.01924 | 5.59479 | 0 | 11254 | 29.3886 | 31.6542 | 0 | 11580.6 | 10927.3 | 29.3886 | 11580.6 | 31.6542 | 3.01924 | 5.59479 | 29.8746 | 31.6542 | 10927.3 | 11580.6 | 3.17911 | 8.61403 | 3000 | 11510.6 | 8.61403 | 8.61403 | 23368.6 | 5750 | 0 | 8.71695
Mur-145 | Etage1 | Mur-145 | Sejour cuisine | A12 | Etage1 | 4 | 0 | 2750 | 2750 | 2750 | 0 | 0 | 3.03709 | 5.62846 | 0 | 11254 | 29.3716 | 31.8467 | 0 | 11580.6 | 10927.3 | 29.3716 | 11580.6 | 31.8467 | 3.03709 | 5.62846 | 30.0501 | 31.8467 | 10927.3 | 11580.6 | 3.15111 | 8.66555 | 5750 | 11580.6 | 8.66555 | 8.66555 | 23368.6 | 8500 | 0 | 8.66897
Mur-145 | Etage1 | Mur-145 | Sejour cuisine | B12 | Etage1 | 4 | 0 | 2750 | 2750 | 2750 | 0 | 0 | 3.02971 | 5.62264 | 0 | 11236.8 | 29.5091 | 31.8411 | 0 | 11578.6 | 10895.1 | 29.5091 | 11578.6 | 31.8411 | 3.02971 | 5.62264 | 29.9614 | 31.8411 | 10895.1 | 11578.6 | 3.14631 | 8.65235 | 5750 | 11578.6 | 8.65235 | 8.65235 | 23358 | 8500 | 0 | 8.72459
Mur-142 | Etage1 | Mur-142 | Entree | A11 | Etage1 | 4 | 1 | 2700 | 2700 | 2700 | 1.8972 | 930 | 0.782239 | 1.33999 | 2.1008 | 3585.26 | 7.76839 | 7.20139 | 0.588224 | 3445.26 | 2715.26 | 7.76839 | 2435.26 | 7.20139 | 0.992319 | 1.71813 | 10.0582 | 9.30219 | 3725.26 | 3445.26 | 0.721071 | 2.12223 | 5750 | 3725.26 | 2.71045 | 2.71045 | 7846.49 | 8450 | 0 | 3.55009 | ArchiCADProperties - Zones conflictuelles: Sejour cuisine/pl
Mur-142 | Etage1 | Mur-142 | Wc | A12 | Etage1 | 4 | 0 | 2700 | 0 | 0 | 0 | 0 | 0.985688 | 1.77426 | 0 | 3720.76 | 9.66784 | 8.83382 | 0 | 3900.76 | 3720.76 | 9.66784 | 3720.76 | 8.83382 | 0.985688 | 1.77426 | 9.85684 | 9.85704 | 3720.76 | 3720.76 | 1.0222 | 2.75994 | 5750 | 3650.83 | 2.75994 | 2.75994 | 8001.51 | 8450 | 0 | 3.5564
Mur-142 | Etage1 | Mur-142 | Sejour cuisine/pl | A11 | Etage1 | 4 | 0 | 2700 | 2100 | 0 | 0 | 0 | 0.463693 | 0.819686 | 0 | 1750 | 4.23 | 4.32 | 0 | 1780 | 1720 | 4.23 | 1780 | 4.32 | 0.463693 | 0.819686 | 4.644 | 4.32 | 1720 | 1780 | 0.476659 | 1.28338 | 5750 | 1880 | 1.28338 | 1.28698 | 4336.43 | 8450 | 0 | 2.5821 | ArchiCADProperties - Zones conflictuelles: Sejour cuisine/pl
Mur-142 | Etage1 | Mur-142 | Sejour cuisine | B16 | Etage1 | 4 | 0 | 2700 | 2700 | 2700 | 0 | 0 | 1.02801 | 1.78742 | 0 | 3721.16 | 10.4051 | 9.4616 | 0 | 3761.16 | 3861.16 | 10.4051 | 3581.16 | 9.4616 | 1.02801 | 1.78742 | 10.4051 | 9.70513 | 3861.16 | 3581.16 | 1.09232 | 2.81544 | 5750 | 4041.16 | 2.81544 | 2.81544 | 8118.3 | 8450 | 0 | 3.9866
Mur-142 | Etage1 | Mur-142 | Sejour cuisine | B16 | Etage1 | 4 | 0 | 2500 | 2500 | 0 | 0 | 0 | 0.3325 | 0.497692 | 0 | 1240 | 3.45 | 2.50647 | 0 | 1100 | 1380 | 3.45 | 1100 | 2.50647 | 0.3325 | 0.497692 | 3.45 | 2.50647 | 1380 | 1100 | 0.3472 | 0.830192 | 5750 | 1380 | 0.830192 | 0.830192 | 3155.98 | 8250 | 0 | 2.36898
Mur-142 | Etage1 | Mur-142 | Sejour cuisine | B11 | Etage1 | 4 | 0 | 2700 | 2700 | 2700 | 0 | 0 | 0.932391 | 1.72204 | 0 | 3511.16 | 9.23713 | 9.72313 | 0 | 3941.16 | 3421.16 | 9.23713 | 3601.16 | 9.72313 | 0.932391 | 1.72204 | 9.23713 | 9.72313 | 3421.16 | 3601.16 | 0.983124 | 2.65444 | 5750 | 3601.16 | 2.65444 | 2.65444 | 7635.18 | 8450 | 0 | 3.62099
Mur-142 | Etage1 | Mur-142 | Sejour cuisine | A13 | Etage1 | 4 | 0 | 3000 | 2100 | 2100 | 0 | 0 | 0.957037 | 1.6153 | 0 | 3070.76 | 9.25627 | 8.56727 | 0 | 3020.76 | 3300.76 | 9.25627 | 2840.76 | 8.56727 | 0.957037 | 1.6153 | 9.83227 | 8.56727 | 3300.76 | 2840.76 | 0.885012 | 2.57233 | 5750 | 3300.76 | 2.57233 | 2.57593 | 6870.36 | 8750 | 0 | 3.91433
Mur-142 | Etage1 | Mur-142 | Ch 1 | A13 | Etage1 | 4 | 0 | 2750 | 2100 | 2100 | 0 | 0 | 1.00408 | 1.73803 | 0 | 3561.19 | 9.98588 | 9.13595 | 0 | 3421.16 | 3701.23 | 9.98588 | 3421.16 | 9.13595 | 1.00408 | 1.73803 | 10.1784 | 9.40818 | 3701.23 | 3421.16 | 0.997134 | 2.74212 | 5750 | 3701.23 | 2.74212 | 2.74212 | 7798.37 | 8500 | 0 | 3.8532
Mur-142 | Etage 2 | Mur-142 | Entree | A21 | Etage 2 | 5 | 1 | 3000 | 3000 | 3000 | 1.8972 | 930 | 0.892684 | 1.53123 | 2.1008 | 3585.88 | 8.34784 | 8.23684 | 0.588224 | 3445.88 | 2715.88 | 8.34784 | 2435.88 | 8.23684 | 1.10276 | 1.90938 | 11.1776 | 10.3376 | 3725.88 | 3445.88 | 0.721246 | 2.42391 | 8500 | 3725.88 | 3.01214 | 3.01214 | 7847.74 | 11500 | 0 | 3.75323
Mur-142 | Etage 2 | Mur-142 | Sejour cuisine | A23 | Etage 2 | 5 | 0 | 3000 | 2300 | 2300 | 0 | 0 | 0.961984 | 1.61385 | 0 | 3070.76 | 9.32627 | 8.52227 | 0 | 3020.76 | 3300.76 | 9.32627 | 2840.76 | 8.52227 | 0.961984 | 1.61385 | 9.90227 | 8.52227 | 3300.76 | 2840.76 | 0.859812 | 2.57583 | 8500 | 3300.76 | 2.57583 | 2.57943 | 6870.36 | 11500 | 0 | 3.90614
Mur-142 | Etage 2 | Mur-142 | Wc | A22 | Etage 2 | 5 | 0 | 3000 | 0 | 0 | 0 | 0 | 0.852267 | 1.53406 | 0 | 3020.87 | 8.33371 | 8.22558 | 0 | 3020.83 | 3020.9 | 8.33371 | 3020.83 | 8.22558 | 0.852267 | 1.53406 | 8.52271 | 8.52249 | 3020.9 | 3020.83 | 0.795442 | 2.38633 | 8500 | 2840.97 | 2.38633 | 2.38633 | 6601.73 | 11500 | 0 | 3.27088
Mur-142 | Etage 2 | Mur-142 | Sejour cuisine/pl | A21 | Etage 2 | 5 | 0 | 3000 | 2300 | 0 | 0 | 0 | 0.515614 | 0.910762 | 0 | 1750 | 4.704 | 4.8 | 0 | 1780 | 1720 | 4.704 | 1780 | 4.8 | 0.515614 | 0.910762 | 5.16 | 4.8 | 1720 | 1780 | 0.476659 | 1.42638 | 8500 | 1880 | 1.42638 | 1.42998 | 4336.43 | 11500 | 0 | 2.76307
Mur-142 | Etage 2 | Mur-142 | Ch 1 | A23 | Etage 2 | 5 | 0 | 3050 | 2300 | 2300 | 0 | 0 | 1.12222 | 1.99302 | 0 | 3651.59 | 11.0657 | 10.679 | 0 | 3421.62 | 3701.55 | 11.0657 | 3601.62 | 10.679 | 1.12222 | 1.99302 | 11.2757 | 10.9759 | 3701.55 | 3601.62 | 1.02244 | 3.11523 | 8500 | 3881.62 | 3.11523 | 3.11523 | 8032.06 | 11550 | 0 | 4.25953 | ArchiCADProperties - Zones conflictuelles: Ch 1; Dressing
Mur-142 | Etage 2 | Mur-142 | Sejour cuisine | B26 | Etage 2 | 5 | 0 | 3000 | 3000 | 3000 | 0 | 0 | 1.14235 | 1.98567 | 0 | 3721.16 | 11.5635 | 10.5359 | 0 | 3761.16 | 3861.16 | 11.5635 | 3581.16 | 10.5359 | 1.14235 | 1.98567 | 11.5635 | 10.7795 | 3861.16 | 3581.16 | 1.09232 | 3.12801 | 8500 | 4041.16 | 3.12801 | 3.12801 | 8118.3 | 11500 | 0 | 4.18939
Mur-142 | Etage 2 | Mur-142 | Sejour cuisine | B26 | Etage 2 | 5 | 0 | 2800 | 2800 | 0 | 0 | 0 | 0.3724 | 0.561952 | 0 | 1240 | 3.864 | 2.83647 | 0 | 1100 | 1380 | 3.864 | 1100 | 2.83647 | 0.3724 | 0.561952 | 3.864 | 2.83647 | 1380 | 1100 | 0.3472 | 0.934352 | 8500 | 1380 | 0.934352 | 0.934352 | 3155.98 | 11300 | 0 | 2.57177
Mur-145 | Etage 2 | Mur-145 | Sejour cuisine | A22 | Etage 2 | 5 | 0 | 3050 | 0 | 0 | 0 | 0 | 3.31581 | 6.14626 | 0 | 11254 | 32.5953 | 34.7808 | 0 | 11580.6 | 10927.3 | 32.5953 | 11580.6 | 34.7808 | 3.31581 | 6.14626 | 32.8053 | 34.7808 | 10927.3 | 11580.6 | 3.19871 | 9.46206 | 8500 | 11580.6 | 9.46206 | 9.46206 | 23368.5 | 11550 | 0 | 8.96395
Mur-142 | Etage 2 | Mur-142 | Sejour cuisine | B21 | Etage 2 | 5 | 0 | 3000 | 3000 | 3000 | 0 | 0 | 1.03599 | 1.91338 | 0 | 3511.16 | 10.2635 | 10.8035 | 0 | 3941.16 | 3421.16 | 10.2635 | 3601.16 | 10.8035 | 1.03599 | 1.91338 | 10.2635 | 10.8035 | 3421.16 | 3601.16 | 0.983124 | 2.94937 | 8500 | 3601.16 | 2.94937 | 2.94937 | 7635.18 | 11500 | 0 | 3.80485
Mur-145 | Etage 2 | Mur-145 | Ch 1 | B21 | Etage 2 | 5 | 0 | 3050 | 3050 | 3050 | 0 | 0 | 3.36022 | 6.23602 | 0 | 11236.8 | 32.7234 | 35.3146 | 0 | 11578.6 | 10895.1 | 32.7234 | 11578.6 | 35.3146 | 3.36022 | 6.23602 | 33.23 | 35.3146 | 10895.1 | 11578.6 | 3.14631 | 9.59624 | 8500 | 11578.6 | 9.59624 | 9.59624 | 23358 | 11550 | 0 | 8.9899
Mur-145 | Etage 3 | Mur-145 | Sde | A32 | Etage 3 | 6 | 0 | 3050 | 3050 | 3050 | 0 | 0 | 3.36866 | 6.24294 | 0 | 11254.8 | 32.0568 | 35.3235 | 0 | 11581.5 | 10928.1 | 32.0568 | 11581.5 | 35.3235 | 3.36866 | 6.24294 | 33.3308 | 35.3235 | 10928.1 | 11581.5 | 3.15134 | 9.6116 | 11550 | 11581.5 | 9.6116 | 9.6116 | 23370.3 | 14600 | 0 | 8.92778 | ArchiCADProperties - Zones conflictuelles: Sde
Mur-145 | Etage 3 | Mur-145 | Ch 1/pl | B31 | Etage 3 | 6 | 0 | 3050 | 3050 | 3050 | 0 | 0 | 3.36022 | 6.23602 | 0 | 11236.8 | 32.5264 | 35.3146 | 0 | 11578.6 | 10895.1 | 32.5264 | 11578.6 | 35.3146 | 3.36022 | 6.23602 | 33.23 | 35.3146 | 10895.1 | 11578.6 | 3.14631 | 9.59624 | 11550 | 11578.6 | 9.59624 | 9.59624 | 23358 | 14600 | 0 | 8.98989
Mur-142 | Etage 3 | Mur-142 | Sde | A32 | Etage 3 | 6 | 0 | 3050 | 1.77636e-12 | 1.77636e-12 | 0 | 0 | 2.18052 | 3.92493 | 0 | 7218.09 | 21.1752 | 20.2342 | 0 | 7678.09 | 7218.09 | 21.1752 | 7218.09 | 20.2342 | 2.18052 | 3.92493 | 21.8052 | 21.8052 | 7218.09 | 7218.09 | 2.02107 | 6.10546 | 11550 | 7218.09 | 6.10546 | 6.10546 | 14996.2 | 14600 | -1.77636e-12 | 5.73054 | ArchiCADProperties - Zones conflictuelles: Sde
Mur-142 | Etage 3 | Mur-142 | Dressing | A32 | Etage 3 | 6 | 0 | 3050 | 3050 | 3050 | 0 | 0 | 1.11241 | 1.92678 | 0 | 3561.06 | 11.064 | 10.1375 | 0 | 3421.16 | 3700.97 | 11.064 | 3421.16 | 10.1375 | 1.11241 | 1.92678 | 11.274 | 10.4345 | 3700.97 | 3421.16 | 0.997098 | 3.03919 | 11550 | 3700.97 | 3.03919 | 3.03919 | 7797.97 | 14600 | 0 | 4.04974 | ArchiCADProperties - Zones conflictuelles: Dressing
Mur-142 | Etage 3 | Mur-142 | Sejour cuisine | A32 | Etage 3 | 6 | 0 | 3000 | 2300 | 2300 | 0 | 0 | 0.917628 | 1.58261 | 0 | 2980.76 | 8.78627 | 8.52227 | 0 | 3020.76 | 3120.76 | 8.78627 | 2840.76 | 8.52227 | 0.917628 | 1.58261 | 9.36227 | 8.52227 | 3120.76 | 2840.76 | 0.834612 | 2.50024 | 11550 | 3120.76 | 2.50024 | 2.50384 | 6637.36 | 14550 | -1.77636e-12 | 3.69676 | ArchiCADProperties - Zones conflictuelles: Sejour cuisine
Mur-142 | Etage 3 | Mur-142 | Sejour cuisine/pl | B31 | Etage 3 | 6 | 0 | 3000 | 3000 | 3000 | 0 | 0 | 1.03599 | 1.91338 | 0 | 3511.16 | 10.0535 | 10.8035 | 0 | 3941.16 | 3421.16 | 10.0535 | 3601.16 | 10.8035 | 1.03599 | 1.91338 | 10.2635 | 10.8035 | 3421.16 | 3601.16 | 0.983124 | 2.94937 | 11550 | 3601.16 | 2.94937 | 2.94937 | 7635.18 | 14550 | 0 | 3.80485
Mur-142 | Etage 3 | Mur-142 | Sejour cuisine/pl | B35 | Etage 3 | 6 | 0 | 3000 | 3000 | 3000 | 0 | 0 | 1.14235 | 1.98567 | 0 | 3721.16 | 11.5635 | 10.5359 | 0 | 3761.16 | 3861.16 | 11.5635 | 3581.16 | 10.5359 | 1.14235 | 1.98567 | 11.5635 | 10.7795 | 3861.16 | 3581.16 | 1.09232 | 3.12801 | 11550 | 4041.16 | 3.12801 | 3.12801 | 8118.3 | 14550 | 0 | 4.18939
Mur-142 | Etage 3 | Mur-142 | Dressing | A34 | Etage 3 | 6 | 0 | 3000 | 3000 | 3000 | 0 | 0 | 0.647576 | 0.982032 | 0 | 1940.01 | 6.84006 | 4.8 | 0 | 1600 | 2280.02 | 6.84006 | 1600 | 4.8 | 0.647576 | 0.982032 | 6.84006 | 4.8 | 2280.02 | 1600 | 0.543203 | 1.62961 | 11550 | 2280.02 | 1.62961 | 1.62961 | 4760.94 | 14550 | 0 | 3.72918
Mur-142 | Etage 3 | Mur-142 | Sejour cuisine/pl | B35 | Etage 3 | 6 | 0 | 2800 | 2300 | 0 | 0 | 0 | 0.3688 | 0.561949 | 0 | 1240 | 3.828 | 2.83647 | 0 | 1100 | 0 | 0 | 0 | 0 | 0.3688 | 0.561949 | 3.864 | 2.83647 | 1380 | 1100 | 0.3472 | 0.930752 | 11550 | 1380 | 0.930752 | 0.934352 | 3155.98 | 14350 | 0 | 2.57177
Mur-142 | etage 4 | Mur-142 | Sejour cuisine/pl | B41 | etage 4 | 7 | 0 | 3000 | 3000 | 3000 | 0 | 0 | 1.03599 | 1.91338 | 0 | 3511.16 | 10.0535 | 10.8035 | 0 | 3941.16 | 3421.16 | 10.0535 | 3601.16 | 10.8035 | 1.03599 | 1.91338 | 10.2635 | 10.8035 | 3421.16 | 3601.16 | 0.983124 | 2.94937 | 14600 | 3601.16 | 2.94937 | 2.94937 | 7635.18 | 17600 | 0 | 3.80485
Mur-142 | Etage 5 | Mur-142 |  |  | Etage 5 | 8 | 0 | 2700 | 2700 | 2700 | 0 | 0 | 0.923713 | 1.66268 | 0 | 3421.16 | 9.23713 | 8.9936 | 0 | 3941.16 | 3421.16 | 9.23713 | 3421.16 | 8.9936 | 0.923713 | 1.66268 | 9.23713 | 9.23713 | 3421.16 | 3421.16 | 0.957924 | 2.5864 | 17650 | 3421.16 | 2.5864 | 2.5864 | 7402.32 | 20350 | 0 | 3.42785
Mur-142 | Etage 5 | Mur-142 | Ch 3 | B51 | Etage 5 | 8 | 1 | 2700 | 2700 | 2700 | 0.2925 | 450 | 1.31747 | 2.37144 | 0.3283 | 5001.1 | 12.4739 | 13.1747 | 0.091924 | 5341.1 | 5001.1 | 12.8022 | 5001.09 | 13.503 | 1.3503 | 2.43053 | 13.503 | 13.503 | 5001.1 | 5001.09 | 1.40031 | 3.6889 | 17650 | 5001.1 | 3.78083 | 3.78083 | 10562.2 | 20350 | 0 | 4.31261

# IfcWallStandardCase: isol int 18+10 280, Mur-142
In: etage 4
Classification: Mur (Classification ARCHICAD); Material: Parpaing 312445824 180 mm, Isolant styromousse 301821074 100 mm
ArchiCADProperties - Complexité de mur: Droit; Option de géométrie: Uniforme; Emplacement de ligne de référence: Face extérieure; Surface de face intérieure: Peinture-01; Surface de face extérieure: Peinture-01; Angle d'inclinaison interne de mur: 90 deg; Angle d'inclinaison externe de mur: 90 deg; ID de l'élément: Mur-142; Lien et ID d'élément: Mur-142; Calque: Interieurs logements; Matériau de construction / Composite / Profil / Hachure: isol int 18+10; Structure Composite: isol int 18+10; Verrouillé: no; Nom d'étage d'implantation: etage 4; Numéro d'étage d'implantation: 7; Type d'élément: Mur; Étage supérieur lié absolu: Non lié; Étage supérieur lié relatif: Non lié; Étage supérieur lié: Non lié; Type de structure: Composite; ID de Parent: Mur-142; Matériaux de construction (Tous): Parpaing 312445824; Isolant styromousse 301821074; Surfaces (Toutes): Peinture-01; Angle d'inclinaison: 90 deg; Nombre de percements: 0; Surface latérale: Peinture-01; Nom de Variante: Modèle principal; Nom de Jeu de Variantes: Modèle principal; Position: Non défini; Fonction structurelle: Non défini; Affichage sur filtre de rénovation: Tous les filtres appropriés; État de rénovation: Existant; État de Variante: Modèle principal; Jeu de Variantes: Modèle principal
AC_Pset_RenovationAndPhasing - Renovation Status: Existing
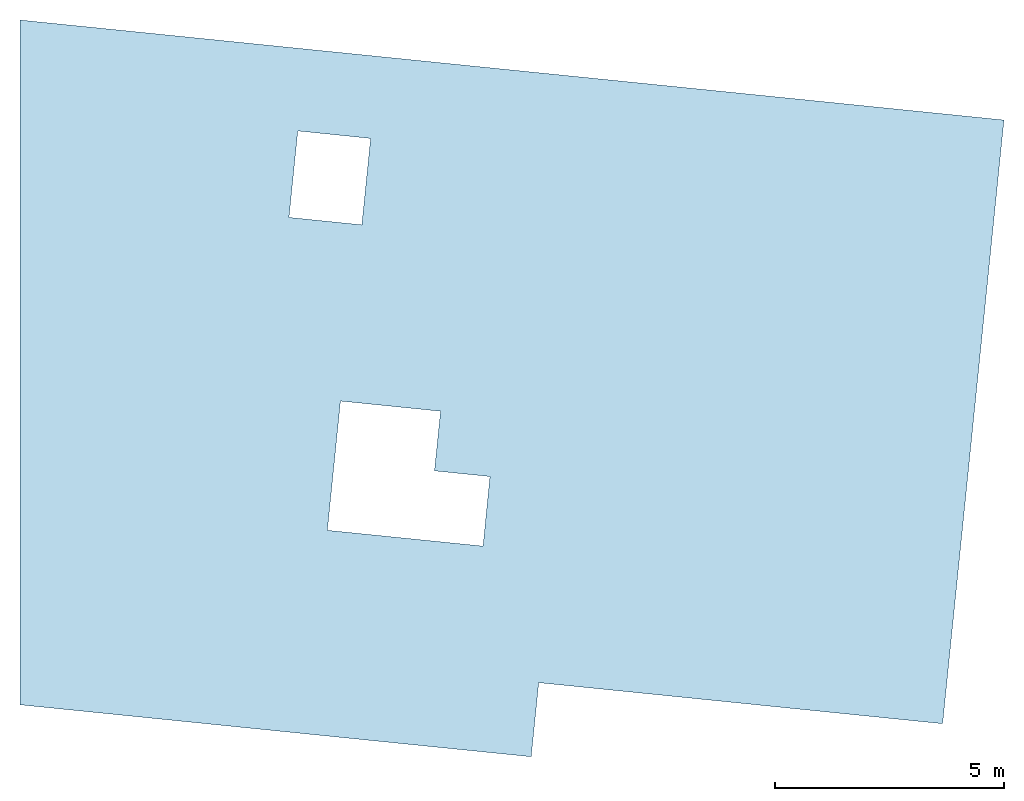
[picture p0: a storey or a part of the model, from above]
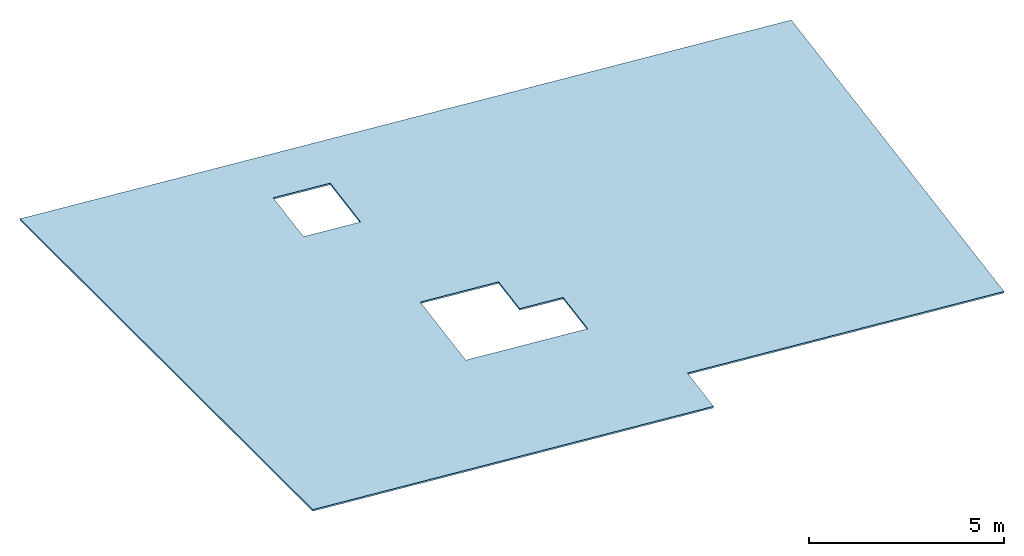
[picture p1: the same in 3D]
Properties of the parts of a building model (IFC2X3), part 32 of 44

# IfcWallStandardCase: isol int 18+10 280, Mur-142
ArchiCADQuantities - Nombre de Portes: 0; Nombre de trous (Nombre d'ouvertures vides): 0; Nombre de Fenêtres: 0; Nombre de Poteaux: 0; Volume des poteaux: 0 m3; Hauteur maximale de la couche de Mur sur face intérieure: 3050 mm; Hauteur minimale de la couche de Mur sur face intérieure: 3050 mm; Hauteur maximale du Mur: 3050 mm; Hauteur minimale du Mur: 3050 mm; Hauteur maximale de la couche de Mur sur face extérieure: 3050 mm; Hauteur minimale de la couche de Mur sur face extérieure: 3050 mm; Épaisseur couche d'air: 0 mm; Superficie des portes: 0 m2; Largeur totale des Portes: 0 mm; Épaisseur de composant de mur sur face intérieure: 100 mm; Épaisseur de composant de mur sur face extérieure: 180 mm; Superficie des fenêtres: 0 m2; Largeur totale des Fenêtres: 0 mm; Volume de composant de mur sur face intérieure (net): 0.178325 m3; Volume de composant de mur sur face extérieure (net): 0.320985 m3; Superficie analytique des ouvertures sur face intérieure: 0 m2; Superficie analytique des ouvertures sur face extérieure: 0 m2; Longueur moyenne du mur: 569.917 mm; Superficie de la face intérieure du mur (nette): 1.78325 m2; Superficie de la face extérieure du mur (nette): 1.78325 m2; Volume analytique des ouvertures: 0 m3; Longueur de ligne de référence: 749.917 mm; Longueur de la face intérieure du mur (conditionnelle): 569.917 mm; Superficie de la face intérieure du mur (conditionnelle): 1.78325 m2; Longueur de la face extérieure du mur (conditionnelle): 569.917 mm; Superficie de la face extérieure du mur (conditionnelle): 1.78325 m2; Volume du composant face intérieure du mur (conditionnel): 0.178325 m3; Volume du composant face extérieure du mur (conditionnel): 0.320985 m3; Superficie de la face intérieure du mur (brute): 1.78325 m2; Superficie de la face extérieure du mur (brute): 1.78325 m2; Épaisseur du Mur à la fin: 280 mm; Longueur du Mur au centre: 569.917 mm; Longueur de Mur sur face intérieure: 569.917 mm; Longueur de Mur sur face extérieure: 569.917 mm; Superficie des baies libres dans le Mur: 0 m2; Superficie: 0.209977 m2; Hauteur: 3050 mm; Volume (net): 0.49931 m3; Largeur: 280 mm; Altitude à Zéro du Projet: 14600 mm; Altitude de Référence Niveau 1: 14600 mm; Altitude de Référence Niveau 2: 14600 mm; Altitude à niveau de la mer: 14600 mm; Altitude à étage lié/étage d'implantation: 0 mm; Décalage étage d'implantation: 0 mm; Décalage supérieur: 0 mm; Superficie en plan: 1.78325 m2; Longueur 3D: 749.917 mm; Épaisseur: 280 mm; Volume (conditionnel): 0.49931 m3; Volume (brut): 0.49931 m3; Épaisseur couche isolation: 0 mm; Périmètre Plan: 1699.83 mm; Altitude supérieure à premier niveau de référence: 17650 mm; Altitude supérieure à étage d'implantation: 3050 mm; Altitude supérieure à Zéro du projet: 17650 mm; Altitude supérieure à niveau de la mer: 17650 mm; Altitude supérieure à deuxième niveau de référence: 17650 mm; Altitude inférieure à premier niveau de référence: 14600 mm; Altitude inférieure à étage d'implantation: 0 mm; Altitude inférieure à Zéro du projet: 14600 mm; Altitude inférieure à niveau de la mer: 14600 mm; Altitude inférieure à deuxième niveau de référence: 14600 mm; Superficie supérieure (nette): 0.209977 m2; Superficie de l'arête (nette): 2.12795 m2; Superficie inférieure (nette): 1.78325 m2

# IfcWallStandardCase: isol int 18+14 320 (6)
In: rdc
Classification: Mur (Classification ARCHICAD); Material: Parpaing 312445824 180 mm, Isolant styromousse 301821074 140 mm
AC_Pset_RenovationAndPhasing - Renovation Status: Existing
ArchiCADProperties - Complexité de mur: Droit; Option de géométrie: Uniforme; Emplacement de ligne de référence: Face extérieure; Surface de face intérieure: Peinture-01; Surface de face extérieure: Peinture-01; Angle d'inclinaison interne de mur: 90 deg; Angle d'inclinaison externe de mur: 90 deg; Calque: Interieurs logements; Matériau de construction / Composite / Profil / Hachure: isol int 18+14; Structure Composite: isol int 18+14; Verrouillé: no; Nom d'étage d'implantation: rdc; Numéro d'étage d'implantation: 3; Type d'élément: Mur; Étage supérieur lié absolu: Non lié; Étage supérieur lié relatif: Non lié; Étage supérieur lié: Non lié; Type de structure: Composite; Matériaux de construction (Tous): Parpaing 312445824; Isolant styromousse 301821074; Surfaces (Toutes): Peinture-01; Angle d'inclinaison: 90 deg; Nombre de percements: 0; Surface latérale: Peinture-01; Nom de Variante: Modèle principal; Nom de Jeu de Variantes: Modèle principal; Position: Non défini; Fonction structurelle: Non défini; Affichage sur filtre de rénovation: Tous les filtres appropriés; État de rénovation: Existant; État de Variante: Modèle principal; Jeu de Variantes: Modèle principal
ArchiCADQuantities - Nombre de trous (Nombre d'ouvertures vides): 0; Nombre de Poteaux: 0; Volume des poteaux: 0 m3; Épaisseur couche d'air: 0 mm; Épaisseur de composant de mur sur face intérieure: 140 mm; Épaisseur de composant de mur sur face extérieure: 180 mm; Épaisseur du Mur à la fin: 320 mm; Superficie des baies libres dans le Mur: 0 m2; Largeur: 320 mm; Altitude à Zéro du Projet: 3000 mm; Altitude de Référence Niveau 1: 3000 mm; Altitude de Référence Niveau 2: 3000 mm; Altitude à niveau de la mer: 3000 mm; Altitude à étage lié/étage d'implantation: 0 mm; Décalage étage d'implantation: 0 mm; Décalage supérieur: 0 mm; Épaisseur: 320 mm; Épaisseur couche isolation: 0 mm; Altitude inférieure à premier niveau de référence: 3000 mm; Altitude inférieure à étage d'implantation: 0 mm; Altitude inférieure à Zéro du projet: 3000 mm; Altitude inférieure à niveau de la mer: 3000 mm; Altitude inférieure à deuxième niveau de référence: 3000 mm
Name | ID de l'élément = Lien et ID d'élément = ID de Parent | Nom de zone liée | Numéro de zone liée | Nombre de Portes | Nombre de Fenêtres | Hauteur maximale de la couche de Mur sur face intérieure (mm) = Hauteur maximale du Mur (mm) = Hauteur maximale de la couche de Mur sur face extérieure (mm) = Hauteur (mm) = Altitude supérieure à étage d'implantation (mm) | Hauteur minimale de la couche de Mur sur face intérieure (mm) = Hauteur minimale du Mur (mm) = Hauteur minimale de la couche de Mur sur face extérieure (mm) | Superficie des portes (m2) | Largeur totale des Portes (mm) | Superficie des fenêtres (m2) | Largeur totale des Fenêtres (mm) | Volume de composant de mur sur face intérieure (net) (m3) | Volume de composant de mur sur face extérieure (net) (m3) | Superficie analytique des ouvertures sur face intérieure (m2) = Superficie analytique des ouvertures sur face extérieure (m2) | Longueur moyenne du mur (mm) = Longueur du Mur au centre (mm) | Superficie de la face intérieure du mur (nette) (m2) | Superficie de la face extérieure du mur (nette) (m2) = Superficie en plan (m2) = Superficie inférieure (nette) (m2) | Volume analytique des ouvertures (m3) | Longueur de ligne de référence (mm) | Longueur de la face intérieure du mur (conditionnelle) (mm) | Superficie de la face intérieure du mur (conditionnelle) (m2) | Longueur de la face extérieure du mur (conditionnelle) (mm) | Superficie de la face extérieure du mur (conditionnelle) (m2) | Volume du composant face intérieure du mur (conditionnel) (m3) | Volume du composant face extérieure du mur (conditionnel) (m3) | Superficie de la face intérieure du mur (brute) (m2) | Superficie de la face extérieure du mur (brute) (m2) | Longueur de Mur sur face intérieure (mm) | Longueur de Mur sur face extérieure (mm) | Superficie (m2) = Superficie supérieure (nette) (m2) | Volume (net) (m3) | Longueur 3D (mm) | Volume (conditionnel) (m3) = Volume (brut) (m3) | Périmètre Plan (mm) | Altitude supérieure à premier niveau de référence (mm) = Altitude supérieure à Zéro du projet (mm) = Altitude supérieure à niveau de la mer (mm) = Altitude supérieure à deuxième niveau de référence (mm) | Superficie de l'arête (nette) (m2)
Mur-142 | Mur-142 | Pl | 819 | 1 | 0 | 2700 | 0 | 0.2925 | 450 | 0 | 0 | 0.582774 | 0.671521 | 0.3283 | 1739.96 | 3.51707 | 3.48767 | 0.105056 | 1579.96 | 1899.96 | 3.84537 | 1579.96 | 3.81597 | 0.628736 | 0.730615 | 4.67998 | 3.81597 | 1899.96 | 1579.96 | 0.556788 | 1.2543 | 1899.96 | 1.35935 | 4252.47 | 5700 | 2.34187
Mur-142 | Mur-142 |  |  | 0 | 0 | 2700 | 2700 | 0 | 0 | 0 | 0 | 1.50082 | 2.00163 | 0 | 4041.92 | 10.5452 | 11.3452 | 0 | 4201.92 | 3881.92 | 10.5452 | 4201.92 | 11.3452 | 1.50082 | 2.00163 | 10.5452 | 11.3452 | 3881.92 | 4201.92 | 1.34461 | 3.50245 | 4201.92 | 3.50245 | 8856.38 | 5700 | 4.7486
Mur-143 | Mur-143 | Pl | 678 | 0 | 1 | 2500 | 2500 | 0 | 0 | 4.87173 | 2319.87 | 1.97122 | 2.67845 | 4.87173 | 7760.78 | 13.2801 | 15.3303 | 1.55895 | 8080.82 | 5120.86 | 13.2801 | 5760.95 | 15.3303 | 2.65326 | 3.55536 | 18.6018 | 20.202 | 7440.74 | 8080.82 | 1.74109 | 4.64967 | 8080.82 | 6.20862 | 16426.7 | 5500 | 6.48743
Mur-143 | Mur-143 | Ch 2/pl | A04 | 0 | 0 | 2700 | 2700 | 0 | 0 | 0 | 0 | 2.78815 | 3.57415 | 0 | 7351.92 | 19.4552 | 19.4452 | 0 | 7681.92 | 7361.92 | 19.4552 | 7341.92 | 19.4452 | 2.78815 | 3.57415 | 19.9412 | 19.8232 | 7361.92 | 7341.92 | 2.40383 | 6.3623 | 7682 | 6.3623 | 15623.4 | 5700 | 7.26398
Mur-143 | Mur-143 | Pl | 819 | 0 | 0 | 2500 | 2500 | 0 | 0 | 0 | 0 | 2.01563 | 2.53552 | 0 | 5688.93 | 13.8585 | 13.7362 | 0 | 5845.91 | 5813.39 | 13.8585 | 5564.47 | 13.7362 | 2.01563 | 2.53552 | 14.5335 | 13.9112 | 5813.39 | 5564.47 | 1.82046 | 4.55114 | 5813.39 | 4.55114 | 12103.3 | 5500 | 5.45445
Mur-143 | Mur-143 | Pl | 819 | 0 | 1 | 2700 | 2700 | 0 | 0 | 4.87173 | 2319.87 | 0.9499 | 1.21158 | 4.87173 | 4306.06 | 6.50863 | 6.70063 | 1.55895 | 4286.06 | 2006.19 | 6.50863 | 1966.19 | 6.70063 | 1.63194 | 2.08849 | 11.6804 | 11.5724 | 4326.06 | 4286.06 | 0.63558 | 2.16148 | 4606.06 | 3.72043 | 9489.87 | 5700 | 4.38345

# IfcWallStandardCase: isol int 18+16 0018356637 340 (165)
Classification: Mur (Classification ARCHICAD); Material: Parpaing 312445824 180 mm, Isolant styromousse 301821074 160 mm
ArchiCADProperties - Complexité de mur: Droit; Option de géométrie: Uniforme; Emplacement de ligne de référence: Face extérieure; Angle d'inclinaison interne de mur: 90 deg; Angle d'inclinaison externe de mur: 90 deg; Matériau de construction / Composite / Profil / Hachure: isol int 18+16 0018356637; Structure Composite: isol int 18+16 0018356637; Verrouillé: no; Type d'élément: Mur; Étage supérieur lié absolu: Non lié; Étage supérieur lié relatif: Non lié; Étage supérieur lié: Non lié; Type de structure: Composite; Matériaux de construction (Tous): Parpaing 312445824; Isolant styromousse 301821074; Angle d'inclinaison: 90 deg; Nombre de percements: 0; Nom de Variante: Modèle principal; Nom de Jeu de Variantes: Modèle principal; Position: Non défini; Fonction structurelle: Non défini; Affichage sur filtre de rénovation: Tous les filtres appropriés; État de rénovation: Existant; État de Variante: Modèle principal; Jeu de Variantes: Modèle principal
ArchiCADQuantities - Nombre de trous (Nombre d'ouvertures vides): 0; Volume des poteaux: 0 m3; Épaisseur couche d'air: 0 mm; Épaisseur de composant de mur sur face intérieure: 160 mm; Épaisseur de composant de mur sur face extérieure: 180 mm; Épaisseur du Mur à la fin: 340 mm; Superficie des baies libres dans le Mur: 0 m2; Largeur: 340 mm; Décalage supérieur: 0 mm; Épaisseur: 340 mm; Épaisseur couche isolation: 0 mm
AC_Pset_RenovationAndPhasing - Renovation Status: Existing
Name | In | Surface de face intérieure = Surface de face extérieure = Surface latérale | ID de l'élément = Lien et ID d'élément = ID de Parent | Calque | Nom de zone liée | Numéro de zone liée | Nom d'étage d'implantation | Numéro d'étage d'implantation | Surfaces (Toutes) | Nombre de Portes | Nombre de Fenêtres | Nombre de Poteaux | Hauteur maximale de la couche de Mur sur face intérieure (mm) = Hauteur maximale du Mur (mm) = Hauteur maximale de la couche de Mur sur face extérieure (mm) = Hauteur (mm) = Altitude supérieure à étage d'implantation (mm) | Hauteur minimale de la couche de Mur sur face intérieure (mm) | Hauteur minimale du Mur (mm) | Hauteur minimale de la couche de Mur sur face extérieure (mm) | Superficie des portes (m2) | Largeur totale des Portes (mm) | Superficie des fenêtres (m2) | Largeur totale des Fenêtres (mm) | Volume de composant de mur sur face intérieure (net) (m3) | Volume de composant de mur sur face extérieure (net) (m3) | Superficie analytique des ouvertures sur face intérieure (m2) | Superficie analytique des ouvertures sur face extérieure (m2) | Longueur moyenne du mur (mm) = Longueur du Mur au centre (mm) | Superficie de la face intérieure du mur (nette) (m2) | Superficie de la face extérieure du mur (nette) (m2) = Superficie en plan (m2) = Superficie inférieure (nette) (m2) | Volume analytique des ouvertures (m3) | Longueur de ligne de référence (mm) | Longueur de la face intérieure du mur (conditionnelle) (mm) | Superficie de la face intérieure du mur (conditionnelle) (m2) | Longueur de la face extérieure du mur (conditionnelle) (mm) | Superficie de la face extérieure du mur (conditionnelle) (m2) | Volume du composant face intérieure du mur (conditionnel) (m3) | Volume du composant face extérieure du mur (conditionnel) (m3) | Superficie de la face intérieure du mur (brute) (m2) | Superficie de la face extérieure du mur (brute) (m2) | Longueur de Mur sur face intérieure (mm) | Longueur de Mur sur face extérieure (mm) | Superficie (m2) = Superficie supérieure (nette) (m2) | Volume (net) (m3) | Altitude à Zéro du Projet (mm) = Altitude de Référence Niveau 1 (mm) = Altitude de Référence Niveau 2 (mm) = Altitude à niveau de la mer (mm) = Altitude inférieure à premier niveau de référence (mm) = Altitude inférieure à Zéro du projet (mm) = Altitude inférieure à niveau de la mer (mm) = Altitude inférieure à deuxième niveau de référence (mm) | Altitude à étage lié/étage d'implantation (mm) = Décalage étage d'implantation (mm) | Longueur 3D (mm) | Volume (conditionnel) (m3) | Volume (brut) (m3) | Périmètre Plan (mm) | Altitude supérieure à premier niveau de référence (mm) = Altitude supérieure à Zéro du projet (mm) = Altitude supérieure à niveau de la mer (mm) = Altitude supérieure à deuxième niveau de référence (mm) | Altitude inférieure à étage d'implantation (mm) | Superficie de l'arête (nette) (m2)
Mur-144 | rdc | Peinture-01 | Mur-144 | Interieurs logements | Ch 2 | B05 | rdc | 3 | Menuiserie Plastique; Peinture-01 | 0 | 2 | 0 | 2750 | 2750 | 2750 | 2750 | 0 | 0 | 4.2 | 2000 | 1.81177 | 2.07199 | 4.7 | 4.2 | 5713.12 | 10.8221 | 11.5111 | 1.458 | 5713.12 | 5713.12 | 10.8221 | 5713.12 | 11.5111 | 2.51377 | 2.82799 | 15.7111 | 15.7111 | 5713.12 | 5713.12 | 1.94246 | 3.88376 | 3000 | 0 | 5713.12 | 5.34176 | 5.34176 | 12106.2 | 5750 | 0 | 5.75492
Mur-142 | rdc | Peinture-01 | Mur-142 | Interieurs logements | Sejour cuisine/pl | A01 | rdc | 3 | Menuiserie Plastique; Peinture-01 | 0 | 2 | 0 | 2750 | 2750 | 2750 | 2750 | 0 | 0 | 4.2 | 2000 | 2.76455 | 3.31963 | 4.7 | 4.2 | 8063.41 | 16.5065 | 18.9593 | 1.458 | 8421.56 | 7705.26 | 16.5065 | 8421.56 | 18.9593 | 3.46655 | 4.07563 | 21.2065 | 23.1593 | 7705.26 | 8421.56 | 2.79936 | 6.08418 | 3000 | 0 | 8421.56 | 7.54218 | 7.54218 | 17114.8 | 5750 | 0 | 8.30864
Mur-142 | rdc | Peinture-01 | Mur-142 | Interieurs logements | Ch 1 | A04 | rdc | 3 | Menuiserie Plastique; Peinture-01 | 0 | 3 | 1 | 2750 | 2750 | 2750 | 2750 | 0 | 0 | 7.53 | 3600 | 5.17931 | 6.04565 | 8.28 | 7.53 | 14791.6 | 31.2729 | 34.0819 | 2.6052 | 15131.6 | 14451.6 | 32.5029 | 15131.6 | 35.3119 | 6.42911 | 7.40105 | 39.7419 | 41.6119 | 14451.6 | 15131.6 | 5.02915 | 11.225 | 3000 | 0 | 15131.6 | 13.8302 | 13.8302 | 30544.9 | 5750 | 0 | 12.7029
Mur-143 | rdc | Poutre | Mur-143 | Interieurs logements | Sejour cuisine/pl | A01 | rdc | 3 | Poutre; Menuiserie Plastique | 0 | 1 | 0 | 2750 | 2750 | 2750 | 2750 | 0 | 0 | 4.3 | 2000 | 0.665427 | 0.79134 | 4.8 | 4.3 | 3153.76 | 3.82293 | 4.42276 | 1.492 | 3171.91 | 1135.61 | 3.82293 | 1171.91 | 4.42276 | 1.38343 | 1.56534 | 8.62293 | 8.72276 | 3135.61 | 3171.91 | 0.392279 | 1.45677 | 3000 | 0 | 3511.91 | 2.94877 | 2.94877 | 7295.51 | 5750 | 0 | 4.18152
Mur-142 | rdc | Peinture-01 | Mur-142 | Interieurs logements | Sejour cuisine/pl | A01 | rdc | 3 | Peinture-01 | 0 | 0 | 0 | 2700 | 2700 | 2150 | 2150 | 0 | 0 | 0 | 0 | 1.29854 | 1.61152 | 0 | 0 | 3170 | 7.533 | 8.86051 | 0 | 3480 | 2860 | 7.533 | 3480 | 8.86051 | 1.29854 | 1.61152 | 7.722 | 9.396 | 2860 | 3480 | 1.0778 | 2.91006 | 3000 | 0 | 3480 | 2.91006 | 2.91006 | 7261.29 | 5700 | 0 | 4.64307
Mur-143 | rdc | Poutre | Mur-143 | Interieurs logements | Sejour cuisine | B02 | rdc | 3 | Poutre; Menuiserie Plastique | 0 | 1 | 0 | 2750 | 2750 | 2750 | 2750 | 0 | 0 | 4.73 | 2200 | 1.52233 | 1.66713 | 5.28 | 4.73 | 5169.57 | 9.38683 | 9.01881 | 1.6412 | 4999.57 | 3139.57 | 9.38683 | 2799.57 | 9.01881 | 2.31213 | 2.51853 | 14.6668 | 13.7488 | 5339.57 | 4999.57 | 1.00965 | 3.18946 | 3000 | 0 | 5339.57 | 4.83066 | 4.83066 | 11160 | 5750 | 0 | 5.01757
Mur-143 | rdc | Peinture-01 | Mur-143 | Interieurs logements | Ch 1 | B03 | rdc | 3 | Peinture-01 | 0 | 0 | 0 | 2700 | 2700 | 2700 | 2700 | 0 | 0 | 0 | 0 | 1.83951 | 2.15207 | 0 | 0 | 4348.12 | 11.2809 | 11.2729 | 0 | 4518.12 | 4178.12 | 11.2809 | 4518.12 | 11.2729 | 1.83951 | 2.15207 | 11.2809 | 12.1989 | 4178.12 | 4518.12 | 1.47836 | 3.99157 | 3000 | 0 | 4518.12 | 3.99157 | 3.99157 | 9517.07 | 5700 | 0 | 5.17297
Mur-142 | rdc | Peinture-01 | Mur-142 | Interieurs logements | Ch 2 | B01 | rdc | 3 | Peinture-01 | 0 | 0 | 0 | 2700 | 2700 | 2700 | 2700 | 0 | 0 | 0 | 0 | 0.647998 | 0.728998 | 0 | 0 | 1500 | 4.04999 | 4.04199 | 0 | 1500 | 1500 | 4.04999 | 1500 | 4.04199 | 0.647998 | 0.728998 | 4.04999 | 4.04999 | 1500 | 1500 | 0.509999 | 1.377 | 3000 | 0 | 1840 | 1.377 | 1.377 | 3961.66 | 5700 | 0 | 3.6165
Mur-142 | rdc | Peinture-01 | Mur-142 | Interieurs logements | Sejour cuisine | B05 | rdc | 3 | Peinture-01 | 0 | 0 | 0 | 2700 | 2700 | 2700 | 2700 | 0 | 0 | 0 | 0 | 1.91946 | 2.24201 | 0 | 0 | 4533.2 | 11.7806 | 12.6986 | 0 | 4703.2 | 4363.2 | 11.7806 | 4703.2 | 12.6986 | 1.91946 | 2.24201 | 11.7806 | 12.6986 | 4363.2 | 4703.2 | 1.54129 | 4.16147 | 3000 | 0 | 4703.2 | 4.16147 | 4.16147 | 9887.22 | 5700 | 0 | 5.29882
Mur-142 | rdc | Peinture-01 | Mur-142 | Interieurs logements | Sejour cuisine | B03 | rdc | 3 | Menuiserie Plastique; Peinture-01 | 0 | 4 | 0 | 2750 | 2750 | 2750 | 2750 | 0 | 0 | 12.9 | 6000 | 4.02907 | 4.80225 | 14.4 | 12.9 | 14232.4 | 23.3542 | 27.1742 | 4.476 | 14572.4 | 7892.42 | 23.3542 | 8572.42 | 27.1742 | 6.18307 | 7.12425 | 38.2042 | 40.0742 | 13892.4 | 14572.4 | 2.79902 | 8.83132 | 3000 | 0 | 14572.4 | 13.3073 | 13.3073 | 29426.5 | 5750 | 0 | 10.2826
Mur-143 | rdc | Poutre | Mur-143 | Interieurs logements | Sejour Cuisine | B01 | rdc | 3 | Poutre; Menuiserie Plastique | 0 | 1 | 0 | 2750 | 2750 | 2750 | 2750 | 0 | 0 | 4.73 | 2200 | 1.5083 | 1.72955 | 5.28 | 4.73 | 5221.32 | 9.09463 | 9.59562 | 1.6412 | 5209.32 | 3033.32 | 9.09463 | 3009.32 | 9.59562 | 2.2981 | 2.58095 | 14.3746 | 14.3256 | 5233.32 | 5209.32 | 1.02725 | 3.23784 | 3000 | 0 | 5549.32 | 4.87904 | 4.87904 | 11387.6 | 5750 | 0 | 5.39421
Mur-144 | rdc | Poutre | Mur-144 | Interieurs logements |  |  | rdc | 3 | Poutre | 0 | 0 | 0 | 2750 | 2750 | 2750 | 2750 | 0 | 0 | 0 | 0 | 2.05839 | 2.38373 | 0 | 0 | 4753.48 | 11.9485 | 12.5251 | 0 | 4613.48 | 4613.48 | 11.9485 | 4893.48 | 12.5251 | 2.05839 | 2.38373 | 12.6871 | 13.4431 | 4613.48 | 4893.48 | 1.61618 | 4.44213 | 3000 | -4.44089e-13 | 4893.48 | 4.44213 | 4.44213 | 10287.4 | 5750 | -4.44089e-13 | 5.37359
Mur-143 | rdc | Peinture-01 | Mur-143 | Interieurs logements | Ch 1 | B03 | rdc | 3 | Menuiserie Plastique; Peinture-01 | 0 | 3 | 0 | 2750 | 2750 | 2750 | 2750 | 0 | 0 | 8.4 | 4000 | 3.19432 | 3.85713 | 9.3 | 8.4 | 10685.1 | 18.599 | 21.919 | 2.942 | 11025.1 | 10345.1 | 18.599 | 11025.1 | 21.919 | 4.62432 | 5.36913 | 28.466 | 30.319 | 10345.1 | 11025.1 | 3.69073 | 7.05145 | 3000 | 0 | 11025.1 | 9.99345 | 9.99345 | 22331.8 | 5750 | 0 | 10.019
Mur-142 | rdc | Peinture-01 | Mur-142 | Interieurs logements | Sejour cuisine/pl | B04 | rdc | 3 | Peinture-01 | 0 | 0 | 0 | 2750 | 2750 | 2750 | 2750 | 0 | 0 | 0 | 0 | 1.22182 | 1.37454 | 0 | 0 | 2776.86 | 7.63635 | 7.63635 | 0 | 2776.86 | 2776.86 | 7.63635 | 2776.86 | 7.63635 | 1.22182 | 1.37454 | 7.63635 | 7.63635 | 2776.86 | 2776.86 | 0.944131 | 2.59636 | 3000 | 0 | 3116.86 | 2.59636 | 2.59636 | 6515.38 | 5750 | 0 | 4.53284
Mur-143 | rdc | Peinture-01 | Mur-143 | Interieurs logements | Ch 2 | B01 | rdc | 3 | Menuiserie Plastique; Peinture-01 | 0 | 3 | 0 | 2750 | 2750 | 2750 | 2750 | 0 | 0 | 8.4 | 4000 | 4.06742 | 4.80859 | 9.4 | 8.4 | 12605.6 | 23.7254 | 27.2004 | 2.916 | 12945.6 | 12265.6 | 23.7254 | 12945.6 | 27.2004 | 5.47142 | 6.32059 | 33.7644 | 35.6004 | 12265.6 | 12945.6 | 4.4015 | 8.87601 | 3000 | 0 | 12945.6 | 11.792 | 11.792 | 26172.9 | 5750 | 0 | 11.4335
Mur-142 | rdc | Peinture-01 | Mur-142 | Interieurs logements | Ch 2 | A02 | rdc | 3 | Peinture-01 | 0 | 0 | 0 | 2700 | 2700 | 2700 | 2700 | 0 | 0 | 0 | 0 | 0.648 | 0.729 | 0 | 0 | 1500 | 4.05 | 4.042 | 0 | 1500 | 1500 | 4.05 | 1500 | 4.042 | 0.648 | 0.729 | 4.05 | 4.05 | 1500 | 1500 | 0.51 | 1.377 | 3000 | 0 | 1840 | 1.377 | 1.377 | 3961.67 | 5700 | 0 | 3.6165
Mur-144 | rdc | Peinture-01 | Mur-144 | Interieurs logements | Ch 1/pl | B04 | rdc | 3 | Menuiserie Plastique; Peinture-01 | 0 | 2 | 0 | 2750 | 2300 | 2300 | 2300 | 0 | 0 | 6.3 | 3000 | 2.36577 | 2.8869 | 7.05 | 6.3 | 7963.03 | 13.5273 | 16.5333 | 2.187 | 8303.03 | 7623.03 | 13.5273 | 8303.03 | 16.5333 | 3.41877 | 4.0209 | 20.9633 | 22.8333 | 7623.03 | 8303.03 | 2.70743 | 5.25267 | 3000 | 0 | 8303.03 | 7.43967 | 7.44543 | 16887.7 | 5750 | 0 | 8.05944
Mur-143 | rdc | Poutre | Mur-143 | Interieurs logements | Sejour Cuisine | A02 | rdc | 3 | Poutre; Menuiserie Plastique | 0 | 1 | 0 | 2750 | 2750 | 2750 | 2750 | 0 | 0 | 4.3 | 2000 | 0.778336 | 0.887864 | 4.8 | 4.3 | 3380.85 | 4.60835 | 4.8693 | 1.492 | 3334.29 | 1427.4 | 4.60835 | 1334.29 | 4.8693 | 1.49634 | 1.66186 | 9.40835 | 9.1693 | 3427.4 | 3334.29 | 0.469487 | 1.6662 | 3000 | 0 | 3674.29 | 3.1582 | 3.1582 | 7662.71 | 5750 | 0 | 4.08973
Mur-143 | rdc | Peinture-01 | Mur-143 | Interieurs logements | Ch 2 | A02 | rdc | 3 | Menuiserie Plastique; Peinture-01 | 0 | 2 | 0 | 2750 | 2750 | 2750 | 2750 | 0 | 0 | 4.2 | 2000 | 3.62093 | 4.27407 | 4.7 | 4.2 | 10000.1 | 21.2038 | 24.2353 | 1.458 | 10340.1 | 9660.12 | 21.2038 | 10340.1 | 24.2353 | 4.32293 | 5.03007 | 26.5823 | 28.4353 | 9660.12 | 10340.1 | 3.45784 | 7.895 | 3000 | 0 | 10340.1 | 9.353 | 9.353 | 20961.9 | 5750 | 0 | 9.55322
Mur-142 | rdc | Poutre | Mur-142 | Interieurs logements | Ch 1 | A03 | rdc | 3 | Poutre; Menuiserie Plastique | 0 | 1 | 0 | 2700 | 2700 | 2700 | 2700 | 0 | 0 | 1.935 | 900 | 0.400184 | 0.450815 | 2.16 | 1.935 | 1658.39 | 2.39864 | 2.46164 | 0.6714 | 1628.39 | 788.386 | 2.39864 | 728.386 | 4.39664 | 0.723284 | 0.799115 | 4.55864 | 4.39664 | 1688.39 | 1628.39 | 0.257851 | 0.850999 | 3000 | 0 | 1968.39 | 1.5224 | 1.5224 | 4238.06 | 5700 | 0 | 3.30918
Mur-142 | rdc | Peinture-01 | Mur-142 | Interieurs logements | Sejour cuisine/pl | B04 | rdc | 3 | Menuiserie Plastique; Peinture-01 | 0 | 1 | 0 | 2750 | 2750 | 2750 | 2750 | 0 | 0 | 2.15 | 1000 | 0.323006 | 0.380257 | 2.4 | 2.15 | 1550.01 | 1.86254 | 2.08654 | 0.746 | 1550.02 | 550.013 | 1.86254 | 550.015 | 2.08654 | 0.682006 | 0.767257 | 4.26254 | 4.26254 | 1550.01 | 1550.02 | 0.187005 | 0.703263 | 3000 | 0 | 1890.02 | 1.44926 | 1.44926 | 4061.7 | 5750 | 0 | 3.35859
Mur-142 | rdc | Peinture-01 | Mur-142 | Interieurs logements | Ch 1 | A01 | rdc | 3 | Menuiserie Plastique; Peinture-01 | 0 | 1 | 0 | 2750 | 2750 | 2750 | 2750 | 0 | 0 | 1.935 | 900 | 0.3369 | 0.3942 | 2.16 | 1.935 | 1500 | 1.965 | 2.182 | 0.6714 | 1500 | 600 | 1.965 | 600 | 4.117 | 0.66 | 0.7425 | 4.125 | 4.125 | 1500 | 1500 | 0.204 | 0.7311 | 3000 | 0 | 1840 | 1.4025 | 1.4025 | 3961.67 | 5750 | 0 | 3.35858
Mur-142 | rdc | Peinture-01 | Mur-142 | Interieurs logements | Sejour cuisine | B03 | rdc | 3 | Menuiserie Plastique; Peinture-01 | 0 | 1 | 0 | 2750 | 2750 | 2750 | 2750 | 0 | 0 | 2.15 | 1000 | 0.345 | 0.405 | 2.4 | 2.15 | 1600 | 2 | 2.242 | 0.746 | 1600 | 600 | 2 | 600 | 2.242 | 0.704 | 0.792 | 4.4 | 4.4 | 1600 | 1600 | 0.204 | 0.75 | 3000 | 0 | 1940 | 1.496 | 1.496 | 4161.67 | 5750 | 0 | 3.39258
Mur-142 | rdc | Peinture-01 | Mur-142 | Interieurs logements | Sejour Cuisine/pl | A04 | rdc | 3 | Menuiserie Plastique; Peinture-01 | 0 | 2 | 0 | 2750 | 2750 | 2750 | 2750 | 0 | 0 | 9.03 | 4200 | 2.39664 | 2.76862 | 10.08 | 9.03 | 8878.45 | 13.8327 | 15.3857 | 3.1332 | 8878.45 | 4678.45 | 13.8327 | 4678.45 | 15.3857 | 3.90444 | 4.39402 | 24.3987 | 24.4157 | 8878.45 | 8878.45 | 1.59067 | 5.16526 | 3000 | 0 | 9218.45 | 8.29846 | 8.29846 | 18718.6 | 5750 | 0 | 7.24689
Mur-142 | rdc | Peinture-01 | Mur-142 | Interieurs logements | Ch 2/pl | A04 | rdc | 3 | Menuiserie Plastique; Peinture-01 | 0 | 1 | 0 | 2750 | 2750 | 2750 | 2750 | 0 | 0 | 2.1 | 1000 | 2.13754 | 2.58354 | 2.35 | 2.1 | 5831.86 | 12.591 | 14.8292 | 0.729 | 5841.91 | 5501.82 | 12.591 | 6161.91 | 14.8292 | 2.48854 | 2.96154 | 15.13 | 16.9292 | 5501.82 | 6161.91 | 1.98283 | 4.72107 | 3000 | 0 | 6161.91 | 5.45007 | 5.45007 | 12611.5 | 5750 | 0 | 6.56577
Mur-143 | rdc | Poutre | Mur-143 | Interieurs logements | Sejour cuisine | B03 | rdc | 3 | Poutre | 0 | 0 | 0 | 2750 | 2750 | 2750 | 2750 | 0 | 0 | 0 | 0 | 1.22182 | 1.37454 | 0 | 0 | 2776.86 | 7.63635 | 7.63635 | 0 | 2776.86 | 2776.86 | 7.63635 | 2776.86 | 7.63635 | 1.22182 | 1.37454 | 7.63635 | 7.63635 | 2776.86 | 2776.86 | 0.944131 | 2.59636 | 3000 | 0 | 3116.86 | 2.59636 | 2.59636 | 6515.38 | 5750 | 0 | 4.53284
Mur-142 | rdc | Peinture-01 | Mur-142 | Interieurs logements | Ch 2 | B02 | rdc | 3 | Menuiserie Plastique; Peinture-01 | 0 | 1 | 0 | 2700 | 2700 | 2700 | 2700 | 0 | 0 | 1.89 | 900 | 0.332105 | 0.388804 | 2.115 | 1.89 | 1500.01 | 1.93504 | 2.15202 | 0.6561 | 1500.01 | 600.013 | 1.93504 | 600.006 | 4.04202 | 0.648005 | 0.729004 | 4.05004 | 4.05002 | 1500.01 | 1500.01 | 0.204003 | 0.720909 | 3000 | 0 | 1840.01 | 1.37701 | 1.37701 | 3961.69 | 5700 | 0 | 3.31051
Mur-144 | rdc | Peinture-01 | Mur-144 | Interieurs logements |  |  | rdc | 3 | Menuiserie Plastique; Peinture-01 | 0 | 1 | 0 | 2750 | 2750 | 2750 | 2750 | 0 | 0 | 4.2 | 2000 | 1.30295 | 1.66634 | 4.7 | 4.2 | 4731.98 | 7.39495 | 9.74795 | 1.458 | 5071.98 | 4391.98 | 7.39495 | 5071.98 | 9.74795 | 2.00495 | 2.42234 | 12.0949 | 13.9479 | 4391.98 | 5071.98 | 1.66667 | 2.96929 | 3000 | 0 | 5071.98 | 4.42729 | 4.42729 | 10425.6 | 5750 | 0 | 5.97089
Mur-144 | rdc | Peinture-01 | Mur-144 | Interieurs logements | Sejour cuisine | B05 | rdc | 3 | Menuiserie Plastique; Peinture-01 | 0 | 1 | 0 | 2750 | 2750 | 2750 | 2750 | 0 | 0 | 2.15 | 1000 | 1.69222 | 2.00477 | 2.4 | 2.15 | 4751.86 | 10.2001 | 10.4421 | 0.746 | 4921.86 | 3581.86 | 10.2001 | 3921.86 | 10.4421 | 2.05122 | 2.39177 | 12.6001 | 13.5351 | 4581.86 | 4921.86 | 1.27563 | 3.69699 | 3000 | 0 | 4921.86 | 4.44299 | 4.44299 | 10324.5 | 5750 | 0 | 5.14855
Mur-144 | rdc | Peinture-01 | Mur-144 | Interieurs logements | Ch 1/pl | B04 | rdc | 3 | Peinture-01 | 0 | 0 | 0 | 2750 | 2750 | 2750 | 2750 | 0 | 0 | 0 | 0 | 2.53869 | 2.94017 | 0 | 0 | 5859.75 | 15.4718 | 15.4498 | 0 | 6029.75 | 5689.75 | 15.4718 | 6029.75 | 15.4498 | 2.53869 | 2.94017 | 15.6468 | 16.5818 | 5689.75 | 6029.75 | 1.99231 | 5.47886 | 3000 | 0 | 6029.75 | 5.47886 | 5.47886 | 12540.3 | 5750 | 0 | 6.24191 | ArchiCADProperties - Zones conflictuelles: Ch 1/pl
Mur-142 | Etage1 | Peinture-01 | Mur-142 | Interieurs logements | Sejour cuisine | B15 | Etage1 | 4 | Menuiserie Plastique; Peinture-01 | 0 | 1 | 0 | 2750 | 2750 | 2750 | 2750 | 0 | 0 | 2.15 | 1000 | 0.323006 | 0.380257 | 2.4 | 2.15 | 1550.01 | 1.86254 | 2.10454 | 0.746 | 1550.01 | 550.013 | 1.86254 | 1550.01 | 2.10454 | 0.682006 | 0.767257 | 4.26254 | 4.26254 | 1550.01 | 1550.01 | 0.187004 | 0.703262 | 5750 | 0 | 1890.01 | 1.44926 | 1.44926 | 4061.69 | 8500 | 0 | 3.35859
Mur-143 | Etage1 | Poutre | Mur-143 | Interieurs logements | Sejour Cuisine | B13 | Etage1 | 4 | Poutre; Menuiserie Plastique | 0 | 1 | 0 | 2750 | 2750 | 2750 | 2750 | 0 | 0 | 4.73 | 2200 | 1.52233 | 1.66713 | 5.28 | 4.73 | 5169.57 | 9.38683 | 9.01881 | 1.6412 | 4999.57 | 3139.57 | 9.38683 | 2799.57 | 9.01881 | 2.31213 | 2.51853 | 14.6668 | 13.7488 | 5339.57 | 4999.57 | 1.00965 | 3.18946 | 5750 | 0 | 5339.57 | 4.83066 | 4.83066 | 11160 | 8500 | 0 | 5.01757
Mur-143 | Etage1 | Peinture-01 | Mur-143 | Interieurs logements | Ch 2 | B13 | Etage1 | 4 | Peinture-01 | 0 | 0 | 0 | 2700 | 2700 | 2700 | 2700 | 0 | 0 | 0 | 0 | 0.648003 | 0.729002 | 0 | 0 | 1500.01 | 4.05003 | 4.05 | 0 | 1500 | 1500.01 | 4.05003 | 1500 | 4.05 | 0.648003 | 0.729002 | 4.05003 | 4.05 | 1500.01 | 1500 | 0.510002 | 1.37701 | 5750 | 0 | 1840.01 | 1.37701 | 1.37701 | 3961.68 | 8450 | 0 | 3.61651
Mur-144 | Etage1 | Poutre | Mur-144 | Interieurs logements | Sejour cuisine | B11 | Etage1 | 4 | Poutre; Menuiserie Plastique | 0 | 3 | 0 | 2750 | 2750 | 2750 | 2750 | 0 | 0 | 8.55 | 4000 | 5.17449 | 5.94991 | 9.55 | 8.55 | 15071 | 29.8863 | 32.2838 | 2.967 | 15194.5 | 11947.6 | 29.8863 | 12194.5 | 32.2838 | 6.60249 | 7.48891 | 41.1058 | 41.7848 | 14947.6 | 15194.5 | 4.10415 | 11.1244 | 5750 | 0 | 15194.5 | 14.0914 | 14.0914 | 30902.2 | 8500 | 0 | 11.3188
Mur-142 | Etage1 | Peinture-01 | Mur-142 | Interieurs logements | Ch 2 | B12 | Etage1 | 4 | Menuiserie Plastique; Peinture-01 | 0 | 1 | 0 | 2700 | 2700 | 2700 | 2700 | 0 | 0 | 1.89 | 900 | 0.332099 | 0.3888 | 2.115 | 1.89 | 1500 | 1.93499 | 2.16 | 0.6561 | 1500 | 599.998 | 1.93499 | 600 | 4.05 | 0.647999 | 0.729 | 4.04999 | 4.05 | 1500 | 1500 | 0.204 | 0.720899 | 5750 | 0 | 1840 | 1.377 | 1.377 | 3961.66 | 8450 | 0 | 3.3105
Mur-143 | Etage1 | Poutre | Mur-143 | Interieurs logements | Sejour cuisine | B14 | Etage1 | 4 | Poutre; Menuiserie Plastique | 0 | 1 | 0 | 2750 | 2750 | 2750 | 2750 | 0 | 0 | 4.3 | 2000 | 0.503816 | 0.600543 | 4.8 | 4.3 | 2776.86 | 2.83635 | 3.33635 | 1.492 | 2776.86 | 776.855 | 2.83635 | 776.855 | 3.33635 | 1.22182 | 1.37454 | 7.63635 | 7.63635 | 2776.86 | 2776.86 | 0.264131 | 1.10436 | 5750 | 0 | 3116.86 | 2.59636 | 2.59636 | 6515.38 | 8500 | 0 | 3.85284
Mur-142 | Etage1 | Peinture-01 | Mur-142 | Interieurs logements | Ch 1 | A15 | Etage1 | 4 | Menuiserie Plastique; Peinture-01 | 0 | 1 | 0 | 2750 | 2750 | 2750 | 2750 | 0 | 0 | 1.935 | 900 | 0.3369 | 0.3942 | 2.16 | 1.935 | 1500 | 1.965 | 2.182 | 0.6714 | 1500 | 600 | 1.965 | 600 | 4.117 | 0.66 | 0.7425 | 4.125 | 4.125 | 1500 | 1500 | 0.204 | 0.7311 | 5750 | 0 | 1840 | 1.4025 | 1.4025 | 3961.67 | 8500 | 0 | 3.35858
Mur-144 | Etage1 | Peinture-01 | Mur-144 | Interieurs logements | Sejour cuisine | B16 | Etage1 | 4 | Menuiserie Plastique; Peinture-01 | 0 | 1 | 0 | 2750 | 2750 | 2750 | 2750 | 0 | 0 | 4.2 | 2000 | 1.30087 | 1.66553 | 4.7 | 4.2 | 4731.98 | 7.37795 | 9.74795 | 1.458 | 5071.98 | 4391.98 | 7.37795 | 5071.98 | 9.74795 | 2.00287 | 2.42153 | 12.0779 | 13.9479 | 4391.98 | 5071.98 | 1.60887 | 2.9664 | 5750 | 0 | 5071.98 | 4.4244 | 4.4244 | 10425.6 | 8500 | 0 | 5.86233
Mur-142 | Etage1 | Peinture-01 | Mur-142 | Interieurs logements | Sejour cuisine/pl | A11 | Etage1 | 4 | Menuiserie Plastique; Peinture-01 | 0 | 1 | 0 | 2750 | 2100 | 2100 | 2100 | 0 | 0 | 2.1 | 1000 | 3.10979 | 3.69763 | 2.35 | 2.1 | 8063.41 | 18.8205 | 21.0593 | 0.729 | 8421.56 | 7705.26 | 18.8205 | 8421.56 | 21.0593 | 3.46079 | 4.07563 | 21.2065 | 23.1593 | 7705.26 | 8421.56 | 2.79936 | 6.80742 | 5750 | 0 | 8421.56 | 7.53642 | 7.54218 | 17114.8 | 8500 | 0 | 8.30864
Mur-143 | Etage1 | Poutre | Mur-143 | Interieurs logements | Sejour cuisine | B12 | Etage1 | 4 | Poutre; Menuiserie Plastique | 0 | 1 | 0 | 2750 | 2750 | 2750 | 2750 | 0 | 0 | 4.73 | 2200 | 1.5083 | 1.72955 | 5.28 | 4.73 | 5221.32 | 9.09463 | 9.59562 | 1.6412 | 5209.32 | 3033.32 | 9.09463 | 3009.32 | 9.59562 | 2.2981 | 2.58095 | 14.3746 | 14.3256 | 5233.32 | 5209.32 | 1.02725 | 3.23784 | 5750 | 0 | 5549.32 | 4.87904 | 4.87904 | 11387.6 | 8500 | 0 | 5.39421
Mur-142 | Etage1 | Peinture-01 | Mur-142 | Interieurs logements | Sejour cuisine/pl | A15 | Etage1 | 4 | Peinture-01 | 0 | 0 | 0 | 2700 | 0 | 0 | 0 | 0 | 0 | 0 | 0 | 2.55827 | 2.92665 | 0 | 0 | 6011.91 | 15.0982 | 16.5022 | 0 | 6181.91 | 5841.91 | 15.0982 | 6181.91 | 16.5022 | 2.55827 | 2.92665 | 15.7732 | 16.5022 | 5841.91 | 6181.91 | 2.03145 | 5.48492 | 5750 | 0 | 6181.91 | 5.48492 | 5.48492 | 12844.7 | 8450 | 0 | 6.27915
Mur-143 | Etage1 | Peinture-01 | Mur-143 | Interieurs logements | Sejour cuisine | B14 | Etage1 | 4 | Peinture-01 | 0 | 0 | 0 | 2750 | 2750 | 2750 | 2750 | 0 | 0 | 0 | 0 | 0.704 | 0.792 | 0 | 0 | 1600 | 4.4 | 4.4 | 0 | 1600 | 1600 | 4.4 | 1600 | 4.4 | 0.704 | 0.792 | 4.4 | 4.4 | 1600 | 1600 | 0.544 | 1.496 | 5750 | 0 | 1940 | 1.496 | 1.496 | 4161.67 | 8500 | 0 | 3.73258
Mur-142 | Etage1 | Peinture-01 | Mur-142 | Interieurs logements | Sejour cuisine/pl | A11 | Etage1 | 4 | Peinture-01 | 0 | 0 | 0 | 2700 | 0 | 0 | 0 | 0 | 0 | 0 | 0 | 1.29854 | 1.44628 | 0 | 0 | 3170 | 7.533 | 8.478 | 0 | 3480 | 2860 | 7.533 | 3480 | 8.478 | 1.29854 | 1.44628 | 7.722 | 8.478 | 2860 | 3480 | 1.0166 | 2.74482 | 5750 | 0 | 3480 | 2.74482 | 2.74482 | 7261.29 | 8450 | 0 | 4.52067
Mur-144 | Etage1 | Peinture-01 | Mur-144 | Interieurs logements | Ch 2 | B15 | Etage1 | 4 | Menuiserie Plastique; Peinture-01 | 0 | 2 | 0 | 2750 | 2750 | 2750 | 2750 | 0 | 0 | 6.3 | 3000 | 2.37153 | 2.8869 | 7.05 | 6.3 | 7963.03 | 13.5493 | 16.5333 | 2.187 | 8303.03 | 7623.03 | 13.5493 | 8303.03 | 16.5333 | 3.42453 | 4.0209 | 20.9633 | 22.8333 | 7623.03 | 8303.03 | 2.70743 | 5.25843 | 5750 | 0 | 8303.03 | 7.44543 | 7.44543 | 16887.7 | 8500 | 0 | 8.05944
Mur-145 | Etage1 | Poutre | Mur-145 | Interieurs logements |  |  | Etage1 | 4 | Poutre; Menuiserie Plastique | 0 | 1 | 0 | 3000 | 3000 | 3000 | 3000 | 0 | 0 | 1.935 | 900 | 0.478714 | 0.53889 | 2.16 | 1.935 | 1658.39 | 2.89016 | 2.95016 | 0.6714 | 1628.39 | 788.386 | 2.89016 | 728.386 | 4.88516 | 0.801814 | 0.88719 | 5.05016 | 4.88516 | 1688.39 | 1628.39 | 0.305451 | 1.0176 | 5750 | 0 | 1968.39 | 1.689 | 1.689 | 4238.06 | 8750 | 0 | 3.62044
Mur-142 | Etage1 | Peinture-01 | Mur-142 | Interieurs logements | Ch 1 | A14 | Etage1 | 4 | Menuiserie Plastique; Peinture-01 | 0 | 3 | 0 | 2750 | 2750 | 2750 | 2750 | 0 | 0 | 7.53 | 3600 | 5.17931 | 6.04565 | 8.28 | 7.53 | 14791.6 | 31.2729 | 34.0819 | 2.6052 | 15131.6 | 14451.6 | 32.5029 | 15131.6 | 35.3119 | 6.42911 | 7.40105 | 39.7419 | 41.6119 | 14451.6 | 15131.6 | 5.02915 | 11.225 | 5750 | 0 | 15131.6 | 13.8302 | 13.8302 | 30544.9 | 8500 | 0 | 12.7029 | ArchiCADProperties - Zones conflictuelles: Sdb
Mur-143 | Etage1 | Poutre | Mur-143 | Interieurs logements | Sejour cuisine/pl | A11 | Etage1 | 4 | Poutre; Menuiserie Plastique | 0 | 1 | 0 | 2750 | 2750 | 2750 | 2750 | 0 | 0 | 4.3 | 2000 | 0.663347 | 0.79053 | 4.8 | 4.3 | 3153.76 | 3.80593 | 4.42276 | 1.492 | 3171.91 | 1135.61 | 3.80593 | 1171.91 | 4.42276 | 1.38135 | 1.56453 | 8.60593 | 8.72276 | 3135.61 | 3171.91 | 0.392279 | 1.45388 | 5750 | 0 | 3511.91 | 2.94588 | 2.94588 | 7295.51 | 8500 | 0 | 4.17448
Mur-142 | Etage1 | Peinture-01 | Mur-142 | Interieurs logements | Sejour cuisine | B14 | Etage1 | 4 | Menuiserie Plastique; Peinture-01 | 0 | 3 | 0 | 2750 | 2750 | 2750 | 2750 | 0 | 0 | 10.75 | 5000 | 4.38807 | 5.18925 | 12 | 10.75 | 14232.4 | 25.5792 | 29.3242 | 3.73 | 14572.4 | 8892.42 | 25.5792 | 14572.4 | 29.3242 | 6.18307 | 7.12425 | 38.2042 | 40.0742 | 13892.4 | 14572.4 | 3.13902 | 9.57732 | 5750 | 0 | 14572.4 | 13.3073 | 13.3073 | 29426.5 | 8500 | 0 | 10.6226
Mur-143 | Etage1 | Peinture-01 | Mur-143 | Interieurs logements | Ch 1 | A12 | Etage1 | 4 | Menuiserie Plastique; Peinture-01 | 0 | 2 | 0 | 2750 | 2750 | 2750 | 2750 | 0 | 0 | 6.3 | 3000 | 3.27201 | 3.89688 | 7.05 | 6.3 | 10000.1 | 18.8708 | 22.1273 | 2.187 | 10340.1 | 9660.12 | 18.8708 | 10340.1 | 22.1273 | 4.32501 | 5.03088 | 26.5993 | 28.4353 | 9660.12 | 10340.1 | 3.51564 | 7.16889 | 5750 | 0 | 10340.1 | 9.35589 | 9.35589 | 20961.9 | 8500 | 0 | 9.66178 | ArchiCADProperties - Zones conflictuelles: Ch 1
Mur-142 | Etage1 | Peinture-01 | Mur-142 | Interieurs logements | Sejour cuisine | B15 | Etage1 | 4 | Menuiserie Plastique; Peinture-01 | 0 | 1 | 0 | 2750 | 2750 | 2750 | 2750 | 0 | 0 | 2.15 | 1000 | 0.862816 | 0.987543 | 2.4 | 2.15 | 2776.86 | 5.23635 | 5.48635 | 0.746 | 2776.86 | 1776.86 | 5.23635 | 2776.86 | 5.48635 | 1.22182 | 1.37454 | 7.63635 | 7.63635 | 2776.86 | 2776.86 | 0.604131 | 1.85036 | 5750 | 0 | 3116.86 | 2.59636 | 2.59636 | 6515.38 | 8500 | 0 | 4.19284
Mur-142 | Etage1 | Peinture-01 | Mur-142 | Interieurs logements | Ch 2 | A12 | Etage1 | 4 | Menuiserie Plastique; Peinture-01 | 0 | 1 | 0 | 2700 | 2700 | 2700 | 2700 | 0 | 0 | 1.935 | 900 | 0.3276 | 0.3807 | 2.115 | 1.935 | 1500 | 1.935 | 2.107 | 0.6687 | 1500 | 600 | 1.935 | 600 | 4.042 | 0.648 | 0.729 | 4.05 | 4.05 | 1500 | 1500 | 0.204 | 0.7083 | 5750 | 0 | 1840 | 1.377 | 1.377 | 3961.67 | 8450 | 0 | 3.3105
Mur-143 | Etage1 | Peinture-01 | Mur-143 | Interieurs logements | Ch 2 | B12 | Etage1 | 4 | Menuiserie Plastique; Peinture-01 | 0 | 3 | 0 | 2750 | 2750 | 2750 | 2750 | 0 | 0 | 6.3 | 3000 | 4.41842 | 5.1866 | 7.05 | 6.3 | 12605.6 | 26.0304 | 29.2844 | 2.187 | 12945.6 | 12265.6 | 26.0304 | 12945.6 | 29.2844 | 5.47142 | 6.3206 | 33.7644 | 35.6004 | 12265.6 | 12945.6 | 4.40151 | 9.60502 | 5750 | 0 | 12945.6 | 11.792 | 11.792 | 26172.9 | 8500 | 0 | 11.4335
Mur-142 | Etage1 | Peinture-01 | Mur-142 | Interieurs logements | Ch 1 | A11 | Etage1 | 4 | Peinture-01 | 0 | 0 | 0 | 2700 | 2700 | 2700 | 2700 | 0 | 0 | 0 | 0 | 0.648 | 0.729 | 0 | 0 | 1500 | 4.05 | 4.05 | 0 | 1500 | 1500 | 4.05 | 1500 | 4.05 | 0.648 | 0.729 | 4.05 | 4.05 | 1500 | 1500 | 0.51 | 1.377 | 5750 | 0 | 1840 | 1.377 | 1.377 | 3961.67 | 8450 | 0 | 3.6165
Mur-142 | Etage1 | Peinture-01 | Mur-142 | Interieurs logements | Sejour cuisine | B16 | Etage1 | 4 | Menuiserie Plastique; Peinture-01 | 0 | 1 | 0 | 2750 | 0 | 0 | 0 | 0 | 0 | 1.89 | 900 | 1.63911 | 1.94333 | 2.115 | 1.89 | 4713.2 | 9.88379 | 11.0438 | 0.6561 | 4883.2 | 4543.2 | 9.88379 | 4883.2 | 12.9338 | 1.95501 | 2.28353 | 11.9988 | 12.9338 | 4543.2 | 4883.2 | 1.54129 | 3.58244 | 5750 | 0 | 4703.2 | 4.23854 | 4.23854 | 10247.2 | 8500 | 0 | 4.40486
Mur-145 | Etage1 | Peinture-01 | Mur-145 | Interieurs logements | Ch 1/pl | B14 | Etage1 | 4 | Menuiserie Plastique; Peinture-01 | 0 | 4 | 0 | 2750 | 2750 | 2750 | 2750 | 0 | 0 | 10.5 | 5000 | 2.86932 | 3.47913 | 11.75 | 10.5 | 10685.1 | 16.149 | 19.803 | 3.645 | 11025.1 | 10345.1 | 16.149 | 11025.1 | 19.803 | 4.62432 | 5.36913 | 28.466 | 30.319 | 10345.1 | 11025.1 | 3.69073 | 6.34845 | 5750 | 0 | 11025.1 | 9.99345 | 9.99345 | 22331.8 | 8500 | 0 | 10.019
Mur-142 | Etage1 | Peinture-01 | Mur-142 | Interieurs logements | Sejour Cuisine/pl | A14 | Etage1 | 4 | Menuiserie Plastique; Peinture-01 | 0 | 2 | 0 | 2750 | 2750 | 2750 | 2750 | 0 | 0 | 9.03 | 4200 | 2.39872 | 2.76943 | 10.08 | 9.03 | 8878.45 | 13.8497 | 15.3857 | 3.1332 | 8878.45 | 4678.45 | 13.8497 | 4678.45 | 15.3857 | 3.90652 | 4.39483 | 24.4157 | 24.4157 | 8878.45 | 8878.45 | 1.59067 | 5.16815 | 5750 | 0 | 9218.45 | 8.30135 | 8.30135 | 18718.6 | 8500 | 0 | 7.25393
Mur-144 | Etage1 | Peinture-01 | Mur-144 | Interieurs logements | Sde | B16 | Etage1 | 4 | Peinture-01 | 0 | 0 | 0 | 2750 | 2750 | 2750 | 2750 | 0 | 0 | 0 | 0 | 2.53871 | 2.9402 | 0 | 0 | 5859.79 | 15.4719 | 15.2609 | 0 | 6029.79 | 5689.79 | 15.4719 | 6029.79 | 15.2609 | 2.53871 | 2.9402 | 15.6469 | 16.5819 | 5689.79 | 6029.79 | 1.99233 | 5.4789 | 5750 | 0 | 6029.79 | 5.4789 | 5.4789 | 12540.4 | 8500 | 0 | 6.24195
Mur-143 | Etage1 | Peinture-01 | Mur-143 | Interieurs logements | Ch 1/pl | B14 | Etage1 | 4 | Peinture-01 | 0 | 0 | 0 | 2700 | 2700 | 2700 | 2700 | 0 | 0 | 0 | 0 | 1.83951 | 2.15207 | 0 | 0 | 4348.12 | 11.2809 | 11.2809 | 0 | 4518.12 | 4178.12 | 11.2809 | 4518.12 | 11.2809 | 1.83951 | 2.15207 | 11.2809 | 12.1989 | 4178.12 | 4518.12 | 1.47836 | 3.99157 | 5750 | 0 | 4518.12 | 3.99157 | 3.99157 | 9517.07 | 8450 | 0 | 5.17297
Mur-142 | Etage1 | Poutre | Mur-142 | Interieurs logements | Sejour cuisine/pl | A15 | Etage1 | 4 | Poutre; Menuiserie Plastique | 0 | 1 | 0 | 2750 | 2750 | 2750 | 2750 | 0 | 0 | 4.73 | 2200 | 0.999914 | 1.1605 | 5.28 | 4.73 | 4062.8 | 5.90971 | 6.44271 | 1.6412 | 4062.8 | 1862.8 | 5.90971 | 1862.8 | 6.44271 | 1.78971 | 2.0119 | 11.1897 | 11.1727 | 4062.8 | 4062.8 | 0.691153 | 2.16041 | 5750 | 0 | 4402.8 | 3.80161 | 3.80161 | 9087.27 | 8500 | 0 | 4.76784
Mur-142 | Etage1 | Peinture-01 | Mur-142 | Interieurs logements | Ch 2 | A14 | Etage1 | 4 | Menuiserie Plastique; Peinture-01 | 0 | 1 | 0 | 2750 | 2750 | 2750 | 2750 | 0 | 0 | 2.1 | 1000 | 3.75768 | 4.41257 | 2.35 | 2.1 | 9517.91 | 22.2143 | 25.0093 | 0.729 | 9857.91 | 9177.91 | 22.2143 | 9857.91 | 25.0093 | 4.10868 | 4.79057 | 25.2393 | 27.1093 | 9177.91 | 9857.91 | 3.23609 | 8.17025 | 5750 | 0 | 9857.91 | 8.89925 | 8.89925 | 19997.5 | 8500 | 0 | 9.11676
Mur-144 | Etage1 | Peinture-01 | Mur-144 | Interieurs logements | Ch 2 | B16 | Etage1 | 4 | Menuiserie Plastique; Peinture-01 | 0 | 2 | 0 | 2750 | 2750 | 2750 | 2750 | 0 | 0 | 6.45 | 3000 | 1.43677 | 1.66699 | 7.2 | 6.45 | 5713.12 | 8.32207 | 9.26107 | 2.238 | 5713.12 | 2713.12 | 8.32207 | 2713.12 | 9.26107 | 2.51377 | 2.82799 | 15.7111 | 15.7111 | 5713.12 | 5713.12 | 0.922459 | 3.10376 | 5750 | 0 | 5713.12 | 5.34176 | 5.34176 | 12106.2 | 8500 | 0 | 4.73492
Mur-143 | Etage1 | Poutre | Mur-143 | Interieurs logements | Sejour cuisine | A12 | Etage1 | 4 | Poutre; Menuiserie Plastique | 0 | 1 | 0 | 2750 | 2750 | 2750 | 2750 | 0 | 0 | 4.3 | 2000 | 0.778336 | 0.887864 | 4.8 | 4.3 | 3380.85 | 4.60835 | 4.8693 | 1.492 | 3334.29 | 1427.4 | 4.60835 | 1334.29 | 4.8693 | 1.49634 | 1.66186 | 9.40835 | 9.1693 | 3427.4 | 3334.29 | 0.469487 | 1.6662 | 5750 | 0 | 3674.29 | 3.1582 | 3.1582 | 7662.71 | 8500 | 0 | 4.08973
Mur-144 | Etage1 | Peinture-01 | Mur-144 | Interieurs logements | Sejour cuisine | B16 | Etage1 | 4 | Menuiserie Plastique; Peinture-01 | 0 | 1 | 0 | 2750 | 2750 | 2750 | 2750 | 0 | 0 | 2.15 | 1000 | 1.69222 | 2.00477 | 2.4 | 2.15 | 4751.86 | 10.2001 | 10.4421 | 0.746 | 4921.86 | 3581.86 | 10.2001 | 3921.86 | 10.4421 | 2.05122 | 2.39177 | 12.6001 | 13.5351 | 4581.86 | 4921.86 | 1.27563 | 3.69699 | 5750 | 0 | 4921.86 | 4.44299 | 4.44299 | 10324.5 | 8500 | 0 | 5.14855
Mur-144 | Etage 2 | Peinture-01 | Mur-144 | Interieurs logements | Sejour cuisine | B26 | Etage 2 | 5 | Menuiserie Plastique; Peinture-01 | 0 | 1 | 0 | 3050 | 3050 | 3050 | 3050 | 0 | 0 | 4.2 | 2000 | 1.53185 | 1.93456 | 4.7 | 4.2 | 4731.98 | 8.79754 | 11.2695 | 1.458 | 5071.98 | 4391.98 | 8.79754 | 5071.98 | 11.2695 | 2.23385 | 2.69056 | 13.4975 | 15.4695 | 4391.98 | 5071.98 | 1.66667 | 3.4664 | 8500 | 0 | 5071.98 | 4.9244 | 4.9244 | 10425.6 | 11550 | 0 | 6.22418
Mur-143 | Etage 2 | Poutre | Mur-143 | Interieurs logements | Sejour cuisine | A22 | Etage 2 | 5 | Poutre; Menuiserie Plastique | 0 | 1 | 0 | 3050 | 3050 | 3050 | 3050 | 0 | 0 | 4.3 | 2000 | 0.9418 | 1.06925 | 4.8 | 4.3 | 3380.85 | 5.63657 | 5.86959 | 1.492 | 3334.29 | 1427.4 | 5.63657 | 1334.29 | 5.86959 | 1.6598 | 1.84325 | 10.4366 | 10.1696 | 3427.4 | 3334.29 | 0.469487 | 2.01105 | 8500 | 0 | 3674.29 | 3.50305 | 3.50305 | 7662.71 | 11550 | 0 | 4.36003
Mur-142 | Etage 2 | Peinture-01 | Mur-142 | Interieurs logements | Ch 1/pl | A21 | Etage 2 | 5 | Menuiserie Plastique; Peinture-01 | 0 | 1 | 0 | 3050 | 2300 | 2300 | 2300 | 0 | 0 | 1.935 | 900 | 0.40314 | 0.4752 | 2.16 | 1.935 | 1500 | 2.379 | 2.64 | 0.6714 | 1500 | 600 | 2.379 | 600 | 4.575 | 0.72624 | 0.8235 | 4.575 | 4.575 | 1500 | 1500 | 0.204 | 0.87834 | 8500 | 0 | 1840 | 1.54974 | 1.5555 | 3961.67 | 11550 | 0 | 3.64708
Mur-142 | Etage 2 | Peinture-01 | Mur-142 | Interieurs logements | Ch 2 | B22 | Etage 2 | 5 | Peinture-01 | 0 | 0 | 0 | 3050 | 3050 | 3050 | 3050 | 0 | 0 | 0 | 0 | 0.731999 | 0.8235 | 0 | 0 | 1500 | 4.57499 | 4.575 | 0 | 1500 | 1500 | 4.57499 | 1500 | 4.575 | 0.731999 | 0.8235 | 4.57499 | 4.575 | 1500 | 1500 | 0.51 | 1.5555 | 8500 | 0 | 1840 | 1.5555 | 1.5555 | 3961.66 | 11550 | 0 | 3.95308
Mur-142 | Etage 2 | Peinture-01 | Mur-142 | Interieurs logements | Sejour cuisine/pl | A25 | Etage 2 | 5 | Peinture-01 | 0 | 0 | 0 | 3000 | 0 | 0 | 0 | 0 | 0 | 0 | 0 | 2.77645 | 3.2261 | 0 | 0 | 5921.92 | 16.7967 | 18.3357 | 0 | 6001.92 | 5661.92 | 16.7967 | 6181.92 | 18.3357 | 2.77645 | 3.2261 | 16.9857 | 18.3357 | 5661.92 | 6181.92 | 2.00085 | 6.00255 | 8500 | 0 | 6181.92 | 6.00255 | 6.00255 | 12709.4 | 11500 | 0 | 6.59832
Mur-142 | Etage 2 | Peinture-01 | Mur-142 | Interieurs logements | Sejour cuisine | B26 | Etage 2 | 5 | Menuiserie Plastique; Peinture-01 | 0 | 1 | 0 | 3050 | 3050 | 3050 | 3050 | 0 | 0 | 1.89 | 900 | 1.85238 | 2.19244 | 2.115 | 1.89 | 4533.2 | 11.1927 | 12.4547 | 0.6561 | 4703.2 | 4363.2 | 11.1927 | 4703.2 | 14.3447 | 2.16828 | 2.53264 | 13.3077 | 14.3447 | 4363.2 | 4703.2 | 1.54129 | 4.04482 | 8500 | 0 | 4703.2 | 4.70092 | 4.70092 | 9887.22 | 11550 | 0 | 5.58611
Mur-143 | Etage 2 | Peinture-01 | Mur-143 | Interieurs logements | Ch 1 | A22 | Etage 2 | 5 | Menuiserie Plastique; Peinture-01 | 0 | 2 | 0 | 3050 | 3050 | 3050 | 3050 | 0 | 0 | 6.3 | 3000 | 3.7413 | 4.44471 | 7.05 | 6.3 | 10000.1 | 21.6765 | 25.2294 | 2.187 | 10340.1 | 9660.12 | 21.6765 | 10340.1 | 25.2294 | 4.7943 | 5.57871 | 29.4804 | 31.5374 | 9660.12 | 10340.1 | 3.45784 | 8.18601 | 8500 | 0 | 10340.1 | 10.373 | 10.373 | 20961.9 | 11550 | 0 | 9.84172
Mur-144 | Etage 2 | Peinture-01 | Mur-144 | Interieurs logements | Sejour cuisine | B25 | Etage 2 | 5 | Peinture-01 | 0 | 0 | 0 | 3050 | 2500 | 2500 | 2500 | 0 | 0 | 0 | 0 | 1.34071 | 1.52449 | 0 | 0 | 2776.86 | 8.37941 | 8.46941 | 0 | 2776.86 | 2776.86 | 8.37941 | 2776.86 | 8.46941 | 1.34071 | 1.52449 | 8.46941 | 8.46941 | 2776.86 | 2776.86 | 0.944131 | 2.8652 | 8500 | 0 | 3116.86 | 2.8652 | 2.8796 | 6515.38 | 11550 | 0 | 4.82132
Mur-143 | Etage 2 | Peinture-01 | Mur-143 | Interieurs logements | Ch 1/pl | B24 | Etage 2 | 5 | Menuiserie Plastique; Peinture-01 | 0 | 3 | 0 | 3050 | 3050 | 3050 | 3050 | 0 | 0 | 8.4 | 4000 | 3.72456 | 4.44277 | 9.4 | 8.4 | 10685.1 | 21.5395 | 25.2185 | 2.916 | 11025.1 | 10345.1 | 21.5395 | 11025.1 | 25.2185 | 5.12856 | 5.95477 | 31.5695 | 33.6265 | 10345.1 | 11025.1 | 3.69073 | 8.16733 | 8500 | 0 | 11025.1 | 11.0833 | 11.0833 | 22331.8 | 11550 | 0 | 10.3075
Mur-142 | Etage 2 | Peinture-01 | Mur-142 | Interieurs logements | Sejour cuisine | B24 | Etage 2 | 5 | Menuiserie Plastique; Peinture-01 | 0 | 4 | 0 | 3050 | 3050 | 3050 | 3050 | 0 | 0 | 12.9 | 6000 | 4.70358 | 5.57944 | 14.4 | 12.9 | 14232.4 | 27.2929 | 31.5459 | 4.476 | 14572.4 | 7892.42 | 27.2929 | 8572.42 | 31.5459 | 6.85758 | 7.90144 | 42.3719 | 44.4459 | 13892.4 | 14572.4 | 2.79902 | 10.283 | 8500 | 0 | 14572.4 | 14.759 | 14.759 | 29426.5 | 11550 | 0 | 10.5711
Mur-143 | Etage 2 | Peinture-01 | Mur-143 | Interieurs logements | Sejour cuisine | B24 | Etage 2 | 5 | Menuiserie Plastique; Peinture-01 | 0 | 1 | 0 | 3050 | 2500 | 2500 | 2500 | 0 | 0 | 2.15 | 1000 | 0.41604 | 0.4914 | 2.4 | 2.15 | 1600 | 2.444 | 2.722 | 0.746 | 1600 | 600 | 2.444 | 600 | 2.722 | 0.77504 | 0.8784 | 4.88 | 4.88 | 1600 | 1600 | 0.204 | 0.90744 | 8500 | 0 | 1940 | 1.65344 | 1.6592 | 4161.67 | 11550 | 0 | 3.68108
Mur-143 | Etage 2 | Poutre | Mur-143 | Interieurs logements | Sejour cuisine | B23 | Etage 2 | 5 | Poutre; Menuiserie Plastique | 0 | 1 | 0 | 3050 | 3050 | 3050 | 3050 | 0 | 0 | 4.73 | 2200 | 1.77479 | 1.94196 | 5.28 | 4.73 | 5169.57 | 10.9887 | 10.5187 | 1.6412 | 4999.57 | 3139.57 | 10.9887 | 2799.57 | 10.5187 | 2.56459 | 2.79336 | 16.2687 | 15.2487 | 5339.57 | 4999.57 | 1.00965 | 3.71676 | 8500 | 0 | 5339.57 | 5.35796 | 5.35796 | 11160 | 11550 | 0 | 5.26382
Mur-142 | Etage 2 | Poutre | Mur-142 | Interieurs logements | Sejour cuisine/pl | A25 | Etage 2 | 5 | Poutre; Menuiserie Plastique | 0 | 1 | 0 | 3050 | 3050 | 3050 | 3050 | 0 | 0 | 4.73 | 2200 | 1.19493 | 1.37989 | 5.28 | 4.73 | 4062.8 | 7.12855 | 7.66155 | 1.6412 | 4062.8 | 1862.8 | 7.12855 | 1862.8 | 7.66155 | 1.98473 | 2.23129 | 12.4086 | 12.3916 | 4062.8 | 4062.8 | 0.691153 | 2.57482 | 8500 | 0 | 4402.8 | 4.21602 | 4.21602 | 9087.27 | 11550 | 0 | 5.05634
Mur-145 | Etage 2 | Poutre | Mur-145 | Interieurs logements | Ch 1 | A23 | Etage 2 | 5 | Poutre; Menuiserie Plastique | 0 | 1 | 0 | 3000 | 3000 | 3000 | 3000 | 0 | 0 | 1.935 | 900 | 0.480549 | 0.539605 | 2.16 | 1.935 | 1658.39 | 2.90516 | 2.95016 | 0.6714 | 1628.39 | 788.386 | 2.90516 | 728.386 | 4.88516 | 0.803649 | 0.887905 | 5.06516 | 4.88516 | 1688.39 | 1628.39 | 0.257851 | 1.02015 | 8500 | 0 | 1968.39 | 1.69155 | 1.69155 | 4238.06 | 11500 | 0 | 3.58556
Mur-142 | Etage 2 | Peinture-01 | Mur-142 | Interieurs logements | Sejour cuisine/pl | A21 | Etage 2 | 5 | Menuiserie Plastique; Peinture-01 | 0 | 2 | 0 | 3050 | 2300 | 2300 | 2300 | 0 | 0 | 4.2 | 2000 | 3.13673 | 3.76415 | 4.7 | 4.2 | 8063.41 | 18.782 | 21.4858 | 1.458 | 8421.56 | 7705.26 | 18.782 | 8421.56 | 21.4858 | 3.83873 | 4.52015 | 23.518 | 25.6858 | 7705.26 | 8421.56 | 2.79936 | 6.90089 | 8500 | 0 | 8421.56 | 8.35889 | 8.36465 | 17114.8 | 11550 | 0 | 8.60503
Mur-142 | Etage 2 | Peinture-01 | Mur-142 | Interieurs logements | Ch 2/pl | A24 | Etage 2 | 5 | Menuiserie Plastique; Peinture-01 | 0 | 1 | 0 | 3050 | 3050 | 3050 | 3050 | 0 | 0 | 4.2 | 2000 | 3.8549 | 4.55717 | 4.7 | 4.2 | 9517.91 | 22.6176 | 25.8666 | 1.458 | 9857.91 | 9177.91 | 22.6176 | 9857.91 | 25.8666 | 4.5569 | 5.31317 | 27.9926 | 30.0666 | 9177.91 | 9857.91 | 3.23609 | 8.41207 | 8500 | 0 | 9857.91 | 9.87007 | 9.87007 | 19997.5 | 11550 | 0 | 9.40526
Mur-143 | Etage 2 | Peinture-01 | Mur-143 | Interieurs logements | Ch 1/pl | B24 | Etage 2 | 5 | Peinture-01 | 0 | 0 | 0 | 3000 | 2500 | 2500 | 2500 | 0 | 0 | 0 | 0 | 2.03814 | 2.39118 | 0 | 0 | 4348.12 | 12.4984 | 12.5344 | 0 | 4518.12 | 4178.12 | 12.4984 | 4518.12 | 12.5344 | 2.03814 | 2.39118 | 12.5344 | 13.5544 | 4178.12 | 4518.12 | 1.47836 | 4.42932 | 8500 | 0 | 4518.12 | 4.42932 | 4.43508 | 9517.07 | 11500 | 0 | 5.41922
Mur-144 | Etage 2 | Peinture-01 | Mur-144 | Interieurs logements | Ch 1/pl | B25 | Etage 2 | 5 | Menuiserie Plastique; Peinture-01 | 0 | 2 | 0 | 3050 | 3050 | 3050 | 3050 | 0 | 0 | 6.3 | 3000 | 2.74512 | 3.32554 | 7.05 | 6.3 | 7963.03 | 15.5752 | 19.0242 | 2.187 | 8303.03 | 7623.03 | 15.5752 | 8303.03 | 19.0242 | 3.79812 | 4.45954 | 23.2502 | 25.3242 | 7623.03 | 8303.03 | 2.70743 | 6.07066 | 8500 | 0 | 8303.03 | 8.25766 | 8.25766 | 16887.7 | 11550 | 0 | 8.34794
Mur-142 | Etage 2 | Peinture-01 | Mur-142 | Interieurs logements | Ch 1 | A25 | Etage 2 | 5 | Menuiserie Plastique; Peinture-01 | 0 | 1 | 0 | 3050 | 2300 | 2300 | 2300 | 0 | 0 | 1.935 | 900 | 0.40314 | 0.4752 | 2.16 | 1.935 | 1500 | 2.379 | 2.632 | 0.6714 | 1500 | 600 | 2.379 | 600 | 4.567 | 0.72624 | 0.8235 | 4.575 | 4.575 | 1500 | 1500 | 0.204 | 0.87834 | 8500 | 0 | 1840 | 1.54974 | 1.5555 | 3961.67 | 11550 | 0 | 3.64708
Mur-142 | Etage 2 | Peinture-01 | Mur-142 | Interieurs logements | Sejour cuisine/pl | A21 | Etage 2 | 5 | Peinture-01 | 0 | 0 | 0 | 3000 | 0 | 0 | 0 | 0 | 0 | 0 | 0 | 1.44282 | 1.60698 | 0 | 0 | 3170 | 8.37 | 9.42 | 0 | 3480 | 2860 | 8.37 | 3480 | 9.42 | 1.44282 | 1.60698 | 8.58 | 9.42 | 2860 | 3480 | 1.0166 | 3.0498 | 8500 | 0 | 3480 | 3.0498 | 3.0498 | 7261.29 | 11500 | 0 | 4.79706
Mur-144 | Etage 2 | Poutre | Mur-144 | Interieurs logements | Ch 1 | B21 | Etage 2 | 5 | Poutre; Menuiserie Plastique | 0 | 3 | 0 | 3050 | 3050 | 3050 | 3050 | 0 | 0 | 10.6 | 5000 | 5.55486 | 6.40137 | 11.85 | 10.6 | 15077.4 | 31.9309 | 34.7095 | 3.679 | 15200.8 | 12953.9 | 31.9309 | 13200.8 | 34.7095 | 7.32586 | 8.30937 | 45.6095 | 46.3625 | 14953.9 | 15200.8 | 4.44631 | 11.9562 | 8500 | 0 | 15200.8 | 15.6352 | 15.6352 | 30914.9 | 11550 | 0 | 11.8912
Mur-143 | Etage 2 | Peinture-01 | Mur-143 | Interieurs logements | Ch 2 | B23 | Etage 2 | 5 | Menuiserie Plastique; Peinture-01 | 0 | 1 | 0 | 3000 | 3000 | 3000 | 3000 | 0 | 0 | 1.935 | 900 | 0.396903 | 0.461701 | 2.16 | 1.935 | 1500 | 2.34002 | 2.565 | 0.6714 | 1500 | 600.008 | 2.34002 | 600 | 4.5 | 0.720003 | 0.810001 | 4.50002 | 4.5 | 1500.01 | 1500 | 0.204001 | 0.858604 | 8500 | 0 | 1840.01 | 1.53 | 1.53 | 3961.68 | 11500 | 0 | 3.59901
Mur-143 | Etage 2 | Poutre | Mur-143 | Interieurs logements | Sejour cuisine | B24 | Etage 2 | 5 | Poutre | 0 | 0 | 0 | 3050 | 2500 | 2500 | 2500 | 0 | 0 | 0 | 0 | 1.34071 | 1.52449 | 0 | 0 | 2776.86 | 8.37941 | 8.46941 | 0 | 2776.86 | 2776.86 | 8.37941 | 2776.86 | 8.46941 | 1.34071 | 1.52449 | 8.46941 | 8.46941 | 2776.86 | 2776.86 | 0.944131 | 2.8652 | 8500 | 0 | 3116.86 | 2.8652 | 2.8796 | 6515.38 | 11550 | 0 | 4.82134
Mur-144 | Etage 2 | Peinture-01 | Mur-144 | Interieurs logements | Sejour cuisine | B25 | Etage 2 | 5 | Menuiserie Plastique; Peinture-01 | 0 | 1 | 0 | 3050 | 2500 | 2500 | 2500 | 0 | 0 | 2.15 | 1000 | 0.397406 | 0.463957 | 2.4 | 2.15 | 1550.01 | 2.32754 | 2.56954 | 0.746 | 1550.01 | 550.013 | 2.32754 | 550.013 | 2.56954 | 0.756406 | 0.850957 | 4.72754 | 4.72754 | 1550.01 | 1550.01 | 0.187004 | 0.861364 | 8500 | 0 | 1890.01 | 1.60736 | 1.60736 | 4061.69 | 11550 | 0 | 3.64706
Mur-143 | Etage 2 | Poutre | Mur-143 | Interieurs logements | Sejour cuisine | B22 | Etage 2 | 5 | Poutre; Menuiserie Plastique | 0 | 1 | 0 | 3050 | 3050 | 3050 | 3050 | 0 | 0 | 4.73 | 2200 | 1.7613 | 2.012 | 5.28 | 4.73 | 5221.32 | 10.6816 | 11.1584 | 1.6412 | 5209.32 | 3033.32 | 10.6816 | 3009.32 | 11.1584 | 2.5511 | 2.8634 | 15.9616 | 15.8884 | 5233.32 | 5209.32 | 1.02725 | 3.77331 | 8500 | 0 | 5549.32 | 5.41451 | 5.41451 | 11387.6 | 11550 | 0 | 5.68475
Mur-142 | Etage 2 | Peinture-01 | Mur-142 | Interieurs logements | Ch 2 | A22 | Etage 2 | 5 | Peinture-01 | 0 | 0 | 0 | 3000 | 2300 | 2300 | 2300 | 0 | 0 | 0 | 0 | 0.71424 | 0.81 | 0 | 0 | 1500 | 4.464 | 4.492 | 0 | 1500 | 1500 | 4.464 | 1500 | 4.492 | 0.71424 | 0.81 | 4.5 | 4.5 | 1500 | 1500 | 0.51 | 1.52424 | 8500 | 0 | 1840 | 1.52424 | 1.53 | 3961.67 | 11500 | 0 | 3.905
Mur-143 | Etage 2 | Peinture-01 | Mur-143 | Interieurs logements | Ch 2 | B22 | Etage 2 | 5 | Menuiserie Plastique; Peinture-01 | 0 | 3 | 0 | 3050 | 3050 | 3050 | 3050 | 0 | 0 | 8.4 | 4000 | 4.66177 | 5.49712 | 9.4 | 8.4 | 12605.6 | 27.2981 | 31.0681 | 2.916 | 12945.6 | 12265.6 | 27.2981 | 12945.6 | 31.0681 | 6.06577 | 7.00912 | 37.4271 | 39.4841 | 12265.6 | 12945.6 | 4.3437 | 10.1589 | 8500 | 0 | 12945.6 | 13.0749 | 13.0749 | 26172.9 | 11550 | 0 | 11.6134
Mur-143 | Etage 2 | Poutre | Mur-143 | Interieurs logements | Sejour cuisine/pl | A21 | Etage 2 | 5 | Poutre; Menuiserie Plastique | 0 | 1 | 0 | 3050 | 2400 | 2400 | 3050 | 0 | 0 | 4.3 | 2000 | 0.816143 | 0.962105 | 4.7799 | 4.3 | 3153.76 | 4.74351 | 5.37434 | 1.4918 | 3171.91 | 1135.61 | 4.74351 | 1171.91 | 5.37434 | 1.53394 | 1.7361 | 9.56361 | 9.67434 | 3135.61 | 3171.91 | 0.394312 | 1.77825 | 8500 | 0 | 3511.91 | 3.27004 | 3.27045 | 7295.51 | 11550 | 0 | 4.47791
Mur-142 | Etage 2 | Peinture-01 | Mur-142 | Interieurs logements | Ch 1 | A24 | Etage 2 | 5 | Menuiserie Plastique; Peinture-01 | 0 | 3 | 0 | 3050 | 2300 | 2300 | 3050 | 0 | 0 | 7.53 | 3600 | 5.87491 | 6.85304 | 8.28 | 7.53 | 14791.6 | 35.5724 | 38.6214 | 2.6052 | 15131.6 | 14451.6 | 36.8024 | 15131.6 | 39.8514 | 7.12471 | 8.20844 | 44.0774 | 46.1514 | 14451.6 | 15131.6 | 5.02915 | 12.7279 | 8500 | 0 | 15131.6 | 15.3331 | 15.3389 | 30544.9 | 11550 | 0 | 12.9914 | ArchiCADProperties - Zones conflictuelles: Sde
Mur-142 | Etage 2 | Peinture-01 | Mur-142 | Interieurs logements | Sejour cuisine/pl | A24 | Etage 2 | 5 | Menuiserie Plastique; Peinture-01 | 0 | 2 | 0 | 3050 | 3050 | 3050 | 3050 | 0 | 0 | 9.03 | 4200 | 2.8228 | 3.24806 | 10.08 | 9.03 | 8878.45 | 16.4423 | 18.0493 | 3.1332 | 8878.45 | 4678.45 | 16.4423 | 4678.45 | 18.0493 | 4.3306 | 4.87346 | 27.0623 | 27.0793 | 8878.45 | 8878.45 | 1.59067 | 6.07087 | 8500 | 0 | 9218.45 | 9.20407 | 9.20407 | 18718.6 | 11550 | 0 | 7.53538
Mur-144 | Etage 2 | Peinture-01 | Mur-144 | Interieurs logements | Ch 2 | B26 | Etage 2 | 5 | Menuiserie Plastique; Peinture-01 | 0 | 1 | 0 | 2750 | 2750 | 2750 | 2750 | 0 | 0 | 2.15 | 1000 | 1.69222 | 2.00477 | 2.4 | 2.15 | 4751.86 | 10.2001 | 10.4421 | 0.746 | 4921.86 | 3581.86 | 10.2001 | 3921.86 | 10.4421 | 2.05122 | 2.39177 | 12.6001 | 13.5351 | 4581.86 | 4921.86 | 1.27563 | 3.69699 | 8500 | 0 | 4921.86 | 4.44299 | 4.44299 | 10324.5 | 11250 | 0 | 5.14855
Mur-144 | Etage 2 | Peinture-01 | Mur-144 | Interieurs logements | Ch 1/pl | B26 | Etage 2 | 5 | Peinture-01 | 0 | 0 | 0 | 3050 | 3050 | 3050 | 3050 | 0 | 0 | 0 | 0 | 2.81566 | 3.26095 | 0 | 0 | 5859.79 | 17.1789 | 16.9679 | 0 | 6029.79 | 5689.79 | 17.1789 | 6029.79 | 16.9679 | 2.81566 | 3.26095 | 17.3539 | 18.3909 | 5689.79 | 6029.79 | 1.99233 | 6.0766 | 8500 | 0 | 6029.79 | 6.0766 | 6.0766 | 12540.4 | 11550 | 0 | 6.4882 | ArchiCADProperties - Zones conflictuelles: Ch 1/pl
Mur-144 | Etage 2 | Peinture-01 | Mur-144 | Interieurs logements | Ch 2 | B26 | Etage 2 | 5 | Menuiserie Plastique; Peinture-01 | 0 | 2 | 0 | 3050 | 3050 | 3050 | 3050 | 0 | 0 | 4.2 | 2000 | 2.086 | 2.3805 | 4.7 | 4.2 | 5713.12 | 12.536 | 13.225 | 1.458 | 5713.12 | 5713.12 | 12.536 | 5713.12 | 13.225 | 2.788 | 3.1365 | 17.425 | 17.425 | 5713.12 | 5713.12 | 1.94246 | 4.4665 | 8500 | 0 | 5713.12 | 5.9245 | 5.9245 | 12106.2 | 11550 | 0 | 5.95892
Mur-142 | Etage 3 | Poutre | Mur-142 | Interieurs logements | Ch 1 | A32 | Etage 3 | 6 | Poutre; Menuiserie Plastique | 0 | 1 | 0 | 3050 | 2300 | 2300 | 2300 | 0 | 0 | 1.935 | 900 | 0.493943 | 0.551163 | 2.16 | 1.935 | 1658.39 | 2.98958 | 3.03158 | 0.6714 | 1628.39 | 788.386 | 2.98958 | 728.386 | 4.96658 | 0.817043 | 0.899463 | 5.14958 | 4.96658 | 1688.39 | 1628.39 | 0.257851 | 1.04511 | 11550 | 0 | 1968.39 | 1.71651 | 1.71975 | 4238.06 | 14600 | 0 | 3.58072
Mur-142 | Etage 3 | Peinture-01 | Mur-142 | Interieurs logements | Ch 1 | A34 | Etage 3 | 6 | Peinture-01 | 0 | 0 | 0 | 3000 | 3000 | 3000 | 3000 | 0 | 0 | 0 | 0 | 2.05363 | 2.28333 | 0 | 0 | 4251.92 | 12.3107 | 12.6057 | 0 | 4201.92 | 4301.92 | 12.3107 | 4201.92 | 12.6057 | 2.05363 | 2.28333 | 12.9057 | 12.6057 | 4301.92 | 4201.92 | 1.44565 | 4.33695 | 11550 | 0 | 4481.92 | 4.33695 | 4.33695 | 9328.99 | 14550 | 0 | 5.36679
Mur-142 | Etage 3 | Peinture-01 | Mur-142 | Interieurs logements | Sejour cuisine | B34 | Etage 3 | 6 | Menuiserie Plastique; Peinture-01 | 0 | 4 | 0 | 3050 | 2300 | 2300 | 2300 | 0 | 0 | 12.9 | 6000 | 5.51419 | 6.48487 | 14.15 | 12.9 | 15882.4 | 32.2844 | 36.554 | 4.461 | 16222.4 | 9542.44 | 32.2844 | 10222.4 | 36.554 | 7.65319 | 8.80687 | 47.4044 | 49.4784 | 15542.4 | 16222.4 | 3.37055 | 11.9991 | 11550 | 0 | 16222.4 | 16.4601 | 16.4701 | 32726.5 | 14600 | 0 | 11.6923
Mur-144 | Etage 3 | Peinture-01 | Mur-144 | Interieurs logements | Ch 2 | B35 | Etage 3 | 6 | Menuiserie Plastique; Peinture-01 | 0 | 2 | 0 | 3050 | 3050 | 3050 | 3050 | 0 | 0 | 6.45 | 3000 | 1.711 | 1.9755 | 7.2 | 6.45 | 5713.12 | 10.036 | 10.975 | 2.238 | 5713.12 | 2713.12 | 10.036 | 2713.12 | 10.975 | 2.788 | 3.1365 | 17.425 | 17.425 | 5713.12 | 5713.12 | 0.922459 | 3.6865 | 11550 | 0 | 5713.12 | 5.9245 | 5.9245 | 12106.2 | 14600 | 0 | 4.93892
Mur-142 | Etage 3 | Peinture-01 | Mur-142 | Interieurs logements | Ch 1 | A33 | Etage 3 | 6 | Menuiserie Plastique; Peinture-01 | 0 | 3 | 0 | 3050 | 3050 | 3050 | 3050 | 0 | 0 | 5.43 | 2600 | 5.49967 | 6.40754 | 5.93 | 5.43 | 13291.6 | 32.9424 | 36.1464 | 1.8762 | 13631.6 | 12951.6 | 34.1724 | 13631.6 | 37.3764 | 6.39847 | 7.38494 | 39.5024 | 41.5764 | 12951.6 | 13631.6 | 4.51915 | 11.9072 | 11550 | 0 | 13631.6 | 13.7834 | 13.7834 | 27544.9 | 14600 | 0 | 11.9714
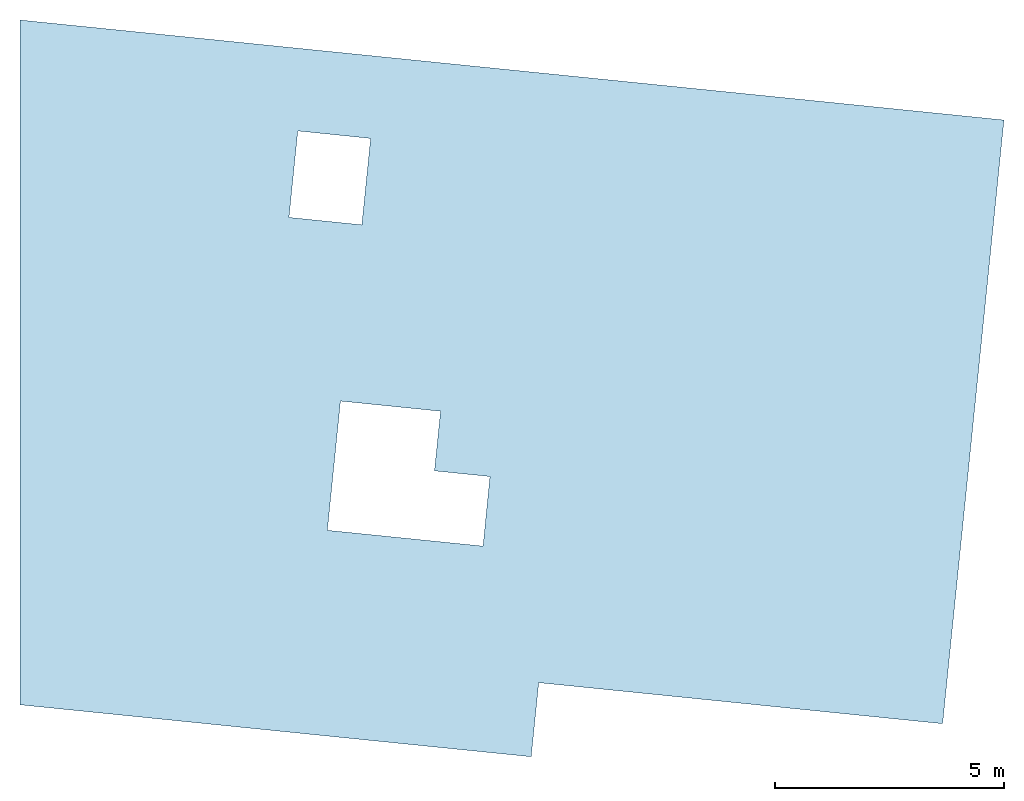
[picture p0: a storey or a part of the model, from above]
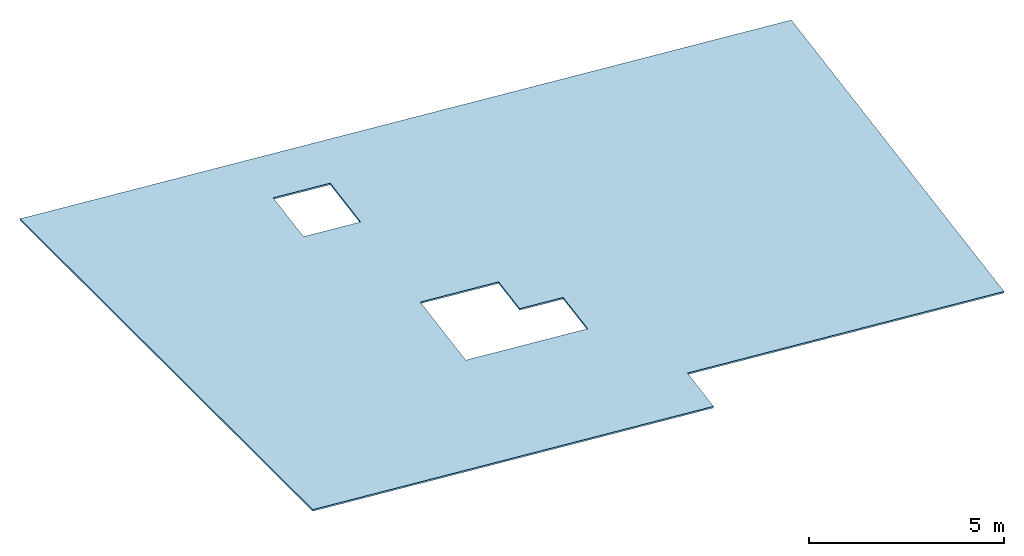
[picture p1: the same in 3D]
Properties of the parts of a building model (IFC2X3), part 33 of 44

# IfcWallStandardCase: isol int 18+16 0018356637 340 (165)
Name | In | Surface de face intérieure = Surface de face extérieure = Surface latérale | ID de l'élément = Lien et ID d'élément = ID de Parent | Calque | Nom de zone liée | Numéro de zone liée | Nom d'étage d'implantation | Numéro d'étage d'implantation | Surfaces (Toutes) | Nombre de Portes | Nombre de Fenêtres | Nombre de Poteaux | Hauteur maximale de la couche de Mur sur face intérieure (mm) = Hauteur maximale du Mur (mm) = Hauteur maximale de la couche de Mur sur face extérieure (mm) = Hauteur (mm) = Altitude supérieure à étage d'implantation (mm) | Hauteur minimale de la couche de Mur sur face intérieure (mm) | Hauteur minimale du Mur (mm) | Hauteur minimale de la couche de Mur sur face extérieure (mm) | Superficie des portes (m2) | Largeur totale des Portes (mm) | Superficie des fenêtres (m2) | Largeur totale des Fenêtres (mm) | Volume de composant de mur sur face intérieure (net) (m3) | Volume de composant de mur sur face extérieure (net) (m3) | Superficie analytique des ouvertures sur face intérieure (m2) | Superficie analytique des ouvertures sur face extérieure (m2) | Longueur moyenne du mur (mm) = Longueur du Mur au centre (mm) | Superficie de la face intérieure du mur (nette) (m2) | Superficie de la face extérieure du mur (nette) (m2) = Superficie en plan (m2) = Superficie inférieure (nette) (m2) | Volume analytique des ouvertures (m3) | Longueur de ligne de référence (mm) | Longueur de la face intérieure du mur (conditionnelle) (mm) | Superficie de la face intérieure du mur (conditionnelle) (m2) | Longueur de la face extérieure du mur (conditionnelle) (mm) | Superficie de la face extérieure du mur (conditionnelle) (m2) | Volume du composant face intérieure du mur (conditionnel) (m3) | Volume du composant face extérieure du mur (conditionnel) (m3) | Superficie de la face intérieure du mur (brute) (m2) | Superficie de la face extérieure du mur (brute) (m2) | Longueur de Mur sur face intérieure (mm) | Longueur de Mur sur face extérieure (mm) | Superficie (m2) = Superficie supérieure (nette) (m2) | Volume (net) (m3) | Altitude à Zéro du Projet (mm) = Altitude de Référence Niveau 1 (mm) = Altitude de Référence Niveau 2 (mm) = Altitude à niveau de la mer (mm) = Altitude inférieure à premier niveau de référence (mm) = Altitude inférieure à Zéro du projet (mm) = Altitude inférieure à niveau de la mer (mm) = Altitude inférieure à deuxième niveau de référence (mm) | Altitude à étage lié/étage d'implantation (mm) = Décalage étage d'implantation (mm) | Longueur 3D (mm) | Volume (conditionnel) (m3) | Volume (brut) (m3) | Périmètre Plan (mm) | Altitude supérieure à premier niveau de référence (mm) = Altitude supérieure à Zéro du projet (mm) = Altitude supérieure à niveau de la mer (mm) = Altitude supérieure à deuxième niveau de référence (mm) | Altitude inférieure à étage d'implantation (mm) | Superficie de l'arête (nette) (m2)
Mur-144 | Etage 3 | Peinture-01 | Mur-144 | Interieurs logements | Sejour cuisine/pl | B35 | Etage 3 | 6 | Menuiserie Plastique; Peinture-01 | 0 | 1 | 0 | 3050 | 2300 | 2300 | 2300 | 0 | 0 | 4.87024 | 2319.16 | 1.41406 | 1.81391 | 5.45003 | 4.87024 | 4731.98 | 8.01152 | 10.5993 | 1.69067 | 5071.98 | 4391.98 | 8.01152 | 5071.98 | 10.5993 | 2.22809 | 2.69056 | 13.4975 | 15.4695 | 4391.98 | 5071.98 | 1.66667 | 3.22798 | 11550 | 0 | 5071.98 | 4.91864 | 4.9244 | 10425.6 | 14600 | 0 | 6.22418
Mur-142 | Etage 3 | Poutre | Mur-142 | Interieurs logements | Dressing | A34 | Etage 3 | 6 | Poutre; Menuiserie Plastique | 0 | 1 | 0 | 3050 | 3050 | 3050 | 3050 | 0 | 0 | 5.375 | 2500 | 2.12726 | 2.53863 | 6 | 5.375 | 6297.87 | 12.0948 | 14.4072 | 1.865 | 6485.97 | 3609.77 | 12.0948 | 3985.97 | 14.4072 | 3.02476 | 3.50613 | 18.6348 | 19.7822 | 6109.77 | 6485.97 | 1.29128 | 4.66589 | 11550 | 0 | 6485.97 | 6.53089 | 6.53089 | 13442.8 | 14600 | 0 | 6.01614
Mur-142 | Etage 3 | Poutre | Mur-142 | Interieurs logements | Dressing | A34 | Etage 3 | 6 | Poutre; Menuiserie Plastique | 0 | 3 | 0 | 3050 | 3050 | 3050 | 3050 | 0 | 0 | 8.335 | 3900 | 6.05513 | 6.97116 | 9.31 | 8.335 | 15350.7 | 35.8212 | 38.9792 | 2.8924 | 15520.7 | 12280.7 | 35.8212 | 12620.7 | 40.9142 | 7.44723 | 8.47146 | 46.3012 | 47.3382 | 15180.7 | 15520.7 | 4.23324 | 13.0263 | 11550 | 0 | 15520.7 | 15.9187 | 15.9187 | 31522.3 | 14600 | 0 | 11.956
Mur-144 | Etage 3 | Peinture-01 | Mur-144 | Interieurs logements | Sejour cuisine/pl | B35 | Etage 3 | 6 | Peinture-01 | 0 | 0 | 0 | 3050 | 3050 | 3050 | 3050 | 0 | 0 | 0 | 0 | 2.16828 | 2.53264 | 0 | 0 | 4533.2 | 13.3077 | 14.3447 | 0 | 4703.2 | 4363.2 | 13.3077 | 4703.2 | 14.3447 | 2.16828 | 2.53264 | 13.3077 | 14.3447 | 4363.2 | 4703.2 | 1.54129 | 4.70092 | 11550 | 0 | 4703.2 | 4.70092 | 4.70092 | 9887.22 | 14600 | 0 | 5.58611
Mur-143 | Etage 3 | Peinture-01 | Mur-143 | Interieurs logements | Ch 2 | B32 | Etage 3 | 6 | Menuiserie Plastique; Peinture-01 | 0 | 3 | 0 | 3050 | 3050 | 3050 | 3050 | 0 | 0 | 6.3 | 3000 | 5.01069 | 5.87431 | 7.05 | 6.3 | 12605.6 | 29.4211 | 33.1761 | 2.187 | 12945.6 | 12265.6 | 29.4211 | 12945.6 | 33.1761 | 6.06369 | 7.00831 | 37.4101 | 39.4841 | 12265.6 | 12945.6 | 4.2859 | 10.885 | 11550 | 0 | 12945.6 | 13.072 | 13.072 | 26172.9 | 14600 | 0 | 11.5049 | ArchiCADProperties - Zones conflictuelles: Ch 1/pl; Ch 2; Ch 2
Mur-142 | Etage 3 | Peinture-01 | Mur-142 | Interieurs logements | Ch 2 | B32 | Etage 3 | 6 | Menuiserie Plastique; Peinture-01 | 0 | 1 | 0 | 3050 | 3050 | 3050 | 3050 | 0 | 0 | 1.935 | 900 | 0.4089 | 0.475201 | 2.16 | 1.935 | 1500 | 2.415 | 2.64001 | 0.6714 | 1500 | 600 | 2.415 | 600.002 | 4.57501 | 0.732 | 0.823501 | 4.575 | 4.57501 | 1500 | 1500 | 0.204 | 0.884101 | 11550 | 0 | 1840 | 1.5555 | 1.5555 | 3961.67 | 14600 | 0 | 3.64708
Mur-144 | Etage 3 | Peinture-01 | Mur-144 | Interieurs logements | Sejour cuisine | B34 | Etage 3 | 6 | Peinture-01 | 0 | 0 | 0 | 3050 | 2500 | 2500 | 2500 | 0 | 0 | 0 | 0 | 2.06005 | 2.41088 | 0 | 0 | 4323.21 | 12.6313 | 12.6233 | 0 | 4493.21 | 4153.21 | 12.6313 | 4493.21 | 12.6233 | 2.06005 | 2.41088 | 12.6673 | 13.7043 | 4153.21 | 4493.21 | 1.46989 | 4.47093 | 11550 | 0 | 4493.21 | 4.47093 | 4.48317 | 9467.26 | 14600 | 0 | 5.44332
Mur-143 | Etage 3 | Poutre | Mur-143 | Interieurs logements | Ch 2 | A31 | Etage 3 | 6 | Poutre; Menuiserie Plastique | 0 | 4 | 0 | 3050 | 3050 | 100 | 100 | 0 | 0 | 12.8 | 6000 | 5.11448 | 6.0261 | 14.3 | 12.8 | 15026.6 | 29.9476 | 33.9735 | 4.442 | 15338.2 | 10715 | 29.9476 | 11338.2 | 33.9735 | 7.25248 | 8.3301 | 44.8808 | 46.7735 | 14715 | 15338.2 | 3.74904 | 11.1406 | 11550 | 0 | 15338.2 | 15.5826 | 15.5826 | 30980.5 | 14600 | 0 | 11.6864
Mur-144 | Etage 3 | Poutre | Mur-144 | Interieurs logements | Ch 1/pl | B31 | Etage 3 | 6 | Poutre; Menuiserie Plastique | 0 | 3 | 0 | 3050 | 3050 | 3050 | 3050 | 0 | 0 | 10.6 | 5000 | 5.55486 | 6.40137 | 11.85 | 10.6 | 15077.4 | 31.9309 | 34.7095 | 3.679 | 15200.8 | 12953.9 | 31.9309 | 13200.8 | 34.7095 | 7.32586 | 8.30937 | 45.6095 | 46.3625 | 14953.9 | 15200.8 | 4.44631 | 11.9562 | 11550 | 0 | 15200.8 | 15.6352 | 15.6352 | 30914.9 | 14600 | 0 | 11.8912 | ArchiCADProperties - Zones conflictuelles: Ch 1/pl
Mur-142 | Etage 3 | Peinture-01 | Mur-142 | Interieurs logements | Sejour cuisine | A32 | Etage 3 | 6 | Menuiserie Plastique; Peinture-01 | 0 | 2 | 0 | 3050 | 2300 | 2300 | 2300 | 0 | 0 | 9.03 | 4200 | 2.81912 | 3.24563 | 10.08 | 9.03 | 8878.45 | 16.4233 | 18.0493 | 3.1332 | 8878.45 | 4678.45 | 16.4233 | 4678.45 | 18.0493 | 4.32692 | 4.87103 | 27.0793 | 27.0793 | 8878.45 | 8878.45 | 1.59067 | 6.06476 | 11550 | 0 | 9218.45 | 9.19796 | 9.20696 | 18718.6 | 14600 | 0 | 7.49151 | ArchiCADProperties - Zones conflictuelles: Sejour cuisine
Mur-144 | Etage 3 | Peinture-01 | Mur-144 | Interieurs logements | Sejour cuisine | B34 | Etage 3 | 6 | Menuiserie Plastique; Peinture-01 | 0 | 2 | 0 | 3050 | 2500 | 2500 | 2500 | 0 | 0 | 6.3 | 3000 | 2.73072 | 3.3255 | 7.05 | 6.3 | 7963.03 | 16.1102 | 19.024 | 2.187 | 8303.03 | 7623.03 | 16.1102 | 8303.03 | 19.024 | 3.78372 | 4.4595 | 23.2502 | 25.3242 | 7623.03 | 8303.03 | 2.70743 | 6.05622 | 11550 | 0 | 8303.03 | 8.24322 | 8.25766 | 16887.7 | 14600 | 0 | 8.32544
Mur-143 | Etage 3 | Poutre | Mur-143 | Interieurs logements | Ch 3 | B34 | Etage 3 | 6 | Poutre; Menuiserie Plastique | 0 | 4 | 0 | 3050 | 2500 | 2500 | 2500 | 0 | 0 | 11.18 | 5200 | 5.93883 | 6.78426 | 12.48 | 11.18 | 16024.7 | 35.3452 | 37.6872 | 3.8792 | 16024.7 | 10824.7 | 35.3452 | 10824.7 | 37.6872 | 7.80563 | 8.79666 | 48.8752 | 48.8752 | 16024.7 | 16024.7 | 3.68039 | 12.7231 | 11550 | 0 | 16364.7 | 16.6023 | 16.6176 | 33011 | 14600 | 0 | 12.061 | ArchiCADProperties - Zones conflictuelles: Sejour cuisine
Mur-143 | Etage 3 | Peinture-01 | Mur-143 | Interieurs logements | Ch 2 | B33 | Etage 3 | 6 | Peinture-01 | 0 | 0 | 0 | 3050 | 3050 | 3050 | 3050 | 0 | 0 | 0 | 0 | 0.731963 | 0.823458 | 0 | 0 | 1499.92 | 4.57477 | 4.57477 | 0 | 1499.92 | 1499.93 | 4.57477 | 1499.92 | 4.57477 | 0.731963 | 0.823458 | 4.57477 | 4.57477 | 1499.93 | 1499.92 | 0.509974 | 1.55542 | 11550 | 0 | 1839.92 | 1.55542 | 1.55542 | 3961.51 | 14600 | 0 | 3.95302
Mur-143 | Etage 3 | Poutre | Mur-143 | Interieurs logements | Sejour cuisine | B32 | Etage 3 | 6 | Poutre; Menuiserie Plastique | 0 | 1 | 0 | 3050 | 3050 | 3050 | 3050 | 0 | 0 | 4.73 | 2200 | 1.7613 | 2.012 | 5.28 | 4.73 | 5221.32 | 10.6816 | 11.1504 | 1.6412 | 5209.32 | 3033.32 | 10.6816 | 3009.32 | 11.1504 | 2.5511 | 2.8634 | 15.9616 | 15.8884 | 5233.32 | 5209.32 | 1.02725 | 3.77331 | 11550 | 0 | 5549.32 | 5.41451 | 5.41451 | 11387.6 | 14600 | 0 | 5.68475 | ArchiCADProperties - Zones conflictuelles: Sejour cuisine
Mur-144 | Etage 3 | Peinture-01 | Mur-144 | Interieurs logements | Sejour cuisine/pl | B35 | Etage 3 | 6 | Menuiserie Plastique; Peinture-01 | 0 | 1 | 0 | 2750 | 2500 | 2500 | 2500 | 0 | 0 | 2.15 | 1000 | 1.68646 | 1.99829 | 2.4 | 2.15 | 4751.86 | 10.1641 | 10.4061 | 0.746 | 4921.86 | 3581.86 | 10.1641 | 3921.86 | 10.4061 | 2.04546 | 2.38529 | 12.6001 | 13.5351 | 4581.86 | 4921.86 | 1.27563 | 3.68475 | 11550 | 0 | 4921.86 | 4.43075 | 4.44299 | 10324.5 | 14300 | 0 | 5.14855
Mur-142 | Etage 3 | Tablette bois | Mur-142 | Interieurs logements | Sejour cuisine/pl | A31 | Etage 3 | 6 | Tablette bois | 1 | 0 | 0 | 3000 | 3000 | 3000 | 3000 | 1.8972 | 930 | 0 | 0 | 1.42038 | 1.52232 | 2.1008 | 2.1008 | 3585.27 | 9.07503 | 8.23497 | 0.714272 | 3445.26 | 2715.28 | 9.07503 | 2435.26 | 8.23497 | 1.75651 | 1.90046 | 11.1758 | 10.3358 | 3725.28 | 3445.26 | 0.875591 | 2.9427 | 11550 | 0 | 3725.28 | 3.65697 | 3.65697 | 7951 | 14550 | 0 | 4.43599
Mur-142 | etage 4 | Peinture-01 | Mur-142 | Interieurs logements | Ch 2 | B42 | etage 4 | 7 | Peinture-01 | 0 | 0 | 0 | 3050 | 3050 | 3050 | 3050 | 0 | 0 | 0 | 0 | 0.732001 | 0.823502 | 0 | 0 | 1500 | 4.57501 | 4.57501 | 0 | 1500 | 1500 | 4.57501 | 1500 | 4.57501 | 0.732001 | 0.823502 | 4.57501 | 4.57501 | 1500 | 1500 | 0.510001 | 1.5555 | 14600 | 0 | 1840 | 1.5555 | 1.5555 | 3961.67 | 17650 | 0 | 3.95309
Mur-143 | etage 4 | Peinture-01 | Mur-143 | Interieurs logements |  |  | etage 4 | 7 | Peinture-01 | 0 | 0 | 0 | 3050 | 3050 | 3050 | 3050 | 0 | 0 | 0 | 0 | 1.63516 | 1.83949 | 0 | 0 | 3350.68 | 9.85392 | 10.2192 | 0 | 3350.56 | 3350.79 | 9.85392 | 3350.56 | 10.2192 | 1.63516 | 1.83949 | 10.2199 | 10.2192 | 3350.79 | 3350.56 | 1.13923 | 3.47465 | 14600 | 0 | 3690.79 | 3.47465 | 3.47465 | 7663.19 | 17650 | 0 | 5.21203
Mur-144 | etage 4 | Peinture-01 | Mur-144 | Interieurs logements | Ch 3/sde | B44 | etage 4 | 7 | Menuiserie Plastique; Peinture-01 | 0 | 4 | 0 | 3050 | 3050 | 3050 | 3050 | 0 | 0 | 10.75 | 5000 | 5.37376 | 6.29964 | 11.75 | 10.75 | 14839.3 | 31.059 | 35.547 | 3.715 | 15179.3 | 9499.34 | 31.059 | 10179.3 | 35.547 | 7.15376 | 8.23464 | 44.223 | 46.297 | 14499.3 | 15179.3 | 3.34537 | 11.6734 | 14600 | 0 | 15179.3 | 15.3884 | 15.3884 | 30640.3 | 17650 | 0 | 11.3238
Mur-143 | etage 4 | Peinture-01 | Mur-143 | Interieurs logements |  |  | etage 4 | 7 | Peinture-01 | 0 | 0 | 0 | 3050 | 3050 | 3050 | 3050 | 0 | 0 | 0 | 0 | 2.05053 | 2.30685 | 0 | 0 | 4201.92 | 12.4498 | 12.2668 | 0 | 4201.92 | 4201.92 | 12.4498 | 4201.92 | 12.2668 | 2.05053 | 2.30685 | 12.8158 | 12.8158 | 4201.92 | 4201.92 | 1.42865 | 4.35739 | 14600 | 0 | 4541.92 | 4.35739 | 4.35739 | 9365.5 | 17650 | 0 | 5.79038
Mur-142 | etage 4 | Peinture-01 | Mur-142 | Interieurs logements | Sejour cuisine | B44 | etage 4 | 7 | Menuiserie Plastique; Peinture-01 | 0 | 4 | 0 | 3050 | 2300 | 2300 | 2300 | 0 | 0 | 12.9 | 6000 | 4.23976 | 5.07852 | 14.4 | 12.9 | 13320 | 25.073 | 28.755 | 4.476 | 13660 | 6980 | 25.073 | 7660 | 28.755 | 6.39376 | 7.40052 | 39.589 | 41.663 | 12980 | 13660 | 2.4888 | 9.31828 | 14600 | 0 | 13660 | 13.7943 | 13.8128 | 27601.7 | 17650 | 0 | 9.95068
Mur-143 | etage 4 | Peinture-01 | Mur-143 | Interieurs logements |  |  | etage 4 | 7 | Peinture-01 | 0 | 0 | 0 | 3050 | 3050 | 3050 | 3050 | 0 | 0 | 0 | 0 | 1.9232 | 1.977 | 0 | 0 | 3761.04 | 12.5078 | 10.1375 | 0 | 3421.16 | 4100.93 | 12.5078 | 3421.16 | 10.1375 | 1.9232 | 1.977 | 12.5078 | 10.4345 | 4100.93 | 3421.16 | 1.27875 | 3.9002 | 14600 | 0 | 4100.93 | 3.9002 | 3.9002 | 8483.59 | 17650 | 0 | 5.4901
Mur-143 | etage 4 | Peinture-01 | Mur-143 | Interieurs logements |  |  | etage 4 | 7 | Peinture-01 | 0 | 0 | 0 | 3050 | 0 | 0 | 0 | 0 | 0 | 0 | 0 | 2.35925 | 2.4675 | 0 | 0 | 4760.76 | 14.8673 | 12.7093 | 0 | 4420.76 | 5100.76 | 14.8673 | 4420.76 | 12.7093 | 2.35925 | 2.4675 | 15.2333 | 13.1593 | 5100.76 | 4420.76 | 1.61866 | 4.82674 | 14600 | 0 | 5100.76 | 4.82674 | 4.82674 | 10483.2 | 17650 | 0 | 6.12959
Mur-143 | etage 4 | Peinture-01 | Mur-143 | Interieurs logements |  |  | etage 4 | 7 | Peinture-01 | 0 | 0 | 0 | 3050 | 3050 | 3050 | 3050 | 0 | 0 | 0 | 0 | 0.150549 | 0.0760373 | 0 | 0 | 218.501 | 1.18493 | 0.147929 | 0 | 48.5014 | 388.501 | 1.18493 | 48.5014 | 0.147929 | 0.150549 | 0.0760373 | 1.18493 | 0.147929 | 388.501 | 48.5014 | 0.0742905 | 0.226586 | 14600 | 0 | 388.501 | 0.226586 | 0.226586 | 1257.84 | 17650 | 0 | 2.65212
Mur-143 | etage 4 | Peinture-01 | Mur-143 | Interieurs logements |  |  | etage 4 | 7 | Peinture-01 | 0 | 0 | 0 | 3050 | 3050 | 3050 | 3050 | 0 | 0 | 0 | 0 | 1.84234 | 1.97931 | 0 | 0 | 3685.3 | 11.7587 | 10.1727 | 0 | 3515.3 | 3855.3 | 11.7587 | 3515.3 | 10.1727 | 1.84234 | 1.97931 | 11.7587 | 10.7217 | 3855.3 | 3515.3 | 1.253 | 3.82165 | 14600 | 0 | 3855.3 | 3.82165 | 3.82165 | 8191.43 | 17650 | 0 | 5.00954
Mur-144 | etage 4 | Poutre | Mur-144 | Interieurs logements | Sejour cuisine/pl | B41 | etage 4 | 7 | Poutre; Menuiserie Plastique | 0 | 3 | 0 | 3050 | 2500 | 2500 | 2500 | 0 | 0 | 8.5 | 4000 | 5.86752 | 6.7706 | 9.5 | 8.5 | 15047.2 | 34.019 | 37.8385 | 2.95 | 15200.8 | 12893.6 | 34.019 | 13200.8 | 37.8385 | 7.28752 | 8.3006 | 45.4255 | 46.3625 | 14893.6 | 15200.8 | 4.43605 | 12.6381 | 14600 | 0 | 15200.8 | 15.5881 | 15.604 | 30892.7 | 17650 | 0 | 11.9579 | ArchiCADProperties - Zones conflictuelles: Ch 1/pl
Mur-143 | etage 4 | Peinture-01 | Mur-143 | Interieurs logements | Ch 2 | B42 | etage 4 | 7 | Menuiserie Plastique; Peinture-01 | 0 | 3 | 0 | 3050 | 3050 | 3050 | 3050 | 0 | 0 | 8.4 | 4000 | 4.65969 | 5.49631 | 9.4 | 8.4 | 12605.6 | 27.0711 | 31.0761 | 2.916 | 12945.6 | 12265.6 | 27.0711 | 12945.6 | 31.0761 | 6.06369 | 7.00831 | 37.4101 | 39.4841 | 12265.6 | 12945.6 | 4.2859 | 10.156 | 14600 | 0 | 12945.6 | 13.072 | 13.072 | 26172.9 | 17650 | 0 | 11.5049 | ArchiCADProperties - Zones conflictuelles: Ch 1/pl; Ch 2; Ch 2
Mur-143 | etage 4 | Poutre | Mur-143 | Interieurs logements | Sejour cuisine | B42 | etage 4 | 7 | Poutre; Menuiserie Plastique | 0 | 1 | 0 | 3050 | 2500 | 2500 | 2500 | 0 | 0 | 4.73 | 2200 | 1.72296 | 2.00324 | 5.28 | 4.73 | 5191.16 | 10.3987 | 11.1504 | 1.6412 | 5209.32 | 2973.01 | 10.3987 | 3009.32 | 11.1504 | 2.51276 | 2.85464 | 15.7777 | 15.8884 | 5173.01 | 5209.32 | 1.017 | 3.7262 | 14600 | 0 | 5549.32 | 5.3674 | 5.38324 | 11370.3 | 17650 | 0 | 5.76655 | ArchiCADProperties - Zones conflictuelles: Sejour cuisine
Mur-143 | etage 4 | Peinture-01 | Mur-143 | Interieurs logements |  |  | etage 4 | 7 | Peinture-01 | 0 | 0 | 0 | 3050 | 3050 | 3050 | 3050 | 0 | 0 | 0 | 0 | 0.880322 | 0.899192 | 0 | 0 | 1712.09 | 5.74037 | 4.72737 | 0 | 1542.09 | 1882.09 | 5.74037 | 1542.09 | 4.72737 | 0.880322 | 0.899192 | 5.74037 | 4.72737 | 1882.09 | 1542.09 | 0.60251 | 1.77951 | 14600 | 0 | 2002.09 | 1.77951 | 1.77951 | 4245.01 | 17650 | 0 | 3.75347
Mur-143 | etage 4 | Peinture-01 | Mur-143 | Interieurs logements |  |  | etage 4 | 7 | Peinture-01 | 0 | 0 | 0 | 3050 | 3050 | 3050 | 3050 | 0 | 0 | 0 | 0 | 0.547865 | 0.528959 | 0 | 0 | 1027.58 | 3.65263 | 2.68163 | 0 | 857.584 | 1197.58 | 3.65263 | 857.584 | 2.68163 | 0.547865 | 0.528959 | 3.65263 | 2.68163 | 1197.58 | 857.584 | 0.369778 | 1.07682 | 14600 | 0 | 1317.58 | 1.07682 | 1.07682 | 2876 | 17650 | 0 | 3.2952
Mur-142 | etage 4 | Peinture-01 | Mur-142 | Interieurs logements | Ch 3/sde | B44 | etage 4 | 7 | Peinture-01 | 0 | 0 | 0 | 3050 | 2500 | 2500 | 2500 | 0 | 0 | 0 | 0 | 2.46937 | 2.87786 | 0 | 0 | 5162 | 14.8116 | 14.9821 | 0 | 5332 | 4992 | 14.8116 | 5332 | 14.9821 | 2.46937 | 2.87786 | 15.2256 | 16.2626 | 4992 | 5332 | 1.75508 | 5.34723 | 14600 | 0 | 5332 | 5.34723 | 5.35299 | 11144.8 | 17650 | 0 | 6.0137
Mur-143 | etage 4 | Peinture-01 | Mur-143 | Interieurs logements | Ch 2 | B43 | etage 4 | 7 | Menuiserie Plastique; Peinture-01 | 0 | 1 | 0 | 3050 | 3050 | 3050 | 3050 | 0 | 0 | 1.935 | 900 | 0.408863 | 0.475158 | 2.16 | 1.935 | 1499.92 | 2.41477 | 2.63977 | 0.6714 | 1499.92 | 599.926 | 2.41477 | 599.924 | 4.57477 | 0.731963 | 0.823458 | 4.57477 | 4.57477 | 1499.93 | 1499.92 | 0.203974 | 0.884022 | 14600 | 0 | 1839.92 | 1.55542 | 1.55542 | 3961.51 | 17650 | 0 | 3.64702
Mur-143 | etage 4 | Poutre | Mur-143 | Interieurs logements | Sejour cuisine | B43 | etage 4 | 7 | Poutre; Menuiserie Plastique | 0 | 3 | 0 | 3050 | 2300 | 2300 | 2300 | 0 | 0 | 8.93 | 4200 | 5.02523 | 5.74694 | 9.98 | 8.93 | 13395.9 | 30.0014 | 31.9194 | 3.0992 | 13395.9 | 11195.9 | 30.0014 | 11195.9 | 31.9194 | 6.51703 | 7.35434 | 40.8574 | 40.8574 | 13395.9 | 13395.9 | 3.8066 | 10.7722 | 14600 | 0 | 13735.9 | 13.8714 | 13.8915 | 27753.4 | 17650 | 0 | 11.2943 | ArchiCADProperties - Zones conflictuelles: Sejour cuisine
Mur-144 | etage 4 | Peinture-01 | Mur-144 | Interieurs logements | Sejour cuisine | B42 | etage 4 | 7 | Peinture-01 | 0 | 0 | 0 | 3050 | 3050 | 3050 | 3050 | 0 | 0 | 0 | 0 | 5.39528 | 6.25731 | 0 | 0 | 11236.8 | 32.5475 | 35.3146 | 0 | 11578.6 | 10895.1 | 32.5475 | 11578.6 | 35.3146 | 5.39528 | 6.25731 | 33.23 | 35.3146 | 10895.1 | 11578.6 | 3.82052 | 11.6526 | 14600 | 0 | 11578.6 | 11.6526 | 11.6526 | 23439 | 17650 | 0 | 10.5854
Mur-143 | etage 4 | Peinture-01 | Mur-143 | Interieurs logements |  |  | etage 4 | 7 | Peinture-01 | 0 | 0 | 0 | 3050 | 3050 | 3050 | 3050 | 0 | 0 | 0 | 0 | 1.47413 | 1.6584 | 0 | 0 | 3020.76 | 9.21331 | 8.91632 | 0 | 3020.76 | 3020.76 | 9.21331 | 3020.76 | 8.91632 | 1.47413 | 1.6584 | 9.21331 | 9.21331 | 3020.76 | 3020.76 | 1.02706 | 3.13252 | 14600 | 0 | 3360.76 | 3.13252 | 3.13252 | 7003.18 | 17650 | 0 | 4.98719
Mur-143 | etage 4 | Peinture-01 | Mur-143 | Interieurs logements |  |  | etage 4 | 7 | Peinture-01 | 1 | 0 | 0 | 3050 | 3050 | 3050 | 3050 | 1.8972 | 930 | 0 | 0 | 0.408772 | 0.459868 | 2.1008 | 2.1008 | 1526.43 | 2.55482 | 2.55482 | 0.714272 | 1526.43 | 516.434 | 2.55482 | 516.434 | 2.55482 | 0.7449 | 0.838012 | 4.65562 | 4.65562 | 1526.43 | 1526.43 | 0.175587 | 0.86864 | 14600 | 0 | 1866.43 | 1.58291 | 1.58291 | 4014.53 | 17650 | 0 | 3.62765
Mur-143 | etage 4 | Poutre | Mur-143 | Interieurs logements | Sejour cuisine | B53 | etage 4 | 7 | Poutre; Menuiserie Plastique | 0 | 3 | 0 | 3050 | 2300 | 2300 | 2300 | 0 | 0 | 9.03 | 4200 | 5.02363 | 5.72894 | 10.08 | 9.03 | 13395.9 | 30.2014 | 31.8194 | 3.1332 | 13395.9 | 9195.87 | 30.2014 | 9195.87 | 31.8194 | 6.53143 | 7.35434 | 40.8574 | 40.8574 | 13395.9 | 13395.9 | 3.1266 | 10.7526 | 14600 | 0 | 13735.9 | 13.8858 | 13.8915 | 27753.4 | 17650 | 0 | 10.6143
Mur-142 | etage 4 | Peinture-01 | Mur-142 | Interieurs logements | Sejour cuisine | B53 | etage 4 | 7 | Métal-Inox; Menuiserie Plastique; Peinture-01 | 0 | 4 | 0 | 3050 | 2300 | 2300 | 2300 | 0 | 0 | 12.9 | 6000 | 4.26176 | 5.00652 | 13.9 | 13.3 | 13320 | 25.573 | 28.355 | 4.526 | 13660 | 6980 | 25.573 | 7660 | 28.355 | 6.39376 | 7.40052 | 39.589 | 41.663 | 12980 | 13660 | 2.4888 | 9.26828 | 14600 | 0 | 13660 | 13.7943 | 13.8128 | 27601.7 | 17650 | 0 | 9.95068
Mur-143 | etage 4 | Peinture-01 | Mur-143 | Interieurs logements |  |  | etage 4 | 7 | Menuiserie Plastique; Peinture-01 | 0 | 1 | 0 | 3050 | 3050 | 3050 | 3050 | 0 | 0 | 1.935 | 900 | 0.4089 | 0.4752 | 2.16 | 1.935 | 1500 | 2.415 | 2.64 | 0.6714 | 1500 | 600 | 2.415 | 600 | 4.575 | 0.732 | 0.8235 | 4.575 | 4.575 | 1500 | 1500 | 0.204 | 0.8841 | 14600 | 0 | 1840 | 1.5555 | 1.5555 | 3961.67 | 17650 | 0 | 3.64708
Mur-143 | etage 4 | Peinture-01 | Mur-143 | Interieurs logements |  |  | etage 4 | 7 | Menuiserie Plastique; Peinture-01 | 0 | 3 | 0 | 3050 | 3050 | 100 | 100 | 0 | 0 | 8.6 | 4000 | 4.62769 | 5.46031 | 9.6 | 8.6 | 12605.6 | 27.2701 | 30.8761 | 2.984 | 12945.6 | 8265.59 | 27.2701 | 8945.59 | 30.8761 | 6.06369 | 7.00831 | 37.4101 | 39.4761 | 12265.6 | 12945.6 | 2.9259 | 10.088 | 14600 | 0 | 12945.6 | 13.072 | 13.072 | 26172.9 | 17650 | 0 | 10.1449
Mur-144 | etage 4 | Peinture-01 | Mur-144 | Interieurs logements |  |  | etage 4 | 7 | Peinture-01 | 0 | 0 | 0 | 3050 | 3050 | 3050 | 3050 | 0 | 0 | 0 | 0 | 5.39528 | 6.25731 | 0 | 0 | 11236.8 | 32.7234 | 35.3146 | 0 | 11578.6 | 10895.1 | 32.7234 | 11578.6 | 35.3146 | 5.39528 | 6.25731 | 33.23 | 35.3146 | 10895.1 | 11578.6 | 3.82052 | 11.6526 | 14600 | 0 | 11578.6 | 11.6526 | 11.6526 | 23439 | 17650 | 0 | 10.5854
Mur-142 | etage 4 | Peinture-01 | Mur-142 | Interieurs logements |  |  | etage 4 | 7 | Peinture-01 | 0 | 0 | 0 | 3050 | 3050 | 3050 | 3050 | 0 | 0 | 0 | 0 | 0.732 | 0.8235 | 0 | 0 | 1500 | 4.575 | 4.575 | 0 | 1500 | 1500 | 4.575 | 1500 | 4.575 | 0.732 | 0.8235 | 4.575 | 4.575 | 1500 | 1500 | 0.51 | 1.5555 | 14600 | 0 | 1840 | 1.5555 | 1.5555 | 3961.67 | 17650 | 0 | 3.95308
Mur-143 | etage 4 | Poutre | Mur-143 | Interieurs logements |  |  | etage 4 | 7 | Poutre; Menuiserie Plastique | 0 | 1 | 0 | 3050 | 3050 | 3050 | 3050 | 0 | 0 | 4.73 | 2200 | 1.7388 | 2.00324 | 5.28 | 4.73 | 5191.16 | 10.4977 | 11.1504 | 1.6412 | 5209.32 | 2973.01 | 10.4977 | 3009.32 | 11.1504 | 2.5286 | 2.85464 | 15.7777 | 15.8884 | 5173.01 | 5209.32 | 1.017 | 3.74204 | 14600 | 0 | 5549.32 | 5.38324 | 5.38324 | 11370.3 | 17650 | 0 | 5.79535
Mur-138 | Etage 5 | Peinture-01 | Mur-138 | 3D |  |  | Etage 5 | 8 | Peinture-01 | 0 | 0 | 0 | 300 | 300 | 300 | 300 | 0 | 0 | 0 | 0 | 0.0732688 | 0.0824274 | 0 | 0 | 1526.43 | 0.45793 | 0.45793 | 0 | 1526.43 | 1526.43 | 0.45793 | 1526.43 | 0.45793 | 0.0732688 | 0.0824274 | 0.45793 | 0.45793 | 1526.43 | 1526.43 | 0.518988 | 0.155696 | 17650 | 3.55271e-12 | 1866.25 | 0.155696 | 0.155696 | 4014.27 | 17950 | 3.55271e-12 | 1.3264
Mur-144 | Etage 5 | Peinture-01 | Mur-144 | 3D |  |  | Etage 5 | 8 | Peinture-01 | 0 | 0 | 0 | 810 | 810 | 810 | 810 | 0 | 0 | 0 | 0 | 0.274752 | 0.259524 | 0 | 0 | 1940 | 1.7136 | 1.296 | 0 | 1600 | 2280 | 1.7136 | 1600 | 1.296 | 0.274752 | 0.259524 | 1.8468 | 1.296 | 2280 | 1600 | 0.6596 | 0.534276 | 17650 | 3.55271e-12 | 2280 | 0.534276 | 0.534276 | 4841.67 | 18460 | 3.55271e-12 | 2.09815
Mur-140 | Etage 5 | Peinture-01 | Mur-140 | 3D |  |  | Etage 5 | 8 | Peinture-01 | 0 | 0 | 0 | 300 | 300 | 300 | 300 | 0 | 0 | 0 | 0 | 0.189167 | 0.194459 | 0 | 0 | 3761.04 | 1.23028 | 1.02635 | 0 | 3421.16 | 4100.93 | 1.23028 | 3421.16 | 1.02635 | 0.189167 | 0.194459 | 1.23028 | 1.02635 | 4100.93 | 3421.16 | 1.27875 | 0.383626 | 17650 | 3.55271e-12 | 4100.93 | 0.383626 | 0.383626 | 8483.59 | 17950 | 3.55271e-12 | 2.84596
Mur-143 | Etage 5 | Peinture-01 | Mur-143 | 3D |  |  | Etage 5 | 8 | Peinture-01 | 0 | 0 | 0 | 300 | 300 | 300 | 300 | 0 | 0 | 0 | 0 | 0.0778519 | 0.0875834 | 0 | 0 | 1621.92 | 0.450574 | 0.486575 | 0 | 1961.92 | 1621.92 | 0.450574 | 1621.92 | 0.486575 | 0.0778519 | 0.0875834 | 0.486575 | 0.486575 | 1621.92 | 1621.92 | 0.551451 | 0.165435 | 17650 | 3.55271e-12 | 1621.92 | 0.165435 | 0.165435 | 3923.83 | 17950 | 3.55271e-12 | 1.3069
Mur-137 | Etage 5 | Peinture-01 | Mur-137 | 3D |  |  | Etage 5 | 8 | Peinture-01 | 0 | 0 | 0 | 810 | 810 | 810 | 810 | 0 | 0 | 0 | 0 | 0.324 | 0.339714 | 0 | 0 | 2410 | 2.0898 | 1.539 | 0 | 2240 | 2580 | 2.0898 | 2240 | 1.539 | 0.324 | 0.339714 | 2.0898 | 1.8144 | 2580 | 2240 | 0.8194 | 0.663714 | 17650 | 3.55271e-12 | 2580 | 0.663714 | 0.663714 | 5640.83 | 18460 | 3.55271e-12 | 2.30367
Mur-142 | Etage 5 | Peinture-01 | Mur-142 | 3D |  |  | Etage 5 | 8 | Peinture-01 | 0 | 0 | 0 | 300 | 300 | 300 | 300 | 0 | 0 | 0 | 0 | 0.173321 | 0.1858 | 0 | 0 | 3520.8 | 0.969274 | 1.00521 | 0 | 3350.69 | 3690.91 | 0.969274 | 3350.69 | 1.00521 | 0.173321 | 0.1858 | 1.10727 | 1.00521 | 3690.91 | 3350.69 | 1.19707 | 0.359122 | 17650 | 3.55271e-12 | 3690.91 | 0.359122 | 0.359122 | 7862.59 | 17950 | 3.55271e-12 | 2.64044
Mur-141 | Etage 5 | Peinture-01 | Mur-141 | 3D |  |  | Etage 5 | 8 | Peinture-01 | 0 | 0 | 0 | 300 | 0 | 0 | 0 | 0 | 0 | 0 | 0 | 0.231365 | 0.241927 | 0 | 0 | 4760.11 | 1.45803 | 1.29004 | 0 | 4420.14 | 5100.09 | 1.45803 | 4420.14 | 1.29004 | 0.231365 | 0.241927 | 1.49403 | 1.29004 | 5100.09 | 4420.14 | 1.57764 | 0.473292 | 17650 | 3.55271e-12 | 4980.37 | 0.473292 | 0.473292 | 10481.9 | 17950 | 0 | 3.44376
Mur-143 | Etage 5 | Poutre | Mur-143 | Interieurs logements | Ch 1 | B51 | Etage 5 | 8 | Poutre; Menuiserie Plastique | 0 | 6 | 0 | 2700 | 2700 | 2700 | 2700 | 0 | 0 | 14.9 | 7000 | 8.26544 | 9.58199 | 16.65 | 14.9 | 25074.5 | 48.3113 | 53.7033 | 5.171 | 25414.5 | 20734.5 | 48.3113 | 21414.5 | 53.7033 | 10.7544 | 12.264 | 66.7833 | 68.6193 | 24734.5 | 25414.5 | 7.16535 | 17.8474 | 17650 | 0 | 25414.5 | 23.0184 | 23.0184 | 51110.8 | 20350 | 0 | 18.2872
Mur-144 | Etage 5 | Peinture-01 | Mur-144 | Interieurs logements | Sejour cuisine | B51 | Etage 5 | 8 | Menuiserie Plastique; Peinture-01 | 0 | 2 | 0 | 2700 | 2300 | 2300 | 2300 | 0 | 0 | 3.87 | 1800 | 4.09971 | 4.81427 | 4.32 | 3.87 | 11179.2 | 24.343 | 27.216 | 1.3428 | 11519.2 | 9039.24 | 24.343 | 9719.24 | 31.086 | 4.74591 | 5.51087 | 29.266 | 31.102 | 10839.2 | 11519.2 | 3.18894 | 8.91398 | 17650 | 0 | 11519.2 | 10.2568 | 10.2625 | 23320.2 | 20350 | 0 | 9.58638
Mur-142 | Etage 5 | Peinture-01 | Mur-142 | Interieurs logements | Sejour Cuisine | B52 | Etage 5 | 8 | Menuiserie Plastique; Peinture-01 | 0 | 2 | 0 | 2700 | 2700 | 2700 | 2700 | 0 | 0 | 10.75 | 5000 | 2.95667 | 3.57587 | 12 | 10.75 | 11179.2 | 17.266 | 20.352 | 3.73 | 11519.2 | 5839.24 | 17.266 | 6519.24 | 20.352 | 4.75167 | 5.51087 | 29.266 | 31.102 | 10839.2 | 11519.2 | 2.10094 | 6.53254 | 17650 | 0 | 11519.2 | 10.2625 | 10.2625 | 23320.2 | 20350 | 0 | 8.49838
Mur-144 | Etage 5 | Poutre | Mur-144 | Interieurs logements | Ch 3 | B51 | Etage 5 | 8 | Poutre; Menuiserie Plastique | 0 | 3 | 0 | 2700 | 2700 | 2700 | 2700 | 0 | 0 | 8.55 | 4000 | 9.32644 | 10.725 | 9.55 | 8.55 | 25074.5 | 53.8057 | 60.0613 | 2.967 | 25414.5 | 21734.5 | 53.8057 | 22414.5 | 60.0613 | 10.7544 | 12.264 | 66.7833 | 68.6193 | 24734.5 | 25414.5 | 7.50535 | 20.0514 | 17650 | 0 | 25414.5 | 23.0184 | 23.0184 | 51110.8 | 20350 | 0 | 18.6272 | ArchiCADProperties - Zones conflictuelles: Terrasse
Mur-139 | Etage 5 | Peinture-01 | Mur-139 | 3D |  |  | Etage 5 | 8 | Peinture-01 | 0 | 0 | 0 | 300 | 300 | 300 | 300 | 0 | 0 | 0 | 0 | 0.144965 | 0.16308 | 0 | 0 | 3020.05 | 0.906051 | 0.905978 | 0 | 3019.93 | 3020.17 | 0.906051 | 3019.93 | 0.905978 | 0.144965 | 0.16308 | 0.906051 | 0.905978 | 3020.17 | 3019.93 | 1.02682 | 0.308045 | 17650 | 3.55271e-12 | 3359.98 | 0.308045 | 0.308045 | 7001.67 | 17950 | 3.55271e-12 | 2.34211
Mur-144 | Etage 5 | Peinture-01 | Mur-144 | Interieurs logements |  |  | Etage 5 | 8 | Menuiserie Plastique; Peinture-01 | 0 | 2 | 0 | 2700 | 2700 | 2700 | 2700 | 0 | 0 | 3.87 | 1800 | 4.10547 | 4.81427 | 4.32 | 3.87 | 11179.2 | 24.946 | 27.216 | 1.3428 | 11519.2 | 9039.24 | 24.946 | 9719.24 | 31.086 | 4.75167 | 5.51087 | 29.266 | 31.102 | 10839.2 | 11519.2 | 3.18894 | 8.91974 | 17650 | 0 | 11519.2 | 10.2625 | 10.2625 | 23320.2 | 20350 | 0 | 9.58638
Mur-143 | Etage 5 | Poutre | Mur-143 | Interieurs logements | Sejour Cuisine | B54 | Etage 5 | 8 | Poutre; Menuiserie Plastique | 0 | 6 | 0 | 2700 | 2700 | 2700 | 2700 | 0 | 0 | 15.05 | 7000 | 8.24144 | 9.55499 | 16.8 | 15.05 | 25074.5 | 48.3363 | 53.5533 | 5.222 | 25414.5 | 17734.5 | 48.3363 | 18414.5 | 53.5533 | 10.7544 | 12.264 | 66.7833 | 68.6193 | 24734.5 | 25414.5 | 6.14535 | 17.7964 | 17650 | 0 | 25414.5 | 23.0184 | 23.0184 | 51110.8 | 20350 | 0 | 17.2672
Mur-142 | Etage 5 | Peinture-01 | Mur-142 | Interieurs logements | Terrasse | B54 | Etage 5 | 8 | Menuiserie Plastique; Peinture-01 | 0 | 2 | 0 | 2700 | 2700 | 2700 | 2700 | 0 | 0 | 10.75 | 5000 | 2.95667 | 3.57587 | 12 | 10.75 | 11179.2 | 17.266 | 20.352 | 3.73 | 11519.2 | 5839.24 | 17.266 | 6519.24 | 20.352 | 4.75167 | 5.51087 | 29.266 | 31.102 | 10839.2 | 11519.2 | 2.10094 | 6.53254 | 17650 | 0 | 11519.2 | 10.2625 | 10.2625 | 23320.2 | 20350 | 0 | 8.49838
Mur-143 | Etage 5 | Peinture-01 | Mur-143 | 3D |  |  | Etage 5 | 8 | Peinture-01 | 0 | 0 | 0 | 810 | 810 | 810 | 810 | 0 | 0 | 0 | 0 | 0.324 | 0.339714 | 0 | 0 | 2410 | 2.0898 | 1.539 | 0 | 2240 | 2580 | 2.0898 | 2240 | 1.539 | 0.324 | 0.339714 | 2.0898 | 1.8144 | 2580 | 2240 | 0.8194 | 0.663714 | 17650 | 3.55271e-12 | 2580 | 0.663714 | 0.663714 | 5640.83 | 18460 | 3.55271e-12 | 2.30367
Mur-137 | Etage 5 | Peinture-01 | Mur-137 | 3D |  |  | Etage 5 | 8 | Peinture-01 | 0 | 0 | 0 | 300 | 300 | 300 | 300 | 0 | 0 | 0 | 0 | 0.173844 | 0.186399 | 0 | 0 | 3531.79 | 1.03851 | 1.00857 | 0 | 3361.88 | 3701.7 | 1.03851 | 3361.88 | 1.00857 | 0.173844 | 0.186399 | 1.11051 | 1.00857 | 3701.7 | 3361.88 | 1.20081 | 0.360243 | 17650 | 3.55271e-12 | 3701.7 | 0.360243 | 0.360243 | 7884.29 | 17950 | 3.55271e-12 | 2.64783
Mur-134 | toiture | Peinture-01 | Mur-134 | 3D | Terrasse/eng. | B52 | toiture | 9 | Peinture-01 | 0 | 0 | 0 | 1100 | 1100 | 1100 | 1100 | 0 | 0 | 0 | 0 | 1.95193 | 2.19592 | 0 | 0 | 11090.5 | 12.1996 | 11.5396 | 0 | 11270.5 | 11090.5 | 12.1996 | 11090.5 | 11.5396 | 1.95193 | 2.19592 | 12.1996 | 12.1996 | 11090.5 | 11090.5 | 3.77077 | 4.14785 | 20350 | 0 | 11090.5 | 4.14785 | 4.14785 | 22861 | 21450 | 0 | 8.28954
Mur-134 | toiture | Peinture-01 | Mur-134 | 3D | Terrasse/eng. | B52 | toiture | 9 | Peinture-01 | 0 | 0 | 0 | 1100 | 1100 | 1100 | 1100 | 0 | 0 | 0 | 0 | 1.96403 | 2.20953 | 0 | 0 | 11159.2 | 12.2752 | 11.6152 | 0 | 11519.2 | 11159.2 | 12.2752 | 11159.2 | 11.6152 | 1.96403 | 2.20953 | 12.2752 | 12.2752 | 11159.2 | 11159.2 | 3.79414 | 4.17356 | 20350 | 0 | 11159.2 | 4.17356 | 4.17356 | 22998.5 | 21450 | 0 | 8.33629
Mur-136 | toiture | Peinture-01 | Mur-136 | 3D |  |  | toiture | 9 | Peinture-01 | 0 | 0 | 0 | 1100 | 1100 | 1100 | 1100 | 0 | 0 | 0 | 0 | 0.377937 | 0.407359 | 0 | 0 | 2099.72 | 2.4087 | 2.2107 | 0 | 2369.72 | 2189.72 | 2.4087 | 2009.72 | 2.2107 | 0.377937 | 0.407359 | 2.4087 | 2.2107 | 2189.72 | 2009.72 | 0.713906 | 0.785297 | 20350 | 3.55271e-12 | 2189.72 | 0.785297 | 0.785297 | 4924.16 | 21450 | 3.55271e-12 | 2.22499
Mur-144 | Etage 5 | Peinture-01 | Mur-144 | 3D |  |  | Etage 5 | 8 | Peinture-01 | 0 | 0 | 0 | 810 | 810 | 810 | 810 | 0 | 0 | 0 | 0 | 0.20736 | 0.23328 | 0 | 0 | 1600 | 1.296 | 1.296 | 0 | 1600 | 1600 | 1.296 | 1600 | 1.296 | 0.20736 | 0.23328 | 1.296 | 1.296 | 1600 | 1600 | 0.544 | 0.44064 | 17650 | 3.55271e-12 | 1600 | 0.44064 | 0.44064 | 3880 | 18460 | 3.55271e-12 | 1.6388

# IfcWallStandardCase: mur 2cm 20 (51)
Classification: Mur (Classification ARCHICAD); Material: Empty Fill 292498448 20 mm
AC_Pset_RenovationAndPhasing - Renovation Status: Existing
ArchiCADQuantities - Nombre de trous (Nombre d'ouvertures vides): 0; Nombre de Fenêtres: 0; Nombre de Poteaux: 0; Volume des poteaux: 0 m3; Hauteur maximale de la couche de Mur sur face intérieure: 2700 mm; Hauteur minimale de la couche de Mur sur face intérieure: 2700 mm; Hauteur maximale du Mur: 2700 mm; Hauteur minimale du Mur: 2700 mm; Hauteur maximale de la couche de Mur sur face extérieure: 2700 mm; Hauteur minimale de la couche de Mur sur face extérieure: 2700 mm; Épaisseur couche d'air: 0 mm; Épaisseur de composant de mur sur face intérieure: 20 mm; Épaisseur de composant de mur sur face extérieure: 20 mm; Superficie des fenêtres: 0 m2; Largeur totale des Fenêtres: 0 mm; Épaisseur du Mur à la fin: 20 mm; Superficie des baies libres dans le Mur: 0 m2; Hauteur: 2700 mm; Largeur: 20 mm; Altitude à étage lié/étage d'implantation: 0 mm; Décalage étage d'implantation: 0 mm; Décalage supérieur: 0 mm; Épaisseur: 20 mm; Épaisseur couche isolation: 0 mm; Altitude supérieure à étage d'implantation: 2700 mm
ArchiCADProperties - Complexité de mur: Droit; Option de géométrie: Uniforme; Emplacement de ligne de référence: Face intérieure; Surface de face intérieure: Lavis blanc; Surface de face extérieure: Lavis blanc; Angle d'inclinaison interne de mur: 90 deg; Angle d'inclinaison externe de mur: 90 deg; ID de l'élément: Mur-148; Lien et ID d'élément: Mur-148; Calque: 1-Projet; Matériau de construction / Composite / Profil / Hachure: mur 2cm; Structure Composite: mur 2cm; Verrouillé: no; Type d'élément: Mur; Étage supérieur lié absolu: Non lié; Étage supérieur lié relatif: Non lié; Étage supérieur lié: Non lié; Type de structure: Composite; ID de Parent: Mur-148; Matériaux de construction (Tous): Empty Fill 292498448; Surfaces (Toutes): Lavis blanc; Angle d'inclinaison: 90 deg; Nombre de percements: 0; Surface latérale: Lavis blanc; Nom de Variante: Modèle principal; Nom de Jeu de Variantes: Modèle principal; Position: Non défini; Fonction structurelle: Non défini; Affichage sur filtre de rénovation: Tous les filtres appropriés; État de rénovation: Existant; État de Variante: Modèle principal; Jeu de Variantes: Modèle principal
Name | In | Nombre de Portes | Superficie des portes (m2) | Largeur totale des Portes (mm) | Volume de composant de mur sur face intérieure (net) (m3) = Volume de composant de mur sur face extérieure (net) (m3) = Volume (net) (m3) | Superficie analytique des ouvertures sur face intérieure (m2) | Superficie analytique des ouvertures sur face extérieure (m2) | Longueur moyenne du mur (mm) = Longueur du Mur au centre (mm) | Superficie de la face intérieure du mur (nette) (m2) | Superficie de la face extérieure du mur (nette) (m2) = Superficie en plan (m2) = Superficie inférieure (nette) (m2) | Volume analytique des ouvertures (m3) | Longueur de ligne de référence (mm) | Longueur de la face intérieure du mur (conditionnelle) (mm) | Superficie de la face intérieure du mur (conditionnelle) (m2) = Superficie de la face intérieure du mur (brute) (m2) | Longueur de la face extérieure du mur (conditionnelle) (mm) | Superficie de la face extérieure du mur (conditionnelle) (m2) = Superficie de la face extérieure du mur (brute) (m2) | Volume du composant face intérieure du mur (conditionnel) (m3) = Volume du composant face extérieure du mur (conditionnel) (m3) = Volume (conditionnel) (m3) = Volume (brut) (m3) | Longueur de Mur sur face intérieure (mm) | Longueur de Mur sur face extérieure (mm) | Superficie (m2) = Superficie supérieure (nette) (m2) | Altitude à Zéro du Projet (mm) = Altitude de Référence Niveau 1 (mm) = Altitude de Référence Niveau 2 (mm) = Altitude à niveau de la mer (mm) = Altitude inférieure à premier niveau de référence (mm) = Altitude inférieure à Zéro du projet (mm) = Altitude inférieure à niveau de la mer (mm) = Altitude inférieure à deuxième niveau de référence (mm) | Longueur 3D (mm) | Périmètre Plan (mm) | Altitude supérieure à premier niveau de référence (mm) = Altitude supérieure à Zéro du projet (mm) = Altitude supérieure à niveau de la mer (mm) = Altitude supérieure à deuxième niveau de référence (mm) | Altitude inférieure à étage d'implantation (mm) | Superficie de l'arête (nette) (m2) | Zones conflictuelles = Nom de zone liée | Numéro de zone liée | Nom d'étage d'implantation | Numéro d'étage d'implantation
Mur-148 | rdc | 1 | 1.632 | 800 | 0.027118 | 1.8304 | 1.8304 | 1180.11 | 1.3559 | 1.3559 | 0.036608 | 1180.11 | 300.11 | 3.1863 | 300.11 | 3.1863 | 0.063726 | 1180.11 | 1180.11 | 0.00600221 | 3000 | 1180.11 | 2400.22 | 5700 | 0 | 0.0960044 | Sdb | B05 | rdc | 3
Mur-148 | rdc | 1 | 1.632 | 800 | 0.027123 | 1.8304 | 1.8304 | 1180.2 | 1.3559 | 1.3564 | 0.036608 | 1180.11 | 300.11 | 3.1863 | 300.297 | 3.1868 | 0.063731 | 1180.11 | 1180.3 | 0.00600408 | 3000 | 1180.3 | 2400.41 | 5700 | 0 | 0.0960105 | Sdb | B02 | rdc | 3
Mur-148 | rdc | 1 | 1.632 | 800 | 0.0271188 | 1.8304 | 1.8304 | 1180.13 | 1.3559 | 1.35598 | 0.036608 | 1180.11 | 300.11 | 3.1863 | 300.142 | 3.18638 | 0.0637268 | 1180.11 | 1180.14 | 0.00600252 | 3000 | 1180.14 | 2400.25 | 5700 | 0 | 0.0960051 | Sdb | B01 | rdc | 3
Mur-148 | rdc | 0 | 0 | 0 | 0.04932 | 0 | 0 | 900 | 2.466 | 2.466 | 0 | 1080 | 900 | 2.466 | 900 | 2.466 | 0.04932 | 900 | 900 | 0.0216 | 3000 | 1080 | 1840 | 5700 | 0 | 0.1512 | Sde | B04 | rdc | 3
Mur-148 | rdc | 1 | 1.632 | 800 | 0.027118 | 1.8304 | 1.8304 | 1180.11 | 1.3559 | 1.3559 | 0.036608 | 1180.11 | 300.11 | 3.1863 | 300.11 | 3.1863 | 0.063726 | 1180.11 | 1180.11 | 0.00600221 | 3000 | 1180.11 | 2400.22 | 5700 | 0 | 0.0960044 | Sde | B04 | rdc | 3
Mur-148 | rdc | 1 | 1.632 | 800 | 0.027118 | 1.8304 | 1.8304 | 1180.11 | 1.3559 | 1.3559 | 0.036608 | 1180.11 | 300.11 | 3.1863 | 300.11 | 3.1863 | 0.063726 | 1180.11 | 1180.11 | 0.00600221 | 3000 | 1180.11 | 2400.22 | 5700 | 0 | 0.0960044 | Sdb | A04 | rdc | 3
Mur-148 | rdc | 1 | 1.632 | 800 | 0.027118 | 1.8304 | 1.8304 | 1180.11 | 1.3559 | 1.3559 | 0.036608 | 1180.11 | 300.11 | 3.1863 | 300.11 | 3.1863 | 0.063726 | 1180.11 | 1180.11 | 0.00600221 | 3000 | 1180.11 | 2400.22 | 5700 | 0 | 0.0960044 | Sdb/pl | A02 | rdc | 3
Mur-148 | rdc | 0 | 0 | 0 | 0.0475541 | 0 | 0 | 880.631 | 2.3777 | 2.3777 | 0 | 880.631 | 880.631 | 2.3777 | 880.631 | 2.3777 | 0.0475541 | 880.631 | 880.631 | 0.0176126 | 3000 | 880.631 | 1801.26 | 5700 | 0 | 0.143225 | Sdb/pl | A02 | rdc | 3
Mur-148 | rdc | 1 | 1.632 | 800 | 0.027118 | 1.8304 | 1.8304 | 1180.11 | 1.3559 | 1.3559 | 0.036608 | 1180.11 | 300.11 | 3.1863 | 300.109 | 3.1863 | 0.063726 | 1180.11 | 1180.11 | 0.00600221 | 3000 | 1180.11 | 2400.22 | 5700 | 0 | 0.0960044 | Sdb | A03 | rdc | 3
Mur-148 | rdc | 0 | 0 | 0 | 0.0468421 | 0 | 0 | 867.446 | 2.34211 | 2.34211 | 0 | 867.446 | 867.446 | 2.34211 | 867.446 | 2.34211 | 0.0468421 | 867.446 | 867.446 | 0.0173489 | 3000 | 867.446 | 1774.89 | 5700 | 0 | 0.142698 | Sdb | A04 | rdc | 3
Mur-148 | rdc | 1 | 1.632 | 800 | 0.027118 | 1.8304 | 1.8304 | 1180.11 | 1.3559 | 1.3559 | 0.036608 | 1180.11 | 300.111 | 3.1863 | 300.112 | 3.1863 | 0.063726 | 1180.11 | 1180.11 | 0.00600221 | 3000 | 1180.11 | 2400.22 | 5700 | 0 | 0.0960044 | Sdb | A01 | rdc | 3
Mur-148 | Etage1 | 1 | 1.632 | 800 | 0.027118 | 1.8304 | 1.8304 | 1180.11 | 1.3559 | 1.3559 | 0.036608 | 1180.11 | 300.11 | 3.1863 | 300.11 | 3.1863 | 0.063726 | 1180.11 | 1180.11 | 0.00600221 | 5750 | 1180.11 | 2400.22 | 8450 | 0 | 0.0960044 | Sde | B11 | Etage1 | 4
Mur-148 | Etage1 | 1 | 1.632 | 800 | 0.027118 | 1.8304 | 1.8304 | 1180.11 | 1.3559 | 1.3559 | 0.036608 | 1180.11 | 300.11 | 3.1863 | 300.11 | 3.1863 | 0.063726 | 1180.11 | 1180.11 | 0.00600221 | 5750 | 1180.11 | 2400.22 | 8450 | 0 | 0.0960044 | Sde | B16 | Etage1 | 4
Mur-148 | Etage1 | 1 | 1.632 | 800 | 0.027118 | 1.8304 | 1.8304 | 1180.11 | 1.3559 | 1.3559 | 0.036608 | 1180.11 | 300.11 | 3.1863 | 300.11 | 3.1863 | 0.063726 | 1180.11 | 1180.11 | 0.00600221 | 5750 | 1180.11 | 2400.22 | 8450 | 0 | 0.0960044 | Sde | B15 | Etage1 | 4
Mur-148 | Etage1 | 1 | 1.632 | 800 | 0.0271188 | 1.8304 | 1.8304 | 1180.13 | 1.3559 | 1.35598 | 0.036608 | 1180.11 | 300.11 | 3.1863 | 300.142 | 3.18638 | 0.0637268 | 1180.11 | 1180.14 | 0.00600252 | 5750 | 1180.14 | 2400.25 | 8450 | 0 | 0.0960051 | Sde | B13 | Etage1 | 4
Mur-148 | Etage1 | 0 | 0 | 0 | 0.04932 | 0 | 0 | 900 | 2.466 | 2.466 | 0 | 1080 | 900 | 2.466 | 900 | 2.466 | 0.04932 | 900 | 900 | 0.0216 | 5750 | 1080 | 1840 | 8450 | 0 | 0.1512 | Sde | B15 | Etage1 | 4
Mur-148 | Etage1 | 1 | 1.632 | 800 | 0.0271189 | 1.8304 | 1.8304 | 1180.13 | 1.3559 | 1.35598 | 0.0366081 | 1180.11 | 300.11 | 3.1863 | 300.142 | 3.18638 | 0.0637269 | 1180.11 | 1180.14 | 0.00600254 | 5750 | 1180.14 | 2400.25 | 8450 | -8.88178e-13 | 0.0960054 | Sde | B12 | Etage1 | 4
Mur-148 | Etage1 | 0 | 0 | 0 | 0.0468421 | 0 | 0 | 867.446 | 2.34211 | 2.34211 | 0 | 867.446 | 867.446 | 2.34211 | 867.446 | 2.34211 | 0.0468421 | 867.446 | 867.446 | 0.0173489 | 5750 | 867.446 | 1774.89 | 8450 | 0 | 0.142698 | Sdb | A14 | Etage1 | 4
Mur-148 | Etage1 | 1 | 1.632 | 800 | 0.027118 | 1.8304 | 1.8304 | 1180.11 | 1.3559 | 1.3559 | 0.036608 | 1180.11 | 300.11 | 3.1863 | 300.11 | 3.1863 | 0.063726 | 1180.11 | 1180.11 | 0.00600221 | 5750 | 1180.11 | 2400.22 | 8450 | 0 | 0.0960044 | Sde | A15 | Etage1 | 4
Mur-148 | Etage1 | 1 | 1.632 | 800 | 0.027118 | 1.8304 | 1.8304 | 1180.11 | 1.3559 | 1.3559 | 0.036608 | 1180.11 | 300.11 | 3.1863 | 300.11 | 3.1863 | 0.063726 | 1180.11 | 1180.11 | 0.00600221 | 5750 | 1180.11 | 2400.22 | 8450 | 0 | 0.0960044 | Sdb | A14 | Etage1 | 4
Mur-148 | Etage1 | 1 | 1.632 | 800 | 0.027118 | 1.8304 | 1.8304 | 1180.11 | 1.3559 | 1.3559 | 0.036608 | 1180.11 | 300.11 | 3.1863 | 300.109 | 3.1863 | 0.063726 | 1180.11 | 1180.11 | 0.00600221 | 5750 | 1180.11 | 2400.22 | 8450 | 0 | 0.0960044 | Sde | A13 | Etage1 | 4
Mur-148 | Etage1 | 0 | 0 | 0 | 0.0475541 | 0 | 0 | 880.631 | 2.3777 | 2.3777 | 0 | 880.631 | 880.631 | 2.3777 | 880.631 | 2.3777 | 0.0475541 | 880.631 | 880.631 | 0.0176126 | 5750 | 880.631 | 1801.26 | 8450 | 0 | 0.143225 | Sde | A12 | Etage1 | 4
Mur-148 | Etage1 | 1 | 1.632 | 800 | 0.027118 | 1.8304 | 1.8304 | 1180.11 | 1.3559 | 1.3559 | 0.036608 | 1180.11 | 300.11 | 3.1863 | 300.11 | 3.1863 | 0.063726 | 1180.11 | 1180.11 | 0.00600221 | 5750 | 1180.11 | 2400.22 | 8450 | 0 | 0.0960044 | Sde | A12 | Etage1 | 4
Mur-148 | Etage1 | 1 | 1.632 | 800 | 0.027118 | 1.8304 | 1.8304 | 1180.11 | 1.3559 | 1.3559 | 0.036608 | 1180.11 | 300.11 | 3.1863 | 300.11 | 3.1863 | 0.063726 | 1180.11 | 1180.11 | 0.00600221 | 5750 | 1180.11 | 2400.22 | 8450 | 0 | 0.0960044 | Sde | A11 | Etage1 | 4
Mur-148 | Etage 2 | 1 | 1.632 | 800 | 0.027118 | 1.8304 | 1.8304 | 1180.11 | 1.3559 | 1.3559 | 0.036608 | 1180.11 | 300.11 | 3.1863 | 300.11 | 3.1863 | 0.063726 | 1180.11 | 1180.11 | 0.00600221 | 8500 | 1180.11 | 2400.22 | 11200 | 0 | 0.0960044 | Sde | A25 | Etage 2 | 5
Mur-148 | Etage 2 | 1 | 1.632 | 800 | 0.027118 | 1.8304 | 1.8304 | 1180.11 | 1.3559 | 1.3559 | 0.036608 | 1180.11 | 300.11 | 3.1863 | 300.11 | 3.1863 | 0.063726 | 1180.11 | 1180.11 | 0.00600221 | 8500 | 1180.11 | 2400.22 | 11200 | 0 | 0.0960044 | Sde | A23 | Etage 2 | 5
Mur-148 | Etage 2 | 0 | 0 | 0 | 0.0468421 | 0 | 0 | 867.446 | 2.34211 | 2.34211 | 0 | 867.446 | 867.446 | 2.34211 | 867.446 | 2.34211 | 0.0468421 | 867.446 | 867.446 | 0.0173489 | 8500 | 867.446 | 1774.89 | 11200 | 0 | 0.142698 | Sde | A24 | Etage 2 | 5
Mur-148 | Etage 2 | 0 | 0 | 0 | 0.0475541 | 0 | 0 | 880.631 | 2.3777 | 2.3777 | 0 | 880.631 | 880.631 | 2.3777 | 880.631 | 2.3777 | 0.0475541 | 880.631 | 880.631 | 0.0176126 | 8500 | 880.631 | 1801.26 | 11200 | 0 | 0.143225 | Sde | A22 | Etage 2 | 5
Mur-148 | Etage 2 | 1 | 1.632 | 800 | 0.027118 | 1.8304 | 1.8304 | 1180.11 | 1.3559 | 1.3559 | 0.036608 | 1180.11 | 300.11 | 3.1863 | 300.11 | 3.1863 | 0.063726 | 1180.11 | 1180.11 | 0.00600221 | 8500 | 1180.11 | 2400.22 | 11200 | 0 | 0.0960044 | Sde | A22 | Etage 2 | 5
Mur-148 | Etage 2 | 1 | 1.632 | 800 | 0.027118 | 1.8304 | 1.8304 | 1180.11 | 1.3559 | 1.3559 | 0.036608 | 1180.11 | 300.11 | 3.1863 | 300.11 | 3.1863 | 0.063726 | 1180.11 | 1180.11 | 0.00600221 | 8500 | 1180.11 | 2400.22 | 11200 | 0 | 0.0960044 | Sde | A21 | Etage 2 | 5
Mur-148 | Etage 2 | 1 | 1.632 | 800 | 0.027118 | 1.8304 | 1.8304 | 1180.11 | 1.3559 | 1.3559 | 0.036608 | 1180.11 | 300.11 | 3.1863 | 300.11 | 3.1863 | 0.063726 | 1180.11 | 1180.11 | 0.00600221 | 8500 | 1180.11 | 2400.22 | 11200 | 0 | 0.0960044 | Sde | B26 | Etage 2 | 5
Mur-148 | Etage 2 | 1 | 1.632 | 800 | 0.0271188 | 1.8304 | 1.8304 | 1180.13 | 1.3559 | 1.35598 | 0.036608 | 1180.11 | 300.11 | 3.1863 | 300.142 | 3.18638 | 0.0637268 | 1180.11 | 1180.14 | 0.00600252 | 8500 | 1180.14 | 2400.25 | 11200 | 0 | 0.0960051 | Sde | B23 | Etage 2 | 5
Mur-148 | Etage 2 | 1 | 1.632 | 800 | 0.0271189 | 1.8304 | 1.8304 | 1180.13 | 1.3559 | 1.35598 | 0.0366081 | 1180.11 | 300.11 | 3.1863 | 300.142 | 3.18638 | 0.0637269 | 1180.11 | 1180.14 | 0.00600254 | 8500 | 1180.14 | 2400.25 | 11200 | 0 | 0.0960054 | Sde | B22 | Etage 2 | 5
Mur-148 | Etage 2 | 1 | 1.632 | 800 | 0.027118 | 1.8304 | 1.8304 | 1180.11 | 1.3559 | 1.3559 | 0.036608 | 1180.11 | 300.11 | 3.1863 | 300.11 | 3.1863 | 0.063726 | 1180.11 | 1180.11 | 0.00600221 | 8500 | 1180.11 | 2400.22 | 11200 | 0 | 0.0960044 | Sde | A24 | Etage 2 | 5
Mur-148 | Etage 2 | 1 | 1.632 | 800 | 0.027118 | 1.8304 | 1.8304 | 1180.11 | 1.3559 | 1.3559 | 0.036608 | 1180.11 | 300.11 | 3.1863 | 300.11 | 3.1863 | 0.063726 | 1180.11 | 1180.11 | 0.00600221 | 8500 | 1180.11 | 2400.22 | 11200 | 0 | 0.0960044 | Sde | B21 | Etage 2 | 5
Mur-148 | Etage 3 | 1 | 1.632 | 800 | 0.027118 | 1.8304 | 1.8304 | 1180.11 | 1.3559 | 1.3559 | 0.036608 | 1180.11 | 300.11 | 3.1863 | 300.11 | 3.1863 | 0.063726 | 1180.11 | 1180.11 | 0.00600221 | 11550 | 1180.11 | 2400.22 | 14250 | 0 | 0.0960044 | Sde | B34 | Etage 3 | 6
Mur-148 | Etage 3 | 1 | 1.632 | 800 | 0.027118 | 1.8304 | 1.8304 | 1180.11 | 1.3559 | 1.3559 | 0.036608 | 1180.11 | 300.11 | 3.1863 | 300.11 | 3.1863 | 0.063726 | 1180.11 | 1180.11 | 0.00600221 | 11550 | 1180.11 | 2400.22 | 14250 | 0 | 0.0960044 | Sde | B31 | Etage 3 | 6
Mur-148 | Etage 3 | 1 | 1.632 | 800 | 0.0271188 | 1.8304 | 1.8304 | 1180.13 | 1.3559 | 1.35598 | 0.036608 | 1180.11 | 300.11 | 3.1863 | 300.142 | 3.18638 | 0.0637268 | 1180.11 | 1180.14 | 0.00600252 | 11550 | 1180.14 | 2400.25 | 14250 | 0 | 0.0960051 | Sde | B33 | Etage 3 | 6
Mur-148 | Etage 3 | 0 | 0 | 0 | 0.0479807 | 0 | 0 | 888.531 | 2.42601 | 2.37206 | 0 | 1078.52 | 898.521 | 2.42601 | 878.541 | 2.37206 | 0.0479807 | 898.521 | 878.541 | 0.0177706 | 11550 | 898.524 | 1825.33 | 14250 | 0 | 0.165876 | Sde/pl | A34 | Etage 3 | 6
Mur-148 | Etage 3 | 1 | 1.632 | 800 | 0.0276923 | 1.8304 | 1.8304 | 1190.75 | 1.38462 | 1.38462 | 0.036608 | 1290.75 | 310.746 | 3.21502 | 310.746 | 3.21502 | 0.0643003 | 1190.75 | 1190.75 | 0.00621493 | 11550 | 1190.75 | 2421.49 | 14250 | 0 | 0.0964299 | Sde | B35 | Etage 3 | 6
Mur-148 | Etage 3 | 1 | 1.632 | 800 | 0.0271189 | 1.8304 | 1.8304 | 1180.13 | 1.3559 | 1.35598 | 0.0366081 | 1180.11 | 300.11 | 3.1863 | 300.142 | 3.18638 | 0.0637269 | 1180.11 | 1180.14 | 0.00600254 | 11550 | 1180.14 | 2400.25 | 14250 | 0 | 0.0960054 | Sde | B32 | Etage 3 | 6
Mur-148 | Etage 3 | 1 | 1.632 | 800 | 0.0269941 | 1.8304 | 1.78884 | 1170.12 | 1.3559 | 1.34351 | 0.0361924 | 1180.11 | 300.11 | 3.1863 | 300.11 | 3.13234 | 0.0631864 | 1180.11 | 1160.13 | 0.00600221 | 11550 | 1180.11 | 2388.51 | 14250 | 0 | 0.100933 | Sde/pl | A34 | Etage 3 | 6
Mur-148 | Etage 3 | 1 | 1.632 | 800 | 0.0271183 | 1.8304 | 1.8304 | 1180.12 | 1.3559 | 1.35594 | 0.036608 | 1180.11 | 300.11 | 3.1863 | 300.124 | 3.18634 | 0.0637263 | 1180.11 | 1180.12 | 0.00600235 | 11550 | 1180.12 | 2400.23 | 14250 | 0 | 0.0960047 | Sde | A33 | Etage 3 | 6
Mur-148 | Etage 3 | 1 | 1.632 | 800 | 0.027118 | 1.8304 | 1.8304 | 1180.11 | 1.3559 | 1.3559 | 0.036608 | 1180.11 | 300.11 | 3.1863 | 300.11 | 3.1863 | 0.063726 | 1180.11 | 1180.11 | 0.00600221 | 11550 | 1180.11 | 2400.22 | 14250 | 0 | 0.0960044 | Sde | A32 | Etage 3 | 6
Mur-148 | etage 4 | 1 | 1.632 | 800 | 0.0271181 | 1.8304 | 1.8304 | 1180.13 | 1.3559 | 1.35598 | 0.0366075 | 1180.11 | 300.11 | 3.1863 | 300.142 | 3.18638 | 0.0637256 | 1180.11 | 1180.14 | 0.00600233 | 14600 | 1180.14 | 2400.25 | 17300 | 0 | 0.0960025 | Sde | B42 | etage 4 | 7
Mur-148 | etage 4 | 1 | 1.632 | 800 | 0.0271188 | 1.8304 | 1.8304 | 1180.13 | 1.3559 | 1.35598 | 0.036608 | 1180.11 | 300.11 | 3.1863 | 300.142 | 3.18638 | 0.0637268 | 1180.11 | 1180.14 | 0.00600252 | 14600 | 1180.14 | 2400.25 | 17300 | 0 | 0.0960051 | Sde | B43 | etage 4 | 7
Mur-148 | etage 4 | 1 | 1.632 | 800 | 0.0298219 | 1.8304 | 1.8304 | 1230.18 | 1.49109 | 1.49109 | 0.036608 | 1230.18 | 350.182 | 3.32149 | 350.182 | 3.32149 | 0.0664299 | 1230.18 | 1230.18 | 0.00700365 | 14600 | 1230.18 | 2500.36 | 17300 | 0 | 0.139607 | Sde | B41 | etage 4 | 7
Mur-148 | etage 4 | 1 | 1.632 | 800 | 0.027118 | 1.8304 | 1.8304 | 1180.11 | 1.3559 | 1.3559 | 0.036608 | 1180.11 | 300.11 | 3.1863 | 300.11 | 3.1863 | 0.063726 | 1180.11 | 1180.11 | 0.00600221 | 14600 | 1180.11 | 2400.22 | 17300 | 0 | 0.0960044 | Sde 2 | B44 | etage 4 | 7
Mur-148 | etage 4 | 1 | 1.632 | 800 | 0.027118 | 1.8304 | 1.8304 | 1180.11 | 1.3559 | 1.3559 | 0.036608 | 1180.11 | 300.11 | 3.1863 | 300.11 | 3.1863 | 0.063726 | 1180.11 | 1180.11 | 0.00600221 | 14600 | 1180.11 | 2400.22 | 17300 | 0 | 0.0960044 | Ch 3/sde | B44 | etage 4 | 7
Mur-148 | Etage 5 | 1 | 1.326 | 650 | 0.033358 | 1.5184 | 1.5184 | 1180.11 | 1.6679 | 1.6679 | 0.030368 | 1180.11 | 450.11 | 3.1863 | 450.11 | 3.1863 | 0.063726 | 1180.11 | 1180.11 | 0.00900221 | 17650 | 1180.11 | 2400.22 | 20350 | 0 | 0.0990044 | sde | B51 | Etage 5 | 8
Mur-148 | Etage 5 | 1 | 1.632 | 800 | 0.027258 | 1.8304 | 1.8304 | 1180.11 | 1.3699 | 1.3559 | 0.036608 | 1180.11 | 300.11 | 3.2003 | 300.11 | 3.1863 | 0.063866 | 1180.11 | 1180.11 | 0.00670221 | 17650 | 1250.11 | 2400.22 | 20350 | 0 | 0.107965 | Sde 2 | B52 | Etage 5 | 8

# IfcWallStandardCase: mur 4cm 40 (22)
In: rdc
Classification: Mur (Classification ARCHICAD); Material: Empty Fill 292498448 40 mm
AC_Pset_RenovationAndPhasing - Renovation Status: Existing
ArchiCADProperties - Complexité de mur: Droit; Option de géométrie: Uniforme; Emplacement de ligne de référence: Face intérieure; Surface de face intérieure: Peinture-01; Surface de face extérieure: Peinture-01; Angle d'inclinaison interne de mur: 90 deg; Angle d'inclinaison externe de mur: 90 deg; Calque: 1-Projet; Matériau de construction / Composite / Profil / Hachure: mur 4cm; Structure Composite: mur 4cm; Verrouillé: no; Nom d'étage d'implantation: rdc; Numéro d'étage d'implantation: 3; Type d'élément: Mur; Étage supérieur lié absolu: Non lié; Étage supérieur lié relatif: Non lié; Étage supérieur lié: Non lié; Type de structure: Composite; Matériaux de construction (Tous): Empty Fill 292498448; Surfaces (Toutes): Peinture-01; Angle d'inclinaison: 90 deg; Nombre de percements: 0; Surface latérale: Peinture-01; Nom de Variante: Modèle principal; Nom de Jeu de Variantes: Modèle principal; Position: Non défini; Fonction structurelle: Non défini; Affichage sur filtre de rénovation: Tous les filtres appropriés; État de rénovation: Existant; État de Variante: Modèle principal; Jeu de Variantes: Modèle principal
ArchiCADQuantities - Nombre de Portes: 0; Nombre de trous (Nombre d'ouvertures vides): 0; Nombre de Fenêtres: 0; Nombre de Poteaux: 0; Volume des poteaux: 0 m3; Hauteur maximale de la couche de Mur sur face intérieure: 100 mm; Hauteur maximale du Mur: 100 mm; Hauteur maximale de la couche de Mur sur face extérieure: 100 mm; Épaisseur couche d'air: 0 mm; Superficie des portes: 0 m2; Largeur totale des Portes: 0 mm; Épaisseur de composant de mur sur face intérieure: 40 mm; Épaisseur de composant de mur sur face extérieure: 40 mm; Superficie des fenêtres: 0 m2; Largeur totale des Fenêtres: 0 mm; Superficie analytique des ouvertures sur face intérieure: 0 m2; Superficie analytique des ouvertures sur face extérieure: 0 m2; Volume analytique des ouvertures: 0 m3; Épaisseur du Mur à la fin: 40 mm; Superficie des baies libres dans le Mur: 0 m2; Hauteur: 100 mm; Largeur: 40 mm; Altitude à Zéro du Projet: 900 mm; Altitude de Référence Niveau 1: 900 mm; Altitude de Référence Niveau 2: 900 mm; Altitude à niveau de la mer: 900 mm; Altitude à étage lié/étage d'implantation: -2100 mm; Décalage étage d'implantation: -2100 mm; Décalage supérieur: 0 mm; Épaisseur: 40 mm; Épaisseur couche isolation: 0 mm; Altitude supérieure à premier niveau de référence: 1000 mm; Altitude supérieure à étage d'implantation: -2000 mm; Altitude supérieure à Zéro du projet: 1000 mm; Altitude supérieure à niveau de la mer: 1000 mm; Altitude supérieure à deuxième niveau de référence: 1000 mm; Altitude inférieure à premier niveau de référence: 900 mm; Altitude inférieure à étage d'implantation: -2100 mm; Altitude inférieure à Zéro du projet: 900 mm; Altitude inférieure à niveau de la mer: 900 mm; Altitude inférieure à deuxième niveau de référence: 900 mm
Name | ID de l'élément = Lien et ID d'élément = ID de Parent | Hauteur minimale de la couche de Mur sur face intérieure (mm) = Hauteur minimale du Mur (mm) = Hauteur minimale de la couche de Mur sur face extérieure (mm) | Volume de composant de mur sur face intérieure (net) (m3) = Volume de composant de mur sur face extérieure (net) (m3) = Volume du composant face intérieure du mur (conditionnel) (m3) = Volume du composant face extérieure du mur (conditionnel) (m3) = Volume (net) (m3) = Volume (conditionnel) (m3) = Volume (brut) (m3) | Longueur moyenne du mur (mm) = Longueur du Mur au centre (mm) | Superficie de la face intérieure du mur (nette) (m2) = Superficie de la face intérieure du mur (conditionnelle) (m2) | Superficie de la face extérieure du mur (nette) (m2) = Superficie de la face extérieure du mur (conditionnelle) (m2) = Superficie de la face extérieure du mur (brute) (m2) = Superficie en plan (m2) = Superficie inférieure (nette) (m2) | Longueur de ligne de référence (mm) | Longueur de la face intérieure du mur (conditionnelle) (mm) = Longueur de Mur sur face intérieure (mm) | Longueur de la face extérieure du mur (conditionnelle) (mm) = Longueur de Mur sur face extérieure (mm) | Superficie de la face intérieure du mur (brute) (m2) | Superficie (m2) = Superficie supérieure (nette) (m2) | Longueur 3D (mm) | Périmètre Plan (mm) | Superficie de l'arête (nette) (m2)
Mur-159 | Mur-159 | 100 | 0.0200801 | 5020.02 | 0.5 | 0.504003 | 5000 | 5000 | 5040.03 | 0.5 | 0.200801 | 5040.03 | 10136.6 | 0.41126
Mur-161 | Mur-161 | 100 | 0.02 | 5000 | 0.5 | 0.5 | 5000 | 5000 | 5000 | 0.5 | 0.2 | 5040 | 10113.1 | 0.411314
Mur-162 | Mur-162 | 100 | 0.04336 | 10840 | 1.08 | 1.088 | 10800 | 10800 | 10880 | 1.08 | 0.4336 | 10880 | 21793.1 | 0.878514
Mur-156 | Mur-156 | 100 | 0.01206 | 3015 | 0.306 | 0.297 | 3060 | 3060 | 2970 | 0.306 | 0.1206 | 3060 | 6150.6 | 0.25326
Mur-154 | Mur-154 | 100 | 0.0246 | 6150 | 0.615 | 0.615 | 6150 | 6150 | 6150 | 0.615 | 0.246 | 6190 | 12413.1 | 0.503314
Mur-153 | Mur-153 | 100 | 0.03364 | 8410 | 0.837 | 0.845 | 8370 | 8370 | 8450 | 0.837 | 0.3364 | 8450 | 16933.1 | 0.684114
Mur-155 | Mur-155 | 100 | 0.0208482 | 5212.06 | 0.523206 | 0.519206 | 5232.06 | 5232.06 | 5192.06 | 0.523206 | 0.208482 | 5232.06 | 10520.7 | 0.426621
Mur-160 | Mur-160 | 100 | 0.00555161 | 1387.9 | 0.14279 | 0.13479 | 1427.9 | 1427.9 | 1347.9 | 0.14279 | 0.0555161 | 1427.9 | 2888.94 | 0.122346
Mur-158 | Mur-158 | 100 | 0.05212 | 13030 | 1.293 | 1.305 | 13060 | 13010 | 13050 | 1.301 | 0.5212 | 13050 | 26156.6 | 1.05206
Mur-164 | Mur-164 | 100 | 0.0130188 | 3254.71 | 0.325471 | 0.325471 | 3254.71 | 3254.71 | 3254.71 | 0.325471 | 0.130188 | 3294.71 | 6622.55 | 0.27169
Mur-159 | Mur-159 | 100 | 0.01992 | 4980 | 0.5 | 0.496 | 5000 | 5000 | 4960 | 0.5 | 0.1992 | 5000 | 10056.6 | 0.408057
Mur-163 | Mur-163 | 100 | 0.02 | 5000.01 | 0.5 | 0.500002 | 5000 | 5000 | 5000.02 | 0.5 | 0.2 | 5040 | 10113.1 | 0.411313
Mur-166 | Mur-166 | 100 | 0.02 | 5000 | 0.5 | 0.5 | 5000 | 5000 | 5000 | 0.5 | 0.2 | 5040 | 10113.1 | 0.411314
Mur-157 | Mur-157 | 0 | 0.0244893 | 6130 | 0.614234 | 0.610231 | 6150 | 6150 | 6110 | 0.614234 | 0.244893 | 6142.34 | 12356.6 | 0.495443
Mur-167 | Mur-167 | 100 | 0.00467764 | 1169.41 | 0.129941 | 0.103941 | 1299.41 | 1299.41 | 1039.41 | 0.129941 | 0.0467764 | 1299.41 | 2618.99 | 0.12157
Mur-165 | Mur-165 | 100 | 0.02016 | 5040 | 0.5 | 0.508 | 5000 | 5000 | 5080 | 0.5 | 0.2016 | 5080 | 10193.1 | 0.414514
Mur-152 | Mur-152 | 100 | 0.02 | 5000 | 0.5 | 0.5 | 5000 | 5000 | 5000 | 0.5 | 0.2 | 5040 | 10113.1 | 0.411314
Mur-163 | Mur-163 | 100 | 0.0031141 | 778.526 | 0.0778519 | 0.0778533 | 778.519 | 778.519 | 778.533 | 0.0778519 | 0.031141 | 818.509 | 1670.17 | 0.0735934
Mur-163 | Mur-163 | 100 | 0.0144236 | 3605.89 | 0.35859 | 0.362589 | 3585.9 | 3585.9 | 3625.89 | 0.35859 | 0.144236 | 3625.89 | 7308.34 | 0.298127
Mur-163 | Mur-163 | 100 | 0.000305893 | 76.4732 | 0.00764732 | 0.00764732 | 76.4732 | 76.4732 | 76.4732 | 0.00764732 | 0.00305893 | 76.4732 | 232.946 | 0.0141179
Mur-164 | Mur-164 | 100 | 0.00581555 | 1453.89 | 0.147389 | 0.143389 | 1473.89 | 1473.89 | 1433.89 | 0.147389 | 0.0581555 | 1473.89 | 3004.34 | 0.125968
Mur-167 | Mur-167 | 100 | 0.00523397 | 1308.49 | 0.143849 | 0.117849 | 1438.49 | 1438.49 | 1178.49 | 0.143849 | 0.0523397 | 1438.49 | 2897.16 | 0.132697

# IfcWindow: Fenêtre 27 (3)
Type - OperationType: DOUBLE_PANEL_HORIZONTAL; ParameterTakesPrecedence: no; Sizeable: no
Type - Window Lining Properties - LiningDepth: 50 mm; LiningThickness: 50 mm; TransomThickness: 50 mm; FirstTransomOffset: 0.428571
Type - Window Panel Properties - Panel 1 - OperationType: SIDEHUNGLEFTHAND; PanelPosition: TOP; FrameDepth: 50 mm; FrameThickness: 50 mm
Type - Window Panel Properties - Panel 2 - OperationType: FIXEDCASEMENT; PanelPosition: BOTTOM
OverallHeight: 2100 mm; Classification: Fenêtre (Classification ARCHICAD)
ArchiCADProperties - Structure de Mur: isol int 18+16 0018356637; Orientation: G; Nom élément de bibliothèque d'ouverture: Fenêtre 27; Index hachure latérale ouverture: 100 %; ID de l'élément: Fen-133; Lien et ID d'élément: Fen-133; Calque: Interieurs logements; Nom Élément de Bibliothèque: Fenêtre 27; Matériau de construction / Composite / Profil / Hachure: 100 %; Type Hachure: 100 %; Verrouillé: no; Type d'élément: Fenêtre; Surfaces (Toutes): Vitrage-Verre; Métal-Zinc; C02; Menuiserie métal; Menuiserie Plastique; Nom de Variante: Modèle principal; Nom de Jeu de Variantes: Modèle principal; Position: Non défini; Fonction structurelle: Non défini; Affichage sur filtre de rénovation: Tous les filtres appropriés; État de rénovation: Existant; État de Variante: Modèle principal; Jeu de Variantes: Modèle principal
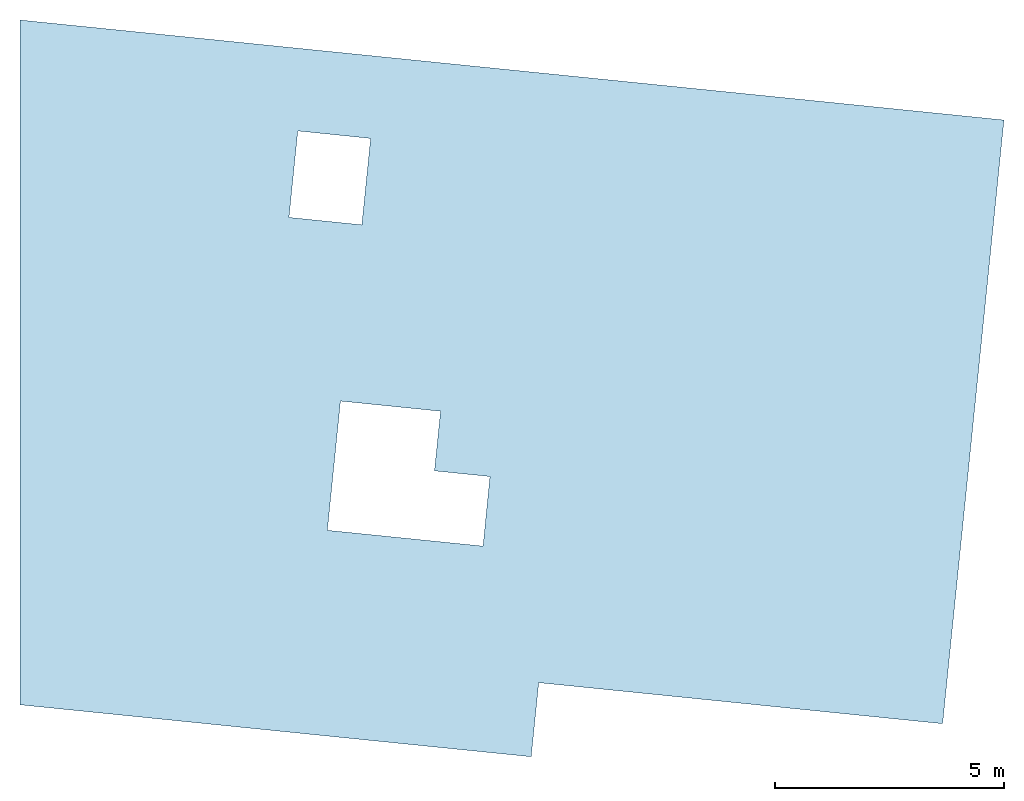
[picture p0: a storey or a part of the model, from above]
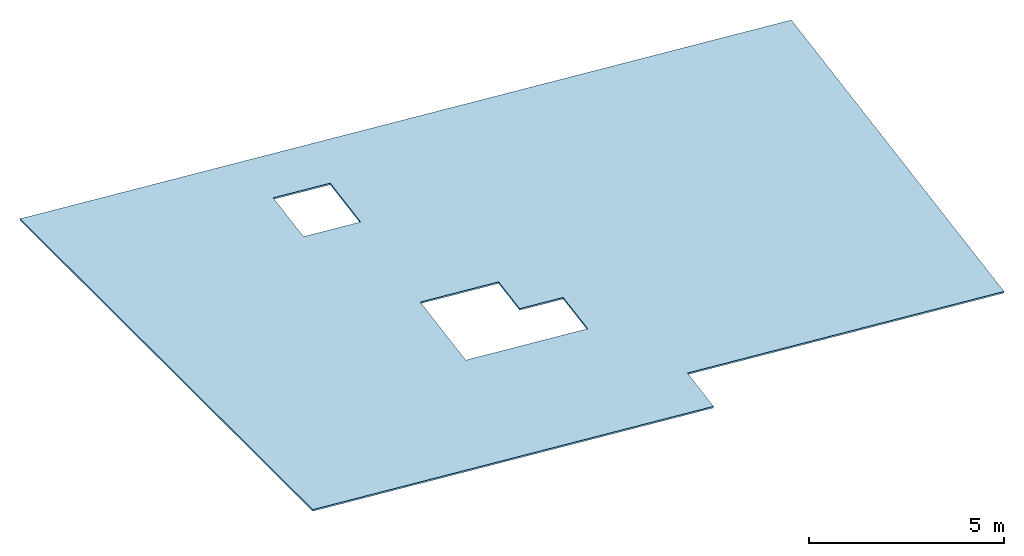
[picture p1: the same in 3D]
Properties of the parts of a building model (IFC2X3), part 38 of 44

# IfcWindow: Fenêtre 27 (28)
Name | In | OverallHeight (mm) = Hauteur ouverture P/F côté ébrasure (mm) = Hauteur nominale de l'ouverture P/F côté ébrasure (mm) = Hauteur nominale de l'ouverture P/F côté opposée ébrasure (mm) = Hauteur nominale linteau P/F (mm) = Hauteur linteau P/F côté ébrasure (mm) = Hauteur linteau P/F côté opposé ébrasure (mm) = ArchiCADQuantities, Hauteur (mm) = AC_Equantity_Fenêtre_27, Hauteur (mm) = Hauteur cavité mur (mm) = Hauteur ébrasure (mm) = Hauteur unité (mm) | OverallWidth (mm) = Largeur ouverture P/F côté ébrasure (mm) = Largeur ouverture P/F côté opposé ébrasure (mm) = Largeur nominale de l'ouverture P/F côté ébrasure (mm) = Largeur nominale de l'ouverture P/F côté opposée ébrasure (mm) = ArchiCADQuantities, Largeur (mm) = AC_Equantity_Fenêtre_27, Largeur (mm) = Largeur cavité mur (mm) = Largeur ébrasure (mm) = Largeur unité (mm) | Dimensions ébrasure = Dimensions trou mur = Dimensions unité = Taille L x H nominale | Taille L x H x E nominale | ID de l'élément = Lien et ID d'élément | Nom de zone liée | Numéro de zone liée = À numéro de Zone | Nom d'étage d'implantation | Numéro d'étage d'implantation | ID de Parent | Surfaces (Toutes) | De Zone | Du numéro de Zone | À Zone | Volet | Superficie vitrée totale (gs_list_glassarea) | Volume ouverture d'ouverture P/F (m3) | Volume nominal ouverture P/F (m3) | Superficie ouverture P/F (m2) = Superficie en plan (m2) = Superficie inférieure (nette) (m2) | Superficie nominale ouverture P/F (m2) = Superficie ouverture P/F côté ébrasure (m2) = Superficie nominale de l'ouverture P/F côté ébrasure (m2) = Superficie nominale de l'ouverture P/F côté opposé ébrasure (m2) | Hauteur ouverture P/F côté opposé ébrasure (mm) = Altitude supérieure à étage d'implantation (mm) | Superficie ouverture P/F côté opposé ébrasure (m2) | Valeur Appui ou Linteau (mm) = Hauteur nominale seuil (mm) = Altitude à étage lié/étage d'implantation (mm) = Décalage étage d'implantation (mm) | Hauteur seuil P/F côté ébrasure (mm) = Hauteur seuil P/F côté opposé ébrasure (mm) | Volume (net) (m3) | Altitude à Zéro du Projet (mm) = Altitude de Référence Niveau 1 (mm) = Altitude de Référence Niveau 2 (mm) = Altitude à niveau de la mer (mm) = Altitude inférieure à premier niveau de référence (mm) = Altitude inférieure à Zéro du projet (mm) = Altitude inférieure à niveau de la mer (mm) = Altitude inférieure à deuxième niveau de référence (mm) | Altitude supérieure à premier niveau de référence (mm) = Altitude supérieure à Zéro du projet (mm) = Altitude supérieure à niveau de la mer (mm) = Altitude supérieure à deuxième niveau de référence (mm) | Largeur panneau central (mm) | Hauteur ouverture en 3D (mm)
Fen-207 | rdc | 2150 | 900 | 0,90×2,15 | 0,90×2,15×0,34 | Fen-207 | Terrasse | A03 | rdc | 3 | Mur-142 | Vitrage-Verre; Métal-Zinc; C02; Menuiserie métal; Menuiserie Plastique | Terrasse | A03 | Ch 1 | yes | 1.5 | 0.6714 | 0.6579 | 9.33212 | 1.935 | 2400 | 2.16 | 0 | 0 | 0.061563 | 3000 | 5400 | 450 | 2120
Fen-208 | rdc | 2150 | 1000 | 1,00×2,15 | 1,00×2,15×0,34 | Fen-208 | Sejour cuisine | B03 | rdc | 3 | Mur-142 | Vitrage-Verre; Métal-Zinc; C02; Menuiserie métal; Menuiserie Plastique |  |  | Sejour cuisine | yes | 1.7 | 0.746 | 0.731 | 10.1421 | 2.15 | 2400 | 2.4 | 0 | 0 | 0.0663698 | 3000 | 5400 | 500 | 2120
Fen-207 | rdc | 2100 | 900 | 0,90×2,10 | 0,90×2,10×0,34 | Fen-207 | Terrasse | B02 | rdc | 3 | Mur-142 | Vitrage-Verre; Métal-Zinc; C02; Menuiserie métal; Menuiserie Plastique | Terrasse | B02 | Ch 2 | yes | 1.4625 | 0.6561 | 0.6426 | 9.20072 | 1.89 | 2350 | 2.115 | 0 | 0 | 0.0611048 | 3000 | 5350 | 450 | 2070
Fen-134 | Etage1 | 2150 | 1000 | 1,00×2,15 | 1,00×2,15×0,34 | Fen-134 | balcon | B11 | Etage1 | 4 | Mur-144 | Vitrage-Verre; Métal-Zinc; C02; Menuiserie métal; Menuiserie Plastique | balcon | B11 | Sejour cuisine | yes | 1.7 | 0.746 | 0.731 | 10.1421 | 2.15 | 2400 | 2.4 | 0 | 0 | 0.0663698 | 5750 | 8150 | 500 | 2120
Fen-207 | Etage1 | 2150 | 900 | 0,90×2,15 | 0,90×2,15×0,34 | Fen-207 | Ch 1 | A15 | Etage1 | 4 | Mur-142 | Vitrage-Verre; Métal-Zinc; C02; Menuiserie métal; Menuiserie Plastique |  |  | Ch 1 | yes | 1.5 | 0.6714 | 0.6579 | 9.33212 | 1.935 | 2400 | 2.16 | 0 | 0 | 0.061563 | 5750 | 8150 | 450 | 2120
Fen-207 | Etage1 | 2150 | 900 | 0,90×2,15 | 0,90×2,15×0,34 | Fen-207 |  |  | Etage1 | 4 | Mur-145 | Vitrage-Verre; Métal-Zinc; C02; Menuiserie métal; Menuiserie Plastique |  |  |  | yes | 1.5 | 0.6714 | 0.6579 | 9.33212 | 1.935 | 2400 | 2.16 | 0 | 0 | 0.061563 | 5750 | 8150 | 450 | 2120
Fen-208 | Etage1 | 2150 | 1000 | 1,00×2,15 | 1,00×2,15×0,34 | Fen-208 | Ch 3 | B15 | Etage1 | 4 | Mur-142 | Vitrage-Verre; Métal-Zinc; C02; Menuiserie métal; Menuiserie Plastique |  |  | Ch 3 | yes | 1.7 | 0.746 | 0.731 | 10.1421 | 2.15 | 2400 | 2.4 | 0 | 0 | 0.0663698 | 5750 | 8150 | 500 | 2120
Fen-208 | Etage1 | 2150 | 1000 | 1,00×2,15 | 1,00×2,15×0,34 | Fen-208 | Sejour cuisine | B15 | Etage1 | 4 | Mur-142 | Vitrage-Verre; Métal-Zinc; C02; Menuiserie métal; Menuiserie Plastique |  |  | Sejour cuisine | yes | 1.7 | 0.746 | 0.731 | 10.1421 | 2.15 | 2400 | 2.4 | 0 | 0 | 0.0663698 | 5750 | 8150 | 500 | 2120
Fen-207 | Etage 2 | 2150 | 1000 | 1,00×2,15 | 1,00×2,15×0,34 | Fen-207 | balcon | B25 | Etage 2 | 5 | Mur-142 | Vitrage-Verre; Métal-Zinc; C02; Menuiserie métal; Menuiserie Plastique | balcon | B25 | Ch 3 | yes | 1.7 | 0.746 | 0.731 | 10.1421 | 2.15 | 2400 | 2.4 | 0 | 0 | 0.0663698 | 8500 | 10900 | 500 | 2120
Fen-208 | Etage 2 | 2150 | 1000 | 1,00×2,15 | 1,00×2,15×0,34 | Fen-208 | balcon | B24 | Etage 2 | 5 | Mur-142 | Vitrage-Verre; Métal-Zinc; C02; Menuiserie métal; Menuiserie Plastique | balcon | B24 | Sejour cuisine | yes | 1.7 | 0.746 | 0.731 | 10.1421 | 2.15 | 2400 | 2.4 | -8.88178e-12 | 0 | 0.0663698 | 8500 | 10900 | 500 | 2120
Fen-209 | Etage 2 | 2150 | 1000 | 1,00×2,15 | 1,00×2,15×0,34 | Fen-209 | balcon | B24 | Etage 2 | 5 | Mur-143 | Vitrage-Verre; Métal-Zinc; C02; Menuiserie métal; Menuiserie Plastique | balcon | B24 | Sejour cuisine | yes | 1.7 | 0.746 | 0.731 | 10.1421 | 2.15 | 2400 | 2.4 | 0 | 0 | 0.0663698 | 8500 | 10900 | 500 | 2120
Fen-207 | Etage 2 | 2150 | 900 | 0,90×2,15 | 0,90×2,15×0,34 | Fen-207 | Ch 1 | A23 | Etage 2 | 5 | Mur-145 | Vitrage-Verre; Métal-Zinc; C02; Menuiserie métal; Menuiserie Plastique |  |  | Ch 1 | yes | 1.5 | 0.6714 | 0.6579 | 9.33212 | 1.935 | 2400 | 2.16 | 0 | 0 | 0.061563 | 8500 | 10900 | 450 | 2120
Fen-207 | Etage 2 | 2150 | 900 | 0,90×2,15 | 0,90×2,15×0,34 | Fen-207 | Ch 1 | A25 | Etage 2 | 5 | Mur-142 | Vitrage-Verre; Métal-Zinc; C02; Menuiserie métal; Menuiserie Plastique |  |  | Ch 1 | yes | 1.5 | 0.6714 | 0.6579 | 9.33212 | 1.935 | 2400 | 2.16 | 0 | 0 | 0.061563 | 8500 | 10900 | 450 | 2120
Fen-209 | Etage 2 | 2150 | 900 | 0,90×2,15 | 0,90×2,15×0,34 | Fen-209 | balcon | B23 | Etage 2 | 5 | Mur-143 | Vitrage-Verre; Métal-Zinc; C02; Menuiserie métal; Menuiserie Plastique | balcon | B23 | Ch 2 | yes | 1.5 | 0.6714 | 0.6579 | 9.33212 | 1.935 | 2400 | 2.16 | 0 | 0 | 0.061563 | 8500 | 10900 | 450 | 2120
Fen-207 | Etage 3 | 2150 | 900 | 0,90×2,15 | 0,90×2,15×0,34 | Fen-207 | Ch 1 | A32 | Etage 3 | 6 | Mur-142 | Vitrage-Verre; Métal-Zinc; C02; Menuiserie métal; Menuiserie Plastique |  |  | Ch 1 | yes | 1.5 | 0.6714 | 0.6579 | 9.33212 | 1.935 | 2400 | 2.16 | 0 | 0 | 0.061563 | 11550 | 13950 | 450 | 2120
Fen-207 | Etage 3 | 2150 | 1000 | 1,00×2,15 | 1,00×2,15×0,34 | Fen-207 | Terrasse | B34 | Etage 3 | 6 | Mur-142 | Vitrage-Verre; Métal-Zinc; C02; Menuiserie métal; Menuiserie Plastique | Terrasse | B34 | Sejour cuisine | yes | 1.7 | 0.746 | 0.731 | 10.1421 | 2.15 | 2400 | 2.4 | 0 | 0 | 0.0663698 | 11550 | 13950 | 500 | 2120
Fen-208 | Etage 3 | 2150 | 1000 | 1,00×2,15 | 1,00×2,15×0,34 | Fen-208 | Terrasse | B34 | Etage 3 | 6 | Mur-142 | Vitrage-Verre; Métal-Zinc; C02 | Terrasse | B34 | Sde | no | 1.7 | 0.731 | 0.731 | 6.32118 | 2.15 | 2150 | 2.15 | 0 | 0 | 0.02625 | 11550 | 13700 | 500 | 2120
Fen-207 | Etage 3 | 2150 | 900 | 0,90×2,15 | 0,90×2,15×0,34 | Fen-207 | Terrasse | A33 | Etage 3 | 6 | Mur-142 | Vitrage-Verre; Métal-Zinc; C02; Menuiserie métal; Menuiserie Plastique | Terrasse | A33 | Ch 2/pl | yes | 1.5 | 0.6714 | 0.6579 | 9.33212 | 1.935 | 2400 | 2.16 | 1.95399e-11 | 1.95399e-11 | 0.061563 | 11550 | 13950 | 450 | 2120
Fen-207 | Etage 3 | 2150 | 1000 | 1,00×2,15 | 1,00×2,15×0,34 | Fen-207 | Terrasse | A31 | Etage 3 | 6 | Mur-143 | Vitrage-Verre; Métal-Zinc; C02; Menuiserie métal; Menuiserie Plastique | Terrasse | A31 | Ch 2 | yes | 1.7 | 0.746 | 0.731 | 10.1421 | 2.15 | 2400 | 2.4 | 0 | 0 | 0.0663698 | 11550 | 13950 | 500 | 2120
2 x Fen-207 | etage 4 | 2150 | 1000 | 1,00×2,15 | 1,00×2,15×0,34 | Fen-207 | Terrasse | B44 | etage 4 | 7 | Mur-142 | Vitrage-Verre; Métal-Zinc; C02; Menuiserie métal; Menuiserie Plastique | Terrasse | B44 | Sejour cuisine | yes | 1.7 | 0.746 | 0.731 | 10.1421 | 2.15 | 2400 | 2.4 | 0 | 0 | 0.0663698 | 14600 | 17000 | 500 | 2120
Fen-211 | etage 4 | 2150 | 900 | 0,90×2,15 | 0,90×2,15×0,34 | Fen-211 | Balcon | B43 | etage 4 | 7 | Mur-143 | Vitrage-Verre; Métal-Zinc; C02; Menuiserie métal; Menuiserie Plastique | Balcon | B43 | Ch 2 | yes | 1.5 | 0.6714 | 0.6579 | 9.33212 | 1.935 | 2400 | 2.16 | 0 | 0 | 0.061563 | 14600 | 17000 | 450 | 2120
Fen-207 | etage 4 | 2150 | 1000 | 1,00×2,15 | 1,00×2,15×0,34 | Fen-207 | Terrasse | B53 | etage 4 | 7 | Mur-142 | Vitrage-Verre; Métal-Zinc; C02; Menuiserie métal; Menuiserie Plastique | Terrasse | B53 | Sejour cuisine | yes | 1.7 | 0.746 | 0.731 | 10.1421 | 2.15 | 2400 | 2.4 | 0 | 0 | 0.0663698 | 14600 | 17000 | 500 | 2120
Fen-211 | etage 4 | 2150 | 900 | 0,90×2,15 | 0,90×2,15×0,34 | Fen-211 |  |  | etage 4 | 7 | Mur-143 | Vitrage-Verre; Métal-Zinc; C02; Menuiserie métal; Menuiserie Plastique |  |  |  | yes | 1.5 | 0.6714 | 0.6579 | 9.33212 | 1.935 | 2400 | 2.16 | 0 | 0 | 0.061563 | 14600 | 17000 | 450 | 2120
Fen-207 | Etage 5 | 2150 | 1000 | 1,00×2,15 | 1,00×2,15×0,34 | Fen-207 | Terrasse | B51 | Etage 5 | 8 | Mur-143 | Vitrage-Verre; Métal-Zinc; C02; Menuiserie métal; Menuiserie Plastique | Terrasse | B51 | Ch 1 | yes | 1.7 | 0.746 | 0.731 | 10.1421 | 2.15 | 2400 | 2.4 | 0 | 0 | 0.0663698 | 17650 | 20050 | 500 | 2120
Fen-207 | Etage 5 | 2150 | 1000 | 1,00×2,15 | 1,00×2,15×0,34 | Fen-207 | Terrasse | B51 | Etage 5 | 8 | Mur-143 | Vitrage-Verre; Métal-Zinc; C02; Menuiserie métal; Menuiserie Plastique | Terrasse | B51 | Sejour cuisine | yes | 1.7 | 0.746 | 0.731 | 10.1421 | 2.15 | 2400 | 2.4 | 0 | 0 | 0.0663698 | 17650 | 20050 | 500 | 2120
2 x Fen-207 | Etage 5 | 2150 | 1000 | 1,00×2,15 | 1,00×2,15×0,34 | Fen-207 |  |  | Etage 5 | 8 | Mur-143 | Vitrage-Verre; Métal-Zinc; C02; Menuiserie métal; Menuiserie Plastique |  |  |  | yes | 1.7 | 0.746 | 0.731 | 10.1421 | 2.15 | 2400 | 2.4 | 0 | 0 | 0.0663698 | 17650 | 20050 | 500 | 2120

# IfcWindow: Fenêtre châssis double variable 27 (21)
Type - OperationType: DOUBLE_PANEL_VERTICAL; ParameterTakesPrecedence: no; Sizeable: no
Type - Window Lining Properties - LiningDepth: 50 mm; LiningThickness: 50 mm; MullionThickness: 50 mm; FirstMullionOffset: 0.2
Type - Window Panel Properties - Panel 1 - OperationType: SIDEHUNGRIGHTHAND; PanelPosition: RIGHT; FrameDepth: 50 mm; FrameThickness: 50 mm
Type - Window Panel Properties - Panel 2 - OperationType: FIXEDCASEMENT; PanelPosition: LEFT
OverallWidth: 2000 mm; Classification: Fenêtre (Classification ARCHICAD)
ArchiCADProperties - Structure de Mur: isol int 18+16 0018356637; Orientation: D; Nom élément de bibliothèque d'ouverture: Fenêtre châssis double variable 27; Index hachure latérale ouverture: 100 %; ID de l'élément: Fen-207; Lien et ID d'élément: Fen-207; Calque: Interieurs logements; Nom Élément de Bibliothèque: Fenêtre châssis double variable 27; Matériau de construction / Composite / Profil / Hachure: 100 %; Type Hachure: 100 %; Verrouillé: no; Type d'élément: Fenêtre; Surfaces (Toutes): Vitrage-Verre; Métal-Zinc; C02; Menuiserie métal; Menuiserie Plastique; Nom de Variante: Modèle principal; Nom de Jeu de Variantes: Modèle principal; Position: Non défini; Fonction structurelle: Non défini; Affichage sur filtre de rénovation: Tous les filtres appropriés; État de rénovation: Existant; État de Variante: Modèle principal; Jeu de Variantes: Modèle principal
AC_Pset_RenovationAndPhasing - Renovation Status: Existing
ArchiCADQuantities - Largeur ouverture P/F côté ébrasure: 2000 mm; Largeur ouverture P/F côté opposé ébrasure: 2000 mm; Largeur nominale de l'ouverture P/F côté ébrasure: 2000 mm; Largeur nominale de l'ouverture P/F côté opposée ébrasure: 2000 mm; Hauteur nominale linteau P/F: 2150 mm; Hauteur linteau P/F côté ébrasure: 2150 mm; Hauteur linteau P/F côté opposé ébrasure: 2150 mm; Épaisseur de Mur: 340 mm; Épaisseur cadre: 50 mm; Largeur: 2000 mm; Altitude supérieure à étage d'implantation: 2400 mm
AC_Equantity_Fenêtre_châssis_double_variable_27 - Largeur: 2000 mm; Dimension Z: 1000 mm; Niveau inférieur: 1000 mm; Niveau supérieur: 0 mm; Ebrasure à âme du mur: 290 mm; Nouv. largeur droite hach. mur: 150 mm; Nouv. largeur gauche hach. mur: 150 mm; Épaisseur du mur connecté: 0 mm; Épaisseur 2 mur connecté: 340 mm; Épaisseur 1 mur connecté: 340 mm; Largeur poteau d'angle: 0 mm; Épaisseur poteau d'angle: 0 mm; Projection poteau d'angle: 0 mm; Tolérance max.: 100 mm; Tolérance: 0 mm; Tolérance gauche: 0 mm; Tolérance droite: 0 mm; Tolérance supérieure: 0 mm; Tolérance inférieure: 0 mm; Largeur cavité mur: 2000 mm; Largeur ébrasure: 2000 mm; Largeur unité: 2000 mm; Largeur châssis côté 1: 1000 mm; Épaisseur cadre: 50 mm; Largeur cadre: 50 mm; Largeur cadre côté 2: 50 mm; Largeur cadre supérieur: 50 mm; Largeur cadre inférieur (gs_frame_width_lower): 50 mm; Profondeur feuillure: 25 mm; Largeur feuillure: 25 mm; Largeur division supérieure: 100 mm; Hauteur divisions hor. sup.: 1150 mm; Largeur division inférieure: 100 mm; Hauteur divisions hor. inf.: 400 mm; Largeur châssis vitré: 400 mm; Largeur meneau: 70 mm; Largeur meneau côté 2: 100 mm; Hauteur division H châssis principal 1: 440 mm; Hauteur division H châssis principal 2: 440 mm; Hauteur division H tierce vitrée: 720 mm; Hauteur division H châssis inférieur 2: 290 mm; Hauteur division H châssis imposte 2: 240 mm; Épaisseur châssis: 50 mm; Largeur châssis: 50 mm; Largeur grille: 20 mm; Épaisseur grille: 25 mm; Épaisseur vitrage: 20 mm; Épaisseur persiennes: 10 mm; Largeur persiennes: 50 mm; Dépassement ouverture gauche: 0 mm; Dépassement ouverture droite: 0 mm; Dépassement ouverture supérieur: 0 mm; Dépassement ouverture inférieur: 0 mm; Largeur Chapiteau architrave: 20 mm; Largeur côté 1 (gs_tw_right_out): 5 mm; Largeur côté 2 (gs_tw_left_out): 5 mm; Largeur haut (gs_tw_top_out): 5 mm; Largeur base (gs_tw_bottom_out): 5 mm; Épaisseur sur mur (gs_trim_thk_out): 5 mm; Épaisseur dans trou de mur (gs_trim_width_out): 5 mm; Décalage (gs_trim_offs_out): 0 mm; Dépassement du verre (gs_trim_jambext_nosing_out): 50 mm; Débord supérieur (gs_trimov_top_left_out): 0 mm; Débord supérieur (gs_trimov_top_right_out): 0 mm; Débord inférieur: (gs_trimov_bot_left_out): 0 mm; Débord inférieur: (gs_trimov_bot_right_out): 0 mm; Débord inférieur: (casingOverhangBottomSideOut): 50 mm; Largeur côté 1 (gs_tw_right_in): 100 mm; Largeur côté 2 (gs_tw_left_in): 100 mm; Largeur haut (gs_tw_top_in): 100 mm; Largeur base (gs_tw_bottom_in): 100 mm; Épaisseur sur mur (gs_trim_thk_in): 25 mm; Épaisseur dans trou de mur (gs_trim_width_in): 25 mm; Décalage (gs_trim_offs_in): 0 mm; Dépassement du verre (gs_trim_jambext_nosing_in): 50 mm; Débord supérieur (gs_trimov_top_left_in): 0 mm; Débord supérieur (gs_trimov_top_right_in): 0 mm; Débord inférieur: (gs_trimov_bot_left_in): 0 mm; Débord inférieur: (gs_trimov_bot_right_in): 0 mm; Largeur appui: 320 mm; Largeur supérieure appui: 10 mm; Hauteur supérieure appui: 10 mm; Épaisseur appui: 50 mm; Épaisseur front appui: 30 mm; Altitude appui: 5 mm; Débord larmier appui: 20 mm; Largeur larmier appui: 30 mm; Débord appui: 30 mm; Dépassement appui gauche: 30 mm; Dépassement appui droite: 30 mm; Glissement appui en profondeur: 0 mm; Glissement appui de mur: 0 mm; Profondeur trou arrière (gs_sill_holeDepthBehind): 0 mm; Épaisseur brique (gs_brick_sill_br_thk): 65 mm; Épaisseur mortier (gs_brick_sill_mort_thk): 15 mm; Largeur latte: 30 mm; Épaisseur latte: 25 mm; Débord tablette: 30 mm; Dépassement tablette gauche: 0 mm; Dépassement tablette droite: 0 mm; Glissement tabl. en profondeur: 0 mm; Hauteur profil: 65 mm; Épaisseur profil: 110 mm; Hauteur panneau: 1500 mm; Décalage intérieur: 20 mm; Profondeur fermeture: 0 mm; Largeur cadre supplémentaire: 40 mm; Épaisseur cadre supplémentaire: 30 mm; Épaisseur allège vitrée: 30 mm; Longueur colonne centrale: 20 mm; Rayon colonne centrale: 5 mm; Distance panneau: 6 mm; Débord extérieur: 0 mm; Largeur panneau intérieur: 120 mm; Longueur ouverture en 3D: 1000 mm; Longueur fermée en 3D: 0 mm; Longueur ouverture 1 en 3D (gs_shutter_opLength_1): 500 mm; Longueur ouverture 1 en 3D (gs_shutter_opLength_2): 500 mm; Hauteur fermée en 3D: 0 mm; Épaisseur panneau: 50 mm; Largeur cadre panneau: 50 mm; Largeur cadre inférieur (gs_shutPanel_frameWidthBottom): 50 mm; Largeur panneau: 0 mm; Épaisseur hachure panneau: 10 mm; Épaisseur persienne: 10 mm; Largeur persienne: 40 mm; Largeur diviseur cadre horiz.: 50 mm; Largeur diviseur cadre vert.: 50 mm; Rayon trou: 10 mm; Largeur montant: 100 mm; Largeur cadre Z: 50 mm; Épaisseur cadre Z: 25 mm; Épaisseur plans verticaux: 25 mm; Épaisseur plans horizontaux: 25 mm; Largeur appr. plans verticaux: 80 mm; Largeur appr. plans horizontaux: 115 mm; Hauteur boîte (gs_shutRoll_boxHeight): 250 mm; Profondeur boîte (gs_shutRoll_boxWidth): 250 mm; Décalage boîte gauche: 0 mm; Décalage boîte droite: 0 mm; Profondeur rails: 280 mm; Distance au mur (gs_shutRoll_distFromWall): 0 mm; Distance au linteau (gs_shutRoll_distFromHead): 0 mm; Largeur lamelle: 50 mm; Hauteur boîte (gs_shutLam_boxHeight): 200 mm; Profondeur boîte (gs_shutLam_boxWidth): 150 mm; Largeur recouvrement: 0 mm; Distance au mur (gs_shutLam_distFromWall): 0 mm; Distance au linteau (gs_shutLam_distFromHead): 0 mm; Largeur segment (gs_shutLam_segmentWidth): 60 mm; Hauteur boîte (gs_shutLam2_boxHeight): 60 mm; Largeur boîte: 60 mm; Distance à fenêtre: 60 mm; Distance au linteau (gs_shutLam2_distFromHead): 60 mm; Hauteur axe cellule à linteau: 0 mm; Largeur segment (gs_shutLam2_segmentWidth): 60 mm; Distance entre arche et fenêtre: 0 mm; Dépassement gauche linteau: 0 mm; Dépassement droite linteau: 0 mm; Elevation linteau: 30 mm; Décalage linteau: 0 mm; Hauteur linteau: 250 mm; Profondeur linteau: 120 mm; Profondeur trou arrière (gs_masonry_arch_rearHoleDepth): 0 mm; Épaisseur brique (gs_masonry_arch_brick_thk): 65 mm; Épaisseur mortier (gs_masonry_arch_mort_thk): 10 mm; Largeur clé de voûte: 100 mm; Dépassement clé de voûte: 0 mm; Projection clé de voûte: 10 mm; Profondeur ébrasure : (gs_wido_sill): 290 mm; Profondeur ébrasure : (AC_wido_sill): 290 mm; Profondeur montant côté 2: 60 mm; Profondeur montant: 60 mm; Profondeur montant int. côté 2 (gs_reveal_splayed_innerLeft): 60 mm; Profondeur montant intérieur (gs_reveal_splayed_innerRight): 60 mm; Profondeur montant int. côté 2 (gs_reveal_double_innerLeft): 60 mm; Profondeur montant intérieur (gs_reveal_double_innerRight): 60 mm; Profondeur montant linteau: 60 mm; Profondeur montant appui: 60 mm; Profondeur linteau int. (gs_reveal_splayed_innerTop): 60 mm; Profondeur appui int. (gs_reveal_splayed_innerBottom): 60 mm; Profondeur linteau int. (gs_reveal_double_innerTop): 60 mm; Profondeur appui int. (gs_reveal_double_innerBottom): 0 mm; Profondeur montant ext.: 80 mm; Limite épaisseur plâtre: 40 mm; Distance de couche / fermeture: 0 mm; Largeur fermeture: 38 mm; Épaisseur fermeture: 100 mm; Épaisseur bande: 25 mm; Largeur profilé: 75 mm; Épaisseur personnalisée: 15 mm; Dépassement couche prof. cadre: 0 mm; Profondeur incrustation: 50 mm; Largeur allège: 1000 mm; Débord sur côté 1: 0 mm; Débord sur côté 2: 0 mm; Hauteur allège: 900 mm; Débord inférieur: (gs_parapet_botelev): 0 mm; Distance ouverture 1 châssis princ. 1: 0 mm; Distance ouverture 2 châssis princ. 1: 0 mm; Distance ouverture 1 châssis princ. 2: 0 mm; Distance ouverture 2 châssis princ. 2: 0 mm; Distance ouverture 1 tierce vitrée: 0 mm; Distance ouverture 2 tierce vitrée: 0 mm; Distance ouverture 1 châssis inf.: 0 mm; Distance ouverture 2 châssis inf.: 0 mm; Distance ouverture 1 châssis imposte: 0 mm; Distance ouverture 2 châssis imposte: 0 mm; Longueur ouverture en 2D: 0 mm; Dépass.ouverture gauche: 0 mm; Dépass.ouverture à droite: 0 mm; Dépass.ouverture supérieur: 0 mm; Dépass.ouverture inférieur: 0 mm
AC_Pset_Fenêtre_châssis_double_variable_27 - Contours Mur (0-Sans,1-Tout,2-Côté,3-Longueur): 1; Point ch.0-Non,1-2D,2-3D,3-Tous: 3; Option affichage en plan: 2; Angle de position baie: 0 deg; Trou reprend surface latérale de mur: yes; Division de surface du trou courbe dans murs courbes: no; Afficher points chauds 2D en 3D: yes; Type de mur: 1; Position ancre ébrasuer: 1; Fonction de debug Fenêtre Angle: no; Placement (1=Angle, 0=Centre): no; Basculer: no; Démolition / Nouvelle constr.: 1; Nouveau motif de hachure de mur: Parpaing; Afficher nouv. constr. sur mur: no; Type de ligne démolition: 4; Aff. param. Démolition/Nouveau: no; Fonction Fenêtre Angle: yes; Angle Murs: 90 deg; Murs connectés d'épaiss. diff.: no; Poteau d'angle: no; Coin 2: no; Angle de coin 2: 90 deg; Murs connectés d'épaiss. diff. 2: no; Coin 1: no; Angle de coin 1: 90 deg; Murs connectés d'épaiss. diff. 1: no; Type connexion angle 1: 1; Type connexion angle 2: 1; Entièrement éditable: yes; Niveau de détail 2D: 2; Afficher ébrasure sur symbole: 2; Niveau de détail 3D: 2; Taille nominale: 0; Taille trou comme taille nominale: yes; Taille ébrasure comme nominale: no; Taille unité comme nominale: no; Transmettre taille nominale actuelle à sélection: no; Panneaux horizontaux: 3; Largeur cadre uniforme: no; Traverse supérieure: no; Traverse inférieure: no; Châssis vitré (gs_bSLight): no; Panneaux verticaux: 3; Meneau jusqu'en haut: yes; Meneau jusqu'en bas: no; Châssis uniformes: no; Direction vitrage fixe (FixGlassDir): Par direction d'ouverture; Direction vitrage fixe (FixGlassDir_m): 1; Type d'opération châssis princ. (gs_optype_01): Battant; Type d'ouverture (gs_optype_m_01): 3; Type d'opération châssis princ. (gs_optype_09): Battant; Type d'ouverture (gs_optype_m_09): 3; Type ouverture panneau adj.: Vitrage fixe; Type d'ouverture (gs_optype_m_05): 1; Type ouverture châssis inf.: Vitrage fixe; Type d'ouverture (gs_optype_m_03): 1; Type ouverture châssis imposte: Vitrage fixe; Type d'ouverture (gs_optype_m_02): 1; Type châssis (MullionStyle_00): Pas de grille; Type châssis (iMullionStyle_00): 1; Type châssis, châssis princ. 1: Pas de grille; Type châssis (iMullionStyle_01): 1; Type châssis, châssis princ. 2: Pas de grille; Type châssis (iMullionStyle_09): 1; Type châssis tierce vitrée: Pas de grille; Type châssis (iMullionStyle_05): 1; Type châssis, châssis inf.: Nombre de meneaux; Type châssis (iMullionStyle_03): 1; Type châssis, châssis imposte: Nombre de meneaux; Type châssis (iMullionStyle_02): 1; Panneau personnalisé symétrie (gs_bMirr_cust_panel_01): no; Panneau personnalisé symétrie (gs_bMirr_cust_panel2_01): no; Panneau personnalisé symétrie (gs_bMirr_cust_panel_02): no; Panneau personnalisé symétrie (gs_bMirr_cust_panel2_02): no; Panneau personnalisé symétrie (gs_bMirr_cust_panel_03): no; Panneau personnalisé symétrie (gs_bMirr_cust_panel2_03): no; Panneau personnalisé symétrie (gs_bMirr_cust_panel_05): no; Panneau personnalisé symétrie (gs_bMirr_cust_panel2_05): no; Panneau personnalisé symétrie (gs_bMirr_cust_panel_09): no; Panneau personnalisé symétrie (gs_bMirr_cust_panel2_09): no; Edition point chaud de grille: yes; Position grille (MullionPosition): Les deux; Position grille (iMullionPosition): 3; Nbre panneaux V châssis princ. 1: 2; Nbre panneaux H châssis princ. 1: 2; Nbre panneaux V 2 châssis princ. 1: 2; Nbre panneaux H 2 châssis princ. 1: 2; Nbre panneaux V châssis princ. 2: 2; Nbre panneaux H châssis princ. 2: 2; Nbre panneaux V 2 châssis princ. 2: 2; Nbre panneaux H 2 châssis princ. 2: 2; Nbre panneaux V tierce vitrée: 3; Nbre panneaux H tierce vitrée: 2; Nbre panneaux V 2 tierce vitrée: 3; Nbre panneaux H 2 tierce vitrée: 2; Nbre panneaux V châssis inf.: 2; Nbre panneaux H châssis inf.: 2; Nbre panneaux V 2 châssis inf.: 2; Nbre panneaux H 2 châssis inf.: 2; Nbre panneaux V châssis imposte: 2; Nbre panneaux H châssis imposte: 2; Nbre panneaux V 2 châssis imposte: 2; Nbre panneaux H 2 châssis imposte: 2; Style persiennes (iLouverStyle): 1; Angle d'ouverture persiennes: 0 deg; Poignée de fenêtre: no; Type de poignée de fenêtre (gs_handle_type_win): Style 1; Type de poignée de fenêtre (gs_handle_type_win_m): 1; Chambranle extérieur (gs_trim_outside): no; Type chambranle extérieur (gs_trimtype_out): Simple; Type chambranle extérieur (gs_trimtype_out_int): 1; Type tête chambr. ext.: 1; Chapiteau architrave: yes; Type chapiteau architrave: 1; Chambranle inférieur extérieur: no; Couvre surface mur ext.: yes; Largeurs uniformes de chambranle (gs_trim_outside_uniform): no; Chambranle intérieur.: no; Type chambranle intérieur (gs_trimtype_in): Simple; Type chambranle intérieur (gs_trimtype_in_int): 1; Couvre surface mur int.: yes; Largeurs uniformes de chambranle (gs_trim_inside_uniform): no; Appui (gs_sill_outside): yes; Dépassement appui: no; Type d'appui/seuil: 11; Angle appui: 3 deg; Appui courbe dans murs courbes: yes; Isolation sous appui: yes; Utiliser couche isolation mur: no; Niveau détail 3D seuil brique: 1; Tablette (gs_board_inside): no; Angle tablette: 0 deg; Tabl. courbe dans murs courbes: yes; Tableau dans murs polygonaux: 1; Aération naturelle: no; Type d'aération naturelle: 2; Châssis principal 1: no; Châssis principal 2: no; Châssis vitré (isVentilationProfileInSash_05): no; Châssis inférieur: no; Châssis imposte: yes; Volet: yes; Type volet: 6; Types volet activés: 126; Nombre de panneaux: 2; Nombre de panneaux 2: 1; Position panneau (gs_shutter_panelPos): Symétrique; Position panneau (gs_shutter_iPanelPos): 1; Hauteur volet automatique: yes; Cadre supplémentaire: no; Type de couverture (gs_slidingShutter_cover): Profil en Z; Type de couverture (gs_slidingShutter_iCover): 1; Direction articulation (gs_foldingShutter_stacking): Intérieur; Direction articulation (gs_foldingShutter_iStacking): 1; Ouvert en 3D: yes; Angle ouverture en 3D: 180 deg; Afficher symbole 2D: yes; Afficher lignes d'ouverture sur symbole: no; Type de panneau: (gs_shutPanel_type): Style 1; Type de panneau: (gs_shutPanel_iType): 1; Largeur cadre inf. différente: no; Largeur volets automatiques: yes; Angle persienne: 30 deg; Nombre trous horizontaux: 5; Nombre trous verticaux: 8; Placement volet roulant (gs_shutRoll_placement): Derrière façade; Placement volet roulant (gs_shutRoll_iPlacement): 3; Type boîte (gs_shutRoll_boxType): Rectangulaire; Type boîte (gs_shutRoll_iBoxType): 1; Position rampe (gs_shutRoll_railPos): Sur revêtement; Position rampe (gs_shutRoll_iRailPos): 1; Afficher revêtement derrière parasol (gs_shutRoll_showCasingBehind): no; Isolation derrière cellule (gs_shutRoll_cutWallBehind): no; Inclure hauteur dans hauteur de trou de mur: no; Angle supérieur boîte: 10 deg; Taille boîte par défaut (gs_shutRoll_boxDefaultSize): A largeur d'ébrasure; Taille boîte par défaut (gs_shutRoll_iBoxDefaultSize): 1; Placement stores (gs_shutLam_placement): Fixé sur façade; Placement stores (gs_shutLam_iPlacement): 1; Isolation derrière cellule (gs_shutLam_cutWallBehind): no; Boîte ouverte: yes; Rampe: yes; Position rampe (gs_shutLam_railPos): Sur revêtement; Position rampe (gs_shutLam_iRailPos): 1; Afficher revêtement derrière parasol (gs_shutLam_showCasingBehind): no; Angle de rotation des lamelles (gs_shutLam_rotation): 45 deg; Angle de rotation des lamelles (gs_shutLam2_rotation): 45 deg; Linteau (bMasonryArch): no; Linteau (gs_masonry_arch_int): 2; Type linteau (gs_masonry_arch_structure): Stuc; Type linteau (gs_masonry_arch_structure_int): 1; Arche sur linteau: yes; Niche sous arche: yes; Angle inclinaison: 75 deg; Surface niche personnalisée: no; Type ébrasure (gs_reveal_type_new): Baie simple; Type ébrasure (gs_reveal_type_int): 2; Type ébrasure inférieure (gs_reveal_type_bottom): Uniforme; Type ébrasure inférieure (gs_reveal_type_bottom_int): 1; Type ébrasure extérieure: Baie simple; Type ébrasure (gs_reveal_doubleOuterTypeInt): 0; Type ébrasure intérieure: Baie simple; Type ébrasure (gs_reveal_doubleInnerTypeInt): 0; Profondeur montant uniforme: yes; Côté angle 2: 20 deg; Côté angle: 20 deg; Angle côté supérieur: 20 deg; Angle côté inférieur: 20 deg; Utiliser composant finition mur: no; Tourner automatiquement plâtre surface intérieure: yes; Tourner plâtre surface intérieure: 0; Tourner automatiquement plâtre surface extérieure: yes; Tourner plâtre surface extérieure: 0; Peut être coté en 2D: no; Afficher en 3D: no; Type de fermeture (gs_closure_type): Pas de fermeture; Type de fermeture (gs_closure_type_int): 1; Tourner couche sur côté (gs_cavity_side): Les deux; Tourner couche sur côté (iCavityClosureSide): 1; Nbre de couches retournées: 1; Num. à partir de (gs_nTurnDir): Face extérieure; Num. à partir de (iCavityClosureTurnDir): 1; Placer fermeture sur côté 2: yes; Placer fermeture sur côté 1: yes; Placer fermeture en haut: no; Placer fermeture en bas: no; Placer fermeture sur couche: 1; Placer fermeture de côté (gs_cc_dutch_ClosureToSide): 1; Ecart à couche externe: yes; Tourner couche sur fermeture: no; Insérer bande d'isolation: yes; Afficher bande d'isolation: yes; Type de ligne de contour (gs_ltJoint): 1; Motif de hachure (gs_fillJoint): Isolant polystyrène; Surface personnalisée: no; Surface: Bois-Pin brillant; Type de ligne de contour (gs_ltPlug): 1; Motif de hachure (gs_fillPlug): Isolant polystyrène; Côté montant édité: 1; Côté mur édité: 1; Numéro couche éditée: 1; Tourner couche: no; Considérer couches comme plâtre: no; Tourner épaiseur: 1; Orientation hachure: 1; Ligne de séparation tournant: no; Dernier côté sélectionné: no; Méthode fermeture changée auto.: no; Connexion à gauche: no; Connexion à droite: no; Connexion en haut: no; Connexion en bas: no; Incrustation allège: no; Tailles incrustation mur (gs_parapet_sizes_st): Automatique; Tailles incrustation mur (iParapetSize): 1; Cotes largeur et longueur auto: yes; Incrustation base mur à (gs_parapet_bottom_st): Etage actuel; Incrustation base mur à (iParapetBottom): 1; Afficher allège masquée: yes; Type ligne allège masquée: 1; Angle ouv. châssis principal 1 (openingAngle_01): 0 deg; Angle ouv. châssis principal 1 (openingAngle2_01): 0 deg; Angle ouv. châssis principal 2 (openingAngle_09): 0 deg; Angle ouv. châssis principal 2 (openingAngle2_09): 0 deg; Angle ouv. tierce vitrée (openingAngle_05): 0 deg; Angle ouv. tierce vitrée (openingAngle2_05): 0 deg; Angle d'ouverture châssis inf. (openingAngle_03): 0 deg; Angle d'ouverture châssis inf. (openingAngle2_03): 0 deg; Angle ouv. châssis imposte (openingAngle_02): 0 deg; Angle ouv. châssis imposte (openingAngle2_02): 0 deg; Angle ouverture en 2D: 90 deg; Suppl. Opt. vue pour aff. symb. 2D: yes; Type ligne ouverture: 1; Forme ligne ouverture (or_SwingType): Courbé; Forme ligne ouverture (or_iSwingType): 1; Forme ligne ouverture (or_SlidingType): Sans; Forme ligne ouverture (or_iSlidingType): 0; Stylo ligne ouverture 2D/3D (or_iOpLinePen): 100; Suppl. Opt. vue pour proj. 3D: yes; Afficher ligne d'ouverture: yes; Type ligne côté ouverture (or_opLineType3dIn): Tirets; Type ligne côté ouverture (or_iOpLineType3dIn): 1; Type ligne côté opposé (or_opLineType3dOut): Tirets; Type ligne côté opposé (or_iOpLineType3dOut): 1; Orientation ligne (or_oplineStyle): Poignée; Orientation ligne (or_iOplineStyle): 1; Ligne de contour de mur (gs_wcont_line): Des deux côtés; Ligne de contour de mur (iWallContourLine): 4; Type ligne contour int. mur: 1; Type ligne contour ext. mur: 1; Type ligne contour int. mur masqué: 1; Type ligne contour ext. mur masqué: 1; Utiliser hachures: yes; Motif de hachure cadre: Sans Trame; Motif de hachure châssis: Lame d'air; Type hachure non coupée: Sans Trame; Motif hachure symbole en plan: Sans Trame; Motif hachure appui en Coupe: Sans Trame; Motif hachure isolation Coupe: Isolant polystyrène; Motif hachure tablette en Coupe: Sans Trame; Type hachure chambr. intérieur: Sans Trame; Type hachure chambr. ext.: Sans Trame; Motif de hachure arche coupe: Sans Trame; Motif de hachure de Coupe de Profil de ventilation: Lame d'air; Type de ligne symbole volet: 4; Type hachure coupée volet: Sans Trame; Stylo fond hachure coupé volet: Fond de fenêtre; Motif de hachure d'isolation de volet: Sans Trame; Stylo de fond d'isolation de volet: Fond de fenêtre; Jonction éléments cadre: 2; Ombre: yes; Surfaces de fenêtre uniformes: no; Cadre extérieur: C02; Cadre intérieur: C02; Châssis extérieur: C02; Châssis intérieur: C02; Persiennes: Bois-Pin brillant; Vitrage (gs_glass_mat): Vitrage-Verre; Grille extérieure: Bois-Pin brillant; Grille intérieure: Bois-Pin brillant; Panneau solide extérieur: Bois-Pin brillant; Panneau solide intérieur: Bois-Pin brillant; Poignée: Métal-Inox; Surfaces uniformes de chambranle: no; Chambranle intérieur: Bois-Pin brillant; Chambranle extérieur (gs_trim_out_mat): Peinture-03; Profil Ventilation: Métal-Aluminium; Panneau volet: Bois-Pin brillant; Cadre panneau volet: Bois-Pin brillant; Boîte volet roulant: Menuiserie Plastique; Lames volet roulant: Menuiserie métal; Rail volet roulant: Menuiserie Plastique; Boîte store vénitien: Métal-Inox; Segments store vénitien: Brique-Chevron 00; Rail volet coulissant: Métal-Inox; Appui (gs_sill_mat): Métal-Zinc; Mortier appui briques: Surface-Plastique Rugueux; Tablette (gs_board_mat): Bois-Pin brillant; Brique linteau: Brique-Appareillage 2; Mortier linteau: Surface-Plastique Rugueux; Clef de voûte linteau: Pierre-Grès; Niche: Menuiserie bois; Surface poteau d'angle: Peinture-03; Direction d'ouverture: 1; Afficher comme imposte: no; Type de ligne tête de mur: 21; Prof. linteau sur symbole: no; Type ligne symbole prof. linteau: 21; Fenêtre appartient à Zone vers laquelle elle donne: no; Coût: 0; Superficie vitrée totale (gs_list_glassarea_tmp): 0; Supplanter surface vitrée: yes; Superficie vitrée totale (gs_list_glassarea): 0; Périmètre total vitrage: 0; Performance air libre (mm2/l/m): 0; Type de groupe (FM_Type): Objets par défaut; Type de groupe (iFMType): 1; Poids de l'objet: 0; Unité poids de l'objet: kg; Définition d'orientation de fenêtre: 0; Orientation de fenêtre: D; Opération IFC (ifc_optypestr): Vertical double; Opération IFC (ifc_optype): 2; Angle ouverture volet: 180 deg; Style lignes d'ouverture: 1
Name | In | OverallHeight (mm) = Hauteur ouverture P/F côté ébrasure (mm) = Hauteur nominale de l'ouverture P/F côté ébrasure (mm) = Hauteur nominale de l'ouverture P/F côté opposée ébrasure (mm) = ArchiCADQuantities, Hauteur (mm) = AC_Equantity_Fenêtre_châssis_double_variable_27, Hauteur (mm) = Hauteur cavité mur (mm) = Hauteur ébrasure (mm) = Hauteur unité (mm) | Dimensions ébrasure = Dimensions trou mur = Dimensions unité = Taille L x H nominale | Taille L x H x E nominale | Nom de zone liée | Numéro de zone liée = À numéro de Zone | Nom d'étage d'implantation | Numéro d'étage d'implantation | ID de Parent | De Zone | Du numéro de Zone | À Zone | Volume ouverture d'ouverture P/F (m3) | Volume nominal ouverture P/F (m3) | Superficie ouverture P/F (m2) = Superficie en plan (m2) = Superficie inférieure (nette) (m2) | Superficie nominale ouverture P/F (m2) = Superficie ouverture P/F côté ébrasure (m2) = Superficie nominale de l'ouverture P/F côté ébrasure (m2) = Superficie nominale de l'ouverture P/F côté opposé ébrasure (m2) | Hauteur ouverture P/F côté opposé ébrasure (mm) | Superficie ouverture P/F côté opposé ébrasure (m2) | Valeur Appui ou Linteau (mm) = Hauteur nominale seuil (mm) = Hauteur seuil P/F côté ébrasure (mm) = Hauteur seuil P/F côté opposé ébrasure (mm) = Altitude à étage lié/étage d'implantation (mm) = Décalage étage d'implantation (mm) | Volume (net) (m3) | Altitude à Zéro du Projet (mm) = Altitude de Référence Niveau 1 (mm) = Altitude de Référence Niveau 2 (mm) = Altitude à niveau de la mer (mm) = Altitude inférieure à premier niveau de référence (mm) = Altitude inférieure à Zéro du projet (mm) = Altitude inférieure à niveau de la mer (mm) = Altitude inférieure à deuxième niveau de référence (mm) | Altitude supérieure à premier niveau de référence (mm) = Altitude supérieure à Zéro du projet (mm) = Altitude supérieure à niveau de la mer (mm) = Altitude supérieure à deuxième niveau de référence (mm) | Altitude inférieure à étage d'implantation (mm) = Hauteur appui à étage actuel (mm) | Hauteur ouverture en 3D (mm) | Type de direction de mur
Fen-207 | rdc | 2100 | 2,00×2,10 | 2,00×2,10×0,34 | Jardin | A04 | rdc | 3 | Mur-142 | Jardin | A04 | Sejour Cuisine/pl | 1.458 | 1.428 | 18.4843 | 4.2 | 2350 | 4.7 | 50 | 0.123729 | 3050 | 5400 | 50 | 2070 | 0
Fen-207 | rdc | 2150 | 2,00×2,15 | 2,00×2,15×0,34 | Terrasse | A01 | rdc | 3 | Mur-143 | Terrasse | A01 | Sejour cuisine/pl | 1.492 | 1.462 | 18.7377 | 4.3 | 2400 | 4.8 | 0 | 0.124438 | 3000 | 5400 | 0 | 2120 | 1
Fen-207 | rdc | 2150 | 2,00×2,15 | 2,00×2,15×0,34 | Terrasse | B03 | rdc | 3 | Mur-142 | Terrasse | B03 | Sejour cuisine | 1.492 | 1.462 | 18.7377 | 4.3 | 2400 | 4.8 | 0 | 0.124438 | 3000 | 5400 | 0 | 2120 | 1
Fen-207 | rdc | 2100 | 2,00×2,10 | 2,00×2,10×0,34 | Ch 3 | B03 | rdc | 3 | Mur-143 |  |  | Ch 3 | 1.458 | 1.428 | 18.4843 | 4.2 | 2350 | 4.7 | 50 | 0.123729 | 3050 | 5400 | 50 | 2070 | 1
Fen-207 | rdc | 2100 | 2,00×2,10 | 2,00×2,10×0,34 | Ch 1 | B01 | rdc | 3 | Mur-143 |  |  | Ch 1 | 1.458 | 1.428 | 18.4843 | 4.2 | 2350 | 4.7 | 50 | 0.123729 | 3050 | 5400 | 50 | 2070 | 1
Fen-207 | Etage1 | 2150 | 2,00×2,15 | 2,00×2,15×0,34 | balcon | B14 | Etage1 | 4 | Mur-143 | balcon | B14 | Sejour cuisine | 1.492 | 1.462 | 18.7377 | 4.3 | 2400 | 4.8 | 0 | 0.124438 | 5750 | 8150 | 0 | 2120 | 1
Fen-207 | Etage1 | 2150 | 2,00×2,15 | 2,00×2,15×0,34 | balcon | A11 | Etage1 | 4 | Mur-143 | balcon | A11 | Sejour cuisine/pl | 1.492 | 1.462 | 18.7377 | 4.3 | 2400 | 4.8 | 0 | 0.124438 | 5750 | 8150 | 0 | 2120 | 1
Fen-207 | Etage1 | 2100 | 2,00×2,10 | 2,00×2,10×0,34 | Ch 1 | A11 | Etage1 | 4 | Mur-143 |  |  | Ch 1 | 1.458 | 1.428 | 18.4843 | 4.2 | 2350 | 4.7 | 50 | 0.123729 | 5800 | 8150 | 50 | 2070 | 1
Fen-207 | Etage1 | 2100 | 2,00×2,10 | 2,00×2,10×0,34 | Ch 2/pl | B14 | Etage1 | 4 | Mur-145 |  |  | Ch 2/pl | 1.458 | 1.428 | 18.4843 | 4.2 | 2350 | 4.7 | 50 | 0.123729 | 5800 | 8150 | 50 | 2070 | 1
Fen-207 | Etage 2 | 2100 | 2,00×2,10 | 2,00×2,10×0,34 | Ch 1 | A22 | Etage 2 | 5 | Mur-143 |  |  | Ch 1 | 1.458 | 1.428 | 18.4843 | 4.2 | 2350 | 4.7 | 50 | 0.123729 | 8550 | 10900 | 50 | 2070 | 1
Fen-207 | Etage 2 | 2100 | 2,00×2,10 | 2,00×2,10×0,34 | Ch 2/pl | B24 | Etage 2 | 5 | Mur-143 |  |  | Ch 2/pl | 1.458 | 1.428 | 18.4843 | 4.2 | 2350 | 4.7 | 50 | 0.123729 | 8550 | 10900 | 50 | 2070 | 1
Fen-207 | Etage 2 | 2150 | 2,00×2,15 | 2,00×2,15×0,34 | balcon | B24 | Etage 2 | 5 | Mur-142 | balcon | B24 | Sejour cuisine | 1.492 | 1.462 | 18.7377 | 4.3 | 2400 | 4.8 | 1.42109e-11 | 0.124438 | 8500 | 10900 | 0 | 2120 | 1
Fen-207 | Etage 2 | 2100 | 2,00×2,10 | 2,00×2,10×0,34 | Ch 2/pl | A24 | Etage 2 | 5 | Mur-142 |  |  | Ch 2/pl | 1.458 | 1.428 | 18.4843 | 4.2 | 2350 | 4.7 | 50 | 0.123729 | 8550 | 10900 | 50 | 2070 | 1
Fen-207 | Etage 2 | 2150 | 2,00×2,15 | 2,00×2,15×0,34 | balcon | B21 | Etage 2 | 5 | Mur-144 | balcon | B21 | Sejour cuisine | 1.492 | 1.462 | 18.7377 | 4.3 | 2400 | 4.8 | 0 | 0.124438 | 8500 | 10900 | 0 | 2120 | 1
Fen-207 | Etage 2 | 2150 | 2,00×2,15 | 2,00×2,15×0,34 | balcon | A21 | Etage 2 | 5 | Mur-143 | balcon | A21 | Sejour cuisine/pl | 1.492 | 1.462 | 18.7377 | 4.3 | 2400 | 4.8 | 0 | 0.124438 | 8500 | 10900 | 0 | 2120 | 1
Fen-207 | Etage 2 | 2100 | 2,00×2,10 | 2,00×2,10×0,34 | Sejour cuisine/pl | A24 | Etage 2 | 5 | Mur-142 |  |  | Sejour cuisine/pl | 1.458 | 1.428 | 18.4843 | 4.2 | 2350 | 4.7 | 50 | 0.123729 | 8550 | 10900 | 50 | 2070 | 0
Fen-207 | Etage 3 | 2150 | 2,00×2,15 | 2,00×2,15×0,34 | Terrasse | B34 | Etage 3 | 6 | Mur-142 | Terrasse | B34 | Ch 1/pl | 1.492 | 1.462 | 18.7377 | 4.3 | 2400 | 4.8 | 0 | 0.124438 | 11550 | 13950 | 0 | 2120 | 1
Fen-207 | Etage 3 | 2100 | 2,00×2,10 | 2,00×2,10×0,34 | Ch 1 | A31 | Etage 3 | 6 | Mur-143 |  |  | Ch 1 | 1.458 | 1.428 | 18.4843 | 4.2 | 2350 | 4.7 | 50 | 0.123729 | 11600 | 13950 | 50 | 2070 | 1
Fen-207 | etage 4 | 2150 | 2,00×2,15 | 2,00×2,15×0,34 | Terrasse | B44 | etage 4 | 7 | Mur-142 | Terrasse | B44 | Sejour cuisine | 1.492 | 1.462 | 18.7377 | 4.3 | 2400 | 4.8 | 0 | 0.124438 | 14600 | 17000 | 0 | 2120 | 1
Fen-207 | etage 4 | 2100 | 2,00×2,10 | 2,00×2,10×0,34 | Ch 1/pl | B43 | etage 4 | 7 | Mur-143 | Ch 1/pl | B43 | Ch 1/pl | 1.458 | 1.428 | 18.4843 | 4.2 | 2350 | 4.7 | 50 | 0.123729 | 14650 | 17000 | 50 | 2070 | 1 | ArchiCADProperties - Zones conflictuelles: Ch 1/pl
Fen-207 | etage 4 | 2150 | 2,00×2,15 | 2,00×2,15×0,34 |  |  | etage 4 | 7 | Mur-143 |  |  |  | 1.492 | 1.462 | 18.7377 | 4.3 | 2400 | 4.8 | 0 | 0.124438 | 14600 | 17000 | 0 | 2120 | 1

# IfcWindow: Fenêtre châssis double variable 27 (2)
Type - OperationType: DOUBLE_PANEL_VERTICAL; ParameterTakesPrecedence: no; Sizeable: no
Type - Window Lining Properties - LiningDepth: 50 mm; LiningThickness: 50 mm; MullionThickness: 50 mm; FirstMullionOffset: 0.4
Type - Window Panel Properties - Panel 1 - OperationType: SIDEHUNGRIGHTHAND; PanelPosition: RIGHT; FrameDepth: 50 mm; FrameThickness: 50 mm
Type - Window Panel Properties - Panel 2 - OperationType: FIXEDCASEMENT; PanelPosition: LEFT
OverallHeight: 1800 mm; OverallWidth: 1000 mm; Classification: Fenêtre (Classification ARCHICAD)
ArchiCADProperties - Dimensions ébrasure: 1,00×1,80; Dimensions trou mur: 1,00×1,80; Dimensions unité: 1,00×1,80; Taille L x H nominale: 1,00×1,80; Taille L x H x E nominale: 1,00×1,80×0,34; Structure de Mur: Empty Fill 272047960; Orientation: D; Nom élément de bibliothèque d'ouverture: Fenêtre châssis double variable 27; Index hachure latérale ouverture: 100 %; Calque: Interieurs logements; Nom Élément de Bibliothèque: Fenêtre châssis double variable 27; Matériau de construction / Composite / Profil / Hachure: 100 %; Type Hachure: 100 %; Verrouillé: no; Type d'élément: Fenêtre; ID de Parent: Mur-143; Surfaces (Toutes): Vitrage-Verre; Métal-Zinc; Peinture-01; Nom de Variante: Modèle principal; Nom de Jeu de Variantes: Modèle principal; Position: Non défini; Fonction structurelle: Non défini; Affichage sur filtre de rénovation: Tous les filtres appropriés; État de rénovation: Existant; État de Variante: Modèle principal; Jeu de Variantes: Modèle principal
AC_Pset_Fenêtre_châssis_double_variable_27 - Contours Mur (0-Sans,1-Tout,2-Côté,3-Longueur): 1; Point ch.0-Non,1-2D,2-3D,3-Tous: 3; Option affichage en plan: 2; Angle de position baie: 0 deg; Trou reprend surface latérale de mur: yes; Division de surface du trou courbe dans murs courbes: no; Afficher points chauds 2D en 3D: yes; Type de mur: 1; Type de direction de mur: 0; Position ancre ébrasuer: 1; Fonction de debug Fenêtre Angle: no; Placement (1=Angle, 0=Centre): no; Basculer: no; Démolition / Nouvelle constr.: 1; Nouveau motif de hachure de mur: Parpaing; Afficher nouv. constr. sur mur: no; Type de ligne démolition: 4; Aff. param. Démolition/Nouveau: no; Fonction Fenêtre Angle: yes; Angle Murs: 90 deg; Murs connectés d'épaiss. diff.: no; Poteau d'angle: no; Coin 2: no; Angle de coin 2: 90 deg; Murs connectés d'épaiss. diff. 2: no; Coin 1: no; Angle de coin 1: 90 deg; Murs connectés d'épaiss. diff. 1: no; Type connexion angle 1: 1; Type connexion angle 2: 1; Entièrement éditable: yes; Niveau de détail 2D: 2; Afficher ébrasure sur symbole: 2; Niveau de détail 3D: 2; Taille nominale: 0; Taille trou comme taille nominale: yes; Taille ébrasure comme nominale: no; Taille unité comme nominale: no; Transmettre taille nominale actuelle à sélection: no; Panneaux horizontaux: 3; Largeur cadre uniforme: no; Traverse supérieure: no; Traverse inférieure: no; Châssis vitré (gs_bSLight): no; Panneaux verticaux: 3; Meneau jusqu'en haut: yes; Meneau jusqu'en bas: no; Châssis uniformes: no; Direction vitrage fixe (FixGlassDir): Par direction d'ouverture; Direction vitrage fixe (FixGlassDir_m): 1; Type d'opération châssis princ. (gs_optype_01): Battant; Type d'ouverture (gs_optype_m_01): 3; Type d'opération châssis princ. (gs_optype_09): Battant; Type d'ouverture (gs_optype_m_09): 3; Type ouverture panneau adj.: Vitrage fixe; Type d'ouverture (gs_optype_m_05): 1; Type ouverture châssis inf.: Vitrage fixe; Type d'ouverture (gs_optype_m_03): 1; Type ouverture châssis imposte: Vitrage fixe; Type d'ouverture (gs_optype_m_02): 1; Type châssis (MullionStyle_00): Pas de grille; Type châssis (iMullionStyle_00): 1; Type châssis, châssis princ. 1: Pas de grille; Type châssis (iMullionStyle_01): 1; Type châssis, châssis princ. 2: Pas de grille; Type châssis (iMullionStyle_09): 1; Type châssis tierce vitrée: Pas de grille; Type châssis (iMullionStyle_05): 1; Type châssis, châssis inf.: Nombre de meneaux; Type châssis (iMullionStyle_03): 1; Type châssis, châssis imposte: Nombre de meneaux; Type châssis (iMullionStyle_02): 1; Panneau personnalisé symétrie (gs_bMirr_cust_panel_01): no; Panneau personnalisé symétrie (gs_bMirr_cust_panel2_01): no; Panneau personnalisé symétrie (gs_bMirr_cust_panel_02): no; Panneau personnalisé symétrie (gs_bMirr_cust_panel2_02): no; Panneau personnalisé symétrie (gs_bMirr_cust_panel_03): no; Panneau personnalisé symétrie (gs_bMirr_cust_panel2_03): no; Panneau personnalisé symétrie (gs_bMirr_cust_panel_05): no; Panneau personnalisé symétrie (gs_bMirr_cust_panel2_05): no; Panneau personnalisé symétrie (gs_bMirr_cust_panel_09): no; Panneau personnalisé symétrie (gs_bMirr_cust_panel2_09): no; Edition point chaud de grille: yes; Position grille (MullionPosition): Les deux; Position grille (iMullionPosition): 3; Nbre panneaux V châssis princ. 1: 2; Nbre panneaux H châssis princ. 1: 2; Nbre panneaux V 2 châssis princ. 1: 2; Nbre panneaux H 2 châssis princ. 1: 2; Nbre panneaux V châssis princ. 2: 2; Nbre panneaux H châssis princ. 2: 2; Nbre panneaux V 2 châssis princ. 2: 2; Nbre panneaux H 2 châssis princ. 2: 2; Nbre panneaux V tierce vitrée: 3; Nbre panneaux H tierce vitrée: 2; Nbre panneaux V 2 tierce vitrée: 3; Nbre panneaux H 2 tierce vitrée: 2; Nbre panneaux V châssis inf.: 2; Nbre panneaux H châssis inf.: 2; Nbre panneaux V 2 châssis inf.: 2; Nbre panneaux H 2 châssis inf.: 2; Nbre panneaux V châssis imposte: 2; Nbre panneaux H châssis imposte: 2; Nbre panneaux V 2 châssis imposte: 2; Nbre panneaux H 2 châssis imposte: 2; Style persiennes (iLouverStyle): 1; Angle d'ouverture persiennes: 0 deg; Poignée de fenêtre: no; Type de poignée de fenêtre (gs_handle_type_win): Style 1; Type de poignée de fenêtre (gs_handle_type_win_m): 1; Chambranle extérieur (gs_trim_outside): no; Type chambranle extérieur (gs_trimtype_out): Simple; Type chambranle extérieur (gs_trimtype_out_int): 1; Type tête chambr. ext.: 1; Chapiteau architrave: yes; Type chapiteau architrave: 1; Chambranle inférieur extérieur: no; Couvre surface mur ext.: yes; Largeurs uniformes de chambranle (gs_trim_outside_uniform): no; Chambranle intérieur.: no; Type chambranle intérieur (gs_trimtype_in): Simple; Type chambranle intérieur (gs_trimtype_in_int): 1; Couvre surface mur int.: yes; Largeurs uniformes de chambranle (gs_trim_inside_uniform): no; Appui (gs_sill_outside): yes; Dépassement appui: no; Type d'appui/seuil: 11; Angle appui: 3 deg; Appui courbe dans murs courbes: yes; Isolation sous appui: yes; Utiliser couche isolation mur: no; Niveau détail 3D seuil brique: 1; Tablette (gs_board_inside): no; Angle tablette: 0 deg; Tabl. courbe dans murs courbes: yes; Tableau dans murs polygonaux: 1; Aération naturelle: no; Type d'aération naturelle: 2; Châssis principal 1: no; Châssis principal 2: no; Châssis vitré (isVentilationProfileInSash_05): no; Châssis inférieur: no; Châssis imposte: yes; Volet: yes; Type volet: 1; Types volet activés: 126; Nombre de panneaux: 2; Nombre de panneaux 2: 1; Position panneau (gs_shutter_panelPos): Symétrique; Position panneau (gs_shutter_iPanelPos): 1; Hauteur volet automatique: yes; Cadre supplémentaire: no; Type de couverture (gs_slidingShutter_cover): Profil en Z; Type de couverture (gs_slidingShutter_iCover): 1; Direction articulation (gs_foldingShutter_stacking): Intérieur; Direction articulation (gs_foldingShutter_iStacking): 1; Ouvert en 3D: yes; Angle ouverture en 3D: 180 deg; Afficher symbole 2D: yes; Afficher lignes d'ouverture sur symbole: no; Type de panneau: (gs_shutPanel_type): Style 1; Type de panneau: (gs_shutPanel_iType): 1; Largeur cadre inf. différente: no; Largeur volets automatiques: yes; Angle persienne: 30 deg; Nombre trous horizontaux: 5; Nombre trous verticaux: 8; Placement volet roulant (gs_shutRoll_placement): Derrière façade; Placement volet roulant (gs_shutRoll_iPlacement): 3; Type boîte (gs_shutRoll_boxType): Rectangulaire; Type boîte (gs_shutRoll_iBoxType): 1; Position rampe (gs_shutRoll_railPos): Sur revêtement; Position rampe (gs_shutRoll_iRailPos): 1; Afficher revêtement derrière parasol (gs_shutRoll_showCasingBehind): no; Isolation derrière cellule (gs_shutRoll_cutWallBehind): no; Inclure hauteur dans hauteur de trou de mur: no; Angle supérieur boîte: 10 deg; Taille boîte par défaut (gs_shutRoll_boxDefaultSize): A largeur d'ébrasure; Taille boîte par défaut (gs_shutRoll_iBoxDefaultSize): 1; Placement stores (gs_shutLam_placement): Fixé sur façade; Placement stores (gs_shutLam_iPlacement): 1; Isolation derrière cellule (gs_shutLam_cutWallBehind): no; Boîte ouverte: yes; Rampe: yes; Position rampe (gs_shutLam_railPos): Sur revêtement; Position rampe (gs_shutLam_iRailPos): 1; Afficher revêtement derrière parasol (gs_shutLam_showCasingBehind): no; Angle de rotation des lamelles (gs_shutLam_rotation): 45 deg; Angle de rotation des lamelles (gs_shutLam2_rotation): 45 deg; Linteau (bMasonryArch): no; Linteau (gs_masonry_arch_int): 2; Type linteau (gs_masonry_arch_structure): Stuc; Type linteau (gs_masonry_arch_structure_int): 1; Arche sur linteau: yes; Niche sous arche: yes; Angle inclinaison: 75 deg; Surface niche personnalisée: no; Type ébrasure (gs_reveal_type_new): Baie simple; Type ébrasure (gs_reveal_type_int): 2; Type ébrasure inférieure (gs_reveal_type_bottom): Uniforme; Type ébrasure inférieure (gs_reveal_type_bottom_int): 1; Type ébrasure extérieure: Baie simple; Type ébrasure (gs_reveal_doubleOuterTypeInt): 0; Type ébrasure intérieure: Baie simple; Type ébrasure (gs_reveal_doubleInnerTypeInt): 0; Profondeur montant uniforme: yes; Côté angle 2: 20 deg; Côté angle: 20 deg; Angle côté supérieur: 20 deg; Angle côté inférieur: 20 deg; Utiliser composant finition mur: no; Tourner automatiquement plâtre surface intérieure: yes; Tourner plâtre surface intérieure: 0; Tourner automatiquement plâtre surface extérieure: yes; Tourner plâtre surface extérieure: 0; Peut être coté en 2D: no; Afficher en 3D: no; Type de fermeture (gs_closure_type): Pas de fermeture; Type de fermeture (gs_closure_type_int): 1; Tourner couche sur côté (gs_cavity_side): Les deux; Tourner couche sur côté (iCavityClosureSide): 1; Nbre de couches retournées: 1; Num. à partir de (gs_nTurnDir): Face extérieure; Num. à partir de (iCavityClosureTurnDir): 1; Placer fermeture sur côté 2: yes; Placer fermeture sur côté 1: yes; Placer fermeture en haut: no; Placer fermeture en bas: no; Placer fermeture sur couche: 1; Placer fermeture de côté (gs_cc_dutch_ClosureToSide): 1; Ecart à couche externe: yes; Tourner couche sur fermeture: no; Insérer bande d'isolation: yes; Afficher bande d'isolation: yes; Type de ligne de contour (gs_ltJoint): 1; Motif de hachure (gs_fillJoint): Isolant polystyrène; Surface personnalisée: no; Surface: Bois-Pin brillant; Type de ligne de contour (gs_ltPlug): 1; Motif de hachure (gs_fillPlug): Isolant polystyrène; Côté montant édité: 1; Côté mur édité: 1; Numéro couche éditée: 1; Tourner couche: no; Considérer couches comme plâtre: no; Tourner épaiseur: 1; Orientation hachure: 1; Ligne de séparation tournant: no; Dernier côté sélectionné: no; Méthode fermeture changée auto.: no; Connexion à gauche: no; Connexion à droite: no; Connexion en haut: no; Connexion en bas: no; Incrustation allège: no; Tailles incrustation mur (gs_parapet_sizes_st): Automatique; Tailles incrustation mur (iParapetSize): 1; Cotes largeur et longueur auto: yes; Incrustation base mur à (gs_parapet_bottom_st): Etage actuel; Incrustation base mur à (iParapetBottom): 1; Afficher allège masquée: yes; Type ligne allège masquée: 1; Angle ouv. châssis principal 1 (openingAngle_01): 0 deg; Angle ouv. châssis principal 1 (openingAngle2_01): 0 deg; Angle ouv. châssis principal 2 (openingAngle_09): 0 deg; Angle ouv. châssis principal 2 (openingAngle2_09): 0 deg; Angle ouv. tierce vitrée (openingAngle_05): 0 deg; Angle ouv. tierce vitrée (openingAngle2_05): 0 deg; Angle d'ouverture châssis inf. (openingAngle_03): 0 deg; Angle d'ouverture châssis inf. (openingAngle2_03): 0 deg; Angle ouv. châssis imposte (openingAngle_02): 0 deg; Angle ouv. châssis imposte (openingAngle2_02): 0 deg; Angle ouverture en 2D: 90 deg; Suppl. Opt. vue pour aff. symb. 2D: yes; Type ligne ouverture: 1; Forme ligne ouverture (or_SwingType): Courbé; Forme ligne ouverture (or_iSwingType): 1; Forme ligne ouverture (or_SlidingType): Sans; Forme ligne ouverture (or_iSlidingType): 0; Stylo ligne ouverture 2D/3D (or_iOpLinePen): 100; Suppl. Opt. vue pour proj. 3D: yes; Afficher ligne d'ouverture: yes; Type ligne côté ouverture (or_opLineType3dIn): Tirets; Type ligne côté ouverture (or_iOpLineType3dIn): 1; Type ligne côté opposé (or_opLineType3dOut): Tirets; Type ligne côté opposé (or_iOpLineType3dOut): 1; Orientation ligne (or_oplineStyle): Poignée; Orientation ligne (or_iOplineStyle): 1; Ligne de contour de mur (gs_wcont_line): Des deux côtés; Ligne de contour de mur (iWallContourLine): 4; Type ligne contour int. mur: 1; Type ligne contour ext. mur: 1; Type ligne contour int. mur masqué: 1; Type ligne contour ext. mur masqué: 1; Utiliser hachures: yes; Motif de hachure cadre: Sans Trame; Motif de hachure châssis: Lame d'air; Type hachure non coupée: Sans Trame; Motif hachure symbole en plan: Sans Trame; Motif hachure appui en Coupe: Sans Trame; Motif hachure isolation Coupe: Isolant polystyrène; Motif hachure tablette en Coupe: Sans Trame; Type hachure chambr. intérieur: Sans Trame; Type hachure chambr. ext.: Sans Trame; Motif de hachure arche coupe: Sans Trame; Motif de hachure de Coupe de Profil de ventilation: Lame d'air; Type de ligne symbole volet: 4; Type hachure coupée volet: Sans Trame; Stylo fond hachure coupé volet: Fond de fenêtre; Motif de hachure d'isolation de volet: Sans Trame; Stylo de fond d'isolation de volet: Fond de fenêtre; Jonction éléments cadre: 2; Ombre: yes; Surfaces de fenêtre uniformes: no; Cadre extérieur: Peinture-01; Cadre intérieur: Peinture-01; Châssis extérieur: Peinture-01; Châssis intérieur: Peinture-01; Persiennes: Bois-Pin brillant; Vitrage (gs_glass_mat): Vitrage-Verre; Grille extérieure: Bois-Pin brillant; Grille intérieure: Bois-Pin brillant; Panneau solide extérieur: Bois-Pin brillant; Panneau solide intérieur: Bois-Pin brillant; Poignée: Métal-Inox; Surfaces uniformes de chambranle: no; Chambranle intérieur: Bois-Pin brillant; Chambranle extérieur (gs_trim_out_mat): Peinture-03; Profil Ventilation: Métal-Aluminium; Panneau volet: Peinture-01; Cadre panneau volet: Peinture-01; Boîte volet roulant: Menuiserie Plastique; Lames volet roulant: Menuiserie métal; Rail volet roulant: Menuiserie Plastique; Boîte store vénitien: Métal-Inox; Segments store vénitien: Brique-Chevron 00; Rail volet coulissant: Métal-Inox; Appui (gs_sill_mat): Métal-Zinc; Mortier appui briques: Surface-Plastique Rugueux; Tablette (gs_board_mat): Bois-Pin brillant; Brique linteau: Brique-Appareillage 2; Mortier linteau: Surface-Plastique Rugueux; Clef de voûte linteau: Pierre-Grès; Niche: Menuiserie bois; Surface poteau d'angle: Peinture-03; Direction d'ouverture: 1; Afficher comme imposte: no; Type de ligne tête de mur: 21; Prof. linteau sur symbole: no; Type ligne symbole prof. linteau: 21; Fenêtre appartient à Zone vers laquelle elle donne: no; Coût: 0; Superficie vitrée totale (gs_list_glassarea_tmp): 0; Supplanter surface vitrée: yes; Superficie vitrée totale (gs_list_glassarea): 0; Périmètre total vitrage: 0; Performance air libre (mm2/l/m): 0; Type de groupe (FM_Type): Objets par défaut; Type de groupe (iFMType): 1; Poids de l'objet: 0; Unité poids de l'objet: kg; Définition d'orientation de fenêtre: 0; Orientation de fenêtre: D; Opération IFC (ifc_optypestr): Vertical double; Opération IFC (ifc_optype): 2; Angle ouverture volet: 180 deg; Style lignes d'ouverture: 1
ArchiCADQuantities - Volume ouverture d'ouverture P/F: 0.612 m3; Volume nominal ouverture P/F: 0.612 m3; Superficie ouverture P/F: 10.9658 m2; Superficie nominale ouverture P/F: 1.8 m2; Largeur ouverture P/F côté ébrasure: 1000 mm; Hauteur ouverture P/F côté ébrasure: 1800 mm; Largeur ouverture P/F côté opposé ébrasure: 1000 mm; Hauteur ouverture P/F côté opposé ébrasure: 1800 mm; Superficie ouverture P/F côté ébrasure: 1.8 m2; Superficie ouverture P/F côté opposé ébrasure: 1.8 m2; Largeur nominale de l'ouverture P/F côté ébrasure: 1000 mm; Hauteur nominale de l'ouverture P/F côté ébrasure: 1800 mm; Largeur nominale de l'ouverture P/F côté opposée ébrasure: 1000 mm; Hauteur nominale de l'ouverture P/F côté opposée ébrasure: 1800 mm; Superficie nominale de l'ouverture P/F côté ébrasure: 1.8 m2; Superficie nominale de l'ouverture P/F côté opposé ébrasure: 1.8 m2; Épaisseur de Mur: 340 mm; Épaisseur cadre: 50 mm; Hauteur: 1800 mm; Volume (net): 0.0662575 m3; Largeur: 1000 mm; Superficie en plan: 10.9658 m2; Superficie inférieure (nette): 10.9658 m2
AC_Pset_RenovationAndPhasing - Renovation Status: Existing
